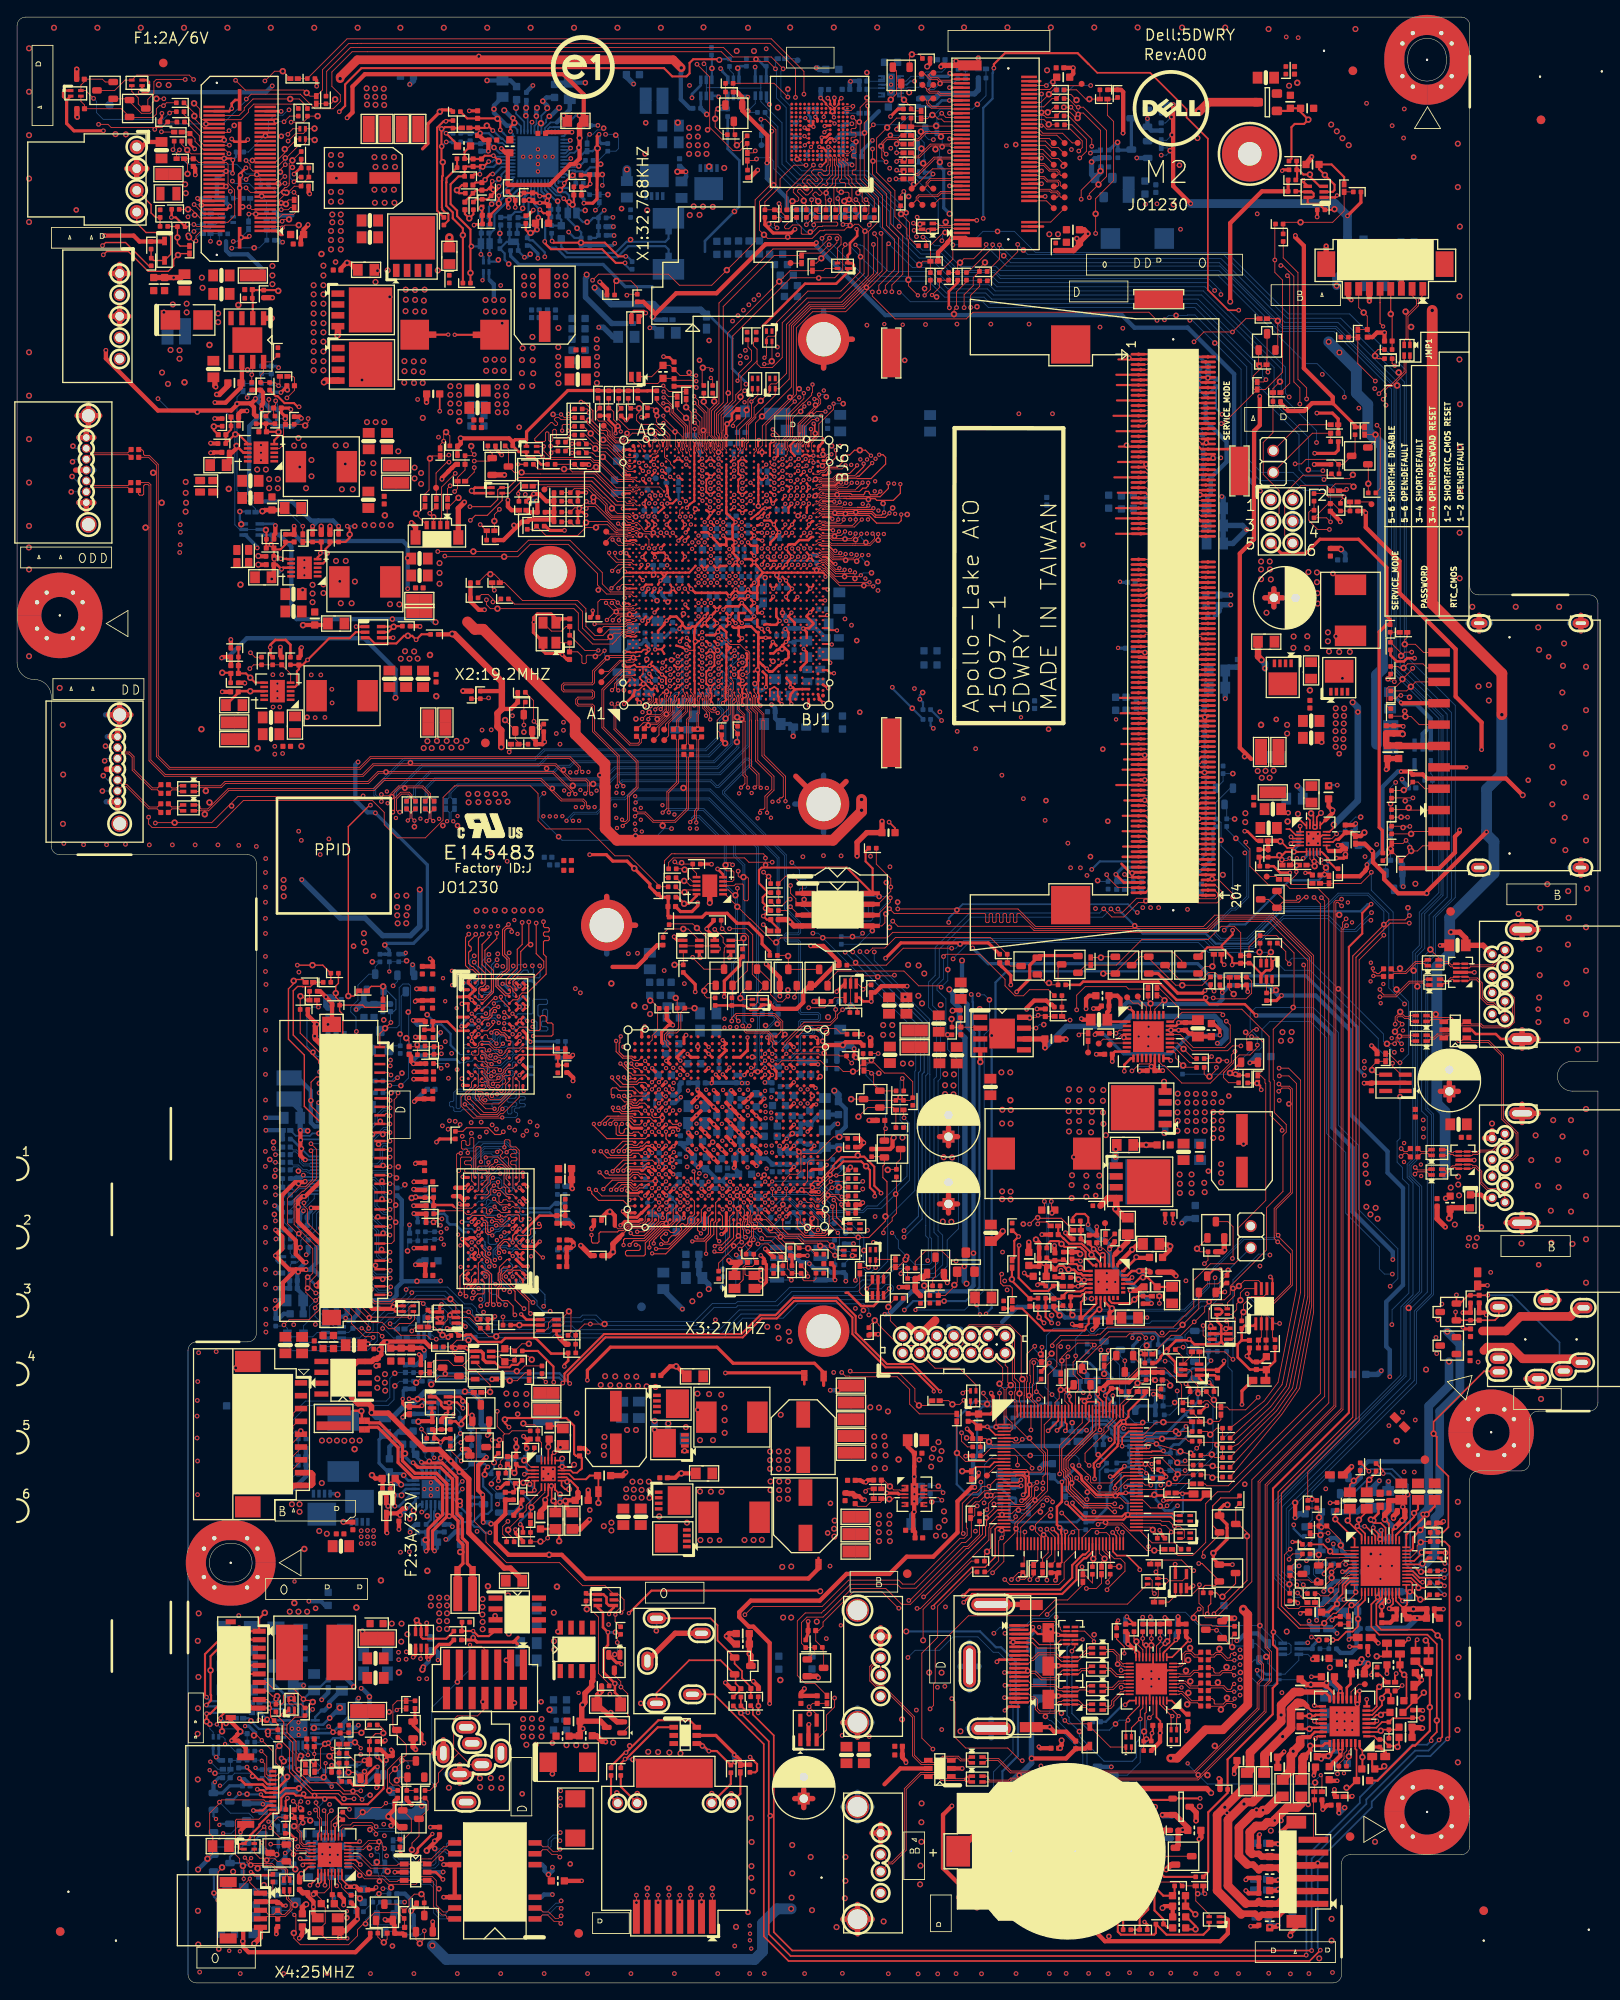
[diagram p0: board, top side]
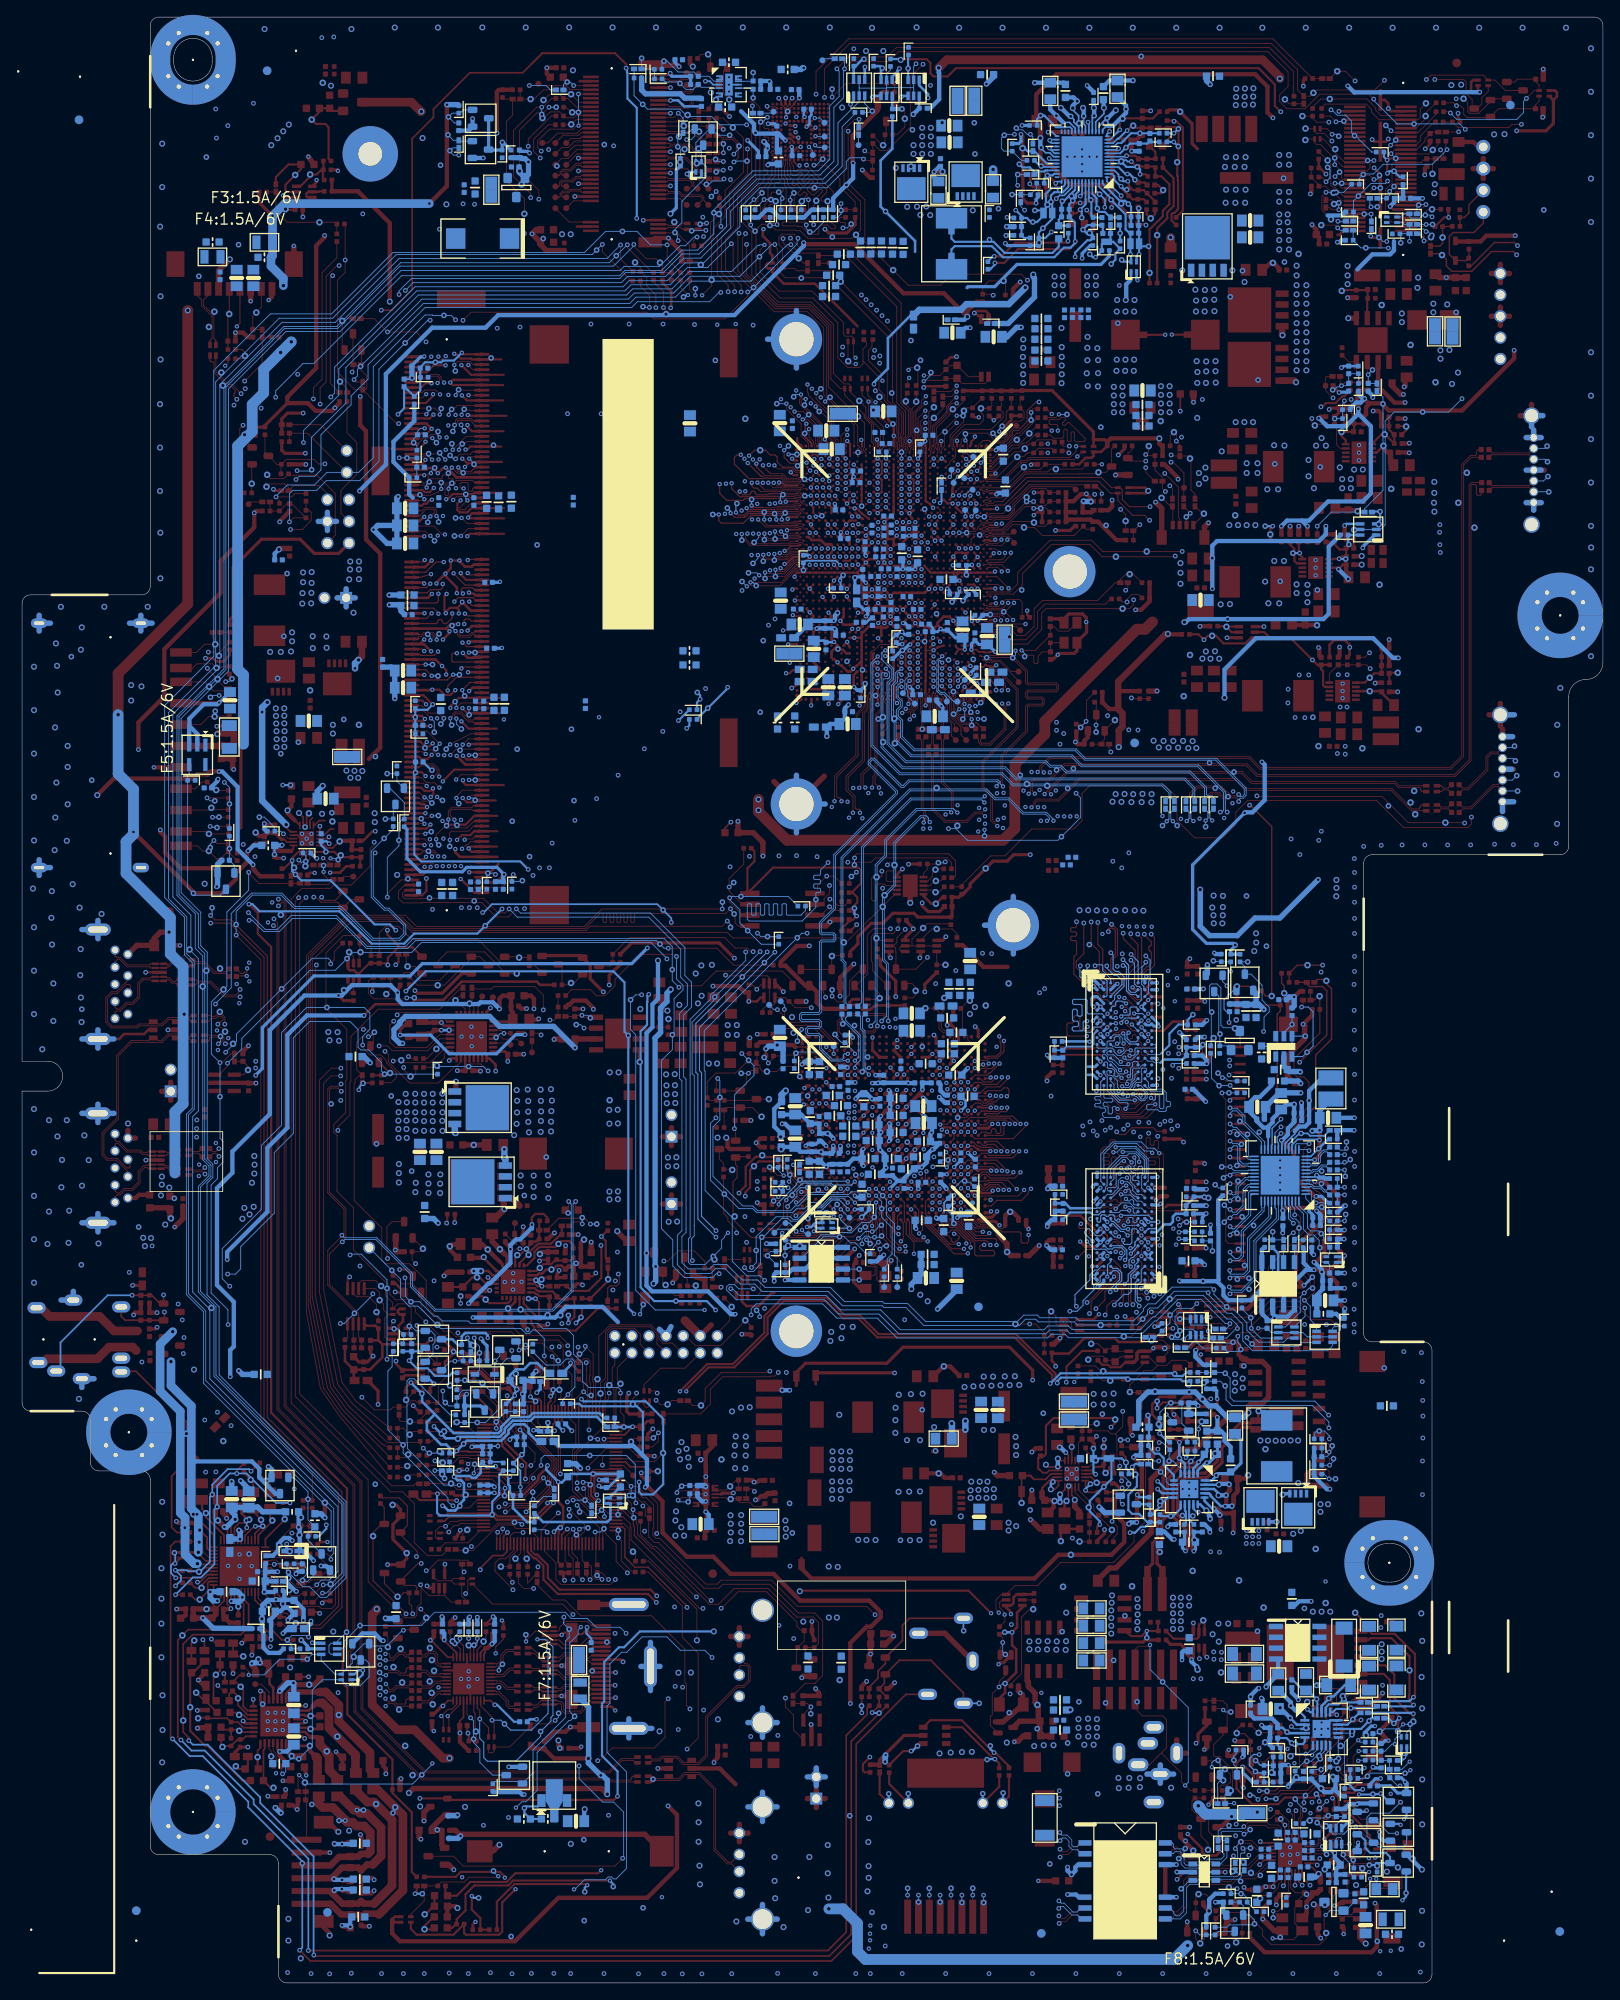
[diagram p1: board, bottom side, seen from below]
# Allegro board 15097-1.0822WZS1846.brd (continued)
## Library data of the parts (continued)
IRMTCN1 = 88459-047N: tolerance: 20.F1897.004
JMP1 = 21S-92-03GB16: tolerance: 021.60308.0203
L1 L10 L11 L25 = L402H24: tolerance: 68.00213.031
L2 = L125100-4P-1H36: tolerance: 68.12105.201; signal model: Graser_L2
L3 = L125100-4P-1H36: tolerance: 68.12105.201; signal model: Graser_L3
L4 = L125100-4P-1H36: tolerance: 68.12105.201; signal model: Graser_L4
L5 = L125100-4P-1H36: tolerance: 68.12105.201; signal model: Graser_L5
L6 = L125100-4P-1H36: tolerance: 68.12105.201; signal model: Graser_L6
L7 = L125100-4P-1H36: tolerance: 68.12105.201; signal model: Graser_L7
L8 = L8080-6020H158: tolerance: 068.33010.1061
L9 = L603H38: tolerance: 68.00335.141
L12-L15 = L20125H42: tolerance: 68.00216.111
L16 = L402H22: tolerance: 68.00084.541
L17 L22 = L603H38: tolerance: 68.00335.051
L19 L23 L24 = L603H38: tolerance: 68.00230.231
L20 = L3030-2709H41: tolerance: 68.2R21F.10E
L21 = L603H38: tolerance: 68.00335.081
L26 PR5-PR8 PR31 PR44 PR46 PR57 PR61 PR69 PR70 PR78 PR79 PR91 PR93 PR139 PR141-PR143 PR146 PR151 PR157 PR165 PR170 PR172 PR184 PR185 PR211 PR217 PR219 PR230 PR235 PR240 PRT1 PRT2 R47 R574 R575 = 0R0805-PAD: tolerance: ZZ.R0805.ZZZ
LED1 = LED1608AKH30: tolerance: 83.01608.Q70
LOUT1 = JAC331-0140A8B-9H: tolerance: 22.10277.2M1
LPC1 = HL5507F: tolerance: 21.60964.207
LVDS1 = 50524-0300N-001: tolerance: 020.K0005.0030
MEMCD1 = 156-5101902601: tolerance: 062.10002.0161
NGFF1 = 2199230-7: tolerance: 62.10043.K51
PC1 PC2 PC27 PC29 PC40 PC41 PC59 PC76 = C402H22: tolerance: 78.10423.5FLDL
PC4 PC9 PC123 PC141 PC146 PC187 PC188 PC198 = C402H22: tolerance: 78.10422.5FLDL
PC11 PC15 = C402H22: tolerance: 78.15034.L1L
PC12 PC183 = C402H22: tolerance: 78.22124.2FLDL
PC18 = C603: tolerance: 78.15324.2BL
PC22 = C402H22: tolerance: 78.10321.2FL
PC38 PC50 = C603H36: tolerance: 78.10224.2BLDL
PC39 PC95 PC112 PC116 = C402H22: tolerance: 78.22034.1FLDL
PC74 = C402H22: tolerance: 78.18034.1FL
PC75 = C402H22: tolerance: 78.10421.L0L
PC85 = C603H36: tolerance: 78.15224.2BLDL
PC88 = C402H22: tolerance: 78.10322.L0L
PC90 = C402H22: tolerance: 78.27224.2FLDL
PC92 = C603H36: tolerance: 78.56224.2BLDL
PC130 PC172 = C402H22: tolerance: 78.47322.2FL
PC135 = C402H22: tolerance: 78.15322.2FLDL
PC136 = C402H22: tolerance: 78.15224.2FLDL
PC144 = C805H54: tolerance: 78.10524.21LDL
PC147 = C402H22: tolerance: 78.22044.1FL
PC175 PC176 = C402H22: tolerance: 78.10034.1FLDL
PD1 = SOD323AKH42: tolerance: 83.04148.D1H
PD2 = SOD523AKH28: tolerance: 83.R2003.0EF
PD3 = D5436AKH97: tolerance: 83.P6SBM.CAG
PG1 PG2 = GAP-CLOSE-PWR: tolerance: ZZ.CLOSE.011
PG3-PG12 PG14-PG18 PGT1 = GAP-CLOSE-PWR-3: tolerance: ZZ.CLOSE.001
PG13 PR40 PR76 PR136 PR202 PR206 PR207 R10 R17 R22 R23 R25 R26 R29 R32 R34 R85 R119 R129 R135 R136 R154 R197 R206 R208 R224 R231 R248 R250 R266 R269 R270 R272 R273 R280 R307 R315 R343 R354 R355 R360-R366 R368 R371 R377 R385 R396 R400 R404 R405 R407 R429 R435 R468 R493 R505 R518 R521 R526 R566 R611 R612 R627 R654 R698 R699 R710 R719 R722 R731 R735 R750 R807 R809 R812 R1702 R1703 R1806 R1807 R2401 R2402 R9201 R9202 = R402H16: tolerance: 63.R0034.1DL
PL1 = L112100-2230H158: tolerance: 68.R2210.10Q
PL2-PL5 = L686647-127318H119: tolerance: 68.1R51A.10F
PL6 = L115100-2H158: tolerance: 68.R3610.10M
PL7 PL8 = L686647-127318H119: tolerance: 68.2R21B.10J
PL9 = L686647-127318H119: tolerance: 68.R4710.10V
PL10 PL11 PL13 = L402H24: tolerance: 69.80007.021
PL12 = L686647-127318H119: tolerance: 68.5R610.10U
PQ1 PQ16 PU8 PU17 = PTDS08-1H44: tolerance: 84.04C10.037
PQ2 PQ3 PU7 PU16 = PTDS08-1H44: tolerance: 84.04C06.037
PQ4 PQ11 PQ18 PU14 PU18 PU19 = PPAK-8P-3232H36: tolerance: 84.07410.A37
PQ5 PQ9 PQ20 PU15 = PPAK-8P-3232H36: tolerance: 84.07506.037
PQ6 PQ8 Q19 Q45-Q47 Q52 = SOT-363H44: tolerance: 84.2N702.A3F
PQ7 Q65 = SOT23CBE2D4H44: tolerance: 84.T3906.E11
PQ10 PQ17 Q25 Q34 Q38 Q64 Q1801 U27 = SOT23DGS2D4H44: tolerance: 84.2N702.J31
PQ12 PQ19 Q8 Q10 Q22 Q26 Q35 Q41 Q50 Q55 Q56 Q70-Q72 Q74 Q2801 Q4501 = SOT23DGS2D4H48: tolerance: 84.2N702.E31
PQ13 = SOT-363H44: tolerance: 84.00512.03F
PQ14 = SOT323CBE2D2H40: tolerance: 84.05212.B11
PQ15 = SOT323CBE2D2H44: tolerance: 84.00124.K1K
PR1 PR16 PR18 PR42 PR197 R585 R586 R634 R655 R785 = R402H16: tolerance: 64.10015.6DL
PR2 PR30 PR43 PR48 PR55 PR58 PR62 PR65 PR74 PR80 PR96 PR103 PR108 PR120 PR126 PR137 PR152 PR167 PR168 PR182 PR194 PR210 PR223 PRT3 = R805H24: tolerance: 63.2R231.16L
PR3 = R402H16: tolerance: 64.19625.6DL
PR4 PR81 PR111 PR198 PR242 R4 R14 R31 R39 R40 R80 R90 R94 R96 R130 R164 R175 R198 R205 R221 R233 R244 R275 R295 R306 R312 R358 R378 R380 R394 R401 R403 R408 R571 R573 R709 R738 R793 = 0R0402-PAD: tolerance: ZZ.R0402.001
PR9 = R603H22: tolerance: 64.84525.55L
PR10 R736 = R603H22: tolerance: 64.2R205.55L
PR11 = R402H16: tolerance: 64.48735.6DL
PR12 = R402H16: tolerance: 64.75025.6DL
PR13 = R402H16: tolerance: 64.22125.6DL
PR14 PR21 PR83 PR85 PR109 PR113 R126 R156 R387 R703 = R402H16: tolerance: 64.20025.6DL
PR15 PR154 = R402H16: tolerance: 64.10235.6DL
PR17 PR27 PR28 PR34 PR89 PR122 PR132 PR159 PR160 PR177 PR232 R101 R103-R105 R112 R118 R131 R148 R161 R252 R279 R281 R282 R285 R290 R298-R300 R308 R313 R314 R373 R391 R453 R461 R660 R661 R667 R692 R696 R697 R708 R716 R720 R778 R784 R792 R1801 R1802 = R402H16: tolerance: 64.10025.6DL
PR19 = R402H16: tolerance: 64.64915.6DL
PR20 = R402H16: tolerance: 64.28025.6DL
PR22 = R402H16: tolerance: 64.84525.6DL
PR23 = R402H16: tolerance: 64.49R95.6DL
PR24 = R402H16: tolerance: 64.15015.6DL
PR25 PR205 = NTC-402H24-U: tolerance: 69.60013.201
PR26 = R402H16: tolerance: 64.29425.6DL
PR29 PR193 = R805H24: tolerance: 63.1R031.16L
PR32 PR37 PR39 PR51 PR63 PR94 PR95 PR97 PR98 PR101 PR150 PR196 PR214 PR216 R3 R11 R20 R41 R51 R56 R59 R75 R92 R106 R109 R133 R159 R166 R179 R185 R194 R204 R209-R211 R215 R217 R219 R223 R227 R232 R239-R241 R255 R262 R274 R276 R319 R324 R326 R327 R331 R332 R334 R336 R337 R339 R348 R367 R392 R397 R452 R460 R474 R481 R485 R490 R491 R507 R508 R510 R515 R516 R525 R536 R547-R554 R557 R568 R628-R630 R633 R635 R644 R649 R653 R656 R668 R682 R745 R760 R789 R791 R798 R799 R802-R805 R815 R1803 R2002 R2403 R5502 = R402H16: tolerance: 63.10334.1DL
PR33 = NTC-402H24-U: tolerance: 69.60028.031
PR35 = R402H16: tolerance: 64.12725.6DL
PR36 PR50 PR64 PR107 PR175 PR203 PR208 PR209 R9 R12 R28 R35 R38 R43 R46 R48 R140 R146 R172 R173 R214 R216 R222 R238 R260 R351 R370 R372 R390 R426 R448 R450 R458 R473 R482 R483 R520 R532 R541 R577 R620 R680 R705 R712 R729 R748 R780 R794 R814 = R402H16: tolerance: 63.10234.1DL
PR38 PR88 PR105 R50 = R402H16: tolerance: 63.47334.1DL
PR41 PR52 PR60 PR110 = R402H16: tolerance: 64.18025.6DL
PR45 PR47 PR53 PR54 R347 R713 R715 R726 R757 = 0R0603-PAD: tolerance: ZZ.R0603.ZZZ
PR49 PR102 PR118 PR119 R16 R24 R30 R33 R36 R37 R42 R45 R49 R52 R55 R76-R78 R120 R124 R141 R143 R150-R153 R168 R203 R212 R218 R225 R230 R234 R235 R256 R263 R265 R330 R345 R356 R379 R381 R388 R402 R417 R441 R444 R463 R469-R471 R475 R479 R494 R511 R517 R522 R528-R531 R539 R544 R545 R556 R559-R561 R563 R564 R580 R587 R657 R662 R688 R689 R702 R704 R707 R734 R768-R770 R772 = 0R0402-PAD-1: tolerance: ZZ.00PAD.M11
PR56 PR189 = R402H16: tolerance: 64.16905.6DL
PR67 R128 R167 = R402H16: tolerance: 64.51025.6DL
PR75 = R402H16: tolerance: 64.64925.6DL
PR82 PR84 PR87 PR90 PR106 PR121 PR127 PR135 PR138 PR140 PR144 PR166 PR190 PR227 PR243 R91 R99 R142 R155 R183 R236 R271 R340-R342 R350 R353 R357 R376 R386 R399 R415 R416 R438 R621 R622 R718 R723 R724 R743 R749 R783 R810 = 0R0402-PAD: tolerance: ZZ.R0402.ZZZ
PR86 PR129 PR156 PR174 PR220 PR226 PR228 PR231 R27 R44 R53 R57 R89 R149 R184 R196 R200 R229 R245 R278 R288 R321 R413 R428 R439 R454 R472 R478 R664 R672 R675-R677 R685 R790 R1805 R4501 = R402H16: tolerance: 63.10434.1DL
PR92 = R402H16: tolerance: 64.31615.6DL
PR99 = NTC-402H22-U: tolerance: 69.60011.221
PR100 PR164 PR229 = R402H16: tolerance: 64.33025.6DL
PR104 PR117 PR204 R79 R651 R781 = R402H14: tolerance: 64.10005.6DL
PR112 R335 R797 = R402H16: tolerance: 64.20015.6DL
PR114 = R402H16: tolerance: 64.35725.6DL
PR115 = R603H22: tolerance: 64.59015.55L
PR116 PR224 R382 R383 = R402H16: tolerance: 64.47025.6DL
PR123 PR128 PR133 PR169 PR171 PR225 R177 R344 R349 R393 R558 R721 R737 R742 R746 R786 R1701 R5501 = R402H16: tolerance: 64.10035.6DL
PR124 = R402H16: tolerance: 64.82025.6DL
PR125 = R402H16: tolerance: 64.51R05.6DL
PR130 R132 = R402H16: tolerance: 63.10534.1DL
PR131 = R402H16: tolerance: 63.47434.1DL
PR134 = R402H16: tolerance: 64.68035.6DL
PR145 PR173 = R3720H40: tolerance: 64.R0105.7FL
PR147 = R402H16: tolerance: 64.30935.6DL
PR148 = R402H16: tolerance: 64.16935.6DL
PR149 = R402H16: tolerance: 64.78725.6DL
PR153 = R402H16: tolerance: 63.33534.1DL
PR155 = R402H16: tolerance: 64.88725.6DL
PR158 = R402H16: tolerance: 64.15425.6DL
PR161 = R402H16: tolerance: 64.1R505.6DL
PR162 = R402H16: tolerance: 64.66515.6DL
PR163 = R402H16: tolerance: 64.10735.6DL
PR176 R665 = R402H16: tolerance: 64.49925.6DL
PR178 = R1206H28: tolerance: 63.33232.11L
PR179 = R603H22: tolerance: 63.47333.15L
PR180 = R603H22: tolerance: 63.24434.15L
PR181 = R805H24: tolerance: 64.2R205.16L
PR183 PR200 = R402H16: tolerance: 64.14025.6DL
PR186 = R402H16: tolerance: 64.11025.6DL
PR187 R253 R254 R267 R268 R283 R284 R287 R292 R310 R645-R647 R652 R669 R670 R673 R674 R693 = R402H16: tolerance: 64.49915.6DL
PR188 PR233 R410 R412 R771 = R402H14: tolerance: 64.10R05.6DL
PR191 = R402H16: tolerance: 64.20R05.6DL
PR192 = R402H16: tolerance: 64.95R35.6DL
PR195 = R402H16: tolerance: 64.84R55.6DL
PR199 R86 = R402H16: tolerance: 64.49905.6DL
PR201 = R603H22: tolerance: 64.75015.55L
PR212 = R603H22: tolerance: 64.5R105.55L
PR213 = R402H16: tolerance: 64.75035.6DL
PR218 = R402H16: tolerance: 64.12035.6DL
PR221 = R805H24: tolerance: 64.20R05.16L
PR222 = R603H22: tolerance: 64.30935.55L
PR234 = R402H16: tolerance: 64.7R505.6DL
PR236 = 0R0402-PAD: tolerance: ZZ.R0402.ZZZ; signal model: Graser_PR236
PR237 = 0R0402-PAD: tolerance: ZZ.R0402.ZZZ; signal model: Graser_PR237
PR238 = 0R0402-PAD: tolerance: ZZ.R0402.ZZZ; signal model: Graser_PR238
PR239 = 0R0402-PAD: tolerance: ZZ.R0402.ZZZ; signal model: Graser_PR239
PRB1 = R402H16: tolerance: 64.26135.6DL
PT1 PT4 PT6 = SE361414H241: tolerance: 79.47612.3GL
PT2 = SE361414H241: tolerance: 79.3371V.6BL
PT3 PT5 PTC1 = ECAP-100D6D3H375: tolerance: 09.8271V.08L
PT7 PT8 = SE3116H241: tolerance: 79.22710.30L
PU1 PU6 = SOIC8-G3530H63: tolerance: 74.05930.B3D
PU2-PU4 = DFN10G3-G265175H32: tolerance: 74.08068.A43
PU5 = QFN20-G1D75H32: tolerance: 074.08231.0073
PU9 PU11 PU12 = SOIC8H69: tolerance: 84.04407.G37
PU10 = QFN20-G1D75H32: tolerance: 074.06575.0A43
PU13 = LFQFN52J6-G4D8-1H40: tolerance: 074.81226.0073
PWRCN1 = 51530-01041-W01: tolerance: 20.K0642.010
Q1 Q5 Q23 Q73 Q9201 Q9202 = SOT23DGS2D4H48: tolerance: 84.05067.031
Q2 = SOT23DGS2D4H48: tolerance: 84.05067.031; signal model: Graser_Q2
Q3 = SOT23DGS2D8H50: tolerance: 84.03418.A31
Q4 = SOT23DGS2D4H48: tolerance: 84.05067.031; signal model: Graser_Q4
Q6 Q12 Q13 = SOT-363H44: tolerance: 75.27002.D7C
Q7 = SOT23CBE2D4H44: tolerance: 84.T3906.A11
Q9 Q28 Q32 Q36 Q60-Q62 = SOT-363H44: tolerance: 75.27002.F7C
Q11 Q18 Q20 Q21 Q40 Q42 Q48 Q49 Q67 Q81 = SOT23CBE2D4H44: tolerance: 84.T3904.H11
Q14-Q17 Q24 = SOT23DGS2D4H44: tolerance: 84.27002.Z31
Q27 Q51 Q59 Q79 = SOT23DGS2D8H50: tolerance: 84.03413.B31
Q29 Q33 Q37 = SOT23-2D4-312H46: tolerance: 75.05125.07D
Q30 Q31 Q69 Q76 = SOT-363H44: tolerance: 84.M3904.B1F
Q39 Q43 Q44 Q53 Q75 Q77 Q78 Q80 = SOT23CBE2D4H44: tolerance: 84.T3904.C11
Q63 = SOT23DGS2D4H48: tolerance: 84.02130.031
Q66 = SOT23DGS2D4H44: tolerance: 84.27002.W31
Q68 = SOIC8H69: tolerance: 084.04286.0037
Q1802 = SOT23CBE2D4H44: tolerance: 084.02222.0011
R1 R73 R384 R406 R728 R788 R1808 = R402H16: tolerance: 63.22234.1DL
R2 R58 R325 R329 R333 R465 R467 R642 R687 R690 R700 R701 R759 R782 R1804 = R402H16: tolerance: 63.47234.1DL
R7 = R402H14: tolerance: 63.10034.1DL
R13 = R402H16: tolerance: 63.R0034.1DL; signal model: Graser_R13
R18 = R402H16: tolerance: 63.R0034.1DL; signal model: Graser_R18
R19 = R402H16: tolerance: 63.R0034.1DL; signal model: Graser_R19
R21 = R402H16: tolerance: 63.R0034.1DL; signal model: Graser_R21
R54 R74 R81 R82 R84 R87 R111 R117 R122 R123 R207 R309 R311 R369 R374 R411 R476 R691 R714 R717 R725 R774 R776 R779 R787 = R402H16: tolerance: 63.33034.1DL
R60 = R402H14: tolerance: 63.10034.1DL; signal model: Graser_R60
R61 = R402H14: tolerance: 63.10034.1DL; signal model: Graser_R61
R62 = R402H14: tolerance: 63.10034.1DL; signal model: Graser_R62
R63 = R402H14: tolerance: 63.10034.1DL; signal model: Graser_R63
R64 = R402H14: tolerance: 63.10034.1DL; signal model: Graser_R64
R65 = R402H14: tolerance: 63.10034.1DL; signal model: Graser_R65
R66 = R402H14: tolerance: 63.10034.1DL; signal model: Graser_R66
R67 = R402H14: tolerance: 63.10034.1DL; signal model: Graser_R67
R68 = R402H14: tolerance: 63.10034.1DL; signal model: Graser_R68
R69 = R402H14: tolerance: 63.10034.1DL; signal model: Graser_R69
R70 = R402H14: tolerance: 63.10034.1DL; signal model: Graser_R70
R71 = R402H16: tolerance: 64.82015.6DL
R72 R213 R228 = R402H16: tolerance: 63.20334.1DL
R83 = R402H16: tolerance: 64.24905.6DL
R88 = R402H15: tolerance: 63.10334.L0L
R93 R169 = R402H16: tolerance: 64.68R05.6DL
R95 R484 = R603H22: tolerance: 64.10055.55L
R97 R98 = R402H16: tolerance: 63.22034.1DL
R100 R193 R289 = NTC-603H38: tolerance: 69.60035.041
R102 R113-R116 R125 R137-R139 R144 R145 R147 R157 R158 R160 R162 R163 R418 R420-R423 R459 R464 R540 R754-R756 R2001 = R402H16: tolerance: 64.47015.6DL
R108 = 0R0402-PAD: tolerance: ZZ.R0402.001; signal model: Graser_R108
R110 = 0R0402-PAD: tolerance: ZZ.R0402.001; signal model: Graser_R110
R121 = R402H16: tolerance: 64.38325.6DL
R127 = R402H16: tolerance: 63.R0034.1DL; signal model: Graser_R127
R134 = R402H16: tolerance: 63.R0034.1DL; signal model: Graser_R134
R165 = R402H16: tolerance: 64.54925.6DL
R170 = R402H16: tolerance: 64.22005.6DL
R171 R546 R565 R567 = R402H16: tolerance: 63.51034.1DL
R174 = R402H16: tolerance: 64.20035.6DL
R176 = R402H14: tolerance: 64.10R05.6DL; signal model: Graser_R176
R178 = R402H14: tolerance: 64.10R05.6DL; signal model: Graser_R178
R180 = R402H14: tolerance: 64.10R05.6DL; signal model: Graser_R180
R181 R182 R604 = R402H16: tolerance: 64.40205.6DL
R186 = R402H14: tolerance: 64.10R05.6DL; signal model: Graser_R186
R187 = R402H16: tolerance: 63.R0034.1DL; signal model: Graser_R187
R188 = R402H16: tolerance: 63.R0034.1DL; signal model: Graser_R188
R189 = R402H16: tolerance: 63.R0034.1DL; signal model: Graser_R189
R190 = R402H16: tolerance: 63.R0034.1DL; signal model: Graser_R190
R191 = R402H14: tolerance: 64.10R05.6DL; signal model: Graser_R191
R192 = R402H14: tolerance: 64.10R05.6DL; signal model: Graser_R192
R195 = 0R0402-PAD: tolerance: ZZ.R0402.001; signal model: Graser_R195
R199 = R402H16: tolerance: 63.R0034.1DL; signal model: Graser_R199
R201 = R402H16: tolerance: 63.33034.1DL; signal model: Graser_R201
R202 = R402H16: tolerance: 63.R0034.1DL; signal model: Graser_R202
R220 R226 R320 R499 R533 R800 R806 = R402H16: tolerance: 63.82234.1DL
R237 R251 R437 R512 R519 R523 R535 R569 R570 R599 R602 R613 R614 R808 = R603H22: tolerance: 63.00000.00L
R246 R583 R584 R590 R816 = R402H16: tolerance: 64.20005.6DL
R247 R498 = R402H16: tolerance: 64.24915.6DL
R257 R261 R683 R686 = R402H16: tolerance: 64.80R65.6DL
R258 R291 R643 R679 = R402H16: tolerance: 64.24305.6DL
R259 R684 = R402H16: tolerance: 64.16205.6DL
R264 = R402H16: tolerance: 64.40R25.6DL
R277 = R402H16: tolerance: 64.40225.6DL
R286 = R603H22: tolerance: 63.15234.15L
R293 = R402: tolerance: 63.51034.1D1
R301 = R402H16: tolerance: 64.42R25.6DL
R304 R730 R732 R733 R739 = R402H16: tolerance: 64.24925.6DL
R316 R359 R375 R424 R427 R430-R432 R440 R466 R594 R747 = 0R0603-PAD-1-U: tolerance: ZZ.00PAD.M21
R317 R502 R534 = R402H16: tolerance: 64.39225.6DL
R318 R409 R751 R753 R758 R762 R767 = R805H24: tolerance: 63.R0031.16L
R328 = R402H16: tolerance: 64.18725.6DL
R338 = 0R0402-PAD: tolerance: ZZ.R0402.ZZZ; signal model: Graser_R338
R352 R477 R480 = R402H16: tolerance: 64.15025.6DL
R389 = R402H16: tolerance: 64.51015.6DL
R414 = R402H16: tolerance: 63.33334.1DL
R419 = R402H16: tolerance: 64.43015.6DL
R425 R449 = 0R1206-PAD-1: tolerance: ZZ.R1206.ZZ1
R433 = R603H22: tolerance: 63.10033.15L
R434 R436 = R603H22: tolerance: 64.10525.55L
R445 = R402H16: tolerance: 63.15234.1DL
R446 R447 = R402H16: tolerance: 63.47034.1DL
R451 = R402H16: tolerance: 64.56015.6DL
R455 R775 = R402H16: tolerance: 64.30035.6DL
R462 = R402H16: tolerance: 64.39015.6DL
R486 R801 = R805H24: tolerance: 64.10025.16L
R487 R489 R496 R504 = R603H22: tolerance: 64.3R305.55L
R492 R495 R501 R503 R506 = R603H22: tolerance: 64.75R05.55L
R500 R744 = R603H22: tolerance: 64.10045.55L
R513 R514 R524 R527 R588 = R402H16: tolerance: 64.47005.6DL
R542 R582 R598 R601 R811 = 0R0805-PAD-U: tolerance: ZZ.R0805.001
R543 = R402H14: tolerance: 63.10134.1DL
R572 R596 R603 R605-R608 R615 R616 R641 = 0R0603-PAD-U: tolerance: ZZ.R0603.001
R578 R581 R610 R617 = R402H16: tolerance: 64.36515.6DL
R589 R591 = R402H16: tolerance: 64.10505.6DL
R592 R593 R609 = R402H16: tolerance: 64.15005.6DL
R595 R659 R666 = R402H16: tolerance: 64.60R45.6DL
R597 = R402H16: tolerance: 64.13705.6DL
R600 = R402H16: tolerance: 64.11305.6DL
R623 = 0R0402-PAD: tolerance: ZZ.R0402.ZZZ; signal model: Graser_R623
R624 = 0R0402-PAD: tolerance: ZZ.R0402.ZZZ; signal model: Graser_R624
R625 = 0R0402-PAD: tolerance: ZZ.R0402.ZZZ; signal model: Graser_R625
R626 = 0R0402-PAD: tolerance: ZZ.R0402.ZZZ; signal model: Graser_R626
R631 = R402H16: tolerance: 63.33034.1DL; signal model: Graser_R631
R632 = R402H16: tolerance: 63.33034.1DL; signal model: Graser_R632
R639 = R603H22: tolerance: 63.33133.15L
R658 = R402H16: tolerance: 64.12025.6DL
R671 = R402H16: tolerance: 64.40R25.6D1
R706 = R402H16: tolerance: 63.33434.1DL
R711 = R402H16: tolerance: 63.20434.1DL
R727 = R402H16: tolerance: 64.16035.6DL
R761 R764 = R1206H26: tolerance: 64.R3305.41L
R766 = R805H24: tolerance: 63.20131.16L
R795 = R603H22: tolerance: 64.18005.55L
R796 = R603H22: tolerance: 64.36R05.55L
RJ1 = 23-01120-2A03-A: tolerance: 062.10032.0041
RN1 RN11 RN14 = SMD-ARES4H20: tolerance: 66.R0036.04L
RN2 RN4-RN8 RN21 RN22 RN37 RN39 RN40 = ARES2H18: tolerance: 66.10336.04L
RN9 RN20 RN25 RN32 RN36 = ARES2H16: tolerance: 66.22236.04L
RN12 RN13 RN24 RN34 RN35 RN41 = SMD-ARES4H18: tolerance: 66.47236.04L
RN15 RN18 = SMD-ARES4H20: tolerance: 66.10156.04L
RN16 RN17 = SMD-ARES4H18: tolerance: 66.10236.04L
RN19 RN30 RN38 = SMD-ARES4: tolerance: 66.10436.04L
RN23 = SMD-ARES4H20: tolerance: 66.20336.04L
RV1 = TVS5436-1121H105: tolerance: 069.A0007.0001
SATAP1 = CI2505P1H00-LF-U: tolerance: 021.60197.0105
SPK1 = A1501WV0-6PS-5E: tolerance: 21.D0278.106
SRCON1 = SKT-SOIC8-092117H235: tolerance: 62.10089.001
SSUSB1 SSUSB2 = SKT-USB11-138165-1: tolerance: 022.10005.0391
TC1 = CT3528H79: tolerance: 77.21071.07L
TC2 = ECAP-100D6D3H237: tolerance: 09.1071D.A5L
TC3 = ECAP-100D6D3H237: tolerance: 09.1071D.F5L
TC4 = CT7343H75: tolerance: 77.23371.13L
TOUCH1 = 3703K-Q05N-11L: tolerance: 020.F0146.0005
TP1-TP66 TP68-TP76 TP78-TP85 = TPAD28: tolerance: ZZ.PAD28.XXX
TP77 = TPAD24: tolerance: ZZ.PAD24.001
TR1-TR4 TR9-TR11 = L125100-4P-4H28: tolerance: 68.01012.20B
TR5 = L125100-4P-1H28: tolerance: 68.10129.201; signal model: Graser_TR5
TR6 = L125100-4P-1H28: tolerance: 68.10129.201; signal model: Graser_TR6
TR7 = L125100-4P-1H28: tolerance: 68.10129.201; signal model: Graser_TR7
TR8 = L125100-4P-1H28: tolerance: 68.10129.201; signal model: Graser_TR8
U1 = BGA153G115130-1H40: tolerance: 072.KMBG4.0C0U
U2 = DFN10G3-G265175H32: tolerance: 73.03956.003; signal model: Graser_U2
U3 = SOIC8-1H86: tolerance: 072.25647.0001
U4 = DFN10G2510H26: tolerance: 75.01045.073; signal model: Graser_U4
U5 = SC70-5H44: tolerance: 73.7SZ08.DAH
U6 U25 = SOT-6H58: tolerance: 075.02304.007C
U7 = QFN32G5-G3D6H32: tolerance: 071.00650.0A03
U8 U23 U39 = SOT-23-5H58: tolerance: 074.22802.009F
U9 = DFN10G2510H26: tolerance: 75.01045.073; signal model: Graser_U9
U11 = LFQFN24G4-G2D9H40: tolerance: 74.81172.073
U12 = MSOP8-1H44: tolerance: 74.07718.0B9
U13 = SC70-6H44: tolerance: 73.02129.02J
U14 = LQFP128H63: tolerance: 071.00985.000G
U15 U29 = SON14J3020-G2610H34: tolerance: 74.22966.093
U16 = QFN48J6-G465H40: tolerance: 71.03661.003
U17 = SC70-5H44: tolerance: 73.7SZ08.EAH
U18 U19 U21 = DFN10G2510H26: tolerance: 75.01045.073
U20 = QFN40J5-G3D65H32: tolerance: 071.08407.0003; signal model: Graser_U20
U22 = QFN32-G3D55H40: tolerance: 74.03131.013
U24 U28 U37 = SOT-6H58: tolerance: 75.01215.07C
U26 = QFN32J4-G2D85H36: tolerance: 71.08111.U03
U31 = QFN48J6-G4D55H40: tolerance: 71.02136.003
U32 = SOIC8H69: tolerance: 72.25106.001
U33 = SOIC8H69: tolerance: 72.24C64.R01
U34 = QFN20G3D5-G2D15H40: tolerance: 74.24727.A73
U35 = QFN20-G2D1H32: tolerance: 074.00554.0073
U36 = SOT-89-4541-3PH63: tolerance: 074.01117.0038
U38 = SOT-6-1H58: tolerance: 74.03521.07P
UHS1 = 2SJ3082-038111F: tolerance: 022.10002.0881
UR1-UR4 = R402H16: tolerance: 64.33005.6DL
USB3 USB4 = SKT-USB6-135063: tolerance: 022.10005.01E1
VRAM1-VRAM4 = BGA96D075130H48: tolerance: 72.51G63.H0U
WEBCM1 = A1251WR0-8PS-5E: tolerance: 20.F1245.008
X1 = SMD49-6914-0403H56: tolerance: 82.30001.G11
X2 = OSC-3225-4P-4H32: tolerance: 82.30071.051
X3 = OSC-3225-4P-4H30: tolerance: 82.30034.641
X4 = OSC-3225-4P-4H36: tolerance: 82.30020.G71
XDP1 = QSH-030-01-FDAK: tolerance: 20.F0971.060
XF1 XF2 = XFORM12A127097H91: tolerance: 68.68167.30D

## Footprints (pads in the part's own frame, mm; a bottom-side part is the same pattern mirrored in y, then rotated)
0R0402-PAD
  custom 0.14x0.14 smd: 1(0,0.445) 2(0,-0.445)
0R0402-PAD-1
  custom 0.14x0.14 smd: 1(0,0.445) 2(0,-0.445)
0R0603-PAD
  custom 0.216x0.216 smd: 1(0,0.851) 2(0,-0.673)
0R0603-PAD-1-U
  custom 0.216x0.216 smd: 1(0,0.762) 2(0,-0.762)
0R0603-PAD-U
  custom 0.216x0.216 smd: 1(0,0.762) 2(0,-0.762)
0R0805-PAD
  rect 1.397x1.562 smd: 1(0,0.965)
  rect 1.397x1.569 smd: 2(0,-0.965)
0R0805-PAD-U
  rect 1.397x1.562 smd: 1(0,0.965)
  rect 1.397x1.569 smd: 2(0,-0.965)
0R1206-PAD-1
  rect 1.651x2.057 smd: 1(0,1.397) 2(0,-1.397)
2DC3115-000111F
  oval 1.422x2.413 hole 0.711x1.702: 1(-1.1,1.46)
  oval 1.473x2.413 hole 0.762x1.702: 2(2.5,0) 5(4.375,0.7) 7(-4.375,0.7)
  oval 1.524x2.413 hole 0.813x1.702: 3(0,-1.13)
  oval 2.413x1.473 hole 1.702x0.762: 4(1.35,3.375) 6(1.35,-3.375)
2SJ3082-038111F
  round 0.254 hole 1.27 unplated: (0,0) (0,-6)
  oval 1.321x2.134 hole 0.61x1.422: 1(3.8,3.1) 2(-3.7,-4.5) 3(3.7,-6.8) 4(-2.7,-6.6) 5(-2.2,3.1) 6(-3.8,3.1) MS1(-4.6,-1.5) MS2(4.6,-2.5)
15-02070-5A61-A
  round 1.041 hole 0.762: 1(3.81,-0.25) 2(2.54,-0.25) 3(1.27,-0.25) 4(0,-0.25) 5(-1.27,-0.25) 6(-2.54,-0.25) 7(-3.81,-0.25)
  round 1.93 hole 1.524: 8(6.37,0) 9(-6.37,0)
21S-92-03GB16
  round 1.422 hole 1.016: 1(-2.54,-1.27) 2(-2.54,1.27) 3(0,-1.27) 4(0,1.27) 5(2.54,-1.27) 6(2.54,1.27)
23-01120-2A03-A
  rect 0.813x3.988 smd: 1(-4.445,13.3) 2(-3.175,13.3) 3(-1.905,13.3) 4(-0.635,13.3) 5(0.635,13.3) 6(1.905,13.3) 7(3.175,13.3) 8(4.445,13.3)
  round 1.321 hole 0.914: 9(-6.645,0) 10(-4.355,0) 11(4.355,0) 12(6.645,0)
  rect 8.992x3.404 smd: 13(0,-3.5)
156-5101902601
  round 0.254 hole 1.702 unplated: (-12.65,0) (12.65,0)
  rect 0.991x2.54 smd: 1(-7.57,8.245) 2(-5.07,8.245) 3(-2.57,8.245) 4(-0.07,8.245) 5(2.43,8.245) 6(4.93,8.245) 7(7.43,8.245) 8(9.055,8.245) 9(-10.07,8.245) 10(10.875,8.245) 11(-11.755,8.245)
  oval 1.118x1.93 hole 0.406x1.219: 12(-14.3,3.55) 13(14.3,3.55) 14(-14.3,-8.35) 15(14.3,-8.35)
3703K-Q05N-11L
  rect 0.61x1.549 smd: 1(-2,3.775) 2(-1,3.775) 3(0,3.775) 4(1,3.775) 5(2,3.775)
  rect 1.194x2.007 smd: 6(-3.3,0) 7(3.3,0)
50524-0300N-001
  rect 0.305x1.295 smd: 1(-14.5,5.65) 2(-13.5,5.65) 3(-12.5,5.65) 4(-11.5,5.65) 5(-10.5,5.65) 6(-9.5,5.65) 7(-8.5,5.65) 8(-7.5,5.65) 9(-6.5,5.65) 10(-5.5,5.65) 11(-4.5,5.65) 12(-3.5,5.65) 13(-2.5,5.65) 14(-1.5,5.65) 15(-0.5,5.65) 16(0.5,5.65) 17(1.5,5.65) 18(2.5,5.65) 19(3.5,5.65) 20(4.5,5.65) 21(5.5,5.65) 22(6.5,5.65) 23(7.5,5.65) 24(8.5,5.65) 25(9.5,5.65) 26(10.5,5.65) 27(11.5,5.65) 28(12.5,5.65) 29(13.5,5.65) 30(14.5,5.65)
  rect 1.803x2.21 smd: 31(-17.15,0) 32(17.15,0)
51202-00901-W01-U
  rect 0.66x1.448 smd: 1(-6,6.225) 2(-4.5,6.225) 3(-3,6.225) 4(-1.5,6.225) 5(0,6.225) 6(1.5,6.225) 7(3,6.225) 8(4.5,6.225) 9(6,6.225)
  rect 2.489x2.997 smd: 10(-8.5,0) 11(8.5,0)
51530-01041-W01
  rect 0.305x0.838 smd: 1(-2.25,3.175) 2(-1.75,3.175) 3(-1.25,3.175) 4(-0.75,3.175) 5(-0.25,3.175) 6(0.25,3.175) 7(0.75,3.175) 8(1.25,3.175) 9(1.75,3.175) 10(2.25,3.175)
  rect 0.813x2.007 smd: 11(-3.95,0) 12(3.95,0)
88314-077N
  rect 0.838x3.556 smd: 1(-4.5,-3.225) 2(-3,-3.225) 3(-1.5,-3.225) 4(0,-3.225) 5(1.5,-3.225) 6(3,-3.225) 7(4.5,-3.225)
  rect 0.838x2.642 smd: 8(-4.5,0.675) 9(-3,0.675) 10(-1.5,0.675) 11(0,0.675) 12(1.5,0.675) 13(3,0.675) 14(4.5,0.675)
88459-047N
  rect 0.508x0.991 smd: 1(1.2,1.455) 2(0.4,1.455) 3(-0.4,1.455) 4(-1.2,1.455)
  rect 1.194x1.702 smd: 5(2.5,0) 6(-2.5,0)
2199230-7
  round 0.254 hole 1.6 unplated: (-10,0)
  round 0.254 hole 1.118 unplated: (10,0)
  rect 0.305x1.854 smd: 1(9.25,-5.423) 2(9,2.423) 3(8.75,-5.423) 4(8.5,2.423) 5(8.25,-5.423) 6(8,2.423) 7(7.75,-5.423) 16(5.5,2.423) 17(5.25,-5.423) 18(5,2.423) 19(4.75,-5.423) 20(4.5,2.423) 21(4.25,-5.423) 22(4,2.423) 23(3.75,-5.423) 24(3.5,2.423) 25(3.25,-5.423) 26(3,2.423) 27(2.75,-5.423) 28(2.5,2.423) 29(2.25,-5.423) 30(2,2.423) 31(1.75,-5.423) 32(1.5,2.423) 33(1.25,-5.423) 34(1,2.423) 35(0.75,-5.423) 36(0.5,2.423) 37(0.25,-5.423) 38(0,2.423) 39(-0.25,-5.423) 40(-0.5,2.423) 41(-0.75,-5.423) 42(-1,2.423) 43(-1.25,-5.423) 44(-1.5,2.423) 45(-1.75,-5.423) 46(-2,2.423) 47(-2.25,-5.423) 48(-2.5,2.423) 49(-2.75,-5.423) 50(-3,2.423) 51(-3.25,-5.423) 52(-3.5,2.423) 53(-3.75,-5.423) 54(-4,2.423) 55(-4.25,-5.423) 56(-4.5,2.423) 57(-4.75,-5.423) 58(-5,2.423) 59(-5.25,-5.423) 60(-5.5,2.423) 61(-5.75,-5.423) 62(-6,2.423) 63(-6.25,-5.423) 64(-6.5,2.423) 65(-6.75,-5.423) 66(-7,2.423) 67(-7.25,-5.423) 68(-7.5,2.423) 69(-7.75,-5.423) 70(-8,2.423) 71(-8.25,-5.423) 72(-8.5,2.423) 73(-8.75,-5.423) 74(-9,2.423) 75(-9.25,-5.423)
  rect 1.194x2.743 smd: 76(10.35,-4.5) 77(-10.35,-4.5)
A1251WR0-8PS-5E
  rect 0.813x1.6 smd: 1(-4.375,2.9) 2(-3.125,2.9) 3(-1.875,2.9) 4(-0.625,2.9) 5(0.625,2.9) 6(1.875,2.9) 7(3.125,2.9) 8(4.375,2.9)
  rect 2.108x2.997 smd: 9(-6.925,0) 10(6.925,0)
A1501WV0-6PS-5E
  rect 0.711x3.505 smd: 1(3.75,2) 2(2.25,2) 3(0.75,2) 4(-0.75,2) 5(-2.25,2) 6(-3.75,2)
  rect 1.499x2.311 smd: 7(5.8,0) 8(-5.8,0)
A2541WV0-1EX2PA-6T
  round 1.397 hole 0.991: 1(-1.27,0) 2(1.27,0)
AAA-BAT-034-K01
  round 0.254 hole 1.067 unplated: (-7.5,0)
  round 0.254 hole 1.372 unplated: (0,0)
  rect 2.794x3.607 smd: 1(6.2,0)
  rect 2.997x2.591 smd: 2(-15.1,0)
AFTE14P-75
  round 0.356 smd: 1(0,0)
ARES2H16
  rect 0.356x0.66 smd: 1(-0.325,-0.599) 2(0.325,-0.599) 3(0.325,0.599) 4(-0.325,0.599)
ARES2H18
  rect 0.356x0.66 smd: 1(-0.325,-0.599) 2(0.325,-0.599) 3(0.325,0.599) 4(-0.325,0.599)
AS0A621-J4R6-7H-U
  round 0.254 hole 1.118 unplated: (-33.4,0)
  round 0.254 hole 1.6 unplated: (33.4,0)
  custom 0.114x0.114 smd: 1(31.65,4.1) 2(31.35,-4.1) 3(31.05,4.1) 4(30.751,-4.1) 5(30.45,4.1) 6(30.15,-4.1) 7(29.85,4.1) 8(29.55,-4.1) 9(29.251,4.1) 10(28.95,-4.1) 11(28.65,4.1) 12(28.35,-4.1) 13(28.051,4.1) 14(27.751,-4.1) 15(27.45,4.1) 16(27.15,-4.1) 17(26.851,4.1) 18(26.551,-4.1) 19(26.25,4.1) 20(25.95,-4.1) 21(25.65,4.1) 22(25.35,-4.1) 23(25.051,4.1) 24(24.75,-4.1) 25(24.45,4.1) 26(24.15,-4.1) 27(23.851,4.1) 28(23.55,-4.1) 29(23.25,4.1) 30(22.95,-4.1) 31(22.651,4.1) 32(22.351,-4.1) 33(22.05,4.1) 34(21.75,-4.1) 35(21.451,4.1) 36(21.151,-4.1) 37(20.85,4.1) 38(20.55,-4.1) 39(20.25,4.1) 40(19.95,-4.1) 41(19.65,4.1) 42(19.35,-4.1) 43(19.049,4.1) 44(18.749,-4.1) 45(18.45,4.1) 46(18.15,-4.1) 47(17.85,4.1) 48(17.549,-4.1) 49(17.25,4.1) 50(16.95,-4.1) 51(16.65,4.1) 52(16.349,-4.1) 53(16.049,4.1) 54(15.75,-4.1) 55(15.45,4.1) 56(15.15,-4.1) 57(14.849,4.1) 58(14.549,-4.1) 59(14.25,4.1) 60(13.95,-4.1) 61(13.649,4.1) 62(13.349,-4.1) 63(13.05,4.1) 64(12.75,-4.1) 65(12.45,4.1) 66(12.149,-4.1) 67(11.85,4.1) 68(11.55,-4.1) 69(11.25,4.1) 70(10.95,-4.1) 71(10.649,4.1) 72(10.349,-4.1) 73(7.65,4.1) 74(7.35,-4.1) 75(7.049,4.1) 76(6.749,-4.1) 77(6.45,4.1) 78(6.15,-4.1) 79(5.85,4.1) 80(5.549,-4.1) 81(5.25,4.1) 82(4.95,-4.1) 83(4.65,4.1) 84(4.349,-4.1) 85(4.05,4.1) 86(3.75,-4.1) 87(3.45,4.1) 88(3.15,-4.1) 89(2.849,4.1) 90(2.549,-4.1) 91(2.25,4.1) 92(1.95,-4.1) 93(1.649,4.1) 94(1.349,-4.1) 95(1.05,4.1) 96(0.75,-4.1) 97(0.45,4.1) 98(0.149,-4.1) 99(-0.15,4.1) 100(-0.45,-4.1) 101(-0.75,4.1) 102(-1.051,-4.1) 103(-1.351,4.1) 104(-1.65,-4.1) 105(-1.95,4.1) 106(-2.25,-4.1) 107(-2.551,4.1) 108(-2.851,-4.1) 109(-3.15,4.1) 110(-3.45,-4.1) 111(-3.751,4.1) 112(-4.051,-4.1) 113(-4.35,4.1) 114(-4.65,-4.1) 115(-4.95,4.1) 116(-5.251,-4.1) 117(-5.55,4.1) 118(-5.85,-4.1) 119(-6.15,4.1) 120(-6.451,-4.1) 121(-6.751,4.1) 122(-7.051,-4.1) 123(-7.35,4.1) 124(-7.65,-4.1) 125(-7.951,4.1) 126(-8.251,-4.1) 127(-8.55,4.1) 128(-8.85,-4.1) 129(-9.15,4.1) 130(-9.451,-4.1) 131(-9.75,4.1) 132(-10.05,-4.1) 133(-10.35,4.1) 134(-10.651,-4.1) 135(-10.95,4.1) 136(-11.25,-4.1) 137(-11.55,4.1) 138(-11.85,-4.1) 139(-12.151,4.1) 140(-12.451,-4.1) 141(-12.75,4.1) 142(-13.05,-4.1) 143(-13.351,4.1) 144(-13.651,-4.1) 145(-13.95,4.1) 146(-14.25,-4.1) 147(-14.55,4.1) 148(-14.851,-4.1) 149(-15.15,4.1) 150(-15.45,-4.1) 151(-15.75,4.1) 152(-16.051,-4.1) 153(-16.35,4.1) 154(-16.65,-4.1) 155(-16.95,4.1) 156(-17.25,-4.1) 157(-17.551,4.1) 158(-17.851,-4.1) 159(-18.15,4.1) 160(-18.45,-4.1) 161(-18.751,4.1) 162(-19.051,-4.1) 163(-19.35,4.1) 164(-19.65,-4.1) 165(-19.95,4.1) 166(-20.251,-4.1) 167(-20.55,4.1) 168(-20.85,-4.1) 169(-21.15,4.1) 170(-21.451,-4.1) 171(-21.751,4.1) 172(-22.051,-4.1) 173(-22.35,4.1) 174(-22.65,-4.1) 175(-22.951,4.1) 176(-23.251,-4.1) 177(-23.55,4.1) 178(-23.85,-4.1) 179(-24.151,4.1) 180(-24.451,-4.1) 181(-24.75,4.1) 182(-25.05,-4.1) 183(-25.35,4.1) 184(-25.651,-4.1) 185(-25.95,4.1) 186(-26.25,-4.1) 187(-26.55,4.1) 188(-26.851,-4.1) 189(-27.151,4.1) 190(-27.451,-4.1) 191(-27.75,4.1) 192(-28.05,-4.1) 193(-28.351,4.1) 194(-28.651,-4.1) 195(-28.95,4.1) 196(-29.25,-4.1) 197(-29.55,4.1) 198(-29.851,-4.1) 199(-30.15,4.1) 200(-30.45,-4.1) 201(-30.75,4.1) 202(-31.05,-4.1) 203(-31.349,4.1) 204(-31.649,-4.1)
  rect 4.496x4.597 smd: 205(32.8,12) 206(-32.8,12)
BGA96D075130H48
  round 0.356 smd: A1(-3.2,6) A2(-2.4,6) A3(-1.6,6) A7(1.6,6) A8(2.4,6) A9(3.2,6) B1(-3.2,5.2) B2(-2.4,5.2) B3(-1.6,5.2) B7(1.6,5.2) B8(2.4,5.2) B9(3.2,5.2) C1(-3.2,4.4) C2(-2.4,4.4) C3(-1.6,4.4) C7(1.6,4.4) C8(2.4,4.4) C9(3.2,4.4) D1(-3.2,3.6) D2(-2.4,3.6) D3(-1.6,3.6) D7(1.6,3.6) D8(2.4,3.6) D9(3.2,3.6) E1(-3.2,2.8) E2(-2.4,2.8) E3(-1.6,2.8) E7(1.6,2.8) E8(2.4,2.8) E9(3.2,2.8) F1(-3.2,2) F2(-2.4,2) F3(-1.6,2) F7(1.6,2) F8(2.4,2) F9(3.2,2) G1(-3.2,1.2) G2(-2.4,1.2) G3(-1.6,1.2) G7(1.6,1.2) G8(2.4,1.2) G9(3.2,1.2) H1(-3.2,0.4) H2(-2.4,0.4) H3(-1.6,0.4) H7(1.6,0.4) H8(2.4,0.4) H9(3.2,0.4) J1(-3.2,-0.4) J2(-2.4,-0.4) J3(-1.6,-0.4) J7(1.6,-0.4) J8(2.4,-0.4) J9(3.2,-0.4) K1(-3.2,-1.2) K2(-2.4,-1.2) K3(-1.6,-1.2) K7(1.6,-1.2) K8(2.4,-1.2) K9(3.2,-1.2) L1(-3.2,-2) L2(-2.4,-2) L3(-1.6,-2) L7(1.6,-2) L8(2.4,-2) L9(3.2,-2) M1(-3.2,-2.8) M2(-2.4,-2.8) M3(-1.6,-2.8) M7(1.6,-2.8) M8(2.4,-2.8) M9(3.2,-2.8) N1(-3.2,-3.6) N2(-2.4,-3.6) N3(-1.6,-3.6) N7(1.6,-3.6) N8(2.4,-3.6) N9(3.2,-3.6) P1(-3.2,-4.4) P2(-2.4,-4.4) P3(-1.6,-4.4) P7(1.6,-4.4) P8(2.4,-4.4) P9(3.2,-4.4) R1(-3.2,-5.2) R2(-2.4,-5.2) R3(-1.6,-5.2) R7(1.6,-5.2) R8(2.4,-5.2) R9(3.2,-5.2) T1(-3.2,-6) T2(-2.4,-6) T3(-1.6,-6) T7(1.6,-6) T8(2.4,-6) T9(3.2,-6)
BGA153G115130-1H40
  oval 0.229x0.356 smd: A1(-3.25,3.25) A2(-2.75,3.25) A3(-2.25,3.25) A4(-1.75,3.25) A5(-1.25,3.25) A6(-0.75,3.25)
  round 0.356 smd: A7(-0.25,3.25) A8(0.25,3.25) A9(0.75,3.25) A10(1.25,3.25) A11(1.75,3.25) A12(2.25,3.25) A13(2.75,3.25) A14(3.25,3.25) B2(-2.75,2.75) B3(-2.25,2.75) B4(-1.75,2.75) B5(-1.25,2.75) B6(-0.75,2.75) B7(-0.25,2.75) B8(0.25,2.75) B9(0.75,2.75) B10(1.25,2.75) B11(1.75,2.75) B12(2.25,2.75) B13(2.75,2.75) B14(3.25,2.75) C2(-2.75,2.25) C3(-2.25,2.25) C4(-1.75,2.25) C5(-1.25,2.25) C6(-0.75,2.25) C7(-0.25,2.25) C8(0.25,2.25) C9(0.75,2.25) C10(1.25,2.25) C11(1.75,2.25) C12(2.25,2.25) C13(2.75,2.25) C14(3.25,2.25) D1(-3.25,1.75) D2(-2.75,1.75) D3(-2.25,1.75) D4(-1.75,1.75) D12(2.25,1.75) D13(2.75,1.75) D14(3.25,1.75) E1(-3.25,1.25) E2(-2.75,1.25) E3(-2.25,1.25) E5(-1.25,1.25) E6(-0.75,1.25) E7(-0.25,1.25) E8(0.25,1.25) E9(0.75,1.25) E10(1.25,1.25) E12(2.25,1.25) E13(2.75,1.25) E14(3.25,1.25) F1(-3.25,0.75) F2(-2.75,0.75) F3(-2.25,0.75) F5(-1.25,0.75) F10(1.25,0.75) F12(2.25,0.75) F13(2.75,0.75) F14(3.25,0.75) G1(-3.25,0.25) G2(-2.75,0.25) G3(-2.25,0.25) G5(-1.25,0.25) G10(1.25,0.25) G12(2.25,0.25) G13(2.75,0.25) G14(3.25,0.25) H1(-3.25,-0.25) H2(-2.75,-0.25) H3(-2.25,-0.25) H5(-1.25,-0.25) H10(1.25,-0.25) H12(2.25,-0.25) H13(2.75,-0.25) H14(3.25,-0.25) J1(-3.25,-0.75) J2(-2.75,-0.75) J3(-2.25,-0.75) J5(-1.25,-0.75) J10(1.25,-0.75) J12(2.25,-0.75) J13(2.75,-0.75) J14(3.25,-0.75) K1(-3.25,-1.25) K2(-2.75,-1.25) K3(-2.25,-1.25) K5(-1.25,-1.25) K6(-0.75,-1.25) K7(-0.25,-1.25) K8(0.25,-1.25) K9(0.75,-1.25) K10(1.25,-1.25) K12(2.25,-1.25) K13(2.75,-1.25) K14(3.25,-1.25) L1(-3.25,-1.75) L2(-2.75,-1.75) L3(-2.25,-1.75) L12(2.25,-1.75) L13(2.75,-1.75) L14(3.25,-1.75) M2(-2.75,-2.25) M3(-2.25,-2.25) M4(-1.75,-2.25) M5(-1.25,-2.25) M6(-0.75,-2.25) M7(-0.25,-2.25) M8(0.25,-2.25) M9(0.75,-2.25) M10(1.25,-2.25) M11(1.75,-2.25) M12(2.25,-2.25) M13(2.75,-2.25) M14(3.25,-2.25) N2(-2.75,-2.75) N3(-2.25,-2.75) N4(-1.75,-2.75) N5(-1.25,-2.75) N6(-0.75,-2.75) N7(-0.25,-2.75) N8(0.25,-2.75) N9(0.75,-2.75) N10(1.25,-2.75) N11(1.75,-2.75) N12(2.25,-2.75) N13(2.75,-2.75) N14(3.25,-2.75) P2(-2.75,-3.25) P3(-2.25,-3.25) P4(-1.75,-3.25) P5(-1.25,-3.25) P6(-0.75,-3.25) P7(-0.25,-3.25) P8(0.25,-3.25) P9(0.75,-3.25) P10(1.25,-3.25) P11(1.75,-3.25) P12(2.25,-3.25) P13(2.75,-3.25) P14(3.25,-3.25)
  oval 0.356x0.229 smd: B1(-3.25,2.75) C1(-3.25,2.25) M1(-3.25,-2.25) N1(-3.25,-2.75) P1(-3.25,-3.25)
BGA595M23H83
  round 0.432 smd: A2(-9.9,10.7) A3(-9.1,10.7) A25(9.1,10.7) A26(9.9,10.7) AE1(-10.7,-9.1) AE2(-9.9,-9.1) AE3(-9.1,-9.1) AE25(9.1,-9.1) AE26(9.9,-9.1) AE27(10.7,-9.1) AF1(-10.7,-9.9) AF2(-9.9,-9.9) AF3(-9.1,-9.9) AF25(9.1,-9.9) AF26(9.9,-9.9) AF27(10.7,-9.9) AG2(-9.9,-10.7) AG3(-9.1,-10.7) AG25(9.1,-10.7) AG26(9.9,-10.7) B1(-10.7,9.9) B2(-9.9,9.9) B3(-9.1,9.9) B25(9.1,9.9) B26(9.9,9.9) B27(10.7,9.9) C1(-10.7,9.1) C2(-9.9,9.1) C3(-9.1,9.1) C25(9.1,9.1) C26(9.9,9.1) C27(10.7,9.1)
  round 0.381 smd: A4(-8.3,10.7) A6(-6.6,10.7) A7(-5.8,10.7) A9(-4.12,10.7) A10(-3.32,10.7) A12(-1.64,10.7) A13(-0.84,10.7) A15(0.84,10.7) A16(1.64,10.7) A18(3.32,10.7) A19(4.12,10.7) A21(5.8,10.7) A22(6.6,10.7) A24(8.3,10.7) AA1(-10.7,-5.8) AA2(-9.9,-5.8) AA3(-9.1,-5.8) AA4(-8.3,-5.8) AA5(-7.5,-5.8) AA6(-6.66,-5.8) AA7(-5.8,-5.8) AA8(-4.96,-5.8) AA9(-4.12,-5.86) AA10(-3.32,-5.86) AA12(-1.64,-5.86) AA13(-0.84,-5.86) AA14(0,-5.86) AA15(0.84,-5.86) AA16(1.64,-5.86) AA18(3.32,-5.86) AA19(4.12,-5.86) AA20(4.96,-5.8) AA21(5.8,-5.8) AA22(6.66,-5.8) AA23(7.5,-5.8) AA24(8.3,-5.8) AA25(9.1,-5.8) AA26(9.9,-5.8) AA27(10.7,-5.8) AB1(-10.7,-6.6) AB2(-9.9,-6.6) AB3(-9.1,-6.6) AB4(-8.3,-6.6) AB5(-7.5,-6.6) AB6(-6.6,-6.6) AB7(-5.8,-6.66) AB8(-4.96,-6.66) AB9(-4.12,-6.66) AB10(-3.32,-6.66) AB11(-2.48,-6.66) AB12(-1.64,-6.66) AB13(-0.84,-6.66) AB14(0,-6.66) AB15(0.84,-6.66) AB16(1.64,-6.66) AB17(2.48,-6.66) AB18(3.32,-6.66) AB19(4.12,-6.66) AB20(4.96,-6.66) AB21(5.8,-6.66) AB22(6.6,-6.6) AB23(7.5,-6.6) AB24(8.3,-6.6) AB25(9.1,-6.6) AB26(9.9,-6.6) AB27(10.7,-6.6) AC2(-9.9,-7.45) AC3(-9.1,-7.45) AC4(-8.3,-7.45) AC5(-7.45,-7.45) AC6(-6.6,-7.5) AC7(-5.8,-7.5) AC8(-4.96,-7.5) AC9(-4.12,-7.5) AC10(-3.32,-7.5) AC11(-2.48,-7.5) AC12(-1.64,-7.5) AC13(-0.84,-7.5) AC14(0,-7.5) AC15(0.84,-7.5) AC16(1.64,-7.5) AC17(2.48,-7.5) AC18(3.32,-7.5) AC19(4.12,-7.5) AC20(4.96,-7.5) AC21(5.8,-7.5) AC22(6.6,-7.5) AC23(7.45,-7.45) AC24(8.3,-7.45) AC25(9.1,-7.45) AC26(9.9,-7.45) AD1(-10.7,-8.3) AD2(-9.9,-8.3) AD3(-9.1,-8.3) AD4(-8.3,-8.3) AD5(-7.45,-8.3) AD6(-6.6,-8.3) AD7(-5.8,-8.3) AD8(-4.96,-8.3) AD9(-4.12,-8.3) AD10(-3.32,-8.3) AD11(-2.48,-8.3) AD12(-1.64,-8.3) AD13(-0.84,-8.3) AD14(0,-8.3) AD15(0.84,-8.3) AD16(1.64,-8.3) AD17(2.48,-8.3) AD18(3.32,-8.3) AD19(4.12,-8.3) AD20(4.96,-8.3) AD21(5.8,-8.3) AD22(6.6,-8.3) AD23(7.45,-8.3) AD24(8.3,-8.3) AD25(9.1,-8.3) AD26(9.9,-8.3) AD27(10.7,-8.3) AE4(-8.3,-9.1) AE5(-7.45,-9.1) AE6(-6.6,-9.1) AE7(-5.8,-9.1) AE8(-4.96,-9.1) AE9(-4.12,-9.1) AE10(-3.32,-9.1) AE11(-2.48,-9.1) AE12(-1.64,-9.1) AE13(-0.84,-9.1) AE14(0,-9.1) AE15(0.84,-9.1) AE16(1.64,-9.1) AE17(2.48,-9.1) AE18(3.32,-9.1) AE19(4.12,-9.1) AE20(4.96,-9.1) AE21(5.8,-9.1) AE22(6.6,-9.1) AE23(7.45,-9.1) AE24(8.3,-9.1) AF4(-8.3,-9.9) AF5(-7.45,-9.9) AF6(-6.6,-9.9) AF7(-5.8,-9.9) AF8(-4.96,-9.9) AF9(-4.12,-9.9) AF10(-3.32,-9.9) AF11(-2.48,-9.9) AF12(-1.64,-9.9) AF13(-0.84,-9.9) AF14(0,-9.9) AF15(0.84,-9.9) AF16(1.64,-9.9) AF17(2.48,-9.9) AF18(3.32,-9.9) AF19(4.12,-9.9) AF20(4.96,-9.9) AF21(5.8,-9.9) AF22(6.6,-9.9) AF23(7.45,-9.9) AF24(8.3,-9.9) AG4(-8.3,-10.7) AG6(-6.6,-10.7) AG7(-5.8,-10.7) AG9(-4.12,-10.7) AG10(-3.32,-10.7) AG12(-1.64,-10.7) AG13(-0.84,-10.7) AG15(0.84,-10.7) AG16(1.64,-10.7) AG18(3.32,-10.7) AG19(4.12,-10.7) AG21(5.8,-10.7) AG22(6.6,-10.7) AG24(8.3,-10.7) B4(-8.3,9.9) B5(-7.45,9.9) B6(-6.6,9.9) B7(-5.8,9.9) B8(-4.96,9.9) B9(-4.12,9.9) B10(-3.32,9.9) B11(-2.48,9.9) B12(-1.64,9.9) B13(-0.84,9.9) B14(0,9.9) B15(0.84,9.9) B16(1.64,9.9) B17(2.48,9.9) B18(3.32,9.9) B19(4.12,9.9) B20(4.96,9.9) B21(5.8,9.9) B22(6.6,9.9) B23(7.45,9.9) B24(8.3,9.9) C4(-8.3,9.1) C5(-7.45,9.1) C6(-6.6,9.1) C7(-5.8,9.1) C8(-4.96,9.1) C9(-4.12,9.1) C10(-3.32,9.1) C11(-2.48,9.1) C12(-1.64,9.1) C13(-0.84,9.1) C14(0,9.1) C15(0.84,9.1) C16(1.64,9.1) C17(2.48,9.1) C18(3.32,9.1) C19(4.12,9.1) C20(4.96,9.1) C21(5.8,9.1) C22(6.6,9.1) C23(7.45,9.1) C24(8.3,9.1) D1(-10.7,8.3) D2(-9.9,8.3) D3(-9.1,8.3) D4(-8.3,8.3) D5(-7.45,8.3) D6(-6.6,8.3) D7(-5.8,8.3) D8(-4.96,8.3) D9(-4.12,8.3) D10(-3.32,8.3) D11(-2.48,8.3) D12(-1.64,8.3) D13(-0.84,8.3) D14(0,8.3) D15(0.84,8.3) D16(1.64,8.3) D17(2.48,8.3) D18(3.32,8.3) D19(4.12,8.3) D20(4.96,8.3) D21(5.8,8.3) D22(6.6,8.3) D23(7.45,8.3) D24(8.3,8.3) D25(9.1,8.3) D26(9.9,8.3) D27(10.7,8.3) E2(-9.9,7.45) E3(-9.1,7.45) E4(-8.3,7.45) E5(-7.45,7.45) E6(-6.6,7.5) E7(-5.8,7.5) E8(-4.96,7.5) E9(-4.12,7.5) E10(-3.32,7.5) E11(-2.48,7.5) E12(-1.64,7.5) E13(-0.84,7.5) E14(0,7.5) E15(0.84,7.5) E16(1.64,7.5) E17(2.48,7.5) E18(3.32,7.5) E19(4.12,7.5) E20(4.96,7.5) E21(5.8,7.5) E22(6.6,7.5) E23(7.45,7.45) E24(8.3,7.45) E25(9.1,7.45) E26(9.9,7.45) F1(-10.7,6.6) F2(-9.9,6.6) F3(-9.1,6.6) F4(-8.3,6.6) F5(-7.5,6.6) F6(-6.6,6.6) F7(-5.8,6.66) F8(-4.96,6.66) F9(-4.12,6.66) F10(-3.32,6.66) F11(-2.48,6.66) F12(-1.64,6.66) F13(-0.84,6.66) F14(0,6.66) F15(0.84,6.66) F16(1.64,6.66) F17(2.48,6.66) F18(3.32,6.66) F19(4.12,6.66) F20(4.96,6.66) F21(5.8,6.66) F22(6.6,6.6) F23(7.5,6.6) F24(8.3,6.6) F25(9.1,6.6) F26(9.9,6.6) F27(10.7,6.6) G1(-10.7,5.8) G2(-9.9,5.8) G3(-9.1,5.8) G4(-8.3,5.8) G5(-7.5,5.8) G6(-6.66,5.8) G7(-5.8,5.8) G8(-4.96,5.8) G9(-4.12,5.86) G10(-3.32,5.86) G12(-1.64,5.86) G13(-0.84,5.86) G14(0,5.86) G15(0.84,5.86) G16(1.64,5.86) G18(3.32,5.86) G19(4.12,5.86) G20(4.96,5.8) G21(5.8,5.8) G22(6.66,5.8) G23(7.5,5.8) G24(8.3,5.8) G25(9.1,5.8) G26(9.9,5.8) G27(10.7,5.8) H2(-9.9,4.96) H3(-9.1,4.96) H4(-8.3,4.96) H5(-7.5,4.96) H6(-6.66,4.96) H22(6.66,4.96) H23(7.5,4.96) H24(8.3,4.96) H25(9.1,4.96) H26(9.9,4.96) J1(-10.7,4.12) J2(-9.9,4.12) J3(-9.1,4.12) J4(-8.3,4.12) J5(-7.5,4.12) J6(-6.66,4.12) J7(-5.86,4.12) J21(5.86,4.12) J22(6.66,4.12) J23(7.5,4.12) J24(8.3,4.12) J25(9.1,4.12) J26(9.9,4.12) J27(10.7,4.12) K1(-10.7,3.32) K2(-9.9,3.32) K3(-9.1,3.32) K4(-8.3,3.32) K5(-7.5,3.32) K6(-6.66,3.32) K7(-5.86,3.32) K21(5.86,3.32) K22(6.66,3.32) K23(7.5,3.32) K24(8.3,3.32) K25(9.1,3.32) K26(9.9,3.32) K27(10.7,3.32) L2(-9.9,2.48) L3(-9.1,2.48) L4(-8.3,2.48) L5(-7.5,2.48) L6(-6.66,2.48) L22(6.66,2.48) L23(7.5,2.48) L24(8.3,2.48) L25(9.1,2.48) L26(9.9,2.48) M1(-10.7,1.64) M2(-9.9,1.64) M3(-9.1,1.64) M4(-8.3,1.64) M5(-7.5,1.64) M6(-6.66,1.64) M7(-5.86,1.64) M21(5.86,1.64) M22(6.66,1.64) M23(7.5,1.64) M24(8.3,1.64) M25(9.1,1.64) M26(9.9,1.64) M27(10.7,1.64) N1(-10.7,0.84) N2(-9.9,0.84) N3(-9.1,0.84) N4(-8.3,0.84) N5(-7.5,0.84) N6(-6.66,0.84) N7(-5.86,0.84) N21(5.86,0.84) N22(6.66,0.84) N23(7.5,0.84) N24(8.3,0.84) N25(9.1,0.84) N26(9.9,0.84) N27(10.7,0.84) P2(-9.9,0) P3(-9.1,0) P4(-8.3,0) P5(-7.5,0) P6(-6.66,0) P22(6.66,0) P23(7.5,0) P24(8.3,0) P25(9.1,0) P26(9.9,0) R1(-10.7,-0.84) R2(-9.9,-0.84) R3(-9.1,-0.84) R4(-8.3,-0.84) R5(-7.5,-0.84) R6(-6.66,-0.84) R7(-5.86,-0.84) R21(5.86,-0.84) R22(6.66,-0.84) R23(7.5,-0.84) R24(8.3,-0.84) R25(9.1,-0.84) R26(9.9,-0.84) R27(10.7,-0.84) T1(-10.7,-1.64) T2(-9.9,-1.64) T3(-9.1,-1.64) T4(-8.3,-1.64) T5(-7.5,-1.64) T6(-6.66,-1.64) T7(-5.86,-1.64) T21(5.86,-1.64) T22(6.66,-1.64) T23(7.5,-1.64) T24(8.3,-1.64) T25(9.1,-1.64) T26(9.9,-1.64) T27(10.7,-1.64) U2(-9.9,-2.48) U3(-9.1,-2.48) U4(-8.3,-2.48) U5(-7.5,-2.48) U6(-6.66,-2.48) U22(6.66,-2.48) U23(7.5,-2.48) U24(8.3,-2.48) U25(9.1,-2.48) U26(9.9,-2.48) V1(-10.7,-3.32) V2(-9.9,-3.32) V3(-9.1,-3.32) V4(-8.3,-3.32) V5(-7.5,-3.32) V6(-6.66,-3.32) V7(-5.86,-3.32) V21(5.86,-3.32) V22(6.66,-3.32) V23(7.5,-3.32) V24(8.3,-3.32) V25(9.1,-3.32) V26(9.9,-3.32) V27(10.7,-3.32) W1(-10.7,-4.12) W2(-9.9,-4.12) W3(-9.1,-4.12) W4(-8.3,-4.12) W5(-7.5,-4.12) W6(-6.66,-4.12) W7(-5.86,-4.12) W21(5.86,-4.12) W22(6.66,-4.12) W23(7.5,-4.12) W24(8.3,-4.12) W25(9.1,-4.12) W26(9.9,-4.12) W27(10.7,-4.12) Y2(-9.9,-4.96) Y3(-9.1,-4.96) Y4(-8.3,-4.96) Y5(-7.5,-4.96) Y6(-6.66,-4.96) Y22(6.66,-4.96) Y23(7.5,-4.96) Y24(8.3,-4.96) Y25(9.1,-4.96) Y26(9.9,-4.96)
  round 0.457 smd: K10(-4,4) K11(-3,4) K12(-2,4) K13(-1,4) K14(0,4) K15(1,4) K16(2,4) K17(3,4) K18(4,4) L10(-4,3) L11(-3,3) L12(-2,3) L13(-1,3) L14(0,3) L15(1,3) L16(2,3) L17(3,3) L18(4,3) M10(-4,2) M11(-3,2) M12(-2,2) M13(-1,2) M14(0,2) M15(1,2) M16(2,2) M17(3,2) M18(4,2) N10(-4,1) N11(-3,1) N12(-2,1) N13(-1,1) N14(0,1) N15(1,1) N16(2,1) N17(3,1) N18(4,1) P10(-4,0) P11(-3,0) P12(-2,0) P13(-1,0) P14(0,0) P15(1,0) P16(2,0) P17(3,0) P18(4,0) R10(-4,-1) R11(-3,-1) R12(-2,-1) R13(-1,-1) R14(0,-1) R15(1,-1) R16(2,-1) R17(3,-1) R18(4,-1) T10(-4,-2) T11(-3,-2) T12(-2,-2) T13(-1,-2) T14(0,-2) T15(1,-2) T16(2,-2) T17(3,-2) T18(4,-2) U10(-4,-3) U11(-3,-3) U12(-2,-3) U13(-1,-3) U14(0,-3) U15(1,-3) U16(2,-3) U17(3,-3) U18(4,-3) V10(-4,-4) V11(-3,-4) V12(-2,-4) V13(-1,-4) V14(0,-4) V15(1,-4) V16(2,-4) V17(3,-4) V18(4,-4)
BGA1296M3124H56
  round 0.47 smd: A3(13.954,-11.314) A62(-14.382,-11.314) B2(14.383,-10.883) B63(-14.814,-10.883) BH1(14.814,10.883) BH63(-14.814,10.883) BJ2(14.382,11.314) BJ62(-14.382,11.314) C1(14.814,-10.454)
  round 0.356 smd: A4(13.221,-11.314) A5(12.548,-11.314) A7(11.697,-11.314) A9(11.024,-11.314) A56(-11.411,-11.314) A58(-12.439,-11.314) A60(-13.112,-11.314) A61(-13.786,-11.314) B3(13.759,-10.72) B4(13.162,-10.72) B5(12.565,-10.72) B8(11.371,-10.72) B57(-11.841,-10.72) B58(-12.438,-10.72) B60(-13.035,-10.72) B61(-13.632,-10.72) B62(-14.238,-10.738) BB1(14.814,8.089) BB63(-14.814,8.089) BC2(14.22,8.354) BC62(-14.22,8.354) BD1(14.814,8.94) BD2(14.22,8.95) BD62(-14.22,8.95) BD63(-14.814,8.94) BE1(14.814,9.613) BE2(14.22,9.547) BE62(-14.22,9.547) BE63(-14.814,9.613) BG1(14.814,10.286) BG2(14.22,10.144) BG62(-14.22,10.144) BG63(-14.814,10.286) BH2(14.238,10.738) BH3(13.632,10.72) BH4(13.035,10.72) BH6(12.438,10.72) BH7(11.841,10.72) BH57(-11.841,10.72) BH58(-12.438,10.72) BH60(-13.035,10.72) BH61(-13.632,10.72) BH62(-14.238,10.738) BJ3(13.786,11.314) BJ4(13.112,11.314) BJ6(12.439,11.314) BJ8(11.411,11.314) BJ56(-11.411,11.314) BJ58(-12.439,11.314) BJ60(-13.112,11.314) BJ61(-13.786,11.314) C2(14.22,-10.259) C62(-14.22,-10.144) C63(-14.814,-10.286) D1(14.814,-9.724) D2(14.22,-9.665) E62(-14.22,-9.547) E63(-14.814,-9.613) F1(14.814,-9.051) F2(14.22,-9.072) F62(-14.22,-8.95) F63(-14.814,-8.94) G1(14.814,-8.2) G2(14.258,-8.474) G62(-14.22,-8.354) H63(-14.814,-8.089) J1(14.814,-7.527)
  oval 0.254x0.343 smd: A10(10.198,-11.314) A12(9.271,-11.314) A14(8.344,-11.314) A16(7.417,-11.314) A18(6.49,-11.314) A20(5.563,-11.314) A22(4.636,-11.314) A24(3.708,-11.314) A26(2.781,-11.314) A28(1.854,-11.314) A30(0.927,-11.314) A32(0,-11.314) A34(-0.927,-11.314) A36(-1.854,-11.314) A38(-2.781,-11.314) A40(-3.708,-11.314) A42(-4.636,-11.314) A44(-5.563,-11.314) A46(-6.49,-11.314) A48(-7.417,-11.314) A50(-8.344,-11.314) A52(-9.271,-11.314) A54(-10.198,-11.314) BJ10(10.198,11.314) BJ12(9.271,11.314) BJ14(8.344,11.314) BJ16(7.417,11.314) BJ18(6.49,11.314) BJ20(5.563,11.314) BJ22(4.636,11.314) BJ24(3.708,11.314) BJ26(2.781,11.314) BJ28(1.854,11.314) BJ30(0.927,11.314) BJ32(0,11.314) BJ34(-0.927,11.314) BJ36(-1.854,11.314) BJ38(-2.781,11.314) BJ40(-3.708,11.314) BJ42(-4.636,11.314) BJ44(-5.563,11.314) BJ46(-6.49,11.314) BJ48(-7.417,11.314) BJ50(-8.344,11.314) BJ52(-9.271,11.314) BJ54(-10.198,11.314)
  oval 0.343x0.254 smd: AA1(14.814,-1.854) AA63(-14.814,-1.854) AC1(14.814,-0.927) AC63(-14.814,-0.927) AE1(14.814,0) AE63(-14.814,0) AG1(14.814,0.927) AG63(-14.814,0.927) AJ1(14.814,1.854) AJ63(-14.814,1.854) AL1(14.814,2.781) AL63(-14.814,2.781) AN1(14.814,3.708) AN63(-14.814,3.708) AR1(14.814,4.636) AR63(-14.814,4.636) AU1(14.814,5.563) AU63(-14.814,5.563) AW1(14.814,6.49) AW63(-14.814,6.49) BA1(14.814,7.417) BA63(-14.814,7.417) J63(-14.814,-7.417) L1(14.814,-6.49) L63(-14.814,-6.49) N1(14.814,-5.563) N63(-14.814,-5.563) R1(14.814,-4.636) R63(-14.814,-4.636) U1(14.814,-3.708) U63(-14.814,-3.708) W1(14.814,-2.781) W63(-14.814,-2.781)
  round 0.279 smd: AA2(14.037,-1.854) AA62(-14.037,-1.854) AB2(14.414,-1.391) AB3(13.66,-1.391) AB61(-13.66,-1.391) AB62(-14.414,-1.391) AC2(14.037,-0.927) AC62(-14.037,-0.927) AD2(14.414,-0.464) AD3(13.66,-0.464) AD61(-13.66,-0.464) AD62(-14.414,-0.464) AE2(14.037,0) AE4(13.285,0) AE60(-13.285,0) AE62(-14.037,0) AF2(14.414,0.464) AF3(13.66,0.464) AF61(-13.66,0.464) AF62(-14.414,0.464) AG2(14.037,0.927) AG62(-14.037,0.927) AH2(14.414,1.391) AH3(13.66,1.391) AH61(-13.66,1.391) AH62(-14.414,1.391) AJ2(14.037,1.854) AJ62(-14.037,1.854) AK2(14.414,2.318) AK3(13.66,2.318) AK61(-13.66,2.318) AK62(-14.414,2.318) AL2(14.037,2.781) AL62(-14.037,2.781) AM2(14.414,3.245) AM3(13.66,3.245) AM61(-13.66,3.245) AM62(-14.414,3.245) AN2(14.037,3.708) AN62(-14.037,3.708) AP2(14.414,4.172) AP3(13.66,4.172) AP61(-13.66,4.172) AP62(-14.414,4.172) AR2(14.037,4.636) AR62(-14.037,4.636) AT2(14.414,5.099) AT3(13.66,5.099) AT61(-13.66,5.099) AT62(-14.414,5.099) AU2(14.037,5.563) AU62(-14.037,5.563) AV2(14.414,6.026) AV3(13.66,6.026) AV61(-13.66,6.026) AV62(-14.414,6.026) AW2(14.037,6.49) AW62(-14.037,6.49) AY2(14.414,6.953) AY3(13.66,6.953) AY61(-13.66,6.953) AY62(-14.414,6.953) B9(10.774,-10.745) B11(9.735,-10.914) B13(8.807,-10.914) B15(7.88,-10.914) B17(6.953,-10.914) B19(6.026,-10.914) B21(5.099,-10.914) B23(4.172,-10.914) B25(3.245,-10.914) B27(2.318,-10.914) B29(1.391,-10.914) B31(0.464,-10.914) B33(-0.464,-10.914) B35(-1.391,-10.914) B37(-2.318,-10.914) B39(-3.245,-10.914) B41(-4.172,-10.914) B43(-5.099,-10.914) B45(-6.026,-10.914) B47(-6.953,-10.914) B49(-7.88,-10.914) B51(-8.807,-10.914) B53(-9.735,-10.914) B55(-10.662,-10.914) BA2(14.22,7.544) BA62(-14.22,7.544) BF32(0,9.78) BG7(11.589,10.159) BG8(11.125,10.537) BG9(10.662,10.159) BG10(10.198,10.537) BG11(9.735,10.159) BG12(9.271,10.537) BG13(8.807,10.159) BG14(8.344,10.537) BG15(7.88,10.159) BG16(7.417,10.537) BG17(6.953,10.159) BG18(6.49,10.537) BG19(6.026,10.159) BG20(5.563,10.537) BG21(5.099,10.159) BG22(4.636,10.537) BG23(4.172,10.159) BG24(3.708,10.537) BG25(3.245,10.159) BG26(2.781,10.537) BG27(2.318,10.159) BG28(1.854,10.537) BG29(1.391,10.159) BG30(0.927,10.537) BG31(0.464,10.159) BG32(0,10.537) BG33(-0.464,10.159) BG34(-0.927,10.537) BG35(-1.391,10.159) BG36(-1.854,10.537) BG37(-2.318,10.159) BG38(-2.781,10.537) BG39(-3.245,10.159) BG40(-3.708,10.537) BG41(-4.172,10.159) BG42(-4.636,10.537) BG43(-5.099,10.159) BG44(-5.563,10.537) BG45(-6.026,10.159) BG46(-6.49,10.537) BG47(-6.953,10.159) BG48(-7.417,10.537) BG49(-7.88,10.159) BG50(-8.344,10.537) BG51(-8.807,10.159) BG52(-9.271,10.537) BG53(-9.735,10.159) BG54(-10.198,10.537) BG55(-10.662,10.159) BG56(-11.125,10.537) BG57(-11.589,10.159) BH9(10.662,10.914) BH11(9.735,10.914) BH13(8.807,10.914) BH15(7.88,10.914) BH17(6.953,10.914) BH19(6.026,10.914) BH21(5.099,10.914) BH23(4.172,10.914) BH25(3.245,10.914) BH27(2.318,10.914) BH29(1.391,10.914) BH31(0.464,10.914) BH33(-0.464,10.914) BH35(-1.391,10.914) BH37(-2.318,10.914) BH39(-3.245,10.914) BH41(-4.172,10.914) BH43(-5.099,10.914) BH45(-6.026,10.914) BH47(-6.953,10.914) BH49(-7.88,10.914) BH51(-8.807,10.914) BH53(-9.735,10.914) BH55(-10.662,10.914) C9(10.662,-10.159) C10(10.198,-10.537) C11(9.735,-10.159) C12(9.271,-10.537) C13(8.807,-10.159) C14(8.344,-10.537) C15(7.88,-10.159) C16(7.417,-10.537) C17(6.953,-10.159) C18(6.49,-10.537) C19(6.026,-10.159) C20(5.563,-10.537) C21(5.099,-10.159) C22(4.636,-10.537) C23(4.172,-10.159) C24(3.708,-10.537) C25(3.245,-10.159) C26(2.781,-10.537) C27(2.318,-10.159) C28(1.854,-10.537) C29(1.391,-10.159) C30(0.927,-10.537) C31(0.464,-10.159) C32(0,-10.537) C33(-0.464,-10.159) C34(-0.927,-10.537) C35(-1.391,-10.159) C36(-1.854,-10.537) C37(-2.318,-10.159) C38(-2.781,-10.537) C39(-3.245,-10.159) C40(-3.708,-10.537) C41(-4.172,-10.159) C42(-4.636,-10.537) C43(-5.099,-10.159) C44(-5.563,-10.537) C45(-6.026,-10.159) C46(-6.49,-10.537) C47(-6.953,-10.159) C48(-7.417,-10.537) C49(-7.88,-10.159) C50(-8.344,-10.537) C51(-8.807,-10.159) C52(-9.271,-10.537) C53(-9.735,-10.159) C54(-10.198,-10.537) C55(-10.662,-10.159) C56(-11.125,-10.537) C57(-11.589,-10.159) D32(0,-9.78) H61(-13.66,-8.001) J2(14.037,-7.417) J62(-14.22,-7.544) K2(14.414,-6.953) K3(13.66,-6.953) K61(-13.66,-6.953) K62(-14.414,-6.953) L2(14.037,-6.49) L62(-14.037,-6.49) M2(14.414,-6.026) M3(13.66,-6.026) M61(-13.66,-6.026) M62(-14.414,-6.026) N2(14.037,-5.563) N62(-14.037,-5.563) P2(14.414,-5.099) P3(13.66,-5.099) P61(-13.66,-5.099) P62(-14.414,-5.099) R2(14.037,-4.636) R62(-14.037,-4.636) T2(14.414,-4.172) T3(13.66,-4.172) T61(-13.66,-4.172) T62(-14.414,-4.172) U2(14.037,-3.708) U62(-14.037,-3.708) V2(14.414,-3.245) V3(13.66,-3.245) V61(-13.66,-3.245) V62(-14.414,-3.245) W2(14.037,-2.781) W62(-14.037,-2.781) Y2(14.414,-2.318) Y3(13.66,-2.318) Y61(-13.66,-2.318) Y62(-14.414,-2.318)
  round 0.33 smd: AA18(6.299,-1.448) AA20(5.512,-1.448) AA22(4.724,-1.448) AA23(3.937,-1.448) AA25(3.15,-1.448) AA27(2.362,-1.448) AA28(1.575,-1.448) AA30(0.787,-1.448) AA32(0,-1.448) AA34(-0.787,-1.448) AA36(-1.575,-1.448) AA37(-2.362,-1.448) AA39(-3.15,-1.448) AA41(-3.937,-1.448) AA42(-4.724,-1.448) AA44(-5.512,-1.448) AA46(-6.299,-1.448) AC18(6.299,-0.724) AC20(5.512,-0.724) AC22(4.724,-0.724) AC23(3.937,-0.724) AC25(3.15,-0.724) AC27(2.362,-0.724) AC28(1.575,-0.724) AC30(0.787,-0.724) AC32(0,-0.724) AC34(-0.787,-0.724) AC36(-1.575,-0.724) AC37(-2.362,-0.724) AC39(-3.15,-0.724) AC41(-3.937,-0.724) AC42(-4.724,-0.724) AC44(-5.512,-0.724) AC46(-6.299,-0.724) AE18(6.299,0) AE20(5.512,0) AE22(4.724,0) AE23(3.937,0) AE25(3.15,0) AE27(2.362,0) AE28(1.575,0) AE30(0.787,0) AE32(0,0) AE34(-0.787,0) AE36(-1.575,0) AE37(-2.362,0) AE39(-3.15,0) AE41(-3.937,0) AE42(-4.724,0) AE44(-5.512,0) AE46(-6.299,0) AG18(6.299,0.724) AG20(5.512,0.724) AG22(4.724,0.724) AG23(3.937,0.724) AG25(3.15,0.724) AG27(2.362,0.724) AG28(1.575,0.724) AG30(0.787,0.724) AG32(0,0.724) AG34(-0.787,0.724) AG36(-1.575,0.724) AG37(-2.362,0.724) AG39(-3.15,0.724) AG41(-3.937,0.724) AG42(-4.724,0.724) AG44(-5.512,0.724) AG46(-6.299,0.724) AJ18(6.299,1.448) AJ20(5.512,1.448) AJ22(4.724,1.448) AJ23(3.937,1.448) AJ25(3.15,1.448) AJ27(2.362,1.448) AJ28(1.575,1.448) AJ30(0.787,1.448) AJ32(0,1.448) AJ34(-0.787,1.448) AJ36(-1.575,1.448) AJ37(-2.362,1.448) AJ39(-3.15,1.448) AJ41(-3.937,1.448) AJ42(-4.724,1.448) AJ44(-5.512,1.448) AJ46(-6.299,1.448) AK18(6.299,2.172) AK20(5.512,2.172) AK22(4.724,2.172) AK23(3.937,2.172) AK25(3.15,2.172) AK27(2.362,2.172) AK28(1.575,2.172) AK30(0.787,2.172) AK32(0,2.172) AK34(-0.787,2.172) AK36(-1.575,2.172) AK37(-2.362,2.172) AK39(-3.15,2.172) AK41(-3.937,2.172) AK42(-4.724,2.172) AK44(-5.512,2.172) AK46(-6.299,2.172) AM18(6.299,2.896) AM20(5.512,2.896) AM22(4.724,2.896) AM23(3.937,2.896) AM25(3.15,2.896) AM27(2.362,2.896) AM28(1.575,2.896) AM30(0.787,2.896) AM32(0,2.896) AM34(-0.787,2.896) AM36(-1.575,2.896) AM37(-2.362,2.896) AM39(-3.15,2.896) AM41(-3.937,2.896) AM42(-4.724,2.896) AM44(-5.512,2.896) AM46(-6.299,2.896) AN18(6.299,3.619) AN20(5.512,3.619) AN22(4.724,3.619) AN23(3.937,3.619) AN25(3.15,3.619) AN27(2.362,3.619) AN28(1.575,3.619) AN30(0.787,3.619) AN32(0,3.619) AN34(-0.787,3.619) AN36(-1.575,3.619) AN37(-2.362,3.619) AN39(-3.15,3.619) AN41(-3.937,3.619) AN42(-4.724,3.619) AN44(-5.512,3.619) AN46(-6.299,3.619) U18(6.299,-3.619) U20(5.512,-3.619) U22(4.724,-3.619) U23(3.937,-3.619) U25(3.15,-3.619) U27(2.362,-3.619) U28(1.575,-3.619) U30(0.787,-3.619) U32(0,-3.619) U34(-0.787,-3.619) U36(-1.575,-3.619) U37(-2.362,-3.619) U39(-3.15,-3.619) U41(-3.937,-3.619) U42(-4.724,-3.619) U44(-5.512,-3.619) U46(-6.299,-3.619) V18(6.299,-2.896) V20(5.512,-2.896) V22(4.724,-2.896) V23(3.937,-2.896) V25(3.15,-2.896) V27(2.362,-2.896) V28(1.575,-2.896) V30(0.787,-2.896) V32(0,-2.896) V34(-0.787,-2.896) V36(-1.575,-2.896) V37(-2.362,-2.896) V39(-3.15,-2.896) V41(-3.937,-2.896) V42(-4.724,-2.896) V44(-5.512,-2.896) V46(-6.299,-2.896) Y18(6.299,-2.172) Y20(5.512,-2.172) Y22(4.724,-2.172) Y23(3.937,-2.172) Y25(3.15,-2.172) Y27(2.362,-2.172) Y28(1.575,-2.172) Y30(0.787,-2.172) Y32(0,-2.172) Y34(-0.787,-2.172) Y36(-1.575,-2.172) Y37(-2.362,-2.172) Y39(-3.15,-2.172) Y41(-3.937,-2.172) Y42(-4.724,-2.172) Y44(-5.512,-2.172) Y46(-6.299,-2.172)
  round 0.305 smd: AB5(12.999,-1.397) AB6(12.288,-1.397) AB7(11.577,-1.397) AB9(10.866,-1.397) AB10(10.154,-1.397) AB12(9.443,-1.397) AB13(8.732,-1.397) AB15(8.021,-1.397) AB16(7.309,-1.397) AB48(-7.309,-1.397) AB49(-8.021,-1.397) AB51(-8.732,-1.397) AB52(-9.443,-1.397) AB54(-10.154,-1.397) AB55(-10.866,-1.397) AB57(-11.577,-1.397) AB58(-12.288,-1.397) AB59(-12.999,-1.397) AC5(12.999,-0.521) AC6(12.288,-0.521) AC7(11.577,-0.521) AC9(10.866,-0.521) AC10(10.154,-0.521) AC12(9.443,-0.521) AC13(8.732,-0.521) AC15(8.021,-0.521) AC16(7.309,-0.521) AC48(-7.309,-0.521) AC49(-8.021,-0.521) AC51(-8.732,-0.521) AC52(-9.443,-0.521) AC54(-10.154,-0.521) AC55(-10.866,-0.521) AC57(-11.577,-0.521) AC58(-12.288,-0.521) AC59(-12.999,-0.521) AE5(12.644,0) AE7(11.932,0) AE8(11.221,0) AE10(10.51,0) AE11(9.799,0) AE13(9.088,0) AE14(8.376,0) AE16(7.665,0) AE17(6.954,0) AE47(-6.954,0) AE48(-7.665,0) AE50(-8.376,0) AE51(-9.088,0) AE53(-9.799,0) AE54(-10.51,0) AE56(-11.221,0) AE57(-11.932,0) AE59(-12.644,0) AG5(12.999,0.521) AG6(12.288,0.521) AG7(11.577,0.521) AG9(10.866,0.521) AG10(10.154,0.521) AG12(9.443,0.521) AG13(8.732,0.521) AG15(8.021,0.521) AG16(7.309,0.521) AG48(-7.309,0.521) AG49(-8.021,0.521) AG51(-8.732,0.521) AG52(-9.443,0.521) AG54(-10.154,0.521) AG55(-10.866,0.521) AG57(-11.577,0.521) AG58(-12.288,0.521) AG59(-12.999,0.521) AH5(12.999,1.397) AH6(12.288,1.397) AH7(11.577,1.397) AH9(10.866,1.397) AH10(10.154,1.397) AH12(9.443,1.397) AH13(8.732,1.397) AH15(8.021,1.397) AH16(7.309,1.397) AH48(-7.309,1.397) AH49(-8.021,1.397) AH51(-8.732,1.397) AH52(-9.443,1.397) AH54(-10.154,1.397) AH55(-10.866,1.397) AH57(-11.577,1.397) AH58(-12.288,1.397) AH59(-12.999,1.397) AK5(12.999,2.349) AK6(12.288,2.349) AK7(11.577,2.349) AK9(10.866,2.349) AK10(10.154,2.349) AK12(9.443,2.349) AK13(8.732,2.349) AK15(8.021,2.349) AK16(7.309,2.349) AK48(-7.309,2.349) AK49(-8.021,2.349) AK51(-8.732,2.349) AK52(-9.443,2.349) AK54(-10.154,2.349) AK55(-10.866,2.349) AK57(-11.577,2.349) AK58(-12.288,2.349) AK59(-12.999,2.349) AM5(12.999,3.226) AM6(12.288,3.226) AM7(11.577,3.226) AM9(10.866,3.226) AM10(10.154,3.226) AM12(9.443,3.226) AM13(8.732,3.226) AM15(8.021,3.226) AM16(7.309,3.226) AM48(-7.309,3.226) AM49(-8.021,3.226) AM51(-8.732,3.226) AM52(-9.443,3.226) AM54(-10.154,3.226) AM55(-10.866,3.226) AM57(-11.577,3.226) AM58(-12.288,3.226) AM59(-12.999,3.226) AN5(12.644,3.747) AN7(11.932,3.747) AN8(11.221,3.747) AN10(10.51,3.747) AN11(9.799,3.747) AN13(9.088,3.747) AN14(8.376,3.747) AN16(7.665,3.747) AN17(6.954,3.747) AN47(-6.954,3.747) AN48(-7.665,3.747) AN50(-8.376,3.747) AN51(-9.088,3.747) AN53(-9.799,3.747) AN54(-10.51,3.747) AN56(-11.221,3.747) AN57(-11.932,3.747) AN59(-12.644,3.747) AP5(12.999,4.267) AP6(12.288,4.267) AP7(11.577,4.267) AP9(10.866,4.267) AP10(10.154,4.267) AP12(9.443,4.267) AP13(8.732,4.267) AP15(8.021,4.267) AP49(-8.021,4.267) AP51(-8.732,4.267) AP52(-9.443,4.267) AP54(-10.154,4.267) AP55(-10.866,4.267) AP57(-11.577,4.267) AP58(-12.288,4.267) AP59(-12.999,4.267) AR17(7.004,4.432) AR19(6.096,4.432) AR21(5.144,4.432) AR23(4.223,4.432) AR25(3.27,4.432) AR27(2.349,4.432) AR29(1.397,4.432) AR30(0.476,4.432) AR32(0,4.787) AR34(-0.476,4.432) AR35(-1.397,4.432) AR37(-2.349,4.432) AR39(-3.27,4.432) AR41(-4.223,4.432) AR43(-5.144,4.432) AR45(-6.096,4.432) AR47(-7.004,4.432) AT5(12.999,5.144) AT6(12.288,5.144) AT7(11.577,5.144) AT9(10.866,5.144) AT10(10.154,5.144) AT12(9.443,5.144) AT13(8.732,5.144) AT16(7.626,5.143) AT17(7.004,5.143) AT19(6.096,5.143) AT21(5.144,5.143) AT23(4.223,5.143) AT25(3.27,5.143) AT27(2.349,5.143) AT29(1.397,5.143) AT30(0.476,5.143) AT34(-0.476,5.143) AT35(-1.397,5.143) AT37(-2.349,5.143) AT39(-3.27,5.143) AT41(-4.223,5.143) AT43(-5.144,5.143) AT45(-6.096,5.143) AT47(-7.004,5.143) AT48(-7.626,5.143) AT51(-8.732,5.144) AT52(-9.443,5.144) AT54(-10.154,5.144) AT55(-10.866,5.144) AT57(-11.577,5.144) AT58(-12.288,5.144) AT59(-12.999,5.144) AU32(0,5.499) AV5(12.999,6.096) AV6(12.288,6.096) AV7(11.577,6.096) AV9(10.866,6.096) AV10(10.154,6.096) AV12(9.443,6.096) AV14(8.534,5.854) AV16(7.626,5.854) AV17(7.004,5.854) AV19(6.096,5.854) AV21(5.144,5.854) AV23(4.223,5.854) AV25(3.27,5.854) AV27(2.349,5.854) AV29(1.397,5.854) AV30(0.476,5.854) AV32(0,6.21) AV34(-0.476,5.854) AV35(-1.397,5.854) AV37(-2.349,5.854) AV39(-3.27,5.854) AV41(-4.223,5.854) AV43(-5.144,5.854) AV45(-6.096,5.854) AV47(-7.004,5.854) AV48(-7.626,5.854) AV50(-8.534,5.854) AV52(-9.443,6.096) AV54(-10.154,6.096) AV55(-10.866,6.096) AV57(-11.577,6.096) AV58(-12.288,6.096) AV59(-12.999,6.096) AW14(8.534,6.565) AW16(7.626,6.565) AW17(7.004,6.565) AW19(6.096,6.565) AW21(5.144,6.565) AW23(4.223,6.565) AW25(3.27,6.565) AW27(2.349,6.565) AW29(1.397,6.565) AW30(0.476,6.565) AW34(-0.476,6.565) AW35(-1.397,6.565) AW37(-2.349,6.565) AW39(-3.27,6.565) AW41(-4.223,6.565) AW43(-5.144,6.565) AW45(-6.096,6.565) AW47(-7.004,6.565) AW48(-7.626,6.565) AW50(-8.534,6.565) AY5(12.999,7.048) AY6(12.288,7.048) AY7(11.577,7.048) AY9(10.866,7.048) AY10(10.154,7.048) AY32(0,6.921) AY54(-10.154,7.048) AY55(-10.866,7.048) AY57(-11.577,7.048) AY58(-12.288,7.048) AY59(-12.999,7.048) B7(11.968,-10.72) BA12(9.487,7.277) BA14(8.534,7.277) BA16(7.626,7.277) BA17(7.004,7.277) BA19(6.096,7.277) BA21(5.144,7.277) BA23(4.223,7.277) BA25(3.27,7.277) BA27(2.349,7.277) BA29(1.397,7.277) BA30(0.476,7.277) BA32(0,7.632) BA34(-0.476,7.277) BA35(-1.397,7.277) BA37(-2.349,7.277) BA39(-3.27,7.277) BA41(-4.223,7.277) BA43(-5.144,7.277) BA45(-6.096,7.277) BA47(-7.004,7.277) BA48(-7.626,7.277) BA50(-8.534,7.277) BA52(-9.487,7.277) BB3(13.66,8.001) BB5(12.999,8.001) BB6(12.288,8.001) BB7(11.577,8.001) BB10(10.439,7.988) BB12(9.487,7.988) BB14(8.534,7.988) BB16(7.626,7.988) BB17(7.004,7.988) BB19(6.096,7.988) BB21(5.144,7.988) BB23(4.223,7.988) BB25(3.27,7.988) BB27(2.349,7.988) BB29(1.397,7.988) BB30(0.476,7.988) BB34(-0.476,7.988) BB35(-1.397,7.988) BB37(-2.349,7.988) BB39(-3.27,7.988) BB41(-4.223,7.988) BB43(-5.144,7.988) BB45(-6.096,7.988) BB47(-7.004,7.988) BB48(-7.626,7.988) BB50(-8.534,7.988) BB52(-9.487,7.988) BB54(-10.439,7.988) BB57(-11.577,8.001) BB58(-12.288,8.001) BB59(-12.999,8.001) BB61(-13.66,8.001) BC32(0,8.343) BD3(13.629,8.89) BD5(12.961,8.89) BD6(12.288,8.89) BD8(11.392,8.699) BD10(10.439,8.699) BD12(9.487,8.699) BD14(8.534,8.699) BD16(7.626,8.699) BD17(7.004,8.699) BD19(6.096,8.699) BD21(5.144,8.699) BD23(4.223,8.699) BD25(3.27,8.699) BD27(2.349,8.699) BD29(1.397,8.699) BD30(0.476,8.699) BD32(0,9.055) BD34(-0.476,8.699) BD35(-1.397,8.699) BD37(-2.349,8.699) BD39(-3.27,8.699) BD41(-4.223,8.699) BD43(-5.144,8.699) BD45(-6.096,8.699) BD47(-7.004,8.699) BD48(-7.626,8.699) BD50(-8.534,8.699) BD52(-9.487,8.699) BD54(-10.439,8.699) BD56(-11.392,8.699) BD58(-12.288,8.89) BD59(-12.961,8.89) BD61(-13.629,8.89) BE8(11.392,9.41) BE10(10.439,9.41) BE12(9.487,9.41) BE14(8.534,9.41) BE16(7.626,9.41) BE17(7.004,9.41) BE19(6.096,9.41) BE21(5.144,9.41) BE23(4.223,9.41) BE25(3.27,9.41) BE27(2.349,9.41) BE29(1.397,9.41) BE30(0.476,9.41) BE34(-0.476,9.41) BE35(-1.397,9.41) BE37(-2.349,9.41) BE39(-3.27,9.41) BE41(-4.223,9.41) BE43(-5.144,9.41) BE45(-6.096,9.41) BE47(-7.004,9.41) BE48(-7.626,9.41) BE50(-8.534,9.41) BE52(-9.487,9.41) BE54(-10.439,9.41) BE56(-11.392,9.41) BF3(13.629,9.682) BF5(12.961,9.682) BF6(12.344,10.121) BF58(-12.344,10.121) BF59(-12.961,9.682) BF61(-13.629,9.682) D4(13.139,-10.121) D6(12.255,-10.121) D8(11.392,-10.121) D58(-12.344,-10.121) D59(-12.961,-9.682) D61(-13.629,-9.682) E3(13.622,-9.624) E4(13.025,-9.474) E6(12.255,-9.41) E8(11.392,-9.41) E10(10.439,-9.41) E12(9.487,-9.41) E14(8.534,-9.41) E16(7.626,-9.41) E17(7.004,-9.41) E19(6.096,-9.41) E21(5.144,-9.41) E23(4.223,-9.41) E25(3.27,-9.41) E27(2.349,-9.41) E29(1.397,-9.41) E30(0.476,-9.41) E34(-0.476,-9.41) E35(-1.397,-9.41) E37(-2.349,-9.41) E39(-3.27,-9.41) E41(-4.223,-9.41) E43(-5.144,-9.41) E45(-6.096,-9.41) E47(-7.004,-9.41) E48(-7.626,-9.41) E50(-8.534,-9.41) E52(-9.487,-9.41) E54(-10.439,-9.41) E56(-11.392,-9.41) F3(13.698,-8.7) F5(12.999,-8.7) F6(12.288,-8.7) F8(11.392,-8.699) F10(10.439,-8.699) F12(9.487,-8.699) F14(8.534,-8.699) F16(7.626,-8.699) F17(7.004,-8.699) F19(6.096,-8.699) F21(5.144,-8.699) F23(4.223,-8.699) F25(3.27,-8.699) F27(2.349,-8.699) F29(1.397,-8.699) F30(0.476,-8.699) F32(0,-9.055) F34(-0.476,-8.699) F35(-1.397,-8.699) F37(-2.349,-8.699) F39(-3.27,-8.699) F41(-4.223,-8.699) F43(-5.144,-8.699) F45(-6.096,-8.699) F47(-7.004,-8.699) F48(-7.626,-8.699) F50(-8.534,-8.699) F52(-9.487,-8.699) F54(-10.439,-8.699) F56(-11.392,-8.699) F58(-12.288,-8.89) F59(-12.961,-8.89) F61(-13.629,-8.89) G32(0,-8.343) H3(13.859,-8.02) H5(12.999,-7.912) H6(12.288,-7.912) H7(11.577,-7.912) H10(10.439,-7.988) H12(9.487,-7.988) H14(8.534,-7.988) H16(7.626,-7.988) H17(7.004,-7.988) H19(6.096,-7.988) H21(5.144,-7.988) H23(4.223,-7.988) H25(3.27,-7.988) H27(2.349,-7.988) H29(1.397,-7.988) H30(0.476,-7.988) H34(-0.476,-7.988) H35(-1.397,-7.988) H37(-2.349,-7.988) H39(-3.27,-7.988) H41(-4.223,-7.988) H43(-5.144,-7.988) H45(-6.096,-7.988) H47(-7.004,-7.988) H48(-7.626,-7.988) H50(-8.534,-7.988) H52(-9.487,-7.988) H54(-10.439,-7.988) H57(-11.577,-8.001) H58(-12.288,-8.001) H59(-12.999,-8.001) J12(9.487,-7.277) J14(8.534,-7.277) J16(7.626,-7.277) J17(7.004,-7.277) J19(6.096,-7.277) J21(5.144,-7.277) J23(4.223,-7.277) J25(3.27,-7.277) J27(2.349,-7.277) J29(1.397,-7.277) J30(0.476,-7.277) J32(0,-7.632) J34(-0.476,-7.277) J35(-1.397,-7.277) J37(-2.349,-7.277) J39(-3.27,-7.277) J41(-4.223,-7.277) J43(-5.144,-7.277) J45(-6.096,-7.277) J47(-7.004,-7.277) J48(-7.626,-7.277) J50(-8.534,-7.277) J52(-9.487,-7.277) K5(12.999,-7.048) K6(12.288,-7.048) K7(11.577,-7.048) K9(10.866,-7.048) K10(10.154,-7.048) K32(0,-6.921) K54(-10.154,-7.048) K55(-10.866,-7.048) K57(-11.577,-7.048) K58(-12.288,-7.048) K59(-12.999,-7.048) L14(8.534,-6.565) L16(7.626,-6.565) L17(7.004,-6.565) L19(6.096,-6.565) L21(5.144,-6.565) L23(4.223,-6.565) L25(3.27,-6.565) L27(2.349,-6.565) L29(1.397,-6.565) L30(0.476,-6.565) L34(-0.476,-6.565) L35(-1.397,-6.565) L37(-2.349,-6.565) L39(-3.27,-6.565) L41(-4.223,-6.565) L43(-5.144,-6.565) L45(-6.096,-6.565) L47(-7.004,-6.565) L48(-7.626,-6.565) L50(-8.534,-6.565) M5(12.999,-6.096) M6(12.288,-6.096) M7(11.577,-6.096) M9(10.866,-6.096) M10(10.154,-6.096) M12(9.443,-6.096) M14(8.534,-5.854) M16(7.626,-5.854) M17(7.004,-5.854) M19(6.096,-5.854) M21(5.144,-5.854) M23(4.223,-5.854) M25(3.27,-5.854) M27(2.349,-5.854) M29(1.397,-5.854) M30(0.476,-5.854) M32(0,-6.21) M34(-0.476,-5.854) M35(-1.397,-5.854) M37(-2.349,-5.854) M39(-3.27,-5.854) M41(-4.223,-5.854) M43(-5.144,-5.854) M45(-6.096,-5.854) M47(-7.004,-5.854) M48(-7.626,-5.854) M50(-8.534,-5.854) M52(-9.443,-6.096) M54(-10.154,-6.096) M55(-10.866,-6.096) M57(-11.577,-6.096) M58(-12.288,-6.096) M59(-12.999,-6.096) N32(0,-5.499) P5(12.999,-5.144) P6(12.288,-5.144) P7(11.577,-5.144) P9(10.866,-5.144) P10(10.154,-5.144) P12(9.443,-5.144) P13(8.732,-5.144) P16(7.626,-5.143) P17(7.004,-5.143) P19(6.096,-5.143) P21(5.144,-5.143) P23(4.223,-5.143) P25(3.27,-5.143) P27(2.349,-5.143) P29(1.397,-5.143) P30(0.476,-5.143) P34(-0.476,-5.143) P35(-1.397,-5.143) P37(-2.349,-5.143) P39(-3.27,-5.143) P41(-4.223,-5.143) P43(-5.144,-5.143) P45(-6.096,-5.143) P47(-7.004,-5.143) P48(-7.626,-5.143) P51(-8.732,-5.144) P52(-9.443,-5.144) P54(-10.154,-5.144) P55(-10.866,-5.144) P57(-11.577,-5.144) P58(-12.288,-5.144) P59(-12.999,-5.144) R17(7.004,-4.432) R19(6.096,-4.432) R21(5.144,-4.432) R23(4.223,-4.432) R25(3.27,-4.432) R27(2.349,-4.432) R29(1.397,-4.432) R30(0.476,-4.432) R32(0,-4.787) R34(-0.476,-4.432) R35(-1.397,-4.432) R37(-2.349,-4.432) R39(-3.27,-4.432) R41(-4.223,-4.432) R43(-5.144,-4.432) R45(-6.096,-4.432) R47(-7.004,-4.432) T5(12.999,-4.267) T6(12.288,-4.267) T7(11.577,-4.267) T9(10.866,-4.267) T10(10.154,-4.267) T12(9.443,-4.267) T13(8.732,-4.267) T15(8.021,-4.267) T49(-8.021,-4.267) T51(-8.732,-4.267) T52(-9.443,-4.267) T54(-10.154,-4.267) T55(-10.866,-4.267) T57(-11.577,-4.267) T58(-12.288,-4.267) T59(-12.999,-4.267) U5(12.644,-3.747) U7(11.932,-3.747) U8(11.221,-3.747) U10(10.51,-3.747) U11(9.799,-3.747) U13(9.088,-3.747) U14(8.376,-3.747) U16(7.665,-3.747) U17(6.954,-3.747) U47(-6.954,-3.747) U48(-7.665,-3.747) U50(-8.376,-3.747) U51(-9.088,-3.747) U53(-9.799,-3.747) U54(-10.51,-3.747) U56(-11.221,-3.747) U57(-11.932,-3.747) U59(-12.644,-3.747) V5(12.999,-3.226) V6(12.288,-3.226) V7(11.577,-3.226) V9(10.866,-3.226) V10(10.154,-3.226) V12(9.443,-3.226) V13(8.732,-3.226) V15(8.021,-3.226) V16(7.309,-3.226) V48(-7.309,-3.226) V49(-8.021,-3.226) V51(-8.732,-3.226) V52(-9.443,-3.226) V54(-10.154,-3.226) V55(-10.866,-3.226) V57(-11.577,-3.226) V58(-12.288,-3.226) V59(-12.999,-3.226) Y5(12.999,-2.349) Y6(12.288,-2.349) Y7(11.577,-2.349) Y9(10.866,-2.349) Y10(10.154,-2.349) Y12(9.443,-2.349) Y13(8.732,-2.349) Y15(8.021,-2.349) Y16(7.309,-2.349) Y48(-7.309,-2.349) Y49(-8.021,-2.349) Y51(-8.732,-2.349) Y52(-9.443,-2.349) Y54(-10.154,-2.349) Y55(-10.866,-2.349) Y57(-11.577,-2.349) Y58(-12.288,-2.349) Y59(-12.999,-2.349)
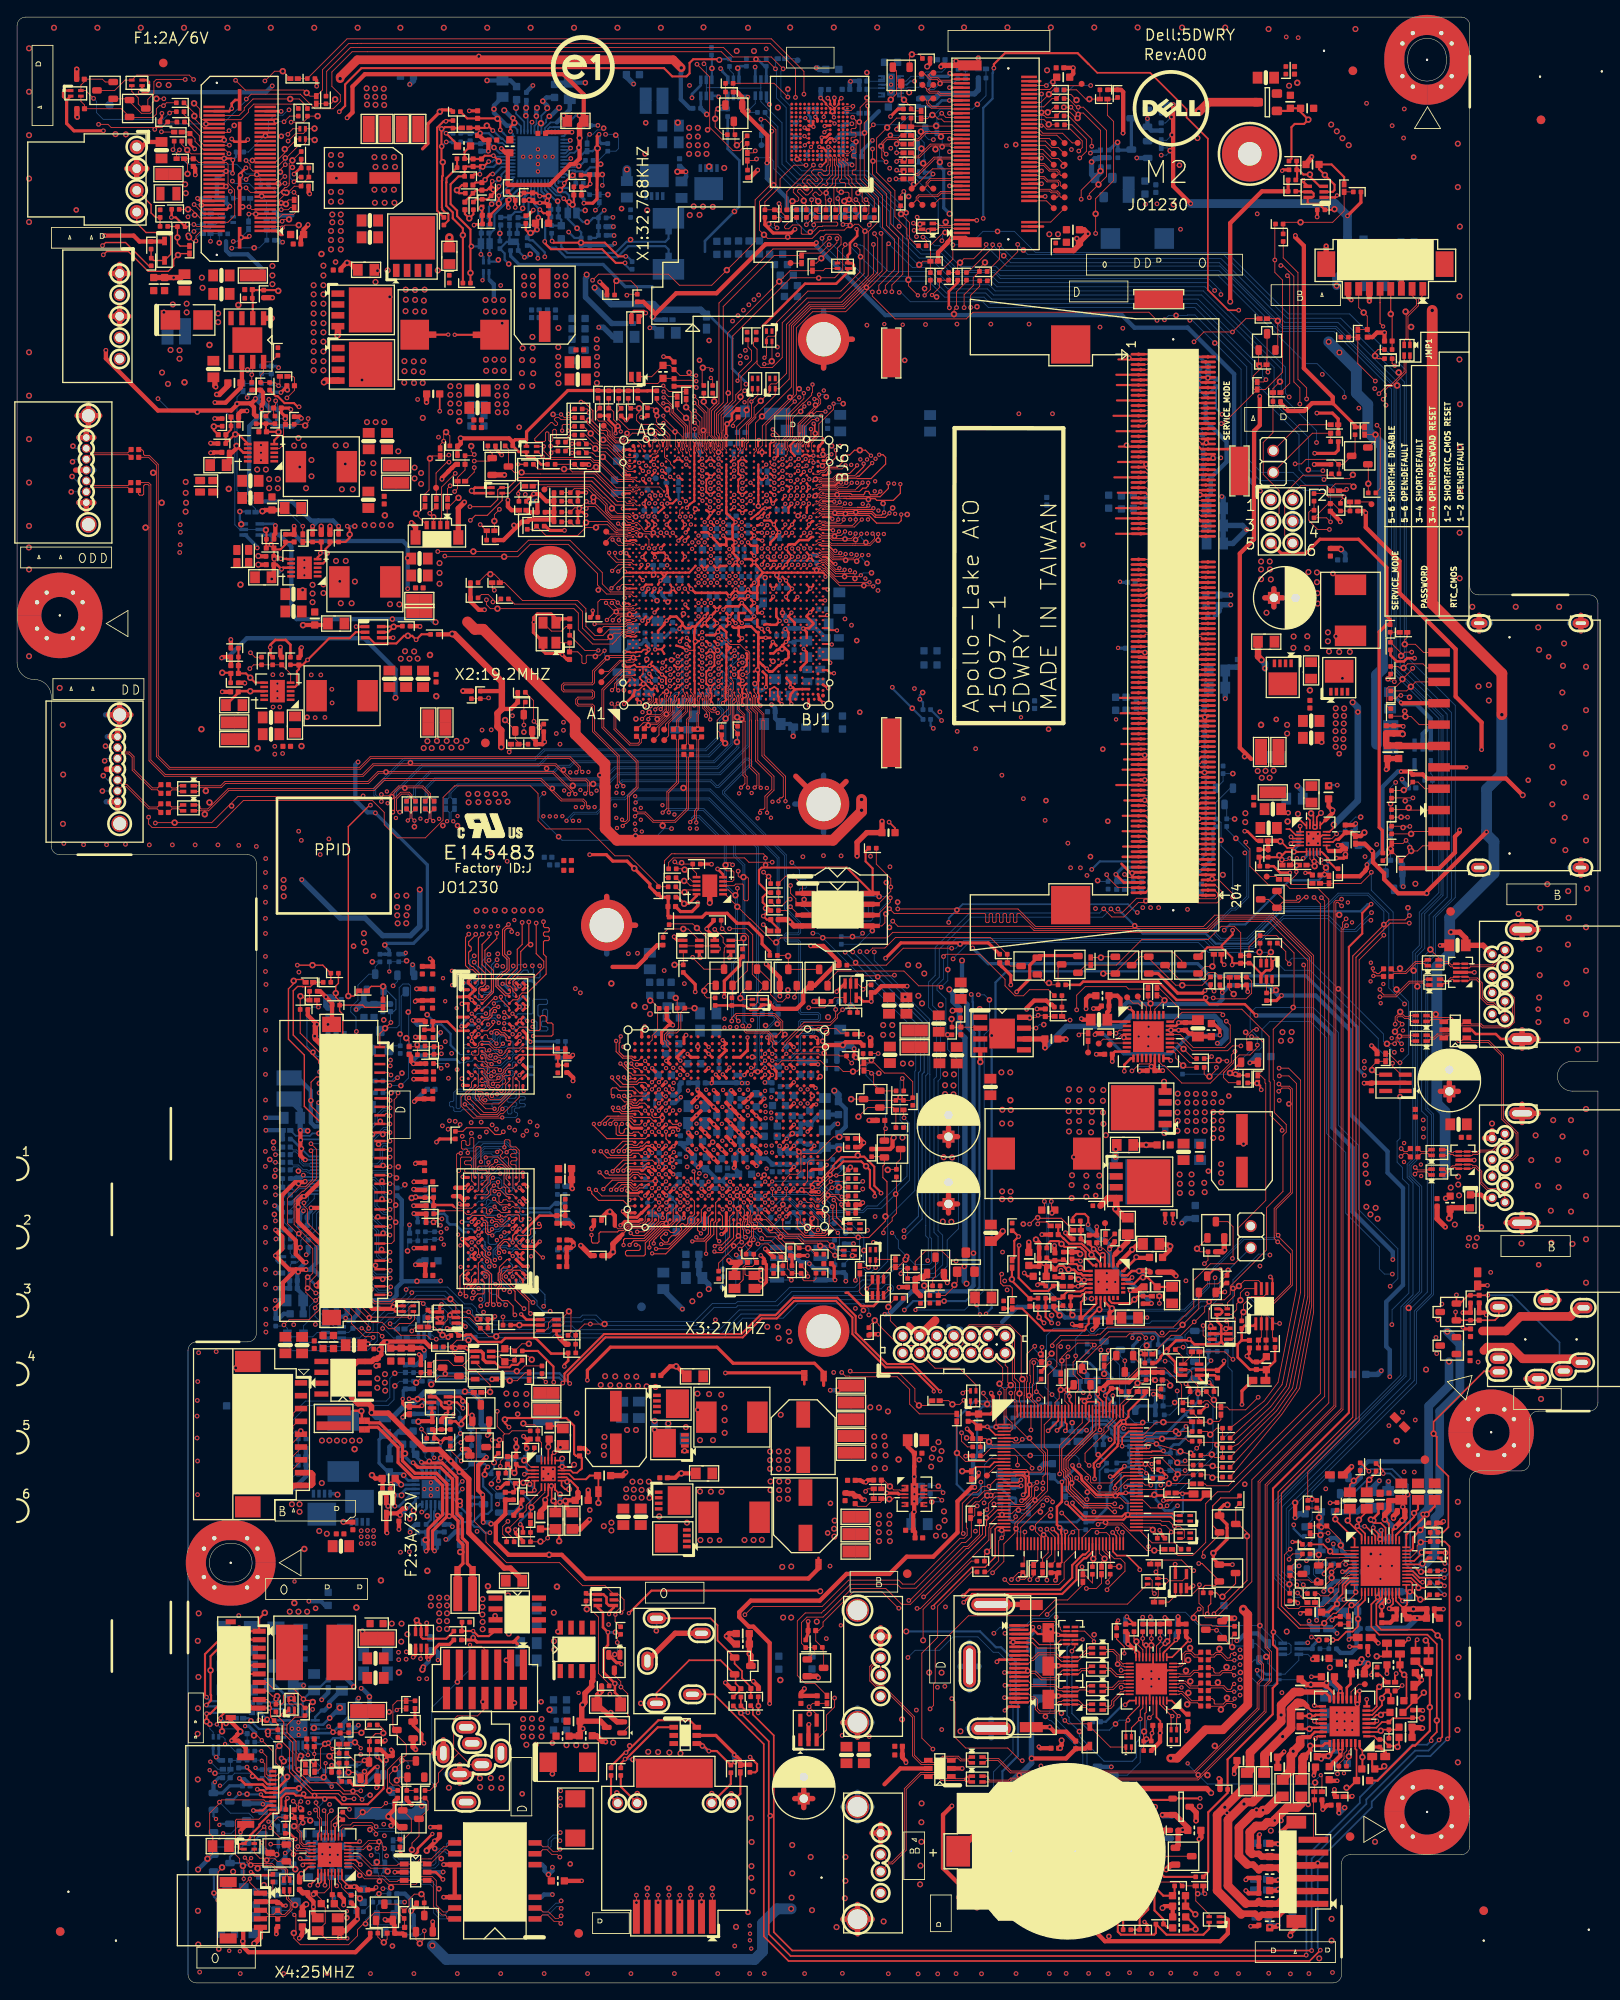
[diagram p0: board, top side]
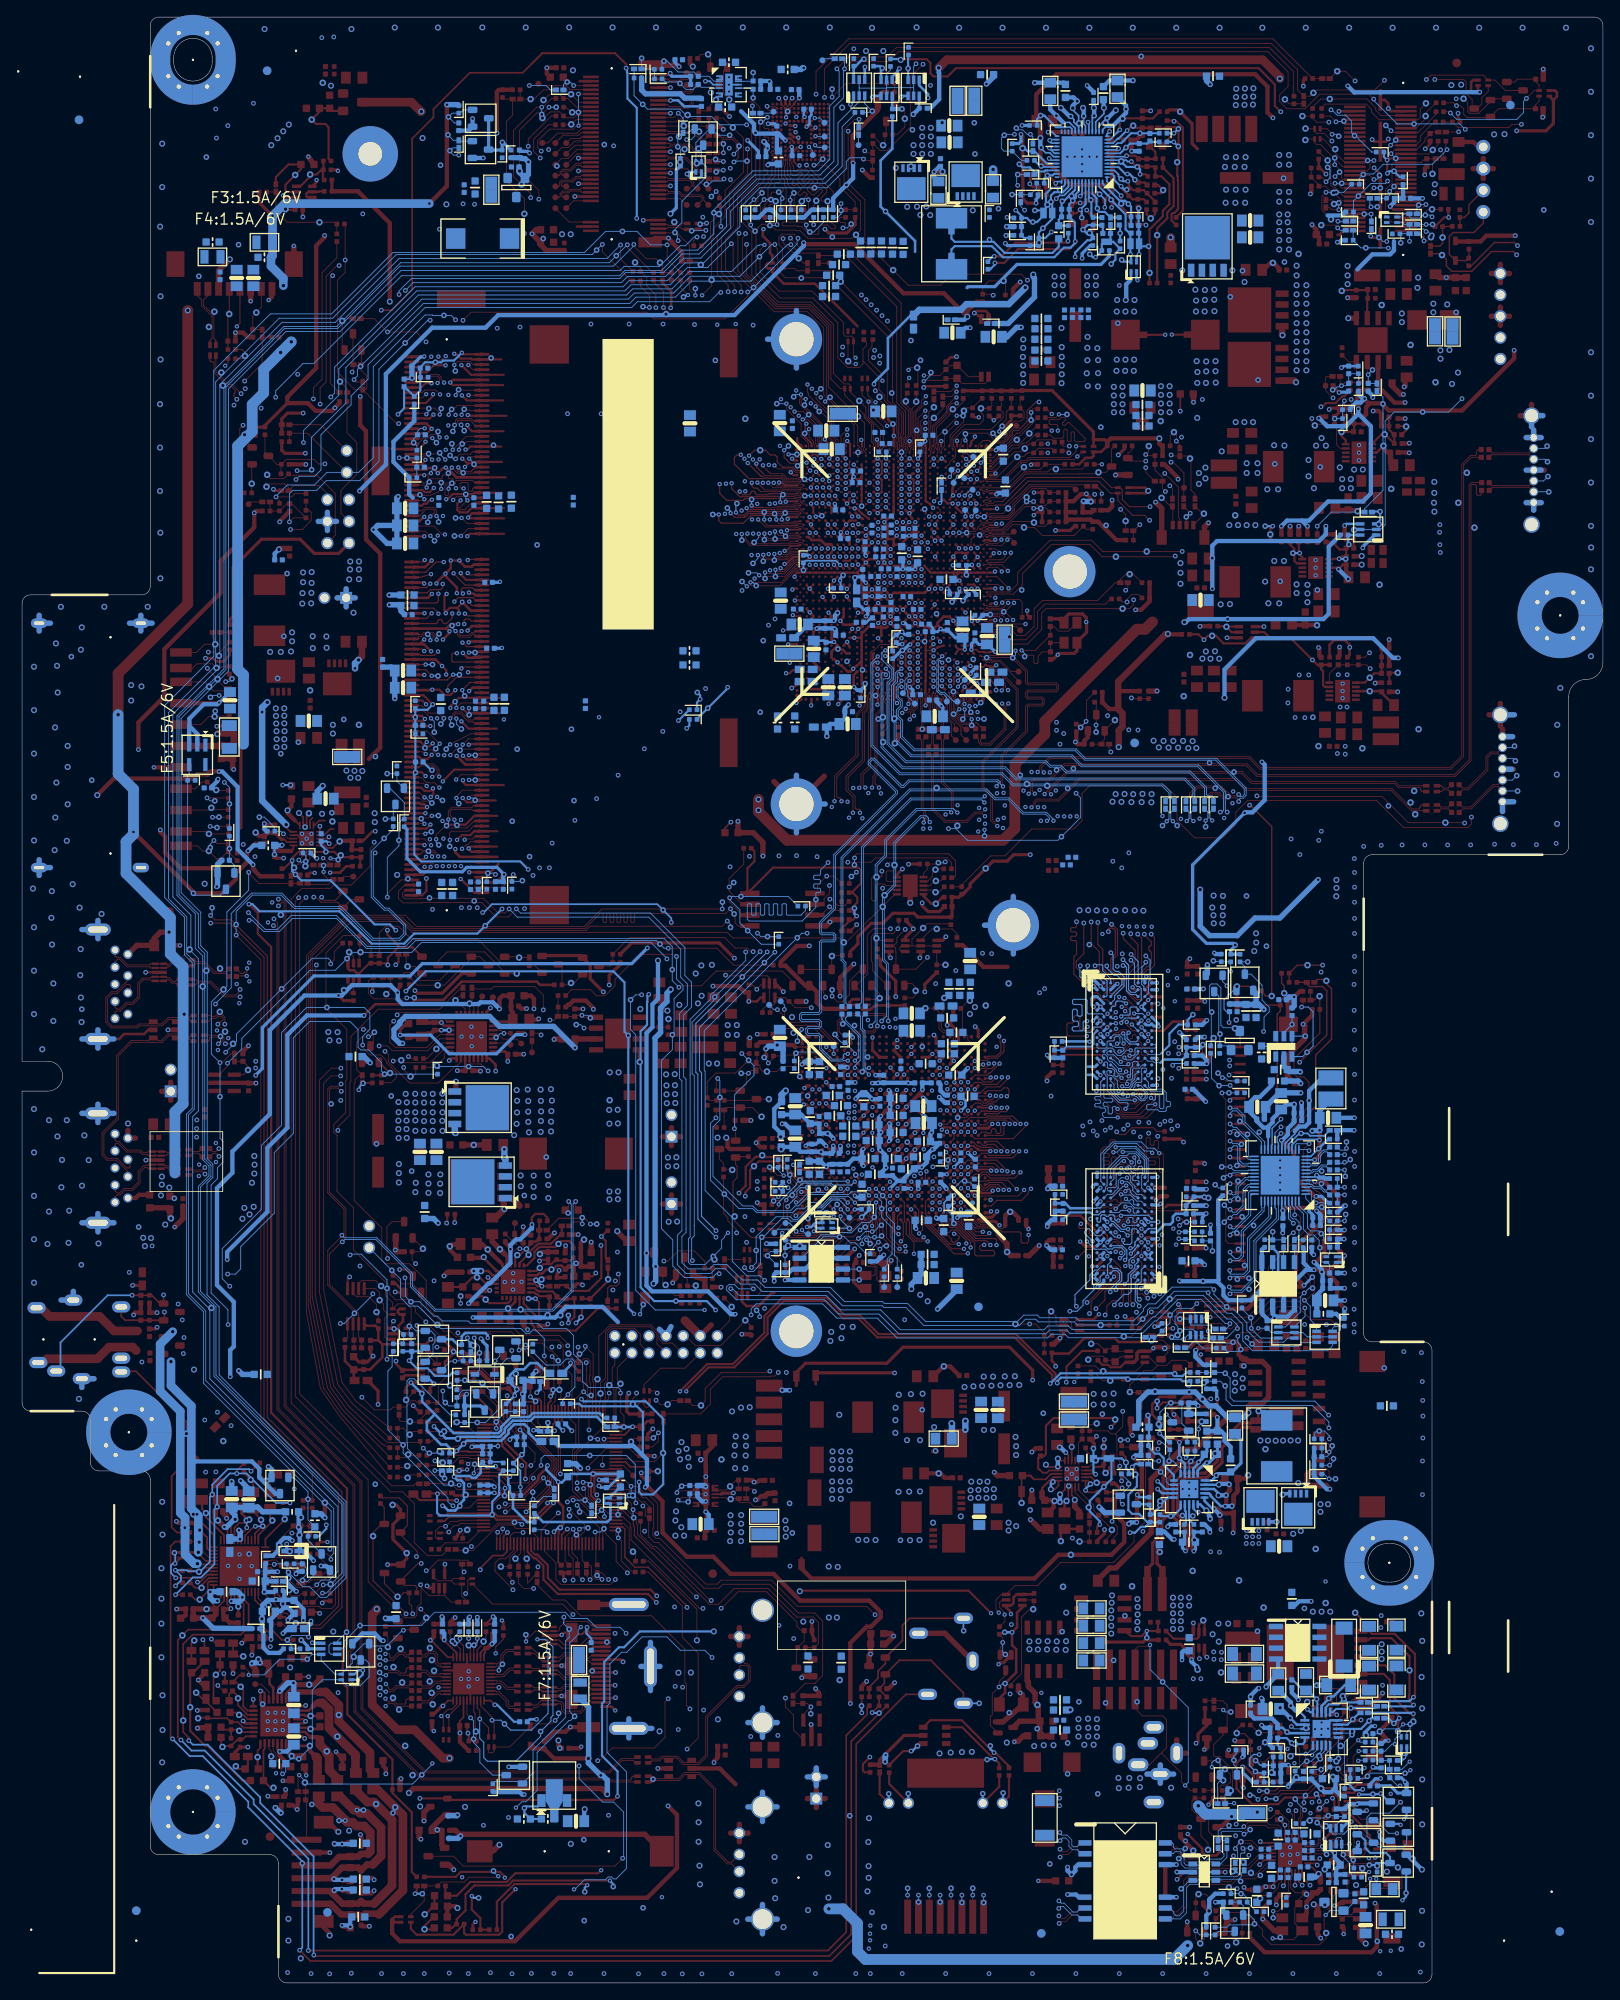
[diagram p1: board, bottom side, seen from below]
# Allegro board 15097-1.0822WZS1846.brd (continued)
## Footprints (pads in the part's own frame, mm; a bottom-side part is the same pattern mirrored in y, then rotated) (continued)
C402H22
  custom 0.152x0.152 smd: 1(0,0.445) 2(0,-0.445)
C603
  custom 0.216x0.216 smd: 1(0,0.762) 2(0,-0.762)
C603H35
  custom 0.216x0.216 smd: 1(0,0.762) 2(0,-0.762)
C603H36
  custom 0.216x0.216 smd: 1(0,0.762) 2(0,-0.762)
C603H38
  custom 0.216x0.216 smd: 1(0,0.762) 2(0,-0.762)
C603H40
  custom 0.216x0.216 smd: 1(0,0.762) 2(0,-0.762)
C805H50
  rect 1.397x1.143 smd: 1(0,0.965) 2(0,-0.965)
C805H54
  rect 1.397x1.143 smd: 1(0,0.965) 2(0,-0.965)
C805H58
  rect 1.397x1.143 smd: 1(0,0.965) 2(0,-0.965)
C1206H71
  rect 1.651x1.27 smd: 1(0,1.397) 2(0,-1.397)
C1206H75
  rect 1.651x1.27 smd: 1(0,1.397) 2(0,-1.397)
C1808H87
  rect 2.286x1.27 smd: 1(0,2.032) 2(0,-2.032)
CI1410M1HRL-NH
  rect 0.61x1.549 smd: 1(-4.5,3.325) 2(-3.5,3.325) 3(-2.5,3.325) 4(-1.5,3.325) 5(-0.5,3.325) 6(0.5,3.325) 7(1.5,3.325) 8(2.5,3.325) 9(3.5,3.325) 10(4.5,3.325)
  rect 0.61x1.194 smd: 11(-5.6,0) 12(5.6,0)
CI2505P1H00-LF-U
  round 1.422 hole 1.016: 1(-5,0) 2(-2.5,0) 3(0,0) 4(2.5,0) 5(5,0)
CT3528H79
  rect 2.286x2.286 smd: 1(0,1.905) 2(0,-1.905)
CT7343H75
  rect 2.413x2.286 smd: 1(0,3.15) 2(0,-3.15)
D4724AKH44
  rect 2.007x1.549 smd: A(0,2.221) K(0,-2.221)
D5436AKH97
  rect 2.286x2.032 smd: A(0,2.438) K(0,-2.438)
DFN10G3-G265175H32
  rect 0.305x0.914 smd: 1(1,1.549) 2(0.5,1.549) 3(0,1.549) 4(-0.5,1.549) 5(-1,1.549) 6(-1,-1.549) 7(-0.5,-1.549) 8(0,-1.549) 9(0.5,-1.549) 10(1,-1.549)
  rect 2.642x1.753 smd: 11(0,0)
DFN10G2510H26
  rect 0.305x0.787 smd: 1(1,0.494) 5(-1,0.494) 6(-1,-0.494) 10(1,-0.494)
  rect 0.254x0.787 smd: 2(0.521,0.494) 4(-0.521,0.494) 7(-0.521,-0.494) 9(0.521,-0.494)
  rect 0.025x0.025 smd: 3(0,0.494)
  rect 0.406x1.753 smd: 8(0,-0.494)
ECAP-100D6D3H237
  rect 1.397x1.397 hole 0.991: 1(0,-1.27)
  round 1.397 hole 0.991: 2(0,1.27)
ECAP-100D6D3H375
  rect 1.397x1.397 hole 0.991: 1(0,-1.27)
  round 1.397 hole 0.991: 2(0,1.27)
FUSE-1608H22
  custom 0.216x0.216 smd: 1(0,0.762) 2(0,-0.762)
FUSE-3216H28
  rect 1.778x1.27 smd: 1(0,-1.336) 2(0,1.336)
GAP-CLOSE-PWR
  rect 0.66x0.762 smd: 1(-0.305,0) 2(0.305,0)
GAP-CLOSE-PWR-3
  rect 0.66x0.762 smd: 1(-0.305,0) 2(0.305,0)
GEN8D5X8R5X4D5-8-F-A
  round 0.254 hole 5.004x4.521 unplated: (0,0)
  round 0.864 hole 0.508: 1(3.136,1.664) 2(1.918,2.882) 3(-1.918,2.882) 4(-3.136,1.664) 5(-3.136,-1.664) 6(-1.918,-2.882) 7(1.918,-2.882) 8(3.136,-1.664)
GEN315R138-8-F-A-1
  round 0.254 hole 3.505 unplated: (0,0)
  round 0.864 hole 0.508: 1(2.667,1.54) 2(1.54,2.667) 3(-1.54,2.667) 4(-2.667,1.54) 5(-2.667,-1.54) 6(-1.54,-2.667) 7(1.54,-2.667) 8(2.667,-1.54)
GEN315R138-8-F-A-2-S
  round 0.254 hole 3.505 unplated: (0,0)
  round 0.864 hole 0.508: 1(2.667,1.54) 2(1.54,2.667) 3(-1.54,2.667) 4(-2.667,1.54) 5(-2.667,-1.54) 6(-1.54,-2.667) 7(1.54,-2.667) 8(2.667,-1.54)
GEN315R178-8-F-A-1
  round 0.254 hole 4.521 unplated: (0,0)
  round 0.864 hole 0.508: 1(2.882,1.664) 2(1.664,2.882) 3(-1.664,2.882) 4(-2.882,1.664) 5(-2.882,-1.664) 6(-1.664,-2.882) 7(1.664,-2.882) 8(2.882,-1.664)
HF1804H
  round 1.651 hole 1.016: 1(-3.81,0) 2(-1.27,0) 3(1.27,0) 4(3.81,0)
HL5507F
  round 0.254 hole 1.016 unplated: (5,0)
  round 1.321 hole 0.914: 1(-6,-1) 2(-6,1) 3(-4,-1) 4(-4,1) 5(-2,-1) 6(-2,1) 7(0,-1) 8(0,1) 9(2,-1) 10(2,1) 11(4,-1) 12(4,1) 13(6,-1) 14(6,1)
HOLE237R158
  round 6.02 hole 4.013: 1(0,0)
JAC331-0140A8B-9H
  oval 1.321x2.235 hole 0.61x1.524: 1(-4.95,2.1) 4(5,2.1) P(3.25,-3.15) Q(-3.9,-2.1)
  oval 2.235x1.422 hole 1.524x0.711: 5(0,3.17)
L402H22
  custom 0.14x0.14 smd: 1(0,0.445) 2(0,-0.445)
L402H24
  custom 0.14x0.14 smd: 1(0,0.445) 2(0,-0.445)
L603H38
  custom 0.216x0.216 smd: 1(0,0.762) 2(0,-0.762)
L3030-2709H41
  rect 2.946x1.778 smd: 1(0,1.235) 2(0,-1.235)
L8080-6020H158
  rect 6.502x3.15 smd: 1(0,2.944) 2(0,-2.944)
L20125H42
  rect 1.397x1.143 smd: 1(0,0.965) 2(0,-0.965)
L112100-2230H158
  rect 3.505x3.353 smd: 1(0,4.67) 2(0,-4.67)
L115100-2H158
  rect 3.759x3.251 smd: 1(0,5.022) 2(0,-5.022)
L125100-4P-1H28
  rect 0.762x0.432 smd: 1(0.625,0.341) 2(-0.625,0.341) 3(-0.625,-0.341) 4(0.625,-0.341)
L125100-4P-1H36
  rect 0.762x0.432 smd: 1(0.625,0.341) 2(-0.625,0.341) 3(-0.625,-0.341) 4(0.625,-0.341)
L125100-4P-4H28
  rect 0.762x0.432 smd: 1(-0.625,0.341) 2(0.625,0.341) 3(0.625,-0.341) 4(-0.625,-0.341)
L686647-127318H119
  rect 3.683x2.413 smd: 1(0,2.986) 2(0,-2.986)
LED1608AKH30
  custom 0.216x0.216 smd: A(0,0.762) K(0,-0.762)
LFQFN24G4-G2D9H40
  rect 0.305x0.508 smd: 1(1.25,1.905) 2(0.75,1.905) 3(0.25,1.905) 4(-0.25,1.905) 5(-0.75,1.905) 6(-1.25,1.905) 13(-1.25,-1.905) 14(-0.75,-1.905) 15(-0.25,-1.905) 16(0.25,-1.905) 17(0.75,-1.905) 18(1.25,-1.905)
  rect 0.508x0.305 smd: 7(-1.905,1.25) 8(-1.905,0.75) 9(-1.905,0.25) 10(-1.905,-0.25) 11(-1.905,-0.75) 12(-1.905,-1.25) 19(1.905,-1.25) 20(1.905,-0.75) 21(1.905,-0.25) 22(1.905,0.25) 23(1.905,0.75) 24(1.905,1.25)
  rect 2.896x2.896 smd: 25(0,0)
LFQFN52J6-G4D8-1H40
  rect 0.203x0.533 smd: 1(2.4,2.911) 13(-2.4,2.911) 27(-2.4,-2.911) 39(2.4,-2.911)
  rect 0.203x0.584 smd: 2(2,2.911) 3(1.6,2.911) 4(1.2,2.911) 5(0.8,2.911) 6(0.4,2.911) 7(0,2.911) 8(-0.4,2.911) 9(-0.8,2.911) 10(-1.2,2.911) 11(-1.6,2.911) 12(-2,2.911) 28(-2,-2.911) 29(-1.6,-2.911) 30(-1.2,-2.911) 31(-0.8,-2.911) 32(-0.4,-2.911) 33(0,-2.911) 34(0.4,-2.911) 35(0.8,-2.911) 36(1.2,-2.911) 37(1.6,-2.911) 38(2,-2.911)
  rect 0.533x0.203 smd: 14(-2.911,2.4) 26(-2.911,-2.4) 40(2.911,-2.4) 52(2.911,2.4)
  rect 0.584x0.203 smd: 15(-2.911,2) 16(-2.911,1.6) 17(-2.911,1.2) 18(-2.911,0.8) 19(-2.911,0.4) 20(-2.911,0) 21(-2.911,-0.4) 22(-2.911,-0.8) 23(-2.911,-1.2) 24(-2.911,-1.6) 25(-2.911,-2) 41(2.911,-2) 42(2.911,-1.6) 43(2.911,-1.2) 44(2.911,-0.8) 45(2.911,-0.4) 46(2.911,0) 47(2.911,0.4) 48(2.911,0.8) 49(2.911,1.2) 50(2.911,1.6) 51(2.911,2)
  rect 4.801x4.801 smd: 53(0,0)
LQFP128H63
  rect 0.203x1.524 smd: 1(6.2,7.747) 2(5.8,7.747) 3(5.4,7.747) 4(5,7.747) 5(4.6,7.747) 6(4.2,7.747) 7(3.8,7.747) 8(3.4,7.747) 9(3,7.747) 10(2.6,7.747) 11(2.2,7.747) 12(1.8,7.747) 13(1.4,7.747) 14(0.999,7.747) 15(0.599,7.747) 16(0.199,7.747) 17(-0.199,7.747) 18(-0.599,7.747) 19(-0.999,7.747) 20(-1.4,7.747) 21(-1.8,7.747) 22(-2.2,7.747) 23(-2.6,7.747) 24(-3,7.747) 25(-3.4,7.747) 26(-3.8,7.747) 27(-4.2,7.747) 28(-4.6,7.747) 29(-5,7.747) 30(-5.4,7.747) 31(-5.8,7.747) 32(-6.2,7.747) 65(-6.2,-7.747) 66(-5.8,-7.747) 67(-5.4,-7.747) 68(-5,-7.747) 69(-4.6,-7.747) 70(-4.2,-7.747) 71(-3.8,-7.747) 72(-3.4,-7.747) 73(-3,-7.747) 74(-2.6,-7.747) 75(-2.2,-7.747) 76(-1.8,-7.747) 77(-1.4,-7.747) 78(-0.999,-7.747) 79(-0.599,-7.747) 80(-0.199,-7.747) 81(0.199,-7.747) 82(0.599,-7.747) 83(0.999,-7.747) 84(1.4,-7.747) 85(1.8,-7.747) 86(2.2,-7.747) 87(2.6,-7.747) 88(3,-7.747) 89(3.4,-7.747) 90(3.8,-7.747) 91(4.2,-7.747) 92(4.6,-7.747) 93(5,-7.747) 94(5.4,-7.747) 95(5.8,-7.747) 96(6.2,-7.747)
  rect 1.524x0.203 smd: 33(-7.747,6.2) 34(-7.747,5.8) 35(-7.747,5.4) 36(-7.747,5) 37(-7.747,4.6) 38(-7.747,4.2) 39(-7.747,3.8) 40(-7.747,3.4) 41(-7.747,3) 42(-7.747,2.6) 43(-7.747,2.2) 44(-7.747,1.8) 45(-7.747,1.4) 46(-7.747,0.999) 47(-7.747,0.599) 48(-7.747,0.199) 49(-7.747,-0.199) 50(-7.747,-0.599) 51(-7.747,-0.999) 52(-7.747,-1.4) 53(-7.747,-1.8) 54(-7.747,-2.2) 55(-7.747,-2.6) 56(-7.747,-3) 57(-7.747,-3.4) 58(-7.747,-3.8) 59(-7.747,-4.2) 60(-7.747,-4.6) 61(-7.747,-5) 62(-7.747,-5.4) 63(-7.747,-5.8) 64(-7.747,-6.2) 97(7.747,-6.2) 98(7.747,-5.8) 99(7.747,-5.4) 100(7.747,-5) 101(7.747,-4.6) 102(7.747,-4.2) 103(7.747,-3.8) 104(7.747,-3.4) 105(7.747,-3) 106(7.747,-2.6) 107(7.747,-2.2) 108(7.747,-1.8) 109(7.747,-1.4) 110(7.747,-0.999) 111(7.747,-0.599) 112(7.747,-0.199) 113(7.747,0.199) 114(7.747,0.599) 115(7.747,0.999) 116(7.747,1.4) 117(7.747,1.8) 118(7.747,2.2) 119(7.747,2.6) 120(7.747,3) 121(7.747,3.4) 122(7.747,3.8) 123(7.747,4.2) 124(7.747,4.6) 125(7.747,5) 126(7.747,5.4) 127(7.747,5.8) 128(7.747,6.2)
LVDFH-02004-TP00
  rect 0.305x1.295 smd: 1(-4.75,-1.95) 2(-4.25,-1.95) 3(-3.75,-1.95) 4(-3.25,-1.95) 5(-2.75,-1.95) 6(-2.25,-1.95) 7(-1.75,-1.95) 8(-1.25,-1.95) 9(-0.75,-1.95) 10(-0.25,-1.95) 11(0.25,-1.95) 12(0.75,-1.95) 13(1.25,-1.95) 14(1.75,-1.95) 15(2.25,-1.95) 16(2.75,-1.95) 17(3.25,-1.95) 18(3.75,-1.95) 19(4.25,-1.95) 20(4.75,-1.95)
  rect 1.194x2.692 smd: 21(-7.15,0) 22(7.15,0)
  rect 2.261x1.346 smd: 23(3.9,1.975) 24(0,1.975) 25(-3.9,1.975)
MSOP8-1H44
  rect 0.356x1.524 smd: 1(-0.975,-2.055) 2(-0.325,-2.055) 3(0.325,-2.055) 4(0.975,-2.055) 5(0.975,2.055) 6(0.325,2.055) 7(-0.325,2.055) 8(-0.975,2.055)
NTC-402H22-U
  custom 0.14x0.14 smd: 1(0,0.445) 2(0,-0.445)
NTC-402H24-U
  custom 0.14x0.14 smd: 1(0,0.445) 2(0,-0.445)
NTC-603H38
  custom 0.216x0.216 smd: 1(0,0.762) 2(0,-0.762)
OSC-3225-4P-4H30
  rect 1.397x1.067 smd: 1(-1.171,-0.756) 2(1.171,-0.756) 3(1.171,0.756) 4(-1.171,0.756)
OSC-3225-4P-4H32
  rect 1.397x1.067 smd: 1(-1.171,-0.756) 2(1.171,-0.756) 3(1.171,0.756) 4(-1.171,0.756)
OSC-3225-4P-4H36
  rect 1.397x1.067 smd: 1(-1.171,-0.756) 2(1.171,-0.756) 3(1.171,0.756) 4(-1.171,0.756)
POLYSW-2114H30
  rect 1.6x0.965 smd: 1(0,0.94) 2(0,-0.94)
PPAK-8P-3232H36
  rect 0.406x0.914 smd: 1(-0.975,-2.396) 2(-0.325,-2.396) 3(0.325,-2.396) 4(0.975,-2.396)
  rect 3.353x2.692 smd: 5(0,0)
  rect 0.025x0.025 smd: 6(0.65,0.838) 7(0,0.838) 8(-0.65,0.838)
PTDS08-1H44
  rect 0.762x1.524 smd: 1(-1.905,-3.81) 2(-0.635,-3.81) 3(0.635,-3.81) 4(1.905,-3.81)
  rect 5.283x5.08 smd: 5(0,0)
  rect 0.025x0.025 smd: 6(0.635,2.032) 7(-0.635,2.032) 8(-1.905,2.032)
QFN20-G1D75H32
  rect 0.203x0.914 smd: 1(0.8,1.551) 2(0.4,1.551) 3(0,1.551) 4(-0.4,1.551) 5(-0.8,1.551) 11(-0.8,-1.551) 12(-0.4,-1.551) 13(0,-1.551) 14(0.4,-1.551) 15(0.8,-1.551)
  rect 0.914x0.203 smd: 6(-1.551,0.8) 7(-1.551,0.4) 8(-1.551,0) 9(-1.551,-0.4) 10(-1.551,-0.8) 16(1.551,-0.8) 17(1.551,-0.4) 18(1.551,0) 19(1.551,0.4) 20(1.551,0.8)
  rect 1.753x1.753 smd: 21(0,0)
QFN20-G2D1H32
  rect 0.305x1.092 smd: 1(0.999,1.956) 5(-0.999,1.956) 11(-0.999,-1.956) 15(0.999,-1.956)
  rect 0.305x1.143 smd: 2(0.5,1.93) 3(0,1.93) 4(-0.5,1.93) 12(-0.5,-1.93) 13(0,-1.93) 14(0.5,-1.93)
  rect 1.092x0.305 smd: 6(-1.956,0.999) 10(-1.956,-0.999) 16(1.956,-0.999) 20(1.956,0.999)
  rect 1.143x0.305 smd: 7(-1.93,0.5) 8(-1.93,0) 9(-1.93,-0.5) 17(1.93,-0.5) 18(1.93,0) 19(1.93,0.5)
  rect 2.108x2.108 smd: 21(0,0)
QFN20G3D5-G2D15H40
  rect 0.305x0.914 smd: 1(1,1.801) 5(-1,1.801) 11(-1,-1.801) 15(1,-1.801)
  rect 0.305x0.965 smd: 2(0.5,1.775) 3(0,1.775) 4(-0.5,1.775) 12(-0.5,-1.775) 13(0,-1.775) 14(0.5,-1.775)
  rect 0.914x0.305 smd: 6(-1.801,1) 10(-1.801,-1) 16(1.801,-1) 20(1.801,1)
  rect 0.965x0.305 smd: 7(-1.775,0.5) 8(-1.775,0) 9(-1.775,-0.5) 17(1.775,-0.5) 18(1.775,0) 19(1.775,0.5)
  rect 2.159x2.159 smd: 21(0,0)
QFN32-G3D55H40
  rect 0.305x0.838 smd: 1(1.75,2.591) 8(-1.75,2.591) 17(-1.75,-2.591) 24(1.75,-2.591)
  rect 0.305x0.94 smd: 2(1.25,2.54) 3(0.751,2.54) 4(0.25,2.54) 5(-0.25,2.54) 6(-0.751,2.54) 7(-1.25,2.54) 18(-1.25,-2.54) 19(-0.751,-2.54) 20(-0.25,-2.54) 21(0.25,-2.54) 22(0.751,-2.54) 23(1.25,-2.54)
  rect 0.838x0.305 smd: 9(-2.591,1.75) 16(-2.591,-1.75) 25(2.591,-1.75) 32(2.591,1.75)
  rect 0.94x0.305 smd: 10(-2.54,1.25) 11(-2.54,0.751) 12(-2.54,0.25) 13(-2.54,-0.25) 14(-2.54,-0.751) 15(-2.54,-1.25) 26(2.54,-1.25) 27(2.54,-0.751) 28(2.54,-0.25) 29(2.54,0.25) 30(2.54,0.751) 31(2.54,1.25)
  rect 3.531x3.531 smd: 33(0,0)
QFN32G5-G3D6H32
  rect 0.305x0.914 smd: 1(1.75,2.551) 8(-1.75,2.551) 17(-1.75,-2.551) 24(1.75,-2.551)
  rect 0.305x0.991 smd: 2(1.25,2.513) 3(0.75,2.513) 4(0.25,2.513) 5(-0.25,2.513) 6(-0.75,2.513) 7(-1.25,2.513) 18(-1.25,-2.513) 19(-0.75,-2.513) 20(-0.25,-2.513) 21(0.25,-2.513) 22(0.75,-2.513) 23(1.25,-2.513)
  rect 0.914x0.305 smd: 9(-2.551,1.75) 16(-2.551,-1.75) 25(2.551,-1.75) 32(2.551,1.75)
  rect 0.991x0.305 smd: 10(-2.513,1.25) 11(-2.513,0.75) 12(-2.513,0.25) 13(-2.513,-0.25) 14(-2.513,-0.75) 15(-2.513,-1.25) 26(2.513,-1.25) 27(2.513,-0.75) 28(2.513,-0.25) 29(2.513,0.25) 30(2.513,0.75) 31(2.513,1.25)
  rect 3.607x3.607 smd: 33(0,0)
QFN32J4-G2D85H36
  rect 0.203x0.864 smd: 1(1.4,2.085) 2(1,2.085) 3(0.6,2.085) 4(0.2,2.085) 5(-0.2,2.085) 6(-0.6,2.085) 7(-1,2.085) 8(-1.4,2.085) 17(-1.4,-2.085) 18(-1,-2.085) 19(-0.6,-2.085) 20(-0.2,-2.085) 21(0.2,-2.085) 22(0.6,-2.085) 23(1,-2.085) 24(1.4,-2.085)
  rect 0.864x0.203 smd: 9(-2.085,1.4) 10(-2.085,1) 11(-2.085,0.6) 12(-2.085,0.2) 13(-2.085,-0.2) 14(-2.085,-0.6) 15(-2.085,-1) 16(-2.085,-1.4) 25(2.085,-1.4) 26(2.085,-1) 27(2.085,-0.6) 28(2.085,-0.2) 29(2.085,0.2) 30(2.085,0.6) 31(2.085,1) 32(2.085,1.4)
  rect 2.845x2.845 smd: 33(0,0)
QFN40J5-G3D65H32
  rect 0.203x0.94 smd: 1(1.8,2.538) 10(-1.8,2.538) 21(-1.8,-2.538) 30(1.8,-2.538)
  rect 0.203x0.965 smd: 2(1.4,2.526) 3(1,2.526) 4(0.6,2.526) 5(0.2,2.526) 6(-0.2,2.526) 7(-0.6,2.526) 8(-1,2.526) 9(-1.4,2.526) 22(-1.4,-2.526) 23(-1,-2.526) 24(-0.6,-2.526) 25(-0.2,-2.526) 26(0.2,-2.526) 27(0.6,-2.526) 28(1,-2.526) 29(1.4,-2.526)
  rect 0.94x0.203 smd: 11(-2.538,1.8) 20(-2.538,-1.8) 31(2.538,-1.8) 40(2.538,1.8)
  rect 0.965x0.203 smd: 12(-2.526,1.4) 13(-2.526,1) 14(-2.526,0.6) 15(-2.526,0.2) 16(-2.526,-0.2) 17(-2.526,-0.6) 18(-2.526,-1) 19(-2.526,-1.4) 32(2.526,-1.4) 33(2.526,-1) 34(2.526,-0.6) 35(2.526,-0.2) 36(2.526,0.2) 37(2.526,0.6) 38(2.526,1) 39(2.526,1.4)
  rect 3.658x3.658 smd: 41(0,0)
QFN48J6-G4D55H40
  rect 0.203x1.016 smd: 1(2.2,3) 2(1.8,3) 3(1.4,3) 4(1,3) 5(0.6,3) 6(0.2,3) 7(-0.2,3) 8(-0.6,3) 9(-1,3) 10(-1.4,3) 11(-1.8,3) 12(-2.2,3) 25(-2.2,-3) 26(-1.8,-3) 27(-1.4,-3) 28(-1,-3) 29(-0.6,-3) 30(-0.2,-3) 31(0.2,-3) 32(0.6,-3) 33(1,-3) 34(1.4,-3) 35(1.8,-3) 36(2.2,-3)
  rect 1.016x0.203 smd: 13(-3,2.2) 14(-3,1.8) 15(-3,1.4) 16(-3,1) 17(-3,0.6) 18(-3,0.2) 19(-3,-0.2) 20(-3,-0.6) 21(-3,-1) 22(-3,-1.4) 23(-3,-1.8) 24(-3,-2.2) 37(3,-2.2) 38(3,-1.8) 39(3,-1.4) 40(3,-1) 41(3,-0.6) 42(3,-0.2) 43(3,0.2) 44(3,0.6) 45(3,1) 46(3,1.4) 47(3,1.8) 48(3,2.2)
  rect 4.547x4.547 smd: 49(0,0)
QFN48J6-G465H40
  rect 0.203x0.965 smd: 1(2.2,3.025) 2(1.8,3.025) 3(1.4,3.025) 4(1,3.025) 5(0.6,3.025) 6(0.2,3.025) 7(-0.2,3.025) 8(-0.6,3.025) 9(-1,3.025) 10(-1.4,3.025) 11(-1.8,3.025) 12(-2.2,3.025) 25(-2.2,-3.025) 26(-1.8,-3.025) 27(-1.4,-3.025) 28(-1,-3.025) 29(-0.6,-3.025) 30(-0.2,-3.025) 31(0.2,-3.025) 32(0.6,-3.025) 33(1,-3.025) 34(1.4,-3.025) 35(1.8,-3.025) 36(2.2,-3.025)
  rect 0.965x0.203 smd: 13(-3.025,2.2) 14(-3.025,1.8) 15(-3.025,1.4) 16(-3.025,1) 17(-3.025,0.6) 18(-3.025,0.2) 19(-3.025,-0.2) 20(-3.025,-0.6) 21(-3.025,-1) 22(-3.025,-1.4) 23(-3.025,-1.8) 24(-3.025,-2.2) 37(3.025,-2.2) 38(3.025,-1.8) 39(3.025,-1.4) 40(3.025,-1) 41(3.025,-0.6) 42(3.025,-0.2) 43(3.025,0.2) 44(3.025,0.6) 45(3.025,1) 46(3.025,1.4) 47(3.025,1.8) 48(3.025,2.2)
  rect 4.648x4.648 smd: 49(0,0)
QSH-030-01-FDAK
  round 0.254 hole 1.016 unplated: (-10.066,2.67) (10.066,2.67)
  rect 0.305x2.515 smd: 1(-7.25,-2.99) 2(-7.25,2.99) 3(-6.75,-2.99) 4(-6.75,2.99) 5(-6.25,-2.99) 6(-6.25,2.99) 7(-5.751,-2.99) 8(-5.751,2.99) 9(-5.25,-2.99) 10(-5.25,2.99) 11(-4.75,-2.99) 12(-4.75,2.99) 13(-4.249,-2.99) 14(-4.249,2.99) 15(-3.75,-2.99) 16(-3.75,2.99) 17(-3.25,-2.99) 18(-3.25,2.99) 19(-2.75,-2.99) 20(-2.75,2.99) 21(-2.25,-2.99) 22(-2.25,2.99) 23(-1.75,-2.99) 24(-1.75,2.99) 25(-1.25,-2.99) 26(-1.25,2.99) 27(-0.751,-2.99) 28(-0.751,2.99) 29(-0.25,-2.99) 30(-0.25,2.99) 31(0.25,-2.99) 32(0.25,2.99) 33(0.751,-2.99) 34(0.751,2.99) 35(1.25,-2.99) 36(1.25,2.99) 37(1.75,-2.99) 38(1.75,2.99) 39(2.25,-2.99) 40(2.25,2.99) 41(2.75,-2.99) 42(2.75,2.99) 43(3.25,-2.99) 44(3.25,2.99) 45(3.75,-2.99) 46(3.75,2.99) 47(4.249,-2.99) 48(4.249,2.99) 49(4.75,-2.99) 50(4.75,2.99) 51(5.25,-2.99) 52(5.25,2.99) 53(5.751,-2.99) 54(5.751,2.99) 55(6.25,-2.99) 56(6.25,2.99) 57(6.75,-2.99) 58(6.75,2.99) 59(7.25,-2.99) 60(7.25,2.99)
  rect 2.54x0.432 smd: 61(-8.065,0) 64(8.065,0)
  rect 4.699x0.432 smd: 62(-3.175,0) 63(3.175,0)
R402
  custom 0.14x0.14 smd: 1(0,0.445) 2(0,-0.445)
R402H14
  custom 0.14x0.14 smd: 1(0,0.445) 2(0,-0.445)
R402H15
  custom 0.14x0.14 smd: 1(0,0.445) 2(0,-0.445)
R402H16
  custom 0.14x0.14 smd: 1(0,0.445) 2(0,-0.445)
R603H22
  custom 0.216x0.216 smd: 1(0,0.762) 2(0,-0.762)
R805H24
  rect 1.397x1.143 smd: 1(0,0.965) 2(0,-0.965)
R1206H26
  rect 1.651x1.27 smd: 1(0,1.397) 2(0,-1.397)
R1206H28
  rect 1.651x1.27 smd: 1(0,1.397) 2(0,-1.397)
R3720H40
  rect 4.013x1.041 smd: 1(0,0.867) 2(0,-0.867)
SC70-5H44
  rect 0.406x1.219 smd: 1(0.65,0.826) 2(0,0.826) 3(-0.65,0.826) 4(-0.65,-0.826) 5(0.65,-0.826)
SC70-6H44
  rect 0.406x1.016 smd: 1(-0.65,-0.94) 2(0,-0.94) 3(0.65,-0.94) 4(0.65,0.94) 5(0,0.94) 6(-0.65,0.94)
SE3116H241
  rect 1.626x3.099 smd: 1(0,2.654) 2(0,-2.654)
SE361414H241
  rect 1.372x3.607 smd: 1(0,2.499) 2(0,-2.499)
SKT-HDMI22-150077
  rect 0.305x2.007 smd: 1(4.21,3.37) 2(3.71,3.37) 3(3.21,3.37) 4(2.71,3.37) 5(2.21,3.37) 6(1.71,3.37) 7(1.21,3.37) 8(0.71,3.37) 9(0.21,3.37) 10(-0.29,3.37) 11(-0.79,3.37) 12(-1.29,3.37) 13(-1.79,3.37) 14(-2.29,3.37) 15(-2.79,3.37) 16(-3.29,3.37) 17(-3.79,3.37) 18(-4.29,3.37) 19(-4.79,3.37)
  oval 4.928x1.524 hole 4.216x0.813: 20(0,-2.53)
  oval 1.524x4.674 hole 0.813x3.962: 21(-7.25,0) 22(7.25,0)
SKT-SOIC8-092117H235
  rect 0.508x1.702 smd: 1(1.905,4.1) 2(0.635,4.1) 3(-0.635,4.1) 4(-1.905,4.1) 5(-1.905,-4.1) 6(-0.635,-4.1) 7(0.635,-4.1) 8(1.905,-4.1)
SKT-USB6-135063
  round 1.346 hole 0.94: 1(3.5,-2.71) 2(1,-2.71) 3(-1,-2.71) 4(-3.5,-2.71)
  round 2.718 hole 2.311: 5(6.57,0) 6(-6.57,0)
SKT-USB11-138165-1
  round 1.067 hole 0.711: 1(3.5,3.5) 2(1,3.5) 3(-1,3.5) 4(-3.5,3.5) 5(-4,2) 6(-2,2) 7(0,2) 8(2,2) 9(4,2)
  oval 1.422x3.023 hole 0.711x2.311: 10(-6.4,0) 11(6.4,0)
SMD49-6914-0403H56
  rect 1.168x0.559 smd: 1(-3.38,-0.427) 2(3.38,-0.427) 3(3.38,0.427) 4(-3.38,0.427)
SMD-ARES4
  rect 0.356x0.66 smd: 1(-0.325,-0.599) 2(0.325,-0.599) 3(0.325,0.599) 4(-0.325,0.599)
SMD-ARES4H18
  rect 0.356x0.66 smd: 1(-0.325,-0.599) 2(0.325,-0.599) 3(0.325,0.599) 4(-0.325,0.599)
SMD-ARES4H20
  rect 0.356x0.66 smd: 1(-0.325,-0.599) 2(0.325,-0.599) 3(0.325,0.599) 4(-0.325,0.599)
SOD323AKH38
  rect 0.559x1.016 smd: A(0,1.143) K(0,-1.143)
SOD323AKH42
  rect 0.559x1.016 smd: A(0,1.143) K(0,-1.143)
SOD523AKH28
  rect 0.559x1.016 smd: A(0,0.762) K(0,-0.762)
SOIC8-1H86
  rect 0.635x1.651 smd: 1(-1.905,-3.493) 2(-0.635,-3.493) 3(0.635,-3.493) 4(1.905,-3.493) 5(1.905,3.493) 6(0.635,3.493) 7(-0.635,3.493) 8(-1.905,3.493)
SOIC8-G3530H63
  rect 0.635x1.651 smd: 1(-1.905,-2.555) 2(-0.635,-2.555) 3(0.635,-2.555) 4(1.905,-2.555) 5(1.905,2.555) 6(0.635,2.555) 7(-0.635,2.555) 8(-1.905,2.555)
  rect 3.505x2.997 smd: 9(0,0)
SOIC8H69
  rect 0.635x1.651 smd: 1(-1.905,-2.54) 2(-0.635,-2.54) 3(0.635,-2.54) 4(1.905,-2.54) 5(1.905,2.54) 6(0.635,2.54) 7(-0.635,2.54) 8(-1.905,2.54)
SON14J3020-G2610H34
  rect 0.025x0.025 smd: 1(1.2,1.105) 6(-0.8,1.105) 9(-0.8,-1.105) 14(1.2,-1.105)
  custom 0.151x0.151 smd: 2(0.8,1.105) 7(-1.2,1.105) 8(-1.2,-1.105) 13(0.8,-1.105)
  rect 0.203x0.813 smd: 3(0.4,1.105) 4(0,1.105) 5(-0.4,1.105) 10(-0.4,-1.105) 11(0,-1.105) 12(0.4,-1.105)
  rect 2.591x0.889 smd: 15(0,0)
SOT23-2D4-312H46
  custom 0.191x0.191 smd: 1(-0.984,-0.953) 2(0.984,-0.953) 3(0,0.953)
SOT23-2D4-312H48
  custom 0.191x0.191 smd: 1(-0.984,-0.953) 2(0.984,-0.953) 3(0,0.953)
SOT23CBE2D4H44
  custom 0.191x0.191 smd: B(-0.984,-0.953) C(0,0.953) E(0.984,-0.953)
SOT23DGS2D4H44
  custom 0.191x0.191 smd: D(0,0.953) G(-0.984,-0.953) S(0.984,-0.953)
SOT23DGS2D4H48
  custom 0.191x0.191 smd: D(0,0.953) G(-0.984,-0.953) S(0.984,-0.953)
SOT23DGS2D8H50
  custom 0.254x0.254 smd: D(0,1.118) G(-1.016,-1.118) S(1.016,-1.118)
SOT323CBE2D2H40
  custom 0.152x0.152 smd: B(-0.65,-0.902) C(0,0.902) E(0.65,-0.902)
SOT323CBE2D2H44
  custom 0.152x0.152 smd: B(-0.65,-0.902) C(0,0.902) E(0.65,-0.902)
SOT-6-1H58
  rect 0.584x1.219 smd: 1(-0.95,-1.194) 2(0,-1.194) 3(0.95,-1.194) 4(0.95,1.194) 5(0,1.194) 6(-0.95,1.194)
SOT-6H58
  rect 0.584x1.016 smd: 1(-0.953,-1.346) 2(0,-1.346) 3(0.953,-1.346) 4(0.953,1.346) 5(0,1.346) 6(-0.953,1.346)
SOT-23-5H58
  rect 0.508x1.524 smd: 1(-0.95,-1.143) 2(0,-1.143) 3(0.95,-1.143) 4(0.95,1.143) 5(-0.95,1.143)
SOT-23-9H44
  custom 0.178x0.178 smd: 1(-0.95,-0.999) 2(0.95,-0.999) 3(0,0.999)
SOT-89-4541-3PH63
  rect 0.991x1.499 smd: 1(-1.5,0) 3(1.5,0)
  custom 0.502x0.502 smd: 2(0,0)
SOT-363H44
  rect 0.406x1.016 smd: 1(-0.65,-0.94) 2(0,-0.94) 3(0.65,-0.94) 4(0.65,0.94) 5(0,0.94) 6(-0.65,0.94)
SPR6024H64
  rect 5.69x2.083 smd: 1(0,0)
STF256R109H99
  round 6.502 hole 2.769: 1(0,0)
TPAD24
  round 0.61 smd: 1(0,0)
TPAD28
  round 0.711 smd: 1(0,0)
TVS5436-1121H105
  rect 2.337x2.007 smd: 1(0,2.299) 2(0,-2.299)
unnamed#2
  round 1.016 smd: (0,0)
XFORM12A127097H91
  rect 0.635x1.524 smd: 1(-4.445,-4.699) 2(-3.175,-4.699) 3(-1.905,-4.699) 4(1.905,-4.699) 5(3.175,-4.699) 6(4.445,-4.699) 7(4.445,4.699) 8(3.175,4.699) 9(1.905,4.699) 10(-1.905,4.699) 11(-3.175,4.699) 12(-4.445,4.699)

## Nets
1V_CPU_VCGI: C19.1 C20.1 C22.1 C24.1 C25.1 C27.1 C28.1 C265.1 C266.1 C267.1 C268.1 C269.1 C270.1 C271.1 C272.1 C273.1 C276.1 C277.1 C278.1 C279.1 C284.1 C288.1 C302.1 C303.1 C304.1 C305.1 C306.1 C307.1 C309.1 C310.1 CPU1.AA28 CPU1.AA30 CPU1.AA32 CPU1.AA36 CPU1.AA37 CPU1.AA39 CPU1.AC28 CPU1.AC30 CPU1.AC32 CPU1.AC36 CPU1.AC37 CPU1.AE28 CPU1.AE30 CPU1.AE32 CPU1.AE36 CPU1.AE37 CPU1.AG28 CPU1.AG30 CPU1.AG32 CPU1.AG36 CPU1.AJ28 CPU1.AJ30 CPU1.AJ32 CPU1.AK28 CPU1.AK30 CPU1.AK32 CPU1.AK34 CPU1.AM30 CPU1.E29 CPU1.E35 CPU1.E37 CPU1.E43 CPU1.E45 CPU1.E48 CPU1.E50 CPU1.F29 CPU1.R45 CPU1.R47 CPU1.U28 CPU1.U30 CPU1.U32 CPU1.U36 CPU1.U37 CPU1.U39 CPU1.U41 CPU1.U42 CPU1.U44 CPU1.U46 CPU1.U47 CPU1.U48 CPU1.V28 CPU1.V30 CPU1.V32 CPU1.V36 CPU1.V37 CPU1.V39 CPU1.V41 CPU1.Y28 CPU1.Y30 CPU1.Y32 CPU1.Y36 CPU1.Y37 CPU1.Y39 CPU1.Y41 PG2.2 PL1.2 PT2.1 RN15.1(A)
1V_CPU_VNN: C252.1 C253.1 C254.1 C255.1 C256.1 C257.1 C258.1 C259.1 C263.1 C264.1 C296.1 C297.1 C301.1 CPU1.AJ37 CPU1.AJ39 CPU1.AJ41 CPU1.AJ42 CPU1.AJ46 CPU1.AK37 CPU1.AK39 CPU1.AK41 CPU1.AK42 CPU1.AK44 CPU1.AK46 CPU1.AM44 PG17.2 PL9.2 PR204.2 R527.1 R582.2
1V_VCCIOA: C286.1 C287.1 CPU1.AM23 CPU1.AM25 CPU1.AM41 CPU1.AM42 PC152.1 PC153.1 R582.1
3V3_VDD33: C425.2 C426.1 C427.1 C428.1 C429.1 C433.1 C440.2 GPU1.G8 GPU1.G9 GPU1.G10 GPU1.G12 R662.2
3V3AUX: GPU1.F11
3V_5V_POK: PC198.1 PR166.1 PR169.2 PR171.2 PR243.1
3V_VA: C162.1 C163.1 C165.1 C166.2 L25.2 U16.23 U16.25
19V_AMP_AVCC: C178.1 R433.2 U22.12
19V_AMP_PVCC: C180.1 C216.1 C500.1 C506.2 L9.2 R433.1 U22.13 U22.14 U22.27 U22.28
+5V_PWR: PC115.1 PG3.2 PGT1.2 PL7.2 PR139.2 PR142.2 PR146.2 PR151.2 PR157.2 PT7.1
AGND: C121.2 C123.2 C124.2 C131.2 C145.2 C146.1 C147.1 C148.1 C149.2 C153.1 C162.2 C163.2 C165.2 C166.1 C167.2 C184.1 C185.1 C218.1 C479.2 C480.1 EC2901.2 LOUT1.5 LOUT1.P Q66.S R316.2 R319.2 R326.2 R359.2 R375.2 R387.2 R424.2 R437.2 R747.2 U16.22 U16.28 U16.42 UHS1.5
AVCC33_2136: C459.1 C460.2 C461.2 L23.2 U31.5
DVCC33_2136: C391.1 C396.2 C397.1 C402.1 C404.1 L19.2 R672.1 RN35.1(A) RN35.2(A) U31.18 U31.22
GND: AFTP1.1 BAT2.8 BAT2.9 BAT2.10 BAT2.11 BT1.2 C1.2 C2.1 C3.1 C4.2 C6.2 C7.2 C8.2 C9.2 C10.2 C11.2 C12.2 C13.1 C14.2 C15.2 C16.2 C17.2 C18.1 C19.2 C20.2 C21.2 C22.2 C23.2 C24.2 C25.2 C26.2 C27.2 C28.2 C29.2 C32.2 C35.2 C36.1 C37.1 C38.1 C39.1 C48.1 C49.1 C52.2 C55.2 C56.2 C57.1 C58.2 C59.1 C61.2 C62.2 C64.2 C65.2 C66.2 C67.2 C68.2 C69.2 C70.2 C71.2 C72.2 C73.2 C74.2 C75.2 C76.2 C77.2 C78.2 C79.2 C80.2 C81.2 C82.2 C83.2 C84.2 C85.2 C86.2 C87.2 C88.2 C89.1 C90.1 C91.2 C93.2 C95.2 C96.2 C99.2 C100.2 C101.2 C103.2 C104.2 C108.2 C110.2 C111.2 C112.2 C113.2 C114.2 C115.2 C116.1 C117.2 C118.2 C119.2 C120.1 C126.2 C128.2 C129.2 C130.2 C132.2 C133.2 C134.2 C138.2 C139.2 C140.2 C141.2 C142.2 C143.2 C144.2 C150.2 C156.2 C157.2 C158.1 C159.2 C160.2 C164.1 C168.1 C169.1 C170.2 C171.2 C172.2 C173.1 C175.2 C180.2 C181.2 C189.2 C190.2 C195.2 C196.2 C203.1 C204.2 C205.2 C206.2 C207.1 C208.1 C209.2 C211.2 C212.2 C213.2 C214.2 C216.2 C218.2 C221.2 C222.2 C223.2 C224.1 C225.1 C226.2 C227.2 C228.2 C229.2 C230.2 C231.2 C232.2 C233.2 C234.2 C235.2 C236.2 C237.2 C238.2 C239.2 C240.2 C241.2 C242.2 C243.2 C244.2 C245.2 C246.2 C247.2 C248.1 C249.2 C250.2 C251.2 C252.2 C253.2 C254.2 C255.2 C256.2 C257.2 C258.2 C259.2 C260.1 C261.2 C262.2 C263.2 C264.2 C265.2 C266.2 C267.2 C268.2 C269.2 C270.2 C271.2 C272.2 C273.2 C274.2 C275.2 C276.2 C277.2 C278.2 C279.2 C280.2 C281.2 C282.2 C283.2 C284.2 C285.2 C286.2 C287.2 C288.2 C289.1 C290.1 C291.1 C292.1 C293.1 C294.2 C295.2 C296.2 C297.2 C298.2 C299.2 C300.2 C301.2 C302.2 C303.2 C304.2 C305.2 C306.2 C307.2 C308.2 C309.2 C310.2 C311.1 C312.2 C313.2 C314.1 C315.2 C316.1 C317.2 C318.2 C319.2 C320.2 C321.1 C322.2 C323.2 C324.2 C325.2 C326.2 C327.2 C328.2 C329.1 C330.2 C331.2 C332.1 C333.2 C334.2 C335.1 C336.1 C337.1 C338.1 C339.1 C340.2 C341.2 C342.2 C343.2 C344.1 C345.2 C346.2 C347.2 C348.1 C349.1 C350.2 C351.2 C352.1 C353.2 C354.2 C355.2 C360.2 C361.2 C362.2 C363.2 C364.2 C365.2 C366.2 C367.2 C368.2 C369.2 C370.2 C371.2 C372.2 C373.2 C374.2 C375.1 C376.1 C377.2 C378.1 C379.2 C380.2 C381.2 C382.2 C383.2 C384.2 C385.2 C386.1 C387.2 C388.1 C389.2 C390.1 C391.2 C392.2 C393.1 C394.2 C395.2 C396.1 C397.2 C398.1 C399.1 C400.2 C401.1 C402.2 C403.2 C404.2 C405.2 C406.1 C407.1 C408.1 C409.1 C410.2 C411.2 C412.2 C413.1 C414.1 C416.2 C417.2 C419.2 C420.1 C421.1 C422.1 C424.2 C425.1 C426.2 C427.2 C428.2 C429.2 C430.1 C432.2 C433.2 C434.2 C435.2 C436.2 C437.2 C439.2 C440.1 C443.2 C444.2 C445.2 C446.1 C447.2 C448.2 C449.2 C450.2 C451.2 C452.2 C453.2 C454.2 C455.2 C456.1 C457.2 C458.2 C459.2 C460.1 C461.1 C462.2 C465.2 C466.2 C468.2 C469.2 C470.2 C471.2 C472.2 C473.2 C474.2 C475.2 C476.2 C477.2 C478.2 C481.2 C482.2 C483.1 C484.1 C486.2 C487.1 C488.2 C489.2 C490.2 C491.2 C492.2 C493.2 C494.2 C495.1 C496.2 C497.2 C499.2 C500.2 C502.2 C503.2 C505.1 C506.1 C508.1 C509.2 C510.1 C511.2 C512.2 C514.2 C516.1 C517.2 C519.1 C520.2 C521.1 C522.2 C523.2 C524.2 C525.2 C526.1 C527.1 C528.1 C529.1 C530.2 C531.2 C532.2 C533.1 C534.1 C535.2 C536.2 C537.1 C538.2 C539.2 C540.2 C541.2 C542.2 C543.1 C544.2 C545.2 C546.2 C547.2 C548.2 C549.2 C550.2 C551.2 C552.2 C553.2 C554.2 C555.2 C556.2 C557.2 C558.2 C559.2 C560.2 C561.2 C562.2 C563.2 C564.2 C565.2 C568.2 C569.2 CONVT1.10 CONVT1.11 CONVT1.12 CPU1.A5 CPU1.A9 CPU1.A12 CPU1.A16 CPU1.A20 CPU1.A24 CPU1.A28 CPU1.A32 CPU1.A36 CPU1.A40 CPU1.A44 CPU1.A48 CPU1.A52 CPU1.A56 CPU1.A62 CPU1.AA1 CPU1.AA2 CPU1.AA27 CPU1.AA34 CPU1.AA41 CPU1.AA63 CPU1.AB5 CPU1.AB9 CPU1.AB10 CPU1.AB12 CPU1.AB16 CPU1.AB48 CPU1.AB52 CPU1.AB57 CPU1.AB59 CPU1.AC18 CPU1.AC27 CPU1.AC34 CPU1.AC39 CPU1.AE1 CPU1.AE2 CPU1.AE4 CPU1.AE5 CPU1.AE7 CPU1.AE8 CPU1.AE10 CPU1.AE11 CPU1.AE13 CPU1.AE14 CPU1.AE16 CPU1.AE17 CPU1.AE23 CPU1.AE27 CPU1.AE34 CPU1.AE39 CPU1.AE41 CPU1.AE47 CPU1.AE48 CPU1.AE50 CPU1.AE51 CPU1.AE53 CPU1.AE54 CPU1.AE56 CPU1.AE57 CPU1.AE59 CPU1.AE63 CPU1.AG13 CPU1.AG18 CPU1.AG23 CPU1.AG27 CPU1.AG34 CPU1.AG37 CPU1.AG39 CPU1.AG41 CPU1.AG42 CPU1.AG44 CPU1.AG46 CPU1.AH5 CPU1.AH6 CPU1.AH7 CPU1.AH15 CPU1.AH16 CPU1.AH48 CPU1.AH52 CPU1.AH54 CPU1.AH55 CPU1.AH57 CPU1.AH58 CPU1.AH59 CPU1.AJ1 CPU1.AJ2 CPU1.AJ18 CPU1.AJ23 CPU1.AJ27 CPU1.AJ34 CPU1.AJ36 CPU1.AJ63 CPU1.AK5 CPU1.AK9 CPU1.AK10 CPU1.AK12 CPU1.AK18 CPU1.AK23 CPU1.AK27 CPU1.AK36 CPU1.AK48 CPU1.AK52 CPU1.AK59 CPU1.AM18 CPU1.AM22 CPU1.AM27 CPU1.AM34 CPU1.AM36 CPU1.AM39 CPU1.AM46 CPU1.AN1 CPU1.AN2 CPU1.AN5 CPU1.AN7 CPU1.AN8 CPU1.AN10 CPU1.AN11 CPU1.AN13 CPU1.AN14 CPU1.AN16 CPU1.AN17 CPU1.AN25 CPU1.AN27 CPU1.AN28 CPU1.AN30 CPU1.AN34 CPU1.AN36 CPU1.AN37 CPU1.AN39 CPU1.AN47 CPU1.AN48 CPU1.AN50 CPU1.AN51 CPU1.AN53 CPU1.AN54 CPU1.AN56 CPU1.AN57 CPU1.AN59 CPU1.AN63 CPU1.AP9 CPU1.AP55 CPU1.AR19 CPU1.AR32 CPU1.AR45 CPU1.AT2 CPU1.AT3 CPU1.AT7 CPU1.AT12 CPU1.AT16 CPU1.AT19 CPU1.AT25 CPU1.AT29 CPU1.AT35 CPU1.AT39 CPU1.AT45 CPU1.AT48 CPU1.AT52 CPU1.AT57 CPU1.AT61 CPU1.AT62 CPU1.AU32 CPU1.AV2 CPU1.AV3 CPU1.AV9 CPU1.AV19 CPU1.AV21 CPU1.AV23 CPU1.AV29 CPU1.AV32 CPU1.AV35 CPU1.AV41 CPU1.AV43 CPU1.AV45 CPU1.AV55 CPU1.AV61 CPU1.AV62 CPU1.AW14 CPU1.AW30 CPU1.AW34 CPU1.AW50 CPU1.AY6 CPU1.AY10 CPU1.AY32 CPU1.AY54 CPU1.AY58 CPU1.B2 CPU1.B3 CPU1.B9 CPU1.B62 CPU1.B63 CPU1.BA1 CPU1.BA2 CPU1.BA12 CPU1.BA16 CPU1.BA17 CPU1.BA21 CPU1.BA25 CPU1.BA27 CPU1.BA29 CPU1.BA32 CPU1.BA35 CPU1.BA37 CPU1.BA39 CPU1.BA43 CPU1.BA47 CPU1.BA48 CPU1.BA52 CPU1.BA62 CPU1.BA63 CPU1.BB3 CPU1.BB19 CPU1.BB25 CPU1.BB39 CPU1.BB45 CPU1.BB61 CPU1.BC32 CPU1.BD3 CPU1.BD8 CPU1.BD32 CPU1.BD56 CPU1.BD61 CPU1.BE1 CPU1.BE10 CPU1.BE12 CPU1.BE16 CPU1.BE17 CPU1.BE21 CPU1.BE27 CPU1.BE29 CPU1.BE35 CPU1.BE37 CPU1.BE43 CPU1.BE47 CPU1.BE48 CPU1.BE52 CPU1.BE54 CPU1.BE63 CPU1.BF3 CPU1.BF32 CPU1.BF61 CPU1.BG19 CPU1.BG23 CPU1.BG29 CPU1.BG32 CPU1.BG35 CPU1.BG41 CPU1.BG45 CPU1.BH1 CPU1.BH2 CPU1.BH21 CPU1.BH25 CPU1.BH39 CPU1.BH43 CPU1.BH62 CPU1.BH63 CPU1.BJ4 CPU1.BJ8 CPU1.BJ10 CPU1.BJ14 CPU1.BJ18 CPU1.BJ28 CPU1.BJ32 CPU1.BJ36 CPU1.BJ46 CPU1.BJ50 CPU1.BJ54 CPU1.BJ56 CPU1.BJ60 CPU1.C12 CPU1.C16 CPU1.C28 CPU1.C32 CPU1.C40 CPU1.C48 CPU1.D6 CPU1.D32 CPU1.D58 CPU1.E4 CPU1.E12 CPU1.E14 CPU1.E19 CPU1.E27 CPU1.E54 CPU1.F3 CPU1.F10 CPU1.F21 CPU1.F32 CPU1.F37 CPU1.F43 CPU1.F45 CPU1.F50 CPU1.F56 CPU1.F59 CPU1.F63 CPU1.G1 CPU1.G32 CPU1.H3 CPU1.H7 CPU1.H17 CPU1.H23 CPU1.H29 CPU1.H37 CPU1.H47 CPU1.H61 CPU1.J12 CPU1.J14 CPU1.J19 CPU1.J27 CPU1.J30 CPU1.J32 CPU1.J35 CPU1.J37 CPU1.J48 CPU1.J63 CPU1.K5 CPU1.K6 CPU1.K32 CPU1.K54 CPU1.K57 CPU1.L21 CPU1.L27 CPU1.L29 CPU1.L35 CPU1.L43 CPU1.L45 CPU1.L50 CPU1.M3 CPU1.M9 CPU1.M14 CPU1.M21 CPU1.M27 CPU1.M32 CPU1.M50 CPU1.M59 CPU1.N1 CPU1.N32 CPU1.N63 CPU1.P5 CPU1.P9 CPU1.P13 CPU1.P19 CPU1.P35 CPU1.P37 CPU1.P41 CPU1.P43 CPU1.P45 CPU1.P55 CPU1.P59 CPU1.R23 CPU1.R29 CPU1.R32 CPU1.T49 CPU1.U1 CPU1.U2 CPU1.U5 CPU1.U7 CPU1.U8 CPU1.U10 CPU1.U11 CPU1.U13 CPU1.U14 CPU1.U16 CPU1.U17 CPU1.U18 CPU1.U27 CPU1.U34 CPU1.U50 CPU1.U51 CPU1.U53 CPU1.U54 CPU1.U56 CPU1.U57 CPU1.U59 CPU1.U62 CPU1.U63 CPU1.V20 CPU1.V27 CPU1.V34 CPU1.V42 CPU1.Y5 CPU1.Y6 CPU1.Y7 CPU1.Y12 CPU1.Y16 CPU1.Y22 CPU1.Y27 CPU1.Y34 CPU1.Y42 CPU1.Y46 CPU1.Y48 CPU1.Y52 CPU1.Y54 CPU1.Y55 CPU1.Y57 CPU1.Y59 D5.1 D9.A DCIN1.2 DCIN1.4 DCIN1.5 DCIN1.6 DCIN1.7 DCIN2.5 DCIN2.6 DCIN2.7 DCIN2.12 DCIN2.13 DCIN2.14 DIMM1.2 DIMM1.3 DIMM1.8 DIMM1.9 DIMM1.11 DIMM1.13 DIMM1.14 DIMM1.19 DIMM1.20 DIMM1.25 DIMM1.26 DIMM1.28 DIMM1.31 DIMM1.32 DIMM1.37 DIMM1.38 DIMM1.43 DIMM1.44 DIMM1.46 DIMM1.48 DIMM1.49 DIMM1.54 DIMM1.55 DIMM1.60 DIMM1.61 DIMM1.63 DIMM1.65 DIMM1.66 DIMM1.71 DIMM1.72 DIMM1.127 DIMM1.128 DIMM1.133 DIMM1.134 DIMM1.136 DIMM1.138 DIMM1.139 DIMM1.144 DIMM1.145 DIMM1.150 DIMM1.151 DIMM1.153 DIMM1.155 DIMM1.156 DIMM1.161 DIMM1.162 DIMM1.167 DIMM1.168 DIMM1.170 DIMM1.172 DIMM1.173 DIMM1.178 DIMM1.179 DIMM1.184 DIMM1.185 DIMM1.187 DIMM1.189 DIMM1.190 DIMM1.195 DIMM1.196 DIMM1.205 DIMM1.206 EC1.2 EC2.2 EC518.2 EC2901.1 EC8601.2 EC8602.2 EC8603.2 EC8604.2 EC_DEBUG1.1 EMC1.1 EMC2.1 EMC3.1 EMC4.1 FANC3.1 GPU1.A2 GPU1.A26 GPU1.AA7 GPU1.AB7 GPU1.AB11 GPU1.AB14 GPU1.AB17 GPU1.AB20 GPU1.AB24 GPU1.AC2 GPU1.AC5 GPU1.AC8 GPU1.AC22 GPU1.AC26 GPU1.AD12 GPU1.AD13 GPU1.AD15 GPU1.AD16 GPU1.AD18 GPU1.AD19 GPU1.AD21 GPU1.AD22 GPU1.AE11 GPU1.AE14 GPU1.AE17 GPU1.AE20 GPU1.AF1 GPU1.AF5 GPU1.AF8 GPU1.AF11 GPU1.AF14 GPU1.AF17 GPU1.AF20 GPU1.AF23 GPU1.AG2 GPU1.AG26 GPU1.B1 GPU1.B5 GPU1.B8 GPU1.B11 GPU1.B14 GPU1.B17 GPU1.B20 GPU1.B23 GPU1.B27 GPU1.E2 GPU1.E5 GPU1.E8 GPU1.E11 GPU1.E14 GPU1.E17 GPU1.E20 GPU1.E22 GPU1.E25 GPU1.H2 GPU1.H5 GPU1.H23 GPU1.H25 GPU1.K11 GPU1.K13 GPU1.K15 GPU1.K17 GPU1.L2 GPU1.L5 GPU1.L10 GPU1.L12 GPU1.L14 GPU1.L16 GPU1.L18 GPU1.L23 GPU1.L25 GPU1.M11 GPU1.M13 GPU1.M15 GPU1.M17 GPU1.N10 GPU1.N12 GPU1.N14 GPU1.N16 GPU1.N18 GPU1.P2 GPU1.P5 GPU1.P11 GPU1.P13 GPU1.P15 GPU1.P17 GPU1.P23 GPU1.P26 GPU1.R10 GPU1.R12 GPU1.R14 GPU1.R16 GPU1.R18 GPU1.T11 GPU1.T13 GPU1.T15 GPU1.T17 GPU1.U2 GPU1.U5 GPU1.U10 GPU1.U12 GPU1.U14 GPU1.U16 GPU1.U18 GPU1.U23 GPU1.U26 GPU1.V11 GPU1.V13 GPU1.V15 GPU1.V17 GPU1.Y2 GPU1.Y5 GPU1.Y23 GPU1.Y26 H1.1 H2.1 H3.1 H4.1 H5.1 H6.1 H6.2 H6.3 H6.4 H6.5 H6.6 H6.7 H6.8 H7.1 H7.2 H7.3 H7.4 H7.5 H7.6 H7.7 H7.8 H9.1 H9.2 H9.3 H9.4 H9.5 H9.6 H9.7 H9.8 H10.1 H10.2 H10.3 H10.4 H10.5 H10.6 H10.7 H10.8 H11.1 H11.2 H11.3 H11.4 H11.5 H11.6 H11.7 H11.8 HDD1.1 HDD1.4 HDD1.7 HDD1.8 HDD1.9 HDMI1.2 HDMI1.5 HDMI1.8 HDMI1.11 HDMI1.17 HDMI1.20 HDMI1.21 HDMI1.22 HDMI2.3 HDMI2.9 HDMI2.12 HDMI2.15 HDMI2.18 HDMI2.20 HDMI2.21 HDMI2.22 HDMI2.23 HDMI2.24 HDMI2.25 HS6.1 IRMTCN1.5 IRMTCN1.6 JMP1.4 LED1.K LPC1.12 LPC1.14 LVDS1.7 LVDS1.14 LVDS1.31 LVDS1.32 MEMCD1.3 MEMCD1.6 MEMCD1.12 MEMCD1.13 MEMCD1.14 MEMCD1.15 NGFF1.7 NGFF1.18 NGFF1.23 NGFF1.24 NGFF1.29 NGFF1.30 NGFF1.33 NGFF1.36 NGFF1.39 NGFF1.45 NGFF1.57 NGFF1.63 NGFF1.69 NGFF1.75 NGFF1.76 NGFF1.77 ODD1.1 ODD1.4 ODD1.7 ODD1.8 ODD1.9 PC1.2 PC2.2 PC3.2 PC4.2 PC5.2 PC6.2 PC9.2 PC12.2 PC13.2 PC15.2 PC16.1 PC17.2 PC19.2 PC20.2 PC21.2 PC23.2 PC24.1 PC25.2 PC26.2 PC27.2 PC29.2 PC31.2 PC32.2 PC33.2 PC34.2 PC35.2 PC36.2 PC37.2 PC38.2 PC40.2 PC41.2 PC43.2 PC44.2 PC45.2 PC46.2 PC47.1 PC48.2 PC49.2 PC50.2 PC54.2 PC55.2 PC56.2 PC57.1 PC58.2 PC59.2 PC60.2 PC61.2 PC62.2 PC64.2 PC65.2 PC66.2 PC67.2 PC69.2 PC70.2 PC71.2 PC72.2 PC73.2 PC75.2 PC76.2 PC77.2 PC78.2 PC79.2 PC81.2 PC82.2 PC83.2 PC84.2 PC85.2 PC86.2 PC87.2 PC88.2 PC89.2 PC90.2 PC92.2 PC93.2 PC94.2 PC98.2 PC99.2 PC100.2 PC101.2 PC102.2 PC103.2 PC104.2 PC105.2 PC108.2 PC110.2 PC111.1 PC113.2 PC115.2 PC117.2 PC118.2 PC119.2 PC120.1 PC122.2 PC123.2 PC124.2 PC126.1 PC129.2 PC131.2 PC132.2 PC133.2 PC139.2 PC141.2 PC144.2 PC145.2 PC146.2 PC147.2 PC148.2 PC149.2 PC150.2 PC151.2 PC152.2 PC153.2 PC154.2 PC155.2 PC156.2 PC157.2 PC158.2 PC159.2 PC160.2 PC161.2 PC162.2 PC163.2 PC164.2 PC165.2 PC166.2 PC167.2 PC168.2 PC169.2 PC170.2 PC171.2 PC172.2 PC173.2 PC174.2 PC175.2 PC176.2 PC177.2 PC178.2 PC184.2 PC185.2 PC190.2 PC191.2 PC192.2 PC193.1 PC195.2 PC196.2 PC197.2 PC198.2 PCB1.2 PCT1.2 PCT2.2 PD3.A PG13.1 PL10.2 PL11.2 PL13.2 PQ2.1 PQ2.2 PQ2.3 PQ3.1 PQ3.2 PQ3.3 PQ5.1 PQ5.2 PQ5.3 PQ6.1 PQ6.4 PQ9.1 PQ9.2 PQ9.3 PQ10.S PQ12.S PQ13.1 PQ13.4 PQ14.E PQ17.S PQ19.S PQ20.1 PQ20.2 PQ20.3 PR3.2 PR13.2 PR15.2 PR20.2 PR21.2 PR22.2 PR24.2 PR25.1 PR26.1 PR34.2 PR41.2 PR52.2 PR60.2 PR67.2 PR85.2 PR89.2 PR94.2 PR95.2 PR97.2 PR99.2 PR101.2 PR107.2 PR111.2 PR114.2 PR116.2 PR117.2 PR130.2 PR131.2 PR133.1 PR134.2 PR144.1 PR155.2 PR159.2 PR160.2 PR163.2 PR179.2 PR183.2 PR186.2 PR214.2 PR216.2 PR218.2 PR242.1 PRB1.2 PT1.2 PT2.2 PT3.2 PT4.2 PT5.2 PT6.2 PT7.2 PT8.2 PTC1.2 PU1.1 PU2.11 PU3.11 PU4.11 PU5.1 PU5.3 PU5.14 PU5.21 PU6.1 PU7.1 PU7.2 PU7.3 PU10.21 PU13.27 PU13.28 PU13.29 PU13.30 PU13.31 PU13.32 PU13.34 PU13.53 PU15.1 PU15.2 PU15.3 PU16.1 PU16.2 PU16.3 PU18.1 PU18.2 PU18.3 PWRCN1.4 PWRCN1.11 PWRCN1.12 Q6.1 Q6.4 Q8.S Q9.1 Q9.4 Q10.S Q12.1 Q12.4 Q13.1 Q13.4 Q14.S Q15.S Q17.S Q18.E Q19.1 Q19.4 Q24.S Q26.S Q29.3 Q30.1 Q30.4 Q31.1 Q31.4 Q33.3 Q36.1 Q36.4 Q37.3 Q38.S Q39.E Q40.E Q43.E Q44.E Q45.1 Q45.4 Q46.1 Q46.4 Q47.1 Q47.4 Q48.E Q50.S Q52.1 Q52.4 Q55.S Q56.S Q64.S Q65.C Q67.E Q69.1 Q70.S Q71.S Q72.S Q74.S Q75.E Q76.1 Q76.4 Q77.E Q78.E Q80.E Q81.E Q1801.S Q2801.S Q4501.S R2.2 R27.1 R30.1 R38.1 R43.2 R44.2 R56.2 R57.2 R59.2 R72.1 R75.2 R78.1 R86.2 R88.1 R100.2 R112.2 R113.2 R114.2 R115.2 R116.2 R120.2 R128.2 R132.2 R138.2 R139.2 R143.2 R145.2 R148.2 R158.2 R161.2 R163.2 R167.2 R171.1 R184.2 R193.2 R197.1 R210.2 R213.2 R229.2 R239.1 R245.2 R247.2 R253.2 R255.1 R258.2 R262.1 R267.2 R277.1 R279.2 R281.2 R282.2 R283.2 R285.2 R291.2 R292.2 R293.2 R298.2 R299.2 R301.2 R304.2 R310.2 R316.1 R324.2 R332.1 R336.2 R351.2 R352.2 R359.1 R375.1 R376.1 R383.2 R390.1 R413.2 R419.2 R424.1 R428.2 R437.1 R438.2 R449.1 R459.2 R472.2 R477.2 R479.2 R480.2 R484.2 R498.1 R558.1 R567.1 R577.2 R578.2 R583.1 R584.1 R589.1 R590.1 R591.1 R592.1 R593.1 R595.1 R597.1 R600.1 R609.1 R617.2 R629.2 R630.2 R633.2 R643.2 R644.2 R647.2 R652.2 R657.1 R658.2 R664.2 R673.2 R674.2 R675.2 R676.2 R677.2 R679.2 R685.2 R692.2 R693.2 R711.2 R718.1 R731.1 R735.1 R747.1 R754.2 R755.2 R756.2 R761.2 R764.2 R790.2 R794.2 R796.2 R803.2 R805.1 R812.2 R1702.2 R1703.2 R1803.2 R1808.2 R2002.2 R4501.2 R5501.2 RJ1.13 RN15.2(A) RN30.3(B) RN30.4(B) RN38.3(B) RN38.4(B) RV1.1 SATAP1.2 SATAP1.4 SPK1.5 SPK1.7 SPK1.8 SRCON1.4 SSUSB1.4 SSUSB1.7 SSUSB1.10 SSUSB1.11 SSUSB2.4 SSUSB2.7 SSUSB2.10 SSUSB2.11 TC1.2 TC2.2 TC3.2 TC4.2 TOUCH1.2 U1.A6 U1.C4 U1.E7 U1.G5 U1.H10 U1.J5 U1.K8 U1.N2 U1.N5 U1.P4 U1.P6 U2.5 U2.11 U3.4 U4.3 U4.8 U5.3 U6.2 U7.9 U7.16 U7.23 U7.32 U7.33 U8.2 U9.3 U9.8 U11.22 U11.25 U12.5 U13.2 U14.5 U14.18 U14.45 U14.78 U14.89 U14.116 U15.11 U15.15 U16.49 U17.3 U18.3 U18.8 U19.3 U19.8 U20.8 U20.15 U20.35 U20.41 U21.3 U21.8 U22.8 U22.9 U22.10 U22.17 U22.20 U22.21 U22.24 U22.33 U23.2 U24.2 U25.2 U26.33 U27.S U28.2 U29.11 U29.15 U31.6 U31.49 U32.4 U33.1 U33.2 U33.4 U34.14 U34.21 U35.20 U37.2 U38.2 U39.2 U39.3 UHS1.MS1 UHS1.MS2 USB3.4 USB3.5 USB3.6 USB4.4 USB4.5 USB4.6 VRAM1.A9 VRAM1.B1 VRAM1.B3 VRAM1.B9 VRAM1.D1 VRAM1.D8 VRAM1.E1 VRAM1.E2 VRAM1.E8 VRAM1.F9 VRAM1.G1 VRAM1.G8 VRAM1.G9 VRAM1.J2 VRAM1.J8 VRAM1.M1 VRAM1.M9 VRAM1.P1 VRAM1.P9 VRAM1.T1 VRAM1.T9 VRAM2.A9 VRAM2.B1 VRAM2.B3 VRAM2.B9 VRAM2.D1 VRAM2.D8 VRAM2.E1 VRAM2.E2 VRAM2.E8 VRAM2.F9 VRAM2.G1 VRAM2.G8 VRAM2.G9 VRAM2.J2 VRAM2.J8 VRAM2.M1 VRAM2.M9 VRAM2.P1 VRAM2.P9 VRAM2.T1 VRAM2.T9 VRAM3.A9 VRAM3.B1 VRAM3.B3 VRAM3.B9 VRAM3.D1 VRAM3.D8 VRAM3.E1 VRAM3.E2 VRAM3.E8 VRAM3.F9 VRAM3.G1 VRAM3.G8 VRAM3.G9 VRAM3.J2 VRAM3.J8 VRAM3.M1 VRAM3.M9 VRAM3.P1 VRAM3.P9 VRAM3.T1 VRAM3.T9 VRAM4.A9 VRAM4.B1 VRAM4.B3 VRAM4.B9 VRAM4.D1 VRAM4.D8 VRAM4.E1 VRAM4.E2 VRAM4.E8 VRAM4.F9 VRAM4.G1 VRAM4.G8 VRAM4.G9 VRAM4.J2 VRAM4.J8 VRAM4.M1 VRAM4.M9 VRAM4.P1 VRAM4.P9 VRAM4.T1 VRAM4.T9 WEBCM1.6 WEBCM1.8 WEBCM1.9 WEBCM1.10 X1.2 X1.3 X2.2 X2.4 X3.2 X3.4 X4.2 X4.4 XDP1.16 XDP1.57 XDP1.58 XDP1.61 XDP1.62 XDP1.63 XDP1.64
GND_AUD: C145.1 C148.2 U16.40
V1P8A_S5_PG: PR49.2 R404.2 R580.1 R587.1
V1P8A_S5_PG_EC: R404.1 U14.58
VBAT1: BT1.1 R483.1 TP85.1
VBAT1_R: D7.2 R483.2 R484.1 TP84.1 U27.G
VCC: C142.1 C143.1 C203.2 C369.1 D6.A F1.1 F7.1 LPC1.8 PC81.1 PR120.1 PR126.1 PU6.6 R47.2 R220.1 R414.1 R574.1 R575.1 R707.1 U15.13 U15.14 U38.6
VCC3: C122.2 C157.1 C171.1 C196.1 C343.1 C344.2 C481.1 C486.1 C487.2 C488.1 C489.1 C519.2 C564.1 D1.K DIMM1.199 F3.1 F5.1 L19.1 L23.1 L25.1 LPC1.4 PR17.1 PR206.1 PR208.1 Q27.S R46.1 R73.1 R92.1 R119.2 R251.2 R252.2 R318.2 R320.2 R321.1 R325.1 R327.1 R331.1 R347.1 R367.1 R392.1 R418.1 R420.1 R421.1 R422.1 R423.1 R460.1 R464.1 R473.1 R482.1 R491.1 R508.1 R510.2 R525.2 R535.1 R566.1 R570.1 R628.2 R642.1 R668.1 R682.2 R687.1 R690.1 R700.1 R701.1 R750.1 R759.2 R789.1 R815.1 RN17.1(A) RN17.2(A) RN41.1(A) RN41.2(A) U15.8 U15.9 U16.11 U20.11 U20.37 U33.3 U33.8 U36.3 U39.5
VCC3_CAM: C260.2 C261.1 C262.1 F3.2 F4.2 R569.2 R570.2 WEBCM1.3
VCC3_CT2: C478.1 U15.10
VCC3_EN: C150.1 R381.1 U15.5
VCC5_PANEL: C355.1 C360.1 C361.1 C548.1 LVDS1.2 LVDS1.3 Q59.S R639.2 R649.2 R655.1 R656.1 U38.1
VCC_1P24_A1_R: C308.1 CPU1.AM28 R594.2
VCC_CT1: C475.1 U15.12
VCC_EN: C144.1 R379.1 U15.3
VCC_FAN_PWR: C8.1 F1.2 FANC3.2 R47.1 R58.1
VCCGI_SENSE: CPU1.R41 PG15.1 RN15.4(B)
VSSGI_SENSE: CPU1.R43 PG16.1 RN15.3(B)
1D05V_FHV0: CPU1.T13 R608.2
1D05V_FHV1: CPU1.T15 R605.2
1D05V_FUSE: CPU1.P16 R607.2
1D05V_IO_3PHASEIO: C324.1 C328.1 C333.1 C334.1 CPU1.AA22 CPU1.AA23 CPU1.AC23 CPU1.V18 CPU1.Y18 CPU1.Y20 PC169.1 R616.2
1D05V_PCH: C315.1 C318.1 C326.1 C330.1 CPU1.AA25 CPU1.AC25 CPU1.AE25 CPU1.U20 CPU1.U22 CPU1.U23 CPU1.U25 CPU1.V22 CPU1.V23 CPU1.V25 CPU1.Y23 CPU1.Y25 PC162.1 PC163.1 R598.2
1D05V_S0: PC9.1 PR44.2 PR46.2 PR56.1 PR189.1 PR195.1 R169.1 R598.1 R605.1 R607.1 R608.1 R616.1
1D8V_EMMC: C240.1 C241.1 C247.1 Q5.G R11.1 R512.2 R519.2 R547.2 R548.2 R549.2 R550.2 R551.2 R552.2 R553.2 R554.2 R557.2 U1.C6 U1.M4 U1.N4 U1.P3 U1.P5 U29.13 U29.14
1D8V_EMMC_CT1: C237.1 U29.12
1D8V_EMMC_EN: C236.1 R518.2 U29.3
1D8V_PCH: C280.1 C283.1 C294.1 C295.1 C313.1 CPU1.AA46 CPU1.AC42 CPU1.AC44 CPU1.AC46 CPU1.AE42 CPU1.AE44 CPU1.AE46 CPU1.AG25 PC149.1 R572.1
1D8V_S0: C2.2 C4.1 C5.2 Q3.S R2.1 R196.2 R474.2 R519.1 R809.1
1D8V_S0_EN: C10.1 Q6.2 R52.1
1D8V_S0_EN1: Q6.5 Q6.6 R53.2 R57.1
1D8V_S0_EN2: Q6.3 R41.1 R44.1 R50.2
1D8V_S0_EN_G: C5.1 C6.1 Q3.G R41.2
1D8V_S0_EN_R: PR17.2 PR27.2 PR28.2 R52.2
1D8V_S5: C12.1 C14.1 C235.1 C251.1 JMP1.5 PR31.1 PR42.1 Q3.D Q23.G Q9201.G Q9202.G R1.1 R3.2 R51.1 R101.1 R102.1 R103.1 R104.1 R105.1 R106.1 R109.2 R124.1 R125.1 R131.2 R133.2 R137.1 R144.1 R147.1 R149.1 R157.1 R159.2 R160.1 R162.1 R166.2 R173.1 R177.1 R179.2 R200.2 R212.1 R222.1 R240.2 R241.2 R512.1 R524.1 R540.1 R543.1 R546.1 R565.1 R572.2 R726.1 R749.1 R780.1 R788.1 R1701.1 R2001.1 R5502.1 RN5.3(B) RN5.4(B) RN6.3(B) RN6.4(B) RN7.1(A) RN7.2(A) RN8.1(A) RN8.2(A) RN18.1(A) RN18.2(A) RN21.1(A) RN21.2(A) RN22.1(A) RN22.2(A) RN24.1(A) RN24.2(A) RN39.1(A) RN39.2(A) U29.1 U29.2 XDP1.1 XDP1.12
1D8V_S5_D: Q47.6 R524.2
1D8V_SPI: C57.2 R194.1 R204.1 R209.1 R212.2 SRCON1.8 U3.8
1D24_35V_S5: R596.1 R599.2 R601.1 R602.2 R603.1 R606.1 R613.2 R614.2
1D24V_AUD_ISH_PLL: C322.1 C331.1 CPU1.AJ20 CPU1.AJ22 CPU1.AK22 PC164.1 R601.2
1D24V_DSI_CSI: C327.1 C340.1 CPU1.AA18 CPU1.AA20 PC171.1 R615.2
1D24V_GLML: C300.1 C319.1 C325.1 CPU1.AK20 CPU1.AM20 CPU1.AM37 PC161.1 R594.1 R596.2
1D24V_MPHY: C317.1 C323.1 CPU1.AE18 CPU1.AE20 CPU1.AE22 CPU1.AG22 PC166.1 PC167.1 R606.2
1D24V_S5: PR57.2 PR240.2 R588.1 R613.1 R614.1 R615.1
1D24V_S5_D: Q52.6 R588.2
1D24V_USB2: C320.1 CPU1.AG20 R603.2
1D35V_S3_PWRGD: PR86.2 PU5.10 R221.1 U14.101
1P05V_PG: PC29.1 PR39.2 PU2.4 R403.2
1P05V_PG_EC: R403.1 U14.57
1P05V_S5_D: Q46.3 R514.2
3D3V_AUX_KBC: Q63.D R373.2 R393.2 R708.1 R713.2 R730.1 R736.2 R737.2 R739.1 R742.2 R745.1 R2403.2 RN12.1(A) RN12.2(A) RN13.1(A) RN13.2(A) RN40.3(B) RN40.4(B)
3D3V_AUX_S5_MUX: R208.1 U2.10
3D3V_EMMC: C243.1 C245.1 R523.2 R535.2 U1.E6 U1.F5 U1.J10 U1.K9 U29.8 U29.9
3D3V_EMMC_CT2: C239.1 U29.10
3D3V_EMMC_EN: C238.1 R521.2 U29.5
3D3V_USB: C282.1 C298.1 C299.1 C312.1 CPU1.AA42 CPU1.AC41 CPU1.AJ25 CPU1.AK25 CPU1.V44 CPU1.V46 CPU1.Y44 PC145.1 R573.2
3D3V_VCCRTC: CPU1.AA44 PC144.1 R571.1
3D3VDD_TPM: C74.1 C75.1 C78.1 C82.1 R237.1 R251.1 U7.8 U7.14 U7.22
1117_ADJ: R795.2 R796.1 U36.1
+3D3V_PWR: PC117.1 PG7.2 PL8.1 PR165.2 PR170.2 PR172.2 PR230.2 PR235.2 PT8.1
+V_1P05_VGA: C68.1 C69.1 C79.1 C351.1 C352.2 C363.1 C366.1 C367.1 C368.1 C370.1 C378.2 C379.1 C380.1 C381.1 C389.1 GPU1.AA10 GPU1.AA12 GPU1.AA13 GPU1.AA16 GPU1.AA18 GPU1.AA19 GPU1.AA20 GPU1.AA21 GPU1.AA22 GPU1.AB22 GPU1.AB23 GPU1.AC23 GPU1.AC24 GPU1.AD24 GPU1.AD25 GPU1.AE25 GPU1.AE26 GPU1.AE27 GPU1.AF26 GPU1.AF27 L17.2 L21.1 L22.1 PR91.1 PR93.1 R217.2 R641.2
+V_1P05_VGA_DISCHIG: Q13.6 R217.1
+V_1P35_VGA: C55.1 C61.1 C62.1 C65.1 C66.1 C67.1 C71.1 C83.1 C84.1 C86.1 C87.1 C95.1 C96.1 C100.1 C101.1 C110.1 C111.1 C112.1 C113.1 C117.1 C118.1 C119.1 C353.1 C384.1 C385.1 C419.1 C424.1 C435.1 C437.1 C439.1 C446.2 C447.1 C454.1 C455.1 C456.2 C458.1 EC8601.1 EC8602.1 EC8603.1 EC8604.1 GPU1.B26 GPU1.C25 GPU1.E23 GPU1.E26 GPU1.F14 GPU1.F21 GPU1.G13 GPU1.G14 GPU1.G15 GPU1.G16 GPU1.G18 GPU1.G19 GPU1.G20 GPU1.G21 GPU1.H24 GPU1.H26 GPU1.J21 GPU1.K21 GPU1.L22 GPU1.L24 GPU1.L26 GPU1.M21 GPU1.N21 GPU1.R21 GPU1.T21 GPU1.V21 GPU1.W21 PR69.2 PR70.2 R215.2 R254.1 R268.1 R284.1 R287.1 R645.1 R646.1 R659.2 R666.2 R669.1 R670.1 R671.2 VRAM1.A1 VRAM1.A8 VRAM1.B2 VRAM1.C1 VRAM1.C9 VRAM1.D2 VRAM1.D9 VRAM1.E9 VRAM1.F1 VRAM1.G7 VRAM1.H2 VRAM1.H9 VRAM1.K2 VRAM1.K8 VRAM1.N1 VRAM1.N9 VRAM1.R1 VRAM1.R9 VRAM2.A1 VRAM2.A8 VRAM2.B2 VRAM2.C1 VRAM2.C9 VRAM2.D2 VRAM2.D9 VRAM2.E9 VRAM2.F1 VRAM2.G7 VRAM2.H2 VRAM2.H9 VRAM2.K2 VRAM2.K8 VRAM2.N1 VRAM2.N9 VRAM2.R1 VRAM2.R9 VRAM3.A1 VRAM3.A8 VRAM3.B2 VRAM3.C1 VRAM3.C9 VRAM3.D2 VRAM3.D9 VRAM3.E9 VRAM3.F1 VRAM3.G7 VRAM3.H2 VRAM3.H9 VRAM3.K2 VRAM3.K8 VRAM3.N1 VRAM3.N9 VRAM3.R1 VRAM3.R9 VRAM4.A1 VRAM4.A8 VRAM4.B2 VRAM4.C1 VRAM4.C9 VRAM4.D2 VRAM4.D9 VRAM4.E9 VRAM4.F1 VRAM4.G7 VRAM4.H2 VRAM4.H9 VRAM4.K2 VRAM4.K8 VRAM4.N1 VRAM4.N9 VRAM4.R1 VRAM4.R9
+V_1P35_VGA_DISCHG: Q12.6 R215.1
+V_3P3_VGA: C116.2 C375.2 C376.2 C377.1 C547.1 GPU1.AA8 GPU1.AA9 GPU1.AB8 PR63.1 PR64.1 PR88.1 PR100.1 PR105.1 PR123.2 PR128.2 Q22.G Q27.D Q28.2 Q28.5 R232.2 R274.1 R276.1 R278.2 R288.2 R290.2 R300.1 R308.1 R313.1 R314.1 R318.1 R653.1 R660.1 R661.1 R662.1 R665.1 R667.1 R696.1 R697.1 RN19.1(A) RN19.2(A) RN20.1(A) RN20.2(A) U5.5 U32.3 U32.7 U32.8
+V_VGA_CORE: C108.1 C382.1 C383.1 C386.2 C388.2 C390.2 C392.1 C393.2 C394.1 C398.2 C399.2 C405.1 C406.2 C407.2 C408.2 C409.2 C413.2 C414.2 C420.2 C421.2 C422.2 C430.2 C432.1 GPU1.K10 GPU1.K12 GPU1.K14 GPU1.K16 GPU1.K18 GPU1.L11 GPU1.L13 GPU1.L15 GPU1.L17 GPU1.M10 GPU1.M12 GPU1.M14 GPU1.M16 GPU1.M18 GPU1.N11 GPU1.N13 GPU1.N15 GPU1.N17 GPU1.P10 GPU1.P12 GPU1.P14 GPU1.P16 GPU1.P18 GPU1.R11 GPU1.R13 GPU1.R15 GPU1.R17 GPU1.T10 GPU1.T12 GPU1.T14 GPU1.T16 GPU1.T18 GPU1.U11 GPU1.U13 GPU1.U15 GPU1.U17 GPU1.V10 GPU1.V12 GPU1.V14 GPU1.V16 GPU1.V18 PC84.1 PL6.2 PR104.1 PT3.1 PT5.1 R223.2
AC_IN: PQ12.D PQ13.2 PR156.2
AC_IN_KBC#: PQ10.G Q36.6 R393.1 U14.65
AC_IN_KBC#_R: PQ10.D PR140.2
AC_OK#: PQ12.G PR225.2 R738.1 R742.1 U34.5
AC_PRESENT_CPU: CPU1.AK49 R394.2 RN4.3(B)
AC_PRESENT_KBC: R394.1 U14.52
AC_PROTECT: PR153.1 PR218.1 PR226.2 R727.1 U34.3
AC_PROTECT_R: C465.1 PQ17.G PR220.2 R727.2
AD+_2: PC125.2 PQ15.C PR179.1 PR180.2 PU12.4
AD+_G_1: PQ13.5 PQ13.6 PR176.2
AD+_G_2: PR174.2 PR176.1 PU11.4
AD+_TO_SYS: PG8.1 PR173.1 PR174.1 PU11.1 PU11.2 PU11.3 R409.2 R751.2 R753.2 R758.2 R762.2
AD_IA: PR227.2 R350.1
AD_IA_HW1: PQ8.5 U14.54
AD_IA_HW2: PQ8.2 U14.55
AD_IA_R: C136.1 R350.2 R352.1 U14.97
AD_JK: C502.1 DCIN1.1 DCIN2.1 DCIN2.2 DCIN2.3 DCIN2.8 DCIN2.9 DCIN2.10 PC125.1 PC191.1 PC192.1 PC193.2 PD3.K PQ15.E PR178.1 PR180.1 PU12.1 PU12.2 PU12.3 R439.1
AD_JK1: Q36.2 R413.1 R439.2
AD_OFF_L: PQ14.C PQ15.B
ADAPTOR_PSID_R: Q41.S R476.1
ADAPTOR_PSID_R_R: D5.3 R444.1 R445.2 R476.2
ADAPTOR_PSID_SIO: R444.2 U14.99
ALERT#: R328.2 U12.6
ALL_PWRGD_2: Q26.D R317.1 R320.1
AMD_RST#_L: D3.2 R239.2 R248.2 R265.2 R272.1 U5.4
AMP_GND: C173.2 C178.2 C197.1 C200.1 R434.2 R436.2 R440.1 R451.2 R462.1 R466.1 R479.1 U22.4
AMP_SPKR_L: C191.1 R431.2 R434.1
AMP_SPKR_R: C217.1 R432.2 R436.1
APU_PROCHOT#: C32.1 C172.1 PQ17.D PR42.2 PR136.1 PR190.1 Q38.D R141.1 R429.2
APU_PROCHOT#_R: CPU1.E47 R141.2
APU_PWNBTN_N: CPU1.AK55 R16.2 R31.2 R528.1 R1802.2
APU_PWNBTN_N_R: R16.1 R17.1
APU_SATA_LED_B: Q78.B R490.2
APU_SATA_LED_N: CPU1.C31 R474.1 R490.1
APU_SPKR: CPU1.AK57 R382.1
AUD_BEEP_C: C155.2 U16.2
AUD_BEEP_R: C155.1 R382.2 R383.1 R388.2
AUD_DMIC_CLK: C18.2 L1.2 WEBCM1.4
AUD_DMIC_CLK_R: R93.1 U16.12
AUD_DMIC_CLK_R_1: L1.1 R93.2
AUD_DMIC_DATA: C168.2 R417.1 WEBCM1.5
AUD_DMIC_DATA_R: R417.2 U16.13
AUD_DVDD: C483.2 C484.2 R749.2 R750.2 R809.2 U16.7
AUD_GP3: R392.2 U16.3
AUD_LINK_BCLK: C158.2 R81.1 U16.5
AUD_LINK_RST_N: R74.1 R748.1 U16.6
AUD_LINK_RST_N_2: Q69.4 Q69.6
AUD_LINK_RST_N_R: C482.1 Q67.B R748.2
AUD_LINK_SDIN: R82.1 R411.1
AUD_LINK_SDIN_1: R411.2 R416.1 U16.8
AUD_LINK_SDIN_ST: R83.2 R86.1 R416.2
AUD_LINK_SDO: C161.1 Q35.D R87.1 R396.2
AUD_LINK_SDO_1: C161.2 Q35.G R414.2
AUD_LINK_SDO_N: Q35.S R396.1 U16.4
AUD_LINK_SYNC: R84.1 U16.9
AUD_REGREF: C164.2 U16.10
AZ_BCLK_M: CPU1.AM48 R81.2
AZ_RST_N_M: R54.1 R74.2
AZ_RST_R_M: CPU1.K58 R54.2
AZ_SDIN_M: CPU1.AK51 R82.2
AZ_SDOUT_M: CPU1.AM54 R87.2
AZ_SYNC_M: CPU1.AK58 R83.1 R84.2
BAT_ALERT: BAT2.7 R735.2
BAT_IN#: R725.1 R737.1 U14.80
BAT_IN#_1: BAT2.5 PC184.1 PL13.1 R725.2
BATA_SCL_1: BAT2.3 PC175.1 PL10.1 R714.2
BATA_SDA_1: BAT2.4 PC176.1 PL11.1 R717.2
BATT_AMBER_LED#: R407.2 U14.32
BATT_AMBER_LED#_C: PWRCN1.10 R407.1 R801.2
BATT_WHITE_LED#: R385.2 U14.22
BATT_WHITE_LED#_C: PWRCN1.8 Q75.C Q77.C R385.1 R486.2
BIST_DISABLE: R333.1 R336.1 R339.2 U14.118
BIST_DISABLE_1: Q31.5 R333.2
BIST_EN: Q30.2 Q31.3 Q31.6 R331.2
BIST_EN_INV: Q30.3 Q30.6 R327.2 R402.1 R676.1 U31.2
BIST_EN_SIO: R402.2 U14.42
BIST_ENABLE: R330.1 U14.43
BIST_ENABLE_1: Q30.5 R324.1 R330.2 R334.2
BIST_PIN25: Q56.G U14.82
BKLT_ADJ: C511.1 C512.1 R778.2 R782.2
BKLT_EN: C206.1 Q40.C R453.2 R460.2 R465.2
BKLT_EN1: Q40.B R467.2
BOOT_HALT_N: R532.1 R540.2 XDP1.36
BQ24737_CSON_1: PC187.1 PC189.2 PG4.1 PR234.2
BQ24737_CSOP_1: PC188.1 PC189.1 PG5.1 PR233.2
BQ24737_REGN: PC120.2 PD2.A PR226.1 U34.16
BT+: BAT2.1 BAT2.2 PC100.1 PC101.1 PC102.1 PC103.1 PC104.1 PC105.1 PG4.2 PR145.2 PU9.5 PU9.6 PU9.7 PU9.8
BT+_R: PG5.2 PL12.2 PR145.1
BUFRST_N: GPU1.D11 R675.1
BUZZER_SPKR_R: C187.1 R388.1
BVCCRTC_EXTPAD: C26.1 CPU1.AG51
C_GPP_TXN2: C41.1 CPU1.L1
C_GPP_TXP2: C40.1 CPU1.L2
CAGND: C198.2 C201.2 C202.2 C498.2 C501.1 C504.2 C507.2 C513.2 C515.2 R449.2 R455.2 R775.2 R785.2 R786.2 R792.2 U35.15 U35.21
CBN: C485.2 U16.21
CBP: C485.1 U16.24
CFG: R423.2 U20.23
CHG_AGND: PC179.2 PC180.2 PC181.2 PC183.2 PC186.2 PC187.2 PC188.2 PQ8.1 PQ8.4 PR144.2 PR148.2 PR224.2 PR229.2
CHG_ON#: PQ19.G PR228.2 U14.28
CHG_SMB2_CLK: R714.1 RN12.3(B) U14.70 U34.9
CHG_SMB2_DATA: R717.1 RN12.4(B) U14.69 U34.8
CK_25M_SIO: R98.2 U14.2
CK_GLAN_DN: CPU1.B8 U26.16
CK_GLAN_DP: CPU1.A7 U26.15
CK_M_DDR0_A_DN: CPU1.BE45 DIMM1.103
CK_M_DDR0_A_DP: CPU1.BD45 DIMM1.101
CK_M_DDR1_A_DN: CPU1.BD48 DIMM1.104
CK_M_DDR1_A_DP: CPU1.BB48 DIMM1.102
CK_PCIEX1_WLAN_DN: CPU1.B5 R33.2
CK_PCIEX1_WLAN_DP: CPU1.B7 R36.2
CK_PE_100M_16PORT_DN: CPU1.B11 GPU1.AD8
CK_PE_100M_16PORT_DP: CPU1.C11 GPU1.AE8
CLINK_CLK_LAN: NGFF1.42 TP11.1
CLINK_DATA_LAN: NGFF1.40 TP14.1
CLINK_RST_LAN_N: NGFF1.38 TP13.1
CLKA0: GPU1.D24 R684.1 R686.1 VRAM2.J7 VRAM4.J7
CLKA0#: GPU1.D25 R683.1 R684.2 VRAM2.K7 VRAM4.K7
CLKA0_AND: C450.1 R683.2 R686.2
CLKA1: GPU1.N22 R259.1 R261.1 VRAM1.J7 VRAM3.J7
CLKA1#: GPU1.M22 R257.1 R259.2 VRAM1.K7 VRAM3.K7
CLKA1_AND: C77.1 R257.2 R261.2
CORE_PLLVDD: C411.1 C416.1 C417.1 GPU1.L6 L22.2
CPU_FAN_CTRL_SIO: R79.1 U14.81
CPU_FAN_TACH_SIO: R76.1 U14.31
CPU_HPD: CPU1.P48 Q10.D R179.1
CPU_LVDS_BL_ADJ: R136.2 R142.1 R149.2 R233.1
CPVEE: C167.1 U16.20
CX_PMODE_PLRST_N: R541.2 XDP1.7
DACA_VDD: GPU1.W5
DACA_VREF: C76.1 GPU1.AE2
DBG0: CPU1.A38 R55.1
DBG1: CPU1.B33 XDP1.19
DBG2: CPU1.C39 XDP1.21
DBG3: CPU1.B39 XDP1.23
DBG4: CPU1.B35 XDP1.25
DBG5: CPU1.A34 XDP1.27
DBG6: CPU1.B31 XDP1.29
DBG7: CPU1.H39 RN1.3(B)
DBG7_R: RN1.2(A) XDP1.31
DBG16: CPU1.B29 RN1.4(B)
DBG16_R: RN1.1(A) XDP1.33
DBG_H_PRDY_N: R544.2 XDP1.11
DBG_H_PREQ_N: R556.1 XDP1.10
DBG_H_TCK: R563.2 XDP1.3
DBG_H_TDI: R559.2 XDP1.5
DBG_H_TDO: R561.1 XDP1.4
DBG_H_TMS: R564.1 XDP1.2
DBG_H_TRST_N: R560.2 XDP1.9
DBG_I2C_SCL_LB: R21.1 XDP1.48
DBG_I2C_SDA_LB: R18.1 XDP1.50
DBG_PMU_PLTRST_N: R35.1 XDP1.38
DBG_PMU_PWRBTN_N: C7.1 R31.1 XDP1.40
DBG_PMU_RSTBTN_N: C9.1 R40.1 XDP1.6 XDP1.34
DBG_PTI_CLK0: R55.2 XDP1.13
DBG_RSMRST_N: R28.1 XDP1.42
DBG_TARGET_PRESENT_N: R43.1 R48.2 R51.2 XDP1.15
DBG_UART_RXD: R23.1 XDP1.56
DBG_UART_TXD: R22.1 XDP1.54
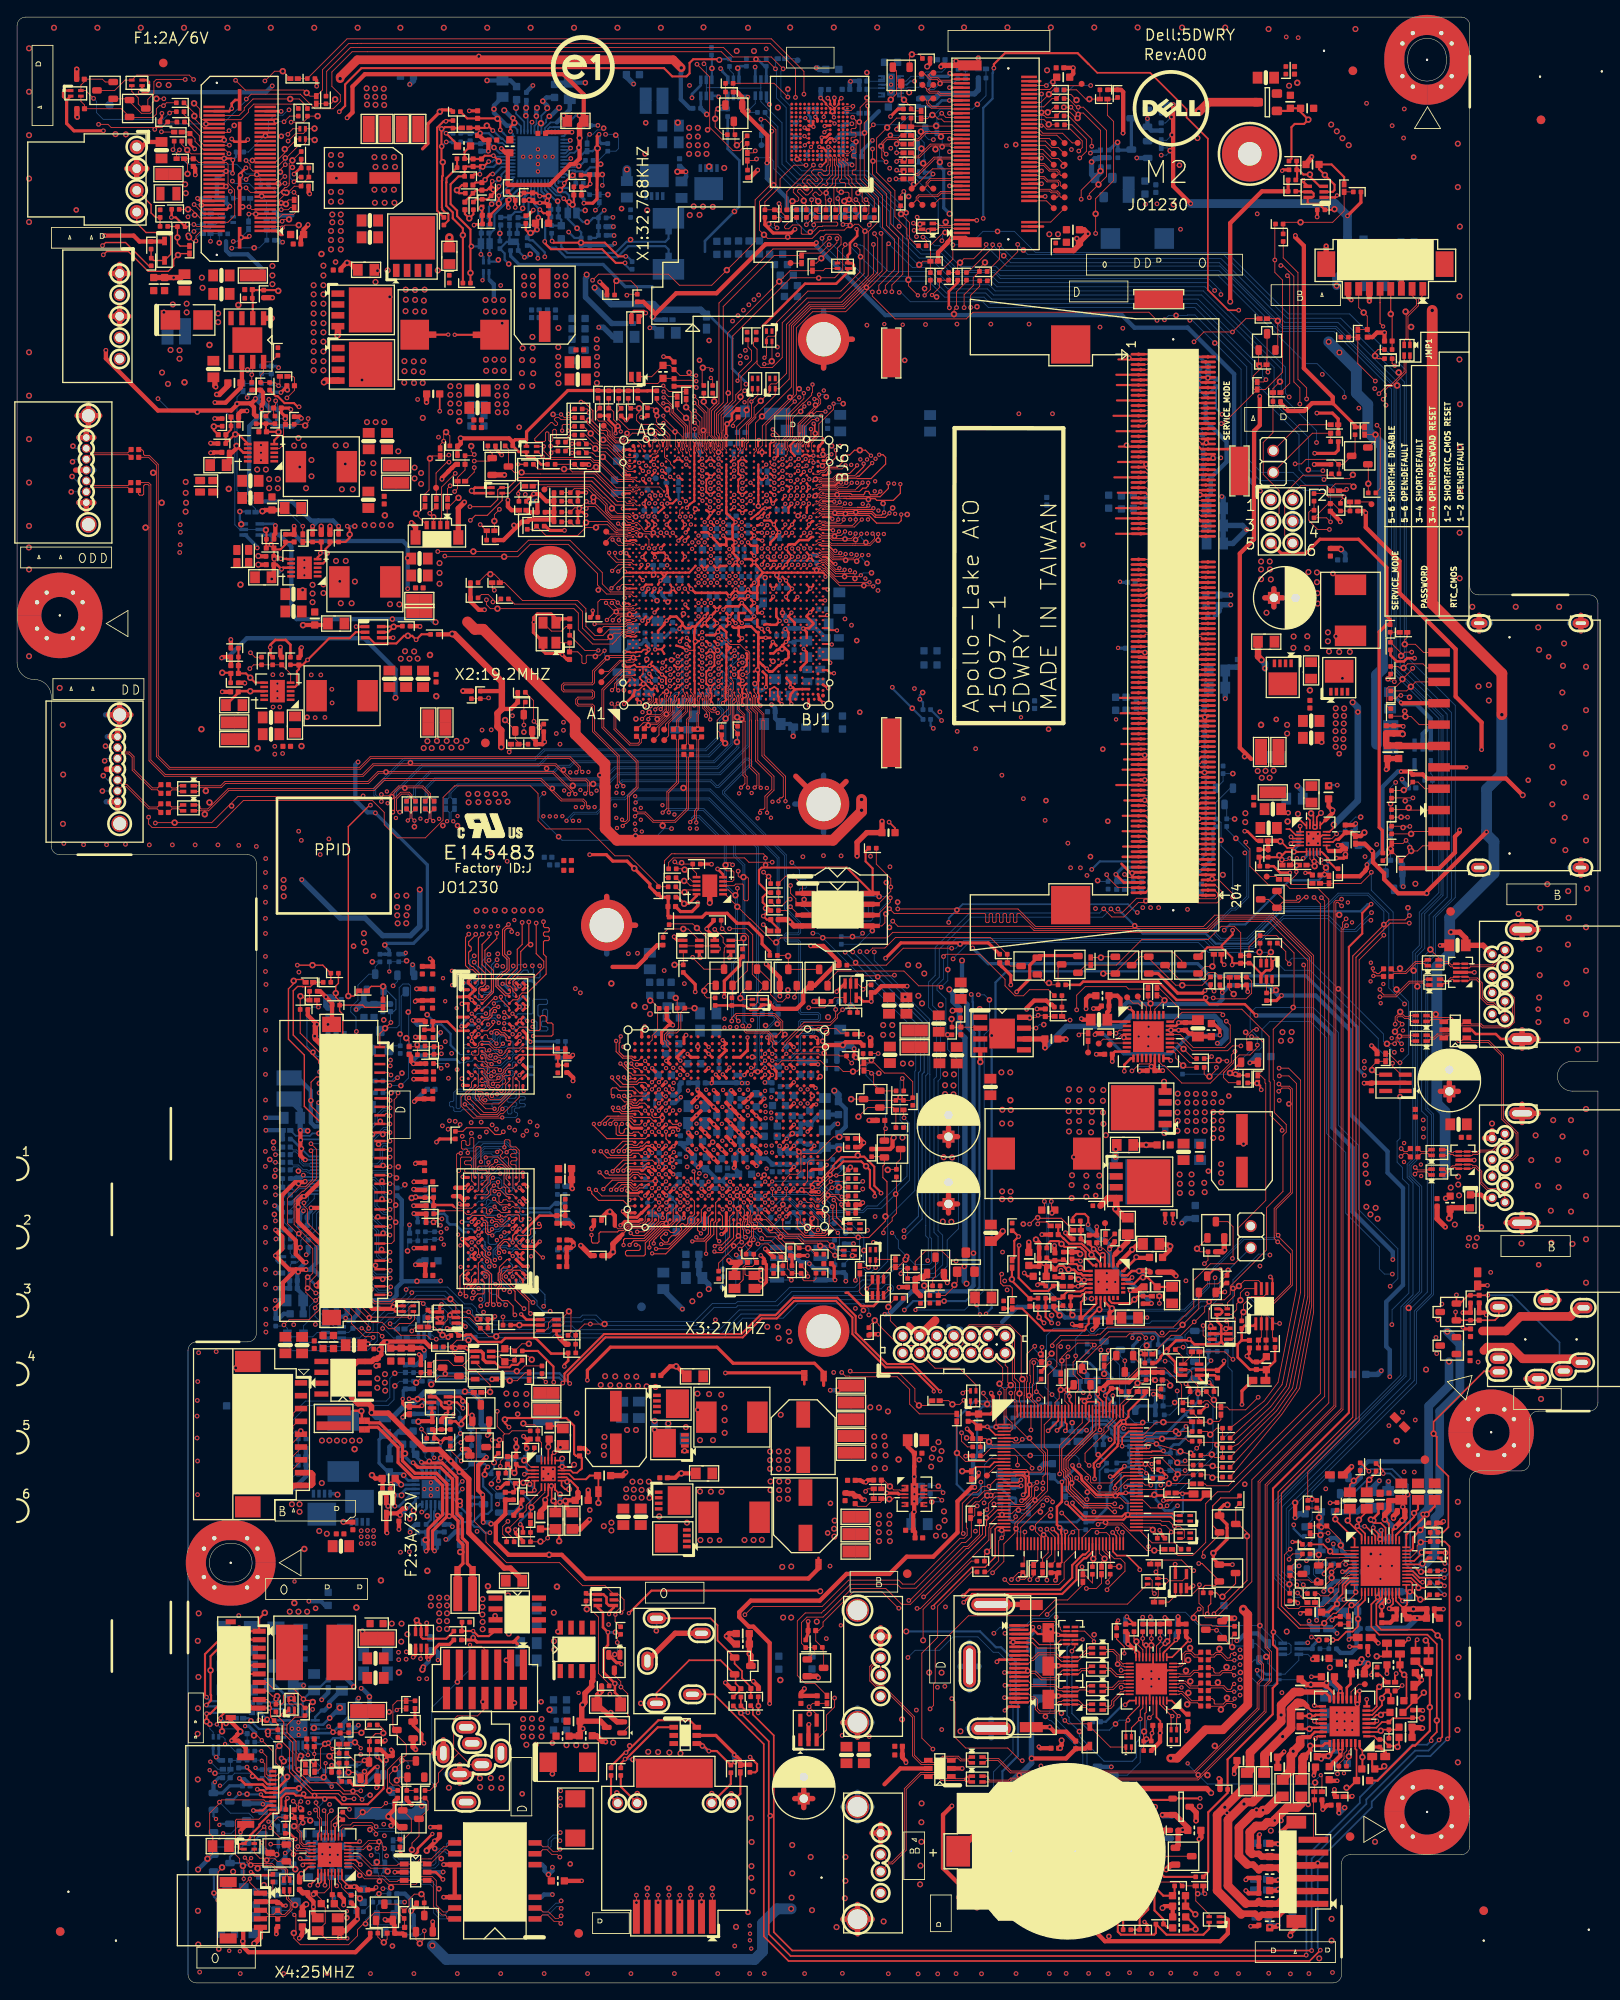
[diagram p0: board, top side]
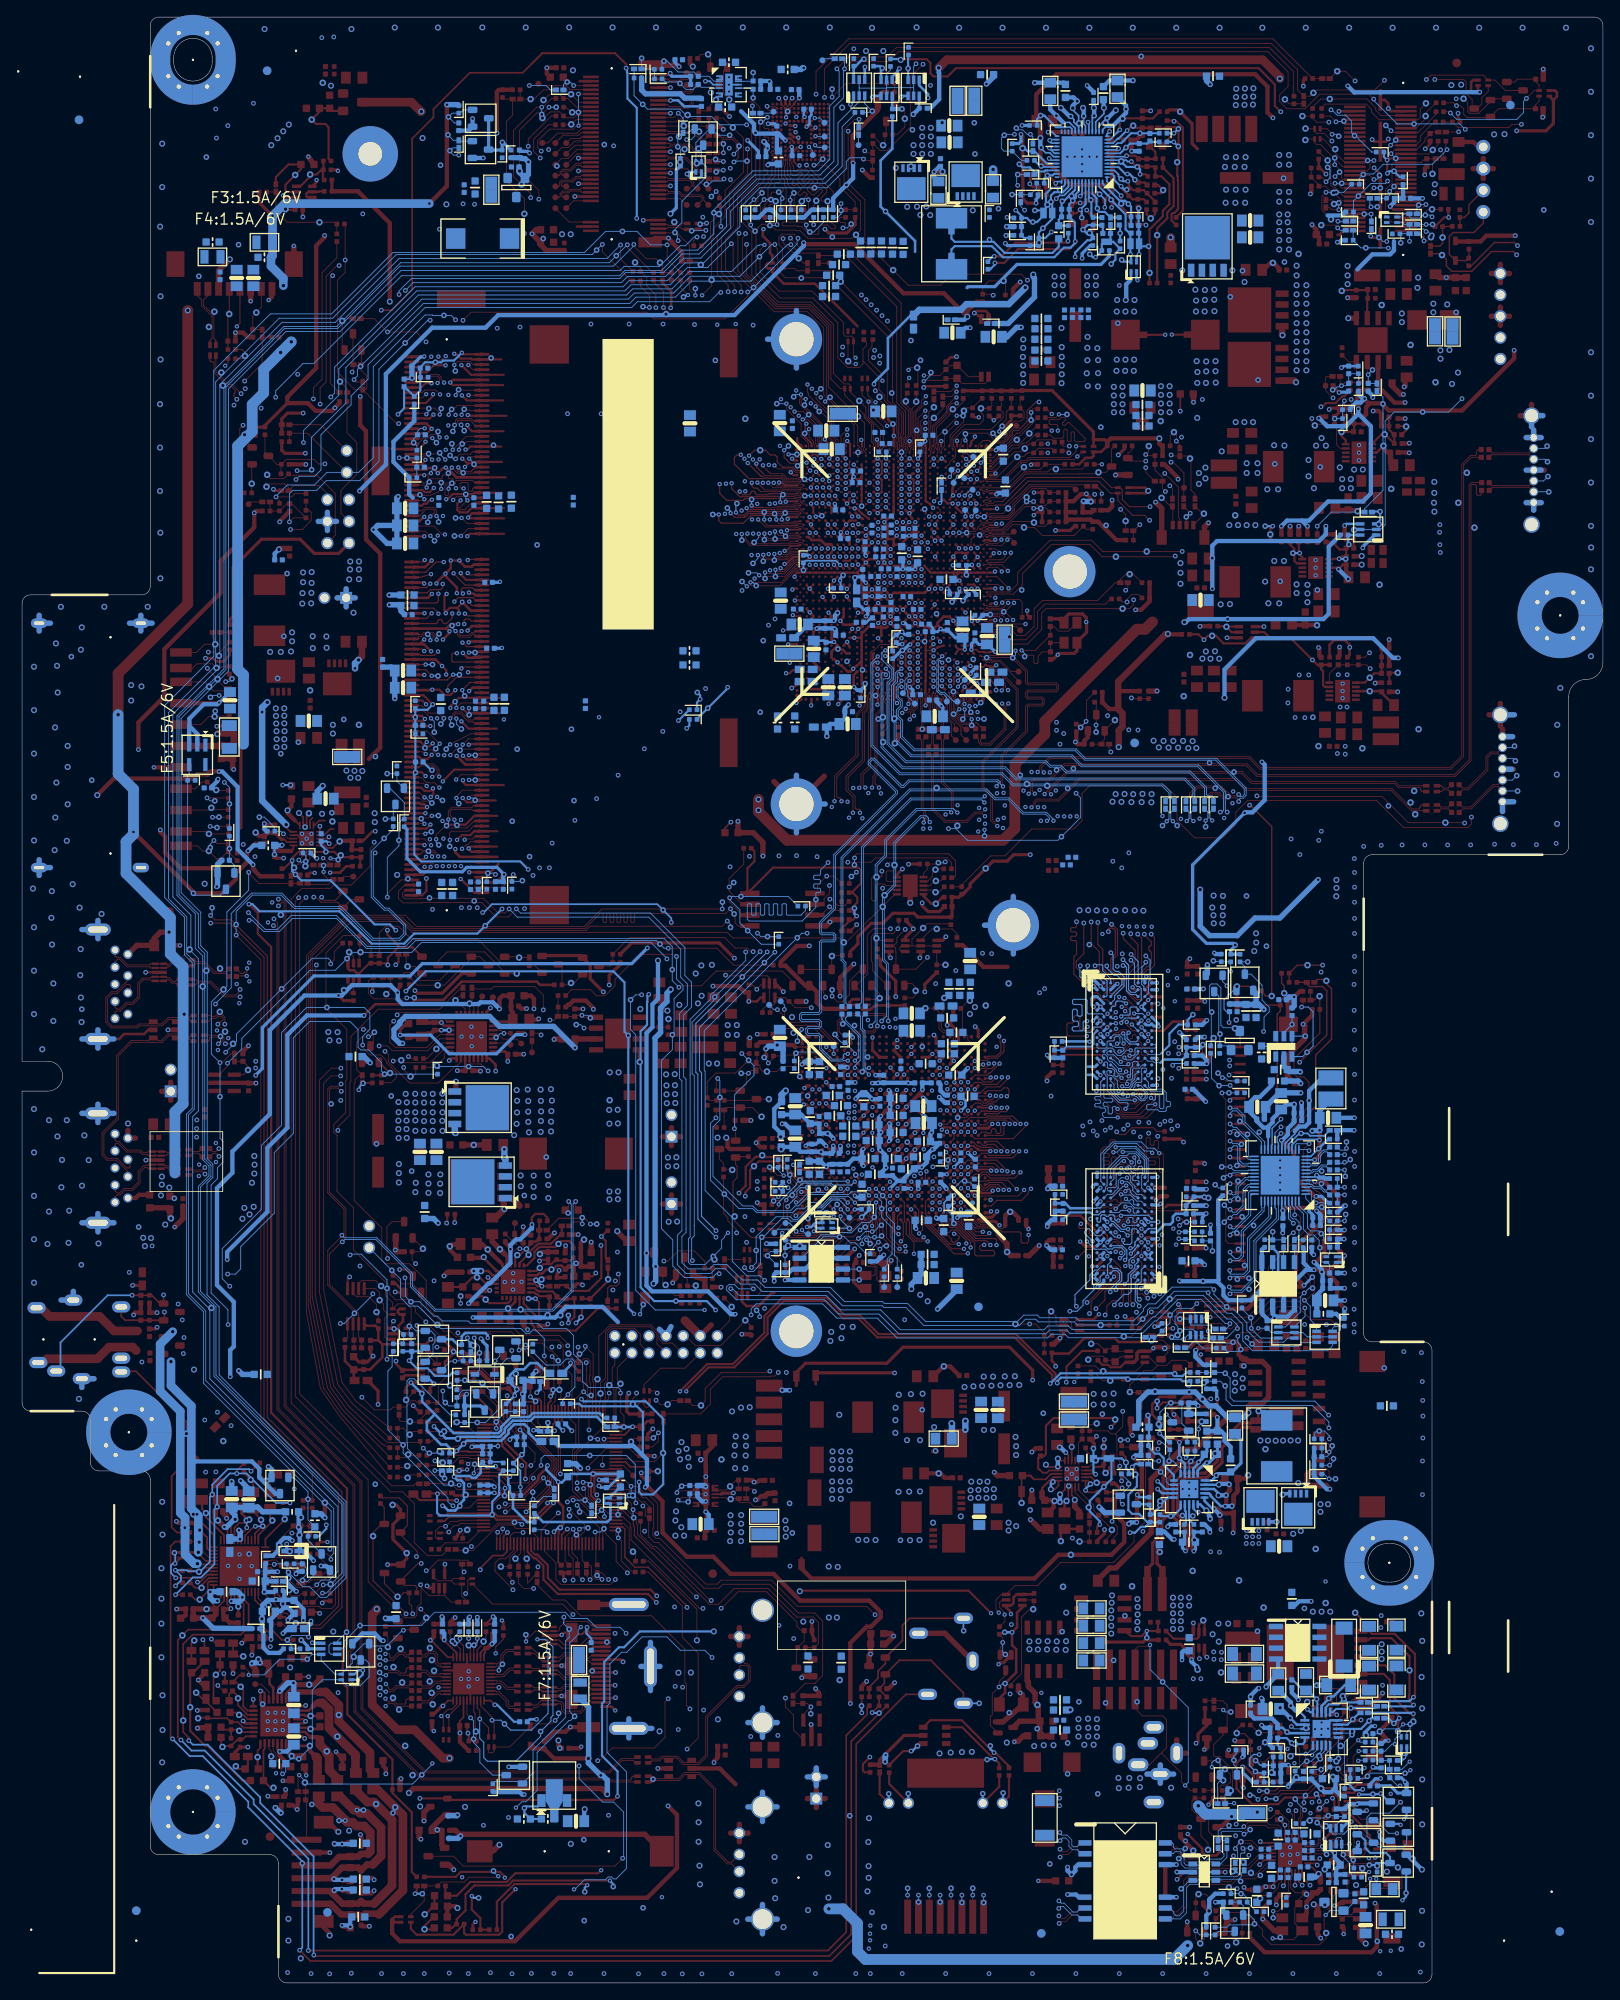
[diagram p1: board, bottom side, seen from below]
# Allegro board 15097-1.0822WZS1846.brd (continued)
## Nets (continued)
DC_19V: PC107.2 PR129.1 PR131.1 PR177.1 PR221.1 PR222.1 PU9.4 PU11.5 PU11.6 PU11.7 PU11.8 PU12.5 PU12.6 PU12.7 PU12.8 R409.1 R751.1 R753.1 R758.1 R762.1
DC_IN_D: PQ13.3 PR177.2
DCBATOUT: C93.1 C128.1 C129.1 C130.1 C494.1 C553.1 C554.1 C555.1 C556.1 C557.1 C558.1 C559.1 C560.1 C561.1 C562.1 C563.1 F2.1 L9.1 PC86.1 PC107.1 PC123.1 PC124.1 PC173.1 PC174.1 PC190.1 PG9.1 PR5.1 PR6.1 PR7.1 PR8.1 PR138.1 PR141.1 PR143.1 PR173.2 PR184.1 PR185.1 PR217.1 PR219.1 PRT1.1 PRT2.1 PT4.1 PU8.5 PU8.6 PU8.7 PU8.8 PU9.1 PU9.2 PU9.3 PU17.5 PU17.6 PU17.7 PU17.8 PU19.5 PU19.6 PU19.7 PU19.8 R50.1 R53.1 R425.1
DCBATOUT_RT6575: PC177.1 PC178.1 PC196.1 PCB1.1 PCT1.1 PQ11.5 PQ11.6 PQ11.7 PQ11.8 PQ18.5 PQ18.6 PQ18.7 PQ18.8 PR141.2 PR143.2 PR168.1 PR217.2 PR219.2 PT6.1
DCBATOUT_RT6575_1: PC118.1 PR168.2 PU10.12
DCIN_EN: R422.2 U20.13
DDCBUF: R418.2 R754.1 U20.14
DDI0_RCOMP_N: CPU1.AG2 R182.1
DDI0_RCOMP_P: CPU1.AG1 R182.2
DDPC_CTRL_CLK_CONN: HDMI1.15 HDMI2.5 RN36.4(B) U18.1 U18.10 U20.32
DDPC_CTRL_DATA_CONN: HDMI1.16 HDMI2.4 RN36.3(B) U18.2 U18.9 U20.33
DDR3_DRAMRST_N: C285.1 CPU1.AR34 R585.1 R586.2
DDR3_DRAMRST_N_A_1: C281.1 DIMM1.30 R585.2
DDR_VDDQ: C289.2 C290.2 C291.2 C292.2 C293.2 C311.2 C314.2 C316.2 C321.2 C329.2 C332.2 C335.2 C336.2 C337.2 C338.2 C339.2 C549.1 C550.1 C551.1 C552.1 CPU1.AN18 CPU1.AN20 CPU1.AN22 CPU1.AN23 CPU1.AN41 CPU1.AN42 CPU1.AN44 CPU1.AN46 CPU1.AR17 CPU1.AR47 CPU1.AT13 CPU1.AT17 CPU1.AT47 CPU1.AT51 CPU1.AV14 CPU1.AV50 DIMM1.75 DIMM1.76 DIMM1.81 DIMM1.82 DIMM1.87 DIMM1.88 DIMM1.93 DIMM1.94 DIMM1.99 DIMM1.100 DIMM1.105 DIMM1.106 DIMM1.111 DIMM1.112 DIMM1.117 DIMM1.118 DIMM1.123 DIMM1.124 EC1.1 EC2.1 PC43.1 PC77.1 PC150.1 PC151.1 PC154.1 PC155.1 PC156.1 PC157.1 PC158.1 PC159.1 PC160.1 PC165.1 PC168.1 PL4.2 PR82.2 PR211.1 PTC1.1 PU6.5 PU6.9 R581.1 R586.1 R599.1 R602.1 R610.1 R620.1
DDSP_C_HPD_CONN: HDMI1.19 HDMI2.1 U18.4 U18.7 U20.28
DFX_MSR_STRAP: R38.2 XDP1.17
DGPU_PWR_EN#: Q12.2 Q12.5 Q13.2 Q13.3 R211.1
DIGITAL_PU: D9.K L24.2 R757.1
DIMM1_SA0: DIMM1.197 R630.1
DIMM1_SA1: DIMM1.201 R629.1
DISCHANGE_EN: R269.1 U14.27
DP1_AUXN: C442.1 R622.2 R672.2
DP1_AUXP: C438.1 R621.2 R664.1
DP1_HPD: Q10.G R183.2 R184.1
DP1_TXN0: C423.1 R189.2 R624.2
DP1_TXN1: C415.1 R187.2 R626.2
DP1_TXP0: C431.1 R190.2 R623.2
DP1_TXP1: C418.1 R188.2 R625.2
DP_AUXN: NGFF1.20 TP22.1
DP_AUXP: NGFF1.22 TP23.1
DP_CPU_AUXN: CPU1.AH9 R622.1
DP_CPU_AUXP: CPU1.AH10 R621.1
DP_CPU_TXN0: CPU1.AG9 R624.1
DP_CPU_TXN1: CPU1.AG10 R626.1
DP_CPU_TXN2: CPU1.AC5 R189.1
DP_CPU_TXN3: CPU1.AC9 R187.1
DP_CPU_TXP0: CPU1.AG7 R623.1
DP_CPU_TXP1: CPU1.AG12 R625.1
DP_CPU_TXP2: CPU1.AC6 R190.1
DP_CPU_TXP3: CPU1.AC7 R188.1
DP_HPD: NGFF1.31 TP19.1
DP_ML0N: NGFF1.32 TP15.1
DP_ML0P: NGFF1.34 TP16.1
DP_ML1N: NGFF1.26 TP17.1
DP_ML1P: NGFF1.28 TP18.1
DP_ML2N: NGFF1.25 TP21.1
DP_ML2P: NGFF1.27 TP20.1
DP_ML3N: NGFF1.19 TP25.1
DP_ML3P: NGFF1.21 TP24.1
DPLVDS_AUXN: C442.2 U31.3
DPLVDS_AUXP: C438.2 U31.4
DPLVDS_BL_EN: R463.2 U14.26 U31.44
DPLVDS_EDIDCLK: C451.1 R687.2 R688.2 U31.46
DPLVDS_EDIDCLK_C: R688.1 U33.6
DPLVDS_EDIDSDA: C452.1 R689.2 R690.2 U31.45
DPLVDS_EDIDSDA_C: R689.1 U33.5
DPLVDS_FWCLK: C453.1 RN41.3(B) U31.48
DPLVDS_FWSDA: C457.1 RN41.4(B) U31.47
DPLVDS_HPD: R680.1 U31.1
DPLVDS_HPD_1: R183.1 R680.2 R682.1 R685.1
DPLVDS_ISPCLK: Q60.4 Q62.1 RN35.3(B) U31.13
DPLVDS_ISPDAT: Q60.1 Q61.1 RN35.4(B) U31.14
DPLVDS_PANEL_VCC: R236.1 R642.2 R5501.1 U31.20
DPLVDS_PIN12: R658.1 U31.12
DPLVDS_PIN16: R657.2 U31.16
DPLVDS_PWMIN: R224.2 R244.1 R245.1 U31.21
DPLVDS_PWMOUT: R230.2 U31.19
DQMA0: GPU1.D19 VRAM4.E7
DQMA1: GPU1.D14 VRAM4.D3
DQMA2: GPU1.C17 VRAM2.D3
DQMA3: GPU1.C22 VRAM2.E7
DQMA4: GPU1.P24 VRAM3.E7
DQMA5: GPU1.W24 VRAM3.D3
DQMA6: GPU1.AA25 VRAM1.D3
DQMA7: GPU1.U25 VRAM1.E7
DRX0N: C423.2 U31.8
DRX0P: C431.2 U31.7
DRX1N: C415.2 U31.10
DRX1P: C418.2 U31.9
EAPD_DEPOP: R426.1 U16.14
EAPD_DEPOP_1: R426.2 R759.1 R760.1
EAPD_DEPOP_2: Q69.2 R760.2
EC_AGND: C135.1 C136.2 C137.2 C464.2 C467.1 R344.2 R718.2 R721.2 U14.103
EC_AVCC: C137.1 C464.1 R349.1 R713.1 R720.1 U14.102
EC_BEEP_GPIO: Q2801.G R2401.1
EC_BEEP_GPIO_EC: R2401.2 U14.79
EC_DEBUG: EC_DEBUG1.2 U14.111
EC_HDMI_PD_N: Q71.G R791.2 U14.109
EC_IMS: R400.2 U14.35
EC_PECI: TP52.1 U14.13
EC_SCI#: R3.1 R4.2 R743.2
EC_SMB_DATA: R2403.1 U14.120
EC_SMI#: R130.2 R131.1 R357.2
EC_SPI_CLK: R361.1 U14.92
EC_SPI_CS0_N: R366.1 U14.90
EC_SPI_SI: R369.1 U14.87
EC_SPI_SO: R374.2 U14.86
EC_SWI#: R164.2 R166.1 R341.2
EC_V_3P3_A: C463.1 Q63.S R380.2 R706.2 R715.2 R716.1 R732.1 R733.1
EC_VBKUP: R724.1 U14.114
EC_VCC1V8_S5: C134.1 R348.1 R722.1 R726.2 R728.1 U13.1 U14.88
EC_VCC3: C126.1 C132.1 C133.1 Q32.2 Q32.5 R328.1 R335.1 R337.1 R343.2 R347.2 R723.1 R729.1 RN9.1(A) RN9.2(A) U12.1 U13.6 U17.5
EC_VDD3D3: C139.1 C140.1 R722.2 R723.2 U14.4
EC_VSBY: R380.1 U14.75
EC_VTT: R376.2 U14.12
ECRST#: C466.1 Q65.E R373.1 R719.2 U14.85
ECSCI#_KBC: R743.1 U14.29
ECSMI#_KBC: R357.1 U14.11
ECSWI#_KBC: R341.1 U14.123
EDID_WC#: R810.2 R812.1 U33.7
EDID_WC_EC#: R810.1 U14.113
EDP_RCOMP_N: CPU1.AG5 R181.2
EDP_RCOMP_P: CPU1.AG6 R181.1
EMMC_CLK: CPU1.Y58 R70.1
EMMC_CLK_R: R70.2 U1.M6
EMMC_CMD: CPU1.Y51 R61.1 R554.1
EMMC_CMD_R: R61.2 U1.M5
EMMC_DATA_0: CPU1.V58 R67.2 R548.1
EMMC_DATA_0_R: R67.1 U1.A3
EMMC_DATA_1: CPU1.T58 R65.2 R550.1
EMMC_DATA_1_R: R65.1 U1.A4
EMMC_DATA_2: CPU1.T59 R63.2 R551.1
EMMC_DATA_2_R: R63.1 U1.A5
EMMC_DATA_3: CPU1.V51 R69.2 R557.1
EMMC_DATA_3_R: R69.1 U1.B2
EMMC_DATA_4: CPU1.V52 R68.2 R547.1
EMMC_DATA_4_R: R68.1 U1.B3
EMMC_DATA_5: CPU1.Y49 R66.2 R549.1
EMMC_DATA_5_R: R66.1 U1.B4
EMMC_DATA_6: CPU1.V55 R64.2 R552.1
EMMC_DATA_6_R: R64.1 U1.B5
EMMC_DATA_7: CPU1.V57 R62.2 R553.1
EMMC_DATA_7_R: R62.1 U1.B6
EMMC_E9: TP60.1 U1.E9
EMMC_E10: TP59.1 U1.E10
EMMC_F10: TP57.1 U1.F10
EMMC_K10: TP56.1 U1.K10
EMMC_RCLK: CPU1.V54 R60.1
EMMC_RCLK_R: R59.1 R60.2 U1.H5
EMMC_RCOMP: CPU1.V59 R583.2
EMMC_RESET#: Q5.S R7.1 R11.2 R32.1
EMMC_RESET#_R: R7.2 U1.K5
EMMC_VDDI: C248.2 U1.C2
EQ: R420.2 R756.1 U20.17
F_USB0N: CPU1.V10 TR3.2
F_USB0N_H: CPU1.AC10 TR2.3
F_USB0P: CPU1.V12 TR3.3
F_USB0P_H: CPU1.AC12 TR2.2
F_USB1N: CPU1.V15 TR4.2
F_USB1N_H: CPU1.Y10 TR1.3
F_USB1P: CPU1.V16 TR4.3
F_USB1P_H: CPU1.Y9 TR1.2
F_USB2N: CPU1.V7 TR9.3
F_USB2N_H: CPU1.V6 TR11.3
F_USB2P: CPU1.V9 TR9.2
F_USB2P_H: CPU1.V5 TR11.2
F_USB3N: CPU1.V13 TR10.2
F_USB3P: CPU1.Y13 TR10.3
FB_CAL_PD_VDDQ: GPU1.D22 R671.1
FB_CAL_PU_GND: GPU1.C24 R301.1
FB_CAL_TERM_GND: GPU1.B25 R293.1
FB_PLLAVDD: C350.1 C387.1 C412.1 C434.1 C436.1 GPU1.F16 GPU1.H22 GPU1.P22 L17.1
FB_VREF: GPU1.D23 TP77.1
FBA_CMD0: GPU1.C27 VRAM2.L2 VRAM4.L2
FBA_CMD2: GPU1.E24 PR101.1 VRAM2.K1 VRAM4.K1
FBA_CMD3: GPU1.F24 PR216.1 VRAM2.K9 VRAM4.K9
FBA_CMD4: GPU1.D27 VRAM1.T7 VRAM2.T7 VRAM3.T7 VRAM4.T7
FBA_CMD5: GPU1.D26 PR95.1 VRAM1.T2 VRAM2.T2 VRAM3.T2 VRAM4.T2
FBA_CMD6: GPU1.F25 VRAM1.R3 VRAM2.R3 VRAM3.R3 VRAM4.R3
FBA_CMD7: GPU1.F26 VRAM1.R2 VRAM2.R2 VRAM3.R2 VRAM4.R2
FBA_CMD8: GPU1.F23 VRAM1.P3 VRAM2.P3 VRAM3.P3 VRAM4.P3
FBA_CMD9: GPU1.G22 VRAM1.N3 VRAM2.N3 VRAM3.N3 VRAM4.N3
FBA_CMD10: GPU1.G23 VRAM1.P8 VRAM2.P8 VRAM3.P8 VRAM4.P8
FBA_CMD11: GPU1.G24 VRAM1.P7 VRAM2.P7 VRAM3.P7 VRAM4.P7
FBA_CMD12: GPU1.F27 VRAM1.M2 VRAM2.M2 VRAM3.M2 VRAM4.M2
FBA_CMD13: GPU1.G25 VRAM1.L3 VRAM2.L3 VRAM3.L3 VRAM4.L3
FBA_CMD15: GPU1.G26 VRAM1.K3 VRAM2.K3 VRAM3.K3 VRAM4.K3
FBA_CMD16: GPU1.M24 VRAM1.L2 VRAM3.L2
FBA_CMD18: GPU1.K24 PR94.1 VRAM1.K1 VRAM3.K1
FBA_CMD19: GPU1.K23 PR214.1 VRAM1.K9 VRAM3.K9
FBA_CMD20: GPU1.M27 VRAM1.T3 VRAM2.T3 VRAM3.T3 VRAM4.T3
FBA_CMD21: GPU1.M26 VRAM1.T8 VRAM2.T8 VRAM3.T8 VRAM4.T8
FBA_CMD22: GPU1.M25 VRAM1.R8 VRAM2.R8 VRAM3.R8 VRAM4.R8
FBA_CMD23: GPU1.K26 VRAM1.R7 VRAM2.R7 VRAM3.R7 VRAM4.R7
FBA_CMD24: GPU1.K22 VRAM1.P2 VRAM2.P2 VRAM3.P2 VRAM4.P2
FBA_CMD25: GPU1.J23 VRAM1.N2 VRAM2.N2 VRAM3.N2 VRAM4.N2
FBA_CMD26: GPU1.J25 VRAM1.M3 VRAM2.M3 VRAM3.M3 VRAM4.M3
FBA_CMD27: GPU1.J24 VRAM1.N8 VRAM2.N8 VRAM3.N8 VRAM4.N8
FBA_CMD28: GPU1.K27 VRAM1.N7 VRAM2.N7 VRAM3.N7 VRAM4.N7
FBA_CMD29: GPU1.K25 VRAM1.L7 VRAM2.L7 VRAM3.L7 VRAM4.L7
FBA_CMD30: GPU1.J27 VRAM1.J3 VRAM2.J3 VRAM3.J3 VRAM4.J3
FBA_DEBUG0: GPU1.F22 R666.1
FBA_DEBUG1: GPU1.J22 R659.1
FWH_ID0: LPC1.6 R332.2
GC6_FB_EN: GPU1.C6 TP78.1
GLAN_WAKE_CPU: CPU1.P61 Q42.C RN39.4(B)
GLAN_WAKE_N: Q42.E R798.1 U26.21
GLAN_WAKE_N_LS: Q42.B RN39.3(B)
GP_SPI0_FS1: CPU1.H52 R532.2
GPIO1_FBVDDQCTL: GPU1.B2 TP81.1
GPIO2_BL_PWM: GPU1.D6 RN30.2(A)
GPIO3_PPEN_R: GPU1.C7 R677.1
GPIO4_BLEN: GPU1.F9 RN30.1(A)
GPIO5_PWM_VID_BOOT_EN: GPU1.A3 TP79.1
GPIO6_FB_CLAMP_TGL_REQ: GPU1.A4 TP80.1
GPIO7_3D_STEREO: GPU1.B6 RN38.1(A)
GPIO8_OVERT#: GPU1.A6 Q25.S R278.1
GPIO9_ALERT#: GPU1.F8 PR127.1 R290.1
GPIO10_MEM_VREF_CTL: GPU1.C5 RN38.2(A)
GPIO11_PWM_VID: GPU1.E7 PR102.2
GPIO12_AC_DETECT: GPU1.D7 R288.1
GPIO13_NVVDD_PSI: GPU1.B4 R295.1
GPIO34_CPU: CPU1.B41 TP35.1
GPIO35_CPU: CPU1.C41 TP34.1
GPIO36_VCCIO_LEVEL: CPU1.F41 R160.2 R161.1
GPIO39_TXE_BPS: CPU1.B45 R144.2 R145.1
GPIO40_CPU: CPU1.A46 TP32.1
GPIO43_EMMC_BOOT: CPU1.B43 R22.2 R157.2 R158.1
GPIO44_SPI_BOOT: CPU1.A42 R162.2 R163.1
GPIO47_DNXFW: CPU1.H41 R147.2 R148.1 R153.1
GPIO48_CPU: CPU1.L41 R152.1 TP31.1
GPIO78_SMB_LEVEL: CPU1.K62 R103.2 R115.1
GPIO82_CPU: CPU1.M55 TP63.1
GPIO88_PMU_LEVEL: CPU1.M58 R105.2 R116.1
GPIO92_SMB_NRB: CPU1.L63 R104.2 R114.1
GPIO104_CPU: CPU1.F54 TP64.1
GPIO105_CPU: CPU1.F52 TP66.1
GPIO110_LPC_LEVEL: CPU1.J52 R137.2 R138.1
GPIO111_BBS: CPU1.F58 R101.2 R113.1
GPIO112_CPU: CPU1.K55 TP65.1
GPIO113_CPU: CPU1.F61 TP30.1
GPIO117_CPU: CPU1.H58 TP62.1
GPIO118_FLASH_OVR: CPU1.F62 Q7.C R125.2 R139.1 R140.2
GPIO120_BIOS_SWAP: CPU1.E56 R102.2 R112.1
GPIO121_CPU: CPU1.D59 TP61.1
GPIO123_CPU: CPU1.E62 R48.1
GPIO_11_SCI: CPU1.C34 R4.1
GPIO_12_SWI: CPU1.E39 R164.1
GPIO_FB_CLAMP_GPU: GPU1.F3 PR97.1
GPIO_RCOMP: CPU1.E34 R590.2
GPU_1D05V: PC79.1 PC80.1 PC82.1 PC83.1 PR91.2 PR92.1 PR93.2 PU6.3 PU6.4
GPU_1D05V_EN: PC78.1 PR90.1 PU6.8
GPU_1D05V_FB: PC80.2 PR89.1 PR92.2 PU6.2
GPU_1D05V_PG: PC59.1 PR64.2 PR76.2 PU4.5 PU6.7
GPU_1D05V_VGA_EN: PR88.2 PR90.2 PR121.1 R250.2
GPU_ALLPWR: CPU1.C33 Q9.3 R173.2
GPU_DMINUS: R698.1 TP82.1
GPU_DMINUS_G: GPU1.E12 R698.2
GPU_DPLUS: R699.1 TP83.1
GPU_DPLUS_G: GPU1.F12 R699.2
GPU_PEX_RST_HOLD: D3.1 R275.1 R276.2
GPU_PEX_RST_HOLD_GPU#: GPU1.C4 R275.2
GPU_TESTMODE: GPU1.AD9 R644.1
GPU_THERM_SHUTDOWN_N: PR106.1 TP51.1
GPU_VCC3_CTL: C120.2 Q26.G R315.2 R321.2
GPU_VCC3_CTL_2: C122.1 Q27.G R317.2
GPU_WAKEB_CPU: CPU1.R62 R222.2
H_PROCHOT_N_EC: Q38.G R428.1 R429.1 RN40.1(A) U14.24
HDM2_CPU_HPD: CPU1.C50 Q8.D R133.1
HDMI1_DATA_IC_N0: C188.2 U20.2
HDMI1_DATA_IC_N1: C182.2 U20.5
HDMI1_DATA_IC_N2: C177.2 U20.7
HDMI1_DATA_IC_N3: C174.2 U20.10
HDMI1_DATA_IC_P0: C192.2 U20.1
HDMI1_DATA_IC_P1: C186.2 U20.4
HDMI1_DATA_IC_P2: C179.2 U20.6
HDMI1_DATA_IC_P3: C176.2 U20.9
HDMI2_HPD: Q8.G R132.1 U20.3
HDMI_CTRL_CLK: Q9201.D R9201.1 RN25.4(B) U20.38
HDMI_CTRL_CLK_CPU: CPU1.B49 Q9201.S R9201.2 RN8.3(B)
HDMI_CTRL_DATA: Q9202.D R9202.1 RN25.3(B) U20.39
HDMI_CTRL_DATA_CPU: CPU1.C49 Q9202.S R9202.2 RN8.4(B)
HDMI_DATA_CPU_N0: C188.1 CPU1.AK2
HDMI_DATA_CPU_N1: C182.1 CPU1.AM2
HDMI_DATA_CPU_N2: C177.1 CPU1.AH2
HDMI_DATA_CPU_N3: C174.1 CPU1.AL1
HDMI_DATA_CPU_P0: C192.1 CPU1.AK3
HDMI_DATA_CPU_P1: C186.1 CPU1.AM3
HDMI_DATA_CPU_P2: C179.1 CPU1.AH3
HDMI_DATA_CPU_P3: C176.1 CPU1.AL2
HDMI_DP2_HPD: D6.K RN36.1(A) RN36.2(A)
HDMI_LANE0_DN: HDMI1.3 HDMI2.17 TR8.2 U21.2 U21.9
HDMI_LANE0_DP: HDMI1.1 HDMI2.19 TR8.3 U21.1 U21.10
HDMI_LANE0_IC_DN: TR8.1 U20.29
HDMI_LANE0_IC_DP: TR8.4 U20.30
HDMI_LANE1_DN: HDMI1.6 HDMI2.14 TR7.2 U21.5 U21.6
HDMI_LANE1_DP: HDMI1.4 HDMI2.16 TR7.3 U21.4 U21.7
HDMI_LANE1_IC_DN: TR7.1 U20.26
HDMI_LANE1_IC_DP: TR7.4 U20.27
HDMI_LANE2_DN: HDMI1.9 HDMI2.11 TR6.2 U19.4 U19.7
HDMI_LANE2_DP: HDMI1.7 HDMI2.13 TR6.3 U19.5 U19.6
HDMI_LANE2_IC_DN: TR6.1 U20.24
HDMI_LANE2_IC_DP: TR6.4 U20.25
HDMI_LANE3_DN: HDMI1.12 HDMI2.8 TR5.2 U19.1 U19.10
HDMI_LANE3_DP: HDMI1.10 HDMI2.10 TR5.3 U19.2 U19.9
HDMI_LANE3_IC_DN: TR5.1 U20.21
HDMI_LANE3_IC_DP: TR5.4 U20.22
HPOL_CON: C123.1 Q29.1 R326.1 R372.2 R384.2 R412.2 UHS1.1
HPOR_CON: C121.1 Q29.2 R319.1 R370.2 R406.2 R410.2 UHS1.2
HPOUT-JD: R389.1 UHS1.6
HPOUT-L: R412.1 U16.26
HPOUT-R: R410.1 U16.27
HSI_C_DN2: CPU1.M7 R37.2
HSI_C_DP2: CPU1.K7 R42.2
HSI_LAN_DN1_R: C219.1 U26.18
HSI_LAN_DN3: C219.2 CPU1.M6
HSI_LAN_DP1_R: C220.1 U26.17
HSI_LAN_DP3: C220.2 CPU1.M5
HSO_C_DN2: C41.2 R45.2
HSO_C_DP2: C40.2 R49.2
HSO_C_LAN_DN3: C47.2 U26.14
HSO_C_LAN_DP3: C46.2 U26.13
HSO_LAN_DN3: C47.1 CPU1.T3
HSO_LAN_DP3: C46.1 CPU1.T2
I2CC_SCL_PU: GPU1.A9 RN20.4(B)
I2CC_SDA_PU: GPU1.B9 RN20.3(B)
I2CS_SCL_G: GPU1.D9 R312.1 RN19.3(B)
I2CS_SDA_G: GPU1.D8 R306.1 RN19.4(B)
IFPA_IOVDD: GPU1.W6
IFPAB_PLLVDD_1: GPU1.V7
IFPAB_PLLVDD_2: GPU1.W7
IFPB_IOVDD: GPU1.Y6
IFPC_IOVDD: GPU1.P6
IFPC_PLLVDD_1: GPU1.M7
IFPC_PLLVDD_2: GPU1.N7
IFPD_IOVDD: GPU1.R6
IFPD_PLLVDD_1: GPU1.R7
IFPD_PLLVDD_2: GPU1.T7
IFPE_IOVDD: GPU1.H6
IFPEF_PLLVDD_1: GPU1.J7
IFPEF_PLLVDD_2: GPU1.K7
IFPF_IOVDD: GPU1.J6
IMS: LVDS1.4 R400.1 R633.1 R634.2
INIT_3V: LPC1.2 R325.2
INT_SERIRQ_CPU: CPU1.AB62 R235.1 R338.1 U13.3
INT_SERIRQ_OE: R348.2 R351.1 U13.5
INTRUDER: CPU1.AC54 R88.2 R89.1
ISEN1: R768.2 U35.17
ISEN2: R769.2 U35.16
ISEN3: R770.2 U35.14
ISEN4: R772.2 U35.13
ISET: R459.1 R464.2 U20.34
ISP_CLK1: Q62.3 Q62.6 R701.2
ISP_DAT1: Q61.3 Q61.6 R700.2
ISW: C498.1 R766.2 U35.19
ISW_1: Q68.1 Q68.2 Q68.3 R761.1 R764.1 R766.1
JACK_PSID: DCIN1.3 DCIN2.4 DCIN2.11 L16.1
JDREF: R387.1 U16.35
JTAG_TCLK: GPU1.AE5 R262.2
JTAG_TDI: GPU1.AE6 TP47.1
JTAG_TDO: GPU1.AF6 TP46.1
JTAG_TMS: GPU1.AD6 TP76.1
JTAG_TRST: GPU1.AG4 R255.2
KBC_ON#_GATE: C463.2 Q63.G Q64.G R703.2
KBC_ON#_GATE_L: R703.1 R705.2 R706.1
KBC_SPI_CLK: R360.1 R361.2 R362.1
KBC_SPI_CS0_N: R365.1 R366.2 R368.1
KBC_SPI_DATAIN: R374.1 R377.1
KBC_SPI_DATAOUT: R369.2 R371.1
KBC_VCC: C160.1 C468.1 C473.1 C474.1 C476.1 C477.1 R736.1 U14.19 U14.46 U14.76 U14.115
KBC_VCORF: C159.1 U14.44
LAD0_FWH0: CPU1.Y61 LPC1.5 U7.24 U14.126
LAD1_FWH1: CPU1.Y62 LPC1.7 U7.21 U14.127
LAD2_FWH2: CPU1.W62 LPC1.9 U7.18 U14.128
LAD3_FWH3: CPU1.W63 LPC1.11 U7.15 U14.1
LAN_DISABLE_N: R802.1 R804.1 R805.2 U14.63
LAN_DISABLE_N_1: C544.1 Q80.B R804.2 R807.1
LAN_DISABLE_N_2: Q44.B Q80.C R806.2 R807.2
LAN_DISABLE_N_3: Q43.C Q44.C R499.2 R502.1
LAN_DISABLE_N_4: C233.1 PC194.2 Q79.G R502.2
LAN_DISABLE_V3: C234.1 Q43.B R510.1
LAN_LEDACT_R#: RJ1.10 UR1.2
LAN_MDI0_C_DN: RJ1.2 XF1.2
LAN_MDI0_C_DP: RJ1.1 XF1.1
LAN_MDI0_DN: U26.2 U28.3 XF1.11
LAN_MDI0_DP: U26.1 U28.4 XF1.12
LAN_MDI1_C_DN: RJ1.6 XF1.6
LAN_MDI1_C_DP: RJ1.3 XF1.5
LAN_MDI1_DN: U26.5 U28.1 XF1.7
LAN_MDI1_DP: U26.4 U28.6 XF1.8
LAN_MDI2_C_DN: RJ1.5 XF2.5
LAN_MDI2_C_DP: RJ1.4 XF2.6
LAN_MDI2_DN: PR238.2 U37.3 XF2.8
LAN_MDI2_DN_R: PR238.1 U26.7
LAN_MDI2_DP: PR239.2 U37.4 XF2.7
LAN_MDI2_DP_R: PR239.1 U26.6
LAN_MDI3_C_DN: RJ1.8 XF2.1
LAN_MDI3_C_DP: RJ1.7 XF2.2
LAN_MDI3_DN: PR236.2 U37.1 XF2.12
LAN_MDI3_DN_R: PR236.1 U26.10
LAN_MDI3_DP: PR237.2 U37.6 XF2.11
LAN_MDI3_DP_R: PR237.1 U26.9
LAN_RSET: R498.2 U26.31
LAN_XTALI: C226.1 R500.2 U26.28 X4.1
LAN_XTALO: C227.1 R500.1 U26.29 X4.3
LANCLK_REQ_U_N: Q73.D R481.1 R793.2 U26.12
LDR: R767.2 U35.1
LDR_1: Q68.4 R767.1
LED_5VSB: LED1.A R286.2
LEDC_ISET: R792.1 U35.12
LFRAMEJ_FW4: CPU1.V61 LPC1.13 U7.20 U14.3
LINE2-VREFO: RN32.1(A) RN32.2(A) U16.29
LINEOUT-JD: LOUT1.Q R391.1
LINEOUT-L: R446.1 U16.19
LINEOUT-R: R447.1 U16.18
LINEOUT_C-L: L10.1 R446.2
LINEOUT_C-R: L11.1 R447.2
LINEOUT_CON-L: C184.2 L10.2 LOUT1.4 Q37.1
LINEOUT_CON-R: C185.2 L11.2 LOUT1.1 Q37.2
LINK_ACTIVITY_N: U24.4 U26.27 UR1.1
LINK_PWR: R471.2 RJ1.9
LPC_CLK0_R: CPU1.AB61 R98.1
LPC_CLK1: LPC1.1 R97.2 R264.1
LPC_CLK1_R: CPU1.AA62 R97.1
LPC_CLKRUN#: CPU1.V62 R367.2 R654.2 U14.8
LPC_PME_N: CPU1.AR63 R363.1 R728.2
LPC_PME_N_R: R363.2 U14.91
LPF: C513.1 U35.9
LPSS_UART1_RXD: CPU1.C43 R23.2
LPSS_UART2_CTS#: IRMTCN1.4 R151.2
LPSS_UART2_RTS#: IRMTCN1.3 R152.2
LPSS_UART2_RXD: CPU1.J41 IRMTCN1.2
LPSS_UART2_TXD: IRMTCN1.1 R153.2
LVDS_BL_ADJ: R230.1 R231.1 R782.1 R789.2 R790.1
LVDS_DET_A*: LVDS1.17 R668.2 U14.59
LVDS_DET_B*: Q55.D R635.2 U14.121
LVDS_DET_B_C*: C354.1 LVDS1.1 Q55.G
LVDS_PU_5: LVDS1.5 R655.2
LVDS_PU_5_1: Q59.D R651.1
LVDS_PU_6: LVDS1.6 R651.2
LVDS_PU_6_2: Q56.D Q59.G R649.1
LVDS_PU_24: LVDS1.24 R656.2
LX: D10.A L8.2 Q68.5 Q68.6 Q68.7 Q68.8
M1_SMB_CLK: NGFF1.60 R13.2
M1_SMB_DATA: NGFF1.58 R19.2
M_A_VREFCA_CPU: CPU1.AR35 R612.1
M_A_VREFDQ_CPU: CPU1.AT34 R611.1
M_CAS_A_N: CPU1.BH47 DIMM1.115
M_DATA_A0: CPU1.AW63 DIMM1.4
M_DATA_A1: CPU1.AY62 DIMM1.5
M_DATA_A2: CPU1.BD62 DIMM1.15
M_DATA_A3: CPU1.BG62 DIMM1.17
M_DATA_A4: CPU1.AY61 DIMM1.7
M_DATA_A5: CPU1.AW62 DIMM1.6
M_DATA_A6: CPU1.BD63 DIMM1.16
M_DATA_A7: CPU1.BE62 DIMM1.18
M_DATA_A8: CPU1.AU63 DIMM1.22
M_DATA_A9: CPU1.AT55 DIMM1.23
M_DATA_A10: CPU1.AV58 DIMM1.33
M_DATA_A11: CPU1.AY59 DIMM1.34
M_DATA_A12: CPU1.AU62 DIMM1.24
M_DATA_A13: CPU1.AT54 DIMM1.21
M_DATA_A14: CPU1.AV57 DIMM1.35
M_DATA_A15: CPU1.AV59 DIMM1.36
M_DATA_A16: CPU1.AV52 DIMM1.42
M_DATA_A17: CPU1.AY55 DIMM1.41
M_DATA_A18: CPU1.BD58 DIMM1.51
M_DATA_A19: CPU1.AV54 DIMM1.40
M_DATA_A20: CPU1.BB57 DIMM1.50
M_DATA_A21: CPU1.BD59 DIMM1.52
M_DATA_A22: CPU1.AY57 DIMM1.39
M_DATA_A23: CPU1.BF59 DIMM1.53
M_DATA_A24: CPU1.BA50 DIMM1.67
M_DATA_A25: CPU1.BB54 DIMM1.58
M_DATA_A26: CPU1.BD50 DIMM1.69
M_DATA_A27: CPU1.BF58 DIMM1.56
M_DATA_A28: CPU1.BE56 DIMM1.57
M_DATA_A29: CPU1.BB50 DIMM1.70
M_DATA_A30: CPU1.BD54 DIMM1.59
M_DATA_A31: CPU1.BE50 DIMM1.68
M_DATA_A32: CPU1.AR41 DIMM1.129
M_DATA_A33: CPU1.AT41 DIMM1.132
M_DATA_A34: CPU1.AR37 DIMM1.141
M_DATA_A35: CPU1.AW35 DIMM1.140
M_DATA_A36: CPU1.AT37 DIMM1.130
M_DATA_A37: CPU1.AR39 DIMM1.131
M_DATA_A38: CPU1.AV37 DIMM1.143
M_DATA_A39: CPU1.AW37 DIMM1.142
M_DATA_A40: CPU1.BJ44 DIMM1.147
M_DATA_A41: CPU1.BG43 DIMM1.149
M_DATA_A42: CPU1.BG39 DIMM1.157
M_DATA_A43: CPU1.BG40 DIMM1.158
M_DATA_A44: CPU1.BH45 DIMM1.146
M_DATA_A45: CPU1.BG44 DIMM1.148
M_DATA_A46: CPU1.BJ40 DIMM1.159
M_DATA_A47: CPU1.BH41 DIMM1.160
M_DATA_A48: CPU1.BD39 DIMM1.163
M_DATA_A49: CPU1.BD37 DIMM1.166
M_DATA_A50: CPU1.BD34 DIMM1.176
M_DATA_A51: CPU1.BB34 DIMM1.177
M_DATA_A52: CPU1.BE39 DIMM1.165
M_DATA_A53: CPU1.BB37 DIMM1.164
M_DATA_A54: CPU1.BE34 DIMM1.174
M_DATA_A55: CPU1.BA34 DIMM1.175
M_DATA_A56: CPU1.BH37 DIMM1.181
M_DATA_A57: CPU1.BG34 DIMM1.194
M_DATA_A58: CPU1.BJ38 DIMM1.180
M_DATA_A59: CPU1.BG38 DIMM1.183
M_DATA_A60: CPU1.BH33 DIMM1.193
M_DATA_A61: CPU1.BJ34 DIMM1.192
M_DATA_A62: CPU1.BG33 DIMM1.191
M_DATA_A63: CPU1.BG37 DIMM1.182
M_DQS_A_DN0: CPU1.BC62 DIMM1.10
M_DQS_A_DN1: CPU1.AT58 DIMM1.27
M_DQS_A_DN2: CPU1.BB58 DIMM1.45
M_DQS_A_DN3: CPU1.BB52 DIMM1.62
M_DQS_A_DN4: CPU1.AW39 DIMM1.135
M_DQS_A_DN5: CPU1.BG42 DIMM1.152
M_DQS_A_DN6: CPU1.BD35 DIMM1.169
M_DQS_A_DN7: CPU1.BH35 DIMM1.186
M_DQS_A_DP0: CPU1.BB63 DIMM1.12
M_DQS_A_DP1: CPU1.AT59 DIMM1.29
M_DQS_A_DP2: CPU1.BB59 DIMM1.47
M_DQS_A_DP3: CPU1.BD52 DIMM1.64
M_DQS_A_DP4: CPU1.AV39 DIMM1.137
M_DQS_A_DP5: CPU1.BJ42 DIMM1.154
M_DQS_A_DP6: CPU1.BB35 DIMM1.171
M_DQS_A_DP7: CPU1.BG36 DIMM1.188
M_MAA_A0: CPU1.BG50 DIMM1.98
M_MAA_A1: CPU1.BG51 DIMM1.97
M_MAA_A2: CPU1.BH51 DIMM1.96
M_MAA_A3: CPU1.BD41 DIMM1.95
M_MAA_A4: CPU1.BE41 DIMM1.92
M_MAA_A5: CPU1.BJ52 DIMM1.91
M_MAA_A6: CPU1.BG53 DIMM1.90
M_MAA_A7: CPU1.BG55 DIMM1.86
M_MAA_A8: CPU1.BH53 DIMM1.89
M_MAA_A9: CPU1.BG52 DIMM1.85
M_MAA_A10: CPU1.BH49 DIMM1.107
M_MAA_A11: CPU1.BH55 DIMM1.84
M_MAA_A12: CPU1.BG54 DIMM1.83
M_MAA_A13: CPU1.BG46 DIMM1.119
M_MAA_A14: CPU1.BG56 DIMM1.80
M_MAA_A15: CPU1.BG57 DIMM1.78
M_ODT_A0: CPU1.AW43 DIMM1.116
M_ODT_A1: CPU1.AW41 DIMM1.120
M_RAS_A_N: CPU1.BG47 DIMM1.110
M_SBS_A0: CPU1.BJ48 DIMM1.109
M_SBS_A1: CPU1.BG49 DIMM1.108
M_SBS_A2: CPU1.BH57 DIMM1.79
M_SCKE_A0: CPU1.BH61 DIMM1.73
M_SCKE_A1: CPU1.BH60 DIMM1.74
M_SCS_A_N0: CPU1.AR43 DIMM1.114
M_SCS_A_N1: CPU1.BA41 DIMM1.121
M_WE_A_N: CPU1.BG48 DIMM1.113
MCSI_RCOMP_1: CPU1.H27 R592.2
MCSI_RCOMP_2: CPU1.F27 R593.2
MCT_R: R492.2 RV1.2 XF1.3 XF1.4 XF2.3 XF2.4
MCT_R_1: EC518.1 R492.1
MDA0: GPU1.E18 VRAM4.F7
MDA1: GPU1.F18 VRAM4.F8
MDA2: GPU1.E16 VRAM4.E3
MDA3: GPU1.F17 VRAM4.F2
MDA4: GPU1.D20 VRAM4.H8
MDA5: GPU1.D21 VRAM4.G2
MDA6: GPU1.F20 VRAM4.H7
MDA7: GPU1.E21 VRAM4.H3
MDA8: GPU1.E15 VRAM4.A2
MDA9: GPU1.D15 VRAM4.C2
MDA10: GPU1.F15 VRAM4.A7
MDA11: GPU1.F13 VRAM4.D7
MDA12: GPU1.C13 VRAM4.C3
MDA13: GPU1.B13 VRAM4.A3
MDA14: GPU1.E13 VRAM4.B8
MDA15: GPU1.D13 VRAM4.C8
MDA16: GPU1.B15 VRAM2.A2
MDA17: GPU1.C16 VRAM2.C2
MDA18: GPU1.A13 VRAM2.C3
MDA19: GPU1.A15 VRAM2.A3
MDA20: GPU1.B18 VRAM2.B8
MDA21: GPU1.A18 VRAM2.C8
MDA22: GPU1.A19 VRAM2.D7
MDA23: GPU1.C19 VRAM2.A7
MDA24: GPU1.B24 VRAM2.H8
MDA25: GPU1.C23 VRAM2.G2
MDA26: GPU1.A25 VRAM2.H3
MDA27: GPU1.A24 VRAM2.H7
MDA28: GPU1.A21 VRAM2.F8
MDA29: GPU1.B21 VRAM2.F7
MDA30: GPU1.C20 VRAM2.F2
MDA31: GPU1.C21 VRAM2.E3
MDA32: GPU1.R22 VRAM3.F7
MDA33: GPU1.R24 VRAM3.H7
MDA34: GPU1.T22 VRAM3.H3
MDA35: GPU1.R23 VRAM3.H8
MDA36: GPU1.N25 VRAM3.E3
MDA37: GPU1.N26 VRAM3.F8
MDA38: GPU1.N23 VRAM3.G2
MDA39: GPU1.N24 VRAM3.F2
MDA40: GPU1.V23 VRAM3.C2
MDA41: GPU1.V22 VRAM3.A2
MDA42: GPU1.T23 VRAM3.A3
MDA43: GPU1.U22 VRAM3.C3
MDA44: GPU1.Y24 VRAM3.D7
MDA45: GPU1.AA24 VRAM3.A7
MDA46: GPU1.Y22 VRAM3.C8
MDA47: GPU1.AA23 VRAM3.B8
MDA48: GPU1.AD27 VRAM1.A7
MDA49: GPU1.AB25 VRAM1.B8
MDA50: GPU1.AD26 VRAM1.C8
MDA51: GPU1.AC25 VRAM1.D7
MDA52: GPU1.AA27 VRAM1.C2
MDA53: GPU1.AA26 VRAM1.C3
MDA54: GPU1.W26 VRAM1.A2
MDA55: GPU1.Y25 VRAM1.A3
MDA56: GPU1.R26 VRAM1.H7
MDA57: GPU1.T25 VRAM1.F7
MDA58: GPU1.N27 VRAM1.F8
MDA59: GPU1.R27 VRAM1.H8
MDA60: GPU1.V26 VRAM1.H3
MDA61: GPU1.V27 VRAM1.G2
MDA62: GPU1.W27 VRAM1.E3
MDA63: GPU1.W25 VRAM1.F2
MDSI_RCOMP: CPU1.AP7 R609.2
ME_UNLOCK: R146.2 U14.23
ME_UNLOCK_1: Q7.B R146.1
ME_UNLOCK_2: Q7.E R124.2
ME_UNLOCK_3: JMP1.6 R140.1
MEM_MA_EVENT_L: DIMM1.198 Q53.E R628.1
MEM_VTT: C52.1 C345.1 C346.1 C347.1 C348.2 C349.2 DIMM1.203 DIMM1.204 PR79.1
MIC2-L: C152.1 U16.47
MIC2-L-1: C152.2 R372.1
MIC2-R: C151.1 U16.48
MIC2-R-1: C151.2 R370.1
MIC2-VREFO-L: R384.1 U16.1
MIC2-VREFO-R: R406.1 U16.30
MIC-CAP: C147.2 U16.36
MINI_POWER_CTRL: R531.1 U14.33
MIPI_PMODE: CPU1.B19 TP36.1
MODEL_ID_DET: C467.2 R720.2 R721.1 U14.95
MPCIE_DISABLE_N: R25.1 U14.40
NCP81172_FB1: PC96.1 PR125.1
NCT3956_OE#_MUX: R197.2 U2.6
NCT_CLK: Q32.1 RN9.3(B) U12.8
NCT_DATA: Q32.4 RN9.4(B) U12.7
NGFF_ALERT_N: NGFF1.62 R10.2
NGFF_BT_DISABLE: R29.1 U14.100
NGFF_CLKREQ0_N: NGFF1.53 R24.1
NGFF_CLKREQ1_N: NGFF1.68 TP3.1
NGFF_DETECT_PCIE: CPU1.AP51 R26.2
NGFF_DETECT_PCIE_C: NGFF1.51 R26.1 R30.2
NGFF_DETECT_USB: CPU1.AP49 R85.2
NGFF_DETECT_USB_C: NGFF1.1 R78.2 R85.1
NGFF_PCIE0_RXN: NGFF1.43 R37.1
NGFF_PCIE0_RXP: NGFF1.41 R42.1
NGFF_PCIE0_TXN: NGFF1.37 R45.1
NGFF_PCIE0_TXP: NGFF1.35 R49.1
NGFF_PCIE1_RXN: NGFF1.67 TP5.1
NGFF_PCIE1_RXP: NGFF1.65 TP4.1
NGFF_PCIE1_TXN: NGFF1.61 TP7.1
NGFF_PCIE1_TXP: NGFF1.59 TP6.1
NGFF_PEWAKE0_N: NGFF1.55 NGFF1.70 R522.2 R529.1
NGFF_POWER_CTRL_1: Q50.G R531.2
NGFF_POWER_CTRL_V2: C244.1 Q48.B R525.1
NGFF_REFCLKN0: NGFF1.49 R33.1
NGFF_REFCLKN1: NGFF1.73 TP1.1
NGFF_REFCLKP0: NGFF1.47 R36.1
NGFF_REFCLKP1: NGFF1.71 TP2.1
NGFF_W_DISABLE1_N: NGFF1.56 R25.2
NGFF_W_DISABLE2_N: NGFF1.54 R29.2
NGFF_WAKE_CPU: CPU1.N62 Q49.C RN21.3(B)
NGFF_WAKE_N: Q49.E R522.1 R529.2 R536.1
NGFF_WAKE_N_LS: Q49.B RN21.4(B)
OSD_BIST_N: R329.1 R401.1 U14.39
OSD_BIST_N_1: Q31.2 R329.2
OSD_BIST_N_LS: R401.2 R783.2
OSD_DN: C508.2 CPU1.AM61 R776.1 RN24.4(B)
OSD_DN_R: PWRCN1.2 R776.2
OSD_MENU: CPU1.AP58 R405.2 R408.1
OSD_MENU_EC: R405.1 U14.56
OSD_MENU_LS: C505.2 R408.2 R774.1 RN24.3(B)
OSD_MENU_R: PWRCN1.1 R774.2
OSD_UP: C510.2 CPU1.AN62 R779.1 R780.2 R783.1
OSD_UP_R: PWRCN1.3 R779.2
OZ554_ENA: C198.1 R453.1 R455.1 U35.3
OZ554_PWM: C507.1 R775.1 R778.1 U35.5
OZ554_VIN: C504.1 R771.2 U35.4
P2800_DXN: C125.2 C127.2 Q11.E R289.2 U12.3
P2800_DXP: C125.1 C127.1 Q11.B Q11.C R289.1 U12.2
P_GFX_TXN0: C43.1 CPU1.V2
P_GFX_TXN1: C45.1 CPU1.R2
P_GFX_TXP0: C44.1 CPU1.V3
P_GFX_TXP1: C42.1 CPU1.R1
PANEL_ON_1: R236.2 U38.3
PANEL_ON_2: C364.1 U38.5
PANEL_ON_3: R639.1 U38.4
PANEL_SEL1_CABLE: CONVT1.7 R450.2 RN37.4(B)
PANEL_SEL1_CABLE_EC: R450.1 U14.107
PANEL_SEL2_CABLE: CONVT1.8 R448.2 RN37.3(B)
PANEL_SEL2_CABLE_EC: R448.1 U14.106
PANEL_SEL3_CABLE: CONVT1.9 R452.2 R458.2
PANEL_SEL3_CABLE_EC: R458.1 U14.105
PB_IN_SW1: PWRCN1.6 R784.2 R787.1
PCB_VER_ID: C135.2 R344.1 R349.2 U14.98
PCH_AUD_RST_N: R397.1 U14.30
PCH_AUD_RST_N_1: Q69.5 R397.2
PCH_PCIECLKRQ0_N: CPU1.AK62 Q23.S RN6.2(A)
PCH_PCIECLKRQ1_N: CPU1.AH62 RN5.1(A)
PCH_PCIECLKRQ2_N: CPU1.AJ62 Q1.S RN6.1(A)
PCH_PCIECLKRQ2_N_1: Q1.D R20.1 R24.2
PCH_PCIECLKRQ2_N_B: Q1.G R1.2
PCH_PCIECLKRQ3_N: CPU1.AH61 Q73.S R793.1 RN5.2(A)
PCH_PCIECLKRQ3_N_B: Q73.G R788.2
PCH_RTCRST: JMP1.1 R1806.2 R1807.2
PCH_RTCRST_DOWN: JMP1.2 R143.1
PCH_RTCRST_PULLUP: C35.1 CPU1.AC55 Q1801.D R150.1 R154.1 R156.2 R1806.1
PCH_RTCX1: C21.1 CPU1.AC59 R95.1 X1.1
PCH_RTCX2: C23.1 CPU1.AC58 R95.2 X1.4
PCH_SATA_LED_1: Q77.B Q78.C R799.2
PCH_SRTCRST_DOWN: CMCLR2.1 R120.1
PCH_SRTCRSTB_PULLUP: C29.1 CMCLR2.2 CPU1.AH49 R126.2 R154.2 R1807.1
PCIE_CLKOUT1N: CPU1.A10 TP37.1
PCIE_CLKOUT1P: CPU1.C10 TP38.1
PCIE_OBSN_CPU: CPU1.F5 R604.1
PCIE_OBSP_CPU: CPU1.F6 R604.2
PCIE_P3_USB3_P4_RXN: CPU1.P10 TP74.1
PCIE_P3_USB3_P4_RXP: CPU1.P12 TP73.1
PCIE_P3_USB3_P4_TXN: CPU1.P2 TP40.1
PCIE_P3_USB3_P4_TXP: CPU1.P3 TP42.1
PCIE_P4_USB3_P3_RXN: CPU1.H6 TP70.1
PCIE_P4_USB3_P3_RXP: CPU1.H5 TP71.1
PCIE_P4_USB3_P3_TXN: CPU1.M2 TP39.1
PCIE_P4_USB3_P3_TXP: CPU1.N2 TP41.1
PCIE_REF_CLK_RCOMP: CPU1.E21 R595.2
PCIE_RST#: NGFF1.52 NGFF1.66 R399.2
PCIE_WAKE1#: CPU1.P62 R106.2
PD4405_A: PD1.A PQ7.B
PD4405_K: PD1.K PR138.2
PD_N: Q71.D U20.36
PEG_C_RXN0: C359.2 GPU1.AB9
PEG_C_RXN1: C357.2 GPU1.AC10
PEG_C_RXP0: C358.2 GPU1.AC9
PEG_C_RXP1: C356.2 GPU1.AB10
PEG_RXN0: C359.1 CPU1.P6
PEG_RXN1: C357.1 CPU1.T12
PEG_RXP0: C358.1 CPU1.P7
PEG_RXP1: C356.1 CPU1.T10
PEG_TXN0: C43.2 GPU1.AG7
PEG_TXN1: C45.2 GPU1.AE7
PEG_TXP0: C44.2 GPU1.AG6
PEG_TXP1: C42.2 GPU1.AF7
PEX_CLKREQ_M: Q22.D Q23.D R219.2
PEX_CLKREQ_N: GPU1.AC6 Q22.S R653.2
PEX_PLLVDD_GPU: C362.1 C365.1 C373.1 C374.1 GPU1.AA14 GPU1.AA15 R641.1
PEX_RST_GPU: GPU1.AC7 R260.1 R265.1 R273.2 R274.2
PEX_RST_GPU_D#: D3.3 R273.1
PEX_TERMP: GPU1.AF25 R247.1
PEX_TSTCLK_OUT: GPU1.AF22 R246.2
PEX_TSTCLK_OUT#: GPU1.AE22 R246.1
PLT_RST#_CPU: CPU1.AG57 R34.2 R35.2 R39.1 R541.1
PLTRST#_CPU_D: Q5.D R32.2 R34.1
PLTRST#_EC_R: C141.1 R364.1 U14.7
PLTRST#_LPC: LPC1.3 R266.1 RN11.3(B)
PLTRST*_SIO: R364.2 RN14.4(B)
PLTRST_LAN_N: RN14.3(B) U26.19
PLTRST_N: R39.2 R46.2 R415.1 R1804.1 U17.1 U17.2
PLTRST_N_1: R399.1 R415.2 RN11.1(A) RN11.2(A) RN14.1(A) RN14.2(A) U17.4
PLTRST_N_1A: C89.2 Q25.G R260.2
PLTRST_N_R: Q1802.B R1804.2 R1808.1
PLTRST_SL_N: R248.1 RN11.4(B) U5.2
PM_SLP_S0#_CPU: CPU1.AD61 R90.1 R256.1
PM_SLP_S3#_CPU: CPU1.AC62 R77.1 R96.1
PM_SLP_S4#_CPU: CPU1.AK54 R203.1 R205.1
PMC_BATLOW#: CPU1.AH51 RN4.4(B)
PMC_SUS_STAT: CPU1.AG58 R234.1 RN2.3(B)
PMIC_I2C_SCL: CPU1.H45 TP68.1
PMIC_I2C_SDA: CPU1.F47 TP69.1
PMIC_THERMTRIP#: CPU1.J47 Q1802.E R2402.1
PMIC_THERMTRIP#_EC: R2402.2 R5502.2 U14.83
PMU_RCOMP: CPU1.AG59 R584.2
PMU_WAKE#_EMMC: R517.1 R518.1 R521.1
PNL0_BKLCTL: CPU1.C46 R142.2
PNL1_BKLCTL: CPU1.C53 R136.1
PORTC_SPK_L: R427.1 U16.43
PORTC_SPK_L_1: R427.2 R431.1
PORTC_SPK_R: R430.1 U16.44
PORTC_SPK_R_1: R430.2 R432.1
PQ4206_D: PR178.2 Q36.3
PQ4406_2: PQ6.2 PR135.2 PR140.1
PQ4406_3: PQ6.3 PR136.2
PQ4406_5: PC106.1 PQ6.5 PR133.2
PQ4406_6: PC106.2 PQ6.6 PR132.1
PQ4409_C: PQ7.C PR134.1 PR135.1
PQ4409_E: PQ7.E PR129.2 PR130.1
PRE: R421.2 R755.1 U20.16
PSID_D: L16.2 Q41.D R478.1
PSID_D_1: Q39.B R477.1 R478.2
PSID_G: Q39.C Q41.G R485.2
PSL_IN1#: R738.2 U14.73
PSL_IN2#: R358.2 U14.93
PSL_OUT#: R705.1 U14.74
PSTBTN_N: CPU1.AD62 R40.2 R530.1 R1801.2
PSTBTN_N_APS: R530.2 TP58.1
PSYS: PR16.2 PR21.1 PU13.50
PURE_HW_SHUTDOWN#: D8.K Q34.D Q65.B Q1802.C R280.1 R716.2 R719.1
PURE_HW_SHUTDOWN#_R: Q25.D R280.2
PW_CLEAR: CPU1.E41 R99.2
PW_CLEAR_H: JMP1.3 R99.1 R109.1
PWR_1D05V_A: PC28.1 PC31.1 PC32.1 PC36.1 PC37.1 PL2.2 PR44.1 PR46.1 R121.1
PWR_1D05V_EN: C569.1 PR40.1 PU2.5 R118.2 R119.1
PWR_1D05V_FB: PC28.2 PC30.1 PU2.6 R121.2 R128.1
PWR_1D05V_FB_N: PC30.2 PR41.1
PWR_1D05V_LX: PL2.1 PR48.1 PU2.1 PU2.2 PU2.3
PWR_1D05V_PVIN: PC34.1 PC35.1 PR43.1 PR45.1 PR47.1 PU2.9 PU2.10
PWR_1D05V_SN: PC38.1 PR48.2
PWR_1D05V_SVIN: PC33.1 PR43.2 PU2.8
PWR_1D24V_A: PC39.1 PC44.1 PC46.1 PC47.2 PC195.1 PL3.2 PR57.1 PR240.1 R165.1
PWR_1D24V_EN: PC40.1 PR49.1 PR50.2 PU3.5
PWR_1D24V_FB: PC39.2 PC42.1 PU3.6 R165.2 R167.1
PWR_1D24V_FB_N: PC42.2 PR52.1
PWR_1D24V_LX: PL3.1 PR58.1 PU3.1 PU3.2 PU3.3
PWR_1D24V_PG: PC41.1 PR51.2 PU3.4 U14.61
PWR_1D24V_PVIN: PC48.1 PC49.1 PR53.1 PR54.1 PR55.1 PU3.9 PU3.10
PWR_1D24V_SN: PC50.1 PR58.2
PWR_1D24V_SVIN: PC45.1 PR55.2 PU3.8
PWR_1D35V_A: PC54.1 PC55.1 PC56.1 PC57.2 PC63.1 PL5.2 PR69.1 PR70.1 PR75.1
PWR_1D35V_FB: PC51.1 PC63.2 PR67.1 PR75.2 PU4.6
PWR_1D35V_FB_N: PC51.2 PR60.1
PWR_1D35V_LX: PL5.1 PR74.1 PU4.1 PU4.2 PU4.3
PWR_1D35V_PVIN: PC64.1 PC67.1 PR61.1 PR65.1 PR78.1 PU4.9 PU4.10
PWR_1D35V_SN: PC65.1 PR74.2
PWR_1D35V_SVIN: PC62.1 PR65.2 PU4.8
PWR_1P15V_PG_L: Q52.3 R587.2
PWR_3D3V_5V_PG: PR166.2 PU10.7
PWR_3D3V_BOOT2: PR167.2 PU10.9
PWR_3D3V_BOOT2_A: PC121.2 PR167.1
PWR_3D3V_CS2: PR163.1 PU10.5
PWR_3D3V_EN2: PC119.1 PR164.1 PU10.6
PWR_3D3V_FB2: PC116.2 PR160.1 PR162.2 PU10.4
PWR_3D3V_FB2_A: PC116.1 PG7.1 PR162.1
PWR_3D3V_HG2: PQ18.4 PU10.10
PWR_3D3V_LDO3: PC185.1 PG18.2 PU10.3
PWR_3D3V_LG2: PQ20.4 PU10.11
PWR_3D3V_PH2: PC121.1 PL8.2 PQ18.1 PQ18.2 PQ18.3 PQ20.5 PQ20.6 PQ20.7 PQ20.8 PRT3.1 PU10.8
PWR_3D3V_SN: PCT2.1 PRT3.2
PWR_5V3V_EMN_R: D4.3 D8.A R709.1 R711.1 R712.1
PWR_5V_BOOT1: PR152.1 PU10.17
PWR_5V_BOOT1_A: PC109.1 PR152.2
PWR_5V_BYP1: PC111.2 PG3.1 PU10.14
PWR_5V_CS1: PR155.1 PU10.1
PWR_5V_EN1: PC110.1 PR150.1 PU10.20
PWR_5V_FB1: PC112.2 PR158.2 PR159.1 PU10.2
PWR_5V_FB1_A: PC112.1 PGT1.1 PR158.1
PWR_5V_HG1: PR223.2 PU10.16
PWR_5V_HG1_R: PQ11.4 PR223.1
PWR_5V_LDO5: PC113.1 PG6.1 PU10.13
PWR_5V_LG1: PQ9.4 PU10.15
PWR_5V_PH1: PC109.2 PL7.1 PQ9.5 PQ9.6 PQ9.7 PQ9.8 PQ11.1 PQ11.2 PQ11.3 PR137.1 PU10.18
PWR_5V_SN: PC108.1 PR137.2
PWR_ALERT#: PU13.37 R539.1
PWR_CHG_ACDET: PC179.1 PR222.2 PR224.1 U34.6
PWR_CHG_ACN: PC181.1 PC182.1 PG9.2 U34.1
PWR_CHG_ACP: PC180.1 PC182.2 PG8.2 U34.2
PWR_CHG_AD_OFF: PR175.1 Q36.5 U14.6
PWR_CHG_AD_OFF_R: PQ14.B PR175.2
PWR_CHG_BTST: PR161.1 U34.17
PWR_CHG_BTST_1: PC114.1 PD2.K PR161.2
PWR_CHG_CMPIN: PR147.1 PR148.1 PR149.2 PR153.2 PR154.2 U34.4
PWR_CHG_CMPIN_R: PQ8.3 PR147.2
PWR_CHG_CMPIN_RR: PQ8.6 PR149.1
PWR_CHG_HIDRV: PU19.4 U34.18
PWR_CHG_ILIM: PQ19.D PR229.1 PR231.2 U34.10
PWR_CHG_IOUT: PC183.1 PR154.1 PR227.1 U34.7
PWR_CHG_LODRV: PC122.1 PU18.4 U34.15
PWR_CHG_NC: PR232.1 U34.11
PWR_CHG_PHASE: PC114.2 PL12.1 PU18.5 PU18.6 PU18.7 PU18.8 PU19.1 PU19.2 PU19.3 U34.19
PWR_CHG_SRN: PR234.1 U34.12
PWR_CHG_SRP: PR233.1 U34.13
PWR_CHG_VCC: PC186.1 PR221.2 U34.20
PWR_CORE_BOOT: PR181.2 PU13.14
PWR_CORE_BOOT_A: PC128.1 PR181.1
PWR_CORE_HG1: PR29.1 PU13.15
PWR_CORE_HG1_R: PQ1.4 PQ16.4 PR29.2 PR32.1
PWR_CORE_LG1: PQ2.4 PQ3.4 PR183.1 PU13.17
PWR_CORE_LX1: PC128.2 PG1.2 PL1.1 PQ1.1 PQ1.2 PQ1.3 PQ2.5 PQ2.6 PQ2.7 PQ2.8 PQ3.5 PQ3.6 PQ3.7 PQ3.8 PQ16.1 PQ16.2 PQ16.3 PR30.1 PR32.2 PU13.16
PWR_CORE_SN: PC20.1 PR30.2
PWR_DCBATOUT_VCCGI: PC17.1 PC19.1 PC139.1 PC197.1 PQ1.5 PQ1.6 PQ1.7 PQ1.8 PQ16.5 PQ16.6 PQ16.7 PQ16.8 PR1.1 PR5.2 PR6.2 PR7.2 PR8.2 PT1.1
PWR_DCBATOUT_VDDQ: PC61.1 PC66.1 PC170.1 PQ4.5 PQ4.6 PQ4.7 PQ4.8 PR213.1 PRT1.2 PRT2.2
PWR_DCBATOUT_VNN: PC129.1 PC131.1 PR184.2 PR185.2 PU14.5 PU14.6 PU14.7 PU14.8
PWR_DDR_SN: PC60.1 PR62.2
PWR_LED_YELLOW_C: PWRCN1.9 Q74.D R505.1 R506.2
PWR_LED_YELLOW_C2: R503.2 R506.1
PWR_SCLK_A: PR192.1 PU13.38
PWR_SDIO: PR191.1 PU13.36
PWR_V1P8A: PC21.1 PC22.1 PC23.1 PR31.2 PR35.1 PU1.3 PU1.4
PWR_V1P8A_EN: PC146.1 PC147.1 PR36.2 PR38.1 PR206.2 PR207.2 PR243.2 PU1.8 R577.1
PWR_V1P8A_FB: PC22.2 PR34.1 PR35.2 PU1.2
PWR_V1P8A_PG: PC148.1 PR37.2 PU1.7 R580.2
PWR_V1P24A_PG_L: Q47.3 R516.2
PWR_VCCGI_COMP: PC10.2 PC11.2 PU13.4
PWR_VCCGI_COMPA: PC10.1 PR19.2
PWR_VCCGI_CSCOMP: PC7.1 PC8.1 PR12.2 PR14.2 PR33.2 PU13.6
PWR_VCCGI_CSN: PG2.1 PR188.2
PWR_VCCGI_CSP: PG1.1 PR9.1 PR187.1
PWR_VCCGI_CSP1: PC130.2 PR187.2 PU13.10
PWR_VCCGI_CSREF: PC130.1 PC132.1 PR188.1 PU13.8
PWR_VCCGI_CSSUM: PC7.2 PC8.2 PR9.2 PR11.1 PU13.7
PWR_VCCGI_DIFFOUT: PR18.1 PR22.1 PR23.1 PU13.2
PWR_VCCGI_EN: PG10.1 PU13.41
PWR_VCCGI_EN_PH: PC141.1 PG10.2 Q4501.D R558.2 R566.2 R568.2
PWR_VCCGI_FB: PC11.1 PC14.2 PR18.2 PR19.1 PU13.3
PWR_VCCGI_FBA: PC14.1 PR23.2
PWR_VCCGI_ICCMAX: PR186.1 PU13.23
PWR_VCCGI_ILIM: PR14.1 PU13.5
PWR_VCCGI_IOUT: PC16.2 PR26.2 PU13.1
PWR_VCCGI_NTC: PR3.1 PR4.1 PR25.2
PWR_VCCGI_PVCC: PC5.1 PR2.1 PU13.18
PWR_VCCGI_TSENSE: PC4.1 PR4.2 PU13.11
PWR_VCCGI_VCC: PC6.1 PR10.2 PU13.13
PWR_VCCGI_VR_RDY: PG11.1 PU13.42
PWR_VCCGI_VR_RDY1: PG11.2 PR203.2 PR207.1
PWR_VCCGI_VRMP: PC3.1 PR1.2 PU13.12
PWR_VCCGI_VSN: PC140.2 PR197.2 PU13.52
PWR_VCCGI_VSNA: PC140.1 PC142.2 PG16.2 PR197.1
PWR_VCCGI_VSP: PC142.1 PG15.2 PU13.51
PWR_VCCGT_ILIM_NTC: PR11.2 PR12.1 PR33.1
PWR_VCORE_VNN_D: Q46.6 R527.2
PWR_VDDQ_BOOT: PR80.1 PU5.18
PWR_VDDQ_BOOT_A: PC68.1 PR80.2
PWR_VDDQ_CS: PRB1.1 PU5.13
PWR_VDDQ_EN: PC75.1 PR87.2 PU5.8
PWR_VDDQ_FB: PC74.2 PR83.2 PR85.1 PU5.6
PWR_VDDQ_HG: PR210.2 PU5.17
PWR_VDDQ_HG_R: PQ4.4 PR210.1
PWR_VDDQ_LG: PQ5.4 PU5.15
PWR_VDDQ_PH: PC68.2 PL4.1 PQ4.1 PQ4.2 PQ4.3 PQ5.5 PQ5.6 PQ5.7 PQ5.8 PR62.1 PU5.16
PWR_VDDQ_TON: PR213.2 PU5.9
PWR_VDDQ_VDD: PC72.1 PR81.1 PU5.12
PWR_VDDQ_VDDQ: PC74.1 PR82.1 PR83.1 PU5.5
PWR_VDDQ_VID: PC73.1 PR212.1 PU5.11
PWR_VDDQ_VLDOIN: PC69.1 PR211.2 PU5.19
PWR_VDDQ_VTT: PC70.1 PC71.1 PR79.2 PU5.2 PU5.20
PWR_VDDQ_VTTREF: PC172.1 PU5.4
PWR_VGA_CORE_BOOT1: PR108.1 U11.1
PWR_VGA_CORE_BOOT1_1: PC91.1 PR108.2
PWR_VGA_CORE_COMP: PC95.1 PR124.2 U11.12
PWR_VGA_CORE_COMP_1: PC97.2 PR124.1
PWR_VGA_CORE_EN: PC89.1 PR105.2 PR106.2 R307.2 U11.3
PWR_VGA_CORE_FB: PC95.2 PC97.1 PR122.1 PR125.2 U11.11
PWR_VGA_CORE_FBRTN: PR118.2 U11.10
PWR_VGA_CORE_FS: PR116.1 U11.9
PWR_VGA_CORE_LGATE1: PR114.1 PU7.4 PU16.4 U11.23
PWR_VGA_CORE_PGOOD: PR121.2 PR123.1 U11.16
PWR_VGA_CORE_PHASE1: PC91.2 PL6.1 PR96.2 PR98.2 PU7.5 PU7.6 PU7.7 PU7.8 PU8.1 PU8.2 PU8.3 PU16.5 PU16.6 PU16.7 PU16.8 PU17.1 PU17.2 PU17.3 U11.24
PWR_VGA_CORE_PSI: PC88.1 PR100.2 PR107.1 R295.2 U11.4
PWR_VGA_CORE_PVCC: PC94.1 PR120.2 U11.21
PWR_VGA_CORE_REFIN: PC90.1 PR110.1 PR112.2 U11.7
PWR_VGA_CORE_SENCE+: GPU1.F2 PR104.2 PR119.1
PWR_VGA_CORE_SENCE-: GPU1.F1 PR117.1 PR118.1
PWR_VGA_CORE_SENSE+_1: PC96.2 PR119.2 PR122.2
PWR_VGA_CORE_SNB: PC85.1 PR96.1
PWR_VGA_CORE_TALERT#: PR127.2 PR128.1 U11.14
PWR_VGA_CORE_TSNS: PC98.1 PR99.1 PR115.2 U11.13
PWR_VGA_CORE_UGATE1: PR103.1 U11.2
PWR_VGA_CORE_UGATE1_R: PR98.1 PR103.2 PU8.4 PU17.4
PWR_VGA_CORE_VCC: PC99.1 PR126.2 U11.15
PWR_VGA_CORE_VID: PC87.1 PR102.1 U11.5
PWR_VGA_CORE_VIDBUF: PR109.1 U11.6
PWR_VGA_CORE_VREF: PC93.1 PR113.1 PR115.1 U11.8
PWR_VGA_CORE_VREF_1: PC92.1 PR109.2 PR112.1 PR113.2
PWR_VGA_CORE_VREF_2: PR110.2 PR111.1
PWR_VGA_VRAM_POK: PC58.1 PR63.2 PU4.4 Q9.2 U14.96
PWR_VGA_VRAM_POK_B_1: Q9.5 Q9.6 R172.2
PWR_VNN_BOOT: PR182.2 PU13.22
PWR_VNN_BOOTA: PC127.2 PR182.1
PWR_VNN_COMP: PC15.1 PC18.1 PU13.47
PWR_VNN_COMPA: PC18.2 PR24.1
PWR_VNN_CSN: PC135.1 PC136.1 PG17.1 PR205.2 PU13.45
PWR_VNN_CSN_NTC: PR200.2 PR205.1
PWR_VNN_CSP: PG12.1 PR201.2
PWR_VNN_CSP1B: PC135.2 PC136.2 PR200.1 PR201.1 PU13.44
PWR_VNN_HG: PR193.1 PU13.21
PWR_VNN_HG_R: PR193.2 PR196.1 PU14.4
PWR_VNN_ILIM: PC13.1 PR20.1 PU13.46
PWR_VNN_IOUT: PC12.1 PR15.1 PU13.43
PWR_VNN_LG: PU13.19 PU15.4
PWR_VNN_PH: PC127.1 PG12.2 PL9.1 PR194.1 PR196.2 PU13.20 PU14.1 PU14.2 PU14.3 PU15.5 PU15.6 PU15.7 PU15.8
PWR_VNN_PWM: PR13.1 PU13.40
PWR_VNN_SN: PC133.1 PR194.2
PWR_VNN_VSN: PC138.2 PR199.2 PU13.48
PWR_VNN_VSP: PC137.2 PR198.2 PU13.49
PWR_VNN_VSPA: PC143.1 PG14.2 PR198.1 PR202.1
PWR_VNN_VSPA_R: PC137.1 PR202.2
PWR_VR_HOT#: PR190.2 PU13.35
PWR_VTT_EN: PR84.2 PU5.7
PWRBTN_APS: R528.2 TP55.1
PWRBTN_N: C514.1 R354.2 R356.1 R787.2
PWRBTN_N_R: C138.1 R355.2 R356.2 R358.1
PWRCN_DET_N: C516.2 PWRCN1.5 R155.1
PWRCN_DET_N_C: CPU1.J39 R155.2 R159.1
PWRGD_3V: C58.1 Q17.G R213.1 R214.1 R218.1 R340.1 R734.2
PWRGD_3V_B: Q17.D Q18.B R226.2
PWRGD_3V_B_1: Q19.5 Q19.6 R238.2
PWRGD_3V_C: PC76.1 Q2.G Q4.G Q18.C R220.2
PWRGD_3V_D: Q14.D Q16.S
PWRGD_3V_G1: Q16.G R218.2
PWRGD_3V_G2: Q14.G R221.2
PWRGD_3V_LL: Q19.3 R214.2
PWRGD_3V_N: Q34.G R340.2 R343.1
PWROK3_1_R: R729.2 R734.1 U14.84
PWROK3_2_R: R216.1 U14.10
QSA0: GPU1.E19 VRAM4.F3
QSA1: GPU1.C15 VRAM4.C7
QSA2: GPU1.B16 VRAM2.C7
QSA3: GPU1.B22 VRAM2.F3
QSA4: GPU1.R25 VRAM3.F3
QSA5: GPU1.W23 VRAM3.C7
QSA6: GPU1.AB26 VRAM1.C7
QSA7: GPU1.T26 VRAM1.F3
QSA#0: GPU1.F19 VRAM4.G3
QSA#1: GPU1.C14 VRAM4.B7
QSA#2: GPU1.A16 VRAM2.B7
QSA#3: GPU1.A22 VRAM2.G3
QSA#4: GPU1.P25 VRAM3.G3
QSA#5: GPU1.W22 VRAM3.B7
QSA#6: GPU1.AB27 VRAM1.B7
QSA#7: GPU1.T27 VRAM1.G3
REXT: R419.1 U20.18
RING2: C124.1 Q33.2 RN32.4(B) U16.31 UHS1.3
ROM_CS*: GPU1.D12 R691.1
ROM_CS_R*: R691.2 R696.2 U32.1
ROM_SCLK: GPU1.C12 R310.1 R311.1 R313.2
ROM_SCLK_R: R311.2 U32.6
ROM_SI: GPU1.B12 R304.1 R308.2 R309.1
ROM_SI_R: R309.2 U32.5
ROM_SO: GPU1.A12 R314.2 R693.1 U32.2
RSMRST#_KBC_MUX: R206.1 U2.9
RSMRST*_R: Q19.2 R216.2
RSMRST_APS: R511.2 TP54.1
RSMRST_N: CPU1.AC57 R27.2 R28.2 R206.2 R511.1 R1805.2 U14.20
RT: R786.1 U35.10
RTC_DET#: RN40.2(A) U14.17 U27.D
RTCRST_ON: Q1801.G R1803.1 U14.122
RTD_LVDS_BL_ADJ: R233.2 R244.2
RTL_ISOLATE_N: Q76.6 R480.1 R482.2 U26.20
RTL_ISOLATE_N_1: C517.1 Q76.5 R794.1 R797.2
RTL_ISOLATE_N_2: Q76.2 Q76.3 R800.2
RTN1: CONVT1.1 R768.1
RTN2: CONVT1.2 R769.1
RTN3: CONVT1.5 R770.1
RTN4: CONVT1.6 R772.1
S5_ENABLE: Q64.D R708.2 R712.2 U14.14
S_LVDS_BL_EN: R463.1 R465.1 R467.1 R472.1 R473.2
S_TXE0+: LVDS1.18 U31.31
S_TXE0-: LVDS1.19 U31.32
S_TXE1+: LVDS1.15 U31.29
S_TXE1-: LVDS1.16 U31.30
S_TXE2+: LVDS1.12 U31.27
S_TXE2-: LVDS1.13 U31.28
S_TXE3+: LVDS1.8 U31.23
S_TXE3-: LVDS1.9 U31.24
S_TXEC+: LVDS1.10 U31.25
S_TXEC-: LVDS1.11 U31.26
S_TXO0+: LVDS1.29 U31.41
S_TXO0-: LVDS1.30 U31.42
S_TXO1+: LVDS1.27 U31.39
S_TXO1-: LVDS1.28 U31.40
S_TXO2+: LVDS1.25 U31.37
S_TXO2-: LVDS1.26 U31.38
S_TXO3+: LVDS1.20 U31.33
S_TXO3-: LVDS1.21 U31.34
S_TXOC+: LVDS1.22 U31.35
S_TXOC-: LVDS1.23 U31.36
SATA__RXN0_C: C51.2 HDD1.5
SATA__RXN1_C: C31.2 ODD1.5
SATA__RXP0_C: C50.2 HDD1.6
SATA__RXP1_C: C30.2 ODD1.6
SATA__TXN0_C: C53.2 HDD1.3
SATA__TXN1_C: C33.2 ODD1.3
SATA__TXP0_C: C54.2 HDD1.2
SATA__TXP1_C: C34.2 ODD1.2
SATAHDR_RX_DN0: CPU1.T7 L2.4
SATAHDR_RX_DN0_EMI: C51.1 L2.3
SATAHDR_RX_DN1: C31.1 CPU1.T6
SATAHDR_RX_DP0: CPU1.T9 L2.1
SATAHDR_RX_DP0_EMI: C50.1 L2.2
SATAHDR_RX_DP1: C30.1 CPU1.T5
SATAHDR_TX_DN0: CPU1.Y2 L3.1
SATAHDR_TX_DN0_EMI: C53.1 L3.2
SATAHDR_TX_DN1: C33.1 CPU1.W2
SATAHDR_TX_DP0: CPU1.Y3 L3.4
SATAHDR_TX_DP0_EMI: C54.1 L3.3
SATAHDR_TX_DP1: C34.1 CPU1.W1
SB3V: C56.1 C70.1 C72.1 C156.1 C242.1 C249.1 C250.1 C537.2 C542.1 D5.2 F4.1 PC25.1 PC134.1 PC194.1 PR36.1 PR37.1 PR38.2 PR39.1 PR45.2 PR47.2 PR50.1 PR51.1 PR53.2 PR54.2 PR61.2 PR78.2 PR86.1 PR165.1 PR170.1 PR171.1 PR172.1 PR203.1 PR209.1 PR230.1 PR235.1 PU1.5 PU1.9 Q51.S Q79.S R9.1 R12.1 R172.1 R185.1 R208.2 R211.2 R219.1 R228.1 R237.2 R238.1 R334.1 R339.1 R445.1 R452.1 R499.1 R513.1 R514.1 R516.1 R520.1 R523.1 R533.1 R536.2 R542.1 R568.1 R569.1 R573.1 R634.1 R635.1 R791.1 R798.2 R800.1 R802.2 R806.1 R811.1 R1801.1 R1802.1 R1805.1 RN2.1(A) RN2.2(A) RN4.1(A) RN4.2(A) RN16.1(A) RN16.2(A) RN25.1(A) RN25.2(A) RN34.1(A) RN34.2(A) RN37.1(A) RN37.2(A) U7.1 U15.6 U15.7 U29.6 U29.7
SB3V_D: Q45.6 R513.2
SB5V: C85.1 C99.1 C189.1 F8.1 PC26.1 PR2.2 PR10.1 PR16.1 PR81.2 PR139.1 PR142.1 PR146.1 PR151.1 PR157.1 PR212.2 PU1.6 PU13.9 PU13.33 R226.1 R286.1 R485.1 R486.1 R501.1 R503.1 R757.2 R799.1 R801.1 R808.1 U8.5 U15.1 U15.2 U15.4 U23.5 U29.4
SD_CD_BD: MEMCD1.11 R195.2 R196.1 R200.1
SD_CD_BD_CPU: CPU1.AB54 R195.1
SD_CLK_BD: MEMCD1.5 R180.2
SD_CLK_BD_CPU: CPU1.AB58 R180.1
SD_CMD_BD: MEMCD1.2 R185.2 R186.2
SD_CMD_BD_CPU: CPU1.AC52 R186.1
SD_DATA0_BD: MEMCD1.7 R178.2
SD_DATA0_CPU: CPU1.AC49 R178.1
SD_DATA1_BD: MEMCD1.8 R176.2
SD_DATA1_CPU: CPU1.AC48 R176.1
SD_DATA2_BD: MEMCD1.9 R192.2
SD_DATA2_CPU: CPU1.AC51 R192.1
SD_DATA3_BD: MEMCD1.1 R191.2
SD_DATA3_CPU: CPU1.AB51 R191.1
SD_PWR_EN: Q81.C R815.2 U39.4
SD_PWR_EN_CPU#: CPU1.P51 R814.2
SD_PWR_EN_CPU#_R: C568.1 Q81.B R814.1
SD_WP_BD: MEMCD1.10 R175.2
SD_WP_BD_CPU: CPU1.AB55 R175.1 R2001.2 R2002.1
SENSE_B: R389.2 R391.2 U16.33
SER_IRQ: R337.2 R338.2 U13.4 U14.125
SIDE_USB3_RX0+: L5.3 SSUSB1.6 U4.2 U4.9
SIDE_USB3_RX0-: L5.2 SSUSB1.5 U4.1 U4.10
SIDE_USB3_RX1+: L7.3 SSUSB2.6 U9.2 U9.9
SIDE_USB3_RX1-: L7.2 SSUSB2.5 U9.1 U9.10
SIDE_USB3_TX0+: L4.3 SSUSB1.9 U4.5 U4.6
SIDE_USB3_TX0-: L4.2 SSUSB1.8 U4.4 U4.7
SIDE_USB3_TX1+: L6.3 SSUSB2.9 U9.5 U9.6
SIDE_USB3_TX1-: L6.2 SSUSB2.8 U9.4 U9.7
SIO_EUP_EN#: R270.1 R271.2 R709.2
SIO_EUP_EN#_G: Q24.G R269.2 R270.2
SIO_EUP_EN#_L: Q45.3 R526.1
SIO_EUP_EN#_R: PR150.2 PR164.2 R271.1 R526.2
SIO_EUP_EN_D: Q24.D Q45.2 Q45.5 Q46.2 Q46.5 Q47.2 Q47.5 Q52.2 Q52.5 R515.2
SIO_GPU_EN: CPU1.B27 Q20.E R210.1 R241.1
SIO_GPU_EN_C: PR76.1 Q13.5 Q20.C R250.1 R307.1 R315.1
SIO_GPU_EN_LS: Q20.B R240.1
SIO_GPU_RST: CPU1.C26 Q21.E RN22.4(B)
SIO_GPU_RST_C: Q21.C R232.1 U5.1
SIO_GPU_RST_LS: Q21.B RN22.3(B)
SIO_GREEN_PWM: R494.1 U14.16
SIO_GREEN_PWM_1: Q74.G R493.1 R494.2 RN34.3(B)
SIO_HDD_LED: R507.1 R508.2 U14.15
SIO_HDD_LED_1: Q75.B R507.2
SIO_LVDS_BL_ADJ: R224.1 R231.2 U14.62
SIO_MEM_EVENT_L: R627.1 U14.25
SIO_MEM_EVENT_L_B: Q53.B R620.2
SIO_MEM_EVENT_L_C: Q53.C R627.2
SIO_PWNBTN_N: R17.2 R345.2 R354.1 R355.1
SIO_SMCLK0: Q28.6 Q32.6 R469.2 R702.2 RN13.3(B) U14.67
SIO_SMCLK0_D: Q60.3 R702.1
SIO_SMDAT0: Q28.3 Q32.3 R470.2 R704.2 RN13.4(B) U14.68
SIO_SMDAT0_D: Q60.6 R704.1
SIO_YELLOW: Q72.G R505.2 RN34.4(B) U14.47
SLEEVE: C131.1 Q33.1 Q66.D RN32.3(B) U16.32 UHS1.4
SLEEVE_G: Q66.G Q67.C R744.1 R746.2
SLP_S0_APS: R256.2 TP50.1
SLP_S0_N: D2.2 R90.2
SLP_S3_N: D2.1 PR27.1 R94.1 R96.2 R118.1 R353.1 R379.2 R381.2
SLP_S3_N_APS: R77.2 TP29.1
SLP_S3_N_EC: R353.2 U14.64
SLP_S4_N: PR28.1 PR87.1 R205.2 R263.2 R386.2 R441.2
SLP_S4_N_APS: R203.2 TP43.1
SLP_S4_N_EC: R386.1 U14.21
SM_RCOMP_0: CPU1.AV34 R589.2
SM_RCOMP_1: CPU1.AV30 R591.2
SMB0_ALERT#: R9.2 R10.1 R14.1
SMB0_ALERT#_C: CPU1.R63 R12.2 R14.2
SMB0_CLK_C: CPU1.T62 R108.2
SMB0_CLK_MAIN: DIMM1.202 PC1.1 Q2.S Q62.4 R21.2 RN17.4(B)
SMB0_CLK_RESUME: Q2.D R13.1 R108.1 RN16.3(B)
SMB0_CVT_CLK: C202.1 R469.1 U35.6
SMB0_CVT_DATA: C201.1 R470.1 U35.7
SMB0_DATA_C: CPU1.T61 R110.2
SMB0_DATA_MAIN: DIMM1.200 PC2.1 Q4.S Q61.4 R18.2 RN17.3(B)
SMB0_DATA_RESUME: Q4.D R19.1 R110.1 RN16.4(B)
SMB_CLK_GPU: Q28.1 R312.2
SMB_DAT_GPU: Q28.4 R306.2
SMBUS_ISP: C462.1 Q61.2 Q61.5 Q62.2 Q62.5 R710.2 U14.50
SMBUS_ISP_G: Q60.2 Q60.5 R707.2 R710.1
SOC_EXTSMI_N: CPU1.M41 R130.1 R151.1
SOC_PWROK_CPU: CPU1.AG49 R225.1 R229.1
SP_PLLVDD: C395.1 C400.1 C403.1 C410.1 GPU1.M6 L21.2
SPEED_100*_CON: RJ1.12 UR2.2
SPEED_100_N: U24.6 U26.25 UR2.1
SPEED_1000*_CON: RJ1.11 UR3.2 UR4.2
SPEED_1000_N: U24.1 U26.26 UR3.1
SPI_CLK_CPU_MUX: R134.2 U2.4
SPI_CLK_KBC_MUX: R362.2 U2.2
SPI_CLK_N_CPU: CPU1.C56 R134.1 R135.2
SPI_CLK_ROM: R199.1 R631.2 R632.2 SRCON1.6 U3.6
SPI_CLK_ROM_CPU: R135.1 R631.1
SPI_CLK_ROM_KBC: R360.2 R632.1
SPI_CLK_ROM_MUX: R199.2 U2.7
SPI_CS0_N_ROM: R201.2 R202.1 R204.2 R207.2 SRCON1.1 U3.1
SPI_CS0_N_ROM_CPU: R129.1 R201.1
SPI_CS0_N_ROM_KBC: R207.1 R368.2
SPI_CS0_R_CPU: CPU1.B57 R127.1 R129.2
SPI_CS_CPU_MUX: R127.2 U2.3
SPI_CS_KBC_MUX: R365.2 U2.1
SPI_CS_ROM_MUX: R202.2 U2.8
SPI_DATAIN_N_CPU: CPU1.B58 R123.2
SPI_DATAIN_ROM: R123.1 R377.2 SRCON1.2 U3.2
SPI_DATAOUT_N_CPU: CPU1.A58 R122.2
SPI_DATAOUT_ROM: R122.1 R371.2 SRCON1.5 U3.5
SPI_IO2_N_CPU: CPU1.B60 R117.2
SPI_IO2_ROM: R117.1 R209.2 SRCON1.3 U3.3
SPI_IO3_N_CPU: CPU1.B61 R111.2
SPI_IO3_ROM: R111.1 R194.2 SRCON1.7 U3.7
SPKR_DET: R475.1 R745.2 U14.48
SPKR_DET_C: PC126.2 R475.2 SPK1.6
SPKR_IN_L: C187.2 C191.2 U22.6
SPKR_IN_R: C217.2 U22.31
SPKR_L+_C: C231.1 L12.2 R504.1 SPK1.1
SPKR_L+_SNB: C545.1 R504.2
SPKR_L-_C: C228.1 L13.2 R496.1 SPK1.2
SPKR_L-_SNB: C540.1 R496.2
SPKR_OUT_L+: C183.2 C212.1 L12.1 U22.16
SPKR_OUT_L-: C193.2 C211.1 L13.1 U22.18
SPKR_OUT_R+: C210.2 C213.1 L15.1 U22.25
SPKR_OUT_R-: C199.2 C214.1 L14.1 U22.23
SPKR_R+_C: C222.1 L15.2 R487.1 SPK1.4
SPKR_R+_SNB: C525.1 R487.2
SPKR_R-_C: C223.1 L14.2 R489.1 SPK1.3
SPKR_R-_SNB: C538.1 R489.2
SRTCRST_APS: R150.2 TP33.1
SSTCMP: R781.1 U35.11
SSTCMP_1: C515.1 R781.2
STATUS: R785.1 U35.8
STRAP0: GPU1.D1 R282.1 R665.2
STRAP1: GPU1.D2 R285.1 R667.2
STRAP2: GPU1.E4 R279.1 R661.2
STRAP3: GPU1.E3 R281.1 R660.2
STRAP4: GPU1.D3 R692.1 R697.2
STRAP_REF0: GPU1.F6 R277.2
SUS_LED_GREEN_C: PWRCN1.7 Q72.D R493.2 R495.2
SUS_LED_GREEN_C2: R495.1 R501.2
SUS_PWR_ACK_CPU: R80.1 U14.60
SUS_PWR_ACK_CPU_R: CPU1.AC63 R80.2 RN2.4(B)
SUSCLK: R378.1 U14.77
SUSCLK_NGFF: NGFF1.50 TP8.1
SUSCLK_SIO_C: CPU1.AE62 R378.2
SVID0_ALERT#_CPU_R: CPU1.B17 R170.2
SVID0_CLK_CPU_R: CPU1.C17 R545.2
SVID0_DATA_CPU_R: CPU1.C18 PR56.2 R168.2
SW_ON_N_SIO: R345.1 U14.117
SWR_LX: L20.2 U31.17
SWR_V12: C401.2 C445.1 C448.1 C449.1 L20.1 U31.11 U31.15 U31.43
SYNC: TP53.1 U22.11
SYS_FAN_TACH1_1: FANC3.3 R58.2 R71.2
SYS_FAN_TACH1_2: R71.1 R72.2 R76.2
SYS_PEX_RST_MON_GPU#: GPU1.D10 R272.2
SYS_PRES: BAT2.6 R731.2
SYS_PWRGD: C64.1 Q15.D R225.2 R228.2
SYS_PWRGD_G: Q15.G Q16.D R227.2
SYSTEM_FAN_PWM1_1: D1.A FANC3.4 R73.2 R79.2
T_CRIT#: R335.2 R342.1 U12.4
TAP_PRDY#: CPU1.C21 R543.2 R544.1
TAP_PREQ#: CPU1.C20 R556.2 RN18.4(B)
THERM_SYS_SHDN#: Q34.S R342.2
TP_DET: R491.2 TOUCH1.1 U14.124
TP_NGFF_COEX1: NGFF1.48 TP10.1
TP_NGFF_COEX2: NGFF1.46 TP9.1
TP_NGFF_COEX3: NGFF1.44 TP12.1
TP_NGFF_LED1: NGFF1.6 TP28.1
TP_NGFF_LED2: NGFF1.16 TP27.1
TP_NGFF_MLDIR: NGFF1.17 TP26.1
TPA3131_BSNL: C193.1 U22.19
TPA3131_BSNR: C199.1 U22.22
TPA3131_BSPL: C183.1 U22.15
TPA3131_BSPR: C210.1 U22.26
TPA3131_FAULT#: R468.2 U22.30
TPA3131_GAIN: R451.1 R454.2 U22.3
TPA3131_GVDD: C197.2 R454.1 R461.2 U22.2
TPA3131_LINN: C194.2 U22.5
TPA3131_LINN_1: C194.1 R440.2
TPA3131_MUTE: R435.2 R438.1 U22.7
TPA3131_PLIMIT: C200.2 R461.1 R462.2 U22.1
TPA3131_RINN: C215.2 U22.32
TPA3131_RINN_1: C215.1 R466.2
TPA3131_SD: Q69.3 Q70.G Q2801.D R435.1 RN23.3(B)
TPA3131_SD1#: C509.1 Q70.D R468.1 RN23.4(B) U22.29
TPM_CLKRUN_N: R654.1 U7.13
TPM_GPIO0: TP45.1 U7.29
TPM_GPIO1: TP44.1 U7.30
TPM_GPIO2: R252.1 U7.3
TPM_GPIO3: TP49.1 U7.6
TPM_LCLK: R264.2 U7.19
TPM_LPCPD_N: R234.2 U7.28
TPM_PP: TP48.1 U7.4
TPM_RST_N: R266.2 U7.17
TPM_SERIRQ: R235.2 U7.27
TRST_PD: R56.1 XDP1.8
U15_ZQ: R679.1 VRAM4.L8
U19_ZQ: R258.1 VRAM1.L8
U35_ZQ: R291.1 VRAM2.L8
U36_ZQ: R643.1 VRAM3.L8
USB1N_C_EXT: SSUSB2.2 TR4.1 U6.6
USB1P_C_EXT: SSUSB2.3 TR4.4 U6.1
USB2N_EXT: TR9.4 U25.3 USB3.2
USB2P_EXT: TR9.1 U25.4 USB3.3
USB3N_EXT: TR10.1 U25.1 USB4.2
USB3P_EXT: TR10.4 U25.6 USB4.3
USB30_RX_CPU_N0: CPU1.K10 L5.1
USB30_RX_CPU_N1: CPU1.G2 L7.1
USB30_RX_CPU_P0: CPU1.K9 L5.4
USB30_RX_CPU_P1: CPU1.F2 L7.4
USB30_TX_CPU_N0: C63.1 CPU1.J2
USB30_TX_CPU_N0_EMI: C63.2 L4.1
USB30_TX_CPU_N1: C94.2 CPU1.K2
USB30_TX_CPU_N1_EMI: C94.1 L6.1
USB30_TX_CPU_P0: C60.1 CPU1.J1
USB30_TX_CPU_P0_EMI: C60.2 L4.4
USB30_TX_CPU_P1: C92.2 CPU1.K3
USB30_TX_CPU_P1_EMI: C92.1 L6.4
USB_DN5: CPU1.AB7 TP72.1
USB_DP5: CPU1.AB6 TP75.1
USB_EN_1: C81.1 R263.1 U8.4
USB_EN_2: C190.1 R441.1 U23.4
USB_OTGID: CPU1.AC15 R177.2 R1703.1
USB_PCH_DN1_NN: TR2.4 WEBCM1.2
USB_PCH_DN4_NN: C232.1 TOUCH1.4 TR11.4
USB_PCH_DN5_NN: NGFF1.5 TR1.4
USB_PCH_DP1_PP: TR2.1 WEBCM1.1
USB_PCH_DP4_PP: C229.1 TOUCH1.3 TR11.1
USB_PCH_DP5_PP: NGFF1.3 TR1.1
USB_RCOMP: CPU1.Y15 R600.2
USB_SSIC_RCOMP: CPU1.AB15 R597.2
USB_VBUSSNS: CPU1.AC16 R1701.2 R1702.1
USBOC01: CPU1.C55 RN7.4(B) U8.3
USBOC02: CPU1.B55 RN7.3(B) U23.3
USBP0N_EXT: SSUSB1.2 TR3.1 U6.4
USBP0P_EXT: SSUSB1.3 TR3.4 U6.3
USBVCC14: C59.2 C88.1 C90.2 C91.1 SSUSB1.1 SSUSB2.1 TC2.1 U6.5 U8.1
USBVCC56: C204.1 C207.2 C208.2 C209.1 TC3.1 U23.1 U25.5 USB3.1 USB4.1
USBVCCTP: C546.1 F8.2 R808.2 TOUCH1.5
V_1P5_HDMI: C169.2 C170.1 C195.1 C205.1 C490.1 C491.1 C503.1 R795.1 U20.12 U20.19 U20.20 U20.31 U20.40 U36.2
V_1P05_LAN: C224.2 C520.1 C524.1 C526.2 C527.2 C528.2 C529.2 C532.1 C533.2 C534.2 C536.1 U26.3 U26.8 U26.22 U26.24 U26.30
V_3_CARD_BD: C38.2 C39.2 C48.2 C49.2 C565.1 F5.2 MEMCD1.4 U39.1
V_3P0_BAT_VREG: D7.3 R89.2 R126.1 R156.1 R571.2 R724.2 R744.2
V_3P3_A: D7.1 PG18.1 PR132.2 PR156.1 PR169.1 PR220.1 PR225.1 PR228.1 PR231.1 PR232.2 R227.1 R515.1 R715.1 R746.1 R784.1 RN23.1(A) RN23.2(A)
V_3P3_LAN: C225.2 C230.1 C521.2 C522.1 C523.1 C530.1 C531.1 C535.1 C539.1 C541.1 C543.2 Q79.D R471.1 R481.2 R797.1 R803.1 R811.2 U24.5 U26.11 U26.23 U26.32 U28.5 U37.5 UR4.1
V_3P3_PCIVAUX: C1.1 C3.2 C11.1 C13.2 NGFF1.2 NGFF1.4 NGFF1.72 NGFF1.74 Q51.D R20.2 R75.1 R542.2 TC4.1
V_5_CODEC: C153.2 C479.1 C480.2 L24.1 U16.39
V_5HDD: C15.1 C16.1 C17.1 R574.2 R575.2 SATAP1.1 SATAP1.3 TC1.1
V_5P0_A: PG6.2
V_5P0_HDMI_CONN: C495.2 HDMI1.18 HDMI2.2 L26.1
V_5P0_HDMI_CONN_L: F7.2 L26.2
V_19_INV: C175.1 C181.1 F2.2 L8.1 R425.2 R771.1
VD1_EN#: R390.2 U14.66
VD_IN1: C469.1 C470.1 R100.1 R733.2 R739.2 U14.104 U14.108
VD_IN2: C471.1 C472.1 R193.1 R730.2 R732.2 U14.94
VD_OUT1#: D4.2 U14.110
VD_OUT2#: D4.1 U14.112
VGA_CORE_DISCHG: Q12.3 R223.1
VID_PLLVDD: GPU1.N6
VNN_CTRL: Q4501.G R4501.1 U14.119
VNN_VCC_SENSE: CPU1.AG48 PG14.1 PR204.1
VNN_VSS_SENSE: PC138.1 PC143.2 PG13.2 PR199.1 PR242.2
VOUT_INV: C492.1 C493.1 C496.1 C497.1 C499.1 CONVT1.3 CONVT1.4 D10.K U35.18
VR_SVID_ALERT#: R169.2 R170.1 R539.2
VR_SVID_CLK: PR192.2 PR195.2 R545.1
VR_SVID_DATA: PR189.2 PR191.2 R168.1
VREF: C501.2 U35.2
VREF_1: C149.1 U16.41
VREF_CA_DIMM1: C341.1 C342.1 DIMM1.126 R610.2 R612.2 R617.1
VREF_DQ_DIMM1: C274.1 C275.1 DIMM1.1 R578.1 R581.2 R611.2
VREFC_U20: C103.1 R283.1 R284.2 VRAM2.M8
VREFC_U21: C443.1 R669.2 R674.1 VRAM4.M8
VREFC_U22: C372.1 R646.2 R647.1 VRAM3.M8
VREFC_U23: C80.1 R267.1 R268.2 VRAM1.M8
VREFD_U20: C104.1 R287.2 R292.1 VRAM2.H1
VREFD_U21: C444.1 R670.2 R673.1 VRAM4.H1
VREFD_U22: C371.1 R645.2 R652.1 VRAM3.H1
VREFD_U23: C73.1 R253.1 R254.2 VRAM1.H1
VREG_PCIAUX_PCH: Q48.C Q50.D R533.2 R534.1
VREG_PCIAUX_PCH_1: C246.1 PC134.2 Q51.G R534.2
VRP: C146.2 U16.38
VTT_EN: PC27.1 PR40.2 PR84.1 PR208.2 PR209.2 R198.2
VTT_EN_R: D2.3 R94.2 R198.1
WAKE_N_APU: CPU1.AG55 R517.2 R520.2
WEBCAM_DET: R91.2 R92.2 U14.34
WEBCAM_DET_M: PC24.2 R91.1 WEBCM1.7
XDP_H_TCK: CPU1.B23 R563.1 R567.2
XDP_H_TDI: CPU1.C22 R546.2 R559.1
XDP_H_TDO: CPU1.A22 R561.2 RN18.3(B)
XDP_H_TMS: CPU1.C23 R564.2 R565.2
XDP_H_TRST_N: CPU1.C24 R171.2 R560.1
XRF_TDC2: C221.1 XF1.9 XF1.10 XF2.9 XF2.10
XTAL19D2M_IN: C37.2 CPU1.R27 R174.1 X2.1
XTAL19D2M_OUT: C36.2 CPU1.P29 R174.2 X2.3
XTAL_OUTBUFF: GPU1.C10 R299.1 R300.2
XTAL_SSFOUT: GPU1.A10 R298.1
XTALIN: C114.1 GPU1.C11 X3.1
XTALOUT: C115.1 R816.2 X3.3
XTALOUT_GPU: GPU1.B10 R816.1
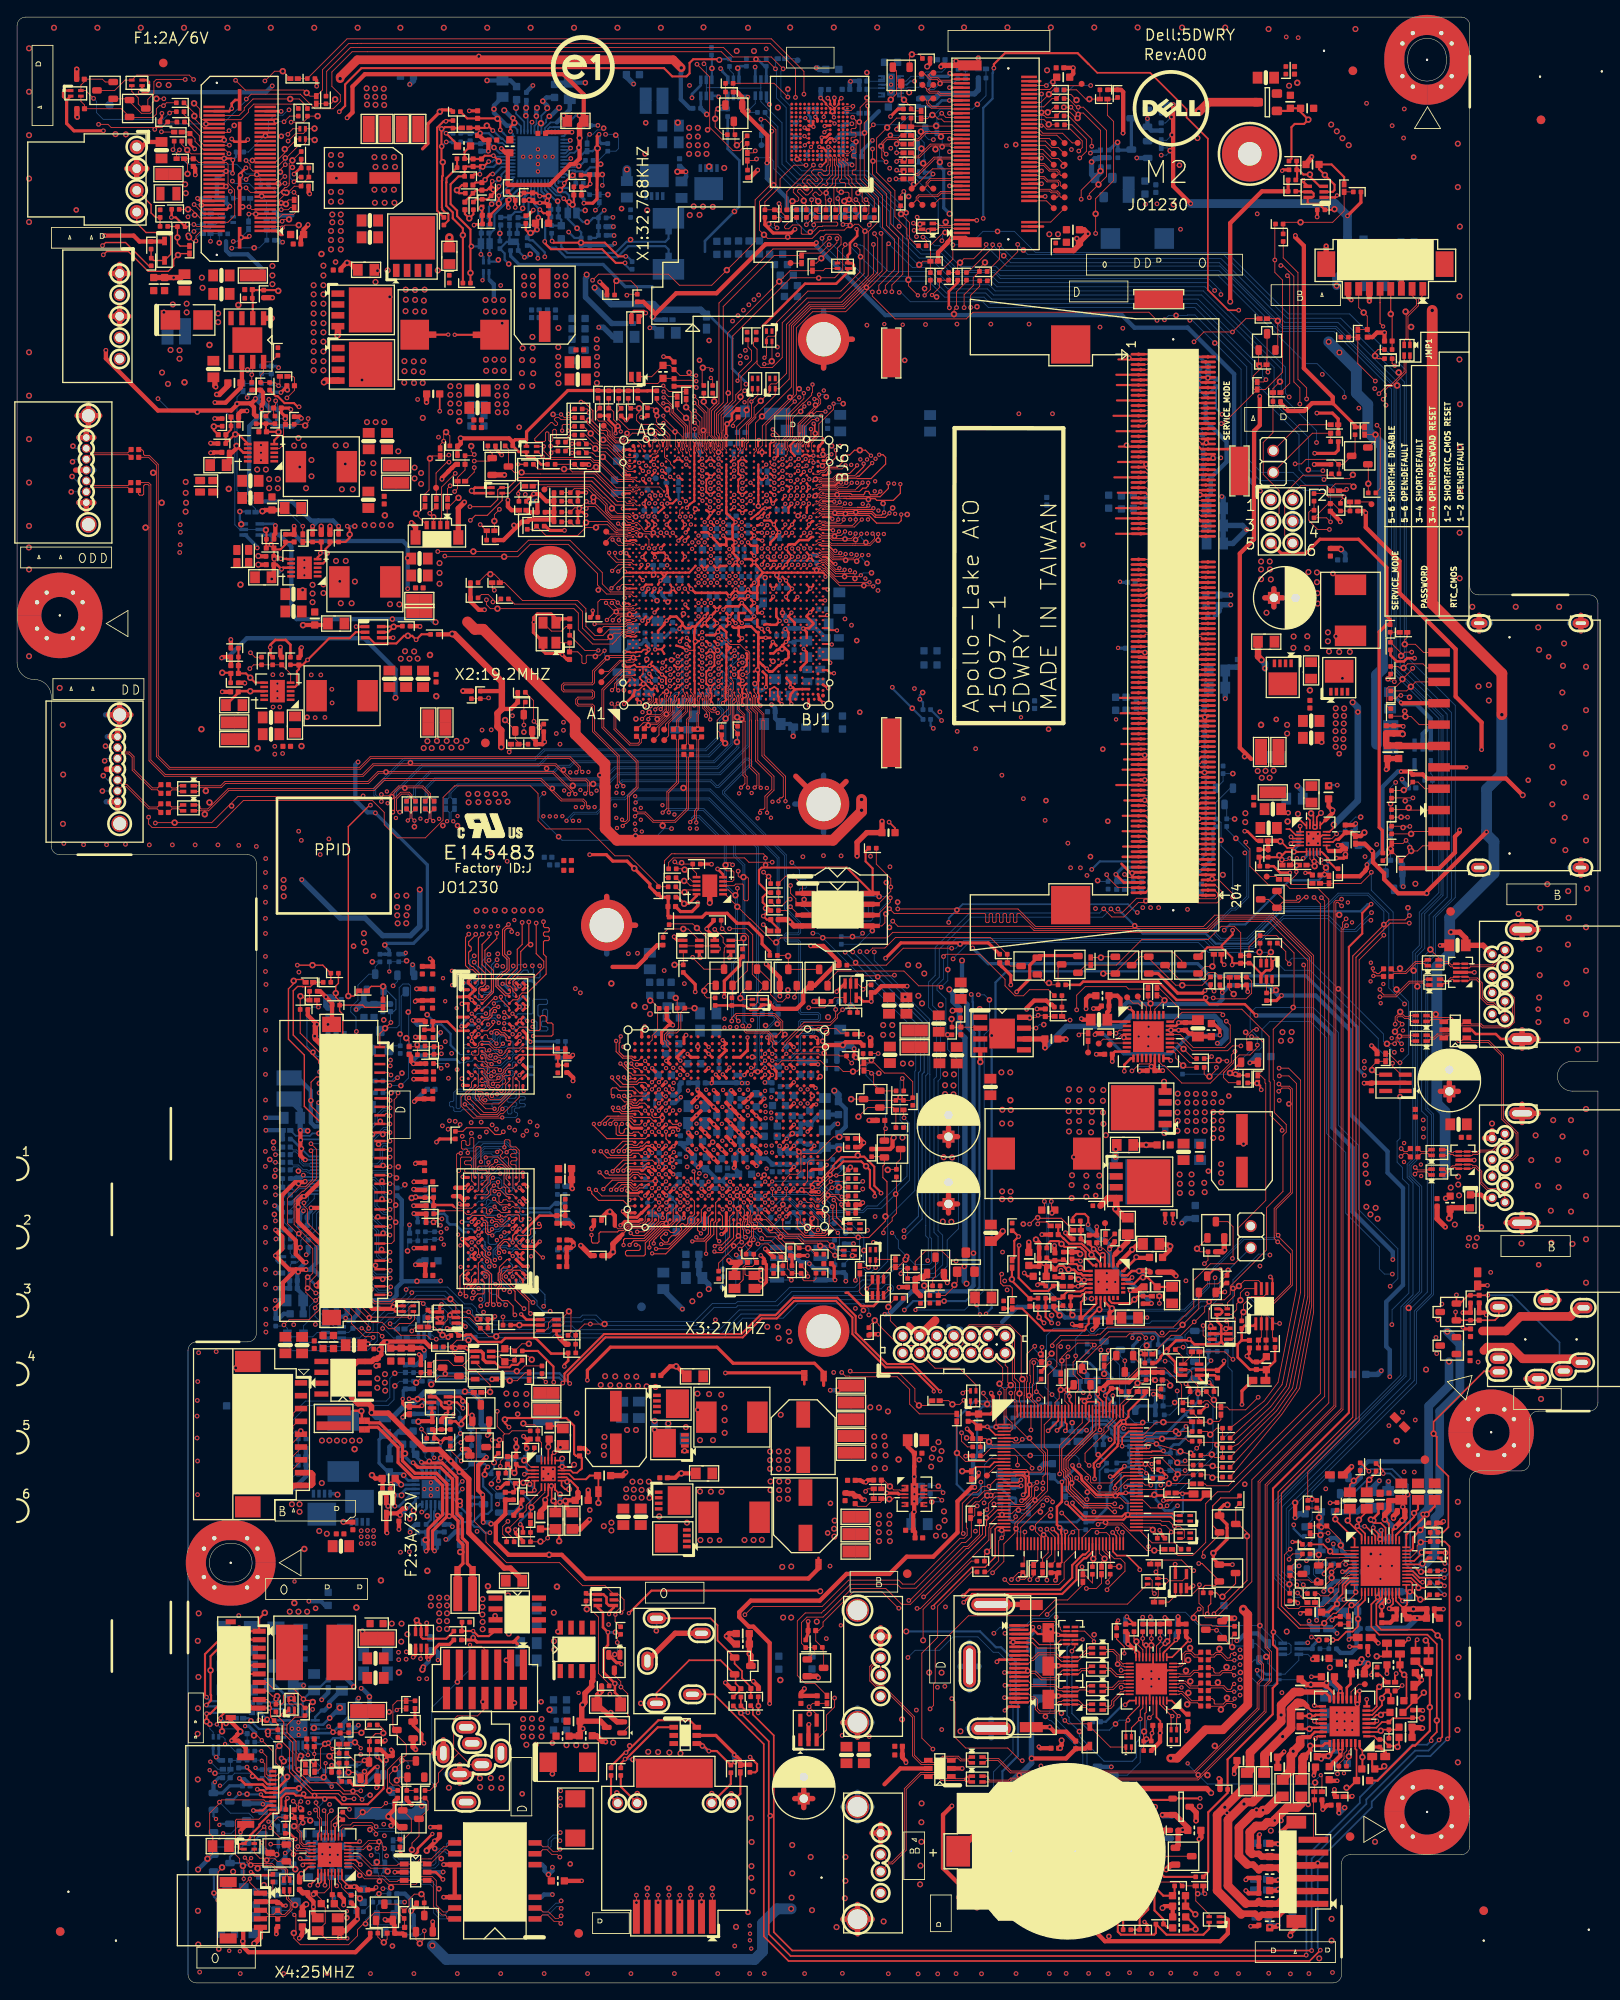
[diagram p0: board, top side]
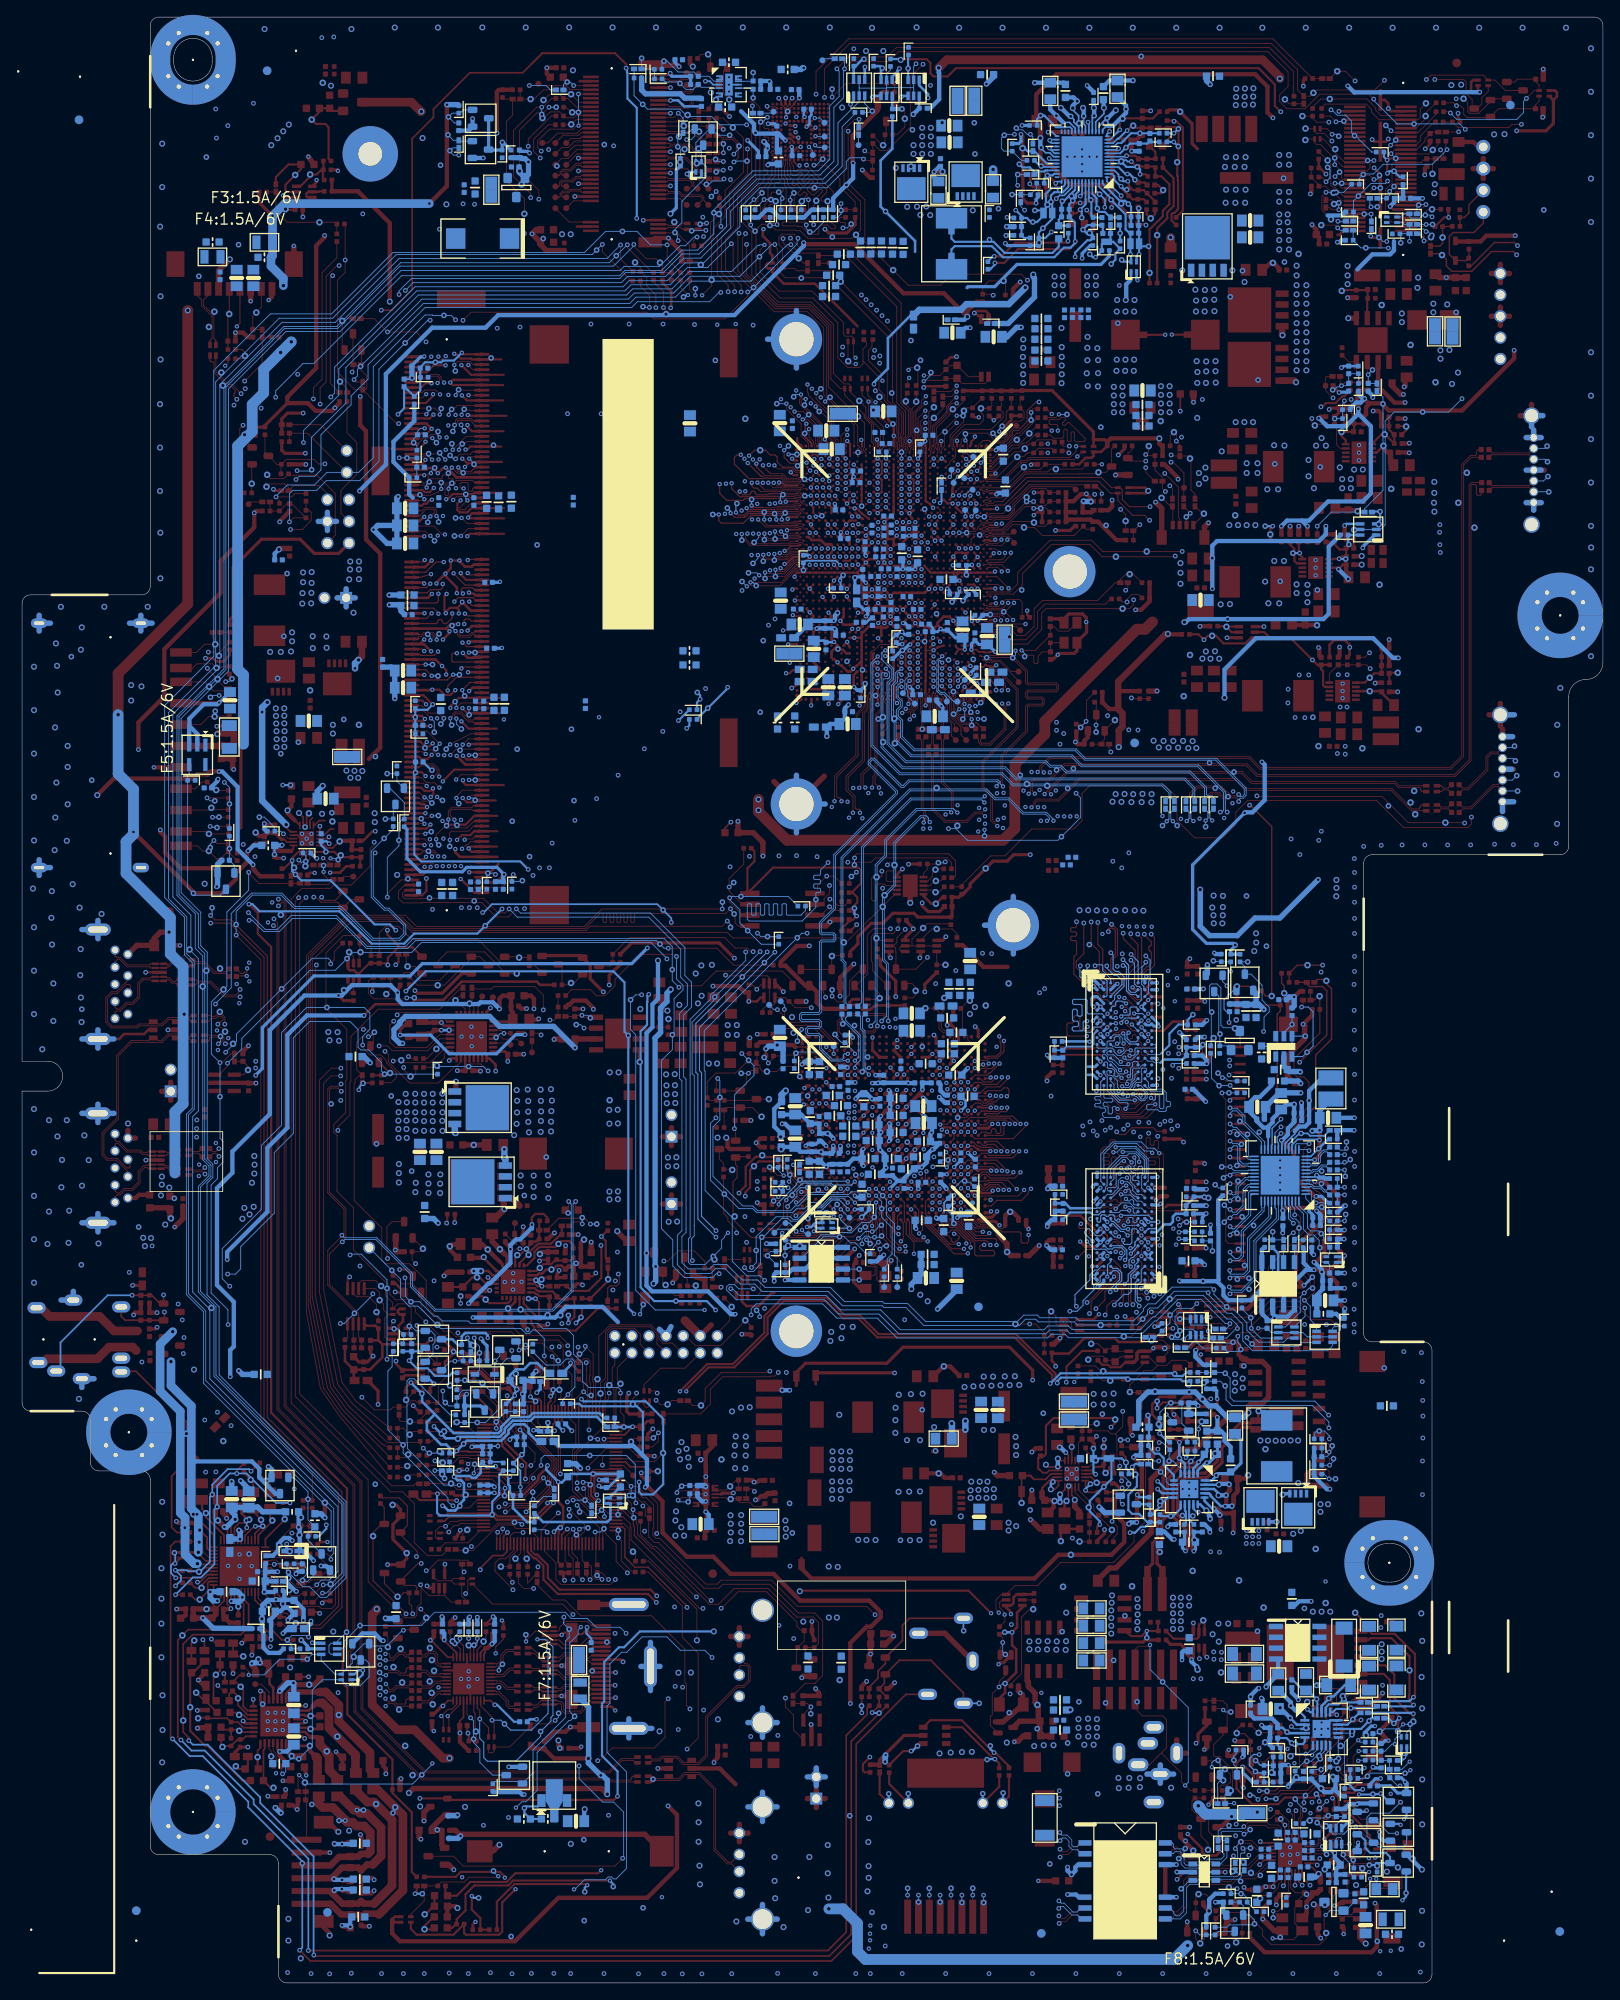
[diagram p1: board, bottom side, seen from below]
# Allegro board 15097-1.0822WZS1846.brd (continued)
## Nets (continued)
Pads without a net: CPU1 A3 A4 A14 A18 A26 A30 A50 A54 A60 A61 AB2 AB3 AB13 AB49 AC1 AC2 AC13 AC20 AC22 AD2 AD3 AE60 AF2 AF3 AF61 AF62 AG15 AG16 AG52 AG54 AG62 AG63 AH12 AH13 AJ44 AK6 AK7 AK13 AK15 AK16 AK61 AL62 AL63 AM5 AM6 AM7 AM9 AM10 AM12 AM13 AM15 AM16 AM32 AM49 AM51 AM52 AM55 AM57 AM58 AM59 AM62 AN32 AP2 AP3 AP5 AP6 AP10 AP12 AP13 AP15 AP52 AP54 AP57 AP59 AP61 AP62 AR1 AR2 AR21 AR23 AR25 AR27 AR29 AR30 AR62 AT5 AT6 AT9 AT10 AT21 AT23 AT27 AT30 AT43 AU1 AU2 AV5 AV6 AV7 AV10 AV12 AV16 AV17 AV25 AV27 AV47 AV48 AW1 AW2 AW16 AW17 AW19 AW21 AW23 AW25 AW27 AW29 AW45 AW47 AW48 AY2 AY3 AY5 AY7 AY9 B4 B13 B15 B21 B25 B37 B47 B51 B53 BA14 BA19 BA23 BA30 BA45 BB1 BB5 BB6 BB7 BB10 BB12 BB14 BB16 BB17 BB21 BB23 BB27 BB29 BB30 BB41 BB43 BB47 BC2 BD1 BD2 BD5 BD6 BD10 BD12 BD14 BD16 BD17 BD19 BD21 BD23 BD25 BD27 BD29 BD30 BD43 BD47 BE2 BE8 BE14 BE19 BE23 BE25 BE30 BF5 BF6 BG1 BG2 BG7 BG8 BG9 BG10 BG11 BG12 BG13 BG14 BG15 BG16 BG17 BG18 BG20 BG21 BG22 BG24 BG25 BG26 BG27 BG28 BG30 BG31 BG63 BH3 BH4 BH6 BH7 BH9 BH11 BH13 BH15 BH17 BH19 BH23 BH27 BH29 BH31 BH58 BJ2 BJ3 BJ6 BJ12 BJ16 BJ20 BJ22 BJ24 BJ26 BJ30 BJ58 BJ61 BJ62 C1 C2 C9 C13 C14 C15 C19 C25 C27 C29 C30 C35 C36 C37 C38 C42 C44 C45 C47 C51 C52 C54 C57 C62 C63 D1 D2 D4 D8 D61 E3 E6 E8 E10 E16 E17 E23 E25 E30 E52 E63 F1 F8 F12 F14 F16 F17 F19 F23 F25 F30 F34 F35 F39 F48 G62 H10 H12 H14 H16 H19 H21 H25 H30 H34 H35 H43 H48 H50 H54 H57 H59 H63 J16 J17 J21 J23 J25 J29 J34 J43 J45 J50 J62 K59 K61 L14 L16 L17 L19 L23 L25 L30 L34 L37 L39 L47 L48 L62 M10 M12 M16 M17 M19 M23 M25 M29 M30 M34 M35 M37 M39 M43 M45 M47 M48 M52 M54 M57 M61 M62 P17 P21 P23 P25 P27 P30 P34 P39 P47 P52 P54 P57 P58 R17 R19 R21 R25 R30 R34 R35 R37 R39 T51 T52 T54 T55 T57 V48 V49; DIMM1 77 122 125; GPU1 A7 AA1 AA2 AA3 AA4 AA5 AA6 AB1 AB2 AB3 AB4 AB5 AB6 AB12 AB13 AB15 AB16 AB18 AB19 AB21 AC3 AC4 AC11 AC12 AC13 AC14 AC15 AC16 AC17 AC18 AC19 AC20 AC21 AD1 AD2 AD3 AD4 AD5 AD7 AD10 AD11 AD14 AD17 AD20 AD23 AE1 AE3 AE4 AE9 AE10 AE12 AE13 AE15 AE16 AE18 AE19 AE21 AE23 AE24 AF2 AF3 AF4 AF9 AF10 AF12 AF13 AF15 AF16 AF18 AF19 AF21 AF24 AG3 AG9 AG10 AG12 AG13 AG15 AG16 AG18 AG19 AG21 AG22 AG24 AG25 B3 B7 B19 C1 C2 C3 C8 C9 C18 C26 D4 D5 D16 D17 D18 E6 E9 E10 F4 F5 F7 F10 G1 G2 G3 G4 G5 G6 G7 G27 H3 H4 J1 J2 J3 J4 J5 J26 K1 K2 K3 K4 K5 K6 L3 L4 M1 M2 M3 M4 M5 M23 N1 N2 N3 N4 N5 P3 P4 R1 R2 R3 R4 R5 T1 T2 T3 T4 T5 T6 T24 U3 U4 U6 U24 V1 V2 V3 V4 V5 V6 V24 V25 W1 W2 W3 W4 Y3 Y4; HDMI1 13 14; HDMI2 6 7; LPC1 10; NGFF1 64; PU2 7; PU3 7; PU4 7; PU10 19; PU13 24 25 26 39; SATAP1 5; TOUCH1 6 7; U1 A1 A2 A7 A8 A9 A10 A11 A12 A13 A14 B1 B7 B8 B9 B10 B11 B12 B13 B14 C1 C3 C5 C7 C8 C9 C10 C11 C12 C13 C14 D1 D2 D3 D4 D12 D13 D14 E1 E2 E3 E5 E8 E12 E13 E14 F1 F2 F3 F12 F13 F14 G1 G2 G3 G10 G12 G13 G14 H1 H2 H3 H12 H13 H14 J1 J2 J3 J12 J13 J14 K1 K2 K3 K6 K7 K12 K13 K14 L1 L2 L3 L12 L13 L14 M1 M2 M3 M7 M8 M9 M10 M11 M12 M13 M14 N1 N3 N6 N7 N8 N9 N10 N11 N12 N13 N14 P1 P2 P7 P8 P9 P10 P11 P12 P13 P14; U7 2 5 7 10 11 12 25 26 31; U11 17 18 19 20; U14 9 36 37 38 41 49 51 53 71 72; U16 15 16 17 34 37 45 46; U18 5 6; U24 3; VRAM1 J1 J9 L1 L9 M7; VRAM2 J1 J9 L1 L9 M7; VRAM3 J1 J9 L1 L9 M7; VRAM4 J1 J9 L1 L9 M7; XDP1 14 18 20 22 24 26 28 30 32 35 37 39 41 43 44 45 46 47 49 51 52 53 55 59 60

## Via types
v1: diameter 0.559, hole 0.305, TOP to BOTTOM, 1796 vias
v2: diameter 0.66, hole 0.33, TOP to BOTTOM, 887 vias
v3: diameter 0.508, hole 0.254, TOP to BOTTOM, 1656 vias
v4: diameter 0.762, hole 0.381, TOP to BOTTOM, 542 vias
v5: diameter 0.711, hole 0.406, TOP to BOTTOM, 958 vias

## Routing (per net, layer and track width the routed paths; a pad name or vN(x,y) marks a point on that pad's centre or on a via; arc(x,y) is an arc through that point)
1V_CPU_VCGI: length 8.4
  TOP w0.254: CPU1.E37 73.18,166.88 v3(73.18,166.82) 73.22,166.82 CPU1.E35 ; CPU1.E43 73.9,170.45 v3(73.9,170.61) 73.9,170.79 CPU1.E45 ; v3(73.17,163.13) CPU1.E29 CPU1.F29 ; CPU1.E48 v3(73.32,173.08) CPU1.E50
  BOTTOM w0.305: RN15.1 55.22,199.29 55.33,199.19
  BOTTOM w0.508: 55.79,196.94 55.79,198.73 55.33,199.19
  vias: v2(56.76,194.19) v2(58.14,170.53) v2(58.75,182.02) v2(68.01,162.97) v2(72.94,169.41) v3(71.11,162.06) v3(73.12,174.24) v3(73.97,173.11) v3(74.67,173.11) v3(78.21,171.55) v3(78.86,171.57) v3(78.85,170.63) v3(79.01,168.54) v3(78.99,167.78) v3(79.74,169.33) v3(79.74,168.54) v3(79.74,165.39) v3(79.74,164.61) v3(79.74,163.82) v3(80.47,168.54) v3(80.47,164.61) v3(80.47,163.82) v3(81.19,167.76) v3(81.19,166.97) v3(81.19,166.18) v3(81.19,163.82) v3(81.91,164.61) v3(81.91,163.82) v3(83.36,167.76) v3(83.36,166.97) v3(83.36,166.18) v3(83.36,164.61) v3(83.36,163.82) v3(84.09,164.61) v3(84.08,163.82) v3(84.81,166.18) v3(84.81,163.82) v5(54.82,196.9) v5(54.86,195.55) v5(54.86,189.92) v5(54.9,188.61) v5(55.83,196.9) v5(55.88,195.55) v5(55.88,189.92) v5(55.91,188.61) v5(56.22,186.74) v5(56.22,185.72) v5(56.22,184.71) v5(56.25,183.76) v5(56.85,196.9) v5(56.89,195.55) v5(56.89,189.92) v5(56.93,188.61) v5(57.23,186.74) v5(57.23,185.72) v5(57.23,184.71) v5(57.22,183.76) v5(59.08,189.87) v5(59.08,188.34) v5(59.1,186.78) v5(59.16,191.26) v5(60.31,192.58) v5(60.33,191.31) v5(60.33,189.85) v5(60.28,186.84) v5(60.4,188.32) v5(63.33,191.39) v5(63.33,190.25) v5(63.33,189.23) v5(63.33,188.21) v5(63.36,193.62) v5(63.36,187.17)
1V_CPU_VNN: length 48.1
  L3 w0.635: 86.14,184 86.14,176.48 86.93,175.69 86.93,173.1
  BOTTOM w0.305: 80.5,202.54 80.5,203.8 v2(83.95,207.26) 84.53,207.83 84.53,213.22 83.15,214.59 R527.1
  BOTTOM w0.381: PR204.2 57.75,202.04 58.74,201.06 68.57,201.06 71.17,198.46 74.29,198.46 74.42,198.34
  vias: v1(83.73,194.44) v1(84.36,195.07) v1(84.62,190.35) v1(84.64,189.51) v1(85,195.71) v1(85.23,191.01) v1(85.36,190.17) v1(85.63,196.34) v1(86.24,196.95) v1(86.77,197.49) v1(88.96,191.4) v1(89.01,190.48) v3(84.81,170.91) v3(84.81,170.12) v3(84.81,169.33) v3(84.81,168.54)
1V_VCCIOA: length 12.1
  TOP w0.305: CPU1.AM25 v3(86.26,161.46) CPU1.AM23 ; CPU1.AM42 v3(86.26,169.33) CPU1.AM41
  L3 w0.381: v3(86.26,170.12) 86.26,170.12 v3(86.26,169.33)
  L3 w0.508: v3(86.26,161.46) 86.26,161.56 87.13,162.43 87.13,164.03 85.61,165.56 85.61,167.44 86.29,168.12 86.29,169.3 v3(86.26,169.33)
  vias: v2(86.74,172.78) v2(87.18,179.07)
3V3_VDD33:
  vias: v2(87.43,94.52) v3(86.72,94.57) v3(87.71,95.27)
3V_5V_POK: length 179.8
  TOP w0.102: v1(31.58,185.45) 32.46,186.32 PC198.1 32.46,187.79 32.29,187.96 PR243.1 ; v1(62.09,52.04) 61.68,51.64 v4(61.25,51.64) 61.22,51.61 PR171.2 PR169.2 PR166.1
  L3 w0.127: v1(62.09,52.04) 58.65,52.04 56.65,54.05 56.65,54.15 55.27,55.52 53.64,55.52 50.99,58.18 50.99,60.79 48.25,63.53 46.01,63.53 37.97,71.57 37.97,78.68 39.14,79.84 39.14,106.01 37.75,107.39 37.75,117.04 36.18,118.62 36.18,129.72 34.36,131.53 34.36,134.55 31.55,137.36 23.41,137.36 18.11,142.66 17.77,142.99 17.77,169.15 18.35,169.72 v1(19.11,169.72)
  L4 w0.127: v1(31.58,185.45) 30.77,184.63 30.77,183.69 29.29,182.22 23.17,182.22 20.73,179.78 20.73,170.81 19.64,169.72 v1(19.11,169.72)
3V_VA: length 19.1
  TOP w0.203: U16.25 162.57,45.85 162.67,45.75 162.67,44.28 162.33,43.94 C163.1 161.36,44.71 161.36,45.07 161.35,45.08 U16.23
  TOP w0.635: 163.53,42.7 C165.1 162.33,43.14 C163.1 v4(163.41,43.74) C162.1 164.97,42.71 C166.2 164.91,42.69 164.06,42.69 163.53,42.7 ; 163.53,42.7 v1(163.84,42.7)
  BOTTOM w0.635: L25.2 162.64,41.5 v1(163.84,42.7)
19V_AMP_AVCC: length 5.8
  TOP w0.305: U22.12 155.6,34.54 156.04,34.98 156.04,36.07 C178.1
  TOP w0.635: C178.1 156.14,37.29 R433.2 156.9,37.41 v4(157.34,37.86)
19V_AMP_PVCC: length 14.3
  TOP w0.305: U22.28 155.1,27.32 v1(154.85,27.07) 154.6,27.32 U22.27 ; U22.14 154.6,33.89 v1(154.85,34.14) 155.1,33.89 U22.13
  TOP w0.508: v1(154.85,27.07) 154.85,26.58 154.06,25.78 C216.1 ; v1(154.85,34.14) 154.85,34.54 154.16,35.23 C180.1
  BOTTOM w0.508: v1(154.85,27.07) 153.99,27.07 C506.2
  BOTTOM w0.635: v1(154.85,34.14) 153.9,35.1 v2(153.24,35.1) 153.2,35.06 C500.1
  vias: v5(153.63,36.91)
+5V_PWR: length 2.4
  TOP w0.305: PG3.2 92.12,70.04
  TOP w0.381: PGT1.2 94.39,69.91
  BOTTOM w0.508: v1(95.16,69.34) v2(96.05,69.34)
AGND: length 43.9
  TOP w0.203: U16.28 163.29,47.77 164.17,46.89 v1(164.47,46.89) ; U16.42 159.74,52.84 v1(159.62,52.96) ; U16.22 160.95,45.01 161.02,44.94 161.02,44.35 160.56,43.89 v1(160.56,43.79)
  TOP w0.381: C124.2 169.39,76.52 v1(169.2,76.71) ; R316.2 v1(172.07,81.61)
  TOP w0.508: R424.2 158.63,40.41 v1(159.29,39.75) ; v1(171.94,78.16) 171.94,78.23 171.75,78.42 C123.2 C121.2 ; R387.2 166.71,53.82 166.89,54 v1(166.94,54) ; v1(82.89,35.13) 83.6,34.42 C185.1 ; v1(166.91,43.74) 165.88,43.74 C162.2 165.86,43.01 C166.1 ; v1(154.69,19.89) 154.66,19.93 C218.1 ; v1(169.2,78.42) R326.2 R319.2 ; C167.2 160.7,42.15 C165.2 161.44,42.89 C163.2 160.71,43.74 160.66,43.79 v1(160.56,43.79) ; v1(86.16,35.28) 86.76,34.68 C184.1
  TOP w0.635: R375.2 155.2,59.44 v1(156.17,60.4) ; v1(161.07,54.36) 161.07,54.58 161.51,55.03 C153.1 ; LOUT1.5 77.01,40.91 LOUT1.P ; EC2901.2 83.32,40.87 v1(83.01,40.56) 83.93,39.65 R437.2
  BOTTOM w0.635: C479.2 160.46,58.65 v1(160.48,58.67) ; v1(156.17,60.4) 155.8,60.04 Q66.S ; v1(159.42,58.75) 158.48,57.81 C480.1 ; v1(154.69,19.89) 154.74,19.89 v2(155.35,20.5) ; v1(159.62,52.96) 159.62,52.94 159.47,52.79 159.47,51.94 v2(159.49,51.92) 159.52,51.94 R747.2
  vias: v1(162.31,59.79) v1(163.51,59.77) v1(163.62,65.86) v1(170.98,72.64) v4(161.45,63.4) v5(152.38,2.87)
AVCC33_2136: length 20.5
  TOP w0.508: v1(33.82,84.33) 33.56,84.33 32.61,85.28 32.61,86.85 30.97,88.49 30.97,92.13 32.54,93.69 33.6,93.69 33.69,93.78 v1(33.71,93.78)
  BOTTOM w0.203: v1(33.71,93.78) 33.84,93.9 U31.5
  BOTTOM w0.508: v1(33.82,84.33) 33.77,84.33 32.9,83.46 v2(32.9,83.19) 32.79,83.07 C459.1 C460.2 32.79,81.16 33.47,80.48 C461.2
  BOTTOM w0.635: L23.2 C461.2
DVCC33_2136: length 58.1
  TOP w0.305: RN35.1 44.32,79.21 43.98,78.87 44.28,78.56 RN35.2
  TOP w0.508: 43.98,78.87 41.59,78.87 38.97,81.48 35.11,81.48 v1(34.98,81.61) 35.92,82.55 35.92,86.03 32.85,89.1 32.85,91.49 33.39,92.02 v1(33.56,92.02) 33.72,92.02 36.15,94.45 36.15,97.12 v1(37.63,98.59)
  BOTTOM w0.203: U31.22 39.18,99.02 ; U31.18 37.58,98.54 v1(37.63,98.59)
  BOTTOM w0.305: v1(34.98,81.61) 34.97,81.61 v2(34,82.58)
  BOTTOM w0.381: v1(33.56,92.02) 32.91,92.02 32.12,91.24 R672.1
  BOTTOM w0.508: 36.14,102.78 C397.1 C404.1 36.14,100.69 36.86,99.96 36.86,99.26 37.52,98.6 37.62,98.6 v1(37.63,98.59) ; 36.14,102.78 37.05,102.78 C391.1 37.65,102.11 38.65,101.1 38.65,100.7 39.18,100.18 39.18,100.06 ; 36.14,102.78 v2(36.13,102.79) ; 39.18,99.02 39.18,100.06 ; 39.18,100.06 39.73,100.06 40.49,100.82 40.51,100.82 C402.1 41.41,101.97 C396.2 41.41,102.92 40.7,103.63 40.17,103.63 38.78,105.02 L19.2
GND: length 2211.6
  TOP w0.089: 97.81,219.28 97.6,219.07 96.91,219.07 U1.N2 96.91,219.56 v1(97.81,219.56) 97.81,219.28
  TOP w0.127: VRAM2.B3 57.7,83.14 57.87,83.14 58.11,83.38 58.86,83.38 VRAM2.B1 ; CPU1.U13 v3(78.33,155.91) ; CPU1.U1 79.33,150.23 79.33,150.83 79.29,150.87 CPU1.U2 ; U1.N5 U1.P6 ; U1.C4 95.16,214.82 v3(94.93,214.82)
  TOP w0.152: CPU1.D6 72.88,152.78 73.25,153.15 73.25,153.91 ; CPU1.E4 73.47,151.98 72.73,151.24 CPU1.B3
  TOP w0.178: v3(85.52,88.57) 85.48,88.61 GPU1.B11
  TOP w0.203: v3(71.11,168.86) 71.26,168.71 CPU1.A40 ; CPU1.A5 71.69,152.43 71.03,151.77 71.03,151.36 71.01,151.34 v1(71.01,151.26) ; CPU1.BH39 94.02,168.24 94.11,168.15 94.98,168.15 95.57,167.55 v3(95.76,167.55) ; U14.5 116.79,63.73 v1(116.9,63.63) ; CPU1.C28 CPU1.A28 ; CPU1.Y52 CPU1.Y54 CPU1.Y55 ; v1(146.67,82.6) 146.91,82.36 U12.5 ; CPU1.BH21 94.67,159.9 v3(94.8,160.03) ; GPU1.E8 87.96,92.5 87.55,92.1 v3(87.54,92.1) ; CPU1.AN5 86.75,151.25 CPU1.AN2 86.76,150.91 86.83,150.63 86.83,150.31 CPU1.AN1 ; v3(151.7,133.88) 152.36,133.88 152.76,134.28 PU5.14 ; U20.8 134.63,36.57 v3(133.63,35.57) ; GPU1.AF8 87.96,110.45 v3(87.79,110.62) ; CPU1.AV2 CPU1.AV3 88.62,151.65 CPU1.AT3 CPU1.AT2 ; v3(71.63,102.41) 71.68,102.41 71.69,102.4 72.74,102.4 72.83,102.48 GPU1.U26 ; v3(132.74,36.46) 132.94,36.66 U20.15 ; CPU1.C16 72.39,157.51 72.29,157.51 72.29,157.51 71.87,157.51 71.87,157.51 71.76,157.51 CPU1.A16 ; U14.89 132.18,62.53 v1(132.37,62.72) ; v3(74.02,154.08) 73.91,153.97 73.31,153.97 73.25,153.91 73.18,153.97 72.51,153.97 CPU1.B9 CPU1.A9 ; CPU1.Y5 CPU1.Y6 CPU1.Y7 ; U15.11 v3(105.01,57.18) ; v1(120.66,64.6) 121.85,65.79 U14.116 ; PU5.1 v1(150.15,135.33) ; CPU1.BE63 92.61,180.14 93.35,180.88 93.35,182.3 v3(93.22,182.43) ; v3(95.49,169.95) 95.41,170.03 94.09,170.03 94.02,170.1 CPU1.BH43 ; v3(70.99,170.7) 71.13,170.56 CPU1.A44 ; CPU1.AJ1 84.92,150.26 84.92,150.41 84.92,150.78 84.92,150.78 84.92,150.89 CPU1.AJ2 ; v3(73.9,155.99) 73.32,155.99 73.05,155.73 CPU1.C12 72.39,155.66 71.76,155.66 CPU1.A12 ; CPU1.AH52 CPU1.AH54 CPU1.AH55 ; U1.P6 94.66,219.92 94.05,220.53 v1(94.03,220.53) ; CPU1.D6 72.88,152.62 CPU1.E4 74.2,151.3 CPU1.F3 ; CPU1.A62 71.83,179.24 CPU1.B62 72.26,179.67 CPU1.B63 ; CPU1.U63 79.22,179.74 79.22,179.11 CPU1.U62 ; GPU1.AF11 v3(85.48,110.62) ; CPU1.BA63 90.54,179.69 CPU1.BA62 ; PU5.3 149.28,133.88 v1(149.08,134.09) ; CPU1.AA1 81.27,150.31 81.27,150.84 CPU1.AA2 ; CPU1.AE2 82.88,150.84 82.88,150.31 CPU1.AE1 ; v1(129.73,58.03) 129.83,58.13 U14.78 ; CPU1.AB12 CPU1.AB10 CPU1.AB9 ; U14.18 117.15,58.53 117.28,58.66 117.29,58.66 v1(117.47,58.85) ; CPU1.BF61 92.5,178.82 92.08,178.82 CPU1.BD61 ; CPU1.AH59 CPU1.AH58 CPU1.AH57 ; U20.35 132.54,34.48 v3(132.74,34.68) ; CPU1.K5 75.93,152.02 75.93,152.69 CPU1.K6 ; v3(75.55,89.53) GPU1.B23 ; CPU1.AN48 CPU1.AN50 ; v1(121.19,53.1) 121.85,52.44 U14.45 ; v3(94.01,212.64) 94.22,212.64 94.66,213.08 U1.A6 ; v3(70.9,172.51) 70.99,172.42 CPU1.A48 CPU1.C48 ; CPU1.A24 71.57,161.41 v3(71.03,161.41)
  TOP w0.229: CPU1.BJ14 95.27,156.66 v3(95.33,156.59) ; CPU1.A20 v3(71.11,159.44) ; CPU1.A36 71.69,166.88 v3(71.29,167.27) ; CPU1.A32 71.27,165 v3(71.14,165.13) ; CPU1.A28 v3(71.11,163.15) ; CPU1.BJ46 95.22,171.49 v3(95.41,171.3) ; CPU1.A16 v3(71.11,157.58) ; CPU1.BJ18 94.95,158.51 95.19,158.27 95.91,158.27 v3(95.95,158.24) ; v3(94.6,164.52) 94.6,164.72 CPU1.BJ32 ; v3(71.11,155.73) CPU1.A12 ; v3(95.63,173.31) 95.6,173.34 CPU1.BJ50
  TOP w0.254: v3(134.89,187.24) 134.6,186.95 DIMM1.13 128.7,186.95 ; v1(161.39,36.2) 161.26,36.07 R438.2 ; 128.41,176.15 DIMM1.49 ; U22.24 152.18,28.86 v1(151.93,28.6) ; v3(133.59,147.6) 132.74,146.75 DIMM1.139 129.47,146.75 ; CPU1.AK5 v3(84.87,151.63) ; v3(84.87,151.63) CPU1.AJ2 ; v3(84.87,151.63) CPU1.AH5 84.55,152 v3(84.89,152.35) 84.53,152.71 CPU1.AH6 84.42,152.74 84.42,153.4 CPU1.AH7 v3(84.87,153.77) 85.34,154.13 CPU1.AK9 85.38,154.17 85.38,154.81 CPU1.AK10 ; DIMM1.14 138.31,186.65 137.8,187.16 v3(137.08,187.16) ; CPU1.AW30 v3(89.98,164.08) CPU1.BA29 v3(90.7,163.13) CPU1.BA27 v3(89.98,162.17) 89.98,162.02 CPU1.BA25 ; v3(91.07,180.59) 91.07,180.54 CPU1.BA63 ; CPU1.AW50 v3(89.84,173.99) ; DIMM1.156 138.23,141.65 v3(137.78,141.2) ; CPU1.E54 73.25,175.78 v3(73.25,175.96) ; v3(87.67,176.22) CPU1.AP55 87.1,175.87 CPU1.AN56 ; v3(95.59,153.23) 95.17,153.23 94.82,153.59 CPU1.BJ8 ; v1(152.94,47.85) 152.94,48.04 C158.1 ; R459.2 132.73,29.13 v1(132.81,29.22) 132.9,29.31 C196.2 ; 128.63,140.15 DIMM1.161 133.05,140.15 133.33,140.43 133.33,140.64 v3(133.41,140.71) ; GPU1.AB7 88.85,106.61 88.85,105.85 GPU1.AA7 ; CPU1.AB5 v3(81.13,151.63) ; v3(81.13,151.63) CPU1.Y5 ; v3(81.13,151.63) 81.14,151.23 81.14,150.97 CPU1.AA2 ; v3(137.93,190.3) 137.98,190.25 DIMM1.2 ; C168.1 154.62,42.86 154.41,42.8 154.24,42.8 v1(153.88,42.44) ; v1(170.53,118.24) U4.3 U4.8 ; CPU1.BA43 v3(90.7,170.62) CPU1.BB45 ; DIMM1.196 138.07,129.65 137.18,130.54 v3(137.18,130.58) ; CPU1.A32 CPU1.C32 CPU1.D32 CPU1.F32 CPU1.G32 CPU1.J32 ; v1(112.3,206.22) 112.27,206.25 NGFF1.7 ; CPU1.AE13 83.17,155.91 CPU1.AG13 83.34,156.27 83,156.61 ; CPU1.AE13 CPU1.AE11 CPU1.AE10 CPU1.AE8 CPU1.AE7 CPU1.AE5 CPU1.AE4 82.9,151.62 82.9,151.06 CPU1.AE2 ; CPU1.AE13 83,156.61 ; CPU1.F63 74.06,179.9 73.93,180.04 73.93,180.32 73.49,180.75 v3(73.49,180.92) ; CPU1.J32 CPU1.K32 ; CPU1.J32 CPU1.J30 ; CPU1.K32 CPU1.J30 ; CPU1.K32 CPU1.M32 CPU1.N32 CPU1.R32 78.67,165 CPU1.U34 ; CPU1.M3 77.13,151.46 77.36,151.69 v3(77.36,151.72) 77.38,151.73 77.5,151.73 CPU1.P5 ; CPU1.G1 74.8,149.74 74.71,149.65 v3(74.71,149.63) ; CPU1.AE48 CPU1.AE50 CPU1.AE51 CPU1.AE53 CPU1.AE54 CPU1.AE56 CPU1.AE57 CPU1.AE59 ; CPU1.AN56 CPU1.AN57 CPU1.AN59 ; CPU1.AN56 CPU1.AN54 CPU1.AN53 CPU1.AN51 CPU1.AN50 ; DIMM1.26 137.92,183.05 137.9,183.02 137.32,183.02 v3(136.86,183.49) ; v3(133.1,179.4) 132.89,179.4 132.54,179.75 DIMM1.37 128.94,179.75 ; 74.37,167.28 CPU1.F37 ; 74.37,167.28 74.64,167.01 v3(74.64,166.8) ; 74.37,167.28 74.43,167.28 74.44,167.29 74.95,167.29 CPU1.H37 CPU1.J37 v3(76.02,166.87) ; v3(133.53,185.73) 132.95,185.15 DIMM1.19 128.72,185.15 ; v3(74.61,176.92) 74.61,176.7 CPU1.F56 ; CPU1.BE35 v3(92.83,166.87) ; v3(92.83,166.87) CPU1.BG35 ; v3(92.83,166.87) CPU1.BE37 ; CPU1.AV55 v3(89.57,176.21) ; v3(81.26,149.65) 81.26,149.89 81.19,149.96 81.19,150.15 CPU1.AA1 ; v3(132.9,169.27) 132.62,169.55 DIMM1.71 128.6,169.55 ; 129.39,136.55 DIMM1.173 132.06,136.55 133.1,135.51 135.31,135.51 135.75,135.95 v3(135.8,135.95) ; CPU1.AT29 88.14,163.44 v3(88.48,163.11) 88.85,163.48 CPU1.AV29 ; v3(84.96,180.57) 84.85,180.47 CPU1.AJ63 ; v3(76.73,163.13) CPU1.L29 ; v3(76.73,163.13) CPU1.L27 CPU1.J27 ; v3(76.73,163.13) CPU1.M27 ; CPU1.BJ32 CPU1.BG32 CPU1.BF32 CPU1.BD32 CPU1.BC32 CPU1.BA32 CPU1.AY32 CPU1.AV32 CPU1.AU32 CPU1.AR32 87.28,165 CPU1.AN34 ; CPU1.A52 71.06,174.27 v3(70.96,174.17) ; v1(31.64,21.62) 31.64,21.5 31.43,21.29 R480.2 ; CPU1.F45 74.68,170.71 v3(74.68,170.61) 74.68,170.53 CPU1.F43 ; CPU1.K6 75.49,153.07 v3(75.48,153.08) CPU1.H7 74.43,154.08 v3(74.02,154.08) CPU1.F10 ; CPU1.E19 73.85,159.32 v3(73.85,159.36) 73.86,159.36 CPU1.F21 ; CPU1.Y52 81.1,174.12 v3(81.16,174.12) 81.16,174.12 CPU1.AB52 ; v3(132.84,183.44) 132.63,183.44 132.53,183.35 DIMM1.25 128.31,183.35 ; CPU1.R23 78.2,161.14 v3(78.2,161.28) ; v3(86.99,149.46) 86.95,149.46 86.74,149.88 86.74,150.16 CPU1.AN1 ; v3(75.44,173.07) 75.44,173.06 CPU1.J48 CPU1.H47 ; DIMM1.162 138.28,139.85 137.9,139.47 137.19,139.47 v3(136.91,139.75) 136.86,139.7 136.86,139.07 v3(137.17,138.76) ; v3(92.67,173.08) 92.67,173.08 92.67,173.02 CPU1.BE48 CPU1.BE47 ; v3(95.05,176.75) 94.71,176.41 CPU1.BJ56 ; DIMM1.172 v3(137.8,136.85) ; v3(82.61,149.73) 82.63,149.76 82.63,149.77 83,150.14 CPU1.AE1 ; v3(88.56,170.62) CPU1.AV43 88.85,170.05 v3(89.19,169.72) 89.12,169.72 88.92,169.52 88.92,169.48 88.85,169.41 CPU1.AV41 ; v3(88.56,170.62) CPU1.AV45 ; v3(88.56,170.62) CPU1.AT45 CPU1.AR45 ; CPU1.BB61 90.79,178.92 90.54,179.16 CPU1.BA62 ; CPU1.AB9 81.6,154.13 v3(81.13,153.77) CPU1.Y7 ; v3(84.9,149.55) 84.9,149.56 84.85,149.61 CPU1.AJ1 ; 129.23,144.95 DIMM1.145 132.64,144.95 v3(132.72,144.87) ; v3(76.02,166.87) CPU1.J35 ; v3(76.02,166.87) CPU1.L35 ; v3(89.9,158.41) 89.99,158.41 CPU1.BA17 CPU1.BA16 ; DIMM1.184 137.97,133.25 137.9,133.19 v3(137.9,133.12) ; CPU1.F59 74.49,178.3 v3(74.52,178.3) 74.52,178.33 CPU1.H61 ; 129.57,138.35 DIMM1.167 132.12,138.35 132.34,138.13 132.93,138.13 133.43,138.63 v3(133.43,138.63) ; CPU1.C40 72.37,168.8 71.78,168.8 CPU1.A40 ; v3(137.73,131.75) 138.03,131.45 DIMM1.190 ; CPU1.BE52 v3(92.69,174.96) CPU1.BE54 ; 129.37,134.75 DIMM1.179 132.09,134.75 132.54,134.29 133.54,134.29 v3(134.09,133.73) ; DIMM1.8 137.64,188.45 136.84,189.26 v3(135.44,189.26) ; v3(132.67,129.95) DIMM1.195 ; v3(79.26,149.46) 79.26,149.47 79.29,149.5 CPU1.U1 ; v1(142.25,123.16) 142.25,122.66 140.97,121.38 140.97,121.16 ; v3(78.38,172.59) CPU1.T49 CPU1.U50 CPU1.U51 CPU1.U53 CPU1.U54 CPU1.U56 CPU1.U57 CPU1.U59 79.25,179 CPU1.U62 ; v3(137.93,176.4) 137.98,176.45 DIMM1.48 ; 75.42,156.02 75.42,156.05 75.72,156.35 CPU1.J14 ; 75.42,156.02 74.69,156.02 v3(74.67,156.01) ; 75.42,156.02 CPU1.J12 ; CPU1.AM46 CPU1.AN47 87.25,172.47 v3(87.57,172.52) CPU1.AT48 ; CPU1.AY54 v3(90.56,174.96) CPU1.BA52 ; CPU1.BH25 94.56,161.76 v3(94.56,161.75) ; v3(78.33,155.91) CPU1.P13 CPU1.M14 ; CPU1.M9 76.91,154.13 77.33,153.82 v3(77.33,153.79) 77.39,153.79 77.85,154.13 CPU1.P9 ; 132.89,177.81 133.41,178.33 v3(133.48,178.33) ; 132.89,177.81 132.46,177.81 132.32,177.95 DIMM1.43 128.84,177.95 ; 132.89,177.81 132.89,177.66 v3(133.18,177.37) ; 83,156.61 CPU1.AE14 ; v3(136.81,174.91) 137.3,174.42 137.87,174.42 138.1,174.65 DIMM1.54 ; v3(133.46,149.15) 132.87,148.56 132.87,148.55 DIMM1.133 129.12,148.55 ; CPU1.BA48 CPU1.BA47 ; v3(134.42,190.6) 134.2,190.6 133.64,190.05 132.46,190.05 132.36,189.95 DIMM1.3 128.88,189.95 ; CPU1.AT52 v3(88.62,174.09) ; v3(96.4,175.54) 96.07,175.54 95.73,175.2 CPU1.BJ54 ; CPU1.AH59 v3(84.87,178.37) CPU1.AK59 ; CPU1.Y55 80.67,175.87 81.14,176.23 v3(81.18,176.23) 81.6,176.53 CPU1.AB57 ; 128.64,188.15 DIMM1.9 132.46,188.15 132.46,188.17 133.15,188.86 133.17,188.86 v3(133.59,189.28) ; CPU1.L50 76.13,174.05 v3(76.04,174.05) ; v3(86.8,180.52) 86.71,180.43 CPU1.AN63 ; PR25.1 49.16,207.35 49.16,217.06 49.9,217.81 v1(50.19,217.81) 50.28,217.9 PR3.2 ; DIMM1.144 138.4,145.25 138.4,145.23 137.85,144.68 137.29,144.68 v3(136.95,145.03) ; 128.81,174.35 DIMM1.55 132.1,174.35 132.25,174.19 134.61,174.19 134.66,174.14 135.22,173.58 v3(135.36,173.58) ; v1(151.81,32.46) 151.91,32.36 U22.17 ; DIMM1.32 138.29,181.25 138.21,181.33 137.57,181.33 v3(137.07,181.84) ; CPU1.AH57 v3(84.87,176.23) CPU1.AH55 ; 129.06,150.35 DIMM1.127 133.88,150.35 134.89,149.35 v3(134.89,149.17) ; v1(150.17,43.23) 150.32,43.38 C164.1 ; v1(124.44,84.45) 124.28,84.62 PR111.2 ; v3(92.83,163.13) CPU1.BE29 ; v3(92.83,163.13) CPU1.BE27 ; v3(92.83,163.13) 93.16,163.46 CPU1.BG29 ; CPU1.J30 75.3,164.1 v3(75.3,164.07) 75.28,164.07 CPU1.H29 ; Q14.S 139.29,121.16 140.97,121.16 ; 129.36,141.95 DIMM1.155 134.41,141.95 135.76,140.6 v3(135.76,140.58) ; 129.43,132.95 DIMM1.185 132.54,132.95 v3(132.75,132.74) ; v3(137.06,143.69) 137.07,143.69 137.57,143.18 138.26,143.18 138.53,143.45 DIMM1.150 ; v3(133.41,143.58) 132.96,143.13 132.49,143.13 132.47,143.15 DIMM1.151 129.53,143.15 ; CPU1.Y12 v3(81.13,155.9) CPU1.AB12 ; CPU1.E27 73.86,163.09 73.88,163.11 v3(73.88,163.11) ; v3(137.79,180.33) 137.79,180.22 138.57,179.45 DIMM1.38 ; CPU1.P35 v3(78.15,166.87) CPU1.P37 ; U22.9 v1(157.1,34.15) 156.87,34.15 156.6,33.89 U22.10 ; CPU1.M59 v3(77.38,178.35) CPU1.P59 ; PQ6.4 55.9,72.6 56.47,72.03 57.62,72.03 57.9,72.31 58.57,72.31 PR133.1 ; 118.87,41.38 119.44,40.82 120.52,40.82 HDMI2.25 121.6,40.97 v3(121.84,40.72) ; CPU1.AK48 85.22,172.31 v3(84.87,171.97) 84.53,172.31 CPU1.AH48 ; v3(82.99,181) 82.99,180.98 83,180.96 CPU1.AE63 ; CPU1.AV35 CPU1.AT35 v3(87.85,166.87) ; CPU1.BF61 v3(93.19,178.69) ; CPU1.AT57 v3(88.62,176.22) ; CPU1.P55 v3(77.38,176.22) ; CPU1.BJ10 94.91,154.8 95.16,154.55 v3(95.16,154.46) ; CPU1.E14 73.9,156.15 v3(73.9,155.99) 73.9,155.83 CPU1.E12 ; R72.1 18.58,206.57 v1(18.05,206.57) ; DIMM1.178 137.68,135.05 v3(137.21,135.52) ; v3(137.73,149.61) 138.17,150.05 DIMM1.128 ; v3(94.85,163.02) 94.72,163.15 CPU1.BJ28 ; 140.97,121.16 142.2,119.93 v1(142.2,119.1) 142.39,119.3 C58.2 143.21,119.31 R213.2 144.35,119.31 145.56,118.1 145.56,117.89 ; v1(129.87,42.84) 130.71,42.01 R419.2 C169.1 ; CPU1.BA35 v3(90.7,166.87) CPU1.BA37 v3(89.98,167.83) CPU1.BA39 ; CPU1.F50 v3(74.02,174.01) ; CPU1.AT61 CPU1.AT62 88.1,180.06 v3(88.43,180.39) ; v3(73.24,176.91) 73.16,176.99 CPU1.D58 ; U22.20 152.07,30.86 v1(151.82,30.61) 152.07,30.36 U22.21 ; v3(92.67,170.64) 92.67,170.44 CPU1.BE43 ; CPU1.H23 v3(74.59,160.33) ; PWRCN1.4 29.3,23.25 28.75,23.8 28.23,23.8 26.9,25.13 v1(26.9,25.25) ; CPU1.AY58 v3(90.52,177.64) ; CPU1.P43 v3(78.15,170.62) CPU1.P45 ; CPU1.P41 77.44,168.81 77.44,168.8 v3(77.39,168.74) ; v3(132.88,182.27) 132.88,182.08 132.35,181.55 DIMM1.31 128.66,181.55 ; CPU1.K57 v3(75.48,176.93) ; v3(89.48,149.62) 89.12,149.99 89.12,150.5 CPU1.AV2 ; C180.2 v1(151.47,35.81) ; v3(95.77,166.01) 95.74,166.04 95.54,166.04 94.89,166.69 94.87,166.69 94.73,166.83 94.63,166.83 94.61,166.85 CPU1.BJ36 ; CPU1.AH52 v3(84.87,174.1) CPU1.AK52 ; CPU1.AE17 CPU1.AE16 ; 128.59,171.35 DIMM1.65 132.7,171.35 v3(132.8,171.45) ; v3(77.42,149.39) 77.42,149.68 77.44,149.69 CPU1.N1 ; CPU1.U14 CPU1.U13 CPU1.U11 CPU1.U10 CPU1.U8 CPU1.U7 CPU1.U5 79.29,152.32 CPU1.U2 ; R424.1 156.09,40.41 v1(155.86,40.18) ; CPU1.M50 76.72,173.11 76.11,173.11 v3(76.1,173.09) ; CPU1.AA63 v3(81.15,180.39) ; CPU1.AB59 v3(81.13,178.37) CPU1.Y59 ; DIMM1.44 138.24,177.65 137.8,178.09 v3(137.8,178.2) ; v3(133.69,173.46) 134.06,173.08 134.06,172.33 133.79,172.06 132.89,172.06 132.4,172.55 DIMM1.61 128.6,172.55 ; v3(94.88,178.33) 94.66,178.11 CPU1.BJ60 ; C173.1 v1(155.94,39.34) ; DIMM1.60 138.21,172.85 138,173.06 137.68,173.06 137.21,173.53 v3(137.04,173.53) ; v3(79.29,180.39) CPU1.U63 ; v3(92.08,176.79) 92.08,176.77 CPU1.BD56 ; v3(88.62,178.35) CPU1.AV61 CPU1.AV62 ; v3(136.9,185.88) 136.9,185.69 137.74,184.85 DIMM1.20 ; U22.8 v1(157.94,33.17) ; DIMM1.72 v3(137.93,169.25) ; CPU1.L45 v3(76.02,170.62) CPU1.L43 ; CPU1.N63 v3(77.44,180.39) ; CPU1.J63 v3(75.58,180.42)
  TOP w0.305: v3(58.99,78.23) 59.61,77.61 Q31.1 ; HDMI1.17 118.43,40.82 118.87,41.27 v1(118.87,41.61) ; VRAM1.G9 58.82,112.58 v3(58.82,112.59) ; DIMM1.168 138.46,138.05 138.34,137.92 137.96,137.92 v3(137.6,137.57) 137.72,137.45 DIMM1.170 ; GPU1.AC8 87.99,107.5 v3(88.41,107.08) ; SSUSB1.10 173.63,110.44 173.06,111.02 170.71,111.02 170.22,111.51 U6.2 ; CPU1.AT12 88.52,155.56 88.93,155.96 89.06,155.96 CPU1.AW14 ; v1(129.57,106.68) 129.57,107.42 130.32,108.17 U7.9 ; v3(92.06,156.06) 92.41,155.7 CPU1.BE12 CPU1.BE10 91.7,153.85 CPU1.BD8 ; CPU1.AN16 CPU1.AN17 86.55,158.05 CPU1.AM18 CPU1.AK18 85.06,158.59 84.56,158.59 CPU1.AJ18 ; CPU1.AN16 86.83,157.33 86.88,157.39 87.44,157.39 87.44,157.38 v3(87.61,157.38) 87.62,157.37 CPU1.AT16 ; CPU1.AN16 CPU1.AN14 CPU1.AN13 CPU1.AN11 CPU1.AN10 ; v3(88.48,162.2) 88.48,162.06 CPU1.AT25 ; XDP1.61 26.99,204.18 v1(27.18,204.36) ; GPU1.L2 92.9,97.54 v3(93.29,97.94) ; 89.23,159.35 89.19,159.35 CPU1.AV19 CPU1.AT19 87.71,158.99 CPU1.AR19 ; 89.23,159.35 CPU1.AV21 CPU1.AV23 ; 89.23,159.35 v3(89.24,159.35) ; v3(81.16,171.96) 81.16,171.98 CPU1.Y48 ; v3(81.16,171.96) 81.16,171.83 CPU1.Y46 ; v3(81.16,171.96) 81.25,171.96 CPU1.AB48 ; v1(26.78,212.36) 26.04,211.63 XDP1.62 ; v3(53.99,111) 53.6,110.6 VRAM1.J2 ; v1(30.9,218.97) 30.87,218.99 XDP1.57 ; U1.P4 95.66,220.29 95.64,220.31 v1(95.64,220.55) ; R38.1 33.25,213.38 R43.2 33.13,212.35 v1(32.41,211.63) ; VRAM2.T1 59.2,94.75 59.18,94.78 v3(59.18,94.79) ; PC75.2 151.33,129.87 v3(150.76,129.87) ; v1(20.78,214.59) 20.24,215.14 20.24,215.17 C7.2 ; Q19.1 146.86,118.69 146.64,118.47 146.14,118.47 145.56,117.89 Q19.4 ; R2002.2 160.71,155.35 161.45,154.61 162.29,154.61 162.67,154.99 v1(163.53,154.99) ; CPU1.AN34 v3(86.26,166.18) ; v3(86.26,166.18) CPU1.AM36 CPU1.AK36 ; v3(86.26,166.18) CPU1.AN36 ; v3(86.26,166.18) CPU1.AM34 ; PC12.2 66.04,209.19 PR15.2 66.72,210.14 v1(67.06,210.49) 67,210.55 PC9.2 66.95,211.51 PR13.2 ; v3(90.91,97.94) 90.5,97.53 GPU1.L5 ; R56.2 18.09,206.6 v1(18.05,206.57) ; CPU1.BA16 90.28,157.2 v3(89.98,156.9) 89.98,156.89 89.57,156.48 CPU1.AW14 ; CPU1.BB25 v3(91.32,162.16) ; v3(134.89,187.24) 134.58,187.55 DIMM1.11 ; 129.38,131.75 DIMM1.189 133.76,131.75 134.3,132.28 v3(134.3,132.66) ; PR85.2 147.05,130.65 147.8,129.9 v3(148.95,129.9) ; v3(84.09,166.18) CPU1.AJ36 CPU1.AG37 83.88,167.52 83.88,167.9 CPU1.AG39 v3(84.09,168.54) CPU1.AG41 ; v3(84.09,166.18) CPU1.AJ34 ; v3(84.09,166.18) CPU1.AG34 ; CPU1.Y57 80.82,176.58 v3(81.18,176.23) ; v1(16.95,218.74) 16.95,218.24 16.73,218.01 R27.1 ; VRAM1.D8 v3(58.8,114.2) VRAM1.E8 ; v3(92.67,170.64) 93.06,171.03 CPU1.BG45 ; v3(150.53,210.93) 150.53,210.7 Q6.4 ; HDMI2.20 116.02,32.32 v3(115.58,31.88) ; v1(130.18,114.07) 130.64,113.61 U7.32 ; v3(82.64,160.67) CPU1.AE23 CPU1.AG23 CPU1.AJ23 v3(84.81,161.46) CPU1.AK23 CPU1.AM22 ; v1(79.48,186.66) 79.34,186.8 C23.2 ; CPU1.BG41 92.95,169.17 92.59,168.81 91.53,168.81 CPU1.BB39 90.97,168.27 90.91,168.33 90.48,168.33 90.43,168.27 CPU1.BA39 ; v3(70.04,181.31) 70.04,182.07 69.23,182.87 R112.2 68.2,183.36 R113.2 ; GPU1.AB14 83.32,106.98 83.32,107.05 v3(83.36,107.09) ; U1.E7 v3(94.16,215.9) 94.2,215.94 94.69,215.94 95.07,216.32 U1.G5 ; 94.29,180.72 94.29,180.24 93.88,179.83 CPU1.BH63 93.74,179.67 CPU1.BH62 ; CPU1.BG23 93.16,160.7 92.82,160.36 v3(92.82,160.35) 92.81,160.35 92.41,159.95 CPU1.BE21 93.16,159.11 CPU1.BG19 92.68,158.5 92.03,158.5 v3(92,158.46) 92.41,158.04 CPU1.BE17 CPU1.BE16 ; v3(67.37,160.55) 67.37,160.06 R171.1 ; GPU1.AB11 85.11,106.29 v3(85.11,106.22) ; CPU1.F3 v3(74.71,151.65) CPU1.H3 ; CPU1.V42 CPU1.Y42 v3(81.19,169.33) CPU1.AA41 CPU1.AC39 82.4,168.28 82.87,168.28 CPU1.AE39 CPU1.AE41 ; CPU1.AK10 85.45,154.94 85.45,155.46 CPU1.AK12 ; v3(90.62,160.32) 90.62,160.27 90.28,159.93 CPU1.BA21 90.99,159.15 CPU1.BB19 ; C21.2 76.34,190.2 75.73,190.2 v1(75.65,190.27) ; VRAM1.F9 59.2,112.97 v3(58.82,112.59) ; DIMM1.134 138.22,148.25 v3(137.85,147.88) 138.08,147.65 DIMM1.136 ; XDP1.58 24.81,218.99 v1(25.11,219.29) 25.11,219.9 25.52,220.31 XDP1.64 ; U1.J5 94.63,217.32 94.56,217.25 v3(94.51,217.25) ; NGFF1.45 v1(109.12,215.75) ; CPU1.AH15 84.49,156.98 v3(84.84,157.33) 84.76,157.33 CPU1.AH16 84.45,157.74 CPU1.AJ18 ; CPU1.Y22 v3(80.47,159.88) CPU1.V20 CPU1.U18 ; CPU1.AN5 CPU1.AN7 CPU1.AN8 CPU1.AN10 ; PR22.2 54.43,206.83 PC16.1 54.43,206.8 54.43,205.76 ; v1(139.22,67.53) 138.49,66.8 C138.2 ; CPU1.BB3 CPU1.BA2 CPU1.BA1 v3(90.61,149.65) ; CPU1.BB3 90.78,151.56 90.54,151.56 v3(90.51,151.6) 90.51,152.16 90.05,152.62 CPU1.AY6 ; CPU1.BB3 CPU1.BD3 CPU1.BF3 ; HDMI1.8 HDMI2.12 v1(115.55,36.32) ; v3(154.47,209.14) 154.23,208.9 Q6.1 ; CPU1.BJ4 v1(94.93,151.5) ; v3(93.41,218.32) 93.59,218.13 93.59,218.12 93.66,218.05 U1.K8 ; v3(58.82,112.59) 58.43,112.2 VRAM1.G8 ; CPU1.P19 78.26,158.5 78.79,158.5 78.99,158.7 CPU1.U18 ; CPU1.P19 77.51,158.55 v3(77.51,158.43) ; CPU1.P19 77.86,159.15 CPU1.M21 CPU1.L21 76.43,159.8 v3(76.02,159.38) 75.72,159.09 CPU1.J19 75.01,158.19 CPU1.H17 ; XDP1.16 21.41,208.49 v1(21.11,208.79) ; 54.43,205.76 53.56,205.76 v1(53.47,205.67) ; 54.43,205.76 PR26.1 ; CPU1.R29 v1(78.87,163.11) CPU1.U27 CPU1.V27 CPU1.Y27 CPU1.AA27 CPU1.AC27 CPU1.AE27 v3(83.36,162.24) CPU1.AG27 v3(84.09,163.03) CPU1.AJ27 CPU1.AK27 v3(85.53,163.03) CPU1.AM27 CPU1.AN27 ; CPU1.BH2 CPU1.BH1 v3(94.38,149.75) ; v3(71.03,149.63) 71.13,149.63 72.11,150.62 CPU1.B2 CPU1.B3 ; R148.2 R145.2 66.58,174.37 v3(66.58,174.37) ; DIMM1.46 137.66,177.05 137.48,177.24 136.92,177.24 136.34,176.65 v3(136.34,176.64) 135.74,177.24 135.47,177.24 v3(135.42,177.29) ; v1(43.64,96.62) 43.52,96.5 LVDS1.14 ; CPU1.AJ18 84.3,158.55 83.87,158.55 CPU1.AG18 ; VRAM1.T9 59.2,104.43 v3(59.28,104.35) ; v1(52.06,114.56) 52.1,114.6 VRAM1.D1 VRAM1.E1 ; CPU1.AE41 v3(82.64,169.33) ; CPU1.AE41 CPU1.AG41 ; v1(155.58,174.75) 155.42,174.59 R143.2 ; v1(25.11,215.74) 25.44,215.42 XDP1.63 26.75,215.42 v1(27,215.67) ; CPU1.AW14 90.28,155.75 CPU1.BA12 90.28,155.07 CPU1.AY10 89.93,154.85 89.59,154.51 v3(89.57,154.51) 89.57,154.49 89.21,154.13 CPU1.AV9 88.38,153.42 CPU1.AT7 88.01,153.42 87.74,153.7 v3(87.74,153.76) 87.67,153.76 87.3,154.13 CPU1.AP9 86.91,154.49 CPU1.AN10 ; v1(120.31,209.01) 120.29,209 NGFF1.18 ; v1(109.14,223.43) 109.33,223.25 NGFF1.75 ; v3(71.01,179.33) 71.06,179.38 CPU1.A62 ; CPU1.U14 CPU1.U16 CPU1.U17 CPU1.U18 ; CPU1.AN27 CPU1.AN28 86.77,163.57 86.77,164.07 CPU1.AN30 87.28,165 ; CPU1.AN27 CPU1.AN25 ; CPU1.AE34 CPU1.AC34 v3(81.91,165.39) CPU1.AA34 ; Q9.1 v1(39.67,158.69) ; v1(115.6,34.82) HDMI1.5 ; v3(132.8,171.45) 132.8,171.48 132.32,171.95 DIMM1.63 ; v1(115.55,33.38) 115.61,33.32 HDMI2.18 HDMI1.2 ; C26.2 84.15,184.1 83.65,183.59 83.65,182.91 82.99,182.24 v3(82.99,181) ; DIMM1.153 133.13,142.55 v3(134.15,143.56) ; R115.2 71.82,183.32 71.32,182.83 v3(71.29,182.83) 71.2,182.83 R116.2 ; NGFF1.57 v1(109.12,218.75) ; v3(76.04,174.05) 76.13,174.14 76.13,174.63 76.06,175.05 CPU1.K54 ; v1(135.92,112.36) 135.92,112.27 135.62,111.97 U7.23 ; v1(52.46,76.78) 52.05,77.2 Q30.1 ; DIMM1.38 141.69,179.45 141.74,179.5 ; CPU1.A56 71.27,176.41 v3(71.08,176.61) ; CPU1.AE48 CPU1.AE47 CPU1.AG46 v3(84.09,170.91) CPU1.AG44 CPU1.AG42 CPU1.AG41 ; v1(97.96,109.3) R262.1 ; v1(130.48,82.54) 130.45,82.54 130.2,82.29 U11.22 ; CPU1.AT39 88.14,168.51 CPU1.AV41 ; v1(135.01,107.92) 134.77,108.17 U7.16 ; v1(81.97,130.33) 82.61,129.69 U2.5 ; R114.2 73.57,183.18 v3(73.03,183.18) ; CPU1.BE1 v3(92.66,149.47) ; CPU1.BA48 90.61,172.96 v3(90.61,173.08) ; CPU1.AN37 CPU1.AN39 CPU1.AM39 v3(85.53,168.54) ; v1(141.24,72.77) 141.24,72.43 C134.2 140.43,71.72 U13.2 ; R4501.2 141.36,81.89 Q4501.S ; DIMM1.28 137.68,182.45 v3(137.07,181.84) ; v1(114.66,37.57) 114.92,37.82 HDMI1.11 ; 129.24,130.93 130.22,129.95 DIMM1.195 ; GPU1.AE11 GPU1.AF11 ; v1(63.53,75.44) 63.13,75.84 Q31.4 ; CPU1.BA35 v3(89.98,165.92) CPU1.AW34 ; NGFF1.63 v1(109.12,220.25) ; v3(132.75,132.74) 132.75,132.69 132.41,132.35 DIMM1.187 ; NGFF1.24 v1(119.88,210.5) ; U1.H10 92.44,216.82 92.18,217.07 v3(92.15,217.07) ; R86.2 110.06,198.93 109.03,197.9 109.03,196.05 v1(109.1,195.99) ; v3(69.27,43.15) 69.28,43.15 69.28,43.39 69.83,43.94 Q36.4 69.25,44.16 68.98,44.43 68.98,45.1 68.62,45.46 Q36.1 66.71,45.46 R413.2 ; CPU1.V34 v3(80.47,165.39) CPU1.Y34 ; LVDS1.7 43.4,103.5 v1(43.64,103.25) ; R351.2 137.27,69.61 v1(136.79,70.09) ; VRAM1.P1 52.81,106.6 v3(53.21,106.2) ; CPU1.Y16 CPU1.AB16 81.64,157.69 v1(82.01,158.07) 82.01,158.31 82.28,158.57 CPU1.AC18 CPU1.AE17 ; v3(52.22,108.1) 52.32,108.2 VRAM1.M1 ; v3(66.6,171.72) 66.55,171.72 66.18,172.09 R158.2 R161.2 ; v3(70.99,154.17) 71.28,153.98 CPU1.A9 ; GPU1.AE17 80.53,109.1 v3(80.93,108.7) 81.33,108.3 GPU1.AD16 ; GPU1.AF17 80.53,109.9 v3(80.93,109.5) ; DIMM1.138 v3(137.22,147.05) ; NGFF1.69 v1(109.12,221.75) ; X1.2 72.75,194.68 73.44,195.38 v1(73.57,195.38) 73.34,195.61 72.19,195.61 71.89,195.3 X1.3 ; NGFF1.39 v1(109.12,214.25) ; NGFF1.30 v1(119.88,212) ; NGFF1.29 v1(109.12,211.75) ; NGFF1.33 v1(109.12,212.75) ; VRAM1.P9 v3(58.8,106.2) ; VRAM1.E2 v3(54,114.2) ; NGFF1.23 v1(109.12,210.25) ; NGFF1.36 v1(119.88,213.5)
  TOP w0.33: DIMM1.66 138.48,171.05 138.01,171.53 v3(137.93,171.53) ; DIMM1.49 134.17,176.15 134.76,176.75 134.93,176.75 135.25,177.07 135.25,177.13 v3(135.42,177.29)
  TOP w0.356: VRAM1.B1 v3(52.2,116.2) ; GPU1.AF20 78.04,110.65 v1(78.28,110.89) ; VRAM2.D1 59.2,84.64 v3(58.8,85.04) ; 82.98,109.9 82.97,109.9 v3(82.57,110.3) ; 82.98,109.9 GPU1.AF14 ; 82.98,109.9 v3(82.57,109.5) 82.97,109.1 ; v3(88.41,107.08) 88.8,106.69 GPU1.AB7 ; GPU1.AC26 73,107.45 73,107.45 v3(72.53,107.45) ; v3(78.46,108.69) 78.85,108.3 GPU1.AD19 GPU1.AD18 ; GPU1.AD22 76.2,108.1 76.2,108.09 75.98,107.87 75.97,107.87 ; GPU1.B14 83,88.05 82.57,87.61 v3(82.43,87.61) ; v3(75.9,105.37) 75.66,105.13 75.66,105.12 GPU1.Y23 ; v3(52,111.91) 52.51,111.91 VRAM1.G1 ; v3(78.46,92.1) 78.44,92.1 GPU1.E20 ; v3(75.92,97.95) 75.84,97.87 75.84,97.86 GPU1.L23 ; GPU1.AB20 77.88,106.82 77.87,106.82 v3(77.63,107.06) ; GPU1.E5 90.47,92.55 v3(90.87,92.95) ; GPU1.T11 86,101.99 v3(86.51,101.48) 86.99,101 GPU1.R10 ; v1(76.73,112.06) 76.71,112.03 76.2,112.03 75.42,111.25 75.42,110.03 GPU1.AF23 ; v3(71.45,100.5) 71.95,100 GPU1.P26 ; GPU1.A2 92.9,88.68 v3(93.14,88.44) ; U19.8 U19.3 v3(121.87,37.11) ; PQ6.1 52.96,73.9 v3(52.61,74.26) ; v3(94.75,95.71) 94.22,95.18 93.04,95.18 GPU1.H2 ; GPU1.P2 92.51,99.61 v3(92.51,99.6) ; v3(58.8,86.64) 59.2,87.04 VRAM2.G1 ; VRAM2.A9 52.8,82.24 v3(52.4,82.64) 52.8,83.04 VRAM2.B9 ; v3(59.6,82.64) 59.2,83.04 VRAM2.B1 ; v1(47.37,67.53) 47.25,67.53 47.14,67.42 PR144.1 45.48,67.42 45.13,67.78 v3(45.13,68.33) ; v3(55.04,116.48) 54.76,116.2 VRAM1.B3 ; v3(90.88,109.49) 90.47,109.9 GPU1.AF5 ; VRAM2.F9 52.1,86.94 52.1,87.04 ; v3(52.14,94.31) 52.21,94.24 VRAM2.T9 ; GPU1.E2 93.43,92.55 v3(93.81,92.55) ; v3(58.8,85.04) 59.2,85.44 VRAM2.E1 ; v3(58.8,85.04) 58.8,85.09 58.45,85.44 VRAM2.E2 ; GPU1.H23 75.87,95.41 75.87,95.41 v3(75.92,95.46) ; VRAM2.E8 53.43,85.27 53.43,85.27 v3(53.2,85.04) 53.6,84.64 VRAM2.D8 ; GPU1.AG26 73.1,111.53 v1(73.46,111.88) ; v3(80.11,92.92) 80.11,92.91 GPU1.E17 ; GPU1.L25 74.3,97.12 v3(74.3,97.11) ; v3(87.54,90.5) 87.55,90.5 87.95,90.1 GPU1.B8 ; U18.8 122.78,40.67 121.9,40.67 v3(121.84,40.72) ; GPU1.B5 v3(90.01,89.66) ; VRAM1.T1 52.22,105 v3(52.19,105.03) ; GPU1.AF1 93.7,110.41 v3(93.55,110.56) 93.41,110.7 GPU1.AG2 ; GPU1.Y26 73.5,104.56 v3(73.5,104.55) ; GPU1.E14 83.41,92.91 v3(83.45,92.91) ; v3(77.62,107.9) 77.61,107.91 77.59,107.91 GPU1.AD21 78,109.1 GPU1.AE20 ; v3(93.73,107.46) 92.99,107.46 92.98,107.45 GPU1.AC2 ; VRAM2.P9 52.8,92.64 v3(53.2,93.04) ; VRAM2.M1 59.2,91.04 v3(58.8,91.44) ; GPU1.E25 73.73,92.38 73.73,92.34 v3(73.5,92.11) ; GPU1.AC5 90.46,107.45 v3(90.88,107.03) ; VRAM2.J2 58.4,88.64 v3(58,88.24) ; GPU1.AD15 82.17,108.3 82.97,109.1 ; GPU1.N10 86.77,99.23 86.77,99.24 v3(86.53,99.47) 86.01,100 GPU1.P11 ; GPU1.AE11 85.46,109.1 84.66,108.3 GPU1.AD12 GPU1.AD13 ; v3(58.8,93.04) 59.2,92.64 VRAM2.P1 ; v3(58.79,111) 58.4,110.61 VRAM1.J8 ; v3(121.87,33.57) 121.88,33.58 U21.8 ; 82.97,109.1 GPU1.AE14 ; 75.97,107.87 v3(75.96,107.87) ; 75.97,107.87 76.2,107.64 76.26,107.64 GPU1.AC22 ; v3(58.79,107.8) 59.19,108.2 VRAM1.M9 ; v3(75.11,102.06) 75.11,102.09 GPU1.U23 ; GPU1.AB24 74.32,106.98 74.32,107.02 v3(74.32,107.02) ; GPU1.B20 78.04,89.53 v3(78.03,89.52) ; VRAM1.B9 59.6,116.6 v3(59.6,116.6) VRAM1.A9 ; v3(76.84,92.91) 76.83,92.9 76.8,92.9 GPU1.E22 ; GPU1.A26 72.91,89.3 72.71,89.1 71.12,89.1 70.66,88.64 v3(70.61,88.64) ; GPU1.P23 75.86,100.36 75.87,100.36 v3(75.92,100.41) ; GPU1.B17 80.45,90.03 80.45,88.31 v3(80.37,88.23) ; v1(49.66,79.38) 49.46,79.17 Q30.4 48.29,78.5 R324.2 ; v3(74.29,94.62) 73.9,95.01 GPU1.H25 ; v3(93.51,102.78) 93.2,102.78 GPU1.U2 ; v3(87.45,103.46) 87,103.01 GPU1.U10 ; v3(90.91,100.41) 90.71,100.21 90.71,100.21 GPU1.P5 ; VRAM2.J8 53.6,88.64 v3(54,89.04) ; GPU1.H5 90.5,95.07 v3(90.9,95.47) ; v3(51.78,91.16) 51.93,91.01 52.77,91.01 VRAM2.M9 ; v3(71.6,90.27) 71.78,90.1 GPU1.B27 ; VRAM2.G8 53.44,87.2 52.96,87.2 VRAM2.G9 52.1,87.04 ; GPU1.AB17 80.87,107.01 80.91,107.01 v3(80.93,107.04) ; 52.1,87.04 v3(52.07,87.04) ; GPU1.E11 v3(85.87,92.89)
  TOP w0.381: R163.2 61.85,170.44 62.34,169.94 v1(64.06,169.94) ; C139.2 111.34,66.56 C140.2 113.94,66.56 114.22,66.84 114.22,68.62 114,68.83 v1(114,69.01) ; v1(43.99,157.39) Q9.4 ; R352.2 133.34,68.88 v1(132.98,68.88) ; v1(81.26,130.89) 81.24,130.91 R197.1 ; v3(70.72,37.29) 70.54,37.47 70.15,37.47 PQ14.E ; R59.2 87.51,205.71 88.48,204.74 90.6,204.74 v1(91.04,205.18) ; PC73.2 155.25,131.6 v1(154.39,131.6) ; PR21.2 57.41,207.81 v1(57.5,207.72) ; R428.2 92.57,40.94 C172.2 v1(92.57,42.29) ; v1(137.61,46.45) 137.5,46.35 137.44,46.35 137.28,46.19 U17.3 ; v1(87.03,85.12) 87.42,84.72 C115.2 87.69,84.04 87.69,83.4 87.68,83.39 87.68,82 86.93,81.25 X3.2 ; v1(49.08,98.37) 49.45,98.74 PR95.2 ; PR155.2 59.52,62.74 59.52,63.09 PC110.2 59.6,63.63 v1(59.27,63.96) ; PC15.2 61.86,208.26 v1(61.17,208.26) 60.6,208.26 PC13.2 PR20.2 ; v1(121.51,47.1) 121.64,47.23 121.64,47.72 C160.2 C159.2 ; PC119.2 58.12,54.84 v1(58.96,55.68) 58.96,56.31 PR163.2 ; v1(76.89,122.4) 76.89,122.35 77.27,121.98 Q12.1 ; PR24.2 59.76,206.77 v1(60.41,207.42) ; C36.1 63.7,159.6 X2.2 63.06,159.61 62.51,160.16 60.88,160.16 60.47,159.75 v3(60.47,159.22) 60.47,159.18 60.42,159.14 60.42,158.02 61.54,156.9 X2.4 61.54,155.86 61.86,155.55 63.64,155.55 v3(63.8,155.4) 64.35,154.84 C37.1 ; PC98.2 123.67,76.9 v1(123.48,77.09) ; GPU1.Y2 92.9,104.96 93.18,104.96 v3(93.45,104.69) ; PR159.2 56.31,58.85 56.33,58.83 v1(56.33,58.73) ; R44.2 148.16,212.13 v3(148.04,212.01) ; v1(95.92,115.98) 96.87,116.93 U5.3 ; v3(31.43,9.04) 31.1,9.04 30.83,9.31 30.57,9.31 C229.2 ; v1(116.97,115.95) 118.51,117.48 118.51,119.07 Q18.E 119.63,120.2 124.1,120.2 Q17.S ; v1(30.88,186.07) 31.57,186.76 PC198.2 ; PR99.2 134.35,88.98 v1(134.37,88.95) ; v1(79.66,126.36) 79.66,126.03 78.98,125.35 77.64,125.35 C56.2 ; PC76.2 114.99,119.15 115.24,118.9 115.27,118.9 116.29,117.88 v1(116.29,116.76) ; v1(152.1,183.67) 153.93,183.67 154.6,182.99 R120.2 154.6,181.32 C29.2 ; v1(95.71,82.25) 95.62,82.34 95.62,83.83 C116.1 ; v1(52.92,219.03) 52.93,219.03 PC3.2 ; v1(42.01,11.18) 42.01,11.17 41.75,10.92 41.56,10.92 C225.1 ; C132.2 145.58,72.66 C133.2 144.59,72.66 v1(143.92,73.32) 143.92,73.39 144.21,73.68 C126.2 ; C64.2 143.77,116.69 R229.2 143.97,116.67 143.97,116.01 v1(144.01,115.98) ; v1(79.94,119.94) 79.84,120.04 Q12.4 ; v1(56.71,178.77) 55.98,179.5 R132.2 ; v1(56.26,57.92) 56.59,57.92 57.11,58.45 PR160.2 ; PC93.2 121.53,82.52 PR116.2 122.4,82.96 122.22,83.13 122.22,83.3 v1(122.16,83.36) ; C141.2 111.78,64.22 v1(111.18,64.82) ; R210.2 81.5,124.21 80.7,123.41 v1(80.7,123.32) 80.7,123.26 81.64,122.33 Q13.1 ; Q13.4 83.52,120.09 v1(83.37,119.94) ; v1(139.02,116.1) 138.72,115.8 135.82,115.8 133.52,118.1 Q15.S ; v1(152.14,206.62) 152.14,206.67 152.16,206.69 R57.2 ; PR117.2 120.11,81.79 119.54,81.79 v1(119.41,81.66) ; v1(133.71,52.96) 133.81,52.86 133.81,52.66 134.05,52.43 134.05,52.3 R390.1 ; v3(90.91,102.9) 90.5,102.49 GPU1.U5 ; v1(141.33,80.85) 141.27,80.78 Q4501.S ; v1(112.53,59.68) 112.53,59.35 112.15,58.97 R376.1 ; PC88.2 PC89.2 v1(126.35,88.47) ; C38.1 161.11,147.09 C39.1 162.14,147.08 v1(162.21,147.02) ; PC78.2 v1(119.35,113.96) ; U28.2 v1(44.2,12.95) ; GPU1.Y5 90.5,104.98 v3(90.89,105.37) ; v1(144.26,107.65) 144.32,107.7 Q24.S ; R310.2 90.69,84.9 R298.2 R299.2 92.48,85.1 v1(92.49,85.09) ; v1(94.44,89.76) 94.1,90.1 GPU1.B1 ; PC29.2 30.91,183.73 PC27.2 30.95,184.25 31.88,184.25 v1(32.04,184.1)
  TOP w0.406: v1(46.35,38.11) 46.63,38.39 PQ13.1 ; v1(170.52,96.27) U9.3 U9.8 ; PQ6.4 54.9,72.6 54.54,72.96 54.54,73.66 54.3,73.9 PQ6.1 ; PQ13.4 v1(47.93,42.11)
  TOP w0.457: GPU1.M17 80,98 v1(80.51,97.49) 81,97 GPU1.L16 81,96.98 v1(81.53,96.45) 81.98,96 GPU1.K15 ; GPU1.K17 80,95.72 v3(79.71,95.43) ; GPU1.V17 79.56,103.56 v3(79.53,103.56) 79.24,103.27 79.24,103.24 GPU1.U18 ; GPU1.V17 79.63,104.37 v3(79.63,104.52) ; GPU1.V17 GPU1.U16 81,103 v1(81.51,102.49) 82,102 GPU1.T15 ; GPU1.L18 79,97.01 v3(78.49,97.52) ; v3(86.53,95.58) 86.12,96 GPU1.K11 ; GPU1.R14 83.05,101 v3(83.5,100.55) 84,100.05 GPU1.P13 84,99.99 v3(84.48,99.51) 84.99,99 GPU1.N12 ; GPU1.N18 78.96,99 78.56,99.4 v3(78.56,99.49) ; v3(83.57,104.45) 83.57,104.43 83.77,104.23 GPU1.V13 ; GPU1.T17 v3(79.5,101.5) GPU1.R18 ; GPU1.K13 84,95.5 v3(83.88,95.38) ; GPU1.L10 87,97.13 v3(86.56,97.56) 86.34,97.79 86.21,97.79 GPU1.M11 ; GPU1.L14 82.99,97 v1(82.47,97.51) 82,97.99 GPU1.M15 ; v3(84.57,97.45) 85,97.02 GPU1.L12 ; v3(81.54,104.45) 81.99,104 GPU1.V15 ; GPU1.P15 81.99,100 v1(81.53,100.46) 81,100.99 GPU1.R16 ; GPU1.M13 84,98.04 v3(83.54,98.5) 83.04,99 GPU1.N14 ; GPU1.V11 86,103.89 v3(85.56,103.45) 85.11,103 GPU1.U12 ; GPU1.N16 80.99,99 v1(80.51,99.47) 80,99.99 GPU1.P17 ; GPU1.R12 84.93,101 v3(84.51,101.42) 84,101.93 GPU1.T13 83.97,102 v3(83.48,102.48) 83,102.97 GPU1.U14
  TOP w0.508: v3(105.01,58.06) 104.99,58.09 v1(104.99,59.23) 104.99,60.41 105,60.43 C143.2 104.22,62.75 C142.2 ; v1(30.82,156.29) 30.82,155.26 PC59.2 ; v3(66.94,177.62) 66.89,177.62 66.84,177.67 R138.2 ; MEMCD1.6 162.02,149.72 v3(161.94,149.8) ; C72.2 124.7,112.69 124.59,112.8 v1(124.54,112.8) ; v1(22.65,180.15) 22.68,180.12 R128.2 ; v1(87.56,85.88) 88.5,84.94 R304.2 ; v1(20.85,211.54) 20.84,211.55 20.84,212.31 C9.2 ; C82.2 131.45,106.73 131.4,106.68 v1(131.35,106.68) ; v1(46.59,114.83) 46.69,114.94 C67.2 47.44,114.94 C66.2 ; v3(30.34,5.71) 30.35,5.72 30.35,6.43 C232.2 ; C3.1 123.59,223.38 v1(123.59,224.07) C1.2 ; v1(26.65,152.07) 26.6,152.12 PR60.2 ; R253.2 46.66,110.63 v1(46.62,110.67) ; v1(46.43,93.72) 46.44,93.73 C101.2 ; SSUSB2.4 171.69,91.84 171.33,92.21 LED1.K ; PWRCN1.12 26.75,18.41 26.14,17.81 v3(26.14,17.64) ; v1(154.16,22.63) 154.16,21.98 R479.2 ; v3(169.58,142.22) MEMCD1.3 ; R498.1 39.81,8.67 v1(39.81,7.47) ; C110.2 64.8,86.92 65.1,86.62 v1(65.1,86.28) 64.83,86 C111.2 64.32,85.98 C113.2 64.32,83.82 C118.2 ; v1(49.72,175.93) 49.72,176.08 50.49,176.85 50.49,176.87 50.88,177.26 50.9,177.26 51.31,177.67 C32.2 ; PR130.2 52.38,74.37 52.49,74.37 v3(52.61,74.26) ; PC99.2 126.32,76.91 v1(125.84,76.43) ; PC111.1 66.39,62.55 v1(66.84,62.1) ; R267.2 64.48,106.51 65.07,105.91 65.07,105.56 v1(65.05,105.53) ; v1(108.86,81.9) 108.86,82.03 108.46,82.43 Q26.S ; CONVT1.10 27.45,32.15 25.79,33.81 v1(25.79,33.91) ; C77.2 46.11,108.4 46.11,107.81 v1(46.38,107.54) 47.17,107.54 47.19,107.56 PR94.2 ; C233.2 45.18,5.77 44.25,5.77 C234.2 44.16,5.86 44.16,6.73 Q43.E 43.17,7.31 43.06,7.42 v1(43.05,7.42) ; C216.2 153.68,23.65 v3(154.49,23.65) ; v3(67.23,88.2) 67.23,88.3 67.5,88.58 R293.2 ; C75.2 137.89,112.36 C74.2 v1(135.92,112.36) ; v3(36.8,25.48) R472.2 ; C231.2 145.18,6.63 v1(144.36,6.63) ; C18.1 v1(160.02,193.08) 160.02,193.09 159.14,193.09 158.61,192.55 PC24.1 ; v1(55.15,214.31) 55.15,215.53 PC6.2 54.62,215.62 54.09,216.15 PC4.2 ; v1(92.66,30.24) 92.62,30.19 U23.2 ; v1(52.08,62.45) 52.08,62.45 52.08,62.46 52.74,62.46 52.98,62.22 PQ12.S ; PR107.2 123.43,87.05 122.75,87.73 122.72,87.73 v1(122.69,87.76) ; PC90.2 121.45,85.85 121.39,85.9 v1(121.39,86.26) ; v1(142.43,24.46) 142.43,25.07 142.76,25.4 C212.2 ; v5(28.23,166.95) 28.26,166.91 R167.2 ; Q44.E v1(48.64,7.16) ; C204.2 C209.2 103.6,26.35 104.02,25.93 v1(104.02,25.78) ; v3(46.16,20.85) 45.6,21.41 R477.2 ; v1(65.02,108.56) 64.82,108.35 C80.2 64.15,108.38 R258.2 ; SPK1.5 148.99,15.25 v1(148.98,15.24) ; C81.2 159.15,109 v1(158.5,109.65) ; v1(34.04,205.72) 34.04,205.65 33.54,205.15 C12.2 33.21,204.23 C14.2 ; NGFF1.76 110.98,204.17 109.38,204.17 v1(109.35,204.14) 109.35,204.13 108.88,203.66 108.88,203.57 107.77,202.46 R78.1 ; R283.2 46.61,92.77 46.52,92.86 v1(46.41,92.86) ; v1(22.66,179.02) 22.67,179.01 22.96,179.01 23.02,179.07 PC33.2 ; v1(46.61,95.86) 46.7,95.94 47.68,95.94 C95.2 ; v1(143.8,12.06) 144.01,12.28 C223.2 C228.2 144.11,10.48 v1(143.8,10.79) ; v1(100.77,75.9) 99.79,75.9 R332.1 ; v5(109.47,113.75) 109.53,113.8 PR89.2 ; HDMI2.22 120.81,29.92 v1(120.84,29.95) 121.39,29.39 122.77,29.39 C203.1 ; v3(43.78,27.27) 43.79,27.26 43.79,27.21 43.95,27.06 43.95,26.57 AFTP1.1 43.31,26.54 42.58,27.28 C206.2 ; U25.2 v1(110.6,25.1) ; v3(119.57,27.64) 119.74,27.46 C205.2 ; C222.2 145.32,17.27 v1(145.4,17.35) ; v1(46.43,90.01) 46.46,89.99 R291.2 PR101.2 ; R5501.2 35.47,116.02 v1(36.13,115.36) 36.86,114.63 R245.2 36.86,112.21 LVDS1.31 ; v1(68.18,199.01) 69.03,198.16 R88.1 ; v1(38.21,9.12) 38.23,9.14 38.23,9.8 37.78,10.25 C227.2 ; CONVT1.12 25,30.58 26.12,29.46 v4(26.12,29.41) 25.76,29.06 25.76,29.01 v3(25.1,28.35) 25.89,28.35 26.75,27.49 PWRCN1.11 ; PC62.2 v1(24.01,151.05) ; v1(157.63,105.27) 158.48,105.27 C85.2 158.53,105.31 U8.2 ; WEBCM1.8 155.77,198.18 155.77,197.26 v3(156.14,196.89) ; C150.2 98.52,56.96 98.97,56.52 v1(99.17,56.52) ; C144.2 99.57,58.83 v1(99.33,58.6) 99.07,58.6 98.66,58.8 PC115.2 ; X4.4 34.68,8.12 v1(34.68,8.9) 34.68,9.51 34.01,10.19 C226.2 ; PC5.2 61.98,216.53 v1(64.93,216.53) ; C78.2 v1(126.3,108.66) ; FANC3.1 14.59,214.81 15.17,215.39 C8.2 ; C120.1 103.21,81.41 v1(103.2,81.4) ; v1(156.65,135.64) 156.48,135.47 PC72.2 ; C229.2 30.38,9.5 TOUCH1.2 ; v1(33.28,156.24) 33.18,156.13 33.18,155.28 PC58.2 ; C65.2 v1(46.74,116.3) ; R277.1 98.59,98.8 v1(99.09,98.3) 98.58,97.79 PR97.2 ; C214.2 147.51,25.25 C211.2 147.66,26.42 148.27,27.03 v3(148.27,27.05) ; PR134.2 47.25,73.33 v3(47.05,73.53) ; v1(42.07,22.83) 42.17,22.93 Q40.E ; C86.2 47.64,103.44 C87.2 46.79,103.43 v1(46.48,103.12) ; R30.1 103.26,217.17 102.95,216.87 v1(102.93,216.87) ; R247.2 76.02,114 76.02,112.77 v1(76.73,112.06) ; 64.97,92.94 64.88,93.03 C100.2 ; PC126.1 v1(152.8,20.29) 153.31,20.8 C218.2 ; v1(55.05,64.06) 55.25,64.26 PQ10.S ; PC120.1 v1(44.69,53.06) ; v1(154.85,170.94) 154.85,171.02 C35.2 ; v1(46.35,112.62) 47.61,112.62 C73.2 ; C112.2 v1(46.43,85.97) ; R139.2 151.85,177.67 151.85,177.67 v1(151.79,177.67) ; C230.2 33.38,5.74 33.31,5.66 33.31,5.62 33.26,5.57 33.26,5.46 v1(33.03,5.23) ; v1(46.61,84.02) C117.2 C119.2 ; C59.1 166.82,121.4 166.81,121.39 v3(166.52,121.39) ; v1(119.92,87.55) PC87.2 ; C157.2 105.08,52.75 C156.2 104.87,55 v1(104.99,55.12) v3(104.99,56.34) ; v1(65.02,88.49) 64.62,88.9 R292.2 64.13,88.88 C104.2 ; C103.2 v1(46.41,90.93) ; v1(30.22,170.51) 30.22,169.57 30.07,169.42 PR52.2 ; v3(136.81,29.46) 137.03,29.68 C195.2 ; C70.2 126.59,114 v1(125.97,114) ; v1(92.13,34.43) 92.13,34.34 91.73,33.93 C189.2 C190.2 ; SPK1.7 149.7,6.5 149,5.81 v5(149,5.55) ; SPK1.8 149.11,18.8 v5(147.99,17.68) ; R1703.2 61.63,145.3 v1(61.73,145.19) 61.47,144.93 R184.2 60.68,145.35 60.28,145.75 Q10.S ; v1(48.37,18.22) C221.2 ; v1(48.34,119.83) 48.64,119.53 C62.2 C61.2 ; PR41.2 v1(23.13,183.02) ; C128.2 C129.2 C130.2 46.16,74.29 47.37,74.29 v1(47.63,74.03) ; R255.1 v1(98.97,111) ; C171.2 C170.2 135.91,42.79 v1(135.86,42.85) ; PC45.2 v5(28.23,165.93) ; C84.2 v1(46.41,105.74) ; v3(151.75,24.28) C213.2 ; C83.2 v1(46.43,106.6) ; PR67.2 v1(25.01,157.18)
  TOP w0.635: HDMI2.24 120.7,37.11 v3(121.87,37.11) ; HDMI1.21 118.63,44.28 HDMI2.21 ; R484.2 138.53,17.02 v1(138.33,16.82) ; 176.12,87.87 SSUSB2.10 ; SSUSB2.10 177.99,88.94 ; SSUSB2.10 174.25,88.94 ; SSUSB2.10 176.12,90.01 ; v1(142.48,42.67) 141.38,42.67 Q2801.S ; Q38.S 93.58,35.88 v1(93.75,35.71) ; 176.58,70.69 UHS1.MS1 178,69.67 ; v1(57.03,176.43) 57.03,176.43 Q8.S ; U27.S 135.07,13.84 v1(134.47,13.24) ; 94.38,188.94 H1.1 97.75,192.31 ; 176.12,109.37 SSUSB1.10 ; SSUSB1.10 176.12,111.51 ; SSUSB1.10 177.99,110.44 ; WEBCM1.6 v3(158.25,196.77) ; C48.1 160.37,143.25 C49.1 160.36,142.1 v1(160.24,141.98) ; v1(83.29,84.53) 83.52,84.3 C114.2 83.95,83.67 X3.4 ; v1(52.35,173.24) 51.63,172.53 IRMTCN1.5 ; PC25.2 23.15,187.68 23.15,186.84 v1(23.25,186.74) ; C224.1 33.45,10.54 C226.2 ; v1(99.83,110.57) 99.89,110.5 C76.2 ; 183,129.58 MEMCD1.14 183,131.4 ; 176.12,100.67 SSUSB2.11 ; SSUSB2.11 177.99,101.74 ; SSUSB2.11 176.12,102.81 ; v5(129.14,16.16) 129.75,15.55 129.82,15.55 129.97,15.4 BT1.2 ; PC92.2 v1(118.4,86.66) ; v1(39.81,7.47) 38.44,6.1 X4.2 ; PR34.2 v1(29.88,197.17) ; 11.75,137.31 HDD1.1 10.87,138.19 ; ODD1.7 8.1,181.69 ; ODD1.7 7.22,180.81 ; ODD1.7 8.98,180.81 ; C150.2 97.78,57.25 97.41,57.25 97.09,57.31 97.07,57.32 PC117.2 ; PU1.1 v5(29.8,194.77) ; v1(130.28,81.03) 131.17,81.03 131.58,81.43 PC94.2 ; v1(52.18,151.16) 52.19,151.14 R1702.2 ; 8.1,172.31 ODD1.1 ; ODD1.1 7.22,173.19 ; ODD1.1 8.98,173.19 ; 12,147.05 HDD1.9 ; HDD1.9 10.68,148.37 ; HDD1.9 13.32,148.37 ; HDD1.9 12,149.69 ; v5(115.35,87.96) 115.35,87.91 114.23,86.79 C108.2 ; Q37.3 85.87,38.32 v1(85.71,38.48) 85.7,38.49 R437.1 85.68,39.66 EC2901.1 ; IRMTCN1.6 46.63,170.36 v1(46.15,170.84) ; 96.64,30.46 USB3.6 98.35,28.74 ; v1(47.91,184.94) 47.91,185.89 R100.2 ; C11.2 124.85,205.12 v1(125.32,204.65) 124.33,203.65 C13.1 124.32,203.36 123.64,202.68 R75.2 ; v5(81.06,126.36) 81.06,126.59 81.06,126.6 U2.11 ; HDD1.4 10.46,142 ; v1(65.96,86.28) 67.15,85.09 R301.2 ; ODD1.9 9.67,183.37 ; ODD1.9 8.35,182.05 ; ODD1.9 8.35,184.69 ; ODD1.9 7.03,183.37 ; SRCON1.4 90.92,123.67 v1(90.46,124.13) 90.18,124.41 C57.1 ; C15.2 19.19,199.52 v1(18.32,199.52) C17.2 C16.2 ; PC113.2 70.84,59.35 v1(71.23,59.74) ; PC1.2 6.97,223.89 v1(6.98,223.9) ; PR179.2 67.82,28.91 68.47,28.26 68.82,28.26 v3(68.87,28.21) ; PC40.2 v1(35.59,170.43) ; PR114.2 135.04,83.16 135.22,83.12 v1(135.62,82.73) ; NGFF1.77 108.26,224.35 v1(108.11,224.2) ; 176.12,122.17 SSUSB1.11 ; SSUSB1.11 177.99,123.24 ; SSUSB1.11 176.12,124.31 ; 49.88,28.44 DCIN1.4 48.79,26.88 ; v1(122.74,110.39) 122.69,110.44 PC81.2 ; C96.2 64.89,93.99 C100.2 ; v1(101.22,135.9) 101.22,134.58 R193.2 99.43,134.58 98.3,133.45 v1(98.3,131.85) ; v5(154.93,167.72) 154.83,167.83 PC43.2 ; 179,80.91 UHS1.MS2 180.42,79.89 ; BAT2.8 34.39,59.7 34.6,59.49 34.6,58.39 34.41,58.2 BAT2.9 32.38,58.2 v1(31.95,57.77) ; 64.97,92.94 v1(64.97,92.93) ; v3(167.14,88.44) 166.17,89.41 C99.2 ; Q1801.S 141.27,85.79 v1(141.31,85.75) 141.1,85.55 R1803.2 ; 98.35,5.74 USB4.6 ; USB4.6 98.35,9.17 ; USB4.6 96.64,7.46 ; USB4.6 100.07,7.46 ; R336.2 64.24,74.73 v1(63.53,75.44) ; ODD1.4 6.85,177 ; R239.1 v1(93.25,114.83) ; PC118.2 v1(66.84,57.66) ; HDMI2.23 121.07,33.57 v3(121.87,33.57) ; PC2.2 7,218.34 v1(7.05,218.29) ; 72.37,123.75 H4.1 69,127.12 ; 171.1,160 MEMCD1.13 171.1,158.17 ; v3(46.64,27.3) 46.35,27.6 D5.1 ; 97.01,140.56 H3.1 91.13,141.18 ; WEBCM1.10 153.2,201.38 153.19,201.39 v3(153.19,203.21) ; 183,160 MEMCD1.15 183,158.17 ; 11.75,146.69 HDD1.7 10.87,145.81 ; PC26.2 24.67,186.87 23.66,185.85 v1(23.35,185.85) ; C89.1 v1(99.7,100.91) ; PC41.2 v1(36.61,170.43) ; C10.2 v3(151.5,213.66)
  L3 w0.635: 175.17,62.1 H11.4 175.17,63.68 ; H7.5 8.46,161.54 ; H7.5 7.67,160.75 ; H7.5 7.67,162.33 ; 168.67,18.34 H10.4 167.88,17.55 ; H7.7 3.46,163.46 ; H7.7 2.67,162.67 ; H7.7 4.25,162.67 ; 168.67,21.66 H10.5 167.88,22.45 ; 23.08,45.48 H9.6 22.29,46.27 ; H7.2 4.25,157.33 ; H7.2 3.46,156.54 ; H7.2 2.67,157.33 ; HDD1.9 9.97,148.37 ; 171.75,61.76 H11.2 170.17,61.76 ; H7.4 7.67,159.25 ; H7.4 8.46,158.46 ; H7.4 7.67,157.67 ; H7.1 2.33,159.25 ; H7.1 1.54,158.46 ; H7.1 2.33,157.67 ; 175.17,66.76 H11.5 175.17,65.18 ; 6.54,156.54 H7.3 ; H7.3 7.33,157.33 ; H7.3 5.75,157.33 ; HDD1.8 10.19,135.63 ; 162.55,17.12 H10.2 163.34,16.33 ; 22.29,52.03 H9.3 23.08,52.82 ; 166.66,23.67 H10.6 167.45,22.88 ; ODD1.9 6.24,183.37 ; 174.83,61.76 H11.3 173.25,61.76 ; 168.67,223.08 H6.2 167.88,222.29 ; H7.6 6.54,163.46 ; H7.6 5.75,162.67 ; H7.6 7.33,162.67 ; 167.88,227.71 H6.3 168.67,226.92 ; ODD1.7 6.34,180.81 ; 2.33,160.75 H7.8 ; H7.8 2.33,162.33 ; H7.8 1.54,161.54 ; 166.66,16.33 H10.3 167.45,17.12 ; HDD1.4 10.21,142 ; HDD1.7 10.08,145.81 ; ODD1.4 6.34,177 ; ODD1.8 6.2,170.63 ; ODD1.1 6.34,173.19 ; HDD1.1 10.08,138.19
  L4 w0.635: 22.29,52.03 H9.3 23.08,52.82 ; H7.2 4.25,157.33 ; H7.2 3.46,156.54 ; H7.2 2.67,157.33 ; 5.75,157.33 H7.3 ; H7.3 7.33,157.33 ; H7.3 6.54,156.54 ; H7.1 2.33,159.25 ; H7.1 2.33,157.67 ; H7.1 1.54,158.46 ; 174.83,61.76 H11.3 173.25,61.76 ; 167.88,17.55 H10.4 168.67,18.34 ; 166.66,23.67 H10.6 167.45,22.88 ; 167.88,222.29 H6.2 168.67,223.08 ; 175.17,63.68 H11.4 175.17,62.1 ; 1.54,161.54 H7.8 ; H7.8 2.33,160.75 ; H7.8 2.33,162.33 ; 166.66,16.33 H10.3 167.45,17.12 ; H7.4 8.46,158.46 ; H7.4 7.67,157.67 ; H7.4 7.67,159.25 ; HDD1.4 9.7,142 ; 22.29,46.27 H9.6 23.08,45.48 ; ODD1.7 6.22,180.81 ; 168.67,226.92 H6.3 167.88,227.71 ; ODD1.9 6.11,183.37 ; H7.7 3.46,163.46 ; H7.7 4.25,162.67 ; H7.7 2.67,162.67 ; H7.6 7.33,162.67 ; H7.6 5.75,162.67 ; H7.6 6.54,163.46 ; H7.5 8.46,161.54 ; H7.5 7.67,160.75 ; H7.5 7.67,162.33 ; 175.17,66.76 H11.5 175.17,65.18 ; HDD1.7 9.83,145.81 ; HDD1.1 9.57,138.19 ; 168.67,21.66 H10.5 167.88,22.45 ; 171.75,61.76 H11.2 170.17,61.76 ; ODD1.4 6.22,177 ; ODD1.1 6.09,173.19 ; HDD1.9 9.72,148.37 ; HDD1.8 9.81,135.63 ; ODD1.8 6.32,170.63
  BOTTOM w0.203: U29.11 v3(102.27,222.1) ; PU13.32 64.18,214.06 64.77,214.66 v1(64.77,214.68) ; PU13.34 64.6,213.26 v1(64.8,213.46) ; U31.6 33.7,94.3 v1(33.5,94.51) ; PU13.27 63.95,216.06 64.42,216.53 v1(64.93,216.53) ; v1(64.77,214.68) 64.56,214.46 PU13.31 ; v1(64.77,214.68) 64.58,214.86 PU13.30 ; PU13.29 64.55,215.26 64.73,215.45 v1(64.73,215.58) 64.65,215.66 PU13.28
  BOTTOM w0.254: v1(29.11,99.75) 29.13,99.77 ; R600.1 83.22,155.92 83.22,157.19 R597.1 ; v1(47.35,55.09) 47.53,55.09 47.92,55.48 U34.14 ; R583.1 79.66,180.02 v3(79.29,180.39) 79.3,180.4 C282.2 ; v1(69.73,206.57) 69.68,206.57 69.68,206.57 68.99,206.57 R558.1 ; v2(139.35,187.78) 139.49,187.64 C275.2 ; v2(137.03,141.88) 137.1,141.88 C342.2 ; v1(34.58,32) 34.25,31.67 U35.20 ; C495.1 118.4,40.32 118.95,40.88 118.95,41.53 v1(118.87,41.61) ; 29.09,101.22 v1(29.08,101.21)
  BOTTOM w0.305: v1(37.75,82.93) 38.01,83.19 38.01,85.37 38.64,86 C451.2 ; v3(52.22,108.1) 52.32,108.2 VRAM1.M1 ; Q64.S 137.39,70.7 v1(136.79,70.09) ; C298.2 v3(81.19,169.33) C299.2 ; R591.1 v3(90.7,163.13) ; v3(58.8,114.2) VRAM3.E1 ; v3(58.8,114.2) VRAM3.D1 ; v3(58.8,114.2) VRAM1.E8 ; v3(93.41,218.32) 93.52,218.42 C243.2 ; v3(92.06,156.06) 92.06,156.44 92.35,156.73 PC164.2 91.15,157.05 C331.2 90.03,156.86 v3(89.98,156.9) ; v1(88.05,219.79) 87.69,220.15 Q45.1 ; C327.2 81.72,157.77 v1(82.01,158.07) 82.22,158.07 82.58,157.71 R597.1 ; Q46.1 83.17,222.99 82.53,223.64 82.53,223.78 v1(82.33,223.98) ; C322.2 85.64,159.72 86.17,159.19 PC160.2 ; PR242.1 77.4,176.2 v3(77.38,176.22) ; 92.36,88.72 91.94,88.3 RN38.4 ; 92.36,88.72 92.16,88.93 91.43,88.93 RN38.3 91.4,88.96 91.4,89.51 90.86,90.04 R677.2 ; 92.36,88.72 92.65,88.44 v3(93.14,88.44) ; v1(82.11,220.67) 82,220.78 Q47.4 ; VRAM1.J2 53.6,110.6 v3(53.99,111) ; C286.2 87.77,176.33 v3(87.67,176.22) 87.84,176.05 C287.2 ; RN15.2 54.57,199.34 54.46,199.24 v3(54.46,199.21) ; Q47.1 80.01,222.03 78.98,221 v1(78.98,220.56) ; VRAM1.M9 59.19,108.2 v3(58.79,107.8) ; VRAM1.E2 v3(54,114.2) VRAM3.D8 ; R577.2 PC146.2 30.31,189.17 30.5,188.99 v1(30.6,188.99) ; v1(109.12,220.25) 108.22,220.25 107.77,219.8 107.74,219.8 107.5,219.55 C242.2 ; C468.2 121.39,65.33 v1(120.66,64.6) ; v1(86.37,224.16) 86.37,223.87 86.39,223.86 Q45.4 ; v1(52.46,76.78) 52,76.78 51.62,77.17 R812.2 ; VRAM1.P9 v3(58.8,106.2) ; v1(85.51,220.63) 85.36,220.78 Q46.4 ; v3(53.21,106.2) 52.81,106.6 VRAM1.P1 ; v3(59.28,104.35) 59.2,104.43 VRAM1.T9 ; VRAM3.F9 52,112.2 v3(52,111.91) 52.03,111.95 52.55,111.95 VRAM1.G1 52.84,112.2 52.98,112.06 53.42,112.06 53.56,112.2 VRAM3.G8 ; C503.2 125.6,30.84 v1(124.8,30.84) ; v3(87.54,90.5) 87.51,90.53 R675.2 ; Q52.4 30.03,170.7 v1(30.22,170.51) ; C387.2 74.59,103.21 74.59,102.58 v3(75.11,102.06) ; v3(75.92,95.46) 75.15,96.23 C419.2 ; C326.2 77.36,158.28 v3(77.51,158.43) 77.84,158.1 C328.2 78.41,158.53 C324.2 ; C470.2 127.12,63.87 C469.2 127.6,63.88 v1(127.91,63.57) ; v3(58.82,112.59) 58.82,112.58 VRAM1.G9
  BOTTOM w0.356: VRAM4.D1 52.8,84.64 v3(53.2,85.04) ; VRAM2.T9 52.21,94.24 v3(52.14,94.31) ; v3(58.8,86.64) 59.2,87.04 VRAM2.G1 ; v3(58.8,86.64) 59.2,86.24 VRAM4.F9 ; v3(58.8,86.64) 58.4,87.04 VRAM4.G8 ; v3(52.2,116.2) VRAM1.B1 ; VRAM1.T1 52.76,105 52.73,105.03 v3(52.19,105.03) ; v3(58.79,111) 58.4,110.61 VRAM1.J8 ; VRAM2.B1 59.2,83.04 v3(59.6,82.64) 59.2,82.24 VRAM4.A9 ; VRAM2.B9 52.8,83.04 v3(52.4,82.64) ; VRAM4.D8 58.4,84.64 v3(58.8,85.04) 58.6,85.24 58.6,85.24 VRAM2.E2 ; VRAM2.M9 52.77,91.01 51.93,91.01 v3(51.78,91.16) ; VRAM1.B9 59.6,116.6 v3(59.6,116.6) ; VRAM3.A9 v3(52.19,117) ; Q76.4 30.52,18.12 29.77,18.87 v3(29.42,18.87) ; VRAM2.P9 52.97,92.81 52.98,92.81 v3(53.2,93.04) ; VRAM2.P1 59.2,92.64 v3(58.8,93.04) ; VRAM3.B3 56.91,116.89 56.84,116.89 56.83,116.89 v3(56.81,116.89) ; VRAM2.M1 59.2,91.04 v3(58.8,91.44) ; v3(58,88.24) 58.4,88.64 VRAM2.J2 ; v3(53.2,85.04) 52.8,85.44 VRAM4.E1 ; v3(53.2,85.04) 53.6,85.44 VRAM2.E8 ; v3(54.81,82.64) 54.8,82.65 54.79,82.65 VRAM4.B3 ; VRAM2.J8 53.6,88.64 v3(54,89.04) ; v3(59.18,94.79) 59.18,94.78 59.2,94.75 VRAM2.T1 ; VRAM2.G9 v3(52.07,87.04)
  BOTTOM w0.381: v1(125.61,214.09) 125.8,214.29 126.27,214.29 126.29,214.3 126.64,214.3 C246.2 ; 46.46,89.99 46.88,89.57 PR216.2 ; 46.46,89.99 C444.2 ; 46.46,89.99 v1(46.43,90.01) ; C440.1 87.37,91.92 v3(87.54,92.1) ; v1(108.11,224.2) 108.59,224.68 C235.2 ; v1(30.88,186.07) 30.83,186.12 29.88,186.12 PC147.2 ; v3(73.85,159.36) 73.85,159.65 R595.1 ; v3(81.13,151.63) 80.76,151.26 C333.2 ; v3(74.67,156.01) 74.67,157.11 PC162.2 75.78,157.38 76.68,158.28 C326.2 ; v3(81.91,165.39) 81.91,166.37 C302.2 ; v3(81.91,165.39) 81.88,165.43 C307.2 81.19,165.39 v3(80.47,165.39) 80.47,165.88 C303.2 ; v3(81.91,165.39) 82.58,165.39 C306.2 ; v3(75.3,164.07) 75.92,164.07 C310.2 ; C247.2 94.88,214.77 v3(94.93,214.82) ; v1(151.04,39.8) 150.98,39.74 Q69.1 ; C332.1 128.88,156.15 v3(128.84,156.19) ; R711.2 130.58,74.54 131.1,75.06 131.1,75.19 v1(131.29,75.38) ; R590.1 v3(76.08,165.86) ; v1(129.73,58.03) 129.93,58.23 C477.2 C476.2 ; v3(161.94,149.8) 161.91,149.8 C565.2 ; v1(45.92,88.69) 45.93,88.68 C450.2 ; D9.A 154.03,50.66 v1(154.03,51.36) ; v1(109.14,223.43) 109.14,223.28 108.94,223.08 C236.2 C238.2 ; v1(60.94,201.78) 60.94,202.34 60,203.28 PG13.1 ; C311.1 129.14,163.87 v3(129.07,163.94) ; v3(92.83,166.87) 93,167.04 R589.1 ; v1(132.98,68.88) 133.22,68.64 C466.2 131.35,67.5 Q65.C ; R718.1 124.36,69.47 v1(124.77,69.06) ; C508.1 25.83,28 25.48,28.35 v3(25.1,28.35) ; v3(73.9,155.99) 73.9,156.65 C330.2 73.03,156.6 PC163.2 71.98,156.6 v3(71.11,155.73) ; v3(76.73,163.13) 76.44,162.84 R592.1 ; PR186.2 v1(67.97,217.32) ; v3(137.93,190.3) 137.98,190.25 138.36,190.25 139.42,189.19 ; C472.2 131.11,62.47 131.1,62.48 C471.2 132.32,62.77 v1(132.37,62.72) ; C424.2 73.56,96.37 v3(74.3,97.11) ; Q72.S 24.03,22.22 24.87,23.06 C516.1 ; v1(26.9,25.25) 26.81,25.16 25.94,25.16 C510.1 ; C505.1 27.81,29.35 27.11,30.05 v3(26.68,30.05) ; v3(73.88,163.11) 73.88,163.07 73.36,162.56 R593.1 ; v1(97.69,217.52) 96.94,217.52 C245.2 ; v1(100.09,215.57) 98.83,214.31 C248.1 ; v3(77.42,149.39) 77.23,149.19 PC169.2 ; PC157.2 89.23,169.67 v3(89.19,169.72) ; v3(23.15,23.5) 23.15,23.56 23.59,24 C514.2 ; v3(89.9,173.05) 89.83,172.99 PC155.2 ; v1(117.47,58.85) 117.09,58.85 117.08,58.84 C474.2 ; v3(93.29,97.94) 93.1,98.13 C416.2 92.1,98.13 C410.2 ; v3(45.13,68.33) 45.19,68.39 45.19,69.31 45.38,69.5 PC176.2 ; v3(83.45,92.91) 82.52,93.84
  BOTTOM w0.406: v3(28.66,16.41) 28.63,16.38 28.63,16.04 28.75,15.92 Q77.E ; v1(31.38,15.19) 31.45,15.19 31.87,15.61 Q76.1 ; v1(28.1,167.89) 28.1,168.02 26.72,169.4 Q52.1 ; Q75.E 25.74,16.64 26.14,17.04 v3(26.14,17.64)
  BOTTOM w0.508: v1(49.86,12.98) 49.83,12.95 U37.2 ; v1(47.63,74.03) 47.69,73.97 47.69,73.26 46.73,72.3 PL10.2 46.39,72.31 PC175.2 ; v3(161.94,149.8) 162.13,149.61 163.74,149.61 165.42,147.93 165.42,147.06 ; v3(104.99,56.34) 105.42,56.34 105.96,56.88 C478.2 ; v3(83.57,104.45) 83.41,104.29 C388.1 83.41,102.55 v3(83.48,102.48) 83.41,102.41 C398.1 ; v5(119.16,20.32) 119.21,20.27 C519.1 ; R567.1 30.58,203.9 30.81,203.67 v1(31.07,203.67) ; C551.2 155.43,167.23 v5(154.93,167.72) ; v1(26.92,185.49) 26.92,185.66 27.47,186.21 PC148.2 ; C482.2 152.71,48.15 152.94,47.91 v1(152.94,47.85) ; v1(142.73,40.03) 142.78,40.08 142.93,40.08 143.74,40.89 145.15,40.89 Q70.S ; Q71.S 126.46,25.27 v1(128.05,25.27) ; v3(86.56,97.56) 86.69,97.44 C421.1 ; R1808.2 133.21,67.49 C466.2 ; C494.2 49.06,38.86 49.25,38.66 v3(49.25,37.78) ; C558.2 51.32,52.81 50.4,51.89 v1(50.17,51.89) ; v3(77.42,149.39) 77.94,149.91 C334.2 ; v3(76.84,92.91) 76.84,93 77,93.16 77,93.17 77.5,93.66 C434.2 ; v1(31.38,15.19) 31.38,14.66 30.74,14.03 C530.2 31.22,13.32 C535.2 ; C425.1 C426.2 91.57,96.14 v3(90.9,95.47) 90.58,95.78 C428.2 C429.2 88.39,95.78 C427.2 87.73,96.44 C421.1 ; v1(38.44,77.77) 38.26,77.95 36.91,77.95 36.1,78.77 U33.4 ; v1(38.44,77.77) 38.44,78.08 38.64,78.28 U33.2 ; v1(38.44,77.77) 38.73,77.48 C462.2 39.3,77.7 39.91,78.31 U33.1 ; v3(83.5,100.55) 83.41,100.46 C408.1 83.41,98.63 v3(83.54,98.5) ; C421.1 86.69,95.74 v3(86.53,95.58) ; v1(89.24,97.92) 89.21,97.89 89.21,97.22 C417.2 ; C392.2 84.68,103.39 85.49,103.39 v3(85.56,103.45) 86.14,104.03 C390.1 86.87,104.03 v3(87.45,103.46) ; C284.2 70.78,179.57 v3(71.01,179.33) ; v1(33.84,85.19) 34.07,85.42 C452.2 ; C239.2 98.56,222.52 C237.2 97.58,222.52 v1(97.54,222.48) 97.44,222.38 C240.2 ; v5(21.18,13.26) 22.93,15.01 Q78.E ; v1(47.37,67.53) 47.7,67.86 C465.2 48.48,67.85 PQ17.S 48.47,66.57 PR218.2 ; v3(92,158.46) 91.98,158.48 C325.2 89.97,158.48 v3(89.9,158.41) 89.78,158.3 C329.1 ; v3(36.8,25.48) 36.82,25.5 37.59,25.5 C511.2 C512.2 R790.2 ; C491.2 129.69,42.67 v1(129.87,42.84) ; v1(34.15,44.65) 35.57,44.65 36.05,44.17 C559.2 ; v3(75.55,89.53) 75.24,89.84 74.43,89.84 C446.1 ; C539.2 31.22,11.74 C535.2 ; v1(74.05,193.65) 74.57,193.65 PC144.2 ; C384.2 47.91,104.55 v1(46.48,103.12) ; C401.1 29.09,101.22 ; v1(46.41,90.93) 46.51,90.93 46.53,90.95 R673.2 ; v3(84.51,101.42) 84.71,101.22 C406.1 84.71,99.74 v3(84.48,99.51) 84.68,99.31 C413.1 84.68,97.56 v3(84.57,97.45) 84,96.87 C422.1 84,95.5 v3(83.88,95.38) 84.44,94.82 C433.2 84.27,94.45 C432.2 83.13,94.45 82.52,93.84 C436.2 81.79,94.11 80.66,95.25 C430.1 80.38,95.43 v3(79.71,95.43) 79.15,95.99 C420.1 79.15,96.87 v3(78.49,97.52) 78.33,97.52 C412.2 78.45,98.23 C414.1 78.69,99.36 v3(78.56,99.49) 78.51,99.54 C405.2 78.6,100.6 v3(79.5,101.5) ; v3(88.41,107.08) 88.5,107.17 C377.2 ; v1(156.65,135.64) 156.65,135 156.39,134.75 PRB1.2 ; C459.2 C460.1 v1(30.23,81.28) ; C490.2 135.79,42.78 v1(135.86,42.85) ; C381.2 C380.2 79.64,104.53 v3(79.63,104.52) ; C448.2 37.45,87.76 v1(37.47,87.73) ; v1(94.03,220.53) 94.04,220.54 94.04,221.29 94.08,221.32 C241.2 ; R658.2 R657.1 31.06,99.77 29.13,99.77 ; 165.42,147.06 164.49,146.13 U39.2 ; 165.42,147.06 165.44,147.03 U39.3 ; PR183.2 59.6,221.23 v1(60.36,222) ; C251.2 v1(21.11,208.79) ; C455.2 47.07,84.48 v1(46.61,84.02) ; v3(23.15,23.5) 22.98,23.33 Q72.S ; C535.2 31.17,12.69 C537.1 ; C435.2 80.13,92.94 v3(80.11,92.92) ; v1(46.35,112.62) 46.88,112.09 R643.2 ; PL11.2 46.39,69.5 PC176.2 ; C371.2 64.18,108.23 R652.2 64.71,108.24 v1(65.02,108.56) ; PR94.2 47.76,107.49 47.71,107.54 v1(46.38,107.54) 46.38,107.99 46.89,108.5 C372.2 ; R756.2 v1(131.72,42.78) ; v1(97.88,86.49) 97.87,86.47 R692.2 ; U32.4 v1(95.71,82.25) ; v3(77.68,103.63) 77.66,103.63 77,102.98 C389.2 ; v1(31.95,57.77) 32.3,57.77 33.8,59.27 R735.1 33.8,60.57 R731.1 33.8,61.55 PC184.2 PL13.2 ; v1(162.06,140.84) 162.16,140.74 162.16,140.59 162.8,139.95 C564.2 ; C443.2 63.18,90.32 R674.2 R679.2 64.52,89.28 65.02,88.77 v1(65.02,88.49) ; R754.2 133.78,41.98 R755.2 132.74,42.71 v1(132.62,42.82) ; C439.2 47.74,92.86 v1(46.41,92.86) ; C517.2 R794.2 29.69,20.9 v3(28.76,20.9) 28.67,21 Q74.S ; v1(46.62,110.67) 47.4,110.67 R647.2 ; R633.2 45.33,120.37 v3(45.48,120.52) ; C461.1 v1(30.21,79.85) ; C244.2 132.73,216.73 Q48.E v1(132.28,218.12) ; v3(93.73,107.46) 93.39,107.8 C375.1 C376.1 ; v3(85.11,106.22) 85.1,106.21 C379.2 ; v1(96.05,100.51) 95.69,100.51 94.92,99.74 C411.2 ; Q50.S v1(131.03,213.52) ; R676.2 31.04,90.17 30.28,90.93 v1(30.13,90.93) ; C447.2 80.48,88.34 v3(80.37,88.23) ; v1(30.29,87.04) R685.2 31.08,87.04 C453.2 ; v3(70.96,174.17) 70.82,174.31 C288.2 ; v3(87.79,110.62) 88.08,110.9 R644.2 ; v1(46.74,116.3) 46.76,116.28 C353.2 ; v1(104.99,55.12) 104.63,54.76 C481.2 ; C449.2 C445.2 33.06,89.88 v1(33.51,90.33) ; v1(45.35,9.45) C544.2 44.42,8.29 Q80.E ; v1(65.1,86.28) 64.6,85.78 C454.2 ; C410.2 91.47,98.5 v3(90.91,97.94) ; C457.2 v1(30.23,83.06) ; v1(33.5,94.51) 33.21,94.22 32.64,94.22 32.53,94.11 R664.2 ; v3(74.32,107.02) 75.03,106.31 C378.1 ; R693.2 84.97,84.42 84.65,84.73 84.65,84.87 84.45,84.87 v1(84.16,85.17) ; v1(35.29,102.98) 35.25,102.95 C397.2 C404.2 ; C383.2 88.3,105.35 v1(87.51,105.35) ; PC132.2 v1(55.15,214.31) ; v3(78.03,89.52) 77.94,89.43 C71.2 ; v1(150.02,48.79) 149.99,48.77 149.43,48.77 Q67.E ; v1(153.88,42.44) 153.88,42.49 153.17,43.21 C487.1 153.87,43.93 C486.2 154.76,43.48 C488.2 155.35,43.07 C489.2 155.86,42.28 v1(155.86,40.18) ; v3(79.53,103.56) C394.2
  BOTTOM w0.635: PC156.2 PC158.2 142.27,168.42 v1(143.88,170.03) 143.39,170.53 PC156.2 ; PC156.2 PC154.2 141.13,173.75 v1(140.98,173.9) ; v1(58.96,55.68) 58.31,55.02 PQ19.S ; 176.12,100.67 SSUSB2.11 ; SSUSB2.11 176.12,102.81 ; SSUSB2.11 177.99,101.74 ; SSUSB2.11 174.25,101.74 ; 181.68,159.09 MEMCD1.15 ; MEMCD1.15 183,158.17 ; MEMCD1.15 183,160 ; PC69.2 150.45,139.42 v5(149.82,140.06) ; C361.2 C360.2 41.82,114.53 C355.2 43.7,114.53 C354.2 ; C361.2 40.59,115.79 Q55.S ; C361.2 40.26,114.48 39.68,113.91 v3(39.68,113.89) ; v1(141.38,150.27) PC168.2 PC165.2 141.79,153.95 C550.2 ; C475.2 105.14,58.19 v3(105.01,58.06) ; 176.58,70.69 UHS1.MS1 178,69.67 ; v1(162.21,128.27) 162.12,128.36 Q81.E 162.12,130.85 C568.2 ; TC3.2 93.11,24.1 ; TC3.2 92.06,23.05 ; TC3.2 91,24.1 ; TC3.2 92.06,25.16 ; 179,80.91 UHS1.MS2 180.42,79.89 ; JMP1.4 150.34,171 ; JMP1.4 149.27,169.93 ; JMP1.4 149.27,172.07 ; JMP1.4 148.2,171 ; v1(68.08,193.7) 68.61,193.7 69.72,192.59 PC145.2 ; v1(144.26,107.65) 144.99,108.38 C554.2 ; C562.2 71.31,223.01 v1(72.14,222.17) ; 113.99,28.66 HDMI1.22 ; HDMI1.22 113.99,30.9 ; HDMI1.22 111.3,29.78 ; v1(159.65,71.63) 159.21,71.2 C563.2 ; USB3.6 100.07,30.46 ; USB3.6 96.64,30.46 ; USB3.6 98.35,32.17 ; USB3.6 98.35,28.74 ; v1(136.3,88.9) 136.84,89.43 C553.2 ; v1(97.96,109.3) 97.65,109.6 C367.2 95.94,109.23 C547.2 ; SSUSB1.11 177.99,123.24 ; SSUSB1.11 176.12,124.31 ; SSUSB1.11 176.12,122.17 ; 7.22,180.81 ODD1.7 ; ODD1.7 8.1,181.69 ; ODD1.7 8.98,180.81 ; H1.1 94.38,195.68 ; H1.1 97.75,192.31 ; H1.1 94.38,188.94 ; H4.1 69,127.12 ; H4.1 72.37,123.75 ; H4.1 69,120.38 ; C314.1 v1(142.04,162.38) ; 7.03,183.37 ODD1.9 8.35,182.05 ; C364.2 36.13,114.32 v1(36.13,115.36) 36.72,115.36 C369.2 ; v2(139.35,187.78) 139.38,187.81 139.38,189.15 139.42,189.19 ; C437.2 64.69,93.21 v1(64.97,92.93) ; C402.2 39.62,102.35 C396.1 37.85,104.11 C391.2 37.63,104.14 v1(35.36,104.14) ; 174.25,110.44 SSUSB1.10 ; SSUSB1.10 176.12,109.37 ; SSUSB1.10 176.12,111.51 ; SSUSB1.10 177.99,110.44 ; 171.1,158.17 MEMCD1.13 ; MEMCD1.13 172.42,159.09 ; MEMCD1.13 169.78,159.09 ; MEMCD1.13 171.1,160 ; SSUSB2.10 176.12,90.01 ; SSUSB2.10 176.12,87.87 ; SSUSB2.10 174.25,88.94 ; SSUSB2.10 177.99,88.94 ; 181.68,130.49 MEMCD1.14 ; MEMCD1.14 183,129.58 ; MEMCD1.14 183,131.4 ; 110.34,37.03 HDMI1.20 ; HDMI1.20 112.58,37.03 ; HDMI1.20 111.46,39.85 ; HDMI1.20 111.46,34.21 ; C555.2 142.43,42.62 v1(142.48,42.67) ; v1(46.29,119.12) 46.29,118.08 Q56.S ; 94.38,134.56 H3.1 ; H3.1 94.38,141.3 ; H3.1 91.01,137.93 ; v1(45.96,222.12) 46.39,222.55 C561.2 ; 96.64,7.46 USB4.6 ; USB4.6 98.35,5.74 ; USB4.6 98.35,9.17 ; USB4.6 100.07,7.46 ; 7.22,177 ODD1.4 8.98,177 ; HDD1.9 10.35,148.37 ; 96.64,20.6 USB4.5 ; USB4.5 98.35,18.88 ; USB4.5 100.07,20.6 ; USB4.5 98.35,22.31 ; 10.43,138.19 HDD1.1 11.75,137.07 11.74,137.06 ; HDD1.7 10.56,145.81 ; v1(119.66,60.21) 120.21,60.75 C473.2 ; U38.2 37.34,107.25 C548.2 36.71,106.63 35.47,106.63 v1(35.42,106.58) ; C499.2 33.47,34.85 v1(33.52,34.8) ; 8.1,172.31 ODD1.1 ; ODD1.1 8.98,173.19 ; ODD1.1 7.22,173.19 ; C55.2 75.62,81.08 v1(77.86,78.84) ; C321.1 140.66,160.53 C316.1 140.75,161.24 v1(142.02,161.24) ; HDD1.4 10.66,142 ; C385.2 C456.1 79.79,82.88 C458.2 80.93,81.74 v5(80.93,81.18) ; PC141.2 v1(69.78,205.49)
  vias: v1(5.47,133.32) v1(7.78,133.17) v1(10.47,133.17) v1(12.68,133.22) v1(15.48,133.15) v1(18.17,133.15) v1(20.84,133.15) v1(21.14,70.36) v1(21.09,68.15) v1(21.06,66.32) v1(21.06,63.75) v1(21.12,61.06) v1(21.12,57.12) v1(21.24,73.74) v1(21.36,1.26) v1(23.3,73.86) v1(23.5,133.15) v1(25.79,34.82) v1(25.94,133.1) v1(25.94,42.98) v1(25.99,41.57) v1(26.12,1.09) v1(28,132.97) v1(29.05,109.19) v1(29.09,131.55) v1(29.07,129.92) v1(29.07,128.2) v1(29.07,126.44) v1(29.07,124.54) v1(29.07,122.78) v1(29.07,120.1) v1(29.07,118.34) v1(29.13,116.82) v1(29.11,113.79) v1(29.09,111.47) v1(29.07,106.3) v1(29.07,103.29) v1(29.06,97.29) v1(29.06,95.53) v1(29.07,93.1) v1(29.07,91.34) v1(29.07,88.4) v1(29.07,86.64) v1(29.07,83.47) v1(29.07,81.71) v1(29.12,78.82) v1(29.12,77.06) v1(29.12,76.15) v1(29.93,153.06) v1(29.95,149.28) v1(30.16,144.68) v1(30.16,143.76) v1(30.74,149.28) v1(30.97,153.06) v1(31.07,143.84) v1(31.2,1.09) v1(32.37,77.01) v1(32.98,118.26) v1(34.04,21.13) v1(34.91,77.04) v1(36.28,1.09) v1(36.57,20.89) v1(40.27,52.91) v1(40.27,52.2) v1(40.27,51.41) v1(41,52.93) v1(41,52.2) v1(41,51.41) v1(41.44,14.94) v1(41.36,1.09) v1(41.71,52.93) v1(41.71,52.2) v1(41.74,51.41) v1(42.91,18.57) v1(42.98,17.22) v1(43.24,14.86) v1(44.64,38.68) v1(44.66,37.82) v1(45.55,38.73) v1(45.52,37.87) v1(46.44,1.09) v1(47.05,35.59) v1(47.94,35.59) v1(50.11,110.13) v1(50.85,108.76) v1(51.52,1.09) v1(54.58,78.48) v1(56.25,120.4) v1(56.59,198.6) v1(56.6,1.09) v1(56.84,118.94) v1(61.68,1.09) v1(63.61,22.48) v1(63.58,21.62) v1(63.59,20.74) v1(66.76,1.09) v1(71.53,120.42) v1(71.84,1.09) v1(72.6,120.47) v1(75.73,118.44) v1(76.92,1.09) v1(78.09,116.92) v1(82,1.09) v1(83.98,4.32) v1(85.73,1.09) v1(87.43,1.09) v1(91.96,131.76) v1(92.16,1.09) v1(94.37,131.89) v1(96.43,131.86) v1(96.55,28.96) v1(96.58,1.12) v1(96.88,159.59) v1(97.65,158.85) v1(98.97,93.78) v1(98.97,92.89) v1(99.45,193.95) v1(99.52,88.06) v1(99.73,28.83) v1(99.87,131.82) v1(100.74,162.92) v1(101.95,1.07) v1(102.12,212.32) v1(102.1,210.98) v1(102.15,130.59) v1(102.24,214.66) v1(105.01,151.43) v1(105.25,204.32) v1(105.33,206.59) v1(105.44,1.06) v1(106.31,194.03) v1(107.74,1.06) v1(107.98,148.72) v1(109.88,1.08) v1(109.99,194.08) v1(110.02,146.43) v1(112.17,144.4) v1(112.86,1.06) v1(113.95,194.08) v1(115.25,141.3) v1(116.9,1.09) v1(117.23,183.59) v1(117.76,138.56) v1(118.42,194.08) v1(120.3,136.02) v1(120.8,1.09) v1(121.17,183.59) v1(122.76,1.11) v1(122.97,133.35) v1(123.29,130.47) v1(123.38,214.5) v1(124.44,130.47) v1(125.39,1.11) v1(126.2,125.7) v1(126.73,193.73) v1(127.66,1.07) v1(128.07,19.35) v1(129.4,193.6) v1(130.18,1.19) v1(131.73,125.81) v1(132.05,208.1) v1(132.65,125.81) v1(132.78,1.09) v1(133.39,208.15) v1(133.59,125.81) v1(135.01,1.15) v1(136.15,205.18) v1(136.96,125.6) v1(137.93,1.09) v1(140.38,1.09) v1(142.93,1.09) v1(143.11,38.96) v1(143.11,37.24) v1(143.11,35.48) v1(143.11,33.68) v1(146.47,1.13) v1(148.52,227.67) v1(149.01,1.06) v1(149.92,227.59) v1(151.18,1.09) v1(153.15,57.8) v1(153.93,1.22) v1(157.92,219.91) v1(158.88,186.53) v1(160.2,184.6) v1(160.54,65.2) v1(160.92,217.3) v1(162.14,66.78) v1(162.34,219.25) v1(162.25,215.85) v1(164.55,100.97) v1(164.57,99.95) v1(164.57,98.96) v1(166.05,75.51) v1(166.12,73.63) v1(166.25,77.57) v1(166.73,79.43) v1(172.45,83.13) v2(23.6,3.96) v2(25.59,71.96) v2(33.41,162.97) v2(37.27,201.35) v2(37.37,211.15) v2(43.92,4.32) v2(62.52,58.14) v2(66.2,29.74) v2(69.48,31.62) v2(80.81,216.81) v2(85.54,8.26) v2(88.15,19.56) v2(90.18,204.27) v2(93.07,103.78) v2(93.81,199.47) v2(103.87,189.84) v2(111.16,23.83) v2(112.33,8.79) v2(119.21,7.29) v2(120.4,138.33) v2(120.71,146.69) v2(122.41,212.57) v2(125.61,131.78) v2(127.06,144.35) v2(127.64,135.92) v2(127.77,5.44) v2(129.83,179.91) v2(130.11,190.12) v2(132.09,126.59) v2(136.41,17.91) v2(137.32,126.95) v2(141.59,19.89) v2(141.8,103.77) v2(143.52,98.17) v2(151.09,20.88) v2(151.87,135.23) v2(152.66,145.16) v2(154.72,143.81) v2(156.85,32.61) v2(158.43,50.19) v2(163.43,213.61) v2(178.01,113.92) v2(178.06,84.02) v2(179.23,155.17) v3(24.82,3.76) v3(26.07,3.71) v3(28.54,179.92) v3(28.54,179.03) v3(28.54,178.15) v3(30.46,152.02) v3(30.46,151.13) v3(30.46,150.32) v3(33.62,166.47) v3(33.62,165.58) v3(33.62,164.69) v3(34.22,19.86) v3(35.72,15.06) v3(36.61,15.88) v3(36.61,14.99) v3(36.61,14.07) v3(37.52,14.99) v3(37.78,96.23) v3(37.78,95.36) v3(37.78,94.5) v3(37.78,93.64) v3(37.78,92.77) v3(43.27,139.4) v3(43.36,138.02) v3(44.33,136.3) v3(47.2,136.22) v3(47.66,57.78) v3(48.42,58.55) v3(48.42,57.78) v3(48.42,57.02) v3(49.18,57.78) v3(49.39,136.19) v3(49.94,86.38) v3(50.27,88.26) v3(51.54,136.53) v3(52.81,123.57) v3(53.7,123.59) v3(54.56,123.59) v3(55.45,123.59) v3(56.29,123.64) v3(58.19,124.35) v3(58.57,122.73) v3(59.22,213.66) v3(60.09,213.66) v3(60.95,214.53) v3(60.95,213.66) v3(60.95,212.8) v3(60.95,211.94) v3(61.58,136.5) v3(61.59,60.12) v3(61.58,59) v3(61.81,213.66) v3(62.16,59.56) v3(62.68,213.66) v3(62.71,60.1) v3(62.73,59) v3(63.81,136.51) v3(64.02,139.51) v3(64.73,141.63) v3(65.38,137.56) v3(65.77,135.97) v3(65.92,139.57) v3(66.86,141.68) v3(67.58,137.57) v3(67.81,139.49) v3(69.99,137.76) v3(70.14,139.24) v3(70.12,136.31) v3(70.2,135.12) v3(70.9,139.19) v3(70.95,109.52) v3(72.99,137.48) v3(73,136.09) v3(73.11,134.71) v3(73.19,148.68) v3(75.52,137.79) v3(76.92,136.71) v3(78.75,135.08) v3(79.54,135.05) v3(82.79,112.8) v3(82.79,111.76) v3(83.45,111.84) v3(84.21,111.84) v3(84.49,139.18) v3(85.12,184.94) v3(85.96,139.22) v3(86.01,112.65) v3(86.66,136.26) v3(87.74,139.8) v3(88.22,136.32) v3(88.4,138.2) v3(90.24,137.59) v3(91.53,185.51) v3(91.69,104.54) v3(91.7,102.9) v3(92.51,104.54) v3(92.51,102.9) v3(92.57,186.52) v3(92.69,184.81) v3(94.11,183.36) v3(94.41,186.31) v3(95.05,184.35) v3(96.19,185.29) v3(96.3,179.83) v3(97.52,173.05) v3(97.49,171.22) v3(97.49,169.62) v3(97.47,165.28) v3(97.61,177.61) v3(97.63,167.17) v3(98.31,175.51) v3(98.68,178.25) v3(98.96,173.05) v3(99.27,164.31) v3(99.45,169.57) v3(99.47,178.24) v3(99.58,171.22) v3(99.63,167.06) v3(100.41,175.69) v3(100.36,174.52) v3(100.46,178.33) v3(100.79,172.26) v3(101.43,169.52) v3(101.48,194.08) v3(102.27,222.97) v3(102.27,221.29) v3(102.62,175.41) v3(102.75,171.88) v3(103.64,194.01) v3(117.48,148.08) v3(126.55,82.03) v3(127.53,83.04) v3(127.54,82.04) v3(127.54,81.12) v3(128.51,82.01) v3(128.61,147.83) v3(131.25,110.73) v3(131.72,35.56) v3(132.42,111.88) v3(132.39,110.72) v3(132.37,109.59) v3(132.74,35.57) v3(133.64,136.07) v3(133.57,110.73) v3(134.14,144.82) v3(134.22,174.88) v3(134.27,183.45) v3(134.34,130.66) v3(135.1,185.79) v3(135.12,182.22) v3(135.32,180.82) v3(135.42,179.37) v3(135.59,143.64) v3(135.59,131.77) v3(135.75,171.63) v3(135.69,133.88) v3(135.76,130.66) v3(136.28,190.27) v3(136.26,178.25) v3(136.35,169.34) v3(136.43,147.96) v3(137.27,133.81) v3(151.14,134.44) v3(151.14,133.32) v3(152.23,134.44) v3(152.23,133.32) v3(154.44,31.62) v3(154.47,30.61) v3(154.49,29.59) v3(155.28,24.54) v3(155.35,31.62) v3(155.35,30.61) v3(155.35,29.59) v3(155.74,126.42) v3(156.22,124.08) v3(156.24,31.6) v3(156.24,30.61) v3(156.24,29.59) v3(158.12,48.77) v3(158.42,119.37) v3(158.39,117.18) v3(159.55,50.14) v3(159.55,48.77) v3(159.55,47.27) v3(159.58,114.63) v3(159.88,116.87) v3(160.87,110.54) v3(160.89,48.79) v3(162.08,109.15) v3(162.19,111.43) v3(162.32,98.26) v3(162.3,96.05) v3(164.28,95.75) v3(164.31,94.41) v4(35.62,202.29) v4(43.04,171.7) v4(44.69,36.32) v4(47.43,36.65) v4(48.32,155.37) v4(51.75,182.74) v4(77.33,217.65) v4(80.98,212.52) v4(100.36,183.01) v4(162.85,78.97) v5(1.4,226.34) v5(1.4,221.26) v5(1.4,216.18) v5(1.4,211.1) v5(1.4,206.02) v5(1.4,190.78) v5(1.4,185.7) v5(1.4,180.62) v5(1.4,175.54) v5(1.4,170.46) v5(1.38,167.94) v5(1.4,165.38) v5(1.4,155.22) v5(4.32,228.76) v5(4.99,151.51) v5(5.34,147.19) v5(5.39,141.38) v5(5.37,135.61) v5(9.4,228.76) v5(14.48,228.76) v5(19.53,228.76) v5(21.15,40.02) v5(21.13,29.15) v5(21.15,23.8) v5(21.15,18.55) v5(21.22,35.79) v5(21.16,32.13) v5(21.16,8.43) v5(21.2,4.5) v5(21.25,43.23) v5(21.62,199.52) v5(21.7,198.33) v5(23.53,195.33) v5(23.53,194.31) v5(24.61,228.76) v5(28.1,177.06) v5(29.12,177.06) v5(29.5,175.95) v5(29.5,174.88) v5(29.69,228.76) v5(30.51,175.95) v5(30.51,174.88) v5(34.58,163.58) v5(34.58,162.56) v5(34.58,161.54) v5(34.7,198.63) v5(34.7,197.56) v5(34.7,196.47) v5(34.7,195.33) v5(34.7,194.18) v5(34.7,193.12) v5(34.7,192.02) v5(34.7,190.88) v5(34.7,189.74) v5(34.7,188.67) v5(34.77,228.76) v5(35.85,200.91) v5(35.85,199.77) v5(35.85,198.63) v5(35.85,197.56) v5(35.85,196.47) v5(35.85,195.33) v5(35.85,194.18) v5(35.85,193.12) v5(35.85,192.02) v5(35.85,190.88) v5(35.85,189.74) v5(35.85,188.67) v5(36.74,213.87) v5(36.74,212.72) v5(36.74,209.55) v5(36.74,208.41) v5(36.74,204.98) v5(36.74,203.91) v5(36.74,202.82) v5(36.89,206.91) v5(36.89,205.99) v5(37.88,213.87) v5(37.88,212.72) v5(37.88,209.55) v5(37.88,208.41) v5(37.88,206.91) v5(37.88,205.99) v5(37.88,204.98) v5(37.88,203.91) v5(37.88,202.82) v5(39.85,228.76) v5(40.67,170.56) v5(40.94,182.61) v5(41.69,170.56) v5(41.96,182.61) v5(42.71,170.56) v5(42.97,182.61) v5(43.72,170.56) v5(44.86,228.76) v5(44.9,154.93) v5(45.4,155.8) v5(45.92,154.93) v5(46.46,155.78) v5(46.87,154.94) v5(49.44,166.12) v5(49.44,164.97) v5(49.44,163.7) v5(49.94,228.76) v5(50.71,186.82) v5(50.71,185.8) v5(50.71,184.78) v5(50.71,183.77) v5(51.72,186.82) v5(51.72,185.8) v5(51.72,184.78) v5(51.72,183.77) v5(55.02,228.76) v5(59.34,199.64) v5(59.34,198.63) v5(59.34,197.51) v5(60.1,228.76) v5(60.36,199.64) v5(60.36,198.63) v5(60.36,197.51) v5(63.2,199.64) v5(63.2,198.63) v5(63.2,197.51) v5(64.17,199.64) v5(64.17,198.63) v5(64.17,197.51) v5(64.3,27.81) v5(65.18,228.76) v5(65.44,27.81) v5(66.56,27.71) v5(67.84,192.28) v5(67.84,191.3) v5(67.88,190.25) v5(67.85,189.23) v5(67.85,188.21) v5(67.85,187.2) v5(68.3,69.96) v5(68.81,70.99) v5(69.43,69.94) v5(70,70.96) v5(70.26,228.76) v5(70.5,69.92) v5(71.28,57.76) v5(71.28,56.79) v5(71.37,70.93) v5(71.56,69.87) v5(72.02,58.65) v5(72.14,56.74) v5(72.17,57.71) v5(72.46,70.93) v5(72.65,69.84) v5(72.93,58.65) v5(73.08,57.68) v5(73.08,56.77) v5(73.67,69.8) v5(73.92,58.65) v5(73.86,27.03) v5(74,57.63) v5(74,56.74) v5(74.71,69.72) v5(75.01,27.01) v5(75.34,228.76) v5(76.33,26.95) v5(77.63,26.85) v5(78.65,217.04) v5(78.65,216.03) v5(78.65,215.01) v5(78.65,214) v5(79.66,217.04) v5(79.66,216.03) v5(79.66,215.01) v5(79.66,214) v5(80.32,228.8) v5(80.68,215.01) v5(80.68,214) v5(84.13,6.55) v5(85.53,228.75) v5(85.89,19.28) v5(85.94,13.67) v5(85.92,12.29) v5(85.96,16.48) v5(86.06,10.72) v5(88.12,62.18) v5(88.12,61.17) v5(88.12,60.15) v5(88.17,58.67) v5(88.17,57.66) v5(89.14,62.18) v5(89.14,61.17) v5(89.14,60.15) v5(89.19,58.67) v5(89.19,57.66) v5(89.19,56.64) v5(90.15,62.18) v5(90.15,61.17) v5(90.15,60.15) v5(90.2,58.67) v5(90.2,57.66) v5(90.2,56.64) v5(90.47,228.79) v5(90.63,9.98) v5(90.71,16.13) v5(90.71,12.83) v5(92.87,14.73) v5(93.02,8.51) v5(95.58,228.79) v5(95.89,6.53) v5(96.93,14.73) v5(96.93,11.94) v5(96.87,9.91) v5(100.66,228.79) v5(101.4,7.19) v5(103.67,107.57) v5(104.63,107.57) v5(105.47,115.49) v5(105.72,13.72) v5(105.67,11.53) v5(105.82,228.77) v5(105.85,21.01) v5(105.82,18.8) v5(105.82,16.51) v5(105.9,114.6) v5(106.73,36.31) v5(108.08,114.43) v5(108.19,36.3) v5(108.62,106.32) v5(109.63,106.3) v5(110.4,29.44) v5(110.82,228.79) v5(112.64,113.94) v5(115.19,106.54) v5(115.9,228.79) v5(116.23,106.53) v5(120.98,228.79) v5(126.06,228.79) v5(131.14,228.79) v5(135.82,104.04) v5(135.82,103.02) v5(135.8,101.85) v5(135.82,100.86) v5(135.8,99.69) v5(136.33,228.78) v5(136.94,104.01) v5(136.94,103) v5(136.94,101.85) v5(136.94,100.84) v5(136.94,99.69) v5(137.96,104.01) v5(137.96,103) v5(137.96,101.85) v5(137.96,100.84) v5(137.96,99.69) v5(138.99,104.02) v5(138.99,103.01) v5(138.99,101.86) v5(138.97,100.91) v5(138.97,99.69) v5(139.98,103.02) v5(139.98,101.88) v5(140.01,100.89) v5(140.01,99.9) v5(139.98,98.86) v5(140.1,104.01) v5(140.95,103.06) v5(140.93,101.87) v5(140.94,98.85) v5(140.96,100.88) v5(140.96,99.89) v5(141.38,228.78) v5(143.74,136.86) v5(143.72,135.81) v5(146.46,228.6) v5(146.72,17.81) v5(153.83,7.49) v5(153.83,4.95) v5(154.32,149.13) v5(154.31,148.26) v5(154.31,147.37) v5(154.29,146.46) v5(154.31,145.52) v5(154.31,144.63) v5(155.23,146.46) v5(155.2,145.52) v5(155.23,144.58) v5(155.3,149.12) v5(155.28,148.23) v5(155.25,147.35) v5(156.62,228.6) v5(158.91,16.51) v5(168.6,215.19) v5(168.6,210.11) v5(168.6,56.28) v5(168.56,52.45) v5(168.56,33.66) v5(168.56,29.59) v5(168.6,25.8) v5(168.69,48.51) v5(168.69,44.96) v5(168.69,42.04) v5(168.69,38.1) v5(168.84,205.49) v5(168.79,197.33) v5(168.79,189.94) v5(168.82,169.67) v5(168.82,164.34) v5(168.86,184.71) v5(168.86,179.63) v5(168.86,174.55) v5(170.3,161) v5(175.38,161) v5(175.7,125.07) v5(176.06,86.51) v5(177.2,96.27) v5(177.71,99.16) v5(178.01,158.6) v5(178.04,112.42) v5(177.99,93.27) v5(178.11,155.98) v5(178.14,120.95) v5(178.11,115.29) v5(178.19,117.91) v5(178.26,125.81) v5(178.34,68.33) v5(179.08,128.55) v5(179.48,90.35) v5(179.56,86.59) v5(179.66,144.73) v5(179.66,142.27) v5(179.66,137.9) v5(179.76,133.63) v5(179.76,100.94) v5(180.32,96.29) v5(180.4,93.09) v5(180.46,161) v5(180.83,150.98) v5(180.91,154.1) v5(180.86,99.03) v5(181.03,156.72) v5(180.98,140.44) v5(181.14,146.89) v5(181.11,136.35) v5(181.19,132.54) v5(181.34,116.94) v5(181.34,112.55) v5(181.52,127.74) v5(181.49,121.49) v5(181.57,124.61) v5(181.85,100.94) v5(181.85,90.25) v5(182.02,86.46) v5(182.64,109.24) v5(183.6,153.99) v5(183.6,148.91) v5(183.6,143.83) v5(183.6,138.75) v5(183.6,133.67) v5(183.6,123.51) v5(183.6,118.43) v5(183.6,113.35) v5(183.6,102.24) v5(183.6,97.16) v5(183.6,92.08) v5(183.6,87) v5(183.6,81.92) v5(183.73,128.04)
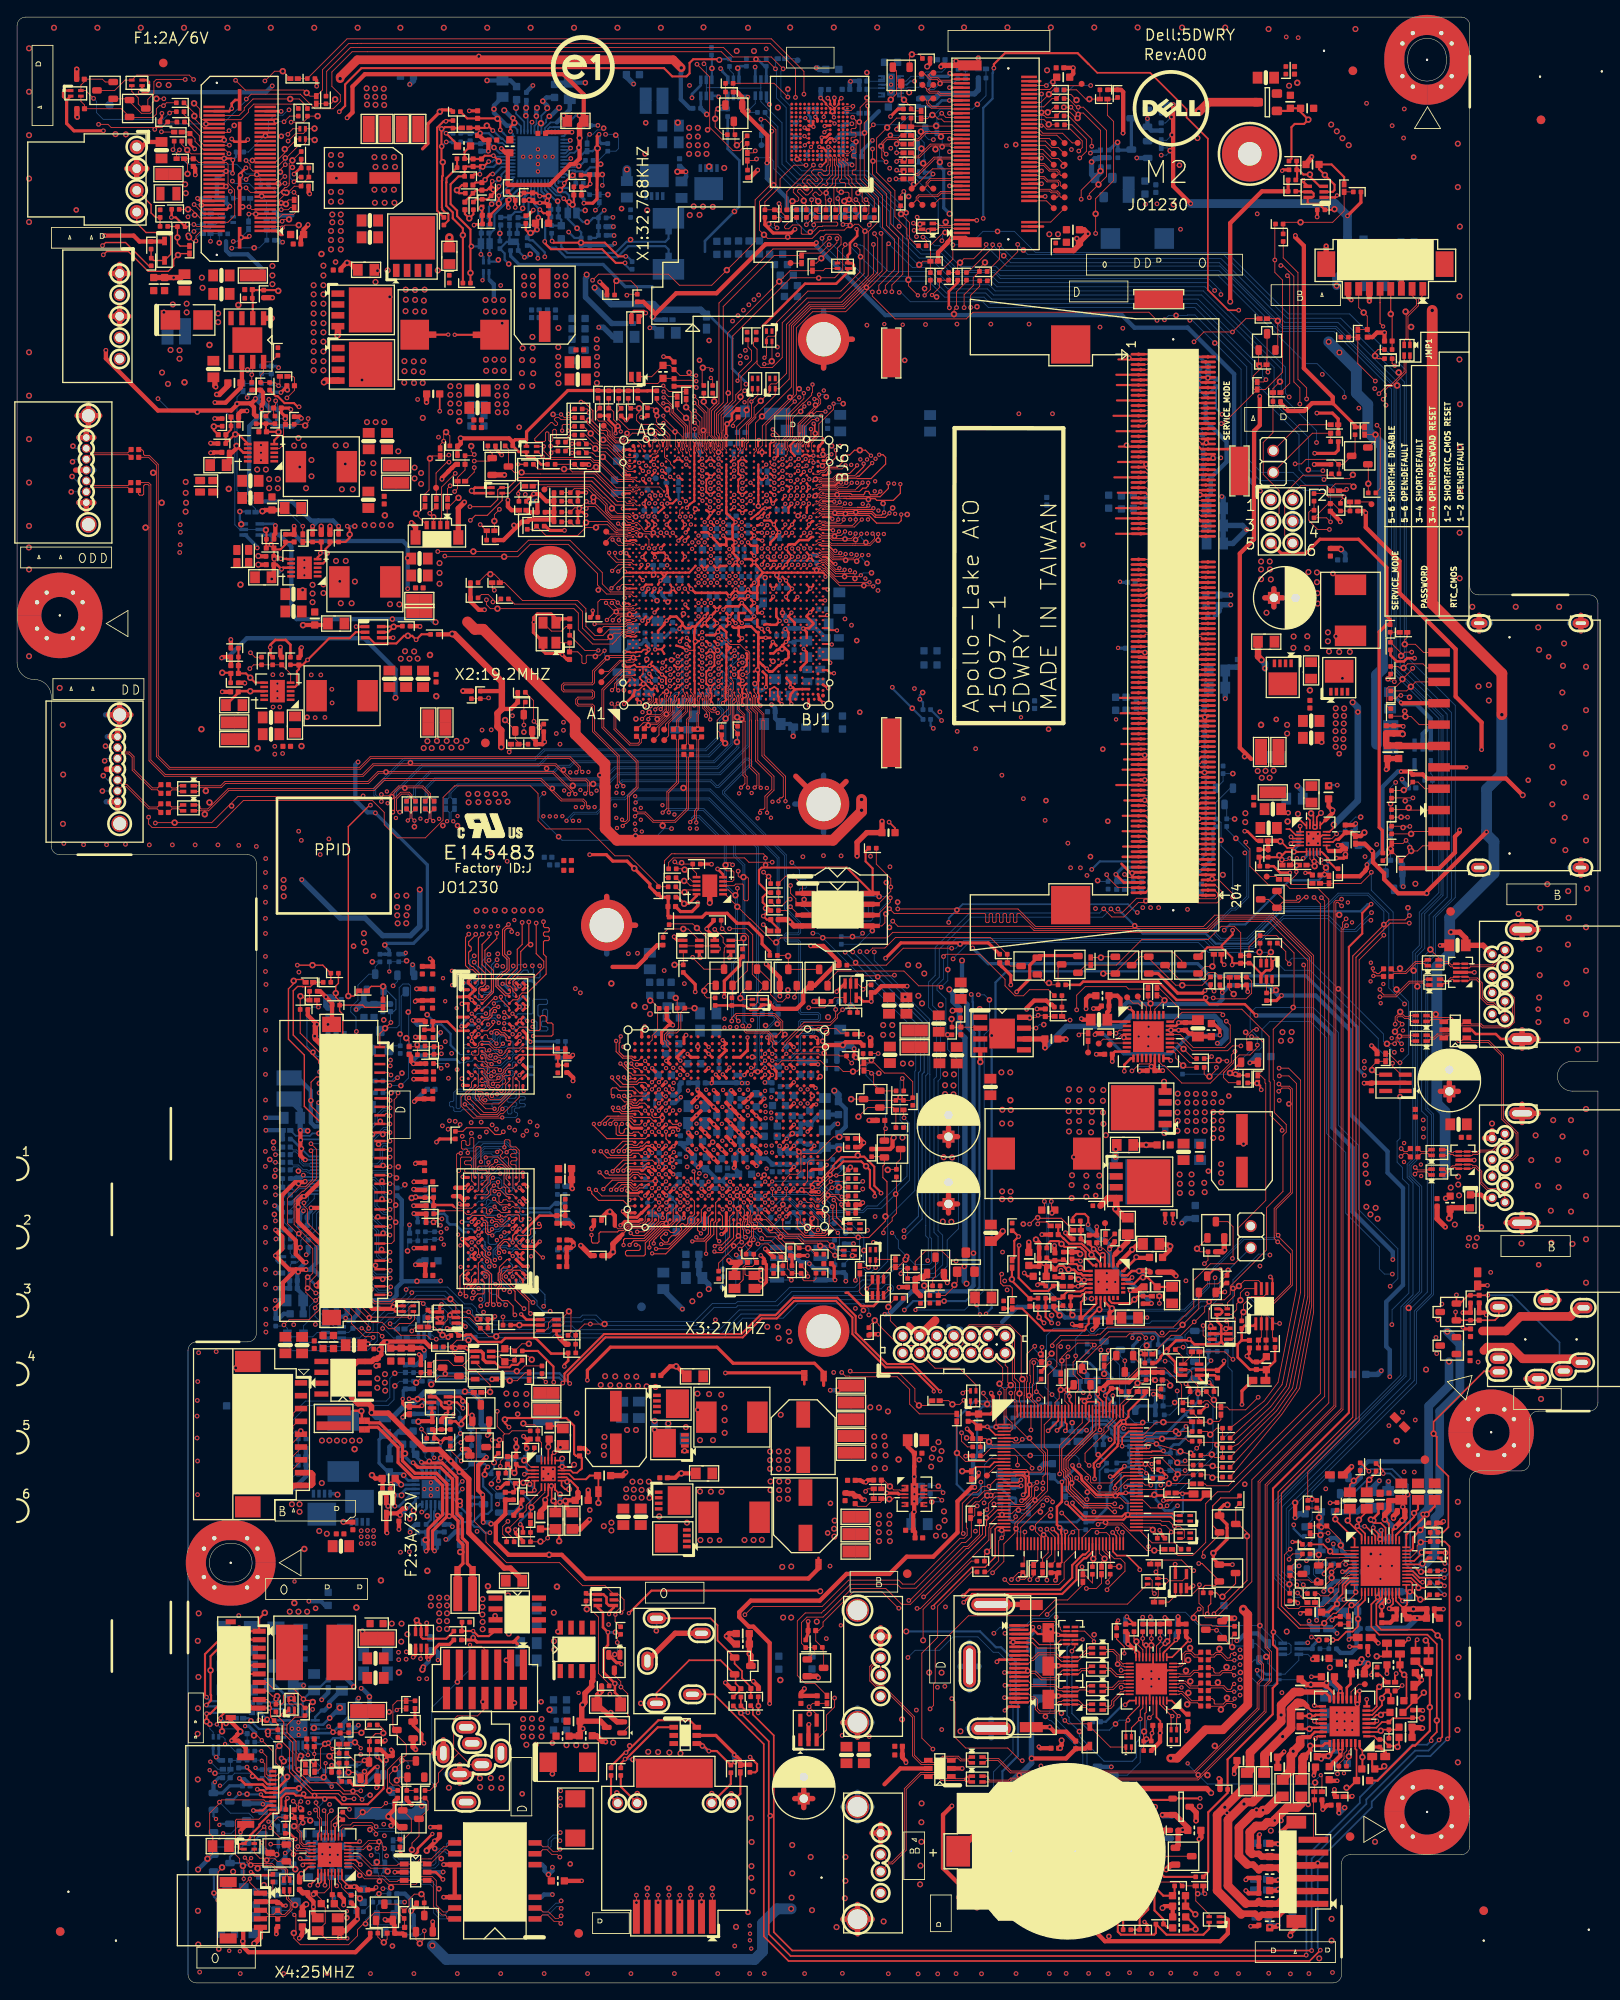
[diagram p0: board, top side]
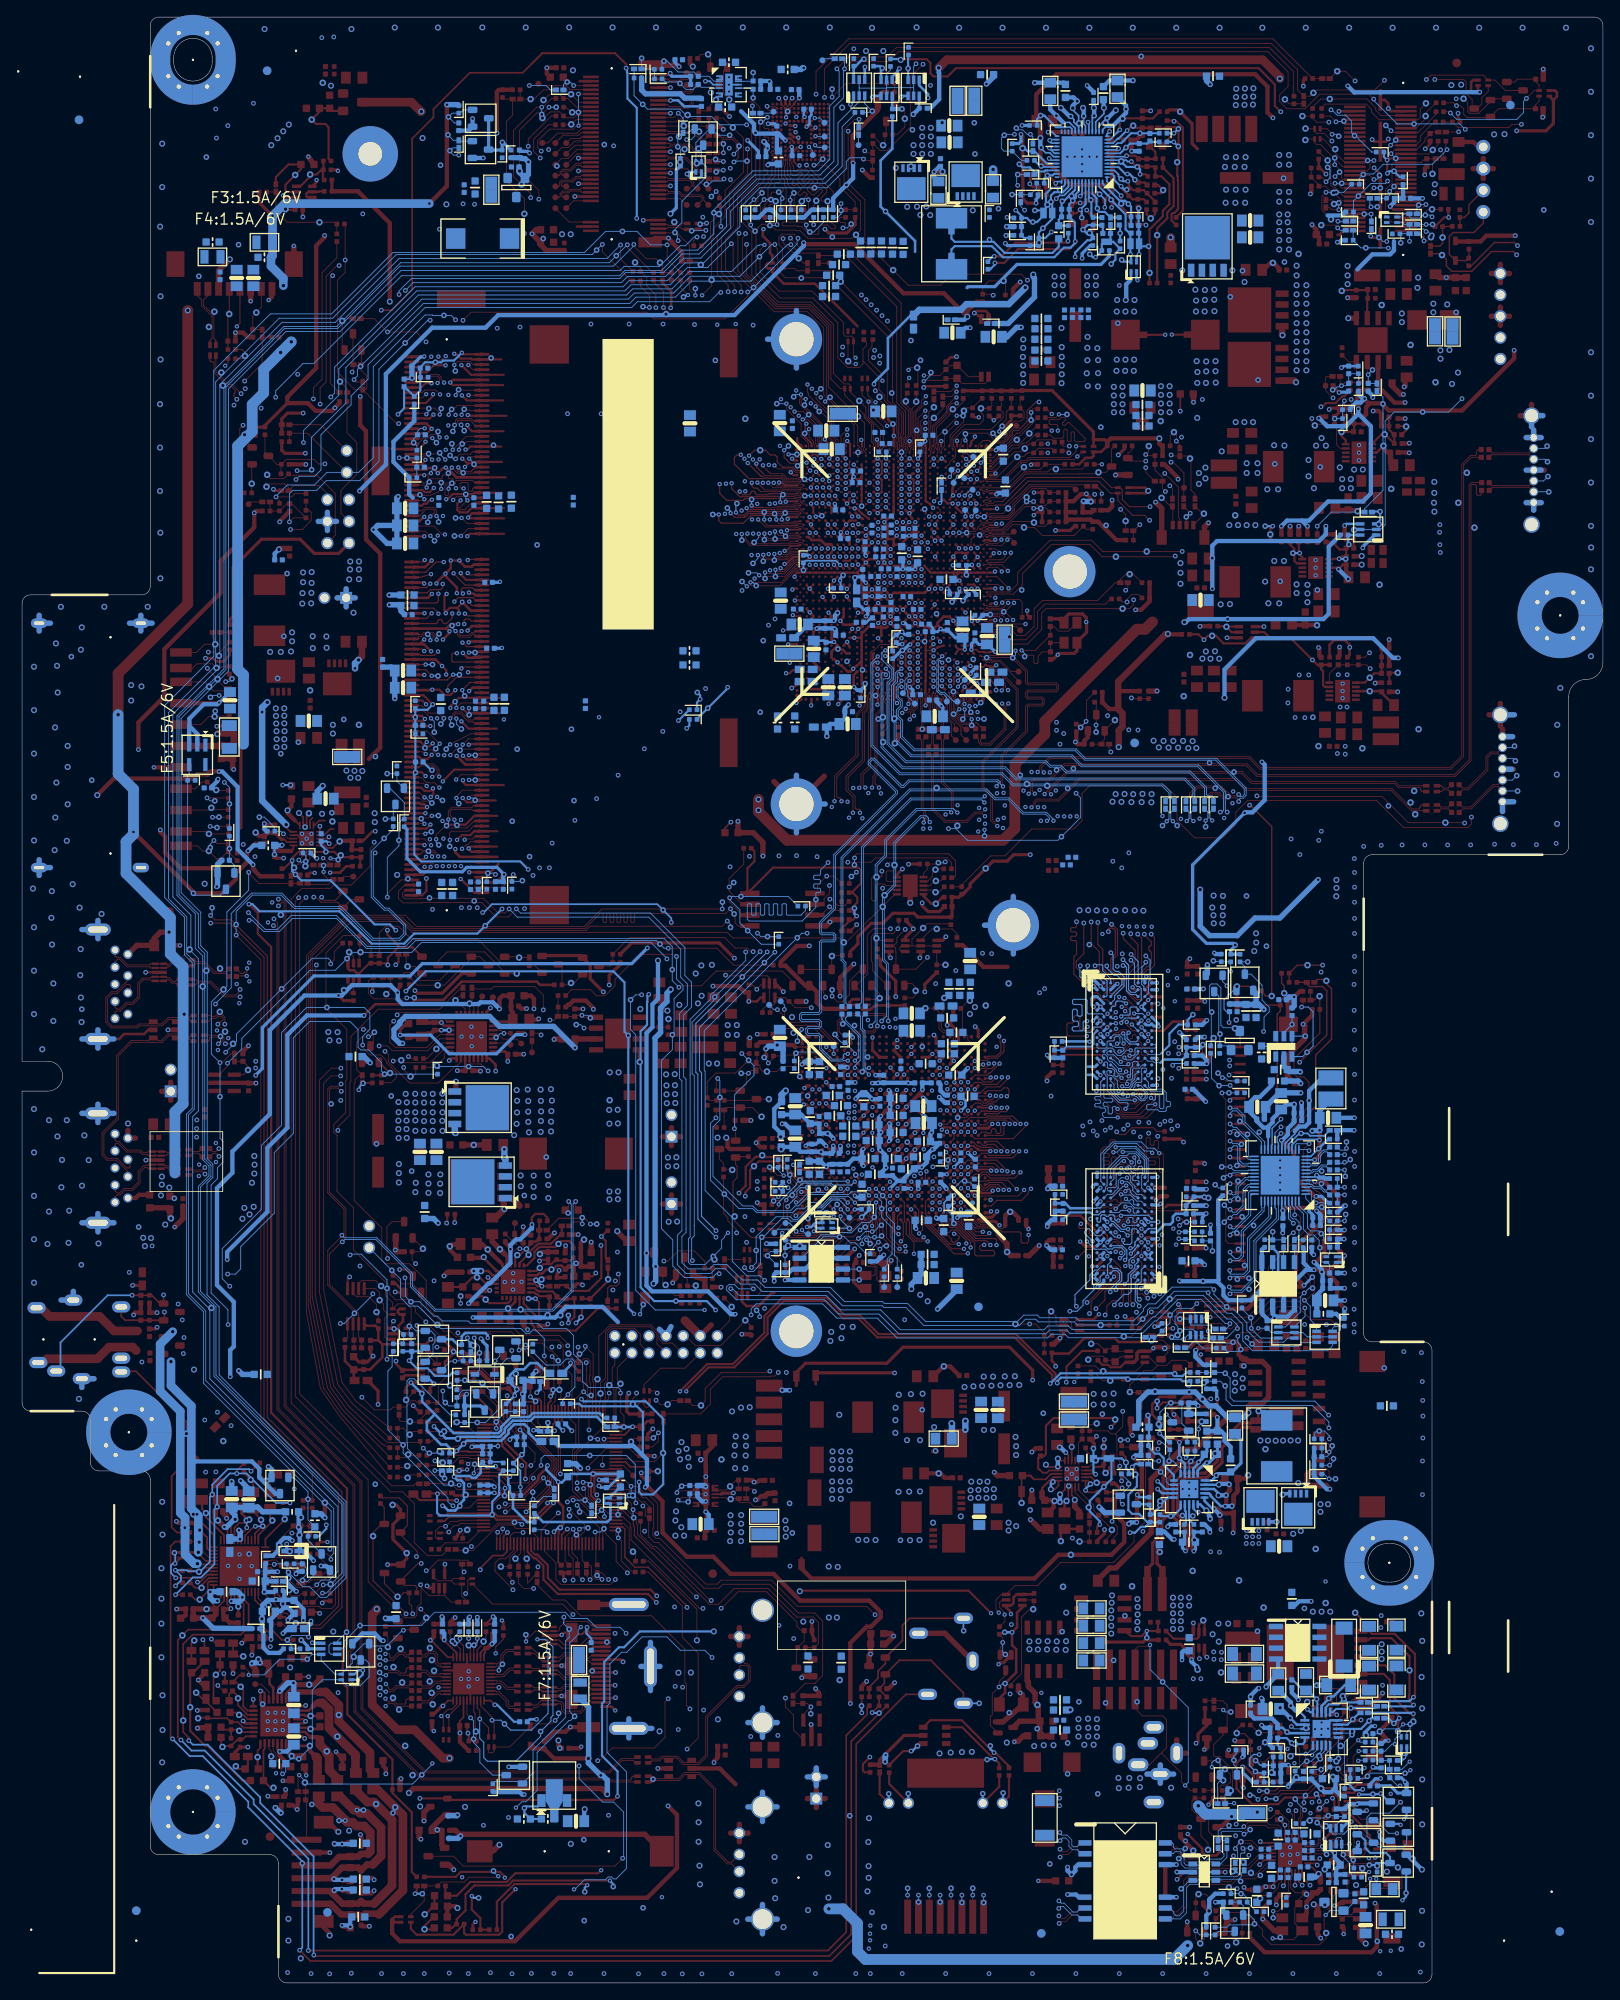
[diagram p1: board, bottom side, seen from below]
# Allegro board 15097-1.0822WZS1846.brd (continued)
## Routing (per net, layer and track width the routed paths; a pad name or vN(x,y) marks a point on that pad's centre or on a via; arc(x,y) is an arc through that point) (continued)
GND_AUD: length 6.5
  TOP w0.203: U16.40 160.55,53.74 v4(160.05,54.23)
  TOP w0.635: v4(160.05,54.23) 160.05,54.84 160.54,55.32 C148.2 161.89,56.43 C145.1
V1P8A_S5_PG: length 251.3
  TOP w0.102: R404.2 127.92,47.42 127.62,47.12 v1(127.62,46.86) ; PR49.2 v1(33.43,170.43)
  L3 w0.127: v1(19.03,167.36) 19.16,167.23 19.16,143.05 23.6,138.61 31.76,138.61 35.39,134.98 35.39,134.59 35.42,134.57 35.42,133.27 37.63,131.06 37.63,119.23 40.37,116.48 40.37,107.16 40.83,106.71 40.83,79.52 40.86,79.48 40.86,79.24 45.1,75.01 47.63,75.01 48.06,75.01 49.26,73.81 63.31,73.81 63.37,73.88 65.49,73.88 65.55,73.81 84.81,73.81 93.76,64.86 93.76,51.53 98.75,46.53 111.28,46.53 112.38,45.44 126.06,45.44 127.49,46.86 v1(127.62,46.86)
  L4 w0.127: v1(33.43,170.43) 33.43,170.44 32.42,171.46 23.13,171.46 v1(19.03,167.36)
  BOTTOM w0.102: v1(33.43,170.43) 32.37,171.5 31.78,172.09 R587.1 27.91,172.45 25.74,174.62 v2(25.74,184.74) 25.74,185.53 R580.1
V1P8A_S5_PG_EC: length 4.1
  TOP w0.102: U14.58 127.05,50.61 127.46,50.19 127.49,50.19 127.92,49.76 R404.1 v4(128.96,48.7)
VBAT1: length 27.5
  TOP w0.635: BT1.1 112.13,17.39 133.48,17.39 v1(133.68,17.19) 133.68,17.25 134.28,17.86 R483.1
  BOTTOM w0.635: TP85.1 133.96,16.91 v1(133.68,17.19)
VBAT1_R: length 8.4
  TOP w0.635: U27.G 135.86,16.12 R483.2 137,17.86 R484.1 137.01,18.18 135.52,19.67 D7.2 134.05,19.67 v1(134.03,19.65)
  BOTTOM w0.635: v1(134.03,19.65) 134.12,19.56 TP84.1
VCC: length 251.8
  TOP w0.305: v1(149.87,44.45) 149.63,44.69 R414.1
  TOP w0.381: R220.1 113.65,121.68 103.43,121.68 v1(101.63,119.89)
  TOP w0.508: v5(118.73,26.26) 122.75,26.26 C203.2 123.9,27.41 124.98,27.41 125.28,27.71 D6.A
  TOP w0.635: PU6.6 PC81.1 120.28,109.43 v1(120.29,109.41) ; v5(116.52,22.07) 117.19,22.74 139.22,22.74 v5(139.73,22.23)
  L3 w0.508: v1(149.87,44.45) 148.85,44.45 146.39,41.99 146.39,36.05 146.38,36.04 146.38,28.94 144.24,26.81 143.75,26.31 143.75,24.21 142.3,22.76 140.27,22.76 v5(139.73,22.23)
  L3 w0.635: v5(103.56,30.84) 105.6,30.84 108.11,28.32 116.67,28.32 v5(118.73,26.26)
  L3 w1.016: v5(89.36,66.47) 91.78,64.06 91.78,49.81 92.41,49.17 92.41,44.09 93.58,42.93 v5(93.58,42.27)
  L4 w0.508: v1(136.78,82.15) 138.21,83.58 138.21,87.7 142.84,92.34 142.84,105.6 140.75,107.7 140.75,109.65 v1(140.47,109.93) ; v1(120.29,109.41) 120.03,109.41 111.13,118.31 110.17,118.31 110.09,118.39 107.44,118.39 105.94,119.89 v1(101.63,119.89)
  L4 w0.762: v5(103.56,30.84) 101.19,30.84 93.36,38.67 93.36,42.04 v5(93.58,42.27)
  BOTTOM w0.508: v3(132.24,77.85) 124.93,77.85 122.61,77.85 121.37,79.1 117.05,79.1 115.27,77.32
  BOTTOM w0.635: v1(140.47,109.93) 140.81,109.93 141.47,110.6 141.47,111.54 140.79,112.22 140.79,112.43 140.14,113.08 130.29,113.08 129.12,111.91 122.79,111.91 v1(120.29,109.41) ; 110.41,76.48 LPC1.8 109.06,76.78 ; v5(116.52,22.07) 116.52,23.72 117.08,24.28 v2(117.28,24.28) 118.73,25.73 v5(118.73,26.26) 118.7,26.29 118.7,32.28 F7.1
  vias: v2(39.38,121.3) v2(51.29,74.24) v2(105.57,61.21) v5(17.96,191.05) v5(19.01,191.02) v5(19.01,190.03) v5(19.67,210.44) v5(19.74,209.4) v5(31.19,129.05) v5(31.18,128.12) v5(31.2,127.14) v5(40.59,122.8) v5(40.57,121.72) v5(40.8,120.73) v5(87.79,76.76) v5(89.01,76.76) v5(89.12,75.43) v5(90.3,76.17) v5(90.41,75.11) v5(107.04,61.47) v5(106.97,60.4) v5(107.25,62.48) v5(107.83,63.27) v5(108,61.26) v5(108.18,62.22)
VCC3: length 1045.5
  TOP w0.203: U16.11 155.99,46.97 155.45,46.42 155.45,45.13 155.28,44.96 v1(155.28,44.86) ; U20.11 135.17,38.11 136.84,39.78 136.84,39.8 137.12,40.08 v1(137.22,40.08) ; C196.1 133.79,30.63 133.34,31.08 U20.37
  TOP w0.305: DIMM1.199 129.53,128.75 v1(128.58,129.69) ; v1(42.17,25.27) 41.88,25.27 40.88,24.27 40.88,23.39 40.57,23.09 39.36,23.09 R473.1 ; R331.1 55.09,76.62 R327.1 55.66,77.65 55.91,77.9 v1(55.91,77.98) ; R491.1 29.81,12.6 27.82,12.6 27.44,12.98 v3(27.37,12.98) ; R392.1 150.13,51.59 v3(149.26,51.59) ; R423.1 128.67,42.23 v3(128.85,42.41) ; R482.1 31.91,17.5 v3(32.59,16.82) ; RN17.2 5.8,220.28 5.39,220.69 5.39,221.21 5.59,221.4 RN17.1 ; v3(131.94,7.14) 132.25,6.82 R508.1
  TOP w0.381: R367.1 111.3,61.67 111.25,61.63 v1(111.01,61.63) ; R347.1 143.34,69.27 v1(143.34,67.68) ; 5.8,220.28 5.8,217.55 6.66,216.69 v1(10.1,216.69) ; R251.2 140.04,112.24 140.75,111.53 v1(140.75,110.9) ; PR17.1 157.26,208.32 v1(155.69,206.74)
  TOP w0.508: v1(137.22,40.08) 136.8,40.5 C171.1 ; v1(126.14,110.95) 126.3,111.1 R252.2 ; R119.2 27.72,183.51 27.72,184.36 27.35,184.73 ; R46.1 85.77,211.21 v1(86.67,212.11) ; v1(10.26,204.43) 13.63,204.43 14.32,203.75 R73.1 17.19,203.75 D1.K ; R420.1 R421.1 133.78,41.98 R418.1 134.89,41.99 R422.1 134.9,42.17 v1(134.32,42.75) ; 32.65,83.46 31.1,81.92 31.1,79.79 30.2,78.89 v1(30.18,78.89) ; 32.65,83.46 31.86,83.46 v1(30.23,85.09) 31.02,85.88 31.02,87.32 v1(30.25,88.09) ; 32.65,83.46 33.79,83.46 v1(33.82,83.44) ; v1(137.34,208.18) 135.29,210.23 v1(135.29,219.75) ; R642.1 34.02,113.22 v1(35.08,112.16) ; v1(43.09,28.37) 42.96,28.24 R460.1 ; 27.35,184.73 27.89,185.27 v1(27.89,185.36) ; 27.35,184.73 27.34,184.73 27.26,184.81 25.89,184.81 25.06,183.97 16.48,183.97 10.39,190.06 v1(10.39,191.01) ; v1(26.67,9.32) 26.46,9.12 26.46,4.22 27.09,3.59 39.59,3.59 41.33,5.32 R510.2 ; C196.1 133.79,29.27 v1(133.75,29.24) 133.75,28.21 R464.1
  TOP w0.635: 104.35,76.99 105.63,75.7 LPC1.4 ; v1(35.08,112.16) 34.9,111.98 34.9,110.47 36.91,108.46 36.91,106.05 36.1,105.23 v1(35.36,105.23)
  TOP w1.016: 107.43,77.5 LPC1.4
  L3 w0.381: v1(152.08,42.42) 152.05,42.44 152.05,43.26 151.14,44.17 151.14,48.8 151.49,49.16 151.49,49.65 149.55,51.59 v3(149.26,51.59)
  L3 w0.508: v1(10.1,216.69) 10.12,216.67 10.12,204.56 v1(10.26,204.43) 11.09,203.6 11.09,201.92 10.39,201.23 v1(10.39,191.01) 10.39,186.39 13.65,183.13 13.65,176.2 16.14,173.7 16.14,141.31 20.97,136.48 28.95,136.48 32.27,133.17 32.27,130.76 33.32,129.71 v1(33.32,129.08) 33.32,120.32 34.2,119.44 34.2,112.93 34.97,112.16 v1(35.08,112.16) ; v1(69.86,204.44) 71.15,204.44 72.98,202.62 72.98,199.06 74.15,197.89 78.49,197.89 86.67,206.07 v1(86.67,212.11) 86.8,211.98 97,211.98 v1(97.72,212.7) ; v5(109.09,116.24) 109.5,116.65 114.62,116.65 115.75,117.78 123.52,117.78 129.93,124.19 129.93,128.35 v1(128.58,129.69)
  L3 w0.635: v5(138.41,20.65) 139.51,20.65 140.66,21.81 142.69,21.81 145.19,24.31 145.19,26.42 149.03,30.25 149.03,35.33 153.37,39.68 153.37,40.89 155.18,42.7 155.18,44.75 v1(155.28,44.86) ; v5(69.76,28.12) 69.76,28.32 65.32,32.75 46.33,32.75 43.09,29.51 v1(43.09,28.37) 43.09,27.56 43.09,25.97 42.38,25.27 v1(42.17,25.27) 41.88,25.27 38.62,22.01 36.03,22.01 35.43,22.61 31.48,22.61 30.89,22.02 30.89,19.84 32.59,18.14 32.59,16.83 v3(32.59,16.82) 32.35,16.58 32.33,16.58 32.08,16.33 32.08,15.51 32.1,15.49 32.1,14.89 30.71,13.5 30.71,10.97 29.6,9.86 27.21,9.86 v1(26.67,9.32) ; v1(33.82,83.44) 33.95,83.44 34.8,84.29 34.8,89.64 35.45,90.3 35.45,98.47 34.56,99.36 34.56,104.43 v1(35.36,105.23) ; v1(97.72,212.7) 98.8,212.7 101.45,210.05 103.2,210.05 103.47,210.32 107.81,210.32 108.9,209.24 119.51,209.24 120.01,209.74 135.78,209.74 v1(137.34,208.18)
  L3 w1.016: v5(107.53,52.32) 106.94,51.74 105.08,51.74 103.83,50.5 99.77,50.5 98.13,52.14 98.13,68.18 100.57,70.62 100.57,74.47 101.08,74.98 101.15,74.98 101.68,75.52 101.68,75.58 103.1,77 104.17,77 105.47,75.7 LPC1.4
  L3 w1.27: 149.46,70.68 155.2,76.42 155.2,79.68 159.72,84.2 159.72,84.92 160.87,86.06 160.87,92.63 159.83,93.66 159.83,113.1 160.68,113.95 160.68,115.51 161.01,115.84 161.01,116.01 161.88,116.89 161.88,125.78 163.63,127.53 v5(163.63,128.6)
  L4 w0.305: v1(55.91,77.98) 55.91,77.82 55.71,77.61 54.65,77.61 52.99,79.27 51.52,79.27 49.56,81.23 v1(49.56,82.14)
  L4 w0.508: v3(131.94,7.14) 131.48,7.59 131.48,17.96 v1(131,18.44) ; v3(27.37,12.98) 27.61,12.98 28.26,13.63 28.88,13.63 31.98,16.73 32.5,16.73 v3(32.59,16.82) ; v5(109.09,116.24) 117.15,108.18 123.6,108.18 126.04,110.62 126.04,110.85 v1(126.14,110.95)
  L4 w0.635: v5(133.16,20.59) 137.87,20.59 137.93,20.65 v5(138.41,20.65) ; v1(116.37,19.61) 112.61,19.61 108.4,23.81 94.28,23.81 92.62,25.46 70.85,25.46 70.43,25.89 70.43,25.91 69.76,26.59 v5(69.76,28.12) ; v5(109.09,116.24) 108.91,116.24 107.89,115.23 107.75,115.23 106.33,113.8 103.64,113.8 100.11,117.34 87.67,117.34 87.09,116.75 78.96,116.75 78.4,116.19 76.95,116.19 74.99,118.15 74.99,119.11 71.79,122.31 71.79,124.72 69.53,126.97 65.18,126.97 63.76,128.4 47.61,128.4 v5(47.12,127.91)
  BOTTOM w0.305: RN41.1 30.58,84.31 30.39,84.51 30.39,84.84 30.37,84.85 30.37,84.96 ; v1(30.23,85.09) 30.37,84.96 ; 30.37,84.96 RN41.2
  BOTTOM w0.381: v1(128.58,129.69) 129.41,130.52 132.43,130.52 132.43,130.52 132.95,130.52 133.47,130.01 138.39,130.01 139.95,131.56 139.95,134.96 R628.2 ; v1(42.17,25.27) 42.14,25.24 42.14,24.61 41.03,23.5 R789.1 ; v1(140.75,110.9) 137.19,110.9 135.01,108.71 129.47,108.71 127.24,110.95 v1(126.14,110.95)
  BOTTOM w0.457: R682.2 v1(30.25,88.09)
  BOTTOM w0.508: R690.1 35.02,85.98 35.02,84.24 34.22,83.44 ; R750.1 154.31,45.76 C486.1 ; R566.1 69.83,204.47 v1(69.86,204.44) ; 45.14,82.07 44.41,81.33 44.41,80.44 43.84,79.87 R700.1 41.22,79.87 40.06,81.03 39.83,81.03 ; 45.14,82.07 44.98,82.23 44.98,88.67 45.02,88.71 45.02,91.58 R668.1 ; 45.14,82.07 45.17,82.09 v2(46.79,82.09) 49.51,82.09 v1(49.56,82.14) ; 34.22,83.44 v1(33.82,83.44) ; 34.22,83.44 34.72,83.44 36.88,81.28 37.63,81.28 37.88,81.03 ; R759.2 154.88,38.61 156.14,38.61 156.75,39.22 156.75,41.01 L25.1 156.89,41.76 C489.1 156.88,42.43 C488.1 156.88,44.22 156.29,44.81 155.33,44.81 v1(155.28,44.86) 155.18,44.86 155.14,44.82 C486.1 ; C486.1 153.23,44.82 C487.2 153.1,44.75 152.05,43.71 152.05,42.79 152.08,42.77 v1(152.08,42.42) ; PR208.1 29.58,184.21 28.88,184.9 28.34,184.9 v1(27.89,185.36) 28.12,185.36 28.61,185.85 PR206.1 ; U33.3 37.37,80.44 37.88,80.95 37.88,81.03 ; L23.1 31.21,78.28 30.67,77.74 R701.1 30.26,78.82 v1(30.18,78.89) ; 39.83,81.03 37.88,81.03 ; 39.83,81.03 39.91,81.1 U33.8 39.91,85.79 R687.1 ; C343.1 C344.2 128.68,129.59 v1(128.58,129.69) ; R535.1 97.6,212.82 v1(97.72,212.7)
  BOTTOM w0.635: v5(109.09,116.24) 109.52,115.8 109.52,114.83 110.27,114.08 110.27,111.2 110.92,110.56 110.92,83.88 v2(110.85,83.82) 110.85,82.07 v5(111.11,81.81) ; R525.2 134,219.75 v1(135.29,219.75) ; L19.1 35.66,105.52 v1(35.36,105.23) ; v5(47.12,127.91) 47.12,123.62 46.04,122.53 42.78,122.53 40.72,124.59 37.81,124.59 v1(33.32,129.08)
  BOTTOM w1.016: v1(137.34,208.18) 154.25,208.18 v1(155.69,206.74) F3.1 155.69,202.07 R570.1 155.87,200.87 154.42,199.42 v5(154.42,198.58)
  BOTTOM w1.27: v5(153.49,192.01) v5(154.74,190.76) 156.73,188.77 156.73,186.01 158.06,184.68 158.06,181.52 159.77,179.81 159.77,153.72 159.09,153.03 159.09,144.93
  vias: v2(119.26,16.76) v5(107.86,53.31) v5(108.47,55.17) v5(108.54,54.1) v5(108.54,52.32) v5(120.78,16.27)
VCC3_CAM: length 4
  TOP w0.635: v5(160.68,201.66) 162,200.34 WEBCM1.3
  vias: v2(159.66,203.37)
VCC3_CT2: length 4.5
  TOP w0.102: v1(108.22,56.48) 108.14,56.48 107.85,56.78 U15.10
  BOTTOM w0.102: C478.1 106.85,56.48 v2(107.04,56.29) 108.03,56.29 v1(108.22,56.48)
VCC3_EN: length 6.7
  TOP w0.102: U15.5 102.62,56.78 102.44,56.6 v4(102.07,56.6) 101.98,56.69 101.16,56.69 R381.1 101.13,56.65 101.13,56.31 101.02,56.21 99.83,56.21 99.38,55.75 98.39,55.75 C150.1
VCC5_PANEL:
  vias: v1(43.7,107.98) v1(43.67,107.29) v2(42.91,112.67)
VCC_1P24_A1_R: length 3.8
  TOP w0.305: CPU1.AM28 85.9,163.46 v3(86.26,163.82)
  BOTTOM w0.381: v3(86.26,163.82) 86.62,164.18 C308.1 87.46,164.49 v2(87.54,164.41) 87.54,163.25 R594.2
VCC_CT1: length 4.3
  TOP w0.102: v1(108.36,57.36) 108.14,57.58 U15.12
  BOTTOM w0.102: C475.1 107.73,58.19 v2(107.81,58.12) 108.36,57.56 v1(108.36,57.36)
VCC_EN: length 4.3
  TOP w0.102: U15.3 103.39,57.58 103.29,57.68 102.58,57.68 102.17,58.09 v4(102.14,58.09) 102.14,58.12 101.43,58.83 C144.1 R379.1
VCC_FAN_PWR: length 4.7
  TOP w0.635: 14,211.09 FANC3.2 ; FANC3.2 14,213.45 ; FANC3.2 15.18,212.27 ; FANC3.2 12.82,212.27
VCCGI_SENSE: length 54.9
  TOP w0.254: CPU1.R41 78.57,169.17 v1(78.15,168.74)
  L3 w0.254: v1(78.15,168.74) 78.15,168.91 77.74,169.32 77.74,169.34 76.59,170.49 76.59,174.36 76.17,174.79 72.82,174.79 71.83,175.78 71.83,176.81 69.04,179.6 69.04,198.98 67.42,200.61 57.55,200.61 55.7,202.46 55.5,202.46 v1(55.29,202.25)
  BOTTOM w0.254: PG15.1 v1(55.29,202.25) 55.22,202.18 RN15.4 56.11,201.39 v2(56.32,201.6)
VSSGI_SENSE: length 55.9
  TOP w0.254: v3(78.24,169.7) 78.57,170.02 CPU1.R43
  L3 w0.254: v3(78.24,169.7) 78.1,169.7 77.1,170.7 77.1,174.57 76.38,175.3 73.03,175.3 72.34,175.99 72.34,177.03 69.55,179.81 69.55,199.19 67.63,201.12 57.76,201.12 55.91,202.97 55.01,202.97 v1(54.28,202.24)
  BOTTOM w0.254: RN15.3 54.57,201.94 v1(54.28,202.24) PG16.1 53.29,203.18 53.28,203.17 v2(53.16,203.17)
1D05V_FHV0: length 0.5
  TOP w0.254: CPU1.T13 78.37,156.63 v3(78.34,156.63)
  vias: v2(76,151.08) v2(76.58,154.8)
1D05V_FHV1: length 0.5
  TOP w0.254: CPU1.T15 78.38,157.36 v3(78.38,157.37)
  vias: v2(72.12,155.06)
1D05V_FUSE: length 0.5
  TOP w0.254: v3(77.57,156.94) 77.58,156.94 CPU1.P16
  vias: v2(73.69,154.86)
1D05V_IO_3PHASEIO: length 4.3
  TOP w0.305: CPU1.V18 v3(80.47,159.09) ; v3(80.47,159.09) CPU1.Y20 v3(81.19,159.88) CPU1.AA22 v3(81.92,160.67) ; v3(80.47,159.09) CPU1.Y18 ; CPU1.AA23 v3(81.92,160.67) ; v3(81.92,160.67) CPU1.AC23
  vias: v2(79.38,156.95) v2(79.65,146.68)
1D05V_PCH:
  vias: v2(70.12,160.43) v2(77.98,160.19) v3(79.74,161.46) v3(79.74,159.88) v3(80.47,161.46) v3(81.19,161.46)
1D05V_S0: length 62.3
  TOP w0.381: v1(68.11,216.28) 67.89,216.07 v4(67.89,214.66) PC9.1 67.87,209.77 67.87,208.73 67.37,208.23 v1(66.33,208.23)
  TOP w0.508: v1(54.69,160.66) 54.04,160.66 53.06,161.64 R169.1 PR56.1
  L4 w0.381: v1(66.33,208.23) 65.39,207.29 65.39,204.72 61.09,200.43 61.09,186.69 56.85,182.45 56.07,182.45 53.54,179.92 51.61,179.92 51.24,180.29 51.24,180.72 50.46,181.51 50.1,181.51 49.73,181.87 48.89,181.87 48.53,181.51 48.52,181.51 47.28,180.26 v5(47.28,176.66)
  BOTTOM w0.381: v1(66.33,208.23) 66.33,208.69 66.11,208.9 PR195.1 ; PR189.1 68.36,215.2 68.11,215.46 v1(68.11,216.28)
  vias: v5(46.52,177.29) v5(46.52,176.02) v5(47.28,175.39)
1D8V_EMMC: length 39.5
  TOP w0.127: U1.P5 U1.N4 U1.P3
  TOP w0.203: v1(96.45,220.51) 96.16,220.21 U1.P3 ; U1.P5 95.16,220.23 v1(94.87,220.52)
  TOP w0.254: U1.C6 94.66,214.37 94.33,214.71 94.32,214.71 94.04,214.71 93.94,214.8 93.89,214.8 v3(93.88,214.82) ; U1.N4 U1.M4
  TOP w0.508: v1(87.75,212.94) 87.81,213 87.81,216.12 84.86,219.08 Q5.G 84.86,220.36 84.85,220.36 84.85,220.64 84.26,221.23 R11.1
  L3 w0.508: v3(93.88,214.82) 93.82,214.82 93.17,214.17 88.98,214.17 v1(87.75,212.94)
  BOTTOM w0.508: v1(87.75,212.94) 87.75,211.15 v2(88.53,210.37) 90.08,208.82 R554.2 R553.2 R552.2 92.6,207.45 93.49,206.57 R551.2 R550.2 R549.2 96.39,206.57 97.28,207.45 R548.2 97.89,207.45 98.78,206.57 R547.2 100.29,206.57 R557.2
1D8V_EMMC_CT1: length 2.7
  BOTTOM w0.102: U29.12 99.47,222.5 C237.1 v2(99.44,223.51)
1D8V_EMMC_EN: length 8.5
  BOTTOM w0.102: R518.2 110.12,224.61 v2(109.88,224.85) 109.87,224.86 109.5,224.86 108.21,223.57 106.36,223.57 C236.1 104.61,223.08 104.03,222.5 U29.3
1D8V_PCH: length 10
  TOP w0.305: CPU1.AG25 v3(84.09,162.24)
  L4 w0.305: v3(82.64,170.12) 83.13,169.62 83.13,169.01 82.87,168.75 82.87,163.49 84.09,162.27 v3(84.09,162.24)
  BOTTOM w0.381: C313.1 v3(84.09,162.24)
  vias: v2(80.98,192.16) v2(83.23,186.02) v3(81.91,170.91) v3(82.64,170.91)
1D8V_S0: length 300.2
  TOP w0.508: v1(168.82,134.9) 168.82,134.67 168.26,134.12 168.26,132.26 166.43,130.42 R196.2
  TOP w0.635: v1(140.66,23.89) 140.77,23.78 R474.2
  L3 w0.635: v5(168.25,88.72) 169.64,90.12 169.64,101.48 170.49,102.34 170.49,111.67 168.8,113.36 168.8,134.66 168.82,134.67 v1(168.82,134.9) ; v5(164.88,71.75) 164.63,71.75 152.38,59.51 152.38,52.48 153.09,51.77 v1(153.37,51.77) 152.38,50.77 152.38,48.79 152.05,48.46 152.05,44.51 152.94,43.62 152.94,42.79 152.97,42.76 152.97,42.02 152.26,41.31 152.26,40 148.01,35.76 v1(148.01,33.96)
  L4 w0.635: v1(140.66,23.89) 141,24.23 141,26.02 148.01,33.03 v1(148.01,33.96) ; v5(168.25,88.72) 168.25,86.56 164.19,82.5 164.19,72.45 v5(164.88,71.75) ; v1(93.52,224.06) 96.34,226.87 133.89,226.87 138.86,221.9 148.78,221.9 v5(148.85,221.97) 153.59,221.97 167.19,208.37 167.19,158.18 168.82,156.55 v1(168.82,134.9)
  BOTTOM w0.508: R809.1 155.65,49.97 155.04,50.58 155.04,51.34 154.32,52.06 153.79,52.06 153.7,51.97 153.65,51.97 153.45,51.77 v1(153.37,51.77)
  BOTTOM w0.635: R519.1 93.85,223.88 93.67,224.06 v1(93.52,224.06)
  vias: v4(149.81,222.31)
1D8V_S0_EN: length 9.5
  TOP w0.254: Q6.2 153.97,209.55 154.17,209.75 154.17,210.39 v4(153.04,211.53) 152.36,212.2 C10.1 153.82,212.76 155.3,211.28 R52.1
1D8V_S0_EN1: length 7.4
  TOP w0.254: v4(154.16,207.53) 154.08,207.45 R57.1 152.34,208.15 151.16,208.15 151.03,208.29 Q6.6 151.61,208.9 151.72,209.01 151.72,209.37 151.54,209.55 Q6.5 150.27,209.55 150.21,209.62 R53.2
1D8V_S0_EN2: length 6.4
  TOP w0.254: Q6.3 152.43,210.2 151.29,211.34 v4(151.29,211.58) 150.53,211.58 149.98,212.13 R44.1 ; R41.1 149.73,212.14 R44.1 ; R44.1 149.79,212.08 149.79,211.11 R50.2
1D8V_S0_EN_G: length 11
  TOP w0.254: R41.2 149.13,213.41 149.13,217.12 149.51,217.5 150.61,217.5 v4(151.11,218) 150.2,218.91 C6.1 C5.1 148.7,219.02 Q3.G
1D8V_S0_EN_R: length 12.2
  TOP w0.102: PR17.2 156.37,209.55 R52.2 155.3,207.34 153.96,205.99 v4(150.2,205.99) 148.36,205.99 PR27.2 148.15,204.65 PR28.2
1D8V_S5: length 965.4
  TOP w0.203: RN39.1 26.52,16.26 26.1,16.26 26.06,16.22 26.05,16.22 25.99,16.16 25.99,16.16 25.99,16.15 25.99,15.75 26.09,15.65 RN39.2
  TOP w0.254: v3(42.17,26.42) 42.88,25.7 42.88,22.73 41.05,20.9 38.01,20.9 37.22,21.69 33.72,21.69 33.49,21.92 32.63,21.92 32.4,22.15 31.42,22.15 30.92,21.65 30.92,20.73 30.9,20.63 30.89,20.63 30.89,20.38 30.87,20.26 30.42,19.81 29.64,19.81 28.35,18.53 28.35,18.34 27.26,17.25 27.26,16.96 RN39.1 ; R212.1 88.06,123.08 v1(87.33,123.81)
  TOP w0.305: RN8.1 53.58,174.95 v5(53.21,174.57) 53.48,174.3 RN8.2 ; RN22.2 87.82,115.08 88.17,114.73 88.17,114.43 88.17,114.43 RN22.1 87.11,114.3 87.07,114.3 86.61,113.85 85.81,113.85 85.68,113.97 85.6,113.97 85.28,114.3 85,114.3 84.93,114.36 R241.2 R240.2 ; v1(24.91,207.85) 24.88,207.85 24.53,207.49 XDP1.12 ; 59.62,180.55 59.61,180.54 RN7.1 ; R133.2 58.71,179.13 RN7.2 59.61,178.68 59.85,178.44 60.54,178.44 61.3,177.67 R137.1 ; 31.07,204.52 30.84,204.52 30.36,204.99 XDP1.1
  TOP w0.381: R200.2 159.77,132.25 159.77,134.82 159.4,135.2 159.4,158.07 160.24,158.92 R2001.1 160.69,159.51 160.31,159.89 160.31,165.58 156.98,168.91 152.46,168.91 150.81,167.26 147.93,167.26 JMP1.5 ; R3.2 35.05,222.6 v1(35.05,221.92) ; v1(142.22,48.94) Q9201.G 139.99,49.64 v4(139.99,50.29) 141.59,51.89 141.59,52.19 141.6,52.2 141.6,53.22 141.59,53.24 141.59,53.64 140.71,54.52 Q9202.G 140.71,55.41 141.23,55.93 v4(141.64,55.93) ; R106.1 73.78,186.28 73.77,186.27 72.65,186.27 R104.1 R103.1 70.43,186.28 R105.1 69.26,186.26 R102.1 68.01,186.28 R101.1 64.45,186.31 59.62,181.48 59.62,180.55 58.29,180.55 58.01,180.28 ; v1(60.45,174.22) 59.61,173.38 R149.1 ; 153.96,184.83 156.57,182.22 R125.1 157.69,182.03 R124.1
  TOP w0.508: v1(149.59,204.44) 149.59,204.24 150.58,203.25 150.58,188.93 153.96,185.54 153.96,184.83 151.54,184.83 150.63,183.92 148.75,183.92 v1(148.39,184.28) 147.86,184.82 R109.2 ; R177.1 R179.2 57.79,149.05 56.73,149.05 ; R51.1 34.12,209.46 34.23,209.35 v1(34.23,209.31) ; R159.2 61.8,172.09 R157.1 ; R166.2 56.91,168.81 59.07,170.96 R162.1 59.95,171.21 62.57,171.21 R160.1 R157.1 ; v5(106.5,224.21) 106.84,224.55 R1.1 ; R133.2 58.01,180.28 57.58,180.71 v5(51.91,180.71) 51.91,180.09 51.66,179.83 R131.2 PR42.1 ; 56.73,151.16 56.71,151.14 R1701.1 ; v5(50.91,157.84) 50.85,157.78 R173.1 ; R147.1 61.95,173.35 61.11,174.19 60.47,174.19 v1(60.45,174.22) ; R147.1 R157.1 ; R147.1 R144.1 ; v1(112.07,58) 112.05,57.97 111.68,57.97 110.05,56.34 110.05,52.71 107.21,49.87 104.1,49.87 102.09,47.85 97.06,47.85 93.94,44.73 85.86,44.73 84.51,43.39 84.51,42.8 85.64,41.68 86.16,41.68 88.07,39.77 v1(88.07,32.69) ; v1(92.87,121.34) 92.88,121.32 94.34,121.32 96.21,119.46 R222.1 96.16,119.02 95.68,119.02 93.33,116.67 Q23.G 92.72,116.67 92.01,115.96 92.01,114.73 91.24,113.97 88.63,113.97 88.17,114.43
  TOP w0.762: v5(56.66,144.59) 56.66,146.55 56.22,146.99 56.22,148.54 56.73,149.05 56.73,152.24 51.15,157.81 50.93,157.81 v5(50.91,157.84)
  TOP w1.016: v5(37.8,222.8) 37.8,222.99 39.82,225.01 76.78,225.01 v5(77.72,224.06) ; Q3.D 139.43,220.04 138.34,218.95 v5(138.28,218.95)
  L3 w0.381: 139.94,17.58 139.94,17.98 137.73,20.19 137.73,22.83 141.71,26.82 141.71,48.43 v1(142.22,48.94)
  L3 w0.508: 42.13,30.53 46.18,34.57 68.61,34.57 v1(69.38,33.81) ; 42.13,30.53 42.13,26.45 v3(42.17,26.42) ; 42.13,30.53 42.13,30.57 41.46,31.24 39.15,31.24 38.18,30.28 38.18,25.32 37.02,24.16 26.93,24.16 24.67,26.42 v1(23.3,26.42) ; v1(152.9,45.81) 155.67,45.81 156.23,45.25 156.23,41.49 155.2,40.46 155.2,40.13 153.68,38.61 153.65,38.61 152.55,37.5 152.55,35.95 150.07,33.48 150.07,29.75 146.26,25.94 146.26,23.9 139.94,17.58 139.94,9.91 139.07,9.04 137.88,9.04 136.53,10.39 133.81,10.39 132.01,8.59 105.29,8.59 103.82,10.06 103.82,18.03 89.16,32.69 v1(88.07,32.69) ; v1(149.59,204.44) 145.47,208.56 143.63,208.56 143.35,208.84 143.23,208.84 139.51,212.56 139.51,217.71 v5(138.28,218.95) ; JMP1.5 147.84,169.57 147.84,174.88 148.88,175.92 148.88,183.8 v1(148.39,184.28) ; v5(53.21,174.57) 58.08,174.57 58.38,174.87 59.8,174.87 v1(60.45,174.22)
  L3 w0.762: v5(110.58,119.62) 109.98,119.02 107.36,119.02 104.54,121.83 95.3,121.83 94.8,121.34 v1(92.87,121.34) 89.8,121.34 v1(87.33,123.81) 86.66,123.81 85,122.15 80.7,122.15 79.81,123.04 79.81,124.87 72.93,131.75 68.82,131.75 67.6,132.97 60.36,132.97 58.26,135.07 58.26,135.17 58.25,135.18 58.25,141.55 56.75,143.05 56.75,144.5 v5(56.66,144.59) ; v5(77.72,224.06) 78.63,223.16 94.38,223.16 95.04,223.82 106.11,223.82 v5(106.5,224.21) 106.67,224.21 108.35,222.54 112.7,222.54 117.12,218.12 128.41,218.12 129.19,218.91 138.23,218.91 v5(138.28,218.95) ; v5(51.91,180.71) 52,180.62 58.78,180.62 66.3,188.14 66.3,197.05 v5(67.6,198.35)
  L4 w0.508: v3(101.53,78.24) 101.53,71.94 110.15,63.33 110.15,59.92 v1(112.07,58) ; v1(69.38,33.81) 76.21,33.81 77.32,32.69 v1(88.07,32.69)
  L4 w0.635: v5(106.5,224.21) 106.5,212.46 107.19,211.77 v1(107.19,211.64)
  L4 w0.762: v5(50.91,157.84) 50.91,169.71 49.16,171.45 49.16,173.17 48.27,174.07 46.55,174.07 45.65,174.96 45.65,181.04 47.45,182.84 47.45,183.08 v5(47.48,183.11)
  BOTTOM w0.254: R5502.1 119.79,67.77 119.49,67.46 113.04,67.46 112.35,66.78 112.35,61.72
  BOTTOM w0.305: v1(85.3,187.05) 85.3,187.25 83.68,188.87 83.68,192.43 81.03,195.07 R572.2 ; RN21.2 105.5,211.4 105.52,211.37 105.52,211.35 105.61,211.26 105.64,211.26 105.7,211.2 106.75,211.2 v1(107.19,211.64) 106.95,211.87 RN21.1 ; RN24.1 23.6,26.72 v1(23.3,26.42) 22.95,26.77 RN24.2
  BOTTOM w0.508: 24.45,203.77 24.45,202.7 24.84,202.31 24.91,202.24 26.97,202.24 28.74,200.47 ; R780.1 23.68,26.04 v1(23.3,26.42) ; v1(24.91,207.85) 24.42,208.33 R543.1 24.41,208.79 C251.1 23.39,210.42 R540.1 ; R546.1 30.15,207.21 30.56,206.8 32.21,206.8 ; R726.1 122.15,62.81 113.44,62.81 111.87,61.24 111.87,58.2 v1(112.07,58) ; v5(110.58,119.62) 110.58,115.12 111.23,114.48 111.23,111.83 111.92,111.13 v2(111.92,85.38) 111.92,81.58 111.25,80.91 104.72,80.91 102.05,78.24 101.7,78.24 v3(101.53,78.24) ; R749.1 154.13,46.99 152.96,45.81 v1(152.9,45.81) ; R788.1 42.04,26.54 v3(42.17,26.42) ; v5(77.72,224.06) 77.72,223.47 77.67,223.42 77.67,220.38 78.71,219.33 R524.1
  BOTTOM w0.762: v5(67.6,198.35) 69.53,196.42 74.48,196.42 75.14,195.76 79.99,195.76 R572.2
  vias: v5(29.88,200.89) v5(29.88,199.77) v5(29.88,198.75)
1D8V_S5_D: length 2.5
  BOTTOM w0.305: R524.2 80.01,219.36 Q47.6
  BOTTOM w0.508: v2(80.7,218.62) R524.2
1D8V_SPI: length 31.5
  TOP w0.254: 87.91,127.57 87.8,127.57 87.26,127.03 87.26,126.42 R209.1 87.99,125.47 v1(87.33,124.82) 87.74,124.41 C57.2 88.2,124.23 89.03,123.4 R212.2 ; 87.91,127.57 R204.1 ; 87.91,127.57 86.82,128.66 86.82,130.18 87.13,130.49 97.1,130.49 SRCON1.8 100.12,130.39 99.3,131.22 99.3,132.4 R194.1
  BOTTOM w0.254: v1(87.33,124.82) 87.59,125.07 v2(87.59,125.73)
1D24_35V_S5:
  vias: v2(98.26,157.05) v2(98.61,148.67)
1D24V_AUD_ISH_PLL: length 2
  TOP w0.305: CPU1.AK22 CPU1.AJ22 CPU1.AJ20 v3(84.81,159.09)
  vias: v2(89.52,156.06)
1D24V_DSI_CSI: length 21.6
  TOP w0.305: CPU1.AA18 81.86,159.01 81.86,159.04 v3(81.91,159.09) 81.86,159.15 81.86,159.18 CPU1.AA20
  L4 w0.381: v1(88.29,149.56) 87.67,149.56 86.8,150.42 83.98,150.42 83.11,151.29 83.11,155.02 82.75,155.37 82.75,158.32 81.98,159.09 v3(81.91,159.09)
  BOTTOM w0.381: C327.1 81.66,159.09 v3(81.91,159.09)
  BOTTOM w0.508: v2(90.82,145.86) R615.2 90.46,147.29 PC171.1 88.71,147.95 C340.1 88.71,149.14 v1(88.29,149.56)
1D24V_GLML: length 24.2
  TOP w0.305: v3(86.26,159.88) CPU1.AM20 CPU1.AK20 ; CPU1.AM37 v3(86.26,166.97)
  L3 w0.508: v3(86.26,159.88) 86.42,159.72 88.47,159.72 88.71,159.95 89.49,159.95 90,159.44 v3(90,159.35)
  L4 w0.508: v3(86.26,159.88) 86.26,160.42 87,161.16 87,164.11 85.66,165.46 85.66,166.45 86.01,166.8 86.09,166.8 v3(86.26,166.97)
  BOTTOM w0.381: R594.1 86.5,160.69 C319.1 86.06,160.08 v3(86.26,159.88) ; C300.1 86.34,167.05 v3(86.26,166.97)
  BOTTOM w0.508: v2(89.57,160.3) 89.86,160.01 89.86,159.49 v3(90,159.35) 90.01,159.37 C325.1 92.6,159.37 PC161.1 94.64,157.33 R596.2
1D24V_MPHY: length 2.7
  TOP w0.305: CPU1.AG22 v3(83.36,159.88) ; v3(83.36,159.88) CPU1.AE22 ; v3(83.36,159.88) CPU1.AE20 v3(83.36,159.09) CPU1.AE18
  vias: v2(86.65,153.62)
1D24V_S5: length 91.9
  TOP w1.27: v5(98.82,138.46) v5(98.82,137.2) 98.82,137.04 95.48,133.69 70.2,133.69 68.83,135.06 68.83,139.91 68.79,139.95 68.79,142.61 65.31,146.09 65.31,147.6 54.54,158.37 53.58,158.37 52.71,159.23
  BOTTOM w0.508: R588.1 32.09,168.03 32.09,160.18 32.71,159.57 v2(43.92,159.57) 48.44,159.57 48.8,159.21 v5(48.98,159.21)
1D24V_S5_D: length 2.6
  BOTTOM w0.305: Q52.6 29.8,169.4 R588.2 29.81,168.43 29.73,168.34 v2(29.73,168.29)
1D24V_USB2: length 0.5
  TOP w0.305: CPU1.AG20 v3(84.09,159.09)
  vias: v2(88.46,154.62)
1D35V_S3_PWRGD: length 97.4
  TOP w0.203: PU5.10 152.66,132.33 152.86,132.13
  TOP w0.254: U14.101 127.85,67.82 128.23,68.2 v1(128.23,68.71) ; 152.86,132.13 153.39,131.61 v1(153.39,131.32) 154.35,130.37 PR86.2 ; v1(141.26,119.13) 140.94,119.45 R221.1
  L3 w0.254: v1(121.83,77.14) 122.41,76.56 124.39,76.56 125.18,77.34 130.74,77.34 132.16,78.77 133.69,78.77 136.25,81.32 136.25,83.48 137.43,84.67 137.43,85.1 137.43,85.46 144.14,92.17 144.14,105.02 143.94,105.22 143.94,106.24 142.12,108.05 142.12,108.08 141.99,108.2 141.99,109.73 142.49,110.22 142.49,117.23 141.26,118.46 v1(141.26,119.13) v1(141.26,123.16)
  L4 w0.254: v1(128.23,68.71) 128.61,69.09 128.61,69.7 122.03,76.28 122.03,76.94 v1(121.83,77.14)
  BOTTOM w0.254: v1(153.39,131.32) 153.39,130.06 v2(153,129.68) 152.33,129.01 148.9,129.01 143.74,123.85 141.95,123.85 v1(141.26,123.16)
1P05V_PG: length 245
  TOP w0.102: v1(34.06,183.03) 34.06,182.57 v4(33.71,182.22) 33.64,182.22 33.5,182.36 PR39.2 32.42,182.35 PC29.1 31.17,182.12 31.17,179.98 30.72,179.53 PU2.4 ; v1(125.13,46.15) 125.13,46.15 126.3,46.15 126.91,46.76 R403.2
  L3 w0.127: v1(125.13,46.15) 124.92,45.94 112.59,45.94 111.47,47.07 98.94,47.07 94.27,51.74 94.27,65.07 84.88,74.46 53.75,74.46 53.42,74.79 50.26,74.79 49.27,75.78 48.84,75.78 48.83,75.77 46.03,75.77 43.77,78.03 42.98,78.03 41.37,79.64 41.37,79.69 41.33,79.73 41.33,107.43 40.88,107.89 40.88,116.71 38.13,119.46 38.13,131.29 35.92,133.5 35.92,135.18 31.99,139.12 23.81,139.12 19.67,143.26 19.67,167.92 19.31,168.28 v1(19.08,168.28)
  L4 w0.127: v1(19.08,168.28) 21.48,170.68 21.48,179.79 23.4,181.71 32.74,181.71 v1(34.06,183.03)
1P05V_PG_EC: length 3.1
  TOP w0.102: U14.57 126.65,50.25 v4(127.26,49.63) 126.91,49.28 R403.1
1P05V_S5_D: length 2.5
  BOTTOM w0.305: Q46.3 84.48,223.89 v2(84.34,224.03) 84.56,224.26 R514.2
3D3V_AUX_KBC: length 86.8
  TOP w0.305: R737.2 134.26,59.03 134.44,59.22 134.45,59.22 v1(134.45,59.22) 134.45,59.39 133.78,60.06 R373.2 ; v1(127.92,59.23) 128.28,59.23 129.11,60.06 129.2,60.06 v1(129.59,60.45) ; R2403.2 119.84,71.58 v1(120.81,72.54)
  L4 w0.305: 125.69,67.77 132.65,67.77 134.91,70.02 134.91,72.98 133.54,74.35 131.54,74.35 130.51,75.37 v3(130.51,75.46) ; 125.69,67.77 125.69,66.95 128.51,64.14 128.51,62.51 129.59,61.43 v1(129.59,60.45) ; 125.69,67.77 123.22,67.77 121.47,69.52 121.47,71.81 120.81,72.47 v1(120.81,72.54)
  BOTTOM w0.305: v1(129.59,60.45) 129.68,60.36 130.65,60.36 131.09,60.81 R730.1 131.33,60.71 131.33,59.68 131.92,59.09 132.36,59.09 132.58,59.31 134.36,59.31 v1(134.45,59.22) 134.03,58.8 133.61,58.8 133.28,58.47 133.28,56.51 133.77,56.02 v2(133.77,55.8) 134.3,55.28 134.34,55.28 134.35,55.27 134.81,55.27 134.81,55.28 135.14,55.28 135.69,55.83 v1(135.8,55.83) ; R713.2 120.81,72.29 v1(120.81,72.54) ; Q63.D 134.64,75.3 133.97,74.63 133.59,74.63 R708.1 133.54,75.63 133.14,76.03 130.78,76.03 130.51,75.77 v3(130.51,75.46) ; R736.2 115.01,58.01 RN40.3 116.78,56.74 116.89,56.63 116.89,56.21 116.78,56.09 RN40.4 116.15,55.96 116.15,54.29 116.51,53.92 124.02,53.92 R742.2 125.05,54.93 R745.1 125.9,53.91 127.55,55.55 R739.1 127.92,57.4 127.92,58.12 128.1,58.3 128.1,59.03 127.92,59.21 v1(127.92,59.23)
3D3V_AUX_S5_MUX: length 3.3
  TOP w0.305: U2.10 79.51,127.18 78.6,126.26 v4(78.06,126.26) 77.3,127.03 R208.1
3D3V_EMMC: length 18.5
  TOP w0.254: v3(95.67,215.57) 95.64,215.57 95.39,215.82 U1.F5 95.1,215.82 94.66,215.37 U1.E6
  TOP w0.305: U1.J10 92.71,217.26 93.05,217.26 93.15,217.16 v3(93.2,217.16) 93.16,217.2 U1.K9
  L3 w0.305: v3(95.67,215.57) 95.67,216.75 95.04,217.38 95.04,217.47 94.73,217.78 93.81,217.78 v3(93.2,217.16)
  BOTTOM w0.305: v3(93.2,217.16) 92.85,217.51 92.85,218.32 92.63,218.54 C243.1
  BOTTOM w0.508: R535.2 96.66,214.53 C245.1 ; 100.85,218.98 99.35,217.48 99.35,216.64 v2(99.17,216.46) 99.07,216.36 C245.1 ; C245.1 96.46,216.36 v3(95.67,215.57)
3D3V_EMMC_CT2: length 2.8
  BOTTOM w0.102: v2(99.44,220.55) 99.45,220.55 C239.1 99.59,221.7 U29.10
3D3V_EMMC_EN: length 7.7
  BOTTOM w0.102: R521.2 109.73,222.41 108.18,222.41 v2(108.01,222.23) 107.3,221.52 106.48,221.52 105.88,222.12 C238.1 105.53,221.78 104.23,221.78 104.15,221.7 U29.5
3D3V_USB: length 13.9
  TOP w0.254: v3(85.53,162.25) CPU1.AK25 85.04,161.99 84.58,161.99 CPU1.AJ25
  L4 w0.254: v3(81.19,170.12) 82.17,169.14 82.17,169.14 82.46,168.85 82.46,162.45 83.2,161.7 84.34,161.7 84.79,162.16 85.45,162.16 v3(85.53,162.25)
  BOTTOM w0.254: C312.1 v3(85.53,162.25)
  vias: v2(77,181.48) v2(79.38,172.42) v3(80.47,170.91)
3D3V_VCCRTC: length 0.5
  TOP w0.254: CPU1.AA44 v3(81.19,170.91)
  vias: v2(79.86,189.85) v2(80.31,181.65)
3D3VDD_TPM: length 33.6
  TOP w0.305: U7.22 v1(135.92,111.47) ; U7.8 128.47,108.97 C78.1 ; U7.14 133.14,106.73 C82.1
  TOP w0.508: C82.1 v1(134.07,106.73) ; R251.1 C75.1 137.86,110.72 137.51,111.07 137.13,111.07 C74.1 v1(135.92,111.47) ; C78.1 v1(128.16,107.82) ; R237.1 125.44,115.5 125.09,115.16 v1(125.09,113.97)
  L3 w0.508: v1(125.09,113.97) 125.34,113.73 125.34,110.64 v1(128.16,107.82) 132.75,107.82 133.84,106.73 v1(134.07,106.73) 135.21,106.73 135.92,107.44 v1(135.92,111.47)
  BOTTOM w0.305: v1(135.92,111.47) v2(135.02,111.47)
1117_ADJ: length 5.4
  BOTTOM w0.254: U36.1 124.21,21.07 124.63,20.65 126.02,20.65 v2(126.21,20.46) 126.21,19.88 R796.1 124.24,19.18 R795.2
+3D3V_PWR: length 0.5
  TOP w0.305: PG7.2 93.78,49.73
  vias: v2(94.86,52.64) v5(85.12,51.82) v5(86.19,51.82) v5(87.16,51.84) v5(95.61,53.14) v5(95.64,52.22) v5(95.67,54.09)
+V_1P05_VGA: length 19.2
  TOP w0.356: GPU1.AA16 81.36,105.36 v3(81.28,105.28)
  TOP w0.381: v1(82.76,115.39) 82.76,117.22 84.56,119.02 84.56,119.75 R217.2
  BOTTOM w0.508: L21.1 96.97,102.27 96.97,100.19 96.16,99.38 L22.1 ; C381.1 77.52,105.11 77.52,104.39 77,103.87 C389.1 ; C380.1 80.56,105.28 v3(81.28,105.28) 81.32,105.32 C379.1 84.8,105.32 v3(84.84,105.28) v3(85.5,105.28)
  BOTTOM w0.762: L21.1 96.12,103.9 v5(95.63,104.39)
  vias: v3(75.95,107.03) v3(76.78,107.06) v3(76.84,105.3) v3(77.6,106.24) v3(78.44,106.24) v4(72.22,114.35) v5(73.49,114.17) v5(74.07,113.36) v5(94.73,111.15) v5(94.9,113) v5(101.35,112.06) v5(101.35,110.92) v5(102.42,112.06) v5(102.42,110.92)
+V_1P05_VGA_DISCHIG: length 2.9
  TOP w0.102: Q13.6 84.65,121.98 84.89,122.22 v4(85.02,122.22) 85.02,121.09 R217.1
+V_1P35_VGA: length 90.5
  TOP w0.178: v3(53.21,110.2) 53.2,110.2 v3(53.2,111) ; VRAM2.H2 58,87.44 v3(58,86.64)
  TOP w0.203: VRAM2.B2 58.81,82.63 VRAM2.A1 ; GPU1.H26 73.28,95.04 73.7,95.46 73.73,95.46 74.3,95.46 v3(74.3,95.45) ; v3(74.31,97.94) 74.1,97.94 74.1,97.94 74.07,97.94 73.64,97.94 73.32,97.61 73.22,97.61 73.13,97.52 GPU1.L26 72.99,97.41 71.82,97.41 71.73,97.32 v3(71.68,97.32)
  TOP w0.229: v3(71.59,95.04) 71.72,95.17 72.97,95.17 73.1,95.04 GPU1.H26
  TOP w0.254: VRAM2.A1 59.2,81.48 v3(59.14,81.42) ; VRAM1.C9 59.2,115.39 59.72,114.88
  TOP w0.279: v3(71.4,92.69) 71.68,92.41 72.71,92.41 72.85,92.55 GPU1.E26
  TOP w0.305: GPU1.L22 76.71,97.89 v3(76.81,97.89) 77.14,98.22 GPU1.M21 ; VRAM1.G7 v3(58,111.8) ; VRAM1.D9 v3(59.6,114.2) VRAM1.E9 ; VRAM1.H2 v3(53.2,111)
  TOP w0.356: GPU1.C25 GPU1.B26 73.06,90.1 72.54,89.58 71.51,89.58 70.89,90.19 v3(70.89,90.27) ; v3(53.44,117.75) 53.32,117.75 52.8,117.23 VRAM1.A1 VRAM1.B2 VRAM1.C1 ; v3(74.31,97.94) 74.32,97.92 74.7,97.54 GPU1.L24 ; GPU1.H24 74.66,95.04 74.32,95.38 74.32,95.43 v3(74.3,95.45) ; VRAM1.F1 51.59,113 51.56,112.97 ; v3(54,86.64) 54.4,87.04 VRAM2.G7 ; v3(61.16,86.74) 61.15,86.74 60.58,86.17 59.27,86.17 VRAM2.F1 ; v3(59.6,91.44) 59.2,91.84 VRAM2.N1 ; GPU1.E23 75.72,92.38 75.72,92.38 75.95,92.15 v3(75.95,92.13) ; VRAM2.K2 58,89.04 v3(58,89.04) ; VRAM1.R9 59.6,106.2 ; v3(60.06,110.11) 59.68,110.49 59.68,110.92 VRAM1.H9 ; v3(52.4,93.03) 52.8,93.43 VRAM2.R9 ; VRAM1.K8 58.41,109.8 v3(58.81,110.2) ; VRAM1.C1 52.25,115.4 52.21,115.36 51.54,115.36 ; VRAM1.C1 52.8,115.4 v3(53.21,115) 53.6,114.6 VRAM1.D2 ; v3(58.8,88.24) 58.4,87.84 VRAM2.H2 ; VRAM1.N9 59.21,107.4 59.68,106.93 ; v3(59.76,83.84) 59.75,83.84 VRAM2.C1 VRAM2.D2 ; v3(59.69,93.17) 59.42,93.44 VRAM2.R1 ; VRAM2.N9 52.56,91.84 v3(52.29,91.57) ; v3(53.2,89.04) 53.6,89.44 VRAM2.K8 ; v3(53.21,110.2) 53.21,110.19 53.59,109.8 VRAM1.K2 ; VRAM2.A8 53.6,82.03 52.97,81.4 v1(52.83,81.4) ; v3(58.79,116.6) 58.69,116.7 58.69,116.71 VRAM1.A8
  TOP w0.508: 69.68,118.87 72.5,118.87 73.59,119.96 73.59,120.09 74.92,121.42 R215.2 ; v3(52.29,91.57) 51.82,92.05 51,92.05 ; 51.28,93.04 51.28,93.03 v3(52.4,93.03)
  L3 w0.305: v3(54,86.64) 53.96,86.64 53.42,87.17 53.41,87.17 53.35,87.23 52.94,87.23 52.55,87.62 51.69,87.62 v3(51.61,87.55)
  L3 w0.508: v3(58,89.04) 58.02,89.05 58.8,89.05 ; 58.8,89.05 58.83,89.05 58.83,89.05 59.67,89.05 59.96,89.34 v1(59.96,89.38) ; 58.8,89.05 v3(58.8,88.24)
  L4 w0.254: v3(53.2,111) 53.19,111.01 53.19,111.81 53.98,112.6 v3(54.01,112.6)
  L4 w0.508: v3(60.06,110.11) 59.98,110.2 ; 59.98,110.2 v3(58.81,110.2) ; 59.98,110.2 59.68,110.49 59.68,111.01 59.03,111.66 58.14,111.66 v3(58,111.8)
  BOTTOM w0.178: v1(52.06,89.03) 52.07,89.04 v3(53.2,89.04) ; VRAM4.H2 53.19,88.25 52.41,88.25 52.32,88.34
  BOTTOM w0.203: 77.1,90.18 77.1,91.29 R671.2
  BOTTOM w0.305: R645.1 60.11,110.16 v3(60.06,110.11) ; 59.82,115.18 59.82,114.42 v3(59.6,114.2) ; VRAM1.R9 59.64,106.24 60.27,106.24 ; v3(58,89.04) 58,89.04 VRAM2.K2 ; VRAM3.G7 54.01,112.59 v3(54.01,112.6) ; VRAM1.C9 VRAM3.D2 ; VRAM3.F1 59.25,113 v3(59.69,112.55) ; VRAM1.N9 59.21,107.4 59.4,107.2 60.28,107.2 ; VRAM3.H2 v3(58,111.8)
  BOTTOM w0.356: VRAM4.A8 58.4,82.03 59.01,81.42 v3(59.14,81.42) ; VRAM1.K8 58.41,109.8 v3(58.81,110.2) ; 60.71,116.84 60.29,117.25 59.45,117.25 59.2,117 VRAM3.A1 59.19,117 v3(58.79,116.6) 58.4,116.21 VRAM3.B2 ; VRAM4.H9 58.8,88.24 v3(58.8,88.24) ; VRAM2.K8 53.6,89.44 v3(53.2,89.04) ; v3(53.44,117.75) 53.44,117.52 53.6,117.37 VRAM3.A8 ; 59.82,115.18 59.6,115.4 VRAM1.C9 ; VRAM2.R1 59.42,93.44 v3(59.69,93.17) ; VRAM2.N1 59.2,91.84 v3(59.6,91.44) ; v3(58,86.64) 57.6,87.04 VRAM4.G7
  BOTTOM w0.508: v3(75.95,92.13) 76.26,92.13 R671.2 ; v1(49.56,111.2) 48.74,110.38 R646.1
  vias: v1(50.48,105.84) v1(51.49,106.86) v1(52.06,105.8) v1(64.57,103.76) v1(65.33,116.33) v1(65.92,115.84) v1(78.29,96.65) v1(78.42,95.48) v1(79.84,94.72) v1(80.58,94.41) v2(60.1,121.48) v3(49.84,117.55) v3(50.1,114.86) v3(50.88,118.41) v3(50.91,116.74) v3(51.45,114.05) v3(51.88,86.29) v3(51.92,83.77) v3(60.16,85.01) v3(67.51,97.3) v3(77.53,102.11) v4(69.55,116.94) v5(47.58,144.48) v5(48.01,145.29) v5(48.52,144.48) v5(49.13,145.31) v5(49.72,144.53) v5(50.27,145.31) v5(50.83,144.53) v5(51.42,145.31) v5(51.98,144.55) v5(52.59,145.34) v5(52.81,139.09) v5(52.84,138.13) v5(53.78,125.45) v5(53.88,139.12) v5(53.98,138.15) v5(54.8,125.48) v5(54.97,139.09) v5(55.18,138.15) v5(55.91,125.5) v5(55.98,139.11) v5(56.34,138.18) v5(57.02,139.1) v5(57.06,125.48) v5(57.39,138.2) v5(58.2,125.48) v5(59.22,125.48) v5(60.23,125.5) v5(61.25,125.5) v5(79.02,79.75) v5(79.88,80.51)
+V_1P35_VGA_DISCHG: length 5.5
  TOP w0.102: Q12.6 79.84,122 78.52,123.31 v4(77.96,123.31) 76.15,123.31 75.6,122.76 R215.1
+V_3P3_VGA: length 215
  TOP w0.254: v3(87.53,106.26) 87.14,105.86 GPU1.AA9 ; PR100.1 123.54,89.55 123.96,89.97 124.95,89.97 125.36,89.56 125.36,88.75 v1(125.33,88.72) ; GPU1.AA8 87.96,105.84 v3(88.35,106.23) 87.96,106.61 GPU1.AB8
  TOP w0.305: 96.96,80.75 97.24,80.75 98.79,79.2 100.24,79.2 100.74,79.71 Q28.2 Q28.5 ; PR63.1 31.99,156.57 31.43,157.12 30.21,157.12 29.62,156.54 v1(29.62,156.26) 29.65,156.24 29.65,155.36 PR64.1 ; U5.5 98.57,115.28 99.02,114.83 v1(99.96,114.83)
  TOP w0.508: v1(104.16,116.62) 101.16,116.62 100.42,115.88 R232.2 99.96,115.87 v1(99.96,114.83) ; v1(127.85,85.84) 127.85,86.03 128.45,86.63 PR105.1 ; PR123.2 132.71,79.46 v1(132.75,79.5) ; v1(89.27,115.44) Q22.G 89.27,117.62 87.68,119.21 v1(87.66,119.21) ; R290.2 R288.2 98.69,91.06 98.92,91.29 v1(98.97,91.29) ; v1(118.14,113.92) 118.14,114.05 119.03,114.94 120.46,114.94 120.94,114.45 121.1,114.45 PR88.1 ; v5(102.59,98.89) 102.45,98.75 102.45,97.86 102.16,97.56 R278.2
  L3 w0.305: v1(56.31,130.46) 43.16,130.46 41.16,132.46 41.15,132.46 37.93,135.68 37.93,136.04 33.33,140.64 33.32,140.64 32.76,141.2 24.59,141.2 21.84,143.95 21.84,154.34 24.06,156.57 29.32,156.57 v1(29.62,156.26)
  L3 w0.508: v1(89.27,115.44) 89.27,114.9 89.72,114.45 89.72,110.29 89.21,109.78 89.21,106.98 88.45,106.23 v3(88.35,106.23) ; v1(118.14,113.92) 116.42,113.92 115.63,114.71 108.85,114.71 108.39,115.16 107.38,115.16 105.92,116.62 v1(104.16,116.62) ; v1(115.32,85.51) 119.17,85.51 122.38,88.72 v1(125.33,88.72)
  L4 w0.508: v1(56.31,130.46) 57.03,129.73 64.31,129.73 65.74,128.31 70.08,128.31 73.12,125.27 73.12,123.09 77.94,118.26 86.71,118.26 v1(87.66,119.21) ; v1(100.41,89.66) 98.97,91.1 v1(98.97,91.29) ; v1(89.27,115.44) 90.06,114.66 92.14,114.66 92.98,115.49 94.72,115.49 95.38,114.83 v1(99.96,114.83)
  BOTTOM w0.508: 90.94,85.09 89.97,86.06 U32.8 ; 90.94,85.09 91.7,84.33 92.54,84.33 v1(92.72,84.15) 93.35,83.52 U32.3 94.85,83.52 95.24,83.12 R696.1 95.72,83.12 R697.1 96.99,82.86 96.99,82.12 v1(96.98,82.11) ; 90.94,85.09 90.63,84.79 U32.7 ; v1(132.75,79.5) 130.39,81.86 130.21,81.86 127.85,84.23 v1(127.85,85.84) 127.85,86.33 127.19,87 126.7,87 125.45,88.24 125.33,88.24 v1(125.33,88.72)
  vias: v1(100.21,86.64) v2(93.99,106.05) v5(103.61,98.9)
+V_VGA_CORE: length 39.1
  TOP w0.381: v1(79.36,115.95) 79.36,116.83 R223.2
  TOP w0.635: PT3.1 109,100.06 ; PT3.1 110.05,99.01 ; PT3.1 107.94,99.01 ; PT3.1 109,97.95 ; PT5.1 109,92.19 ; PT5.1 110.05,91.14 ; PT5.1 107.94,91.14 ; PT5.1 109,90.08
  L3 w0.381: 80.09,105.28 80.09,115.21 v1(79.36,115.95)
  L3 w0.635: 109,90.08 PT5.1 ; PT5.1 110.05,91.14 ; PT5.1 107.94,91.14 ; PT5.1 109,92.19 ; PT3.1 109,100.06 ; PT3.1 109,97.95 ; PT3.1 110.05,99.01 ; PT3.1 107.94,99.01
  L4 w0.635: 109,90.08 PT5.1 ; PT5.1 109,92.19 ; PT5.1 107.94,91.14 ; PT5.1 110.05,91.14 ; 107.94,99.01 PT3.1 ; PT3.1 109,97.95 ; PT3.1 110.05,99.01 ; PT3.1 109,100.06
  vias: v2(81.41,98.37) v3(78.52,104.4) v3(79.55,102.51) v3(79.51,100.53) v3(79.53,99.44) v3(79.48,97.54) v3(80.63,104.5) v3(81.51,97.46) v3(82.53,102.49) v3(82.48,100.51) v3(82.53,98.53) v3(82.61,104.47) v3(83.52,97.46) v3(84.56,104.49) v3(85.53,104.5) v3(85.48,102.47) v3(85.53,101.5) v3(85.5,99.47) v3(85.5,97.46) v3(85.48,95.43) v3(87.53,104.36) v3(87.56,102.62) v3(87.59,101.9) v3(87.59,101.17) v3(87.63,97.96) v3(87.64,97.16) v3(88.25,101.83) v3(88.26,103.63) v3(88.27,101.15) v3(88.31,97.97) v3(88.35,97.16) v4(116.24,103.28) v5(108.34,89.08) v5(108.43,96.6) v5(108.43,95.56) v5(108.59,105.03) v5(108.59,103.99) v5(108.56,102.95) v5(109.33,89.05) v5(109.42,96.57) v5(109.42,95.53) v5(109.55,102.92) v5(109.58,105) v5(109.58,103.96) v5(115.3,102.16) v5(115.27,100.56) v5(115.27,92.61) v5(115.27,91.69) v5(116.29,102.13) v5(116.26,100.53) v5(116.26,92.58) v5(116.26,91.67)
AC_IN: length 37.7
  TOP w0.102: v1(47.21,37.93) 47.28,38 PQ13.2 ; v1(55.61,63.53) 56.09,63.53 56.32,63.3 PR156.2 56.15,62.69 PQ12.D
  L4 w0.127: v1(55.61,63.53) 55.54,63.59 54.85,63.59 54.75,63.69 51.73,63.69 51.35,63.31 51.35,62.15 51.77,61.73 51.97,61.73 52.73,60.98 52.73,53.33 47.21,47.82 v1(47.21,37.93)
  BOTTOM w0.102: v1(55.61,63.53) v2(56.45,63.53)
AC_IN_KBC#: length 119.1
  TOP w0.102: v1(126.5,53.64) 126.6,53.64 126.76,53.81 129.33,53.81 130.2,52.93 U14.65 131.38,52.93 132.82,51.49 135.47,51.49 R393.1 ; v3(70.7,43.32) 70.71,43.32 71.03,43.64 71.03,44.83 70.4,45.46 Q36.6 68.81,46.48 66.17,46.48 63.48,49.17 57.28,49.17 54.87,51.58 54.87,52.63 53.53,53.97 53.53,60.89 53.73,61.09 53.73,64.77 53.28,65.22 PQ10.G
  L4 w0.127: v1(126.5,53.64) 125.9,53.05 125.9,52.15 126.18,51.87 126.18,45.54 124.65,44 124.65,42.43 121.63,39.41 114.56,39.41 113.78,40.19 108.74,40.19 107.65,39.1 102.71,39.1 102.48,39.33 96.73,39.33 94.8,41.26 94.8,42.83 93.73,43.89 86.62,43.89 85.4,43.89 85.16,44.13 71.48,44.13 70.9,43.55 70.9,43.52 v3(70.7,43.32)
  BOTTOM w0.102: v1(126.5,53.64) 126.74,53.88 v2(127.37,53.88)
AC_IN_KBC#_R: length 2.9
  TOP w0.102: PQ10.D 54.26,68.05 53.44,68.87 PR140.2 52.51,69.09 v4(52.41,69.19)
AC_OK#: length 113.3
  TOP w0.102: PQ12.G 52.38,63.67 v1(51.93,63.22)
  L4 w0.127: v1(51.93,63.22) 51.61,62.9 51.61,62.26 51.88,61.98 52.08,61.98 55.04,59.02 55.04,54.18 64.5,44.72 85.41,44.72 85.65,44.48 86.38,44.48 93.98,44.48 95.38,43.07 95.38,41.5 96.01,40.88 99.37,40.88 99.88,41.39 101.52,41.39 103.23,39.69 104.74,39.69 106.71,41.66 115.71,41.66 117.37,39.99 120.33,39.99 121.74,41.4 122.12,41.4 124.06,43.34 124.06,44.37 125.6,45.91 125.6,51.63 125.32,51.91 125.32,54.41 v1(126.02,55.11)
  BOTTOM w0.102: v1(51.93,63.22) 51.53,63.22 PR225.2 50.68,61.88 50.77,61.79 v2(50.77,61.06) 50.3,61.06 49.42,60.18 U34.5 ; v1(126.02,55.11) 125.3,55.83 R742.1 123.97,56.9 R738.1
AC_PRESENT_CPU: length 256.1
  TOP w0.102: v3(98.12,203.35) 98.12,203.29 98.64,202.77 98.64,200.18 96.4,197.94 92.54,197.94 88.88,194.28 88.88,192.91 88.63,192.66 87.89,192.66 87.69,192.46 RN4.3 87.69,190.38 v3(87.46,190.14) ; R394.2 135.87,50.01 137.57,50.01 139.1,51.54 139.1,56.08 140.47,57.45 141.85,57.45 153.02,68.62 153.02,126.59 v1(152.64,126.97) ; CPU1.AK49 85.37,173.04 85.37,173.05 85.71,173.38 v3(85.83,173.38)
  L3 w0.127: v1(152.64,126.97) 152.64,127.4 155.56,130.32 155.56,132.59 159.25,136.28 159.25,141.65 160.31,142.71 160.31,150.69 159.53,151.47 159.53,172.66 155.89,176.3 153.45,176.3 v1(152.81,176.94) ; v3(87.46,190.14) 87.87,189.74 87.87,189.15 86.33,187.61 86.33,186.13 85.69,185.49 84.94,185.49 84.68,185.22 84.68,184.02 85.64,183.06 85.64,176.31 86.26,175.68 86.26,173.7 85.95,173.38 v3(85.83,173.38)
  BOTTOM w0.102: v1(152.81,176.94) 152.76,176.89 151.26,176.89 v2(151.11,177.04) 151.14,177.06 151.14,180.8 147.1,184.83 147.1,189 138.62,197.49 114.26,197.49 113.55,198.2 108.95,198.2 106.92,200.23 101.96,200.23 98.92,203.28 98.75,203.28 98.67,203.35 v3(98.12,203.35)
AC_PRESENT_KBC: length 12.2
  TOP w0.102: U14.52 124.65,52.1 125.71,53.16 127.17,53.16 127.59,53.58 129.23,53.58 132.21,50.6 v4(133.08,50.6) 134.14,50.6 R394.1
AC_PROTECT: length 8.5
  TOP w0.102: PR153.1 47.94,64.17 47.32,64.79 v1(47.32,64.8)
  BOTTOM w0.102: PR218.1 46.75,65.68 47.32,65.11 v1(47.32,64.8) 47.32,63.7 R727.1 47.74,63.27 PR226.2 47.74,61.52 v2(48.23,61.03) 48.42,60.84 U34.3
AC_PROTECT_R: length 8.6
  BOTTOM w0.102: R727.2 48.64,64.45 PQ17.G 48.48,64.65 49.28,65.45 49.28,67.78 C465.1 v2(50.57,67.86) 50.72,67.86 51.85,66.73 PR220.2
AD+_2: length 12.9
  TOP w0.635: PC125.2 65.87,29 PR179.1 65.75,28.87 PR180.2 ; PC125.2 66.08,30.83 66.08,32.43 v4(66.18,32.53) 66.4,32.75 66.4,32.81 66.45,32.86 66.45,33.9 67.24,34.68 67.24,35.23 67.37,35.36 PU12.4 ; PC125.2 68.27,30.62 PQ15.C
AD+_G_1: length 7.9
  TOP w0.254: PQ13.6 46.63,42.28 v4(46.77,42.42) 47.28,41.91 PQ13.5 47.28,40.47 47.47,40.27 50.22,40.27 PR176.2
AD+_G_2: length 6.3
  TOP w0.254: 52.01,41.17 52.06,41.22 PR174.2 ; 52.01,41.17 v3(53.37,41.17) 53.97,40.58 55.2,40.58 PU11.4 ; 52.01,41.17 PR176.1
  BOTTOM w0.254: v3(53.37,41.17) v2(53.37,40.39)
AD+_TO_SYS: length 2.3
  TOP w0.254: PR173.1 53.3,45.51 PG8.1
  vias: v2(55.94,42.95) v2(57.26,37.74) v4(55.1,46.41) v5(54.48,44.91) v5(54.45,43.99) v5(54.45,43.1) v5(54.48,42.24) v5(54.48,41.38) v5(57.45,45.34) v5(57.49,44.48) v5(57.54,43.59) v5(57.54,42.7) v5(57.54,41.78) v5(57.54,40.87)
AD_IA: length 116
  TOP w0.254: v4(54.72,59.48) 54.73,59.49 54.73,60.06 54.92,60.25 54.96,60.25 55.07,60.36 v1(55.08,60.36) ; R350.1 132.03,68.88 130.06,66.91 130.06,66.26 129.59,65.8 129.12,65.8 128.44,65.12 128.44,63.22 125.99,60.77 125.99,60.32 126.09,60.22 v1(126.09,58.97)
  L4 w0.254: v1(55.08,60.36) 55.08,60.27 55.49,59.86 55.49,54.36 64.68,45.16 85.59,45.16 85.83,44.92 86.2,44.92 94.16,44.92 94.42,44.66 95.83,43.25 95.83,42.4 95.83,41.69 96.19,41.33 99.19,41.33 99.7,41.84 101.71,41.84 103.41,40.13 104.56,40.13 106.53,42.1 115.9,42.1 117.56,40.44 120.15,40.44 121.56,41.85 121.94,41.85 123.48,43.39 123.48,44.61 123.94,45.07 123.94,50.92 124.67,51.66 124.67,57 125.74,58.06 125.74,58.55 126.09,58.9 v1(126.09,58.97)
  BOTTOM w0.254: PR227.2 54.74,60.71 v1(55.08,60.36)
AD_IA_HW1: length 94.2
  TOP w0.203: 125,50.12 125.45,50.58 U14.54
  TOP w0.254: 125,50.12 124.72,50.12 123.48,48.89 123.48,47.4 122.09,46.01 111.45,46.01 v1(110.72,45.29) ; PQ8.5 51.5,67.92 v1(52.18,67.24)
  L4 w0.254: v1(52.18,67.24) 52.9,66.52 54.93,66.52 57.42,64.03 57.42,63.31 59.9,60.84 59.9,56.74 60.42,56.22 60.42,52.39 64.6,48.21 86.85,48.21 87.08,47.98 107.3,47.98 109.99,45.29 v1(110.72,45.29)
  BOTTOM w0.254: v2(52.16,68.06) 52.16,68.02 52.18,68 v1(52.18,67.24)
AD_IA_HW2: length 104.2
  TOP w0.203: U14.55 125.85,50.44 125.79,50.38
  TOP w0.254: 125.79,50.38 125.1,49.68 124.87,49.68 123.99,48.8 123.99,47.19 122.3,45.5 111.75,45.5 v1(110.78,44.53) ; v1(45.88,68.33) 45.91,68.3 v4(46.87,68.3) 47.56,68.3 47.94,67.92 PQ8.2
  L4 w0.254: v1(110.78,44.53) 110.6,44.7 109.84,44.7 107.07,47.47 87.29,47.47 86.87,47.47 86.64,47.7 64.39,47.7 64.22,47.87 64.18,47.87 59.91,52.13 59.91,52.18 59.91,52.18 59.91,52.6 59.91,55.79 58.73,56.97 58.73,60.22 56.85,62.1 56.85,63.88 54.81,65.93 52.6,65.93 51.16,67.37 49.11,67.37 47.68,65.94 46.68,65.94 45.88,66.73 v1(45.88,68.33)
AD_IA_R: length 8.7
  TOP w0.102: U14.97 129.45,67.49 R350.2 131.14,69.39 131.39,69.64 132.31,69.64 132.57,69.38 133.77,69.38 R352.1 133.88,69.49 133.88,70.42 C136.1 134.59,70.55 134.93,70.21 v4(134.93,69.9)
AD_JK: length 28
  TOP w0.635: 51.79,23.36 DCIN1.1 ; DCIN1.1 53.36,24.43 ; DCIN1.1 51.79,25.5 ; PQ15.E 70.22,30.54 PR178.1 67.93,33.69 v3(68.18,33.93) 68.4,34.15 R439.1
  L3 w0.635: 50.23,24.43 DCIN1.1 ; DCIN1.1 51.79,23.36 ; DCIN1.1 53.36,24.43 ; DCIN1.1 51.79,25.5
  L4 w0.635: DCIN1.1 53.36,24.43 ; DCIN1.1 51.79,25.5 ; DCIN1.1 51.79,23.36 ; DCIN1.1 50.23,24.43 ; v3(68.18,33.93) 67.84,33.93 67.84,33.93 v3(65.72,33.93)
  BOTTOM w0.635: DCIN1.1 53.36,24.43 ; DCIN1.1 51.79,25.5 ; DCIN1.1 51.79,23.36 ; DCIN1.1 50.23,24.43
  vias: v2(54.52,32.89) v2(58.2,32.77) v2(59.11,22.12) v2(61.32,32.89) v2(62.64,28.07) v2(62.64,24.46) v4(62.32,31.96) v5(50.53,22.83) v5(54.16,23.95) v5(54.19,22.91) v5(55.43,23.98) v5(55.51,22.83) v5(56.65,22.78) v5(56.7,23.98) v5(59.22,30.86) v5(59.22,29.84) v5(59.22,28.83) v5(59.6,27.86) v5(60.23,29.84) v5(60.23,28.83) v5(60.26,30.91) v5(60.69,27.86) v5(61.37,30.86) v5(61.37,29.84) v5(61.37,28.83)
AD_JK1: length 12.7
  TOP w0.102: Q36.2 66.7,44.81 R413.1 66.58,43.81 v4(66.67,43.73) 67.1,43.73 68.03,42.8 68.03,36.22 69.29,34.96 R439.2
AD_OFF_L: length 9.3
  TOP w0.102: PQ15.B 71.69,30.12 71.69,31.14 71.46,31.37 71.46,33.83 v1(70.67,34.62) 70.65,34.65 70.65,35.26 69.89,36.01 PQ14.C
  BOTTOM w0.102: v1(70.67,34.62) 70.26,35.03 v2(69.96,35.03)
ADAPTOR_PSID_R: length 4.8
  TOP w0.508: 43.47,19.46 v4(43.45,19.46) ; 43.47,19.46 43.47,19.62 44.18,20.33 44.18,21.27 R476.1 ; 43.47,19.46 44.71,18.22 Q41.S
ADAPTOR_PSID_R_R: length 15.7
  TOP w0.102: R445.2 R444.1 44.47,33.01 43.98,32.51 43.98,30.06 D5.3 44.44,28.99 45.55,27.89 45.55,26.67 45.35,26.47 44.87,26.47 43.34,24.94 43.34,22.7 v4(43.54,22.5) 43.56,22.52 R476.2
ADAPTOR_PSID_SIO: length 125.4
  TOP w0.102: R444.2 44.62,32.12 v3(44.43,31.93) ; U14.99 128.65,66.01 127.69,65.05 127.69,64.69 124.98,61.97 124.98,61.01 125.45,60.54 v1(125.46,60.54)
  L4 w0.127: v1(125.46,60.54) 126.19,59.8 126.28,59.8 127.4,58.68 127.4,51.85 126.98,51.44 126.98,45.39 125.41,43.82 125.41,42.47 121.84,38.9 113.63,38.9 112.85,39.68 109.34,39.68 105.98,36.32 105.98,31.99 103.99,30.01 100.22,30.01 99.12,28.91 97.26,28.91 95.05,31.13 85.29,31.13 85.1,31.32 72.65,31.32 70.93,33.04 65.29,33.04 62.28,36.06 46.85,36.06 44.43,33.63 v3(44.43,31.93)
  BOTTOM w0.102: v3(44.43,31.93) 44.2,31.7 v2(43.54,31.7)
ALERT#: length 5.8
  TOP w0.102: R328.2 143.31,78.28 v4(143.52,78.49) 143.52,79.38 144.43,80.29 145.86,80.29 146.26,80.69 U12.6
ALL_PWRGD_2: length 5.9
  TOP w0.102: Q26.D 107.48,82.68 107.16,82.36 107.16,81.58 R317.1 107.11,81.53 106.21,81.53 v4(106.15,81.58) 106.15,81.33 106.81,80.67 R320.1
AMD_RST#_L: length 24.8
  TOP w0.102: R272.1 100.98,104.37 D3.2 100.24,105.11 100.24,106.17 v1(99.98,106.43) 99.66,106.74 R265.2 ; v1(92.64,114.1) 94.51,114.1 R239.2 95.69,115.28 U5.4 96.89,114.62 97.45,114.06 R248.2
  L3 w0.127: v1(92.64,114.1) 92.81,113.93 94.81,113.93 96.54,112.21 96.54,109.87 v1(99.98,106.43)
  BOTTOM w0.102: v1(99.98,106.43) v2(100.85,106.43)
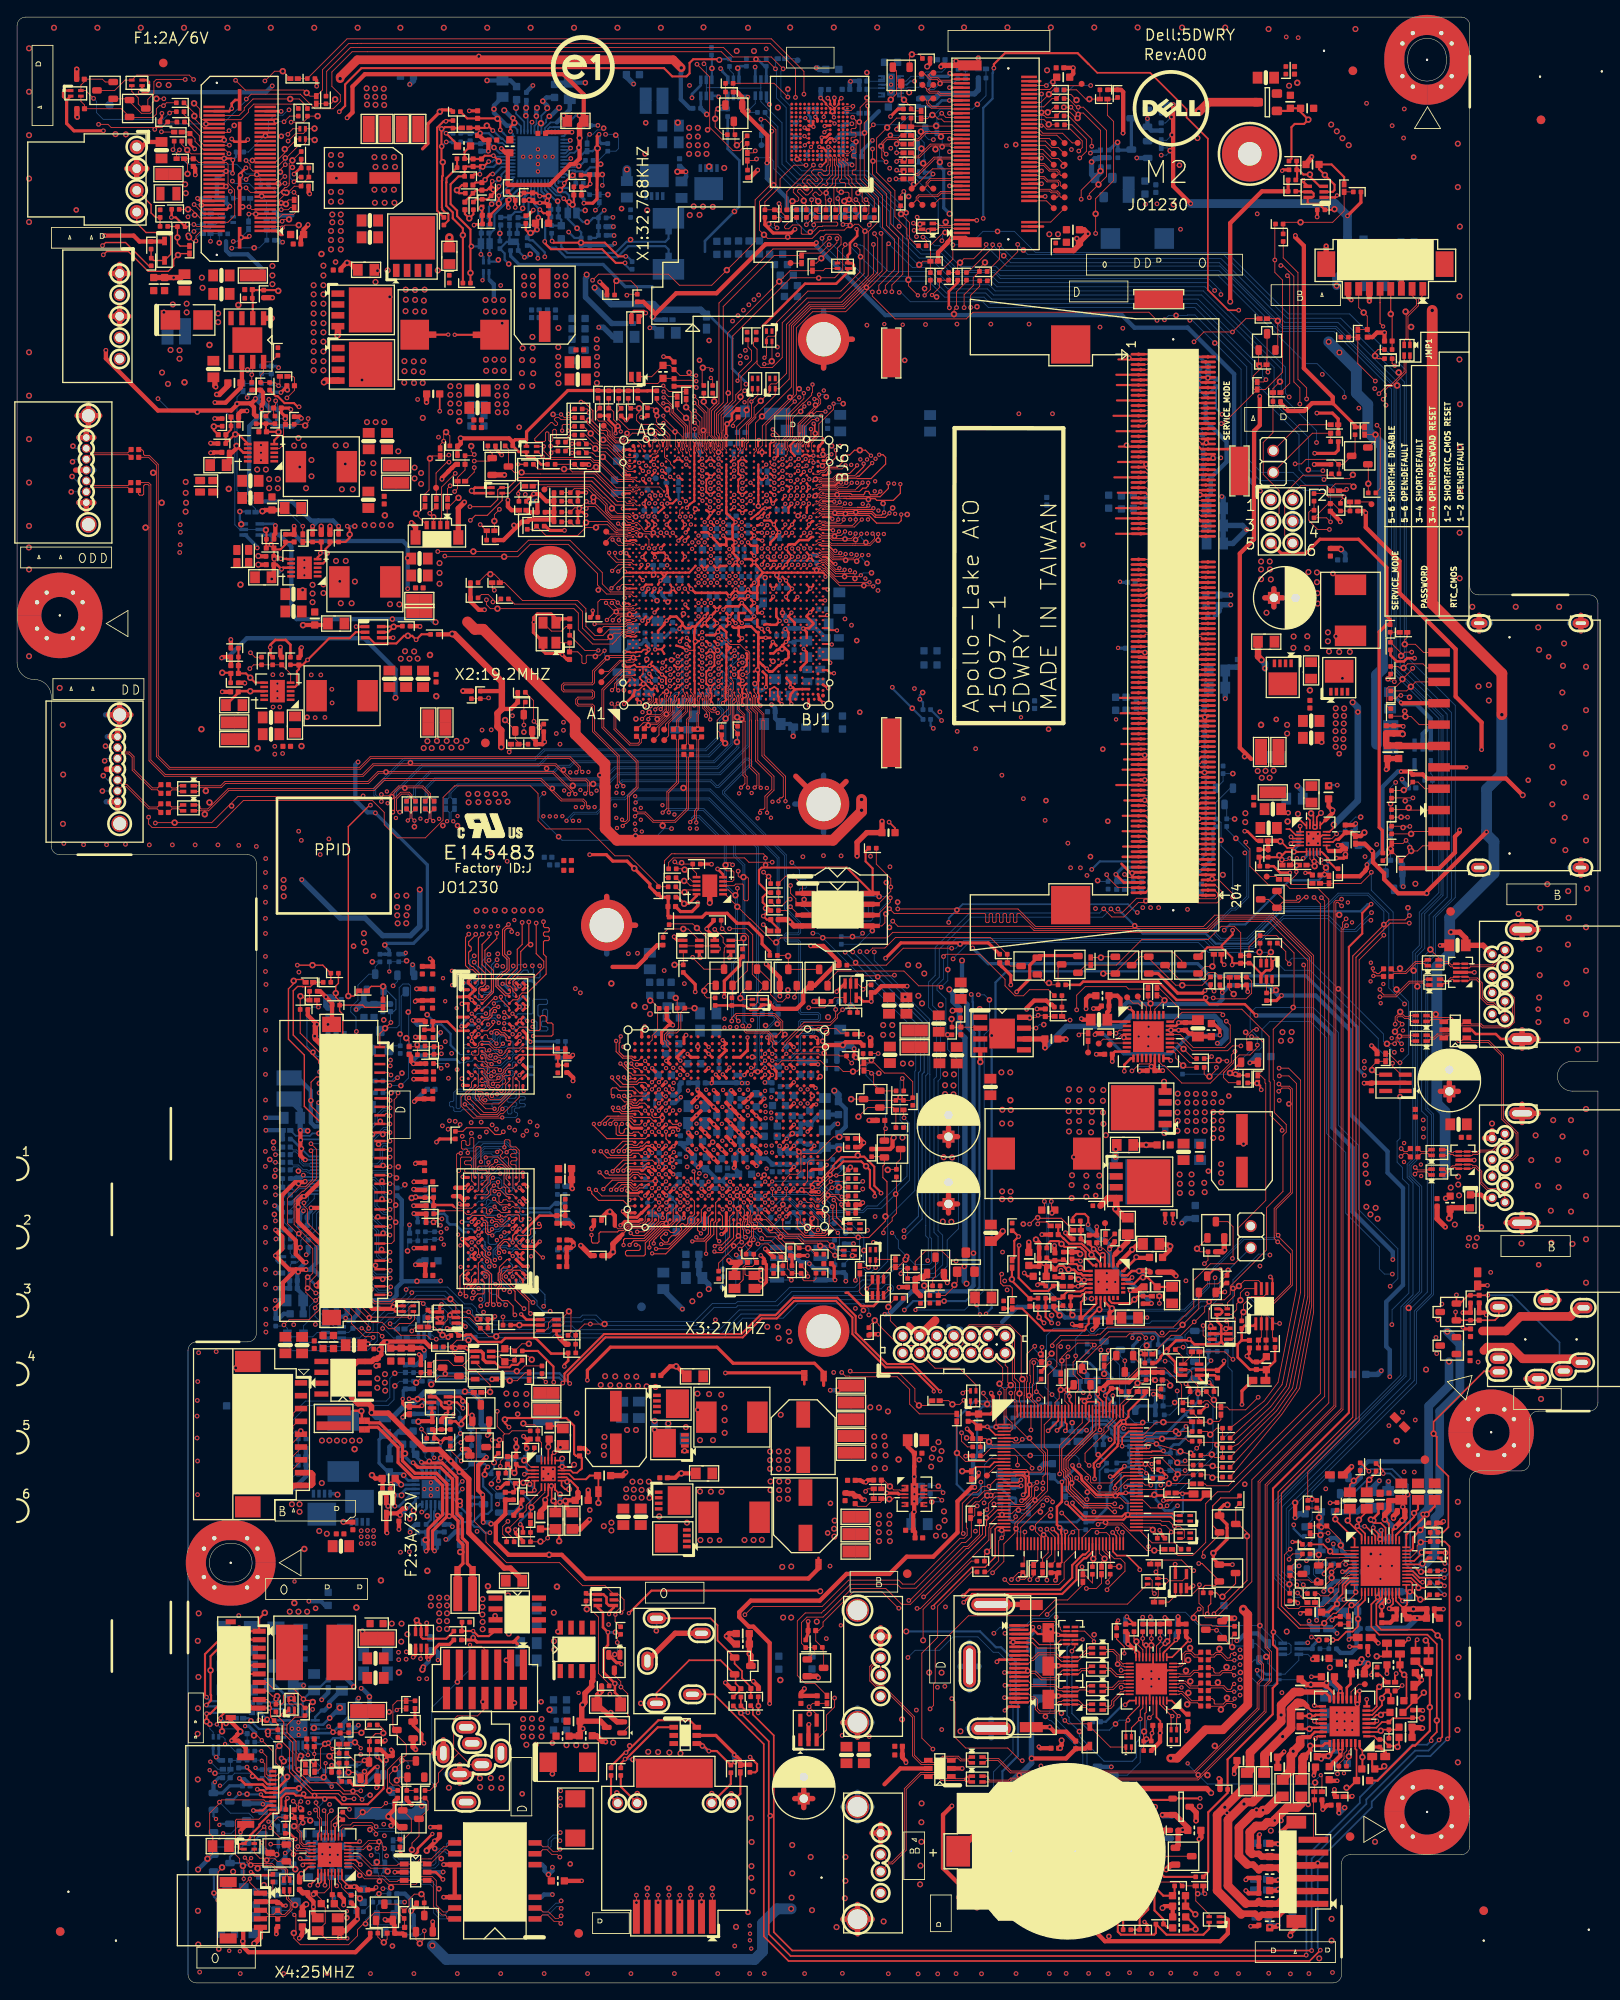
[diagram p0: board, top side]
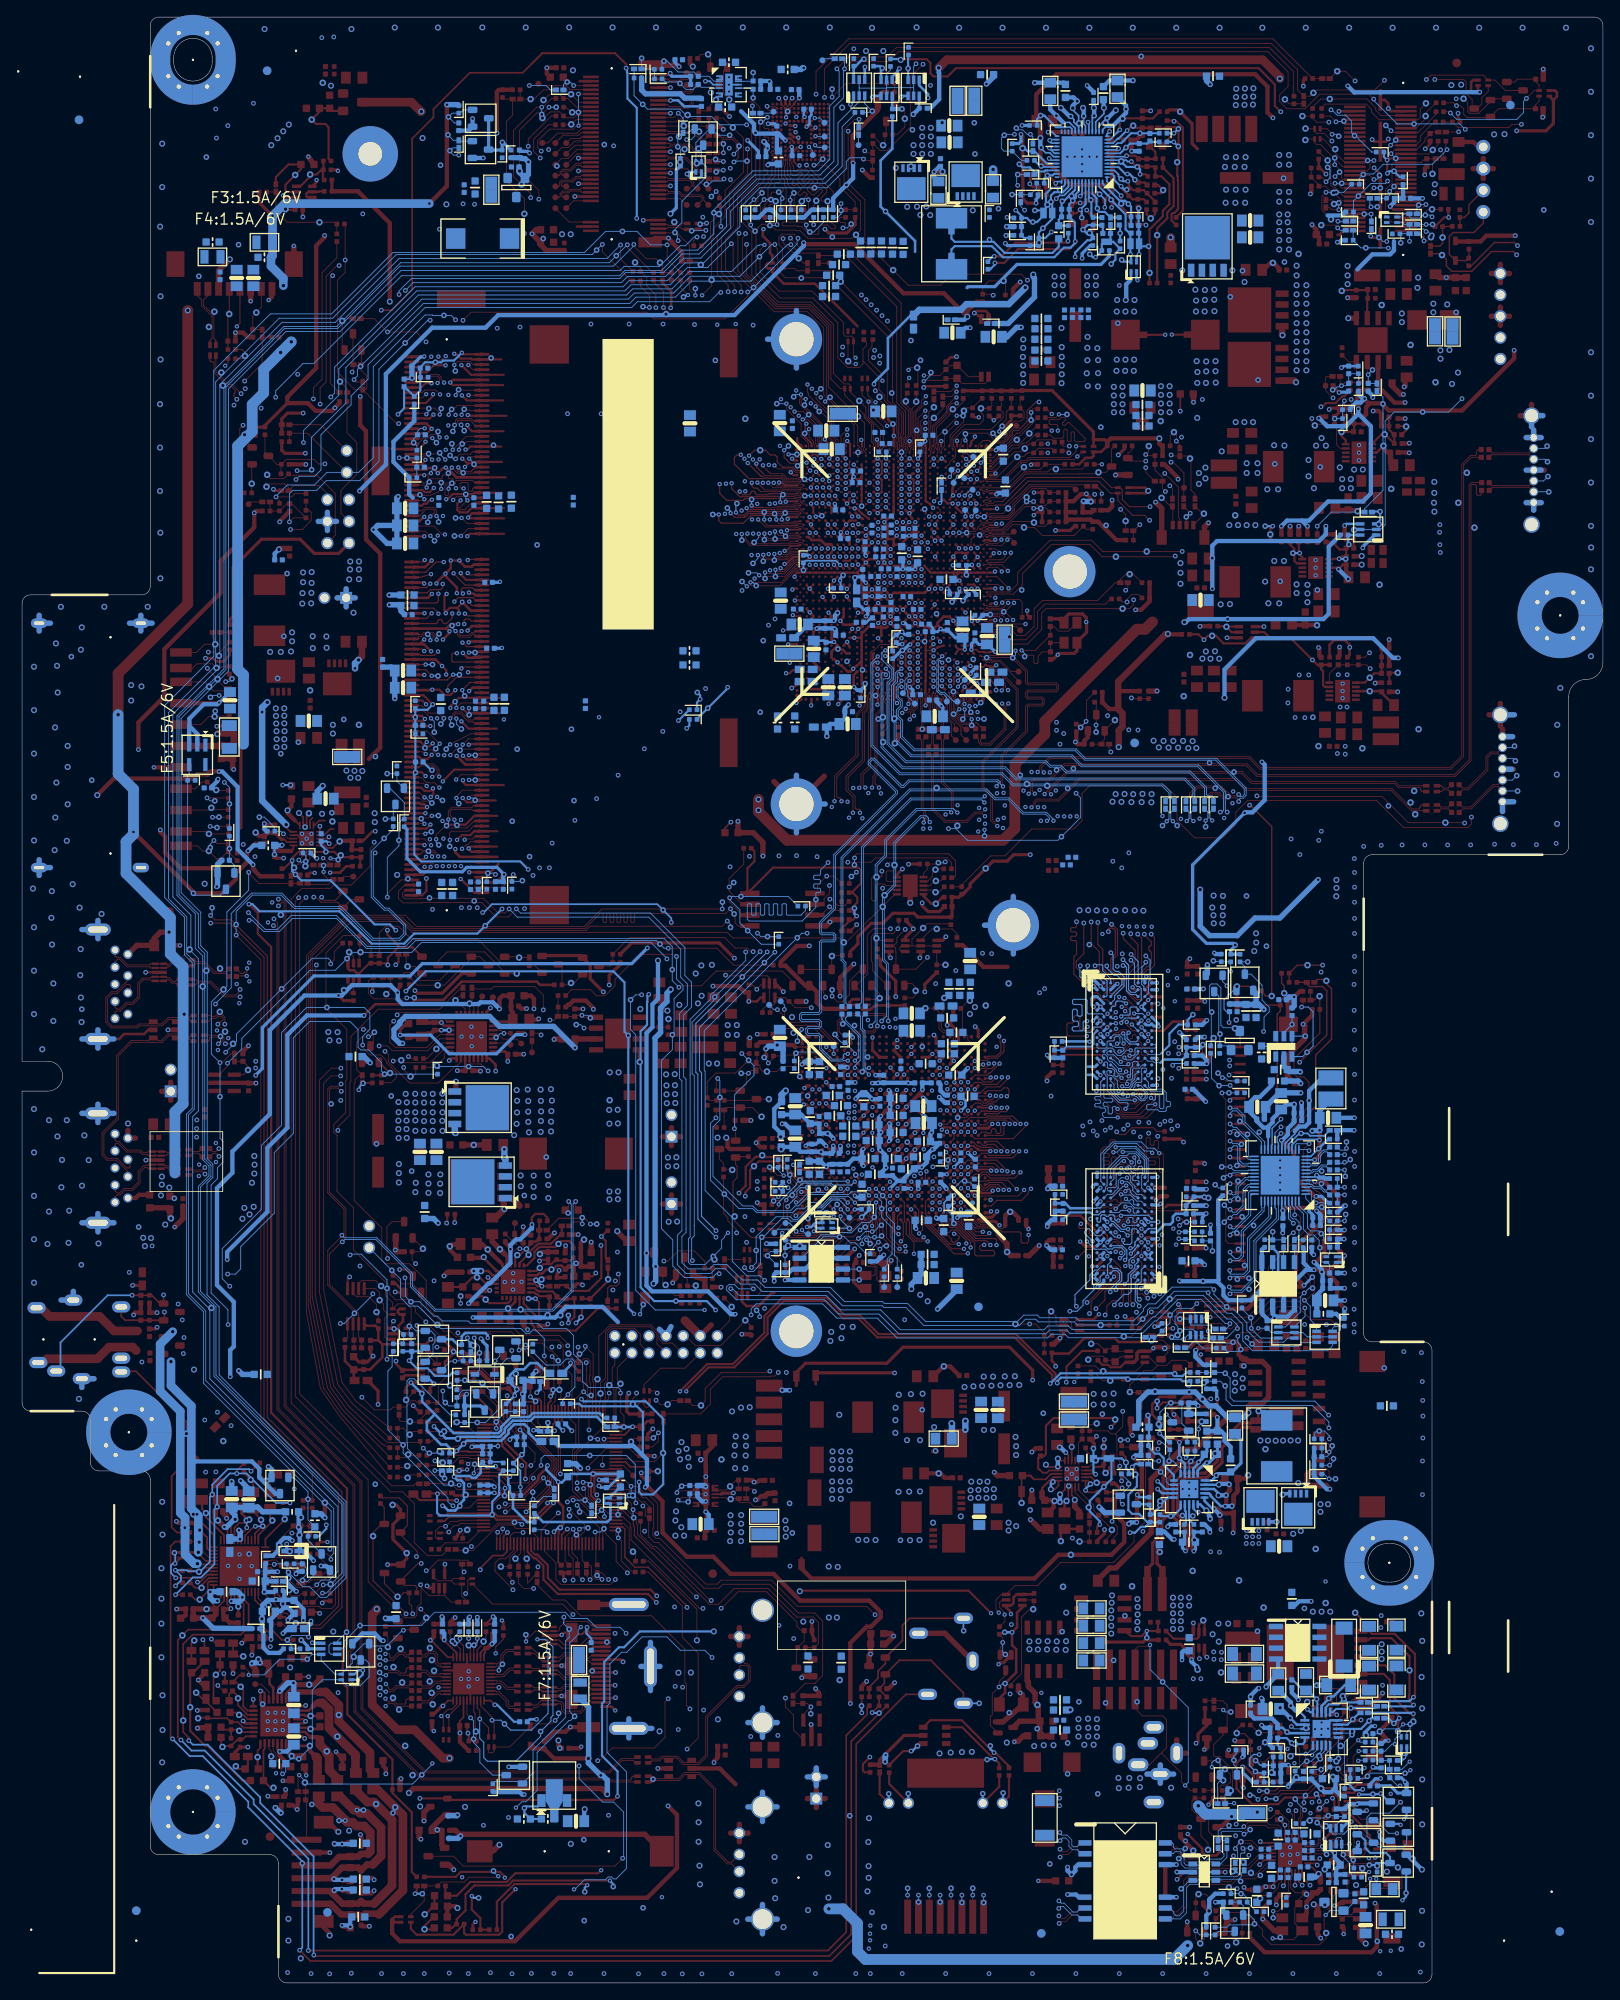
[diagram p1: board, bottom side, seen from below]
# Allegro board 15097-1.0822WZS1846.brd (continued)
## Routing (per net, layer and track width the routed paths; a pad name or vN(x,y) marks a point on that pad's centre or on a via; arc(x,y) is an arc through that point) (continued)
AMP_GND: length 15.1
  TOP w0.305: v1(159.13,30.65) 158.84,30.36 U22.4
  TOP w0.381: R466.1 160.1,26.96 R462.1 158.59,27.6 v1(158.58,27.58)
  TOP w0.508: R479.1 156.19,21.79 v1(156.24,21.84) ; R440.1 163.7,34.76 v1(164.37,35.43) 164.37,35.48 163.63,36.22 R436.2 ; C173.2 158.06,38.4 v1(158.11,38.35) ; R434.2 v1(160.31,36.2) ; v1(164.5,31.88) 164.46,31.92 R451.2
  TOP w0.635: C178.2 157.67,36.73 158.12,37.19 v1(158.12,37.37) ; C200.1 C197.1 163.38,29.86 164.28,29.86 164.33,29.81 v1(164.47,29.81)
  BOTTOM w0.635: v2(157.16,37.47) 158.02,37.47 v1(158.12,37.37)
AMP_SPKR_L: length 5.9
  TOP w0.203: 162.59,35.78 162.59,33.32 C191.1
  TOP w0.254: R431.2 R434.1 161.83,36.54 v4(162.32,36.06) 162.59,35.78
AMP_SPKR_R: length 18.4
  TOP w0.254: R432.2 164.98,36.3 R436.1 165.32,36.13 v4(165.32,32.25) 165.32,29.49 163.59,27.76 163.3,27.76 159.21,23.67 C217.1
APU_PROCHOT#: length 302.1
  TOP w0.102: PR136.1 61.42,70.75 v3(61.87,70.31) ; v4(53.14,179.81) 53.14,179.17 v1(53.5,178.82) 53.38,178.69 PR42.2 C32.1 52.42,177.02 51.54,176.14 R141.1 51.54,174.83 v1(51.2,174.49) ; Q38.D 94.38,38.62 R429.2 93.46,40.02 C172.1 93.81,41.22 94.32,41.73 94.32,42.22 97.87,45.77 101.2,45.77 103.13,43.84 v1(103.18,43.84)
  L3 w0.127: v3(51.07,66.51) 51.18,66.4 59.32,66.4 59.86,66.94 59.9,66.94 60.29,67.34 60.29,67.37 61.87,68.95 v3(61.87,70.31) 59.79,72.39 43.36,72.39 39.5,76.25 39.5,77.14 40.23,77.87 40.23,79.22 40.19,79.26 40.19,106.4 38.79,107.8 38.79,117.45 37.24,119 37.24,130.12 35.47,131.9 v1(35.47,132.02)
  L4 w0.127: v1(51.2,174.49) 51.12,174.4 51.12,170.48 51.61,169.99 51.61,154.58 53.98,152.21 53.98,148.83 55.99,146.82 55.99,145.89 56.75,145.14 56.89,145.14 57.21,144.82 57.21,144.68 57.25,144.64 57.25,144.36 57.11,144.22 57.11,143.81 57.39,143.54 57.5,143.54 58.18,142.85 58.18,137.86 57.75,137.43 45.5,137.43 45.48,137.45 43.54,137.45 42.45,136.36 41.12,136.36 36.77,132.02 v1(35.47,132.02) ; v1(66.99,216.28) 66.87,216.16 66.87,210.96 66.59,210.68 66.59,210.29 66.87,210.02 66.9,210.02 67.22,209.7 67.22,207.65 67.19,207.62 67.19,207.21 67.22,207.19 67.22,204.55 62.49,199.82 62.49,186.01 57.91,181.43 56.5,181.43 53.88,178.82 v1(53.5,178.82) ; v1(103.18,43.84) 102.91,43.84 99.72,47.03 87.48,47.03 86.69,47.03 86.46,47.26 64.16,47.26 59.47,51.95 59.47,51.99 59.47,51.99 59.47,52.78 59.47,54 58.29,55.18 58.29,59.74 56.41,61.62 56.41,63.39 54.52,65.28 52.3,65.28 v3(51.07,66.51)
  BOTTOM w0.102: PQ17.D 50.38,65.82 v3(51.07,66.51) ; v2(68.64,217) 68.44,216.8 67.89,216.8 67.37,216.28 v1(66.99,216.28) 66.71,215.99 PR190.1
APU_PROCHOT#_R: length 27.2
  TOP w0.102: v1(53.5,177.29) 53.5,176.76 R141.2 ; CPU1.E47 73.18,171.58 v3(73.18,171.57)
  L3 w0.127: v3(73.18,171.57) 72.59,172.16 72.59,173.49 72,174.08 72,174.32 70.34,175.97 64.08,175.97 62.05,178 60.67,178 60.36,178.31 56.91,178.31 56.91,178.3 56.39,178.3 55.38,177.29 v1(53.5,177.29)
  BOTTOM w0.102: v3(73.18,171.57) 72.44,171.57 72.41,171.54 v2(72.4,171.54)
APU_PWNBTN_N: length 162.3
  TOP w0.102: v1(16.89,216.59) 16.89,216.57 16.91,216.55 R31.2 ; v3(84.31,187.45) 84.44,187.58 84.44,188.32 85.94,189.82 85.94,191 85.53,191.41 85.53,192.15 R1802.2 ; v1(99.53,219.62) 99.52,219.6 99.52,217.99 99.14,217.61 99.14,211.23 101.28,209.1 101.28,205.41 102.68,204.01 102.68,200.46 100.85,198.63 v1(100.85,197.84) ; v3(84.87,175.52) CPU1.AK55 ; v1(25.57,222.6) 26.71,221.46 33.55,221.46 v4(33.88,221.13) 33.88,221.13 34.27,220.75 R16.2 35.75,221.48 35.75,223.85 38.81,226.91 39.21,226.91 39.21,226.91 39.8,226.91 39.81,226.92 39.86,226.92 40.26,226.92 40.26,226.92 88.12,226.92 91.09,223.95 v1(91.09,220.6)
  L3 w0.127: v3(84.31,187.45) 84.31,188.33 85.96,189.98 85.96,191.73 91.15,196.93 99.93,196.93 v1(100.85,197.84)
  L4 w0.089: 84.49,180.77 84.49,175.91 v3(84.87,175.52)
  L4 w0.127: v1(16.89,216.59) 19.52,216.59 24.45,221.52 24.48,221.52 v1(25.57,222.6) ; v1(99.53,219.62) 99.12,220.03 91.66,220.03 v1(91.09,220.6) ; v3(84.31,187.45) 84.25,187.39 84.25,182.47 84.49,182.23 84.49,180.77
  BOTTOM w0.102: v1(99.53,219.62) 99.48,219.56 R528.1
APU_PWNBTN_N_R: length 2.4
  TOP w0.102: R16.1 36.14,219.86 R17.1 36.71,219.86 v4(37.22,220.37)
APU_SATA_LED_B: length 131.6
  TOP w0.254: v3(128.5,12.31) 128.5,12.43 129.06,12.99 133.66,12.99 134.24,12.41 R490.2
  L3 w0.254: v3(85.77,5.75) 85.69,5.75 84.92,4.98 84.92,3.34 84.18,2.6 24.25,2.6 23.25,3.59 23.25,9.46 v3(23.46,9.67)
  L4 w0.254: v3(85.77,5.75) 87.03,4.5 110.95,4.5 119.06,12.6 127.67,12.6 127.95,12.31 v3(128.5,12.31)
  BOTTOM w0.254: Q78.B 23.04,11.81 v2(23.04,10.52) 23.04,10.1 v3(23.46,9.67)
APU_SATA_LED_N: length 231.6
  TOP w0.254: CPU1.C31 72.84,164.51 v3(73.23,164.12) ; R490.1 139.39,12.99 139.39,19.96 141.66,22.23 R474.1 141.66,26.15 146.94,31.43 146.94,34.49 147.47,35.02 147.47,39.08 146.97,39.57 146.97,57.84 155.85,66.71 155.85,121.21 157.42,122.77 157.42,125.18 v1(158.45,126.21)
  L3 w0.254: v1(125.2,129.58) 128.83,125.95 v1(128.83,125.65)
  L4 w0.254: v1(125.2,129.58) 125.2,129.57 122.77,129.57 101.91,150.43 89.58,150.43 87.76,152.25 86.94,152.25 86.01,153.17 86.01,158.95 84.96,160 83.97,160 81.9,162.08 80.65,162.08 79.09,163.64 76.42,163.64 75.48,164.58 73.69,164.58 v3(73.23,164.12)
  BOTTOM w0.254: v1(128.83,125.65) v2(130.79,123.69) 131.71,122.77 139.11,122.77 140.28,121.59 144.08,121.59 147.86,125.38 157.21,125.38 158.04,126.21 v1(158.45,126.21)
APU_SPKR: length 244.2
  TOP w0.102: CPU1.AK57 v3(84.87,176.95) ; v1(159.94,122.58) 157.06,119.7 157.06,65.78 151.04,59.76 R382.1
  L4 w0.089: 85.57,181.36 85.57,177.64 v3(84.87,176.95)
  L4 w0.102: 85.53,181.39 85.57,181.36
  L4 w0.127: 85.53,181.39 85.53,185.18 85.77,185.42 86.49,185.42 90.43,189.36 90.43,192.19 93.72,195.48 97.98,195.48 98.53,196.04 103.46,196.04 104.39,196.97 107.3,196.97 108.26,197.94 112.41,197.94 114.22,196.13 137.52,196.13 142.23,191.41 142.23,173.52 140.81,172.09 140.81,134.18 142.78,132.21 v1(143.68,132.21)
  BOTTOM w0.102: v1(143.68,132.21) 143.68,132.19 143.9,131.97 143.9,127.13 142.53,125.75 142.05,125.75 140.1,123.79 140.1,122.68 140.78,122 144.02,122 147.73,125.71 153.13,125.71 154.69,127.27 158.04,127.27 159.94,125.37 v2(159.94,123.83) v1(159.94,122.58)
AUD_BEEP_C: length 4.9
  TOP w0.102: U16.2 155.33,50.57 154.9,51 v4(154.9,51.2) 154.9,51.83 C155.2
AUD_BEEP_R: length 4.3
  TOP w0.102: R388.2 151.33,53.47 C155.1 152.36,53.48 v4(152.36,54.46) 152.36,55.31 R383.1 R382.2
AUD_DMIC_CLK: length 7.2
  TOP w0.127: L1.2 160.91,192.09 C18.2 160.91,195.11 v4(160.76,195.26) 160.76,195.64 160.75,195.65 WEBCM1.4
AUD_DMIC_CLK_R: length 169.8
  TOP w0.127: v3(161.23,189.21) 161.19,189.21 160.91,189.49 R93.1 ; U16.12 156.52,45.41 154.35,43.24 154.35,43.24 154.02,43.24 153.69,42.91 153.69,42.91 152.97,42.19 v4(152.97,42.09) 152.75,41.87 150.17,41.87 147.95,44.09 147.95,57.29 156.69,66.03 156.69,119.99 160.69,124 v1(162.92,124)
  L4 w0.127: v3(161.23,189.21) 161.23,188.86 166.55,183.54 166.55,157.69 166.93,157.31 166.93,131.9 164.72,129.7 164.72,125.8 v1(162.92,124)
AUD_DMIC_CLK_R_1: length 2.9
  TOP w0.127: L1.1 159.26,191.1 158.91,190.75 v4(158.91,190.36) 159.23,190.04 R93.2
AUD_DMIC_DATA: length 176.9
  TOP w0.127: WEBCM1.5 159.5,196.59 159.5,196.58 159.5,194.17 v3(159.86,193.81) ; v1(162.94,124.89) 162.43,124.38 160.53,124.38 156.31,120.15 156.31,66.18 147.57,57.45 147.57,43.94 150.01,41.49 153.98,41.49 154.45,41.97 154.48,41.97 C168.2 155.79,41.97 R417.1
  L4 w0.127: v3(159.86,193.81) 159.43,193.38 159.43,189.65 166.17,182.91 166.17,157.5 166.55,157.13 166.55,132.06 164.34,129.86 164.34,126.29 v1(162.94,124.89)
  BOTTOM w0.127: v2(162.76,125.79) 162.76,125.07 v1(162.94,124.89)
AUD_DMIC_DATA_R: length 3.7
  TOP w0.127: U16.13 157.35,44.97 156.57,44.2 v4(156.17,44.2) 155.81,43.84 R417.2
AUD_DVDD: length 9.1
  TOP w0.203: v1(155.1,48.11) 155.15,48.16 155.49,48.16 155.9,48.57 U16.7
  BOTTOM w0.508: C484.2 156.55,48.09 C483.2 ; C484.2 156.52,46.99 R749.2 ; C484.2 156.64,46.92 v2(156.64,45.73) 155.51,45.73 R750.2 ; C483.2 156.54,49.02 R809.2 ; C483.2 v1(155.1,48.11)
AUD_GP3: length 5.7
  TOP w0.203: U16.3 153.99,50.17 v4(153.66,50.5) 152.85,51.31 R392.2
AUD_LINK_BCLK: length 218.1
  TOP w0.102: v1(150.51,46.58) 150.8,46.29 152.86,46.29 153.83,47.26 v4(153.83,47.4) 153.83,48.04 C158.2 155.27,49.48 155.79,49.48 155.9,49.37 U16.5 ; R81.1 114.96,201.69 v1(114.96,203.34)
  BOTTOM w0.102: v1(150.51,46.58) 149.96,47.14 149.04,47.14 148.04,48.13 148.04,55.71 163.02,70.69 163.02,78.82 165.03,80.82 165.03,101.35 164.37,102.01 164.37,119.86 165.24,120.73 165.24,124.93 167.35,127.04 167.35,148.44 167.22,148.57 167.22,148.57 164.25,151.54 164.25,151.54 161.86,153.94 161.86,187 154.57,194.28 148.35,194.28 140.89,201.75 116.55,201.75 v1(114.96,203.34)
AUD_LINK_RST_N: length 225.8
  TOP w0.102: v1(106.01,204.27) 106.01,204.26 106.39,203.88 R74.1 ; v1(155.48,48.97) 155.58,48.97 155.59,48.97 U16.6
  BOTTOM w0.102: v1(155.48,48.97) 155.42,49.03 R748.1 154.01,49 154.01,48.23 v2(153.83,48.04) 152.15,46.36 151.35,46.36 150.1,45.11 149.36,45.11 147.1,47.37 147.1,56.31 161.93,71.15 161.93,79.1 163.36,80.52 163.36,93.56 162.67,94.24 162.67,95.78 163.33,96.44 163.33,120.6 164.09,121.36 164.09,125.27 166.38,127.56 166.38,147.96 160.84,153.49 160.84,186.49 154.11,193.22 147.78,193.22 140.65,200.36 115.02,200.36 114.54,200.84 110.4,200.84 107.98,203.25 107.36,203.25 106.35,204.27 v1(106.01,204.27)
AUD_LINK_RST_N_2: length 4.7
  BOTTOM w0.102: v2(147.02,41.05) 148.12,39.95 Q69.6 148.84,39.74 149.08,39.5 149.08,38.68 148.84,38.44 Q69.4
AUD_LINK_RST_N_R: length 5.5
  BOTTOM w0.102: R748.2 C482.1 152.2,48.99 151.72,48.51 151.72,47.77 152.17,47.32 v2(152.17,47.11) 152.06,46.99 151.57,46.99 150.93,47.63 Q67.B
AUD_LINK_SDIN: length 213.3
  TOP w0.102: R411.1 150.77,45.55 v1(149.75,46.57) ; R82.1 111.23,200.12 114.17,203.05 v1(114.17,203.37)
  BOTTOM w0.102: v1(114.17,203.37) v2(115.46,202.08) 116.27,201.27 140.69,201.27 148.15,193.8 154.37,193.8 161.37,186.8 161.37,153.74 166.87,148.24 166.87,127.24 164.73,125.1 164.73,121.03 163.85,120.16 163.85,96.31 163.13,95.58 163.13,94.44 164.37,93.19 164.37,80.85 162.54,79.02 162.54,70.99 147.56,56.01 147.56,47.93 148.92,46.57 v1(149.75,46.57)
AUD_LINK_SDIN_1: length 7.2
  TOP w0.102: R416.1 151.89,44.51 R411.2 152.3,45.55 152.56,45.29 153.45,45.29 153.75,45.59 v4(153.75,45.95) 154.44,46.63 154.44,46.67 155.94,48.17 U16.8
AUD_LINK_SDIN_ST: length 216.5
  TOP w0.102: R416.2 150.95,44.51 v1(149.84,45.62) ; v1(113.4,203.4) 113.4,203.19 111.95,201.73 110.8,201.73 v4(110.35,201.27) 110.06,200.99 R86.1 109.01,200.11 R83.2
  BOTTOM w0.102: v1(149.84,45.62) 149.39,45.62 147.33,47.68 147.33,56.12 162.3,71.09 162.3,79.11 164.12,80.92 164.12,93.12 163.31,93.93 163.3,93.93 162.9,94.34 162.9,95.68 163.62,96.41 163.62,120.44 164.37,121.18 164.37,125.07 166.64,127.34 166.64,148.15 161.15,153.64 161.15,186.7 154.28,193.57 148.06,193.57 140.77,200.86 115.78,200.86 113.4,203.24 v1(113.4,203.4)
AUD_LINK_SDO: length 212.4
  TOP w0.102: v1(117.09,203.41) 117.09,202.55 113.69,199.14 R87.1 ; Q35.D 149.65,47.85 C161.1 150.41,50.01 R396.2 149.28,50.19 148.85,49.76 v1(148.85,49.56)
  BOTTOM w0.102: v1(148.85,49.56) 148.85,49.94 148.52,50.27 148.52,55.5 163.51,70.48 163.51,78.61 165.51,80.62 165.51,101.55 164.85,102.21 164.85,119.53 165.72,120.4 165.72,124.73 167.85,126.86 167.85,148.63 164.4,152.08 164.39,152.08 162.34,154.14 162.34,187.32 154.9,194.77 148.65,194.77 141.18,202.23 118.27,202.23 v2(117.76,202.74) v1(117.09,203.41)
AUD_LINK_SDO_1: length 5.8
  TOP w0.102: R414.2 148.93,46.55 148.89,46.58 v4(148.89,46.65) 148.95,46.71 C161.2 149.17,47.66 149.69,47.14 151.16,47.14 151.44,46.87 Q35.G
AUD_LINK_SDO_N: length 6.9
  TOP w0.102: U16.4 154.77,49.77 154.73,49.73 153.21,49.73 Q35.S 152.32,50.08 v4(152.33,50.09) 152.23,50.19 R396.1
AUD_LINK_SYNC: length 230.5
  TOP w0.102: v1(148.98,50.75) 148.32,50.09 148.32,44.25 148.75,43.81 149.99,43.81 150.22,44.04 152.89,44.04 154.67,45.82 154.67,46.57 155.74,47.65 155.91,47.65 156.03,47.77 U16.9 ; R84.1 109.51,201.68 v1(109.51,203.35)
  BOTTOM w0.102: v1(109.51,203.35) 111.46,203.35 113.04,204.93 v2(114.74,204.93) 116.71,204.93 119.17,202.46 141.59,202.46 148.78,195.28 155.94,195.28 162.57,188.65 162.57,155.2 168.31,149.46 168.31,126.99 166,124.68 166,120.27 165.08,119.35 165.08,102.33 165.74,101.66 165.74,80.52 163.76,78.53 163.76,70.15 148.83,55.22 148.83,50.91 148.98,50.76 v1(148.98,50.75)
AUD_REGREF: length 6.4
  TOP w0.203: U16.10 155.93,47.37 155.12,46.56 155.12,45.51 154.67,45.07 154.67,45.06 154.47,44.86 v4(154.47,44.35)
  TOP w0.305: C164.2 153.5,43.38 v4(154.47,44.35)
AZ_BCLK_M: length 47.8
  TOP w0.102: v1(110.83,196) 110.83,197.51 111.89,198.58 111.89,199.51 R81.2 112.62,200.65 v4(113.27,201.29) ; CPU1.AM48 86.17,172.31 v3(85.83,171.97)
  L4 w0.127: v1(110.83,196) 109.46,194.64 106.12,194.64 104.71,193.23 100.08,193.23 96.11,189.26 92.85,189.26 87.82,184.23 87.82,179.69 87.11,178.99 87.11,173.26 v3(85.83,171.97)
AZ_RST_N_M: length 5.7
  TOP w0.102: R74.2 105.3,203.25 105.3,203.26 104.43,204.12 104.43,205.97 v4(103.44,206.96) 103.39,207 R54.1
AZ_RST_R_M: length 62.8
  TOP w0.102: R54.2 103.39,209.22 v1(103.77,209.6) ; CPU1.K58 v3(75.48,177.64)
  L4 w0.127: v3(75.48,177.64) 75.48,177.92 74.5,178.89 73.3,178.89 71.38,180.81 71.38,181.97 70.42,182.93 70.42,195.81 72.52,197.92 77.7,197.92 89.79,210.01 100.09,210.01 100.61,209.49 103.66,209.49 v1(103.77,209.6)
  BOTTOM w0.102: v1(103.77,209.6) 103.77,209.57 v2(104.33,209.01)
AZ_SDIN_M: length 43.6
  TOP w0.102: CPU1.AK51 v3(85.83,174.1) ; v4(109.64,195.25) 109.64,195.71 v1(109.94,196.01) 109.94,197.87 111.1,199.03 R82.2
  L4 w0.127: v3(85.83,174.1) 86.75,175.02 86.75,179.02 87.21,179.48 87.21,184.1 92.58,189.48 95.97,189.48 97.08,190.58 97.08,190.59 99.97,193.48 104.38,193.48 105.96,195.07 109.33,195.07 109.94,195.68 v1(109.94,196.01)
AZ_SDOUT_M: length 44.6
  TOP w0.102: v1(111.59,196.03) 111.59,197.45 112.65,198.51 R87.2 ; CPU1.AM54 v3(85.83,175.52)
  L4 w0.089: 86.39,180.79 86.39,176.09 v3(85.83,175.52)
  L4 w0.102: 86.73,181.14 86.39,180.79
  L4 w0.127: v1(111.59,196.03) 111.14,196.48 108.78,196.48 107.97,195.68 105.9,195.68 104.76,194.54 99.37,194.54 97.65,192.82 97.65,191.62 95.72,189.69 92.49,189.69 86.73,183.93 86.73,181.14
  BOTTOM w0.102: v1(111.59,196.03) 112.25,196.03 v2(112.33,196.12)
AZ_SYNC_M: length 41.9
  TOP w0.102: v3(107.07,197.48) 107.93,198.34 R84.2 107.93,199.22 R83.1 ; CPU1.AK58 v3(84.87,177.66)
  L4 w0.089: 85.36,180.98 85.36,178.15 v3(84.87,177.66)
  L4 w0.127: 85.36,180.98 84.99,181.35 84.99,182.41 84.72,182.69 84.72,185.11 85.25,185.64 86.4,185.64 90.18,189.41 90.18,192.3 93.79,195.91 97.77,195.91 98.2,196.34 103.1,196.34 104.68,197.92 106.62,197.92 v3(107.07,197.48)
  BOTTOM w0.102: v3(107.07,197.48) 107.38,197.48 v2(107.6,197.26)
BAT_ALERT: length 4.6
  TOP w0.102: v1(32.03,58.97) 32.03,59.86 33.22,61.06 BAT2.7
  BOTTOM w0.102: R735.2 32.61,59.51 32.07,58.97 v1(32.03,58.97) v2(31.29,58.97)
BAT_IN#: length 144
  TOP w0.102: R737.1 132.8,58.93 U14.80 129.98,58.93 128.94,57.88 128.94,57.69 128.67,57.43 128.29,57.43 128.29,57.43 126.49,57.43 125.17,58.75 v1(125.17,59.05)
  L3 w0.127: v1(32.01,63.65) 30.51,62.15 30.51,55.68 35.62,50.57 44.3,50.57 44.95,51.22 49.37,51.22 50.31,50.28 59.07,50.28 61.5,47.85 83.95,47.85 87.61,44.2 87.61,41.61 89.75,39.47 95.31,39.47 96.4,40.56 v3(96.4,41.83)
  L4 w0.127: v3(96.4,41.83) 99.07,41.83 99.51,42.28 101.89,42.28 103.6,40.58 104.37,40.58 106.34,42.55 116.09,42.55 117.75,40.88 119.92,40.88 121.33,42.29 121.75,42.29 122.84,43.38 122.84,44.6 123.49,45.25 123.49,51.09 124.32,51.91 124.32,57.15 125.17,58 v1(125.17,59.05)
  BOTTOM w0.102: R725.1 33.78,63.97 33.78,64.28 33.49,64.57 v2(33.2,64.57) 32.57,64.57 32.01,64.01 v1(32.01,63.65)
BAT_IN#_1: length 6.8
  TOP w0.102: BAT2.5 33.22,64.15 32.04,62.97 v1(32.04,62.1)
  BOTTOM w0.102: v2(31.68,62.84) 31.68,62.46 v1(32.04,62.1) 32.04,61.83 32.3,61.56 PC184.1 PL13.1 32.89,63.41 R725.2
BATA_SCL_1: length 20.2
  TOP w0.102: BAT2.3 32.86,67.2 v1(32.1,66.43)
  BOTTOM w0.102: R714.2 46.41,71.43 PL10.1 46.39,71.42 PC175.1 44.3,71.42 v2(44.2,71.32) 43.62,70.74 43.62,68.5 43.19,68.07 33.74,68.07 v1(32.1,66.43)
BATA_SDA_1: length 20.4
  TOP w0.102: BAT2.4 32.84,65.7 v1(32.07,64.93)
  BOTTOM w0.102: R717.2 47.42,70.4 PL11.1 45.46,70.4 PC176.1 44.75,70.39 v2(44.21,69.85) 44.1,69.74 44.1,68.24 43.43,67.56 34.01,67.56 32.07,65.63 v1(32.07,64.93)
BATT_AMBER_LED#: length 6.9
  TOP w0.102: U14.32 115.5,52.35 v1(115.22,52.07) 114.87,51.71 114.87,49.38 113.57,48.08 R407.2
  BOTTOM w0.102: v1(115.22,52.07) v2(115.22,52.96)
BATT_AMBER_LED#_C: length 133.2
  TOP w0.102: PWRCN1.10 29.4,20.25 28.3,19.15 25.69,19.15 25.57,19.03 25.57,15 26.04,14.53 26.04,14.07 v4(26.42,13.69) 26.53,13.59 v3(26.53,12.18) ; R407.1 111.72,48.08 107.73,44.09 107.73,40.44 105.87,38.58 105.87,28.65 v1(107.17,27.36)
  L4 w0.127: v1(107.17,27.36) 106.76,26.94 103.45,26.94 102.7,26.2 94.75,26.2 92.98,27.97 84.84,27.97 84.04,28.78 71.6,28.78 70.15,30.23 64.48,30.23 61.47,33.25 50.02,33.25 44.98,28.2 44.98,23.98 37.39,16.38 34.52,16.38 33.59,15.45 32.3,15.45 29.79,12.93 28.61,12.93 27.42,11.75 26.96,11.75 v3(26.53,12.18)
  BOTTOM w0.102: R801.2 v3(26.53,12.18)
BATT_WHITE_LED#: length 5
  TOP w0.102: R385.2 113.02,54.9 v1(113.49,55.37) 113.7,55.58 113.7,56.11 114.52,56.93 U14.22
  BOTTOM w0.102: v2(113.42,54.43) 113.49,54.51 v1(113.49,55.37)
BATT_WHITE_LED#_C: length 210.5
  TOP w0.102: R385.1 112.63,52.47 111.21,51.05 110.78,51.05 104.48,44.75 v1(104.35,44.75) ; PWRCN1.8 29.05,21.25 28.89,21.41 23.94,21.41 v1(23.68,21.15) 23.68,21.01 22.54,19.86 22.54,17.48 22.87,17.14 R486.2 22.87,15.11 v4(22.28,14.53)
  L3 w0.127: v1(104.35,44.75) 104.59,44.51 104.59,38.85 104.25,38.51 v1(104.25,38.07)
  L4 w0.127: v3(120.4,10.95) 120.02,10.95 112.42,3.34 27.94,3.34 26.53,4.75 26.12,4.75 23.91,6.96 23.91,9.86 23.31,10.45 23.31,13.94 23.31,14.72 24.27,15.68 24.27,16.68 24.53,16.94 24.53,16.94 24.59,17.01 24.59,19.79 24,20.38 23.68,20.7 v1(23.68,21.15)
  BOTTOM w0.102: Q75.C 22.98,16.27 23.35,15.9 26.33,15.9 Q77.C 27.62,17.18 27.62,19.37 27.12,19.86 24.97,19.86 24.38,20.45 v1(23.68,21.15) ; v3(120.4,10.95) 120.3,10.95 119.18,12.06 116.75,12.06 116.42,12.4 116.01,12.4 115.78,12.17 115.48,12.17 114.26,13.39 114.26,24.69 116.31,26.75 116.31,26.77 116.54,27 116.54,32.38 116.21,32.72 116.21,37.31 114.84,38.68 114.23,38.68 112.43,40.49 109.53,40.49 107.96,38.91 105.09,38.91 v1(104.25,38.07)
BIST_DISABLE: length 95.7
  TOP w0.102: U14.118 121.05,66.15 120.2,65.3 120.2,62.71 120.58,62.33 120.58,57.58 116.77,53.77 116.77,52.65 115.48,51.36 115.48,49.3 v1(114.16,47.98) ; v4(68.75,77.09) v1(67.09,77.09) 66.4,77.09 65.36,76.05 R333.1 R336.1 65.37,74.71 R339.2
  L3 w0.127: v1(67.09,77.09) 85.71,77.09 96.91,65.89 96.91,51.65 99.72,48.84 112.33,48.84 113.19,47.98 v1(114.16,47.98)
BIST_DISABLE_1: length 5.7
  TOP w0.102: Q31.5 63.85,76.96 64,77.11 64,77.99 v4(64.58,78.57) 64.81,78.33 64.81,76.11 R333.2
BIST_EN: length 13.8
  TOP w0.102: Q31.6 62.58,77.61 62.19,77.22 62.19,76.71 61.79,76.31 Q31.3 60.85,76.31 60.59,76.05 56.47,76.05 v4(56.07,75.64) 55.18,75.64 R331.2 52.97,77.85 Q30.2
BIST_EN_INV: length 126.2
  TOP w0.102: R402.1 120,47.76 v1(119.42,47.18) ; Q30.6 49.98,77.2 50.4,77.62 50.4,78.18 50.72,78.5 Q30.3 ; R327.2 53.69,77.65 v1(52.84,78.5) Q30.3 ; Q30.3 51.34,79.38 v4(50.71,80.01) 43.98,80.01 43.67,79.71 41.89,79.71 39.17,82.42 39.17,83.72 33.97,88.93 33.97,90.52 33.56,90.92 v1(33.56,91.26)
  L3 w0.127: v1(119.42,47.18) 119.42,47.65 117.86,49.2 99.72,49.2 97.16,51.76 97.16,66.08 85.16,78.09 65.7,78.09 65.31,77.7 62.42,77.7 62.14,77.42 54.75,77.42 53.66,78.5 v1(52.84,78.5)
  BOTTOM w0.102: U31.2 34.22,92.7 34.09,92.57 34.09,91.59 33.76,91.26 v1(33.56,91.26) 33.14,91.26 33.09,91.31 32.72,91.31 32.42,91.01 32.42,90.88 31.97,90.44 R676.1
BIST_EN_SIO: length 5.9
  TOP w0.102: v1(119.77,53.09) 119.77,52.98 120.65,52.1 U14.42 120.65,50.33 120,49.68 R402.2
  BOTTOM w0.102: v1(119.77,53.09) 119.62,53.24 v2(118.78,53.24)
BIST_ENABLE: length 100.4
  TOP w0.102: v1(120.51,47.13) 120.51,49.61 121.05,50.15 U14.43 ; v1(46.18,76.28) 46.64,76.73 R330.1
  L3 w0.127: v1(120.51,47.13) 119.83,46.45 112.8,46.45 111.68,47.57 99.15,47.57 94.78,51.95 94.78,65.28 85.09,74.97 53.96,74.97 53.63,75.3 50.51,75.3 49.52,76.29 48.03,76.29 48.01,76.28 v1(46.18,76.28)
BIST_ENABLE_1: length 5.6
  TOP w0.102: Q30.5 48.06,77.85 R324.1 R330.2 48.85,76.73 v4(49.79,75.79) 49.84,75.74 R334.2
BIST_PIN25: length 143.2
  TOP w0.102: U14.82 129.24,59.73 128.01,58.5 125.74,58.5 125.63,58.61 125.63,59.24 125.36,59.51 125.3,59.51 v1(124.26,60.54)
  L3 w0.127: v1(44,116.66) 44,113.13 45.25,111.89 45.25,84.25 48.57,80.92 49.66,80.92 52.74,77.85 53.21,77.85 53.95,77.85 54.64,77.17 62.36,77.17 62.64,77.44 65.42,77.44 65.56,77.59 v1(81.72,77.59)
  L4 w0.127: v1(81.72,77.59) 81.73,77.59 86.67,72.64 99.12,72.64 105.1,66.67 105.1,60.6 106.96,58.74 109.21,58.74 111.56,56.39 112.94,56.39 v1(113.16,56.16)
  BOTTOM w0.102: v1(124.26,60.54) 124.26,61.34 123.89,61.71 v2(118.56,61.71) 114.28,61.71 113.24,60.68 113.24,56.24 v1(113.16,56.16) ; v1(44,116.66) 44.51,117.17 Q56.G
BKLT_ADJ: length 4.2
  BOTTOM w0.165: R778.2 C511.1 ; C511.1 38.64,25.46 R782.2 40.08,25.46 v2(40.64,26.02) ; C511.1 C512.1
BKLT_EN: length 9
  TOP w0.127: R453.2 42.33,30.19 42.85,29.66 v4(42.85,29.22) 42.79,29.16 41.93,29.16 41.24,28.47 R460.2 C206.1 41.24,25.91 Q40.C 39.61,25.84 R465.2
BKLT_EN1: length 2.9
  TOP w0.127: Q40.B 39.51,24.63 v4(38.79,24.63) 38.58,24.83 R467.2
BOOT_HALT_N: length 7.1
  TOP w0.254: v1(25.21,211.72) 25.25,211.75 v1(25.25,213.28) 25.06,213.46 24.52,213.46 24.49,213.49 XDP1.36
  BOTTOM w0.254: R532.1 25.63,213.65 v1(25.25,213.28) ; R540.2 23.79,211.31 v2(24.44,211.96) 24.97,211.96 v1(25.21,211.72)
BQ24737_CSON_1: length 25.9
  TOP w0.381: v4(45.4,61.93) 45.09,61.93 ; 45.09,61.93 45.09,61.09 46.56,59.63 49.07,59.63 49.54,59.16 50.29,58.41 50.29,54.56 48.61,52.88 48.61,50.77 v1(48.85,50.54) ; 45.09,61.93 45.09,62.85 42.42,65.52 41.2,65.52 PG4.1
  BOTTOM w0.381: PC187.1 48.98,52.76 PR234.2 48.97,51.81 PC189.2 49.2,50.89 v1(48.85,50.54)
BQ24737_CSOP_1: length 25
  TOP w0.381: 48.1,51.83 48.1,53.09 49.79,54.77 49.79,58.2 49.19,58.8 48.86,59.12 46.35,59.12 44.58,60.88 44.58,62.64 42.21,65.01 41.2,65.01 PG5.1 ; 48.1,51.83 v4(47.8,51.83) ; 48.1,51.83 48.1,50.75 v1(47.87,50.52)
  BOTTOM w0.381: v1(47.87,50.52) 47.68,50.71 PC189.1 47.87,51.77 PR233.2 PC188.1
BQ24737_REGN: length 25.3
  TOP w0.508: v1(45.5,55.5) 45.13,55.5 44.69,55.05 PC120.2 44.68,54.93 43.28,54.93 PD2.A 43.21,52.72 v1(43.28,52.65)
  L4 w0.508: v1(43.28,52.65) 43.92,52.01 46.43,52.01 48.13,53.71 48.81,53.71 48.88,53.65 49.43,53.65 49.81,54.03 49.81,55.4 50.66,56.24 50.66,60.26 49.51,61.41 48.86,61.41 48.86,61.41 48.84,61.41 v3(48.81,61.44)
  BOTTOM w0.305: v3(48.81,61.44) 48.63,61.62 PR226.1 ; U34.16 46.62,56.39 45.73,55.5 v1(45.5,55.5)
  BOTTOM w0.508: v2(44.83,54.73) 44.83,54.78 45.5,55.45 v1(45.5,55.5)
BT+: length 2
  TOP w0.305: PG4.2 40.34,66.86 v4(40.29,66.9) 40.25,66.94 39.46,66.94
BT+_R:
  vias: v4(39.49,62.45) v5(35.68,63.46) v5(36.54,63.47) v5(37.43,63.45) v5(38.3,63.44) v5(39.2,63.45) v5(40.08,63.46)
BUFRST_N: length 2.7
  TOP w0.305: GPU1.D11 85.5,91.7 v3(85.9,91.3)
  BOTTOM w0.305: v2(86.75,89.59) 86.72,89.59 85.87,90.44 R675.1 85.9,90.55 v3(85.9,91.3)
BUZZER_SPKR_R: length 26.6
  TOP w0.102: v1(153.42,52.63) 152.76,52.63 v4(152.53,52.4) 152.34,52.59 R388.1 ; v1(162.09,34.8) 161.45,34.16 C187.1
  L4 w0.127: v1(153.42,52.63) 153.8,52.63 155.23,51.21 155.23,50.8 156.8,49.23 156.8,37.47 157.69,36.58 159.16,36.58 161.07,34.67 161.96,34.67 v1(162.09,34.8)
BVCCRTC_EXTPAD: length 11.1
  TOP w0.102: CPU1.AG51 v3(83.92,174.1) ; C26.1 84.37,183.07 83.78,182.47 v3(83.78,182.17)
  L4 w0.089: 84.02,180.65 84.31,180.35 84.31,174.49 v3(83.92,174.1)
  L4 w0.127: v3(83.78,182.17) 84.02,181.93 84.02,180.65
  BOTTOM w0.102: v2(83.09,182.4) 83.32,182.17 v3(83.78,182.17)
C_GPP_TXN2: length 5.5
  TOP w0.089: CPU1.L1 76.51,149.97 76.45,149.91 76.45,148.79 74.88,147.22 73.79,147.22
  TOP w0.102: C41.1 73.4,147.03 73.59,147.22 73.79,147.22
C_GPP_TXP2: length 6.9
  TOP w0.089: 73.79,147.43 73.81,147.43 73.82,147.42 73.88,147.42 73.88,147.41 74.8,147.41 76.26,148.87 76.26,149.9 76.22,149.94 76.22,150.33 76.37,150.52 76.43,150.58 CPU1.L2
  TOP w0.102: 73.79,147.43 73.27,147.43 72.58,146.74 C40.1
CAGND: length 27.9
  L3 w0.508: v3(36.81,22.96) 38.08,22.96 39.33,24.21 39.33,29.51 39.94,30.12 v1(39.94,30.15)
  BOTTOM w0.305: U35.15 31.93,30.72 v3(32.93,29.72)
  BOTTOM w0.508: C501.1 39.83,33.2 v1(39.96,33.32) ; R775.2 38.99,27.84 38.99,28.62 C507.2 C504.2 39.63,29.84 v1(39.94,30.15) ; C498.2 36.41,33.96 35.64,33.2 v1(35.64,33.12) ; 31.3,22.83 31.81,22.33 32.62,22.33 34.07,23.78 R786.2 C513.2 36,23.86 R785.2 36.81,23.1 v3(36.81,22.96) ; 31.3,22.83 C515.2 ; 31.3,22.83 31.3,22.52 30.63,21.85 R792.2
  vias: v3(32.16,29.74) v3(32.93,30.48) v3(32.95,29.01) v3(33.69,29.69) v4(34.74,29.83) v4(37.77,32.19)
CBN: length 4.1
  TOP w0.203: v1(160.51,44.65) 160.55,44.69 U16.21
  BOTTOM w0.635: C485.2 159.76,45.77 159.21,45.23 v2(159.21,45.11) 159.21,44.96 159.52,44.65 v1(160.51,44.65)
CBP: length 4.1
  TOP w0.203: v1(162.14,44.7) 161.74,45.09 U16.24
  BOTTOM w0.635: C485.1 162.97,45.77 v2(162.98,45.75) 162.98,45.04 162.64,44.7 v1(162.14,44.7)
CFG: length 6.5
  TOP w0.127: v3(129.57,38.56) 129.57,39.32 128.67,40.22 R423.2 ; U20.23 v1(129.2,36.57)
  L3 w0.127: v3(129.57,38.56) 129.2,38.18 v1(129.2,36.57)
  BOTTOM w0.127: v2(128.79,37.29) 129.2,36.88 v1(129.2,36.57)
CHG_AGND: length 53.1
  TOP w0.305: v1(50.19,66.51) 50.43,66.74 PQ8.4 49.96,67.27 49.64,67.59 49.64,67.94 49.01,68.57 PQ8.1
  TOP w0.508: v1(45.13,66.17) 45.49,66.54 PR144.2 ; v1(54.55,53.89) 54.52,53.92 54.52,57 54.49,57.02 v1(54.49,57.11) 53.96,57.64 53.96,60.53 v1(54.92,61.49) ; PR148.2 49.66,65.95 50.19,66.48 v1(50.19,66.51)
  L3 w0.508: v1(54.55,53.89) 54.55,52.27 54.25,51.96 52.35,51.96 v1(50.93,53.38) 50.28,52.73 v1(45.99,52.73) ; v1(54.92,61.49) 54.92,61.98 55.1,62.15 55.1,62.73 52.46,65.36 51.22,65.36 50.19,66.39 v1(50.19,66.51) 50.15,66.46 45.42,66.46 v1(45.13,66.17)
  BOTTOM w0.305: v1(54.49,57.11) 54.49,57.09 54.24,56.83 PR229.2
  BOTTOM w0.508: v1(50.93,53.38) 50.67,53.64 PC187.2 ; v1(45.13,66.17) 45.11,66.15 PC181.2 ; PC179.2 PR224.2 PC183.2 54.69,61.72 v1(54.92,61.49) ; v2(55.47,53.71) 55.29,53.89 v1(54.55,53.89) ; v1(45.99,52.73) 45.99,53.03 46.6,53.64 PC188.2 ; PC181.2 44.68,64.56 44.26,64.14 44.26,63.4 43.57,62.71 PC186.2 ; PC181.2 PC180.2
CHG_ON#: length 75.7
  TOP w0.102: U14.28 114.66,54.53 113.83,53.7 113.83,53.38 113.72,53.28 113.72,51.82 105.72,43.81 v1(105.32,43.81)
  L4 w0.127: v1(105.32,43.81) 104.86,43.36 102.85,43.36 99.67,46.53 63.94,46.53 56.19,54.28 56.19,55.98 v1(56.22,56.01)
  BOTTOM w0.102: v1(56.22,56.01) 56.26,56.01 56.48,56.23 PQ19.G 55.48,57.99 55.48,58.37 v2(55.5,58.39) 55.5,58.71 PR228.2
CHG_SMB2_CLK: length 132
  TOP w0.203: RN12.3 135.44,54.68 135.19,54.93 U14.70 129.67,54.93
  TOP w0.254: v1(64.67,70.13) 64.47,70.33 64.47,70.36 64.44,70.39 64.44,71.12 68.85,75.53 84.91,75.53 87.12,77.74 88.9,77.74 90.94,79.78 95.84,79.78 97.75,77.86 97.75,75.91 101.65,72.02 104.66,72.02 107.27,69.41 v3(107.27,69.22) ; 129.67,54.93 129.31,54.57 124.87,54.57 123.5,55.94 v1(123.5,56.16)
  L3 w0.254: v1(52.1,57.78) 52.15,57.83 54.64,57.83 55.57,56.9 57.01,56.9 58.2,58.09 58.2,61.56 60.61,63.98 60.61,64.97 64.45,68.8 64.45,69.91 v1(64.67,70.13)
  L4 w0.254: v1(123.5,56.16) 123.35,56.31 123.35,56.38 121.17,58.56 121.17,60.4 119.31,62.26 116.77,62.26 115.07,63.96 115.07,65 113.84,66.23 111.27,66.23 108.75,68.75 108.75,69.19 108.22,69.72 107.78,69.72 v3(107.27,69.22)
  BOTTOM w0.254: v1(52.1,57.78) 51.6,57.28 U34.9 ; R714.1 48.76,71.43 49.18,71.01 50.11,71.01 ; v1(64.67,70.13) 64.66,70.13 63.47,71.32 50.43,71.32 50.11,71.01 ; 50.11,71.01 v2(50.11,71.27)
CHG_SMB2_DATA: length 130.8
  TOP w0.203: 129.81,54.53 U14.69 135.05,54.53 135.55,54.03 RN12.4
  TOP w0.254: v1(122.82,56.16) 122.82,56.09 124.71,54.19 129.47,54.19 129.81,54.53 ; v1(63.86,70.18) 64.06,70.38 64.06,71.28 68.69,75.91 84.76,75.91 86.96,78.12 88.74,78.12 90.78,80.16 95.99,80.16 98.14,78.02 98.14,76.07 101.8,72.4 104.82,72.4 v3(108.01,69.22)
  L3 w0.254: v1(63.86,70.18) 64.07,69.97 64.07,68.96 60.23,65.13 60.23,64.14 57.82,61.72 57.82,58.25 56.85,57.28 55.73,57.28 54.8,58.21 52.57,58.21 v1(52.1,58.67)
  L4 w0.254: v1(122.82,56.16) 122.82,56.37 120.78,58.41 120.78,60.24 119.15,61.87 116.61,61.87 114.69,63.8 114.69,64.84 113.68,65.85 111.11,65.85 108.37,68.6 108.37,68.85 v3(108.01,69.22)
  BOTTOM w0.254: R717.1 48.76,70.39 49.18,70.39 49.41,70.62 v2(55.58,70.62) 55.77,70.82 63.44,70.82 63.86,70.4 v1(63.86,70.18) ; U34.8 51.18,57.78 52.07,58.67 v1(52.1,58.67)
CK_25M_SIO: length 242.7
  TOP w0.102: v1(114.97,69.01) 114.97,66.76 114.56,66.36 114.56,65.06 114.69,64.93 U14.2 ; R98.2 81.4,187.57 v3(81.19,187.78)
  L3 w0.127: v1(147.7,103.25) 154.55,110.1 154.55,121.59 154.53,121.6 154.53,127.23 156.7,129.41 156.7,132.23 160.27,135.8 160.27,140.42 161.37,141.53 161.37,151.16 160.55,151.98 160.55,173.84 160.54,173.85 160.54,174.89 152.83,182.59 152.83,188.1 v1(152.74,188.2)
  L4 w0.127: v1(140.19,82.5) 140.13,82.56 140.13,87.91 144.02,91.8 144.02,99.58 v1(147.7,103.25) ; v3(81.19,187.78) 82.33,188.93 82.33,190.21 92.96,200.84 141.44,200.84 149,193.28 149,192.44 149,191.94 v1(152.74,188.2)
  BOTTOM w0.102: v1(114.97,69.01) 114.97,69.42 115.21,69.66 118.67,69.66 119.4,70.38 119.4,72.35 119.44,72.39 119.44,72.54 120.45,73.56 120.45,75.74 121.29,76.58 124.06,76.58 124.65,77.17 132.52,77.17 132.8,77.44 135.81,77.44 136.37,78.01 136.79,78.01 138.47,79.69 v2(139.49,79.69) 140.13,80.33 140.13,82.44 v1(140.19,82.5)
CK_GLAN_DN: length 191
  TOP w0.102: v1(34.92,20.23) 35.17,19.98 35.17,19.37 35.39,19.15 35.39,17.68 35.21,17.5 U26.16 ; v3(70.8,136.09) 71,135.89 71.22,135.89 71.42,136.1 71.42,138.89 72.45,139.92 72.45,142.83 68.44,146.85 68.44,151.35 70.72,153.63 71.82,153.63 71.83,153.63 CPU1.B8
  L4 w0.127: v3(70.8,136.09) 70.54,135.84 66.99,135.84 65.74,137.09 64.79,137.09 64.39,137.49 61.38,137.49 59.08,135.19 54.67,135.19 51.32,131.84 43.18,131.84 35.31,123.97 35.31,117.95 34.17,116.8 34.17,102.45 35.78,100.83 35.78,91.29 32.47,87.98 32.47,78.1 32.96,77.61 32.96,76.49 26.33,69.87 26.33,55.54 38.12,43.75 38.12,34.45 34.39,30.72 34.39,29.7 30.6,25.92 30.6,20.98 31.21,20.37 34.79,20.37 v1(34.92,20.23)
  BOTTOM w0.102: v2(36,21.51) 35.77,21.29 35.77,21.08 v1(34.92,20.23)
CK_GLAN_DP: length 189.9
  TOP w0.102: CPU1.A7 71.69,153.31 71.58,153.42 70.81,153.42 68.65,151.26 68.65,146.94 72.67,142.92 72.67,139.83 71.64,138.8 71.64,136.01 71.31,135.67 71.19,135.67 v3(70.87,135.36) ; U26.15 35.61,19.24 35.39,19.46 35.39,20.45 34.98,20.85 v1(34.98,21.1)
  L4 w0.127: v3(70.87,135.36) 70.66,135.57 66.88,135.57 65.62,136.82 64.67,136.82 64.28,137.22 61.49,137.22 59.19,134.92 54.78,134.92 51.44,131.57 43.29,131.57 35.58,123.86 35.58,117.84 34.43,116.69 34.43,102.56 36.05,100.94 36.05,91.18 32.74,87.87 32.74,78.21 33.22,77.73 33.22,76.38 26.6,69.76 26.6,55.65 38.39,43.86 38.39,34.34 34.65,30.61 34.65,29.59 30.87,25.81 30.87,21.09 31.32,20.64 34.53,20.64 v1(34.98,21.1)
  BOTTOM w0.102: v2(34.81,21.92) 34.98,21.75 v1(34.98,21.1)
CK_M_DDR0_A_DN: length 63.4
  TOP w0.089: CPU1.BE45 92.77,171.5 v3(92.84,171.5)
  TOP w0.102: v3(134.27,158.17) 134.06,157.95 134.06,157.7 133.8,157.45 132.62,157.45 132.26,157.81 132.08,157.81 131.96,157.68 131.96,157.68 131.83,157.55 DIMM1.103
  L4 w0.127: v3(134.27,158.17) 134.27,158.06 133.56,157.35 131.57,157.35 131.29,157.64 131.29,158.42 131.16,158.55 130.78,158.55 130.66,158.42 130.66,156.59 130.37,156.31 129.77,156.31 129.49,156.59 129.49,158.42 129.36,158.55 128.98,158.55 128.85,158.42 128.85,157.64 128.57,157.35 127.71,157.35 126.44,158.62 126.18,158.88 108.97,176.1 96.33,176.1 94.08,173.84 94.08,172.53 93.4,171.86 93.2,171.86 92.84,171.5 v3(92.84,171.5)
  BOTTOM w0.102: v3(134.27,158.17) 134.68,158.57 v2(134.68,158.8)
CK_M_DDR0_A_DP: length 63.2
  TOP w0.089: CPU1.BD45 v3(92.12,171.57)
  TOP w0.102: DIMM1.101 131.99,158.15 132.11,158.02 132.11,158.02 132.35,158.02 132.71,157.67 133.71,157.67 133.84,157.79 133.84,157.97 133.64,158.17 v3(133.56,158.17)
  L4 w0.127: v3(92.12,171.57) 92.67,172.12 93.29,172.12 93.81,172.64 93.81,173.95 96.22,176.37 109.08,176.37 126.37,159.07 126.63,158.81 127.82,157.62 128.46,157.62 128.59,157.75 128.59,158.53 128.87,158.81 129.47,158.81 129.75,158.53 129.75,156.7 129.88,156.57 130.26,156.57 130.39,156.7 130.39,158.53 130.67,158.81 131.27,158.81 131.56,158.53 131.56,157.75 131.69,157.62 133.45,157.62 133.63,157.8 133.63,158.1 v3(133.56,158.17)
  BOTTOM w0.102: v3(92.12,171.57) 91.8,171.6 91.42,171.65 v2(91.4,171.65)
CK_M_DDR1_A_DN: length 62.4
  TOP w0.102: CPU1.BD48 91.7,172.78 92.03,173.11 v3(92.03,173.13) ; v3(137.22,157.1) 136.89,157.42 136.89,157.67 137.02,157.79 137.93,157.79 138.21,157.51 138.53,157.51 138.79,157.25 DIMM1.104
  L4 w0.127: v3(137.22,157.1) 136.89,157.43 136.89,158.09 135.26,159.72 127,159.72 126.94,159.78 126.88,159.84 126.18,160.54 109.36,177.36 101.11,177.36 100.9,177.14 96.1,177.14 93.15,174.19 93.15,172.87 92.9,172.62 91.98,172.62 91.8,172.8 91.8,172.9 v3(92.03,173.13)
  BOTTOM w0.102: v2(137.52,157.78) 137.22,157.48 v3(137.22,157.1)
CK_M_DDR1_A_DP: length 62.4
  TOP w0.102: DIMM1.102 138.79,157.85 138.67,157.73 138.3,157.73 138.02,158.01 136.93,158.01 136.68,157.76 136.68,157.36 v3(136.47,157.15) ; v3(91.32,173.13) 91.32,173.11 90.99,172.78 CPU1.BB48
  L4 w0.127: v3(91.32,173.13) 91.53,172.92 91.53,172.7 91.87,172.35 93.01,172.35 93.41,172.76 93.41,174.08 96.21,176.87 101.01,176.87 101.23,177.09 109.25,177.09 126,160.35 126.69,159.65 126.89,159.45 135.15,159.45 135.63,158.97 136.62,157.98 136.62,157.3 v3(136.47,157.15)
  BOTTOM w0.102: v2(136.2,157.84) 136.47,157.56 v3(136.47,157.15)
CK_PCIEX1_WLAN_DN: length 102.2
  TOP w0.089: 71,152.78 71.93,152.78 CPU1.B5
  TOP w0.102: v3(70.35,151.22) 70.15,151.42 70.15,151.93 71,152.78 ; v1(101.69,213.05) 101.2,213.54 101.2,215.36 101.72,215.88 103.12,215.88 103.39,216.15 R33.2
  L4 w0.127: v1(101.69,213.05) 101.59,213.15 98.89,213.15 98.59,213.46 89.4,213.46 76.3,200.36 70.87,200.36 67.58,197.07 67.58,194.99 66.84,194.24 66.84,185.12 67.66,184.29 67.66,170.52 66.99,169.85 66.99,163.27 65.69,161.97 65.69,154.5 66.81,153.38 69.42,153.38 70.35,152.45 v3(70.35,151.22)
  BOTTOM w0.102: v2(100.16,213.16) 101.38,213.16 101.5,213.05 v1(101.69,213.05)
CK_PCIEX1_WLAN_DP: length 101.9
  TOP w0.089: 70.89,152.97 70.91,153 71.09,153 71.12,152.97 72.01,152.97 72.01,152.97 72.22,152.97 CPU1.B7
  TOP w0.102: v1(101.71,213.96) 101.41,214.26 101.41,215.27 101.81,215.67 102.96,215.67 103.49,215.14 R36.2 ; 70.89,152.97 69.94,152.02 69.94,151.58 v3(69.62,151.26)
  L4 w0.127: v3(69.62,151.26) 69.62,151.6 69.79,151.78 69.99,151.78 70.09,151.88 70.09,152.34 69.31,153.11 66.7,153.11 65.42,154.39 65.42,162.08 66.72,163.38 66.72,169.96 67.39,170.63 67.39,184.18 66.57,185.01 66.57,194.35 67.32,195.1 67.32,197.18 70.76,200.62 76.19,200.62 89.29,213.72 98.7,213.72 99.01,213.42 101.33,213.42 101.71,213.79 v1(101.71,213.96)
  BOTTOM w0.102: v1(101.71,213.96) 101.09,214.58 v2(101.09,214.91)
CK_PE_100M_16PORT_DN: length 101.9
  TOP w0.102: CPU1.B11 71.97,155.27 71.94,155.3 69.12,155.3 67.35,153.52 67.35,152.19 67.25,152.09 63.95,152.09 63.7,151.84 63.7,151.3 63.95,151.05 67.25,151.05 67.35,150.95 67.35,150.54 67.25,150.44 65.63,150.44 65.37,150.19 65.37,149.65 65.63,149.4 67.25,149.4 67.35,149.3 67.35,146.4 70.24,143.51 70.24,140.01 v3(70.21,139.98) ; GPU1.AD8 87.97,108.3 v3(88.37,107.9)
  BOTTOM w0.102: v3(70.21,139.98) 70.56,140.33 70.56,140.53 70.78,140.75 81.24,140.75 81.9,140.1 82.04,140.1 85.25,143.3 85.61,143.3 85.99,142.93 85.99,142.57 82.78,139.36 82.78,139.21 90.01,131.98 90.01,125.76 91.69,124.08 91.69,122.86 91.46,122.63 90.09,122.63 89.99,122.53 89.99,122.13 90.09,122.02 91.46,122.02 91.69,121.8 91.69,113.64 91.79,113.54 93.77,113.54 94.03,113.28 94.03,112.75 93.77,112.5 91.79,112.5 91.69,112.39 91.69,111.99 91.79,111.89 93.04,111.89 93.29,111.63 93.29,111.1 93.04,110.85 91.79,110.85 91.69,110.74 91.69,109.26 90.29,107.86 88.91,107.86 88.84,107.92 88.4,107.92 v3(88.37,107.9)
CK_PE_100M_16PORT_DP: length 101.9
  TOP w0.102: v3(88.37,108.7) 88.36,108.7 GPU1.AE8 ; v3(70.95,140.02) 70.45,140.51 70.45,143.6 67.56,146.49 67.56,149.39 67.34,149.61 65.72,149.61 65.59,149.74 65.59,150.1 65.72,150.22 67.34,150.22 67.56,150.45 67.56,151.04 67.34,151.26 64.04,151.26 63.91,151.39 63.91,151.75 64.04,151.87 67.34,151.87 67.56,152.1 67.56,153.43 69.21,155.08 71.85,155.08 71.95,154.97 72.2,154.97 72.46,155.19 72.76,155.19 CPU1.C11
  BOTTOM w0.102: v3(70.95,140.02) 70.77,140.2 70.77,140.44 70.87,140.54 81.15,140.54 81.81,139.88 82.13,139.88 85.34,143.09 85.52,143.09 85.77,142.84 85.77,142.66 82.56,139.45 82.56,139.12 89.8,131.89 89.8,125.67 91.47,123.99 91.47,122.95 91.37,122.85 90,122.85 89.77,122.62 89.77,122.04 90,121.81 91.37,121.81 91.47,121.71 91.47,113.55 91.7,113.32 93.68,113.32 93.81,113.2 93.81,112.84 93.68,112.71 91.7,112.71 91.47,112.48 91.47,111.9 91.7,111.67 92.95,111.67 93.07,111.54 93.07,111.19 92.95,111.06 91.7,111.06 91.47,110.83 91.47,109.35 90.2,108.08 88.99,108.08 88.9,108.17 88.9,108.57 88.77,108.7 v3(88.37,108.7)
CLINK_CLK_LAN: length 3.3
  TOP w0.102: TP11.1 120.31,215 NGFF1.42
CLINK_DATA_LAN: length 4.9
  TOP w0.102: NGFF1.40 120.06,214.5 121.1,213.46 121.85,213.46 TP14.1
CLINK_RST_LAN_N: length 3.4
  TOP w0.102: TP13.1 120.04,214 NGFF1.38
CLKA0: length 48.1
  TOP w0.127: v3(55.61,87.45) 55.5,87.56 55.07,87.56 54.82,87.81 54.82,88.86 54.71,88.98 54.57,88.98 54.4,88.81 VRAM2.J7 ; v3(75.13,91.31) 75.09,91.31 GPU1.D24
  L4 w0.127: v1(49.63,87.07) 49.89,87.33 50.42,87.33 51.08,87.99 51.08,88.74 51.88,89.54 54.17,89.54 54.47,89.24 54.47,88.05 54.79,87.73 55.33,87.73 v3(55.61,87.45)
  L4 w0.152: v3(55.61,87.45) 55.81,87.65 56.24,87.65 57.55,88.96 57.55,89.43 57.68,89.56 58.29,89.56 58.57,89.84 58.57,90.5 58.72,90.65 59.01,90.65 59.16,90.5 59.16,88.5 59.51,88.16 60.27,88.16 60.65,88.53 60.65,88.99 60.73,89.08 60.73,89.09 61.01,89.37 61.01,89.83 60.39,90.45 60.39,90.61 60.76,90.99 60.92,90.99 61.39,90.51 61.52,90.39 61.77,90.14 61.77,88.96 62.03,88.7 62.48,88.7 63.28,89.5 71.9,89.5 72.54,90.15 72.54,90.67 72.77,90.9 73.17,90.9 73.34,90.73 73.34,90.34 73.59,90.09 74.02,90.09 74.47,90.55 74.47,91.24 74.69,91.46 74.98,91.46 v3(75.13,91.31)
  BOTTOM w0.127: v1(49.63,87.07) 49.56,87 47.96,87 R686.1 ; v3(55.61,87.45) 56.08,87.92 56.44,87.92 57.34,88.82 57.51,88.82 57.6,88.72 VRAM4.J7
CLKA0#: length 48
  TOP w0.127: v3(55.57,88.18) 55.57,88.05 55.34,87.82 55.18,87.82 55.08,87.92 55.08,88.97 54.81,89.23 54.54,89.23 54.4,89.37 VRAM2.K7 ; v3(74.3,92.13) 73.9,91.73 GPU1.D25
  L4 w0.127: v3(55.57,88.18) 55.35,87.96 54.88,87.96 54.7,88.15 54.7,89.33 54.26,89.77 51.78,89.77 50.85,88.83 50.85,88.08 50.32,87.56 49.88,87.56 v1(49.61,87.83)
  L4 w0.152: v3(74.3,92.13) 74.43,92.13 74.59,91.96 74.59,91.79 74.17,91.37 74.17,90.67 73.89,90.39 73.72,90.39 73.64,90.47 73.64,90.86 73.3,91.2 72.64,91.2 72.24,90.8 72.24,90.27 71.77,89.81 63.15,89.81 62.35,89.01 62.15,89.01 62.07,89.09 62.07,90.27 61.05,91.29 60.63,91.29 60.08,90.74 60.08,90.33 60.71,89.7 60.71,89.5 60.43,89.22 60.43,89.2 60.34,89.12 60.34,88.66 60.15,88.46 59.63,88.46 59.47,88.63 59.47,90.62 59.14,90.95 58.59,90.95 58.26,90.62 58.26,89.96 58.16,89.86 57.55,89.86 57.24,89.55 57.24,89.08 56.11,87.95 55.8,87.95 v3(55.57,88.18)
  BOTTOM w0.127: R683.1 R684.2 49.55,87.88 v1(49.61,87.83) ; v3(55.57,88.18) 55.9,88.18 55.92,88.17 56.33,88.17 57.23,89.07 57.44,89.07 57.6,89.24 VRAM4.K7
CLKA0_AND: length 3.3
  BOTTOM w0.102: R683.2 R686.2 C450.1 45.73,86.61 45.73,85.63 v2(45.69,85.63)
CLKA1: length 50.7
  TOP w0.127: VRAM1.J7 57.03,111.17 56.71,111.17 56.33,111.54 55.87,111.54 v3(55.51,111.18) ; R261.1 47.79,108.66 R259.1 49.61,108.66 v1(49.66,108.71) ; v3(76.76,99.59) 76.34,99.17 GPU1.N22
  L4 w0.127: v1(49.66,108.71) 49.91,108.96 50.26,108.96 50.54,109.24 53.21,109.24 55.15,111.18 v3(55.51,111.18)
  L4 w0.152: v3(76.76,99.59) 76.76,98.85 76.46,98.55 75.35,98.55 75.12,98.77 73.79,98.77 73.61,98.59 73.61,98.44 73.28,98.1 72.75,98.1 72.42,98.44 72.42,99.11 72.22,99.31 70.05,99.31 69.68,99.68 66.82,99.68 61.68,104.82 57.31,104.82 56.98,105.15 56.98,105.72 57.31,106.05 57.89,106.05 58.04,106.2 58.04,106.51 57.89,106.67 57.35,106.67 57.02,106.99 57.02,107.46 57.35,107.78 57.84,107.78 58,107.94 58,108.25 57.84,108.4 57.37,108.4 57.04,108.73 57.04,109.32 57.37,109.65 57.81,109.65 57.96,109.8 57.96,110.11 57.81,110.26 57.33,110.26 57.25,110.34 55.98,110.34 55.59,110.73 55.59,111.09 v3(55.51,111.18)
  BOTTOM w0.127: v3(55.51,111.18) 55.69,111 55.69,110.51 55.29,110.11 54.62,110.11 54.4,110.33 VRAM3.J7
CLKA1#: length 51.7
  TOP w0.127: VRAM1.K7 57.79,109.99 57.79,110.13 57.68,110.23 57.35,110.23 57.23,110.36 57.23,110.62 56.93,110.91 56.6,110.91 56.42,111.09 v3(56.14,111.09) ; v3(75.94,99.59) 75.94,98.76 GPU1.M22 ; v1(49.61,109.47) 49.53,109.55 R259.2 47.81,109.55 R257.1
  L4 w0.127: v3(56.14,111.09) 56.14,111.17 55.69,111.62 55.27,111.62 53.12,109.47 50.44,109.47 50.16,109.19 49.89,109.19 v1(49.61,109.47)
  L4 w0.152: v3(56.14,111.09) 56.11,111.09 55.99,110.97 55.99,110.76 56.11,110.64 57.38,110.64 57.45,110.56 57.94,110.56 58.27,110.23 58.27,109.67 57.94,109.34 57.5,109.34 57.35,109.19 57.35,108.86 57.5,108.71 57.97,108.71 58.3,108.38 58.3,107.81 57.97,107.48 57.47,107.48 57.32,107.33 57.32,107.12 57.47,106.97 58.02,106.97 58.35,106.64 58.35,106.08 58.02,105.75 57.43,105.75 57.28,105.59 57.28,105.28 57.43,105.13 61.81,105.13 66.95,99.99 69.81,99.99 70.18,99.61 72.35,99.61 72.72,99.24 72.72,98.56 72.87,98.41 73.15,98.41 73.3,98.56 73.3,98.71 73.66,99.07 75.25,99.07 75.47,98.85 76.33,98.85 76.45,98.97 76.45,99.28 76.15,99.59 v3(75.94,99.59)
  BOTTOM w0.127: v3(56.14,111.09) 55.94,110.9 55.94,110.4 55.4,109.86 54.62,109.86 54.56,109.8 VRAM3.K7
CLKA1_AND: length 3.2
  TOP w0.102: v4(45.55,110.54) 45.87,110.22 C77.1 46.76,109.53 R257.2 R261.2
CORE_PLLVDD: length 7.8
  TOP w0.356: v3(90.07,97.94) 89.66,97.53 GPU1.L6
  BOTTOM w0.508: L22.2 C411.1 93.95,97.24 C416.1 v2(91.5,97.24) 91.31,97.05 C417.1 90.07,97.25 v3(90.07,97.94)
CPU_FAN_CTRL_SIO: length 307
  TOP w0.165: v1(128.48,57.88) 128.48,58.27 129.54,59.33 U14.81 ; R79.1 15.41,200.9 12.69,203.62 10.36,203.62 v1(10,203.26)
  L3 w0.165: v1(108.57,34.7) 108.57,34.69 107.08,33.2 103.31,33.2 102.18,32.07 99.99,32.07 99.17,32.89 98.31,32.89 93.66,37.54 88.96,37.54 85.71,40.79 85.71,43.31 83.12,45.9 60.74,45.9 58.66,47.98 34.53,47.98 27.87,54.64 27.87,69.29 32.86,74.28 32.86,77.36 31.86,78.36 31.86,129.56 31.13,130.29 31.13,132.66 28.46,135.33 20.51,135.33 15.01,140.84 15.01,173.23 12.51,175.73 12.51,182.34 9.25,185.6 9.25,202.52 v1(10,203.26)
  L4 w0.165: v1(108.57,34.7) 108.91,34.36 112.65,34.36 116.77,38.48 121.98,38.48 125.97,42.46 125.97,43.66 128.11,45.8 128.11,48.58 127.7,48.99 127.7,56.63 128.51,57.43 128.51,57.86 v1(128.48,57.88)
  BOTTOM w0.165: v1(128.48,57.88) 128.53,57.83 v2(128.53,57)
CPU_FAN_TACH_SIO: length 281.3
  TOP w0.165: v1(10.09,202.19) 10.47,202.56 13.04,202.56 15.35,200.25 17.69,200.25 18.32,200.89 18.32,201.65 v4(18.83,202.16) 18.87,202.16 19.03,202.32 R76.1 ; U14.31 114.69,53.33 114.45,53.1 114.45,49.82 113.27,48.64 111.73,48.64 107.25,44.16 107.25,44 v1(107.19,43.94)
  L3 w0.165: v1(10.09,202.19) 9.67,201.77 9.67,185.81 12.93,182.56 12.93,175.9 15.43,173.4 15.43,141.01 20.67,135.76 28.63,135.76 31.55,132.85 31.55,130.46 32.29,129.72 32.29,120.32 33.47,119.15 33.47,117.23 33.24,117 33.24,108.6 33.67,108.16 33.67,97.4 33.01,96.74 33.01,79.22 33.97,78.26 33.97,73.28 28.99,68.3 28.99,55.09 34.98,49.1 59.11,49.1 61.2,47.02 83.65,47.02 86.82,43.84 86.82,41.25 89.42,38.66 97.11,38.66 103.7,45.24 105.26,45.24 106.26,44.25 106.89,44.25 v1(107.19,43.94)
CPU_HPD: length 40.5
  TOP w0.102: v3(77.57,171.55) 77.57,171.86 77.55,171.88 77.55,172.32 CPU1.P48 ; R179.1 59.29,149.66 Q10.D 59.29,147.4 59.32,147.37 v1(59.32,147.17)
  L3 w0.127: v1(59.32,147.17) 61.15,149 62.45,149 69.87,156.42 72.12,156.42 76,160.3 76,163.2 79.27,166.46 79.27,167.04 79.02,167.28 78.91,167.28 78.59,167.61 78.59,169.46 78.65,169.53 78.65,169.87 78.3,170.21 77.98,170.21 77.57,170.62 v3(77.57,171.55)
  BOTTOM w0.102: v1(59.32,147.17) 59.32,146.63 59.31,146.62 v2(59.31,146.34)
CPU_LVDS_BL_ADJ: length 93.5
  TOP w0.165: v1(41.35,137.8) 41.26,137.8 38.76,135.3 v4(38.76,115.46) 39.42,115.46 R233.1 ; R149.2 58.72,174.15 v3(58.64,174.23) 58.64,174.51 59.24,175.11 R142.1 ; R136.2 v3(58.63,177.67)
  L3 w0.165: v1(63.94,146.56) 63.76,146.56 63.65,146.67 61,146.67 60.5,146.17 58.65,146.17 57.68,147.14 46.97,147.14 41.35,141.51 v1(41.35,137.8)
  L4 w0.165: v1(63.94,146.56) 63.38,147.12 63.38,148.52 55.36,156.54 55.36,159.35 57.14,161.12 57.14,169.45 58.64,170.95 v3(58.64,174.23) 58.63,174.25 v3(58.63,177.67)
CPVEE: length 2.9
  TOP w0.203: U16.20 160.14,45.03 159.98,44.86 159.98,44.63 159.9,44.55
  TOP w0.305: 159.9,44.55 159.7,44.35 v4(159.7,44.04) C167.1
CX_PMODE_PLRST_N: length 9.9
  TOP w0.102: v1(32.4,209.5) 32.89,209.02 32.89,207.44 32.36,206.91 31.06,206.91 30.65,206.49 XDP1.7
  BOTTOM w0.102: v1(32.4,209.5) v2(31.21,209.5) 30.34,209.5 R541.2
DACA_VREF: length 6.6
  TOP w0.152: 94.52,109.5 93.3,109.5 GPU1.AE2
  TOP w0.508: 94.52,109.5 94.75,109.73 v4(96.63,109.73) 96.96,110.06 98.65,110.06 C76.1
DBG0: length 75.8
  TOP w0.102: R55.1 31.99,207.72 31.73,207.47 v1(30.91,207.47) ; CPU1.A38 71.07,167.78 70.63,167.34 v3(70.63,167.3)
  L3 w0.127: v3(70.63,167.3) 69.99,167.95 68.93,167.95 68.89,167.91 66.38,167.91 65.43,168.86 52.97,168.86 48.09,173.74 48.09,178.79 43.45,183.43 34.81,183.43 30.82,187.41 30.82,187.73 29.84,188.71 29.84,193.67 30.54,194.37 30.54,207.14 30.87,207.47 v1(30.91,207.47)
  BOTTOM w0.102: v1(30.91,207.47) 30.91,207.47 v2(30.91,208.27)
DBG1: length 90.9
  TOP w0.102: XDP1.19 27.31,209.49 26.79,210.01 v1(26.79,210.02) ; v3(70.35,165.14) 70.83,165.62 71.93,165.62 CPU1.B33
  L3 w0.127: v3(70.35,165.14) 70.01,164.8 67.24,164.8 64.45,167.59 52.44,167.59 50.35,169.67 30.03,169.67 24.93,174.78 24.93,198.38 26.18,199.63 26.18,208.41 26.79,209.02 v1(26.79,210.02)
  BOTTOM w0.102: v2(26.04,210.01) 26.17,210.01 26.18,210.02 v1(26.79,210.02)
DBG2: length 79.1
  TOP w0.089: v3(70.39,168.86) 70.82,168.44 71.84,168.44 71.97,168.53 72.21,168.53 72.56,168.24 CPU1.C39
  TOP w0.102: XDP1.21 30.53,209.99 31.09,210.55 v1(31.35,210.55)
  L3 w0.127: v3(70.39,168.86) 69.99,169.27 69.22,169.27 68.95,168.99 66.89,168.99 65.22,170.67 62.46,170.67 61.94,170.15 54,170.15 53.52,170.64 53.52,171.32 53.24,171.59 53.08,171.59 49.1,175.57 49.1,179.21 46.11,182.21 46.11,182.26 43.88,184.49 35.19,184.49 31.84,187.84 31.84,188.24 31.84,188.24 31.84,202.51 32.33,203 32.33,208.01 31.35,208.99 v1(31.35,210.55)
  BOTTOM w0.102: v2(30.57,210.55) 30.57,210.55 v1(31.35,210.55)
DBG3: length 79.7
  TOP w0.089: 70.07,168.47 70.38,168.17 71.37,168.17 71.44,168.24 CPU1.B39
  TOP w0.102: 70.07,168.47 v3(69.68,168.86) ; v1(31.34,211.35) 31.25,211.35 30.39,210.49 XDP1.23
  L3 w0.127: v3(69.68,168.86) 69.12,168.86 69,168.73 66.79,168.73 65.11,170.41 62.56,170.41 62.05,169.9 53.61,169.9 48.85,174.66 48.85,179.11 45.86,182.1 45.86,182.15 43.78,184.23 35.08,184.23 31.58,187.73 31.58,188.13 31.58,188.14 31.58,202.62 32.07,203.11 32.07,207.9 30.88,209.1 30.88,210.89 v1(31.34,211.35)
  BOTTOM w0.102: v1(31.34,211.35) 31.34,211.35 v2(30.82,211.87)
DBG4: length 87
  TOP w0.102: XDP1.25 30.42,210.99 30.6,211.18 30.6,211.95 v1(31.39,212.73) ; v3(69.97,167.31) 69.97,166.89 70.35,166.51 71.97,166.51 CPU1.B35
  L3 w0.127: v1(31.39,212.73) 30.89,212.73 30.06,211.89 30.06,208.74 30.07,208.73 30.07,202.15 29.23,201.31 29.23,186.98 30.15,186.06 30.15,186.06 30.94,185.26 30.94,184.1 31.62,183.42 32.82,183.42 33.25,183.85 33.93,183.85 34.61,183.17 43.34,183.17 47.83,178.68 47.83,173.64 52.86,168.6 65.33,168.6 66.27,167.66 68.95,167.66 69.02,167.73 69.55,167.73 v3(69.97,167.31)
  BOTTOM w0.102: v1(31.39,212.73) v2(31.39,213.52)
DBG5: length 91.4
  TOP w0.102: v3(69.64,165.2) 70.36,165.93 CPU1.A34 ; XDP1.27 27.28,211.49 v1(26.79,211)
  L3 w0.127: v3(69.64,165.2) 67.27,165.2 64.64,167.84 52.54,167.84 50.45,169.93 30.14,169.93 25.18,174.88 25.18,198.27 26.43,199.52 26.43,208.3 27.26,209.13 27.26,210.53 v1(26.79,211)
  BOTTOM w0.102: v1(26.79,211) 26.45,211 26.14,211.31 v2(26.14,211.48)
DBG6: length 96.3
  TOP w0.102: XDP1.29 27.61,211.99 27.26,212.34 27.26,212.75 v1(26.79,213.22) ; CPU1.B31 70.92,164.54 v3(69.55,163.17)
  L3 w0.127: v3(69.55,163.17) 68.01,163.17 67.56,162.72 59.7,162.72 55.26,167.17 52.22,167.17 50.22,169.16 30.18,169.16 24.67,174.67 24.67,198.6 25.93,199.85 25.93,212.36 v1(26.79,213.22)
  BOTTOM w0.102: v1(26.79,213.22) 27.39,213.22 27.39,213.23 v2(27.54,213.23)
DBG7: length 88.4
  TOP w0.102: v1(31.72,215.5) 32.61,216.4 33.52,216.4 33.74,216.62 RN1.3 34.78,216.94 v4(34.81,216.97) ; CPU1.H39 75.01,168.24 v3(74.59,167.83)
  L3 w0.127: v3(74.59,167.83) 74.2,167.44 72.73,167.44 71.72,168.45 66.71,168.45 66.68,168.48 65.7,169.46 53.69,169.46 48.6,174.55 48.6,179 43.62,183.98 34.98,183.98 31.33,187.63 31.33,188.03 31.33,188.03 31.33,202.73 31.82,203.22 31.82,207.8 30.63,208.99 30.63,211.3 31.15,211.82 31.5,211.82 32.11,212.43 32.11,213.74 31.72,214.13 v1(31.72,215.5)
DBG7_R: length 7.4
  TOP w0.102: XDP1.31 30.46,212.49 33.05,215.09 33.53,215.09 33.74,215.3 RN1.2 34.7,215.74 v4(34.82,215.62)
DBG16: length 91.6
  TOP w0.102: v3(70.37,163.17) 70.81,163.61 CPU1.B29 ; v1(31.69,216.28) 31.69,216.35 32.28,216.94 RN1.4
  L3 w0.127: v3(70.37,163.17) 70.37,163.32 71.7,164.66 71.7,167.44 70.97,168.16 66.49,168.16 65.54,169.11 53.68,169.11 48.34,174.45 48.34,178.89 43.51,183.72 34.87,183.72 31.08,187.52 31.08,187.92 31.07,187.92 31.07,202.83 31.56,203.32 31.56,207.59 30.37,208.79 30.37,211.4 31.04,212.07 31.39,212.07 31.86,212.54 31.86,213.38 31.25,213.99 31.25,215.84 v1(31.69,216.28)
  BOTTOM w0.102: v2(30.92,216.06) 31.14,216.28 v1(31.69,216.28)
DBG16_R: length 5.4
  TOP w0.102: XDP1.33 30.19,212.99 31.33,214.12 v4(31.33,214.55) 31.56,214.55 32.75,215.74 RN1.1
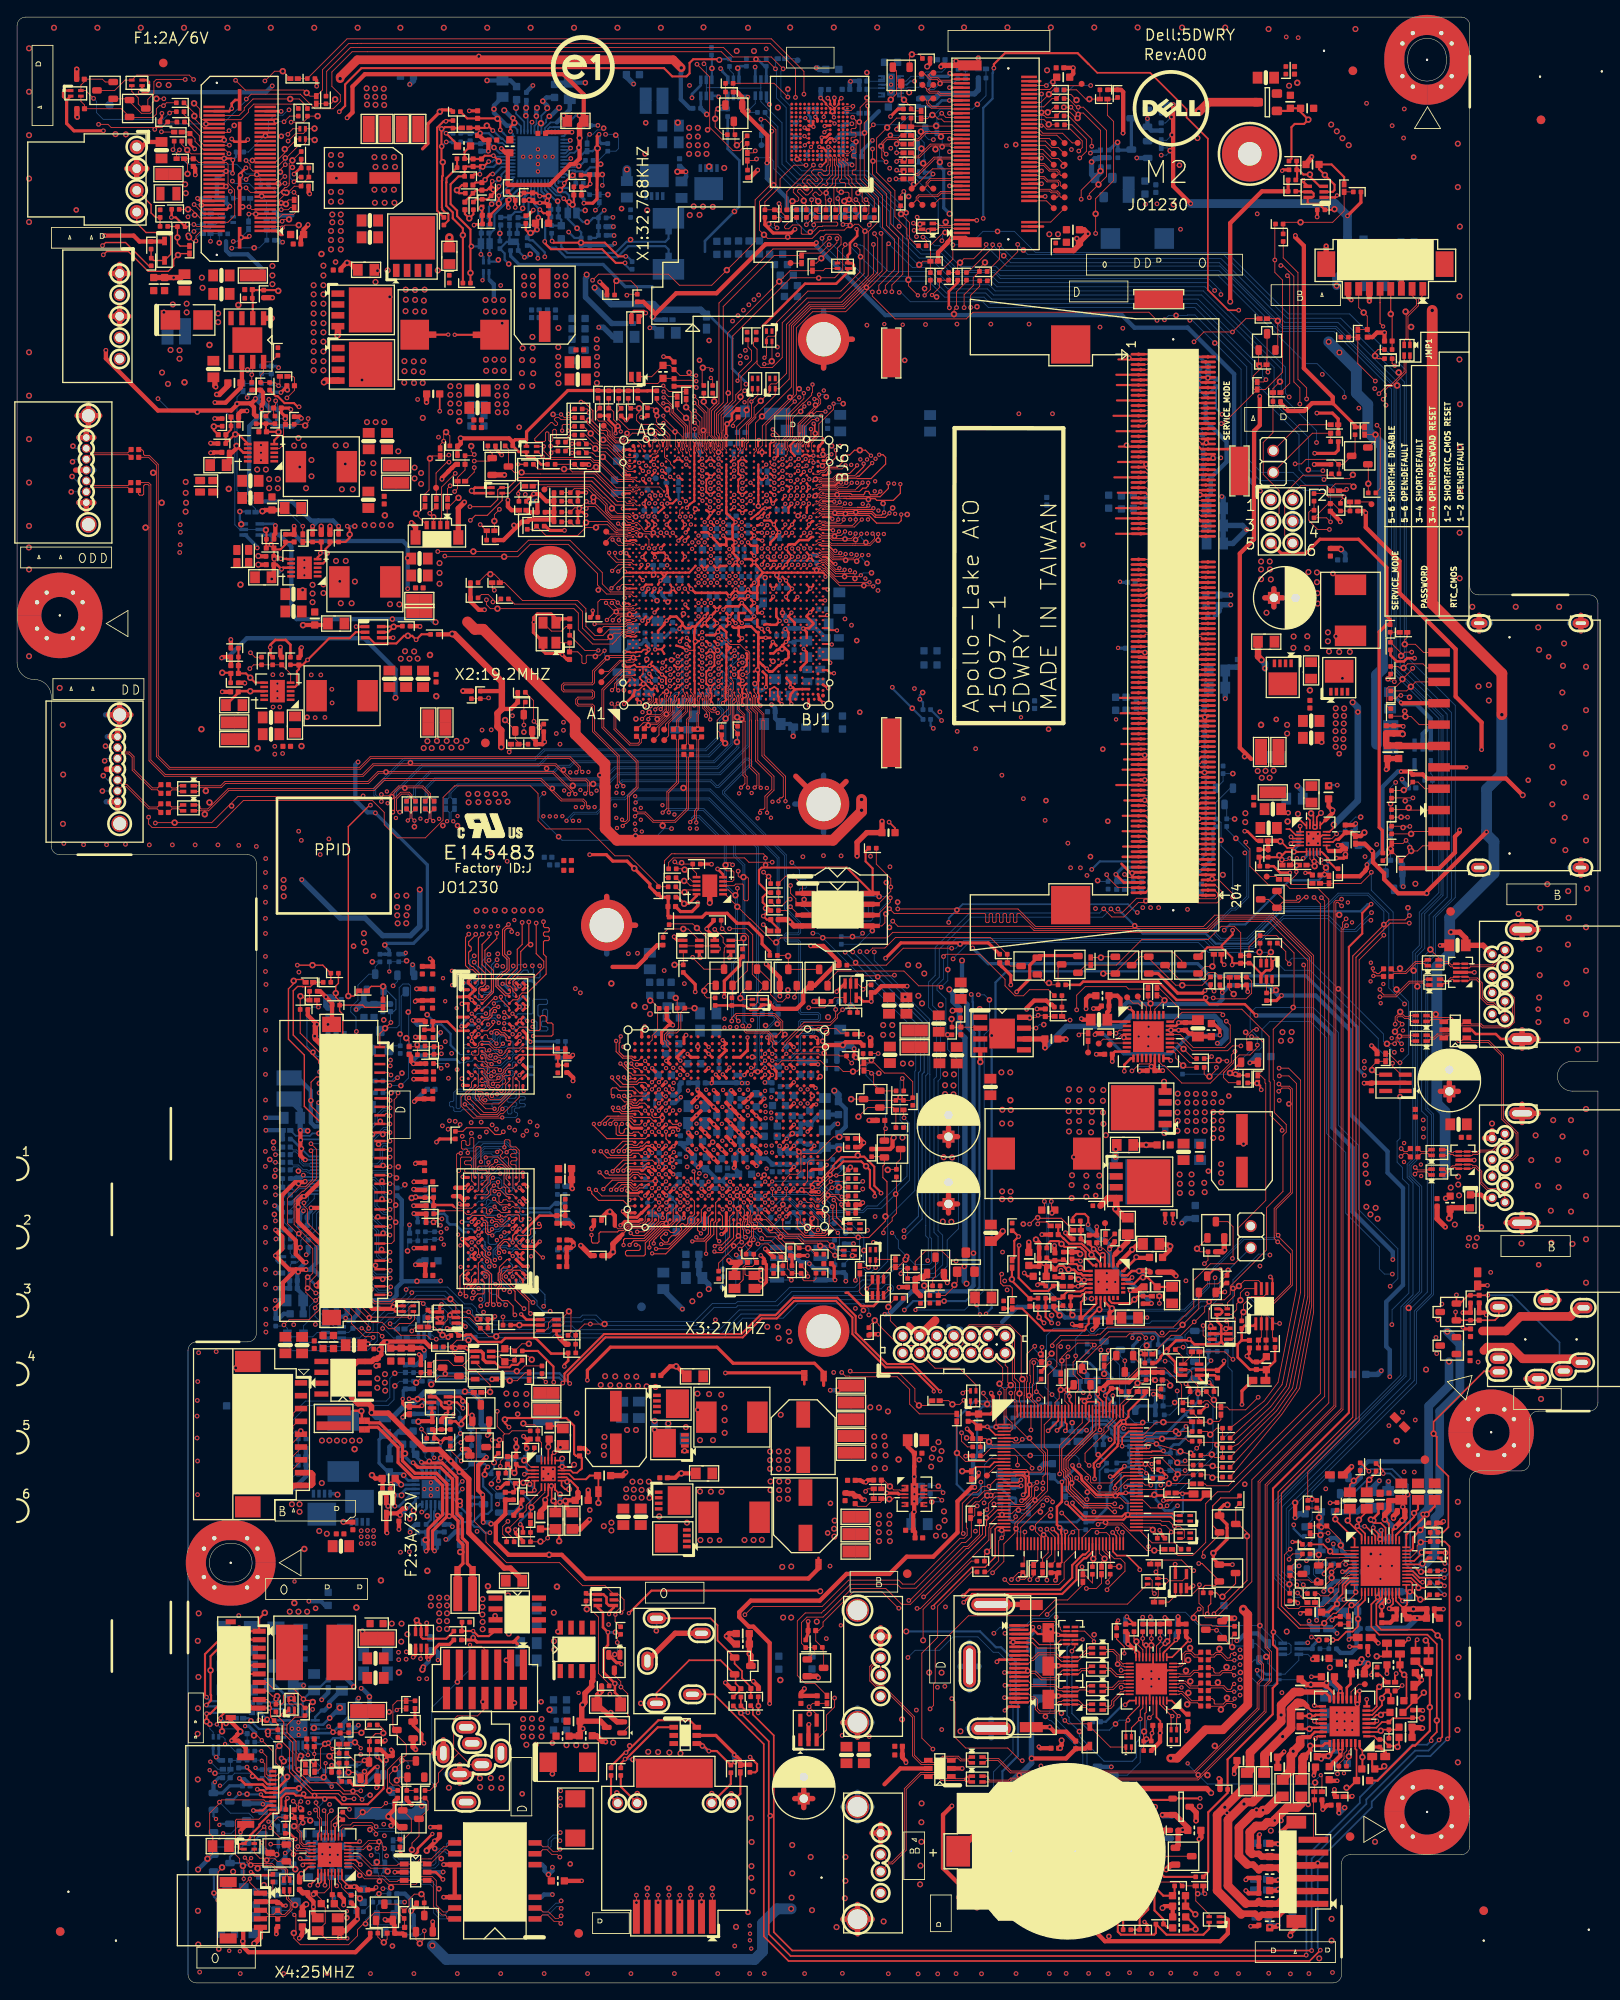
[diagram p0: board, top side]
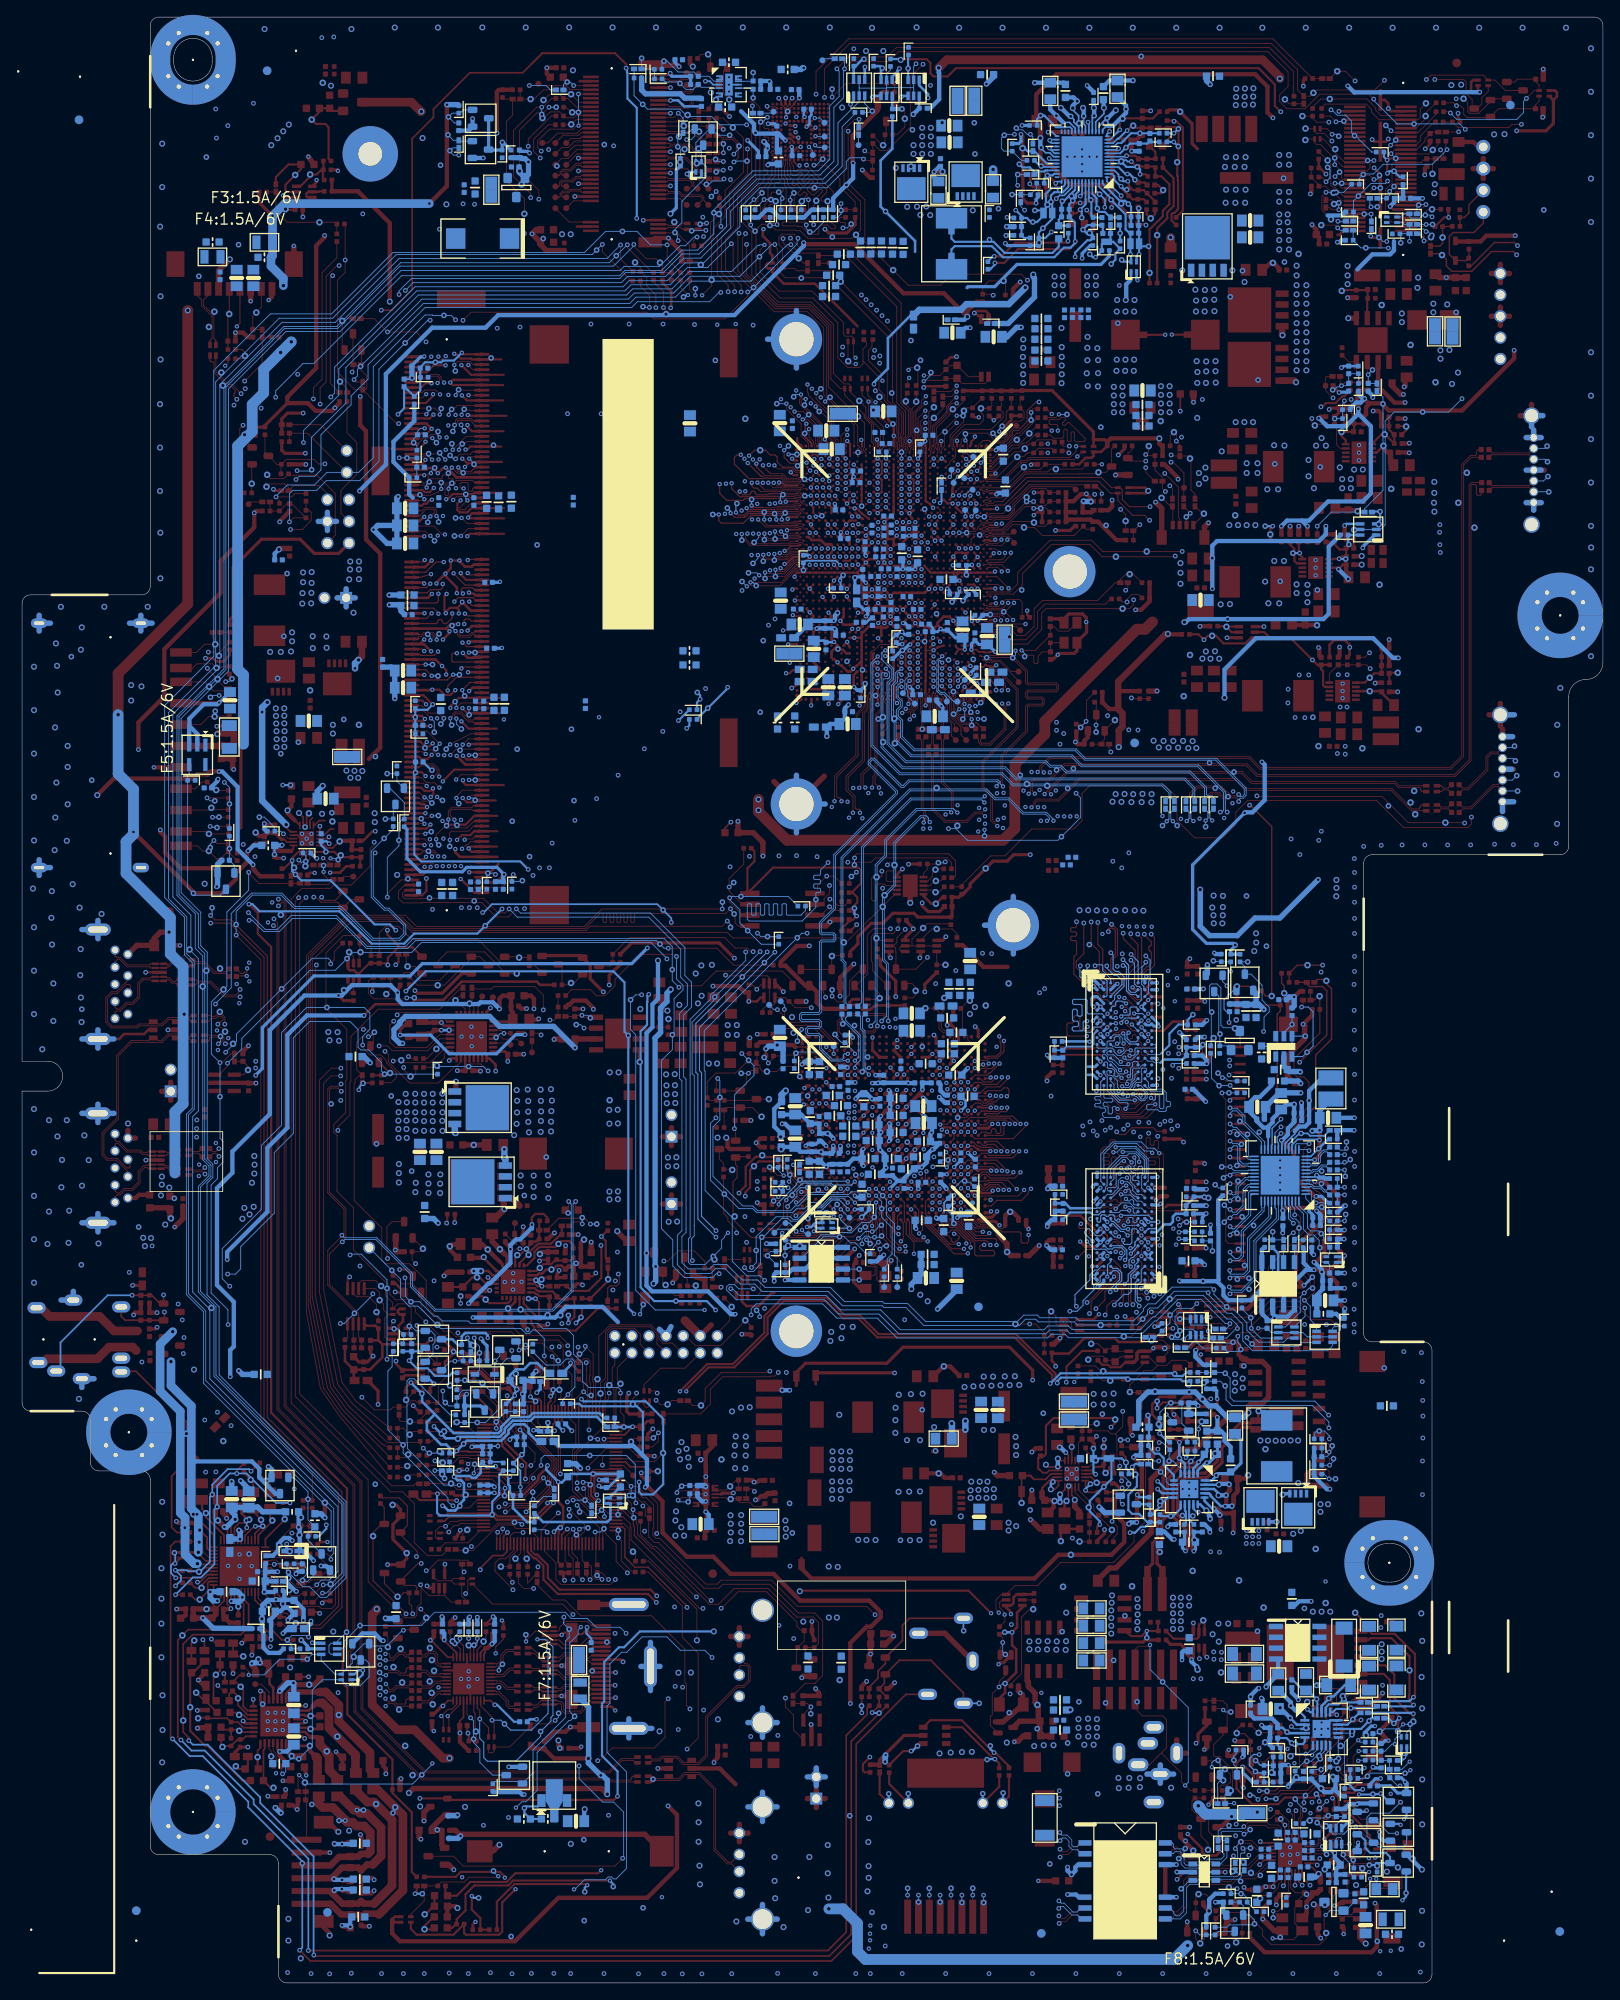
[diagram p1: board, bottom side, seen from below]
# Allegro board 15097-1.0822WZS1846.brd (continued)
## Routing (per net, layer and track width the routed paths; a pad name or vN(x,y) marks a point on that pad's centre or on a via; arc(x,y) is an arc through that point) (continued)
DBG_H_PRDY_N: length 3.8
  TOP w0.102: XDP1.11 27.44,207.49 v1(27.14,207.8)
  BOTTOM w0.102: v2(26.4,207.8) v1(27.14,207.8) 27.27,207.94 R544.2
DBG_H_PREQ_N: length 4.8
  TOP w0.102: XDP1.10 21.8,206.99 v1(20.71,208.07)
  BOTTOM w0.102: R556.1 21.76,207.81 v2(21.56,208.01) 21.5,208.07 v1(20.71,208.07)
DBG_H_TCK: length 5.2
  TOP w0.102: v4(32.96,205.66) 31.36,205.66 v1(31.04,205.35) 30.9,205.49 XDP1.3
  BOTTOM w0.102: v1(31.04,205.35) 30.76,205.06 R563.2
DBG_H_TDI: length 3.9
  TOP w0.102: XDP1.5 30.9,205.99 v1(31.01,206.11) 31.24,206.34 v4(31.83,206.34)
  BOTTOM w0.102: v1(31.01,206.11) 30.86,206.11 30.85,206.11 30.28,206.11 30.26,206.13 R559.2
DBG_H_TDO: length 4.3
  TOP w0.102: v1(20.69,205.74) 20.8,205.74 21.05,205.49 XDP1.4
  BOTTOM w0.102: v2(19.94,205.74) v1(20.69,205.74) 20.7,205.75 R561.1
DBG_H_TMS: length 5.3
  TOP w0.102: XDP1.2 21.54,204.99 20.93,204.39 v1(20.93,203.81) 20.55,203.81 v4(20.12,204.24)
  BOTTOM w0.102: R564.1 21.5,204.67 20.93,204.11 v1(20.93,203.81)
DBG_H_TRST_N: length 3.6
  TOP w0.102: v1(27.12,206.95) 27.16,206.99 XDP1.9
  BOTTOM w0.102: R560.2 27.09,206.92 v1(27.12,206.95) v2(27.93,206.95)
DBG_I2C_SCL_LB: length 7.4
  TOP w0.102: v1(24.8,216.71) 24.58,216.49 XDP1.48 21.65,216.49 19.54,218.61 R21.1
  BOTTOM w0.102: v2(25.41,217.32) v1(24.8,216.71)
DBG_I2C_SDA_LB: length 5.1
  TOP w0.102: XDP1.50 21.89,216.99 20.75,218.14 v4(20.75,218.42) 20.75,218.76 R18.1
DBG_PMU_PLTRST_N: length 4.6
  TOP w0.102: XDP1.38 20.37,213.99 v4(19.91,214.46) 19.27,215.09 R35.1
DBG_PMU_PWRBTN_N: length 7.5
  TOP w0.102: R31.1 20.04,216.55 C7.1 20.82,215.77 20.82,215.46 21.79,214.49 XDP1.40 24.33,214.49 v1(24.8,214.02)
  BOTTOM w0.102: v1(24.8,214.02) v2(24.24,213.46)
DBG_PMU_RSTBTN_N: length 16.4
  TOP w0.102: v4(19.95,211.66) 19.95,212.88 19.55,213.27 R40.1 19.57,213.42 C9.1 20.82,213.42 21.25,212.99 XDP1.34 24.49,212.99 24.68,212.8 24.68,210.56 25.45,209.8 25.45,208.14 25.47,208.12 25.47,206.78 24.68,205.99 XDP1.6
DBG_PTI_CLK0: length 3.8
  TOP w0.102: XDP1.13 30.75,207.99 30.77,208.01 31.34,208.01 v4(31.46,208.13) 31.46,208.31 31.76,208.61 R55.2
DBG_RSMRST_N: length 7.6
  TOP w0.102: R28.1 19.72,217.73 21.33,216.13 21.33,215.55 21.89,214.99 XDP1.42 24.67,214.99 24.69,215.01 v1(24.85,215.01)
  BOTTOM w0.102: v1(24.85,215.01) v2(24.24,215.62)
DBG_TARGET_PRESENT_N: length 7.4
  TOP w0.102: XDP1.15 30.57,208.49 v4(31.53,209.45) 31.68,209.45 32.45,210.21 33.22,210.21 R51.2 33.23,210.37 R48.2 34.14,212.35 R43.1
DBG_UART_RXD: length 12.4
  TOP w0.102: R23.1 33.98,219.47 33.03,220.42 v4(31.96,220.42) 27.61,220.42 26.59,219.39 26.59,219.12 25.97,218.49 XDP1.56
DBG_UART_TXD: length 14.8
  TOP w0.102: v4(20.71,219.91) 21.37,219.25 21.37,218.29 21.66,217.99 XDP1.54 26.19,217.99 27.07,218.87 27.07,219.19 27.7,219.82 32.48,219.82 32.91,219.39 R22.1
DC_19V: length 74.1
  TOP w0.381: 58.07,39.88 58.34,39.88 58.57,39.65 ; 58.07,39.88 58.63,40.44 ; 58.07,39.88 53.82,39.88 53.57,40.13 PR177.1
  TOP w0.508: PC107.2 42.63,73.5 PR131.1 42.63,74.7 42.97,75.04 47.7,75.04 48.32,74.42 PR129.1
  TOP w0.635: R409.1 59.11,47.16 57.73,48.54 57.01,48.54 52.87,52.68 52.87,58.94 49.38,62.42 47.68,62.42 43.44,66.66 41.53,66.66 v5(41.48,66.72) 41.48,67.44 41.17,67.74 39.91,67.74 39.13,68.53 39.13,71.99 39.85,72.71 PU9.4 41.5,72.71 41.77,72.97 42.11,72.97 PC107.2
  BOTTOM w0.635: v5(41.48,66.72) 42.03,66.17 PR221.1 43.95,66.17 45.29,67.51 46.09,67.51 47.72,69.14 v2(48.41,69.14) 53.25,69.14 54.31,68.07 54.31,65.35 PR222.1
  vias: v2(63.28,41.1) v4(63.18,46.35) v5(62.81,43.32) v5(62.82,39.98) v5(62.87,38.96) v5(63.91,39.95) v5(63.96,38.99) v5(64.98,39.98) v5(65.06,39.01) v5(66.05,39.98) v5(66.12,39.01) v5(67.11,39.95) v5(67.11,39.04)
DC_IN_D: length 6.8
  TOP w0.381: PQ13.3 47.93,38.06 v3(48.14,37.85) 48.14,37.91 48.83,38.6 48.83,39.04 49.4,39.61 50.6,39.61 PR177.2
  BOTTOM w0.508: v3(48.14,37.85) 48.14,37.59 47.53,36.98 v2(47.53,36.96)
DCBATOUT: length 77.6
  TOP w0.254: PG9.1 51.54,45.53 PR173.2
  TOP w0.381: R50.1 R53.1
  TOP w0.508: 144.41,143.21 143.09,144.53 143.09,167.23 144.74,168.89 144.74,176.06 144.76,176.07 144.76,181.58 145.42,182.25 v1(145.42,185.62) ; R53.1 145.68,209.62 141.97,205.9 v5(141.97,196.71)
  L4 w0.508: v1(145.42,185.62) 145.01,186.04 145.01,192.31 141.97,195.35 v5(141.97,196.71)
  vias: v2(6.92,207.44) v2(25.1,137.71) v2(41.71,127.17) v2(42.02,72.18) v2(54.03,225.4) v2(58.58,66.55) v2(139.41,94.98) v2(143.67,58.35) v2(148.83,102.84) v4(33.61,50.77) v4(42.58,47.09) v4(48.01,48.21) v5(32.16,56.01) v5(33.05,56.01) v5(33.05,55.12) v5(35.35,52.88) v5(36.25,52.55) v5(40.9,221.67) v5(40.93,220.7) v5(40.95,219.76) v5(41.89,221.64) v5(41.92,220.68) v5(41.94,219.74) v5(42.16,70.71) v5(42.15,69.63) v5(42.91,221.62) v5(42.93,220.65) v5(42.96,219.71) v5(43.05,71.22) v5(43.04,70.23) v5(43.08,69.3) v5(43.85,42.04) v5(44.47,127.18) v5(44.47,125.87) v5(44.48,124.91) v5(44.53,123.97) v5(44.99,42.04) v5(44.95,39.93) v5(45.54,123.98) v5(45.56,127.22) v5(45.58,124.92) v5(45.71,125.82) v5(45.68,40.79) v5(48.42,45.09) v5(48.42,44.15) v5(49.39,45.07) v5(49.39,44.16) v5(49.39,43.24) v5(49.39,42.33) v5(49.39,41.41) v5(50.31,45.07) v5(50.31,44.16) v5(50.31,43.24) v5(50.31,42.33) v5(50.31,41.41) v5(57.26,68.96) v5(57.39,67.67) v5(58.38,68.88) v5(58.43,67.69) v5(59.6,68.91) v5(59.6,67.67) v5(136.05,94.59) v5(136.08,93.51) v5(136.08,92.42) v5(137.44,94.59) v5(137.44,93.53) v5(137.44,92.43) v5(138.93,93.61) v5(138.98,92.52) v5(140.9,95.81) v5(140.9,94.74) v5(140.9,93.65) v5(145.18,141.79) v5(145.66,140.99) v5(146.1,141.81) v5(146.58,141) v5(147.04,141.84) v5(147.91,110.22) v5(148.08,111.24) v5(148.58,41.1) v5(149.02,110.28) v5(149.16,111.25)
DCBATOUT_RT6575: length 2.5
  TOP w0.635: v1(66.99,54.2) 65.9,53.11 PR168.1
  vias: v2(65.49,66.64) v2(67.02,55.33) v5(68.74,63.88) v5(68.67,62.78) v5(68.67,61.77) v5(68.66,53.44) v5(69.55,53.85) v5(69.55,52.93) v5(71.38,64.69) v5(72.42,64.69)
DCBATOUT_RT6575_1: length 6.9
  TOP w0.203: 64.73,58.75 64.31,59.16 PU10.12
  TOP w0.254: 64.73,58.75 64.78,58.75 65.62,57.91 65.62,57.4
  TOP w0.508: PR168.2 64.88,55.04 64.3,55.63 64.3,56.26 v4(64.17,56.39) 64.24,56.46 PC118.1
  TOP w0.635: PC118.1 65.64,56.79 65.64,57.38 65.62,57.4
DCIN_EN: length 3.5
  TOP w0.127: U20.13 133.74,39.1 v4(134.61,39.97) 134.9,40.26 R422.2
DDCBUF: length 5.9
  TOP w0.127: R418.2 133.78,40.32 v1(133.75,40.29) 133.79,40.26 133.79,39.89 133.34,39.44 U20.14
  BOTTOM w0.127: v1(133.75,40.29) 133.75,40.04 134.08,39.71 v2(134.36,39.71) 134.4,39.75 134.4,40.48 R418.2
DDI0_RCOMP_N: length 4.8
  TOP w0.089: 83.88,148.08 83.88,149.68 84.2,150.01 84.2,150.34 84.01,150.59 CPU1.AG2 ; 83.88,148.08 v4(84.26,148.08) ; 83.88,148.08 83.88,147.32 84.17,147.03 R182.1
DDI0_RCOMP_P: length 5.4
  TOP w0.089: R182.2 84.31,146.25 83.69,146.87 83.69,149.95 CPU1.AG1
  TOP w0.102: R182.2 84.31,145.26 v4(84.23,145.19)
DDPC_CTRL_CLK_CONN: length 27.9
  TOP w0.127: v1(123.44,38.81) 123.44,38.93 123.79,39.28 U18.1 U18.10 122.27,39.64 121.8,39.17 119.46,39.17 118.81,39.82 HDMI1.15 ; RN36.4 129.76,30.49 v1(130,30.73) 130,31.1 131.34,32.43 U20.32
  BOTTOM w0.127: v1(123.44,38.81) 123.44,31.53 125.39,29.58 127.82,29.58 v2(128.54,30.3) 128.98,30.73 v1(130,30.73)
DDPC_CTRL_DATA_CONN: length 38.7
  TOP w0.127: v3(124.69,40.19) 124.58,40.19 124.51,40.12 U18.2 U18.9 122.12,40.12 121.57,39.57 119.62,39.57 118.87,40.32 HDMI1.16 ; U20.33 131.74,32.17 131.44,31.88 v1(131.44,30.89) 130.41,29.85 RN36.3
  BOTTOM w0.127: v1(131.44,30.89) 131.44,28.62 130.97,28.14 130.97,26.37 130.54,25.93 127.22,25.93 124.32,28.84 v2(124.32,29.41) 123.11,30.62 123.11,31.05 122.87,31.29 122.87,39.29 123.77,40.19 v3(124.69,40.19)
DDR3_DRAMRST_N: length 119.1
  TOP w0.102: CPU1.AR34 87.83,165.9 v3(87.83,165.9)
  L4 w0.127: v3(87.83,165.9) 88.93,164.8 89.84,164.8 93.38,161.26 93.38,157.94 95.13,156.18 98.56,156.18 122.91,131.84 135.02,131.84 135.43,132.25 138.55,132.25 139.49,133.18 139.49,176.39 140.86,177.75 v1(140.86,178.44)
  BOTTOM w0.102: R586.2 138.81,176.12 C285.1 138.79,177.36 R585.1 v2(139.95,178.42) 140.85,178.42 v1(140.86,178.44)
DDR3_DRAMRST_N_A_1: length 5.1
  TOP w0.102: v3(137.88,181.89) 137.88,181.89 137.92,181.85 139.19,181.85 139.19,181.85 DIMM1.30
  BOTTOM w0.102: R585.2 138.79,179.83 v2(139.17,180.21) 139.17,180.66 C281.1 138.7,181.55 138.36,181.89 v3(137.88,181.89)
DDR_VDDQ: length 126.5
  TOP w0.254: v3(134.83,166.42) v3(133.81,166.42) ; CPU1.AT47 v3(87.85,171.57) ; v3(87.16,169.67) 87.1,169.72 CPU1.AN42 ; DIMM1.81 131.2,164.15 133.01,164.15 133.66,164.8 v3(133.66,164.95) ; v3(132.71,162.67) 132.6,162.56 132.2,162.56 132.11,162.48 132.04,162.48 131.92,162.35 DIMM1.87 ; 134.04,160.88 133.5,161.43 v1(133.5,161.57) ; 134.04,160.88 134.93,160.88 135.39,160.43 135.39,160.27 v3(135.42,160.25) 135.42,160.43 135.57,160.58 135.57,162.26 v3(135.31,162.51) ; 134.04,160.88 134.04,160.83 133.89,160.68 v3(133.89,160.23) ; CPU1.AT51 88.25,173.48 88.25,173.28 v3(88.45,173.08) 88.45,173.09 CPU1.AV50 ; v3(134.3,151.26) 134.86,150.7 135.57,150.7 136.18,151.31 v3(136.99,151.31) ; v3(135.85,154.08) 135.36,153.59 v3(135.36,153.09) ; CPU1.AR17 v3(87.14,158.43) ; 138.46,156.65 v3(137.94,157.18) ; CPU1.AT17 v3(87.85,158.43)
  TOP w0.305: v3(135.46,164.88) 134.83,165.51 v3(134.83,166.42) ; v3(135.46,164.88) 135.46,164.61 134.12,163.27 v3(134.12,162.6) ; v3(135.46,164.88) 136.51,163.83 v3(136.51,163.73) ; 135.29,158.45 v3(134.98,158.14) 134.98,157.94 v3(135.75,157.18) ; 135.29,158.45 135.29,158.52 134.83,158.98 v3(133.97,158.98) ; 135.29,158.45 DIMM1.100 ; v3(137.04,162.51) 137.06,162.51 137.52,162.05 DIMM1.88 ; v3(137.13,155.8) 137.14,155.8 137.98,156.64 138.16,156.64 138.17,156.65 DIMM1.106 ; DIMM1.99 132.37,158.75 132.85,158.27 v3(132.85,158.22) ; CPU1.AN20 CPU1.AN18 v3(87.14,158.43) ; CPU1.AN46 v3(87.14,171.57) CPU1.AR47 ; DIMM1.76 137.83,165.65 137.36,166.12 137.36,166.14 137.1,166.4 137.09,166.4 v3(137.07,166.42) ; v3(137.9,160.25) 137.9,160.25 DIMM1.94 ; CPU1.AN23 CPU1.AN22 87.14,160.28 v3(87.18,160.31) ; v3(133.81,166.42) 133.76,166.37 133.76,166.29 133.18,165.71 132.37,165.71 132.13,165.95 DIMM1.75 ; DIMM1.82 138.04,163.85 137.98,163.79 137.98,163.77 v3(137.94,163.73) ; DIMM1.118 138.48,153.05 138.46,153.03 v3(137.93,153.03) ; CPU1.AV14 v3(88.44,156.9) CPU1.AT13 ; DIMM1.117 v3(132.8,153.35) ; v1(143.66,134.75) 143.97,134.75 145.09,133.63 PR82.2 ; v3(133.41,155.6) 132.84,155.03 132.25,155.03 132.22,155.06 131.29,155.06 DIMM1.111 ; CPU1.AN44 v3(87.13,170.67) ; v3(132.75,156.84) 132.64,156.95 DIMM1.105 ; DIMM1.123 132.28,151.55 v3(132.68,151.15) ; CPU1.AN41 v3(87.2,168.74) ; v3(135.85,154.08) 136.62,154.85 DIMM1.112
  TOP w0.33: DIMM1.124 137.05,151.25 v3(136.99,151.31) ; DIMM1.93 132.47,160.55 v1(133.5,161.57)
  TOP w0.635: PTC1.1 147.07,163.11 ; PTC1.1 147.07,161 ; PTC1.1 146.02,162.05 ; PTC1.1 148.13,162.05
  L4 w0.508: v5(146.21,160.31) 146.2,160.3 144.33,160.3 143.42,159.38 143.42,152.02 143.92,151.51 143.92,139.06 144.81,138.18 144.81,135.13 144.43,134.75 v1(143.66,134.75)
  BOTTOM w0.508: R581.1 139.1,182.75 141.54,180.31 141.54,177.96 R586.1 139.69,174.17 139.28,173.76
  BOTTOM w0.635: 147.07,161 PTC1.1 ; PTC1.1 147.07,163.11 ; PTC1.1 148.13,162.05 ; PTC1.1 146.02,162.05
  vias: v2(124.72,168.25) v2(143.64,143.48) v2(153.98,164.9) v5(104.27,119.11) v5(105.51,119.04) v5(106.16,118.1) v5(145.58,166.31) v5(145.58,165.38) v5(145.58,164.24) v5(146.59,166.31) v5(146.62,165.38) v5(146.72,164.21) v5(151.11,165.07) v5(151.11,163.8) v5(151.14,162.63) v5(151.17,161.41) v5(152.12,165.03) v5(152.12,163.89) v5(152.18,162.6) v5(152.2,161.38)
DDSP_C_HPD_CONN: length 18.5
  TOP w0.102: v3(126.02,39.95) 126.02,40.07 124.92,41.16 U18.4 U18.7 122.27,41.16 122.08,41.35 122.08,41.61 121.41,42.28 118.83,42.28 118.37,41.82 HDMI1.19 ; U20.28 v1(129.2,34.57)
  L3 w0.127: v3(126.02,39.95) 126.02,37.77 129.2,34.59 v1(129.2,34.57)
  BOTTOM w0.102: v2(126.04,40.74) 126.04,39.98 v3(126.02,39.95)
DFX_MSR_STRAP: length 7.9
  TOP w0.102: R38.2 v4(32.22,213.24) 31.84,212.86 31.84,210.55 31.83,210.54 31.83,210.35 31.55,210.07 31.36,210.07 31.3,210.01 31.3,210.01 30.97,209.68 30.97,209.68 30.29,208.99 XDP1.17
DGPU_PWR_EN#: length 11.5
  TOP w0.102: Q12.2 Q12.5 80.86,121.33 ; Q13.3 82.1,120.68 82.28,120.85 82.28,121.13 82.08,121.33 Q13.2 80.86,121.33 ; R211.1 76.41,123.91 79.07,123.91 v4(79.56,123.42) 80.86,122.12 80.86,121.33
DIGITAL_PU: length 15.4
  L4 w0.635: v1(150.89,49.4) 150.89,47.65 151.24,47.3 151.24,42.49 151.19,42.44 v1(151.19,42.34)
  BOTTOM w0.508: L24.2 v2(152.64,53.31) 152.51,53.19 152.51,50.66 D9.K 152,50.54 150.89,49.43 v1(150.89,49.4) ; v1(151.19,42.34) 151.19,42.05 151.79,41.45 R757.1
DIMM1_SA0: length 3.8
  TOP w0.102: DIMM1.197 129.95,129.35 129.66,129.64 129.65,129.64 v1(129.6,129.69)
  BOTTOM w0.102: R630.1 130.61,129.72 v2(130.49,129.84) 129.75,129.84 v1(129.6,129.69)
DIMM1_SA1: length 6.6
  TOP w0.102: v1(127.52,129.67) 127.52,129.46 128.83,128.15 DIMM1.201
  BOTTOM w0.102: v1(127.52,129.67) 127.67,129.51 R629.1 126.55,128.87 v2(126.45,128.97)
DISCHANGE_EN: length 116.6
  TOP w0.102: v1(120.04,57.83) 120.04,57.53 117.84,55.34 116.83,55.34 116.42,54.93 U14.27 ; R269.1 141.78,105.32 141.18,105.92 141.18,106.48 141.26,106.55 141.26,106.56 141.33,106.63 141.33,106.65 142.32,107.64 142.32,107.87 143.02,108.57 144.27,108.57 145.14,109.44 v1(145.14,109.73)
  L3 w0.127: v1(160.69,81.51) 158.14,78.96 158.14,75.78 138.86,56.5 135.49,56.5 134.99,57 134.19,57 134.19,57 133.8,57 133.79,57 130.05,57 129.93,56.87 129.5,56.87 129.12,57.25 126.5,57.25 125.83,57.92 123.11,57.92 123.01,57.83 v1(120.04,57.83)
  BOTTOM w0.102: v1(160.69,81.51) 161.58,82.4 161.58,85.9 156.99,90.49 156.99,97.98 154.63,100.35 154.63,111.2 151.69,114.13 v2(149.33,114.13) 144.96,114.13 144.3,113.48 144.3,111.56 145.14,110.72 v1(145.14,109.73)
DP1_AUXN: length 62.1
  L4 w0.127: v3(50.32,135.92) 50.35,135.92 50.76,135.51 50.76,135.33 50.56,135.13 50.38,135.13 50.1,135.42 49.94,135.42 48.48,133.95 42.2,133.95 31.67,123.42 31.67,100.27 32.59,99.35 32.59,95.97 31.38,94.75 31.38,93.02 30.87,92.51 30.54,92.51 v1(30.23,92.2)
  BOTTOM w0.102: R622.2 50.57,136.96 50.57,136.17 v3(50.32,135.92) 50.32,135.9 49.82,135.41 v2(49.82,135.41) ; R672.2 C442.1 v1(30.23,92.2)
DP1_AUXP: length 62.1
  L4 w0.127: v3(51.04,135.91) 50.59,136.36 50.11,136.36 49.84,136.1 49.84,135.69 48.37,134.22 42.09,134.22 31.41,123.53 31.41,100.16 32.32,99.24 32.32,96.08 31.11,94.86 31.11,93.13 30.76,92.78 30.54,92.78 v1(30.23,93.09)
  BOTTOM w0.102: R664.1 C438.1 v1(30.23,93.09) ; v2(51.54,135.4) 51.54,135.4 51.04,135.9 v3(51.04,135.91) 50.78,136.17 50.78,136.97 R621.2
DP1_HPD: length 4.6
  TOP w0.102: R184.1 R183.2 58.68,145.14 58.31,145.51 Q10.G 58.31,146.55 v4(57.11,147.75)
DP1_TXN0: length 58.3
  TOP w0.102: R189.2 48.22,136.92 48.22,136.24 v3(47.92,135.94)
  L4 w0.127: v3(47.92,135.94) 48.07,135.79 48.22,135.79 48.42,135.59 48.42,135.38 48.09,135.05 41.75,135.05 30.63,123.93 30.63,99.74 31.55,98.82 31.55,96.4 30.85,95.7 30.49,95.7 30.23,95.96 v1(30.23,96.01)
  BOTTOM w0.102: v3(47.92,135.94) 47.94,135.94 48.22,136.22 48.22,136.92 R189.2 ; v2(29.57,96.34) 29.89,96.01 v1(30.23,96.01) 30.34,95.91 30.98,95.91 C423.1
DP1_TXN1: length 54.5
  TOP w0.102: R187.2 45.99,136.96 45.99,136.26 v3(45.73,136)
  L4 w0.127: v1(30.01,97.64) 30.08,97.64 30.36,97.36 30.65,97.36 30.77,97.49 30.77,98.5 29.82,99.45 29.82,124.23 41.41,135.82 44.9,135.82 45.03,135.95 45.03,136.04 45.15,136.17 45.6,136.17 45.73,136.04 v3(45.73,136)
  BOTTOM w0.102: R187.2 46,136.95 46,136.28 v3(45.73,136) ; C415.1 30.73,97.43 30.21,97.43 v1(30.01,97.64) 30.01,98.39 v2(30.01,98.39)
DP1_TXP0: length 58.2
  TOP w0.102: R190.2 48.43,137.01 48.43,136.21 v3(48.7,135.94)
  L4 w0.127: v1(30.23,95.12) 30.54,95.43 30.96,95.43 31.82,96.29 31.82,98.93 30.9,99.85 30.9,123.82 41.86,134.78 48.2,134.78 48.7,135.28 v3(48.7,135.94)
  BOTTOM w0.102: v3(48.7,135.94) 48.43,136.21 48.43,137.01 R190.2 ; C431.1 v1(30.23,95.12) 30.15,95.04 v2(30.15,94.37)
DP1_TXP1: length 54.4
  TOP w0.102: v3(46.5,135.99) 46.2,136.28 46.2,136.96 R188.2
  L4 w0.127: v1(30.23,96.9) 30.42,97.09 30.76,97.09 31.04,97.37 31.04,98.61 30.09,99.56 30.09,124.12 41.53,135.56 46.07,135.56 v3(46.5,135.99)
  BOTTOM w0.102: C418.1 v1(30.23,96.9) ; R188.2 46.22,136.98 46.22,136.28 46.5,136 v3(46.5,135.99) 46.5,135.37 46.5,135.37 46.5,135.28 v2(46.5,135.28)
DP_AUXN: length 4.4
  TOP w0.102: TP22.1 121.7,208.91 121.83,209.04 121.83,209.3 121.67,209.45 121.01,209.45 120.81,209.65 119.65,209.65 119.5,209.5 NGFF1.20
DP_AUXP: length 4.8
  TOP w0.102: TP23.1 122.16,208.91 122.03,209.04 122.03,209.38 121.76,209.65 121.1,209.65 120.9,209.85 119.65,209.85 119.5,210 NGFF1.22
DP_CPU_AUXN: length 50
  TOP w0.102: CPU1.AH9 84.28,154.25 84.28,154.41 84.41,154.54 84.81,154.54 v3(84.87,154.48)
  BOTTOM w0.102: v3(84.87,154.48) 85.03,154.63 85.13,154.63 85.44,154.32 85.44,150.61 ; v2(85.11,150.61) 85.44,150.61 ; 85.44,150.61 85.44,144.8 82.21,141.58 70.26,141.58 68.96,140.27 51.52,140.27 50.55,139.3 50.55,138.67 R622.1
DP_CPU_AUXP: length 50
  TOP w0.102: CPU1.AH10 v3(84.87,155.19)
  BOTTOM w0.102: v2(62.64,139.75) 62.64,140.06 ; 62.64,140.06 51.61,140.06 50.77,139.21 50.77,138.68 R621.1 ; 62.64,140.06 69.04,140.06 70.35,141.36 82.3,141.36 85.65,144.71 85.65,154.41 v3(84.87,155.19)
DP_CPU_TXN0: length 50.8
  TOP w0.102: CPU1.AG9 v3(83.92,153.77)
  BOTTOM w0.102: v2(68.18,141.3) 68.18,140.97 ; 68.18,140.97 48.88,140.97 47.76,139.85 R624.1 ; 68.18,140.97 68.61,140.97 69.92,142.28 81.91,142.28 84.25,144.62 84.25,152.46 84.12,152.59 83.66,152.59 83.5,152.76 83.5,153.31 83.92,153.74 v3(83.92,153.77)
DP_CPU_TXN1: length 53.6
  TOP w0.102: CPU1.AG10 83.58,154.85 v3(83.98,155.24)
  BOTTOM w0.102: R626.1 45.58,138.71 45.73,138.86 46.21,138.86 46.4,139.05 46.4,139.89 48.3,141.79 61.96,141.79 ; v3(83.98,155.24) 83.68,155.24 83.55,155.12 83.55,154.94 83.75,154.74 83.75,154.51 83.01,153.76 83.01,152.56 83.55,152.02 83.55,145.01 81.52,142.98 65.16,142.98 64.64,142.46 63.41,142.46 62.74,141.79 61.96,141.79 ; v2(61.96,142.08) 61.96,141.79
DP_CPU_TXN2: length 60.2
  TOP w0.102: CPU1.AC5 82.32,152 82.08,151.78 v3(82.08,151.63) ; v1(42.63,138.23) 42.63,138.4 42.81,138.58 42.82,138.58 42.91,138.67 43.58,138.67 44.74,139.83 47.4,139.83 48.17,139.06 48.17,138.68 R189.1
  BOTTOM w0.102: v2(43.17,141.67) 43.39,141.45 ; 43.39,141.45 41.75,139.82 41.75,138.92 42.06,138.62 42.41,138.62 42.63,138.4 v1(42.63,138.23) ; 43.39,141.45 45.21,143.28 60.55,143.28 61.64,144.37 80.53,144.37 81.99,145.83 81.99,147.75 82.47,148.23 82.47,148.84 82,149.31 82,149.99 82.48,150.46 82.48,151.53 82.31,151.7 82.14,151.7 v3(82.08,151.63)
DP_CPU_TXN3: length 58.1
  TOP w0.102: v1(44.78,136.98) 44.61,136.98 44.38,137.21 44.38,138.48 44.99,139.09 45.8,139.09 45.99,138.91 45.99,138.68 R187.1 ; CPU1.AC9 82.23,153.91 v3(82.09,153.77)
  BOTTOM w0.102: 45.14,140.03 44.41,139.29 44.41,137.19 44.61,136.98 v1(44.78,136.98) ; 45.14,140.03 v2(45.38,139.78) ; 45.14,140.03 47.41,142.3 61.05,142.3 62.21,143.46 80.98,143.46 82.94,145.42 82.94,147.41 83.24,147.71 83.24,151.84 82.75,152.33 82.75,153.3 82.53,153.53 82.34,153.53 v3(82.09,153.77)
DP_CPU_TXP0: length 50.8
  TOP w0.102: CPU1.AG7 v3(83.92,153.05)
  BOTTOM w0.102: v2(84.8,147.88) 84.47,147.88 ; 84.47,147.88 84.47,144.53 82,142.06 70.01,142.06 68.7,140.75 48.97,140.75 47.98,139.76 47.98,139 48.17,138.81 48.62,138.81 48.8,138.63 R623.1 ; 84.47,147.88 84.47,153.16 84.34,153.29 84.05,153.29 83.92,153.16 v3(83.92,153.05)
DP_CPU_TXP1: length 53.7
  TOP w0.102: CPU1.AG12 83.61,155.56 v3(83.95,155.91)
  BOTTOM w0.102: R625.1 46.62,139.8 48.39,141.57 62.83,141.57 63.5,142.24 63.94,142.24 ; 63.94,142.24 v2(63.94,141.91) ; 63.94,142.24 64.73,142.24 65.25,142.76 81.61,142.76 83.76,144.92 83.76,152.11 83.22,152.65 83.22,153.67 84.38,154.83 84.38,155.61 84.08,155.91 v3(83.95,155.91)
DP_CPU_TXP2: length 60.3
  TOP w0.102: CPU1.AC6 v3(82.08,152.34) ; v1(42.63,139.04) 42.78,138.89 43.49,138.89 44.65,140.04 47.49,140.04 48.39,139.15 48.39,138.68 R190.1
  BOTTOM w0.102: 46.03,143.06 60.64,143.06 61.73,144.16 80.62,144.16 82.2,145.74 82.2,147.66 82.68,148.14 82.68,148.93 82.21,149.4 82.21,149.9 82.69,150.37 82.69,151.62 82.08,152.23 v3(82.08,152.34) ; 46.03,143.06 v2(46.03,142.76) ; 46.03,143.06 45.3,143.06 41.97,139.73 41.97,139.01 42.15,138.84 42.43,138.84 v1(42.63,139.04)
DP_CPU_TXP3: length 58.1
  TOP w0.102: v1(43.97,136.98) 44.17,137.18 44.17,138.57 44.9,139.31 45.89,139.31 46.2,139 46.2,138.68 R188.1 ; CPU1.AC7 v3(82.08,153.07)
  BOTTOM w0.102: v1(43.97,136.98) 44.19,137.2 44.19,138.79 ; v3(82.08,153.07) 82.09,153.07 82.34,153.31 82.44,153.31 82.54,153.21 82.54,152.24 83.03,151.75 83.03,147.8 82.72,147.5 82.72,145.5 80.89,143.68 62.12,143.68 60.96,142.51 47.32,142.51 44.19,139.38 44.19,138.79 ; v2(43.87,138.79) 44.19,138.79
DP_HPD: length 6.9
  TOP w0.102: TP19.1 104.81,209.93 107.13,212.25 NGFF1.31
DP_ML0N: length 4.6
  TOP w0.102: TP15.1 121.7,211.46 121.83,211.58 121.83,211.84 121.67,211.99 120.78,211.99 120.12,212.65 119.65,212.65 119.5,212.5 NGFF1.32
DP_ML0P: length 5
  TOP w0.102: TP16.1 122.16,211.46 122.03,211.58 122.03,211.92 121.76,212.19 120.87,212.19 120.21,212.85 119.65,212.85 119.5,213 NGFF1.34
DP_ML1N: length 4.6
  TOP w0.102: NGFF1.26 119.5,211 119.65,211.15 120.1,211.15 120.53,210.72 121.77,210.72 121.88,210.61 121.88,210.31 121.75,210.19 TP17.1
DP_ML1P: length 4.9
  TOP w0.102: NGFF1.28 119.5,211.5 119.65,211.35 120.18,211.35 120.61,210.92 121.85,210.92 122.08,210.69 122.08,210.31 122.21,210.19 TP18.1
DP_ML2N: length 5.3
  TOP w0.102: TP21.1 106.94,209.93 106.59,210.29 106.59,210.57 106.92,210.9 109.35,210.9 109.5,210.75 NGFF1.25
DP_ML2P: length 5.4
  TOP w0.102: TP20.1 106.13,209.93 106.38,210.19 106.38,210.65 106.83,211.1 109.35,211.1 109.5,211.25 NGFF1.27
DP_ML3N: length 6.5
  TOP w0.102: TP25.1 105.42,208.56 105.42,208.84 105.57,208.99 107.76,208.99 108.17,209.4 109.35,209.4 109.5,209.25 NGFF1.19
DP_ML3P: length 6.8
  TOP w0.102: TP24.1 105.21,208.56 105.21,208.93 105.48,209.19 107.68,209.19 108.09,209.6 109.35,209.6 109.5,209.75 NGFF1.21
DPLVDS_AUXN: length 3.3
  BOTTOM w0.102: C442.2 32.31,92.54 32.63,92.54 33.03,92.93 33.88,92.93 34.15,93.19 34.23,93.19 34.32,93.1 U31.3
DPLVDS_AUXP: length 3.6
  BOTTOM w0.102: 32.94,93.15 33.79,93.15 34.06,93.41 34.23,93.41 34.33,93.5 U31.4 ; 32.94,93.15 v2(32.94,93.51) ; 32.94,93.15 32.55,92.75 32.31,92.75 C438.2
DPLVDS_BL_EN: length 170.2
  TOP w0.127: v1(106.08,45.16) 106.17,45.16 113.13,52.12 113.13,52.12 113.34,52.34 113.34,53.42 113.46,53.53 113.46,54.06 114.72,55.33 U14.26 ; v3(40.22,27.46) 40.22,27.54 39.6,28.15 v4(39.54,28.15) 38.79,28.15 R463.2
  L3 w0.127: v1(36.23,88.87) 35.72,88.37 35.72,74.17 29.4,67.84 29.4,55.27 35.16,49.5 44.97,49.5 v1(45.91,50.44) 46.62,49.73 59.06,49.73 61.37,47.42 83.83,47.42 87.23,44.02 87.23,41.43 89.58,39.08 96.95,39.08 103.69,45.82 105.42,45.82 v1(106.08,45.16)
  L4 w0.127: v3(40.22,27.46) 40.22,28.2 43.3,31.29 43.3,43.32 45.78,45.8 45.78,50.32 v1(45.91,50.44)
  BOTTOM w0.127: v1(36.23,88.87) 36.79,89.43 36.79,90.5 37.18,90.89 U31.44
DPLVDS_EDIDCLK: length 9.4
  TOP w0.102: v1(36.07,89.86) 35.67,89.86 35.39,89.57 35.39,88.67 36.23,87.83 v1(36.23,87.76)
  BOTTOM w0.102: U31.46 36.38,90.93 36.07,90.62 v1(36.07,89.86) ; v2(38.64,87.89) C451.1 ; C451.1 R687.2 ; C451.1 R688.2 37.21,86.93 36.38,87.76 v1(36.23,87.76)
DPLVDS_EDIDCLK_C: length 1.7
  BOTTOM w0.102: U33.6 R688.1
DPLVDS_EDIDSDA: length 7.5
  BOTTOM w0.102: U31.45 36.78,91 36.54,90.77 36.54,89.64 36.28,89.37 35.92,89.37 35.57,89.01 v2(35.57,88.31) 35.57,87.47 R689.2 R690.2 C452.1
DPLVDS_EDIDSDA_C: length 1.7
  BOTTOM w0.102: U33.5 R689.1
DPLVDS_FWCLK: length 8.7
  BOTTOM w0.102: U31.48 35.58,90.96 35.01,90.39 35.01,90.38 34.57,89.95 34.57,88.36 34.2,87.99 33.29,87.99 v2(32.97,87.67) 32.68,87.38 32.68,86.86 31.97,86.15 C453.1 31.96,85.35 RN41.3
DPLVDS_FWSDA: length 10.7
  BOTTOM w0.102: U31.47 35.98,90.93 35.06,90.02 35.06,88.16 34.4,87.5 33.83,87.5 33.2,86.88 33.2,86.11 v2(33.12,86.02) 33.09,85.99 33.09,84.62 32.78,84.31 RN41.4 32.27,84.31 31.97,84.01 C457.1
DPLVDS_HPD: length 4.8
  BOTTOM w0.102: U31.1 34.78,91.76 33.8,90.79 33.32,90.79 33.31,90.78 v2(32.91,90.78) 32.42,90.28 32.42,89.6 R680.1
DPLVDS_HPD_1: length 83.4
  TOP w0.102: v1(57.59,144.02) 57.79,144.22 R183.1
  L4 w0.127: v1(57.59,144.02) 58.58,143.03 60,143.03 60.4,142.63 60.4,138.95 58.25,136.8 53.16,136.8 49.73,133.38 42.52,133.38 32.2,123.06 32.2,102.05 33.91,100.35 33.91,96.81 34.2,96.51 34.2,96.1 32.31,94.2 32.31,92.75 30.97,91.41 30.97,90.03 30.23,89.3 v1(30.23,89.15)
  BOTTOM w0.102: R685.1 31.98,87.05 R682.1 31.98,88.26 R680.2 v1(30.23,89.15) 30.11,89.28 v2(30.11,89.92)
DPLVDS_ISPCLK: length 49.5
  TOP w0.102: 44.12,76.54 44.9,75.77 47.94,75.77 48.4,75.31 v1(49.06,75.31) ; 44.12,76.54 44.72,77.14 46.03,77.14 46.5,77.61 46.5,78.43 RN35.3 ; 44.12,76.54 43.47,76.54 42.72,77.29 41.49,77.29 38.54,80.24 35.31,80.24 v1(34.93,79.86) 34.73,79.86 33.79,80.8 33.79,82.24 34.6,83.05 34.6,85.88 31.63,88.85 31.63,91.8 32.98,93.14 33.73,93.14 34.58,93.99 34.58,97.18 34.39,97.37 v1(34.39,97.37)
  BOTTOM w0.102: U31.13 34.53,97.5 v1(34.39,97.37) ; v2(50.45,75.54) 50.22,75.31 v1(49.06,75.31) 48.57,75.79 Q60.4 ; Q62.1 33.51,76.86 34.25,77.6 34.25,79.17 v1(34.93,79.86)
DPLVDS_ISPDAT: length 44.9
  TOP w0.102: RN35.4 46,79.21 45.85,79.07 45.85,78.05 45.94,77.97 v3(45.94,77.89) 45.94,77.89 41.57,77.89 38.74,80.72 v1(34.96,80.72) 34.88,80.8 34.81,80.8 34.27,81.33 34.27,82.04 35.09,82.85 35.09,86.08 32.42,88.74 32.42,91.66 33.39,92.63 33.54,92.63 35.06,94.15 35.06,97.51 v1(34.39,98.19)
  BOTTOM w0.102: v3(45.94,77.89) 45.99,77.93 46.54,77.93 46.8,77.67 Q60.1 ; v1(34.39,98.19) 35.83,98.19 35.98,98.04 U31.14 ; v2(33.98,81.29) 34.39,81.29 v1(34.96,80.72) 35.42,80.26 35.42,78.48 37.15,76.75 Q61.1
DPLVDS_PANEL_VCC: length 24.8
  TOP w0.127: R5501.1 34.23,115.01 R236.1 33.82,114.99 33.36,115.44 v4(33.15,115.44) 33.13,115.42 R642.2 33.13,111.12 36.15,108.1 36.15,106.38 35.77,105.99 35.01,105.99 34.4,105.38 34.4,102.62 36.86,100.15 v1(37.68,100.15)
  BOTTOM w0.102: U31.20 38.38,99.45 v1(37.68,100.15)
DPLVDS_PIN12: length 3.6
  BOTTOM w0.203: v2(33.27,97.6) 34.18,96.7 U31.12
  BOTTOM w0.305: v2(33.27,97.6) 32.15,98.73 R658.1
DPLVDS_PIN16: length 6.3
  BOTTOM w0.203: R657.2 32.61,99.11 34.27,99.11 34.55,99.39 v2(35.33,99.39) 35.51,99.39 36.78,98.13 U31.16
DPLVDS_PWMIN: length 26.9
  TOP w0.165: R245.1 37.75,113.71 38.11,113.34 38.11,101.51 v1(37.68,101.07) ; R245.1 37.75,114.88 37.29,115.33 v4(37.29,115.8) 37.29,116.64 37.6,116.95 R224.2 ; R245.1 40.44,114.4 40.7,114.15 R244.1
  BOTTOM w0.165: v1(37.68,101.07) 37.68,101.02 38.71,99.98 38.71,98.07 38.78,98.01 U31.21
DPLVDS_PWMOUT: length 24.8
  TOP w0.165: R230.2 33.43,117.4 32.52,117.4 v4(32.37,117.25) 32.37,116.92 31.76,116.31 31.76,110.41 33.61,108.56 33.61,102.57 36.79,99.39 v1(37.68,99.39)
  BOTTOM w0.165: U31.19 37.98,98.25 38.12,98.39 38.12,98.95 v1(37.68,99.39)
DQMA0: length 37.5
  TOP w0.127: v3(75.93,87.65) 75.67,87.65 75.31,87.3 75.31,87.12 75.55,86.88 75.56,86.88 75.78,86.66 76.09,86.66 76.25,86.83 76.25,87.04 76.63,87.43 77.07,87.43 77.77,88.12 77.77,88.3 77.59,88.48 77.59,88.66 77.77,88.84 77.95,88.84 78.13,88.66 78.3,88.66 78.48,88.84 78.48,89.45 78.74,89.71 79.04,89.71 79.27,89.94 79.27,91.45 79.01,91.7 GPU1.D19
  L3 w0.165: v3(75.93,87.65) 74.84,87.65 74.68,87.81 74.68,88.5 74.23,88.95 73.94,88.95 73.77,88.78 73.77,87.55 73.61,87.38 73.28,87.38 73.11,87.55 73.11,88.78 72.95,88.95 72.54,88.95 72.38,88.78 72.38,88.35 72.22,88.19 71.82,88.19 71.49,88.51 71.23,88.51 71.07,88.35 71.07,87.97 70.9,87.8 69.6,87.8 69.45,87.66 69.45,86.96 69.29,86.79 67.93,86.79 67.77,86.96 67.77,88.61 67.6,88.77 66.94,88.77 66.76,88.59 66.76,87.83 66.41,87.47 63.64,87.47 63.17,87.01 62.32,87.01 62.12,87.21 61.62,87.21 61.6,87.2 60.82,87.2 60.38,86.76 v3(60.38,86.75)
  BOTTOM w0.127: VRAM4.E7 57.64,85.48 57.87,85.48 58.22,85.83 59.45,85.83 60.37,86.75 v3(60.38,86.75)
DQMA1: length 37.1
  TOP w0.127: GPU1.D14 83.02,91.7 83.42,91.29 v3(83.42,91.29)
  L3 w0.102: v3(83.42,91.29) 82.76,91.29 82.15,90.68 82.15,90.25 82.2,90.2
  L3 w0.165: 82.2,90.2 82.2,89.56 81.36,88.72 81.36,87.51 75.89,82.03 60.39,82.03 60.25,81.89 58.68,81.89 58.43,81.64 56.08,81.64 v3(55.98,81.74)
  BOTTOM w0.127: VRAM4.D3 54.4,84.36 54.55,84.21 54.55,84.21 54.77,83.99 54.77,83.99 54.77,83.98 54.77,83.66 55.56,82.87 55.56,82.16 v3(55.98,81.74)
DQMA2: length 42
  TOP w0.127: v1(56.43,79.36) 56.13,79.66 56.13,81.24 56.44,81.55 56.44,82.09 56.3,82.22 56.3,83.02 56.44,83.15 56.44,83.75 57.33,84.64 VRAM2.D3 ; GPU1.C17 80.07,90.45 80.07,89.14 79.62,88.69 79.62,88.09 v3(80.02,87.69)
  L4 w0.165: v3(80.02,87.69) 79.93,87.78 79.93,90.15 79.77,90.32 79.15,90.32 78.99,90.15 78.99,88.12 77.56,86.7 77.56,86.37 73.02,81.82 64.99,81.82 64.31,81.15 59.54,81.15 58.24,79.84 56.9,79.84 v1(56.43,79.36)
DQMA3: length 31.2
  TOP w0.127: v3(54.99,84.42) 54.99,84.57 54.45,85.11 54.45,85.23 54.4,85.28 VRAM2.E7 ; GPU1.C22 76.37,90.9 v3(75.98,90.51)
  L4 w0.165: v3(75.98,90.51) 76.29,90.51 76.45,90.67 76.45,91.37 76.62,91.54 76.97,91.54 77.14,91.37 77.14,89.66 76.99,89.51 76.23,89.51 75.78,89.06 74.41,89.06 74.24,88.9 74.24,87.82 74.08,87.65 73.23,87.65 72.57,87 70.35,87 70.11,86.76 68.68,86.76 68.23,86.31 66.67,86.31 66.17,86.81 62.63,86.81 62.14,86.32 61.99,86.32 61.97,86.3 59.23,86.3 59.01,86.08 56.79,86.08 56.62,85.91 56.2,85.91 55.78,85.49 55.78,85.2 v3(54.99,84.42)
DQMA4: length 35.6
  TOP w0.127: v3(74.29,100.42) 74.29,100.41 GPU1.P24
  L3 w0.165: v3(56.37,113.07) 56.37,113.59 56.81,114.04 58.08,114.04 58.24,114.2 58.24,114.5 58.41,114.67 61.32,114.67 61.7,114.29 63.13,114.29 64.2,113.21 64.2,108.31 64.47,108.05 65.18,108.05 65.54,107.68 65.54,101.82 67.32,100.04 71.8,100.04 72.64,100.88 73.83,100.88 v3(74.29,100.42)
  BOTTOM w0.127: VRAM3.E7 54.4,113.96 54.62,114.18 55.21,114.18 55.33,114.05 55.33,113.36 55.46,113.23 56.2,113.23 v3(56.37,113.07)
DQMA5: length 40.7
  TOP w0.127: v3(75.11,104.54) 75.11,104.53 GPU1.W24
  L3 w0.165: v1(57.59,120.53) 57.67,120.44 64.33,120.44 71.11,113.67 71.11,110.29 72.09,109.31 72.09,108.22 71.93,108.07 70.48,108.07 70.08,107.67 70.08,107.25 70.24,107.08 72.19,107.08 73.28,105.99 73.28,105 73.06,104.78 73.06,104.34 73.32,104.08 74.45,104.08 74.91,104.54 v3(75.11,104.54)
  BOTTOM w0.127: VRAM3.D3 57.14,115.06 57.14,115.52 56.04,116.62 56.04,117.72 56.67,118.35 57.04,118.35 57.32,118.63 57.32,120.26 v1(57.59,120.53)
DQMA6: length 39
  TOP w0.127: v1(56.14,122.81) 56.14,122.2 54.75,120.8 54.75,119.44 55.74,118.45 55.74,115.89 54.45,114.6 VRAM1.D3 ; v3(70.6,107.56) 71.71,106.46 71.83,106.46 72.08,106.21 73.49,106.21 GPU1.AA25
  L4 w0.165: v1(56.14,122.81) 56.86,122.81 57.53,122.15 58.35,122.15 58.52,121.97 58.76,121.97 58.91,122.13 59.15,122.13 59.38,121.89 59.38,121.66 59.23,121.5 59.23,121.27 59.46,121.04 63.48,121.04 68.76,115.76 68.76,109.4 v3(70.6,107.56)
DQMA7: length 33.5
  TOP w0.127: GPU1.U25 73.45,102.93 72.86,102.93 72.59,102.66 72.05,102.66 71.86,102.85 71.37,102.85 70.99,102.48 v3(70.99,102.41) ; VRAM1.E7 57.6,114.08 56.61,115.06 v3(56.61,115.36)
  L4 w0.165: v3(56.61,115.36) 62.76,115.36 63.82,114.31 63.82,109.02 69.56,103.27 72.83,103.27 73,103.11 73,102.11 72.83,101.94 71.16,101.94 70.99,102.11 v3(70.99,102.41)
DRX0N: length 3.3
  BOTTOM w0.102: U31.8 34.33,95.1 34.22,95 34.1,95 33.91,95.18 33.45,95.18 32.94,95.69 32.29,95.69 C423.2
DRX0P: length 3.6
  BOTTOM w0.102: v2(32.91,94.98) 33.13,95.2 ; 33.13,95.2 33.36,94.96 33.82,94.96 34.01,94.78 34.17,94.78 34.25,94.7 U31.7 ; 33.13,95.2 32.85,95.48 32.33,95.48 C431.2
DRX1N: length 4.1
  BOTTOM w0.102: U31.10 34.31,95.9 34.22,95.81 33.58,95.81 33.28,96.11 33.28,96.88 32.7,97.45 32.31,97.45 C415.2
DRX1P: length 4.1
  BOTTOM w0.102: C418.2 32.31,97.24 32.61,97.24 33.06,96.79 33.06,96.02 33.49,95.59 34.23,95.59 34.33,95.5 U31.9
EAPD_DEPOP: length 8.7
  TOP w0.203: U16.14 157.74,44.8 156.93,43.98 v4(156.93,42.59) 156.93,41.73 156.29,41.1 155.56,41.1 154.59,40.13 R426.1
EAPD_DEPOP_1: length 6.1
  TOP w0.102: R426.2 151.99,40.13 151.73,40.39 151.54,40.39 v1(151.47,40.46)
  BOTTOM w0.102: v1(151.47,40.46) 151.52,40.46 151.69,40.64 153.44,40.64 v2(153.96,40.13) 153.51,39.68 R759.1 R760.1
EAPD_DEPOP_2: length 2.9
  BOTTOM w0.381: Q69.2 R760.2 151.58,39.41 152.28,40.11 v2(152.33,40.11)
EC_AGND: length 17.7
  TOP w0.203: v1(126.45,68.9) 126.45,68.6 127.05,68.01 U14.103
  TOP w0.508: v1(126.45,68.9) 126.45,69.34 126.66,69.56 C137.2 127.16,69.74 127.69,70.27 130.14,70.27 131.29,71.42 132.1,71.42 R344.2 C135.1 134,71.45 C136.2
  BOTTOM w0.508: v2(124.86,71.56) 124.87,71.56 125.24,71.18 R718.2 125.3,70.43 C464.2 126.19,70.27 126.19,69.15 v1(126.45,68.9) 126.31,68.76 C467.1 126.32,67.74 R721.2
EC_AVCC: length 14.2
  TOP w0.203: v1(127.35,68.72) 127.35,68.6 127.45,68.49 U14.102
  TOP w0.305: v1(127.35,68.72) 127.35,68.73 127.87,69.26 127.87,69.38 C137.1 128.85,69.56 R349.1
  BOTTOM w0.305: R713.1 123.5,71.32 124.7,72.52 125.53,72.52 126.27,71.78 127.21,71.78 127.9,71.09 C464.1 127.9,70.23 v2(127.11,69.44) 127.11,69.25 127.35,69.01 v1(127.35,68.72) 128.25,67.82 128.29,67.82 R720.1
EC_BEEP_GPIO: length 3.3
  TOP w0.102: Q2801.G 141.15,40.34 v4(142.2,39.29) 142.2,40.55 R2401.1
EC_BEEP_GPIO_EC: length 25.2
  TOP w0.102: v1(132.67,58.23) 132.58,58.23 132.57,58.24 132.01,58.24 131.72,58.53 U14.79 ; R2401.2 142.46,41.71 140.44,41.71 140.39,41.76 139.86,41.76 139.73,41.88 138.54,41.88 v4(137.7,42.72) 137.7,43.1 v1(138.34,43.74)
  L4 w0.127: v1(138.34,43.74) 138.34,43.79 134.17,47.96 134.17,50.6 132.91,51.85 132.91,53.45 133,53.54 133,57.2 132.91,57.29 132.91,57.31 132.67,57.55 v1(132.67,58.23)
EC_DEBUG: length 35.6
  TOP w0.102: U14.111 123.85,69.04 124.2,69.39 124.2,70.62 123.58,71.25 123.58,72.62 123.88,72.93 v1(123.88,73.36)
  BOTTOM w0.102: v1(123.88,73.36) 123.88,75.39 124.9,76.4 125.22,76.4 125.65,75.97 126.03,75.97 126.46,76.4 126.47,76.4 126.63,76.57 136.04,76.57 138.65,79.18 139.7,79.18 140.71,80.18 140.71,82.35 v2(141.72,83.37) EC_DEBUG1.2
EC_HDMI_PD_N: length 52.7
  TOP w0.102: v1(122,59.55) 122,62.89 124.65,65.53 U14.109
  L4 w0.127: v1(121.6,42.8) 121.6,44.08 122.98,45.46 122.98,51.5 124.02,52.54 124.02,57.21 122.74,58.5 122.74,58.81 122.03,59.51 122.03,59.52 v1(122,59.55)
  BOTTOM w0.102: R791.2 129.64,23.57 126.68,23.57 Q71.G 125.2,24.56 125.2,27.25 121.39,31.06 121.39,40.01 120.97,40.43 v2(120.97,41.38) 121.65,42.06 121.65,42.16 121.6,42.21 v1(121.6,42.8)
EC_IMS: length 5.2
  TOP w0.102: v1(117.94,52.76) 117.85,52.66 U14.35 117.85,49.07 R400.2
  BOTTOM w0.102: v1(117.94,52.76) 117.28,52.76 v2(116.9,53.14)
EC_PECI: length 2.5
  TOP w0.102: U14.13 114.6,60.53 113.49,59.42 TP52.1
EC_SCI#: length 316.4
  TOP w0.102: R4.2 33.96,222.8 R3.1 38.61,227.46 88.27,227.46 92.08,223.64 v1(92.08,220.98)
  L3 w0.127: v1(92.08,220.98) 92.37,220.69 93.52,220.69 93.86,221.02 97.02,221.02 99.03,219 100.13,219 101.8,217.34 103.13,217.34 106.68,213.78 119.5,213.78 119.69,213.97 120.54,213.97 122.21,212.3 136.77,212.3 143.78,205.28 144.2,205.28 150.68,198.8 150.68,198.37 157.28,191.77 157.28,185.17 163.44,179.01 163.44,178.12 163.44,177.17 163.46,177.16 163.46,175.06 163.47,175.05 163.47,158.02 165.88,155.61 165.88,155.29 165.88,155.29 165.88,123.68 164.74,122.54 164.74,102.17 165.04,101.86 165.04,90.96 163.52,89.43 163.52,83.66 158.52,78.66 158.52,75.62 138.24,55.33 130.21,55.33 129.39,56.16 129.04,56.16 128.61,56.59 126.25,56.59 125.55,57.29 123.85,57.29 123.64,57.07 121.5,57.07 121.17,56.74 120.78,56.74 v1(120.52,56.48)
  BOTTOM w0.102: R743.2 119.01,56.48 v2(119.12,56.48) v1(120.52,56.48)
EC_SMB_DATA: length 5.5
  TOP w0.102: R2403.1 119.29,70.09 v1(119.29,69.16) 119.38,69.16 120.04,68.5 120.05,68.5 120.25,68.3 U14.120
  BOTTOM w0.102: v2(118.42,68.73) 118.85,68.73 v1(119.29,69.16)
EC_SMI#: length 221.6
  TOP w0.102: v1(96.5,71.42) 96.93,70.99 97.39,70.99 97.47,70.92 101.25,70.92 102.99,70.92 104.45,69.45 104.45,67.72 105.59,66.58 R357.2 ; R130.2 49.53,180 v1(49.92,180.39) 49.92,181.16 v4(50.2,181.44) 50.64,181 R131.1
  L3 w0.127: v1(96.5,71.42) 96.5,72.29 98.07,73.86 98.07,78.01 99.14,79.07 102.32,79.07 102.91,79.66 109.93,79.66 113.8,83.53 113.8,111.01 111.65,113.16 106.5,113.16 103.28,116.38 103.28,119.15 101.29,121.14 95.61,121.14 95.12,120.64 88.71,120.64 88.05,121.3 80.41,121.3 79,122.71 79,124.69 72.73,130.96 65.67,130.96 65.26,131.37 59.84,131.37 56.85,134.37 43.79,134.37 41.08,137.07 41.08,137.39 40.02,138.45 40.02,141.89 46.55,148.42 57.81,148.42 v1(57.97,148.26)
  L4 w0.127: v1(57.97,148.26) 57.97,149.67 52.43,155.22 52.43,170.4 51.88,170.94 51.88,173.44 52.05,173.61 52.05,175.16 49.77,177.44 49.77,179.3 49.92,179.45 v1(49.92,180.39)
EC_SPI_CLK: length 6.8
  TOP w0.102: R361.1 137.44,64.53 v4(135.61,64.53) 133.3,64.53 132.82,64.04 132.1,64.04 131.79,63.73 U14.92
EC_SPI_CS0_N: length 6.9
  TOP w0.102: U14.90 131.81,62.93 132.13,63.13 132.19,63.17 132.35,63.21 132.48,63.21 132.79,63.15 134.54,62.68 v4(136.13,62.19) R366.1
EC_SPI_SI: length 7.1
  TOP w0.102: R369.1 136.05,60.58 v4(135.77,60.86) 134.9,61.73 U14.87
EC_SPI_SO: length 7.5
  TOP w0.102: R374.2 135.9,59.44 v4(135.83,59.51) 133.87,61.47 132.7,61.47 132.57,61.33 U14.86
EC_SWI#: length 155.7
  TOP w0.102: R341.2 119.87,74.27 119.92,74.32 119.92,74.36 v1(119.93,74.38) ; R166.1 54.95,169.89 R164.2 54.91,169.91 v1(54.2,170.62)
  L3 w0.127: v1(63.53,144.93) 63.53,144.67 61.12,142.26 61.12,136.7 61.14,136.68 61.14,136.25 61.87,135.52 68.85,135.52 70.14,134.24 76.36,134.24 84.29,126.31 87.59,126.31 90.38,123.52 92.54,123.52 93.12,122.94 v1(93.12,122.82)
  L4 w0.127: v1(54.2,170.62) 54.2,155.97 61.93,148.24 61.93,146.53 v1(63.53,144.93) ; v1(98.1,82.19) 98.1,80.66 98.88,79.88 105.65,79.88 105.82,79.71 113.27,79.71 115.06,77.91 116.33,77.91 116.39,77.85 116.4,77.85 119.87,74.38 v1(119.93,74.38)
  BOTTOM w0.102: v1(93.12,122.82) 93.75,122.82 v2(94.28,122.28) 105.16,111.4 105.16,106.77 105.06,106.66 105.06,92.71 101.89,89.53 101.89,84.43 100.19,82.73 98.64,82.73 v1(98.1,82.19)
EC_V_3P3_A: length 45.8
  TOP w0.254: R380.2 136.28,57.33 v1(136.38,57.23) 136.43,57.28 137.6,57.28 R715.2
  L4 w0.254: v1(139.71,72.81) 139.71,70.81 140.14,70.39 140.14,67.42 138.79,66.08 138.79,59.64 v1(136.38,57.23)
  BOTTOM w0.254: R733.1 128.67,59.93 R732.1 129.17,59.46 129.17,57.12 129.98,56.3 v2(129.98,54.79) 130.08,54.69 136.13,54.69 136.43,54.99 136.43,57.17 v1(136.38,57.23) ; Q63.S 138.24,73.89 C463.1 ; C463.1 R706.2 ; C463.1 139.4,73.12 v1(139.71,72.81) 138.81,71.91 137.54,71.91 136.65,71.02 135,71.02 134.63,71.39 R716.1
EC_VBKUP: length 4.3
  TOP w0.203: U14.114 122.65,65.58 122.84,65.38 122.84,64.77 v1(122.67,64.6)
  BOTTOM w0.305: v2(123.47,65.54) R724.1 122.74,64.53 v1(122.67,64.6)
EC_VCC1V8_S5: length 55.7
  TOP w0.203: U14.88 132.75,62.13 132.82,62.2 134.1,62.2 v1(134.15,62.25)
  TOP w0.305: R348.1 140.06,69.67 v1(139.5,70.24) 138.84,70.24 138.33,70.75 U13.1 140.17,71.09 C134.1
  BOTTOM w0.305: R726.2 124.72,63.36 125.68,64.32 125.68,64.41 125.71,64.43 125.71,64.87 126.18,65.35 127.4,65.35 128.07,64.67 128.07,64.29 128.91,63.45 132.94,63.45 v2(133.33,63.06) v1(134.15,62.25) 134.41,61.99 R728.1 134.97,62.6 135.36,62.99 135.98,62.99 137.62,64.64 137.62,65.61 136.7,66.54 ; 136.7,66.54 138.18,68.02 138.18,68.92 v2(138.21,68.95) v1(139.5,70.24) ; 136.7,66.54 134.49,64.33 129.27,64.33 128.94,64.66 128.94,65.02 127.75,66.21 125.67,66.21 125.22,66.66 117.44,66.66 116.88,66.1 R722.1
EC_VCC3: length 91.6
  TOP w0.305: 140.92,75.95 Q32.2 ; 140.92,75.95 140.92,76.9 140.43,77.4 RN9.2 140.79,78.21 141.02,78.43 141.02,78.64 140.79,78.86 RN9.1 ; 140.92,75.95 Q32.5 ; 140.92,75.95 140.92,75.05 ; 142.84,74.71 142.84,73.2 144.27,71.77 C133.1 145.05,71.74 C132.1 ; 142.84,74.71 143.3,75.17 ; 142.84,74.71 141.22,74.71 140.92,75.02 140.92,75.05 ; 143.3,75.17 143.31,75.19 R328.1 143.63,76.89 144.73,76.89 U12.1 ; 143.3,75.17 C126.1 ; R337.1 133.83,73.28 133.83,73.09 133.26,72.52 R343.2 ; R337.1 134.65,73.51 135.52,72.64 135.52,71.51 135.93,71.09 U13.6 ; R337.1 134.65,74.19 135.64,75.18 137.04,75.18 v1(137.17,75.31) 137.76,74.71 140.58,74.71 140.92,75.05 ; C132.1 147.21,72.76 R335.1 ; C132.1 146.19,70.59 R347.2 ; v1(135.52,48.98) 135.52,48.82 135.55,48.79 U17.5
  L4 w0.305: v1(137.17,75.31) 138.64,73.84 138.64,66.95 v1(136.79,65.11) 136.79,61.2 v1(136.69,61.09) 137.24,60.53 137.24,59.03 135.21,57 135.21,55.65 134.34,54.78 134.34,52.06 135.29,51.11 135.29,49.38 135.52,49.15 v1(135.52,48.98)
  BOTTOM w0.305: R723.1 117.73,66.23 125.04,66.23 125.49,65.78 127.58,65.78 128.51,64.84 128.51,64.48 129.09,63.9 133.74,63.9 133.92,63.72 135.41,63.72 v2(135.93,64.24) v1(136.79,65.11) ; R729.1 136.56,60.96 v1(136.69,61.09)
EC_VDD3D3: length 8.1
  TOP w0.203: v1(113.54,65.07) 114.48,64.13 U14.4
  TOP w0.305: C139.1 111.8,65.71 111.83,65.71 C140.1 112.55,65.07 v1(113.54,65.07)
  BOTTOM w0.305: v1(113.54,65.07) 113.56,65.04 v2(114.57,65.04) R723.2 R722.2
EC_VSBY: length 3.9
  TOP w0.203: U14.75 132.9,56.93 v4(133.08,57.11)
  TOP w0.305: v4(133.08,57.11) 133.17,57.02 134.38,57.02 R380.1
EC_VTT: length 5.4
  TOP w0.203: U14.12 114.35,60.93 113.8,60.38 112.19,60.38 R376.2
  TOP w0.305: v4(110.6,59.87) 110.61,59.86 R376.2
ECRST#: length 19.4
  TOP w0.102: U14.85 132.56,60.93 v3(132.78,60.71) 133.02,60.95 R373.1
  L4 w0.127: v1(135.76,69.26) 135.76,68.11 133.45,65.8 133.45,61.57 132.78,60.9 v3(132.78,60.71)
  BOTTOM w0.102: Q65.E 132.26,69.34 133.4,69.34 133.81,68.93 133.81,68.81 R719.2 134.12,67.51 C466.1 135.05,67.5 135.45,67.91 v2(135.46,67.91) 135.46,67.92 135.76,68.21 v1(135.76,69.26)
ECSCI#_KBC: length 3.9
  TOP w0.102: U14.29 116.6,54.13 116.85,54.38 v1(116.85,54.56)
  BOTTOM w0.102: v1(116.85,54.56) 116.85,54.99 v2(117.18,55.32) 117.56,54.94 R743.1
ECSMI#_KBC: length 9.8
  TOP w0.102: U14.11 113.79,61.33 113.47,61.01 110.98,61.01 v4(109.99,62) 109.96,62.03 109.96,65.05 R357.1
ECSWI#_KBC: length 9.4
  TOP w0.102: v4(121.06,73.63) 120.06,72.63 R341.1 119.66,72.63 119.26,73.03 118.79,73.03 118.52,72.77 118.52,71.07 118.57,71.02 118.57,70.26 118.47,70.16 118.47,68.46 118.48,68.45 118.48,68.35 119.05,67.78 U14.123
EDID_WC#: length 20.9
  TOP w0.102: v1(47.53,79.48) 47.28,79.73 44.15,79.73 43.87,79.45 41.82,79.45 39.1,82.17 v1(37.75,82.17)
  BOTTOM w0.102: v1(47.53,79.48) 48.09,78.92 49.87,78.92 v2(50.66,78.13) 50.66,77.22 R812.1 52.33,75.54 R810.2 ; U33.7 38.64,83.06 v1(37.75,82.17)
EDID_WC_EC#: length 83.6
  TOP w0.102: U14.113 123.05,67.64 122.61,68.07 122.61,68.94 122.77,69.09 122.77,73.08 v1(122.97,73.28)
  L4 w0.127: v1(122.97,73.28) 121.65,73.28 121.6,73.33 119.59,73.33 118.32,74.6 118.32,75.38 116.17,77.53 114.9,77.53 113.11,79.32 105.65,79.32 105.49,79.48 101,79.48 v1(99.68,78.16)
  BOTTOM w0.102: R810.1 53.58,75.49 62.54,75.49 62.95,75.9 64.55,75.9 64.98,75.46 82.61,75.46 84.92,77.77 89.64,77.77 91.32,79.45 99.07,79.45 99.68,78.84 v1(99.68,78.16) ; v2(122.26,72.8) 122.49,72.8 v1(122.97,73.28)
EDP_RCOMP_N: length 8.1
  TOP w0.089: R181.2 81.92,146.57 81.92,147.75 83.27,149.1 83.27,150.37 83.26,150.38 83.18,150.47 83.18,150.7 83.2,150.76 83.29,150.84 83.29,151.08 83.26,151.14 83.18,151.22 83.18,151.47 83.18,151.47 83.31,151.66 CPU1.AG5
  TOP w0.381: R181.2 82.46,145.44 v4(82.86,145.03)
EDP_RCOMP_P: length 6.5
  TOP w0.089: R181.1 82.46,147.46 82.47,147.47 82.48,147.47 82.91,147.9 v4(82.91,147.93) 82.94,147.93 83.45,148.44 83.45,150.17 83.75,150.47 83.75,150.7 83.64,150.81 83.64,151.1 83.78,151.27 83.82,151.35 83.82,152.18 83.82,152.2 83.72,152.41 CPU1.AG6
EMMC_CLK: length 45.4
  TOP w0.102: v1(99.73,205.69) 100.31,206.27 R70.1 ; CPU1.Y58 80.53,177.29 80.22,177.61 80.2,177.61 v3(80.18,177.62)
  L4 w0.089: v3(80.18,177.62) 80.18,177.64 79.77,178.06 79.77,179.37 78.9,180.23 78.9,180.63 78.18,181.36
  L4 w0.114: 78.18,181.36 78.03,181.51 78.03,188.86 78.37,189.2 78.37,189.3 78.37,189.3 78.37,189.85 82.1,193.58 82.1,194.29 86.81,199 87.44,199 91.82,203.37 91.9,203.37 92.49,203.37 93.87,204.75 98.78,204.75 99.08,205.05 99.88,205.05 100.22,205.4 100.22,205.58 100,205.8 99.82,205.8 99.73,205.7 v1(99.73,205.69)
  BOTTOM w0.102: v1(99.73,205.69) 99.73,205.46 v2(99.22,204.95)
EMMC_CLK_R: length 20.5
  TOP w0.102: R70.2 100.31,208.68 98.18,210.82 98.18,211.5 98.07,211.6 97.84,211.6 97.73,211.7 97.73,212.01 97.84,212.11 98.07,212.11 98.18,212.21 98.18,213.44 98.07,213.54 97.77,213.54 97.67,213.64 97.67,213.95 97.77,214.05 98.07,214.05 98.18,214.15 98.18,215.34 98.07,215.44 97.7,215.44 97.59,215.54 97.59,215.85 97.7,215.95 98.07,215.95 98.18,216.05 98.18,216.35 98.07,216.46 97.7,216.46 97.59,216.56 97.59,216.86 97.7,216.96 98.07,216.96 98.18,217.07 98.18,217.88 v1(97.77,218.28) ; U1.M6 94.63,218.82 94.4,218.59 v3(94.4,218.32)
  L4 w0.114: v1(97.77,218.28) 97.35,218.71 94.79,218.71 v3(94.4,218.32)
  BOTTOM w0.102: v2(98.56,217.73) 98.33,217.73 v1(97.77,218.28)
EMMC_CMD: length 55.4
  TOP w0.102: R61.1 90.06,206.57 89.44,207.19 89.44,207.9 v1(89.16,208.18) ; CPU1.Y51 80.73,173.73 v3(81.11,173.35)
  L4 w0.114: v1(89.16,208.18) 89.01,208.18 78.63,197.8 78,197.17 73.15,197.17 71.18,195.2 71.18,183.95 71.99,183.13 71.99,182.36 72.58,181.27 73.4,180.45 74.62,179.93 78.23,176.32 78.46,174.59 80.04,173.01 80.45,173.01 v3(81.11,173.35)
  BOTTOM w0.102: v1(89.16,208.18) v2(89.16,207.38) 89.16,206.96 89.56,206.57 R61.1
EMMC_CMD_R: length 15.6
  TOP w0.102: R61.2 90.08,209.57 v1(93.2,212.69) ; v3(95.59,218.27) 95.59,218.38 U1.M5
  L3 w0.114: v1(93.2,212.69) 93.43,212.69 93.85,213.11 94.55,213.11 96.13,214.69 96.13,217.74 v3(95.59,218.27)
  BOTTOM w0.102: v3(95.59,218.27) 95.59,218.78 v2(95.41,218.97)
EMMC_DATA_0: length 56.3
  TOP w0.102: R67.2 97.42,206.57 97.55,206.44 97.55,205.98 97.42,205.85 96.76,205.85 v1(96.64,205.73) ; CPU1.V58 79.87,177.29 80.18,176.98 v3(80.18,176.95)
  L4 w0.089: v3(80.18,176.95) 79.59,177.54 79.59,179.23 78.66,180.16 78.66,180.53 77.92,181.27
  L4 w0.114: 77.92,181.27 77.83,181.36 77.83,189.31 77.88,189.36 77.88,190.05 81.61,193.78 81.61,194.5 86.66,199.54 87.29,199.54 87.55,199.81 87.55,199.97 87.4,200.12 87.4,200.28 87.64,200.53 87.8,200.53 87.95,200.37 88.12,200.37 88.36,200.61 88.36,200.78 88.2,200.93 88.2,201.09 88.45,201.33 88.61,201.33 88.76,201.18 88.93,201.18 89.16,201.42 89.16,201.59 89.01,201.74 89.01,201.9 89.25,202.14 89.42,202.14 89.57,201.99 89.73,201.99 89.97,202.23 89.97,202.39 89.82,202.55 89.82,202.71 90.06,202.95 90.22,202.95 90.38,202.8 90.54,202.8 91.61,203.87 92.19,203.87 93.69,205.37 93.69,205.92 93.99,206.23 94.22,206.23 94.35,206.1 94.35,205.37 94.48,205.25 94.75,205.25 94.87,205.37 94.87,206.1 95,206.23 95.44,206.23 95.57,206.1 95.57,205.48 95.8,205.25 96.99,205.25 97.61,205.87 98.8,205.87 98.93,206 98.93,206.29 98.82,206.4 97.26,206.4 97.24,206.42 96.41,206.42 96.28,206.29 96.28,205.86 96.41,205.73 v1(96.64,205.73)
  BOTTOM w0.102: R548.1 97.49,206.55 v2(97.49,205.62) 96.76,205.62 v1(96.64,205.73)
EMMC_DATA_0_R: length 10.8
  TOP w0.102: R67.1 96.93,207.3 97.06,207.17 97.45,207.17 97.57,207.3 97.57,207.94 97.45,208.07 96.93,208.07 96.81,208.2 v4(96.81,208.46) 96.81,208.73 96.93,208.86 97.25,208.86 97.35,208.96 97.35,209.38 97.22,209.51 96.07,209.51 95.94,209.64 95.94,209.94 96.07,210.06 96.83,210.06 96.96,210.19 96.96,210.52 96.83,210.64 96.39,210.64 96.27,210.77 96.27,210.91 96.47,211.11 96.47,212.71 96.16,213.02 U1.A3
EMMC_DATA_1: length 63.2
  TOP w0.102: R65.2 94.88,206.57 95.2,206.88 95.2,208.47 95.11,208.56 v1(95.11,208.59) ; CPU1.T58 78.69,177.29 78.35,177.63 v3(78.3,177.63)
  L4 w0.089: 75.19,180.59 75.19,180.26 76.43,179.02 77.26,179.02 77.79,178.5 77.79,178.19 78.3,177.68 v3(78.3,177.63)
  L4 w0.114: v1(95.11,208.59) 95.08,208.59 94.81,208.85 93.94,208.85 93.69,209.1 90.92,209.1 89.17,207.35 88.71,207.35 78.1,196.74 73.47,196.74 73.33,196.6 73.33,196.12 73.46,195.99 74.89,195.99 75.02,195.86 75.02,193.66 74.53,193.17 73.69,193.17 73.54,193.03 73.54,186.98 73.18,186.62 73.18,186.33 73.35,186.16 73.35,186 73.11,185.75 72.95,185.75 72.38,186.32 72.22,186.32 71.64,185.74 71.64,185.22 71.76,185.1 73.2,185.1 73.32,184.97 73.32,184.68 73.2,184.55 71.76,184.55 71.64,184.42 71.64,184.06 72.37,183.33 72.37,182.29 73.13,181.53 73.54,181.53 74.09,180.98 74.8,180.98 75.19,180.59
  BOTTOM w0.102: v2(94.67,209.42) 95.11,208.99 v1(95.11,208.59) 95.03,208.51 R550.1
EMMC_DATA_1_R: length 6.4
  TOP w0.102: U1.A4 95.66,212.65 95.76,212.56 95.76,211.41 95.44,211.09 95.44,210.47 94.58,209.62 94.58,208.66 94.65,208.6 R65.1
EMMC_DATA_2: length 56.8
  TOP w0.102: v3(78.31,178.35) 78.34,178.35 78.69,178 CPU1.T59 ; R63.2 92.36,206.6 92.96,207.2 92.96,208.61 v1(92.97,208.63)
  L4 w0.089: v3(78.31,178.35) 77.39,179.27 76.66,179.27 75.98,179.95 75.98,180.61 75.57,181.03
  L4 w0.114: v1(92.97,208.63) 91.19,208.63 89.54,206.98 88.86,206.98 77.98,196.09 77.81,196.09 77.54,196.37 77.25,196.37 77.08,196.2 77.08,196.02 77.41,195.69 77.41,195.53 77.17,195.29 77.01,195.29 75.92,196.37 75.69,196.37 75.49,196.17 75.49,195.99 76.6,194.88 76.6,194.72 76.36,194.48 76.2,194.48 75.75,194.93 75.57,194.93 75.39,194.75 75.39,194.48 75.79,194.07 75.79,193.91 74.69,192.8 74.01,192.8 73.91,192.71 73.91,185.97 73.93,185.95 73.93,184.35 73.84,184.25 73.46,184.25 73.34,184.14 73.34,183.79 73.46,183.68 73.8,183.68 73.93,183.55 73.93,182.86 73.73,182.65 72.87,182.65 72.72,182.47 72.72,182.23 72.82,182.13 73.67,182.13 73.74,182.06 73.74,181.76 73.93,181.57 74.17,181.57 74.49,181.9 74.7,181.9 75.57,181.03
  BOTTOM w0.102: v1(92.97,208.63) 93.14,208.8 93.41,208.8 93.71,208.5 v2(93.71,208.5) 93.71,208.5 93.81,208.4 R551.1
EMMC_DATA_2_R: length 13.2
  TOP w0.102: U1.A5 95.16,212.57 95.06,212.47 95.06,211.72 94.81,211.46 94.41,211.46 94.04,211.84 93.84,211.84 93.73,211.73 93.73,211.56 94.26,211.03 94.26,210.88 93.58,210.2 93.49,210.2 92.73,210.96 92.56,210.96 92.44,210.85 92.44,210.68 93.08,210.03 93.08,209.74 92.54,209.2 92.31,209.2 91.65,209.85 91.47,209.85 91.35,209.73 91.35,209.55 92.06,208.84 v4(92.06,208.51) 92.06,208.28 92.36,207.98 R63.1
EMMC_DATA_3: length 62.8
  TOP w0.102: v3(80.21,173.41) 80.21,173.42 79.89,173.73 CPU1.V51 ; R69.2 99.68,207.02 99.68,208.32 v1(99.35,208.65)
  L4 w0.089: 77.07,179.59 77.62,179.59 78.7,178.51 78.7,174.91 v3(80.21,173.41)
  L4 w0.114: v1(99.35,208.65) 99.35,208.44 99.56,208.23 100.24,208.23 100.38,208.37 100.38,208.97 99.77,209.58 97.73,209.58 96.45,208.3 95.63,208.3 95.46,208.12 91.37,208.12 89.71,206.46 88.87,206.46 74.3,191.9 74.3,182.7 76.21,180.8 76.21,180.45 77.07,179.59
  BOTTOM w0.102: R557.1 100.31,207.69 v1(99.35,208.65) 99.18,208.65 v2(98.41,209.42)
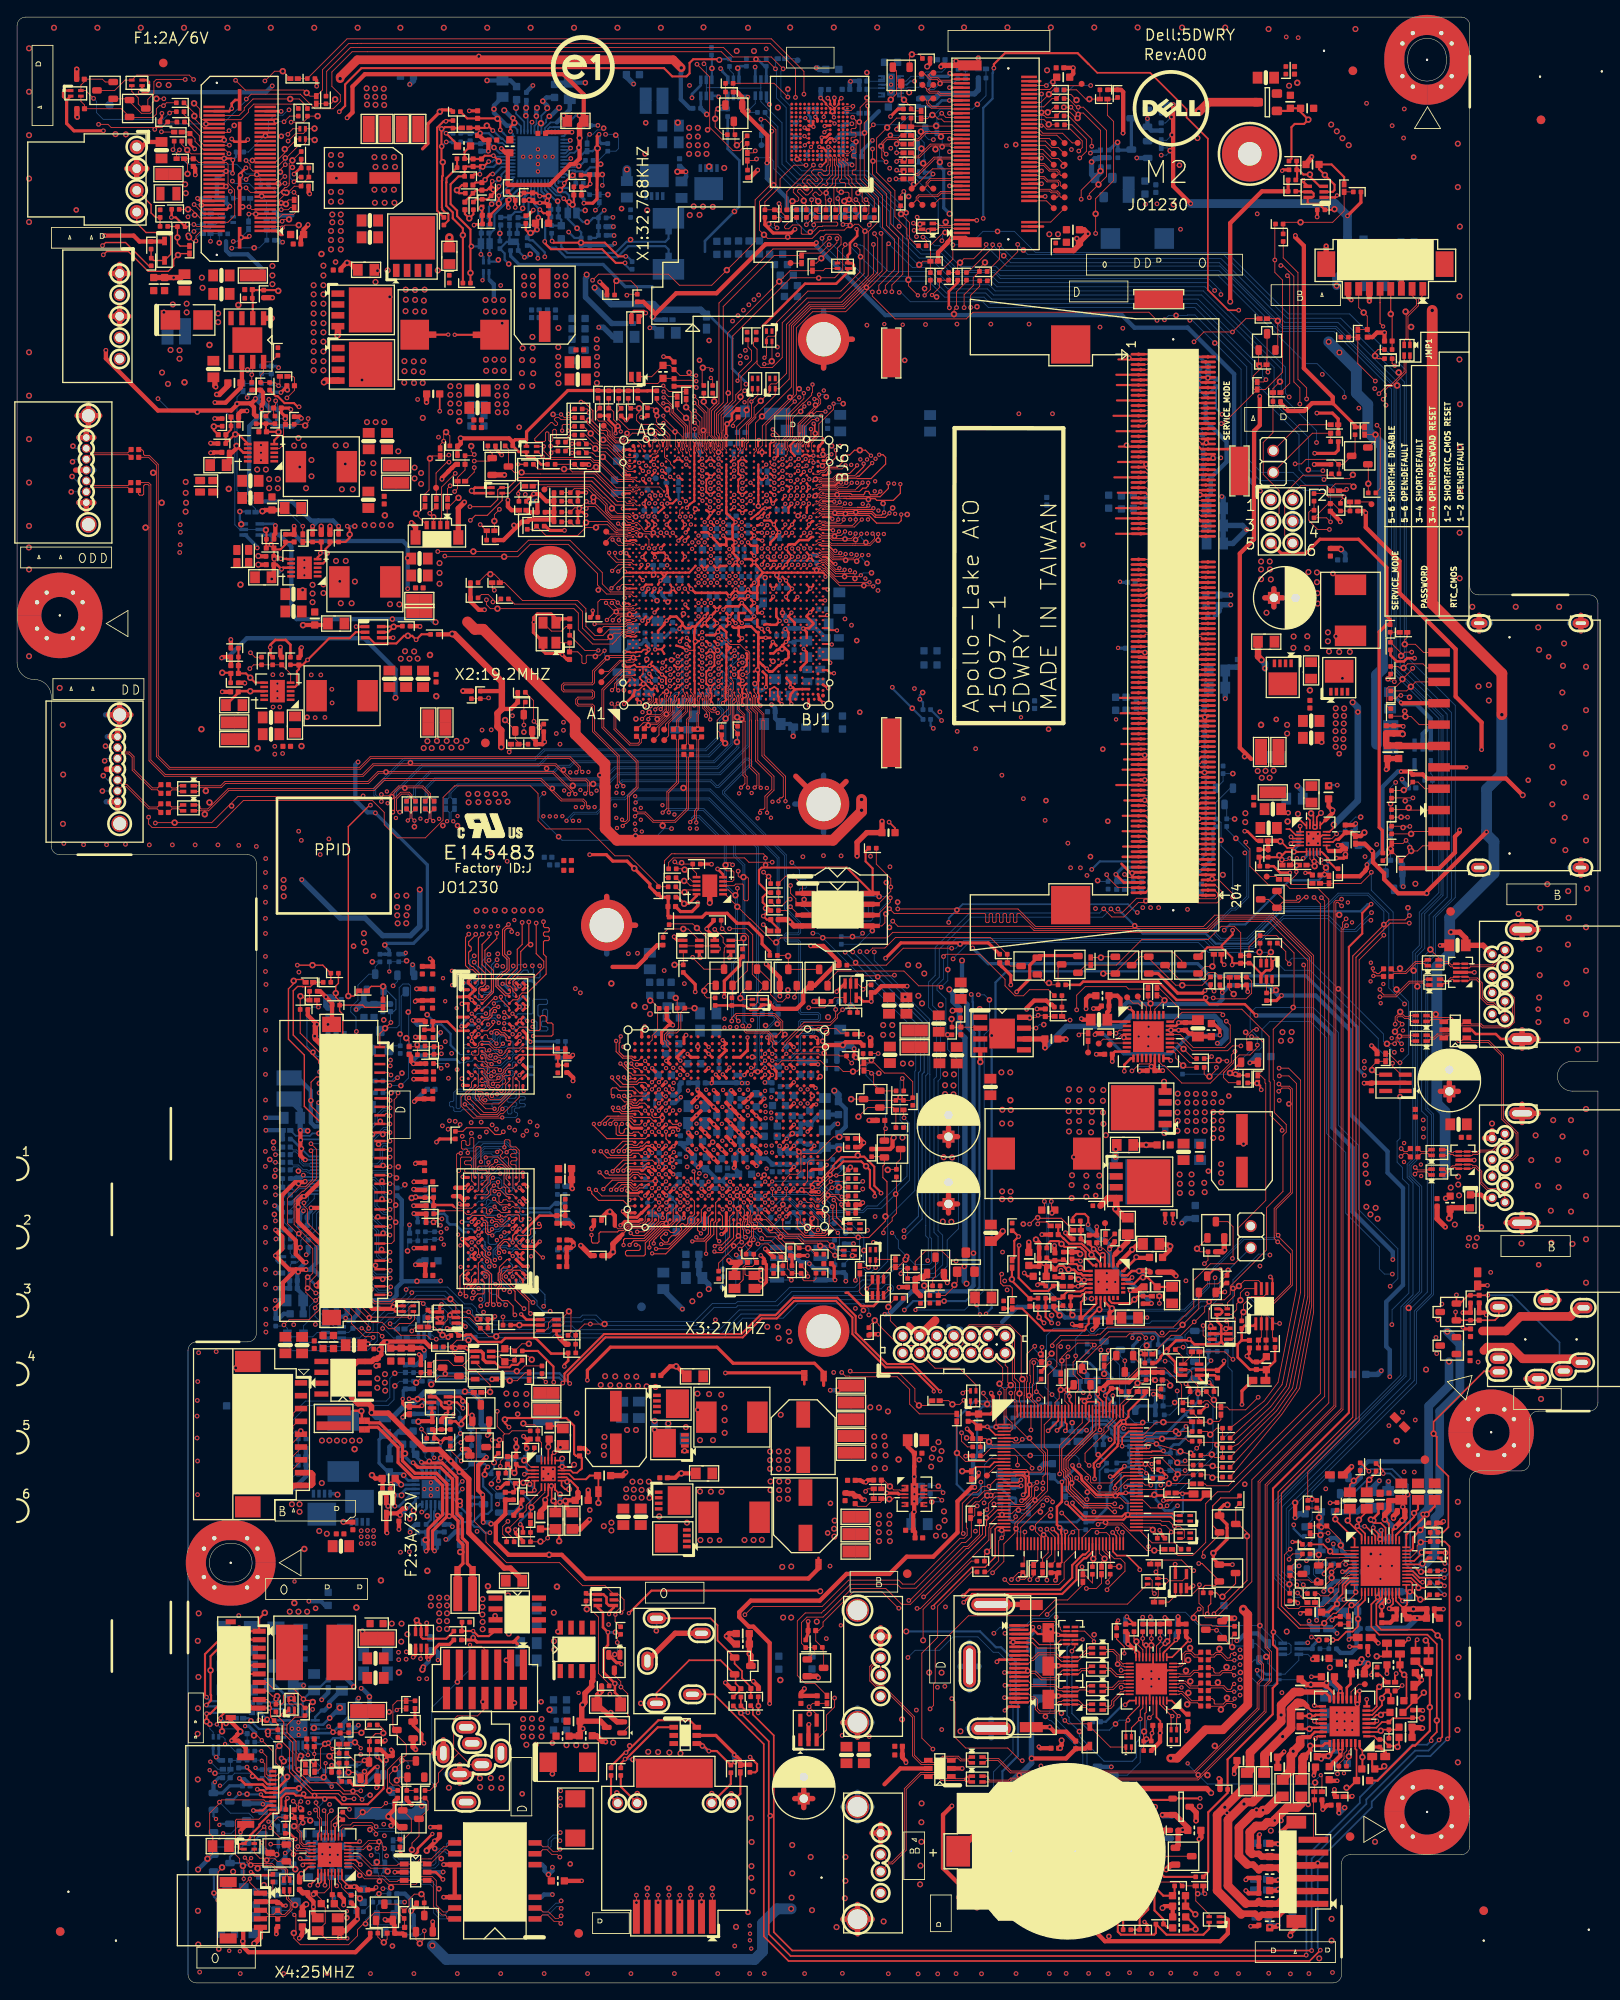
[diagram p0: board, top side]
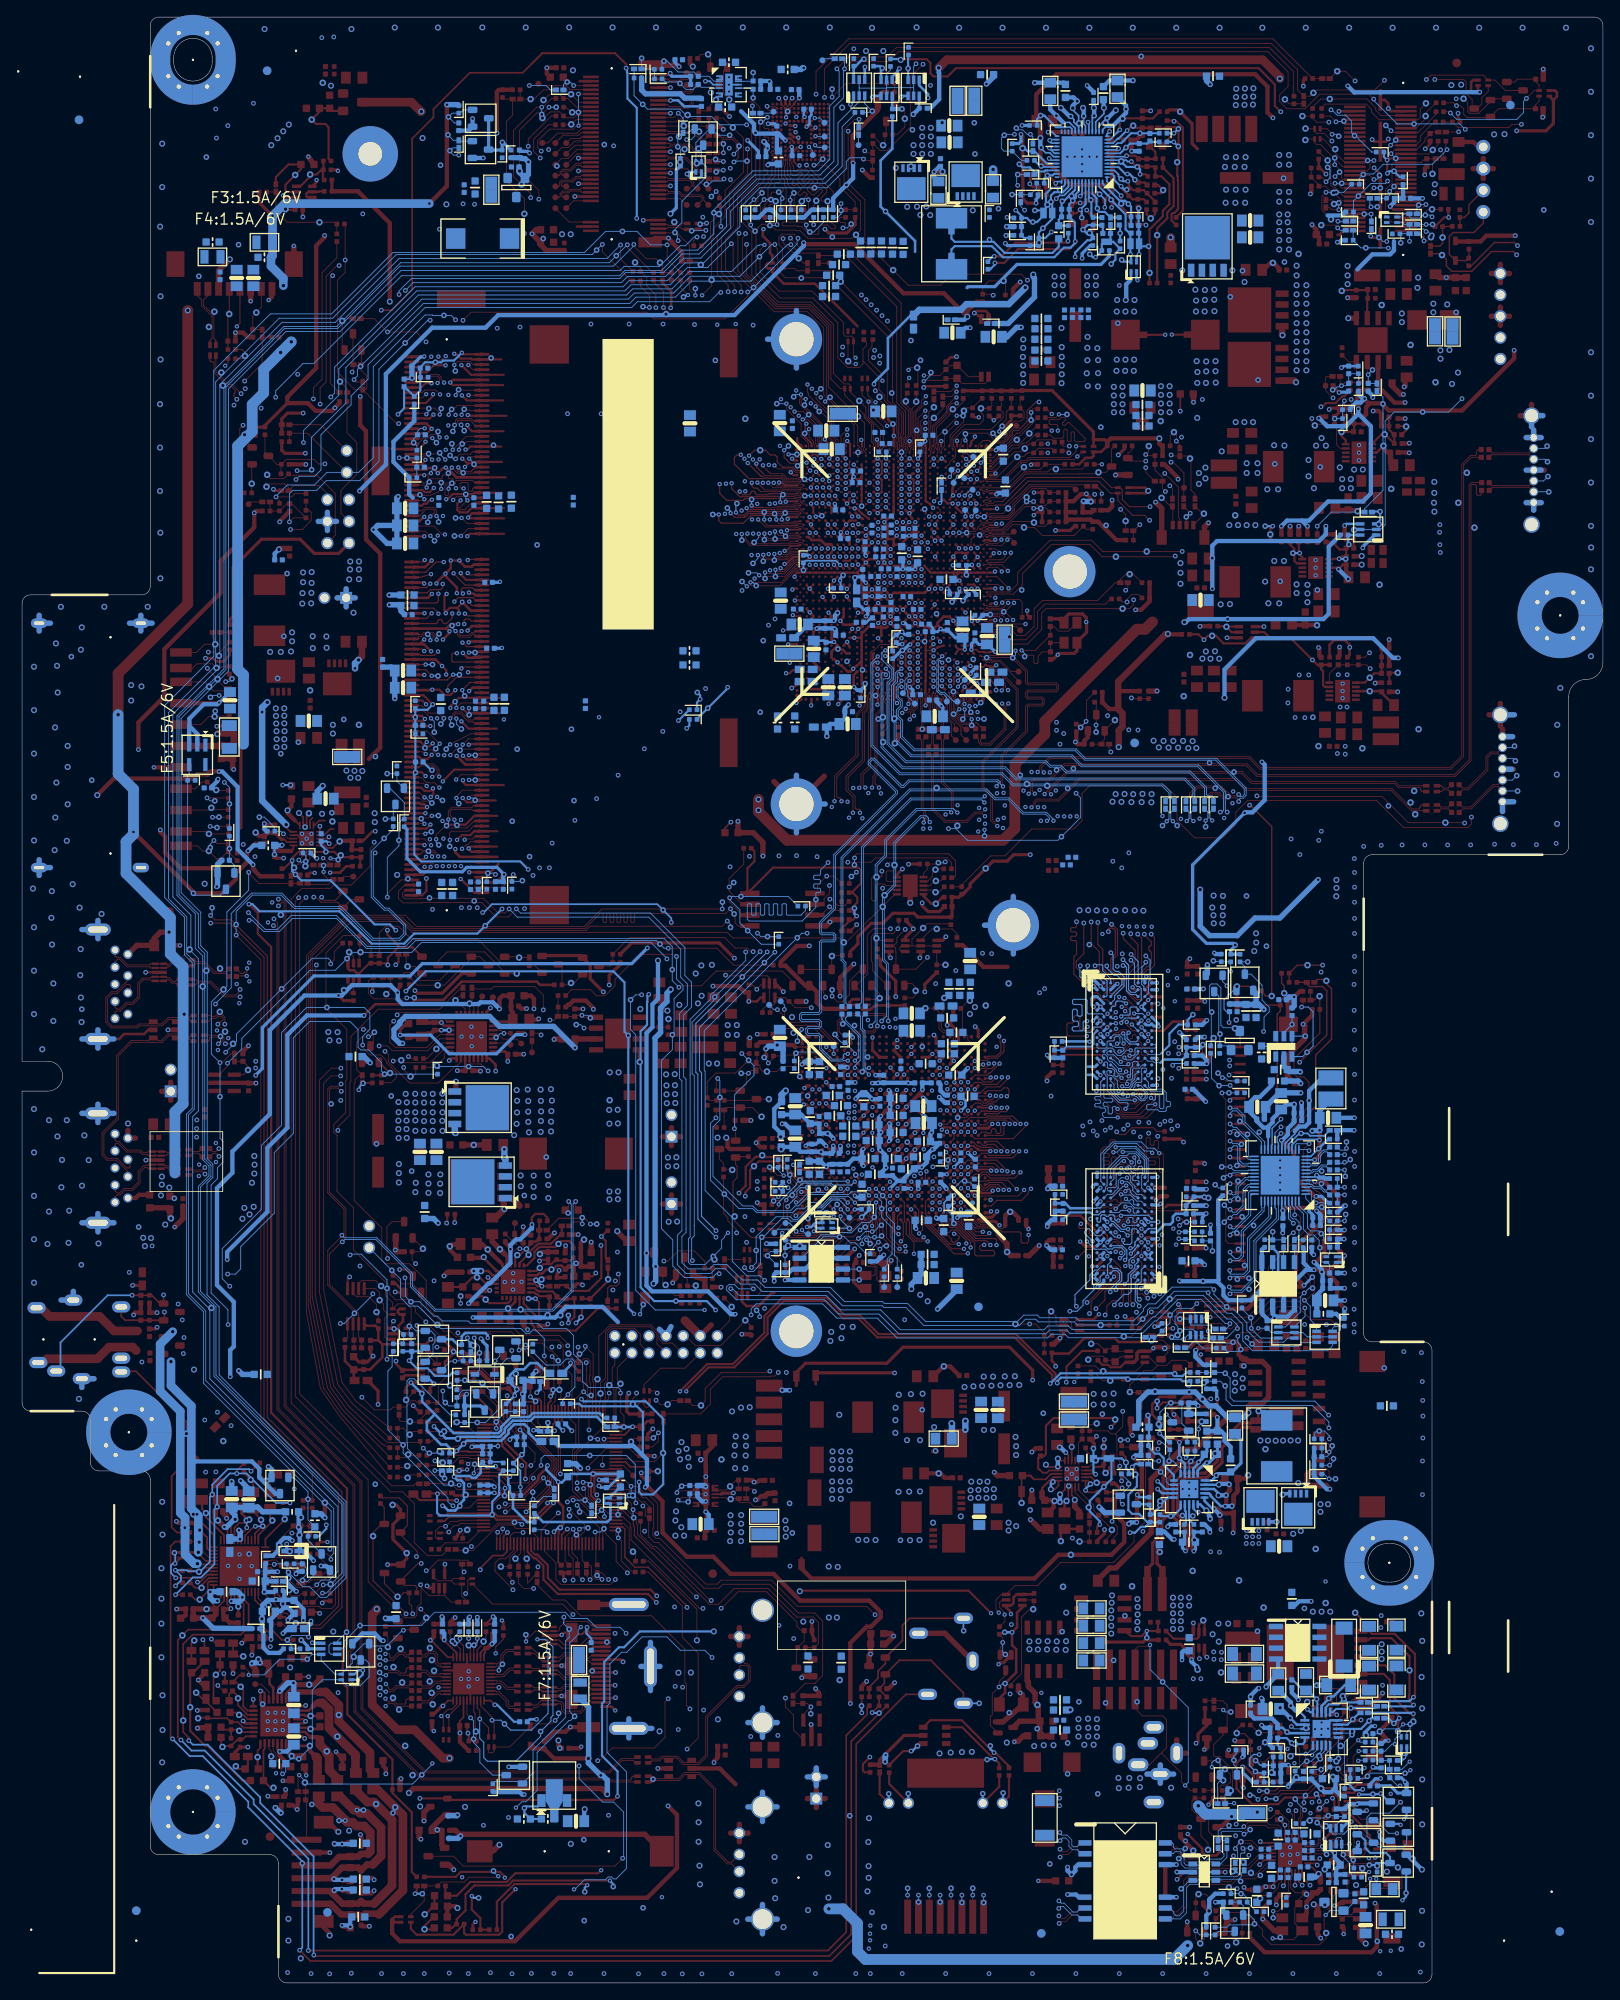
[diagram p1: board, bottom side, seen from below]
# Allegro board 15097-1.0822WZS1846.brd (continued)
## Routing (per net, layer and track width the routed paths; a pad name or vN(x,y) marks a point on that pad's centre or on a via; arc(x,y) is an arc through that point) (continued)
EMMC_DATA_3_R: length 7.4
  TOP w0.089: U1.B2 96.66,213.78 96.91,213.54 96.91,213.14
  TOP w0.102: 96.91,213.14 97.25,212.8 97.25,211.5 97.69,211.06 97.69,210.62 98.89,209.42 98.89,208.46 99.22,208.13 R69.1
EMMC_DATA_4: length 62.6
  TOP w0.102: v3(80.2,174.11) 79.87,174.44 CPU1.V52 ; v1(98.16,208.65) 98.59,208.22 98.59,207.07 R68.2
  L4 w0.089: 76.62,180.74 76.62,180.42 77.25,179.78 77.68,179.78 78.88,178.59 78.88,175.43 79.08,175.23 79.08,175.1 79,175.02 79,174.9 79.19,174.71 79.32,174.71 79.4,174.79 79.52,174.79 79.71,174.6 79.71,174.42 80.02,174.11 v3(80.2,174.11)
  L4 w0.114: 76.62,180.74 75.45,181.91 75.39,181.91 74.51,182.79 74.51,184.07 74.62,184.18 74.85,184.18 74.96,184.3 74.96,184.64 74.85,184.75 74.62,184.75 74.51,184.87 74.51,185.27 74.62,185.38 74.78,185.38 74.9,185.5 74.9,185.84 74.78,185.95 74.62,185.95 74.51,186.07 74.51,186.41 74.62,186.53 74.78,186.53 74.9,186.64 74.9,186.98 74.78,187.1 74.62,187.1 74.51,187.21 74.51,187.55 74.62,187.67 74.78,187.67 74.9,187.78 74.9,188.13 74.78,188.24 74.62,188.24 74.51,188.35 74.51,188.95 74.67,189.12 74.67,191.75 89.02,206.1 89.86,206.1 91.52,207.76 95.61,207.76 95.78,207.93 96.64,207.93 97.87,209.16 98.55,209.16 98.75,208.97 98.75,208.04 98.62,207.91 97.89,207.91 97.76,208.04 97.76,208.25 v1(98.16,208.65)
  BOTTOM w0.102: v2(97.37,208.65) 97.38,208.65 v1(98.16,208.65) 99.22,207.59 R547.1
EMMC_DATA_4_R: length 7.2
  TOP w0.089: 96.6,212.95 96.41,213.14 96.41,213.57 U1.B3
  TOP w0.102: R68.1 98.08,208.09 97.7,208.46 97.7,210.11 97.34,210.47 97.34,210.91 96.87,211.38 96.87,212.68 96.6,212.95
EMMC_DATA_5: length 64
  TOP w0.102: v3(81.08,172.63) 80.7,173.02 CPU1.Y49 ; R66.2 96.25,207.03 96.25,208.18 v1(96.04,208.78)
  L4 w0.114: v3(81.08,172.63) 80,172.76 78.1,174.66 77.82,176.44 74.56,179.71 73.36,180.2 72.32,181.25 71.76,182.3 71.76,182.94 70.81,183.88 70.81,195.36 73,197.54 77.85,197.54 78.05,197.74 78.27,197.96 78.27,197.96 88.95,208.64 90.77,209.47 90.77,209.47 93.84,209.47 93.85,209.47 94.36,209.47 v1(96.04,208.78)
  BOTTOM w0.102: v2(96.45,209.52) 96.04,209.12 v1(96.04,208.78) 96.04,208.68 96.2,208.53 R549.1
EMMC_DATA_5_R: length 6.8
  TOP w0.089: 96.09,212.54 95.91,212.73 95.91,213.57 U1.B4
  TOP w0.102: 96.09,212.54 96.11,212.53 96.11,211.26 95.79,210.94 95.79,210.33 95.59,210.12 95.59,208.28 R66.1
EMMC_DATA_6: length 54
  TOP w0.102: v3(80.2,175.54) 79.87,175.87 CPU1.V55 ; R64.2 93.21,206.57 v1(92.36,205.71)
  L4 w0.089: 77.43,181.04 78.12,180.35 78.12,180.2 79.23,179.08 79.23,176.87 79.49,176.61 79.49,176.43 79.23,176.17 79.23,175.63 79.61,175.26 80.07,175.26 80.2,175.39 v3(80.2,175.54)
  L4 w0.114: 77.43,181.04 77.39,181.08 77.17,181.08 76.97,181.28 76.97,181.6 77.14,181.77 77.14,182.05 77.03,182.16 76.98,182.16 76.87,182.27 76.87,182.62 76.98,182.73 77.08,182.73 77.21,182.86 77.21,183.27 77.08,183.4 76.92,183.4 76.81,183.51 76.81,183.86 76.92,183.97 77.07,183.97 77.2,184.1 77.2,184.45 77.07,184.57 76.18,184.57 76.05,184.7 76.05,185.02 76.18,185.15 77.05,185.15 77.18,185.27 77.18,185.59 77.05,185.72 76.24,185.72 76.11,185.84 76.11,186.16 76.24,186.29 77.03,186.29 77.14,186.4 77.14,190.44 77.32,190.62 77.32,190.85 77.14,191.03 77.14,191.24 77.38,191.48 77.54,191.48 77.82,191.2 77.98,191.2 78.22,191.44 78.22,191.6 77.95,191.88 77.95,192.04 78.19,192.28 78.35,192.28 78.63,192.01 78.79,192.01 79.03,192.25 79.03,192.41 78.76,192.69 78.76,192.85 79,193.09 79.16,193.09 79.44,192.82 79.6,192.82 79.84,193.06 79.84,193.22 79.56,193.5 79.56,193.66 79.84,193.94 80.01,193.94 80.23,193.72 80.41,193.72 80.63,193.94 80.63,194.12 80.41,194.34 80.41,194.51 80.96,195.05 81.12,195.05 81.44,195.37 81.44,195.54 81.76,195.86 81.93,195.86 82.25,196.18 82.25,196.35 82.57,196.67 82.74,196.67 83.06,196.99 83.06,197.15 83.38,197.48 83.55,197.48 83.87,197.8 83.87,197.96 84.19,198.28 84.35,198.28 84.68,198.61 84.68,198.77 85,199.09 85.16,199.09 85.48,199.41 85.48,199.58 85.81,199.9 85.97,199.9 86.29,200.22 86.29,200.39 86.61,200.71 86.78,200.71 87.1,201.03 87.1,201.2 87.42,201.52 87.59,201.52 87.91,201.84 87.91,202 88.23,202.33 88.4,202.33 88.72,202.65 88.72,202.81 89.04,203.13 89.2,203.13 89.56,203.48 89.56,203.65 90.48,204.57 90.73,204.57 90.89,204.41 91.06,204.41 91.28,204.64 91.65,204.64 91.89,204.88 91.89,205.25 91.68,205.47 91.68,205.77 92.13,206.23 92.51,206.23 92.6,206.14 92.6,205.96 v1(92.36,205.71)
  BOTTOM w0.102: R552.1 v1(92.36,205.71)
EMMC_DATA_6_R: length 11
  TOP w0.089: 95.09,211.23 95.41,211.55 95.41,213.63 95.22,213.82 U1.B5
  TOP w0.102: R64.1 93.51,207.25 93.72,207.04 94.06,207.04 94.19,207.16 94.19,208 v4(93.76,208.43) 93.76,208.56 93.45,208.86 93.43,208.86 93.13,209.16 93.13,209.29 93.37,209.52 93.5,209.52 93.87,209.15 94.02,209.15 94.2,209.33 94.2,209.47 93.84,209.84 93.84,209.95 94.31,210.42 94.45,210.42 94.59,210.28 94.74,210.28 94.88,210.42 94.88,210.57 94.74,210.71 94.74,210.85 95.09,211.2 95.09,211.23
EMMC_DATA_7: length 55
  TOP w0.102: R62.2 90.87,206.57 90.36,206.05 90.33,206.05 89.81,205.53 89.81,205.36 89.94,205.23 90.3,205.23 90.75,205.68 91.51,205.68 91.76,205.43 91.76,204.7 91.87,204.6 92.85,204.6 93.75,205.49 94.2,205.49 94.27,205.56 95.91,205.56 96.04,205.69 96.04,205.9 95.91,206.02 93.35,206.02 93.23,205.9 v1(93.23,205.69) ; CPU1.V57 79.87,176.58 80.18,176.26 v3(80.18,176.24)
  L4 w0.089: v3(80.18,176.24) 79.41,177.01 79.41,179.15 78.35,180.21 78.35,180.43 77.7,181.08
  L4 w0.114: v1(93.23,205.69) 91.8,204.27 91.44,204.27 90.76,203.59 90.18,203.59 81.11,194.52 81.11,193.81 77.51,190.21 77.51,181.27 77.7,181.08
  BOTTOM w0.102: v1(93.23,205.69) 93.23,205.26 v2(92.82,204.85) 92.36,204.85 91.22,205.99 R62.2
EMMC_DATA_7_R: length 15.3
  TOP w0.089: U1.B6 94.72,213.82 94.91,213.63 94.91,212.75
  TOP w0.102: R62.1 90.85,207.45 90.53,207.77 90.53,208.25 v4(90.74,208.46) 91.35,208.46 91.47,208.58 91.47,208.86 90.84,209.5 90.84,209.8 91.39,210.36 91.66,210.36 92.36,209.67 92.5,209.67 92.65,209.81 92.65,209.96 91.91,210.7 91.91,210.88 92.52,211.49 92.7,211.49 93.43,210.76 93.6,210.76 93.72,210.88 93.72,211.05 92.97,211.8 92.97,211.94 93.23,212.19 94.18,212.19 94.41,211.97 94.6,211.97 94.7,212.07 94.7,212.54 94.91,212.75
EMMC_E9: length 1.7
  TOP w0.102: U1.E9 93.16,215.06 92.91,214.82 v3(92.91,214.8)
  BOTTOM w0.102: v3(92.91,214.8) 92.46,214.35 TP60.1
EMMC_E10: length 1.8
  TOP w0.102: U1.E10 92.47,215.32 92.18,215.03 v3(92.18,215.01)
  BOTTOM w0.102: TP59.1 91.93,214.75 v3(92.18,215.01)
EMMC_F10: length 1.7
  TOP w0.102: v3(92.15,216.07) 92.15,216.06 92.39,215.82 U1.F10
  BOTTOM w0.102: v3(92.15,216.07) 92.1,216.02 TP57.1
EMMC_K10: length 1.9
  TOP w0.102: v3(92.24,218.18) 92.6,217.82 U1.K10
  BOTTOM w0.102: v3(92.24,218.18) 91.64,218.18 TP56.1
EMMC_RCLK: length 49.2
  TOP w0.102: R60.1 89.26,206.57 89.39,206.44 89.39,206.15 89.22,205.98 88.73,205.98 88.62,205.86 88.62,205.65 v1(88.93,205.33) ; CPU1.V54 80.13,174.8 v3(80.17,174.8)
  L4 w0.089: v3(80.17,174.8) 80,174.97 79.46,174.97 79.34,175.08 79.34,175.27 79.06,175.56 79.06,178.99 78.65,179.39 78.53,179.39 78.49,179.35 78.36,179.35 78.17,179.54 78.17,179.67 78.21,179.71 78.21,179.83 78.06,179.99 77.3,179.99 76.92,180.37 76.92,180.39
  L4 w0.114: v1(88.93,205.33) 88.93,205.17 88.48,204.72 88.34,204.72 83.51,199.88 83.51,199.74 83.28,199.51 83.13,199.51 82.67,199.04 82.67,198.9 82.28,198.51 82.14,198.51 76.7,193.07 76.7,192.93 76.39,192.62 76.25,192.62 75.35,191.73 75.35,191.53 75.48,191.4 75.54,191.4 75.63,191.31 75.63,190.98 75.54,190.89 75.29,190.89 75.17,190.77 75.17,189.69 75.28,189.58 75.56,189.58 75.67,189.46 75.67,189.12 75.56,189.01 75.28,189.01 75.17,188.89 75.17,188.55 75.28,188.43 75.71,188.43 75.82,188.32 75.82,187.98 75.71,187.86 75.28,187.86 75.17,187.75 75.17,184 75.34,183.83 75.58,183.83 75.69,183.94 75.69,184.26 75.8,184.38 76.1,184.38 76.21,184.26 76.21,183.65 76.33,183.54 76.49,183.54 76.61,183.43 76.61,183.08 76.49,182.97 76.23,182.97 76.12,182.85 76.12,182.55 76.25,182.42 76.54,182.42 76.66,182.29 76.66,182.07 76.54,181.95 76.15,181.95 76.03,181.84 76.03,181.61 76.76,180.89 76.8,180.89 76.92,180.78 76.92,180.39
  BOTTOM w0.102: v2(87.97,205.79) 88.43,205.33 v1(88.93,205.33)
EMMC_RCLK_R: length 17.4
  TOP w0.102: R60.2 R59.1 87.51,208.38 89.29,210.16 89.29,211.07 90.89,212.67 v1(92.32,212.67) ; U1.H5 94.79,216.82 94.51,216.54 v3(94.47,216.54)
  L3 w0.114: v1(92.32,212.67) 92.37,212.67 93.17,213.47 93.46,213.47 93.59,213.61 94.34,213.61 95.37,214.64 95.37,215 95.07,215.3 95.07,215.94 v3(94.47,216.54)
  BOTTOM w0.102: v1(92.32,212.67) 92.06,212.67 91.35,213.39 v2(91.3,213.39)
EMMC_RCOMP: length 1.4
  TOP w0.254: v3(80.16,178.34) 80.16,178.34 80.13,178.31 80.11,178.31 79.81,178 CPU1.V59
  BOTTOM w0.254: R583.2 79.92,178.62 80.15,178.39 80.15,178.35 v3(80.16,178.34)
EMMC_RESET#: length 7.7
  TOP w0.102: R32.1 82.59,216.25 81.69,217.14 v4(81.69,218.11) 81.69,219.02 82.37,219.7 Q5.S 82.89,221.22 R11.2 R7.1
EMMC_RESET#_R: length 16.3
  TOP w0.102: v3(95.65,217.55) 95.64,217.55 95.37,217.82 U1.K5 ; R7.2 88.59,222.25 v1(90.2,220.64)
  L4 w0.127: v3(95.65,217.55) 95.5,217.71 91.53,217.71 90.2,219.03 v1(90.2,220.64)
  BOTTOM w0.102: v1(90.2,220.64) v2(90.2,221.58)
EMMC_VDDI: length 3.5
  TOP w0.089: U1.C2 96.91,214.07 97.32,214.07 97.69,214.43 97.69,214.59 v3(97.74,214.65)
  BOTTOM w0.508: C248.2 97.94,214.45 v3(97.74,214.65) 97.74,214.98 v2(98.18,215.42)
EQ: length 4.9
  TOP w0.127: R420.2 v1(131.72,40.29) 131.72,39.56 132.14,39.14 U20.17
  BOTTOM w0.127: R420.2 v1(131.72,40.29) 131.72,39.91 v2(132.11,39.52)
F_USB0N: length 127.7
  TOP w0.102: CPU1.V10 v3(80.17,154.48) ; v4(161.25,111.3) 161.25,111.33 162.09,112.17 v1(162.09,112.17) 162.09,112.24 161.89,112.43 161.72,112.43 161.49,112.66 161.49,112.93 161.6,113.04 162.15,113.04 162.35,112.84 162.83,112.84 163.18,112.5 TR3.2
  L4 w0.089: 79.97,150.71 79.97,150.82 79.94,150.86 79.94,151.13 79.77,151.3 79.77,154.69 79.89,154.81 80.05,154.81 80.17,154.69 v3(80.17,154.48)
  L4 w0.127: v1(162.09,112.17) 161.81,112.45 161.81,115.85 161.94,115.97 163.4,115.97 163.69,116.26 163.69,116.86 163.4,117.14 161.94,117.14 161.81,117.27 161.81,117.65 161.94,117.78 163.4,117.78 163.69,118.06 163.69,118.66 163.4,118.95 161.94,118.95 161.81,119.07 161.81,119.71 161.07,120.45 161.07,120.63 162.64,122.21 162.64,122.66 162.26,123.04 161.82,123.04 160.24,121.46 160.06,121.46 156.1,125.42 139.93,125.42 139.01,124.5 125.29,124.5 125.1,124.69 125.1,125.32 124.8,125.63 124.07,125.63 123.78,125.35 123.78,124.84 123.44,124.5 122.73,124.5 101.05,146.18 81.95,146.18 79.97,148.15 79.97,150.71
F_USB0N_H: length 160.5
  TOP w0.102: 161.95,188.15 162.32,188.51 TR2.3 ; 161.95,188.15 v4(161.68,188.42) ; 161.95,188.15 160.8,186.99 160.42,186.99 v1(159.37,185.95) ; CPU1.AC10 v3(82.08,154.48)
  L4 w0.089: v3(82.08,154.48) 82.08,154.51 82.28,154.72 82.41,154.72 82.49,154.64 82.49,151.02 82.45,150.98 82.45,150.96
  L4 w0.127: v1(159.37,185.95) 159.71,186.28 160.58,186.28 160.99,185.87 164.64,182.23 164.64,156.52 165,156.16 165,134.4 159.04,128.45 122.52,128.45 102.32,148.64 84.66,148.64 82.45,150.85 82.45,150.96
F_USB0P: length 126.9
  TOP w0.102: TR3.3 162.97,113.18 162.85,113.06 162.44,113.06 162.24,113.26 161.86,113.26 ; v1(161.27,112.17) 161.27,113.02 161.51,113.26 161.86,113.26 ; 161.86,113.26 v4(161.86,113.61) ; CPU1.V12 v3(80.17,155.19)
  L4 w0.089: v3(80.17,155.19) 79.99,155 79.81,155 79.58,154.77 79.58,151.22 79.75,151.05 79.75,150.86 79.71,150.82 79.71,150.71
  L4 w0.127: v1(161.27,112.17) 161.54,112.44 161.54,115.96 161.82,116.24 163.29,116.24 163.42,116.37 163.42,116.75 163.29,116.88 161.82,116.88 161.54,117.16 161.54,117.76 161.82,118.04 163.29,118.04 163.42,118.17 163.42,118.55 163.29,118.68 161.82,118.68 161.54,118.96 161.54,119.6 160.8,120.34 160.8,120.74 162.37,122.32 162.37,122.55 162.15,122.77 161.93,122.77 160.35,121.19 159.95,121.19 155.99,125.15 140.04,125.15 139.12,124.23 125.18,124.23 124.84,124.58 124.84,125.21 124.69,125.36 124.18,125.36 124.05,125.23 124.05,124.73 123.55,124.23 122.62,124.23 100.94,145.91 81.84,145.91 79.71,148.04 79.71,150.71
F_USB0P_H: length 160.5
  TOP w0.102: 161.25,187.14 160.89,186.78 160.51,186.78 160.05,186.32 160.05,186.08 160.21,185.93 160.21,185.62 v1(159.87,185.28) ; 161.25,187.14 162.53,188.42 162.53,189.53 162.67,189.66 162.87,189.66 163,189.79 TR2.2 ; 161.25,187.14 v4(161.5,186.89) ; CPU1.AC12 82.09,155.2 82.09,155.19 v3(82.06,155.16)
  L4 w0.089: v3(82.06,155.16) 82.06,155.16 82.31,154.91 82.49,154.91 82.68,154.72 82.68,151.02 82.71,150.98 82.71,150.96
  L4 w0.127: 82.71,150.96 84.77,148.91 102.44,148.91 122.63,128.71 158.93,128.71 164.73,134.51 164.73,156.05 164.37,156.41 164.37,182.12 160.8,185.69 160.47,186.02 160.02,186.02 159.87,185.86 v1(159.87,185.28)
F_USB1N: length 120.6
  TOP w0.102: v1(162.02,109.88) 161.86,109.88 161.59,110.15 161.59,110.48 161.77,110.66 162.96,110.66 163.05,110.57 163.05,110.31 163.17,110.19 TR4.2 ; CPU1.V15 v3(80.17,157.32)
  L4 w0.089: 78.14,148.97 78.14,149 78.1,149.03 78.1,149.78 78.96,150.63 78.96,156.93 79.58,157.55 79.95,157.55 v3(80.17,157.32)
  L4 w0.127: v1(162.02,109.88) 161.65,110.25 161.65,110.82 160.61,111.86 160.61,119.63 157.55,122.69 121.92,122.69 100.24,144.37 81.2,144.37 78.14,147.44 78.14,148.97
  BOTTOM w0.102: v1(162.02,109.88) 161.78,110.12 v2(161.78,110.74)
F_USB1N_H: length 228.4
  TOP w0.102: v3(81.13,155.19) 81.07,155.24 80.74,155.24 80.65,155.16 CPU1.Y10 ; TR1.3 105.71,205.85 105.47,205.61 105.18,205.61 v1(104.9,205.89)
  L4 w0.089: 81.74,150.99 81.74,151.02 81.69,151.06 81.69,154.97 81.67,154.99 81.67,155.41 81.58,155.5 81.22,155.5 81.13,155.41 v3(81.13,155.19)
  L4 w0.127: v1(104.9,205.89) 104.9,205.7 104.51,205.31 104.2,205.31 104.05,205.46 104.05,205.81 103.8,206.05 103.8,206.68 104.19,207.06 107.19,207.06 108.89,205.36 116.43,205.36 118.04,203.75 143.55,203.75 159.03,188.28 159.49,188.28 165.27,182.49 165.27,157.01 165.64,156.64 165.64,133.14 160.31,127.81 122.19,127.81 102.02,147.98 83.73,147.98 82.13,149.58 82.13,150.08 81.74,150.47 81.74,150.99
  BOTTOM w0.102: v2(105.65,205.77) 105.52,205.89 v1(104.9,205.89)
F_USB1P: length 120.7
  TOP w0.102: v4(160.31,109.88) v1(161.21,109.88) 161.37,110.05 161.37,110.57 161.68,110.88 TR4.3 ; CPU1.V16 v3(80.17,158.03)
  L4 w0.089: 77.87,148.97 77.87,149 77.91,149.03 77.91,149.85 78.77,150.71 78.77,157.01 79.5,157.74 79.88,157.74 v3(80.17,158.03)
  L4 w0.127: 77.87,148.97 77.87,147.33 81.09,144.11 100.13,144.11 121.81,122.43 157.44,122.43 160.35,119.52 160.35,111.75 161.38,110.71 161.38,110.06 v1(161.21,109.88)
F_USB1P_H: length 229.2
  TOP w0.102: v1(104.97,205.05) 105.09,205.17 TR1.2 ; CPU1.Y9 v3(81.13,154.48)
  L4 w0.089: v3(81.13,154.48) 81.35,154.48 81.48,154.35 81.51,154.31 81.51,151.06 81.47,151.02 81.47,150.99
  L4 w0.127: v1(104.97,205.05) 104.09,205.05 103.78,205.35 103.78,205.7 103.54,205.94 103.54,206.79 104.08,207.33 107.3,207.33 109,205.63 116.54,205.63 118.15,204.02 143.66,204.02 159.14,188.54 159.6,188.54 165.54,182.6 165.54,157.12 165.91,156.75 165.91,133.03 160.42,127.54 122.08,127.54 101.91,147.71 83.62,147.71 81.86,149.47 81.86,149.97 81.47,150.36 81.47,150.99
  BOTTOM w0.102: v2(106.64,205) 106.59,205 106.55,205.05 v1(104.97,205.05)
F_USB2N: length 224.7
  TOP w0.102: v4(154.72,124.97) 154.33,124.97 ; 154.33,124.97 154.33,67.45 145.45,58.57 145.45,37.72 145.87,37.3 145.87,35.57 145.33,35.04 145.33,32.04 137.87,24.57 116.23,24.57 114.79,26.02 113.46,26.02 113.18,25.74 TR9.3 ; 154.33,124.97 154.33,126.34 154.43,126.44 154.57,126.44 v1(155,126.01) ; CPU1.V7 v3(80.17,153.05)
  L4 w0.089: 80.52,151.2 80.52,151.22 80.56,151.27 80.56,152.89 80.4,153.05 v3(80.17,153.05)
  L4 w0.127: v1(155,126.01) 154.82,126.19 141.78,126.19 141.52,126.44 121.74,126.44 101.37,146.81 82.71,146.81 80.52,149.01 80.52,151.2
F_USB2N_H: length 202.1
  TOP w0.102: CPU1.V6 v3(80.17,152.34) ; v3(27.38,14.61) 27.13,14.35 27.13,14.17 27.33,13.97 29.85,13.97 30.26,13.56 31.3,13.56 31.66,13.2 31.66,12.52 31.9,12.28 TR11.3
  L3 w0.127: v3(80.17,152.34) 80.72,151.8 80.72,151.47 81.04,151.14 82.15,151.14 83.51,149.79 83.51,146.28 77,139.78 75.85,139.78 74.07,138 74.07,135.54 73.7,135.17 72.62,135.17 v3(72.37,134.91)
  L4 w0.127: v3(72.37,134.91) 72.12,134.91 71.67,134.47 71.3,134.47 69.58,132.74 55.2,132.74 52.17,129.71 44,129.71 38.68,124.39 38.68,85.36 35.9,82.58 35.9,76.48 28.4,68.98 28.4,56.4 41.1,43.7 41.1,33.3 35.49,27.69 35.49,23.01 37.61,20.89 37.61,19.71 36.01,18.11 30.91,18.11 30.18,17.38 28.58,17.38 27.38,16.18 v3(27.38,14.61)
  BOTTOM w0.102: v3(72.37,134.91) v2(72.37,134.19)
F_USB2P: length 224.8
  TOP w0.102: CPU1.V9 v3(80.17,153.77) ; v4(140.16,27.74) 140.44,27.46 ; 140.44,27.46 137.78,24.79 116.32,24.79 114.88,26.24 113.37,26.24 113.18,26.43 TR9.2 ; 140.44,27.46 145.12,32.13 145.12,35.13 145.65,35.66 145.65,37.21 145.23,37.63 145.23,58.66 154.11,67.54 154.11,126.43 154.34,126.66 154.86,126.66 v1(155,126.8)
  L4 w0.089: 80.78,151.2 80.78,151.22 80.74,151.27 80.74,153.2 v3(80.17,153.77)
  L4 w0.127: 80.78,151.2 80.78,149.12 82.82,147.08 101.48,147.08 121.85,126.71 141.64,126.71 141.89,126.46 154.66,126.46 v1(155,126.8)
F_USB2P_H: length 201.7
  TOP w0.102: CPU1.V5 v3(80.17,151.63) ; 28.15,13.75 27.24,13.75 26.91,14.08 26.91,14.4 v3(26.65,14.66) ; 28.15,13.75 v4(28.15,13.4) ; 28.15,13.75 29.76,13.75 30.17,13.35 31.21,13.35 31.45,13.11 31.45,12.49 31.21,12.26 TR11.2
  L3 w0.127: v3(72.31,135.62) 72.5,135.43 73.59,135.43 73.81,135.65 73.81,138.11 75.74,140.04 76.89,140.04 83.24,146.39 83.24,149.68 82.04,150.88 80.93,150.88 v3(80.17,151.63)
  L4 w0.127: v3(72.31,135.62) 72.17,135.76 71.94,135.76 71.81,135.64 71.81,134.99 71.56,134.73 71.19,134.73 69.47,133.01 55.09,133.01 52.06,129.98 43.89,129.98 38.41,124.5 38.41,85.47 35.63,82.69 35.63,76.59 28.13,69.09 28.13,56.29 40.84,43.59 40.84,33.41 35.22,27.8 35.22,22.9 37.35,20.78 37.35,19.82 35.9,18.38 30.8,18.38 30.07,17.65 28.47,17.65 27.12,16.29 27.12,15.12 v3(26.65,14.66)
F_USB3N: length 231
  TOP w0.102: v1(155.52,124.49) 155.12,124.1 155.12,123.55 154.95,123.38 154.95,67.18 146.06,58.29 146.06,39.19 146.57,38.68 146.57,38.15 ; TR10.2 113.51,24.19 113.7,24 113.7,23.85 113.82,23.73 116.01,23.73 116.25,23.96 138.12,23.96 145.94,31.79 145.94,34.79 146.57,35.41 146.57,38.15 ; 146.57,38.15 v4(146.18,38.15) ; CPU1.V13 v3(80.17,155.9)
  L4 w0.089: 79,148.92 78.82,149.1 78.82,149.86 79.33,150.37 79.33,155.99 79.51,156.17 79.9,156.17 v3(80.17,155.9)
  L4 w0.127: 79,148.92 79.41,148.51 79.41,147.44 81.57,145.28 100.63,145.28 122.31,123.6 139.76,123.6 140.28,124.11 155.14,124.11 v1(155.52,124.49)
F_USB3P: length 230.9
  TOP w0.102: 139.03,24.57 146.16,31.7 146.16,34.7 146.78,35.32 146.78,38.77 146.27,39.28 146.27,58.2 155.16,67.09 155.16,123.29 v1(155.58,123.71) ; 139.03,24.57 138.21,23.75 116.34,23.75 116.1,23.51 TR10.3 ; 139.03,24.57 v4(139.3,24.31) ; CPU1.Y13 v3(80.17,156.61)
  L4 w0.089: v3(80.17,156.61) 79.93,156.36 79.43,156.36 79.14,156.07 79.14,150.45 78.63,149.94 78.63,149.02 78.79,148.86 78.79,148.83 78.8,148.83 78.8,148.75 78.81,148.73
  L4 w0.127: v1(155.58,123.71) 155.44,123.85 140.39,123.85 139.87,123.33 122.2,123.33 100.52,145.01 81.46,145.01 79.14,147.33 79.14,148.4 78.81,148.73
FB_CAL_PD_VDDQ: length 3.7
  TOP w0.254: GPU1.D22 76.38,91.7 v3(75.97,91.3)
  BOTTOM w0.305: v2(75.95,88.85) 76.08,88.98 76.08,89.87 76.61,90.39 R671.1 76.38,90.89 v3(75.97,91.3)
FB_CAL_PU_GND: length 10
  TOP w0.127: GPU1.C24 74.32,90.52 74.32,89.18 73.46,88.32 71.59,88.32 70.84,87.58
  TOP w0.508: 70.48,87.22 70.84,87.58
  TOP w0.635: 70.48,87.22 69.73,86.47 v4(69.73,85.52) 69.3,85.09 R301.1
FB_CAL_TERM_GND: length 8.7
  TOP w0.102: GPU1.B25 73.51,89.71 73.51,89.15 73.26,88.91 72.98,88.91 72.84,88.77 71.4,88.77 70.87,88.24 70.3,88.24 69.95,88.59
  TOP w0.508: R293.1 68.39,89.52 69.09,90.22 v4(69.37,90.22) 69.47,90.11 69.6,90.11 69.95,89.77 69.95,88.59
FB_PLLAVDD: length 7.8
  TOP w0.254: v3(77.37,99.82) 77.37,99.84 77.11,100.1 76.44,100.1 GPU1.P22
  TOP w0.381: v3(80.96,92.91) 81.36,93.31 GPU1.F16 ; GPU1.H22 76.78,94.6 v3(76.79,94.6)
  L4 w0.381: 77.77,94.48 78.79,94.48 79.71,93.57 80.29,93.57 80.95,92.91 v3(80.96,92.91)
  BOTTOM w0.381: C436.1 81,92.95 v3(80.96,92.91) ; C434.1 77.46,94.6 v3(76.79,94.6)
  vias: v2(75.51,101.24)
FB_VREF: length 2.3
  TOP w0.102: GPU1.D23 75.54,91.7 v3(75.14,92.1)
  BOTTOM w0.102: v3(75.14,92.1) 74.3,91.26 TP77.1
FBA_CMD0: length 35.9
  TOP w0.102: VRAM2.L2 58.53,90.11 58.72,90.11 58.84,90.24 58.84,90.58 58.74,90.68 58.25,90.68 58.11,90.83 57.94,90.83 57.71,90.6 57.54,90.6 57.31,90.83 57.15,90.83 57.02,90.7 v3(57.02,90.57)
  TOP w0.127: GPU1.C27 71.58,90.9 70.92,91.56 68.04,91.56 67.25,92.35 67.25,92.59 v3(66.93,92.91)
  L3 w0.165: v3(57.02,90.57) 58.35,91.9 59.04,91.9 60.52,93.37 61.11,93.37 61.27,93.54 61.27,94.57 61.44,94.74 61.77,94.74 61.94,94.57 61.94,93.54 62.1,93.37 62.43,93.37 62.6,93.54 62.6,95.19 62.72,95.32 63.13,95.32 63.26,95.19 63.26,93.54 63.42,93.37 63.75,93.37 63.92,93.54 63.92,94.84 64.04,94.97 64.45,94.97 64.58,94.84 64.58,93.67 64.7,93.54 65.96,93.54 66.09,93.67 66.09,94.51 66.22,94.64 66.8,94.64 66.93,94.51 v3(66.93,92.91)
  BOTTOM w0.102: VRAM4.L2 54.02,90.66 54.75,90.66 55.35,91.26 56.34,91.26 v3(57.02,90.57)
FBA_CMD2: length 46.7
  TOP w0.127: v3(56.4,89.76) 56.4,89.75 56.78,89.75 56.9,89.63 57.23,89.63 57.45,89.86 58.65,89.86 58.78,89.73 58.78,89.22 58.9,89.1 59.08,89.1 59.2,89.22 VRAM2.K1 ; GPU1.E24 74.7,92.55 v3(75.11,92.97) ; v1(49.71,89.39) 49.3,89.39 48.86,88.95 PR101.1
  L3 w0.165: v3(75.11,92.97) 75.11,93.92 74.99,94.05 70.84,94.05 70.71,93.92 70.71,93.54 70.84,93.42 72.09,93.42 72.21,93.29 72.21,92.53 71.91,92.22 66.37,92.22 66.25,92.35 66.25,92.81 66.12,92.93 65.71,92.93 65.59,92.81 65.59,92.43 65.46,92.3 64.26,92.3 64.13,92.43 64.13,92.73 64.01,92.86 62.71,92.86 62.59,92.73 62.59,91.64 62.46,91.51 62.1,91.51 61.98,91.64 61.98,92.73 61.85,92.86 60.78,92.86 60.43,92.5 60.43,91.61 59.77,90.95 58.25,90.95 57.07,89.76 56.41,89.76 56.4,89.76 v3(56.4,89.76)
  L4 w0.127: v1(49.71,89.39) 50.94,90.62 54.53,90.62 55.24,89.91 56.24,89.91 v3(56.4,89.76)
  BOTTOM w0.127: VRAM4.K1 53.17,89.81 56.34,89.81 v3(56.4,89.76)
FBA_CMD3: length 50.3
  TOP w0.127: v3(56.71,89.2) 56.61,89.3 56.03,89.3 55.77,89.57 54.88,89.57 54.64,89.81 53.31,89.81 52.94,89.44 VRAM2.K9 ; GPU1.F24 74.7,93.39 v3(74.3,92.99)
  L3 w0.165: v3(56.71,89.2) 56.95,89.2 57.94,90.19 60.09,90.19 60.83,90.93 60.83,92.1 60.96,92.22 61.39,92.22 61.52,92.1 61.52,91.23 61.65,91.1 62.92,91.1 63.04,91.23 63.04,92.17 63.17,92.3 63.58,92.3 63.7,92.17 63.7,91.23 63.83,91.1 64.2,91.1 64.36,91.27 64.36,91.69 64.53,91.86 64.86,91.86 65.02,91.69 65.02,91.27 65.19,91.1 65.52,91.1 65.68,91.27 65.68,91.69 65.85,91.86 66.18,91.86 66.34,91.69 66.34,91.27 66.51,91.1 66.88,91.1 67.04,91.27 67.04,91.69 67.21,91.86 67.54,91.86 67.7,91.69 67.7,91.27 67.87,91.1 68.2,91.1 68.36,91.27 68.36,91.69 68.53,91.86 68.86,91.86 69.02,91.69 69.02,91.27 69.19,91.1 69.52,91.1 69.68,91.27 69.68,91.69 69.85,91.86 70.18,91.86 70.35,91.69 70.35,91.27 70.51,91.1 72.57,91.1 72.69,91.23 72.69,93.44 72.82,93.57 74.17,93.57 74.3,93.44 v3(74.3,92.99)
  L4 w0.127: v1(49.54,88.63) 49.64,88.63 51.23,90.22 54.41,90.22 55.07,89.55 55.78,89.55 56.01,89.32 56.58,89.32 v3(56.71,89.2)
  BOTTOM w0.127: v1(49.54,88.63) 49.15,89.02 v2(48.72,89.02) PR216.1 ; v3(56.71,89.2) 57,89.2 57.12,89.33 57.12,89.73 57.25,89.86 57.71,89.86 57.89,89.68 58.12,89.68 58.29,89.86 58.65,89.86 58.78,89.73 58.78,89.12 58.9,89 59.08,89 59.2,89.12 VRAM4.K9
FBA_CMD4: length 50.6
  TOP w0.102: VRAM2.T7 54.4,94.51 54.53,94.64 54.86,94.64 54.99,94.76 54.99,94.97 54.86,95.09 54.05,95.09 53.92,95.22 53.92,95.45 54.05,95.58 55.03,95.58 55.16,95.7 v3(55.16,96) ; v3(54.97,103.98) 55.14,103.81 55.14,103.59 55.39,103.33 56.57,103.33 57.6,104.36 VRAM1.T7
  TOP w0.127: v3(71.65,91.61) 71.74,91.7 GPU1.D27
  L3 w0.127: v3(55.16,96) 55.16,96.27 55.32,96.43 55.32,96.77 54.91,97.18 54.91,97.56 55.28,97.93 55.28,98.55 55.16,98.67 54.92,98.67 54.79,98.55 54.79,98.19 54.46,97.86 54.28,97.86 54.03,98.11 54.03,98.29 54.31,98.57 54.31,98.83 v3(54.14,98.99) 54.14,99.77 53.62,100.29 53.61,100.3 53.61,100.47 53.61,100.47 53.61,100.86 53.61,101 54.9,102.29 54.9,102.75 55.23,103.09 55.23,103.46 54.97,103.72 v3(54.97,103.98)
  L4 w0.165: v3(71.65,91.61) 70.59,91.61 69.93,90.96 63.67,90.96 57.9,96.72 57.09,96.72 56.65,97.17 56.65,97.42 55.9,98.17 54.97,98.17 v3(54.14,98.99)
  BOTTOM w0.102: v3(54.97,103.98) 54.68,103.69 54.57,103.69 54.32,103.43 54.1,103.22 53.67,103.22 53.34,103.55 53.34,104.24 54.1,105 VRAM3.T7 ; VRAM4.T7 57.6,95.28 56.29,96.59 55.76,96.59 55.16,96 v3(55.16,96)
FBA_CMD5: length 60.4
  TOP w0.102: GPU1.D26 72.73,92.07 68.44,92.07 v3(67.73,92.77) ; VRAM2.T2 58.4,95.6 58.27,95.73 57.89,95.73 57.76,95.86 57.76,96.06 57.89,96.19 58.38,96.19 58.5,96.3 58.5,96.47 58.38,96.59 57.89,96.59 57.76,96.72 57.76,96.9 57.89,97.02 58.34,97.02 58.47,97.15 58.47,97.38 58.34,97.51 57.6,97.51 v3(57.29,97.19) ; v3(56.8,102.26) 56.8,102.24 56.15,101.6 54.23,101.6 52.45,103.37 52.45,103.75 53.6,104.9 VRAM1.T2
  TOP w0.127: PR95.1 52.17,99.63 52.59,100.05 55.13,100.05 55.91,99.26 56.58,99.26 v1(56.9,99.58)
  L3 w0.127: v3(56.8,102.26) 57.22,101.84 57.22,100.37 56.9,100.05 v1(56.9,99.58) 56.9,98.47 57.03,98.34 57.37,98.34 57.49,98.22 57.49,97.39 v3(57.29,97.19)
  L4 w0.165: v3(67.73,92.77) 67.4,92.45 64.66,92.45 58.19,98.91 58.03,98.91 57.36,99.58 v1(56.9,99.58)
  BOTTOM w0.102: VRAM3.T2 58.4,103.63 58.27,103.51 57.48,103.51 57.35,103.38 57.35,103.17 57.48,103.04 58.35,103.04 58.48,102.92 58.48,102.69 58.35,102.56 58.03,102.56 57.9,102.43 57.9,101.8 57.78,101.67 57.52,101.67 57.39,101.8 57.39,102.43 57.31,102.52 57.06,102.52 v3(56.8,102.26) ; VRAM4.T2 53.6,94.5 53.43,94.67 53.43,96.35 54.73,97.66 56.39,97.66 56.86,97.19 v3(57.29,97.19)
FBA_CMD6: length 50.1
  TOP w0.102: VRAM1.R3 54.28,105.8 54.18,105.7 54.18,105.48 54.3,105.36 54.61,105.36 54.75,105.5 54.88,105.5 55,105.38 55,104.93 55.38,104.55 55.6,104.55 55.73,104.42 55.73,104.29 55.5,104.06 55.5,103.83 v3(55.57,103.76) ; VRAM2.R3 57.6,93.71 57.23,94.08 57.23,94.39 57.35,94.51 57.35,95.24 56.83,95.75 56.21,95.75 55.75,95.29 v3(55.68,95.29)
  TOP w0.127: v3(70.77,92.79) 70.81,92.83 70.81,92.86 71.1,93.14 71.63,93.14 72.03,92.75 72.57,92.75 72.84,93.01 73.26,93.01 73.65,93.4 GPU1.F25
  L3 w0.127: v3(55.57,103.76) 55.57,103.73 55.56,103.72 55.56,103 55.12,102.57 55.12,102.19 54.98,102.04 54.98,102.04 53.84,100.9 53.84,100.49 54.47,99.86 54.62,99.86 v1(54.92,99.56) 54.65,99.29 54.65,99.11 54.86,98.9 55.04,98.9 55.22,99.08 55.4,99.08 55.51,98.97 55.51,97.82 55.24,97.56 55.24,97.17 55.61,96.81 55.61,95.98 55.85,95.73 55.85,95.47 v3(55.68,95.29)
  L4 w0.165: v3(70.77,92.79) 70.77,92.77 69.69,91.69 63.99,91.69 58.28,97.4 58.28,97.54 56.99,98.83 55.65,98.83 v1(54.92,99.56)
  BOTTOM w0.102: v3(55.57,103.76) 55.81,103.52 56.48,103.52 57.23,104.27 57.23,105.15 57.6,105.53 VRAM3.R3 ; v3(55.68,95.29) 55.68,95.47 55.55,95.6 55.35,95.6 55.22,95.47 55.22,94.97 55.09,94.84 54.81,94.84 54.69,94.71 54.69,94.53 54.81,94.41 54.93,94.41 55.06,94.28 55.06,93.97 54.97,93.87 54.41,93.87 54.28,93.75 54.28,93.56 VRAM4.R3
FBA_CMD7: length 60
  TOP w0.102: VRAM1.R2 53.17,105.37 53.17,104.84 51.96,103.63 51.96,102.62 53.39,101.19 56.71,101.19 v3(56.78,101.26) ; VRAM2.R2 58.76,93.8 58.76,97.42 58.37,97.81 57.81,97.81 57.68,97.94 57.68,98.52 57.56,98.65 57.15,98.65 57.02,98.52 v3(57.02,97.77)
  TOP w0.127: GPU1.F26 72.85,93.4 72.46,93.01 72.12,93.01 71.74,93.4 70.74,93.4 v3(70.13,92.79)
  L3 w0.127: v3(56.78,101.26) 56.41,101.26 56.29,101.13 56.29,100.91 56.41,100.78 56.64,100.78 56.77,100.66 56.77,100.38 56.64,100.25 56.45,100.25 v1(56.09,99.89) 56.43,99.55 56.43,99.11 56.59,98.94 56.59,98.19 v3(57.02,97.77)
  L4 w0.165: v3(70.13,92.79) 70.13,92.77 69.43,92.06 64.29,92.06 57.25,99.09 56.7,99.09 56.09,99.7 v1(56.09,99.89)
  BOTTOM w0.102: v3(56.78,101.26) 58.35,101.26 58.57,101.48 58.57,101.72 58.45,101.85 58.32,101.85 58.19,101.98 58.19,102.23 58.32,102.36 58.75,102.36 58.88,102.49 59.34,102.49 59.46,102.61 59.46,102.78 59.34,102.9 58.88,102.9 58.77,103 58.77,103.2 58.88,103.3 59.34,103.3 59.46,103.42 59.46,103.59 59.34,103.71 58.88,103.71 58.77,103.81 58.77,105.43 VRAM3.R2 ; VRAM4.R2 53.23,93.81 53.23,96.44 54.65,97.86 56.93,97.86 v3(57.02,97.77)
FBA_CMD8: length 63
  TOP w0.102: VRAM1.P3 54.4,106.33 54.77,105.95 54.77,105.89 55.21,105.46 55.21,105.01 55.46,104.75 55.77,104.75 56.07,104.45 56.58,104.45 v3(56.67,104.36) ; VRAM2.P3 57.6,92.91 56.98,93.52 56.98,94.49 57.07,94.57 57.07,95.18 56.85,95.4 56.46,95.4 v3(56.39,95.32)
  TOP w0.127: v3(75.94,93.77) 75.56,93.4 GPU1.F23
  L3 w0.127: v3(56.67,104.36) 56.61,104.42 53.91,104.42 53.62,104.14 53.62,102.51 52.32,101.21 52.32,100.24 52.1,100.02 v1(52.1,99.06) 52.45,98.71 52.45,98.36 53.39,97.42 53.39,97.42 53.49,97.32 53.49,97.32 53.52,97.29 53.52,95.93 54.13,95.32 54.33,95.32 54.62,95.61 54.8,95.61 55.05,95.36 55.05,95.18 54.75,94.88 54.75,94.7 55.03,94.42 55.21,94.42 55.45,94.66 55.96,94.66 56.08,94.79 56.08,95.02 v3(56.39,95.32)
  L4 w0.165: v1(52.1,99.06) 52.34,99.06 53.82,97.58 53.82,95.87 55.01,94.67 55.89,94.67 56.4,94.16 58.33,94.16 58.78,93.71 59.79,93.71 63.28,90.22 68.36,90.22 68.36,90.22 69.94,90.22 70.55,90.82 71.9,90.82 73.04,91.97 73.04,92.39 74.11,93.46 75.62,93.46 v3(75.94,93.77)
  BOTTOM w0.102: VRAM3.P3 57.75,106.75 57.94,106.75 58.04,106.64 58.04,106.35 57.88,106.18 57.47,106.18 56.82,105.53 56.82,104.82 56.67,104.68 v3(56.67,104.36) ; VRAM4.P3 54.77,93.01 54.77,93.2 55.26,93.69 55.26,94.4 55.56,94.7 55.77,94.7 v3(56.39,95.32)
FBA_CMD9: length 60.2
  TOP w0.102: v3(55.88,92.63) 55.95,92.7 56.57,92.7 57.28,91.99 57.45,91.99 VRAM2.N3 ; VRAM1.N3 54.6,107.2 54.92,107.2 55.09,107.03 55.09,106.8 54.96,106.67 54.96,106.5 55.06,106.4 55.21,106.4 55.44,106.63 v3(55.8,106.63)
  TOP w0.127: GPU1.G22 75.93,94.61 v3(75.91,94.61)
  L3 w0.127: v3(55.88,92.63) 55.87,92.63 55.87,92.64 55.67,92.64 50.44,97.86 v1(50.44,99.89) 50.44,100.32 50.11,100.65 50.11,101.69 55.06,106.63 v3(55.8,106.63)
  L4 w0.165: v3(75.91,94.61) 75.19,93.89 74.16,93.89 72.16,91.89 72.16,91.47 71.85,91.15 70.5,91.15 69.94,90.59 63.45,90.59 59.91,94.12 59.01,94.12 56.39,96.74 55.33,96.74 55.03,97.04 54.82,97.04 52.32,99.54 50.82,99.54 50.48,99.89 v1(50.44,99.89)
  BOTTOM w0.102: VRAM4.N3 54.6,92.04 54.85,92.04 55.3,92.49 55.3,92.73 55.42,92.86 55.65,92.86 v3(55.88,92.63) ; v3(55.8,106.63) 56.08,106.35 56.67,106.35 56.95,106.63 56.95,106.82 57.53,107.4 VRAM3.N3
FBA_CMD10: length 69
  TOP w0.102: v3(54.1,103.83) 54.1,103.35 54.61,102.84 56.37,102.84 58.03,104.5 58.03,105.95 58.22,106.14 58.22,106.42 VRAM1.P8 ; v3(54.28,96.06) 54.28,97.71 54.15,97.84 53.81,97.84 53.69,97.71 53.69,94.84 53.81,94.72 53.9,94.72 54.03,94.59 54.03,92.76 53.9,92.64 53.6,92.64 VRAM2.P8
  TOP w0.127: v3(75.1,94.62) 75.5,94.22 GPU1.G23
  L3 w0.127: v3(54.1,103.83) 53.89,103.61 53.89,102.42 52.67,101.2 52.67,99.91 v1(53.16,99.42) 53.28,99.3 53.28,99.03 53.15,98.9 52.91,98.9 52.78,98.78 52.78,98.5 52.91,98.37 53.21,98.37 53.34,98.24 53.34,97.96 54.2,97.1 54.2,96.85 54.08,96.72 53.87,96.72 53.77,96.62 53.77,96.29 54,96.06 v3(54.28,96.06)
  L4 w0.165: v1(53.16,99.42) 53.36,99.61 54.17,99.61 55.23,98.56 56.88,98.56 58.02,97.43 58.02,97.15 63.84,91.32 69.92,91.32 70.48,91.88 71.25,91.88 73.53,94.15 74.64,94.15 v3(75.1,94.62)
  BOTTOM w0.102: VRAM3.P8 53.52,106.6 53.39,106.73 53.39,106.9 53.52,107.03 53.9,107.03 54.03,106.91 54.03,106.4 53.96,106.33 53.96,105.48 54.08,105.36 54.56,105.36 54.76,105.15 54.76,104.87 54.93,104.71 54.93,104.53 54.78,104.38 54.6,104.38 54.33,104.64 54.03,104.64 53.54,104.15 53.54,103.64 53.75,103.42 54,103.42 54.1,103.53 v3(54.1,103.83) ; VRAM4.P8 58.21,92.83 58.21,93.12 58.03,93.3 58.03,95.26 56.49,96.79 55.7,96.79 55.49,97.01 54.66,97.01 54.28,96.63 v3(54.28,96.06)
FBA_CMD11: length 46.1
  TOP w0.102: VRAM2.P7 54.4,92.91 55.11,93.62 55.11,94.26 55.54,94.68 v3(56.54,94.68) ; v3(56.25,104.9) 56.52,104.9 56.79,105.18 56.96,105.18 57.15,105.36 57.15,105.66 56.97,105.84 56.97,106.04 57.1,106.17 57.58,106.17 57.71,106.29 57.71,106.49 VRAM1.P7
  TOP w0.127: v3(68.6,92.88) 69.65,93.92 71.93,93.92 72.04,93.81 74.31,93.81 GPU1.G24
  L3 w0.127: v3(56.54,94.68) 56.87,95.01 56.87,96.12 57.75,97 57.75,98.58 57.61,98.73 v1(57.61,100.08) 57.57,100.11 57.57,102.29 56.9,102.97 56.9,103.75 57.14,104 57.14,104.6 56.84,104.9 v3(56.25,104.9)
  L4 w0.165: v3(68.6,92.88) 68.24,93.24 67.44,93.24 67.26,93.42 64.28,93.42 58.52,99.18 58.14,99.18 57.61,99.71 v1(57.61,100.08)
  BOTTOM w0.102: VRAM3.P7 54.77,106.23 54.77,105.75 55.23,105.3 55.23,105.03 55.51,104.75 56.1,104.75 v3(56.25,104.9) ; v3(56.54,94.68) 56.86,94.68 56.96,94.59 56.96,93.15 57.05,93.06 57.84,93.06 57.96,92.94 57.96,92.76 57.84,92.64 VRAM4.P7
FBA_CMD12: length 47.4
  TOP w0.102: VRAM1.M2 53.98,107.83 54.51,107.83 54.93,107.4 55.01,107.4 55.35,107.06 56.24,107.06 v3(56.5,106.8) ; v3(56.39,92.25) 56.39,91.44 56.52,91.31 56.72,91.31 56.85,91.44 56.85,91.54 56.95,91.64 57.28,91.64 57.45,91.46 57.98,91.46 VRAM2.M2
  TOP w0.127: v3(69.5,92.79) 69.55,92.84 69.55,92.85 70.36,93.65 71.84,93.65 72.1,93.4 GPU1.F27
  L3 w0.127: v3(56.39,92.25) 56.39,93.14 58.15,94.9 58.15,95.79 58.58,96.22 58.58,96.83 59.2,97.46 59.2,97.75 59.07,97.87 58.8,97.87 58.67,98 58.67,98.25 58.8,98.38 59.07,98.38 59.2,98.51 v1(59.2,99.16) 59.12,99.24 59.12,103.04 58,104.16 58,105.3 v3(56.5,106.8)
  L4 w0.165: v1(59.2,99.16) 59.2,99.1 64.49,93.81 67.44,93.81 67.63,93.62 68.67,93.62 v3(69.5,92.79)
  BOTTOM w0.102: VRAM4.M2 54.02,91.46 54.56,91.46 55.27,92.18 56.07,92.18 56.14,92.25 v3(56.39,92.25) ; VRAM3.M2 58.57,108.37 58.57,108.54 58.46,108.64 58.27,108.64 57.96,108.34 57.96,108.02 57.72,107.77 57.47,107.77 56.5,106.8 v3(56.5,106.8)
FBA_CMD13: length 50.1
  TOP w0.102: v3(56.41,107.78) 55.85,107.78 55.57,108.06 55.22,108.06 54.97,108.31 54.97,108.57 54.73,108.81 54.59,108.81 VRAM1.L3 ; VRAM2.L3 57.48,90.12 56.66,90.12 56.4,90.38 56.32,90.38 v3(55.88,90.83)
  TOP w0.127: GPU1.G25 73.47,94.63 72.92,94.63 72.7,94.84 72.03,94.84 72.03,94.84 72.02,94.84 71.7,94.52 69.32,94.52 v3(68.98,94.85)
  L3 w0.127: v3(56.41,107.78) 56.74,108.11 56.92,108.11 57.23,107.8 57.23,107.67 57.01,107.45 57.01,107.27 57.53,106.75 57.89,106.75 58.04,106.9 58.22,106.9 58.38,106.74 58.38,106.56 58.22,106.4 58.22,106.12 58.55,105.79 58.55,104.97 58.68,104.85 58.98,104.85 59.11,104.97 59.11,105.3 59.23,105.43 59.6,105.43 59.73,105.3 59.73,101.43 60.03,101.13 v1(60.03,100.74) 60.03,99.96 60.11,99.88 60.11,96.94 58.75,95.57 58.75,94.76 57.13,93.15 57.13,92.01 56.47,91.35 56.41,91.35 v3(55.88,90.83)
  L4 w0.165: v1(60.03,100.74) 60.03,100.41 60.71,99.72 61.03,99.72 65.41,95.34 68.49,95.34 v3(68.98,94.85)
  BOTTOM w0.102: v3(56.41,107.78) 57.22,108.58 57.92,108.58 58.04,108.7 58.04,108.88 57.92,109 VRAM3.L3 ; v3(55.88,90.83) 55.22,90.83 54.97,90.57 54.97,90.19 54.84,90.06 54.58,90.06 VRAM4.L3
FBA_CMD15: length 49.3
  TOP w0.102: v3(55.57,89.09) 55.94,89.09 56.2,89.09 56.52,88.77 56.93,88.77 VRAM2.K3 ; VRAM1.K3 55.21,109.8 55.83,109.19 56.35,109.19 v3(56.57,108.97)
  TOP w0.127: v3(68.17,94.84) 68.83,94.17 71.72,94.17 72.13,94.58 72.6,94.58 72.98,94.2 GPU1.G26
  L3 w0.127: v3(55.57,89.09) 55.57,89.88 56.35,90.66 56.35,90.9 57.36,91.92 57.36,91.95 57.49,92.08 57.49,92.49 60.47,95.48 60.47,98.91 v1(60.8,99.23) 60.8,99.66 60.4,100.06 60.4,100.45 60.5,100.54 60.5,101.04 60.04,101.49 60.04,105.59 58.32,107.31 57.96,107.31 57.77,107.12 57.59,107.12 57.39,107.33 57.39,107.5 57.51,107.63 57.51,108.03 v3(56.57,108.97)
  L4 w0.165: v3(68.17,94.84) 68.09,94.92 65.12,94.92 v1(60.8,99.23)
  BOTTOM w0.102: VRAM3.K3 57.4,109.6 57.18,109.6 57.03,109.44 56.18,109.44 56.06,109.32 56.06,109.1 56.19,108.97 v3(56.57,108.97) ; VRAM4.K3 54.53,89.31 54.53,89.07 54.66,88.95 54.86,88.95 54.99,89.07 54.99,89.43 55.12,89.56 55.44,89.56 55.57,89.43 v3(55.57,89.09)
FBA_CMD16: length 40.3
  TOP w0.102: v3(55.26,109.12) 55.08,108.94 54.89,108.94 54.79,109.04 54.79,109.32 54.66,109.44 54.15,109.44 54.03,109.32 54.03,108.68 53.9,108.56 53.29,108.56 53.16,108.68 53.16,108.87 53.29,109 VRAM1.L2
  TOP w0.127: GPU1.M24 75.1,97.96 v3(75.1,97.93)
  L3 w0.165: v3(75.1,97.93) 75.1,97.17 74.57,96.63 72.1,96.63 71.93,96.46 66.35,96.46 62.67,100.15 62.67,101.3 61.6,102.37 61.6,106.42 57.39,110.63 55.29,110.63 54.79,110.13 54.79,109.59 v3(55.26,109.12)
  BOTTOM w0.102: v3(55.26,109.12) 55.75,109.12 56.35,108.52 56.76,108.52 57.23,108.98 57.23,109.16 57.44,109.37 57.85,109.37 58.08,109.15 58.25,109.15 VRAM3.L2
FBA_CMD18: length 53.2
  TOP w0.102: v3(56.86,109.89) 56.85,109.89 56.42,109.46 55.9,109.46 55.19,110.16 54.56,110.16 54.55,110.17 54.25,110.17 54.03,109.95 54.03,109.7 53.75,109.42 53.18,109.42 VRAM1.K1
  TOP w0.127: GPU1.K24 75.11,96.27 v3(75.11,95.46) ; v1(49.63,107.01) 49.07,107.56 PR94.1
  L3 w0.165: v3(75.11,95.46) 74.65,95.92 72.76,95.92 72.57,95.73 64.85,95.73 64.24,96.34 64.24,96.57 64.6,96.94 64.6,97.17 64.37,97.4 64.13,97.4 63.55,96.82 63.37,96.82 63.08,97.11 63.08,97.29 63.67,97.87 63.67,98.1 63.43,98.34 63.2,98.34 62.84,97.97 62.6,97.97 61.73,98.84 61.73,101.01 60.79,101.96 60.79,106.46 57.36,109.89 v3(56.86,109.89)
  L4 w0.165: v1(49.63,107.01) 49.63,107.01 49.63,107.54 49.63,107.54 49.63,107.72 50.18,108.27 51.28,108.27 51.92,108.91 53.53,108.91 54.2,109.58 55.52,109.58 55.66,109.44 56.41,109.44 v3(56.86,109.89)
  BOTTOM w0.102: v3(56.86,109.89) 56.64,109.89 56.51,110.01 56.51,110.55 56.68,110.71 57.02,110.71 57.15,110.59 57.15,110.33 57.28,110.21 57.91,110.21 58.03,110.09 58.03,109.49 58.16,109.37 59.08,109.37 59.2,109.49 VRAM3.K1
FBA_CMD19: length 50
  TOP w0.102: VRAM1.K9 58.77,109.37 57.44,109.37 57.1,109.03 57.1,108.86 56.76,108.52 56.39,108.52 56.18,108.72 55.63,108.72 v3(55.4,108.49)
  TOP w0.127: GPU1.K23 75.87,97.05 v3(75.92,97.05)
  L3 w0.165: v3(75.92,97.05) 75.87,97.05 75.1,96.28 72.47,96.28 72.28,96.09 66.2,96.09 63.3,98.99 63.07,98.99 62.73,98.66 62.55,98.66 62.26,98.94 62.26,99.12 62.6,99.46 62.6,99.69 62.23,100.06 62.23,101.13 61.2,102.16 61.2,106.42 57.26,110.36 55.9,110.36 55.56,110.02 55.56,109.59 55.78,109.37 55.78,108.87 v3(55.4,108.49)
  L4 w0.165: v3(55.4,108.49) 55.31,108.58 52.02,108.58 51.3,107.86 50.84,107.86 v1(50.34,107.36)
  BOTTOM w0.102: v3(55.4,108.49) 54.93,108.49 54.76,108.66 54.76,109.27 54.65,109.37 52.4,109.37 52.27,109.5 52.27,109.68 52.4,109.8 VRAM3.K9
  BOTTOM w0.127: v1(50.34,107.36) 50.14,107.56 PR214.1
FBA_CMD20: length 49.2
  TOP w0.102: v3(54.79,103.27) 54.74,103.22 54.52,103.22 54.44,103.29 54.39,103.35 54.39,103.51 54.53,103.65 54.53,104.14 54.41,104.26 54.01,104.26 53.9,104.37 53.9,104.51 54.03,104.64 54.67,104.64 54.8,104.77 54.8,104.97 54.7,105.08 54.48,105.08 VRAM1.T3 ; v3(54.84,96.58) 54.9,96.64 56.25,96.64 57.6,95.3 VRAM2.T3
  TOP w0.127: v3(69.7,97.29) 69.71,97.29 70.89,98.47 72.03,98.47 72.15,98.36 GPU1.M27
  L3 w0.127: v3(54.84,96.58) 54.5,96.92 54.5,97.21 53.67,98.04 53.67,99.84 53.14,100.38 v1(53.14,100.66) 53.14,101.29 53.36,101.52 53.81,101.52 54.05,101.77 54.05,102.05 54.18,102.18 54.46,102.18 54.61,102.33 54.61,102.66 54.48,102.79 54.25,102.79 54.13,102.92 54.13,103.23 54.35,103.45 54.61,103.45 v3(54.79,103.27)
  L4 w0.165: v3(69.7,97.29) 69.69,97.29 68.48,98.5 65.95,98.5 61.47,102.99 56.5,102.99 56.25,102.74 55.67,102.74 55.2,102.27 54.75,102.27 v1(53.14,100.66)
  BOTTOM w0.102: VRAM3.T3 57.6,104.31 56.57,103.27 v3(54.79,103.27) ; v3(54.84,96.58) 54.71,96.45 54.71,95.71 54.86,95.56 54.86,95.25 54.74,95.12 54.51,95.12 54.38,95.25 54.38,95.42 54.25,95.55 53.99,95.55 53.86,95.42 53.86,94.92 53.99,94.79 54.27,94.79 54.4,94.66 VRAM4.T3
FBA_CMD21: length 69.1
  TOP w0.102: v3(52.74,97.11) 52.74,97.43 52.62,97.56 52.12,97.56 51.99,97.68 51.99,98.45 52.12,98.57 52.4,98.57 52.53,98.45 52.53,98.12 52.65,97.99 52.86,97.99 52.98,98.12 52.98,98.8 53.11,98.93 53.32,98.93 53.44,98.8 53.44,94.4 VRAM2.T8 ; VRAM1.T8 58.4,104.47 56.32,102.39 56.32,102.12 56.05,101.84 54.59,101.84 v3(52.88,103.55)
  TOP w0.127: v3(70.41,97.31) 70.41,97.31 71.21,98.11 72.01,98.11 72.14,97.98 72.52,97.98 72.9,98.36 GPU1.M26
  L3 w0.127: v3(52.74,97.11) 52.74,97.12 51.27,98.59 v1(51.27,100.81) 51.61,101.14 51.61,101.35 51.36,101.59 51.36,101.77 51.57,101.99 51.75,101.99 51.92,101.82 52.14,101.82 53.01,102.69 53.01,103.43 v3(52.88,103.55)
  L4 w0.165: v1(51.27,100.81) 52.34,101.87 53.4,101.87 54.07,102.54 55.09,102.54 55.55,103.01 56.14,103.01 56.39,103.26 61.72,103.26 66.1,98.87 68.85,98.87 70.41,97.31 v3(70.41,97.31)
  BOTTOM w0.102: VRAM4.T8 58.4,97 57.2,98.2 54.54,98.2 53.85,97.5 53.84,97.5 53.67,97.33 52.96,97.33 v3(52.74,97.11) ; VRAM3.T8 53.38,104.78 53.38,104.78 52.93,104.32 51.54,104.32 51.38,104.17 51.38,102.41 51.51,102.28 51.74,102.28 51.87,102.41 51.87,103.81 51.99,103.93 52.22,103.93 52.35,103.81 52.35,103.4 52.48,103.27 52.6,103.27 v3(52.88,103.55)
FBA_CMD22: length 80.1
  TOP w0.102: v3(52.39,102.8) 53.8,101.39 56.27,101.39 56.59,101.71 56.86,101.71 58.76,103.6 58.76,105.44 VRAM1.R8 ; VRAM2.R8 53.17,93.87 53.17,94.71 53.05,94.84 52.5,94.84 52.37,94.97 52.37,95.14 52.5,95.27 53.05,95.27 53.17,95.4 53.17,95.6 53.05,95.73 52.48,95.73 52.35,95.86 52.35,96.06 52.48,96.19 53.05,96.19 53.17,96.31 53.17,96.49 53.05,96.62 52.02,96.62 51.89,96.49 51.89,94.94 51.77,94.81 51.56,94.81 51.44,94.94 51.44,96.95 51.56,97.07 v3(51.92,97.07)
  TOP w0.127: v3(71.05,97.31) 71.05,97.31 71.5,97.76 71.92,97.76 71.94,97.74 72.78,97.74 72.94,97.91 73.2,97.91 73.65,98.36 GPU1.M25
  L3 w0.127: v3(51.92,97.07) 50.96,98.03 50.96,100.37 50.59,100.74 v1(50.59,100.87) 51.08,101.36 51.08,101.57 50.8,101.85 50.8,102.03 51.09,102.32 51.27,102.32 51.36,102.23 51.54,102.23 51.77,102.46 51.77,103.01 51.97,103.22 52.27,103.22 52.39,103.09 v3(52.39,102.8)
  L4 w0.165: v1(50.59,100.87) 51.96,102.24 53.39,102.24 53.96,102.81 54.98,102.81 55.47,103.3 56.05,103.3 56.28,103.52 61.97,103.52 66.26,99.24 69.14,99.24 70.88,97.5 70.88,97.48 71.05,97.31 v3(71.05,97.31)
  BOTTOM w0.102: VRAM3.R8 53.17,105.37 53.17,104.86 52.88,104.56 51.49,104.56 51.11,104.18 51.11,103.25 50.98,103.12 50.72,103.12 50.6,102.99 50.6,102.64 50.72,102.51 50.98,102.51 51.11,102.38 51.11,102.08 51.23,101.95 51.89,101.95 52.1,102.15 53.26,102.15 53.39,102.28 53.39,102.67 53.26,102.8 v3(52.39,102.8) ; v3(51.92,97.07) 52.51,97.66 53.29,97.66 54.02,98.4 57.35,98.4 58.76,96.99 58.76,93.79 58.4,93.44 VRAM4.R8
FBA_CMD23: length 46
  TOP w0.102: VRAM2.R7 54.91,93.95 54.91,94.34 55.24,94.68 55.24,95.47 55.5,95.72 55.62,95.72 v3(56.06,96.16) ; VRAM1.R7 57.6,105.53 57.14,105.07 57.14,104.22 56.85,103.93 56.22,103.93 v3(56.17,103.98)
  TOP w0.127: v3(68.99,97.31) 69.48,96.82 71.81,96.82 72.06,97.07 72.71,97.07 GPU1.K26
  L3 w0.127: v3(56.17,103.98) 56.17,103.45 56.29,103.32 56.51,103.32 56.64,103.2 56.64,102.89 56.5,102.75 55.66,102.75 55.43,102.52 55.43,101.7 55.13,101.41 54.67,101.41 54.28,101.02 54.28,100.73 v1(54.31,100.71) 54.93,100.08 55.06,100.08 55.39,99.75 55.39,99.5 55.74,99.14 55.74,97 56.06,96.68 56.06,96.16 v3(56.06,96.16)
  L4 w0.165: v3(68.99,97.31) 68.17,98.13 65.8,98.13 61.21,102.72 56.61,102.72 56.34,102.45 56.34,102.08 55.94,101.69 55.28,101.69 v1(54.31,100.71)
  BOTTOM w0.102: VRAM4.R7 57.6,93.71 57.23,94.08 57.23,95.25 56.31,96.16 v3(56.06,96.16) ; VRAM3.R7 55.02,105.18 55.02,104.95 55.43,104.54 55.96,104.54 56.17,104.33 v3(56.17,103.98)
FBA_CMD24: length 57.9
  TOP w0.102: v3(56.18,97.23) 56.43,97.47 56.61,97.47 56.81,97.27 56.81,97.09 56.57,96.85 56.57,96.67 56.76,96.48 56.94,96.48 57.1,96.64 57.35,96.64 57.52,96.48 57.52,95.67 58.03,95.16 58.03,93.01 VRAM2.P2 ; VRAM1.P2 53.97,106.23 53.97,104.87 53.64,104.54 53.64,103.48 54.84,102.28 v3(55.87,102.28)
  TOP w0.127: GPU1.K22 v3(76.86,97.2)
  L3 w0.127: v3(55.87,102.28) 56.13,102.01 56.13,101.69 55.5,101.06 55.04,101.06 54.91,100.93 54.91,100.51 55.04,100.38 v1(55.59,100.38) 55.59,99.87 55.62,99.84 55.62,99.67 56.18,99.11 v3(56.18,97.23)
  L4 w0.165: v3(76.86,97.2) 76.56,97.5 75.67,97.5 74.62,96.45 65.9,96.45 60.86,101.49 58.33,101.49 57.22,100.38 v1(55.59,100.38)
  BOTTOM w0.102: VRAM4.P2 53.97,93.01 53.97,94.43 53.63,94.78 53.63,96.27 54.59,97.23 v3(56.18,97.23) ; v3(55.87,102.28) 55.58,102.57 55.58,102.87 55.7,102.99 56.62,102.99 58.01,104.38 58.01,106.02 58.4,106.41 VRAM3.P2
FBA_CMD25: length 52.3
  TOP w0.102: v3(56.34,105.9) 56.07,105.63 55.32,105.63 54.98,105.98 54.98,106.15 54.76,106.38 54.76,106.77 54.56,106.97 54.03,106.97 VRAM1.N2 ; v3(56.28,93.7) 56.28,93.04 56.39,92.93 56.62,92.93 56.79,93.11 57.05,93.11 57.18,92.98 57.18,92.43 57.34,92.26 57.98,92.26 VRAM2.N2
  TOP w0.127: v3(75.92,96.29) 75.92,96.26 75.54,95.88 GPU1.J23
  L3 w0.127: v3(56.34,105.9) 56.64,105.6 57.16,105.6 57.73,105.02 57.73,103.35 57.86,103.22 58.45,103.22 58.57,103.09 58.57,102.76 58.45,102.64 58.16,102.64 58.03,102.51 58.03,102.23 58.16,102.1 58.55,102.1 58.67,101.98 58.67,101.67 58.55,101.54 58.19,101.54 58.06,101.42 58.06,101.02 58.19,100.89 v1(58.63,100.89) 58.63,100.56 58.72,100.47 58.72,99.49 58.27,99.03 58.27,96.24 57.87,95.84 57.87,95.03 56.78,93.94 56.52,93.94 v3(56.28,93.7)
  L4 w0.165: v3(75.92,96.29) 75.71,96.08 65.74,96.08 60.59,101.23 58.97,101.23 v1(58.63,100.89)
  BOTTOM w0.102: VRAM4.N2 54.02,92.26 54.56,92.26 55.04,92.75 55.04,93.17 55.61,93.74 56.06,93.74 56.1,93.7 v3(56.28,93.7) ; VRAM3.N2 58.4,107.62 58.27,107.74 58.09,107.74 57.96,107.62 57.96,107.11 57.84,106.98 57.4,106.98 57.16,106.74 57.16,106.44 57.22,106.37 57.22,106.22 57.03,106.03 56.86,106.03 56.74,106.14 56.58,106.14 v3(56.34,105.9)
FBA_CMD26: length 46.9
  TOP w0.102: VRAM1.M3 54.23,108.37 54.23,108.5 54.33,108.61 54.64,108.61 54.76,108.48 54.76,108.21 54.86,108.11 54.86,107.81 55.02,107.65 55.37,107.65 v3(55.52,107.5) ; v3(55.81,91.73) 56.5,91.04 VRAM2.M3
  TOP w0.127: v3(70.96,95.02) 71.02,95.09 71.02,95.11 71.41,95.49 73.27,95.49 73.66,95.88 GPU1.J25
  L3 w0.127: v3(55.52,107.5) 55.82,107.5 55.98,107.34 56.59,107.34 58.27,105.66 58.27,104.39 59.38,103.27 59.38,99.94 v1(59.64,99.68) 59.67,99.65 59.67,97.46 58.81,96.59 58.81,96.06 58.44,95.7 58.44,94.82 56.86,93.24 56.86,92.06 56.41,91.61 55.93,91.61 v3(55.81,91.73)
  L4 w0.165: v1(59.64,99.68) 59.75,99.57 59.75,99.07 64.64,94.18 67.65,94.18 67.83,94 69.96,94 70.96,95 v3(70.96,95.02)
  BOTTOM w0.102: v3(55.52,107.5) 55.68,107.34 56.59,107.34 57.25,108 57.4,108 VRAM3.M3 ; VRAM4.M3 54.8,91.04 54.91,91.16 54.91,91.49 55.07,91.64 55.24,91.64 55.4,91.49 55.57,91.49 v3(55.81,91.73)
FBA_CMD27: length 51.6
  TOP w0.102: v3(55.68,105.19) 55.73,105.19 55.91,105.36 56.44,105.36 56.77,105.69 56.77,106.14 57.16,106.53 57.16,106.69 57.48,107.01 58.01,107.01 VRAM1.N8 ; VRAM2.N8 53.6,92.1 53.72,92.22 55.02,92.22 55.15,92.35 55.15,92.63 54.97,92.81 54.97,93.09 55.38,93.5 55.38,93.89 v3(55.7,94.21)
  TOP w0.127: GPU1.J24 74.32,96.26 70.93,96.26 69.88,95.21 69.88,95.15 v3(69.69,94.97)
  L3 w0.127: v3(55.7,94.21) 56.69,94.21 57.51,95.02 57.51,95.58 57.33,95.75 57.33,96.13 57.46,96.26 57.81,96.26 57.98,96.43 57.98,99.52 v1(58.24,99.77) 58.24,100.27 57.8,100.71 57.8,102.38 57.47,102.72 57.47,104.6 56.7,105.37 55.87,105.37 v3(55.68,105.19)
  L4 w0.165: v3(69.69,94.97) 69.69,94.9 69.17,94.38 67.97,94.38 67.8,94.55 64.8,94.55 60.13,99.21 60.13,99.89 59.84,100.17 58.63,100.17 v1(58.24,99.77)
  BOTTOM w0.102: VRAM3.N8 53.89,107.4 54.26,107.03 54.87,107.03 55.04,106.85 55.04,105.79 55.19,105.64 55.63,105.64 55.75,105.51 55.75,105.25 v3(55.68,105.19) ; v3(55.7,94.21) 56.39,94.21 56.72,93.88 56.72,92.99 57.44,92.26 57.98,92.26 VRAM4.N8
FBA_CMD28: length 52
  TOP w0.102: v3(55.49,106.07) 55.87,106.07 56.15,106.35 56.69,106.35 56.95,106.61 56.95,106.82 57.53,107.4 VRAM1.N7 ; v3(55.8,93.29) 55.44,92.93 55.44,92.26 55.01,91.84 VRAM2.N7
  TOP w0.127: v3(68.31,97.31) 69.07,96.54 72.16,96.54 GPU1.K27
  L3 w0.127: v3(55.49,106.07) 55.49,105.78 55.32,105.61 55.14,105.61 54.94,105.81 54.71,105.81 54.53,105.64 54.53,105.46 54.81,105.18 54.81,105 54.59,104.77 54.33,104.77 54.03,105.08 53.83,105.08 53.39,104.64 53.39,102.75 51.96,101.32 51.96,100.55 v1(51.85,100.43) 51.63,100.21 51.63,98.86 53.29,97.19 53.29,95.79 v3(55.8,93.29)
  L4 w0.165: v3(68.31,97.31) 67.85,97.77 65.65,97.77 61.39,102.03 57.68,102.03 57.38,101.72 56.55,101.72 56.1,101.27 55.41,101.27 54.84,100.7 54.84,100.55 54.46,100.17 52.11,100.17 v1(51.85,100.43)
  BOTTOM w0.102: VRAM4.N7 57.52,91.84 56.2,93.16 55.92,93.16 v3(55.8,93.29) ; VRAM3.N7 54.4,107.67 54.53,107.79 54.92,107.79 55.05,107.67 55.05,107.23 55.28,107 55.28,106.28 v3(55.49,106.07)
FBA_CMD29: length 62.3
  TOP w0.102: VRAM2.L7 54.4,90.57 54.53,90.7 54.79,90.7 54.91,90.57 54.91,90.09 55.04,89.96 55.3,89.96 55.43,90.09 v3(55.43,90.38) ; VRAM1.L7 57.34,108.74 57.34,108.44 57.02,108.12 56.69,108.12 56.5,108.31 56.05,108.31 v3(55.99,108.26)
  TOP w0.127: v3(73.51,97.1) 73.52,97.1 73.9,96.72 GPU1.K25
  L3 w0.127: v3(55.43,90.38) 55.43,90.38 55.33,90.28 54.88,90.28 54.05,91.12 54.05,93.05 49.77,97.33 v1(49.77,100.28) 49.77,101.88 54.11,106.22 54.11,106.4 53.7,106.81 53.7,106.99 53.88,107.17 54.06,107.17 54.47,106.76 54.65,106.76 54.82,106.94 54.82,107.11 54.51,107.42 54.51,107.72 54.79,108 55.7,108 55.96,108.26 v3(55.99,108.26)
  L4 w0.165: v1(49.77,100.28) 49.87,100.38 51.01,100.38 51.48,99.91 54.57,99.91 55.1,100.44 55.1,100.59 55.39,100.87 55.96,100.87 56.04,100.79 56.97,100.79 57.94,101.76 61.12,101.76 66.06,96.83 73.24,96.83 v3(73.51,97.1)
  BOTTOM w0.102: v3(55.99,108.26) 55.72,107.99 55.14,107.99 54.4,108.73 VRAM3.L7 ; VRAM4.L7 57.48,90.12 56.66,90.12 56.4,90.38 v3(55.43,90.38)
FBA_CMD30: length 50.8
  TOP w0.102: v3(56.09,109.9) 55.53,110.46 55.19,110.46 55.07,110.59 55.07,110.82 54.94,110.94 54.74,110.94 VRAM1.J3 ; v3(56.06,88.62) 56.13,88.55 57.51,88.55 VRAM2.J3
  TOP w0.127: GPU1.J27 71.18,95.88 v3(70.32,95.02)
  L3 w0.127: v3(56.09,109.9) 56.09,109.53 56.21,109.42 56.63,109.42 56.63,109.41 56.76,109.41 57.08,109.09 57.25,109.09 57.4,109.24 57.55,109.24 57.75,109.03 57.75,108.85 57.53,108.63 57.53,108.33 57.67,108.2 58.09,108.2 58.35,107.94 58.35,107.62 58.85,107.12 59.03,107.12 59.23,107.32 59.41,107.32 59.59,107.14 59.59,106.96 59.39,106.76 59.39,106.58 59.57,106.4 59.75,106.4 59.94,106.6 60.12,106.6 60.3,106.42 60.3,106.24 60.11,106.04 60.11,105.86 60.38,105.59 60.38,101.59 60.87,101.09 v1(60.87,100.26) 61.27,99.86 61.27,95.47 59.26,93.46 59.26,92.87 58.56,92.17 57.93,92.17 57.59,91.83 57.59,91.82 56.58,90.81 56.58,90.57 55.95,89.94 55.95,89.38 56.06,89.27 v3(56.06,88.62)
  L4 w0.165: v1(60.87,100.26) 61.03,100.26 65.57,95.71 69.64,95.71 v3(70.32,95.02)
  BOTTOM w0.102: v3(56.09,109.9) 56.18,109.99 56.18,110.51 56.59,110.92 57.28,110.92 VRAM3.J3 ; VRAM4.J3 54.4,88.64 55.04,88.64 55.04,88.64 56.04,88.64 v3(56.06,88.62)
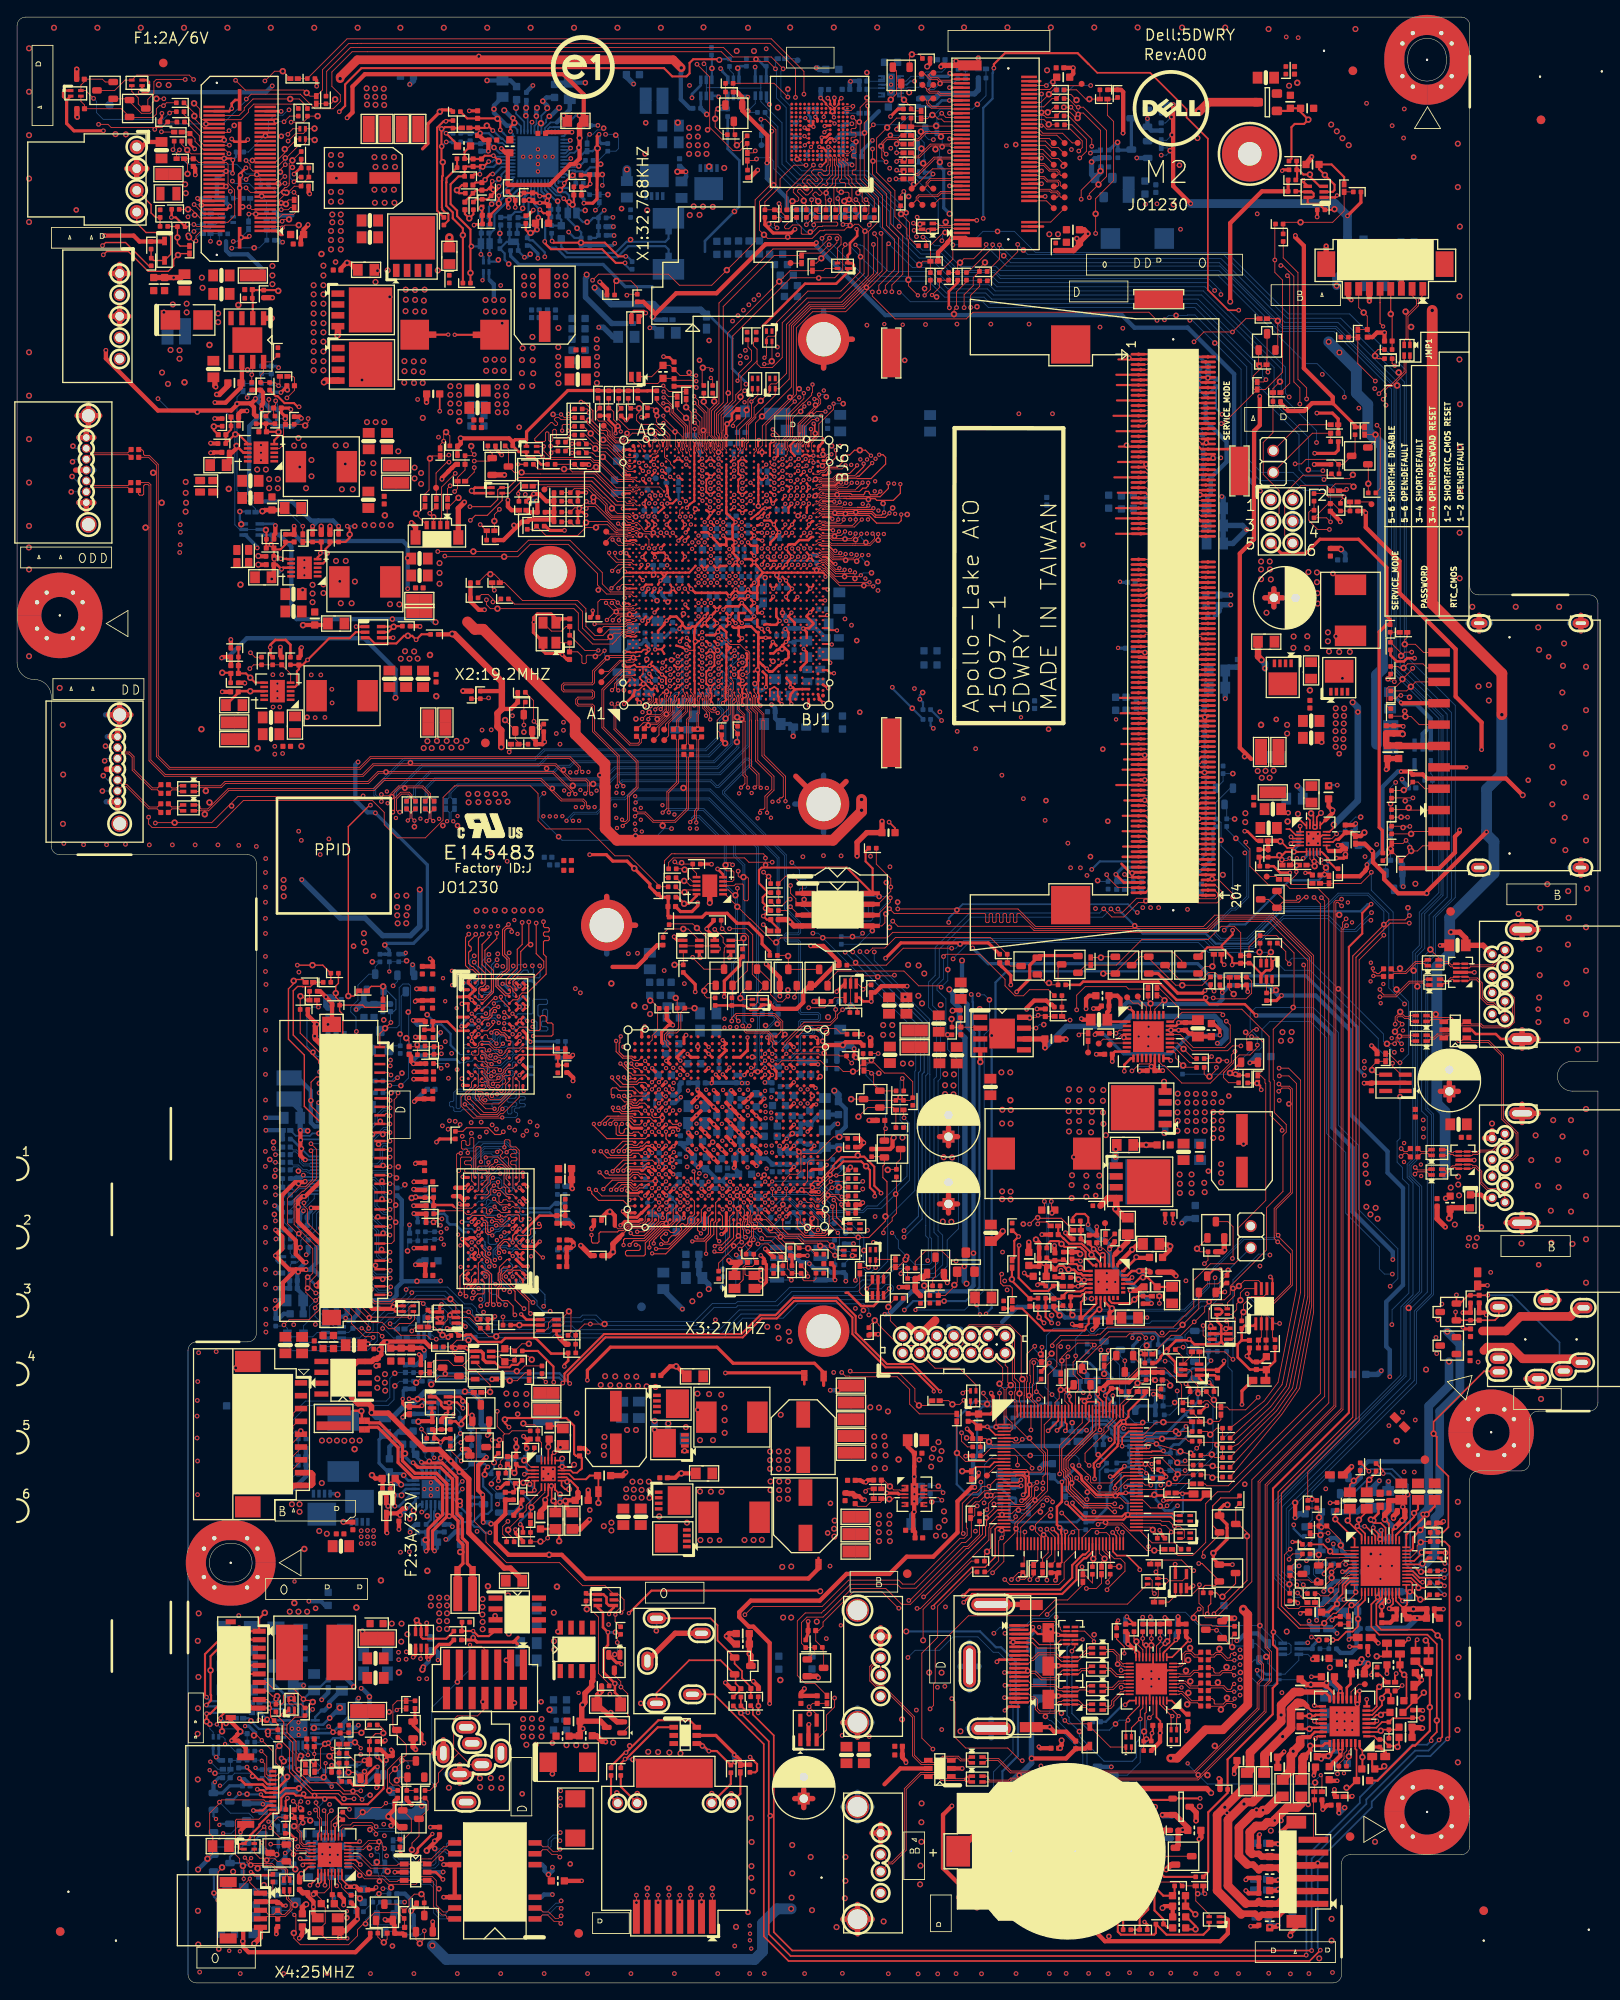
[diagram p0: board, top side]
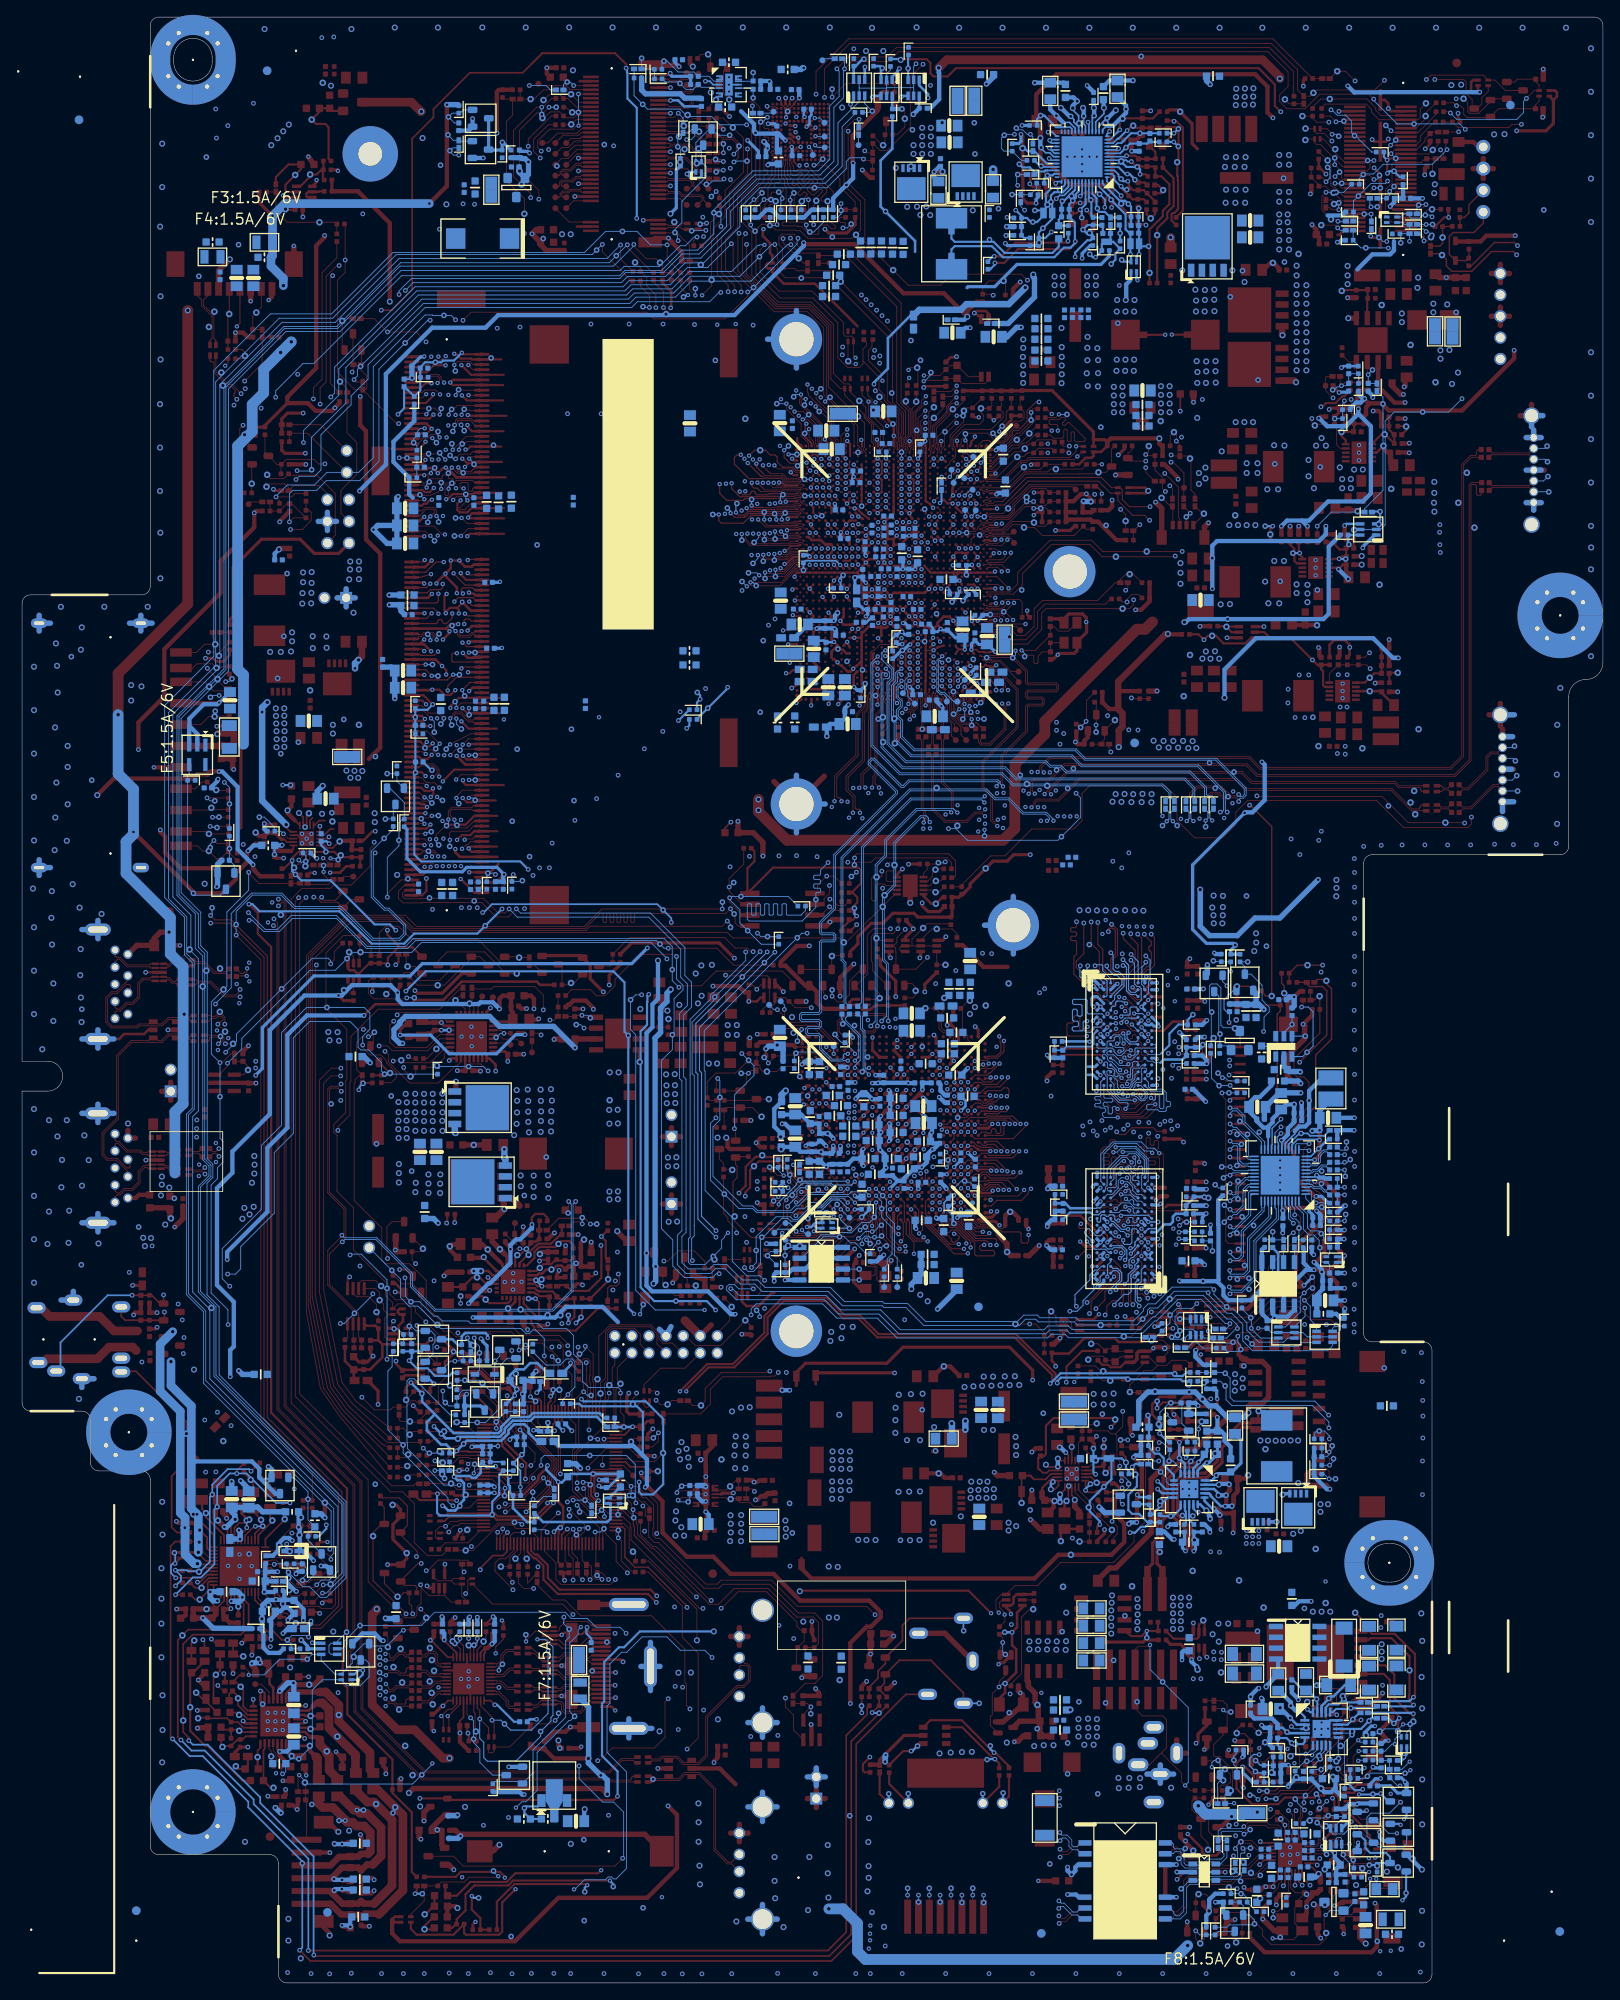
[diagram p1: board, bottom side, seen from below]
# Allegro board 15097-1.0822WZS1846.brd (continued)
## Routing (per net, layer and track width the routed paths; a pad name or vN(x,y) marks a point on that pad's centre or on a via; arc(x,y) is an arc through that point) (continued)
FBA_DEBUG0: length 3.7
  TOP w0.102: v3(75.98,92.97) 75.98,92.98 GPU1.F22
  BOTTOM w0.102: v3(75.98,92.97) 75.94,92.97 75.09,93.82 v2(74.7,93.82) 74.5,93.62 74,93.62 R666.1
FBA_DEBUG1: length 2.6
  TOP w0.102: GPU1.J22 76.34,95.87 v3(76.78,95.42)
  BOTTOM w0.102: v3(76.78,95.42) 76.64,95.57 v2(76.64,96.29) 77.36,96.29 R659.1
FWH_ID0: length 10.1
  TOP w0.102: R332.2 99.68,76.83 v4(100.36,77.52) 100.83,77.05 100.83,76.97 103.23,74.57 106.21,74.57 107.33,75.7 LPC1.6
GC6_FB_EN: length 2
  TOP w0.102: v3(89.19,90.51) 89.21,90.51 GPU1.C6
  BOTTOM w0.102: v3(89.19,90.51) 88.21,89.53 TP78.1
GLAN_WAKE_CPU: length 410.2
  TOP w0.089: 77.38,181.38 77.82,180.93 77.82,180.23 77.72,180.13 77.72,179.65 77.62,179.55 77.62,179.29 77.9,179.01 CPU1.P61
  TOP w0.102: v3(75.62,183.36) 75.62,183.13 77.38,181.38 ; RN39.4 27.75,17.11 v3(28.92,18.28) 29.12,18.09 29.12,15.7 Q42.C
  L3 w0.127: v3(75.62,183.36) 77.5,185.24 77.5,191.68 87.71,201.89 98.72,201.89 98.73,201.9 139.75,201.9 153.34,188.31 153.34,182.8 161.04,175.1 161.04,174.06 161.06,174.05 161.06,153.37 162.69,151.74 162.69,140.05 160.78,138.14 160.78,135.59 157.21,132.02 157.21,129.2 156.18,128.17 156.18,126.23 155.05,125.11 155.05,109.1 146.36,100.41 146.36,90.07 145.26,88.97 145.26,88.19 144.74,87.67 144.47,87.67 141.38,84.59 141.38,83.03 134.94,76.58 134.53,76.58 v1(133.99,76.05)
  L4 w0.127: v3(28.92,18.28) 28.21,18.28 26.08,16.16 26.08,12 26.58,11.49 27.57,11.49 28.49,12.41 30.02,12.41 32.77,15.16 33.75,15.16 34.1,15.51 35.91,15.51 35.98,15.43 36.8,15.43 45.32,23.95 45.32,28.18 50.13,32.99 61.36,32.99 64.38,29.97 70.04,29.97 71.49,28.52 83.92,28.52 84.75,27.69 92.8,27.69 94.54,25.95 103.23,25.95 103.8,26.52 115.65,26.52 121.01,31.88 123.6,31.88 129.07,37.34 129.91,37.34 131.25,38.68 131.25,40.49 133.75,42.98 133.75,50.64 132.66,51.73 132.66,57.2 132.16,57.7 132.16,58.53 135.31,61.68 135.31,66.82 136.23,67.74 136.23,73.81 v1(133.99,76.05)
  BOTTOM w0.102: v3(75.62,183.36) v2(74.88,183.36)
GLAN_WAKE_N: length 8.6
  TOP w0.102: v1(29.67,16.23) 29.71,16.19 Q42.E 31.51,16.07 32.47,15.11 33.64,15.11 33.96,14.79 U26.21
  BOTTOM w0.102: R798.1 29.15,14.31 v2(29.22,14.37) 29.24,14.4 29.24,14.4 29.7,14.86 29.7,16.03 29.67,16.05 v1(29.67,16.23)
GLAN_WAKE_N_LS: length 6
  TOP w0.102: RN39.3 27.75,15.25 28.41,14.58 30.1,14.58 30.47,14.22 Q42.B 31.63,14.22 v4(32.56,13.3)
GP_SPI0_FS1: length 89.6
  TOP w0.102: CPU1.H52 75.34,174.16 v3(75.34,174.03)
  L3 w0.127: v3(75.34,174.03) 74.91,173.6 73.02,173.6 70.14,176.48 64.29,176.48 61.49,179.29 51.57,179.29 50.66,180.21 50.66,180.37 48.46,182.56 47.71,182.56 47.7,182.56 47.25,182.56 44.31,185.5 35.61,185.5 32.85,188.26 32.85,188.66 32.85,188.67 32.85,202.09 33.38,202.62 33.38,208.27 33.68,208.57 33.68,217.29 v1(31.82,219.15)
  BOTTOM w0.102: R532.2 27.06,214.21 27.07,214.22 27.07,214.23 28.97,216.13 v2(29.07,216.13) 29.41,216.47 29.41,217.82 30.1,218.51 31.09,218.51 31.72,219.15 v1(31.82,219.15)
GPIO1_FBVDDQCTL: length 3.3
  TOP w0.102: GPU1.B2 93.73,89.27 v3(93.73,88.08)
  BOTTOM w0.127: TP81.1 93.25,87.6 v3(93.73,88.08)
GPIO2_BL_PWM: length 12.4
  TOP w0.102: GPU1.D6 89.62,91.7 90.02,92.09 90.02,92.91 v3(89.99,92.93)
  TOP w0.127: v1(95.41,90.83) 95.46,90.78 95.46,89.36 96.63,88.19 RN30.2
  BOTTOM w0.102: v3(89.99,92.93) 90.42,93.36 92.78,93.36 93.07,93.07 v2(93.07,93.06) 93.88,93.06 94.32,92.61 94.32,92 94.59,91.73 94.59,91.73 94.84,91.49 94.84,91.48
  BOTTOM w0.127: 94.84,91.48 95.41,90.91 v1(95.41,90.83)
GPIO3_PPEN_R: length 6.7
  TOP w0.127: v3(88.38,90.51) 88.77,90.9 GPU1.C7
  BOTTOM w0.127: v2(93.05,89.43) 92.41,90.07 91.83,90.07 R677.1 91.73,90.17 91.64,90.17 90.2,91.61 89.35,91.61 88.38,90.63 v3(88.38,90.51)
GPIO4_BLEN: length 13.8
  TOP w0.102: GPU1.F9 87.13,93.35 87.13,93.35 87.53,93.75 v3(87.55,93.75)
  TOP w0.127: v3(95.56,91.59) 95.56,91.54 95.89,91.21 95.89,89.61 96.66,88.84 RN30.1
  BOTTOM w0.127: v3(95.56,91.59) 95.56,91.67 95.07,92.16 v2(94.88,92.16) 94.88,92.36 93.8,93.43 93.75,93.43 93.6,93.58 90.33,93.58 90.11,93.35 87.95,93.35 v3(87.55,93.75)
GPIO5_PWM_VID_BOOT_EN: length 5.1
  TOP w0.127: v1(94.41,87.93) 94.15,87.66 93.55,87.66 93.55,87.67 93.32,87.67 92.1,88.89 GPU1.A3
  BOTTOM w0.127: v1(94.41,87.93) 94.41,88.13 95.18,88.9 TP79.1
GPIO6_FB_CLAMP_TGL_REQ: length 7.5
  TOP w0.127: v1(95.12,87.98) 94.58,87.43 92.23,87.43 91.3,88.36 GPU1.A4
  BOTTOM w0.127: v1(95.12,87.98) 95.32,88.18 96.54,88.18 TP80.1
GPIO7_3D_STEREO: length 4.4
  TOP w0.102: GPU1.B6 89.57,90.1 89.21,89.74 v3(89.21,89.69)
  BOTTOM w0.127: 88.21,88.3 v2(88.17,88.27) ; 88.21,88.3 89.21,89.31 v3(89.21,89.69) ; 88.21,88.3 RN38.1
GPIO8_OVERT#: length 23.6
  TOP w0.127: GPU1.A6 89.6,88.23 90.22,87.6 91.73,87.6 92.13,87.21 99.67,87.21 101.61,89.15 v4(101.61,89.68) 101.8,89.87 101.8,93.74 101.32,94.23 101.32,95.57 101.49,95.75 Q25.S 101.4,96.67 R278.1
GPIO9_ALERT#: length 40
  TOP w0.102: v3(88.36,93.77) 88.34,93.75 88.34,93.72 GPU1.F8
  TOP w0.127: R290.1 96.45,90.84 v3(96.45,91.08) ; PR127.1 116.47,81.28 116.19,81.56 115.41,81.56 115.1,81.86 115.1,82.81 v1(115.22,82.93)
  L4 w0.165: v1(115.22,82.93) 112.85,85.3 105.05,85.3 103.28,87.07 103.28,88.01 102.73,88.56 101.83,88.56 101.51,88.25 100.72,88.25 99.96,87.48 98.99,87.48 96.45,90.02 v3(96.45,91.08)
  BOTTOM w0.102: 88.39,93.8 v3(88.36,93.77)
  BOTTOM w0.127: v3(96.45,91.08) 96.45,91.33 95.19,92.59 95.18,92.59 94.39,93.37 94.39,93.52 v2(93.96,93.95) 93.94,93.95 93.79,93.81 90.23,93.81 90.23,93.8 88.39,93.8
GPIO10_MEM_VREF_CTL: length 3.3
  TOP w0.127: GPU1.C5 90.05,90.5 v3(90.03,90.5)
  BOTTOM w0.127: RN38.2 90.57,89.32 90.57,89.7 90.03,90.24 v3(90.03,90.5) 90.03,90.68 v2(89.62,91.08)
GPIO11_PWM_VID: length 40.2
  TOP w0.102: v3(89.2,92.93) 88.8,92.52 GPU1.E7
  TOP w0.127: PR102.2 120.49,89.03 119.67,89.03 v1(119.44,88.8)
  L4 w0.165: v1(119.44,88.8) 118.91,88.27 118.91,86.48 118.22,85.79 116.47,85.79 115.25,87.02 106.54,87.02 104.13,89.43 101.3,89.43 100.89,89.02 99.49,89.02 97.84,90.67 97.84,91.79 96.84,92.79 95.8,92.79 95.56,92.56 94.8,92.56 94.35,92.11 90.02,92.11 v3(89.2,92.93)
  BOTTOM w0.127: v1(119.44,88.8) v2(119.44,89.53)
GPIO12_AC_DETECT: length 11.9
  TOP w0.102: v3(88.38,92.91) 88.39,92.9 88.39,92.11 GPU1.D7
  TOP w0.127: R288.1 96.76,91.55 96.21,91.55 95.75,92.01 95.12,92.01 v3(94.42,91.31)
  BOTTOM w0.102: 91.81,92.48 88.98,92.48 88.54,92.91 v3(88.38,92.91) ; 91.81,92.48 v2(91.81,92.77) ; 91.81,92.48 92.98,92.48 94.14,91.31 v3(94.42,91.31)
GPIO13_NVVDD_PSI: length 48.3
  TOP w0.102: v3(92.34,87.93) 92.34,87.96 92.24,88.06 92.24,88.39 91.64,88.98 91.64,89.76 GPU1.B4
  TOP w0.127: R295.1 122.19,89.46 119.16,89.46 v1(118.49,88.79)
  L4 w0.165: v1(118.49,88.79) 118.99,89.29 119.64,89.29 119.93,89 119.93,88.45 119.29,87.81 119.29,86.32 118.38,85.41 116.3,85.41 115.07,86.64 106.7,86.64 106.38,86.64 103.97,89.05 101.46,89.05 101.04,88.64 100.73,88.64 99.33,88.64 97.46,90.52 97.46,91.64 96.68,92.41 95.8,92.41 95.66,92.28 95.44,92.28 94.98,91.82 94.31,91.82 92.24,89.75 92.24,88.06 92.34,87.96 v3(92.34,87.93)
  BOTTOM w0.127: v1(118.49,88.79) v2(117.75,88.79)
GPIO34_CPU: length 3.6
  TOP w0.089: 70.13,169.27 71.32,169.27 71.41,169.17 CPU1.B41
  TOP w0.102: TP35.1 68.92,168.65 69.53,169.27 70.13,169.27
GPIO35_CPU: length 4.2
  TOP w0.089: CPU1.C41 72.49,169.17 72.21,169.46 71.95,169.46 71.86,169.36 71.47,169.36 71.39,169.44 70.19,169.44 70.11,169.52
  TOP w0.102: TP34.1 69.22,169.52 70.11,169.52
GPIO36_VCCIO_LEVEL: length 11.9
  TOP w0.089: 71.53,169.91 71.85,169.91
  TOP w0.102: 71.85,169.91 71.95,169.81 72.21,169.81 72.33,169.93 72.58,169.93 72.97,169.54 73.98,169.54 CPU1.F41 ; R160.2 R161.1 65.25,170.43 66.15,170.43 v4(66.58,170.87) 66.71,170.99 69.07,170.99 70.17,169.89 71.5,169.89 71.53,169.91
GPIO39_TXE_BPS: length 10.7
  TOP w0.102: R144.2 R145.1 65.2,174.83 66.77,174.83 67.44,174.16 v4(67.44,173.81) 67.52,173.74 67.95,173.74 68.85,172.83 68.85,172.21 69.02,172.04 69.02,172 69.58,171.44 71.3,171.44 71.53,171.21 71.9,171.21 CPU1.B45
GPIO40_CPU: length 12
  TOP w0.102: CPU1.A46 71.55,171.63 69.66,171.63 69.21,172.08 69.21,172.12 69.04,172.29 69.04,173 66.99,175.06 62.03,175.06 TP32.1
GPIO43_EMMC_BOOT: length 88.6
  TOP w0.089: 71.45,170.11 71.93,170.11
  TOP w0.102: 71.93,170.11 71.93,170.1 CPU1.B43 ; R22.2 31.91,218.42 v1(31.24,217.75) ; R157.2 R158.1 65.25,172.59 66.53,172.59 v1(66.61,172.51) 66.84,172.75 67.62,172.75 70.29,170.08 71.42,170.08 71.45,170.11
  L3 w0.127: v1(66.61,172.51) 65.11,174.02 62.32,174.02 60.9,175.44 58.14,175.44 57.9,175.2 52.73,175.2 51.55,174.02 51.01,174.02 50.19,174.84 50.19,176.22 49.36,177.06 49.36,179.32 46.37,182.31 46.37,182.36 43.99,184.74 35.29,184.74 32.09,187.94 32.09,188.35 32.09,188.35 32.09,202.41 32.62,202.94 32.62,208.59 32.88,208.85 32.88,215.76 31.24,217.4 v1(31.24,217.75)
  BOTTOM w0.102: v2(30.32,217.82) 30.36,217.78 31.21,217.78 v1(31.24,217.75) ; v1(66.61,172.51) v2(65.79,172.51)
GPIO44_SPI_BOOT: length 13.6
  TOP w0.089: 69.63,170.08 69.96,169.75 70.05,169.75 70.1,169.71 70.19,169.71 70.2,169.7 70.26,169.7 70.33,169.64 CPU1.A42
  TOP w0.102: R162.2 60.42,170.07 R163.1 61.88,169.34 65.59,169.34 66.54,170.29 v4(67.74,170.29) 67.74,170.36 68,170.61 69.1,170.61 69.63,170.08
GPIO47_DNXFW: length 33.2
  TOP w0.102: v1(50.68,175.17) 50.38,174.86 R153.1 ; R147.2 R148.1 65.27,172.82 66.12,172.82 v1(66.63,173.33) 66.91,173.05 67.7,173.05 69.5,171.24 71.1,171.24 71.51,170.84 71.85,170.84 71.95,170.73 72.21,170.73 72.33,170.85 72.58,170.85 73.13,170.31 73.13,170.17 73.48,169.82 74.33,169.82 74.93,169.22 CPU1.H41
  L3 w0.127: v1(66.63,173.33) 66.35,173.33 65.41,174.27 62.43,174.27 61,175.69 57.75,175.69 57.51,175.45 51.03,175.45 50.75,175.17 v1(50.68,175.17)
  BOTTOM w0.102: v2(67.44,173.33) 67.44,173.33 v1(66.63,173.33)
GPIO48_CPU: length 35.3
  TOP w0.102: v1(50.54,177.93) 50.3,177.93 49.03,176.66 TP31.1 49.05,174.9 R152.1 ; CPU1.L41 v3(76.02,169.67)
  L3 w0.127: v1(50.54,177.93) 50.85,177.93 52.57,176.21 56.15,176.21 56.84,176.9 57.23,176.9 57.67,176.46 61.32,176.46 62.7,175.08 67.4,175.08 69.04,173.44 69.04,173.38 70.59,171.84 71.24,171.84 73.2,169.89 74.93,169.89 75.15,170.1 75.51,170.1 75.76,169.85 75.8,169.85 75.98,169.67 v3(76.02,169.67)
GPIO78_SMB_LEVEL: length 9.8
  TOP w0.102: R103.2 71.52,184.53 R115.1 v4(72.78,184.23) 72.78,183.74 72.5,183.46 72.5,182.8 72.96,182.35 74.7,182.35 76.17,180.88 76.17,179.53 CPU1.K62
GPIO82_CPU: length 1.5
  TOP w0.102: CPU1.M55 v3(76.43,176.21)
  BOTTOM w0.102: v3(76.43,176.21) 76.23,176.4 TP63.1
GPIO88_PMU_LEVEL: length 13.3
  TOP w0.102: CPU1.M58 76.46,177.73 76.46,177.92 76.02,178.36 75.93,178.36 75.75,178.54 75.75,179.54 75.98,179.76 75.98,180.58 74.8,181.76 71.56,181.76 70.19,183.14 70.19,183.72 R116.1 70.4,184.52 R105.2
GPIO92_SMB_NRB: length 7.6
  TOP w0.102: R104.2 72.65,185.39 73.77,184.28 74.44,184.28 v4(74.77,183.94) 74.81,183.91 74.81,182.65 76.4,181.07 76.4,179.93 CPU1.L63
GPIO104_CPU: length 1.4
  TOP w0.102: CPU1.F54 v3(73.98,175.92)
  BOTTOM w0.102: TP64.1 74.12,176.05 v3(73.98,175.92)
GPIO105_CPU: length 1.8
  TOP w0.102: CPU1.F52 74.68,174.1 v3(74.68,174.02)
  BOTTOM w0.102: TP66.1 74,174.7 v3(74.68,174.02)
GPIO110_LPC_LEVEL: length 14.5
  TOP w0.089: CPU1.J52 75.19,175.02 72.72,175.02 72.61,174.91 72.35,174.91 72.24,175.02 71.95,175.02 71.86,174.92 71.41,174.92
  TOP w0.102: 71.41,174.92 70.12,174.92 67.75,177.29 v4(67.75,177.35) 67.45,177.35 67.16,177.06 65.86,177.06 R138.1 R137.2
GPIO111_BBS: length 12.8
  TOP w0.102: CPU1.F58 v3(73.61,177.52) ; R101.2 68.19,185.21 R113.1 67.74,183.79 67.74,183.08 68.09,182.73 68.86,182.73 69.64,181.95 69.64,181.14 69.87,180.91 70,180.78 v3(70.86,180.78)
  L3 w0.127: v3(73.61,177.52) 73.61,177.75 70.86,180.51 v3(70.86,180.78)
  BOTTOM w0.102: v3(70.86,180.78) v2(71.38,181.3)
GPIO112_CPU: length 1.5
  TOP w0.102: CPU1.K55 v3(75.48,176.22)
  BOTTOM w0.102: TP65.1 75.98,175.72 v3(75.48,176.22)
GPIO113_CPU: length 10.8
  TOP w0.102: CPU1.F61 74.37,178.89 74.78,178.89 74.98,179.08 74.98,179.24 75.24,179.5 75.24,179.95 75.09,180.1 75.09,180.54 74.31,181.32 72,181.32 71.07,180.39 70.13,180.39 69.39,181.12 69.39,181.49 68.69,182.19 TP30.1
GPIO117_CPU: length 1.9
  TOP w0.102: CPU1.H58 v3(74.52,177.62)
  BOTTOM w0.102: TP62.1 73.69,178.45 v3(74.52,177.62)
GPIO118_FLASH_OVR: length 118.9
  TOP w0.102: v3(74.61,180.47) 74.39,180.25 74.39,179.56 CPU1.F62 ; R139.1 154.06,178.26 150.83,178.26 150.3,177.73 v1(149.56,177.73) ; R139.1 154.7,177.62 R140.2 ; R139.1 155.18,177.67 Q7.C 156.57,179.06 R125.2
  L3 w0.127: v3(74.61,180.47) 74.61,180.54 77.77,183.71 77.77,191.59 87.82,201.64 98.83,201.64 98.84,201.65 137.8,201.65 149.45,190 149.45,177.84 v1(149.56,177.73)
  BOTTOM w0.102: v3(74.61,180.47) v2(74.61,181.24)
GPIO120_BIOS_SWAP: length 12
  TOP w0.102: v3(73.91,176.81) 73.91,176.72 CPU1.E56 ; R102.2 R112.1 69.36,184.25 69.82,183.8 69.82,182.89 70.59,182.12 70.59,181.56 v3(70.65,181.51)
  L3 w0.127: v3(70.65,181.51) 70.97,181.19 71.02,181.19 71.26,180.95 71.26,180.48 74.02,177.73 74.02,176.91 v3(73.91,176.81)
  BOTTOM w0.102: v2(70.3,182.14) 70.3,182.14 70.65,181.8 v3(70.65,181.51)
GPIO121_CPU: length 1.5
  TOP w0.102: v3(72.8,177.86) 72.8,177.86 72.85,177.91 CPU1.D59
  BOTTOM w0.102: TP61.1 72.42,178.24 v3(72.8,177.86)
GPIO123_CPU: length 77.5
  TOP w0.102: CPU1.E62 73.06,179.62 73.06,179.94 72.53,180.47 72.44,180.47
  TOP w0.127: 72.44,180.47 71.84,180.47 71.56,180.19 70.04,180.19 69.12,181.11 69.12,181.46 68.93,181.65 68.41,181.65 67.38,182.68 67.38,183.94 66.36,184.96 v1(65.99,184.96) ; v1(32.4,210.74) 32.94,211.28 R48.1
  L3 w0.165: v1(65.99,184.96) 64.14,184.96 58.99,179.81 51.79,179.81 51.19,180.41 51.19,180.71 46.87,185.04 v1(46.87,185.27)
  L4 w0.165: v1(32.4,210.74) 31.85,210.18 31.85,187.47 34.05,185.27 v1(46.87,185.27)
  BOTTOM w0.127: v2(32.21,212.42) 31.94,212.15 31.94,211.2 v1(32.4,210.74)
GPIO_11_SCI: length 103.5
  TOP w0.102: v3(69.28,167.33) 69.28,167.05 70.11,166.22 70.77,166.22 70.79,166.2 71.52,166.2 71.53,166.21 71.85,166.21 71.85,166.2 71.86,166.2 72.13,165.93 CPU1.C34 ; v1(29,222.53) 30.14,223.67 v4(31.09,223.67) 31.1,223.67 R4.1
  L3 w0.127: v1(29,222.53) 29,221.66 27.64,220.3 27.64,216.88 27.64,207.74 27.65,207.74 27.65,203.24 26.81,202.4 26.81,199.36 25.56,198.11 25.56,175.14 29.23,171.47 49.45,171.47 52.7,168.22 65.17,168.22 66.11,167.27 68.95,167.27 69,167.33 v3(69.28,167.33)
GPIO_12_SWI: length 22
  TOP w0.102: v3(73.19,167.9) 73.24,167.95 73.29,167.95 CPU1.E39 ; R164.1 v4(55.85,171.04) 55.85,171.8 56.44,172.38 v1(56.44,172.41)
  L3 w0.127: v3(73.19,167.9) 73.14,167.9 71.56,169.48 69.06,169.48 68.95,169.37 67.05,169.37 64.02,172.41 v1(56.44,172.41)
GPIO_FB_CLAMP_GPU: length 8.2
  TOP w0.102: PR97.1 96.42,97.79 v4(96.17,97.54) 94.9,96.27 92.8,96.27 92.49,95.95 92.49,93.79 GPU1.F3
GPIO_RCOMP: length 2.3
  TOP w0.254: CPU1.E34 73.59,165.51 73.8,165.72 73.8,165.88 v3(73.84,165.92)
  BOTTOM w0.381: v2(74.49,164.74) R590.2 73.89,165.86 v3(73.84,165.92)
GPU_1D05V: length 1.4
  TOP w0.508: v4(112.72,107.75) PU6.4
GPU_1D05V_EN: length 4.9
  TOP w0.102: PU6.8 119.26,112.98 v1(119.49,113.21) 120.19,113.21 PC78.1 121.39,113.07 PR90.1
  BOTTOM w0.102: v2(118.5,112.9) 118.8,113.21 v1(119.49,113.21)
GPU_1D05V_FB: length 5.4
  TOP w0.102: PC80.2 PR92.2 109.41,112.62 109.35,112.67 v4(109.35,112.78) ; PC80.2 112.6,111.82 PU6.2 ; PC80.2 110.4,111.87 PR89.1
GPU_1D05V_PG: length 133.2
  TOP w0.102: v1(27.24,153.77) 27.68,154.22 PR76.2 PR64.2 PC59.1 32.01,153.17 PU4.5 ; PU6.7 v1(119.24,111.71)
  L3 w0.127: v1(27.24,153.77) 24.67,153.77 23.45,152.55 23.45,144.61 25.26,142.81 33.43,142.81 33.76,142.48 33.77,142.48 34,142.26 35.74,140.51 35.75,140.51 39.56,136.7 39.56,136.34 41.82,134.07 41.82,134.07 43.68,132.22 v1(55.48,132.22)
  L4 w0.127: v1(119.24,111.71) 118.75,111.71 111.45,119.01 110.46,119.01 110.37,119.1 107.81,119.1 106.32,120.59 101.26,120.59 99.88,119.2 89.88,119.2 88.66,120.42 79.29,120.42 79.25,120.46 78.17,120.46 74.84,123.8 74.84,125.98 70.34,130.48 65.99,130.48 64.66,131.81 55.89,131.81 v1(55.48,132.22)
  BOTTOM w0.102: v2(120.15,112.12) 119.65,112.12 v1(119.24,111.71)
GPU_1D05V_VGA_EN: length 58.2
  TOP w0.102: v1(123.22,112.65) 122.73,112.65 PR90.2 122.27,113.11 PR88.2 R250.2 ; v1(133.68,79.5) PR121.1
  L4 w0.127: v1(123.22,112.65) 123.86,113.28 136.13,113.28 139.1,110.31 139.1,107.05 142.15,104 142.15,92.82 137.36,88.03 137.36,83.74 133.68,80.05 v1(133.68,79.5)
  BOTTOM w0.102: v2(133.68,80.37) 133.68,80.19 133.68,80.18 v1(133.68,79.5)
GPU_ALLPWR: length 42.8
  TOP w0.254: Q9.3 41.18,157.39 41.85,156.72 44.38,156.72 45.28,157.61 v4(45.73,157.61) 46.23,157.61 v1(46.69,157.15) 47.33,157.78 48.04,157.78 R173.2 ; v3(73.07,165.9) 73.03,165.87 73.03,165.66 CPU1.C33
  L3 w0.254: v1(46.69,157.15) 47.33,157.78 49.39,157.78 50.09,158.49 67.35,158.49 67.36,158.48 71.54,158.48 72.25,159.18 72.25,164.82 73.07,165.64 v3(73.07,165.9)
GPU_DMINUS: length 1.2
  BOTTOM w0.102: TP82.1 R698.1
GPU_DMINUS_G: length 10.4
  TOP w0.102: v3(85.07,92.09) 84.66,92.5 GPU1.E12
  BOTTOM w0.102: R698.2 84.11,83.67 83.75,84.02 83.75,84.72 83.18,85.29 83.18,88.35 84.4,89.58 v2(84.4,90.58) 84.4,91.43 v3(85.07,92.09)
GPU_DPLUS: length 1.2
  BOTTOM w0.102: R699.1 TP83.1
GPU_DPLUS_G: length 11.1
  TOP w0.102: GPU1.F12 84.66,93.34 v3(85.09,92.91)
  BOTTOM w0.102: R699.2 82.58,84.84 82.9,85.16 82.9,88.84 83.85,89.79 83.85,91.68 84.28,92.11 v2(84.28,92.11) 84.28,92.11 v3(85.09,92.91)
GPU_PEX_RST_HOLD: length 7
  TOP w0.102: v4(98.46,101.35) 99.53,102.42 D3.1 102.56,102.42 R275.1 102.84,102.14 R276.2
GPU_PEX_RST_HOLD_GPU#: length 23.9
  TOP w0.102: v3(91.68,91.3) 91.3,90.92 GPU1.C4 ; R275.2 103.73,101.29 v1(103.79,101.22)
  BOTTOM w0.102: v3(91.68,91.3) 92.72,91.3 93.39,90.63 94.32,90.63 94.84,90.12 99.02,90.12 99.49,90.59 101.11,90.59 v2(102.81,92.29) 104.43,93.91 104.43,100.58 v1(103.79,101.22)
GPU_TESTMODE: length 4.1
  TOP w0.102: GPU1.AD9 87.14,108.3 v3(87.53,108.7)
  BOTTOM w0.102: v3(87.53,108.7) 87.53,108.85 R644.1 89.09,110.02 89.87,110.79 v2(89.87,110.97)
GPU_THERM_SHUTDOWN_N: length 1.3
  TOP w0.102: TP51.1 127.36,88.85 PR106.1
GPU_VCC3_CTL: length 3.9
  TOP w0.635: R321.2 105.1,81.03 C120.2 R315.2 105.52,82.42 105.66,82.56 106.06,82.56 Q26.G
GPU_VCC3_CTL_2: length 5.4
  TOP w0.102: Q27.G 110.02,81.99 v4(109.68,81.66) 109.68,81.51 108.61,80.43 C122.1 107.81,81 108.02,81.22 R317.2
GPU_WAKEB_CPU: length 237.3
  TOP w0.089: CPU1.R62 78.25,179.15 78.25,179.45 78.09,179.66 78.09,180 78.19,180.09 78.19,181.29 78.25,181.36
  TOP w0.102: 78.25,181.36 78.25,182.09 76.64,183.7 76.64,184.36 76.19,184.81 v3(75.62,184.81) ; v1(109.37,121.06) 103.7,121.06 101.72,119.08 R222.2
  L3 w0.127: v3(75.62,184.81) 77.25,186.44 77.25,191.79 87.61,202.15 98.62,202.15 98.63,202.16 139.86,202.16 154.13,187.89 154.13,182.6 161.3,175.43 161.3,174.17 161.31,174.16 161.31,153.48 162.94,151.85 162.94,139.67 161.58,138.3 161.58,133.02 159.65,131.09 159.65,128.85 157.73,126.94 157.73,125.03 v1(158.43,124.33)
  BOTTOM w0.102: v1(158.43,124.33) 158.05,124.33 156.73,123.01 154.88,123.01 153.36,124.54 148.19,124.54 144.69,121.03 139.86,121.03 138.94,121.95 110.77,121.95 v2(110.35,121.54) 109.87,121.06 v1(109.37,121.06)
H_PROCHOT_N_EC: length 40.4
  TOP w0.102: Q38.G 93.34,38.71 R429.1 93.33,39.24 R428.1 91.79,39.74 91.79,42.16 92.44,42.8 94.32,42.8 94.6,43.08 94.62,43.08 97.7,46.15 101.66,46.15 103.51,44.3 104.54,44.3 111.07,50.83 111.31,50.83 112.97,52.49 112.97,53.57 113.09,53.68 113.09,54.25 114.32,55.48 v1(114.32,56.03) 114.41,56.13 U14.24
  BOTTOM w0.102: v2(115.25,54.79) 115.25,55.92 RN40.1 114.37,56.09 v1(114.32,56.03)
HDM2_CPU_HPD: length 19.2
  TOP w0.102: CPU1.C50 72.31,173.5 71.97,173.5 71.7,173.77 70.4,173.77 67.61,176.56 61.22,176.56 61.21,176.56 59.21,176.56 v4(59.04,176.73) 58.19,176.73 Q8.D 57.5,179.45 R133.1
HDMI1_DATA_IC_N0: length 4.2
  TOP w0.102: 136.81,33.68 136.38,34.11 135.98,34.11 135.98,34.11 135.92,34.17 U20.2 ; 136.81,33.68 v4(137.07,33.93) ; 136.81,33.68 137.47,33.02 138.25,33.02 C188.2
HDMI1_DATA_IC_N1: length 4
  TOP w0.102: 137.03,35.01 137.29,34.75 138.18,34.75 C182.2 ; 137.03,35.01 136.74,35.31 136,35.31 135.93,35.37 U20.5 ; 137.03,35.01 v4(137.29,35.28)
HDMI1_DATA_IC_N2: length 4
  TOP w0.102: 136.79,36.13 136.1,36.13 136.06,36.17 U20.7 ; 136.79,36.13 137.23,36.13 137.68,36.58 138.2,36.58 C177.2 ; 136.79,36.13 v4(136.79,36.53)
HDMI1_DATA_IC_N3: length 5.1
  TOP w0.102: 137.27,38.81 136.73,38.81 136.4,38.48 136.4,37.54 136.17,37.31 135.98,37.31 135.92,37.37 U20.10 ; 137.27,38.81 v4(137.27,39.19) ; 137.27,38.81 137.42,38.81 137.85,38.38 138.2,38.38 C174.2
HDMI1_DATA_IC_P0: length 4.3
  TOP w0.102: C192.2 138.15,32.77 137.37,32.77 137.24,32.89 ; U20.1 136.01,33.77 136.1,33.86 136.27,33.86 137.24,32.89 ; v4(136.94,32.59) 137.24,32.89
HDMI1_DATA_IC_P1: length 3.6
  TOP w0.102: C186.2 138.22,34.49 137.19,34.49 136.63,35.05 136,35.05 135.91,34.97 U20.4
HDMI1_DATA_IC_P2: length 3.6
  TOP w0.102: U20.6 135.91,35.77 136.02,35.87 137.33,35.87 137.78,36.32 138.2,36.32 C179.2
HDMI1_DATA_IC_P3: length 5.2
  TOP w0.102: U20.9 135.92,36.97 136.01,37.06 136.28,37.06 136.66,37.44 136.66,37.77 ; 136.66,37.77 136.66,38.38 136.84,38.56 137.31,38.56 137.75,38.12 138.2,38.12 C176.2 ; 136.66,37.77 v4(137.04,37.77)
HDMI2_HPD: length 222.9
  TOP w0.102: R132.1 55.09,179.43 55.6,178.93 Q8.G 55.25,178.05 v1(53.5,178.05) ; v3(136.27,34.57) U20.3
  L4 w0.127: v1(53.5,178.05) 53.97,177.58 53.97,171.38 53.73,171.14 53.73,155.81 61.46,148.08 61.46,146.34 64.52,143.28 67.54,143.28 68.86,141.96 71.67,141.96 74.74,138.9 74.74,136.62 74.91,136.44 74.91,129.85 77.12,127.64 77.12,125.09 79.96,122.26 89.42,122.26 89.82,121.86 90.21,121.86 90.21,121.85 92.7,121.85 92.72,121.84 93.53,121.84 93.55,121.85 97.44,121.85 v1(98.63,120.67) ; v3(136.27,34.57) 136.27,34.74 135.12,35.89 135.12,40.33 136.48,41.68 136.94,41.68 138.95,43.68 138.95,47.75 136.51,50.18 136.51,54.32 142.34,60.14 142.34,69.78 143.36,70.8 143.36,76.34 141.77,77.93 136.38,77.93 135.86,77.41 124.89,77.41 123.18,79.12 119.36,79.12 116.82,81.66 114.94,81.66 113.28,83.31 107.88,83.31 106.69,84.51 v1(106.56,84.51)
  BOTTOM w0.102: v1(106.56,84.51) 106.64,84.58 106.64,87.11 106.33,87.41 106.33,88.61 106.33,106.14 106.59,106.39 106.59,112.41 104.1,114.89 104.1,115.19 v2(103.94,115.36) v1(98.63,120.67)
HDMI_CTRL_CLK: length 26.3
  TOP w0.127: Q9201.D 142.59,46.72 v4(141.05,45.19) 140.83,45.19 140.37,45.64 R9201.1 139.69,44.37 139.4,44.08 139.4,43.31 v1(139.28,43.18) ; RN25.4 135.04,31.07 v3(135.19,31.22) 135.11,31.22 133.74,32.59 U20.38
  L4 w0.127: v3(135.19,31.22) 135.19,32.52 136.71,34.04 136.71,35.26 136.06,35.91 136.06,40.26 136.06,40.62 136.69,41.25 137.35,41.25 v1(139.28,43.18)
HDMI_CTRL_CLK_CPU: length 224.2
  TOP w0.089: CPU1.B49 71.09,172.88 71.08,172.89
  TOP w0.127: v1(53.05,171.12) 53.63,171.7 55.02,171.7 56.77,173.45 RN8.3 57.62,174.3 59.02,175.7 67.26,175.7 70.05,172.91 71.06,172.91 71.08,172.89 ; R9201.2 138.81,46.29 139.02,46.51 140.22,46.51 Q9201.S 140.69,47.05 138.67,49.07 v1(138.29,49.07)
  L4 w0.127: v1(53.05,171.12) 53.3,170.88 53.3,155.62 60.97,147.95 60.97,145.29 63.41,142.85 67.36,142.85 68.76,141.44 71.58,141.44 74.3,138.72 74.3,138.02 74.3,138.02 74.3,136.64 74.31,136.63 74.31,136.44 74.48,136.27 74.48,129.41 76.69,127.2 76.69,125.22 76.69,124.92 79.78,121.83 89.24,121.83 89.64,121.42 89.89,121.42 89.89,121.42 91.4,121.42 91.96,120.87 93.68,120.87 93.88,121.07 97.36,121.07 v1(97.8,120.63) ; v1(103.79,87.25) 103.82,87.25 105.32,85.75 113.37,85.75 119.39,79.73 119.41,79.73 119.59,79.55 123.36,79.55 123.78,79.13 129.18,79.13 129.95,78.36 141.95,78.36 144.39,75.92 144.39,70.46 142.77,68.84 142.77,59.96 138.29,55.48 v1(138.29,49.07)
  BOTTOM w0.127: v1(103.79,87.25) 105.91,89.37 105.91,106.31 106.15,106.55 106.15,112.24 103.67,114.73 103.67,114.76 v2(100.72,117.71) v1(97.8,120.63)
HDMI_CTRL_DATA: length 34.7
  TOP w0.127: RN25.3 135.69,30.98 v3(135.94,31.22) 135.93,31.22 135.15,32 134.72,32 134.14,32.59 U20.39 ; v1(140.06,43.18) 140.06,43.22 143.92,47.08 v4(143.92,52.27) 143.95,52.3 143.95,52.65 142.91,53.7 Q9202.D 142.62,55.65 R9202.1
  L4 w0.127: v1(140.06,43.18) 139.99,43.1 139.99,42.98 137.83,40.82 136.87,40.82 136.49,40.44 136.49,36.18 137.15,35.53 137.15,33.15 135.94,31.94 v3(135.94,31.22)
HDMI_CTRL_DATA_CPU: length 230.3
  TOP w0.089: CPU1.C49 72.5,172.88 72.21,173.17 71.95,173.17 71.85,173.07 71.4,173.07 71.16,173.31 70.38,173.31
  TOP w0.127: R9202.2 142.82,56.74 140.85,56.74 139.91,55.8 139.91,53.51 Q9202.S 140.71,52.45 138.74,50.48 138.74,49.99 v1(138.84,49.89) ; v1(52.99,172.72) 55.41,172.72 56.24,173.56 56.24,174.68 56.52,174.95 RN8.4 57.51,174.95 58.69,176.14 67.44,176.14 70.26,173.31 70.38,173.31
  L4 w0.127: v1(103.79,88.01) 105.62,86.18 113.57,86.18 119.77,79.98 123.54,79.98 123.96,79.57 129.76,79.57 130.3,79.03 141.89,79.03 144.93,75.99 144.93,70.36 144.2,69.63 144.2,67.62 143.38,66.8 143.38,59.96 138.84,55.43 v1(138.84,49.89) ; v1(52.99,172.72) 52.58,172.31 52.58,170.85 52.86,170.57 52.86,155.41 59.9,148.37 59.9,145.75 64.69,140.96 71.45,140.96 73.87,138.55 73.87,137.84 73.87,137.84 73.87,137.11 73.87,137.11 73.87,136.46 73.87,136.45 73.87,136.26 74.05,136.09 74.05,129.23 76.26,127.02 76.26,125.04 76.26,124.74 79.6,121.39 89.06,121.39 89.46,120.99 89.71,120.99 89.71,120.99 91.22,120.99 91.78,120.43 93.86,120.43 94.02,120.6 v1(96.91,120.6)
  BOTTOM w0.127: v1(96.91,120.6) v2(98.13,119.38) 105.72,111.79 105.72,106.73 105.48,106.49 105.48,89.7 v1(103.79,88.01)
HDMI_DATA_CPU_N0: length 181.4
  TOP w0.089: 85.68,147.62 85.68,147.64 85.71,147.67 85.71,148.59 85.31,149 85.31,150.57 CPU1.AK2
  TOP w0.102: v3(142.48,33.26) 142.48,33.15 142.27,32.94 141.59,32.94 ; C188.1 139.88,33.28 140.09,33.07 140.09,32.72 140.18,32.63 141.14,32.63 141.46,32.94 141.59,32.94 ; 141.59,32.94 v4(141.59,33.35) ; v3(86.32,139.86) 86.57,140.11 86.57,141.35 85.68,142.24 85.68,147.62
  L4 w0.127: v3(86.32,139.86) 86.32,139.75 86.65,139.42 86.77,139.42 87.33,138.86 90.22,138.86 90.69,138.4 90.69,137.29 92.92,135.05 93,134.98 102.38,134.98 119.48,117.88 139.18,117.88 139.64,117.42 150.65,117.42 153.4,114.68 153.4,65.71 148.37,60.68 148.37,57.03 146.64,55.3 146.64,35.92 143.37,32.64 143.1,32.64 142.93,32.81 142.93,33.07 142.74,33.26 v3(142.48,33.26)
HDMI_DATA_CPU_N1: length 177.3
  TOP w0.089: CPU1.AM2 86.24,149.34 87.2,148.39 87.2,147.72 87.17,147.69 87.17,147.66
  TOP w0.102: v3(89.11,138.25) 89.11,138.48 89.28,138.65 89.5,138.65 89.67,138.81 89.67,141.07 87.17,143.57 87.17,147.66 ; v3(142.43,34.98) 142.16,34.71 142.16,34.51 141.99,34.34 141.67,34.34 141.24,34.77 140.52,34.77 ; 140.52,34.77 139.72,34.77 C182.1 ; 140.52,34.77 v4(140.52,35.15)
  L4 w0.127: v3(142.43,34.98) 142.7,34.98 142.83,34.85 142.83,34.57 142.98,34.42 143.77,34.42 145.19,35.84 145.32,35.84 145.88,36.4 145.88,55.62 147.61,57.34 147.61,61 152.64,66.03 152.64,114.02 150.02,116.64 139.06,116.64 138.58,117.12 119.13,117.12 102.14,134.11 92.69,134.11 89.69,137.11 89.53,137.27 89.53,138.02 89.29,138.25 v3(89.11,138.25)
HDMI_DATA_CPU_N2: length 175.8
  TOP w0.089: CPU1.AH2 84.39,149.9 84.31,149.82 84.31,148.98 84.97,148.32 84.97,147.64 84.94,147.61 84.94,147.58
  TOP w0.102: v3(84.72,139.85) 85.17,140.31 85.17,141.04 84.94,141.28 84.94,147.58 ; 141.54,36.55 v4(141.54,36.96) ; 141.54,36.55 141,36.55 140.7,36.26 140.2,36.26 140.05,36.4 140.05,36.72 139.88,36.89 C177.1 ; 141.54,36.55 142.1,36.55 v3(142.43,36.88)
  L4 w0.127: v3(84.72,139.85) 84.72,139.65 84.89,139.47 85.1,139.47 85.25,139.32 85.25,138.48 85.68,138.05 87.48,138.05 92.26,133.27 101.73,133.27 118.67,116.33 137.32,116.33 137.32,116.33 137.45,116.33 139.25,114.52 149.92,114.52 151.85,112.59 151.85,66.36 146.82,61.33 146.82,57.67 145.09,55.94 145.09,37.87 143.47,36.25 143.06,36.25 142.91,36.4 142.91,36.7 142.73,36.88 v3(142.43,36.88)
HDMI_DATA_CPU_N3: length 172.4
  TOP w0.089: CPU1.AL1 85.87,150.1 85.87,149.1 86.45,148.52 86.45,147.75 86.42,147.72 86.42,147.7
  TOP w0.102: 140.7,38.68 140.95,38.68 141.64,38 141.84,38 141.97,38.13 141.97,38.43 142.1,38.56 142.42,38.56 v3(142.48,38.49) ; 140.7,38.68 140.29,38.68 139.98,38.38 139.72,38.38 C174.1 ; 140.7,38.68 v4(140.7,39.09) ; 86.42,147.7 86.42,142.97 88.32,141.07 88.32,139.65 87.51,138.84 87.51,137.47 87.36,137.31 86.98,137.31 86.88,137.21 86.88,136.98 v3(86.95,136.91)
  L4 w0.127: v3(142.48,38.49) 142.75,38.22 143.16,38.22 143.64,38.71 143.64,42.47 144.28,43.1 144.28,56.28 146.01,58.01 146.01,61.66 151.04,66.69 151.04,112.18 149.47,113.74 138.95,113.74 137.13,115.56 118.29,115.56 101.39,132.46 90.99,132.46 87.51,135.94 87.51,136.34 87.37,136.49 87.14,136.49 86.95,136.68 v3(86.95,136.91)
HDMI_DATA_CPU_P0: length 181.4
  TOP w0.089: 85.94,147.62 85.94,147.73 85.91,147.76 85.91,148.67 85.5,149.08 85.5,150.33 85.6,150.46 85.6,150.47 85.6,150.7 85.6,150.71 85.6,150.73 85.5,150.84 85.32,151.27 CPU1.AK3
  TOP w0.102: C192.1 139.43,32.37 140.88,32.37 ; v3(87.03,139.83) 86.82,140.03 86.82,141.46 85.94,142.34 85.94,147.62 ; 140.88,32.37 v4(140.88,31.98) ; 140.88,32.37 141.25,32.37 141.57,32.69 142.15,32.69 v3(142.45,32.38)
  L4 w0.127: v3(87.03,139.83) 87.03,139.52 87.43,139.12 90.33,139.12 90.94,138.51 90.94,137.39 93.1,135.23 102.49,135.23 119.58,118.14 139.28,118.14 139.74,117.68 150.76,117.68 153.65,114.78 153.65,65.61 148.62,60.58 148.62,56.92 146.9,55.19 146.9,35.81 143.47,32.38 v3(142.45,32.38)
HDMI_DATA_CPU_P1: length 177.8
  TOP w0.089: CPU1.AM3 86.24,151.04 86.32,150.96 86.54,150.69 86.54,150.49 86.45,150.36 86.45,150.36 86.44,150.34 86.44,149.42 87.39,148.47 87.39,147.72 87.42,147.69 87.42,147.66
  TOP w0.102: C186.1 139.72,34.52 141.13,34.52 141.56,34.09 142.41,34.09 v3(142.43,34.07) ; 87.42,147.66 87.42,143.68 89.92,141.18 v3(89.92,138.26)
  L4 w0.127: v3(142.43,34.07) 142.52,34.16 143.87,34.16 145.3,35.59 145.42,35.59 146.13,36.3 146.13,55.51 147.86,57.24 147.86,60.89 152.89,65.92 152.89,114.13 150.12,116.9 139.17,116.9 138.69,117.37 119.24,117.37 102.25,134.37 92.8,134.37 89.87,137.29 89.78,137.38 89.78,138.12 v3(89.92,138.26)
  BOTTOM w0.102: v3(142.43,34.07) 142.65,34.07 v2(143.13,34.54)
HDMI_DATA_CPU_P2: length 176.2
  TOP w0.089: CPU1.AH3 84.39,151.04 84.47,150.96 84.68,150.71 84.68,150.47 84.58,150.34 84.58,149.82 84.5,149.74 84.5,149.06 85.16,148.39 85.16,147.64 85.19,147.61 85.19,147.58
  TOP w0.102: 85.19,147.58 85.19,141.38 85.43,141.15 85.43,139.96 v3(85.53,139.85) ; v3(142.43,35.99) 142.12,36.3 141.1,36.3 140.81,36 C179.1
  L4 w0.127: v3(142.43,35.99) 143.57,35.99 145.35,37.77 145.35,55.84 147.07,57.56 147.07,61.22 152.1,66.25 152.1,112.69 150.02,114.77 139.36,114.77 137.55,116.58 118.78,116.58 101.83,133.53 92.36,133.53 87.59,138.3 85.78,138.3 85.5,138.58 85.5,139.82 v3(85.53,139.85)
  BOTTOM w0.102: v3(142.43,35.99) 142.83,35.99 v2(143.16,36.32)
HDMI_DATA_CPU_P3: length 172.8
  TOP w0.089: 86.68,147.7 86.68,147.72 86.65,147.75 86.65,148.6 86.06,149.18 86.06,150.34 85.92,150.52 85.92,150.82 CPU1.AL2
  TOP w0.102: C176.1 139.72,38.12 140.09,38.12 140.39,38.43 140.85,38.43 141.53,37.74 v3(142.45,37.74) ; v3(87.76,136.91) 87.76,138.73 88.58,139.55 88.58,141.17 86.68,143.07 86.68,147.7
  L4 w0.127: v3(87.76,136.91) 87.76,136.05 91.1,132.72 101.5,132.72 118.39,115.82 137.24,115.82 139.06,114 149.58,114 151.29,112.28 151.29,66.59 146.26,61.56 146.26,57.9 144.53,56.17 144.53,43 143.9,42.36 143.9,38.6 143.26,37.97 142.67,37.97 v3(142.45,37.74)
  BOTTOM w0.102: v2(143.16,38.1) 142.81,37.74 v3(142.45,37.74)
HDMI_DP2_HPD: length 11.3
  TOP w0.102: v1(122.61,30.71) 123.01,30.31 125.22,30.31 D6.K 127.94,27.59 RN36.1 129.76,27.12 129.95,26.92 130.08,26.92 130.08,26.92 130.33,26.92 130.41,27 RN36.2
  BOTTOM w0.102: v2(122.21,31.55) 122.21,31.11 v1(122.61,30.71)
HDMI_LANE0_DN: length 11.1
  TOP w0.102: HDMI1.3 118.37,33.82 118.71,33.47 119.12,33.47 119.41,33.18 119.41,32.11 119.72,31.8 121.39,31.8 121.62,32.03 121.62,32.64 121.9,32.92 122.23,32.92 122.37,33.06 U21.9 U21.2 124.23,33.06 124.82,32.48 125.14,32.48 125.27,32.61 TR8.2
HDMI_LANE0_DP: length 11
  TOP w0.102: TR8.3 125.38,31.93 125.08,32.22 124.71,32.22 124.35,32.58 U21.1 U21.10 122.37,32.58 122.28,32.66 122.01,32.66 121.88,32.53 121.88,31.93 121.5,31.55 119.61,31.55 119.16,32 119.16,33.07 119.01,33.22 118.71,33.22 118.32,32.82 HDMI1.1
HDMI_LANE0_IC_DN: length 4.3
  TOP w0.102: U20.29 129.56,34.17 129.45,34.06 129.14,34.06 128.09,33.01 128.09,32.57 127.89,32.38 127.41,32.38 127.18,32.61 TR8.1
HDMI_LANE0_IC_DP: length 4.2
  TOP w0.102: TR8.4 127.26,31.93 127.45,32.12 128,32.12 128.34,32.47 128.34,32.91 129.24,33.81 129.41,33.81 129.45,33.77 U20.30
HDMI_LANE1_DN: length 9
  TOP w0.102: TR7.2 125.34,34.77 125.1,34.53 124.2,34.53 124.15,34.58 U21.5 U21.6 122.45,34.58 122.31,34.44 121.95,34.44 121.48,34.92 118.71,34.92 118.32,35.32 HDMI1.6
HDMI_LANE1_DP: length 9
  TOP w0.102: HDMI1.4 118.33,34.32 118.67,34.67 121.37,34.67 121.85,34.19 122.29,34.19 122.38,34.1 U21.7 U21.4 124.13,34.1 124.3,34.28 125.06,34.28 125.25,34.09 TR7.3
HDMI_LANE1_IC_DN: length 3.6
  TOP w0.102: U20.26 129.51,35.37 129.46,35.32 128.91,35.32 128.18,34.59 127.48,34.59 127.3,34.77 TR7.1
HDMI_LANE1_IC_DP: length 3.6
  TOP w0.102: TR7.4 127.17,34.09 127.42,34.33 128.28,34.33 129.01,35.06 129.48,35.06 129.57,34.97 U20.27
HDMI_LANE2_DN: length 9.4
  TOP w0.102: HDMI1.9 118.28,36.82 118.63,36.47 119.19,36.47 119.95,35.71 121.47,35.71 122.35,36.59 U19.4 U19.7 124.3,36.59 124.5,36.79 125.31,36.79 125.58,37.05 TR6.2
HDMI_LANE2_DP: length 9.4
  TOP w0.102: HDMI1.7 118.32,35.82 118.71,36.22 119.09,36.22 119.84,35.46 121.58,35.46 122.23,36.11 U19.5 U19.6 124.18,36.11 124.6,36.53 125.26,36.53 125.42,36.37 TR6.3
HDMI_LANE2_IC_DN: length 3.6
  TOP w0.102: TR6.1 127.28,37.05 127.51,36.82 128,36.82 128.2,36.62 128.73,36.09 128.74,36.08 129.48,36.08 129.57,36.17 U20.24
HDMI_LANE2_IC_DP: length 3.6
  TOP w0.102: U20.25 129.54,35.77 129.49,35.82 128.64,35.82 128.55,35.91 127.9,36.57 127.45,36.57 127.26,36.37 TR6.4
HDMI_LANE3_DN: length 9.5
  TOP w0.102: TR5.2 125.37,39.21 124.94,38.79 124.92,38.79 124.24,38.11 U19.10 U19.1 122.07,38.11 121.55,38.63 119.47,38.63 118.81,37.97 118.71,37.97 118.37,38.32 HDMI1.12
HDMI_LANE3_DP: length 9.6
  TOP w0.102: TR5.3 125.02,38.53 124.12,37.63 U19.9 U19.2 122.19,37.63 121.45,38.38 119.57,38.38 118.91,37.72 118.71,37.72 118.32,37.32 HDMI1.10
HDMI_LANE3_IC_DN: length 4.3
  TOP w0.102: TR5.1 127.26,39.21 127.45,39.02 128.33,39.02 128.97,38.38 128.97,37.74 129.39,37.32 129.49,37.32 129.54,37.37 U20.21
HDMI_LANE3_IC_DP: length 4.4
  TOP w0.102: TR5.4 127.28,38.53 127.51,38.76 128.22,38.76 128.71,38.27 128.71,37.64 129.29,37.06 129.48,37.06 129.57,36.97 U20.22
HPOL_CON: length 59
  TOP w0.203: v1(153.65,56.16) 153.75,56.16 153.79,56.2 R384.2 ; v1(168.34,78.49) 168.34,77.62 Q29.1 168.46,77.53 R326.1 C123.1 172.94,77.53 173.4,77.99 UHS1.1 ; R412.2 v1(167.04,45.42) ; v1(159.88,59.6) 159.88,59.93 R372.2
  L4 w0.203: v1(168.34,78.49) 168.34,77.62 168.61,77.34 168.61,68.88 159.88,60.15 v1(159.88,59.6)
  BOTTOM w0.203: v1(167.04,45.42) 165.01,47.45 164.03,47.45 162.49,48.98 162.49,55.38 v2(162.17,55.7) 162.17,58.13 160.7,59.6 v1(159.88,59.6) 158.72,59.6 155.28,56.16 v1(153.65,56.16)
HPOR_CON: length 69.6
  TOP w0.203: v1(167.04,46.46) 166.68,46.81 R410.2 ; v1(158.2,59.87) 157.22,60.85 R370.2 ; v1(172.12,80.45) C121.1 R319.1 169.82,80.45 168.85,79.48 Q29.2 v1(168.44,80.49) ; R406.2 166.99,48.21 v1(167.06,48.29)
  L4 w0.203: v1(168.44,80.49) 167.8,79.85 167.8,77.22 168.16,76.86 168.16,69.07 158.95,59.87 v1(158.2,59.87)
  BOTTOM w0.203: v1(172.12,80.45) 174.98,80.45 180.5,74.93 180.5,72.09 UHS1.2 ; v1(158.2,59.87) 158.44,60.11 160.93,60.11 162.74,58.3 v2(162.74,57.14) 163.02,56.85 163.02,49.27 164.11,48.18 165.62,48.18 165.72,48.29 v1(167.06,48.29) 166.4,47.62 166.4,47.09 v1(167.04,46.46)
HPOUT-JD: length 24.7
  TOP w0.203: UHS1.6 173.33,71.56 171.67,71.56 165.77,65.66 v4(165.77,64.26) 166.15,63.88 166.15,60.63 167.5,59.28 167.5,53.31 166.89,52.7 R389.1
HPOUT-L: length 4.4
  TOP w0.203: U16.26 163.08,46.97 163.28,46.76 163.28,45.77 164.19,44.86 v4(164.21,44.86) 164.74,44.86 R412.1
HPOUT-R: length 3.6
  TOP w0.203: U16.27 163.15,47.37 164,46.52 v4(164,46.22) 164.73,46.22 R410.1
HSI_C_DN2: length 102
  TOP w0.102: v1(102.93,214.12) R37.2 ; CPU1.M7 76.45,153.09 v3(76.45,153.05)
  L4 w0.127: v1(102.93,214.12) 104.26,214.12 104.79,213.59 104.79,211.54 103.38,210.13 100.93,210.13 100.05,211.01 89.59,211.01 77.13,198.55 71.74,198.55 69.78,196.6 69.78,184.05 69.55,183.82 69.55,169.52 68.82,168.78 68.82,162.36 68.33,161.87 68.33,158.04 67.49,157.19 67.49,155.46 67.69,155.26 76.19,155.26 76.86,154.59 76.86,153.46 v3(76.45,153.05)
  BOTTOM w0.102: v1(102.93,214.12) v2(102.93,215.16)
HSI_C_DP2: length 102
  TOP w0.102: R42.2 103.47,213.37 103.19,213.37 v1(102.93,213.11) ; v3(76.45,153.76) 76.45,153.61 76.2,153.42 CPU1.K7
  L4 w0.127: v1(102.93,213.11) 103.37,213.11 103.51,213.25 103.51,213.7 103.66,213.86 104.15,213.86 104.53,213.48 104.53,211.65 103.27,210.39 101.04,210.39 100.16,211.28 89.48,211.28 77.02,198.82 71.63,198.82 69.51,196.71 69.51,184.16 69.29,183.93 69.29,169.63 68.55,168.89 68.55,162.47 68.07,161.98 68.07,158.15 67.22,157.3 67.22,155.35 67.58,154.99 76.08,154.99 76.35,154.72 76.35,154.53 76.23,154.4 76.15,154.4 76.02,154.27 76.02,153.89 76.15,153.76 v3(76.45,153.76)
  BOTTOM w0.102: v2(103.84,213.36) 103.59,213.11 v1(102.93,213.11)
HSI_LAN_DN1_R: length 5.2
  TOP w0.102: C219.1 32.76,19.02 32.76,18.34 ; v4(32.42,18.34) 32.76,18.34 ; 32.76,18.34 32.76,17.81 33.09,17.48 33.09,16.36 33.46,15.99 U26.18
HSI_LAN_DN3: length 174.7
  TOP w0.102: CPU1.M6 76.45,152.38 76.4,152.38 v3(76.39,152.37) ; v1(32.32,21.26) 32.68,20.89 32.68,20.52 C219.2
  L3 w0.127: v3(62.34,136.48) 62.56,136.71 62.56,137.39 62.34,137.61 62.34,141.77 67.66,147.09 74.15,147.09 75.74,148.68 75.74,151.27 75.91,151.44 75.91,151.89 v3(76.39,152.37)
  L4 w0.127: v1(32.32,21.26) 32.32,26.21 35.59,29.49 35.59,30.33 39.11,33.85 39.11,44.03 35.14,48.01 28.25,54.9 28.25,54.9 27.23,55.92 27.23,69.47 33.88,76.11 33.88,82.66 36.7,85.48 36.7,124.08 43.53,130.91 51.69,130.91 54.69,133.92 54.84,134.07 59.73,134.07 60.64,134.98 61.84,134.98 62.43,135.57 62.43,136.39 v3(62.34,136.48)
  BOTTOM w0.102: v1(32.32,21.26) 33.11,20.47 33.12,20.47 v2(33.17,20.42)
HSI_LAN_DP1_R: length 6.1
  TOP w0.102: U26.17 34,16.39 33.81,16.2 33.55,16.2 33.31,16.45 33.31,17.57 32.98,17.9 32.98,18.49 33.13,18.64 33.46,18.64 33.53,18.72 33.53,18.95 33.31,19.17 C220.1 33.93,19.37 v4(34.3,19)
HSI_LAN_DP3: length 174.4
  TOP w0.102: C220.2 32.9,20.66 32.9,21.03 33.1,21.23 v1(33.21,21.23) ; CPU1.M5 76.9,151.97 76.57,151.71 v3(76.39,151.71)
  L3 w0.127: v3(76.39,151.71) 76.39,151.54 76,151.16 76,148.57 74.26,146.82 67.77,146.82 62.6,141.66 62.6,137.72 62.82,137.5 62.82,136.71 v3(63.05,136.48)
  L4 w0.127: v1(33.21,21.23) 33.21,21.62 33.03,21.79 32.72,21.79 32.58,21.93 32.58,26.1 35.86,29.38 35.86,30.22 39.22,33.58 39.38,33.74 39.38,44.14 35.25,48.28 28.52,55.01 28.52,55.01 27.5,56.03 27.5,69.35 34.14,76 34.14,82.55 36.96,85.37 36.96,123.97 43.64,130.65 51.8,130.65 54.96,133.8 59.84,133.8 60.75,134.71 61.95,134.71 62.69,135.46 62.69,136.13 v3(63.05,136.48)
  BOTTOM w0.102: v1(33.21,21.23) 33.21,21.77 v2(33.54,22.1)
HSO_C_DN2: length 104.3
  TOP w0.102: C41.2 73.05,145.5 73.05,145.12 72.76,144.83 71.68,144.83 69.85,146.65 69.85,149.41 v3(69.58,149.68) ; v1(102.93,212.09) 103.12,211.9 103.54,211.9 R45.2
  L4 w0.127: v3(69.58,149.68) 69.86,149.96 69.86,150.26 70.29,150.68 71.17,150.68 71.44,150.96 71.44,152.44 69.81,154.08 67.01,154.08 66.32,154.76 66.32,161.66 67.62,162.96 67.62,169.31 68.32,170.01 68.32,184.24 68.56,184.48 68.56,197.13 71.16,199.72 76.61,199.72 89.07,212.18 100.78,212.18 101.24,211.72 102.51,211.72 102.53,211.74 v1(102.93,212.09)
  BOTTOM w0.102: v1(102.93,212.09) 103.56,212.09 v2(103.77,211.89)
HSO_C_DP2: length 104.4
  TOP w0.102: R49.2 v1(102.85,211.07) ; v3(70.3,149.68) 70.07,149.45 70.07,146.74 71.77,145.04 72.67,145.04 72.84,145.21 72.84,145.5 C40.2
  L4 w0.127: v3(70.3,149.68) 70.13,149.86 70.13,150.15 70.4,150.42 71.28,150.42 71.71,150.85 71.71,152.55 69.92,154.34 67.12,154.34 66.59,154.87 66.59,161.55 67.89,162.85 67.89,169.2 68.59,169.9 68.59,184.13 68.83,184.37 68.83,197.02 71.27,199.45 76.72,199.45 89.18,211.91 100.67,211.91 101.13,211.46 102.52,211.46 v1(102.85,211.07)
  BOTTOM w0.102: v2(104.92,210.43) 104.61,210.43 104.21,210.83 103.1,210.83 v1(102.85,211.07)
HSO_C_LAN_DN3: length 186.9
  TOP w0.102: U26.14 36.01,17.48 36.11,17.58 36.11,19.97 v1(35.92,20.16) ; 75.55,135.8 77.03,135.8 78.58,137.34 78.58,143.38 C47.2 ; 75.55,135.8 v4(75.55,135.39) ; 75.55,135.8 74.42,135.8 73.44,136.78 72.6,136.78 v3(72.31,136.5)
  L4 w0.127: v1(35.92,20.16) 35.1,19.34 30.4,19.34 30.32,19.42 29.79,19.94 29.79,28.41 30.28,28.9 31.02,29.64 35.07,33.69 37.27,35.89 37.27,43.59 33.21,47.64 29.78,51.08 29.78,51.11 25.8,55.08 25.68,55.2 25.68,70.27 30.56,75.16 30.56,77.76 31.17,78.36 31.17,88.57 31.96,89.36 31.96,91.11 33.49,92.64 33.88,92.64 35.13,93.89 35.13,100.44 33.4,102.17 33.4,117.12 33.76,117.48 33.76,123.34 42.9,132.48 50.28,132.48 53.69,135.88 58.65,135.88 60.89,138.13 68.36,138.13 69.66,136.82 70.46,136.82 70.96,137.33 71.66,137.33 71.76,137.22 71.76,136.5 71.86,136.4 72.21,136.4 v3(72.31,136.5)
HSO_C_LAN_DP3: length 187.7
  TOP w0.102: v4(77.98,139.81) 78.36,139.81 ; 78.36,139.81 78.36,137.43 76.94,136.02 74.51,136.02 73.53,136.99 72.6,136.99 v3(72.29,137.31) ; 78.36,139.81 78.36,143.39 C46.2 ; v1(36.79,20.16) 36.33,19.7 36.33,17.55 36.41,17.47 U26.13
  L4 w0.127: v1(36.79,20.16) 36.28,19.66 35.79,19.66 35.21,19.07 30.29,19.07 30.13,19.23 29.52,19.83 29.52,28.52 34.96,33.96 37,36 37,43.48 33.1,47.37 29.51,50.97 29.51,50.99 25.69,54.82 25.69,54.82 25.42,55.09 25.42,70.38 30.3,75.27 30.3,77.87 30.9,78.47 30.9,88.68 31.69,89.47 31.69,91.22 33.38,92.91 33.77,92.91 34.86,94 34.86,100.32 33.13,102.06 33.13,117.23 33.49,117.59 33.49,123.45 42.79,132.74 50.17,132.74 53.58,136.15 58.54,136.15 60.78,138.39 68.47,138.39 69.77,137.09 70.35,137.09 70.85,137.59 72.01,137.59 v3(72.29,137.31)
HSO_LAN_DN3: length 7.2
  TOP w0.089: 78.54,147.34 78.54,147.78 78.86,148.1 78.86,149.69 79.02,149.85 79.02,150.34 79.13,150.49 79.13,150.69 78.91,150.96 78.83,151.04 CPU1.T3
  TOP w0.102: C47.1 78.54,144.98 78.54,147.34
HSO_LAN_DP3: length 6.3
  TOP w0.089: 78.33,147.34 78.33,147.35 78.35,147.37 78.35,147.42 78.35,147.42 78.35,147.86 78.67,148.18 78.67,149.77 78.83,149.92 CPU1.T2
  TOP w0.102: C46.1 78.33,144.91 78.33,147.34
I2CC_SCL_PU: length 11.4
  TOP w0.102: RN20.4 95.66,85.09 94.51,86.23 v4(93.99,86.23) 93.66,86.56 91.96,86.56 91.4,87.12 89.82,87.12 87.64,89.3 GPU1.A9
I2CC_SDA_PU: length 11.4
  TOP w0.102: RN20.3 95.87,85.74 v4(95.35,86.26) 94.82,86.79 92.07,86.79 91.5,87.37 89.87,87.37 87.2,90.04 87.18,90.04 GPU1.B9
I2CS_SCL_G: length 20.6
  TOP w0.102: GPU1.D9 87.13,91.7 87.54,91.29 v3(87.54,91.29) ; RN19.3 99.83,83.9 v1(99.64,83.71) 98.81,83.71 R312.1
  BOTTOM w0.102: v3(87.54,91.29) 88.27,92.02 90.38,92.02 91.51,90.89 92.69,90.89 94.26,89.33 94.77,89.33 95.08,89.64 96.76,89.64 99.09,87.31 v2(99.09,85.7) 99.08,85.7 99.07,85.69 99.07,84.27 v1(99.64,83.71)
I2CS_SDA_G: length 21.9
  TOP w0.102: v3(88.38,91.3) 87.98,91.7 GPU1.D8 ; v1(100.46,83.69) 100.48,83.71 RN19.4 100.54,84.65 R306.1
  BOTTOM w0.102: v1(100.46,83.69) 100.46,83.69 100.01,83.24 99.42,83.24 98.58,84.08 98.58,87.07 98.43,87.22 v2(98.43,87.25) 98.28,87.25 96.1,89.43 95.36,89.43 95.05,89.12 94.17,89.12 92.62,90.68 91.44,90.68 91.43,90.69 91.43,90.69 90.29,91.82 88.9,91.82 v3(88.38,91.3)
IMS: length 137.4
  TOP w0.102: v1(43.75,106.22) 43.47,106.5 LVDS1.4 ; v1(116.37,47.19) 117.19,48.02 R400.1
  L3 w0.127: v1(116.37,47.19) 115.86,47.7 114.78,47.7 114.52,47.45 112.89,47.45 112,48.34 99.51,48.34 96.4,51.44 96.4,65.47 85.29,76.58 65.55,76.58 65.21,76.92 62.86,76.92 62.59,76.66 54.43,76.66 53.85,77.24 52.67,77.24 52.66,77.25 52.45,77.25 49.86,79.84 49.86,79.84 49.28,80.42 48.36,80.42 44.74,84.04 44.74,103.17 44.03,103.89 44.03,104.55 44.18,104.7 44.18,105.44 43.75,105.87 v1(43.75,106.22) 43.71,106.26 43.71,106.66 44.14,107.09 44.14,107.76 44.17,107.78 44.17,108.17 43.62,108.72 43.62,109.86 43.19,110.29 43.19,117.97 v3(43.56,118.34)
  BOTTOM w0.102: v2(45.58,119.59) 45.48,119.48 R633.1 R634.2 43.56,119.46 v3(43.56,118.34)
INIT_3V: length 5.5
  TOP w0.102: LPC1.2 103.63,76.03 102.19,77.47 102.19,78.21 101.96,78.44 v4(101.96,79.1) 101.96,79.26 R325.2
INT_SERIRQ_CPU: length 265.5
  TOP w0.089: CPU1.AB62 81.61,180.05 81.71,180.15 81.71,180.63 81.27,181.07 81.27,181.36
  TOP w0.102: v1(142.29,72.96) 142.24,72.96 141.36,73.84 R338.1 138.37,72.46 U13.3 ; v1(95.08,204.14) 93.81,202.87 88.46,202.87 82.14,196.55 82.14,184.81 81.27,183.95 81.27,181.36 ; v1(148.04,99.75) 148.04,100.13 146.64,101.52 146.64,105.38 146.51,105.51 146.51,110.74 143.33,113.92 136.14,113.92 133.62,116.43 R235.1
  L3 w0.127: v1(146.61,85.17) 147.05,85.6 147.05,87.62 147.63,88.2 147.63,88.71 147.89,88.97 147.89,99.59 v1(148.04,99.75) 148.13,99.66 148.68,99.66 156.58,107.56 156.58,121.06 159.01,123.49 159.01,126.95 160.15,128.09 160.15,130.77 162.23,132.84 162.38,132.84 163.82,134.29 163.82,152.17 161.82,154.17 161.82,174.37 161.81,174.38 161.81,176.06 154.74,183.12 154.74,188.78 139.94,203.58 129.02,203.58 127.03,205.57 113.78,205.57 113.16,204.95 108.12,204.95 106.44,203.28 102.96,203.28 102.27,203.96 100.1,203.96 99.06,202.92 98.31,202.92 98.3,202.91 96.31,202.91 v1(95.08,204.14)
  BOTTOM w0.102: v1(146.61,85.17) 146.51,85.27 145.3,85.27 142.29,82.26 v2(142.29,81.25) v1(142.29,72.96)
INT_SERIRQ_OE: length 6.1
  TOP w0.102: U13.5 137.21,71.74 137.47,71.48 137.47,70.6 138.16,69.9 R351.1 138.18,69.19 R348.2 139.17,69.09 140.05,68.21 v4(140.05,68.21)
INTRUDER: length 38.1
  TOP w0.102: CPU1.AC54 v3(82.08,175.52) ; v1(71.36,197.46) 71.47,197.57 R89.1 72.58,198.4 71.84,199.14 v4(70.14,199.14) 69.92,198.92 R88.2
  L3 w0.127: v1(71.36,197.46) 71.56,197.46 73.17,195.85 73.76,195.85 73.77,195.83 74.26,195.83 74.92,195.17 74.92,193.28 73.79,192.15 73.79,181.51 73.97,181.33 73.97,180.21 74.76,179.43 79.66,179.43 80.7,178.38 80.7,177.5 81.64,176.56 81.64,175.96 v3(82.08,175.52)
ISEN1: length 5.2
  BOTTOM w0.254: U35.17 32.43,32.23 32.07,32.59 30.94,32.59 v2(30.31,33.22) 29.9,32.82 R768.2
ISEN2: length 5.7
  BOTTOM w0.254: U35.16 31.6,31.67 31.22,32.05 29.6,32.05 v2(29.5,32.16) 26.66,32.16 R769.2
ISEN3: length 3.2
  BOTTOM w0.254: R770.2 28.51,31.6 v2(29.27,30.84) 29.89,30.22 U35.14
ISEN4: length 5.1
  BOTTOM w0.254: U35.13 28.3,29.72 v2(27.36,30.66) 27.36,30.71 27.11,30.96 R772.2
ISET: length 6
  TOP w0.127: R464.2 R459.1 131.84,29.37 v4(131.88,29.41) 131.99,29.51 131.99,31.52 132.14,31.68 U20.34
ISP_CLK1: length 24.2
  TOP w0.102: v1(41.66,75.51) 41.56,75.62 40.66,75.62 39.12,77.15 39.12,78.05 38.06,79.12 35.67,79.12 35.36,78.82 35.36,78.77 35.09,78.49 35.05,78.49 34.16,77.6 31.83,77.6 v1(31.22,76.99)
  BOTTOM w0.102: Q62.6 31.63,76.58 v1(31.22,76.99) 31.08,76.85 R701.2 ; Q62.3 35.2,74.94 35.69,74.45 40.75,74.45 v2(41.06,74.76) 41.66,75.36 v1(41.66,75.51)
ISP_DAT1: length 17.4
  TOP w0.102: v1(41.15,76.59) 41.15,76.84 38.23,79.76 35.54,79.76 34.88,79.1 v1(34.88,78.97)
  BOTTOM w0.102: v1(34.88,78.97) 34.86,78.94 34.86,77.99 Q61.6 ; Q61.3 40.07,75.45 41.15,76.52 v1(41.15,76.59) 41.15,77.76 v2(41.21,77.83) 42.25,78.87 R700.2
ISW: length 5.4
  BOTTOM w0.254: C498.1 36.29,35.45 35.06,34.21 R766.2 34.53,34.21 v2(33.51,33.2) 33.43,33.11 U35.19
ISW_1:
  vias: v2(40.42,41.15)
JACK_PSID: length 41.4
  TOP w0.102: DCIN2.4 54.75,39.01 54.38,39.38 53.17,39.38 v3(53,39.55) ; 51.67,26.9 53.04,25.53 DCIN1.3 ; 51.67,26.9 49.31,24.54 49.31,23.52 v3(48.89,23.1) 48.31,22.52 L16.1 ; 51.67,26.9 51.09,27.48 51.09,30.81 51.52,31.24 53.88,31.24 54.75,32.11 DCIN2.11
  BOTTOM w0.102: v3(48.89,23.1) 48.52,23.47 48.52,32.21 v2(51.53,35.21) 53,36.69 v3(53,39.55)
JDREF: length 4.8
  TOP w0.203: U16.35 163.09,50.57 163.33,50.81
  TOP w0.254: R387.1 165.06,53.82 v4(164.21,52.98) 163.36,52.12 163.36,50.84 163.33,50.81
JTAG_TCLK: length 8.8
  TOP w0.102: v1(97.67,107.62) 97.07,108.22 R262.2 96.27,108.45 96.16,108.56 93.97,108.56 93.83,108.7 90.86,108.7 90.46,109.1 GPU1.AE5
  BOTTOM w0.102: v2(98.15,108.28) 97.67,107.79 v1(97.67,107.62)
JTAG_TDI: length 10.6
  TOP w0.102: v1(96.6,113.87) 95.99,113.26 95.99,112.89 95.13,112.03 92.1,112.03 90.08,110.02 90.08,109.86 89.6,109.38 GPU1.AE6
  BOTTOM w0.102: TP47.1 97.01,113.87 v1(96.6,113.87)
JTAG_TDO: length 9.5
  TOP w0.102: GPU1.AF6 92.1,112.39 95.21,112.39 95.79,112.98 v1(95.79,113.89)
  BOTTOM w0.102: v1(95.79,113.89) 95.79,114.43 TP46.1
JTAG_TMS: length 1.5
  TOP w0.102: GPU1.AD6 89.6,108.32 89.99,108.71 v3(90.02,108.71)
  BOTTOM w0.102: TP76.1 v3(90.02,108.71)
JTAG_TRST: length 8.1
  TOP w0.102: GPU1.AG4 92.26,111.66 93.69,111.66 v1(93.78,111.56) 93.88,111.66 95.84,111.66 96.38,111.12 97,111.12 R255.2
  BOTTOM w0.102: v2(94.27,110.19) 94.27,110.82 93.78,111.3 v1(93.78,111.56)
KBC_ON#_GATE: length 9.2
  BOTTOM w0.102: C463.2 139.47,74.85 R703.2 139.68,76.08 v2(139.68,76.83) 139.45,76.83 138.9,76.28 Q63.G 137.15,76.28 136.68,75.81 136.68,74.94 136.91,74.71 136.91,73.64 136.88,73.61 Q64.G
KBC_ON#_GATE_L: length 3.6
  BOTTOM w0.102: v2(141.46,76.53) 141.03,76.53 R703.1 140.36,74.87 R706.1 141.54,74.78 R705.2
KBC_SPI_CLK: length 4.3
  TOP w0.102: R361.2 139.28,64.52 v4(139.63,64.16) 140.37,64.9 R360.1 R362.1
KBC_SPI_CS0_N: length 3.9
  TOP w0.102: R366.2 139.71,61.72 v4(139.81,61.82) 140.16,61.47 R368.1 R365.1
KBC_SPI_DATAIN: length 2.7
  TOP w0.102: R377.1 139.96,59.18 v4(139.89,59.11) 139.56,59.44 R374.1
KBC_SPI_DATAOUT: length 2.6
  TOP w0.102: R371.1 140.06,60.33 v4(139.91,60.48) 139.81,60.58 R369.2
KBC_VCC: length 45.5
  TOP w0.203: 122.18,52.79 122.18,52.55 122.25,52.48 U14.46 122.25,49.22 C160.1 ; v1(117.5,58.16) 117.47,58.13 U14.19 ; U14.76 129.68,57.33 ; v1(121.7,64.64) 121.71,64.64 122.25,65.18 U14.115
  TOP w0.305: 122.18,52.79 122.18,53.11 121.68,53.61 121.68,55.72 122.27,56.3 v1(122.27,58.61) ; 129.68,57.33 129.69,57.34 v1(129.73,57.34) 129.64,57.25 128.96,57.25 128.8,57.1 128.15,57.1 128.15,57.1 126.33,57.1 124.61,58.82 124.61,58.96 124.54,59.03 124.54,59.31 123.5,60.35 v1(123.5,60.54)
  L4 w0.305: v1(121.7,64.64) 121.79,64.55 121.79,63.19 123.5,61.48 v1(123.5,60.54)
  BOTTOM w0.305: v1(129.73,57.34) C477.1 C476.1 ; v1(123.5,60.54) 123.5,60.53 123.63,60.4 123.63,60.02 122.27,58.66 v1(122.27,58.61) 122.22,58.61 122.16,58.55 121.83,58.55 C473.1 120.83,59.55 v2(118.17,59.55) R736.1 114.98,59.35 116.39,57.95 C474.1 117.29,57.95 v1(117.5,58.16) ; C468.1 122.28,65.19 121.73,64.64 v1(121.7,64.64)
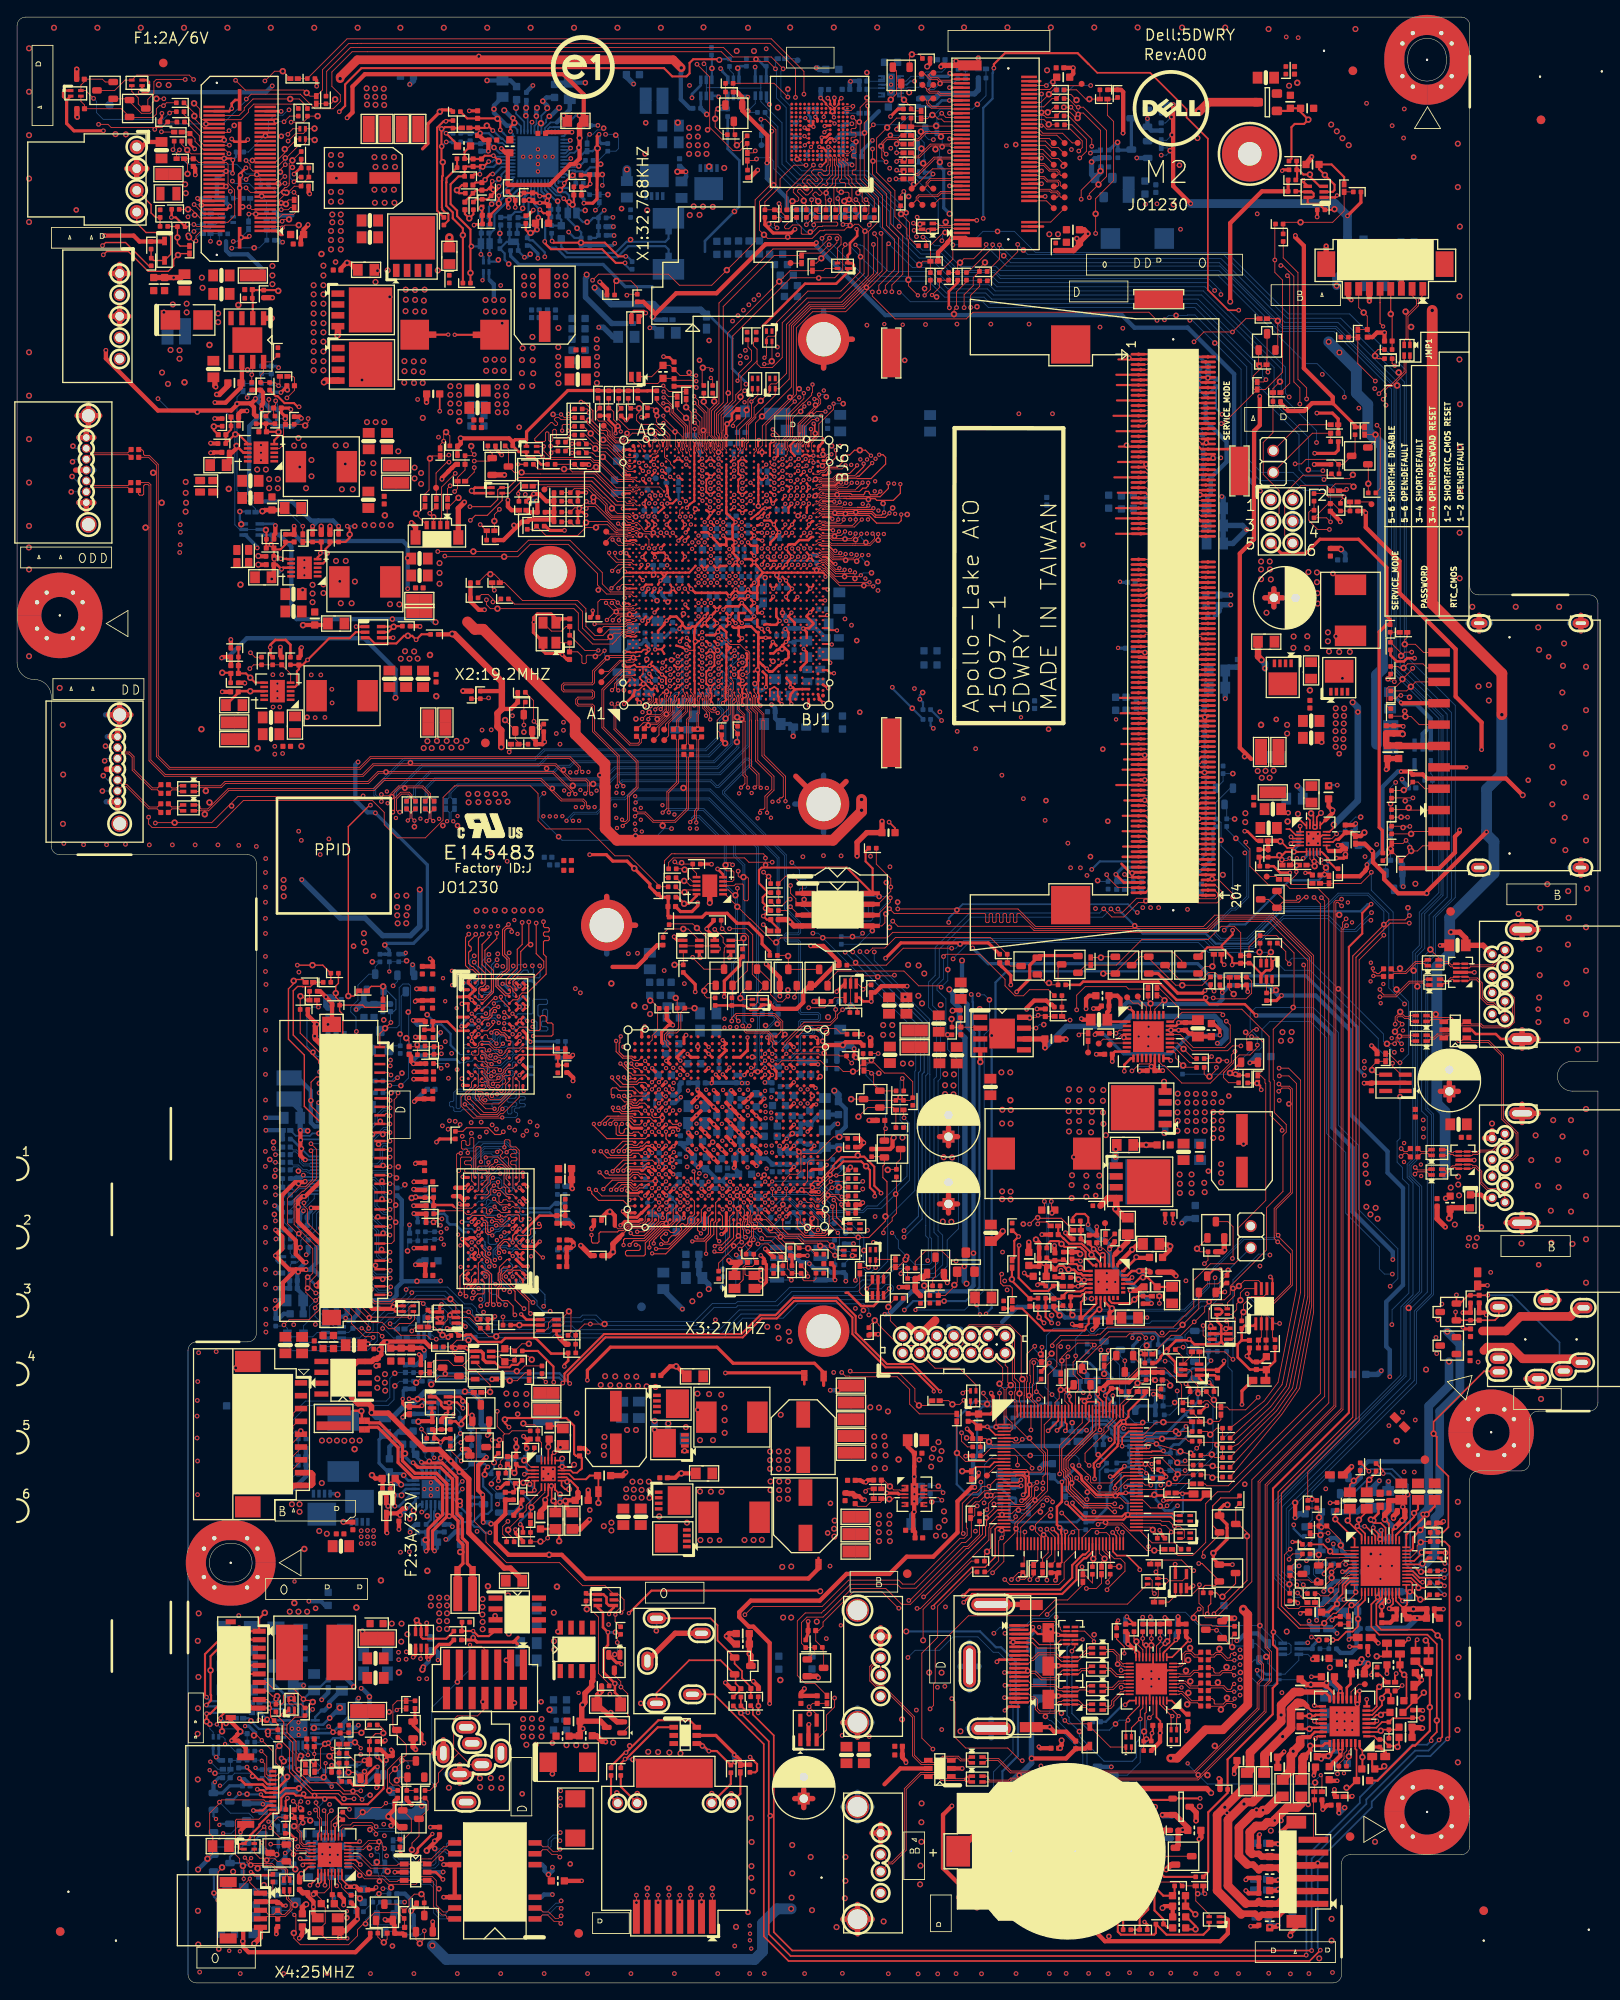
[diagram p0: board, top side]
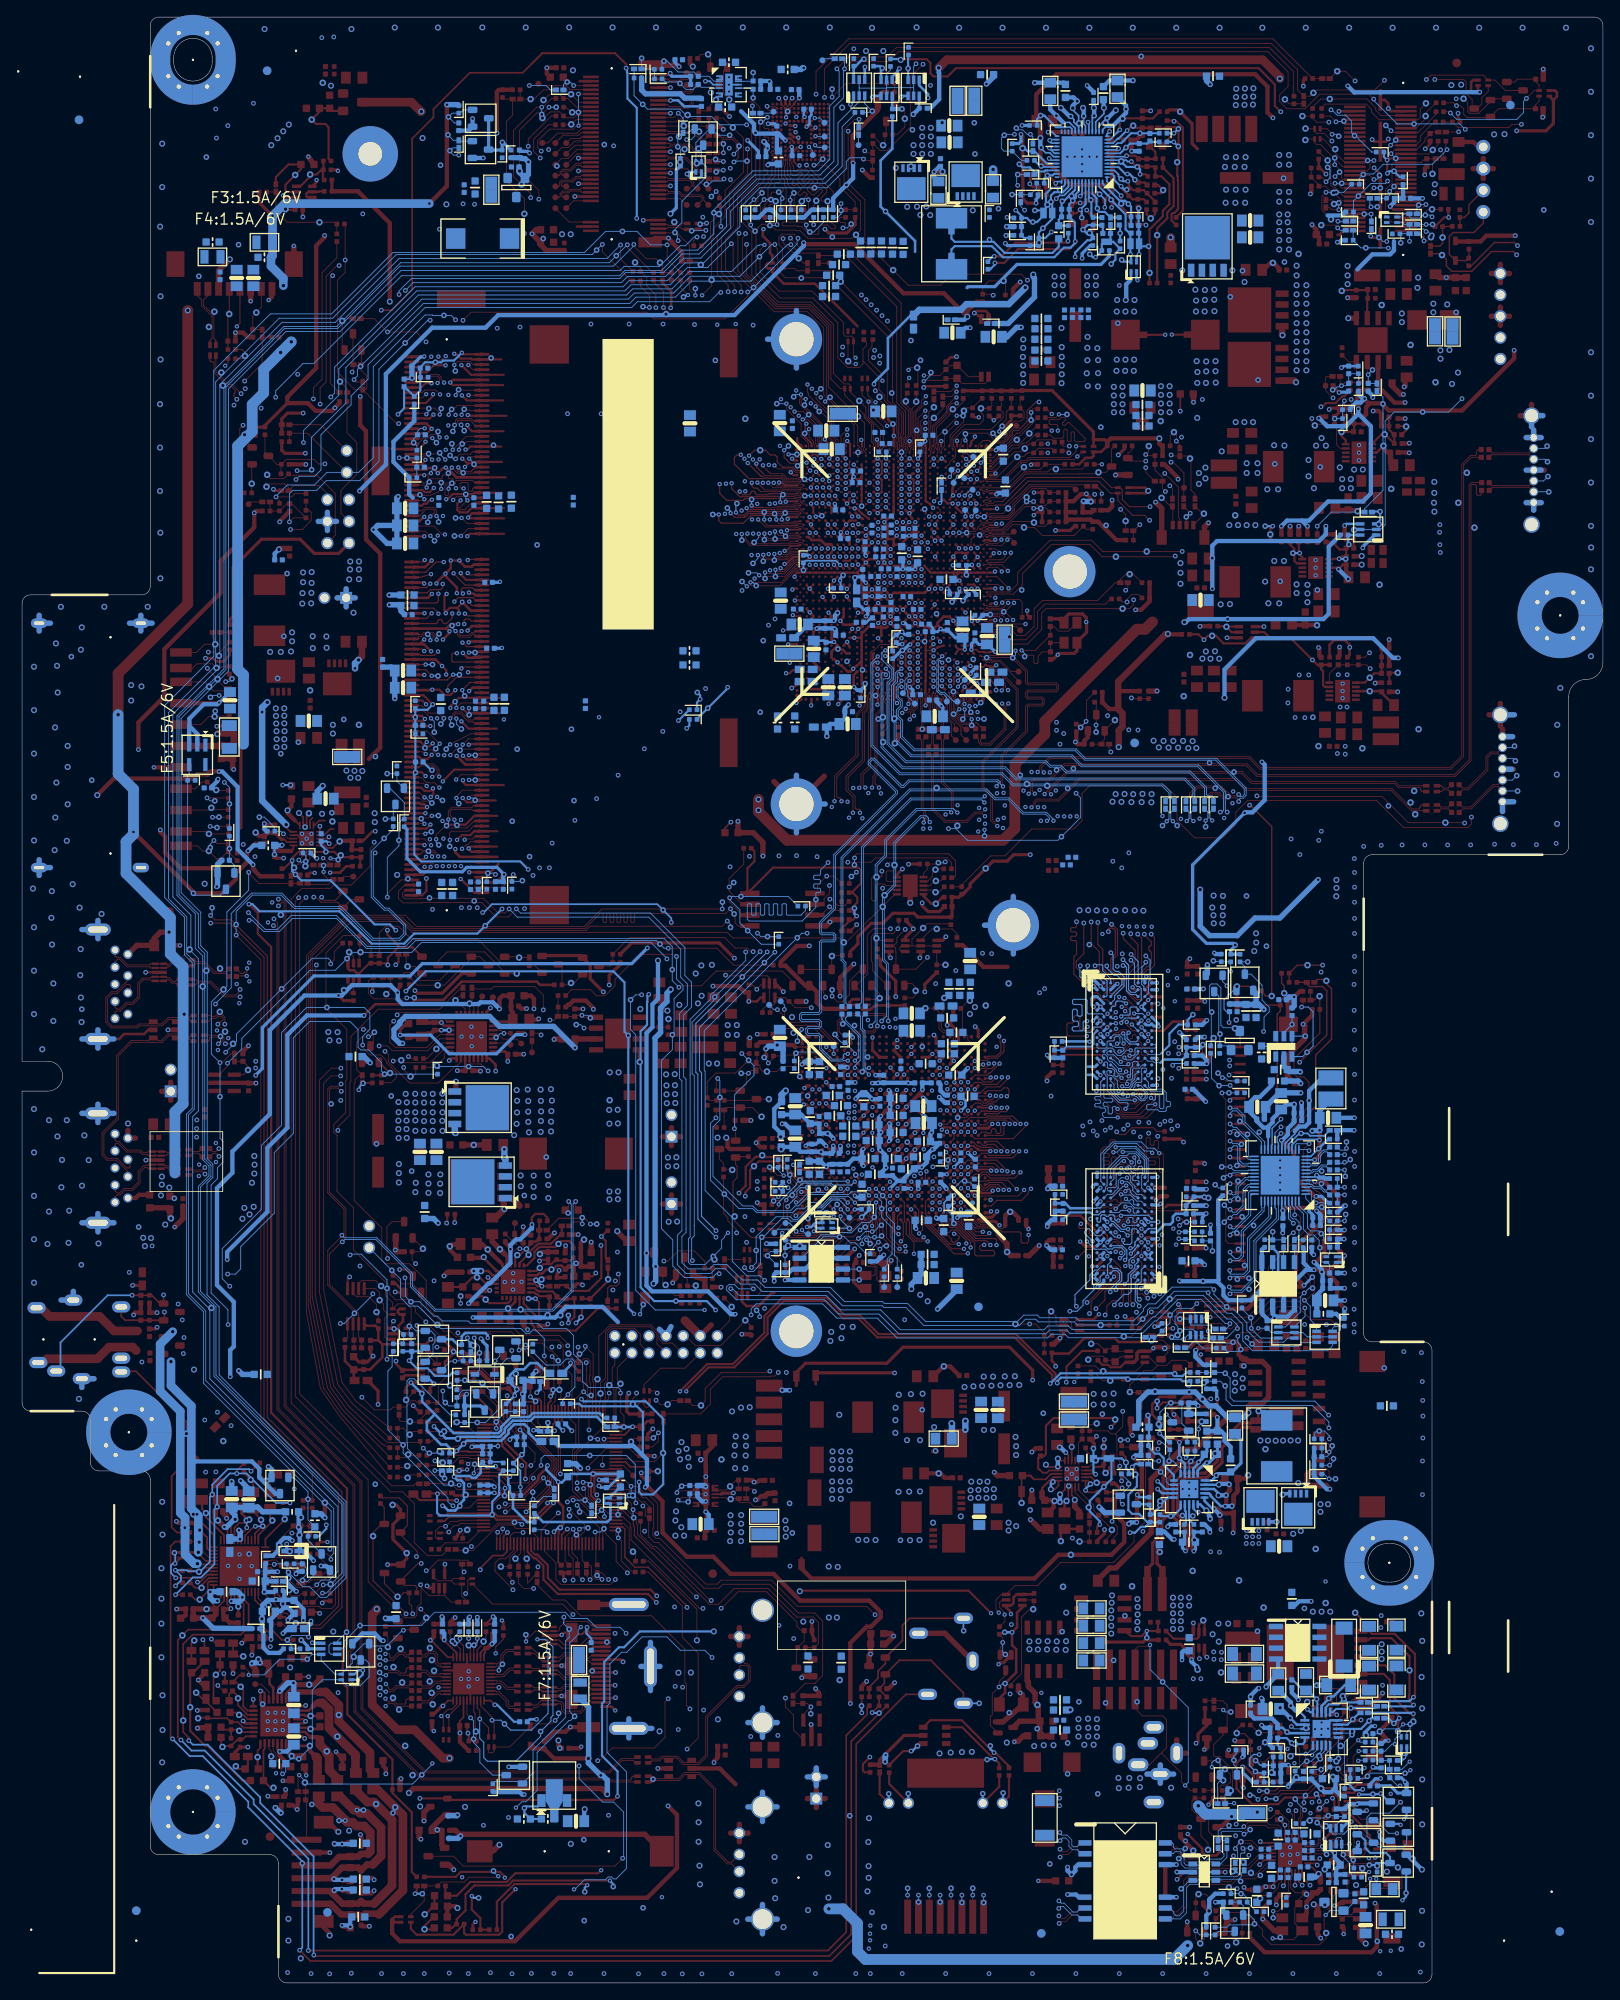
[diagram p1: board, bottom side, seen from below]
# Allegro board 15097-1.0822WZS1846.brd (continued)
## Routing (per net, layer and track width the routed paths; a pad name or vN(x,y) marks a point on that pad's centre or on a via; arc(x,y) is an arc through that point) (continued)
KBC_VCORF: length 5.5
  TOP w0.102: C159.1 121.45,49.34 U14.44 121.45,52.14 v1(120.51,53.09)
  BOTTOM w0.102: v2(120.12,52.43) 120.45,53.01 v1(120.51,53.09)
LAD0_FWH0: length 259.9
  TOP w0.089: CPU1.Y61 80.68,178.94 80.4,179.29 80.4,179.53 80.49,179.66 80.49,180 80.4,180.09 80.4,181.36
  TOP w0.102: LPC1.5 107.75,73.7 108.91,74.86 109.98,74.86 110.47,75.35 110.47,76.05 111.42,77 115.79,77 115.79,77 116.17,77 117.51,75.66 117.51,70.79 v4(117.66,70.64) 117.86,70.43 117.86,68.73 117.85,68.71 U14.126 ; U7.24 135.23,112.47 136.33,113.56 140.9,113.56 141.1,113.36 v1(141.1,113.26) ; v3(79.25,184.85) 80.4,183.7 80.4,181.36
  L3 w0.127: v3(79.25,184.85) 79.64,185.24 79.64,185.86 79.05,186.45 79.05,191.03 88.39,200.37 104.14,200.37 104.15,200.38 109.79,200.38 110.17,200 133.62,200 142.74,190.87 142.74,172.78 141.85,171.89 141.85,166.37 141.28,165.8 141.28,159.98 141.85,159.4 141.85,149.64 141.42,149.21 141.42,130.82 142.16,130.08 142.16,129.05 140.27,127.16 140.27,118.01 141.54,116.74 141.54,113.69 v1(141.1,113.26) 141.03,113.18 141.03,112.29 141.26,112.06 141.26,110.39 141.03,110.16 141.03,109.75 140.85,109.57 140.85,107.37 142.98,105.23 142.98,104.82 143.19,104.62 143.19,92.56 136.48,85.86 136.48,85.5 136.48,85.49 136.48,85.12 131.7,80.34 131.34,80.34 129.83,78.83 129.2,78.83 124.05,78.83 123.95,78.93 112.71,78.93 111.54,77.76 111.54,77.17 110.52,76.15 110.52,75.39 109.99,74.85 108.78,74.85 LPC1.5
LAD1_FWH1: length 259.3
  TOP w0.089: 80.64,181.36 80.58,181.3 80.58,180.16 80.68,180.06 CPU1.Y62
  TOP w0.102: 80.64,181.36 80.64,183.76 79.74,184.66 79.74,185.13 v3(79.23,185.64) ; U7.21 136.1,110.97 137.65,109.42 141.31,109.42 141.97,110.08 141.97,112.06 v1(141.51,112.52) ; LPC1.7 110.7,74.77 110.7,75.95 111.52,76.77 116.08,76.77 116.72,76.12 116.72,70.79 117.3,70.2 v4(117.3,68.96) 117.3,67.98 117.45,67.84 U14.127
  L3 w0.127: v3(79.23,185.64) 78.8,186.07 78.8,191.14 88.28,200.62 104.04,200.62 104.05,200.63 109.89,200.63 110.27,200.25 133.72,200.25 143,190.98 143,172.67 142.11,171.78 142.11,166.27 141.53,165.69 141.53,160.08 142.11,159.51 142.11,149.53 141.68,149.1 141.68,130.92 142.41,130.18 142.41,128.95 140.54,127.07 140.54,118.11 141.79,116.86 141.79,112.8 v1(141.51,112.52) 141.51,110.26 141.28,110.03 141.28,109.5 141.1,109.32 141.1,107.65 143.24,105.51 143.24,104.93 143.44,104.73 143.44,92.46 136.74,85.75 136.74,85.39 136.74,84.96 129.89,78.11 114.47,78.11 113.69,77.33 112.06,77.33 110.78,76.05 110.78,74.84 LPC1.7
LAD2_FWH2: length 253.4
  TOP w0.089: CPU1.W62 80.1,179.16 80.1,179.46 79.93,179.67 79.93,179.98 80.04,180.08 80.04,181.03 79.9,181.17 79.9,181.36
  TOP w0.102: U14.128 117,66.93 117,68.07 116.75,68.33 116.75,69.19 116.84,69.28 116.84,70.16 116.47,70.53 116.47,76.05 115.98,76.54 113.29,76.54 112.66,75.91 112.66,74.72 LPC1.9 ; v3(79.29,183.24) 79.9,182.63 79.9,181.36 ; v1(141.57,107.85) 141.47,107.95 v4(140.62,107.95) 140.34,107.66 137.22,107.66 135.42,109.47 U7.18
  L3 w0.127: v3(79.29,183.24) 79.7,183.65 79.7,184.12 79.39,184.43 79.1,184.43 78.54,184.98 78.54,191.24 88.18,200.88 99.14,200.88 99.16,200.89 110,200.89 110.38,200.51 133.83,200.51 143.25,191.08 143.25,172.57 142.57,171.89 142.57,149.64 141.93,148.99 141.93,131.03 142.67,130.29 142.67,128.84 140.79,126.97 140.79,118.23 142.04,116.98 142.04,110.41 141.55,109.92 141.55,107.88 v1(141.57,107.85) 143.49,105.93 143.49,105.03 143.7,104.83 143.7,92.35 136.99,85.65 136.99,85.28 136.99,84.85 129.99,77.86 114.59,77.86 113.54,76.81 113.18,76.81 112.53,76.16 112.53,75.79 112.53,75.79 112.53,74.59 LPC1.9
LAD3_FWH3: length 252.1
  TOP w0.089: CPU1.W63 80.22,181.19 80.14,181.27 80.14,181.36
  TOP w0.102: 80.14,181.36 80.14,183.1 v3(79.29,183.95) ; v1(142.53,108.99) 142.1,108.56 142.1,107.73 139.65,105.28 136.3,105.28 134.23,107.35 134.06,107.35 133.64,107.77 U7.15 ; LPC1.11 115.34,72 115.34,70.47 v4(114.97,70.1) 114.97,69.98 115.5,69.44 U14.1
  L3 w0.127: v3(79.29,183.95) 79.27,183.95 78.29,184.93 78.29,191.35 88.07,201.13 99.04,201.13 99.05,201.14 110.1,201.14 110.48,200.76 133.94,200.76 143.51,191.2 143.51,172.46 142.83,171.78 142.83,149.53 142.18,148.89 142.18,131.14 142.93,130.39 142.93,110.01 142.74,109.82 142.74,109.21 v1(142.53,108.99) 142.83,108.69 142.83,107.98 144.38,106.43 144.38,105.4 144.58,105.2 144.58,91.99 137.88,85.28 137.88,81.99 134.15,78.26 133.54,78.26 132.27,76.99 131.01,76.99 130.93,76.9 125.36,76.9 124.55,76.09 116.45,76.09 115.99,76.55 113.28,76.55 112.78,76.05 112.78,75.35 113.28,74.85 113.39,74.85 113.63,74.61 LPC1.11
LAN_DISABLE_N: length 150.9
  TOP w0.102: v1(109.38,33.25) 109.76,32.87 109.76,28.73 111.01,27.48 115.93,27.48 117.42,26 v1(117.63,26) ; v1(128.75,53.12) 128.75,52.66 129.05,52.37 U14.63
  L4 w0.127: v1(109.38,33.25) 113.17,33.25 115.22,35.3 115.97,35.3 117.27,36.6 123.36,36.6 127.13,40.37 127.13,43.28 129.34,45.49 129.34,48.96 128.75,49.55 v1(128.75,53.12) ; v1(117.63,26) 116.26,24.63 110.4,24.63 110.23,24.8 94.36,24.8 92.24,26.93 85.06,26.93 84.43,26.93 83.6,27.76 73.03,27.76 71.18,27.76 69.73,29.21 64.06,29.21 61.04,32.23 53.99,32.23 53.99,32.23 51.12,32.23 51.12,32.23 50.44,32.23 46.65,28.44 46.65,28.43 46.2,27.98 46.2,25.54 46.27,25.46 46.27,23.79 44.16,21.68 44.16,14.37 42.81,13.03 v1(42.81,11.03)
  BOTTOM w0.102: v1(42.81,11.03) 42.86,11.08 43.22,11.08 43.53,10.77 R802.1 43.53,10.43 v2(42.35,10.43) 42.12,10.43 41.63,9.94 R804.1 41.63,9.42 R805.2
LAN_DISABLE_N_1: length 9.5
  BOTTOM w0.102: R807.1 43.99,6.52 43.71,6.79 40.89,6.79 v2(40.77,6.91) 40.77,7.37 41.34,7.94 Q80.B 42.1,9.04 R804.2 C544.1
LAN_DISABLE_N_2: length 8.2
  TOP w0.102: Q44.B 46.67,5.07 v4(47.12,4.62) 47.66,5.16 v1(47.66,6.1)
  BOTTOM w0.102: v1(47.66,6.1) 47.19,5.63 R806.2 R807.2 44.99,6.03 Q80.C
LAN_DISABLE_N_3: length 8.6
  TOP w0.102: Q43.C 44.51,9.22 R502.1 45.86,9 45.86,9.77 46.48,10.39 v4(47.32,10.39) 47.65,10.06 R499.2 47.65,7.9 Q44.C
LAN_DISABLE_N_4: length 23.5
  TOP w0.102: v3(32.44,7.95) 32.62,7.77 32.62,6.08 v4(32.38,5.84) 32.38,5.23 33.14,4.47 38.79,4.47 39.83,5.51 39.83,6.23 41.82,8.22 44.61,8.22 R502.2 45.35,7.17 C233.1
  BOTTOM w0.102: v3(32.44,7.95) 31.94,8.46 Q79.G 30.11,8.46 PC194.2
LAN_DISABLE_V3: length 4.2
  TOP w0.102: Q43.B 42.21,7.1 R510.1 42.21,5.38 42.85,4.74 v4(42.92,4.74) 43.31,5.13 C234.1
LAN_LEDACT_R#: length 5.6
  TOP w0.254: UR1.2 83.52,23.29 RJ1.10
  BOTTOM w0.254: v2(81.29,22.15) 81.29,21.05 RJ1.10
LAN_MDI0_C_DN: length 28.5
  TOP w0.089: RJ1.2 v1(80.1,10.27) ; XF1.2 61.08,8.76 61.55,8.3 62.21,8.3 62.97,7.54 63.36,7.54 v1(63.66,7.84)
  L4 w0.102: v1(63.66,7.84) 63.97,7.53 65.44,7.53 66.49,6.48 79.75,6.48 80.78,7.52 80.78,10.14 80.65,10.27 v1(80.1,10.27)
  BOTTOM w0.089: v1(80.1,10.27) v2(80.1,9.45)
LAN_MDI0_C_DP: length 28.5
  TOP w0.089: v1(63.63,6.96) 63.39,7.19 62.83,7.19 62.07,7.96 61.47,7.96 61.01,7.49 XF1.1 ; RJ1.1 v1(81.37,10.27)
  L4 w0.102: v1(63.63,6.96) 63.87,7.2 65.3,7.2 66.35,6.15 79.61,6.15 79.88,6.15 81.11,7.38 81.11,10.01 v1(81.37,10.27)
  BOTTOM w0.089: v1(81.37,10.27) v2(81.37,11.08)
LAN_MDI0_DN: length 17.7
  TOP w0.089: 41.19,12.52 42.92,12.52 43.56,11.88 44.5,11.88 44.62,12 U28.3 45.97,12 46.09,11.88 46.53,11.88 47.12,12.47 48.57,12.47 49.06,11.98 49.06,9.12 49.87,8.3 50.32,8.3 50.78,8.76 XF1.11 ; 41.19,12.52 v4(41.19,12.88) ; 41.19,12.52 40.8,12.52 39.34,13.99 U26.2
LAN_MDI0_DP: length 17.7
  TOP w0.089: 43.77,11.54 43.42,11.54 42.78,12.18 40.66,12.18 39.25,13.59 U26.1 ; 43.77,11.54 v4(43.77,11.16) ; 43.77,11.54 46.67,11.54 47.26,12.12 47.87,12.12 U28.4 48.55,12 48.71,11.84 48.71,8.98 49.73,7.96 50.09,7.96 50.3,7.75 50.3,7.57 50.38,7.49 XF1.12
LAN_MDI1_C_DN: length 29.6
  TOP w0.089: XF1.6 61.08,16.38 61.54,15.92 62.17,15.92 62.74,15.35 63.24,15.35 v1(63.53,15.64) ; RJ1.6 v1(75.02,10.27)
  L4 w0.102: v1(75.02,10.27) 75.02,9.85 75.22,9.65 76.76,9.65 76.89,9.53 76.89,8.23 76.53,7.87 68.11,7.87 64.9,11.08 64.9,14.92 64.48,15.34 63.84,15.34 v1(63.53,15.64)
  BOTTOM w0.089: v1(75.02,10.27) v2(75.02,9.4)
LAN_MDI1_C_DP: length 29.5
  TOP w0.089: v1(63.52,14.72) 63.23,15.01 62.59,15.01 62.03,15.58 61.49,15.58 61.03,15.11 XF1.5 ; RJ1.3 v1(78.83,10.27)
  L4 w0.102: v1(63.52,14.72) 63.8,15.01 64.35,15.01 64.57,14.79 64.57,10.94 67.97,7.54 76.67,7.54 77.22,8.09 77.22,9.53 77.35,9.65 78.21,9.65 v1(78.83,10.27)
  BOTTOM w0.089: v1(78.83,10.27) 78.83,10.61 78.83,10.62 v2(78.83,11.08)
LAN_MDI1_DN: length 14.7
  TOP w0.089: 42.1,13.76 44.45,13.76 44.6,13.91 U28.1 45.92,13.91 46.06,13.76 46.43,13.76 47.18,14.5 48.47,14.5 49.89,15.92 50.29,15.92 50.76,16.38 XF1.7 ; 42.1,13.76 41.52,13.76 40.13,15.15 39.2,15.15 39.17,15.19 U26.5 ; 42.1,13.76 v4(42.1,14.14)
LAN_MDI1_DP: length 14.8
  TOP w0.089: 43.37,13.42 46.57,13.42 47.32,14.16 47.74,14.16 U28.6 48.36,13.91 50.03,15.58 50.32,15.58 50.78,15.11 XF1.8 ; 43.37,13.42 v4(43.37,13.05) ; 43.37,13.42 41.38,13.42 39.99,14.81 39.15,14.81 39.12,14.79 U26.4
LAN_MDI2_C_DN: length 25.2
  TOP w0.089: RJ1.5 v1(76.29,10.27)
  L3 w0.102: v1(76.29,10.27) 76.81,10.27 76.93,10.14 76.93,7.84 76.26,7.16 66.87,7.16 66.02,8.01 66.02,8.85 65.55,9.33 63.93,9.33 v1(63.66,9.6)
  BOTTOM w0.089: XF2.5 61.07,8.76 61.54,8.29 62.01,8.29 63.06,9.34 63.41,9.34 v1(63.66,9.6) ; v1(76.29,10.27) v2(76.29,11.08)
LAN_MDI2_C_DP: length 25.2
  TOP w0.089: RJ1.4 v1(77.56,10.27)
  L3 w0.102: v1(77.56,10.27) 77.26,9.98 77.26,7.7 76.39,6.83 66.73,6.83 65.69,7.87 65.69,8.71 65.41,9 63.96,9 v1(63.67,8.71)
  BOTTOM w0.089: XF2.6 61.01,7.49 61.47,7.95 62.15,7.95 63.14,8.93 63.45,8.93 v1(63.67,8.71) ; v1(77.56,10.27) v2(77.56,9.45)
LAN_MDI2_DN: length 13.9
  BOTTOM w0.089: 49.06,11.01 49.06,11.3 48.48,11.88 48.11,11.88 U37.3 47.87,11.88 47.51,11.88 46.92,12.47 42.78,12.47 42.65,12.6 42.65,12.79 PR238.2 ; 49.06,11.01 v2(49.36,11.01) ; 49.06,11.01 49.06,8.36 49.58,7.84 49.94,7.84 50.22,8.11 50.22,8.33 50.65,8.76 XF2.8
LAN_MDI2_DN_R: length 8.2
  TOP w0.089: v1(43.02,15.71) 42.73,16 42.73,16.38 42.44,16.68 41.12,16.68 40.37,15.93 39.17,15.93 39.11,15.99 U26.7
  BOTTOM w0.089: v2(42.36,16.52) 43.02,15.86 v1(43.02,15.71) 42.76,15.45 42.76,14.34 PR238.1
LAN_MDI2_DP: length 14
  BOTTOM w0.089: XF2.7 49.44,7.49 48.71,8.22 48.71,11.16 48.33,11.54 47.37,11.54 46.78,12.13 45.42,12.13 U37.4 45.17,12.13 42.64,12.13 ; v2(42.4,11.89) 42.64,12.13 ; 42.64,12.13 42.31,12.46 42.31,12.83 PR239.2
LAN_MDI2_DP_R: length 8
  TOP w0.089: v1(42.13,15.74) 42.39,15.99 42.39,16.24 42.3,16.33 41.26,16.33 40.51,15.58 38.7,15.58 U26.6
  BOTTOM w0.089: v2(41.24,15.78) 42.09,15.78 v1(42.13,15.74) 41.98,15.74 41.89,15.65 41.89,15.28 41.98,15.19 42.3,15.19 42.41,15.07 42.41,14.5 PR239.1
LAN_MDI3_C_DN: length 25.9
  TOP w0.089: RJ1.8 v1(72.48,10.27)
  L3 w0.102: v1(72.48,10.27) 72.81,10.27 73.05,10.03 73.05,9.01 72.55,8.52 68.39,8.52 65.61,11.3 65.61,16.51 64.9,17.22 63.76,17.22 63.56,17.42 v1(63.56,17.59)
  BOTTOM w0.089: v1(63.56,17.59) 63.56,17.53 63.33,17.3 62.72,17.3 62.15,16.72 62.15,16.12 61.96,15.93 61.53,15.93 61.07,16.38 XF2.1 ; v1(72.48,10.27) v2(72.48,9.4)
LAN_MDI3_C_DP: length 26
  TOP w0.089: RJ1.7 v1(73.75,10.27)
  L3 w0.102: v1(63.52,16.64) 63.78,16.89 64.77,16.89 65.28,16.38 65.28,11.16 68.26,8.19 72.69,8.19 73.38,8.88 73.38,9.91 73.74,10.27 v1(73.75,10.27)
  BOTTOM w0.089: v1(73.75,10.27) v2(73.75,11.08) ; v1(63.52,16.64) 63.23,16.96 62.87,16.96 62.49,16.58 62.49,15.98 62.1,15.59 61.51,15.59 61.03,15.11 XF2.2
LAN_MDI3_DN: length 11.1
  BOTTOM w0.089: 49.12,15.48 v2(48.87,15.72) ; 49.12,15.48 49.32,15.68 50.08,15.68 50.27,15.88 50.27,16.26 50.4,16.38 XF2.12 ; 49.12,15.48 49.02,15.38 49.02,14.04 48.76,13.78 48.12,13.78 U37.1 47.59,13.91 47.47,13.78 46.96,13.78 46.25,14.49 44.68,14.49 44.34,14.82 44.34,15.09 PR236.2
LAN_MDI3_DN_R: length 10.5
  TOP w0.089: U26.10 37.61,17.5 37.64,17.53 37.64,18.1 38.02,18.48 39.01,18.48 39.3,18.77 41.54,18.77 41.97,18.34 v1(42.02,18.29)
  BOTTOM w0.089: 43.76,18.08 42.22,18.08 v1(42.02,18.29) ; 43.76,18.08 v2(43.76,18.4) ; 43.76,18.08 44.69,18.08 45.02,17.75 45.02,16.7 PR236.1
LAN_MDI3_DP: length 11
  BOTTOM w0.089: PR237.2 44,14.68 44.78,13.91 U37.6 45.54,14.15 46.11,14.15 46.82,13.44 48.9,13.44 49.36,13.89 49.36,14.55 ; v2(49.65,14.55) 49.36,14.55 ; 49.36,14.55 49.36,15.24 49.46,15.34 50.08,15.34 50.31,15.11 XF2.11
LAN_MDI3_DP_R: length 11.1
  TOP w0.089: U26.9 38.01,17.5 37.98,17.53 37.98,17.96 38.16,18.14 39.15,18.14 39.44,18.43 41.39,18.43 41.57,18.25 41.57,18.08 41.99,17.65 v1(41.99,17.4)
  BOTTOM w0.089: v2(41.29,17.94) 41.82,17.4 v1(41.99,17.4) 42.34,17.74 44.55,17.74 44.67,17.61 44.67,17.1 44.58,17.01 44.58,16.76 44.5,16.68 PR237.1
LAN_RSET: length 4.6
  TOP w0.102: v4(40.12,9.88) 39.75,10.25 R498.2 38.91,10.25 37.96,11.2 37.96,11.51 37.61,11.85 U26.31
LAN_XTALI: length 13.9
  TOP w0.102: U26.28 36.41,12.15 36.56,12 36.56,11.15 35.95,10.54 C226.1 34.89,10.45 35.59,9.75 R500.2 36.06,8.8 36.06,6.98 X4.1 36.21,5.08 38.51,5.08 v3(38.64,5.21)
  BOTTOM w0.102: v3(38.64,5.21) 38.01,5.21 37.88,5.33 v2(37.75,5.33)
LAN_XTALO: length 7.8
  TOP w0.102: U26.29 36.81,10.4 C227.1 36.89,9.5 R500.1 37.99,8.39 v3(38.59,8.39) 37.81,7.61 X4.3
  BOTTOM w0.102: v3(38.59,8.39) v2(38.59,7.62)
LANCLK_REQ_U_N: length 12.4
  TOP w0.102: v3(43.16,21.03) 42.65,20.52 41.54,20.52 40.99,19.98 v4(40.44,19.98) 39.72,19.25 38.83,19.25 R481.1 37.84,19.98 36.75,18.89 36.75,17.87 36.81,17.81 U26.12
  BOTTOM w0.102: v3(43.16,21.03) 43.21,20.98 R793.2 44.22,22.05 Q73.D
LDR: length 5
  BOTTOM w0.254: 35.64,31.88 34.88,31.11 U35.1
  BOTTOM w0.508: 35.64,31.88 35.97,31.88 v2(36.53,32.44) 36.53,32.84 37.88,34.19 R767.2
LDR_1: length 3.9
  BOTTOM w0.508: v2(39.4,34.65) 39.4,34.72 R767.1 38.01,37.64 Q68.4
LED_5VSB: length 3.6
  TOP w0.635: v4(167.58,89.45) 167.7,89.57 R286.2 167.86,90.68 LED1.A
LEDC_ISET: length 8.3
  BOTTOM w0.102: R792.1 30.23,28.17 v2(29.37,29.03) 29.56,29.22 U35.12
LFRAMEJ_FW4: length 248
  TOP w0.089: CPU1.V61 79.76,178.95 79.47,179.3 79.47,179.53 79.58,179.67 79.58,180.13 79.68,180.23 79.68,180.6 79.29,180.99 79.29,181.36
  TOP w0.102: U14.3 116.22,64.53 116.44,64.76 116.44,65.51 115.73,66.22 115.73,69.44 116.22,69.93 v4(116.28,69.93) 115.93,70.28 115.93,71.98 115.63,72.28 LPC1.13 ; 79.29,181.36 v3(79.29,181.82) ; v1(143.21,109.63) 142.22,109.63 141.66,109.07 137.52,109.07 136.12,110.47 U7.20
  L3 w0.127: LPC1.13 117.73,75.79 126.22,75.79 126.38,75.63 126.77,75.63 127.01,75.87 128.02,75.87 128.8,76.64 132.3,76.64 133.66,78 134.27,78 138.13,81.86 138.13,85.17 144.84,91.88 144.84,105.3 144.64,105.51 144.64,106.55 143.21,107.98 v1(143.21,109.63) 143.21,130.47 142.44,131.24 142.44,148.78 143.08,149.42 143.08,171.36 143.76,172.04 143.76,192.29 135.04,201.02 110.59,201.02 110.21,201.4 98.94,201.4 98.93,201.38 87.92,201.38 78.02,191.49 78.02,183.08 v3(79.29,181.82)
LINE2-VREFO: length 11.1
  TOP w0.203: RN32.2 166.99,50.36 167.17,50.19 167.17,49.15 v1(167.09,49.07) 166.49,49.67 RN32.1 ; v1(167.01,47.4) 164.13,47.4 163.36,48.17 U16.29
  BOTTOM w0.203: v1(167.01,47.4) 167.57,47.96 167.57,48.84 167.34,49.07 v1(167.09,49.07) 167.06,49.1 167.06,50.23 v2(167.17,50.33)
LINEOUT-JD: length 156.3
  TOP w0.203: R391.1 167.06,51.64 167.62,51.08 167.62,28.78 v1(167.39,28.55) ; LOUT1.Q 81.56,33.76 87.38,27.94 87.38,5.46 90.28,2.57 151.25,2.57 v1(152.51,3.83)
  BOTTOM w0.203: v1(152.51,3.83) 152.2,4.13 v2(152.2,14) 152.2,14.22 158.53,20.55 158.53,21.21 163.86,26.54 165.39,26.54 v1(167.39,28.55)
LINEOUT-L: length 147.6
  TOP w0.203: v1(166.4,28.42) 166.77,28.79 166.77,40.11 v4(166.24,40.65) 165.56,41.33 159.64,41.33 159.06,41.9 159.06,44.35 159.65,44.93 159.65,45 159.74,45.1 U16.19 ; R446.1 86.1,32.18 86.1,31.4 88.55,28.95 88.55,5.95 90.71,3.78 v1(151.49,3.78)
  BOTTOM w0.203: v1(151.49,3.78) 151.49,14.53 157.89,20.93 157.89,21.46 163.61,27.18 165.16,27.18 v1(166.4,28.42)
LINEOUT-R: length 149.1
  TOP w0.203: U16.18 159.35,45.16 158.48,44.29 158.48,41.66 159.39,40.74 165.04,40.74 166.14,39.64 v4(166.14,30.71) 166.14,29.35 165.49,28.7 v1(165.49,28.35) ; R447.1 87.97,28.26 87.97,5.7 90.52,3.15 150.76,3.15 v1(150.86,3.25)
  BOTTOM w0.203: v1(165.49,28.35) 165.02,27.88 163.29,27.88 157.13,21.72 157.13,21.06 150.88,14.81 150.88,3.28 v1(150.86,3.25)
LINEOUT_C-L: length 2.7
  TOP w0.203: v1(86.73,31.6) 86.74,31.6 R446.2 L10.1
  BOTTOM w0.203: v1(86.73,31.6) 86.76,31.62 86.76,32.41 v2(86.76,32.41)
LINEOUT_C-R: length 3
  TOP w0.203: v1(85.52,31.62) 84.73,32.41 R447.2 L11.1
  BOTTOM w0.203: v1(85.52,31.62) 85.47,31.57 85.11,31.57 85.11,31.58 v2(84.71,31.58)
LINEOUT_CON-L: length 18.9
  TOP w0.203: L10.2 85.87,33.5 C184.2 85.87,34.61 84.83,35.65 84.83,36.49 83.97,37.35 Q37.1 81.97,40.06 81.97,41.84 81.15,42.66 LOUT1.4
  BOTTOM w0.203: v2(74.81,41.2) 74.84,41.22 74.84,42.55 LOUT1.4
LINEOUT_CON-R: length 17.8
  TOP w0.203: L11.2 84.7,34.34 C185.2 84.08,35.04 84.08,35.99 Q37.2 82.32,37.75 78.65,37.75 74.83,33.93 LOUT1.1
  BOTTOM w0.203: v2(72.99,32.71) LOUT1.1
LINK_ACTIVITY_N: length 61
  TOP w0.203: 36.01,11.99 U26.27
  TOP w0.254: v1(36.03,11.42) 36.03,11.48 36.01,11.5 36.01,11.99 ; U24.4 80.08,28 v1(80.96,27.13) 81.88,27.13 UR1.1
  L3 w0.254: v1(36.03,11.42) 36.03,11.43 36.74,12.15 37.88,12.15 39.5,13.76 39.5,17.22 41.54,19.26 57.24,19.26 62.53,24.55 78.38,24.55 v1(80.96,27.13)
  BOTTOM w0.254: v2(80.2,27.72) 80.79,27.13 v1(80.96,27.13)
LINK_PWR: length 5.1
  TOP w0.254: R471.2 84.64,22.12 RJ1.9
  BOTTOM w0.254: RJ1.9 83.57,21.05 v2(83.57,22.12)
LPC_CLK0_R: length 8
  TOP w0.089: 81.06,181.36 81.06,181.03 81.53,180.55 81.53,180.23 81.43,180.13 81.43,179.67 81.32,179.53 81.32,179.29 81.61,178.94 CPU1.AB61
  TOP w0.102: R98.1 81.58,185.83 v4(81.58,185.05) 81.58,184.64 81.06,184.12 81.06,181.36
LPC_CLK1: length 223.8
  TOP w0.102: R264.1 139.55,108.15 v1(139.78,108.38) ; v3(81.26,188.72) 81.01,188.98 v4(80.25,188.98) 80.17,188.9 80.17,187.08 R97.2
  L3 w0.127: LPC1.1 104.59,74.66 105.8,74.66 106.65,75.51 106.65,75.92 108.99,78.26 110.96,78.26 112.39,79.69 124.3,79.69 124.4,79.59 129.51,79.59 131.02,81.1 131.38,81.1 135.72,85.44 135.72,85.81 135.72,85.81 135.72,86.18 142.43,92.88 142.43,104.21 139.78,106.86 v1(139.78,108.38) 139.78,112.78 140.57,113.56 140.57,116.97 139.76,117.78 139.76,127.38 141.65,129.27 141.65,129.87 140.91,130.6 140.91,151.59 141.28,151.96 141.28,159.26 140.77,159.76 140.77,166.01 141.28,166.52 141.28,172.03 142.23,172.99 142.23,190.66 133.68,199.21 109.53,199.21 108.87,199.87 104.37,199.87 104.16,199.67 90.5,199.67 81.26,190.43 v3(81.26,188.72)
LPC_CLK1_R: length 7.4
  TOP w0.089: 80.85,181.36 80.85,180.96 80.76,180.87 80.76,180.23 80.86,180.13 80.86,179.67 81.06,179.41 81.06,179.12 CPU1.AA62
  TOP w0.102: 80.85,181.36 80.85,184.2 80.36,184.7 v4(80.36,185.01) R97.1
LPC_CLKRUN#: length 326.6
  TOP w0.089: 79.7,181.36 79.7,180.95 79.86,180.79 79.86,180.17 79.76,180.06 CPU1.V62
  TOP w0.102: 79.7,181.36 79.7,182.12 v3(79.29,182.53) ; R367.2 113.06,61.67 113.92,62.53 U14.8 116.65,62.53 118.78,60.4 v1(118.78,60.22)
  L3 w0.127: v1(118.78,60.22) 119.26,59.74 120.44,59.74 121.01,60.31 122.2,60.31 122.71,59.8 128.19,59.8 128.32,59.67 129.84,59.67 131.76,57.76 133.48,57.76 133.48,57.76 134.38,57.76 135.03,58.42 139.7,58.42 157.18,75.9 157.18,79.41 160.71,82.93 v1(160.94,82.93) 161.53,82.93 162.5,83.91 162.5,94.7 161.48,95.72 161.48,98.17 162.81,99.5 162.81,112.94 161.75,114 161.75,115.06 162.97,116.28 162.97,123.18 165.23,125.44 165.23,155.35 162.83,157.75 162.83,174.79 162.82,174.8 162.82,176.89 162.81,176.91 162.81,177.58 157.02,183.37 v1(157.02,184.25)
  L4 w0.127: v3(79.29,182.53) 79.7,182.93 79.7,185.76 79.05,186.41 79.05,188.23 79.42,188.59 79.99,188.59 92.7,201.31 92.71,201.31 92.75,201.35 141.65,201.35 149.51,193.49 149.51,192.36 157.02,184.85 v1(157.02,184.25)
  BOTTOM w0.102: v1(160.94,82.93) 160.02,82.93 159.42,83.54 159.42,86.12 155.48,90.06 155.48,97.16 153.25,99.38 153.25,110.58 151.36,112.48 146.6,112.48 145.68,111.55 145.68,109.47 145.35,109.14 144.41,109.14 142.93,107.67 142.93,106.68 v2(142.58,106.32) R654.2
LPC_PME_N: length 230
  TOP w0.102: v1(138.04,62.56) 138.4,62.91 R363.1 138.53,63.25 142.26,63.25 146.7,67.4 148.5,69.82 148.56,70.03 150.68,80.47 150.68,118.97 v1(150.55,119.1) ; v1(101.99,203.49) 101.79,203.28 101.79,200.35 96.97,195.53 93.09,195.53 91.19,193.63 91.19,185.84 87.64,182.28 CPU1.AR63
  L3 w0.127: v1(150.55,119.1) 150.55,120.96 153.96,124.36 153.96,127.38 156.19,129.62 156.19,132.46 159.76,136.03 159.76,140.8 160.82,141.86 160.82,150.9 160.04,151.68 160.04,173.63 153.45,180.22 v1(152.07,180.22)
  BOTTOM w0.102: R728.2 v2(137.33,61.99) 137.47,61.99 v1(138.04,62.56) ; v1(152.07,180.22) 152.07,181.62 147.94,185.75 147.94,188.85 138.82,197.97 114.46,197.97 113.75,198.68 109.15,198.68 107.12,200.71 104.76,200.71 v1(101.99,203.49)
LPC_PME_N_R: length 6.8
  TOP w0.102: R363.2 137.06,63.37 136.77,63.67 v4(134,63.67) 132.15,63.67 131.81,63.33 U14.91
LPF: length 4.4
  BOTTOM w0.102: C513.1 34.54,25.25 34.04,25.25 33.08,26.21 v2(33.08,26.21) 33.08,26.59 32.43,27.25 U35.9
LPSS_UART1_RXD: length 83.6
  TOP w0.089: 71.86,170.29 71.85,170.29 71.52,170.29 71.51,170.29
  TOP w0.102: v3(70.34,170.74) 70.78,170.3 71.51,170.3 71.51,170.29 ; v1(32.07,217.71) 33.5,217.71 33.98,218.19 R23.2 v4(35.17,218.41) ; CPU1.C43 72.67,170.1 72.52,170.25 72.35,170.25 72.21,170.39 71.95,170.39 71.86,170.29
  L3 w0.127: v1(32.07,217.71) 32.07,217.11 33.17,216.01 33.17,208.78 32.98,208.59 32.88,208.49 32.88,202.83 32.34,202.3 32.34,188.46 32.35,188.45 32.35,188.05 35.4,184.99 44.1,184.99 46.62,182.47 46.62,182.42 49.96,179.08 49.96,177.27 51.52,175.7 57.4,175.7 57.65,175.95 61.11,175.95 62.53,174.53 65.51,174.53 66.24,173.8 66.82,173.8 66.84,173.79 67.8,173.79 70.34,171.25 v3(70.34,170.74)
LPSS_UART2_CTS#: length 3.2
  TOP w0.102: R151.2 46.88,171.91 v4(46.69,171.91) 46.95,171.65 46.95,171.55 IRMTCN1.4
LPSS_UART2_RTS#: length 3.3
  TOP w0.102: IRMTCN1.3 48.73,171.37 48.29,171.81 v1(48.29,171.94) 48.29,172 R152.2
  BOTTOM w0.102: v1(48.29,171.94) 48.33,171.94 v2(48.75,171.53)
LPSS_UART2_RXD: length 35.4
  TOP w0.102: v1(51.28,176.61) 49.68,175.01 49.68,171.48 49.53,171.34 IRMTCN1.2 ; v1(75.33,169.67) 75.33,169.66 75.33,169.59 75.7,169.22 CPU1.J41
  L3 w0.127: v1(51.28,176.61) 51.93,175.96 57.29,175.96 57.54,176.2 61.22,176.2 62.59,174.83 67.29,174.83 70.5,171.62 71.15,171.62 73.11,169.67 v1(75.33,169.67)
  BOTTOM w0.102: v2(74.46,169.67) v1(75.33,169.67)
LPSS_UART2_TXD: length 3.9
  TOP w0.102: v4(51.65,173.75) 51.59,173.75 50.59,172.76 R153.2 50.33,172.72 IRMTCN1.1
LVDS_BL_ADJ: length 119
  TOP w0.165: R231.1 R230.1 34.65,116.89 34.32,116.56 33.41,116.56 33.38,116.59 32.82,116.59 32.32,116.08 32.32,110.9 v1(35.49,107.72)
  L3 w0.165: v1(44.86,50.39) 44.51,50.04 35.39,50.04 29.93,55.5 29.93,67.21 36.28,73.56 36.28,87.02 36.72,87.46 36.72,92.32 36.69,92.35 36.69,92.37 36.55,92.5 36.55,98.13 36.53,98.15 36.53,101.47 36.55,101.49 36.55,106.22 35.49,107.28 v1(35.49,107.72)
  L4 w0.165: v1(44.86,50.39) 44.89,50.37 44.89,45.66 42.77,43.54 42.77,31.5 39.69,28.42 39.69,27.24 40,26.93 40.01,26.93 v1(40.22,26.72)
  BOTTOM w0.165: v1(40.22,26.72) 40.88,26.72 41.33,26.26 41.33,25.41 v2(40.66,24.73) 40.5,24.57 R782.1 39.66,23.51 R789.2 R790.1
LVDS_DET_A*: length 130.5
  TOP w0.102: U14.59 127.45,50.59 128.4,49.63 129.14,49.63 129.65,49.12 129.65,48.17 127.55,46.07 v1(127.55,46) ; LVDS1.17 v1(43.63,93.5)
  L3 w0.127: v1(127.55,46) 127.55,46.07 128.09,46.61 128.09,47.06 127.54,47.6 120.32,47.6 120.01,47.3 120.01,47.11 119.61,46.71 112.91,46.71 111.79,47.83 99.25,47.83 95.03,52.05 95.03,66.12 85.08,76.07 65.28,76.07 64.94,76.42 63.09,76.42 62.82,76.15 54.22,76.15 54.05,76.31 52.27,76.31 51.85,76.73 51.82,76.73 49.65,78.91 49.15,78.91 44.23,83.83 44.23,92.9 v1(43.63,93.5)
  BOTTOM w0.102: v2(45.37,93.39) 44.99,93 R668.2 43.99,93.5 v1(43.63,93.5)
LVDS_DET_B*: length 177.8
  TOP w0.102: v1(120.04,58.51) 120.04,59.24 120.35,59.55 120.35,62 119.85,62.5 U14.121
  L3 w0.127: v1(108.64,43.99) 106.43,46.2 96.95,46.2 92.74,50.41 92.74,64.44 84.44,72.75 60.72,72.75 60.69,72.77 43.52,72.77 39.88,76.41 39.88,76.78 40.55,77.45 40.55,77.65 40.61,77.71 40.61,79.38 40.57,79.41 40.57,106.58 39.71,107.44 v1(39.71,111.32)
  L4 w0.127: v1(120.04,58.51) 120.04,58.49 120.51,58.02 120.51,57.8 122.71,55.6 122.71,53.55 122.27,53.1 122.27,45.47 121.09,44.29 121.09,42.48 119.75,41.14 118.38,41.14 116.46,43.06 109.58,43.06 v1(108.64,43.99)
  BOTTOM w0.102: v2(41.57,119.46) R635.2 41.9,118.9 Q55.D 41.18,118.02 39.88,116.72 39.88,114.99 39.05,114.15 39.05,113.61 39.66,113 39.66,111.37 v1(39.71,111.32)
LVDS_DET_B_C*: length 8.4
  TOP w0.127: v1(43.75,112.37) v4(43.07,111.69) 42.45,111.07 42.45,109.5 LVDS1.1
  BOTTOM w0.127: v1(43.75,112.37) 43.7,112.42 C354.1 44.05,113.64 44.33,113.92 44.33,115.02 43.24,116.12 Q55.G
LVDS_PU_5: length 4.9
  TOP w0.102: v1(44.52,105.91) 44.11,105.5 LVDS1.5
  BOTTOM w0.102: R655.2 43.52,105.52 43.58,105.59 43.87,105.59 44.19,105.91 v1(44.52,105.91) 44.99,106.38 44.99,106.4 v2(45.04,106.45)
LVDS_PU_5_1: length 15.6
  BOTTOM w0.102: 42.5,111.38 42.88,111.76 44.42,111.76 44.71,112.05 44.71,116.43 45.16,116.88 45.83,116.88 46.05,116.65 46.05,113.86 v2(45.78,113.59) 45.83,113.54 45.83,109.74 R651.1
LVDS_PU_6: length 6.9
  TOP w0.102: v1(43.62,105) 43.12,104.5 LVDS1.6
  BOTTOM w0.102: R651.2 45.91,108.56 45.8,108.46 45.8,105.87 v2(44.91,104.98) 44.89,105 v1(43.62,105)
LVDS_PU_6_2: length 8.2
  BOTTOM w0.102: Q56.D 44.95,115.45 44.95,111.21 44.81,111.07 v2(44.81,111.02) 44.84,111 R649.1 44.01,109.64 Q59.G
LVDS_PU_24: length 21.1
  TOP w0.102: v1(44.59,104.13) 44.44,103.98 44.44,103.66 44.13,103.34 44.13,86.82 43.81,86.5 LVDS1.24
  BOTTOM w0.102: R656.2 v2(43.76,104.14) 44.57,104.14 v1(44.59,104.13)
LX:
  vias: v2(34.93,43.83) v4(32.44,44.45) v5(31.91,43.43) v5(32.93,43.43) v5(33.94,43.43)
M1_SMB_CLK: length 6.4
  TOP w0.102: NGFF1.60 120.14,219.5 121.11,220.47 R13.2 122.12,220.95 123.31,220.95 123.5,220.77 v4(123.98,220.29)
M1_SMB_DATA: length 3.5
  TOP w0.102: NGFF1.58 120.47,219 v4(120.62,218.85) 120.75,218.85 121.35,219.46 R19.2
M_A_VREFCA_CPU: length 28.6
  TOP w0.254: v3(87.15,165.94) 87.15,165.94 CPU1.AR35
  L4 w0.254: v1(102.42,151.59) 102.12,151.59 98.1,155.6 94.93,155.6 92.84,157.68 92.84,158.7 91.14,160.4 91.14,161.67 90.84,161.98 90.84,161.99 89.22,163.6 89.09,163.6 87.15,165.54 v3(87.15,165.94)
  BOTTOM w0.254: v1(102.42,151.59) 102.42,151.47 v2(104.76,149.14) 106.01,147.88 R612.1
M_A_VREFDQ_CPU: length 27.8
  TOP w0.254: CPU1.AT34 v3(88.56,165.92)
  L4 w0.254: v3(88.56,165.92) 89.23,165.25 90.03,165.25 94.01,161.26 94.01,159 96.05,156.97 98.69,156.97 105.47,150.19 v1(105.65,150.19)
  BOTTOM w0.254: v2(105.98,150.98) 105.65,150.65 v1(105.65,150.19) 106.01,149.82 R611.1
M_CAS_A_N: length 59.3
  TOP w0.089: 95.88,171.95 CPU1.BH47
  TOP w0.14: 95.88,171.95 95.9,171.93 96.73,171.93 96.76,171.91 97.14,171.91 97.16,171.93 98.67,171.93 98.68,171.93 99.97,171.93 100.4,171.5 100.44,171.5 100.46,171.48 101.61,171.48 v3(102.09,171.96) ; DIMM1.115 132.75,153.95 132.75,153.95 133.43,153.95 v3(133.59,153.8)
  L3 w0.191: v3(102.09,171.96) 102.45,172.32 105.23,172.32 125.86,151.69 133.24,151.69 133.29,151.74 134.49,151.74 134.54,151.69 136.19,151.69 136.39,151.89 136.39,152.29 136.19,152.49 134.03,152.49 133.58,152.94 133.58,153.79 v3(133.59,153.8)
  BOTTOM w0.14: v3(102.09,171.96) 102.09,172.19 v2(102.46,172.57)
M_DATA_A0: length 61.4
  TOP w0.089: CPU1.AW63 89.49,180.49 90.02,181.02 90.02,181.36
  TOP w0.102: v3(137.12,190.27) 137.73,189.65 DIMM1.4 ; 90.02,181.36 90.02,184.03 v3(91.01,185.02)
  L4 w0.127: v3(137.12,190.27) 137.12,190.35 136.58,190.89 135,190.89 132.76,193.13 111.36,193.13 111.24,193.26 111.24,193.5 111.11,193.62 110.83,193.62 110.7,193.5 110.7,193.26 110.57,193.13 105.36,193.13 104.93,192.7 100.3,192.7 97.48,189.88 96.2,188.59 93.15,188.59 91.01,186.45 v3(91.01,185.02)
  BOTTOM w0.102: v2(90.43,185.52) 90.51,185.52 v3(91.01,185.02)
M_DATA_A1: length 60.9
  TOP w0.089: 90.5,181.36 90.5,180.87 89.95,180.32 CPU1.AY62
  TOP w0.102: 90.5,181.36 90.5,183.38 91.97,184.84 92.05,184.84 92.98,185.77 92.98,186.01 93.08,186.11 v3(93.08,187.02) ; v3(134.41,189.3) 133.99,189.72 132.6,189.72 132.23,189.35 DIMM1.5
  L4 w0.127: v3(134.41,189.3) 134.41,189.61 134.27,189.76 132.96,189.76 130.65,192.06 113.31,192.06 113.19,191.94 113.19,191.89 113.06,191.76 112.78,191.76 112.65,191.89 112.65,191.94 112.53,192.06 109.26,192.06 109.13,191.94 109.13,191.6 109,191.48 108.72,191.48 108.6,191.6 108.6,191.94 108.47,192.06 108.19,192.06 108.06,191.94 108.06,191.6 107.93,191.48 107.66,191.48 107.53,191.6 107.53,191.94 107.4,192.06 107.12,192.06 106.99,191.94 106.99,191.6 106.87,191.48 106.59,191.48 106.46,191.6 106.46,191.94 106.33,192.06 105.8,192.06 105.37,191.63 100.74,191.63 97.15,188.04 94.1,188.04 v3(93.08,187.02)
  BOTTOM w0.102: v2(134.3,188.59) 134.41,189.05 v3(134.41,189.3)
M_DATA_A2: length 59.2
  TOP w0.089: CPU1.BD62 91.66,179.51 91.62,179.55 91.62,179.97 91.89,180.24 91.89,181.36
  TOP w0.102: v3(94.59,183.85) 93.55,183.85 91.89,182.19 91.89,181.36 ; v3(134.24,185.77) 133.66,186.35 DIMM1.15
  L4 w0.127: v3(134.24,185.77) 133.46,186.56 131.71,186.56 130.51,187.75 109.43,187.75 109.3,187.63 109.3,187.3 109.17,187.18 108.89,187.18 108.77,187.3 108.77,187.63 108.64,187.75 108.36,187.75 108.23,187.63 108.23,187.3 108.11,187.18 107.83,187.18 107.7,187.3 107.7,187.63 107.57,187.75 107.29,187.75 107.17,187.63 107.17,187.3 107.04,187.18 106.76,187.18 106.63,187.3 106.63,187.63 106.51,187.75 106.23,187.75 106.1,187.63 106.1,187.3 105.97,187.18 105.69,187.18 105.57,187.3 105.57,187.63 105.44,187.75 105.16,187.75 105.03,187.63 105.03,187.3 104.91,187.18 104.63,187.18 104.5,187.3 104.5,187.63 104.37,187.75 104.09,187.75 103.97,187.63 103.97,187.3 103.84,187.18 103.56,187.18 103.43,187.3 103.43,187.63 103.31,187.75 103.03,187.75 102.9,187.63 102.9,187.3 102.77,187.18 102.49,187.18 102.37,187.3 102.37,187.63 102.24,187.75 101.99,187.75 100.34,186.11 95.97,186.11 94.59,184.73 v3(94.59,183.85)
  BOTTOM w0.102: v3(134.24,185.77) 134.24,185.91 v2(133.92,186.41)
M_DATA_A3: length 59.5
  TOP w0.089: CPU1.BG62 92.95,179.41 92.95,180.14
  TOP w0.102: v3(132.76,185.76) 132.75,185.75 DIMM1.17 ; v3(95.55,184.77) 95.55,184.13 93.82,182.4 93.82,181.01 92.95,180.14
  L4 w0.127: v3(95.55,184.77) 95.55,185.23 96.05,185.72 100.77,185.72 101.59,186.55 101.88,186.55 101.89,186.56 109.82,186.56 109.95,186.69 109.95,187.13 110.04,187.22 110.39,187.22 110.48,187.13 110.48,186.69 110.61,186.56 110.89,186.56 111.02,186.69 111.02,187.07 111.14,187.2 111.42,187.2 111.55,187.07 111.55,186.69 111.68,186.56 111.96,186.56 112.08,186.69 112.08,187.07 112.21,187.2 112.49,187.2 112.62,187.07 112.62,186.69 112.75,186.56 113.02,186.56 113.15,186.69 113.15,187.07 113.28,187.2 113.56,187.2 113.68,187.07 113.68,186.69 113.81,186.56 114.09,186.56 114.22,186.69 114.22,187.07 114.35,187.2 114.62,187.2 114.75,187.07 114.75,186.69 114.88,186.56 115.16,186.56 115.29,186.69 115.29,187.07 115.41,187.2 115.69,187.2 115.82,187.07 115.82,186.69 115.95,186.56 116.22,186.56 116.35,186.69 116.35,187.07 116.48,187.2 116.76,187.2 116.89,187.07 116.89,186.69 117.01,186.56 117.29,186.56 117.42,186.69 117.42,187.07 117.55,187.2 117.83,187.2 117.95,187.07 117.95,186.69 118.08,186.56 118.36,186.56 118.49,186.69 118.49,187.07 118.61,187.2 118.89,187.2 119.02,187.07 119.02,186.69 119.15,186.56 119.43,186.56 119.55,186.69 119.55,187.07 119.68,187.2 119.96,187.2 120.09,187.07 120.09,186.69 120.21,186.56 120.49,186.56 120.62,186.69 120.62,187.07 120.75,187.2 121.03,187.2 121.15,187.07 121.15,186.69 121.28,186.56 121.56,186.56 121.69,186.69 121.69,187.11 121.8,187.22 130.23,187.22 131.69,185.76 v3(132.76,185.76)
  BOTTOM w0.102: v3(95.55,184.77) v2(96.68,184.77)
M_DATA_A4: length 60.4
  TOP w0.089: 90.76,181.36 90.76,180.87 90.13,180.24 90.13,179.67 90.25,179.51 90.25,179.31 90.12,179.15 90.12,178.83 CPU1.AY61
  TOP w0.102: 90.76,181.36 90.76,183.08 v3(92.13,184.45) ; DIMM1.7 132.24,188.75 v3(132.78,189.29)
  L4 w0.127: v3(132.78,189.29) 132.67,189.29 130.43,191.53 130.18,191.53 130.05,191.4 130.05,191.21 129.92,191.08 129.64,191.08 129.52,191.21 129.52,191.4 129.39,191.53 129.11,191.53 128.98,191.4 128.98,191.21 128.86,191.08 128.58,191.08 128.45,191.21 128.45,191.4 128.32,191.53 128.04,191.53 127.92,191.4 127.92,191.21 127.79,191.08 127.51,191.08 127.38,191.21 127.38,191.4 127.26,191.53 126.98,191.53 126.85,191.4 126.85,191.21 126.72,191.08 126.44,191.08 126.32,191.21 126.32,191.4 126.19,191.53 125.91,191.53 125.78,191.4 125.78,191.21 125.66,191.08 125.38,191.08 125.25,191.21 125.25,191.4 125.12,191.53 124.84,191.53 124.72,191.4 124.72,191.21 124.59,191.08 124.31,191.08 124.18,191.21 124.18,191.4 124.06,191.53 123.78,191.53 123.65,191.4 123.65,191.21 123.52,191.08 123.24,191.08 123.12,191.21 123.12,191.4 122.99,191.53 117.47,191.53 117.34,191.4 117.34,191.07 117.21,190.94 116.93,190.94 116.81,191.07 116.81,191.4 116.68,191.53 116.4,191.53 116.27,191.4 116.27,191.07 116.15,190.94 115.87,190.94 115.74,191.07 115.74,191.4 115.61,191.53 115.08,191.53 114.49,190.94 100.81,190.94 97.65,187.78 94.43,187.78 92.13,185.48 v3(92.13,184.45)
  BOTTOM w0.102: v3(92.13,184.45) 92.13,184.28 v2(91.7,183.86)
M_DATA_A5: length 61.4
  TOP w0.089: 90.26,181.36 90.26,180.98 89.78,180.5 89.78,179.67 89.65,179.51 89.49,179.35 CPU1.AW62
  TOP w0.102: v3(92.07,186) 92.07,185.37 90.26,183.56 90.26,181.36 ; v3(135.42,190.33) 135.42,190.26 135.88,189.98 135.97,189.89 136.18,189.79 137.01,189.55 138.29,189.05 DIMM1.6
  L4 w0.127: v3(135.42,190.33) 135.24,190.16 133.42,190.16 131.92,191.65 131.92,191.83 132.13,192.04 132.13,192.22 131.93,192.42 131.75,192.42 131.55,192.21 131.37,192.21 130.98,192.6 105.58,192.6 105.15,192.16 100.52,192.16 97.76,189.41 96.67,188.32 93.79,188.32 92.07,186.59 v3(92.07,186)
  BOTTOM w0.102: v3(92.07,186) 91.69,186.39 v2(91.52,186.51)
M_DATA_A6: length 58.8
  TOP w0.089: CPU1.BD63 91.94,179.87 92.14,180.07 92.14,181.36
  TOP w0.102: v3(93.63,182.93) 93.05,182.93 92.14,182.02 92.14,181.36 ; DIMM1.16 138.2,186.05 137.89,186.36 136.59,186.36 v3(136.09,185.86)
  L4 w0.127: v3(93.63,182.93) 93.63,184.3 95.79,186.46 99.88,186.46 101.71,188.29 111.76,188.29 111.89,188.41 111.89,188.49 112.01,188.62 112.29,188.62 112.42,188.49 112.42,188.41 112.55,188.29 112.83,188.29 112.95,188.41 112.95,188.49 113.08,188.62 113.36,188.62 113.49,188.49 113.49,188.41 113.61,188.29 113.89,188.29 114.02,188.41 114.02,188.49 114.15,188.62 114.43,188.62 114.55,188.49 114.55,188.41 114.68,188.29 114.96,188.29 115.09,188.41 115.09,188.49 115.21,188.62 115.49,188.62 115.62,188.49 115.62,188.41 115.75,188.29 116.03,188.29 116.15,188.41 116.15,188.49 116.28,188.62 116.56,188.62 116.69,188.49 116.69,188.41 116.81,188.29 117.09,188.29 117.22,188.41 117.22,188.49 117.35,188.62 117.63,188.62 117.75,188.49 117.75,188.41 117.88,188.29 118.16,188.29 118.29,188.41 118.29,188.49 118.41,188.62 118.69,188.62 118.82,188.49 118.82,188.41 118.95,188.29 119.23,188.29 119.35,188.41 119.35,188.49 119.48,188.62 119.76,188.62 119.89,188.49 119.89,188.41 120.01,188.29 120.29,188.29 120.42,188.41 120.42,188.49 120.55,188.62 120.83,188.62 120.95,188.49 120.95,188.41 121.08,188.29 121.36,188.29 121.49,188.41 121.49,188.49 121.61,188.62 121.89,188.62 122.02,188.49 122.02,188.41 122.15,188.29 130.77,188.29 131.97,187.09 133.68,187.09 134.27,186.5 135.36,186.5 136,185.86 v3(136.09,185.86)
  BOTTOM w0.102: v2(92.94,183.48) 92.98,183.48 93.54,182.93 v3(93.63,182.93)
M_DATA_A7: length 58.3
  TOP w0.089: 92.37,180.32 92.37,180.05 92.29,179.97 92.29,179.48 CPU1.BE62
  TOP w0.102: v3(137.71,185.88) 137.76,185.88 138.19,185.45 DIMM1.18 ; 92.37,180.32 92.9,180.86 v3(92.9,181.8)
  L4 w0.127: v3(137.71,185.88) 137.06,186.53 135.81,186.53 135.58,186.75 134.65,186.75 133.62,187.78 132.37,187.78 131,189.15 108.49,189.15 108.36,189.02 108.36,188.95 108.23,188.82 107.96,188.82 107.83,188.95 107.83,189.02 107.7,189.15 107.17,189.15 107.04,189.02 107.04,188.95 106.91,188.82 106.63,188.82 106.51,188.95 106.51,189.02 106.38,189.15 106.1,189.15 105.97,189.02 105.97,188.95 105.85,188.82 105.57,188.82 105.44,188.95 105.44,189.02 105.31,189.15 105.03,189.15 104.91,189.02 104.91,188.95 104.78,188.82 104.5,188.82 104.37,188.95 104.37,189.02 104.25,189.15 103.97,189.15 103.84,189.02 103.84,188.95 103.71,188.82 103.43,188.82 103.31,188.95 103.31,189.02 103.18,189.15 102.9,189.15 102.77,189.02 102.77,188.95 102.65,188.82 102.37,188.82 102.24,188.95 102.24,189.02 102.11,189.15 101.58,189.15 99.27,186.84 95.59,186.84 92.81,184.06 92.81,181.89 v3(92.9,181.8)
  BOTTOM w0.102: v2(93.41,181.29) 92.9,181.8 v3(92.9,181.8)
M_DATA_A8: length 59.3
  TOP w0.089: CPU1.AU63 88.56,179.96 88.82,180.21 88.82,180.72 v3(88.43,181.11)
  TOP w0.102: DIMM1.22 136.71,184.25 136.15,183.7 136.15,183.53 v3(136.12,183.5)
  L4 w0.127: v3(136.12,183.5) 136.44,183.82 136.44,184.42 136.12,184.74 135.84,184.74 135.71,184.61 135.71,184.33 135.58,184.2 135.21,184.2 135.08,184.33 135.08,184.61 134.96,184.74 131.13,184.74 130.63,185.25 129.65,185.25 129.4,185.5 129.12,185.5 128.87,185.25 128.33,185.25 128.08,185.5 102.45,185.5 101.76,184.81 96.95,184.81 93.25,181.11 90.64,181.11 90.51,180.98 90.51,180.77 90.38,180.64 90.1,180.64 89.98,180.77 89.98,180.98 89.85,181.11 89.42,181.11 89.09,180.77 88.63,180.77 88.43,180.97 v3(88.43,181.11)
  BOTTOM w0.102: v3(136.12,183.5) 136.08,183.67 v2(135.95,184.2)
M_DATA_A9: length 61.9
  TOP w0.102: CPU1.AT55 88.26,175.87 v3(88.62,175.51) ; v3(133.56,183.46) 133.56,183.65 133.18,184.02 132.59,184.02 132.52,183.95 DIMM1.23
  L4 w0.089: 89.11,179.64 88.23,178.76 88.23,178.52 88.22,178.51 88.22,178.19 88.23,178.18 88.23,175.9 v3(88.62,175.51)
  L4 w0.127: 89.11,179.64 91.4,179.64 91.94,180.18 93.2,180.18 96.94,183.92 97.2,183.92 97.32,183.79 97.32,183.54 97.45,183.41 97.73,183.41 97.86,183.54 97.86,183.79 97.98,183.92 98.26,183.92 98.39,183.79 98.39,183.54 98.52,183.41 98.8,183.41 98.92,183.54 98.92,183.79 99.05,183.92 99.33,183.92 99.46,183.79 99.46,183.54 99.58,183.41 99.86,183.41 99.99,183.54 99.99,183.79 100.12,183.92 100.4,183.92 100.52,183.79 100.52,183.54 100.65,183.41 100.93,183.41 101.06,183.54 101.06,183.79 101.18,183.92 102.4,183.92 102.62,184.15 102.88,184.15 103,184.28 103,184.3 103.13,184.43 103.41,184.43 103.54,184.3 103.54,184.28 103.67,184.15 103.94,184.15 104.07,184.28 104.07,184.3 104.2,184.43 104.48,184.43 104.6,184.3 104.6,184.28 104.73,184.15 105.01,184.15 105.14,184.28 105.14,184.3 105.27,184.43 105.54,184.43 105.67,184.3 105.67,184.28 105.8,184.15 106.08,184.15 106.21,184.28 106.21,184.3 106.33,184.43 106.61,184.43 106.74,184.3 106.74,184.28 106.87,184.15 107.14,184.15 107.27,184.28 107.27,184.3 107.4,184.43 107.68,184.43 107.81,184.3 107.81,184.28 107.93,184.15 108.21,184.15 108.34,184.28 108.34,184.3 108.47,184.43 108.75,184.43 108.87,184.3 108.87,184.28 109,184.15 109.28,184.15 109.41,184.28 109.41,184.3 109.53,184.43 109.81,184.43 109.94,184.3 109.94,184.28 110.07,184.15 110.35,184.15 110.47,184.28 110.47,184.3 110.6,184.43 110.88,184.43 111.01,184.3 111.01,184.28 111.13,184.15 111.41,184.15 111.54,184.28 111.54,184.3 111.67,184.43 111.95,184.43 112.07,184.3 112.07,184.28 112.2,184.15 112.48,184.15 112.61,184.28 112.61,184.3 112.73,184.43 113.01,184.43 113.14,184.3 113.14,184.28 113.27,184.15 113.55,184.15 113.67,184.28 113.67,184.3 113.8,184.43 114.08,184.43 114.21,184.3 114.21,184.28 114.33,184.15 129.54,184.15 129.8,183.89 131.25,183.89 131.38,183.76 131.38,183.56 131.51,183.43 131.79,183.43 131.91,183.56 131.91,183.76 132.04,183.89 133.38,183.89 133.56,183.71 v3(133.56,183.46)
  BOTTOM w0.102: v3(133.56,183.46) 133.54,183.67 v2(133.26,184.12)
M_DATA_A10: length 59.6
  TOP w0.102: v3(134.6,179.37) 133.03,180.95 DIMM1.33 ; v3(89.57,177.63) 89.44,177.63 CPU1.AV58
  L4 w0.089: 93.36,176.9 92.95,176.49 92.33,176.49 92.24,176.4 91.65,176.4 91.58,176.48 91.28,176.48 90.52,177.24 89.96,177.24 v3(89.57,177.63)
  L4 w0.127: 93.36,176.9 94.06,177.6 94.06,178.48 96.53,180.95 110.77,180.95 112.03,179.69 118.74,179.69 118.87,179.82 118.87,180.27 119,180.4 119.28,180.4 119.4,180.27 119.4,179.82 119.53,179.69 119.81,179.69 119.94,179.82 119.94,180.27 120.06,180.4 120.34,180.4 120.47,180.27 120.47,179.82 120.6,179.69 120.88,179.69 121,179.82 121,180.27 121.13,180.4 121.41,180.4 121.54,180.27 121.54,179.82 121.66,179.69 121.94,179.69 122.07,179.82 122.07,180.27 122.2,180.4 122.48,180.4 122.6,180.27 122.6,179.82 122.73,179.69 123.01,179.69 123.14,179.82 123.14,180.27 123.26,180.4 132.39,180.4 132.47,180.32 134.05,180.32 134.6,179.77 v3(134.6,179.37)
  BOTTOM w0.102: v3(134.6,179.37) 134.6,179.38 134.6,179.98 v2(134.7,180.09)
M_DATA_A11: length 60
  TOP w0.102: CPU1.AY59 90.17,178 v3(90.52,178.35) ; DIMM1.34 138.4,180.65 138.07,180.99 137.36,180.99 137.17,181.18 136.49,181.18 v3(136.14,180.82)
  L4 w0.089: 93.76,178.62 93.45,178.3 92.9,178.3 92.51,178.7 90.87,178.7 v3(90.52,178.35)
  L4 w0.127: 93.76,178.62 96.63,181.48 110.99,181.48 111.53,180.95 112.21,180.95 112.34,180.82 112.34,180.39 112.47,180.26 112.75,180.26 112.88,180.39 112.88,180.82 113,180.95 113.28,180.95 113.41,180.82 113.41,180.39 113.54,180.26 113.81,180.26 113.94,180.39 113.94,180.82 114.07,180.95 114.35,180.95 114.48,180.82 114.48,180.39 114.6,180.26 114.88,180.26 115.01,180.39 115.01,180.82 115.14,180.95 115.42,180.95 115.54,180.82 115.54,180.39 115.67,180.26 115.95,180.26 116.08,180.39 116.08,180.82 116.2,180.95 116.48,180.95 116.61,180.82 116.61,180.39 116.74,180.26 117.02,180.26 117.14,180.39 117.14,180.82 117.27,180.95 117.55,180.95 117.68,180.82 117.68,180.55 117.8,180.42 118.08,180.42 118.21,180.55 118.21,180.82 118.34,180.95 130.8,180.95 131,180.75 134.2,180.75 135.12,179.82 135.92,179.82 136.14,180.03 v3(136.14,180.82)
  BOTTOM w0.102: v2(136.33,181.51) 136.33,181.02 v3(136.14,180.82)
M_DATA_A12: length 60.9
  TOP w0.102: v3(88.43,181.76) 89.16,181.03 89.16,180.11 88.86,179.81 88.86,179.68 88.84,179.66 88.84,179.65 88.56,179.37 CPU1.AU62 ; v3(137.69,183.53) 137.8,183.65 DIMM1.24
  L4 w0.127: v3(137.69,183.53) 136.06,185.16 131.32,185.16 130.45,186.03 102.12,186.03 101.37,185.29 97.04,185.29 93.14,181.39 91.03,181.39 90.9,181.52 90.9,182.09 90.77,182.22 90.49,182.22 90.37,182.09 90.37,181.52 90.24,181.39 89.96,181.39 89.83,181.52 89.83,182.09 89.7,182.22 89.43,182.22 89.3,182.09 89.3,181.52 89.17,181.39 88.8,181.39 v3(88.43,181.76)
  BOTTOM w0.102: v2(137.4,184.2) 137.5,183.74 v3(137.69,183.53)
M_DATA_A13: length 62.8
  TOP w0.102: DIMM1.21 134.08,184.55 135.07,183.56 v3(135.07,183.47) ; v3(88.62,174.8) 88.26,175.15 CPU1.AT54
  L4 w0.089: v3(88.62,174.8) 88.05,175.36 88.05,178.1 88.04,178.11 88.04,178.58 88.05,178.59 88.05,179.11 88.85,179.91
  L4 w0.127: v3(135.07,183.47) 135.07,183.82 134.47,184.42 130.26,184.42 130,184.68 120.37,184.68 120.24,184.81 120.24,184.84 120.12,184.96 119.84,184.96 119.71,184.84 119.71,184.81 119.58,184.68 119.3,184.68 119.18,184.81 119.18,184.84 119.05,184.96 118.77,184.96 118.64,184.84 118.64,184.81 118.52,184.68 118.24,184.68 118.11,184.81 118.11,184.84 117.98,184.96 117.7,184.96 117.58,184.84 117.58,184.81 117.45,184.68 117.17,184.68 117.04,184.81 117.04,184.84 116.92,184.96 116.64,184.96 116.51,184.84 116.51,184.81 116.38,184.68 116.1,184.68 115.98,184.81 115.98,184.84 115.85,184.96 115.57,184.96 115.44,184.84 115.44,184.81 115.32,184.68 115.04,184.68 114.91,184.81 114.91,184.84 114.78,184.96 102.68,184.96 102.03,184.31 96.86,184.31 93.08,180.53 91.82,180.53 91.2,179.91 89.92,179.91 89.8,180.03 89.8,180.39 89.67,180.52 89.39,180.52 89.26,180.39 89.26,180.03 89.14,179.91 88.85,179.91
  BOTTOM w0.102: v2(134.73,184.1) 135.07,183.71 v3(135.07,183.47)
M_DATA_A14: length 58.6
  TOP w0.102: v3(89.57,176.92) 89.44,176.92 CPU1.AV57 ; v3(133.87,179.37) 133.87,179.43 132.94,180.35 DIMM1.35
  L4 w0.089: 93.51,176.72 93.1,176.32 92.4,176.32 92.31,176.23 91.54,176.23 91.47,176.3 91.21,176.3 90.59,176.92 v3(89.57,176.92)
  L4 w0.127: v3(133.87,179.37) 133.87,179.45 133.44,179.88 131.97,179.88 131.85,179.75 131.85,178.9 131.72,178.78 131.2,178.78 131.07,178.9 131.07,179.74 130.95,179.87 130.67,179.87 130.54,179.74 130.54,178.89 130.41,178.76 130.13,178.76 130.01,178.89 130.01,179.74 129.88,179.87 129.6,179.87 129.47,179.74 129.47,179.02 129.35,178.9 129.07,178.9 128.94,179.02 128.94,179.74 128.81,179.87 128.53,179.87 128.41,179.74 128.41,179.09 128.28,178.96 128,178.96 127.85,179.11 111.65,179.11 111.01,179.75 111.01,179.88 110.47,180.42 96.3,180.42 94.45,178.56 94.45,177.67 93.51,176.72
  BOTTOM w0.102: v2(133.48,180.06) 133.87,179.68 v3(133.87,179.37)
M_DATA_A15: length 60.1
  TOP w0.102: DIMM1.36 138.68,180.05 137.97,180.76 137.23,180.76 137.22,180.75 v3(136.99,180.75) ; CPU1.AV59 89.26,178 v3(89.57,178.31)
  L4 w0.089: v3(89.57,178.31) 90.18,178.92 92.87,178.92 93.03,179.07 93.51,179.07
  L4 w0.127: v3(136.99,180.75) 136.99,181.08 136.76,181.31 136.17,181.31 136.05,181.43 136.05,181.69 135.92,181.81 135.64,181.81 135.51,181.69 135.51,181.43 135.39,181.31 134.9,181.31 134.72,181.13 131.36,181.13 130.9,181.59 122.56,181.59 122.43,181.72 122.43,181.89 122.31,182.02 122.03,182.02 121.9,181.89 121.9,181.72 121.77,181.59 121.49,181.59 121.37,181.72 121.37,181.89 121.24,182.02 120.96,182.02 120.83,181.89 120.83,181.72 120.71,181.59 120.43,181.59 120.3,181.72 120.3,181.89 120.17,182.02 119.89,182.02 119.77,181.89 119.77,181.72 119.64,181.59 119.36,181.59 119.23,181.72 119.23,181.89 119.11,182.02 118.83,182.02 118.7,181.89 118.7,181.72 118.57,181.59 118.29,181.59 118.17,181.72 118.17,181.89 118.04,182.02 117.76,182.02 117.63,181.89 117.63,181.72 117.51,181.59 117.23,181.59 117.1,181.72 117.1,181.89 116.97,182.02 116.69,182.02 116.57,181.89 116.57,181.72 116.44,181.59 116.16,181.59 116.03,181.72 116.03,181.89 115.91,182.02 115.63,182.02 115.5,181.89 115.5,181.72 115.37,181.59 115.09,181.59 114.97,181.72 114.97,181.89 114.84,182.02 114.56,182.02 114.43,181.89 114.43,181.72 114.31,181.59 114.03,181.59 113.9,181.72 113.9,181.89 113.77,182.02 113.49,182.02 113.37,181.89 113.37,181.72 113.24,181.59 112.96,181.59 112.83,181.72 112.83,181.89 112.7,182.02 112.43,182.02 112.3,181.89 112.3,181.72 112.17,181.59 111.64,181.59 111.21,182.02 96.45,182.02 93.51,179.07
  BOTTOM w0.102: v2(136.51,180.21) 136.51,180.26 v3(136.99,180.75)
M_DATA_A16: length 76.2
  TOP w0.102: v3(137.02,178.22) 137.62,178.66 137.99,178.66 138.4,178.25 DIMM1.42 ; v3(89.57,174.79) 89.23,174.44 CPU1.AV52
  L3 w0.089: v3(89.57,174.79) 89.23,175.12 89.01,175.35 89.01,178.77
  L3 w0.127: v3(137.02,178.22) 135.79,179.86 132.78,181.71 132.28,182.21 132.28,183.9 124.68,191.5 124.5,191.5 123.93,190.93 123.75,190.93 123.56,191.13 123.56,191.31 124.13,191.88 124.13,192.06 123.93,192.26 123.75,192.26 123.18,191.69 123,191.69 122.8,191.89 122.8,192.07 123.37,192.63 123.37,192.81 122.99,193.19 98.74,193.19 93.91,188.37 93.38,188.37 89.01,183.99 89.01,178.77
  BOTTOM w0.102: v3(137.02,178.22) 137.42,178.63 v2(137.42,178.92)
M_DATA_A17: length 75.4
  TOP w0.102: DIMM1.41 132.46,178.55 v3(132.67,178.33) ; CPU1.AY55 90.34,175.87 90.42,175.79 90.47,175.79 90.54,175.72 v3(90.55,175.72)
  L3 w0.089: v3(90.55,175.72) 89.96,176.31 89.96,178.98
  L3 w0.127: 89.96,178.98 89.96,182.85 97.28,190.17 97.29,190.17 99.25,192.13 120.86,192.13 121.24,191.75 121.24,191.57 120.91,191.23 120.91,191.05 121.1,190.86 121.28,190.86 121.62,191.19 121.8,191.19 121.99,190.99 121.99,190.81 121.66,190.48 121.66,190.3 121.86,190.1 122.04,190.1 122.37,190.44 122.55,190.44 122.75,190.24 122.75,190.06 122.41,189.73 122.41,189.55 122.61,189.35 122.79,189.35 123.12,189.68 123.3,189.68 123.5,189.48 123.5,189.3 123.17,188.97 123.17,188.79 123.37,188.59 123.55,188.59 123.88,188.93 124.06,188.93 124.26,188.73 124.26,188.55 123.92,188.22 123.92,188.04 124.12,187.84 124.3,187.84 124.63,188.17 124.81,188.17 125.01,187.98 125.01,187.8 124.68,187.46 124.68,187.28 124.87,187.09 125.05,187.09 125.39,187.42 125.57,187.42 125.76,187.22 125.76,187.04 125.43,186.71 125.43,186.53 125.63,186.33 125.81,186.33 126.14,186.66 126.32,186.66 126.52,186.47 126.52,186.29 126.44,186.2 126.44,186.02 126.63,185.83 126.81,185.83 126.9,185.91 127.08,185.91 127.45,185.53 127.45,185.35 127.16,185.06 127.16,184.88 127.36,184.69 127.54,184.69 127.83,184.98 128.01,184.98 128.21,184.78 128.21,184.6 127.92,184.31 127.92,184.13 128.12,183.93 128.3,183.93 128.59,184.22 128.77,184.22 128.96,184.02 128.96,183.84 128.67,183.55 128.67,183.37 128.87,183.18 129.05,183.18 129.34,183.47 129.52,183.47 132.31,180.68 132.31,178.7 v3(132.67,178.33)
  BOTTOM w0.102: v3(132.67,178.33) 132.54,178.28 v2(132.11,177.67)
M_DATA_A18: length 72.6
  TOP w0.102: DIMM1.51 132.06,175.55 132.29,175.78 134.17,175.78 134.29,175.65 134.29,175.42 134.45,175.26 135.42,175.26 135.52,175.16 135.52,174.14 135.39,174.02 135.22,174.02 135.08,174.15 v3(135.08,174.83) ; CPU1.BD58 92.16,177.29 v3(92.39,177.52)
  L3 w0.089: v3(92.39,177.52) 92.67,177.8 92.67,178.41 92.62,178.5 92.62,178.97 93.7,180.06 93.7,180.14 93.3,180.55 93.3,180.73 93.58,181.01 93.76,181.01 94.02,180.75
  L3 w0.127: 94.02,180.75 94.15,180.75 94.66,181.27 94.66,181.45 94.55,181.56 94.55,181.74 94.75,181.94 94.93,181.94 95.04,181.82 95.22,181.82 95.42,182.02 95.42,182.2 95.3,182.32 95.3,182.5 95.5,182.7 95.68,182.7 95.8,182.58 95.98,182.58 96.17,182.78 96.17,182.96 96.06,183.07 96.06,183.25 96.25,183.45 96.43,183.45 96.55,183.33 96.73,183.33 96.93,183.53 96.93,183.71 96.81,183.83 96.81,184.01 97.01,184.2 97.19,184.2 97.3,184.09 97.48,184.09 97.68,184.29 97.68,184.47 97.57,184.58 97.57,184.76 97.76,184.96 97.94,184.96 98.06,184.84 98.24,184.84 98.44,185.04 98.44,185.22 98.32,185.34 98.32,185.52 98.52,185.71 98.7,185.71 98.81,185.6 98.99,185.6 99.19,185.79 99.19,185.97 99.07,186.09 99.07,186.27 99.27,186.47 99.45,186.47 99.57,186.35 99.75,186.35 99.94,186.55 99.94,186.73 99.83,186.84 99.83,187.02 100.03,187.22 100.21,187.22 100.32,187.11 100.5,187.11 100.7,187.3 100.7,187.48 100.58,187.6 100.58,187.78 100.78,187.98 100.96,187.98 101.08,187.86 101.26,187.86 101.48,188.09 101.48,188.33 101.88,188.73 111.89,188.73 111.89,188.73 116.24,188.73 117.47,188.73 127.45,178.76 129.37,176.84 129.47,176.84 129.82,177.19 130,177.19 130.2,176.99 130.2,176.81 129.34,175.95 129.34,175.77 129.49,175.63 129.77,175.63 130.09,175.94 130.27,175.94 130.42,175.79 130.42,175.56 130.54,175.43 130.99,175.43 131.12,175.31 131.12,175.23 131.24,175.11 131.52,175.11 131.65,175.23 131.65,175.39 131.78,175.51 132.06,175.51 132.18,175.39 132.18,175.23 132.31,175.11 132.59,175.11 132.72,175.23 132.72,175.49 132.84,175.62 134.96,175.62 135.08,175.49 v3(135.08,174.83)
  BOTTOM w0.102: v3(135.08,174.83) 135.08,175.08 v2(134.7,175.46)
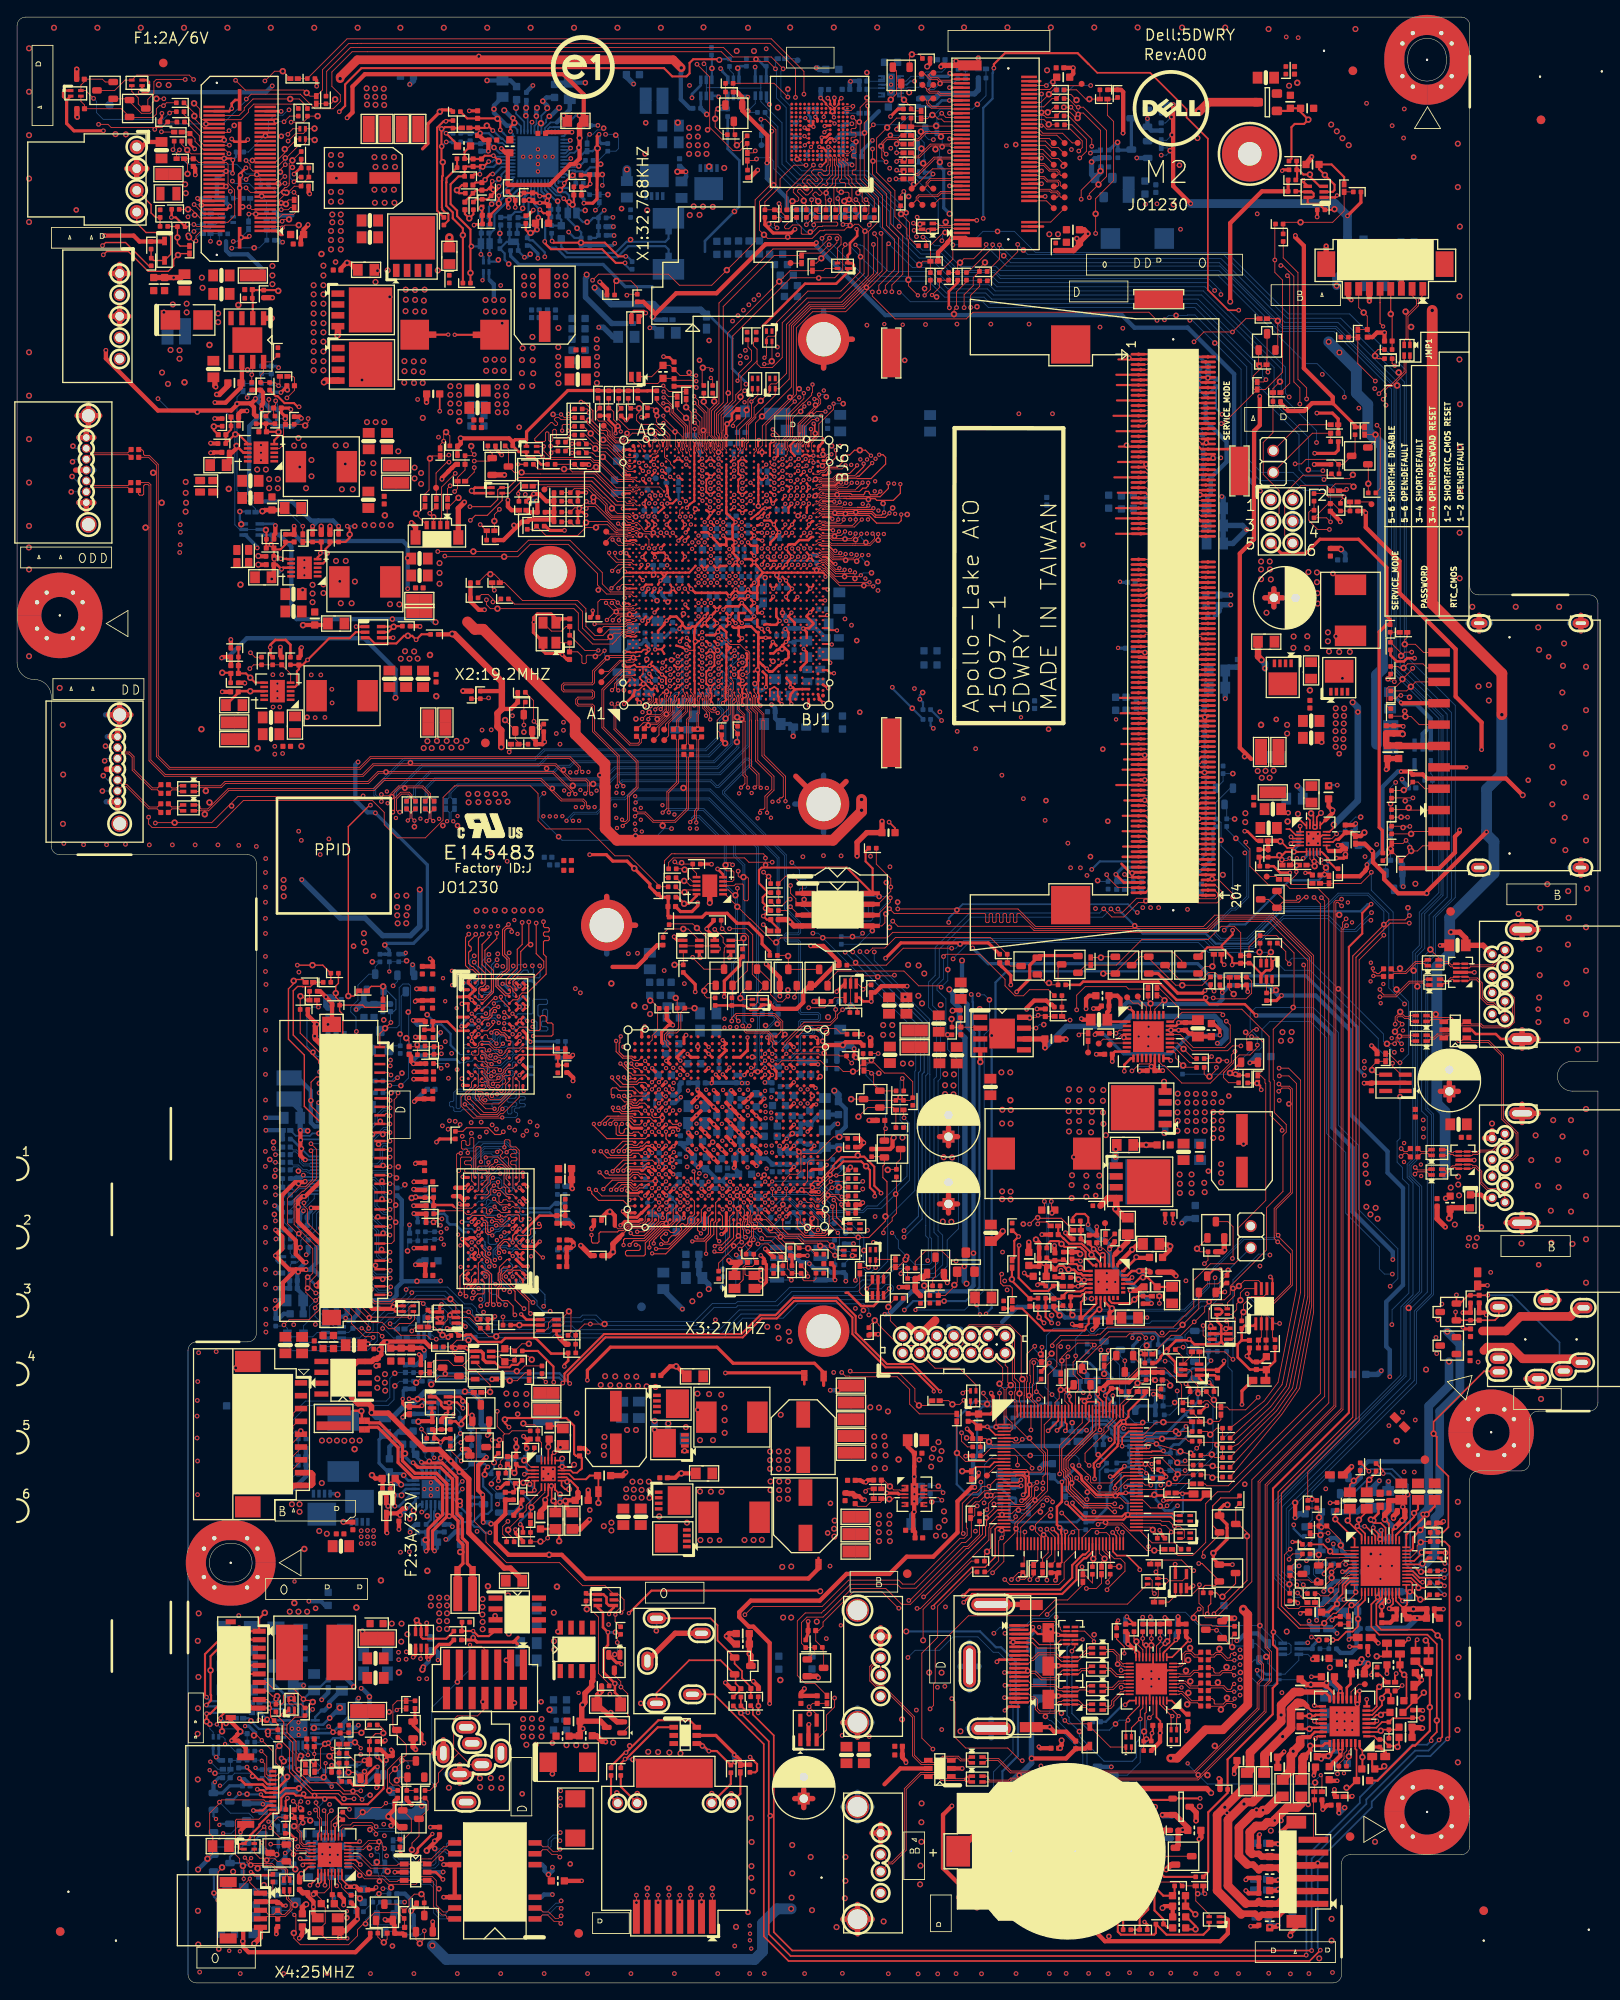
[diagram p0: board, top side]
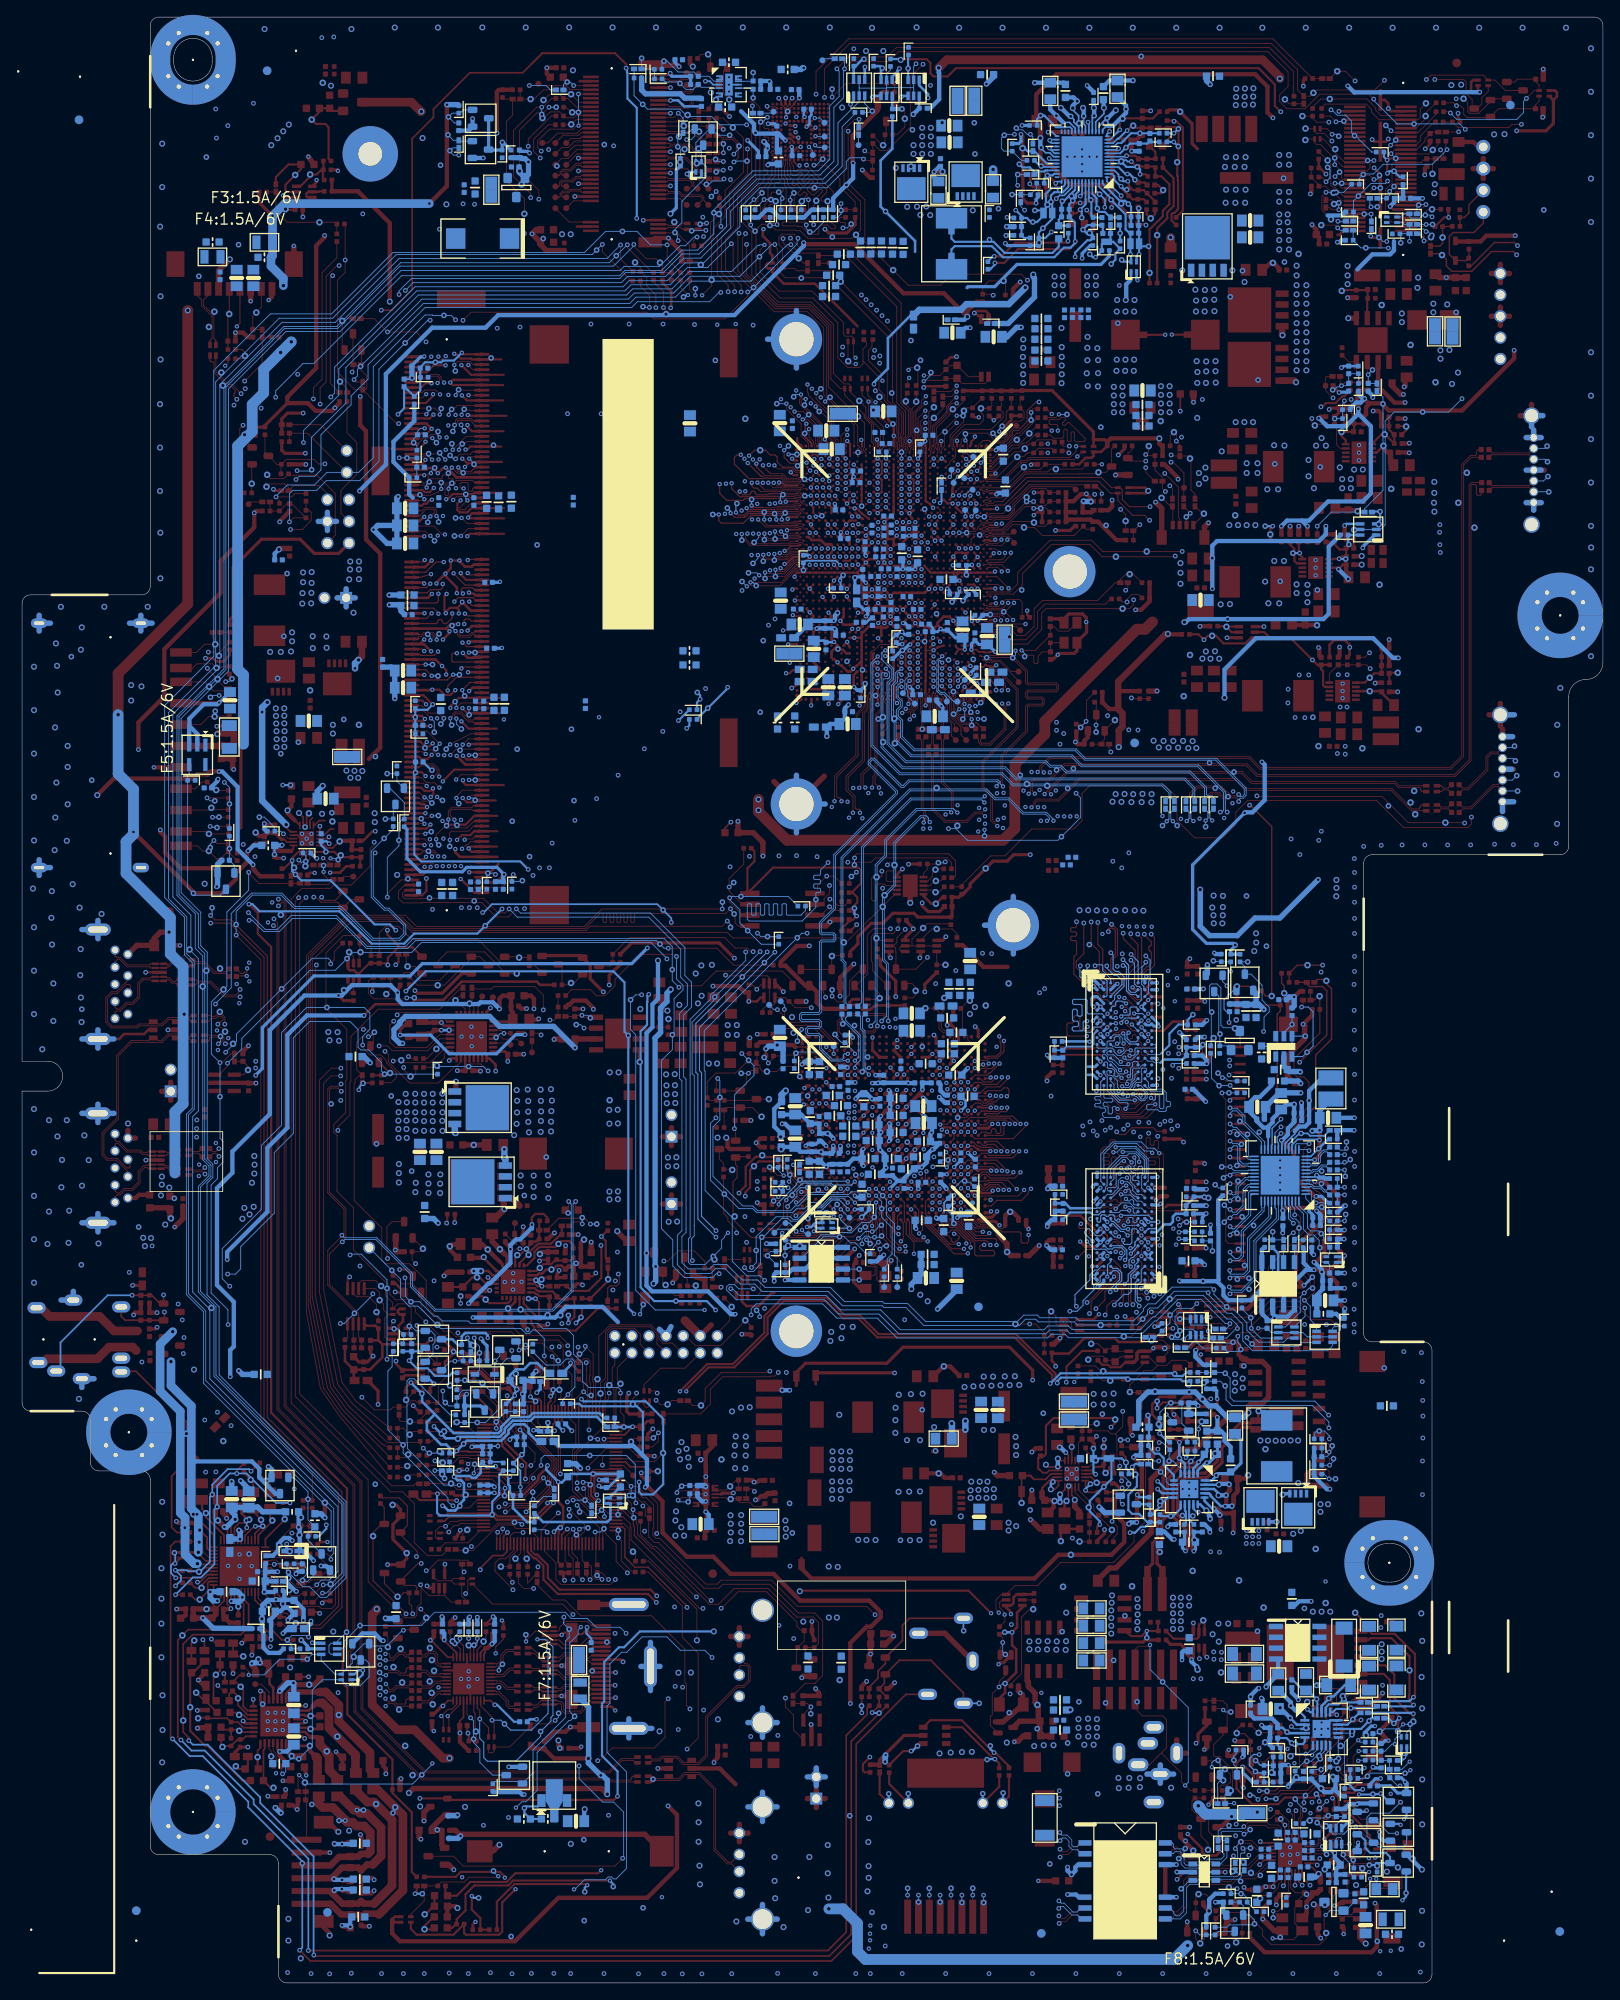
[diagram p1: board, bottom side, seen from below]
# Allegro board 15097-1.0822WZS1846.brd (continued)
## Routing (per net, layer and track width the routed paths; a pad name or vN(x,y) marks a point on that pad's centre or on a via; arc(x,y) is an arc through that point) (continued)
M_DATA_A19: length 76.2
  TOP w0.102: CPU1.AV54 89.23,175.15 v3(89.57,175.5) ; DIMM1.40 138.28,178.85 138.24,178.89 136.12,178.89 v3(135.47,178.24)
  L3 w0.089: 89.44,179.1 89.44,178.9 89.18,178.65 89.18,175.88 v3(89.57,175.5)
  L3 w0.127: 89.44,179.1 89.44,184.03 93.24,187.83 94.2,187.83 99.02,192.66 121.08,192.66 123.79,189.95 123.97,189.95 124.63,190.62 124.81,190.62 125.01,190.42 125.01,190.24 124.34,189.58 124.34,189.4 124.54,189.2 124.72,189.2 125.39,189.86 125.57,189.86 125.77,189.67 125.77,189.49 125.1,188.82 125.1,188.64 125.3,188.44 125.48,188.44 125.64,188.61 125.82,188.61 126.02,188.41 126.02,188.23 125.85,188.07 125.85,187.89 132.56,181.18 132.56,179.32 132.97,178.9 134.81,178.9 v3(135.47,178.24)
  BOTTOM w0.102: v2(136.13,179.02) 136.13,178.9 v3(135.47,178.24)
M_DATA_A20: length 73.6
  TOP w0.102: DIMM1.50 138.38,175.85 138.02,175.49 134.67,175.49 134.52,175.64 134.52,175.86 134.65,175.98 135,175.98 135.11,176.09 135.11,176.32 135.22,176.43 135.73,176.43 135.84,176.32 135.84,176.09 135.94,175.98 137.36,175.98 137.49,176.11 137.49,176.51 137.36,176.64 v3(137.15,176.64) ; CPU1.BB57 91.33,176.9 91.41,176.9 v3(91.41,176.9)
  L3 w0.089: 92.2,180.46 92.04,180.3 92.04,179.63 91.9,179.49 91.9,177.41 91.41,176.92 v3(91.41,176.9)
  L3 w0.127: 92.2,180.46 93.31,181.57 93.31,181.67 101.44,189.8 111.45,189.8 118.81,189.8 121.3,187.31 121.3,187.13 121.13,186.96 121.13,186.78 121.33,186.58 121.51,186.58 121.68,186.75 121.86,186.75 122.05,186.56 122.05,186.38 121.88,186.2 121.88,186.02 122.08,185.83 122.26,185.83 122.43,186 122.61,186 124.36,184.25 124.68,183.93 124.68,183.04 129.59,178.13 130.08,178.13 130.94,177.27 130.94,176.77 131.52,176.19 134.95,176.19 136,177.24 137.5,177.24 137.6,177.14 137.6,176.73 137.5,176.64 v3(137.15,176.64)
  BOTTOM w0.102: v3(137.15,176.64) 137.15,176.82 v2(136.71,177.27)
M_DATA_A21: length 72.3
  TOP w0.102: v3(92.28,178.29) 91.95,177.96 CPU1.BD59 ; v3(137.65,174.96) 137.95,175.25 139.4,175.25 DIMM1.52
  L3 w0.089: v3(92.28,178.29) 92.28,180.03 92.44,180.19 92.56,180.19 92.81,179.94 92.93,179.94 93.16,180.17 93.16,180.29 92.91,180.54 92.91,180.66 93.64,181.39 93.78,181.39
  L3 w0.127: v3(137.65,174.96) 137.64,174.96 137.14,174.46 136.63,174.46 136.62,174.47 136.26,174.47 136.13,174.34 136.13,174.07 136.26,173.95 136.82,173.95 136.92,174.04 138.35,174.04 138.48,174.17 138.48,175.4 138.35,175.52 136.93,175.52 136.8,175.65 136.8,176.04 136.68,176.17 136.28,176.17 136.15,176.04 136.15,175.4 136.03,175.27 135.75,175.27 135.62,175.4 135.62,175.77 135.49,175.9 131.07,175.9 130.5,176.47 130.5,177.31 130.2,177.61 129.86,177.61 129.85,177.6 129.36,177.6 120.21,186.76 120.21,186.94 120.47,187.2 120.47,187.38 120.28,187.58 120.1,187.58 119.83,187.31 119.65,187.31 119.45,187.51 119.45,187.69 119.72,187.96 119.72,188.14 119.52,188.33 119.34,188.33 119.08,188.07 118.9,188.07 118.7,188.27 118.7,188.44 118.96,188.71 118.96,188.89 118.77,189.09 118.59,189.09 118.32,188.82 118.14,188.82 117.7,189.27 116.46,189.27 101.66,189.27 93.78,181.39
  BOTTOM w0.102: v3(137.65,174.96) 137.65,175.31 v2(137.35,175.62)
M_DATA_A22: length 70.6
  TOP w0.102: v1(134.27,178.32) 133.72,178.87 132.52,178.87 132.24,179.15 DIMM1.39 ; v3(90.53,176.36) 90.31,176.58 CPU1.AY57
  L3 w0.089: v3(90.53,176.36) 90.14,176.75 90.14,178.73 90.3,178.89
  L3 w0.127: v1(134.27,178.32) 134.8,178.32 134.92,178.19 134.92,177.94 134.8,177.81 133.36,177.81 133.36,177.81 132.99,177.81 132.99,177.81 132.37,177.81 132.05,178.13 132.05,179.09 131.75,179.39 131.75,179.7 132.05,180 132.05,180.23 131.78,180.5 131.6,180.5 131.2,180.1 131.04,180.1 130.77,180.37 130.77,180.55 131.18,180.96 131.18,181.14 130.98,181.33 130.8,181.33 130.39,180.93 130.21,180.93 130.02,181.13 130.02,181.34 129.68,181.68 129.46,181.68 120.37,190.77 120.37,191.44 120.22,191.59 99.55,191.59 95.07,187.11 95.07,186.3 92.66,183.89 91.52,183.89 90.27,182.63 90.27,181.57 90.3,181.53 90.3,178.89
  BOTTOM w0.102: v1(134.27,178.32) 134.51,178.32 v2(134.91,178.71)
M_DATA_A23: length 72.7
  TOP w0.102: DIMM1.53 132.14,174.95 132.26,174.82 132.26,174.61 132.35,174.52 132.69,174.52 132.79,174.61 132.79,175.41 132.91,175.53 133.62,175.53 133.75,175.41 133.75,174.98 133.62,174.85 v3(133.33,174.85) ; CPU1.BF59 92.68,178.19 92.79,178.29 93.09,178.29 93.2,178.19 v3(93.2,177.87)
  L3 w0.089: v3(93.2,177.87) 92.97,177.87 92.85,178 92.85,178.46 92.8,178.54 92.8,178.85 93.84,179.88
  L3 w0.127: v3(133.33,174.85) 129.92,174.85 129.68,175.09 129.1,175.09 128.31,175.88 128.31,176.06 128.51,176.27 128.51,176.45 128.05,176.91 127.87,176.91 127.66,176.71 127.48,176.71 127.29,176.91 127.29,177.09 127.73,177.54 127.73,177.72 127.54,177.91 127.36,177.91 126.91,177.46 126.73,177.46 126.53,177.66 126.53,177.84 126.98,178.29 126.98,178.47 126.78,178.67 126.6,178.67 126.15,178.22 125.97,178.22 125.78,178.42 125.78,178.6 126.23,179.05 126.23,179.22 126.03,179.42 125.85,179.42 125.4,178.97 125.22,178.97 125.02,179.17 125.02,179.35 125.47,179.8 125.47,179.98 125.27,180.18 125.09,180.18 124.65,179.73 124.47,179.73 124.27,179.93 124.27,180.11 124.72,180.55 124.72,180.73 124.52,180.93 124.34,180.93 123.87,180.46 123.73,180.46 123.5,180.7 123.5,180.84 123.96,181.31 123.96,181.49 123.16,182.29 122.98,182.29 122.75,182.07 122.57,182.07 122.37,182.26 122.37,182.44 122.6,182.67 122.6,182.85 122.4,183.05 122.22,183.05 121.99,182.82 121.82,182.82 121.62,183.02 121.62,183.2 121.85,183.43 121.85,183.61 121.42,184.03 121.42,184.03 120.89,184.56 120.71,184.56 120.48,184.33 120.3,184.33 120.1,184.53 120.1,184.71 120.33,184.94 120.33,185.12 120.14,185.32 119.96,185.32 119.73,185.09 119.55,185.09 119.35,185.29 119.35,185.47 119.58,185.7 119.58,185.88 119.38,186.07 119.2,186.07 118.97,185.84 118.79,185.84 118.6,186.04 118.6,186.22 118.83,186.45 118.83,186.63 118.63,186.83 118.45,186.83 118.22,186.6 118.04,186.6 117.84,186.79 117.84,186.97 118.07,187.2 118.07,187.38 117.25,188.2 116.02,188.2 102.1,188.2 94.42,180.52 94.42,180.47 93.84,179.88
  BOTTOM w0.102: v2(94.25,177.5) 93.87,177.87 v3(93.2,177.87)
M_DATA_A24: length 61.3
  TOP w0.102: CPU1.BA50 90.28,173.73 v3(90.56,174.01) ; DIMM1.67 132.91,170.75 v3(133.56,171.4)
  L3 w0.089: 93.84,174.72 93.69,174.58 90.79,174.58 90.56,174.34 v3(90.56,174.01)
  L3 w0.127: v3(133.56,171.4) 133.17,171.01 132.61,171.01 132.54,171.08 127.48,171.08 114.43,184.13 108.23,184.13 108.08,184.28 107.72,184.28 107.58,184.13 107.21,184.13 107.07,184.28 106.71,184.28 106.56,184.13 106.2,184.13 106.05,184.28 105.69,184.28 105.54,184.13 105.18,184.13 105.04,184.28 104.67,184.28 104.53,184.13 104.17,184.13 104.02,184.28 103.66,184.28 103.51,184.13 103.15,184.13 103,184.28 102.64,184.28 102.5,184.13 101.66,184.13 97.87,180.34 97.87,179.96 95.7,177.79 95.7,176.58 95.1,175.98 94.92,175.98 94.51,176.39 94.33,176.39 94.15,176.21 94.15,176.03 94.56,175.62 94.56,175.44 94.38,175.26 94.2,175.26 93.79,175.67 93.61,175.67 93.43,175.49 93.43,175.31 93.84,174.9 93.84,174.72
  BOTTOM w0.102: v3(133.56,171.4) v2(134.27,171.4)
M_DATA_A25: length 61.5
  TOP w0.102: v3(91.31,175.88) 91.31,175.87 91.31,175.76 CPU1.BB54 ; v3(137.91,173.59) 138.05,173.45 DIMM1.58
  L3 w0.089: v3(91.31,175.88) 91.31,175.92 91.69,176.3 92.15,176.3 92.34,176.49 92.9,176.49 93.99,177.59 93.99,179.15
  L3 w0.127: v3(137.91,173.59) 137.91,173.52 137.07,172.96 136.7,172.96 135.85,173.9 135.72,174.03 128.58,174.03 121.96,180.64 121.96,181.13 115.96,187.13 115.58,187.13 115.57,187.13 112.55,187.13 101.98,187.13 93.99,179.15
  BOTTOM w0.102: v3(137.91,173.59) 137.91,173.59 v2(138.44,174.12)
M_DATA_A26: length 59.9
  TOP w0.102: CPU1.BD50 91.7,173.73 v3(91.98,174.01) ; DIMM1.69 132.78,170.15 v3(133.64,169.29)
  L3 w0.127: v3(91.98,174.01) 91.98,173.69 92.11,173.56 92.98,173.56 93.11,173.43 93.11,172.9 93.24,172.77 93.73,172.77 96,175.04 96,175.79 96.68,176.48 97.16,176.48 97.29,176.6 97.29,177 97.16,177.13 96.66,177.13 96.45,177.33 96.45,177.62 98.64,179.81 99.05,179.81 101.77,182.53 111.09,182.53 111.12,182.5 112.92,182.5 112.96,182.53 113.77,182.53 126.93,169.37 129.86,169.37 130.14,169.09 132.09,169.09 132.22,169.21 132.22,169.63 132.35,169.76 133.51,169.76 133.64,169.63 v3(133.64,169.29)
  BOTTOM w0.102: v3(133.64,169.29) v2(134.4,169.29)
M_DATA_A27: length 60.6
  TOP w0.102: v3(92.79,176.94) 92.8,176.94 92.81,176.95 92.81,176.95 93.12,177.27 CPU1.BF58 ; v3(135.95,174.8) 136.35,174.41 137.23,174.05 DIMM1.56
  L3 w0.089: 93.71,179.08 93.71,177.61 93.58,177.49 92.9,177.49 92.67,177.25 92.67,177.06 v3(92.79,176.94)
  L3 w0.127: v3(135.95,174.8) 135.95,174.69 135.54,174.28 133.14,174.28 132.86,174.56 128.88,174.56 122.49,180.94 122.49,181.35 122.25,181.59 122.25,181.63 117.18,186.7 117.18,187.48 116.99,187.67 115.8,187.67 101.88,187.67 94.94,180.73 94.94,180.4 93.77,179.24 93.77,179.15 93.71,179.08
  BOTTOM w0.102: v2(135.95,175.54) v3(135.95,174.8)
M_DATA_A28: length 62.4
  TOP w0.102: DIMM1.57 132.56,173.75 132.7,173.89 134.18,173.89 v3(134.55,173.52) ; CPU1.BE56 92.7,176.1 v3(92.7,175.93)
  L3 w0.089: 94.44,178.61 94.44,177.54 92.83,175.93 92.77,175.93 92.77,175.93 v3(92.7,175.93)
  L3 w0.127: 94.44,178.61 96.27,180.44 96.43,180.44 102.05,186.07 113.05,186.07 114.92,186.07 114.92,186.07 115.03,186.07 117.02,184.08 117.4,184.08 117.7,183.79 117.7,183.4 128.16,172.94 129.73,172.94 130.14,172.53 134.39,172.53 134.52,172.4 134.52,172.4 135.1,171.82 135.28,171.82 135.57,172.11 136.33,172.11 136.46,172.24 136.46,172.57 135.98,173.04 135.03,173.04 v3(134.55,173.52)
  BOTTOM w0.102: v2(93.43,175.92) 93.27,175.93 v3(92.7,175.93)
M_DATA_A29: length 60.9
  TOP w0.102: v3(137.22,169.31) 137.31,169.31 137.85,169.85 DIMM1.70 ; v3(91.27,174.01) 90.99,173.73 CPU1.BB50
  L3 w0.089: v3(91.27,174.01) 91.65,174.4 93.82,174.4 95.1,175.68
  L3 w0.127: v3(137.22,169.31) 137.22,169.93 136.6,170.55 127.26,170.55 114.21,183.6 112.51,183.6 112.48,183.57 111.56,183.57 111.53,183.6 101.54,183.6 98.2,180.26 98.2,179.99 95.92,177.7 95.92,176.49 95.1,175.68
  BOTTOM w0.102: v2(136.74,168.73) 136.74,168.83 v3(137.22,169.31)
M_DATA_A30: length 61.9
  TOP w0.102: v3(92.03,175.84) 92.02,175.82 92.02,175.76 CPU1.BD54 ; v3(132.88,173.46) 132.93,173.46 133.76,172.63 133.76,172.45 133.66,172.36 133.18,172.36 132.41,173.14 132.16,173.14 132.15,173.15 DIMM1.59
  L3 w0.089: 94.22,178.79 94.22,177.56 92.97,176.32 92.51,176.32 v3(92.03,175.84)
  L3 w0.127: 94.22,178.79 102.02,186.6 112.77,186.6 115.74,186.6 116.11,186.22 116.11,186.04 116.05,185.98 116.05,185.8 116.25,185.6 116.43,185.6 116.49,185.67 116.67,185.67 116.87,185.47 116.87,185.29 116.8,185.23 116.8,185.05 117,184.85 117.18,184.85 117.24,184.91 117.42,184.91 118.41,183.93 118.41,183.57 118.61,183.37 118.96,183.37 119.16,183.17 119.16,182.82 119.36,182.62 119.72,182.62 119.92,182.42 119.92,182.07 120.12,181.87 120.47,181.87 120.67,181.66 120.67,181.31 120.87,181.11 121.23,181.11 121.43,180.91 121.43,180.42 128.38,173.47 130.42,173.47 130.54,173.34 130.54,172.97 130.67,172.85 130.95,172.85 131.08,172.97 131.08,173.56 131.2,173.69 131.48,173.69 131.61,173.56 131.61,172.97 131.74,172.85 132.02,172.85 132.14,172.97 132.14,173.66 132.26,173.77 132.76,173.77 132.88,173.66 v3(132.88,173.46)
  BOTTOM w0.102: v3(132.88,173.46) 133.08,173.66 v2(133.08,174.17)
M_DATA_A31: length 60.7
  TOP w0.102: v3(135.52,169.47) 135.85,169.47 136.83,170.45 DIMM1.68 ; v3(92.69,174.01) 92.41,173.73 CPU1.BE50
  L3 w0.127: v3(92.69,174.01) 93.28,174.01 93.41,173.88 93.41,173.57 93.54,173.44 93.92,173.44 95.78,175.3 95.78,175.88 96.13,176.24 96.13,177.61 101.59,183.06 111.31,183.06 111.34,183.03 112.7,183.03 112.74,183.06 113.99,183.06 127.04,170.01 133.77,170.01 134.2,169.59 134.2,169.01 134.33,168.88 135.39,168.88 135.52,169.01 v3(135.52,169.47)
  BOTTOM w0.102: v2(93.4,173.99) 93.19,174.01 v3(92.69,174.01)
M_DATA_A32: length 64.2
  TOP w0.102: v3(134.18,149.17) 134.17,149.18 134.17,149.2 133.62,149.75 DIMM1.129 ; v3(87.79,169.66) 87.43,169.3 CPU1.AR41
  L3 w0.089: v3(87.79,169.66) 88.34,169.1 93.06,169.1 93.87,169.91
  L3 w0.127: 93.87,169.91 94.75,170.79 104.36,170.79 125.45,149.71 126.03,149.71 126.28,149.45 126.56,149.45 126.82,149.71 127.1,149.71 127.22,149.58 127.22,149.43 127.35,149.3 127.63,149.3 127.76,149.43 127.76,149.58 127.88,149.71 128.16,149.71 128.29,149.58 128.29,149.25 128.42,149.12 128.7,149.12 128.82,149.25 128.82,149.58 128.95,149.71 129.23,149.71 129.36,149.58 129.36,149.25 129.48,149.12 129.76,149.12 129.89,149.25 129.89,149.58 130.02,149.71 130.3,149.71 130.42,149.58 130.42,149.25 130.55,149.12 130.83,149.12 130.96,149.25 130.96,149.58 131.08,149.71 133.64,149.71 134.17,149.17 v3(134.18,149.17)
  BOTTOM w0.102: v3(134.18,149.17) 134.18,149.76 v2(134.32,149.91)
M_DATA_A33: length 66.9
  TOP w0.102: v3(88.45,169.67) 88.45,169.53 CPU1.AT41 ; DIMM1.132 138.04,148.85 v3(137.14,147.96)
  L3 w0.089: 93.68,170.25 93.68,169.97 92.99,169.28 88.84,169.28 v3(88.45,169.67)
  L3 w0.127: 93.68,170.25 95.14,171.7 95.7,171.7 95.83,171.83 95.83,172.01 95.96,172.14 96.24,172.14 96.37,172.01 96.37,171.83 96.49,171.7 96.77,171.7 96.9,171.83 96.9,172.16 97.03,172.29 97.3,172.29 97.43,172.16 97.43,171.83 97.56,171.7 97.84,171.7 97.97,171.83 97.97,172.19 98.09,172.31 98.37,172.31 98.5,172.19 98.5,171.83 98.63,171.7 99.94,171.7 102.75,171.22 104.69,171.22 125.67,150.24 129.85,150.24 129.98,150.1 133.9,150.1 135.31,149.67 v3(137.14,147.96)
  BOTTOM w0.102: v2(136.76,146.33) 136.76,147.59 136.91,147.73 v3(137.14,147.96)
M_DATA_A34: length 66.6
  TOP w0.089: CPU1.AR37 v3(87.14,166.87)
  TOP w0.102: v3(134.91,144.91) 134.41,145.16 134.4,145.17 132.48,146.15 DIMM1.141
  L3 w0.089: v3(87.14,166.87) 87.96,166.31 88.72,166.31 93.24,166.31
  L3 w0.127: v3(134.91,144.91) 134.91,144.8 134.38,144.37 134.25,144.37 132.71,144.26 131.44,143.59 129.85,143.59 129.85,143.59 127.57,143.59 127.44,143.46 127.44,143.18 127.31,143.05 127.03,143.05 126.91,143.18 126.91,143.46 126.78,143.59 126.5,143.59 126.37,143.46 126.37,143.18 126.25,143.05 125.97,143.05 125.84,143.18 125.84,143.46 125.71,143.59 124.12,143.59 119,148.71 118.99,148.71 104.98,162.72 104.98,163.86 100.88,167.96 95.3,167.96 93.24,166.31
  BOTTOM w0.102: v2(135.36,144.35) 135.36,144.45 v3(134.91,144.91)
M_DATA_A35: length 67.4
  TOP w0.089: CPU1.AW35 v3(89.98,166.87)
  TOP w0.102: DIMM1.140 137.59,146.45 v3(136.13,144.98)
  L3 w0.089: v3(89.98,166.87) 90.37,167.26 93.55,167.26
  L3 w0.127: v3(136.13,144.98) 134.99,146.12 132.88,146.12 131.43,144.68 125.58,144.68 121.94,148.31 121.7,148.31 121.38,148.62 121.38,148.87 121.19,149.07 121.01,149.07 120.72,148.78 120.54,148.78 120.34,148.98 120.34,149.16 120.63,149.45 120.63,149.63 120.25,150 120.07,150 119.73,149.66 119.55,149.66 119.35,149.86 119.35,150.04 119.7,150.38 119.7,150.56 119.5,150.76 119.32,150.76 118.98,150.42 118.8,150.42 118.6,150.61 118.6,150.79 118.94,151.13 118.94,151.31 118.74,151.51 118.56,151.51 118.22,151.17 118.04,151.17 106.05,163.16 106.05,164.3 101.96,168.39 94.7,168.39 94.1,167.79 94.09,167.79 93.55,167.26
  BOTTOM w0.102: v2(136.58,144.4) 136.58,144.53 v3(136.13,144.98)
M_DATA_A36: length 64.9
  TOP w0.089: CPU1.AT37 v3(87.85,167.83)
  TOP w0.102: DIMM1.130 138.26,149.45 137.37,148.56 136.25,148.56 v1(135.64,147.96)
  L3 w0.089: 93.91,169.11 93.53,168.73 88.92,168.73 v3(87.85,167.83)
  L3 w0.127: v1(135.64,147.96) 135.28,148.32 134.78,148.59 134.59,148.6 133.64,148.33 132.5,147.19 126.45,147.19 103.29,170.36 95.16,170.36 93.91,169.11
  BOTTOM w0.102: v2(136,147.29) 135.64,147.65 v1(135.64,147.96)
M_DATA_A37: length 65.5
  TOP w0.089: CPU1.AR39 v3(87.14,167.83)
  TOP w0.102: DIMM1.131 132.65,149.15 132.65,149.15 v3(132.7,149.15)
  L3 w0.089: v3(87.14,167.83) 88.22,168.91 93.35,168.91 93.91,169.47
  L3 w0.127: 93.91,169.47 95.02,170.57 103.83,170.57 125.81,148.58 126.68,148.58 126.8,148.46 126.8,147.85 126.93,147.72 127.21,147.72 127.34,147.85 127.34,148.46 127.46,148.58 129.06,148.58 129.19,148.46 129.19,147.9 129.32,147.77 129.59,147.77 129.72,147.9 129.72,148.46 129.85,148.58 130.13,148.58 130.26,148.46 130.26,147.58 130.38,147.45 130.66,147.45 130.79,147.58 130.79,148.46 130.92,148.58 131.19,148.58 131.32,148.46 131.32,147.58 131.45,147.45 131.73,147.45 131.86,147.58 131.86,148.46 131.98,148.58 132.13,148.58 v3(132.7,149.15)
  BOTTOM w0.102: v2(132.67,148.36) 132.7,148.56 v3(132.7,149.15)
M_DATA_A38: length 63.4
  TOP w0.089: CPU1.AV37 v3(88.56,166.87)
  TOP w0.102: v3(133.43,144.88) 132.76,145.55 DIMM1.143
  L3 w0.089: 93.78,167.13 93.14,166.49 89.07,166.49 88.68,166.87 v3(88.56,166.87)
  L3 w0.127: 93.78,167.13 94.83,168.18 101.42,168.18 105.51,164.08 105.51,162.94 121.87,146.59 122.05,146.59 122.39,146.93 122.57,146.93 122.77,146.73 122.77,146.55 122.43,146.21 122.43,146.03 122.63,145.83 122.81,145.83 123.15,146.17 123.33,146.17 123.53,145.98 123.53,145.8 123.18,145.45 123.18,145.27 123.38,145.08 123.71,145.08 123.94,144.85 123.94,144.52 124.32,144.14 131.36,144.14 132.59,145.37 132.94,145.37 v3(133.43,144.88)
  BOTTOM w0.102: v3(133.43,144.88) 133.43,144.73 v2(133.74,144.22)
M_DATA_A39: length 65.4
  TOP w0.089: CPU1.AW37 v3(89.27,166.87)
  TOP w0.102: v3(137.64,145.19) 137.64,145.56 137.93,145.85 DIMM1.142
  L3 w0.089: v3(89.27,166.87) 89.84,167.44 93.14,167.44 93.2,167.5
  L3 w0.127: 93.2,167.5 93.71,168.01 94.01,168.01 94.61,168.61 102.5,168.61 106.58,164.52 106.58,163.38 113.65,156.32 114.79,156.32 115.17,155.94 115.17,155.76 115.01,155.59 115.01,155.41 115.2,155.22 115.38,155.22 115.55,155.38 115.73,155.38 115.93,155.19 115.93,155.01 115.76,154.84 115.76,154.66 115.96,154.46 116.14,154.46 116.3,154.63 116.48,154.63 116.68,154.43 116.68,154.19 117,153.87 117.24,153.87 125.75,145.36 126.08,145.36 126.08,145.36 126.26,145.36 126.26,145.36 131.54,145.36 132.59,146.41 136.42,146.41 v3(137.64,145.19)
  BOTTOM w0.102: v2(137.85,144.5) 137.85,144.98 v3(137.64,145.19)
M_DATA_A40: length 61.4
  TOP w0.102: DIMM1.147 134.19,144.35 v3(134.88,143.66) ; CPU1.BJ44 94.48,170.56 94.51,170.54 97.77,170.54 98.14,170.91 v3(98.14,171.21)
  L4 w0.127: v3(98.14,171.21) 98.78,171.84 99.97,171.84 100.65,171.16 104.07,171.16 104.69,170.53 104.69,169.3 106.05,167.95 106.05,167.95 113.97,160.02 114.15,160.02 114.24,160.11 114.42,160.11 114.61,159.91 114.61,159.73 114.53,159.65 114.53,159.47 114.72,159.27 114.9,159.27 114.99,159.36 115.17,159.36 115.37,159.16 115.37,158.98 115.28,158.89 115.28,158.71 116.32,157.68 116.5,157.68 116.98,158.16 117.16,158.16 117.36,157.97 117.36,157.79 116.87,157.3 116.87,157.12 117.07,156.92 117.25,156.92 117.69,157.36 117.87,157.36 130.95,144.27 134.27,144.27 v3(134.88,143.66)
  BOTTOM w0.102: v3(98.14,171.21) v2(98.14,172.08)
M_DATA_A41: length 60.1
  TOP w0.089: CPU1.BG43 93.44,170.1 93.79,170.38 94.03,170.38 94.16,170.29 94.49,170.29 94.55,170.35
  TOP w0.102: DIMM1.149 132.58,143.75 v3(132.7,143.64) ; v3(98.86,171.21) 97.99,170.35 94.55,170.35
  L4 w0.127: v3(98.86,171.21) 99.27,171.63 99.88,171.63 100.56,170.94 103.38,170.94 104.16,170.16 104.16,169.08 117.23,156.01 117.67,156.01 117.91,156.24 118.15,156.24 118.34,156.04 118.34,155.86 117.96,155.48 117.96,155.3 118.16,155.1 118.34,155.1 118.72,155.49 118.9,155.49 119.1,155.29 119.1,155.11 118.71,154.72 118.71,154.54 118.91,154.35 119.09,154.35 119.48,154.73 119.66,154.73 119.85,154.54 119.85,154.36 119.47,153.97 119.47,153.79 119.67,153.59 119.85,153.59 120.23,153.98 120.41,153.98 120.61,153.78 120.61,153.6 120.22,153.22 120.22,153.04 120.42,152.84 120.6,152.84 120.99,153.22 121.16,153.22 130.68,143.71 132.62,143.71 v3(132.7,143.64)
  BOTTOM w0.102: v3(132.7,143.64) v2(131.96,143.64)
M_DATA_A42: length 60.4
  TOP w0.089: CPU1.BG39 93.44,168.24 93.79,168.53 94.03,168.53 94.16,168.44 95.02,168.44 95.26,168.2 95.28,168.2 95.29,168.19 97.74,168.19 98.05,168.19 98.06,168.19 99.83,168.19 100.56,168.91 100.56,168.92
  TOP w0.102: v3(100.77,169.52) 100.8,169.49 100.8,169.16 100.56,168.92 ; v3(134.2,140.79) 133.64,141.35 DIMM1.157
  L4 w0.127: v3(100.77,169.52) 100.77,169.18 123.17,146.78 123.18,146.78 123.37,146.58 123.55,146.58 123.92,146.95 124.1,146.95 124.3,146.75 124.3,146.57 123.93,146.2 123.93,146.02 124.13,145.83 124.31,145.83 124.68,146.19 124.86,146.19 129.73,141.33 134.33,141.33 134.46,141.2 134.46,140.92 134.33,140.79 v3(134.2,140.79)
  BOTTOM w0.102: v3(100.77,169.52) v2(100.77,168.8)
M_DATA_A43: length 60.7
  TOP w0.089: CPU1.BG40 93.68,168.85 93.98,168.85 94.16,168.98 95.21,168.98 95.24,168.95 95.28,168.91
  TOP w0.102: v3(136.15,139.85) 136.71,140.41 137.42,140.41 137.47,140.46 137.7,140.46 138.29,141.05 DIMM1.158 ; 95.28,168.91 95.4,168.8 98.12,168.8 98.79,169.46 v3(98.79,169.54)
  L4 w0.127: v3(136.15,139.85) 135.54,139.85 135.14,140.26 128.18,140.26 100.99,167.46 100.88,167.46 99.94,168.39 99.94,168.8 99.72,169.01 99.32,169.01 v3(98.79,169.54)
  BOTTOM w0.102: v3(98.79,169.54) 98.79,169.09 v2(99.33,168.54)
M_DATA_A44: length 60.2
  TOP w0.102: DIMM1.146 138.36,144.65 138.01,144.3 138,144.3 137.99,144.3 137.99,144.3 137.94,144.25 137.01,144.25 136.5,143.74 136.35,143.74 v3(136.3,143.69) ; CPU1.BH45 93.92,171.02 94.55,171.02 94.66,170.9 95.83,170.9 96.1,171.17 v3(96.1,171.22)
  L4 w0.127: v3(96.1,171.22) 96.72,171.84 98.13,171.84 98.35,172.06 100.06,172.06 100.74,171.37 105.9,171.37 107.39,169.88 107.39,169.55 107.6,169.34 107.93,169.34 108.14,169.12 108.14,168.79 108.36,168.58 108.69,168.58 108.9,168.37 108.9,168.04 109.11,167.83 109.44,167.83 109.65,167.62 109.65,167.29 109.87,167.07 110.2,167.07 131.8,145.47 135.08,145.47 135.35,145.2 135.35,144.64 v3(136.3,143.69)
  BOTTOM w0.102: v3(96.1,171.22) 96.1,171.58 v2(95.69,171.99)
M_DATA_A45: length 62.2
  TOP w0.089: v3(96.73,171.22) 96.68,171.17 96.68,171.02 96.38,170.72 94.59,170.72 94.47,170.84 94.16,170.84 94.13,170.81 94.12,170.81 93.98,170.7 93.68,170.7 CPU1.BG44
  TOP w0.102: v3(137.77,143.79) 137.78,143.79 137.93,143.94 138.06,143.94 138.11,143.99 138.12,143.99 138.12,144 138.14,144 138.19,144.05 DIMM1.148
  L4 w0.127: v3(137.77,143.79) 137.99,143.79 138.12,143.66 138.12,143.24 137.99,143.12 130.51,143.12 122.01,151.62 121.83,151.62 121.44,151.23 121.26,151.23 121.06,151.43 121.06,151.61 121.45,152 121.45,152.18 121.25,152.38 121.07,152.38 120.68,151.98 120.5,151.98 120.3,152.18 103.41,169.08 103.41,169.95 102.63,170.73 97.23,170.73 v3(96.73,171.22)
  BOTTOM w0.102: v3(96.73,171.22) 96.73,171.7 96.94,171.9 v2(96.94,171.9)
M_DATA_A46: length 60.3
  TOP w0.089: 96.02,168.38 95.33,168.38 95.03,168.68 94.34,168.68 CPU1.BJ40
  TOP w0.102: v3(100.11,169.57) 100.33,169.35 100.33,168.95 99.75,168.38 98.14,168.38 96.02,168.38 ; DIMM1.159 132.69,140.75 v3(132.7,140.74)
  L4 w0.127: v3(132.7,140.74) 132.65,140.79 128.41,140.79 128.03,141.17 128.03,141.35 128.39,141.71 128.39,141.89 128.19,142.09 128.01,142.09 127.65,141.73 127.47,141.73 127.27,141.92 127.27,142.1 127.63,142.46 127.63,142.64 127.43,142.84 127.25,142.84 126.9,142.48 126.72,142.48 126.52,142.68 126.52,142.86 126.88,143.22 126.88,143.4 126.68,143.59 126.5,143.59 126.14,143.24 125.96,143.24 125.76,143.43 125.76,143.61 126.12,143.97 126.12,144.15 125.93,144.35 125.75,144.35 125.39,143.99 125.21,143.99 125.01,144.19 125.01,144.37 125.37,144.73 125.37,144.91 125.17,145.1 124.99,145.1 124.63,144.74 124.45,144.74 100.41,168.78 100.41,169.27 v3(100.11,169.57)
  BOTTOM w0.102: v3(132.7,140.74) v2(131.96,140.74)
M_DATA_A47: length 61.8
  TOP w0.089: 95.49,168.99 95.3,169.17 CPU1.BH41
  TOP w0.102: v3(98.13,169.57) 98.13,169.49 97.63,168.99 95.49,168.99 ; v3(137.65,140.03) 137.73,140.11 137.78,140.11 138.03,140.36 139.14,140.36 139.23,140.45 DIMM1.160
  L4 w0.127: v3(98.13,169.57) 98.28,169.42 98.28,169.41 98.45,169.23 98.45,169.05 98.15,168.75 98.15,168.57 98.35,168.37 98.53,168.37 98.83,168.68 99.01,168.68 99.21,168.48 99.21,168.3 98.9,167.99 98.9,167.81 99.1,167.62 99.28,167.62 99.59,167.92 99.77,167.92 127.96,139.73 134.78,139.73 135.2,139.31 137.1,139.31 137.65,139.86 v3(137.65,140.03)
  BOTTOM w0.102: v3(98.13,169.57) v2(98.13,168.85)
M_DATA_A48: length 67.3
  TOP w0.089: CPU1.BD39 v3(92.12,167.83)
  TOP w0.102: v3(134.17,138.63) 134.17,138.81 133.43,139.55 DIMM1.163
  L4 w0.127: v3(92.12,167.83) 92.52,168.23 94.44,168.23 96.15,166.52 100.41,166.52 124.24,142.69 124.24,142.51 123.71,141.99 123.71,141.81 123.91,141.61 124.09,141.61 124.62,142.14 124.8,142.14 124.99,141.94 124.99,141.76 124.47,141.23 124.47,141.05 124.67,140.86 124.85,140.86 125.37,141.38 125.55,141.38 125.75,141.19 125.75,141.01 125.23,140.49 125.23,140.31 125.43,140.11 125.61,140.11 126.13,140.63 126.31,140.63 126.5,140.43 126.5,140.25 125.98,139.72 125.98,139.54 126.17,139.35 126.35,139.35 126.88,139.87 127.06,139.87 127.77,139.17 134.48,139.17 134.6,139.04 134.6,138.65 134.48,138.52 134.28,138.52 v3(134.17,138.63)
  BOTTOM w0.102: v3(134.17,138.63) 134.17,138.33 v2(133.89,137.97)
M_DATA_A49: length 66.6
  TOP w0.089: CPU1.BD37 v3(91.41,167.83)
  TOP w0.102: v3(136.43,138.76) 136.94,138.25 138.11,138.25 138.5,138.65 DIMM1.166
  L4 w0.089: 93.3,167.44 91.79,167.44 v3(91.41,167.83)
  L4 w0.127: 93.3,167.44 96.43,164.31 98.54,164.31 100.37,162.48 101.18,162.48 101.3,162.61 101.3,163.25 101.43,163.37 101.71,163.37 101.84,163.25 101.84,162.61 101.96,162.48 102.94,162.48 115.54,149.89 115.54,149.54 115.05,149.05 115.05,148.91 115.28,148.68 115.43,148.68 115.92,149.17 116.1,149.17 116.29,148.97 116.29,148.79 115.82,148.31 115.82,148.13 125.85,138.1 135.77,138.1 v3(136.43,138.76)
  BOTTOM w0.102: v2(135.8,138.35) 136.02,138.35 v3(136.43,138.76)
M_DATA_A50: length 67.3
  TOP w0.102: CPU1.BD34 v3(92.12,165.92) ; v3(137.91,135.61) 137.95,135.65 DIMM1.176
  L4 w0.127: v3(137.91,135.61) 137.65,135.35 137.65,135.34 137.28,134.97 124.91,134.97 105.33,154.55 105.33,154.73 105.9,155.29 105.9,155.47 105.7,155.67 105.52,155.67 104.95,155.1 104.77,155.1 104.58,155.3 104.58,155.48 105.14,156.05 105.14,156.23 104.94,156.42 104.76,156.42 104.2,155.86 104.02,155.86 103.82,156.06 103.82,156.23 104.39,156.8 104.39,156.98 104.19,157.18 104.01,157.18 103.87,157.03 103.69,157.03 103.49,157.23 103.49,157.41 103.63,157.55 103.63,157.73 101.74,159.63 99.31,159.63 96.21,162.73 96.19,162.73 95.38,163.54 94.5,163.54 v3(92.12,165.92)
  BOTTOM w0.102: v2(138.29,136.22) 138.01,135.74 v3(137.91,135.61)
M_DATA_A51: length 68
  TOP w0.102: CPU1.BB34 v3(91.41,165.92) ; v3(134.93,133.73) 134.98,133.78 134.98,134.52 134.75,134.75 132.77,134.75 132.17,135.35 DIMM1.177
  L4 w0.127: v3(91.41,165.92) 91.41,165.89 94.68,162.61 95.57,162.61 99.08,159.09 99.97,159.09 100.44,158.62 100.62,158.62 101.09,159.09 101.27,159.09 101.46,158.89 101.46,158.71 101,158.25 101,158.07 101.2,157.87 101.38,157.87 101.96,158.45 102.14,158.45 102.33,158.25 102.33,158.07 101.75,157.49 101.75,157.31 101.95,157.12 102.13,157.12 102.57,157.56 102.75,157.56 102.95,157.36 102.95,157.18 102.51,156.74 102.51,156.56 124.86,134.2 134.46,134.2 v3(134.93,133.73)
  BOTTOM w0.102: v2(134.96,132.97) 134.96,132.97 134.93,133.04 v3(134.93,133.73)
M_DATA_A52: length 66.9
  TOP w0.089: CPU1.BE39 v3(92.83,167.83)
  TOP w0.102: v3(132.72,138.63) 132.41,138.95 DIMM1.165
  L4 w0.127: v3(132.72,138.63) 126.11,138.63 122.86,141.89 122.86,142.06 123.38,142.59 123.38,142.77 123.19,142.97 123.01,142.97 122.48,142.44 122.3,142.44 122.1,142.64 122.1,142.82 122.63,143.35 122.63,143.53 122.43,143.72 122.25,143.72 121.72,143.2 121.55,143.2 121.35,143.39 121.35,143.57 121.88,144.1 121.88,144.28 121.68,144.48 121.5,144.48 120.97,143.95 120.79,143.95 120.59,144.15 120.59,144.33 121.12,144.86 121.12,145.04 120.92,145.23 120.74,145.23 120.22,144.71 120.04,144.71 119.84,144.9 119.84,145.08 120.37,145.61 120.37,145.79 120.17,145.99 119.99,145.99 119.46,145.46 119.28,145.46 119.08,145.66 119.08,145.84 119.61,146.36 119.61,146.54 119.41,146.74 119.24,146.74 118.71,146.21 118.53,146.21 118.33,146.41 118.33,146.59 118.51,146.77 118.51,146.95 118.31,147.15 118.13,147.15 117.95,146.97 117.77,146.97 117.01,147.73 117.01,149.17 100.26,165.92 96.43,165.92 94.53,167.83 v3(92.83,167.83)
  BOTTOM w0.102: v2(131.96,138.38) 132.21,138.63 v3(132.72,138.63)
M_DATA_A53: length 67.2
  TOP w0.089: CPU1.BB37 v3(90.7,167.83)
  TOP w0.102: v3(137.9,138.71) 138.44,139.25 DIMM1.164
  L4 w0.089: 96.67,164.1 96.31,164.1 93.15,167.26 91.26,167.26 v3(90.7,167.83)
  L4 w0.127: v3(137.9,138.71) 138.03,138.58 138.03,138.26 137.9,138.14 137.33,138.14 136.76,137.57 125.63,137.57 114.18,149.02 114.18,149.2 114.73,149.76 114.73,149.94 114.53,150.14 114.36,150.14 113.79,149.57 113.63,149.57 113.41,149.79 113.41,149.95 113.98,150.51 113.98,150.69 113.78,150.89 102.72,161.95 100.27,161.95 98.12,164.1 96.67,164.1
  BOTTOM w0.102: v2(137.04,138.05) 137.12,138.05 137.78,138.71 v3(137.9,138.71)
M_DATA_A54: length 65.2
  TOP w0.102: v3(137.04,136.55) 137.19,136.55 137.44,136.31 139.34,136.31 DIMM1.174 ; CPU1.BE34 v3(92.83,165.92)
  L4 w0.127: v3(137.04,136.55) 137.04,136.01 136.53,135.5 131.66,135.5 131.44,135.72 131.12,135.72 130.9,135.5 130.59,135.5 130.37,135.72 130.06,135.72 129.84,135.5 129.52,135.5 129.3,135.72 128.99,135.72 128.77,135.5 128.46,135.5 128.24,135.72 127.92,135.72 127.7,135.5 125.17,135.5 124.92,135.75 124.92,135.75 111.23,149.44 109.77,150.9 108.31,152.35 108.31,152.35 107.04,153.62 107.04,153.8 107.56,154.32 107.56,154.5 107.36,154.7 107.18,154.7 106.67,154.18 106.49,154.18 106.29,154.38 106.29,154.56 106.84,155.11 106.84,155.29 101.96,160.16 99.53,160.16 96.75,162.94 96.28,162.94 95.47,163.75 94.79,163.75 92.83,165.71 v3(92.83,165.92)
  BOTTOM w0.102: v2(136.28,136.58) 136.3,136.55 v3(137.04,136.55)
M_DATA_A55: length 66.9
  TOP w0.102: v3(90.7,165.92) 90.28,165.5 CPU1.BA34 ; v3(136.53,133.81) 136.53,134.32 135.72,135.13 132.95,135.13 132.92,135.15 132.91,135.15 132.11,135.95 DIMM1.175
  L4 w0.127: v3(90.7,165.92) 91.81,164.8 94.65,162.18 96.19,161.18 119.7,137.67 120.79,136.8 121.86,135.94 124.6,133.73 125.76,133.29 135.54,133.29 v3(136.53,133.81)
  BOTTOM w0.102: v3(136.53,133.81) 136.53,133.45 v2(136.23,133.15)
M_DATA_A56: length 67
  TOP w0.089: 96.4,166.7 95.54,166.7 94.92,167.32 CPU1.BH37
  TOP w0.102: v3(98.26,167.08) 97.87,166.7 96.4,166.7 ; v3(133.21,133.76) 133.13,133.83 132.3,133.83 131.98,134.15 DIMM1.181
  L3 w0.127: v3(98.26,167.08) 98.63,167.46 99.87,167.46 103.89,163.44 103.89,162.36 103.91,162.34 103.91,162.28 104.35,161.85 104.35,161.67 103.99,161.32 103.99,161.14 104.19,160.94 104.37,160.94 104.72,161.29 104.9,161.29 105.1,161.09 105.1,160.91 104.75,160.56 104.75,160.38 104.95,160.18 105.13,160.18 105.48,160.54 105.66,160.54 105.85,160.34 105.85,160.16 105.5,159.81 105.5,159.63 105.7,159.43 105.88,159.43 106.23,159.78 106.41,159.78 119.43,146.77 119.43,146.59 119.35,146.51 119.35,146.33 119.55,146.13 119.73,146.13 119.8,146.21 119.98,146.21 120.18,146.01 120.18,145.83 120.1,145.75 120.1,145.57 120.3,145.38 120.48,145.38 120.56,145.45 120.74,145.45 120.94,145.26 120.94,145.08 120.86,145 120.86,144.82 121.06,144.62 121.24,144.62 121.31,144.7 121.49,144.7 121.69,144.5 121.69,144.32 121.61,144.25 121.61,144.07 121.81,143.87 121.99,143.87 122.07,143.95 122.25,143.95 122.45,143.75 122.45,143.57 122.37,143.49 122.37,143.31 122.56,143.11 122.74,143.11 122.82,143.19 123,143.19 123.2,142.99 123.2,142.81 123.12,142.74 123.12,142.56 123.32,142.36 123.5,142.36 123.58,142.44 123.76,142.44 123.95,142.24 123.95,142.06 123.88,141.98 123.88,141.8 124.07,141.6 124.25,141.6 124.33,141.68 124.51,141.68 124.71,141.49 124.71,141.31 124.63,141.23 124.63,141.05 124.83,140.85 125.01,140.85 125.09,140.93 125.27,140.93 125.46,140.73 125.46,140.55 125.39,140.47 125.39,140.29 125.58,140.1 125.76,140.1 125.84,140.17 126.02,140.17 126.22,139.98 126.22,139.8 126.14,139.72 126.14,139.54 126.34,139.34 126.52,139.34 126.59,139.42 126.77,139.42 126.97,139.22 126.97,139.04 126.89,138.96 126.89,138.78 127.09,138.59 127.27,138.59 127.35,138.66 127.53,138.66 127.73,138.47 127.73,138.29 127.65,138.21 127.65,138.03 127.85,137.83 128.03,137.83 128.1,137.91 128.28,137.91 128.48,137.71 128.48,137.53 128.4,137.46 128.4,137.28 128.6,137.08 128.78,137.08 128.86,137.16 129.04,137.16 129.23,136.96 129.23,136.78 129.16,136.7 129.16,136.52 129.35,136.32 129.53,136.32 129.61,136.4 129.79,136.4 132.44,133.76 v3(133.21,133.76)
  BOTTOM w0.102: v3(98.26,167.08) v2(98.26,166.33)
M_DATA_A57: length 65.9
  TOP w0.089: 94.68,165.99 94.68,165.99 94.47,166.2 94.16,166.2 94.15,166.19 93.98,166.07 93.68,166.07 CPU1.BG34
  TOP w0.102: DIMM1.194 138.23,130.25 v3(137.89,130.58) ; v3(98.05,165.02) 97.91,164.89 95.78,164.89 95.41,165.25 94.68,165.99
  L3 w0.127: v3(98.05,165.02) 98.05,165 97.59,164.54 97.59,164.08 98.25,160.28 98.25,159.5 127.29,130.46 129.5,130.46 130.45,129.51 133.39,129.51 133.48,129.6 136.91,129.6 v3(137.89,130.58)
  BOTTOM w0.102: v3(98.05,165.02) v2(98.05,164.31)
M_DATA_A58: length 66.5
  TOP w0.089: CPU1.BJ38 94.96,167.78 95.64,167.11 96.15,167.11 v3(96.33,167.29)
  TOP w0.102: v3(137.8,134.45) DIMM1.180
  L3 w0.127: v3(137.8,134.45) 136.83,134.45 136.7,134.58 136.7,135.06 136.58,135.19 136.3,135.19 136.17,135.06 136.17,134.58 136.04,134.45 135.76,134.45 135.64,134.58 135.64,135.06 135.51,135.19 135.23,135.19 135.1,135.06 135.1,134.58 134.98,134.45 134.7,134.45 134.57,134.58 134.57,135.06 134.44,135.19 134.16,135.19 134.04,135.06 134.04,134.58 133.91,134.45 133.63,134.45 133.5,134.58 133.5,135.06 133.38,135.19 133.1,135.19 132.97,135.06 132.97,134.58 132.84,134.45 132.5,134.45 127.42,139.53 127.42,139.53 126.86,140.09 126.66,140.29 126.66,140.46 126.92,140.72 126.92,140.9 126.72,141.1 126.54,141.1 126.29,140.84 126.11,140.84 104.45,162.5 104.45,162.62 104.43,162.64 104.43,163.66 102.99,165.1 100.41,167.68 96.72,167.68 v3(96.33,167.29)
  BOTTOM w0.102: v2(137.12,134.7) 137.73,134.52 v3(137.8,134.45)
M_DATA_A59: length 65.7
  TOP w0.089: v3(96.96,167.18) 96.67,166.9 96.54,166.9 95.59,166.9 95,167.5 94.17,167.5 94.01,167.62 93.85,167.78 CPU1.BG38
  TOP w0.102: DIMM1.183 132.15,133.55 132.17,133.53 132.52,133.53 132.88,133.17 132.93,133.17 132.98,133.12 133.08,133.12 v3(133.51,132.69)
  L3 w0.127: v3(133.51,132.69) 133.12,132.3 132.56,132.3 132.3,132.56 132.3,132.58 129.8,135.08 128.42,135.08 115.87,147.62 115.69,147.62 115.54,147.47 115.36,147.47 115.16,147.67 115.16,147.85 115.32,148 115.32,148.18 115.12,148.38 114.94,148.38 114.79,148.22 114.61,148.22 114.41,148.42 114.41,148.6 114.56,148.75 114.56,148.93 114.37,149.13 114.19,149.13 114.03,148.98 113.85,148.98 113.66,149.18 113.66,149.36 113.81,149.51 113.81,149.69 113.61,149.89 113.43,149.89 113.28,149.73 113.1,149.73 112.9,149.93 112.9,150.11 113.05,150.26 113.05,150.44 112.86,150.64 112.68,150.64 112.52,150.49 112.34,150.49 112.15,150.68 112.15,150.86 112.3,151.02 112.3,151.2 112.1,151.39 111.92,151.39 111.77,151.24 111.59,151.24 111.39,151.44 111.39,151.62 111.55,151.77 111.55,151.95 111.35,152.15 111.17,152.15 111.02,152 110.84,152 110.64,152.19 110.64,152.37 110.79,152.53 110.79,152.71 110.59,152.9 110.41,152.9 110.26,152.75 110.08,152.75 109.88,152.95 109.88,153.13 110.04,153.28 110.04,153.46 109.84,153.66 109.66,153.66 109.51,153.5 109.33,153.5 109.13,153.7 109.13,154.02 108.89,154.26 108.57,154.26 102.32,160.51 102.32,163.48 101.78,164.02 101.26,164.02 98.69,166.59 97.55,166.59 v3(96.96,167.18)
  BOTTOM w0.102: v3(96.96,167.18) v2(96.96,166.45)
M_DATA_A60: length 65.7
  TOP w0.089: 94.15,165.27 94.1,165.27 CPU1.BH33
  TOP w0.102: 94.15,165.27 94.15,165.28 94.47,165.28 96.29,163.46 100.12,163.46 v3(100.19,163.4) ; v3(133.63,130.66) 133.52,130.55 DIMM1.193
  L3 w0.127: v3(100.19,163.4) 100.28,163.3 100.28,159.73 102.49,157.52 102.5,157.52 118.09,141.94 118.27,141.94 118.55,142.22 118.73,142.22 118.92,142.02 118.92,141.84 118.65,141.56 118.65,141.38 118.84,141.18 119.02,141.18 119.3,141.46 119.48,141.46 119.68,141.26 119.68,141.08 119.4,140.81 119.4,140.63 119.6,140.43 119.78,140.43 120.05,140.71 120.23,140.71 120.43,140.51 120.43,140.33 120.15,140.05 120.15,139.87 120.35,139.68 120.53,139.68 120.81,139.95 120.99,139.95 121.19,139.76 121.19,139.58 120.91,139.3 120.91,139.12 121.11,138.92 121.29,138.92 121.56,139.2 121.74,139.2 121.94,139 121.94,138.82 121.66,138.54 121.66,138.36 121.86,138.17 122.04,138.17 122.32,138.44 122.5,138.44 122.7,138.25 122.7,138.07 122.42,137.79 122.42,137.61 122.62,137.41 122.8,137.41 123.07,137.69 123.25,137.69 127.66,133.29 129.07,133.29 131.45,130.9 133.39,130.9 v3(133.63,130.66)
  BOTTOM w0.102: v3(100.19,163.4) v2(100.75,163.96)
M_DATA_A61: length 68.8
  TOP w0.102: CPU1.BJ34 94.58,165.66 94.63,165.66 95.48,164.81 95.73,164.57 98.61,164.57 v3(98.74,164.69) ; v3(136.48,130.66) 136.61,130.66 136.96,131.01 138.26,131.01 138.42,130.85 DIMM1.192
  L3 w0.127: v3(136.48,130.66) 135.78,129.96 133.29,129.96 132.85,130.39 130.22,130.39 128.86,131.75 126.75,131.75 126.37,132.13 126.37,132.31 126.63,132.57 126.63,132.75 126.43,132.95 126.25,132.95 125.99,132.69 125.81,132.69 125.61,132.89 125.61,133.07 125.87,133.33 125.87,133.5 125.67,133.7 125.5,133.7 125.24,133.44 125.06,133.44 124.86,133.64 124.86,133.82 125.12,134.08 125.12,134.26 124.92,134.46 124.74,134.46 124.48,134.2 124.3,134.2 98.78,159.72 98.78,162.16 98.53,162.4 98.53,162.7 98.78,162.94 98.78,163.22 98.65,163.35 98.28,163.35 98.15,163.48 98.15,163.76 98.28,163.88 98.65,163.88 98.78,164.01 98.78,164.65 v3(98.74,164.69)
  BOTTOM w0.102: v2(99.99,164.97) 99.02,164.97 v3(98.74,164.69)
M_DATA_A62: length 66.4
  TOP w0.089: 94.22,165.61 94.03,165.75 93.79,165.75 93.56,165.56 93.26,165.56 CPU1.BG33
  TOP w0.102: DIMM1.191 134.46,131.15 134.96,130.66 v3(135.05,130.66) ; v3(99.75,163.86) 96.16,163.86 94.55,165.47 94.36,165.47 94.22,165.61
  L3 w0.127: v3(135.05,130.66) 134.61,130.21 133.39,130.21 132.96,130.65 130.82,130.65 129.16,132.31 127.83,132.31 124.83,135.31 124.65,135.31 124.38,135.05 124.2,135.05 124.01,135.25 124.01,135.43 124.27,135.69 124.27,135.87 124.07,136.07 123.89,136.07 123.63,135.81 123.45,135.81 123.25,136 123.25,136.18 123.51,136.45 123.51,136.63 123.32,136.82 123.14,136.82 122.88,136.56 122.7,136.56 99.75,159.51 v3(99.75,163.86)
  BOTTOM w0.102: v2(99.09,163.48) 99.47,163.86 v3(99.75,163.86)
M_DATA_A63: length 67
  TOP w0.089: 94.7,167.13 94.16,167.13 94.03,167.03 93.79,167.03 93.53,167.25 93.23,167.25 CPU1.BG37
  TOP w0.102: DIMM1.182 137.95,133.85 137.22,133.12 137.15,133.12 v3(137.14,133.11) ; v3(98.89,167.06) 98.34,166.51 95.47,166.51 94.85,167.13 94.7,167.13
  L3 w0.127: v3(98.89,167.06) 99.35,166.6 99.98,166.6 102.85,163.73 102.85,161.52 103.25,161.13 103.25,160.95 103.03,160.73 103.03,160.55 103.23,160.36 103.41,160.36 103.62,160.57 103.8,160.57 104,160.37 104,160.19 103.79,159.98 103.79,159.8 103.98,159.6 104.16,159.6 104.38,159.82 104.56,159.82 104.76,159.62 104.76,159.44 104.54,159.22 104.54,159.04 104.74,158.85 104.92,158.85 105.13,159.06 105.31,159.06 105.51,158.87 105.51,158.69 105.3,158.47 105.3,158.29 105.49,158.09 105.67,158.09 105.89,158.31 106.07,158.31 128.77,135.61 129.97,135.61 132.39,133.18 132.93,133.18 132.94,133.17 137.08,133.17 v3(137.14,133.11)
  BOTTOM w0.102: v2(99.46,166.08) 98.89,166.65 v3(98.89,167.06)
M_DQS_A_DN0: length 59.9
  TOP w0.089: CPU1.BC62 91.43,179.29 91.43,180.04 91.63,180.25 91.63,180.34 91.64,180.35 91.64,180.83 91.59,180.88 91.59,181.27 91.6,181.28 91.6,181.33 91.62,181.35 91.62,181.36
  TOP w0.102: 91.62,181.36 91.62,182.36 94.03,184.78 94.03,185.25 93.81,185.47 93.81,185.8 v3(93.85,185.83) ; v3(135.6,187.23) 135.95,187.58 135.95,187.89 136.26,188.2 137.16,188.2 137.51,187.85 DIMM1.10
  L4 w0.127: v3(135.6,187.23) 136.1,187.73 136.1,188.21 135.88,188.43 132.47,188.43 130.99,189.91 101.23,189.91 98.54,187.22 94.64,187.22 93.57,186.14 93.57,185.93 93.66,185.83 v3(93.85,185.83)
  BOTTOM w0.102: v2(94.7,185.58) 94.44,185.83 v3(93.85,185.83)
M_DQS_A_DN1: length 60.2
  TOP w0.102: DIMM1.27 132.17,182.75 132.43,183.01 132.66,183.01 132.66,183.01 133.11,183.01 133.11,183.01 134.08,183.01 134.27,182.82 134.27,182.37 v1(134.38,182.27) ; v3(88.62,176.93) CPU1.AT58
  L4 w0.089: v3(88.62,176.93) 89.18,177.5 89.18,178.8 89.57,179.19 91.85,179.19 92.14,179.47 92.25,179.47 92.29,179.44 92.31,179.44
  L4 w0.127: 92.31,179.44 93.35,179.44 96.69,182.78 103.98,182.78 104.33,183.12 104.67,183.12 105.02,182.78 105.58,182.78 105.93,183.12 106.27,183.12 106.62,182.78 107.18,182.78 107.53,183.12 107.87,183.12 108.22,182.78 108.79,182.78 109.13,183.12 109.47,183.12 109.82,182.78 110.39,182.78 110.73,183.12 111.07,183.12 111.42,182.78 111.99,182.78 112.33,183.12 112.68,183.12 113.02,182.78 122.1,182.78 122.42,183.1 123.18,183.1 123.31,182.98 123.31,182.63 123.59,182.35 124.32,182.35 124.61,182.63 124.61,182.98 124.73,183.1 125.24,183.1 125.37,182.98 125.37,182.63 125.65,182.35 126.38,182.35 126.66,182.63 126.66,182.98 126.79,183.1 127.3,183.1 127.43,182.98 127.43,182.63 127.71,182.35 128.44,182.35 128.72,182.63 128.72,182.98 128.85,183.1 130.8,183.1 132.37,181.53 133.49,181.53 133.82,181.53 134.11,181.81 134.11,181.82 134.21,181.92 134.21,182.1 v1(134.38,182.27)
  BOTTOM w0.102: v1(134.38,182.27) 134.38,181.73 v2(134.58,181.53)
M_DQS_A_DN2: length 72.7
  TOP w0.102: v3(133.94,177.32) 134.06,177.2 134.06,176.98 133.94,176.86 132.44,176.86 132.28,177.02 132.26,177.02 131.92,177.35 DIMM1.45 ; CPU1.BB58 91.41,177.57 v3(91.45,177.57)
  L3 w0.089: v3(91.45,177.57) 91.05,177.97 91.05,179.2 91.56,179.7
  L3 w0.127: v3(133.94,177.32) 133.94,177.07 133.77,176.9 131.83,176.9 131.61,177.12 131.61,178.44 131.27,178.78 130.4,178.78 130.07,179.1 130.07,179.28 130.49,179.69 130.49,180.09 129.97,180.61 129.57,180.61 129.16,180.19 128.98,180.19 128.62,180.55 128.62,180.73 128.77,180.89 128.77,181.29 128.26,181.81 127.86,181.81 127.7,181.65 127.52,181.65 127.16,182.01 127.16,182.41 126.47,183.11 126.07,183.11 125.71,183.47 125.71,183.65 125.86,183.8 125.86,184.2 125.35,184.72 125.35,184.72 119.23,190.83 117.23,190.83 99.86,190.83 99.15,190.11 99.15,189.71 99.64,189.22 99.64,189.04 99.46,188.86 99.28,188.86 98.79,189.35 98.39,189.35 98.05,189.02 98.05,188.62 98.55,188.12 98.55,187.94 98.36,187.76 98.19,187.76 97.69,188.26 97.29,188.26 96.95,187.92 96.95,187.52 97.44,187.03 97.44,186.85 97.26,186.67 97.08,186.67 96.59,187.16 96.19,187.16 95.86,186.82 95.86,186.45 92.38,182.97 91.16,182.97 90.88,182.69 90.88,181.67 91.16,181.39 91.43,181.39 91.57,181.24 91.57,180.08 91.56,180.07 91.56,179.7
  BOTTOM w0.102: v2(133.38,176.68) 133.89,177.24 v3(133.94,177.32)
M_DQS_A_DN3: length 61.3
  TOP w0.089: CPU1.BB52 v3(91.27,174.96)
  TOP w0.102: v3(136.51,171.63) 136.51,172.33 136.81,172.64 137.81,172.64 138.2,172.25 DIMM1.62
  L3 w0.089: 94.94,177.81 94.93,177.8 94.93,177.72 94.92,177.71 94.92,177.68 94.82,177.58 94.82,177.43 92.93,175.54 92.93,175.54 92.45,175.54 92.45,175.54 92.29,175.54 92.18,175.43 91.73,175.43 v3(91.27,174.96)
  L3 w0.127: v3(136.51,171.63) 136.51,171.46 136.22,171.17 135.39,171.17 134.39,172.17 127.85,172.17 114.71,185.31 114.61,185.31 101.93,185.31 97.1,180.48 97.1,179.97 95.27,178.14 94.94,177.81
  BOTTOM w0.102: v2(136.25,170.94) 136.25,171.37 v3(136.51,171.63)
M_DQS_A_DN4: length 67.7
  TOP w0.089: CPU1.AW39 v3(89.27,167.83)
  TOP w0.102: DIMM1.135 132.02,147.95 132.22,147.75 132.63,147.75 133.58,148.7 134.36,148.7 134.59,148.47 134.59,148.25 v3(134.88,147.96)
  L3 w0.127: v3(134.88,147.96) 134.75,147.83 134.75,147.24 134.18,146.67 131.57,146.67 131.03,146.12 126.07,146.12 114.91,157.28 114.73,157.28 114.52,157.08 114.12,157.08 113.61,157.6 113.61,158 113.81,158.2 113.81,158.38 113.27,158.92 113.09,158.92 112.81,158.64 112.41,158.64 111.89,159.15 111.89,159.55 112.18,159.83 112.18,160.01 111.82,160.37 111.64,160.37 111.35,160.09 110.95,160.09 110.44,160.61 110.44,161.01 110.72,161.29 110.72,161.47 110.36,161.83 110.18,161.83 109.9,161.55 109.5,161.55 108.98,162.06 108.98,162.46 109.26,162.75 109.26,162.93 108.9,163.29 108.72,163.29 108.44,163 108.04,163 107.35,163.7 107.35,164.84 106.9,165.28 103.36,168.82 94.44,168.82 93.86,168.25 89.7,168.25 v3(89.27,167.83)
  BOTTOM w0.102: v3(134.88,147.96) 134.88,147.32 v2(134.73,147.17)
M_DQS_A_DN5: length 62.4
  TOP w0.089: 96.81,169.74 96.42,169.35 94.15,169.35 94.11,169.4 94.08,169.42 93.81,169.64 CPU1.BG42
  TOP w0.102: DIMM1.152 138.65,142.85 138.42,142.62 136.84,142.62 136.19,141.97 v3(136.19,141.14) ; v3(96.89,169.82) 96.81,169.74
  L4 w0.127: v3(96.89,169.82) 97.2,170.13 101.79,170.13 102.29,169.63 102.29,168.74 120.93,150.1 121.04,149.99 121.34,149.69 121.74,149.69 121.91,149.87 122.09,149.87 122.45,149.51 122.45,149.33 122.27,149.16 122.27,148.76 122.79,148.24 123.19,148.24 123.45,148.5 123.63,148.5 124.09,148.04 124.17,147.96 130.05,142.09 135.87,142.09 136.29,141.67 136.29,141.24 v3(136.19,141.14)
  BOTTOM w0.102: v3(96.89,169.82) v2(96.89,168.94)
M_DQS_A_DN6: length 67.4
  TOP w0.089: CPU1.BD35 v3(92.12,166.87)
  TOP w0.102: v3(135.11,136.12) 135.11,137.14 134.76,137.49 132.42,137.49 132.16,137.75 DIMM1.169
  L4 w0.089: v3(92.12,166.87) 92.02,166.77 92.02,166.61 92.15,166.49 93.3,166.49 93.49,166.29 93.6,166.29
  L4 w0.127: 93.6,166.29 93.84,166.06 94.07,166.06 96.41,163.72 97.43,163.72 99.95,161.19 102.39,161.19 109.78,153.8 109.78,153.4 109.34,152.96 109.34,152.78 109.7,152.42 109.88,152.42 110.32,152.86 110.72,152.86 111.24,152.34 111.24,151.94 110.8,151.5 110.8,151.32 111.16,150.96 111.34,150.96 111.78,151.41 112.18,151.41 112.7,150.89 112.7,150.49 112.25,150.05 112.25,149.87 125.34,136.78 126.11,136.78 126.35,136.53 126.83,136.53 127.08,136.78 134.66,136.78 134.93,136.51 134.93,136.3 v3(135.11,136.12)
  BOTTOM w0.102: v3(135.11,136.12) 135.11,135.62 v2(135.32,135.41)
M_DQS_A_DN7: length 67.4
  TOP w0.089: v3(96.84,165.34) 96.62,165.13 95.8,165.13 95.6,165.33 95.19,165.73 95.05,165.88 95.02,165.91 94.84,166.08 94.69,166.24 94.69,166.24 94.55,166.38 94.11,166.38 94.09,166.39 CPU1.BH35
  TOP w0.102: DIMM1.186 138.38,132.65 138.26,132.53 136.78,132.53 136.54,132.29 136.54,132.04 v3(136.3,131.8)
  L3 w0.127: v3(96.84,165.34) 96.64,165.54 96.64,165.91 96.76,166.03 98.34,166.03 100.97,163.4 100.97,163.38 101.29,163.06 101.29,159.85 115.03,146.11 115.43,146.11 115.58,146.26 115.76,146.26 116.12,145.9 116.12,145.72 115.97,145.57 115.97,145.17 116.49,144.66 116.89,144.66 117.04,144.81 117.21,144.81 117.57,144.45 117.57,144.27 117.43,144.12 117.43,143.72 117.94,143.2 118.34,143.2 118.49,143.35 118.67,143.35 127.97,134.05 129.39,134.05 131.74,131.7 134.67,131.7 135.35,132.37 136.51,132.37 136.63,132.25 136.63,132.01 136.43,131.8 v3(136.3,131.8)
  BOTTOM w0.102: v3(96.84,165.34) v2(96.84,164.54)
M_DQS_A_DP0: length 59.7
  TOP w0.089: CPU1.BB63 91.23,179.96 91.23,180.12 91.44,180.33 91.44,180.42 91.45,180.43 91.45,180.75 91.4,180.8 91.4,181.36
  TOP w0.102: v3(93.3,185.31) 93.31,185.31 93.67,185.31 93.82,185.16 93.82,184.87 91.4,182.45 91.4,181.36 ; DIMM1.12 138.54,187.25 138.16,187.63 137.42,187.63 137.07,187.98 136.35,187.98 136.17,187.8 136.17,187.39 v3(136.37,187.19)
  L4 w0.127: v3(136.37,187.19) 136.37,188.32 135.99,188.7 132.58,188.7 131.1,190.18 101.12,190.18 98.43,187.49 94.53,187.49 93.3,186.25 v3(93.3,185.31)
  BOTTOM w0.102: v3(93.3,185.31) 93.3,184.74 v2(93.43,184.61)
M_DQS_A_DP1: length 60.1
  TOP w0.102: DIMM1.29 131.89,182.15 132.28,182.54 132.28,182.56 132.52,182.8 133.15,182.8 133.16,182.8 133.99,182.8 134.06,182.73 134.06,182.59 133.76,182.29 v1(133.62,182.29) ; CPU1.AT59 88.14,177.72 88.35,177.51 88.49,177.51 88.62,177.64 v3(88.62,177.64)
  L4 w0.089: 92.31,179.7 92.29,179.7 92.25,179.66 92.06,179.66 91.77,179.38 89.65,179.38 89.65,179.38 89.49,179.38 89.01,178.89 89.01,177.64 88.88,177.51 88.75,177.51 v3(88.62,177.64)
  L4 w0.127: v1(133.62,182.29) 133.82,182.29 133.91,182.2 133.91,182 133.84,181.93 133.84,181.92 133.71,181.8 132.48,181.8 130.91,183.37 128.74,183.37 128.45,183.09 128.45,182.75 128.33,182.62 127.82,182.62 127.69,182.75 127.69,183.09 127.41,183.37 126.68,183.37 126.4,183.09 126.4,182.75 126.27,182.62 125.76,182.62 125.63,182.75 125.63,183.09 125.35,183.37 124.62,183.37 124.34,183.09 124.34,182.75 124.21,182.62 123.7,182.62 123.58,182.75 123.58,183.09 123.29,183.37 122.31,183.37 121.99,183.05 113.13,183.05 112.79,183.39 112.22,183.39 111.88,183.05 111.53,183.05 111.19,183.39 110.62,183.39 110.27,183.05 109.93,183.05 109.59,183.39 109.02,183.39 108.67,183.05 108.33,183.05 107.99,183.39 107.42,183.39 107.07,183.05 106.73,183.05 106.38,183.39 105.82,183.39 105.47,183.05 105.13,183.05 104.78,183.39 104.22,183.39 103.87,183.05 96.58,183.05 93.24,179.7 92.31,179.7
  BOTTOM w0.102: v1(133.62,182.29) 133.51,182.04 v2(133.26,181.61)
M_DQS_A_DP2: length 72.6
  TOP w0.102: v3(91.47,178.31) 91.45,178.31 CPU1.BB59 ; v3(134.7,177.29) 134.07,176.66 134.04,176.66 134.03,176.64 132.19,176.64 132.08,176.75 DIMM1.47
  L3 w0.089: 91.83,179.7 91.83,179.69 91.77,179.63 91.77,179.62 91.65,179.49 91.62,179.49 91.24,179.12 91.24,178.41 91.34,178.31 v3(91.47,178.31)
  L3 w0.127: v3(134.7,177.29) 134.04,176.63 131.72,176.63 131.34,177.01 131.34,178.33 131.16,178.51 130.29,178.51 129.81,178.99 129.81,179.39 130.22,179.8 130.22,179.98 129.86,180.34 129.68,180.34 129.27,179.93 128.87,179.93 128.35,180.44 128.35,180.84 128.51,181 128.51,181.18 128.15,181.54 127.97,181.54 127.81,181.38 127.41,181.38 126.9,181.9 126.9,182.3 126.36,182.84 125.96,182.84 125.44,183.35 125.44,183.76 125.6,183.91 125.6,184.09 125.12,184.57 119.12,190.56 117.12,190.56 99.97,190.56 99.41,190 99.41,189.82 99.91,189.33 99.91,188.93 99.57,188.59 99.17,188.59 98.68,189.09 98.5,189.09 98.32,188.91 98.32,188.73 98.81,188.23 98.81,187.83 98.48,187.5 98.07,187.5 97.58,187.99 97.4,187.99 97.22,187.81 97.22,187.63 97.71,187.14 97.71,186.74 97.37,186.41 96.97,186.41 96.48,186.89 96.3,186.89 96.12,186.71 96.12,186.34 92.49,182.7 91.27,182.7 91.15,182.58 91.15,181.78 91.27,181.65 91.54,181.65 91.84,181.35 91.84,179.97 91.83,179.96 91.83,179.7
  BOTTOM w0.102: v2(135.11,176.63) 134.7,177.24 v3(134.7,177.29)
M_DQS_A_DP3: length 61.3
  TOP w0.089: CPU1.BD52 v3(91.98,174.96)
  TOP w0.102: v3(137.22,171.58) 137.19,171.58 136.72,172.05 136.72,172.24 136.9,172.42 137.72,172.42 138.09,172.05 138.09,172.05 138.49,171.65 DIMM1.64
  L3 w0.089: 95.13,177.62 95.01,177.5 95.01,177.35 93.01,175.35 92.85,175.35 92.85,175.35 92.53,175.35 92.53,175.35 92.37,175.35 92.26,175.24 92.25,175.24 v3(91.98,174.96)
  L3 w0.127: 95.13,177.62 95.46,177.95 97.37,179.86 97.37,180.37 102.04,185.04 113.42,185.04 114.6,185.04 127.73,171.91 134.28,171.91 135.28,170.9 136.54,170.9 v3(137.22,171.58)
  BOTTOM w0.102: v3(137.22,171.58) 137.52,171.28 v2(137.52,170.89)
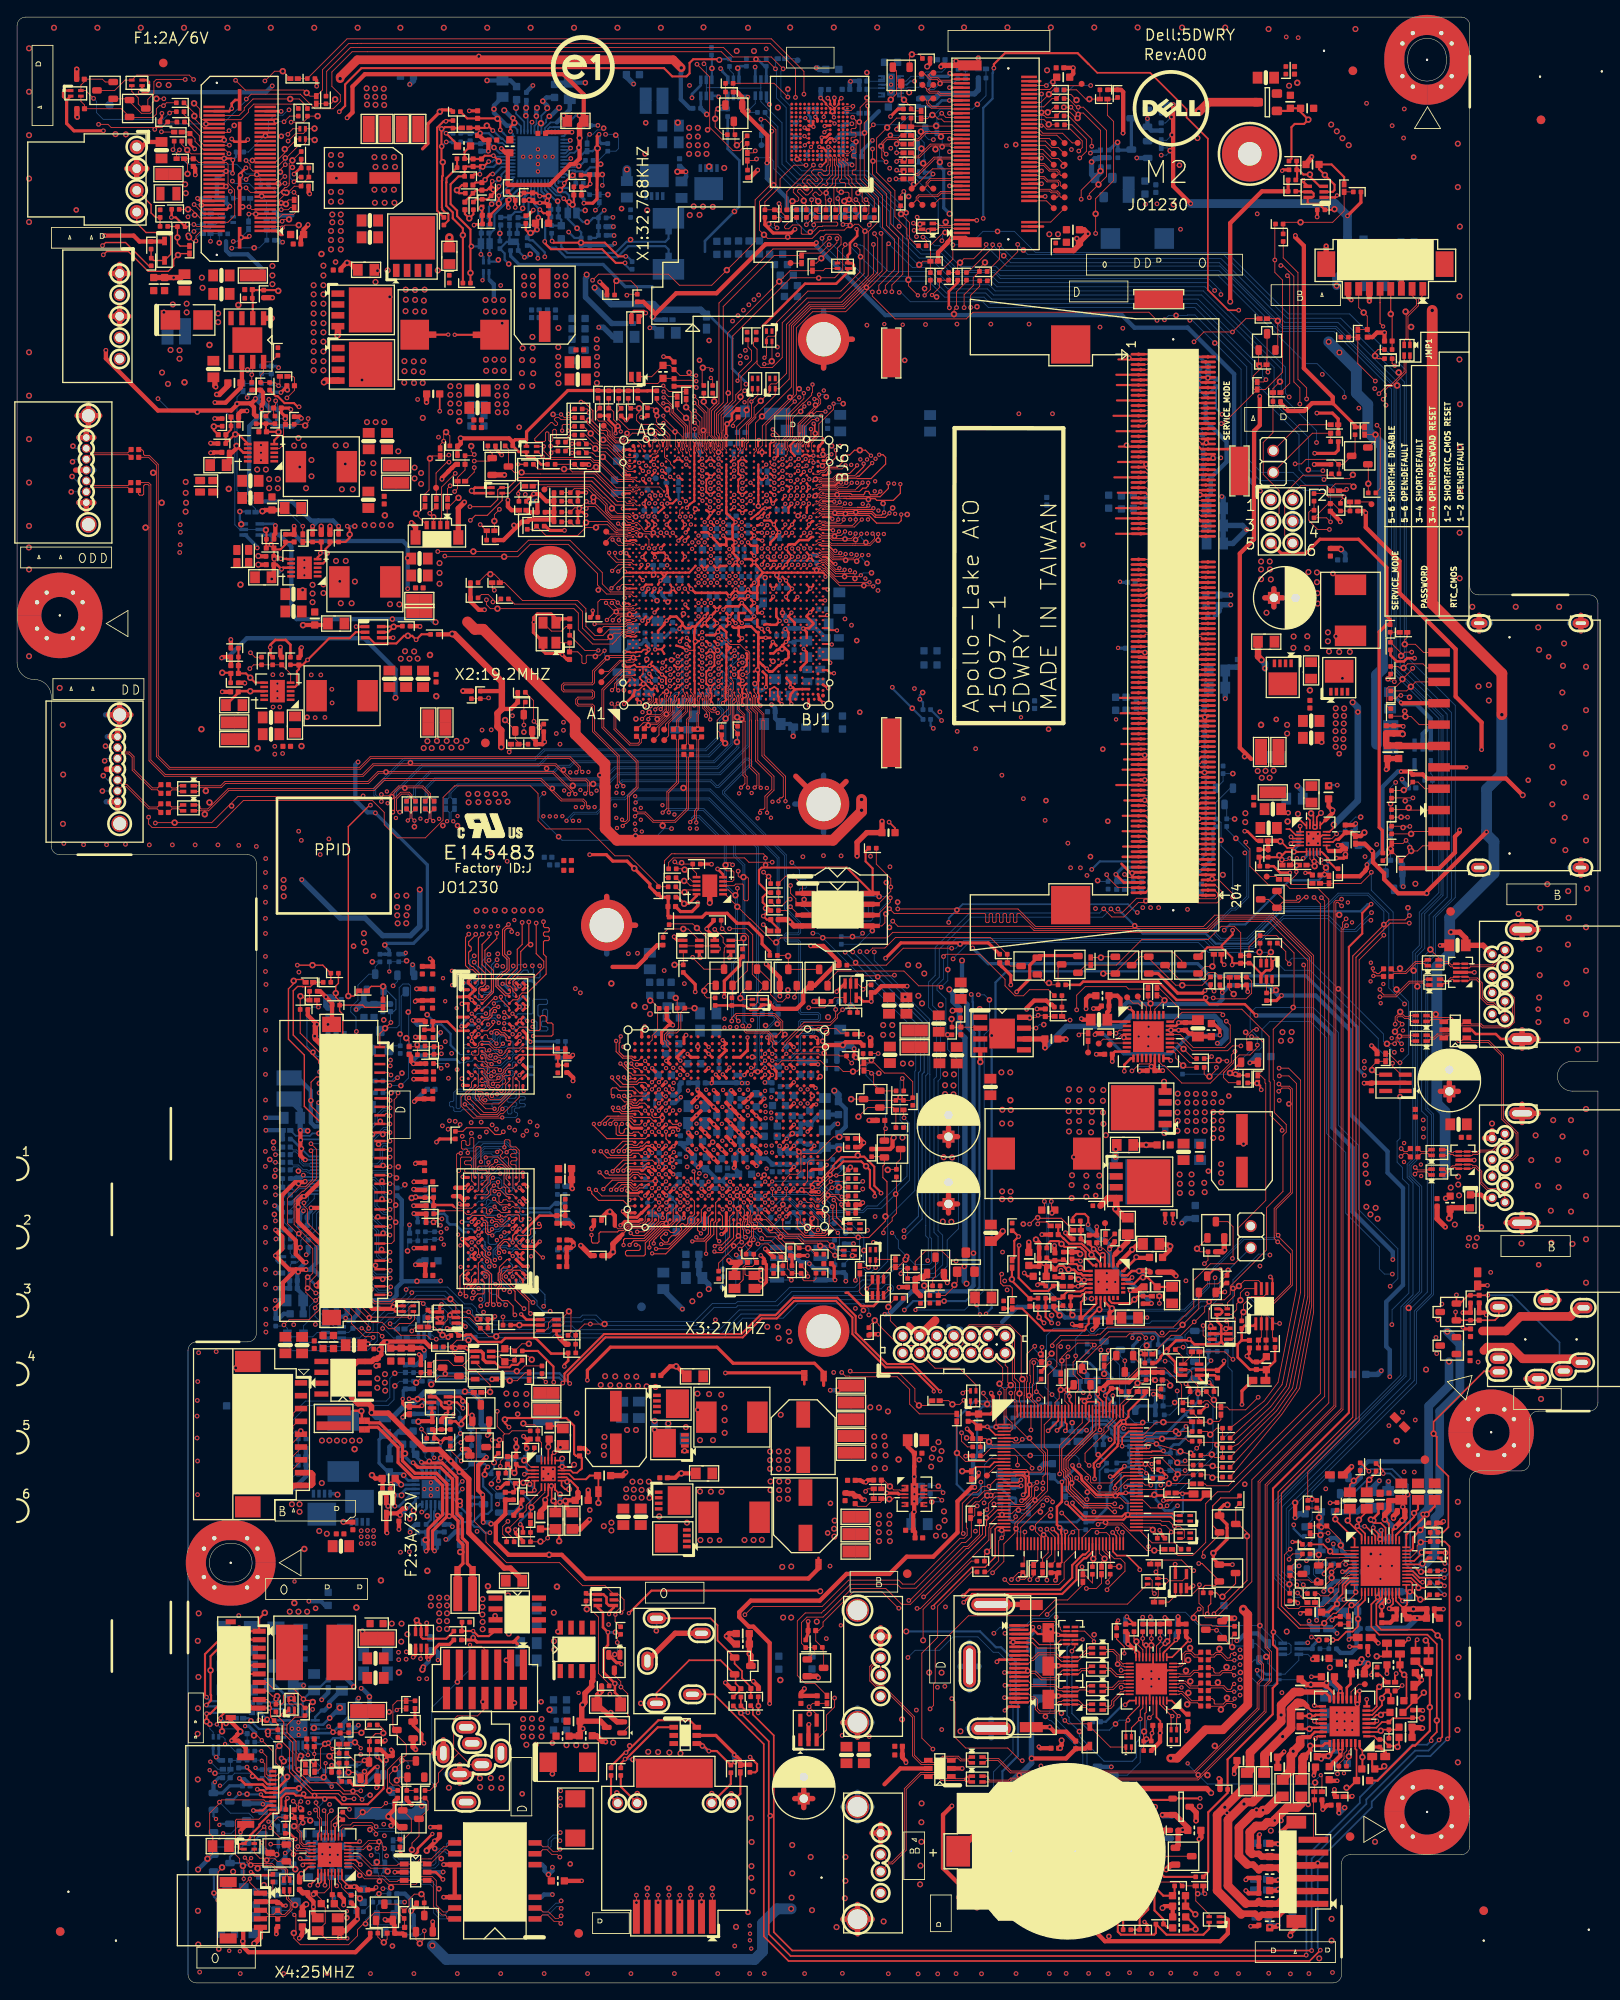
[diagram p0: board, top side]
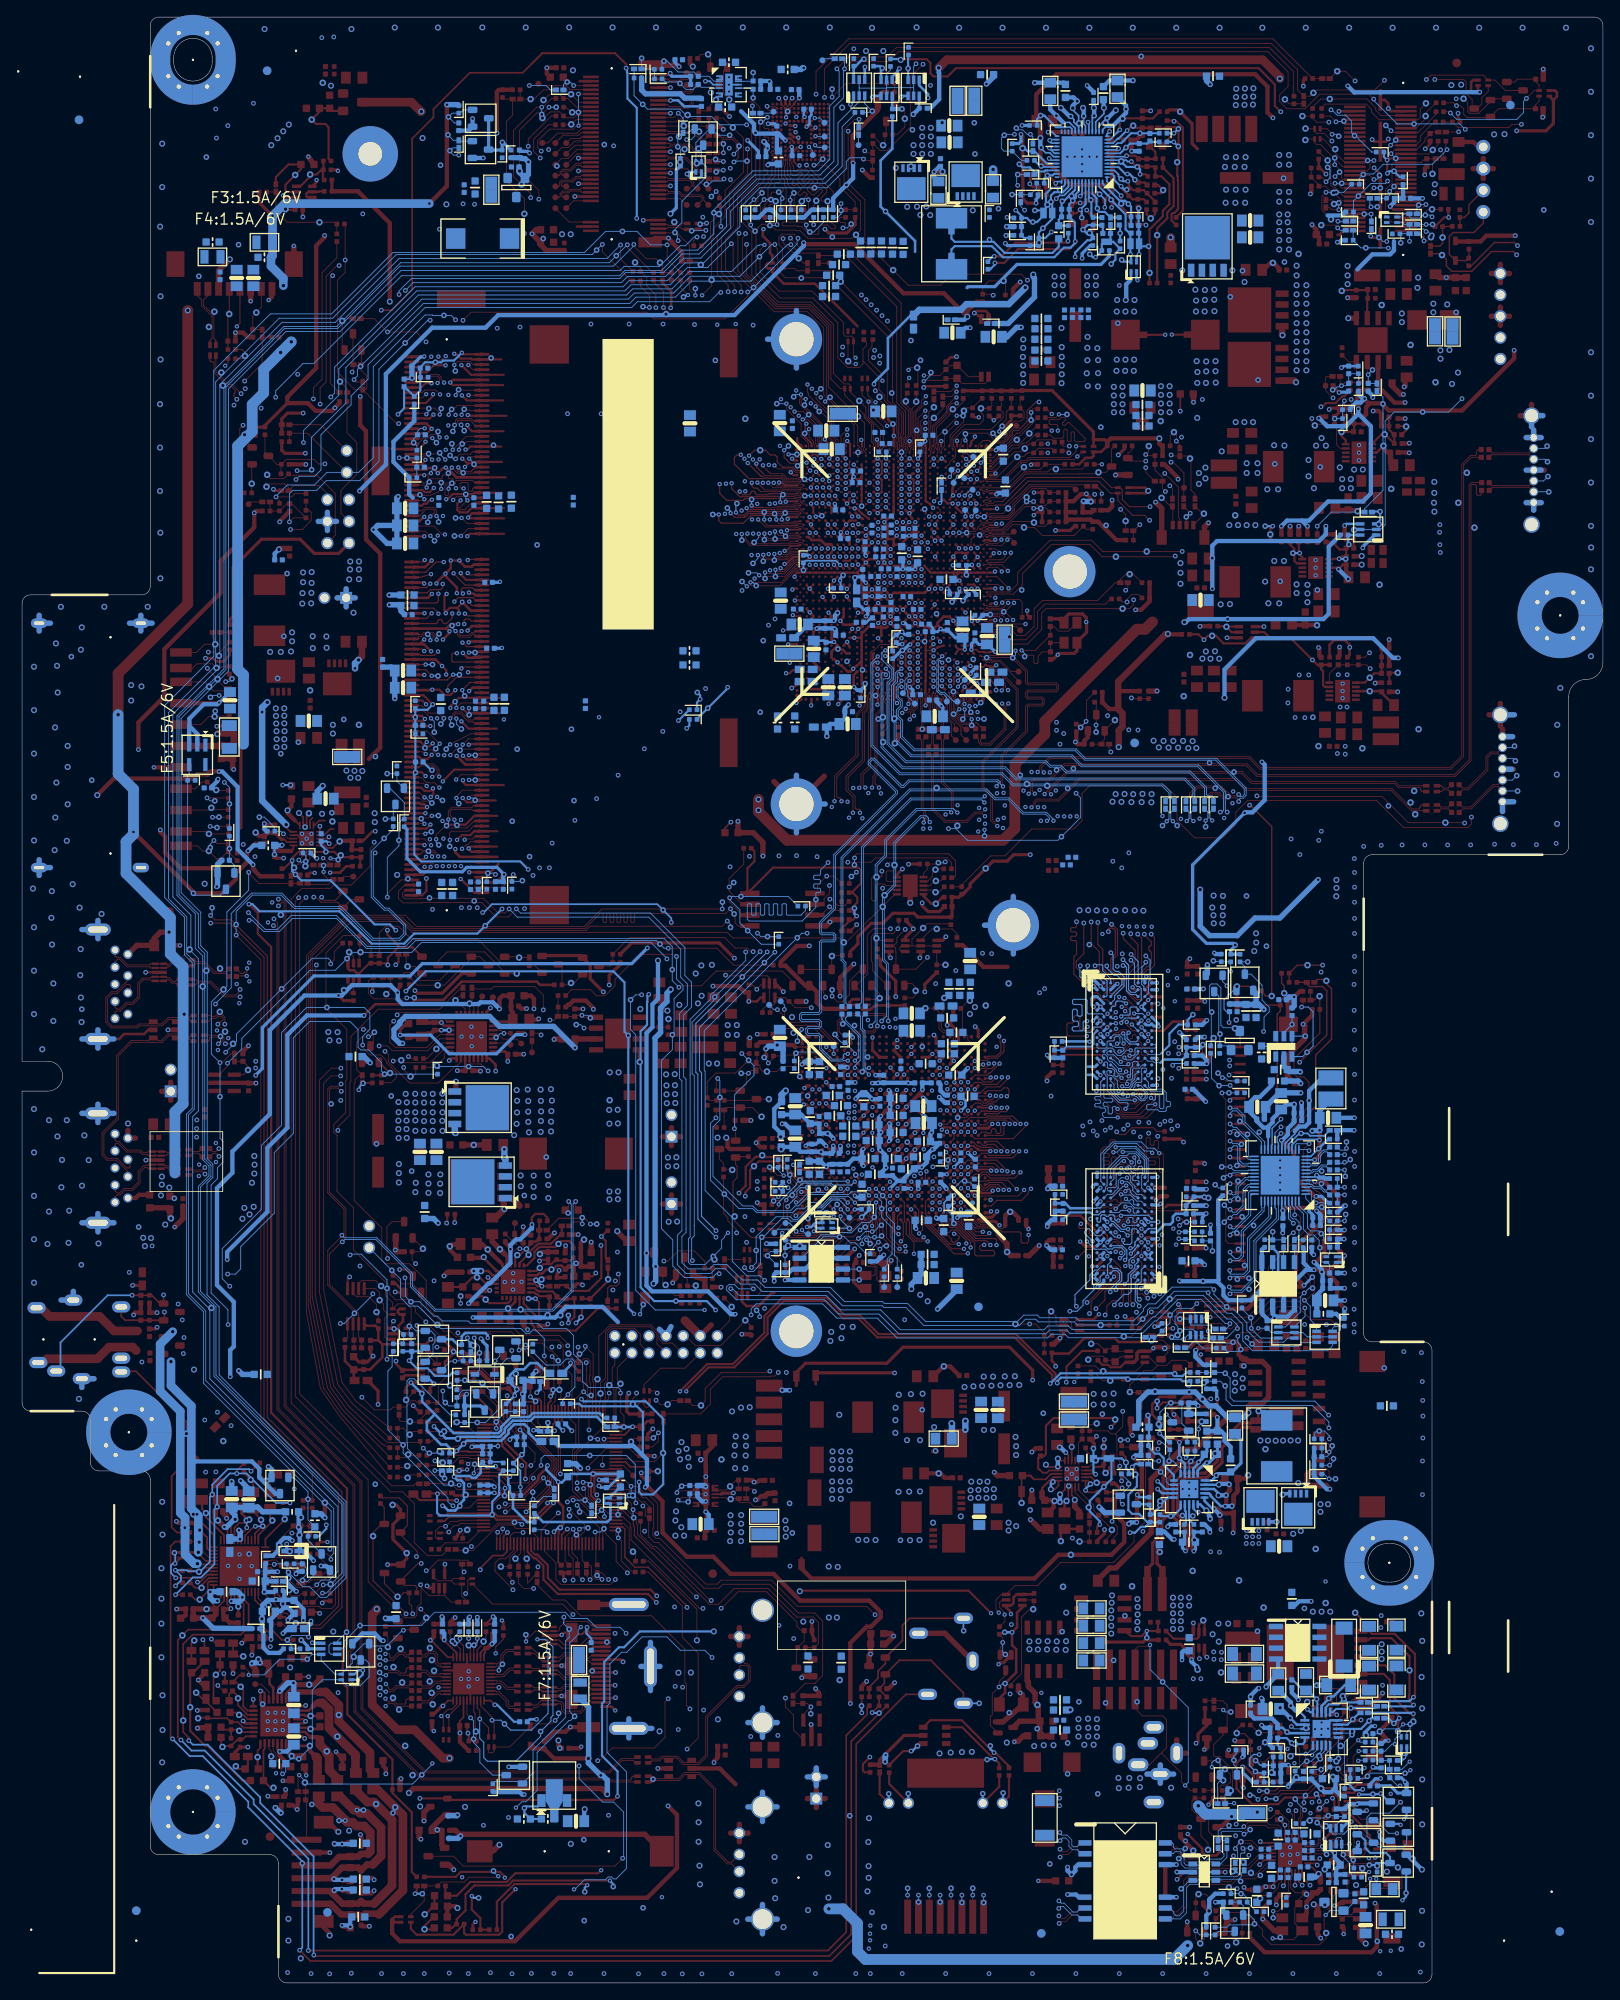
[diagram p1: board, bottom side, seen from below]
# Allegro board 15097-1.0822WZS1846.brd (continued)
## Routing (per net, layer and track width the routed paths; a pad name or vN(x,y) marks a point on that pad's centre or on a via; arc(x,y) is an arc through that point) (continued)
M_DQS_A_DP4: length 68.4
  TOP w0.089: CPU1.AV39 v3(88.56,167.83)
  TOP w0.102: DIMM1.137 132.04,147.35 132.22,147.53 132.72,147.53 133.67,148.48 134.27,148.48 134.37,148.38 134.37,148.08 134.21,147.92 v3(134.17,147.92)
  L3 w0.127: v3(88.56,167.83) 89.25,168.52 93.75,168.52 94.33,169.09 103.47,169.09 107.01,165.55 107.61,164.95 107.61,163.81 108.15,163.27 108.33,163.27 108.61,163.55 109.01,163.55 109.53,163.04 109.53,162.64 109.25,162.35 109.25,162.17 109.61,161.81 109.79,161.81 110.07,162.1 110.47,162.1 110.99,161.58 110.99,161.18 110.7,160.9 110.7,160.72 111.06,160.36 111.24,160.36 111.53,160.64 111.93,160.64 112.44,160.12 112.44,159.72 112.16,159.44 112.16,159.26 112.52,158.9 112.7,158.9 112.98,159.19 113.38,159.19 114.08,158.49 114.08,158.09 113.87,157.89 113.87,157.71 114.23,157.35 114.41,157.35 114.62,157.55 115.02,157.55 126.18,146.39 130.92,146.39 131.46,146.94 134.07,146.94 134.49,147.35 134.49,147.6 v3(134.17,147.92)
  BOTTOM w0.102: v3(134.17,147.92) 134.17,147.29 v2(133.59,146.71)
M_DQS_A_DP5: length 62.2
  TOP w0.089: CPU1.BJ42 94.4,169.54 95.9,169.54 96.13,169.78
  TOP w0.102: DIMM1.154 138.52,142.25 138.36,142.41 136.93,142.41 136.41,141.88 136.41,141.53 136.84,141.1 v3(137.01,141.1) ; 96.13,169.78 v3(96.18,169.82)
  L4 w0.127: v3(137.01,141.1) 136.86,141.1 136.56,141.41 136.56,141.78 135.98,142.35 130.16,142.35 124.28,148.23 123.74,148.77 123.34,148.77 123.08,148.51 122.9,148.51 122.54,148.87 122.54,149.05 122.72,149.22 122.72,149.62 122.2,150.14 121.8,150.14 121.62,149.96 121.45,149.96 102.56,168.85 102.56,169.74 101.9,170.4 96.75,170.4 v3(96.18,169.82)
  BOTTOM w0.102: v2(95.66,169.26) 95.66,169.31 96.17,169.82 v3(96.18,169.82)
M_DQS_A_DP6: length 67.4
  TOP w0.089: CPU1.BB35 v3(91.41,166.87)
  TOP w0.102: DIMM1.171 132.23,137.15 132.35,137.27 134.67,137.27 134.89,137.05 134.89,136.59 v3(134.4,136.09)
  L4 w0.089: 93.41,166.11 93.21,166.31 91.97,166.31 v3(91.41,166.87)
  L4 w0.127: 93.41,166.11 93.73,165.79 93.96,165.79 96.3,163.45 97.32,163.45 99.84,160.92 102.28,160.92 109.51,153.69 109.51,153.51 109.08,153.07 109.08,152.67 109.59,152.15 109.99,152.15 110.43,152.59 110.61,152.59 110.97,152.23 110.97,152.05 110.53,151.61 110.53,151.21 111.05,150.7 111.45,150.7 111.89,151.14 112.07,151.14 112.43,150.78 112.43,150.6 111.99,150.16 111.99,149.76 125.23,136.51 125.99,136.51 126.24,136.26 126.94,136.26 127.19,136.51 134.55,136.51 134.67,136.4 134.67,136.21 134.55,136.09 v3(134.4,136.09)
  BOTTOM w0.102: v3(134.4,136.09) 134.4,135.74 v2(134.1,135.45)
M_DQS_A_DP7: length 67.5
  TOP w0.089: CPU1.BG36 93.55,166.84 93.82,166.84 94.17,166.57 94.62,166.57 94.77,166.43 94.77,166.43 94.98,166.22 95.13,166.07 95.18,166.02 95.33,165.87 95.82,165.38 96.09,165.38 v3(96.23,165.52)
  TOP w0.102: DIMM1.188 138.39,132.05 138.13,132.32 136.87,132.32 136.76,132.2 136.76,132.03 v3(137.02,131.78)
  L3 w0.127: v3(96.23,165.52) 96.37,165.66 96.37,166.02 96.65,166.3 98.45,166.3 101.24,163.51 101.24,163.49 101.56,163.17 101.56,159.96 115.14,146.38 115.32,146.38 115.47,146.53 115.87,146.53 116.39,146.01 116.39,145.61 116.24,145.46 116.24,145.28 116.6,144.92 116.78,144.92 116.92,145.07 117.32,145.07 117.84,144.56 117.84,144.16 117.69,144.01 117.69,143.83 118.05,143.47 118.23,143.47 118.38,143.62 118.78,143.62 128.08,134.32 129.5,134.32 131.85,131.97 134.56,131.97 135.24,132.64 136.62,132.64 136.9,132.36 136.9,131.89 v3(137.02,131.78)
  BOTTOM w0.102: v2(137.45,132.41) 137.45,132.36 137.02,131.93 v3(137.02,131.78)
M_MAA_A0: length 56.2
  TOP w0.089: CPU1.BG50 93.84,173.34 93.85,173.36 93.98,173.48 94.17,173.63 94.66,173.63 94.72,173.69 96.73,173.69
  TOP w0.14: 96.73,173.69 97.05,173.69 97.09,173.65 100.41,173.65 100.6,173.46 102.54,173.46 103.36,174.28 v3(103.36,175.36) ; v3(134.65,160.22) 134.65,159.72 135.32,159.05 135.66,159.05 135.8,159.19 135.8,159.36 135.94,159.5 136.22,159.5 136.36,159.36 136.36,159.19 136.5,159.05 DIMM1.98
  L3 w0.191: v3(134.65,160.22) 134.65,160.51 134.46,160.7 132.18,160.7 131.64,160.17 125.11,160.17 124.12,161.15 124.12,161.42 124.15,161.45 124.15,161.72 123.88,161.98 123.61,161.98 123.58,161.96 123.32,161.96 109.91,175.37 108.17,175.37 108.14,175.4 103.4,175.4 v3(103.36,175.36)
M_MAA_A1: length 57.2
  TOP w0.089: CPU1.BG51 93.44,173.81 93.79,174.09 94.03,174.09 94.16,174 94.51,174 94.61,174.09 96.1,174.09 96.26,174.26
  TOP w0.14: DIMM1.97 132.43,159.35 132.65,159.57 133.11,159.57 133.26,159.41 133.26,158.99 v3(133.26,158.98) ; v3(101.02,174.5) 100.64,174.11 99.87,174.11 99.73,174.25 99.73,174.39 99.61,174.51 99.31,174.51 99.19,174.39 99.19,174.25 99.05,174.11 97.7,174.11 97.55,174.26 96.26,174.26
  L3 w0.191: v3(133.26,158.98) 133.23,158.95 132.72,158.95 132.13,158.36 130.95,158.36 130.76,158.17 130.76,157.49 130.56,157.29 130.2,157.29 130,157.49 130,158.17 129.81,158.36 129.43,158.36 129.24,158.17 129.24,157.51 129.03,157.3 128.68,157.3 128.47,157.51 128.47,158.17 128.28,158.36 127.9,158.36 127.71,158.17 127.71,157.55 127.51,157.34 127.15,157.34 126.95,157.55 126.95,158.17 126.76,158.36 126.38,158.36 126.19,158.17 126.19,157.5 125.99,157.29 125.63,157.29 125.43,157.5 125.43,158.17 125.24,158.36 124.26,158.36 108.45,174.17 101.56,174.17 101.23,174.5 v3(101.02,174.5)
M_MAA_A2: length 56.5
  TOP w0.089: CPU1.BH51 94.57,173.81 94.68,173.91 96.45,173.91 96.48,173.94
  TOP w0.14: DIMM1.96 137.66,159.65 v3(137.06,160.24) ; 96.48,173.94 97.42,173.94 97.47,173.88 100.99,173.88 101.96,174.85 v3(101.96,175.46)
  L3 w0.191: v3(137.06,160.24) 137.58,160.76 137.58,161.79 137.45,161.91 136.85,161.91 136.72,161.79 136.72,161.2 136.59,161.07 131.96,161.07 131.65,160.76 125.95,160.76 123.86,162.85 123.29,162.85 110.17,175.96 108.41,175.96 108.38,176 102.5,176 v3(101.96,175.46)
M_MAA_A3: length 56.8
  TOP w0.14: v3(92.12,169.67) 91.7,169.25 CPU1.BD41 ; DIMM1.95 132.81,159.95 133.06,160.2 v3(133.18,160.2)
  L3 w0.191: v3(133.18,160.2) 132.38,160.2 131.75,159.57 124.84,159.57 109.64,174.77 108.91,174.77 108.88,174.8 101.99,174.8 101.55,175.24 100.07,175.24 99.25,174.43 95.74,174.43 93.7,172.39 91.64,172.39 91.64,172.4 90.86,172.4 90.65,172.19 90.65,171.36 90.86,171.15 91.51,171.15 92.12,170.55 v3(92.12,169.67)
M_MAA_A4: length 57.4
  TOP w0.14: DIMM1.92 136.85,160.85 136.28,160.27 v3(136.28,160.2) ; v3(92.83,169.67) 92.41,169.25 CPU1.BE41
  L3 w0.191: v3(92.83,169.67) 92.83,169.78 95.12,173.41 95.85,174.15 99.37,174.15 100.18,174.96 101.4,174.96 101.87,174.49 109.06,174.49 124.58,158.97 124.6,158.97 125.09,158.97 131.83,158.97 132.52,159.66 135.59,159.66 136.13,160.2 v3(136.28,160.2)
M_MAA_A5: length 54.7
  TOP w0.089: 98.59,174.5 96.15,174.5 95.93,174.28 94.32,174.28 CPU1.BJ52
  TOP w0.14: DIMM1.91 132.33,161.15 132.66,161.48 v3(132.66,161.62) ; v3(99.6,175.51) 99.6,175.16 99.34,174.89 98.98,174.89 98.59,174.5
  L3 w0.191: v3(132.66,161.62) 132.43,161.39 131.65,161.39 131.46,161.58 131.46,162.21 131.33,162.33 130.82,162.33 130.7,162.21 130.7,161.58 130.51,161.39 126.17,161.39 125.6,161.95 125.6,162.03 124.97,162.66 124.96,162.66 124.12,163.5 123.85,163.5 123.8,163.45 123.53,163.45 123.26,163.72 123.26,163.99 123.31,164.04 123.31,164.31 123.04,164.58 122.78,164.58 122.73,164.53 122.46,164.53 122.19,164.8 122.19,165.07 122.24,165.12 122.24,165.39 121.97,165.66 121.7,165.66 121.65,165.61 121.38,165.61 121.11,165.88 121.11,166.14 121.16,166.19 121.16,166.46 120.89,166.73 120.62,166.73 120.57,166.68 120.3,166.68 120.03,166.95 120.03,167.22 120.08,167.27 120.08,167.54 119.81,167.81 119.54,167.81 119.49,167.76 119.22,167.76 118.95,168.03 118.95,168.3 119,168.35 119,168.62 118.73,168.89 118.46,168.89 118.41,168.84 118.14,168.84 117.87,169.11 117.87,169.38 117.92,169.43 117.92,169.7 117.66,169.97 117.39,169.97 117.34,169.92 117.07,169.92 116.8,170.19 116.8,170.46 116.85,170.51 116.85,170.78 116.58,171.05 116.31,171.05 116.26,171 115.99,171 115.72,171.27 115.72,171.53 115.77,171.58 115.77,171.85 115.5,172.12 115.23,172.12 115.18,172.07 114.91,172.07 114.64,172.34 114.64,172.61 114.69,172.66 114.69,172.93 114.42,173.2 114.15,173.2 114.1,173.15 113.83,173.15 113.56,173.42 113.56,173.69 113.61,173.74 113.61,174.01 113.34,174.28 113.07,174.28 113.02,174.23 112.75,174.23 112.48,174.5 112.48,174.77 112.53,174.82 112.53,175.09 112.27,175.36 112,175.36 111.95,175.31 111.68,175.31 111.41,175.58 111.41,175.85 111.46,175.9 111.46,176.17 111.06,176.56 108.66,176.56 108.63,176.59 101.85,176.59 101.63,176.38 101.62,176.38 101.38,176.14 100.23,176.14 v3(99.6,175.51)
M_MAA_A6: length 55.9
  TOP w0.089: CPU1.BG53 93.27,174.85 93.58,174.85 93.79,175.02 94.03,175.02 94.16,174.92 95.82,174.92 96.05,175.15 96.64,175.15 97,175.51 v3(97.04,175.51)
  TOP w0.14: v3(136.28,162.53) 136.28,161.67 136.5,161.45 DIMM1.90
  L3 w0.191: v3(136.28,162.53) 136.24,162.53 135.26,163.51 131.8,163.51 130.88,164.43 128.55,164.43 128.21,164.09 127.79,164.09 127.45,164.43 127.03,164.43 126.69,164.09 126.27,164.09 125.9,164.45 125.7,164.45 111.8,178.35 109.4,178.35 109.37,178.38 102.44,178.38 101.03,176.98 98.91,176.98 98.16,176.23 97.75,176.23 v3(97.04,175.51)
M_MAA_A7: length 55.2
  TOP w0.089: CPU1.BG55 93.44,175.66 93.79,175.95 94.03,175.95 94.05,175.93 94.14,175.85 95.5,175.85 96.02,176.36 98.03,176.36 98.23,176.56
  TOP w0.14: 98.23,176.56 99.07,177.39 v3(99.07,177.75) ; DIMM1.86 137.58,162.65 137.21,163.02 136.02,163.02 135.77,163.27 v3(135.77,163.68)
  L3 w0.191: v3(135.77,163.68) 135.62,163.83 131.94,163.83 130.75,165.02 126.71,165.02 126.68,165.05 125.95,165.05 112.05,178.95 109.65,178.95 109.62,178.98 102.62,178.98 100.99,177.35 99.47,177.35 v3(99.07,177.75)
M_MAA_A8: length 56.2
  TOP w0.089: v3(97.67,175.52) 97.13,174.97 96.12,174.97 95.88,174.73 CPU1.BH53
  TOP w0.14: v3(134.4,161.62) 133.94,162.08 132.21,162.08 131.88,161.75 DIMM1.89
  L3 w0.191: v3(134.4,161.62) 134.4,161.54 134.53,161.41 135.97,161.41 136.1,161.54 136.1,161.9 135.97,162.03 135.24,162.03 135.12,162.03 134.84,162.31 134.84,163.02 134.71,163.14 131.65,163.14 131.33,163.46 125.86,163.46 125.47,163.86 125.46,163.86 111.56,177.76 109.16,177.76 109.13,177.79 102.24,177.79 101.15,176.7 99.02,176.7 98.27,175.95 98.11,175.95 v3(97.67,175.52)
M_MAA_A9: length 54.3
  TOP w0.089: 98.27,174.87 98.08,174.68 96.08,174.68 95.96,174.56 94.17,174.56 93.98,174.41 93.85,174.28 93.84,174.27 CPU1.BG52
  TOP w0.14: DIMM1.85 132,162.95 132.27,163.22 133.39,163.22 133.6,163.01 133.6,162.75 v3(133.41,162.56) ; v3(98.94,175.54) 98.27,174.87
  L3 w0.191: v3(98.94,175.54) 99.01,175.54 99.89,176.42 101.26,176.42 101.5,176.66 101.51,176.66 102.04,177.19 108.88,177.19 108.91,177.16 111.31,177.16 125.21,163.26 125.22,163.26 125.62,162.86 126.01,162.86 126.2,162.67 126.2,162.2 126.39,162.01 126.77,162.01 126.96,162.2 126.96,162.67 127.15,162.86 127.53,162.86 127.72,162.67 127.72,162.2 127.91,162.01 128.29,162.01 128.48,162.2 128.48,162.67 128.67,162.86 129.05,162.86 129.25,162.67 129.25,162.2 129.44,162.01 129.82,162.01 130.01,162.2 130.01,162.67 130.2,162.86 131.49,162.86 132.15,162.19 133.04,162.19 v3(133.41,162.56)
M_MAA_A10: length 55.5
  TOP w0.089: CPU1.BH49 94.54,172.88 94.68,172.74 96.52,172.74 v3(96.88,173.1)
  TOP w0.14: DIMM1.107 132.96,156.35 133.43,156.82 v3(133.46,156.82)
  L3 w0.191: v3(133.46,156.82) 133.46,157.13 133.27,157.32 132.28,157.32 131.39,156.42 131.39,155.93 131.25,155.79 130.74,155.79 130.47,156.06 130.14,156.06 129.95,155.87 129.95,155.17 129.76,154.98 129.38,154.98 129.19,155.17 129.19,155.55 129.06,155.68 128.56,155.68 128.43,155.55 128.43,155.17 128.24,154.98 127.86,154.98 127.67,155.17 127.67,155.87 127.48,156.06 127.1,156.06 126.91,155.87 126.91,155.17 126.72,154.98 126.33,154.98 126.14,155.17 126.14,155.87 125.95,156.06 124.87,156.06 107.44,173.49 97.27,173.49 v3(96.88,173.1)
M_MAA_A11: length 55.3
  TOP w0.089: 98.32,176.29 98.21,176.18 96.09,176.18 95.58,175.67 94.09,175.67 94.08,175.66 CPU1.BH55
  TOP w0.14: 98.32,176.29 98.53,176.29 v3(100.07,177.83) ; v3(137.23,163.7) 137.27,163.66 137.27,163.64 137.7,163.25 DIMM1.84
  L3 w0.191: v3(100.07,177.83) 100.63,177.83 102.38,179.58 109.87,179.58 109.9,179.55 112.3,179.55 126.2,165.65 127.19,165.65 130.81,165.65 132.3,164.15 135.8,164.15 135.93,164.28 135.93,164.9 136.06,165.02 136.54,165.02 136.66,164.9 136.66,164.25 137.21,163.7 v3(137.23,163.7)
M_MAA_A12: length 55.6
  TOP w0.089: 98.32,176 96.16,176 95.65,175.49 94.17,175.49 94.12,175.44 93.98,175.34 93.67,175.34 CPU1.BG54
  TOP w0.14: v3(100.89,178.79) 101.33,178.79 101.64,178.49 101.64,177.71 99.94,176 98.32,176 ; DIMM1.83 133.15,163.55 134.5,164.9 v3(134.5,164.92)
  L3 w0.191: v3(100.89,178.79) 102.27,180.17 110.11,180.17 110.15,180.14 112.55,180.14 126.45,166.24 126.94,166.24 126.94,166.24 130.88,166.24 132.65,164.47 134.05,164.47 v3(134.5,164.92)
M_MAA_A13: length 57.7
  TOP w0.089: CPU1.BG46 93.8,171.49 94.14,171.75 94.14,171.75 94.16,171.76 94.47,171.76 94.48,171.75 95.59,171.75 95.61,171.73
  TOP w0.14: v3(135.19,151.21) 135.19,151.74 134.18,152.75 DIMM1.119 ; v3(103.46,171.81) 103.46,171.08 103.17,170.79 100.59,170.79 99.68,171.7 98.59,171.7 98.58,171.7 97.26,171.7 97.23,171.68 96.66,171.68 96.64,171.7 95.8,171.7 95.78,171.73 95.61,171.73
  L3 w0.191: v3(103.46,171.81) 103.51,171.75 104.95,171.75 125.62,151.08 131.51,151.08 131.99,150.6 134.58,150.6 v3(135.19,151.21)
  BOTTOM w0.14: v3(103.46,171.81) v2(104.17,171.81)
M_MAA_A14: length 56.6
  TOP w0.089: 97.42,176.61 96.01,176.61 95.43,176.02 94.21,176.02 94.11,176.13 CPU1.BG56
  TOP w0.14: DIMM1.80 139.4,164.45 138.39,164.45 v3(137.14,164.82) ; 97.42,176.61 98.23,177.42 98.23,177.48 98.3,177.56 v3(98.3,177.56)
  L3 w0.191: v3(98.3,177.56) 98.3,177.57 98.13,177.74 98.13,178.32 98.66,178.85 99.26,178.85 101.79,181.37 110.61,181.37 110.64,181.34 113.23,181.34 126.38,168.19 131.52,168.19 132.09,167.88 132.26,166.86 132.28,166.39 132.44,166.21 133.01,165.63 136.64,165.63 137.14,165.14 v3(137.14,164.82)
M_MAA_A15: length 56.2
  TOP w0.089: CPU1.BG57 93.23,176.52 93.88,176.52 94.11,176.75 94.5,176.75 94.89,177.13 96.54,177.13 v3(96.95,177.55)
  TOP w0.14: DIMM1.78 137.75,165.05 136.56,166.24 v3(135.64,166.24)
  L3 w0.191: v3(135.64,166.24) 135.64,167.26 135.27,167.63 134.29,167.63 133.14,168.79 132.7,168.79 132.69,168.8 126.7,168.8 113.54,181.97 113.19,181.97 113.16,181.93 110.89,181.93 110.86,181.97 101.76,181.97 99.12,179.32 98.69,179.32 97.17,177.8 97.17,177.77 v3(96.95,177.55)
M_ODT_A0: length 65
  TOP w0.14: DIMM1.116 137.77,153.65 v3(137.06,152.93) ; v3(89.9,170.64) 89.9,170.48 CPU1.AW43
  L4 w0.089: 93.52,170.88 92.87,170.23 90.3,170.23 v3(89.9,170.64)
  L4 w0.191: v3(137.06,152.93) 136.43,153.56 135.52,153.56 134.73,154.36 132.19,154.36 132,154.17 132,153.66 131.81,153.47 131.43,153.47 131.23,153.66 131.23,154.17 131.04,154.36 130.66,154.36 130.47,154.17 130.47,153.66 130.28,153.47 129.9,153.47 129.71,153.66 129.71,154.17 129.52,154.36 128.92,154.36 127.19,156.09 125.55,157.73 125.29,157.99 109.05,174.23 101.67,174.23 101.48,174.05 95.75,174.05 94.72,173.02 94.72,172.09 93.52,170.88
  BOTTOM w0.14: v3(137.06,152.93) 136.36,152.93 v2(136.33,152.91)
M_ODT_A1: length 61.7
  TOP w0.14: v3(134.55,153.06) 134.63,153.06 135.24,152.45 DIMM1.120 ; v3(89.98,169.67) 89.57,169.25 CPU1.AW41
  L4 w0.089: 93.78,170.72 93.11,170.05 90.37,170.05 v3(89.98,169.67)
  L4 w0.191: v3(134.55,153.06) 134.36,152.87 129.24,152.87 109.89,172.23 109.58,172.23 109.08,172.72 109.08,173.03 108.66,173.46 100.74,173.46 100.43,173.77 98.67,173.77 97.95,173.05 97.95,172.87 97.6,172.52 95.57,172.52 93.78,170.72
  BOTTOM w0.14: v3(134.55,153.06) v2(133.81,153.06)
M_RAS_A_N: length 58.6
  TOP w0.089: CPU1.BG47 93.44,171.95 93.79,172.24 94.03,172.24 94.16,172.14 95.75,172.14 95.76,172.16 95.99,172.16
  TOP w0.14: DIMM1.110 138.5,155.45 138.37,155.32 136.77,155.32 v3(136.31,155.77) ; v3(101.46,172.04) 101.15,171.73 100.49,171.73 100.06,172.15 98.78,172.15 98.77,172.16 97.07,172.16 97.04,172.14 96.85,172.14 96.83,172.16 95.99,172.16
  L3 w0.191: v3(136.31,155.77) 135.49,154.95 132.93,154.27 132.32,153.66 132.32,152.49 132.12,152.29 126.11,152.29 105.8,172.6 102.02,172.6 v3(101.46,172.04)
  BOTTOM w0.14: v3(101.46,172.04) 101.46,172.98 v2(101.34,173.1)
M_SBS_A0: length 57
  TOP w0.089: 96.95,172.36 94.37,172.36 CPU1.BJ48
  TOP w0.14: 96.95,172.36 96.97,172.39 100.06,172.39 v3(100.21,172.54) ; DIMM1.109 132.6,155.75 v3(132.7,155.65)
  L3 w0.191: v3(132.7,155.65) 132.99,155.36 132.99,154.87 132.86,154.75 132.2,154.75 132,154.55 132,152.87 131.88,152.75 131.33,152.75 131.2,152.87 131.2,153.73 131,153.93 130.56,153.93 130.36,153.73 130.36,153.07 130.17,152.88 129.79,152.88 129.6,153.07 129.6,153.61 129.43,153.78 129,153.78 128.83,153.61 128.83,153.07 128.64,152.88 128.26,152.88 128.07,153.07 128.07,153.61 127.9,153.78 127.39,153.78 127.22,153.61 127.22,153.09 127.02,152.88 126.6,152.88 126.4,153.09 126.4,153.56 126.19,153.76 125.48,153.76 106.36,172.88 100.55,172.88 v3(100.21,172.54)
  BOTTOM w0.14: v3(132.7,155.65) v2(131.99,155.65)
M_SBS_A1: length 57.7
  TOP w0.089: v3(96.26,173.24) 95.98,172.96 95.95,172.96 95.91,172.92 94.75,172.92 94.61,173.06 94.17,173.06 94.03,173.17 93.79,173.17 93.62,173.03 93.31,173.03 CPU1.BG49
  TOP w0.14: v3(137.94,155.83) 138.16,156.05 DIMM1.108
  L3 w0.191: v3(96.26,173.24) 96.79,173.77 108.01,173.77 125.1,156.67 130.93,156.67 131.92,157.66 138.13,157.66 138.42,157.37 138.42,156.31 v3(137.94,155.83)
  BOTTOM w0.14: v3(96.26,173.24) 96.26,173.82 v2(95.96,174.12)
M_SBS_A2: length 54.1
  TOP w0.14: v3(99.92,178.69) 99.28,179.33 v4(98.62,179.33) 97.99,179.33 97.43,178.77 96.88,178.77 96.63,178.52 96.63,177.96 96,177.34 94.8,177.34 94.42,176.95 94.02,176.95 93.91,176.84 CPU1.BH57 ; DIMM1.79 132.65,164.75 v3(132.85,164.95)
  L3 w0.191: v3(99.92,178.69) 100.01,178.69 102.1,180.77 110.36,180.77 110.39,180.74 112.79,180.74 126.69,166.84 127.07,166.84 127.2,166.97 127.2,167.45 127.33,167.58 127.87,167.58 128,167.45 128,167.03 128.19,166.84 128.57,166.84 128.76,167.03 128.76,167.48 128.88,167.6 129.41,167.6 129.52,167.48 129.52,167.03 129.71,166.84 130.41,166.84 130.54,166.97 130.54,167.57 130.66,167.69 131.47,167.69 131.6,167.57 131.6,166.47 132.85,165.22 v3(132.85,164.95)
M_SCKE_A0: length 58.2
  TOP w0.089: v3(95.3,178.84) 94.83,178.84 94.45,178.46 93.9,178.46 CPU1.BH61
  TOP w0.14: v3(132.85,166.47) 132.77,166.55 132.57,166.55 132.57,166.55 DIMM1.73
  L4 w0.191: v3(95.3,178.84) 97.26,178.84 97.66,179.23 101.22,179.23 101.51,178.94 101.82,178.94 102.01,178.75 102.01,178.26 102.2,178.07 102.59,178.07 102.78,178.26 102.78,178.75 102.97,178.94 103.35,178.94 103.54,178.75 103.54,178.26 103.73,178.07 104.11,178.07 104.3,178.26 104.3,178.75 104.49,178.94 104.87,178.94 105.06,178.75 105.06,178.26 105.25,178.07 105.63,178.07 105.82,178.26 105.82,178.75 106.01,178.94 106.4,178.94 106.59,178.75 106.59,178.26 106.78,178.07 107.16,178.07 107.35,178.26 107.35,178.75 107.54,178.94 108.72,178.94 121.2,166.46 122.24,166.46 122.43,166.27 122.43,165.74 122.62,165.54 123,165.54 123.19,165.74 123.19,166.27 123.38,166.46 123.76,166.46 123.95,166.27 123.95,165.74 124.14,165.54 124.53,165.54 124.72,165.74 124.72,166.27 124.91,166.46 125.29,166.46 125.48,166.27 125.48,165.74 125.67,165.54 126.05,165.54 126.24,165.74 126.24,166.27 126.43,166.46 126.81,166.46 127,166.27 127,165.74 127.19,165.54 127.57,165.54 127.76,165.74 127.76,166.27 127.95,166.46 132.84,166.46 v3(132.85,166.47)
  BOTTOM w0.14: v3(95.3,178.84) v2(94.31,178.84)
M_SCKE_A1: length 57.2
  TOP w0.089: 95.12,177.79 93.97,177.79 CPU1.BH60
  TOP w0.14: v3(137.88,166.47) 138.1,166.25 DIMM1.74 ; v3(95.82,179.32) 95.82,178.49 95.12,177.79
  L4 w0.191: v3(137.88,166.47) 137.29,167.06 130.35,167.06 130.16,167.25 130.16,167.47 129.97,167.67 129.59,167.67 129.4,167.47 129.4,167.25 129.21,167.06 128.83,167.06 128.64,167.25 128.64,167.47 128.45,167.67 128.07,167.67 127.88,167.47 127.88,167.25 127.69,167.06 127.31,167.06 127.12,167.25 127.12,167.47 126.93,167.67 126.54,167.67 126.35,167.47 126.35,167.25 126.16,167.06 125.78,167.06 125.59,167.25 125.59,167.47 125.4,167.67 125.02,167.67 124.83,167.47 124.83,167.25 124.64,167.06 124.26,167.06 124.07,167.25 124.07,167.47 123.88,167.67 123.5,167.67 123.31,167.47 123.31,167.25 123.12,167.06 122.52,167.06 109.87,179.71 97.52,179.71 97.14,179.32 v3(95.82,179.32)
  BOTTOM w0.14: v3(95.82,179.32) v2(95.31,179.83)
M_SCS_A_N0: length 64
  TOP w0.14: CPU1.AR43 87.43,170.2 v3(87.79,170.56) ; DIMM1.114 v3(137.78,154.25)
  L4 w0.089: 93.45,171.35 93.2,171.09 88.32,171.09 v3(87.79,170.56)
  L4 w0.191: v3(137.78,154.25) 137.78,154.44 137.2,155.02 129.1,155.02 127.44,156.69 125.97,158.15 125.71,158.41 109.24,174.88 101.26,174.88 101.18,174.96 96.27,174.96 94.44,173.14 94.44,172.34 93.45,171.35
  BOTTOM w0.14: v3(137.78,154.25) v2(136.97,154.25)
M_SCS_A_N1: length 62.8
  TOP w0.14: v3(90.7,169.67) 90.28,169.25 CPU1.BA41 ; v3(133.48,151.26) 132.59,152.15 DIMM1.121
  L4 w0.089: v3(90.7,169.67) 91.27,169.67 91.66,169.28 92.99,169.28 93.58,169.87 93.58,169.88
  L4 w0.191: 93.58,169.88 94.1,170.39 94.1,170.6 95.58,172.09 97.57,172.09 98.23,172.75 98.23,172.94 98.78,173.49 99.89,173.49 100.55,172.82 107.48,172.82 111.44,168.86 111.71,168.86 111.92,169.08 112.19,169.08 112.46,168.81 112.46,168.54 112.25,168.32 112.25,168.05 112.52,167.78 112.79,167.78 113,168 113.27,168 113.54,167.73 113.54,167.46 113.32,167.24 113.32,166.97 113.59,166.71 113.86,166.71 114.08,166.92 114.35,166.92 114.62,166.65 114.62,166.38 114.4,166.17 114.4,165.9 114.67,165.63 114.94,165.63 115.16,165.84 115.43,165.84 115.7,165.57 115.7,165.3 115.48,165.09 115.48,164.82 115.75,164.55 116.02,164.55 116.23,164.76 116.5,164.76 116.77,164.49 116.77,164.23 116.56,164.01 116.56,163.74 128.1,152.2 132.55,152.2 v3(133.48,151.26)
  BOTTOM w0.14: v2(133.21,150.57) 133.48,151.23 v3(133.48,151.26)
M_WE_A_N: length 59
  TOP w0.089: 98.38,172.64 98.34,172.6 96.63,172.6 96.59,172.56 94.6,172.56 94.48,172.69 94.16,172.69 93.98,172.56 93.85,172.43 93.84,172.42 CPU1.BG48
  TOP w0.14: v3(99.63,172.85) 99.41,172.64 98.38,172.64 98.38,172.64 ; DIMM1.113 134.57,154.55 134.7,154.68 134.7,155.45 134.57,155.57 v3(134.12,155.57)
  L3 w0.191: v3(134.12,155.57) 135.53,155.57 135.74,155.78 135.74,156.13 135.53,156.33 132.55,156.33 130.6,154.38 125.71,154.38 106.93,173.16 99.94,173.16 v3(99.63,172.85)
  BOTTOM w0.14: v2(99.63,173.56) v3(99.63,172.85)
MCSI_RCOMP_1: length 2.5
  TOP w0.254: CPU1.H27 v3(75.3,163.13)
  BOTTOM w0.381: v2(76.16,161.57) 76.16,161.67 75.55,162.28 R592.2 75.3,162.73 v3(75.3,163.13)
MCSI_RCOMP_2: length 2.4
  TOP w0.254: CPU1.F27 v3(74.59,163.13)
  BOTTOM w0.381: v3(74.59,163.13) 74.59,162.78 R593.2 74.43,162.26 v2(74.89,161.72)
MCT_R: length 5.5
  BOTTOM w0.508: v1(62.64,10.34) 61.65,10.34 61.35,10.03 60.61,10.03 ; XF1.4 61.42,13.84 61.73,13.54 61.73,13.13 v2(62.19,12.67) 62.64,13.13 v1(62.64,13.54)
MCT_R_1: length 2
  TOP w0.508: R492.1 v3(66.07,11.94)
  vias: v2(64.73,13.92)
MDA0: length 35.9
  TOP w0.127: v3(80.1,92.1) 80.08,92.1 GPU1.E18
  L3 w0.165: v3(55.92,84.59) 56.17,84.34 57.09,84.34 57.35,84.59 58.08,84.59 58.33,84.34 58.76,84.34 59.26,84.84 59.26,84.85 59.89,85.47 60.38,85.47 60.66,85.19 60.66,84.63 60.88,84.41 61.8,84.41 61.99,84.6 61.99,84.98 62.15,85.15 62.8,85.15 62.97,84.98 62.97,84.65 63.12,84.5 63.48,84.5 63.63,84.65 63.63,84.92 63.79,85.09 73.1,85.09 73.7,84.49 74.87,84.49 79.97,89.59 79.97,91.56 80.1,91.7 v3(80.1,92.1)
  BOTTOM w0.127: v3(55.92,84.59) 55.71,84.8 55.71,85.73 56.24,86.25 57.59,86.25 VRAM4.F7
MDA1: length 37.2
  TOP w0.127: v3(79.16,94.95) 79.28,94.84 79.28,93.72 79.66,93.34 GPU1.F18
  L3 w0.165: v3(79.16,94.95) 79.16,94.63 79.65,94.15 79.65,91.77 79.7,91.72 79.7,89.7 74.86,84.86 74.01,84.86 73.3,85.57 60.88,85.57 60.72,85.74 59.55,85.74 59.35,85.54 57.63,85.54 56.89,84.8 v3(56.52,84.8)
  BOTTOM w0.127: VRAM4.F8 58.3,86.24 57.93,85.87 57.4,85.87 57.25,86.02 56.33,86.02 55.94,85.63 55.94,85.26 56.4,84.8 v3(56.52,84.8)
MDA2: length 39.3
  TOP w0.127: v3(80.94,92.11) 80.97,92.11 GPU1.E16
  L3 w0.165: v3(55.25,83.81) 55.29,83.77 55.32,83.77 55.67,83.42 56.08,83.42 56.67,84.01 58.81,84.01 59.35,84.55 60.36,84.55 60.79,84.12 64.15,84.12 64.31,84.28 64.31,84.54 64.48,84.71 64.81,84.71 64.97,84.54 64.97,84.28 65.14,84.12 65.47,84.12 65.63,84.28 65.63,84.54 65.8,84.71 66.13,84.71 66.29,84.54 66.29,84.28 66.46,84.12 66.79,84.12 66.95,84.28 66.95,84.54 67.12,84.71 67.45,84.71 67.61,84.54 67.61,84.28 67.78,84.12 68.11,84.12 68.27,84.28 68.27,84.54 68.44,84.71 68.77,84.71 68.93,84.54 68.93,84.28 69.1,84.12 69.43,84.12 69.59,84.28 69.59,84.54 69.76,84.71 70.09,84.71 70.26,84.54 70.26,84.28 70.42,84.12 70.75,84.12 70.92,84.28 70.92,84.54 71.08,84.71 71.41,84.71 71.58,84.54 71.58,84.28 71.74,84.12 72.07,84.12 72.24,84.28 72.24,84.54 72.4,84.71 72.73,84.71 72.9,84.54 72.9,84.28 73.06,84.12 74.88,84.12 80.23,89.48 80.23,91.41 v3(80.94,92.11)
  BOTTOM w0.127: VRAM4.E3 54.98,84.86 55.18,84.86 55.46,84.58 55.46,84.01 v3(55.25,83.81)
MDA3: length 38.3
  TOP w0.127: v3(80.92,93.75) 80.52,93.34 GPU1.F17
  L3 w0.165: v3(53.2,85.83) 53.91,85.83 54.48,85.26 54.48,83.92 55.25,83.15 56.19,83.15 56.75,83.71 58.89,83.71 59.45,84.27 60.26,84.27 60.78,83.75 74.89,83.75 80.5,89.37 80.5,89.45 80.51,89.46 80.51,91.02 81.42,91.94 81.42,93.25 v3(80.92,93.75)
  BOTTOM w0.127: VRAM4.F2 53.6,86.23 v3(53.2,85.83)
MDA4: length 33.8
  TOP w0.127: GPU1.D20 78.06,91.7 v3(78.47,91.29)
  L3 w0.165: v3(78.47,91.29) 78.03,90.86 78.03,90.29 77.56,89.81 77.56,89.11 77.26,88.82 76.43,88.82 75.61,87.99 75.13,87.99 74.94,88.18 74.94,88.7 74.43,89.21 69.17,89.21 69.01,89.05 69.01,87.48 68.84,87.31 68.51,87.31 68.35,87.48 68.35,89.05 68.18,89.21 66.58,89.21 66.39,89.02 66.39,88.07 66.23,87.91 65.79,87.91 65.62,88.07 65.62,89.03 65.42,89.23 64.85,89.23 64.51,88.89 64.51,88.16 64.25,87.9 63.55,87.9 63.02,87.38 62.33,87.38 62.23,87.48 60.43,87.48 59.73,86.78 v3(59.73,86.78)
  BOTTOM w0.127: VRAM4.H8 58.83,87.41 59.3,87.41 60.12,88.23 60.3,88.23 60.65,87.88 60.65,87.7 v3(59.73,86.78)
MDA5: length 30.2
  TOP w0.127: GPU1.D21 77.23,91.7 v3(77.62,91.31)
  L3 w0.165: v3(53.2,86.64) 53.2,86.57 53.6,86.17 54.28,86.17 54.95,86.84 55.55,86.84 55.95,86.44 56.34,86.44 56.49,86.6 57.31,86.6 57.88,87.17 59.43,87.17 60,87.75 62.58,87.75 63.13,88.3 63.79,88.3 63.96,88.46 63.96,89.12 64.44,89.61 68.95,89.61 69.08,89.48 74.54,89.48 75.22,88.8 75.92,88.8 76.51,89.38 76.95,89.38 77.11,89.55 77.11,91.13 77.29,91.31 v3(77.62,91.31)
  BOTTOM w0.127: VRAM4.G2 53.59,87.04 53.2,86.65 v3(53.2,86.64)
MDA6: length 35.8
  TOP w0.127: GPU1.F20 77.64,92.94 v3(77.64,92.91)
  L3 w0.165: v3(56.63,87.33) 56.45,87.51 56.45,88.14 58.15,89.84 60.17,89.84 60.46,89.56 60.46,88.78 60.89,88.35 61.76,88.35 61.93,88.53 61.93,88.87 60.99,89.81 60.99,90.48 61.15,90.63 62.33,90.63 63.2,89.76 63.49,89.76 64.36,90.63 64.73,90.63 65.02,90.34 65.39,90.34 65.68,90.63 66.05,90.63 66.34,90.34 66.71,90.34 67,90.63 67.37,90.63 67.66,90.34 68.03,90.34 68.32,90.63 68.69,90.63 68.98,90.34 69.35,90.34 69.64,90.63 70.35,90.63 70.48,90.76 71.77,90.76 72.07,90.47 72.07,90.27 72.26,90.08 72.85,90.08 73.03,90.26 73.03,91.28 73.32,91.57 74.41,91.57 74.63,91.35 74.63,90.31 74.91,90.03 75.32,90.03 75.34,90.05 76.17,90.05 76.45,90.32 76.45,91.71 v3(77.64,92.91)
  BOTTOM w0.127: v3(56.63,87.33) 56.69,87.27 57.13,87.27 57.6,87.74 VRAM4.H7
MDA7: length 35.5
  TOP w0.127: v3(77.62,92.1) 77.6,92.1 GPU1.E21
  L3 w0.165: v3(77.62,92.1) 76.79,91.27 76.79,90.11 75.75,89.06 75.33,89.06 74.37,90.03 74.37,91.16 74.25,91.28 73.47,91.28 73.3,91.11 73.3,90.04 73.07,89.81 69.49,89.81 69.32,89.97 64.29,89.97 63.62,89.31 63.13,89.31 62.18,90.26 61.81,90.26 61.64,90.1 61.64,89.77 62.6,88.81 62.6,88.29 62.4,88.08 59.92,88.08 59.3,87.47 57.76,87.47 57.16,86.86 56.18,86.86 v3(56.14,86.9)
  BOTTOM w0.127: VRAM4.H3 54.4,88.01 54.63,88.23 55.01,88.23 55.13,88.12 55.13,86.6 55.32,86.41 56,86.41 56.14,86.55 v3(56.14,86.9)
MDA8: length 36.7
  TOP w0.127: GPU1.E15 82.18,92.5 82.55,92.13 82.55,92.12 v3(82.57,92.1)
  L3 w0.102: 81.9,90 81.94,90.05 81.94,91.33 82.57,91.96 v3(82.57,92.1)
  L3 w0.165: v1(54.03,81.25) 54.23,81.25 55.18,82.2 56.99,82.2 57.28,81.91 58.32,81.91 58.59,82.17 59.99,82.17 60.27,82.46 75.79,82.46 77.54,84.21 77.58,84.21 78.56,85.19 78.56,85.19 79.1,85.74 79.1,85.74 81.08,87.71 81.08,87.72 81.08,88.82 81.9,89.63 81.9,90
  BOTTOM w0.127: VRAM4.A2 53.6,81.68 v1(54.03,81.25)
MDA9: length 40.1
  TOP w0.127: GPU1.D15 81.75,91.29 81.75,89.16 81.74,89.15 81.74,89.14 81.53,88.94 81.53,87.58 80.63,86.68 v3(80.63,85.31)
  L3 w0.165: v3(80.63,85.31) 80.6,85.28 80.6,85.04 79.9,84.33 79.86,84.33 76.12,80.58 61.25,80.58 61.03,80.36 54.62,80.36 v1(54.24,79.97)
  BOTTOM w0.127: v1(54.24,79.97) 54.5,80.23 54.5,81.61 54.03,82.08 54.03,83.41 VRAM4.C2
MDA10: length 39
  TOP w0.127: v3(82.56,92.93) 82.16,93.33 GPU1.F15
  L3 w0.165: v3(82.56,92.93) 82.93,93.3 82.93,94.6 82.77,94.76 82.26,94.76 82.09,94.6 82.09,93.44 81.97,93.31 81.97,91.71 81.68,91.42 81.68,90.16 81.63,90.11 81.63,89.74 80.81,88.92 80.81,87.82 78.99,86 78.76,86 78.53,86.24 78.29,86.24 78.06,86 78.06,85.77 78.29,85.54 78.29,85.3 77.47,84.48 77.13,84.48 76.98,84.63 76.75,84.63 76.42,84.3 76.42,83.66 75.72,82.96 60.11,82.96 59.97,83.1 59.25,83.1 58.59,82.44 58.48,82.44 58.21,82.18 57.62,82.18 57.2,82.59 v3(57.2,82.64)
  BOTTOM w0.127: VRAM4.A7 57.2,82.64 v3(57.2,82.64)
MDA11: length 41.9
  TOP w0.127: v3(83.43,93.74) 83.45,93.74 83.84,93.35 GPU1.F13
  L3 w0.165: v3(83.43,93.74) 85.03,93.74 85.19,93.9 85.19,94.37 85.03,94.53 83.58,94.53 83.41,94.7 83.41,95.33 83.25,95.5 81.86,95.5 81.7,95.33 81.7,91.82 81.41,91.53 81.41,90.27 81.33,90.18 81.33,89.81 75.88,84.37 75.88,83.79 75.46,83.37 59.15,83.37 58.88,83.1 58.22,83.1 58,82.89 v3(58,82.64)
  BOTTOM w0.127: VRAM4.D7 57.6,84.36 57.97,83.99 57.97,82.67 v3(58,82.64)
MDA12: length 40.9
  TOP w0.127: GPU1.C13 83.84,90.89 84.25,90.48 84.25,87.13 82.56,85.44 81.72,85.44 v3(81.6,85.57)
  L3 w0.165: v1(57.17,79.32) 57.24,79.39 59.52,79.39 59.79,79.12 60.8,79.12 61.38,79.7 76.34,79.7 81.6,84.96 v3(81.6,85.57)
  BOTTOM w0.127: v1(57.17,79.32) 57.17,79.42 56.03,80.56 55.55,80.56 55.19,80.93 55.19,82.39 55.25,82.45 55.25,82.83 54.4,83.68 VRAM4.C3
MDA13: length 39.3
  TOP w0.127: v3(81.64,86.2) 81.77,86.33 82.45,86.33 83.4,87.28 83.4,89.66 GPU1.B13
  L3 w0.165: v3(81.64,86.2) 81.58,86.2 81.14,85.76 81.14,85.08 76.26,80.21 61.26,80.21 61.14,80.1 55.05,80.1 54.33,79.38 54.33,79.26 v1(54.26,79.19)
  BOTTOM w0.127: VRAM4.A3 54.72,81.92 54.72,79.79 54.26,79.33 v1(54.26,79.19)
MDA14: length 39.5
  TOP w0.127: GPU1.E13 84.24,92.9 v3(84.24,92.92)
  L3 w0.165: v3(84.24,92.92) 84.24,89.62 83.9,89.28 83.9,88.82 84.24,88.48 84.24,87.97 83.95,87.68 83.95,87.36 84.24,87.07 84.24,86.46 76.7,78.92 62.72,78.92 v1(62.38,78.59)
  BOTTOM w0.127: VRAM4.B8 58.83,82.61 58.83,82.09 59.05,81.87 59.32,81.87 59.58,81.61 59.58,81.06 60.84,79.8 60.84,79.27 61.53,78.59 v1(62.38,78.59)
MDA15: length 40
  TOP w0.127: v3(83.43,92.1) 83.83,91.7 GPU1.D13
  L3 w0.165: v1(61.62,79.16) 61.78,79.32 76.57,79.32 82.9,85.66 82.9,86.28 83.07,86.45 83.4,86.45 83.57,86.61 83.57,86.94 83.4,87.11 83.07,87.11 82.9,87.27 82.9,87.6 83.07,87.77 83.4,87.77 83.57,87.93 83.57,88.26 83.4,88.43 83.07,88.43 82.9,88.59 82.9,88.87 83.91,89.87 83.91,91.62 v3(83.43,92.1)
  BOTTOM w0.127: v1(61.62,79.16) 61.77,79.32 61.77,79.96 61.77,80.51 60.04,82.24 60.04,82.82 59.46,83.41 59.11,83.41 58.68,83.84 VRAM4.C8
MDA16: length 38.2
  TOP w0.127: v1(60.37,79.61) 60.33,79.61 58.4,81.53 VRAM2.A2 ; GPU1.B15 82.55,89.71 82.55,88.57 82.53,88.55 82.53,88.52 82.44,88.42 82.44,88.37 82.43,88.36 v3(82.43,88.35)
  L4 w0.165: v1(60.37,79.61) 60.37,79.46 60.62,79.21 60.91,79.21 61.33,79.63 62.83,79.63 62.93,79.53 62.93,78.6 63.07,78.47 63.69,78.47 63.85,78.63 63.85,79.29 64.02,79.45 65.15,79.45 65.44,79.74 65.45,79.74 66,80.3 73.84,80.3 74.33,80.79 74.56,80.79 75.03,80.32 75.27,80.32 75.5,80.55 75.5,80.78 75.03,81.25 75.03,81.49 75.26,81.72 75.5,81.72 76.22,81 76.46,81 76.69,81.23 76.69,81.46 75.96,82.19 75.96,82.42 76.22,82.68 76.46,82.68 76.64,82.5 76.87,82.5 77.1,82.74 77.1,82.97 76.92,83.15 76.92,83.38 81.99,88.45 82.28,88.45 82.38,88.35 v3(82.43,88.35)
MDA17: length 38.5
  TOP w0.127: v3(80.95,90.5) 81.34,90.9 GPU1.C16 ; v1(59.33,78.89) 59.29,78.92 59.25,78.92 58.28,79.9 58.28,80.89 56.76,82.41 56.76,82.83 57.34,83.41 57.82,83.41 58.12,83.71 58.27,83.71 VRAM2.C2
  L4 w0.165: v3(80.95,90.5) 80.58,90.5 80.42,90.34 80.42,89.64 80.58,89.48 81.83,89.48 81.99,89.31 81.99,88.88 81.83,88.72 81.24,88.72 81.08,88.55 81.08,88.06 73.69,80.67 65.85,80.67 65.3,80.11 65.29,80.11 65.2,80.02 64.78,80.02 64.78,80.02 63.1,80.02 63.1,80.02 60.62,80.02 60.57,80.07 60,80.07 59.33,79.4 v1(59.33,78.89)
MDA18: length 39.8
  TOP w0.127: VRAM2.C3 57.52,83.76 56.93,83.76 56.67,83.5 56.67,83.06 56.53,82.92 56.53,82.32 56.67,82.18 56.67,81.45 56.36,81.14 56.36,80.21 56.74,79.83 57.41,79.83 58.05,79.18 58.05,78.36 v1(58.25,78.15) ; GPU1.A13 83.84,87.19 82.54,85.89 v3(82.31,85.89)
  L4 w0.165: v1(58.25,78.15) 58.68,77.73 64.6,77.73 66.44,79.56 76.25,79.56 82.31,85.62 v3(82.31,85.89)
MDA19: length 40.5
  TOP w0.127: VRAM2.A3 57.75,82.09 57.75,81.85 59.89,79.71 59.89,78.51 v1(60.08,78.32) ; GPU1.A15 82.16,89.19 81.87,88.91 81.87,87.07 v3(82.16,86.78)
  L4 w0.165: v3(82.16,86.78) 81.23,86.78 80.08,85.62 80.08,85.19 80.61,84.66 80.61,84.49 80.36,84.24 80.13,84.24 79.44,84.93 79.21,84.93 78.97,84.7 78.97,84.46 79.66,83.78 79.66,83.54 79.43,83.31 79.19,83.31 78.51,84 78.27,84 78.04,83.76 78.04,83.53 78.73,82.84 78.73,82.61 78.49,82.37 78.26,82.37 77.94,82.69 77.71,82.69 77.47,82.46 77.47,82.23 77.79,81.91 77.79,81.67 76.05,79.93 66.28,79.93 64.45,78.1 60.31,78.1 v1(60.08,78.32)
MDA20: length 39
  TOP w0.127: GPU1.B18 79.68,89.85 79.29,89.46 79.29,89 76.19,85.9 74.99,85.9 74.97,85.88 v3(74.77,85.88) ; v1(52.54,80.34) 52.33,80.54 52.33,80.82 52.32,80.82 52.32,81.68 52.51,81.87 52.95,81.87 53.17,82.09 53.17,82.61 VRAM2.B8
  L4 w0.165: v1(52.54,80.34) 52.54,81 52.3,81.24 52.3,81.62 52.58,81.89 54.42,81.89 54.58,81.73 54.58,81.26 54.75,81.1 55.31,81.1 55.47,81.26 55.47,82.04 55.64,82.2 56.17,82.2 56.21,82.17 58.24,82.17 59.18,83.11 60.19,83.11 60.35,82.94 60.35,82.63 60.52,82.47 61.02,82.47 61.19,82.63 61.19,82.9 61.35,83.07 72.68,83.07 74.78,85.16 74.78,85.88 v3(74.77,85.88)
MDA21: length 38.4
  TOP w0.127: v1(51.86,80.62) 51.86,80.75 51.83,80.78 51.83,82.7 52.54,83.41 53.17,83.41 VRAM2.C8 ; GPU1.A18 79.68,89.07 75.91,85.3 74.37,85.3 v3(74.32,85.36)
  L4 w0.165: v3(74.32,85.36) 74.29,85.36 72.37,83.43 60.01,83.43 59.95,83.37 57.23,83.37 56.43,82.56 55.39,82.56 54.99,82.16 51.14,82.16 50.98,81.99 50.98,80.79 51.14,80.62 v1(51.86,80.62)
MDA22: length 38
  TOP w0.127: GPU1.A19 78.88,88.92 76.4,86.43 v3(75.38,86.43) ; VRAM2.D7 53.97,84.21 53.97,82.29 53.97,82.28 53.97,81.92 53.32,81.27 53.32,80.87 v1(53.39,80.79)
  L4 w0.165: v3(75.38,86.43) 75.38,87.03 75.51,87.17 76.1,87.17 76.38,86.89 76.38,86.24 72.71,82.57 64.25,82.57 64.08,82.41 64.08,82.14 63.92,81.97 63.18,81.97 63.02,82.14 63.02,82.53 62.85,82.7 62.22,82.7 62.05,82.53 62.05,82.34 61.89,82.17 58.69,82.17 58.24,81.71 56.84,81.71 55.89,80.76 53.82,80.76 53.79,80.79 v1(53.39,80.79)
MDA23: length 35.8
  TOP w0.127: v3(78.48,90.51) 78.48,90.52 78.86,90.9 GPU1.C19 ; VRAM2.A7 54.66,81.98 54.66,80.73 54.55,80.61 53.88,80.61 53.59,80.32 53.46,80.32 v1(53.26,80.12)
  L4 w0.165: v3(78.48,90.51) 78.48,90.49 78.49,90.48 78.49,88.22 77.05,86.78 77.05,86.4 72.86,82.2 64.81,82.2 64.21,81.61 59.87,81.61 59.57,81.91 58.86,81.91 58.48,81.53 58.48,80.84 57.9,80.26 57.06,80.26 56.86,80.47 53.76,80.47 53.41,80.12 v1(53.26,80.12)
MDA24: length 25.9
  TOP w0.127: v3(71.81,87.73) 72.1,87.43 73.37,87.43 75.08,89.14 75.08,89.72 GPU1.B24 ; VRAM2.H8 53.69,87.93 53.7,87.93 v3(54,88.24)
  L4 w0.165: v3(54,88.24) 54,88.17 54.82,87.35 54.82,86.88 54.94,86.76 55.63,86.76 55.95,86.44 56.34,86.44 56.61,86.71 56.81,86.71 57.47,87.37 59.29,87.37 59.41,87.49 62.27,87.49 62.33,87.55 66.47,87.55 66.97,87.05 67.76,87.05 68.21,87.49 69.01,87.49 69.64,88.13 71.41,88.13 v3(71.81,87.73)
MDA25: length 26.7
  TOP w0.127: VRAM2.G2 58.4,87.28 58.59,87.46 59.93,87.46 60.1,87.63 60.1,88.13 60.25,88.28 61.2,88.28 61.35,88.43 61.35,88.66 61.2,88.81 v3(61.08,88.81) ; v3(75.13,90.49) 75.13,90.79 75.24,90.9 GPU1.C23
  L4 w0.165: v3(75.13,90.49) 75.01,90.37 75.01,89.67 74.84,89.51 73.98,89.51 73.81,89.34 73.81,88.17 73.65,88.01 73.27,88.01 73.1,88.17 73.1,89.47 72.95,89.63 72.59,89.63 72.44,89.47 72.44,88.5 72.28,88.34 71.79,88.34 71.63,88.5 71.63,88.94 71.48,89.09 64.58,89.09 64.49,89 64.49,88.45 64.33,88.29 63.97,88.29 63.8,88.45 63.8,88.87 63.65,89.02 63.38,89.02 63.14,88.79 63.14,88.45 62.98,88.29 61.25,88.29 61.08,88.45 v3(61.08,88.81)
MDA26: length 25.2
  TOP w0.127: v3(57.04,87.82) 57.06,87.84 VRAM2.H3 ; GPU1.A25 73.9,89.24 73.22,88.55 71.49,88.55 70.96,88.02 70.42,88.02 70.27,87.87 68.26,87.87 68.1,87.7 68.1,86.72 67.93,86.56 67.38,86.56 67.22,86.72 v3(67.22,87.51)
  L4 w0.165: v3(67.22,87.51) 67.58,87.51 67.94,87.88 68.92,87.88 69.09,88.04 69.09,88.55 68.94,88.7 65.67,88.7 65.51,88.55 65.51,88.29 65.14,87.92 62.33,87.92 62.29,87.87 59.15,87.87 58.95,87.68 57.62,87.68 57.48,87.82 v3(57.04,87.82)
MDA27: length 25.1
  TOP w0.127: GPU1.A24 74.7,89.2 73.38,87.88 v3(72.57,87.88) ; VRAM2.H7 54.4,87.84 v3(54,87.44)
  L4 w0.165: v3(54,87.44) 54.29,87.44 54.46,87.28 54.46,86.56 54.59,86.42 55.59,86.42 55.84,86.17 56.45,86.17 56.6,86.33 56.72,86.44 57.29,86.44 57.45,86.61 57.45,86.93 57.62,87.1 59.4,87.1 59.52,87.23 61.44,87.23 61.82,86.84 62.13,86.84 62.48,87.18 66.32,87.18 66.82,86.68 68.08,86.68 68.52,87.12 69.15,87.12 69.7,87.68 71.19,87.68 71.61,87.26 72.36,87.26 72.57,87.47 v3(72.57,87.88)
MDA28: length 28.9
  TOP w0.127: GPU1.A21 77.2,89.24 76.33,88.37 75.64,88.37 73.99,86.72 v3(73.99,86.04) ; VRAM2.F8 54,85.84 v3(54,85.03)
  L4 w0.165: v3(54,85.03) 54.47,84.56 54.47,83.93 55.06,83.34 56,83.34 56.69,84.03 59.23,84.03 59.47,84.28 59.97,84.28 60.44,83.81 71.7,83.81 73.94,86.04 v3(73.99,86.04)
MDA29: length 29.2
  TOP w0.127: VRAM2.F7 54.4,86.01 54.8,85.61 54.8,85.14 55.06,84.88 55.16,84.88 55.44,84.6 55.44,84.33 v3(55.89,83.88) ; v3(74.5,86.52) 74.5,86.9 74.77,87.17 75.7,88.09 76.21,88.09 76.51,87.8 76.88,87.8 77.14,88.06 77.14,88.7 77.58,89.14 77.58,89.72 GPU1.B21
  L4 w0.165: v3(55.89,83.88) 56.17,83.88 56.58,84.3 59.12,84.3 59.37,84.55 60.11,84.55 60.48,84.19 71.43,84.19 73.75,86.52 v3(74.5,86.52)
MDA30: length 28.4
  TOP w0.127: v3(61.53,84.87) 61.42,84.87 60.49,85.81 58.83,85.81 VRAM2.F2 ; GPU1.C20 78.02,90.9 77.62,90.5 v3(77.58,90.5)
  L4 w0.165: v3(61.53,84.87) 61.57,84.87 61.86,84.58 71.3,84.58 73.2,86.49 73.2,87.03 73.37,87.19 74.54,87.19 74.7,87.36 74.7,88.53 74.87,88.69 75.27,88.69 75.44,88.53 75.44,88.28 75.6,88.11 76.03,88.11 76.2,88.28 76.2,88.98 76.37,89.15 76.72,89.15 76.89,88.98 76.89,87.87 77.05,87.7 77.4,87.7 77.57,87.87 77.57,90.44 77.58,90.46 v3(77.58,90.5)
MDA31: length 29.8
  TOP w0.127: GPU1.C21 76.78,90.48 76.78,89.14 76.24,88.6 75.55,88.6 73.51,86.57 73.51,85.23 73.35,85.06 71.36,85.06 71.2,85.23 71.2,85.53 71.36,85.7 72.76,85.7 72.92,85.86 72.92,86.19 72.76,86.35 v3(72.41,86.35) ; VRAM2.E3 57.6,85.42 57.98,85.04 58,85.04 v3(58,85.04)
  L4 w0.165: v3(58,85.04) 58,84.74 58.17,84.57 58.99,84.57 59.64,85.22 59.64,85.23 59.89,85.47 60.33,85.47 60.51,85.29 61,85.29 61.15,85.43 61.67,85.43 61.82,85.29 61.83,85.29 62.16,84.96 71.1,84.96 72.36,86.21 72.36,86.3 v3(72.41,86.35)
MDA32: length 39.6
  TOP w0.127: GPU1.R22 76.73,100.45 77.52,100.45 v3(77.55,100.43)
  L3 w0.165: v3(56.37,112.33) 56.28,112.33 55.9,111.95 55.9,111.71 56.03,111.58 56.37,111.58 56.37,111.58 56.78,111.17 57.4,111.17 57.54,111.3 57.54,111.99 57.81,112.26 58.19,112.26 58.57,111.88 59.64,111.88 60,111.53 60,111.12 59.59,110.71 59.59,109.51 62.35,106.75 62.35,102.87 63.49,101.73 63.49,101.15 66.48,98.16 73.5,98.16 74.06,98.73 75.03,98.73 75.39,99.08 76.02,99.08 76.38,98.73 76.93,98.73 77.83,99.63 77.83,100.14 v3(77.55,100.43)
  BOTTOM w0.127: v3(56.37,112.33) 56.37,112.41 56.18,112.61 56.18,112.62 55.91,112.88 55.16,112.88 55.13,112.86 54.54,112.86 VRAM3.F7
MDA33: length 36.6
  TOP w0.127: v3(68.15,100.5) 69.06,101.41 70.34,101.41 71.99,101.41 72.15,101.25 74.07,101.25 74.48,100.84 GPU1.R24
  L3 w0.165: v3(68.15,100.5) 68.15,100.5 67.64,101.02 67.52,101.02 66.28,102.25 66.28,111.51 64.96,112.84 64.96,113.53 63.08,115.41 57.28,115.41 56.86,115.83 55.93,115.83 55.33,115.23 55.33,113.95 55.35,113.94 55.35,112.76 55.13,112.55 v3(55.13,112.14)
  BOTTOM w0.127: v3(55.13,112.14) 55.13,112.13 VRAM3.H7
MDA34: length 34.7
  TOP w0.127: v3(76.76,102.08) 76.76,102.06 GPU1.T22
  L3 w0.165: v3(76.76,102.08) 76.76,101.87 78.1,100.53 78.1,99.51 77.04,98.46 74.2,98.46 73.54,97.8 66.32,97.8 63.12,101 63.12,101.48 61.98,102.62 61.98,106.59 59.27,109.3 59.27,111.18 58.99,111.46 58.6,111.46 58.13,111 v3(58,111)
  BOTTOM w0.127: VRAM3.H3 57.6,111.39 v3(58,111)
MDA35: length 37.8
  TOP w0.127: v3(75.09,100.43) 75.09,100.43 GPU1.R23
  L3 w0.165: v3(53.99,111.8) 54.47,112.28 54.47,113.11 54.37,113.21 54.37,113.62 54.61,113.86 54.61,115.26 55.71,116.36 57.4,116.36 57.62,116.14 60.04,116.14 60.05,116.14 63.39,116.14 67.02,112.51 67.02,103.46 69.01,101.47 70.92,101.47 71.25,101.15 74.38,101.15 v3(75.09,100.43)
  BOTTOM w0.127: VRAM3.H8 53.99,111.79 v3(53.99,111.8)
MDA36: length 39.3
  TOP w0.127: GPU1.N25 73.52,98.78 69.01,98.78 67.49,100.3 v3(67.49,100.5)
  L3 w0.165: v3(55.8,114.59) 55.9,114.69 56.14,114.69 56.33,114.87 56.93,114.87 57.1,114.71 57.1,114.54 57.26,114.37 57.67,114.37 57.84,114.54 57.84,114.87 58,115.04 61.59,115.04 61.87,114.75 62.33,114.75 62.62,115.04 62.93,115.04 64.59,113.38 64.59,111.69 64.76,111.53 65.75,111.53 65.91,111.36 65.91,110.9 65.75,110.74 64.76,110.74 64.59,110.57 64.59,109.23 64.76,109.06 65.09,109.06 65.25,109.23 65.25,109.66 65.42,109.83 65.75,109.83 65.91,109.66 65.91,108.91 65.61,108.61 65.61,108.2 65.91,107.89 65.91,102.03 67.44,100.5 v3(67.49,100.5)
  BOTTOM w0.127: VRAM3.E3 57.52,113.88 57.52,114.13 57.39,114.26 57.13,114.26 57.01,114.39 57.01,114.74 56.88,114.87 56.29,114.87 56.18,114.76 55.97,114.76 v3(55.8,114.59)
MDA37: length 38.3
  TOP w0.127: GPU1.N26 72.71,99.55 72.14,99.55 71.98,99.39 71.72,99.39 71.55,99.55 71.55,99.8 71.4,99.94 71.19,99.94 71.04,99.8 71.04,99.55 70.88,99.39 70.62,99.39 70.46,99.55 70.46,100.25 70.71,100.5 v3(70.79,100.5)
  L3 w0.165: v3(54.86,113.41) 54.86,113.73 54.88,113.75 54.88,115.15 55.82,116.09 57.16,116.09 57.47,115.78 63.23,115.78 65.33,113.68 65.33,112.99 65.59,112.73 65.82,112.73 65.94,112.84 66.17,112.84 66.4,112.61 66.4,112.37 66.29,112.26 66.29,112.03 66.65,111.67 66.65,102.46 66.91,102.2 67.14,102.2 67.34,102.39 67.57,102.39 67.8,102.16 67.8,101.92 67.61,101.73 67.61,101.5 68.05,101.06 70.62,101.06 70.79,100.9 v3(70.79,100.5)
  BOTTOM w0.127: VRAM3.F8 53.6,113.13 53.88,113.41 v3(54.86,113.41)
MDA38: length 38.4
  TOP w0.127: GPU1.N23 75.5,99.19 v3(75.1,99.59)
  L3 w0.165: v3(60.32,111.86) 60.69,111.86 60.86,112.03 60.86,112.19 61.01,112.34 61.4,112.34 61.56,112.19 61.56,112.03 61.72,111.86 62.58,111.86 62.73,111.71 62.73,111.22 62.58,111.07 60.99,111.07 60.84,110.92 60.84,110.54 60.99,110.38 62.57,110.38 62.72,110.23 62.72,109.83 62.57,109.68 60.66,109.68 60.51,109.53 60.51,109.17 60.66,109.02 62.32,109.02 62.72,108.62 62.72,103.07 63.86,101.93 63.86,101.3 66.65,98.52 73.48,98.52 73.97,99 74.93,99 75.1,99.17 v3(75.1,99.59)
  BOTTOM w0.127: VRAM3.G2 58.77,111.83 59.47,111.83 59.57,111.72 59.57,111.57 59.92,111.23 60.47,111.23 60.6,111.36 60.6,111.74 60.47,111.86 v3(60.32,111.86)
MDA39: length 42.4
  TOP w0.127: GPU1.N24 74.3,99.56 v3(74.3,99.57)
  L3 w0.165: v3(74.3,99.57) 74.1,99.57 73.42,98.88 66.8,98.88 64.22,101.46 64.22,102.27 63.1,103.39 63.1,111.92 62.64,112.39 62.18,112.39 61.86,112.71 60.54,112.71 v3(60.35,112.52)
  BOTTOM w0.127: v3(60.35,112.52) 60.7,112.52 60.83,112.4 60.83,111.51 60.96,111.38 61.95,111.38 62.1,111.53 62.1,111.74 61.95,111.89 61.49,111.89 61.36,112.01 61.36,112.39 61.49,112.52 61.95,112.52 62.08,112.65 62.08,113.79 61.95,113.92 61.65,113.92 61.51,113.78 61.51,113.23 61.37,113.1 61.09,113.1 60.95,113.23 60.95,114.34 61.09,114.47 61.93,114.47 62.07,114.61 62.07,114.95 61.94,115.08 60.49,115.08 60.36,114.95 60.36,113.51 60.23,113.38 58.63,113.38 58.4,113.15 VRAM3.F2
MDA40: length 39.6
  TOP w0.127: v3(75.1,102.91) 75.11,102.92 75.11,102.93 GPU1.V23
  L3 w0.165: v1(60.3,119) 60.22,118.93 60.22,118.62 60.35,118.49 61.1,118.49 61.49,118.49 61.86,118.86 62.32,118.86 62.53,118.64 62.53,117.62 62.7,117.46 63.03,117.46 63.2,117.62 63.2,118.54 63.32,118.67 63.67,118.67 63.96,118.38 63.96,117.66 64.12,117.5 64.98,117.5 66.68,115.79 66.68,115.66 66.38,115.35 66.38,115.12 66.61,114.88 66.84,114.88 67.13,115.17 67.31,115.17 67.6,114.88 67.6,114.7 67.31,114.41 67.31,114.18 67.54,113.95 67.78,113.95 68.06,114.23 68.24,114.23 68.6,113.88 68.6,113.7 68.35,113.46 68.35,104.21 69.29,103.27 71.95,103.27 72.31,102.91 v3(75.1,102.91)
  BOTTOM w0.127: v1(60.3,119) 60.3,118.74 60.43,118.61 60.43,118.25 60.26,118.07 59.95,118.07 59.82,118.2 59.82,118.37 59.7,118.49 59.27,118.49 58.03,117.25 58.03,115.52 58.15,115.4 VRAM3.C2
MDA41: length 40.8
  TOP w0.127: v3(75.9,102.9) 76.32,103.32 GPU1.V22
  L3 w0.165: v1(61.16,119) 61.34,119.18 63.73,119.18 64.34,118.57 64.34,118.04 64.5,117.88 65.13,117.88 69.14,113.86 69.14,113.56 69.29,113.41 69.52,113.41 69.64,113.28 69.64,112.88 69.52,112.75 69.13,112.75 68.96,112.59 68.96,112.26 69.13,112.09 69.58,112.09 69.7,111.96 69.7,111.56 69.58,111.43 68.87,111.43 68.75,111.3 68.75,104.34 69,104.08 69.39,104.08 69.56,104.25 69.56,105.27 69.72,105.43 70.05,105.43 70.22,105.27 70.22,104.45 70.38,104.29 70.71,104.29 70.88,104.45 70.88,105.27 71.04,105.43 71.96,105.43 72.09,105.3 72.09,104.95 71.96,104.82 71.59,104.82 71.42,104.66 71.42,104.43 71.59,104.26 72.05,104.26 72.21,104.1 72.21,103.6 72.61,103.2 74.77,103.2 74.92,103.35 74.93,103.35 74.96,103.37 75.42,103.37 v3(75.9,102.9)
  BOTTOM w0.127: VRAM3.A2 59,117.6 61.08,117.6 61.21,117.73 61.21,118.82 61.16,118.86 v1(61.16,119)
MDA42: length 41.1
  TOP w0.127: v3(74.3,102.05) 74.3,101.46 74.51,101.25 75.11,101.25 GPU1.T23
  L3 w0.165: v3(74.3,102.05) 74.3,102.35 74.13,102.52 72.97,102.52 72.82,102.36 72.82,102.09 72.66,101.93 72.26,101.93 72.09,102.09 72.09,102.6 71.82,102.87 69.13,102.87 67.88,104.12 67.88,113.09 63.88,117.09 62.33,117.09 62.13,117.29 62.13,117.94 61.96,118.11 61.63,118.11 61.47,117.94 61.47,117.2 61.3,117.04 60.97,117.04 60.81,117.2 60.81,117.94 60.64,118.11 60.31,118.11 60.15,117.94 60.15,117.74 59.98,117.57 57.67,117.57 57.51,117.74 57.51,118.22 57.67,118.38 58.51,118.38 58.67,118.55 58.67,119.11 58.84,119.27 59.27,119.27 59.43,119.11 v1(59.43,119)
  BOTTOM w0.127: v1(59.43,119) 59.31,119.13 58.66,119.13 58.54,119 58.54,118.44 57.6,117.5 VRAM3.A3
MDA43: length 41.3
  TOP w0.127: v3(75.92,102.06) 76.34,102.48 GPU1.U22
  L3 w0.165: v3(75.92,102.06) 75.45,101.59 71.58,101.59 71.27,101.9 69.58,101.9 67.51,103.96 67.51,112.93 63.72,116.72 60.64,116.72 60.25,117.11 57.61,117.11 57.11,117.61 55.82,117.61 55.65,117.77 55.65,118.2 55.82,118.36 57.08,118.36 57.7,118.99 v1(58.06,118.99)
  BOTTOM w0.127: v1(58.06,118.99) 58.06,118.74 57.22,117.9 57.09,117.9 57.09,117.9 56.85,117.9 56.28,117.33 56.28,116.8 57.6,115.49 VRAM3.C3
MDA44: length 40.6
  TOP w0.127: GPU1.Y24 74.69,104.96 74.3,104.57 v3(74.3,104.54)
  L3 w0.165: v1(55.23,119.65) 55.71,120.13 55.71,120.66 56.05,121 56.31,121 56.68,120.62 57.03,120.62 57.55,121.14 57.98,121.14 58.3,120.82 64.48,120.82 71.51,113.78 71.51,110.5 72.42,109.6 73.41,109.6 73.57,109.43 73.57,108.9 73.41,108.73 72.67,108.73 72.5,108.57 72.5,108.11 72.67,107.95 72.87,107.95 73.04,107.78 73.04,106.74 73.24,106.54 74.13,106.54 74.29,106.37 74.29,106.04 74.05,105.79 73.8,105.79 73.63,105.62 73.63,105.24 74.3,104.58 v3(74.3,104.54)
  BOTTOM w0.127: VRAM3.D7 54.03,114.97 54.03,116.36 54.25,116.57 54.5,116.57 54.82,116.89 54.82,118.38 54.82,118.39 54.82,119.25 v1(55.23,119.65)
MDA45: length 39.3
  TOP w0.127: GPU1.AA24 74.7,105.79 v3(74.29,105.38)
  L3 w0.165: v3(74.29,105.38) 74.78,105.87 74.78,108.29 74.62,108.45 74.13,108.45 73.96,108.62 73.96,109.05 74.13,109.22 74.56,109.22 74.73,109.38 74.73,109.88 74.56,110.04 72.53,110.04 71.88,110.69 71.88,112.08 72.05,112.24 72.5,112.24 72.67,112.41 72.67,112.74 72.5,112.9 72.05,112.9 71.88,113.07 71.88,113.94 64.31,121.51 63.72,121.51 63.41,121.2 63.03,121.2 62.72,121.51 62.39,121.51 62.06,121.18 61.73,121.18 61.4,121.51 61.07,121.51 60.74,121.18 60.41,121.18 60.08,121.51 59.75,121.51 59.42,121.18 59.09,121.18 58.76,121.51 56.17,121.51 55.22,120.55 v1(55.22,120.33)
  BOTTOM w0.127: v1(55.22,120.33) 54.39,119.51 54.39,117.01 VRAM3.A7
MDA46: length 40.5
  TOP w0.127: GPU1.Y22 76.72,104.58 v3(76.72,104.56)
  L3 w0.165: v3(76.72,104.56) 76.37,104.91 76.37,105.72 75.48,106.61 75.48,111.1 73.52,113.06 73.52,113.35 64.62,122.25 55.58,122.25 v1(53.49,120.16)
  BOTTOM w0.127: VRAM3.C8 53.17,115.83 53.17,117.16 52.99,117.34 52.99,119.66 v1(53.49,120.16)
MDA47: length 41
  TOP w0.127: GPU1.AA23 75.11,105.41 v3(75.11,105.38)
  L3 w0.165: v1(53.49,119.43) 54.38,119.43 54.55,119.59 54.55,120.48 55.94,121.88 64.46,121.88 73.19,113.15 73.19,112.86 74.17,111.88 74.17,111.44 74,111.27 72.71,111.27 72.54,111.11 72.54,110.63 72.71,110.46 74.94,110.46 75.11,110.29 v3(75.11,105.38)
  BOTTOM w0.127: VRAM3.B8 53.72,116.32 53.72,116.59 53.97,116.84 53.97,117.16 53.96,117.17 53.96,118.84 53.49,119.3 v1(53.49,119.43)
MDA48: length 35
  TOP w0.127: v1(59.89,124.13) 59.89,121.62 58.94,120.67 58.94,118.53 57.6,117.19 VRAM1.A7 ; GPU1.AD27 72.08,108.3 71.95,108.43 70.96,108.43 70.46,108.93 70.46,109.94 70.55,110.03 70.55,110.65 v3(70.64,110.75)
  L4 w0.165: v1(59.89,124.13) 59.89,123.7 60.34,123.25 63.95,123.25 64.11,123.09 64.11,122.71 64.28,122.54 64.99,122.54 65.22,122.31 65.22,122.08 65.03,121.88 65.03,121.7 65.32,121.41 65.49,121.41 65.76,121.68 65.98,121.68 66.23,121.43 66.23,121.22 65.99,120.98 65.99,120.74 66.23,120.51 66.46,120.51 66.7,120.74 66.91,120.74 67.16,120.49 67.16,120.28 66.98,120.1 66.98,119.86 67.22,119.63 67.45,119.63 67.56,119.74 67.79,119.74 68.03,119.51 68.03,118.79 70.29,116.52 70.29,111.09 v3(70.64,110.75)
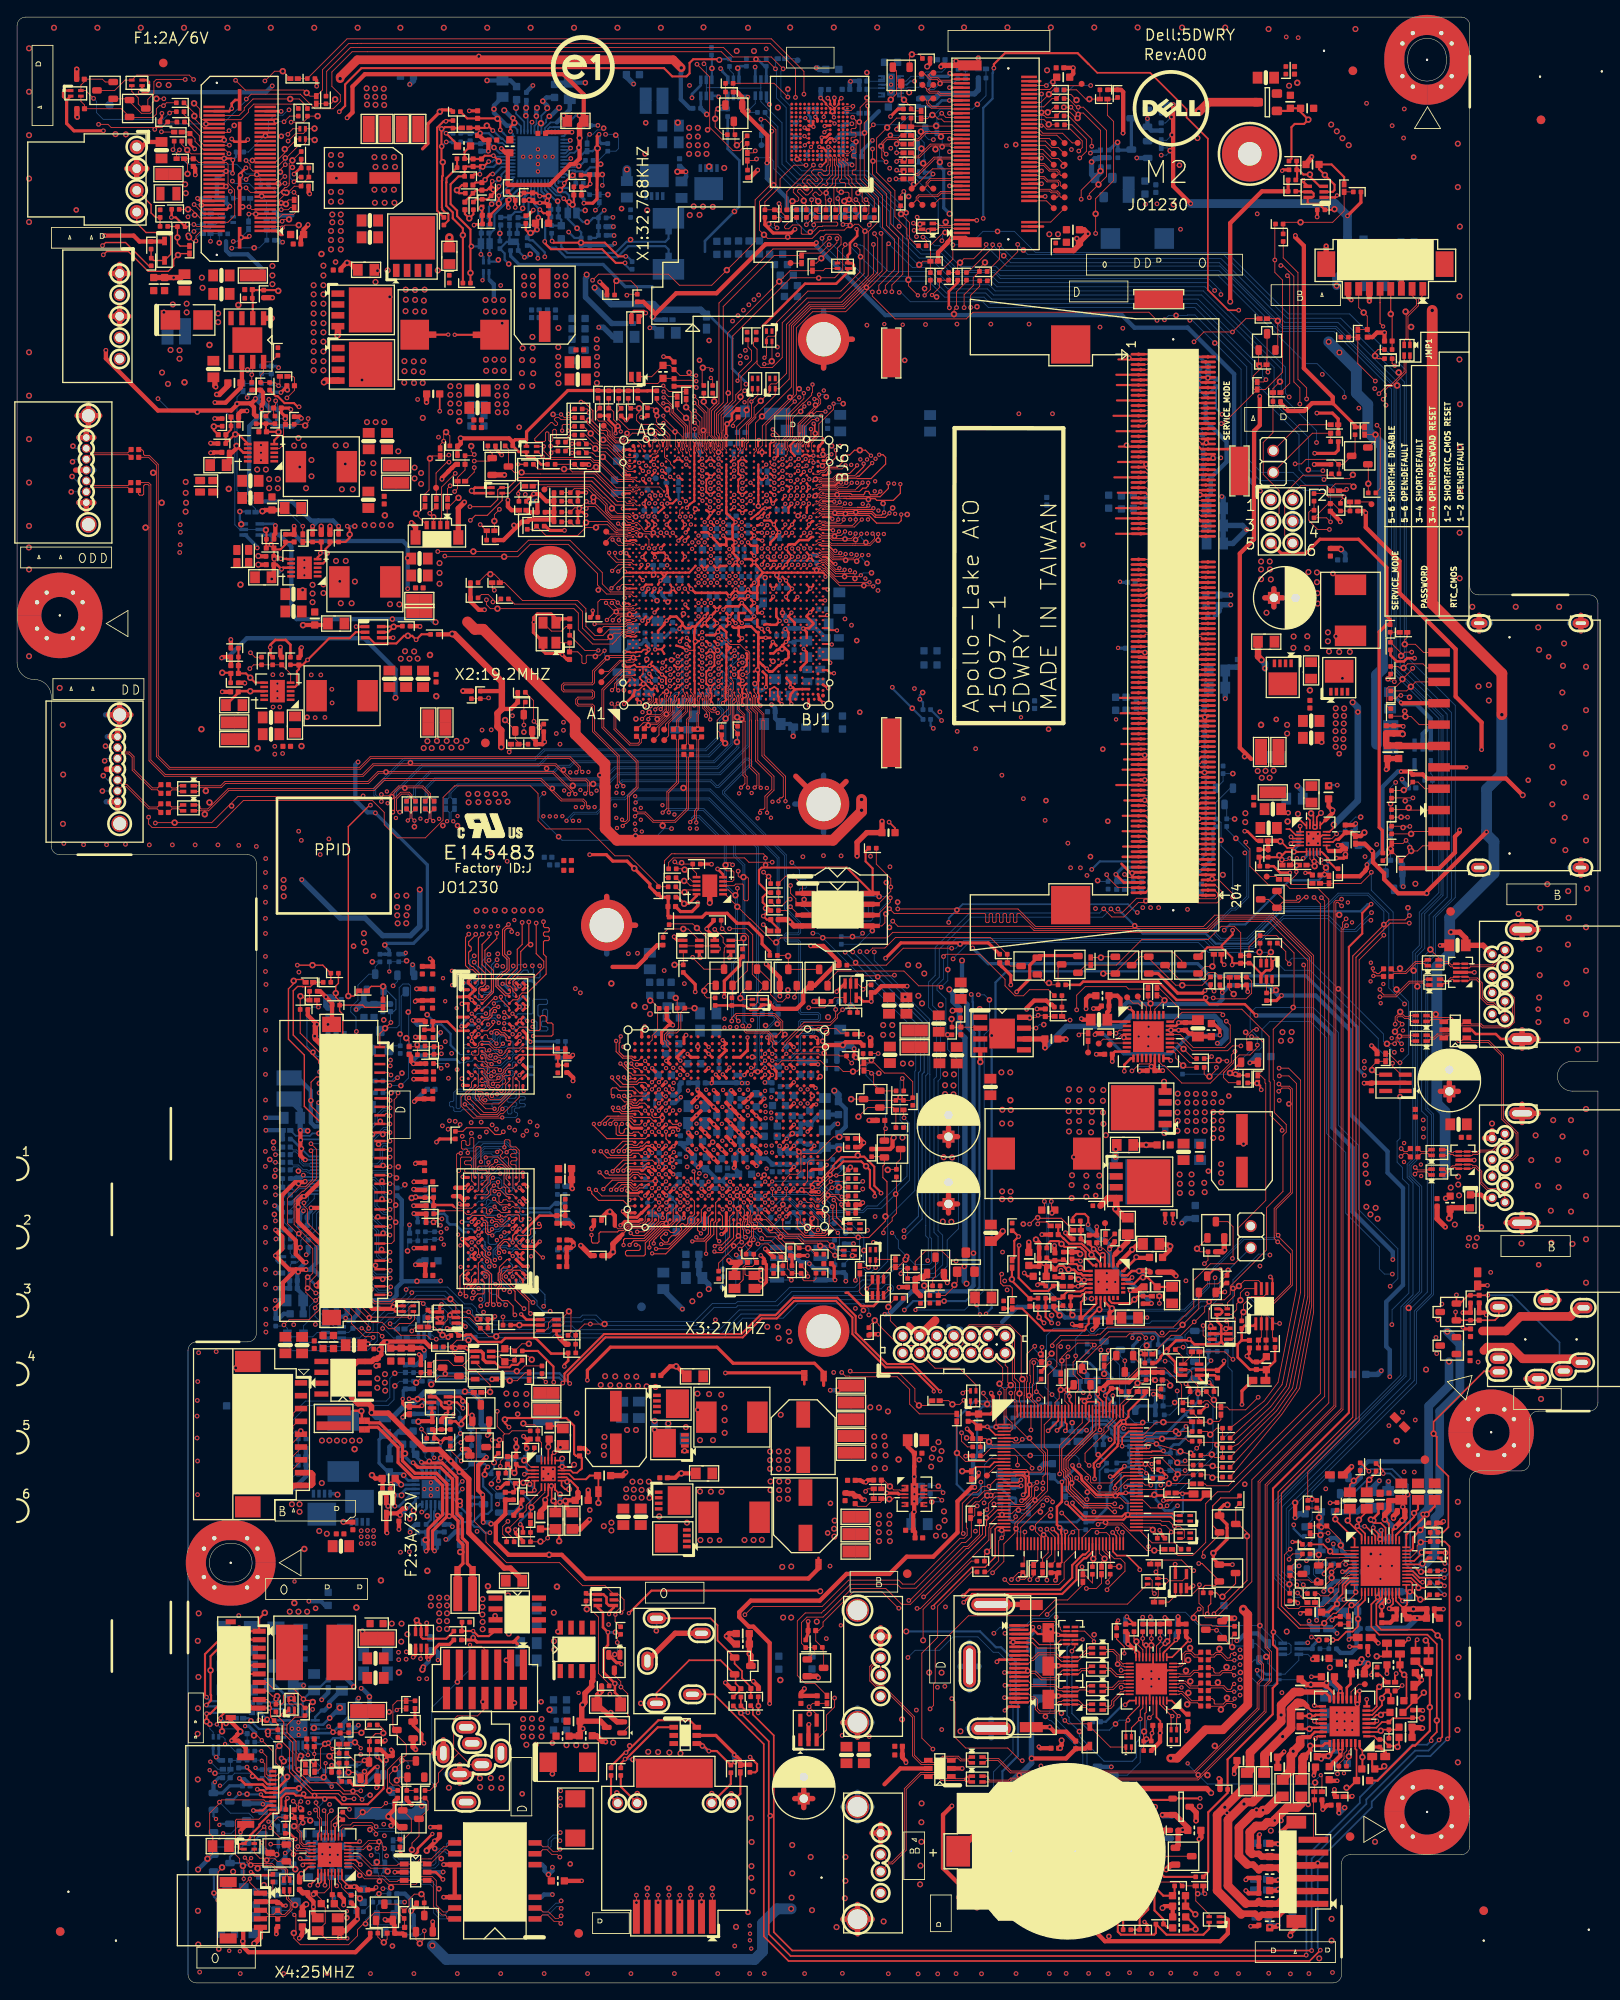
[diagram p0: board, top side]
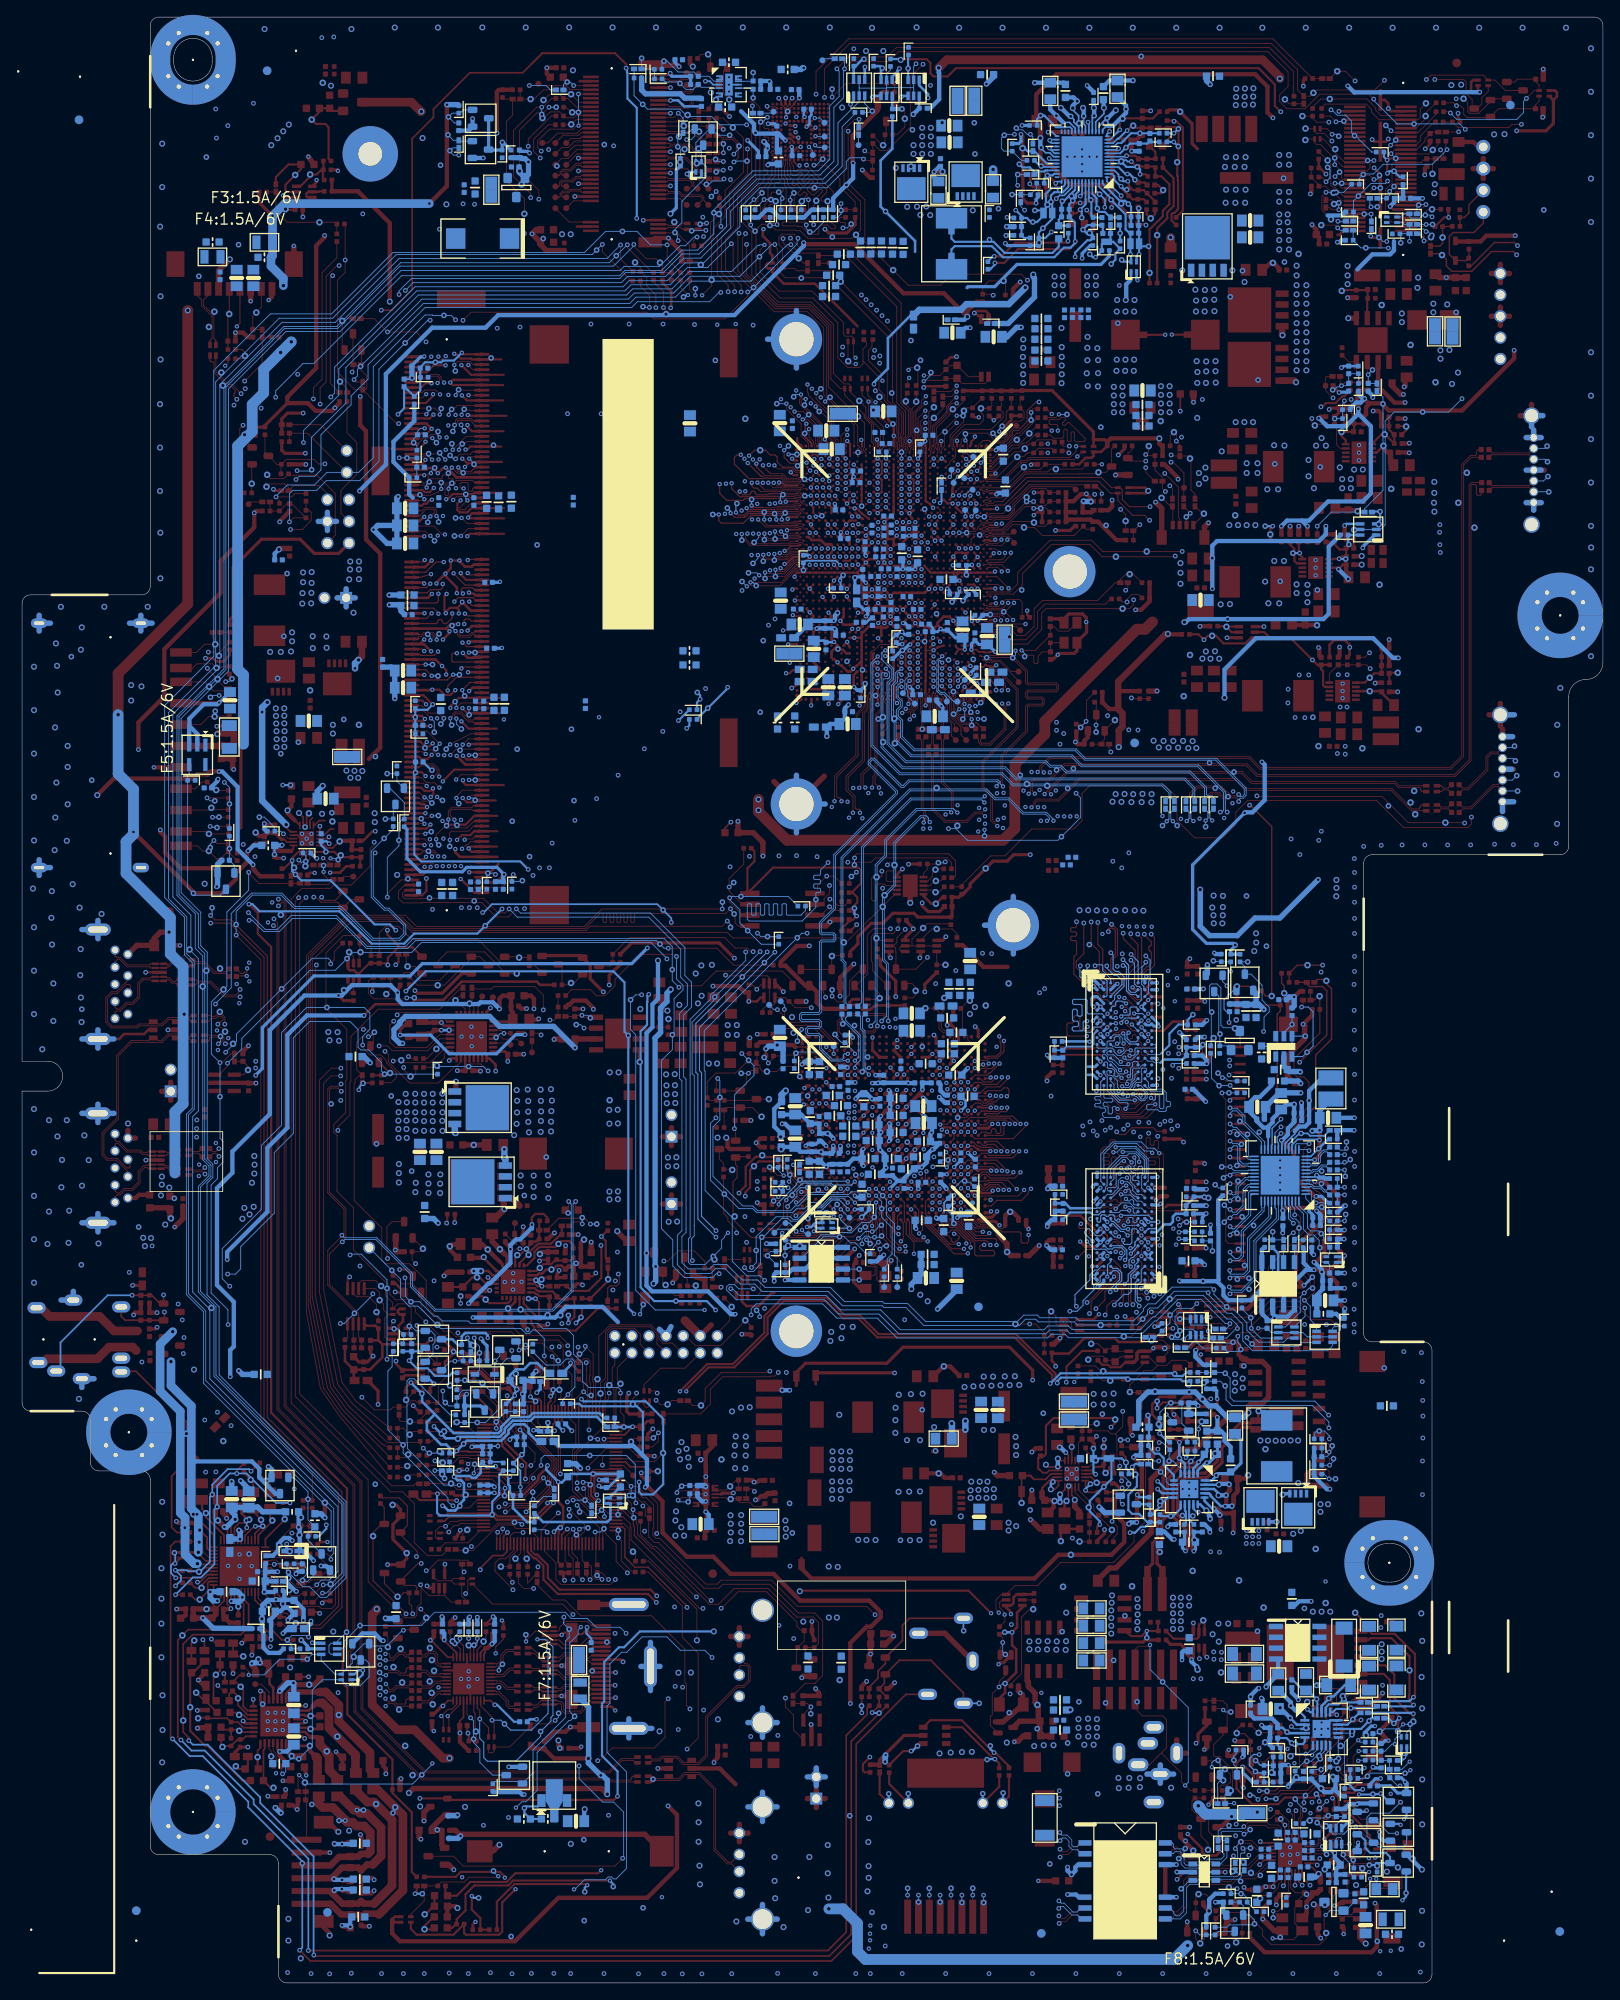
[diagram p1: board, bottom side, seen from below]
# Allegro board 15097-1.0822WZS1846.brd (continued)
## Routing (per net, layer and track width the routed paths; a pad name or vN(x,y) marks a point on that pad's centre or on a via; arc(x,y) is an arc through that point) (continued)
MDA49: length 38.1
  TOP w0.127: VRAM1.B8 58.27,116.33 58.27,116.6 58.03,116.84 58.03,117.15 58.57,117.69 60.51,117.69 61.63,118.81 61.63,119.54 60.75,120.42 v1(60.75,124) ; GPU1.AB25 73.51,106.99 v3(73.51,107.03)
  L4 w0.165: v1(60.75,124) 61.13,123.62 64.8,123.62 68.85,119.58 68.85,119.29 68.56,119.01 68.56,118.79 68.79,118.56 69.01,118.56 69.19,118.75 69.4,118.75 69.66,118.49 69.66,118.28 69.5,118.12 69.5,117.89 69.73,117.65 69.96,117.65 70.07,117.76 70.3,117.76 70.66,117.39 70.66,111.55 71.18,111.03 71.18,109.91 71.81,109.29 71.81,108.19 71.97,108.03 72.83,108.03 72.99,107.86 72.99,107.2 73.16,107.03 v3(73.51,107.03)
MDA50: length 37.6
  TOP w0.127: GPU1.AD26 72.72,107.92 72.14,107.92 72.05,108.01 72.04,108.01 71.86,108.2 70.87,108.2 70.1,108.97 v3(70.1,110.21) ; v1(59.11,124.07) 59.11,121.5 58.53,120.93 58.53,118.73 57.23,117.43 57.23,116.85 57.45,116.63 57.7,116.63 58.03,116.3 58.03,116.04 58.4,115.67 VRAM1.C8
  L4 w0.165: v3(70.1,110.21) 69.89,110.42 69.89,116.32 64.14,122.07 64.14,122.07 63.65,122.55 63.65,122.72 63.49,122.88 63.16,122.88 62.99,122.72 62.99,122.3 62.87,122.17 62.5,122.17 62.33,122.33 62.33,122.72 62.17,122.88 61.84,122.88 61.67,122.72 61.67,122.23 61.51,122.07 61.14,122.07 61.01,122.19 61.01,122.65 60.81,122.86 60.12,122.86 59.11,123.87 v1(59.11,124.07)
MDA51: length 38.3
  TOP w0.127: v1(61.6,124.16) 61.6,123.6 61.73,123.47 62.15,123.47 62.28,123.35 62.28,123.09 62.15,122.97 61.73,122.97 61.6,122.84 61.6,122.58 61.73,122.46 62.15,122.46 62.28,122.33 62.28,122.08 62.15,121.95 61.73,121.95 61.6,121.82 61.6,120.37 61.91,120.06 61.91,118.04 59.7,115.83 59.1,115.83 58.77,115.5 58.77,115.25 58.55,115.03 58.03,115.03 VRAM1.D7 ; v3(73.5,107.87) 73.5,107.85 GPU1.AC25
  L4 w0.165: v1(61.6,124.16) 64.78,124.16 71.03,117.91 71.03,111.84 71.65,111.22 71.65,109.95 72.22,109.38 72.22,108.69 72.39,108.53 73.07,108.53 73.5,108.1 v3(73.5,107.87)
MDA52: length 38
  TOP w0.127: v1(55.26,122.75) 55.26,122.35 54.42,121.51 54.42,119.12 55.5,118.04 55.5,115.98 54.55,115.03 53.97,115.03 VRAM1.C2 ; v3(71.65,105.93) 71.79,105.8 GPU1.AA27
  L4 w0.165: v3(71.65,105.93) 71.65,105.97 71.21,106.42 71.2,106.42 70.65,106.97 70.44,106.97 68.39,109.02 68.39,115.61 63.33,120.67 59.18,120.67 58.1,121.75 57.4,121.75 56.83,122.32 55.69,122.32 v1(55.26,122.75)
MDA53: length 38.4
  TOP w0.127: GPU1.AA26 72.85,105.8 72.46,105.41 71.53,105.41 71.02,105.92 v3(71.02,105.95) ; VRAM1.C3 54.4,115.42 54.03,115.79 54.03,116.35 54.25,116.57 54.5,116.57 54.77,116.85 54.77,118.14 53.99,118.93 53.99,122.26 v1(54.44,122.71)
  L4 w0.165: v3(71.02,105.95) 71.01,105.96 71.01,105.97 70.33,106.65 70.13,106.65 69.19,107.59 69.19,107.62 68.03,108.79 68.03,115.45 63.18,120.3 59.02,120.3 57.94,121.38 57.25,121.38 56.68,121.95 55.19,121.95 v1(54.44,122.71)
MDA54: length 38.9
  TOP w0.127: v3(69.63,105.95) 69.63,105.79 69.75,105.67 69.75,105.66 70.59,104.83 72.14,104.83 72.85,104.12 GPU1.W26 ; VRAM1.A2 53.6,117.02 54.02,117.44 54.02,117.84 53.31,118.55 52.96,118.55 52.48,119.03 52.48,122.32 v1(52.86,122.7)
  L4 w0.165: v1(52.86,122.7) 54.5,121.07 56.35,121.07 57.85,119.57 62.32,119.57 62.33,119.57 62.87,119.57 67.28,115.15 67.28,108.45 69.63,106.11 v3(69.63,105.95)
MDA55: length 38.9
  TOP w0.127: VRAM1.A3 54.33,117.07 54.33,117.92 53.33,118.91 53.21,118.91 52.84,119.28 52.84,120.59 52.97,120.72 53.02,120.72 53.15,120.84 53.15,121.18 53.02,121.3 52.97,121.3 52.84,121.43 52.84,121.81 53.67,122.63 v1(53.67,122.69) ; GPU1.Y25 73.51,105.35 72.77,105.35 72.55,105.13 70.93,105.13 70.34,105.72 v3(70.34,105.96)
  L4 w0.165: v3(70.34,105.96) 67.65,108.64 67.65,115.3 63.02,119.93 58.87,119.93 57.79,121.01 57.04,121.01 56.6,121.45 54.91,121.45 v1(53.67,122.69)
MDA56: length 35.7
  TOP w0.127: v3(69.42,100.5) 69.87,100.95 71.65,100.95 72.2,100.4 72.87,100.4 73.1,100.63 GPU1.R26 ; v3(56.97,111.63) 57.2,111.4 VRAM1.H7
  L4 w0.165: v3(69.42,100.5) 69.25,100.67 69.25,100.7 68.61,101.34 66.72,101.34 65.2,102.85 65.2,103.17 65.53,103.5 65.53,103.73 64.48,104.78 64.25,104.78 63.9,104.43 63.66,104.43 63.26,104.84 63.26,105.07 63.62,105.44 63.62,105.67 63.39,105.91 63.16,105.91 62.79,105.54 62.55,105.54 61.62,106.47 59.88,106.47 59.72,106.64 59.72,106.97 59.88,107.13 60.82,107.13 60.99,107.3 60.99,108.47 60.82,108.63 59.25,108.63 59.08,108.8 59.08,109.13 59.25,109.29 60.82,109.29 60.99,109.46 60.99,112.55 60.47,113.06 58.38,113.06 58.16,112.85 57.7,112.85 57.53,112.68 57.53,111.79 57.37,111.63 v3(56.97,111.63)
MDA57: length 34.3
  TOP w0.127: GPU1.T25 73.5,102.04 v3(73.5,102.05) ; v3(57.01,113.57) 57.14,113.44 57.16,113.44 VRAM1.F7
  L4 w0.165: v3(73.5,102.05) 73.96,101.59 74.49,101.59 74.5,101.6 76.16,101.6 76.33,101.43 76.33,101.1 76.16,100.94 73.53,100.94 72.92,101.54 69.6,101.54 69.04,102.1 68.26,102.1 65.74,104.63 65.74,105.55 65.1,106.19 64.31,106.19 61.72,108.78 61.72,112.92 62.34,113.54 62.34,113.78 62.08,114.04 61.85,114.04 61.54,113.74 58.6,113.74 58.48,113.86 57.29,113.86 v3(57.01,113.57)
MDA58: length 34.2
  TOP w0.127: GPU1.N27 70.27,99.16 70.1,99.33 70.1,100.48 v3(70.08,100.5) ; VRAM1.F8 58.39,113 58,113.39 v3(57.97,113.39)
  L4 w0.165: v3(70.08,100.5) 70.57,100.02 72.71,100.02 72.87,100.19 72.87,101 72.71,101.16 69.34,101.16 68.78,101.72 68.03,101.72 66.9,102.86 66.58,102.86 66.27,102.55 66.04,102.55 65.8,102.78 65.8,103.01 66.16,103.37 66.16,103.6 63.19,106.58 62.95,106.58 62.63,106.26 62.4,106.26 62.16,106.49 62.16,106.72 62.59,107.15 62.59,107.39 62.36,107.62 62.12,107.62 61.83,107.33 61.6,107.33 61.37,107.56 61.37,107.8 61.66,108.09 61.66,108.32 61.35,108.62 61.35,112.91 60.87,113.39 v3(57.97,113.39)
MDA59: length 36.2
  TOP w0.127: VRAM1.H8 58.83,111.83 59.59,111.83 60,111.42 61.05,111.42 61.21,111.58 61.21,113.01 61.38,113.18 61.76,113.18 61.93,113.01 61.93,112.48 62.09,112.31 62.55,112.31 62.71,112.15 62.71,110.95 62.55,110.78 v3(60.39,110.78) ; v3(68.79,100.5) 68.93,100.64 68.93,100.69 69.42,101.18 71.86,101.18 72.2,100.84 GPU1.R27
  L4 w0.165: v3(60.39,110.78) 60.53,110.64 60.53,109.79 60.36,109.62 58.86,109.62 58.7,109.46 58.7,108.44 58.86,108.28 60.39,108.28 60.55,108.11 60.55,107.73 60.39,107.56 59.21,107.56 58.99,107.34 58.89,107.34 58.72,107.17 58.72,106.82 58.88,106.66 59.14,106.66 59.31,106.5 59.31,106.26 59.47,106.09 61.44,106.09 66.57,100.97 68.35,100.97 68.79,100.52 v3(68.79,100.5)
MDA60: length 33.7
  TOP w0.127: VRAM1.H3 55.02,111.4 55.72,112.1 v3(55.72,112.43) ; v3(70.41,103.76) 71.09,103.08 71.99,103.08 72.13,102.94 72.47,102.94 72.85,103.32 GPU1.V26
  L4 w0.165: v3(70.41,103.76) 69.85,104.32 69.56,104.32 65.89,107.99 65.89,109.09 65.33,109.65 64.73,109.65 64.57,109.81 64.57,110.54 64.87,110.84 65.51,110.84 65.89,111.22 65.89,113.51 63.27,116.12 56.23,116.12 55.33,115.23 55.33,113.63 55.35,113.62 55.35,112.81 v3(55.72,112.43)
MDA61: length 32.5
  TOP w0.127: v3(53.2,112.6) 53.59,112.2 VRAM1.G2 ; GPU1.V27 71.51,103.32 v3(71.05,103.78)
  L4 w0.165: v3(71.05,103.78) 70.03,104.8 69.6,104.8 66.26,108.14 66.26,113.77 62.96,117.07 62.59,117.07 62.43,116.9 62.43,116.67 62.26,116.51 61.93,116.51 61.77,116.67 61.77,116.9 61.6,117.07 61.27,117.07 61.11,116.9 61.11,116.67 60.94,116.51 60.61,116.51 60.45,116.67 60.45,116.9 60.28,117.07 58.6,117.07 57.99,116.45 56.11,116.45 54.47,114.81 54.47,113.86 v3(53.2,112.6)
MDA62: length 34.3
  TOP w0.127: VRAM1.E3 55.19,114.59 55.19,114.62 55.63,115.05 55.64,115.05 55.82,115.23 v3(55.99,115.23) ; GPU1.W27 72.03,104.39 70.44,104.39 70.12,104.72 69.67,104.72 69.52,104.57 69.52,103.97 v3(69.75,103.73)
  L4 w0.165: v3(69.75,103.73) 69.62,103.73 65.52,107.83 65.52,108.9 65.35,109.06 64.35,109.06 64.19,109.23 64.19,111.04 64.35,111.21 65.35,111.21 65.52,111.37 65.52,111.7 65.35,111.87 64.35,111.87 64.19,112.04 64.19,112.37 64.35,112.53 65.35,112.53 65.52,112.7 65.52,113.03 65.35,113.19 64.35,113.19 64.19,113.36 64.19,113.62 64.35,113.79 64.55,113.79 64.72,113.95 64.72,114.16 63.13,115.74 56.89,115.74 56.81,115.83 56.42,115.83 55.99,115.4 v3(55.99,115.23)
MDA63: length 32.3
  TOP w0.127: v3(71.73,103.82) 71.79,103.76 73.54,103.76 GPU1.W25 ; VRAM1.F2 v3(53.2,113.4)
  L4 w0.165: v3(71.73,103.82) 70.41,105.14 69.78,105.14 67.65,107.26 67.65,107.26 66.62,108.29 66.62,113.93 63.2,117.36 56.57,117.36 53.86,114.64 53.82,114.64 53.38,114.2 53.38,113.57 v3(53.2,113.4)
MDSI_RCOMP: length 3.9
  TOP w0.305: CPU1.AP7 87.27,153.41 87.69,152.98 87.69,151.66 v3(87.64,151.61)
  BOTTOM w0.381: v3(87.64,151.61) 87.25,151.23 R609.2 86.34,151.76 v2(86.34,152.02)
ME_UNLOCK: length 175.5
  TOP w0.102: R146.2 159.52,174.85 159.52,181.86 v1(159.14,182.25) ; U14.23 116.22,56.53 116.78,55.96 117.79,55.96 118.73,56.9 118.73,57.95 v1(119.35,58.57)
  L3 w0.127: v1(119.35,58.57) 119.76,58.98 120.87,58.98 121.71,58.14 122.82,58.14 123.18,58.5 129.93,58.5 131.17,57.25 133.69,57.25 133.69,57.25 135.09,57.25 135.59,56.76 138.76,56.76 157.88,75.88 157.88,79.37 160.56,82.04 161.36,82.04 163.12,83.8 163.12,95.86 163.92,96.67 163.92,122.27 165.49,123.83 165.49,155.46 163.09,157.86 163.09,174.89 163.08,174.91 163.08,177 163.06,177.01 163.06,178.3 159.14,182.22 v1(159.14,182.25)
  BOTTOM w0.102: v2(118.51,58.29) 118.79,58.57 v1(119.35,58.57)
ME_UNLOCK_1: length 3.4
  TOP w0.102: Q7.B 158.13,177.63 v4(158.13,175.41) 158.13,174.34 R146.1
ME_UNLOCK_2: length 3.1
  TOP w0.102: Q7.E 158.96,180.53 v4(158.96,181.15) R124.2
ME_UNLOCK_3: length 15.6
  TOP w0.102: v4(156.32,176.45) 156.32,176.38 155.94,176 154.37,176 R140.1 153.65,176.4 150.48,176.4 148.34,174.27 148.34,169.39 JMP1.6
MEM_MA_EVENT_L: length 18.7
  TOP w0.102: v1(142.26,127.03) 142.26,127.43 140.64,129.05 DIMM1.198
  BOTTOM w0.102: v1(142.26,127.03) 142.26,131.68 140.9,133.04 v2(140.9,133.69) 140.9,135.75 140.48,136.17 R628.1 140.27,138.1 141.95,139.78 Q53.E
MEM_VTT: length 6.6
  TOP w0.254: DIMM1.204 138.19,127.25 137.69,127.75 v1(137.69,129.21) ; 132.05,127.55 133.38,128.88 133.38,128.9 133.66,129.18 v3(133.66,129.16)
  TOP w0.305: DIMM1.203 132.05,127.55
  vias: v2(139.84,129.19) v5(141.1,129.64)
MIC2-L: length 4.4
  TOP w0.203: U16.47 157.74,52.57 157.03,53.29 v4(157.03,54.18) 157.03,54.23 157.94,55.14 C152.1
MIC2-L-1: length 2.9
  TOP w0.203: C152.2 157.94,58.57 v4(158.24,58.87) 159.04,59.66 R372.1
MIC2-R: length 4.5
  TOP w0.203: C151.1 155.96,54.36 v4(155.71,54.1) 155.71,54.03 157.35,52.39 U16.48
MIC2-R-1: length 3.1
  TOP w0.203: R370.1 157.18,59.47 156.48,58.78 156.45,58.78 v4(156.42,58.75) 155.96,58.29 C151.2
MIC2-VREFO-L: length 5.4
  TOP w0.203: R384.1 154.26,55.11 v4(154.26,54.25) 154.29,54.23 154.29,54.18 156.52,51.95 U16.1
MIC2-VREFO-R: length 3
  TOP w0.203: R406.1 165.25,48.11 v4(164.29,48.11) 164.07,48.11 163.61,48.57 U16.30
MIC-CAP: length 6.9
  TOP w0.203: U16.36 162.57,51.99
  TOP w0.254: 162.57,51.99 162.57,52.44 v4(164.95,54.82) 165.9,55.77 C147.2
MINI_POWER_CTRL: length 214.8
  TOP w0.102: v1(121.18,56.27) 121.18,56.48 120.71,56.94 120.33,56.94 117.05,53.65 U14.33
  L3 w0.127: v1(121.18,56.27) 121.73,56.82 123.74,56.82 123.96,57.04 125.42,57.04 126.13,56.33 127.52,56.33 128.26,55.59 128.63,55.59 129.27,54.95 138.45,54.95 158.9,75.41 158.9,78.5 163.9,83.51 163.9,83.53 163.91,83.54 163.91,89.28 165.44,90.81 165.44,102.03 165.13,102.34 165.13,122.35 166.28,123.49 166.28,155.75 163.85,158.18 163.85,175.21 163.84,175.22 163.84,177.31 163.82,177.33 163.82,177.96 163.82,179.18 157.69,185.32 157.69,191.91 151.08,198.52 151.08,199.37 144.72,205.74 143.87,205.74 135.76,213.84 v1(133.89,213.84)
  BOTTOM w0.102: R531.1 134.61,214.69 v2(134.93,214.38) 134.93,214.27 134.5,213.84 v1(133.89,213.84)
MIPI_PMODE: length 4.2
  TOP w0.102: CPU1.B19 71.93,158.97 71.93,158.97 71.48,158.97 71.22,158.71 68.64,158.71 TP36.1
MODEL_ID_DET: length 6
  TOP w0.102: v1(129.5,64.89) 129.55,64.93 U14.95
  BOTTOM w0.102: v1(129.5,64.89) v2(129.5,65.65) 129.5,65.72 R720.2 128.36,66.85 R721.1 127.29,66.84 C467.2
MPCIE_DISABLE_N: length 224.7
  TOP w0.102: R25.1 123.05,218.44 125.76,215.72 v1(125.76,214.88) ; U14.40 119.85,52.17 119.18,52.83 119.18,53.64 119.79,54.25 119.82,54.25 v1(120.98,55.42)
  L3 w0.127: v1(120.98,55.42) 121.66,55.42 121.94,55.71 122.54,55.71 122.59,55.66 126.84,55.66 128.13,54.38 138.62,54.38 159.59,75.36 159.59,78.46 164.42,83.29 164.42,89.03 165.95,90.55 165.95,122.1 166.78,122.94 166.78,155.54 166.78,155.96 164.36,158.39 164.36,175.42 164.35,175.43 164.35,177.53 164.33,177.54 164.33,179.44 158.41,185.36 158.41,191.97 151.79,198.59 151.79,199.39 144.56,206.62 143.75,206.62 135.71,214.65 125.99,214.65 v1(125.76,214.88)
  BOTTOM w0.102: v2(120.93,54.64) 120.93,55.37 v1(120.98,55.42)
NCP81172_FB1: length 4.1
  TOP w0.254: v1(120.18,77.22) 119.48,77.91 PR125.1 118.59,79.1 PC96.1
  BOTTOM w0.254: v2(119.59,77.88) 119.59,77.8 v1(120.18,77.22)
NCT3956_OE#_MUX: length 4.8
  TOP w0.102: U2.6 79.51,129.82 79.07,130.26 R197.2 77.22,130.91 v1(76.96,131.17)
  BOTTOM w0.102: v2(77.77,131.06) 77.07,131.06 v1(76.96,131.17)
NCT_CLK: length 9.2
  TOP w0.102: 142.12,78.21 142.16,78.21 142.72,78.77 142.72,79.44 v4(143.15,79.88) 143.15,80.74 143.64,81.23 U12.8 ; 142.12,78.21 142.55,77.78 142.55,75.6 142.25,75.3 Q32.1 ; 142.12,78.21 RN9.3
NCT_DATA: length 12
  TOP w0.102: U12.7 145.61,81.85 145.29,82.17 143.62,82.17 v4(142.98,81.53) 142.45,81 142.45,80.39 141.64,79.58 141.64,78.87 RN9.4 141.04,79.45 140.01,79.45 139.46,78.9 139.46,77.38 139.87,76.97 Q32.4
Net_73: length 51.4
  TOP w0.127: 124.25,51.38 124.25,52.98 v1(122.24,54.98)
  L4 w0.127: v1(122.24,54.98) 122.21,54.95 118.34,54.95 116.42,56.87 116.42,60.25 111.26,65.41 110.01,65.41 102.28,73.14 102.28,77.84 103.66,79.22 105.37,79.22 105.52,79.07 111.97,79.07 112.68,78.36 v3(112.68,78.23)
  BOTTOM w0.127: v3(112.68,78.23) 112.56,78.36 112.56,78.87 112.43,78.99 112.43,79.25 v2(112.3,79.38)
NGFF_ALERT_N: length 3.8
  TOP w0.102: NGFF1.62 119.78,220 v4(120.75,220.97) 121.26,221.49 R10.2
NGFF_BT_DISABLE: length 231.2
  TOP w0.102: v1(125.2,56.57) 125,56.57 123.53,58.04 123.53,59.28 123.22,59.59 123.22,60.05 122.99,60.28 122.99,61.06 123.12,61.19 123.12,61.23 126.13,64.24 126.92,64.24 127.19,64.5 127.19,64.94 128.25,66 U14.100 ; v1(124.36,213.51) 125.13,214.29 125.13,215.7 123.44,217.4 R29.1
  L3 w0.127: v1(124.36,213.51) 127.52,213.51 128.31,214.31 135.69,214.31 143.91,206.1 144.72,206.1 151.43,199.39 151.43,198.58 157.94,192.06 157.94,185.45 164.08,179.31 164.08,177.85 164.08,177.43 164.09,177.42 164.09,175.33 164.1,175.31 164.1,158.28 166.53,155.85 166.53,123.37 165.39,122.22 165.39,102.46 165.69,102.16 165.69,90.68 164.17,89.15 164.17,83.41 159.15,78.4 159.15,75.3 138.49,54.64 128.25,54.64 126.84,56.05 125.72,56.05 v1(125.2,56.57)
  BOTTOM w0.102: v1(125.2,56.57) 125.24,56.6 v2(125.24,57.42)
NGFF_CLKREQ0_N: length 5.3
  TOP w0.102: R24.1 106.55,218.13 106.96,218.54 v4(107.11,218.54) 107.33,218.54 107.8,218.07 108.17,218.07 108.49,217.75 NGFF1.53
NGFF_CLKREQ1_N: length 6.4
  TOP w0.102: NGFF1.68 118.45,221.53 120.85,221.53 121.29,221.97 124.36,221.97 TP3.1
NGFF_DETECT_PCIE: length 62.4
  TOP w0.102: v3(105.42,197.45) 104.3,198.56 v4(104.3,199.26) 104.3,203.52 104.3,203.92 104.12,204.1 104.12,205.26 102.73,206.66 102.73,209.7 100.59,211.84 100.59,215.85 v4(101.82,217.08) 102.93,218.19 R26.2 ; CPU1.AP51 87.62,174.08 v1(87.71,174.08)
  L3 w0.127: v1(87.71,174.08) 87.71,175.59 87.04,176.26 87.04,178.4 87.22,178.58 87.22,182.32 87.61,182.71 87.61,184.1 90.59,187.08 90.59,192.84 93.28,195.53 103.61,195.53 105.42,197.33 v3(105.42,197.45)
NGFF_DETECT_PCIE_C: length 7
  TOP w0.102: NGFF1.51 107.59,217.25 107.58,217.26 v4(107.56,217.26) 107.54,217.25 104.94,217.25 104.86,217.17 R30.2 R26.1
NGFF_DETECT_USB: length 42.2
  TOP w0.102: v3(87.72,173.34) 87.59,173.34 CPU1.AP49 ; v3(106.21,197.44) 106.87,198.11 R85.2
  L3 w0.127: v3(106.21,197.44) 106.21,197.33 104.07,195.2 93.34,195.2 90.88,192.74 90.88,187.07 87.83,184.01 87.83,182.62 87.48,182.27 87.48,178.36 87.26,178.14 87.26,177.3 88.14,176.42 88.14,173.77 v3(87.72,173.34)
  BOTTOM w0.102: v3(106.21,197.44) v2(106.21,198.23)
NGFF_DETECT_USB_C: length 9
  TOP w0.102: R78.2 106.88,203.29 108.34,204.75 NGFF1.1 ; R78.2 106.87,201.42 R85.1 ; R78.2 105.99,201.43 v4(105.57,201.02)
NGFF_PCIE0_RXN: length 7.1
  TOP w0.102: 106.08,214.36 106.86,215.14 109.17,215.14 109.28,215.25 NGFF1.43 ; 106.08,214.36 105.46,213.74 105,213.74 R37.1 ; 106.08,214.36 v4(105.83,214.61)
NGFF_PCIE0_RXP: length 7.2
  TOP w0.102: NGFF1.41 109.33,214.75 109.16,214.92 107.47,214.92 ; 107.47,214.92 106.95,214.92 105.55,213.53 105.04,213.53 R42.1 ; 107.47,214.92 v4(107.47,214.54)
NGFF_PCIE0_TXN: length 7.3
  TOP w0.102: 106.3,212.62 v4(106.03,212.89) ; 106.3,212.62 105.39,211.71 105,211.71 R45.1 ; 106.3,212.62 107.3,213.61 109.38,213.61 109.52,213.75 NGFF1.37
NGFF_PCIE0_TXP: length 7.4
  TOP w0.102: 107.99,213.4 107.39,213.4 105.48,211.49 105.04,211.49 R49.1 ; 107.99,213.4 v4(107.99,213.03) ; 107.99,213.4 109.41,213.4 109.55,213.25 NGFF1.35
NGFF_PCIE1_RXN: length 5
  TOP w0.102: TP5.1 106.67,221.58 106.67,221.47 106.82,221.32 107.82,221.32 108.07,221.07 109.31,221.07 109.5,221.25 NGFF1.67
NGFF_PCIE1_RXP: length 5.3
  TOP w0.102: NGFF1.65 109.51,220.75 109.4,220.85 107.98,220.85 107.73,221.11 106.73,221.11 106.46,221.38 106.46,221.62 TP4.1
NGFF_PCIE1_TXN: length 5.1
  TOP w0.102: TP7.1 106.93,220.47 106.67,220.22 106.67,219.95 107.07,219.56 109.29,219.56 109.48,219.75 NGFF1.61
NGFF_PCIE1_TXP: length 5.3
  TOP w0.102: TP6.1 106.21,220.47 106.46,220.22 106.46,219.86 106.98,219.34 109.37,219.34 109.46,219.25 NGFF1.59
NGFF_PEWAKE0_N: length 22
  TOP w0.102: NGFF1.55 108.7,218.25 v1(108.2,218.75) ; v1(120.45,221.99) 120.44,222 NGFF1.70
  L4 w0.127: v1(108.2,218.75) 109.23,219.78 109.31,219.78 109.53,220 116.64,220 118.63,221.99 v1(120.45,221.99)
  BOTTOM w0.102: v1(120.45,221.99) 120.87,222.4 v2(121.21,222.4) 121.34,222.4 121.64,222.1 R522.2 ; v1(108.2,218.75) 107.64,218.19 R529.1
NGFF_POWER_CTRL_1: length 3.2
  BOTTOM w0.102: Q50.G 133.8,215.49 R531.2 134.52,215.58 v2(135.15,216.22)
NGFF_POWER_CTRL_V2: length 4.7
  BOTTOM w0.102: C244.1 134.39,217.61 v2(135.09,218.31) 134.65,218.76 R525.1 133.75,218.9 133.58,218.9 133.33,219.14 Q48.B
NGFF_REFCLKN0: length 6.9
  TOP w0.102: 106.02,216.35 105.76,216.09 105.76,216.09 105.41,215.75 105.02,215.75 R33.1 ; 106.02,216.35 v4(105.77,216.6) ; 106.02,216.35 106.27,216.6 109.35,216.6 109.5,216.75 NGFF1.49
NGFF_REFCLKN1: length 4.9
  TOP w0.102: NGFF1.73 109.43,222.75 109.29,222.61 108.05,222.61 107.77,222.9 106.94,222.9 106.7,223.14 106.7,223.28 106.89,223.47 TP1.1
NGFF_REFCLKP0: length 6.9
  TOP w0.102: NGFF1.47 109.49,216.25 109.35,216.39 108.12,216.39 ; v4(108.12,216.01) 108.12,216.39 ; 108.12,216.39 106.36,216.39 105.85,215.87 105.85,215.87 105.5,215.53 105.01,215.53 R36.1
NGFF_REFCLKP1: length 5.2
  TOP w0.102: TP2.1 106.13,223.41 106.85,222.68 107.68,222.68 107.96,222.4 109.35,222.4 109.5,222.25 NGFF1.71
NGFF_W_DISABLE1_N: length 6.4
  TOP w0.102: v4(124.1,218.19) 123.91,218.19 123.19,218.91 122.1,218.91 R25.2 121.42,218.23 120.45,218.23 120.18,218.5 NGFF1.56
NGFF_W_DISABLE2_N: length 3.5
  TOP w0.102: NGFF1.54 120.18,218 v4(120.73,217.45) 120.78,217.4 R29.2
NGFF_WAKE_CPU: length 64.1
  TOP w0.089: CPU1.N62 77.3,179.52 77.16,179.66 77.05,179.77 77.05,181.1 v3(75.64,182.51)
  L3 w0.127: v1(108.22,203.84) 108.19,203.81 108.01,203.81 106.87,202.67 98.42,202.67 98.4,202.65 87.37,202.65 75.18,190.47 75.18,182.97 v3(75.64,182.51)
  BOTTOM w0.102: v1(108.22,203.84) 108.31,203.93 108.31,204.51 v2(108.6,204.8) 108.6,205.15 107.78,205.96 107.78,208.44 105.07,211.16 105.07,211.18 104.94,211.31 104.94,212.51 RN21.3 105.5,214.8 Q49.C
NGFF_WAKE_N: length 31.2
  L4 w0.127: v1(107.23,215.66) 107.23,215.67 108.5,216.93 117.13,216.93 122.19,222 v1(125.64,222)
  BOTTOM w0.102: v1(107.23,215.66) 106.68,215.66 106.28,216.07 Q49.E 106.58,216.91 107.04,216.46 R529.2 108.26,215.83 v2(108.26,214.82) 107.96,214.52 R536.1 ; R522.1 123.16,221.48 123.68,222 v1(125.64,222)
NGFF_WAKE_N_LS: length 7.2
  BOTTOM w0.102: v2(102.19,216.18) 103.58,216.18 Q49.B 104.56,216.91 106.15,215.32 RN21.4
OSD_BIST_N: length 85.2
  TOP w0.102: v1(117.13,47.22) 117.91,47.22 118.37,47.68 118.37,48.71 118.57,48.91 R401.1 119.45,49.4 U14.39 ; R329.1 v1(56.87,77.93)
  L4 w0.127: v1(56.87,77.93) 58.47,76.33 82.17,76.33 86.23,72.26 99,72.26 104.85,66.42 104.85,60.49 106.94,58.39 107.99,58.39 108.56,57.83 110.62,55.77 110.62,53.73 111.68,52.67 111.68,52.66 111.95,52.39 111.96,52.39 v1(117.13,47.22)
  BOTTOM w0.102: v2(117.71,47.67) 117.26,47.22 v1(117.13,47.22)
OSD_BIST_N_1: length 3.5
  TOP w0.305: Q31.2 v4(58.78,76.96) R329.2
OSD_BIST_N_LS: length 176.9
  TOP w0.102: R401.2 118.96,47.62 v1(118.52,47.18)
  L4 w0.127: v3(127.2,20.5) 127.2,17.32 130.22,14.3 130.22,12.09 128.02,9.88 120.4,9.88 112.84,2.32 26.82,2.32 25.27,3.88 25.27,3.94 22.3,6.92 22.3,23.69 22.99,24.38 22.99,25.51 v3(22.61,25.88) ; v3(119.61,41.63) 119.61,41.95 118.96,42.61 118.96,46.75 v1(118.52,47.18)
  BOTTOM w0.102: v3(22.61,25.88) 23.5,24.99 R783.2 ; v3(119.61,41.63) 119.92,41.32 119.92,40.77 120.91,39.78 120.91,31.75 v2(120.34,31.18) 120.82,30.7 120.99,30.7 124.72,26.97 124.72,22.51 126.04,21.19 126.51,21.19 v3(127.2,20.5)
OSD_DN: length 438.6
  TOP w0.102: v1(100.34,204.67) 100.39,204.62 100.39,204.45 100.71,204.13 100.71,200.14 96.69,196.11 92.83,196.11 90.61,193.9 90.61,186.71 v4(87.18,183.28) 86.41,182.52 86.41,179.67 86.54,179.55 86.54,179.29 86.24,179 CPU1.AM61
  L3 w0.127: v1(100.34,204.67) 100.39,204.62 100.39,204.45 100.63,204.21 102.38,204.21 103.06,203.53 106.34,203.53 108.01,205.21 113.06,205.21 113.67,205.82 127.31,205.82 129.25,203.89 139.99,203.89 155.95,187.93 155.95,183.05 162.31,176.68 162.31,174.59 162.33,174.58 162.33,157.54 164.49,155.38 164.49,133.65 163.18,132.33 162.44,132.33 160.66,130.56 160.66,127.84 159.52,126.7 159.52,123.24 157.4,121.13 157.4,108.24 157.19,108.03 157.19,107.64 157.4,107.42 157.4,107.31 v1(157.67,107.04)
  L4 w0.127: v1(157.67,107.04) 155.1,104.48 155.1,65.57 149.62,60.1 149.62,56.36 147.82,54.55 147.82,35.07 146.62,33.86 146.62,33.45 136.01,22.85 131.96,22.85 130.38,21.26 130.38,16.12 130.73,15.78 130.73,11.87 128.23,9.37 120.62,9.37 113.06,1.82 25.78,1.82 21.79,5.81 21.79,25.69 24.04,27.94 v3(24.34,27.94)
  BOTTOM w0.102: RN24.4 24.09,28.79 24.34,28.54 v3(24.34,27.94) 24.67,27.94 25.5,27.11 C508.2 25.98,27.13 R776.1
OSD_DN_R: length 8.9
  TOP w0.102: v4(30.69,27.73) 30.28,27.33 30.28,25.76 30.67,25.37 30.67,24.56 30.35,24.25 PWRCN1.2 29.38,24.25 29.22,24.41 29.22,26.48 v3(28.58,27.12)
  BOTTOM w0.102: v3(28.58,27.12) 28.57,27.13 R776.2
OSD_MENU: length 261.9
  TOP w0.102: v3(87.67,177.64) 87.67,177.61 87.67,177.61 87.67,177.59 87.36,177.29 CPU1.AP58 ; R405.2 125.84,46.78 125.38,47.25 125.38,47.29 124.86,47.81 R408.1 124.72,48.59 v1(124.62,48.68)
  L3 w0.127: v1(98.68,77.95) 99.42,78.69 102.48,78.69 103.07,79.28 110.23,79.28 110.54,79.28 114.18,82.92 114.18,110.69 116.22,112.73 120.5,112.73 130.62,122.85 130.62,126.58 132.15,128.11 136.88,128.11 137.19,128.42 137.19,129.41 137.47,129.69 138.44,129.69 138.62,129.87 138.62,152.55 138.99,152.93 138.99,158.31 138.49,158.82 138.49,166.96 138.99,167.46 138.99,189.86 136.97,191.88 136.97,192.46 136.56,192.87 136.55,192.87 135.86,193.56 133.19,193.56 132.04,194.71 93.39,194.71 91.51,192.83 91.51,187.19 88.34,184.02 88.34,182.51 87.86,182.03 87.86,178.14 87.67,177.95 v3(87.67,177.64) ; v1(112.15,52.86) 114.84,50.16 122.89,50.16 124.37,48.68 v1(124.62,48.68)
  L4 w0.127: v1(112.15,52.86) 114.05,54.76 114.05,55.63 113.85,55.84 113.85,56.14 113.35,56.64 111.72,56.64 109.37,58.99 107.6,58.99 105.62,60.97 105.62,66.5 98.76,73.37 98.76,77.86 v1(98.68,77.95)
  BOTTOM w0.102: v2(99.04,78.69) 98.68,78.33 v1(98.68,77.95)
OSD_MENU_EC: length 2.9
  TOP w0.102: R405.1 125.84,49.53 v4(125.94,49.63) 126.25,49.94 U14.56
OSD_MENU_LS: length 142.3
  TOP w0.102: v1(106.84,32.05) 107.25,32.46 107.25,34.95 107.44,35.14 107.44,39.07 111.33,42.95 119.62,42.95 121.47,44.8 122.93,44.8 124.72,46.59 R408.2
  L3 w0.127: v3(32.46,46.97) 32.47,46.96 34.06,46.96 34.08,46.94 58.21,46.94 60.3,44.85 62.06,44.85 82.14,44.85 85.2,41.8 85.2,40.72 88.78,37.13 93.3,37.13 98.1,32.33 98.97,32.33 99.65,31.65 102.33,31.65 103.07,32.39 106.5,32.39 v1(106.84,32.05)
  L4 w0.127: v3(23.38,30.25) 22.69,30.94 22.69,33.93 22.05,34.57 22.05,42.52 24.34,44.81 28.23,44.81 29.42,46 31.49,46 v3(32.46,46.97)
  BOTTOM w0.102: RN24.3 22.95,29.34 22.56,29.73 v2(22.56,30.27) 23.36,30.27 v3(23.38,30.25) 23.91,29.72 25.55,29.72 26.14,29.16 C505.2 R774.1
OSD_MENU_R: length 6.2
  TOP w0.102: PWRCN1.1 29.93,27.11 v3(28.63,28.4) 28.07,28.96 v4(27.72,28.96)
  BOTTOM w0.102: v3(28.63,28.4) 28.4,28.17 R774.2
OSD_UP: length 434
  TOP w0.102: v1(101.1,204.7) 101.23,204.57 101.23,200.29 96.82,195.88 92.92,195.88 90.84,193.8 90.84,185.81 87.21,182.18 87.21,179.88 86.74,179.41 86.74,179.21 86.71,179.17 CPU1.AN62
  L3 w0.127: v1(157.66,107.83) 157.66,121.02 159.77,123.14 159.77,126.57 160.92,127.71 160.92,130.45 162.53,132.07 163.27,132.07 164.75,133.54 164.75,155.48 162.58,157.65 162.58,174.68 162.57,174.7 162.57,176.79 162.55,176.8 162.55,177.03 156.38,183.2 156.38,187.86 140.05,204.19 129.5,204.19 127.61,206.08 113.53,206.08 112.94,205.48 107.93,205.48 106.23,203.78 103.24,203.78 102.51,204.52 101.28,204.52 v1(101.1,204.7)
  L4 w0.127: v1(157.66,107.83) 154.54,104.71 154.54,65.73 149.21,60.4 149.21,56.66 147.4,54.85 147.4,35.45 146.11,34.15 146.11,33.31 136.16,23.36 132.11,23.36 130.13,21.37 130.13,16.01 130.47,15.67 130.47,11.98 128.12,9.63 120.51,9.63 112.95,2.07 25.88,2.07 22.04,5.91 22.04,24.06 22.5,24.52 22.5,24.86 v3(22.54,24.89)
  BOTTOM w0.102: R779.1 25.95,26.06 C510.2 25.93,26.04 R780.2 R783.1 24.96,24.8 24.7,24.54 23.16,24.54 v2(23.15,24.53) 22.89,24.53 v3(22.54,24.89)
OSD_UP_R: length 6.9
  TOP w0.102: v3(28.63,25.99) 28.99,25.63 28.99,24.21 29.45,23.75 PWRCN1.3 30.49,23.75 30.97,24.23 30.97,25.7 v4(31.2,25.93)
  BOTTOM w0.102: R779.2 28.56,26.06 v3(28.63,25.99)
OZ554_ENA: length 7.2
  TOP w0.102: R453.1 41.22,30.19 v4(40.29,29.26) 40.28,29.27 R455.1 38.77,29.25 C198.1 37.21,29.25 v1(36.46,30)
  BOTTOM w0.102: U35.3 36.13,29.72 36.41,30 v1(36.46,30)
OZ554_PWM: length 6.5
  BOTTOM w0.254: U35.5 34.88,28.19 35.14,27.94 36.3,27.94 v2(36.43,28.07) 37.02,28.65 C507.1 38.07,27.81 R775.1 37.69,27.43 R778.1
OZ554_VIN: length 7.7
  BOTTOM w0.305: C504.1 37.47,29.84 v2(36.96,29.34) 36.85,29.22 U35.4
  BOTTOM w0.508: R771.2 41.23,31.37 40.8,30.94 38.72,30.94 38.07,30.29 C504.1
P2800_DXN: length 106.9
  TOP w0.102: v1(121.03,91.43) 121.03,90.83 R289.2 ; v1(149.94,127.03) 149.94,126.89 149.72,126.66 148.35,126.66 147.44,127.57 Q11.E ; v1(147.67,105.17) 147.92,104.91 148.9,104.91 149.23,104.59 149.23,92.43 147.33,90.53 147.33,87.71 v1(147.57,87.47) 147.57,87.36 149.23,85.7 149.23,81.63 146.26,78.66 U12.3 146.26,75.31 C125.2 C127.2
  L3 w0.127: v1(147.67,105.17) 148.12,105.17 150.67,107.72 150.67,117.84 149.7,118.81 149.7,125.33 150.48,126.11 150.48,126.53 150.1,127.03 v1(149.94,127.03)
  BOTTOM w0.102: v2(121.09,90.08) 120.73,90.08 ; 120.73,90.08 120.73,81.04 122.96,78.82 136.61,78.82 139.32,81.53 139.32,83.02 143.49,87.19 147.29,87.19 v1(147.57,87.47) ; 120.73,90.08 120.73,91.13 v1(121.03,91.43)
P2800_DXP: length 110.6
  TOP w0.102: C127.1 C125.1 145.61,75.55 U12.2 145.61,78.32 149.01,81.72 149.01,85.28 147.6,86.7 v1(147.52,86.7) 147.11,87.11 147.11,90.62 149.01,92.52 149.01,104.5 148.82,104.7 148.02,104.7 v1(147.64,104.32) ; R289.1 120.22,90.73 v1(120.22,91.43) ; Q11.C 146.46,126.77 Q11.B 148.1,126.45 150.01,126.45 150.6,127.04 v1(150.87,127.04)
  L3 w0.127: v1(150.87,127.04) 150.75,126.94 150.75,126 149.97,125.22 149.97,118.92 150.93,117.95 150.93,107.61 v1(147.64,104.32)
  BOTTOM w0.102: 120.52,84.19 120.52,80.95 122.87,78.6 136.7,78.6 139.54,81.44 139.54,82.93 143.58,86.97 147.24,86.97 v1(147.52,86.7) ; 120.52,84.19 v2(120.16,84.19) ; 120.52,84.19 120.52,91.13 v1(120.22,91.43)
P_GFX_TXN0: length 4.2
  TOP w0.089: C43.1 79.56,147.02 79.56,148.5 79.68,148.62 79.68,149.32 79.68,149.96 79.59,150.05 79.59,150.42 CPU1.V2
P_GFX_TXN1: length 5.1
  TOP w0.089: CPU1.R2 78.5,150.82 78.5,150.52 78.65,150.33 78.65,150.03 78.56,149.94 78.56,149.92 78.44,149.81 78.44,148.72 77.36,147.64 77.36,147.02 C45.1
P_GFX_TXP0: length 5
  TOP w0.089: CPU1.V3 79.76,151.27 79.93,150.84 80.04,150.73 80.04,150.71 80.04,150.7 80.04,150.47 80.04,150.46 79.93,150.33 79.87,150.26 79.87,149.24 79.87,148.54 79.75,148.42 79.75,147.03 C44.1
P_GFX_TXP1: length 4.1
  TOP w0.089: CPU1.R1 78.36,150 78.25,149.89 78.25,148.79 77.17,147.72 77.17,147.02 C42.1
PANEL_ON_1: length 9.4
  TOP w0.127: R236.2 35.1,114.34 v1(35.26,114.17)
  BOTTOM w0.127: v1(35.26,114.17) 34.48,114.17 33.92,113.61 33.92,109.6 v2(34.63,108.89) 35.14,108.38 U38.3
PANEL_ON_2: length 2.8
  BOTTOM w0.127: U38.5 37.34,111.19 v2(36.38,112.14) C364.1
PANEL_ON_3: length 6.1
  BOTTOM w0.127: v2(34.83,110.77) U38.4 36.39,109.93 36.74,109.58 39.89,109.58 R639.1
PANEL_SEL1_CABLE: length 11
  TOP w0.127: CONVT1.7 29.22,35.15 29.95,34.42 32.35,34.42 33.71,33.06 34.41,33.06 v4(34.6,32.87) 33.9,32.17 R450.2 33.24,32.61 31.92,32.61 31.79,32.74 RN37.4
PANEL_SEL1_CABLE_EC: length 155.2
  TOP w0.127: R450.1 33.51,31.1 32.53,31.1 31.58,30.16 31.58,29.32 32.64,28.26 32.64,25.02 34.24,23.42 37.38,23.42 38.32,22.48 v1(40.22,22.48) ; U14.107 125.45,65.67 122.25,62.46 122.25,59.97 122.47,59.74 122.47,59.17 122.77,58.87 122.77,57.68 122.78,57.68 122.78,57.61 124.23,56.16 124.23,56.16 124.8,55.59 124.8,55.59 124.81,55.58 125.23,55.58 127.69,55.58 128.16,55.11 v1(128.45,55.11)
  L4 w0.127: v1(40.22,22.48) 40.46,22.72 40.46,23.51 40.84,23.89 40.84,27.87 44.08,31.11 44.56,31.11 48.85,35.4 62.39,35.4 65.33,32.47 70.96,32.47 72.49,30.94 84.94,30.94 85.13,30.75 85.13,30.75 93.46,30.75 95.85,28.36 101.81,28.36 103.08,29.63 105.3,29.63 108.03,32.36 113.04,32.36 115.03,34.35 115.8,34.35 117.54,36.09 123.83,36.09 127.64,39.91 127.64,43.08 129.85,45.28 129.85,53.71 v1(128.45,55.11)
  BOTTOM w0.127: v1(40.22,22.48) 39.34,22.48 v2(39.31,22.44)
PANEL_SEL2_CABLE: length 7
  TOP w0.127: CONVT1.8 29.28,34.15 29.88,33.55 v4(30.44,33.55) 30.44,33.17 30.28,33.02 R448.2 30.96,32.6 31.17,32.82 31.17,33.63 31.35,33.81 32.32,33.81 32.44,33.68 RN37.3
PANEL_SEL2_CABLE_EC: length 158
  TOP w0.127: U14.106 125.85,64.65 122.5,61.3 122.5,60.08 122.73,59.85 122.73,59.27 123.03,58.97 123.03,58.95 123.03,58.94 123.03,57.72 124.48,56.27 124.48,56.27 124.9,55.84 124.91,55.84 124.91,55.84 127.93,55.84 128.18,55.59 129.11,55.59 v1(129.2,55.68) ; R448.1 30.46,31.24 30.51,31.19 31.2,30.5 31.2,29.17 32.26,28.11 32.26,24.86 34.6,22.52 37.74,22.52 38.16,22.1 39.73,22.1 v1(40.37,21.46)
  L4 w0.127: v1(40.37,21.46) 40.4,21.46 41.22,22.28 41.22,23.19 41.6,23.57 41.6,27.55 44.4,30.35 44.88,30.35 49.17,34.64 62.05,34.64 64.99,31.7 70.65,31.7 72.18,30.18 84.62,30.18 85.42,29.37 85.43,29.37 85.74,29.37 93.56,29.37 95.34,27.6 102.12,27.6 103.39,28.87 105.89,28.87 108.57,31.55 114.39,31.55 118.15,35.31 124.12,35.31 128.4,39.59 128.4,42.76 130.61,44.97 130.61,54.28 v1(129.2,55.68)
  BOTTOM w0.127: v1(40.37,21.46) 40.88,21.97 v2(41.31,21.97)
PANEL_SEL3_CABLE: length 6.3
  TOP w0.127: CONVT1.9 29.27,33.15 29.65,32.77 29.65,31.13 R452.2 30.51,30.26 R458.2 29.54,29.6 v4(29.34,29.41)
PANEL_SEL3_CABLE_EC: length 154
  TOP w0.127: v1(39.43,21.54) 38.18,21.54 37.59,22.14 34.44,22.14 31.88,24.7 31.88,27.35 R458.1 ; v1(128.46,56.06) 128.42,56.09 125.02,56.09 125.01,56.1 125.01,56.1 124.73,56.37 124.73,56.38 123.29,57.82 123.29,59.05 123.28,59.05 123.28,59.08 122.98,59.38 122.98,59.95 122.75,60.18 122.75,61.2 126.25,64.69 U14.105
  L4 w0.127: v1(39.43,21.54) 39.82,21.93 40.33,21.93 40.84,22.44 40.84,23.35 41.22,23.73 41.22,27.71 44.24,30.73 44.72,30.73 49.01,35.02 62.23,35.02 65.17,32.09 70.81,32.09 72.34,30.56 84.78,30.56 85.58,29.75 93.72,29.75 95.5,27.98 101.96,27.98 103.23,29.25 105.73,29.25 108.46,31.98 113.22,31.98 115.21,33.97 115.96,33.97 117.7,35.71 123.99,35.71 128.02,39.75 128.02,42.92 130.23,45.13 130.23,53.99 128.46,55.76 v1(128.46,56.06)
  BOTTOM w0.127: v1(39.43,21.54) v2(38.27,21.54)
PB_IN_SW1: length 8.9
  TOP w0.254: v4(32.98,22.76) 32.95,22.78 31.34,22.78 31.22,22.66 31.21,22.66 30.8,22.25 PWRCN1.6 29.12,22.25 28.81,22.56 28.21,22.56 v1(28.11,22.65)
  BOTTOM w0.254: R784.2 R787.1 29.57,23.08 29.04,22.56 28.21,22.56 v1(28.11,22.65)
PCB_VER_ID: length 6.3
  TOP w0.102: C135.2 R344.1 131.77,70.21 131.15,70.21 v4(131.12,70.18) 130.12,69.18 R349.2 130.11,68.69 129.05,67.62 U14.98
PCH_AUD_RST_N: length 5.9
  TOP w0.102: U14.30 114.55,53.73 113.95,53.14 113.95,50.9 v4(113.51,50.46) 113.2,50.15 R397.1
PCH_AUD_RST_N_1: length 58.2
  TOP w0.102: v5(106.03,40.08) 106.03,43.71 111.67,49.35 R397.2
  L4 w0.127: v5(106.03,40.08) 107.35,41.4 113.65,41.4 114.15,40.9 v1(114.31,40.9)
  BOTTOM w0.102: v1(114.31,40.9) 115.01,41.61 117.82,41.61 118.86,42.65 120.73,42.65 121.45,43.36 136.74,43.36 138.29,41.81 v2(145.45,41.81) 147.25,40.01 147.25,39.42 147.58,39.09 Q69.5
PCH_PCIECLKRQ0_N: length 238.2
  TOP w0.102: Q23.S 94.84,117.19 96.05,118.39 103.77,118.39 105.5,116.66 107.97,116.66 v1(108.13,116.49) ; v1(100.21,203.4) 100.21,199.96 96.59,196.34 92.73,196.34 90.36,193.97 90.36,187.66 89.22,186.52 RN6.2 88.72,185.77 86.44,183.49 86.44,183.13 85.58,182.26 85.58,180.29 85.38,180.09 85.38,179.53 85.32,179.47 CPU1.AK62
  L3 w0.127: v1(100.21,203.4) 100.6,203.02 106.56,203.02 108.23,204.7 113.65,204.7 114.27,205.32 126.92,205.32 128.92,203.32 139.84,203.32 154.38,188.78 154.38,182.71 161.55,175.54 161.55,174.27 161.56,174.26 161.56,153.94 163.48,152.03 163.48,139.69 161.93,138.15 161.93,132.99 159.9,130.96 159.9,128.5 157.98,126.58 157.98,125.74 v1(158.5,125.22)
  BOTTOM w0.102: v1(108.13,116.49) 108.91,117.27 v2(108.91,118.56) 108.91,121.25 109.84,122.18 139.22,122.18 140.14,121.26 144.59,121.26 148.23,124.89 153.48,124.89 155.13,123.25 156.53,123.25 v1(158.5,125.22)
PCH_PCIECLKRQ1_N: length 7.9
  TOP w0.102: RN5.1 86.04,185.78 85.53,185.27 85.53,184.18 v4(85.38,184.02) 85.26,183.91 85.26,183.12 84.21,182.07 84.21,179.65 84.39,179.47 CPU1.AH62
PCH_PCIECLKRQ2_N: length 58.7
  TOP w0.089: 85.34,180.96 85.34,180.39 85.14,180.19 85.14,179.67 84.95,179.42 84.95,179.13 CPU1.AJ62
  TOP w0.102: 85.34,180.96 85.34,182.3 86.25,183.21 86.25,184.33 v4(87.02,185.1) 88.07,186.15 RN6.1 88.07,186.93 88.23,187.08 88.81,187.08 90.05,188.32 90.05,194.06 92.64,196.65 96.5,196.65 99.6,199.75 99.6,204.88 100.79,206.07 100.79,208.88 98.66,211.02 98.66,219.43 99.32,220.09 101.98,220.09 v4(102.24,220.34) 102.91,221.02 102.91,221.58 102.9,221.59 102.9,222.88 102.91,222.89 102.91,223.7 Q1.S
PCH_PCIECLKRQ2_N_1: length 4.7
  TOP w0.102: R24.2 104.85,219.02 R20.1 104.63,219.49 v4(103.79,220.32) 103.46,220.65 Q1.D
PCH_PCIECLKRQ2_N_B: length 3.1
  TOP w0.102: Q1.G 104.45,225.37 v4(104.71,225.64) 105.59,225.64 105.95,225.28 R1.2
PCH_PCIECLKRQ3_N: length 369.6
  TOP w0.089: 84.57,180.31 84.57,179.65 84.68,179.55 84.68,179.29 84.39,179.01 CPU1.AH61
  TOP w0.102: RN5.2 86.69,185.77 v3(85.94,185.01) 85.94,183.16 84.56,181.79 84.56,180.32 84.57,180.31
  L3 w0.127: v1(157.74,131.78) 157.46,131.5 157.46,128.47 156.45,127.45 156.45,124.52 156.66,124.3 156.66,123.28 155.31,121.92 155.31,108.91 146.62,100.22 146.62,89.74 145.73,88.85 145.73,86.18 145.45,85.9 v1(145.45,83.88)
  L4 w0.127: v3(45.76,25.25) 45.69,25.32 45.69,28.19 50.24,32.74 61.25,32.74 64.27,29.72 69.94,29.72 71.39,28.27 83.81,28.27 84.64,27.44 92.45,27.44 94.57,25.31 104.54,25.31 105.19,25.96 115.83,25.96 118.78,28.92 127.02,28.92 128.19,30.09 136.23,30.09 141.03,34.89 141.03,57 143.81,59.78 143.81,66.62 144.63,67.44 144.63,69.45 145.99,70.82 145.99,83.33 v1(145.45,83.88) ; v3(85.94,185.01) 86.39,185.01 90.81,189.43 90.81,192.14 93.75,195.07 98.15,195.07 98.66,195.58 104.33,195.58 105.47,196.72 107.4,196.72 108.18,197.5 112.1,197.5 113.95,195.65 137.57,195.65 141.98,191.24 141.98,177.42 140.51,175.95 140.51,133.64 143.28,130.87 151.96,130.87 151.98,130.85 156.82,130.85 v1(157.74,131.78)
  BOTTOM w0.102: R793.1 45.11,23.32 44.81,23.62 Q73.S 44.81,25.8 v2(45.04,26.04) 45.51,26.04 45.76,25.78 v3(45.76,25.25)
PCH_PCIECLKRQ3_N_B: length 3.2
  BOTTOM w0.102: R788.2 42.93,26.8 43.19,26.54 v2(43.19,26.06) 43.19,25.5 42.84,25.15 Q73.G
PCH_RTCRST: length 13.9
  TOP w0.102: R1807.2 R1806.2 151.4,172.3 151.16,172.06 151.16,171.16 151.21,171.11 151.21,171.04 152.2,170.05 v1(153.58,170.05)
  L4 w0.127: v1(153.58,170.05) 153.58,170.08 151.32,172.34 148.29,172.34 147.09,173.54 JMP1.1
PCH_RTCRST_DOWN: length 9.1
  TOP w0.102: v4(156.4,175.06) 156.07,175.39 154.26,175.39 153.81,174.94 R143.1 153.22,175.18 150.22,175.18 149.27,174.23 JMP1.2
PCH_RTCRST_PULLUP: length 227.9
  TOP w0.102: v1(142.22,84.76) 142.3,84.84 142.3,88.47 141.7,89.07 Q1801.D ; R150.1 R156.2 154.88,172.21 R154.1 154.01,173.08 C35.1 153.44,173.08 R1806.1 153.23,171.41 v1(153.7,170.94) ; CPU1.AC55 v3(82.08,176.23)
  L3 w0.127: v1(159.11,133.2) 159.11,131.47 159.01,131.37 159.01,129.12 157.08,127.19 157.08,124.78 157.3,124.57 157.3,122.68 155.94,121.32 155.94,108.74 155.94,108.74 155.94,108.65 147.25,99.96 147.25,89.23 146.36,88.34 146.36,85.83 146.14,85.61 146.14,83.9 146.08,83.85 146.08,83.61 145.71,83.24 145.18,83.24 145.02,83.41 143.58,83.41 v1(142.22,84.76) ; v3(82.08,176.23) 82.49,176.64 82.49,190.76 90.76,199.03 104.42,199.03 104.63,199.24 108.61,199.24 109.55,198.3 110.73,198.3 110.75,198.32 133.44,198.32 v1(137.24,194.53)
  L4 w0.127: v1(159.11,133.2) 159.49,133.58 159.49,141.07 159.75,141.33 159.75,142.16 160.48,142.9 160.48,151.04 159.14,152.39 159.14,169.8 158.52,170.42 154.22,170.42 v1(153.7,170.94)
  BOTTOM w0.102: v1(153.7,170.94) 153.7,174.24 153.32,174.62 150.53,174.62 149.39,175.77 145.47,175.77 143.24,178 143.24,188.8 v2(140.16,191.87) 137.51,194.53 v1(137.24,194.53)
PCH_RTCX1: length 19.9
  TOP w0.102: CPU1.AC59 82.1,178.35 v3(82.08,178.35) ; X1.1 73.05,187.92 74.26,187.92 R95.1 76.39,189.26 C21.1 77.58,188.06 v3(79.46,188.06)
  L4 w0.089: v3(82.08,178.35) 82.08,178.9 80.5,180.48 80.5,181.05
  L4 w0.127: v3(79.46,188.06) 79.56,188.06 80.52,187.1 80.52,181.07 80.5,181.05
  BOTTOM w0.102: v2(82.08,179.09) v3(82.08,178.35)
PCH_RTCX2: length 21.4
  TOP w0.102: X1.4 71.89,187.56 72.33,187.12 74.98,187.12 R95.2 76.85,187.73 C23.1 77.07,187.5 79.38,187.5 v3(79.48,187.4) ; CPU1.AC58 v3(82.08,177.66)
  L4 w0.089: 80.31,181.16 80.28,181.14 80.28,180.96 80.31,180.93 80.31,180.14 81.69,178.75 81.69,178.66 81.69,178.66 81.69,178.04 81.78,177.95 v3(82.08,177.66)
  L4 w0.127: 80.31,181.16 80.31,186.73 79.64,187.4 v3(79.48,187.4)
  BOTTOM w0.102: v3(79.48,187.4) 79.38,187.4 78.65,188.14 v2(78.65,188.42)
PCH_SATA_LED_1: length 8.7
  BOTTOM w0.254: v2(27.34,13.79) 26.51,13.79 R799.2 26.28,14.02 Q78.C 24.91,14.74 25.38,15.21 27.24,15.21 27.8,15.77 27.8,16.65 28.53,17.39 Q77.B
PCH_SRTCRST_DOWN: length 8
  TOP w0.102: CMCLR2.1 150.04,182.31 R120.1
PCH_SRTCRSTB_PULLUP: length 123.3
  TOP w0.102: R154.2 154.87,173.45 v1(155.28,173.86) 153.45,173.86 153.06,174.26 R1807.1 ; v3(84.89,172.69) 84.72,172.69 CPU1.AH49 ; R126.2 C29.1 151.59,181.32 CMCLR2.2
  L3 w0.127: v1(134.27,194.58) 134.27,195.02 132.27,197.03 109.02,197.03 108.08,197.97 105.15,197.97 103.35,196.16 91.72,196.16 86.59,191.04 86.59,189.72 84.77,187.9 84.77,186.87 84.03,186.12 84.03,183.46 84.63,182.86 84.63,180.82 84.47,180.66 84.47,173.12 v3(84.89,172.69)
  BOTTOM w0.102: v1(155.28,173.86) 155.28,173.93 153.96,175.26 150.78,175.26 149.31,176.73 CMCLR2.2 145.6,176.73 143.9,178.44 143.9,189.09 137.84,195.15 136.96,195.15 136.91,195.1 v2(135.63,195.1) 134.78,195.1 v1(134.27,194.58)
PCIE_CLKOUT1N: length 3.9
  TOP w0.089: TP37.1 69.19,153.42 70.52,154.75 71.63,154.75 CPU1.A10
PCIE_CLKOUT1P: length 5.3
  TOP w0.089: TP38.1 68.37,152.33 68.36,152.34 70.6,154.57 71.29,154.57 71.33,154.53 72.13,154.53 72.4,154.8 CPU1.C10
PCIE_OBSN_CPU: length 2.2
  TOP w0.305: CPU1.F5 v3(73.92,152.35)
  BOTTOM w0.381: R604.1 v3(73.92,152.35) 73.65,152.35 v2(73.29,151.99)
PCIE_OBSP_CPU: length 1.6
  TOP w0.305: CPU1.F6 v3(73.99,153.17)
  BOTTOM w0.381: v3(73.99,153.17) 73.99,153.26 73.91,153.36 73.68,153.59 73.67,153.59 73.39,153.89 R604.2
PCIE_P3_USB3_P4_RXN: length 7.4
  TOP w0.102: v3(77.32,154.48) 77.44,154.48 CPU1.P10
  BOTTOM w0.089: v3(77.32,154.48) 77.55,154.71 77.67,154.71 77.74,154.64 77.74,153.57 77.76,153.55 77.76,152.61 77.75,152.61 77.75,152.12 77.76,152.11 77.76,151.26 77.67,151.17
  BOTTOM w0.102: 77.67,151.17 77.5,151 77.05,151 75.96,149.91 TP74.1
PCIE_P3_USB3_P4_RXP: length 7.1
  TOP w0.102: v3(77.31,155.22) 77.48,155.22 CPU1.P12
  BOTTOM w0.089: v3(77.31,155.22) 77.55,154.99 77.63,154.9 77.74,154.9 77.93,154.71 77.93,153.65 77.95,153.63 77.95,152.52 77.95,152.52 77.95,152.2 77.95,152.19 77.95,151.14 77.8,150.99
  BOTTOM w0.102: 77.8,150.99 77.59,150.78 77.14,150.78 76.78,150.42 TP73.1
PCIE_P3_USB3_P4_TXN: length 4.8
  TOP w0.089: CPU1.P2 77.82,150.51 77.82,149.21 75.87,147.25 75.87,146.79 TP40.1
PCIE_P3_USB3_P4_TXP: length 7
  TOP w0.089: CPU1.P3 78.08,150.9 78.08,150.84 78.19,150.74 78.19,150.71 78.19,150.7 78.19,150.47 78.18,150.46 78.08,150.33 78.02,150.26 78.02,149.13 76.26,147.37 76.26,145.93 TP42.1
PCIE_P4_USB3_P3_RXN: length 2.2
  TOP w0.102: CPU1.H6 75.47,152.38 75.47,152.36 v3(75.47,152.35)
  BOTTOM w0.102: v3(75.47,152.35) 75.47,152.36 75.47,152.46 74.73,153.19 TP70.1
PCIE_P4_USB3_P3_RXP: length 1.7
  TOP w0.102: v3(75.48,151.65) CPU1.H5
  BOTTOM w0.102: TP71.1 74.69,152.45 75.48,151.66 v3(75.48,151.65)
PCIE_P4_USB3_P3_TXN: length 5
  TOP w0.089: CPU1.M2 76.97,150.41 76.94,150.36 76.94,150.05 76.69,149.8 76.69,148.73 74.62,146.65 TP39.1
PCIE_P4_USB3_P3_TXP: length 6.7
  TOP w0.089: TP41.1 75.12,146.02 75.12,146.88 76.88,148.65 76.88,149.72 77.15,149.99 77.15,150.33 77.3,150.52 77.42,150.65 CPU1.N2
PCIE_REF_CLK_RCOMP: length 2.4
  TOP w0.254: CPU1.E21 v3(73.17,159.38)
  BOTTOM w0.381: v3(73.17,159.38) 72.59,159.96 R595.2 72.51,160.1 v2(71.69,160.1)
PCIE_RST#: length 227.4
  TOP w0.102: v1(137.7,48.23) 137.52,48.23 136.27,49.48 133.86,49.48 133.84,49.45 132.84,49.45 132.61,49.21 R399.2 ; NGFF1.66 v1(119.88,221) ; v1(124.24,214.33) 124.65,214.73 124.65,215.5 123.26,216.89 120.5,216.89 120.09,217.3 v3(119.87,217.3) 119.67,217.5 NGFF1.52
  L3 w0.127: v1(137.7,48.23) 138.84,48.23 139.45,48.84 139.45,52.25 162.36,75.16 162.36,79.63 165.62,82.88 165.62,88.62 167.04,90.04 167.04,101.68 169.51,104.15 169.51,111.55 168.01,113.05 168.01,156.3 165.45,158.86 165.45,182.59 159.82,188.21 159.82,192.25 152.89,199.19 152.89,199.95 145.08,207.75 143.33,207.75 135.92,215.16 135.57,215.16 135.38,215.35 126.01,215.35 125.97,215.39 125.55,215.39 125.51,215.35 125.27,215.35 v1(124.24,214.33)
  BOTTOM w0.102: v3(119.87,217.3) 119.88,217.31 v2(119.88,218.86) v1(119.88,221)
PCIE_WAKE1#: length 7.5
  TOP w0.089: CPU1.P62 77.9,180.06 78,180.16 78,181.92
  TOP w0.102: 78,181.92 76.4,183.53 76.4,183.81 v4(76.08,184.12) 75.73,184.12 74.86,184.99 R106.2
PD4405_A: length 5.7
  TOP w0.102: v4(48.47,70.03) 49.44,71 PQ7.B 52.48,71 52.84,70.64 PD1.A
PD4405_K: length 4.5
  TOP w0.102: PD1.K 57.48,70.64 v4(57.65,70.46) 58.53,70.46 59.48,71.41 PR138.2
PD_N: length 11.6
  TOP w0.102: U20.36 132.94,31.44 v1(132.51,31.01)
  BOTTOM w0.102: v1(132.51,31.01) 132.17,30.67 v2(132.17,28.53) 132.17,28.12 131.43,27.38 131.43,25.81 129.93,24.31 Q71.D
PEG_C_RXN0: length 8.4
  TOP w0.102: GPU1.AB9 87.12,106.87 87.3,107.06 v3(87.53,107.06)
  BOTTOM w0.102: v2(87.59,112.01) 87.8,111.8 ; 87.8,111.8 86.91,110.91 86.91,107.94 87.53,107.32 v3(87.53,107.06) ; 87.8,111.8 88.62,112.61 88.62,112.9 C359.2
PEG_C_RXN1: length 8.3
  TOP w0.102: v3(85.89,107.06) 86.21,107.06 86.32,107.17 GPU1.AC10
  BOTTOM w0.102: C357.2 86.65,113.04 86.65,111.69 86.36,111.4 86.36,108.33 ; v3(85.89,107.06) 86.02,106.93 86.24,106.93 86.36,107.05 86.36,108.33 ; 86.36,108.33 v2(86.04,108.33)
PEG_C_RXP0: length 7.3
  TOP w0.102: GPU1.AC9 87.52,107.9 v3(87.53,107.9)
  BOTTOM w0.102: v3(87.53,107.9) 87.13,108.3 87.13,110.82 88.73,112.42 ; C358.2 89.06,112.75 88.73,112.42 ; v2(88.96,112.19) 88.73,112.42
PEG_C_RXP1: length 8.5
  TOP w0.102: GPU1.AB10 86.29,106.66 v3(85.9,106.27)
  BOTTOM w0.102: 86.44,106.83 86.58,106.96 86.58,111.31 86.87,111.6 86.87,113.04 C356.2 ; 86.44,106.83 v2(86.67,106.6) ; 86.44,106.83 86.04,106.42 86.04,106.41 v3(85.9,106.27)
PEG_RXN0: length 74.1
  TOP w0.102: v3(77.33,152.39) 77.41,152.39 CPU1.P6
  L3 w0.089: v3(77.33,152.39) 77.26,152.39 76.97,152.1 76.97,151.56 77.1,151.43 77.1,150.92 77.12,150.9
  L3 w0.127: 77.12,150.9 77.12,150.44 76.82,150.14 76.82,148.42 74.31,145.91 68.13,145.91 63.53,141.31 63.53,138.25 64.79,136.99 64.79,136.23 v3(65.06,135.97)
  BOTTOM w0.102: C359.1 88.59,114.66 88.59,119.39 88.95,119.75 88.95,131.57 81.05,139.47 72.19,139.47 71.15,138.43 69.58,138.43 67.91,136.75 65.22,136.75 64.75,136.29 64.75,136.14 64.93,135.97 v3(65.06,135.97)
PEG_RXN1: length 60.8
  TOP w0.102: CPU1.T12 v3(78.33,155.2)
  L3 w0.089: 80.24,150.89 80.22,150.9 80.17,150.9 79.71,151.36 79.71,154.27 79.05,154.93 78.6,154.93 v3(78.33,155.2)
  L3 w0.127: 80.24,150.89 80.28,150.84 80.59,150.53 81.33,150.53 82.1,149.76 82.1,149.58 82.83,148.85 82.83,146.88 76.77,140.82 75.34,140.82 72.91,138.38 72.65,138.38 v3(72.38,138.11)
  BOTTOM w0.102: v3(72.38,138.11) 72.69,138.41 80.94,138.41 86.55,132.81 86.55,114.49 C357.1
PEG_RXP0: length 75.4
  TOP w0.102: v3(77.37,153.08) 77.38,153.08 CPU1.P7
  L3 w0.089: v3(77.37,153.08) 77.37,153.05 76.78,152.46 76.78,151.48 76.91,151.35 76.91,150.99 76.85,150.93 76.85,150.9
  L3 w0.127: 76.85,150.9 76.85,150.55 76.55,150.25 76.55,148.53 74.2,146.18 68.02,146.18 63.26,141.42 63.26,138.14 64.52,136.88 64.52,136.19 v3(64.3,135.97)
  BOTTOM w0.102: C358.1 88.81,114.49 88.81,119.3 89.16,119.66 89.16,131.66 81.14,139.69 72.1,139.69 71.06,138.65 69.49,138.65 67.82,136.97 65.13,136.97 64.3,136.13 v3(64.3,135.97)
PEG_RXP1: length 60.4
  TOP w0.102: CPU1.T10 v3(78.33,154.49)
  L3 w0.089: v3(78.33,154.49) 78.58,154.74 78.97,154.74 79.52,154.19 79.52,151.28 80.03,150.77 80.03,150.72 80.05,150.7
  L3 w0.127: 80.05,150.7 80.48,150.27 81.22,150.27 81.83,149.65 81.83,149.47 82.56,148.74 82.56,146.99 76.66,141.08 75.23,141.08 72.83,138.68 72.49,138.68 v3(72.33,138.84)
  BOTTOM w0.102: v3(72.33,138.84) 72.54,138.63 81.03,138.63 86.76,132.9 86.76,114.71 C356.1
PEG_TXN0: length 46.5
  TOP w0.102: C43.2 79.55,145.46 79.55,137.44 79.27,137.16 79.27,136.31 v3(78.78,135.82) ; GPU1.AG7 89.38,111.28 89.38,112.4 88.59,113.2 84.22,113.2 84.15,113.12 84.15,112.8 v1(84.41,112.54)
  BOTTOM w0.102: v1(84.41,112.54) 83.85,113.1 83.85,119.19 84.31,119.66 84.31,127.15 82.98,128.49 82.98,133.44 79.86,136.55 79.19,136.55 78.94,136.3 78.94,135.98 v3(78.78,135.82)
PEG_TXN1: length 46.7
  TOP w0.102: v3(76.26,136.96) 76.26,139.26 77.4,140.41 77.4,145.48 C45.2 ; GPU1.AE7 88.43,109.48 88.43,109.98 88.21,110.19 88.21,110.55 88.2,110.57 88.2,110.79 87.84,111.14 85.31,111.14 85.1,111.35 85.1,111.77 v1(84.91,111.96)
  BOTTOM w0.102: v1(84.91,111.96) 84.95,112 84.95,130.73 83.83,131.85 83.83,133.63 80.28,137.17 76.47,137.17 v3(76.26,136.96)
PEG_TXP0: length 45.7
  TOP w0.102: v1(83.63,112.54) 83.63,112.91 84.13,113.41 88.68,113.41 89.6,112.49 GPU1.AG6 ; C44.2 79.76,145.45 79.76,137.35 79.48,137.07 v3(79.48,135.76)
  BOTTOM w0.102: v1(83.63,112.54) 83.63,119.28 84.09,119.75 84.09,127.06 82.76,128.4 82.76,133.35 79.77,136.34 79.48,136.34 79.48,136.32 79.36,136.19 79.36,135.89 v3(79.48,135.76)
PEG_TXP1: length 47.6
  TOP w0.102: GPU1.AF7 88.8,109.99 88.46,110.33 88.46,110.83 87.93,111.35 85.4,111.35 85.31,111.44 85.31,111.79 85.49,111.96 v1(85.68,111.96) ; C42.2 77.19,145.44 77.19,140.5 76.04,139.35 76.04,137.42 v3(75.55,136.93)
  BOTTOM w0.102: v1(85.68,111.96) 85.16,112.48 85.16,130.82 84.04,131.94 84.04,133.72 80.37,137.39 76.01,137.39 v3(75.55,136.93)
PEX_CLKREQ_M: length 6.5
  TOP w0.102: Q23.D 93.86,118.58 Q22.D 90.25,120.12 v4(90.23,120.15) 90.16,120.22 R219.2
PEX_CLKREQ_N: length 17.1
  TOP w0.102: v3(90.04,107.03) 90.04,107.06 GPU1.AC6 ; v1(90.97,115.32) 90.97,115.57 91.24,115.84 Q22.S
  L3 w0.127: v1(90.97,115.32) 90.84,115.19 90.84,110.24 90.46,109.86 90.46,107.45 v3(90.04,107.03)
  BOTTOM w0.102: v3(90.04,107.03) 90.04,107.15 91.81,108.91 94.31,108.91 v2(94.44,108.78) 94.62,108.6 R653.2
PEX_PLLVDD_GPU: length 1.2
  TOP w0.33: GPU1.AA14 83,105.88 v3(82.58,106.3)
  TOP w0.381: GPU1.AA15 82.16,105.88 v3(81.77,106.27)
  vias: v2(79.65,109.55)
PEX_RST_GPU: length 22.4
  TOP w0.102: R273.2 104.5,103.26 R274.2 104.81,105.44 103.79,106.45 101.51,106.45 100.32,107.63 R265.1 ; R265.1 99,107.72 R260.1 ; R265.1 98.85,107.39 98.74,107.39 98.64,107.29 98.64,106.98 98.33,106.68 97.87,106.68 v4(97.82,106.63) 96.68,106.63 96.08,107.23 94.68,107.23 94.02,107.89 89.47,107.89 89.08,107.5 GPU1.AC7
PEX_RST_GPU_D#: length 5.3
  TOP w0.102: R273.1 99.2,103.26 D3.3 97.6,103.4 v4(97.6,103.4)
PEX_TERMP: length 6.1
  TOP w0.102: GPU1.AF25 74.33,110.33 74.33,110.85 74.96,111.48 74.96,113.83 R247.1 74.23,114.93 v4(74.09,114.93)
PEX_TSTCLK_OUT: length 6.8
  TOP w0.102: v4(79.28,114.05) R246.2 77.67,113.58 77.67,111.63 77.19,111.15 76.31,111.15 76.02,110.86 76.02,110.39 76.4,110.01 GPU1.AF22
PEX_TSTCLK_OUT#: length 7.8
  TOP w0.102: GPU1.AE22 76.4,109.32 75.97,109.75 75.97,110.08 75.77,110.28 75.77,110.96 76.2,111.4 77.09,111.4 77.42,111.73 77.42,113.37 77.25,113.54 R246.1 77.25,115.07 v4(77.07,115.24)
PLT_RST#_CPU: length 164.6
  TOP w0.102: v1(100.11,214.57) 100.11,211.64 102.24,209.5 102.24,205.81 103.64,204.41 103.64,199.93 102.37,198.65 v1(102.37,197.87) ; v1(79.57,224.48) 81.05,223 81.05,217.11 83.78,214.38 84.59,214.38 R34.2 85.43,214.14 R39.1 86.15,214.11 v1(86.39,214.35) ; R35.2 18.38,214.64 v1(18.24,214.49) ; CPU1.AG57 v3(83.92,176.95)
  L4 w0.089: v3(83.92,176.95) 83.54,177.33 83.54,177.49 83.53,177.5 83.53,177.82 83.54,177.82 83.54,178.2 83.53,178.21 83.53,180.64 83.57,180.68 83.57,181.37
  L4 w0.127: v1(86.39,214.35) 86.66,214.62 89.09,214.62 89.35,214.36 95.38,214.36 96.12,215.09 98.53,215.09 99.05,214.57 v1(100.11,214.57) ; v1(102.37,197.87) 102.32,197.87 101.82,197.36 101.79,197.36 101.79,197.36 94.22,197.36 93.75,197.36 88.41,192.02 88.41,190.54 88.41,190.54 88.41,189.75 88.41,189.75 88.41,188.94 87.58,188.11 84.4,188.11 83.37,187.09 83.37,182 83.57,181.8 83.57,181.37 ; v1(18.24,214.49) 19.32,215.57 19.97,215.57 29.28,224.88 78.81,224.88 79.21,224.48 v1(79.57,224.48)
  BOTTOM w0.102: R541.1 28.51,211.12 v2(28.05,211.58) 27.99,211.65 26.84,211.65 25.71,212.78 19.96,212.78 v1(18.24,214.49)
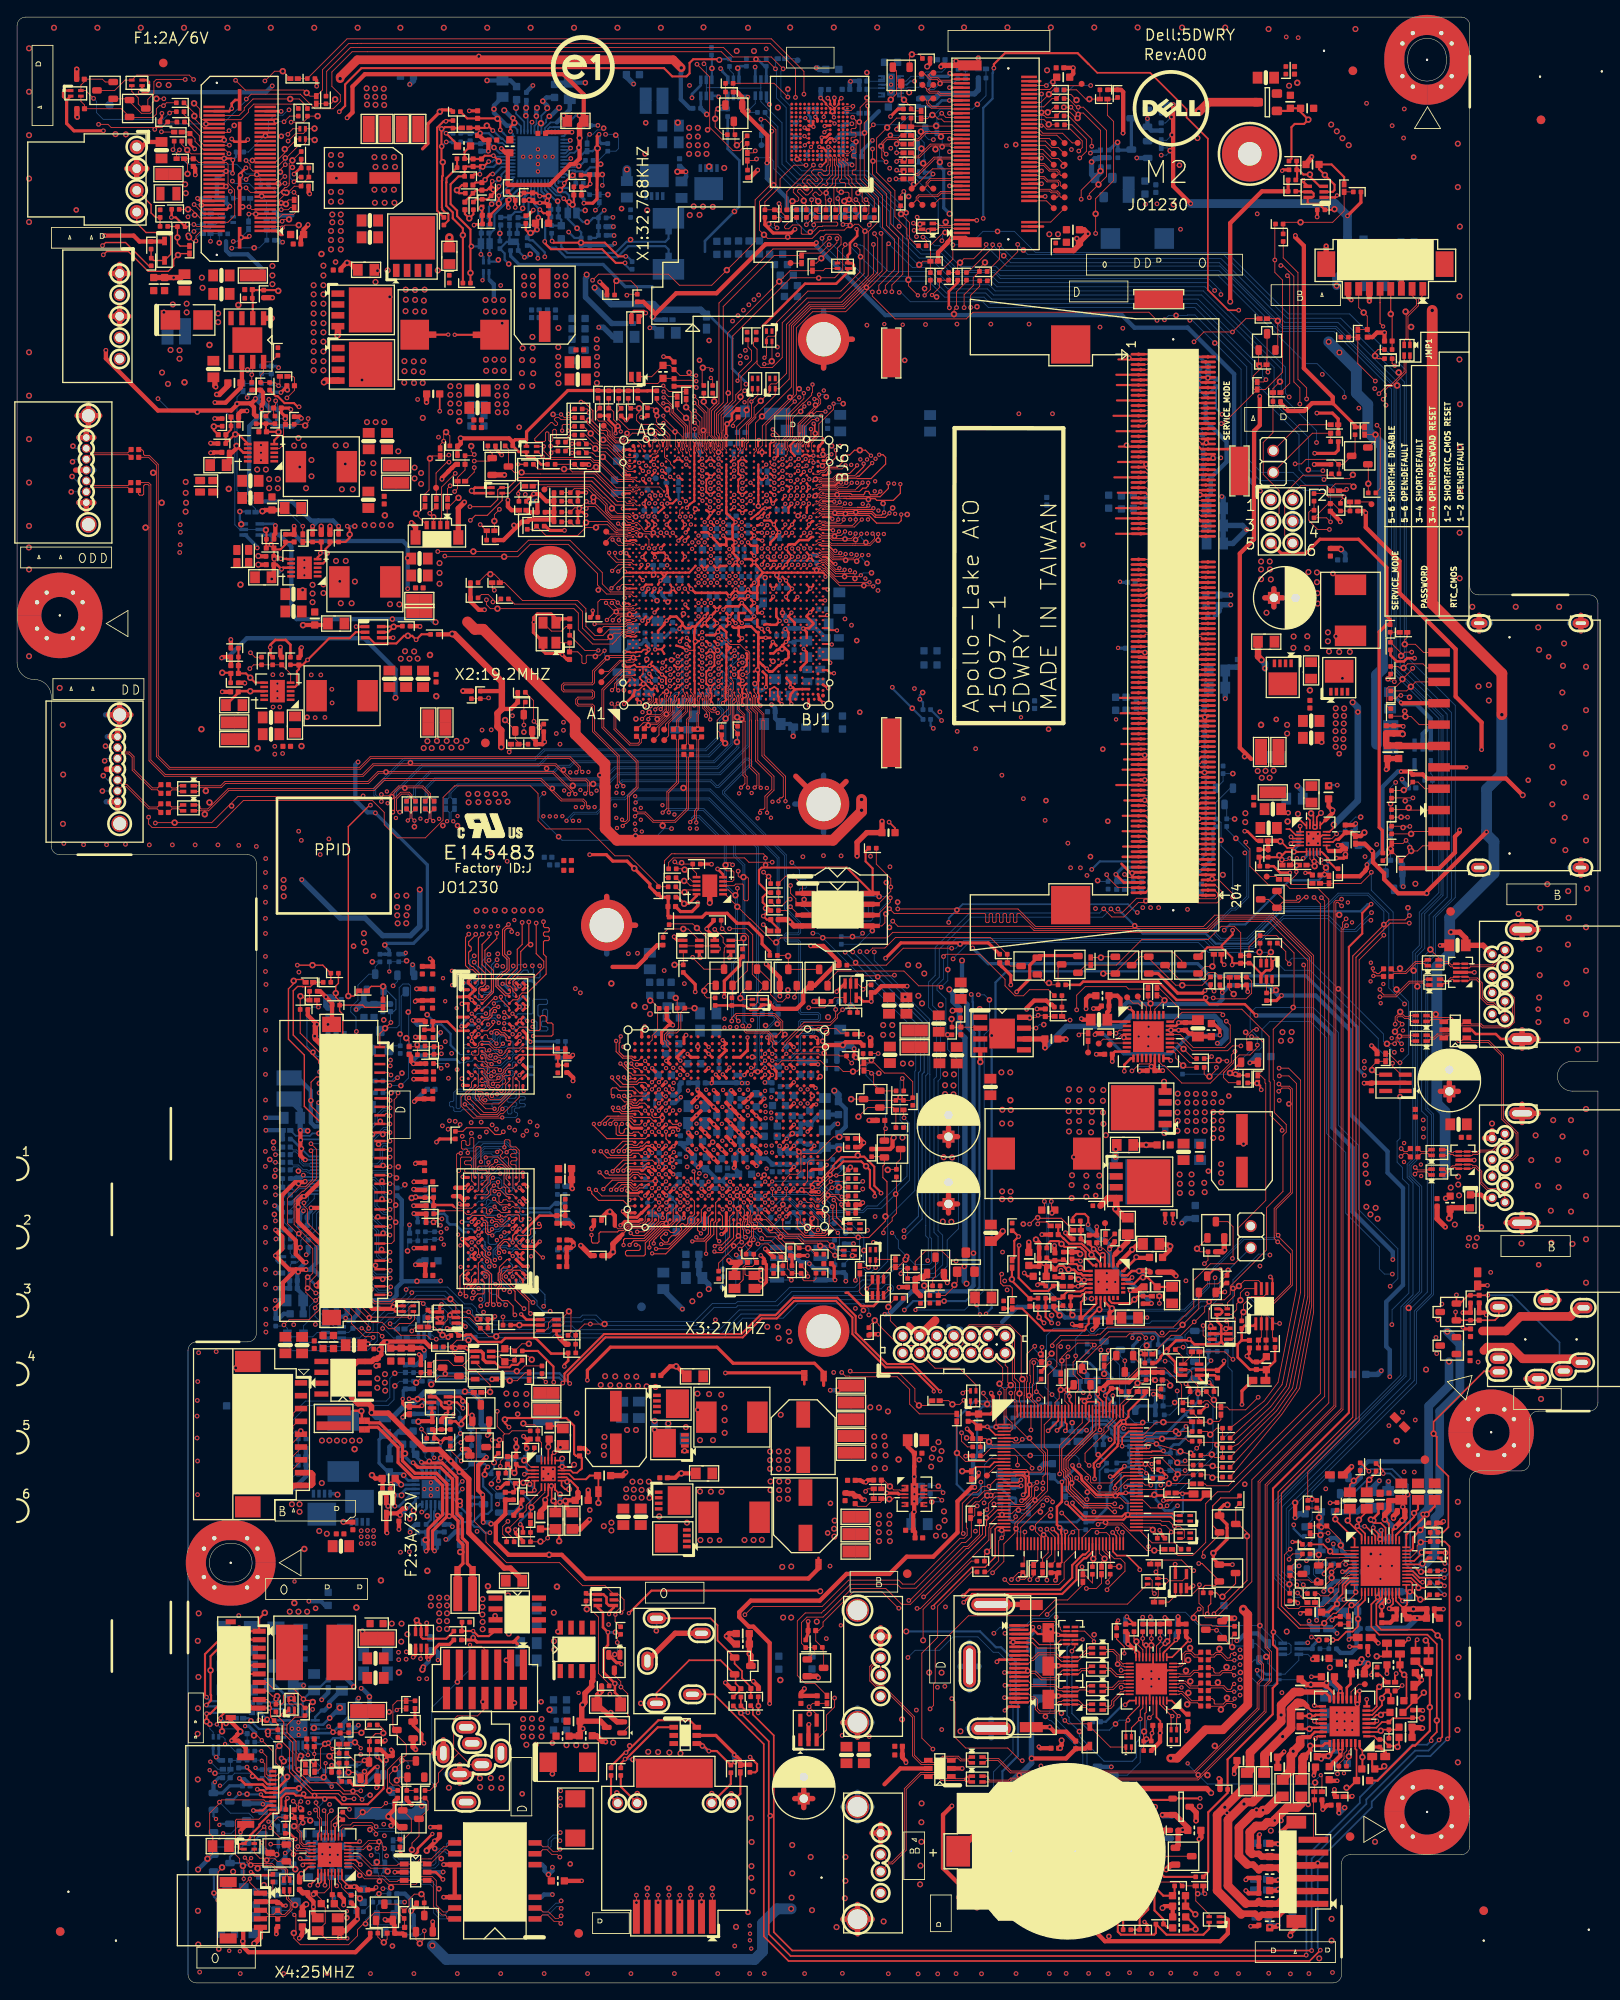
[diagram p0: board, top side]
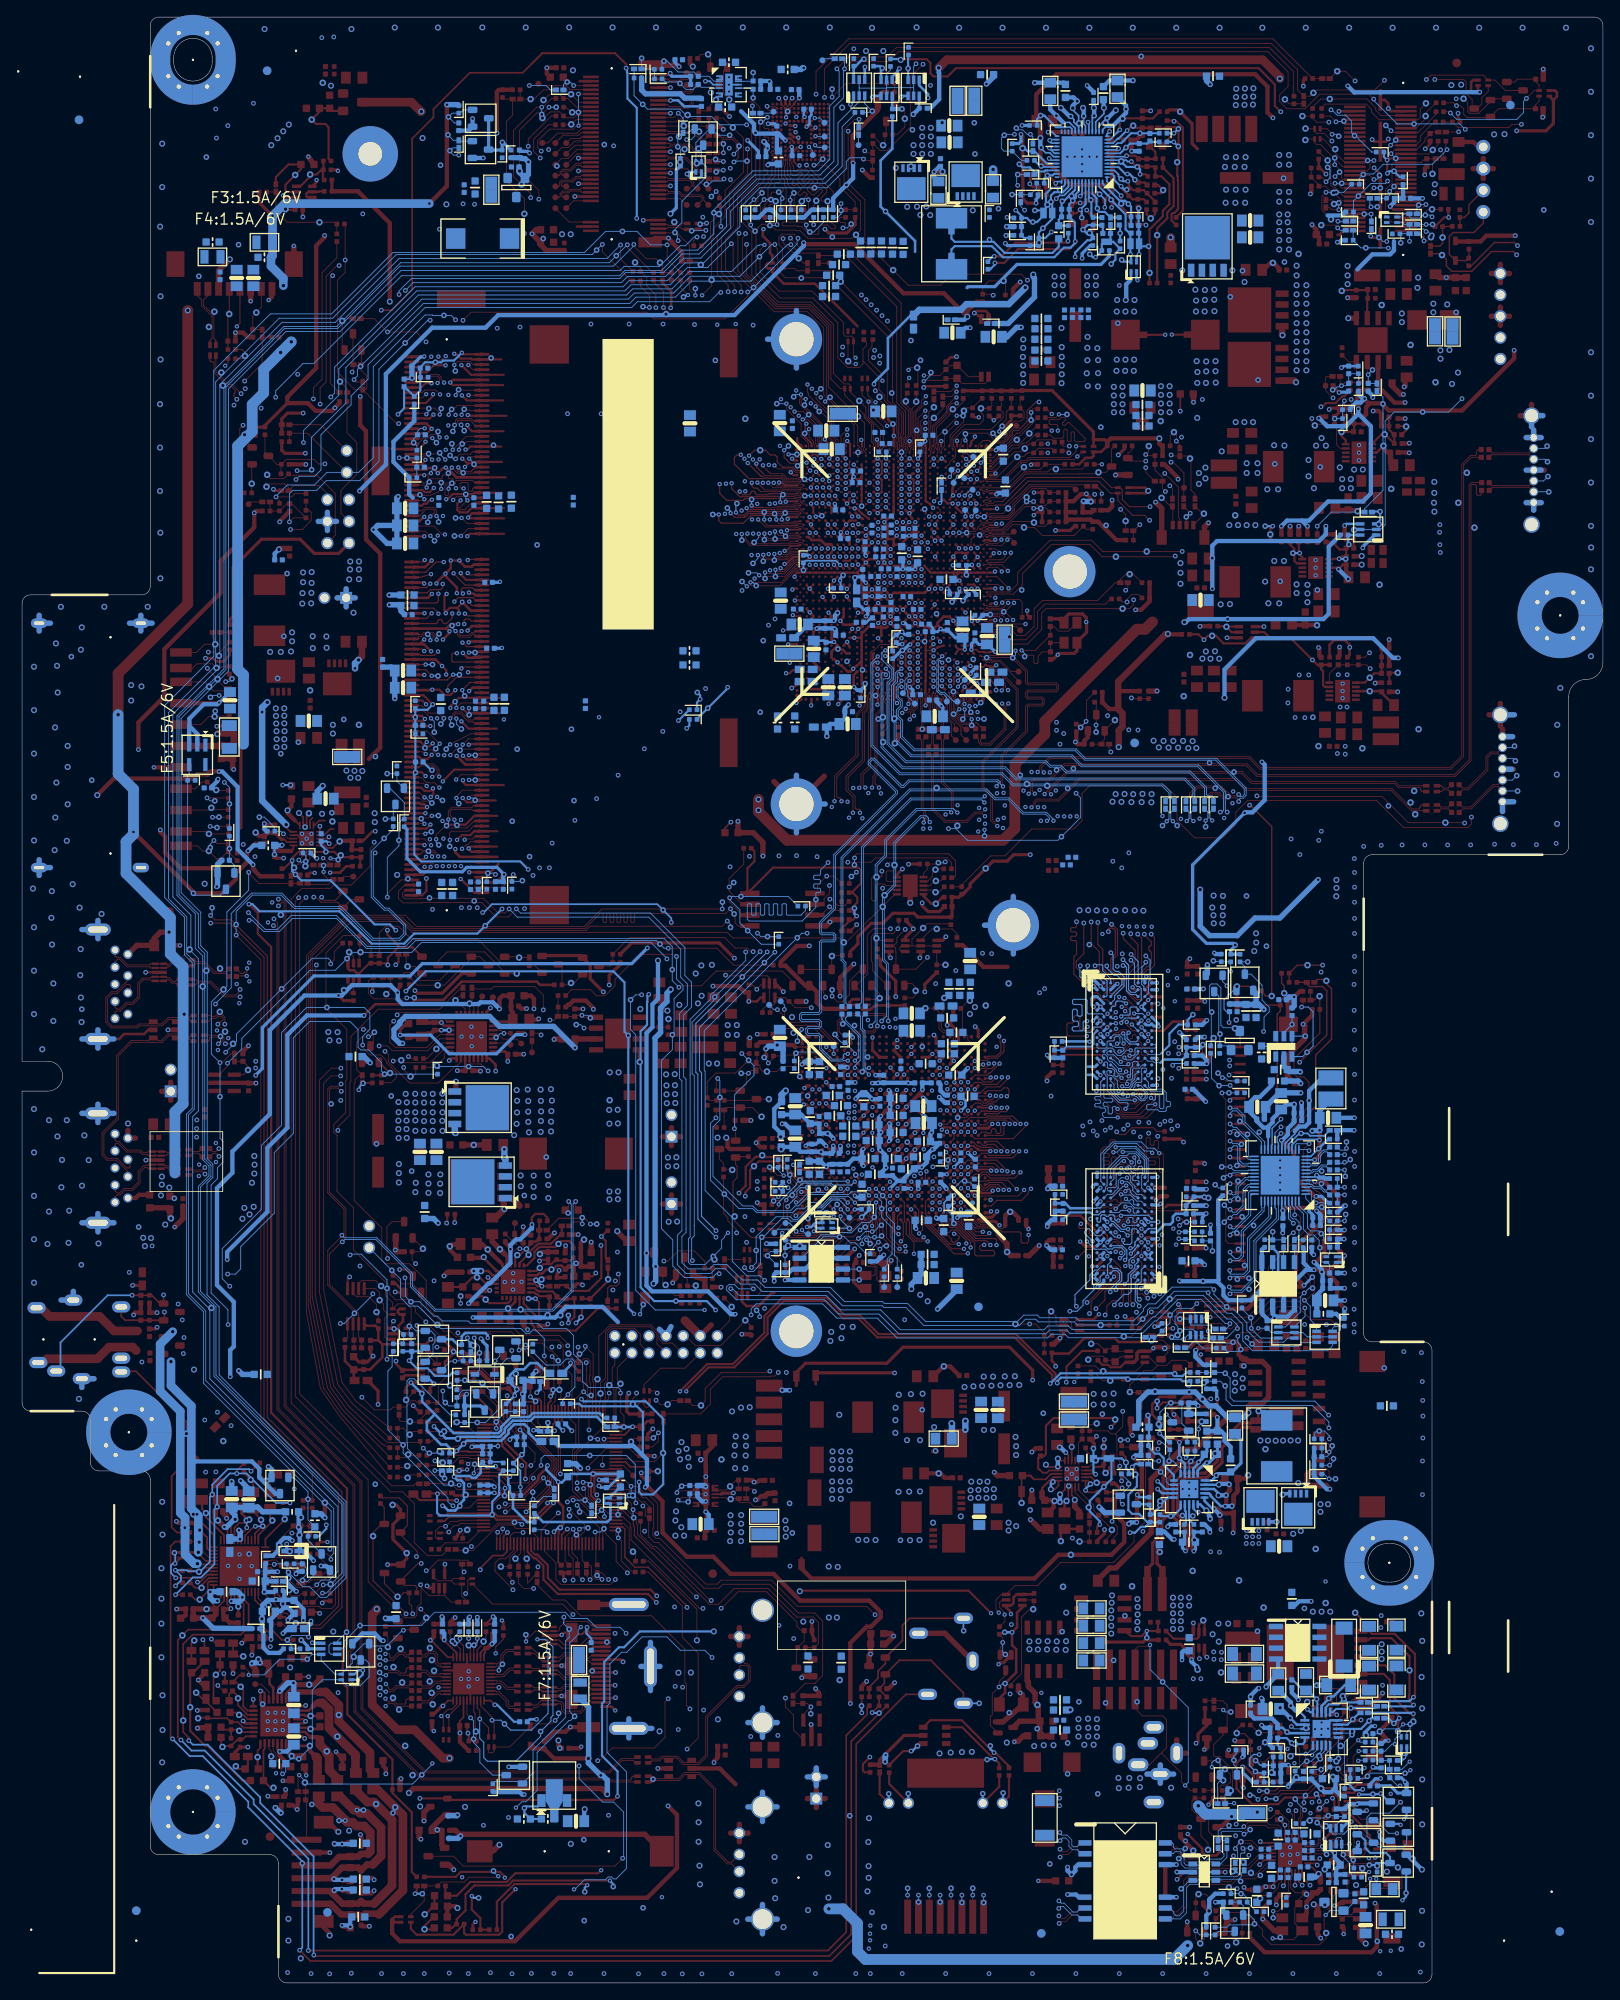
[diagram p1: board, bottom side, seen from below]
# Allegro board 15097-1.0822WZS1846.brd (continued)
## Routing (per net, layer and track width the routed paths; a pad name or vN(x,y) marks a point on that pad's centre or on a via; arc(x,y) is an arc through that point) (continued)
PLTRST#_CPU_D: length 4.6
  TOP w0.102: Q5.D 83.87,216.38 R32.2 84.01,215.24 v4(84.23,215.01) 84.33,215.01 R34.1
PLTRST#_EC_R: length 4.1
  TOP w0.102: R364.1 C141.1 113.38,63.68 v4(113.74,63.32) 114.12,62.93 U14.7
PLTRST#_LPC: length 73.1
  TOP w0.102: R266.1 138.92,106.35 139.23,106.05 v4(139.54,106.05) 140.34,106.85 v1(140.34,107.11) ; LPC1.3 107.42,71.92 110.27,71.92 112.21,69.97 RN11.3
  L3 w0.127: LPC1.3 105.74,73.7 106.71,74.68 107.81,74.68 108.49,75.35 108.49,75.76 110.48,77.75 111.17,77.75 112.6,79.18 124.07,79.18 124.18,79.08 129.3,79.08 129.72,79.08 131.24,80.59 131.59,80.59 136.23,85.23 136.23,85.6 136.23,85.96 142.93,92.67 142.93,104.51 v1(140.34,107.11)
PLTRST*_SIO: length 42.4
  TOP w0.102: RN14.4 132.28,46.66 129.94,44.32 121.75,44.32 v1(120.53,43.1) ; v1(110.52,64.36) 110.52,63.38 111.22,62.71 R364.2
  L4 w0.127: v1(110.52,64.36) 115.2,59.69 115.2,57.36 116.18,56.38 116.18,52.92 120.98,48.12 120.98,44.9 120.58,44.5 120.58,43.15 v1(120.53,43.1)
  BOTTOM w0.102: v2(111.12,63.77) 111.05,63.84 111.05,63.84 v1(110.52,64.36)
PLTRST_LAN_N: length 128.6
  TOP w0.102: v1(32.84,15.96) 32.92,15.96 33.14,15.73 33.93,15.73 34.08,15.59 U26.19 ; v1(133.09,45.55) 132.83,45.81 132.83,47.11 132.63,47.32 RN14.3
  L4 w0.127: v1(133.09,45.55) 133.09,45.38 131.41,43.7 131.25,43.54 131.25,42.13 130.49,41.37 130.49,38.64 129.83,37.97 128.81,37.97 123.22,32.38 120.44,32.38 115.88,27.83 103.61,27.83 102.49,26.71 94.97,26.71 93.19,28.48 86.11,28.48 85.05,28.48 84.25,29.29 71.81,29.29 70.36,30.74 64.69,30.74 61.68,33.75 49.74,33.75 44.47,28.49 44.47,24.18 37.18,16.89 33.77,16.89 v1(32.84,15.96)
  BOTTOM w0.102: v2(32.34,15.04) 32.84,15.53 v1(32.84,15.96)
PLTRST_N: length 291.8
  TOP w0.102: 138.31,46.53 138.23,46.46 138.23,46.18 137.37,45.31 136.14,45.31 ; 138.31,46.53 v1(138.36,46.58) ; 138.31,46.53 138.31,44.41 138.79,43.93 138.79,43.02 139.09,42.72 140.27,42.72 144.5,46.95 144.5,58.86 153.5,67.87 153.5,126.79 152.25,128.04 148.95,128.04 148.54,128.45 146.48,128.45 144.27,130.65 144.27,132.68 143.79,133.16 v1(143.79,133.47) ; 135.55,45.31 134.79,44.55 R415.1 ; 135.55,45.31 U17.1 ; 135.55,45.31 136.14,45.31 ; R46.2 85.46,212.12 R39.2 86.36,213.23 v1(86.53,213.39) ; 136.14,45.31 136.2,45.37 U17.2
  L4 w0.127: v1(143.79,133.47) 143.04,133.47 142.43,134.08 142.43,150.61 141.94,151.1 141.94,160.07 142.68,160.81 142.68,171.91 142.68,172.33 142.68,172.33 142.68,172.52 143.5,173.35 143.5,179.71 145.07,181.28 146.89,181.28 148.87,183.26 v1(148.87,185.55) ; v1(133.84,58.24) 133.36,57.76 133.36,53.52 133.24,53.4 133.24,52.26 134.68,50.83 134.68,48.72 137.42,45.98 137.81,45.98 138.36,46.54 v1(138.36,46.58)
  BOTTOM w0.102: v1(133.84,58.24) 135.63,58.24 139.89,62.5 139.89,63.14 139.95,63.21 139.95,70.43 139.69,70.69 139.13,70.69 134.89,66.46 R1804.1 ; v1(148.87,185.55) 148.42,186 148.42,189.05 139.02,198.45 114.66,198.45 113.95,199.16 109.48,199.16 107.4,201.24 105.23,201.24 101,205.47 101,207.69 98.65,210.03 v2(92.26,210.03) 90.78,210.03 88.55,212.27 88.55,213.11 88.11,213.54 86.69,213.54 86.54,213.39 v1(86.53,213.39)
PLTRST_N_1: length 47.9
  TOP w0.102: v1(113.09,69.01) 113.09,68.78 113.52,68.35 v4(113.52,67.72) 112.83,67.72 112.48,68.07 RN11.2 112.21,67.55 112.02,67.36 111.76,67.36 111.56,67.55 RN11.1 ; R399.1 133.5,48.78 133.5,48.32 v1(133.28,48.09) 133.5,47.87 RN14.2 134.53,47.32 134.79,47.05 ; R415.2 133.05,44.78 133.55,45.28 133.55,46.61 RN14.1 134.4,46.66 134.79,47.05 ; 134.79,47.05 136.39,47.05 136.85,47.51 U17.4
  L4 w0.127: v1(113.09,69.01) 114,68.1 115.1,68.1 117.19,66 122.66,66 127.93,60.72 127.93,60.25 129.43,58.75 130.03,58.75 131.25,57.53 131.25,50.83 133.28,48.8 v1(133.28,48.09)
PLTRST_N_1A: length 13.7
  TOP w0.102: C89.2 101.54,100.04 v1(101.63,99.95) 101.49,99.81 Q25.G ; R260.2 v1(100.77,108.74)
  BOTTOM w0.102: v1(100.77,108.74) v2(99.98,107.94) 99.35,107.31 99.35,106.17 101.63,103.89 v1(101.63,99.95)
PLTRST_N_R: length 13.1
  BOTTOM w0.102: Q1802.B 128.22,73.08 129.03,72.28 129.03,67.3 130.75,65.57 v2(131.73,65.57) R1808.1 R1804.2
PLTRST_SL_N: length 79.7
  TOP w0.102: v1(102.67,117.91) 102.6,117.83 97.8,117.83 97.54,117.58 U5.2 97.54,114.66 98.34,113.86 R248.1 ; v1(110.68,69.01) 110.94,69.27 RN11.4
  L4 w0.127: v3(105.13,78.73) 104.78,78.38 104.78,73.35 107,71.13 108.55,71.13 v1(110.68,69.01) ; v1(102.67,117.91) 103.26,117.32 106.69,117.32 107,117.64 109.85,117.64 109.91,117.58 110.53,117.58 v1(112.49,115.61)
  BOTTOM w0.102: v1(112.49,115.61) 112.5,115.61 113.21,115.61 v2(113.79,115.03) 113.79,111.55 113.18,110.94 113.18,81.03 110.88,78.73 v3(105.13,78.73)
PM_SLP_S0#_CPU: length 184.7
  TOP w0.089: 82.05,181.36 82.22,181.19 82.22,180.87 82.24,180.85 82.24,180.67 82.25,180.66 82.25,180.09 82.35,180 82.35,179.64 82.25,179.55 82.25,179.29 82.54,179.01 CPU1.AD61
  TOP w0.102: R256.1 124.45,111.11 v1(124.26,110.91) ; 82.05,181.36 82.05,183.47 83.75,185.17 83.75,192.7 90.55,199.5 95.68,199.5 96.61,200.44 96.61,202.91 96.91,203.2 v1(96.91,203.39) ; v1(137.73,192) 138.88,193.16 v1(142.23,193.16) 143.79,194.72 R90.1
  L3 w0.127: v1(137.73,192) 139.25,190.48 139.25,167.36 138.74,166.85 138.74,158.92 139.25,158.41 139.25,152.8 138.87,152.43 138.87,129.46 137.44,128.03 137.44,124.61 135.68,122.85 132.21,122.85 123.49,114.13 123.49,113.05 124.26,112.28 v1(124.26,110.91)
  BOTTOM w0.102: v1(142.23,193.16) 142.05,193.16 138.21,197 114.06,197 113.35,197.71 108.75,197.71 106.79,199.67 100.99,199.67 v2(98.7,201.96) 97.26,203.4 96.96,203.4 96.95,203.39 v1(96.91,203.39)
PM_SLP_S3#_CPU: length 92.5
  TOP w0.089: 81.6,181.36 81.6,180.99 81.89,180.7 81.89,180.06 81.8,179.97 81.8,179.66 81.95,179.5 81.95,179.16 CPU1.AC62
  TOP w0.102: R96.1 145.88,187.31 v1(146.15,187.58) ; 81.6,181.36 81.6,183.86 82.63,184.89 82.63,196.14 88.6,202.1 R77.1 92.09,202.39 94.04,202.39 v1(95.03,203.38)
  BOTTOM w0.102: v1(146.15,187.58) 146.15,187.62 145.75,188.01 145.75,188.78 v2(145.4,189.13) 138.03,196.49 113.88,196.49 113.15,197.23 108.55,197.23 106.68,199.1 99.71,199.1 95.44,203.38 v1(95.03,203.38)
PM_SLP_S4#_CPU: length 149.5
  TOP w0.102: R205.1 151.46,128.52 149.15,128.52 R203.1 149.13,129.11 149.71,129.69 v3(149.71,130) ; v3(84.87,174.81) CPU1.AK54
  L4 w0.089: v3(84.87,174.81) 85.35,175.29 85.35,175.64 86.09,176.38 86.09,181.08 86.23,181.22
  L4 w0.127: v3(149.71,130) 149.36,130.35 142.86,130.35 140,133.21 140,176.17 141.47,177.65 141.47,191.03 137.39,195.11 113.71,195.11 111.83,196.99 108.39,196.99 107.61,196.21 105.71,196.21 104.57,195.07 99.18,195.07 97.14,193.03 97.14,191.57 95.48,189.91 92.08,189.91 86.23,184.06 86.23,181.22
  BOTTOM w0.102: v2(149.72,130.73) 149.72,130 v3(149.71,130)
PMC_BATLOW#: length 22.4
  TOP w0.102: v3(87.43,189.41) 87.97,189.41 88.3,189.74 v4(88.32,189.74) 88.34,189.76 RN4.4 ; CPU1.AH51 v3(84.87,173.39)
  L3 w0.127: v3(87.43,189.41) 87.43,189.33 86.01,187.9 86.01,186.23 85.56,185.78 84.79,185.78 84.4,185.39 84.4,183.86 85.39,182.87 85.39,173.67 85.11,173.39 v3(84.87,173.39)
PMC_SUS_STAT: length 188.7
  TOP w0.102: R234.1 132.2,116.28 130.07,116.28 129.78,116.57 125,116.57 124,115.57 v1(124,113.85) ; v1(94.19,204.11) 94.67,204.6 96.08,204.6 96.43,204.25 96.43,203.4 96,202.98 RN2.3 ; v1(133.4,194.52) 132.45,195.47 111.86,195.47 111.08,194.69 102.75,194.69 100.08,197.36 v1(100.08,197.84) ; CPU1.AG58 v3(83.92,177.66)
  L3 w0.127: v1(100.08,197.84) 99.68,197.43 90.94,197.43 83.64,190.13 83.64,183.3 84.18,182.75 84.18,180.78 83.51,180.12 83.51,178.06 v3(83.92,177.66) ; v1(124,113.85) 124,113.92 132.42,122.34 137.04,122.34 137.94,123.25 137.94,127.8 139.39,129.25 139.39,152.23 139.76,152.59 139.76,158.63 139.25,159.13 139.25,166.64 139.76,167.15 139.76,190.73 137.1,193.38 136.76,193.38 136.08,194.07 133.85,194.07 v1(133.4,194.52)
  BOTTOM w0.102: v1(100.08,197.84) 100.06,197.87 99.89,197.87 v2(99.39,198.37) 94.29,203.47 94.29,204.01 v1(94.19,204.11)
PMIC_I2C_SCL: length 1.4
  TOP w0.102: v3(74.59,171.57) CPU1.H45
  BOTTOM w0.102: v3(74.59,171.57) 74.64,171.62 TP68.1
PMIC_I2C_SDA: length 1.5
  TOP w0.102: v3(73.88,171.57) CPU1.F47
  BOTTOM w0.102: TP69.1 73.39,172.06 v3(73.88,171.57)
PMIC_THERMTRIP#: length 210.5
  TOP w0.102: CPU1.J47 v3(76.02,171.57)
  L3 w0.127: v1(49.31,180.85) 49.28,180.82 49.28,180.12 49.87,179.53 50.6,179.53 53.31,176.82 55.98,176.82 56.56,177.41 57.5,177.41 57.84,177.06 61.44,177.06 62.91,175.59 68.39,175.59 72.82,171.16 75.18,171.16 75.59,171.57 v3(76.02,171.57)
  L4 w0.127: v1(126.83,74.04) 125.5,74.04 122.69,76.85 122.69,76.94 121.5,78.14 118.99,78.14 117.17,79.95 115.93,79.95 113.2,82.68 106.8,82.68 102.48,87 102.48,87.67 v3(102.4,87.76) ; v1(100.31,120.62) 99.69,120 89.81,120 88.88,120.93 79.46,120.93 75.83,124.56 75.83,126.8 73.62,129.01 73.62,135.89 73.44,136.07 73.44,136.27 73.43,136.28 73.43,137.29 73.44,137.29 73.44,137.66 73.43,137.66 73.43,138.37 72.52,139.28 72.13,139.28 71.6,138.75 69.46,138.75 67.7,140.51 64.53,140.51 57.31,147.73 57.31,149.73 52.03,155.02 52.03,170.13 51.5,170.66 51.5,173.61 51.67,173.79 51.67,174.9 49.31,177.26 v1(49.31,180.85)
  BOTTOM w0.102: Q1802.E 126.88,74.73 126.88,74.09 v1(126.83,74.04) 126.7,74.17 125.88,74.17 125.61,74.44 125.61,74.5 125.37,74.74 R2402.1 ; v1(100.31,120.62) 100.31,119.62 104.06,115.87 104.14,115.87 104.45,115.56 104.45,115.09 106.81,112.73 106.81,106.25 106.81,87.27 107.02,87.07 107.02,84.32 106.75,84.05 105.06,84.05 v2(104.11,85) 103.13,85.98 103.13,86.89 102.8,87.22 102.8,87.35 v3(102.4,87.76)
PMIC_THERMTRIP#_EC: length 30.5
  TOP w0.102: U14.83 131.71,60.13 132.14,59.7 v3(132.14,59.63)
  L4 w0.127: v3(132.14,59.63) 131.8,59.96 130.23,59.96 130.06,59.79 129.47,59.79 128.99,60.27 128.99,61.42 125.89,64.52 125.89,64.95 124.6,66.23 122.78,66.23 121.11,67.9 v1(121.11,68.83)
  BOTTOM w0.102: v2(132.04,60.68) 132.04,59.89 132.14,59.78 v3(132.14,59.63) ; R2402.2 123.67,72.29 122.03,72.29 121.32,73 120.62,73 120.3,72.68 120.3,69.7 121.11,68.88 v1(121.11,68.83) 121.74,68.21 R5502.2
PMU_RCOMP: length 1.3
  TOP w0.254: CPU1.AG59 v3(83.92,178.37)
  BOTTOM w0.381: R584.2 83.86,178.43 v3(83.92,178.37)
PMU_WAKE#_EMMC: length 3.9
  BOTTOM w0.102: R521.1 110.99,223.88 R518.1 111.05,223.94 R517.1 v2(112.49,225.19)
PNL0_BKLCTL: length 14
  TOP w0.102: CPU1.C46 72.35,171.6 72.02,171.6 71.7,171.92 70.24,171.92 69.65,172.52 v4(69.6,172.52) 69.6,172.87 68.72,173.76 68.61,173.76 67.09,175.29 60.52,175.29 R142.2
PNL1_BKLCTL: length 13.9
  TOP w0.102: CPU1.C53 72.73,174.73 72.56,174.56 72.34,174.56 72.22,174.44 71.97,174.44 71.78,174.62 69.87,174.62 67.7,176.79 67.47,176.79 67.46,176.78 64.98,176.78 64.65,177.11 v4(64.02,177.11) 60.98,177.11 R136.1
PORTC_SPK_L: length 19.7
  TOP w0.203: R427.1 162.36,39.75 v1(162.85,40.23) ; v1(158.71,53.26) 158.71,53.15 159.35,52.52 U16.43
  L4 w0.203: v1(162.85,40.23) 162.72,40.36 162.72,50.93 161.7,51.94 159.67,51.94 158.71,52.91 v1(158.71,53.26)
  BOTTOM w0.203: v2(158.76,54.1) 158.71,54.05 v1(158.71,53.26)
PORTC_SPK_L_1: length 2.6
  TOP w0.203: R427.2 R431.1 160.04,38.21 v4(159.11,38.21)
PORTC_SPK_R: length 22.7
  TOP w0.203: v1(163.84,40.16) 163.66,39.98 R430.1 ; U16.44 158.95,52.31 157.84,53.42 v1(157.69,53.42)
  L4 w0.203: v1(163.84,40.16) 163.3,40.69 163.3,51.23 161.96,52.58 161.07,52.58 159.67,53.98 158.25,53.98 v1(157.69,53.42)
  BOTTOM w0.203: v1(157.69,53.42) 156.86,53.42 v2(156.84,53.44)
PORTC_SPK_R_1: length 2.6
  TOP w0.203: R432.1 165.18,37.67 R430.2 165.18,39.73 v4(164.85,40.07)
PQ4206_D: length 14
  TOP w0.305: PR178.2 70.63,33.29 69.96,33.96 69.96,35.03 68.66,36.33 68.66,39.03 69.15,39.52 v1(69.15,41.02) 68.56,41.61 68.56,43.32 67.95,43.93 Q36.3
  BOTTOM w0.305: v2(70.01,41.02) v1(69.15,41.02)
PQ4406_2: length 12.3
  TOP w0.102: 52.13,72.24 51.06,72.24 50.45,72.85 48.81,72.85 PR135.2 ; 52.13,72.24 52.74,71.63 53.7,71.63 55.35,69.98 v4(55.35,69.14) 55.3,69.09 PR140.1 ; 52.13,72.24 53.14,73.25 PQ6.2
PQ4406_3: length 8.5
  TOP w0.102: PR136.2 59.39,72.19 58.78,71.57 v4(58.48,71.57) 54.63,71.57 PQ6.3
PQ4406_5: length 5.6
  TOP w0.102: v4(60.23,72.92) 59.82,73.33 58.49,73.33 58.21,73.05 PR133.2 57.26,72.85 PC106.1 56.5,73.25 PQ6.5
PQ4406_6: length 5
  TOP w0.102: v4(59.89,74.78) 59.08,74.78 PR132.1 57.98,74.19 PC106.2 56.79,73.9 PQ6.6
PQ4409_C: length 4.2
  TOP w0.102: PQ7.C 49.36,71.98 48.8,71.42 PR135.1 47.25,71.42 PR134.1 47.25,70.78 v4(46.7,70.23)
PQ4409_E: length 5.2
  TOP w0.102: PR129.2 50.93,74.41 PR130.1 ; PR130.1 50.92,74.65 51.47,75.2 v4(52.83,75.2) ; PR130.1 50.92,73.76 PQ7.E
PRE: length 3.9
  TOP w0.127: U20.16 132.54,39.3 v4(132.73,39.5) 132.73,40.29 v1(132.74,40.29) R421.2
  BOTTOM w0.127: R421.2 v1(132.74,40.29)
PSID_D: length 8
  TOP w0.102: v4(46.21,15.57) 46.21,16.36 47.04,17.18 Q41.D 48.09,20.26 48.09,21.27 L16.2 R478.1
PSID_D_1: length 4.1
  TOP w0.102: v4(44.43,23.7) 44.8,24.07 Q39.B 45.6,23.98 R477.1 R478.2
PSID_G: length 13.6
  TOP w0.102: R485.2 45.23,16.8 46.13,17.7 46.13,19.18 Q41.G 45.02,20.3 45.02,22.77 44.65,23.14 43.95,23.14 43.59,23.5 43.59,24.4 44.21,25.02 v4(44.23,25.02) 44.23,25.03 45.17,25.97 Q39.C
PSL_IN1#: length 10.1
  TOP w0.102: U14.73 129.73,56.13 129.09,56.77 128.01,56.77 128.01,56.77 126.19,56.77 124.28,58.68 124.24,58.68 123.99,58.94 v1(123.99,59.08)
  BOTTOM w0.102: v1(123.99,59.08) 123.99,59.06 123.42,58.49 v2(123.42,58.49) 123.42,58.49 R738.2
PSL_IN2#: length 7.1
  TOP w0.102: R358.2 137.46,65.61 v4(134.13,65.61) 133.31,65.61 131.83,64.13 U14.93
PSL_OUT#: length 25.6
  TOP w0.102: v1(134.58,55.83) 134.32,55.58 132.67,55.58 131.71,56.53 U14.74
  BOTTOM w0.102: R705.1 141.69,73.75 141.69,72.09 142.19,71.59 142.19,64.73 v2(140.41,62.95) 140.41,61.99 135.16,56.74 135.16,56.3 134.89,56.03 134.78,56.03 v1(134.58,55.83)
PSTBTN_N: length 145.3
  TOP w0.089: 82.39,181.36 82.42,181.33 82.42,180.74 82.43,180.74 82.43,180.37 82.54,180.26 CPU1.AD62
  TOP w0.102: 86.59,189.76 86.59,189.43 87.01,189.01 88.39,189.01 89.54,190.17 89.54,194.23 92.44,197.13 96.27,197.13 99.12,199.98 99.12,205.1 98.46,205.77 98.02,205.77 97.62,205.37 97.09,205.37 96.8,205.08 94.47,205.08 94.4,205.01 93.95,205.01 93.05,204.11 87.82,204.11 v4(87.41,204.53) 86.89,205.05 86.89,208.45 88.8,210.36 88.8,216.81 87.58,218.04 v1(87.05,218.04) ; 86.59,189.76 86.59,191.14 86.18,191.55 86.18,191.95 86.49,192.25 R1801.2 ; 86.59,189.76 84.72,187.88 84.72,186.42 84.1,185.8 84.1,185.13 82.39,183.42 82.39,181.36 ; v1(19,214.46) 18.66,214.12 R40.2
  L4 w0.127: v1(87.05,218.04) 82.37,222.72 77.07,222.72 75.42,224.37 29.53,224.37 19.62,214.46 19.01,214.46 v1(19,214.46)
  BOTTOM w0.102: R530.1 87.1,217.99 v1(87.05,218.04)
PSTBTN_N_APS: length 1.2
  BOTTOM w0.102: TP58.1 87.11,216.2 R530.2
PSYS: length 5.7
  TOP w0.254: PR16.2 58.3,208.71 PR21.1 58.3,207.88 58.3,207.88 v1(58.3,207.74)
  BOTTOM w0.203: PU13.50 59.35,209.73 v2(58.9,209.28) 58.27,208.65 58.27,207.91 58.3,207.88 v1(58.3,207.74)
PURE_HW_SHUTDOWN#: length 55.4
  TOP w0.102: R280.1 102.9,90.04 102.41,89.55 102.41,89.17 101.43,88.19 101.43,87.81 v1(101.38,87.76) ; Q34.D 129.62,72.78 v1(129.63,72.79)
  L4 w0.127: v1(129.63,72.79) 126.79,75.63 124.27,75.63 123.01,76.89 123.01,76.98 121.45,78.54 119.08,78.54 117.14,80.48 115.76,80.48 113.2,83.03 106.8,83.03 102.92,86.92 102.92,87.86 102.58,88.2 101.98,88.2 101.66,87.88 101.51,87.88 v1(101.38,87.76)
  BOTTOM w0.102: Q1802.C 129.1,73.32 v1(129.63,72.79) 129.71,72.71 D8.K 129.71,69.08 Q65.B 131.46,70.5 133.19,70.5 v2(133.19,70.51) 133.21,70.51 133.21,70.5 R716.2 134.12,70.49 R719.1
PURE_HW_SHUTDOWN#_R: length 3.6
  TOP w0.102: v4(101.89,95.12) 101.95,95.19 R280.2 102.9,95.9 103.4,96.39 Q25.D
PW_CLEAR: length 166.6
  TOP w0.102: v1(67.34,199.22) 68.05,199.92 76.21,199.92 77.51,198.62 81.28,198.62 v4(83.06,200.4) 86.37,203.71 86.37,208.61 88.32,210.56 v1(88.32,216.65) ; CPU1.E41 73.95,168.87 v3(73.95,167.84) ; v1(148.66,199.75) 148.93,199.47 148.93,187.15 R99.2
  L3 w0.127: v1(88.32,216.65) 89.62,216.65 91.73,218.76 95.73,218.76 96.71,217.79 96.71,217.12 97.79,216.04 100.29,216.04 101.11,215.22 102.86,215.22 106.92,211.17 120.2,211.17 120.69,210.68 136.03,210.68 146.96,199.75 v1(148.66,199.75) ; v1(59.47,174.16) 59.47,174.03 60.71,172.79 64.18,172.79 67.21,169.75 68.97,169.75 69.14,169.91 71.52,169.91 73.04,168.39 73.4,168.39 v3(73.95,167.84)
  L4 w0.127: v1(59.47,174.16) 59.47,180.11 65.9,186.53 65.9,194.69 66.58,195.38 66.58,198.35 67.34,199.11 v1(67.34,199.22)
PW_CLEAR_H: length 18.3
  TOP w0.102: v4(147.78,187.35) 146.96,186.52 R99.1 146.96,185.03 R109.1 146.97,181.38 145.83,180.24 145.83,176.48 147.68,174.62 147.68,171.95 JMP1.3
PWR_1D05V_A: length 22.2
  TOP w0.508: R121.1 25.93,183.21 PC28.1 25.92,183.58 26.26,183.92 v1(26.9,183.92)
  L3 w0.508: v5(44.61,179.2) 42.78,179.2 39.65,182.33 28.48,182.33 v1(26.9,183.92)
  vias: v2(38.4,177.72) v5(37.27,179.87) v5(38.01,174.75) v5(38.48,179.91) v5(39.28,174.75) v5(40.42,177.8) v5(40.42,176.66) v5(41.69,177.8) v5(41.69,176.66)
PWR_1D05V_EN: length 6.2
  TOP w0.254: R118.2 28,182.44 R119.1 ; R118.2 29.12,182.43 PR40.1 ; R118.2 29.12,181.55 C569.1 30.56,181.48 v4(30.59,181.46) 30.59,180.98 30.09,180.48 PU2.5
PWR_1D05V_FB: length 6.9
  TOP w0.254: PU2.6 26.99,180.1 25.94,181.15 25.56,181.15 v4(25.53,181.18) 25.48,181.18 R128.1 24.41,181.12 PC30.1 25.04,181.75 R121.2 25.03,182.16 PC28.2
PWR_1D05V_FB_N: length 2.2
  TOP w0.254: PR41.1 23.05,182.13 v4(23.02,182.1) 23.02,181.66 PC30.2
PWR_1D05V_LX:
  vias: v2(33.08,177.37) v5(30.79,177.32) v5(32.42,179.86) v5(32.93,180.75) v5(33.56,179.86) v5(33.82,174.88) v5(34.45,178.18) v5(34.45,176.28)
PWR_1D05V_PVIN:
  vias: v4(24.77,174.8)
PWR_1D05V_SN: length 2.8
  TOP w0.508: PR48.2 31.07,172.33 PC38.1 28.98,172.33 28.84,172.19 v4(28.71,172.19)
PWR_1D05V_SVIN: length 4.6
  TOP w0.305: PU2.8 26.48,179.03 v4(25.69,179.83)
  TOP w0.508: v4(25.69,179.83) 25.69,179.58 25.18,179.07 PC33.1
  TOP w0.635: PR43.2 24.85,177.91 PC33.1
PWR_1D24V_A: length 21.8
  TOP w0.508: v1(32.42,170.43) PC39.1 R165.1
  BOTTOM w0.508: v1(45.71,163.12) v2(45.71,166.7) 45.71,168.15 45.16,168.7 33.22,168.7 32.42,169.5 v1(32.42,170.43)
  vias: v5(43.64,161.32) v5(44.74,161.29)
PWR_1D24V_EN: length 5.1
  TOP w0.254: PU3.5 35.17,166.78 35.49,167.11 v1(35.49,167.28) 35.59,167.39 PC40.1 PR50.2 PR49.1
  BOTTOM w0.254: v1(35.49,167.28) v2(36.28,167.28)
PWR_1D24V_FB: length 6.9
  TOP w0.254: PC39.2 R165.2 31.4,168.3 30.82,167.72 30.21,167.72 PC42.1 30.05,166.94 R167.1 30.54,166.91 30.83,166.62 v1(30.87,166.62) 31.53,166.62 31.58,166.58 PU3.6
  BOTTOM w0.254: v2(30.11,166.6) 30.84,166.6 v1(30.87,166.62)
PWR_1D24V_FB_N: length 2.2
  TOP w0.254: v4(29.12,170) 29.18,169.94 PR52.1 29.16,168.89 PC42.2
PWR_1D24V_LX:
  vias: v2(37.76,163.98) v5(35.85,163.63) v5(35.85,162.61) v5(37.32,166.37) v5(37.88,161.42) v5(38.46,166.37) v5(39.15,161.42) v5(39.53,163.96)
PWR_1D24V_PG: length 259
  TOP w0.203: U14.61 128.25,50.46 128.72,49.99 129.9,49.99 131.35,48.55 131.35,48.37 v1(131.38,48.34)
  TOP w0.254: v1(38.64,170.43) 38.92,170.15 v4(38.92,169.47) 38.92,169.08 38.44,168.59 PR51.2 PC41.1 36.61,168.28 36.1,167.77 36.1,166.37 35.81,166.08 PU3.4
  L3 w0.254: v1(94.7,40.28) 89.56,40.28 88.07,41.78 88.07,44.37 84.13,48.31 61.93,48.31 58.78,51.46 57.49,51.46 56.07,52.88 56.07,53.92 55.05,54.94 52.69,54.94 50.4,57.23 50.4,60.57 48.03,62.94 44.38,62.94 40.85,66.47 40.85,67.23 37.37,70.71 37.37,78.89 37.96,79.48 37.96,80.95 38.56,81.56 38.56,105.77 37.17,107.16 37.17,116.81 35.44,118.54 35.44,129.64 34.63,130.45 34.63,130.45 33.79,131.29 33.79,134.32 33.36,134.75 v1(32.95,134.75) ; v1(108.2,29.64) 105.93,31.92 v1(105.24,31.92)
  L4 w0.254: v1(38.64,170.43) 39.52,169.56 46.11,169.56 47.26,168.41 47.26,161.36 47.91,160.72 47.91,157.81 48.52,157.2 48.52,150.57 48.29,150.34 48.29,150.04 33,134.75 v1(32.95,134.75) ; v1(105.24,31.92) 101.36,31.92 94.24,39.03 94.24,39.83 v1(94.7,40.28) ; v1(131.38,48.34) 131.38,45.11 129.33,43.07 129.33,42.62 129.36,42.6 129.36,42.18 128.86,41.68 128.86,39.42 124.24,34.8 119.6,34.8 115.85,31.05 109.61,31.05 v1(108.2,29.64)
  BOTTOM w0.254: v1(38.64,170.43) v2(39.52,170.43)
PWR_1D24V_PVIN:
  vias: v4(26.14,163.6)
PWR_1D24V_SN: length 3
  TOP w0.508: v4(33.46,158.85) 33.48,158.88 PC50.1 36.21,158.88 PR58.2
PWR_1D24V_SVIN: length 5.5
  TOP w0.305: PU3.8 31.12,165.58 v1(30.94,165.4) 30.42,165.93 PC45.1
  TOP w0.508: PC45.1 30.04,164.73 PR55.2
  BOTTOM w0.508: v2(29.8,164.26) v1(30.94,165.4)
PWR_1D35V_A: length 28.3
  TOP w0.457: v1(23.93,155.02) 24.06,155.14 PR75.1
  TOP w0.508: PC63.1 PR75.1
  BOTTOM w0.508: v5(44.28,150.37) 44.28,153.67 40.62,157.33 26.88,157.33 24.57,155.02 v1(23.93,155.02)
  vias: v4(49.06,150.55)
PWR_1D35V_FB: length 6.4
  TOP w0.254: PR67.1 PR75.2 PC63.2 PC51.1 26.78,153.21 v4(27.29,152.7) 27.86,152.13 PU4.6
PWR_1D35V_FB_N: length 2.1
  TOP w0.254: v4(24.01,153.29) 24.87,153.29 PC51.2 24.99,153.19 PR60.1
PWR_1D35V_LX:
  vias: v1(34.42,153.03) v1(34.88,148.03) v1(35.54,153.03) v1(36.02,148.06) v1(36.84,151.36) v1(36.86,149.76) v2(33.94,148.08)
PWR_1D35V_PVIN:
  vias: v4(28.15,144.45)
PWR_1D35V_SN:
  vias: v4(33.28,144.7)
PWR_1D35V_SVIN: length 5.2
  TOP w0.305: PU4.8 v4(27.29,151.13) 25.95,151.13 PC62.1 25.88,150.94 PR65.2
PWR_1P15V_PG_L: length 2.6
  BOTTOM w0.254: Q52.3 26.07,171.16 v2(26.07,172.15) 26.95,172.15 R587.2
PWR_3D3V_5V_PG: length 4
  TOP w0.102: PR166.2 60.08,55.54 v4(60.18,55.64) 60.18,55.8 61.76,57.38 PU10.7
PWR_3D3V_BOOT2: length 3.2
  TOP w0.203: v4(62.77,56.39) 62.56,56.6 PU10.9
  TOP w0.305: v4(62.77,56.39) 63,56.16 PR167.2
PWR_3D3V_BOOT2_A: length 3.4
  TOP w0.305: v4(63.43,51.69) 63.43,52.68 PR167.1 PC121.2
PWR_3D3V_CS2: length 3.6
  TOP w0.203: PR163.1 60.31,57.4 v1(60.54,57.63) 60.54,58.69 PU10.5
  BOTTOM w0.254: v2(59.98,58.37) 60.54,57.81 v1(60.54,57.63)
PWR_3D3V_EN2: length 8.3
  TOP w0.102: PR164.1 58.17,51.87 57.46,52.58 v4(57.46,53.01) 57.46,53.09 59.01,54.64 PC119.1 59.58,55.28 59.58,55.89 61.36,57.67 PU10.6
PWR_3D3V_FB2: length 4.7
  TOP w0.203: v4(59.24,58.52) 59.88,59.16 PU10.4
  TOP w0.254: PC116.2 58.08,57.4 PR162.2 58.29,57.61 PR160.1 58.41,58.57 59.19,58.57 v4(59.24,58.52)
PWR_3D3V_FB2_A: length 46.6
  TOP w0.508: PG7.1 93.78,48.49 92.61,47.32 66.51,47.32 63.74,50.09 v4(62.26,50.09) 57.51,50.09 56.01,51.59 56.01,53.75 57.13,54.86 PC116.1 58.08,56.52 PR162.1
PWR_3D3V_HG2: length 21
  TOP w0.203: PU10.10 62.96,57.72 v5(63.53,57.15)
  L4 w0.762: v5(78.39,53.85) 78.39,53.52 76.49,51.61 67.82,51.61 63.53,55.9 v5(63.53,57.15)
  BOTTOM w0.508: v5(63.53,57.15) v2(63.53,56.24)
PWR_3D3V_LDO3: length 5.9
  TOP w0.203: v1(59.36,59.51) 59.42,59.56 PU10.3
  BOTTOM w0.254: PC185.1 59.6,61.37 PG18.2 ; PC185.1 59.62,59.76 v1(59.36,59.51) ; PC185.1 v2(59.62,62.52)
PWR_3D3V_LG2: length 14.5
  TOP w0.203: v5(64.6,57.76) 64.14,57.76 63.71,58.19 PU10.11
  L3 w0.762: v5(64.6,57.76) 66.91,55.45 70.29,55.45 71.15,54.58 v5(75.14,54.58)
  BOTTOM w0.305: v2(64.36,58.63) 64.6,58.39 v5(64.6,57.76)
PWR_3D3V_PH2: length 25.7
  TOP w0.203: PU10.8 62.16,57.05 61.81,56.69 v5(61.81,56.52)
  TOP w0.635: v5(61.81,56.52) 61.81,55.72 61.25,55.16 PC121.1
  L4 w0.762: v5(79.97,51.82) 79.95,51.83 78.89,51.83 77.25,50.19 67.27,50.19 61.81,55.66 v5(61.81,56.52)
  vias: v2(82.2,51.79) v5(79.92,57.51) v5(81.08,51.79) v5(81.19,57.48) v5(82.43,57.45)
PWR_3D3V_SN: length 3.5
  TOP w0.508: PCT2.1 77.02,59.1 77.53,59.61 v4(77.73,59.61) PRT3.2
PWR_5V3V_EMN_R: length 16.5
  TOP w0.102: v1(132.09,75.46) 131.61,75.95 130.16,75.95 129.8,75.59 127.82,75.59 126.78,74.55 126.68,74.55 124.63,72.5 D4.3
  BOTTOM w0.102: R711.1 132.47,72.8 R712.1 132.48,73.78 R709.1 ; R711.1 v2(131.47,73.71) 131.47,74.47 131.95,74.95 131.95,75.07 132.09,75.2 v1(132.09,75.46) ; R711.1 131.47,71.72 D8.A
PWR_5V_BOOT1: length 3.4
  TOP w0.203: 63.23,62.28 63,62.05 v1(62.85,62.05) 62.56,61.77 PU10.17
  TOP w0.508: PR152.1 63.74,62.79 63.23,62.28
  BOTTOM w0.508: v2(63.58,62.66) 63.46,62.66 v1(62.85,62.05)
PWR_5V_BOOT1_A: length 1.7
  TOP w0.254: PC109.1 63.58,65.15 PR152.2
PWR_5V_BYP1: length 59.2
  TOP w0.203: 65.92,60.02 65.87,60.02 65.54,59.69 65.06,59.69 64.78,59.96 PU10.14
  TOP w0.254: 65.92,60.02 66.09,60.19 66.09,61.39 PC111.2 65.4,61.66 65.18,61.87 65.18,65.18 64.27,66.09 57.26,66.09 v4(57.08,65.91) 57.08,65.51 v1(57.56,65.02)
  TOP w0.381: PG3.1 82.91,71.38 v1(82.89,71.36)
  L4 w0.381: v1(57.56,65.02) 58.58,66.04 60.15,66.04 61.04,66.93 61.04,71.22 63.06,73.24 81.02,73.24 v1(82.89,71.36)
PWR_5V_CS1: length 3.6
  TOP w0.102: PR155.1 60.54,62.33 v4(59.34,61.14) 60.12,60.36 PU10.1
PWR_5V_EN1: length 5.9
  TOP w0.102: v4(59.24,65.46) 59.39,65.3 60.59,65.3 60.94,64.95 PR150.1 PC110.1 61.36,63.21 PU10.20
PWR_5V_FB1: length 6.1
  TOP w0.203: PU10.2 59.81,59.96 59.39,60.38
  TOP w0.254: 59.39,60.38 58.76,60.38 58.44,60.69 PR158.2 58.4,59.87 v4(58.2,59.67) 57.8,60.06 57.8,60.28 PC112.2 57.2,60.51 PR159.1
PWR_5V_FB1_A: length 46
  TOP w0.381: PGT1.1 94.39,71.42 93.31,72.5 83.79,72.5 81.91,74.38 69.43,74.38 66.74,71.68 v1(66.74,70.52) ; PC112.1 PR158.1 58.4,62.68 v4(58.42,62.7) 58.42,63.51 v1(58.35,63.58)
  L4 w0.381: v1(66.74,70.52) 66.74,70.48 61.41,65.15 59.23,65.15 58.35,64.27 v1(58.35,63.58)
PWR_5V_HG1: length 20.4
  TOP w0.203: v5(63.79,61.34) 63.56,61.11 PU10.16
  L4 w0.762: v5(63.79,61.34) 63.79,62.6 68.24,67.06 75.59,67.06 76.21,66.45 v5(76.21,65.46)
  BOTTOM w0.508: v5(63.79,61.34) v2(63.79,60.4)
  BOTTOM w0.762: PR223.2 76.18,65.43 v5(76.21,65.46)
PWR_5V_HG1_R:
  vias: v2(78.11,62.26) v5(78.27,65.02)
PWR_5V_LDO5: length 6.3
  TOP w0.203: 66.58,58.93 65.21,58.93 64.57,59.56 PU10.13 ; 68.03,57.78 68.03,59.26 PC113.1
  TOP w0.254: 66.58,58.93 67.01,59.35 PC113.1
PWR_5V_LG1: length 15.7
  TOP w0.203: PU10.15 64.99,60.36 65.18,60.55 v5(65.18,60.63)
  L3 w0.762: v5(74.61,65.75) 74.09,66.27 68.94,66.27 65.18,62.51 v5(65.18,60.63)
  BOTTOM w0.762: v5(74.61,65.75) 74.61,65.75 v2(74.61,64.72)
PWR_5V_PH1: length 22.7
  TOP w0.203: PU10.18 v5(62.16,62.71)
  TOP w0.508: 62.26,63.63 62.14,62.74 v5(62.16,62.71)
  L4 w0.762: v5(62.16,62.71) 62.16,62.95 67.67,68.46 79.14,68.46 v5(79.62,68.94)
  vias: v2(79.66,67.06) v5(79.92,63.5) v5(80.98,68.89) v5(81.44,63.5) v5(82.4,68.82) v5(82.78,67.29) v5(82.8,65.83) v5(82.8,64.36)
PWR_5V_SN: length 4
  TOP w0.508: PC108.1 76.4,72.14 v4(77.12,72.14) 77.2,72.14 PR137.2
PWR_ALERT#: length 5.3
  BOTTOM w0.203: PU13.37 65.01,212.06 65.01,212.06
  BOTTOM w0.254: 65.01,212.06 65.25,212.06 65.37,211.94 66.16,211.94 R539.1 66.52,211.87 67.06,212.42 67.92,212.42 v2(68.29,212.79)
PWR_CHG_ACDET: length 9.2
  BOTTOM w0.254: v2(53.23,66.4) 53.23,66.21 53.12,66.1 PR222.2 53.12,63.94 PC179.1 PR224.1 53.18,62.7 52.4,61.92 51.92,61.92 51.39,61.39 51.39,60.61 50.22,59.44 U34.6
PWR_CHG_ACN: length 21.6
  TOP w0.381: v1(46.34,60.87) 46.88,60.33 49.55,60.33 50.96,58.92 50.96,54.69 51.6,54.05 51.6,51.85 52.18,51.27 52.18,50.41 ; v4(51.86,50.41) 52.18,50.41 ; 52.18,50.41 52.18,49.07 PG9.2
  BOTTOM w0.305: v1(46.34,60.87) 46.5,60.87 47.42,59.95 U34.1
  BOTTOM w0.381: PC181.1 45.11,61.86 PC182.1 46.11,60.87 v1(46.34,60.87)
PWR_CHG_ACP: length 20.8
  TOP w0.381: v1(47.32,60.93) 47.41,60.84 49.76,60.84 51.47,59.13 51.47,56.35 ; 51.47,56.35 51.47,54.9 52.1,54.26 52.1,52.06 52.68,51.48 52.68,49.06 PG8.2 ; 51.47,56.35 v4(51.81,56.35)
  BOTTOM w0.305: v1(47.32,60.93) 47.38,60.87 47.38,60.73 47.92,60.19 U34.2
  BOTTOM w0.381: v1(47.32,60.93) 46.65,61.6 PC182.2 46.35,62.14 PC180.1
PWR_CHG_AD_OFF: length 96.7
  TOP w0.102: PR175.1 70.58,41.67 69.98,42.27 69.98,43.05 v3(70.02,43.09) 70.02,43.34 70.59,43.92 70.59,44.53 70.31,44.81 Q36.5 ; v1(117.64,63.6) 117.2,63.17 116.67,63.17 116.51,63.33 U14.6
  L4 w0.127: v3(70.02,43.09) 70.23,42.88 70.89,42.88 71.15,43.14 71.15,43.44 71.41,43.7 85.24,43.7 85.57,43.37 93.65,43.37 94.55,42.47 94.55,41.15 96.62,39.08 102.37,39.08 102.6,38.85 107.76,38.85 108.85,39.94 113.52,39.94 114.31,39.15 121.73,39.15 124.9,42.32 124.9,43.9 126.65,45.65 126.65,51.59 127.15,52.08 127.15,58.58 126.18,59.55 123.06,59.55 119.02,63.59 118.17,63.59 118.16,63.6 v1(117.64,63.6)
  BOTTOM w0.102: v1(117.64,63.6) 117.76,63.73 v2(118.49,63.73)
PWR_CHG_AD_OFF_R: length 4.2
  TOP w0.102: PQ14.B 70.54,39.22 70.24,39.52 v1(70.24,39.83) 70.24,40.4 PR175.2
  BOTTOM w0.102: v2(69.93,38.43) 70.24,38.73 v1(70.24,39.83)
PWR_CHG_BTST: length 6.1
  TOP w0.508: PR161.1 43.66,57.65 44.08,57.23 44.08,55.91 v1(44.2,55.78)
  BOTTOM w0.305: v1(44.2,55.78) 44.71,55.78 45.88,56.95 45.88,57.05 46.11,57.28 U34.17
  BOTTOM w0.508: v2(43.42,55.79) 43.42,55.78 v1(44.2,55.78)
PWR_CHG_BTST_1: length 4.2
  TOP w0.508: PD2.K 43.21,57.02 42.77,57.47 PR161.2 42.77,58.96 PC114.1 41.92,59.01 v4(41.53,59.4)
PWR_CHG_CMPIN: length 9.5
  TOP w0.305: PR149.2 PR148.1 PR147.1 48.83,64.53 PR153.2 49.11,63.7 v1(49.56,63.25)
  TOP w0.381: v1(49.56,63.25) 50.02,63.7 PR154.2
  BOTTOM w0.305: v1(49.56,63.25) v2(49.56,61.4) 49.39,61.23 49.39,61.19 48.92,60.72 U34.4
PWR_CHG_CMPIN_R: length 3.3
  TOP w0.305: PQ8.3 48.55,66.65
  TOP w0.508: 48.55,66.65 48.55,66.4 48.6,66.34 PR147.2 48.52,65.72 47.01,65.72 v4(46.96,65.67)
PWR_CHG_CMPIN_RR: length 6.7
  TOP w0.305: PQ8.6 51.86,68.57 52.74,67.69 52.74,66.51 51.98,65.75 v4(51.98,65.38) 51.65,65.38 51.31,65.72 PR149.1
PWR_CHG_HIDRV: length 11.4
  L3 w1.016: v5(37.49,57.12) 44.91,57.12 v5(44.99,57.05)
  BOTTOM w0.305: v5(44.99,57.05) 45.02,57.07 45.02,57.3 45.5,57.78 U34.18
  BOTTOM w0.406: PU19.4 37.38,57.24 v5(37.49,57.12)
  BOTTOM w0.508: v5(44.99,57.05) v2(44.1,57.05)
PWR_CHG_ILIM: length 6.4
  BOTTOM w0.254: U34.10 50.94,56.79 v2(51.85,55.88) 51.85,55.7 52.75,54.8 PR231.2 52.99,55.73 53,55.83 PR229.1 53.18,56.01 PQ19.D
PWR_CHG_IOUT: length 9.1
  TOP w0.102: v1(51.98,61.06) 50.71,62.33 PR154.1
  BOTTOM w0.102: U34.7 50.76,58.29 51.1,58.63 51.1,59.12 v2(51.76,59.78) 52.07,60.09 52.57,60.09 PR227.1 PC183.1 52.52,61.06 v1(51.98,61.06)
PWR_CHG_LODRV: length 13.4
  TOP w0.508: v5(38.18,53.95) 38.22,53.91 PC122.1
  L3 w1.016: v5(46.41,55.27) 46.41,55.12 45.4,54.1 38.34,54.1 v5(38.18,53.95)
  BOTTOM w0.305: U34.15 47.13,55.98 v5(46.41,55.27)
  BOTTOM w0.406: PU18.4 v5(38.18,53.95)
  BOTTOM w0.508: v2(45.96,54.28) 45.96,54.5 46.11,54.65 46.11,54.97 v5(46.41,55.27)
PWR_CHG_NC: length 3.4
  BOTTOM w0.254: PR232.1 51.66,54.61 v2(50.58,54.61) 50.3,54.61 49.42,55.49 U34.11
PWR_CHG_PHASE: length 13.6
  TOP w0.508: PC114.2 44.94,58.31 v5(44.94,58.3)
  L3 w1.016: v5(44.94,58.3) 44.73,58.3 44.25,58.78 35.95,58.78 v5(35.66,58.48)
  BOTTOM w0.305: v5(44.94,58.3) 44.96,58.29 U34.19
  BOTTOM w0.508: v2(43.74,58.32) 43.82,58.39 44.85,58.39 v5(44.94,58.3)
PWR_CHG_SRN: length 2.9
  BOTTOM w0.254: U34.12 48.92,55.27 48.8,55.15 48.8,54.69 ; 48.8,54.69 v2(49.21,54.69) ; 48.8,54.69 48.8,53.8 PR234.1
PWR_CHG_SRP: length 3
  BOTTOM w0.254: v2(47.99,54.64) 48.42,54.64 ; 48.42,54.64 U34.13 ; 48.42,54.64 48.42,54.2 PR233.1
PWR_CHG_VCC: length 8.9
  BOTTOM w0.305: v2(45.25,59.39) 45.25,59.31 45.77,58.78 U34.20
  BOTTOM w0.381: PR221.2 43.05,64.23 42.36,63.54 42.36,60.82 43.39,59.79 PC186.1 43.77,59.59 45.04,59.59 v2(45.25,59.39)
PWR_CORE_BOOT: length 6.1
  BOTTOM w0.203: 58.07,217.3 58.55,216.82 PU13.14
  BOTTOM w0.508: PR181.2 55.81,219.65 v2(55.81,219.24) 55.81,218.8 57.31,217.3 58.07,217.3
PWR_CORE_BOOT_A: length 3.8
  BOTTOM w0.508: v2(55,222.58) 55,222.58 PR181.1 57.74,222.58 PC128.1
PWR_CORE_HG1: length 29.5
  TOP w1.016: PR29.1 v5(50.59,204.22)
  L3 w1.016: v5(50.59,204.22) 48.31,206.5 48.31,218.19 50.27,220.15 55.98,220.15 57.01,219.13 v5(57.01,219.1)
  BOTTOM w0.203: v2(58.02,218.19) 58.96,217.25 58.96,216.59 PU13.15
  BOTTOM w0.508: v5(57.01,219.1) 57.03,219.1 57.95,218.19 v2(58.02,218.19)
PWR_CORE_HG1_R: length 5.9
  L3 w1.016: v5(43.37,200.36) v5(49.23,200.36)
  vias: v2(42.18,200.32)
PWR_CORE_LG1: length 61.6
  TOP w0.762: v5(37.5,192.79) 37.54,192.83 PQ2.4 ; PQ3.4 37.56,187.47 36.1,187.47 v5(35.91,187.28)
  L4 w1.016: v5(35.91,187.28) 36.9,187.28 37.5,187.88 v5(37.5,192.79) 37.5,198.5 39.91,200.92 39.91,214.25 48.83,223.16 57.16,223.16 59.57,220.75 v5(59.57,219.38)
  BOTTOM w0.203: v2(59.53,218.46) 59.75,218.25 59.75,216.58 PU13.17
  BOTTOM w0.508: PR183.1 59.6,219.41 v5(59.57,219.38) 59.57,219.3 59.53,219.27 v2(59.53,218.46)
PWR_CORE_LX1: length 40.8
  L3 w1.016: v5(41.94,199.01) 41.55,199.41 41.55,202.17 46.64,207.26 46.64,218.95 49.51,221.82 56.72,221.82 58.39,220.15 v5(58.39,219.38)
  BOTTOM w0.203: v5(58.39,219.38) 58.39,218.7 59.35,217.74 PU13.16
  BOTTOM w0.508: v5(58.39,219.38) 58.43,219.41 58.43,220.32 PC128.2
  vias: v2(40.36,187.54) v2(43.6,197.27) v5(45.33,189.75) v5(45.34,188.57) v5(45.31,187.23) v5(45.48,198.11) v5(45.49,196.93) v5(45.46,195.6) v5(46.43,189.71) v5(46.43,188.55) v5(46.45,187.2) v5(46.58,198.07) v5(46.58,196.91) v5(46.61,195.56) v5(47.54,189.75) v5(47.45,188.47) v5(47.47,187.2) v5(47.6,196.83) v5(47.62,195.56) v5(47.69,198.11)
PWR_CORE_SN: length 2.8
  TOP w0.508: PC20.1 37.89,200.6 38.32,201.03 38.34,201.05 38.54,201.24 v4(38.62,201.24) 38.9,201.24 39.71,200.43 PR30.2
PWR_DCBATOUT_VCCGI: length 6.9
  TOP w0.381: 49.49,218.93 49.71,219.14 50.78,219.14 PR1.1 ; 49.49,218.93 v4(49.47,218.93) ; 49.49,218.93 48.08,217.51 48.08,215.21 47.45,214.58
  vias: v5(41.82,213.61) v5(41.82,209.8) v5(41.94,212.47) v5(41.87,208.28) v5(42.96,213.61) v5(42.96,209.8) v5(43.01,208.28) v5(43.09,212.47) v5(44.1,213.61) v5(44.1,209.8) v5(44.23,212.47) v5(44.16,208.28)
PWR_DCBATOUT_VDDQ: length 16.4
  L4 w0.381: v1(150.5,131.57) 150.5,132.23 150.38,132.36 150.38,133.86 148.62,135.61 v5(148.62,146.18)
  BOTTOM w0.381: PR213.1 150.67,131.65 150.58,131.65 v1(150.5,131.57)
  vias: v2(147.35,147.83) v4(145.58,147.19) v5(148.62,147.19)
PWR_DCBATOUT_VNN:
  vias: v2(73.49,213.99) v2(73.57,217.63)
PWR_DDR_SN:
  vias: v4(151.29,151.23)
PWR_LED_YELLOW_C: length 161.1
  TOP w0.254: v1(27.66,20.17) 28.74,20.17 29.32,20.75 PWRCN1.9 ; v3(116.21,11.96) 116.23,11.98 127.54,11.98 128.12,11.4 132.07,11.4 133.1,10.36 133.1,8.48 134.13,7.45 134.13,6.91 R505.1 134.22,6.88 134.67,6.43 R506.2
  L4 w0.254: v3(116.21,11.96) 116.21,11.61 113.51,8.9 100.27,8.9 98.81,10.37 98.81,15.77 95.95,18.64 89.63,18.64 85.53,22.73 68.72,22.73 67.52,23.93 62.09,23.93 57.61,19.46 48.27,19.46 47.23,18.41 47.23,14.22 47.73,13.72 47.73,8.56 47.73,7.99 46.7,6.96 46.7,6.96 43.96,4.22 30.08,4.22 27.93,6.37 25.93,6.37 24.66,7.64 24.66,10.17 24.06,10.76 24.06,14.25 25.02,15.21 25.02,16.37 25.28,16.63 25.28,16.63 25.61,16.96 25.61,19.28 26.44,20.1 27.59,20.1 v1(27.66,20.17)
  BOTTOM w0.254: v1(27.66,20.17) 27.81,20.02 Q74.D ; v3(116.21,11.96) 115.81,11.56 v2(115.81,11.27)
PWR_LED_YELLOW_C2: length 3.2
  TOP w0.254: R506.1 136.92,6.27 v4(137.9,6.27) 137.9,6.65 136.84,7.72 R503.2
PWR_SCLK_A: length 2.3
  BOTTOM w0.203: PU13.38 64.21,211.66
  BOTTOM w0.254: 64.21,211.66 64.4,211.48 64.9,211.48 64.91,211.47 v2(65.01,211.47) 65.01,211.46 65.37,211.09 PR192.1
PWR_SDIO: length 3
  BOTTOM w0.203: v2(65.74,212.57) 65.63,212.46 PU13.36
  BOTTOM w0.254: PR191.1 65.85,212.57 v2(65.74,212.57)
PWR_V1P8A:
  vias: v4(25.89,196.32)
PWR_V1P8A_EN: length 13.6
  TOP w0.102: PR36.2 29.75,189.66 PU1.8 28.85,188.45 28.48,188.09 PR38.1 29.54,187.26 PR207.2 29.6,187.2 30.27,187.2 v1(30.59,186.87) 30.75,187.03 PR243.2
  BOTTOM w0.102: PR206.2 R577.1 PC146.1 PC147.1 30.01,186.87 v1(30.59,186.87) 30.73,186.74 31.1,186.74 31.28,186.56 31.29,186.56 31.3,186.56 31.46,186.56 v2(31.63,186.39)
PWR_V1P8A_FB: length 6.5
  TOP w0.254: PU1.2 27.58,197.05 PR35.2 PC22.2 27.59,198.06 PR34.1 30.47,198.06 v4(30.56,197.97)
PWR_V1P8A_PG: length 5.3
  TOP w0.102: PU1.7 27.58,188.28 v1(27.46,188.16) 27.46,187.99 27.47,187.99 PR37.2
  BOTTOM w0.102: R580.2 PC148.1 27.47,187.99 27.46,187.99 v1(27.46,188.16) 27.46,188.23 v2(26.97,188.72)
PWR_V1P24A_PG_L: length 2.9
  BOTTOM w0.254: R516.2 81.31,225.52 81.31,224.01 v2(81.31,224) 81.31,224 Q47.3
PWR_VCCGI_COMP: length 6.8
  TOP w0.254: v1(55.65,211.64) 55.39,211.64 PC11.2 53.63,210.64 PC10.2
  BOTTOM w0.203: 56.7,212.46 PU13.4
  BOTTOM w0.254: 56.7,212.46 55.88,211.64 v1(55.65,211.64) 55.39,211.64 54.77,211.02 v2(54.77,210.97)
PWR_VCCGI_COMPA: length 2.4
  TOP w0.254: PR19.2 51.72,209.39 51.47,209.64 v4(51.47,209.75) 52.07,210.35 PC10.1
PWR_VCCGI_CSCOMP: length 21.6
  TOP w0.254: PR33.2 v4(53.06,200.07) 53.06,205.15 51.49,206.71 51.49,207.36 50.73,208.12 50.73,210.44 51.66,211.36 PR14.2 52.38,211.37 PR12.2 52.5,212.52 PC7.1 54.34,212.52 PC8.1 54.6,212.51 v1(55.19,213.1)
  BOTTOM w0.203: v1(55.19,213.1) 55.62,213.1 55.79,213.26 PU13.6
PWR_VCCGI_CSN: length 28.4
  TOP w0.254: v3(51.21,192.83) PG2.1
  L4 w0.254: v1(50.22,215.39) 50.2,215.39 49.94,215.14 49.94,208.03 52.48,205.49 52.48,202.41 51.4,201.33 51.4,195.26 51.09,194.94 51.09,192.95 v3(51.21,192.83)
  BOTTOM w0.254: PR188.2 v1(50.22,215.39) 50.21,215.39 v2(49.69,214.87)
PWR_VCCGI_CSP: length 30.9
  TOP w0.254: PG1.1 v3(50.45,192.85) ; PR9.1 51.54,215.07 v1(50.2,216.41)
  L4 w0.254: v1(50.2,216.41) 49.44,215.65 49.44,207.82 51.98,205.28 51.98,202.62 50.9,201.54 50.9,195.47 50.58,195.16 50.58,192.98 v3(50.45,192.85)
  BOTTOM w0.254: PR187.1 v1(50.2,216.41) 50.19,216.41 v2(49.67,216.93)
PWR_VCCGI_CSP1: length 6.8
  BOTTOM w0.203: 56.35,215.26 56.8,215.26 57.2,214.86 PU13.10
  BOTTOM w0.254: PR187.2 53,216.41 PC130.2 53.03,216.41 v2(54.19,216.41) 55.21,216.41 56.35,215.26
PWR_VCCGI_CSREF: length 6.8
  BOTTOM w0.203: 56.48,214.06 PU13.8
  BOTTOM w0.254: PR188.1 52.9,215.39 PC130.1 53.32,215.2 PC132.1 55.34,215.2 v2(55.81,214.74) 56.48,214.06
PWR_VCCGI_CSSUM: length 8.6
  TOP w0.254: v4(56.37,213.13) 56.37,213.15 v1(55.74,213.78) 54.72,213.78 PC8.2 53.37,213.4 PC7.2 52.39,213.41 PR11.1 52.36,214.22 PR9.2
  BOTTOM w0.203: PU13.7 55.86,213.66 v1(55.74,213.78)
PWR_VCCGI_DIFFOUT: length 7.2
  TOP w0.254: v1(56.38,210.2) 56.38,210 PR18.1 55.06,208.68 PR22.1 53.72,208.68 PR23.1
  BOTTOM w0.203: PU13.2 57.46,211.66 57.18,211.39
  BOTTOM w0.254: v2(55.73,209.81) 55.99,209.81 v1(56.38,210.2) 56.44,210.2 57.18,210.94 57.18,211.39
PWR_VCCGI_EN: length 6.1
  BOTTOM w0.203: 63.09,210.25 62.95,210.39 PU13.41
  BOTTOM w0.254: 63.09,210.25 63.32,210.02 64.49,210.02 65.18,209.32 65.18,207.66 PG10.1 v2(66.48,207.38)
PWR_VCCGI_EN_PH: length 257.8
  TOP w0.203: 125.38,224.51 126.41,223.48 132.6,223.48 136.86,219.22 136.86,218.26 139.35,215.77 139.35,198.09 141.73,195.71 v1(142.96,195.71)
  TOP w0.254: Q4501.D 140.05,83.46 v1(140.83,83.46) ; 125.38,224.51 124.11,225.78 115.6,225.78 114.31,224.49 v1(114.31,224.03)
  L3 w0.203: v1(140.83,83.46) 140.55,83.74 140.55,86.26 145.88,91.59 145.88,103.58 146.21,103.91 146.21,104.9 145.5,105.61 145.5,109.17 145.68,109.35 145.68,111.94 145.5,112.12 145.5,116.51 144.79,117.22 144.79,138.35 144.08,139.06 144.08,148.31 144.53,148.77 144.53,167.35 145.79,168.61 145.79,174.08 146.07,174.36 146.07,179.65 147.05,180.63 147.05,191.62 v1(142.96,195.71)
  L3 w0.254: v1(113.06,206.45) 112.76,206.76 111.44,206.76 111.06,206.38 108.29,206.38 107.54,207.12 100.4,207.12 99.04,205.76 99.04,205.01 98.52,204.49 97.7,204.49 97.01,205.18 93.48,205.18 92.09,203.78 86.95,203.78 79.54,196.37 73.52,196.37 71.33,198.56 71.33,200.28 68.65,202.96 68.65,207.34 v1(68.71,207.4)
  BOTTOM w0.254: PG10.2 66.22,206.02 v2(66.71,206.02) 66.94,206.02 67.42,206.5 R558.2 ; v1(68.71,207.4) 68.7,207.4 68.04,206.74 R558.2 ; v1(113.06,206.45) 113.06,219.38 114.16,220.47 114.16,223.44 114.21,223.49 114.21,223.93 v1(114.31,224.03) ; R558.2 PC141.1 R566.2 67.73,204.16 R568.2
PWR_VCCGI_FB: length 7.8
  TOP w0.254: PC14.2 52.4,208.45 PR19.1 53.71,209.75 PC11.1 54.98,209.75 55.21,209.99 PR18.2 55.47,210.67 v1(55.6,210.79)
  BOTTOM w0.203: v2(56.38,211.06) 56.68,211.36 56.68,211.57 57.17,212.06 PU13.3
  BOTTOM w0.254: v2(56.38,211.06) 56.12,210.79 v1(55.6,210.79)
PWR_VCCGI_FBA: length 2.4
  TOP w0.254: PR23.2 53.4,206.93 v4(52.92,206.45) 52.4,206.96 PC14.1
PWR_VCCGI_ICCMAX: length 6
  BOTTOM w0.203: PU13.23 62.15,216.93 62.34,217.12 62.82,217.12
  BOTTOM w0.254: PR186.1 66.21,218.08 v2(65.81,218.48) 65.37,218.48 64.01,217.12 62.82,217.12
PWR_VCCGI_ILIM: length 5.7
  TOP w0.254: PR14.1 53.5,211.6 v1(54.16,211.6)
  BOTTOM w0.203: 56.38,212.86 PU13.5
  BOTTOM w0.254: 56.38,212.86 56.15,212.86 55.76,212.47 v2(54.49,212.47) 54.44,212.47 54.16,212.19 v1(54.16,211.6)
PWR_VCCGI_IOUT: length 6.6
  TOP w0.254: PR26.2 55.34,205.82 PC16.2 56.37,207.85 v4(56.37,208.18) v1(56.37,209.1)
  BOTTOM w0.203: PU13.1 58.04,210.77 v1(56.37,209.1)
PWR_VCCGI_NTC: length 14.4
  TOP w0.254: PR4.1 52.01,217.01 PR3.1 50.89,217.12 50.06,217.12 49.66,216.73 49.66,213.18 v4(49.82,213.03) 49.82,211.44 49.74,211.37 49.74,210.89 49.72,210.86 49.72,207.7 49.74,207.67 49.74,207.49 50.14,207.09 50.33,207.09 50.48,206.94 50.48,206.21 PR25.2
PWR_VCCGI_PVCC: length 1.2
  BOTTOM w0.203: v1(60.26,217.71) 60.15,217.6 PU13.18
  vias: v4(61.3,217.58)
PWR_VCCGI_TSENSE: length 6.1
  TOP w0.254: PR4.2 53.89,217.04 PC4.1 54.72,217.04 v4(54.97,217.3) 55.1,217.3 v1(55.67,216.72)
  BOTTOM w0.203: 56.8,215.77 57.31,215.26 PU13.11
  BOTTOM w0.254: 56.8,215.77 56.67,215.77 55.72,216.72 v1(55.67,216.72)
PWR_VCCGI_VCC: length 1.9
  TOP w0.254: v1(57.73,216.63) 57.73,217.16 v4(58.2,217.63)
  BOTTOM w0.203: v1(57.73,216.63) 58.04,216.32 PU13.13
PWR_VCCGI_VR_RDY: length 4.9
  BOTTOM w0.203: 62.64,210.06 62.55,210.15 PU13.42
  BOTTOM w0.254: PG11.1 64.45,208.23 v2(64.6,208.38) 64.6,209.12 64.21,209.51 63.19,209.51 62.64,210.06
PWR_VCCGI_VR_RDY1: length 57.9
  TOP w0.254: PR207.1 30.26,185.65 30.49,185.65 31.3,184.84 32.4,184.84 32.84,184.4 v1(33,184.4)
  L4 w0.254: v1(33,184.4) 48.29,184.4 48.93,185.04 48.93,186.56 49.94,187.58 57.31,187.58 58.07,188.34 58.07,200.15 59.09,201.17 59.6,201.17 60.33,201.9 60.33,203.17 62.01,204.85 v1(64.55,204.85)
  BOTTOM w0.254: PG11.2 64.45,206.38 v2(65.53,205.3) 66.01,204.81 PR203.2 65.24,204.16 v1(64.55,204.85)
PWR_VCCGI_VRMP: length 8.1
  TOP w0.254: v1(56.55,216.81) 56.55,217.78 v4(56.22,218.11) 56.17,218.15 53.9,218.15 PC3.1 52.67,218.15 PR1.2
  BOTTOM w0.203: PU13.12 57.67,215.66 56.94,216.4
  BOTTOM w0.254: 56.94,216.4 56.55,216.79 v1(56.55,216.81)
PWR_VCCGI_VSN: length 6.9
  BOTTOM w0.203: 58.21,210.19 58.55,210.52 PU13.52
  BOTTOM w0.254: PC140.2 PR197.2 55.21,207.82 55.53,208.13 v2(55.53,208.13) 55.91,208.51 56.54,208.51 58.21,210.19
PWR_VCCGI_VSNA: length 3.9
  BOTTOM w0.254: PG16.2 54.28,204.68 PC142.2 PC140.1 PR197.1 v2(54.33,207.63)
PWR_VCCGI_VSP: length 8.6
  BOTTOM w0.203: PU13.51 58.95,210.16 58.46,209.67
  BOTTOM w0.254: PG15.2 55.29,204.65 PC142.1 55.41,204.72 55.86,205.18 55.86,206.92 v2(57.57,208.63) 57.57,208.78 58.46,209.67
PWR_VCCGT_ILIM_NTC: length 15.9
  TOP w0.254: PR33.1 v4(52.17,204.49) 52.17,205.28 51,206.45 50.99,206.5 50.99,206.5 50.99,207.15 50.22,207.91 50.22,210.65 50.25,210.67 50.25,211.16 PR12.1 51.49,213.42 PR11.2
PWR_VCORE_VNN_D: length 2.7
  BOTTOM w0.305: Q46.6 83.17,219.27 R527.2
  BOTTOM w0.508: R527.2 v2(82.02,219.25)
PWR_VDDQ_BOOT: length 1.5
  TOP w0.203: PU5.18 151.7,136.58 v4(151.43,136.84)
PWR_VDDQ_BOOT_A: length 0.9
  BOTTOM w0.254: v2(153.58,140.14) v1(154.5,140.14)
PWR_VDDQ_CS: length 5.3
  TOP w0.102: v1(154.41,134.44) 153.86,133.88 PU5.13
  BOTTOM w0.102: v2(157.23,136.4) 156.62,136.4 155.48,135.25 155.48,134.81 PRB1.1 154.72,134.75 v1(154.41,134.44)
PWR_VDDQ_EN: length 4.9
  TOP w0.102: 152.51,129.62 153.17,130.27 v4(153.17,130.48) 152.73,130.91 152.42,130.91 151.7,131.64 PU5.8 ; 152.51,129.62 PC75.1 ; 152.51,129.62 153.44,129.62 PR87.2
PWR_VDDQ_FB: length 6.9
  TOP w0.203: PU5.6 149.92,132.33
  TOP w0.254: PR85.1 145.43,131.62 PC74.2 PR83.2 147.49,131.71 v4(147.71,131.93) 148.04,131.93 148.44,132.33 149.92,132.33
PWR_VDDQ_HG: length 27.7
  TOP w0.203: v5(152.59,136.88) 152.1,136.39 PU5.17
  TOP w0.762: PR210.2 145.22,155.19 v5(145.63,154.79)
  L4 w0.762: v5(152.59,136.88) 152.59,137.06 151.39,138.25 151.39,152.06 149.76,153.7 146.72,153.7 v5(145.63,154.79)
  BOTTOM w0.762: v5(145.63,154.79) 146.03,154.38 v2(146.03,153.8)
PWR_VDDQ_LG: length 17.1
  TOP w0.203: PU5.15 153.59,134.68 154.08,135.18 v5(154.08,135.51)
  BOTTOM w0.762: v5(154.08,135.51) 156.9,138.33 v2(156.9,148.69) 156.9,149.22 v5(156.29,149.83)
PWR_VDDQ_PH: length 24.1
  TOP w0.203: PU5.16 153.09,136.02
  TOP w0.508: PC68.2 153.47,137.64 v5(153.93,137.19) 153.93,136.87 153.09,136.02
  L4 w0.762: v5(150.97,156.17) 150.97,154.98 152.94,153.01 152.94,138.86 153.93,137.87 v5(153.93,137.19)
  vias: v2(154.36,157.55) v2(155.09,152.63) v5(149.39,157.53) v5(149.36,156.21) v5(150.99,157.56) v5(153.4,158.01) v5(153.4,156.97) v5(153.53,155.78) v5(154.72,155.73) v5(155.96,155.73)
PWR_VDDQ_TON: length 3.2
  TOP w0.102: v1(152.61,131.37) 152.1,131.88 PU5.9
  BOTTOM w0.102: v1(152.61,131.37) 152.38,131.14 151.88,131.14 v2(151.8,131.21) 151.8,131.89 PR213.2
PWR_VDDQ_VDD: length 5.2
  TOP w0.203: PU5.12 154,133.48 154.31,133.79 154.53,133.79
  TOP w0.381: PC72.1 154.64,133.79 154.53,133.79
  TOP w0.508: PC72.1 156.22,134.58 PR81.1 157.25,134.18 v4(157.67,134.59)
PWR_VDDQ_VDDQ: length 6.5
  TOP w0.203: PU5.5 149.6,133.08 149.31,132.79 148.65,132.79 147.88,133.56 v4(147.84,133.56)
  TOP w0.305: PC74.1 PR83.1
  TOP w0.508: PR83.1 146.4,132.51 PR82.1 147.76,133.63 v4(147.84,133.56)
PWR_VDDQ_VID: length 5.8
  TOP w0.203: PU5.11 153.25,132.69 153.5,132.44
  TOP w0.508: 153.5,132.44 154.85,132.44 155.08,132.67 PC73.1 155.44,132.7 155.03,133.12 v1(154.57,133.12)
  BOTTOM w0.254: PR212.1 155.46,133.07 v2(155.46,132.03)
  BOTTOM w0.508: PR212.1 154.64,133.09 154.62,133.12 v1(154.57,133.12)
PWR_VDDQ_VLDOIN: length 1
  TOP w0.203: 151.01,136.32 151.3,136.04 PU5.19
  vias: v2(148.75,136.91) v5(149.89,136.78)
PWR_VDDQ_VTT: length 3.5
  TOP w0.203: 148.52,135 148.93,135 149.65,134.28 PU5.2 ; PU5.20 150.78,135.43 150.22,135.99 149.54,135.99
  vias: v4(148.68,135.89)
PWR_VDDQ_VTTREF: length 3.7
  TOP w0.203: v1(149.05,133.3) 149.24,133.48 PU5.4
  BOTTOM w0.254: v2(149.44,132.34) 149.44,132.55 149.99,133.11 PC172.1 149.35,133.57 149.08,133.3 v1(149.05,133.3)
PWR_VGA_CORE_BOOT1: length 4.1
  TOP w0.305: U11.1 128.79,84.08 129.01,84.3
  TOP w0.508: PR108.1 131.17,86.46 130.51,85.8 v4(130.5,85.8) 130.5,85.79 129.01,84.3
PWR_VGA_CORE_BOOT1_1: length 3
  TOP w0.508: PR108.2 134.27,86.46 134.35,86.38 134.75,86.38 v4(134.95,86.18) 134.91,86.15 134.91,85.76 PC91.1
PWR_VGA_CORE_COMP: length 4.8
  TOP w0.254: v4(123.5,78.13) 123.29,78.35 PR124.2 PC95.1 123.36,80.34 124.45,80.34 124.7,80.59 124.86,80.59 125.06,80.79 U11.12
PWR_VGA_CORE_COMP_1: length 2.5
  TOP w0.254: v4(122,78.11) 121.32,78.79 PC97.2 122.31,79.16 PR124.1
PWR_VGA_CORE_EN: length 32.9
  TOP w0.102: R307.2 105.1,84.42 106.33,85.65 108.21,85.65 109.41,84.45 v1(109.89,84.45) ; U11.3 127.79,85.25 127.09,85.95 126.8,85.95 v1(126.75,85.9) 126.67,85.9 126.35,86.23 PC89.1 126.47,86.73 PR106.2 127.55,86.73 PR105.2
  L3 w0.127: v1(115.57,82.13) 115.63,82.13 115.67,82.17 115.98,82.17 118.02,84.2 120.81,84.2 122.51,85.9 v1(126.75,85.9)
  L4 w0.127: v1(109.89,84.45) 110.37,83.97 113.34,83.97 115.15,82.17 115.54,82.17 v1(115.57,82.13)
  BOTTOM w0.102: v2(125.97,85.86) 126.71,85.86 v1(126.75,85.9)
PWR_VGA_CORE_FB: length 10
  TOP w0.254: v1(121.06,77.22) 120.37,77.91 PR125.2 PR122.1 120.43,80.05 PC97.1 122.18,80.05 PC95.2 122.4,80.38 122.92,80.9 124.47,80.9 124.55,80.98 124.7,80.98 125.02,81.29 U11.11
  BOTTOM w0.254: v1(121.06,77.22) v2(121.06,78.11)
PWR_VGA_CORE_FBRTN: length 3.5
  TOP w0.254: U11.10 124.98,81.79 124.7,81.51 v1(124.16,81.51) PR118.2
  BOTTOM w0.254: v2(124.87,82.22) v1(124.16,81.51)
PWR_VGA_CORE_FS: length 2.4
  TOP w0.254: PR116.1 123.99,82.52 v4(124.21,82.3) 124.22,82.29 U11.9
PWR_VGA_CORE_LGATE1: length 30
  TOP w0.305: U11.23 129.94,82.79 130.44,83.29 v5(131.3,83.29)
  TOP w0.559: PR114.1 132.48,83.29 132.18,83.29 132.13,83.34 131.48,83.34 131.43,83.29 v5(131.3,83.29)
  TOP w0.635: v5(134.22,105.44) 134.22,104.42 PU7.4
  L4 w1.016: v5(131.3,83.29) 131.39,83.29 133,84.9 133,98.17 v5(134.27,99.44) 134.22,99.49 v5(134.22,105.44)
  BOTTOM w0.762: PU16.4 134.36,99.53 v5(134.27,99.44) ; v2(132.13,83.29) v5(131.3,83.29)
PWR_VGA_CORE_PGOOD: length 5.7
  TOP w0.254: PR121.2 132.77,80.35 PR123.1 131.16,80.35 v4(130.75,79.95) 130.34,79.53 128.41,79.53 128.39,79.55 128.11,79.55 127.79,79.87 U11.16
PWR_VGA_CORE_PHASE1: length 21.3
  TOP w0.305: U11.24 130.97,84.82 130.97,84.84
  TOP w0.508: PC91.2 132.47,84.84 130.97,84.84 v5(130.97,84.91)
  L4 w1.016: v5(130.97,84.91) 131.22,85.17 131.22,98 130.04,99.19 v5(127.41,99.19)
  vias: v2(123.65,96.62) v2(126.22,92.12) v5(122.99,103.23) v5(123.11,104.56) v5(123.06,102) v5(123.1,100.77) v5(123.1,99.62) v5(123.41,93.35) v5(123.41,91.83) v5(123.46,94.49) v5(124.32,104.52) v5(124.28,103.2) v5(124.26,101.97) v5(124.28,100.85) v5(124.3,99.57) v5(125.13,94.45) v5(125.14,93.15) v5(125.13,91.97) v5(125.68,99.52) v5(125.83,104.52) v5(125.76,103.17) v5(125.77,101.93) v5(125.76,100.74) v5(126.63,93.22) v5(126.65,94.47) v5(127.11,104.46) v5(127.07,103.21) v5(127.08,101.84) v5(127.12,100.51)
PWR_VGA_CORE_PSI: length 6.9
  TOP w0.254: U11.4 127.29,84.9 127.04,85.15 v4(127.04,85.16) 126.74,85.16 125.46,86.44 PC88.1 125.33,86.73 124.89,86.73 124.75,86.87 124.66,86.87 PR107.1 R295.2 124.48,89.1 PR100.2
PWR_VGA_CORE_PVCC: length 6.5
  TOP w0.254: PR120.2 PC94.1 132.29,82.55 v4(131.76,82.55) 131.45,82.55 130.69,81.79 U11.21
PWR_VGA_CORE_REFIN: length 5.9
  TOP w0.254: PR112.2 120.81,84.52 PC90.1 122.33,84.52 PR110.1 122.55,84.62 123.07,84.1 123.97,84.1 v4(124.41,83.65) 124.45,83.65 124.82,83.29 U11.7
PWR_VGA_CORE_SENCE+: length 36.2
  TOP w0.152: 95.77,95.91 95.46,95.61 95.46,95.43 93.84,93.8 93.3,93.8 GPU1.F2
  TOP w0.254: PR119.1 116.7,84.82 116.7,86.82 v1(117.2,87.33) 116.52,88.01 PR104.2 ; 95.77,95.91 96.48,96.62 98.18,96.62 v4(98.38,96.82) 98.53,96.67 99.13,96.67 100.31,95.49 100.31,93.27 101.1,92.48 v1(101.1,92.41)
  L4 w0.254: v1(101.1,92.41) 101.1,92.03 101.46,91.67 103.62,91.67 103.84,91.45 103.85,91.45 106.93,88.37 113.69,88.37 114.4,89.08 115.81,89.08 116.7,88.19 116.7,87.83 v1(117.2,87.33)
PWR_VGA_CORE_SENCE-: length 41.1
  TOP w0.152: 96.12,95.53 95.89,95.3 95.71,95.3 93.81,93.4 GPU1.F1
  TOP w0.254: PR118.1 122.18,81.51 122.05,81.64 121.45,81.64 121.34,81.53 PR117.1 120.68,80.96 118.71,80.96 117.2,82.47 117.2,86.23 v1(117.25,86.28) ; v1(100.36,92.05) 100.36,92.5 99.8,93.06 99.8,95.1 v4(99.35,95.55) 98.79,96.11 96.7,96.11 96.12,95.53
  L4 w0.254: v1(100.36,92.05) 101.25,91.16 103.41,91.16 103.63,90.94 103.64,90.94 106.72,87.86 113.9,87.86 114.61,88.57 115.6,88.57 116.19,87.98 116.19,87.35 v1(117.25,86.28)
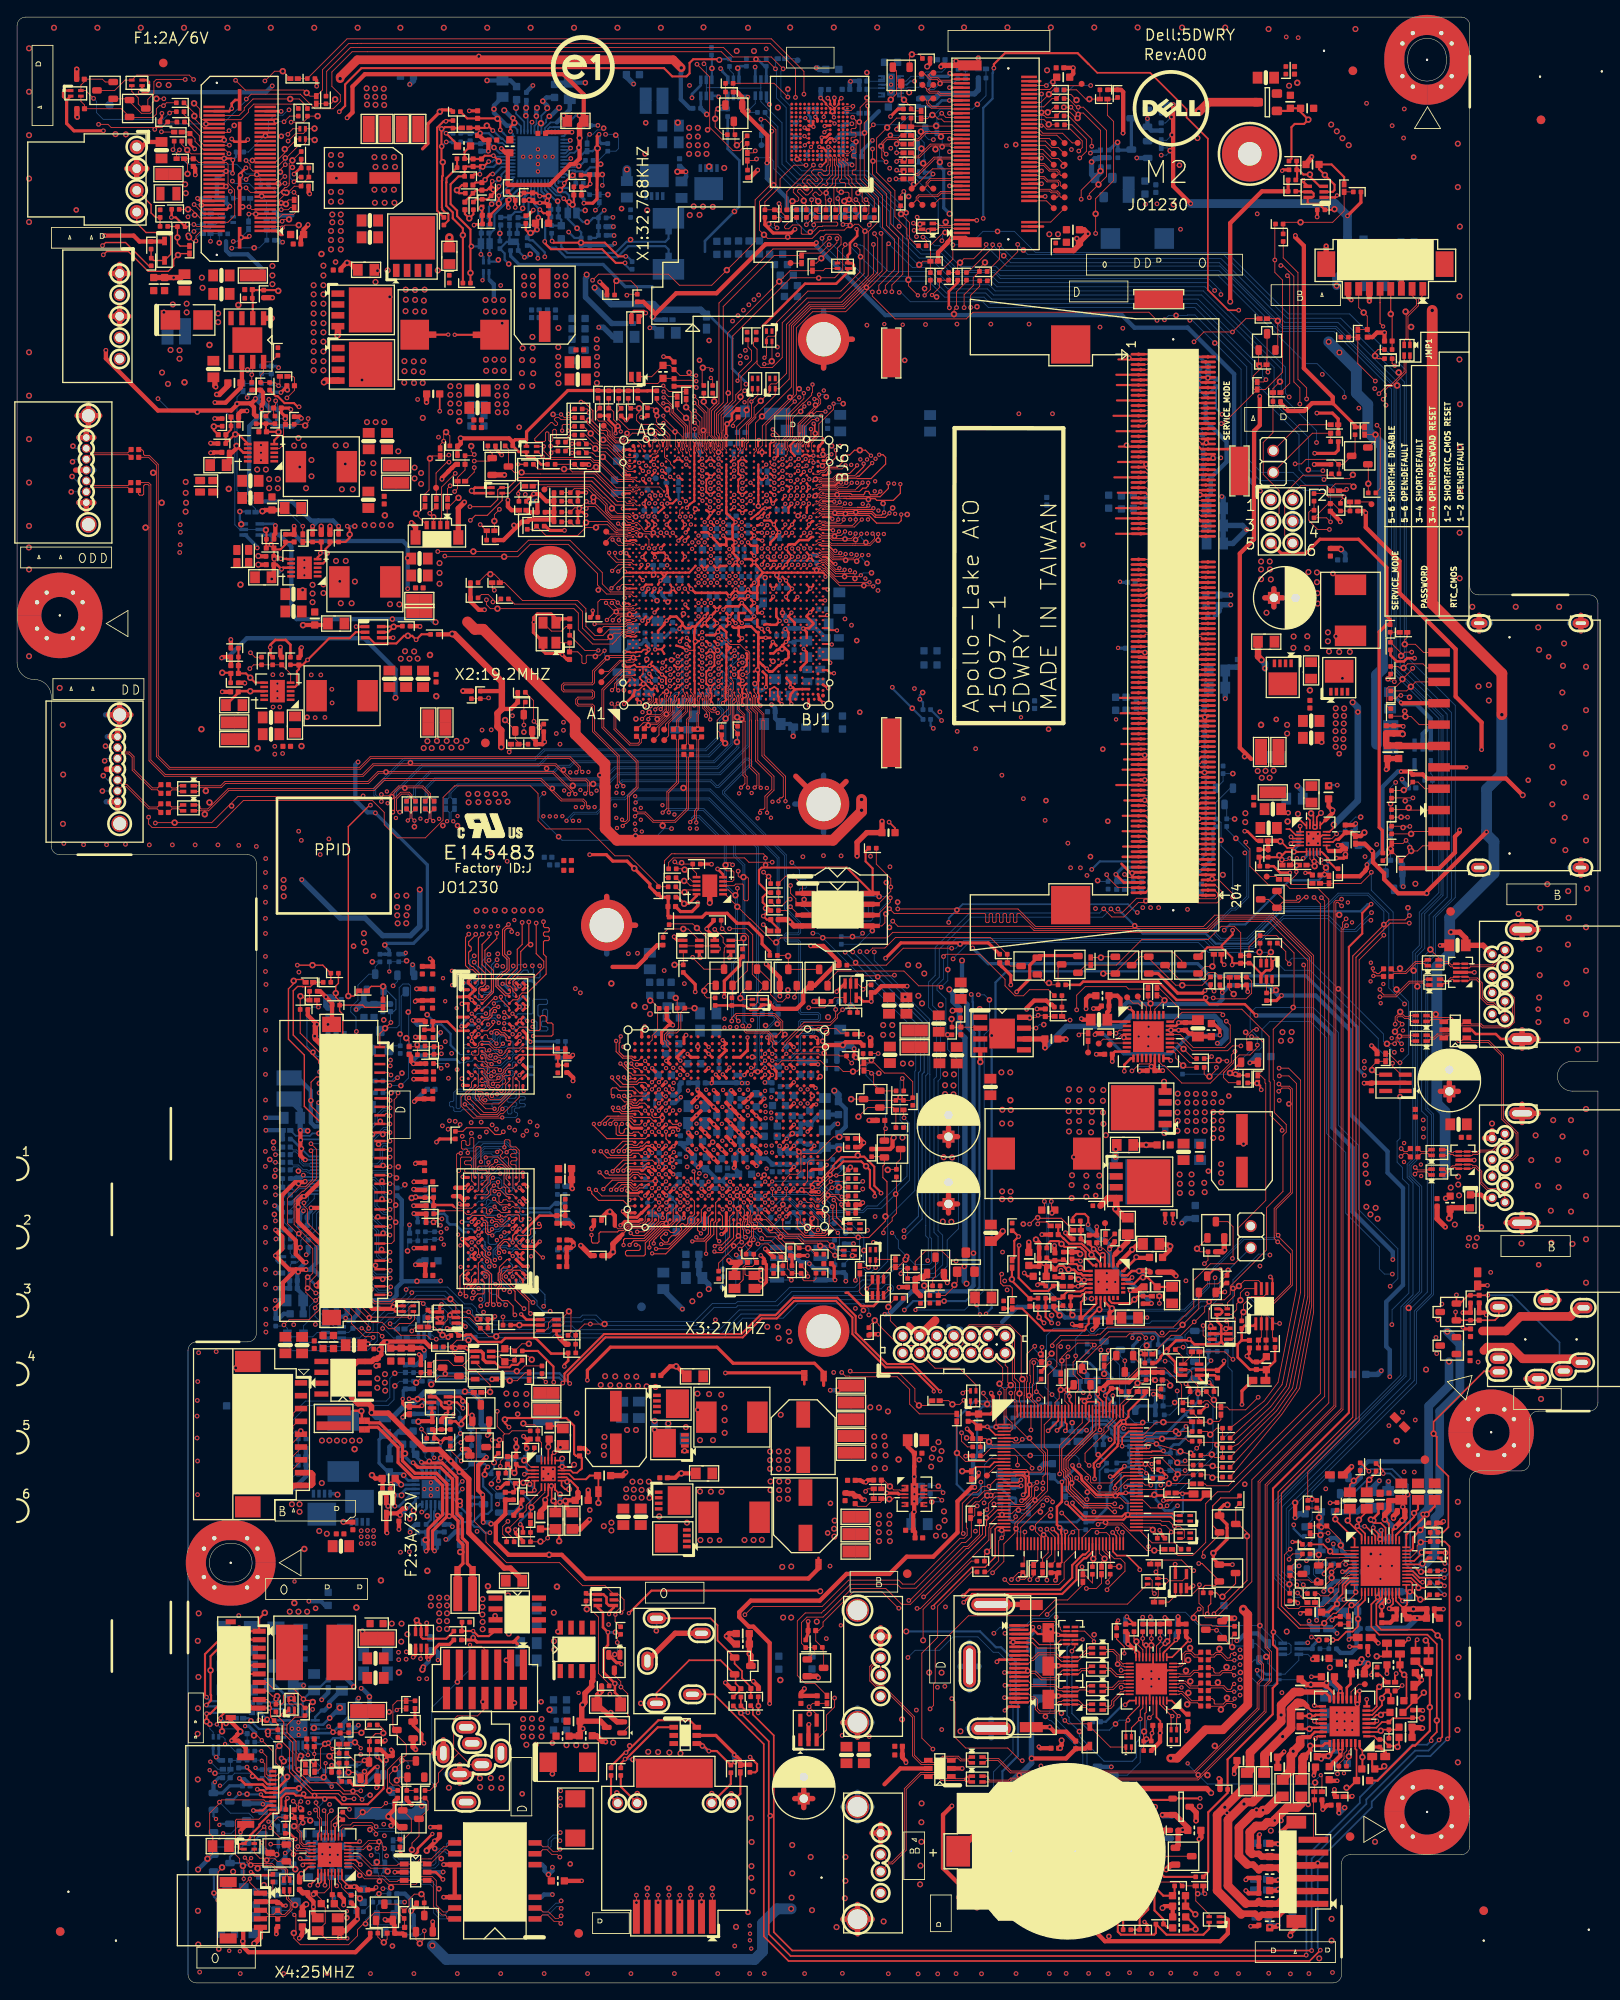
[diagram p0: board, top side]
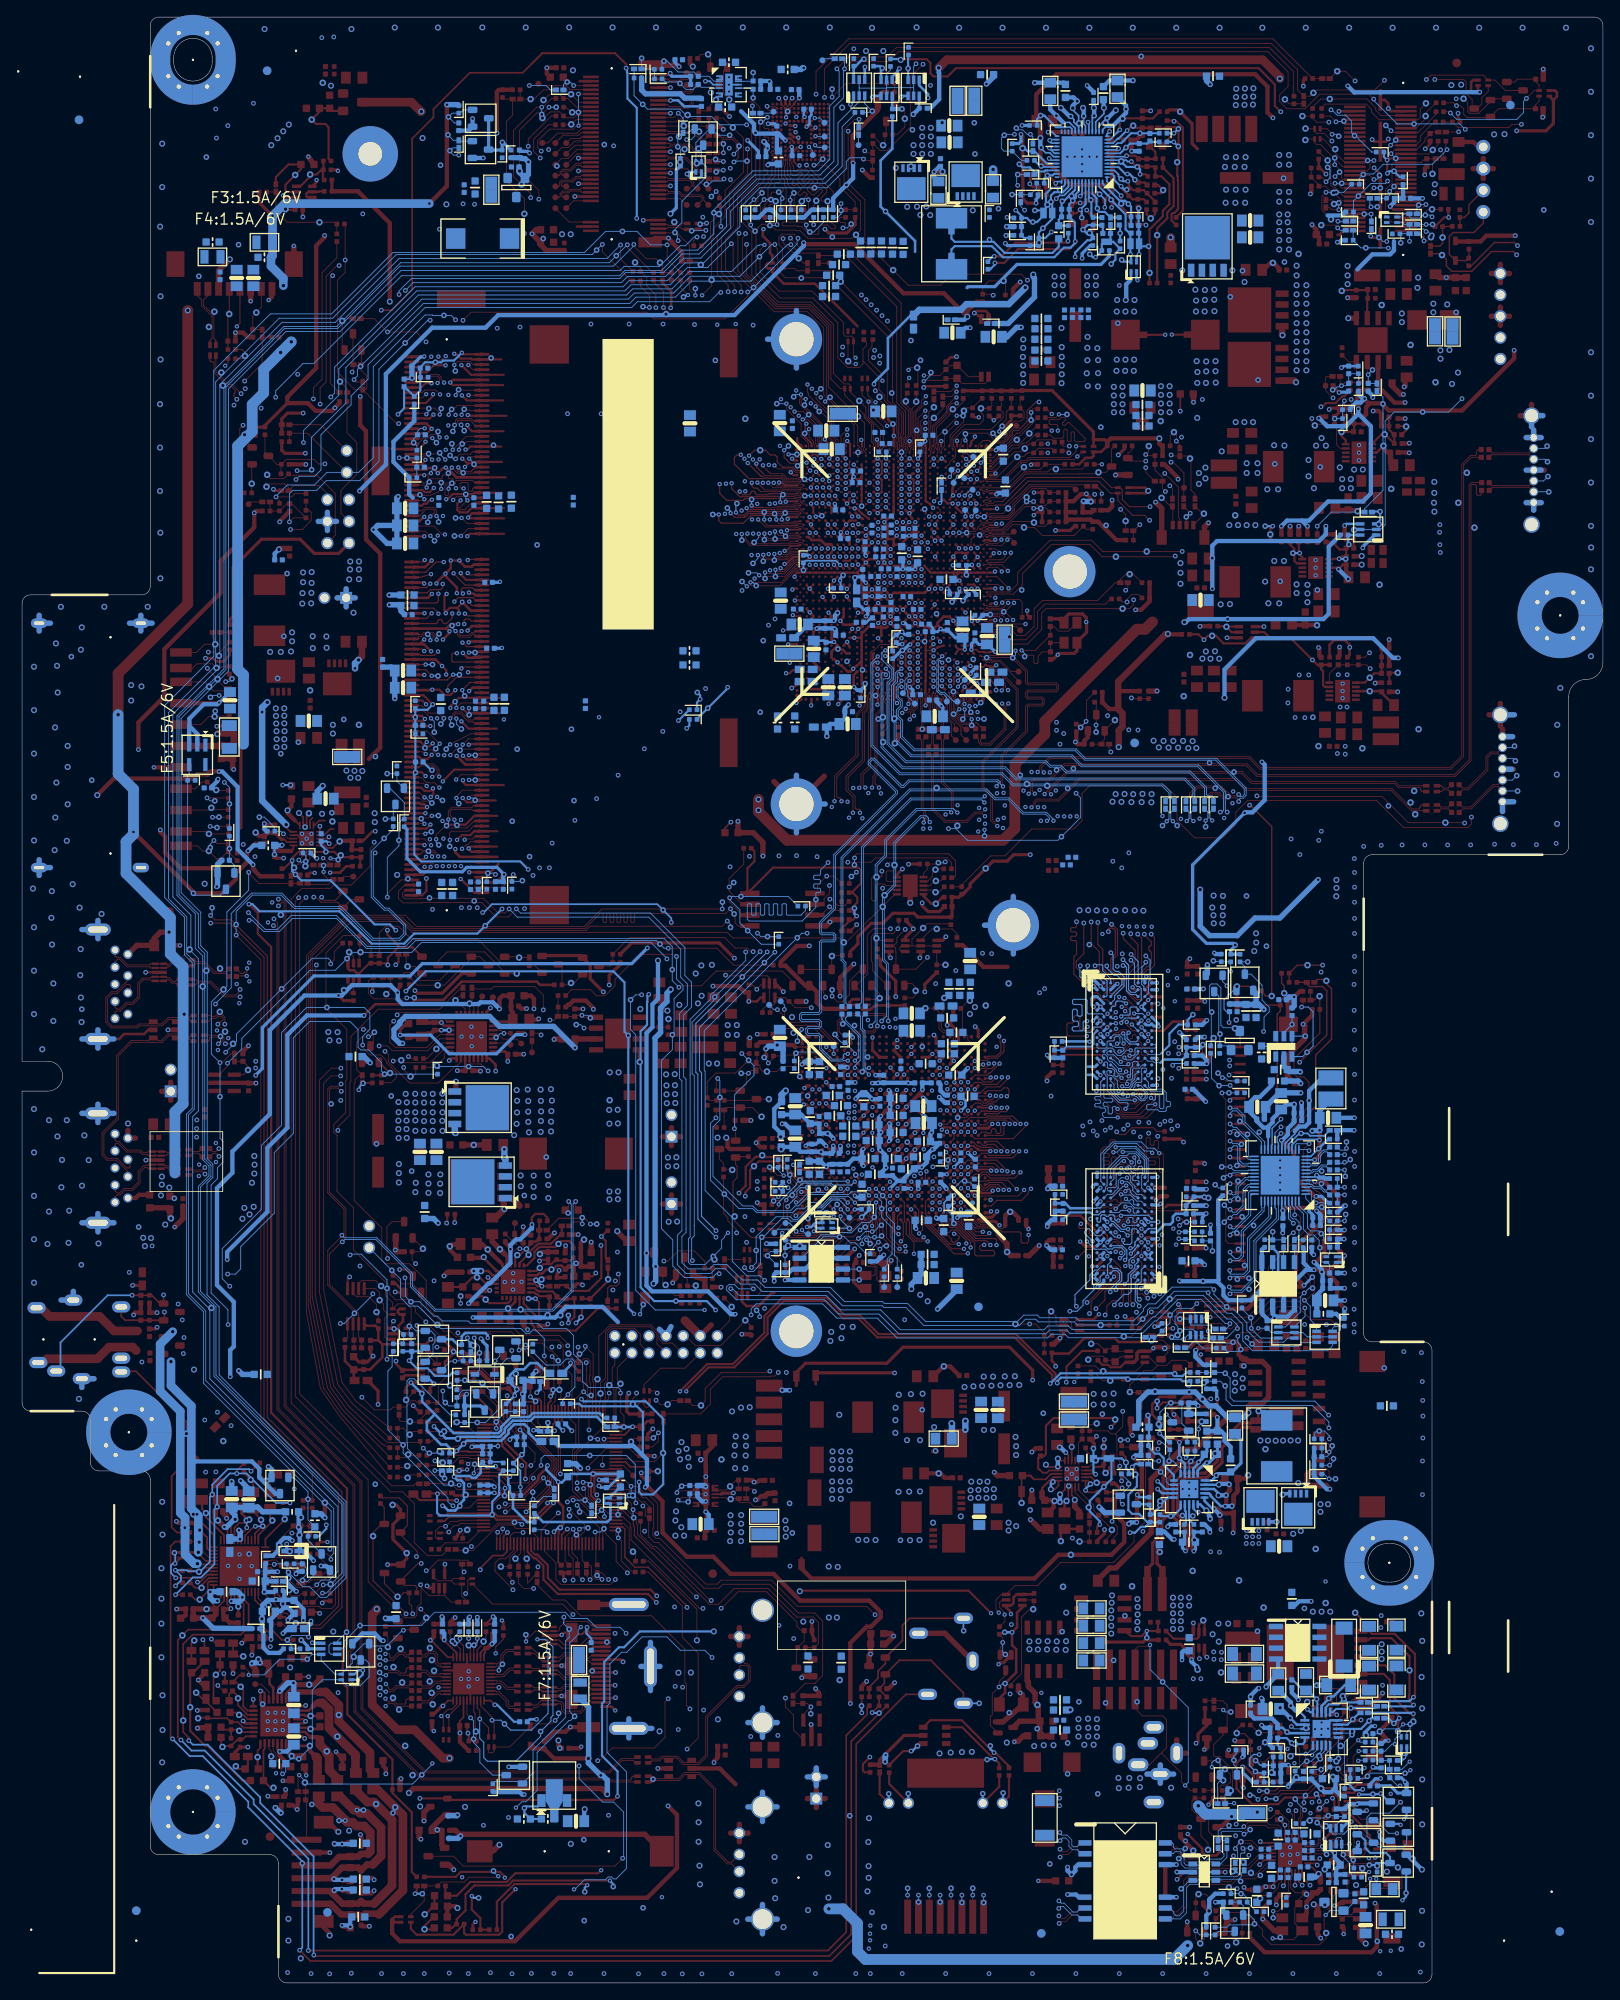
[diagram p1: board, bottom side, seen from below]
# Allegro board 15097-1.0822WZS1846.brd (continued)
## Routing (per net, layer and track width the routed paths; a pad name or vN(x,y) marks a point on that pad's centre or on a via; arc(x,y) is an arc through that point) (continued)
PWR_VGA_CORE_SENSE+_1: length 5.5
  TOP w0.254: PR119.2 116.42,83.65 v4(116.42,82.32) 116.42,82.16 PC96.2 119.41,80.05 PR122.2
PWR_VGA_CORE_SNB: length 2.8
  TOP w0.635: PR96.1 v4(132.14,98.04) PC85.1
PWR_VGA_CORE_TALERT#: length 15.2
  TOP w0.254: U11.14 126.79,78.93 v4(126.65,78.79) 126.47,78.79 125.41,77.72 125.41,77.11 125.05,76.76 125.05,76.48 124.9,76.33 120.2,76.33 117.62,78.91 PR127.2 PR128.1
PWR_VGA_CORE_TSNS: length 33.9
  TOP w0.254: v1(135.31,88.9) 135.24,88.98 PR99.1 ; U11.13 126.29,79.47 124.61,77.79 PC98.1 124.49,79.63 v1(124.92,80.06) ; PR115.2 118.24,82.68 v1(117.86,83.06)
  L4 w0.254: v1(117.86,83.06) 121.17,83.06 124.16,80.06 v1(124.92,80.06) 131.41,80.06 135.31,83.96 v1(135.31,88.9)
  BOTTOM w0.254: v2(125.74,80.06) v1(124.92,80.06)
PWR_VGA_CORE_UGATE1: length 4.4
  TOP w0.305: U11.2 128.29,85.05 128.51,85.27
  TOP w0.635: 128.51,85.27 v4(129.08,85.84) 129.98,86.74 PR103.1
PWR_VGA_CORE_UGATE1_R: length 13.4
  TOP w0.762: PR98.1 127.67,91.82 PU8.4 128.63,90.63 v5(128.56,90.55) 129.57,89.53 PR103.2
  L4 w1.016: v5(128.56,96.65) v5(128.56,90.55)
  BOTTOM w0.762: v2(128.56,97.54) v5(128.56,96.65) 128.56,96.52 128.43,96.39 PU17.4
PWR_VGA_CORE_VCC: length 4.8
  TOP w0.305: 128.08,78.89 127.29,79.68 U11.15
  TOP w0.508: 128.08,78.89 128.1,78.92 v4(128.13,78.92) 128.13,78.72 127.85,78.44 PC99.1 128.23,77.83 PR126.2
PWR_VGA_CORE_VID: length 7.7
  TOP w0.254: U11.5 126.79,84.21 125.82,85.18 v4(125.72,85.18) 125.64,85.27 125.64,85.48 124.82,86.29 124.79,86.29 124.59,86.49 123.09,86.49 122.48,87.1 122.45,87.1 121.99,87.55 PC87.1 PR102.1
PWR_VGA_CORE_VIDBUF: length 7.9
  TOP w0.254: U11.6 125.92,83.95 125.09,84.78 125.04,84.82 125.04,85.54 124.67,85.91 124.63,85.91 124.43,86.11 122.58,86.11 v4(122.22,86.46) 121.89,86.79 120.94,86.79 120.49,86.35 PR109.1
PWR_VGA_CORE_VREF: length 7.1
  TOP w0.305: PC93.1 121.86,83.92 122.41,83.92 122.87,83.46 v4(123.05,83.46) 123.08,83.44 123.69,83.44 124.14,82.99 124.51,82.99 124.71,82.79 U11.8
  TOP w0.508: PC93.1 121.38,83.5 121.06,83.82 PR113.1 120.43,83.76 PR115.1
PWR_VGA_CORE_VREF_1: length 4.6
  TOP w0.508: v4(119.24,86.97) 119.6,86.6 PR109.2 PR112.1 PR113.2 118.52,83.82 PC92.1
PWR_VGA_CORE_VREF_2: length 2.1
  TOP w0.508: PR110.2 PR111.1 124.17,85.51 v4(124.4,85.27)
PWR_VGA_VRAM_POK: length 225.8
  TOP w0.254: PC58.1 32.98,153.7 32.75,153.47 32.75,151.84 32.54,151.63 PU4.4 ; PC58.1 32.95,154.22 PR63.2 ; PC58.1 33.4,154.19 v1(33.99,154.79) 36.53,157.33 38.92,157.33 39.63,158.04 Q9.2 ; U14.96 129.81,65.33 129.72,65.42 129.28,65.42 128.87,65.01 128.87,63.11 128.78,63.02 128.78,62.8 v1(126.53,60.54)
  L3 w0.254: v1(33.99,154.79) 24.87,154.79 23.3,153.21 23.3,153.21 22.88,152.79 22.88,144.38 25.02,142.24 33.19,142.24 33.75,141.68 33.76,141.68 38.97,136.47 38.97,136.11 41.58,133.5 41.59,133.5 43.59,131.5 57.08,131.5 v1(57.35,131.23)
  L4 w0.254: v1(111.66,115.65) 111.02,115.65 109.61,117.07 107.24,117.07 106.61,116.43 105.14,116.43 104.8,116.09 102.89,116.09 100.82,118.16 90.11,118.16 88.53,119.74 83.93,119.74 83.59,119.41 78.42,119.41 74.26,123.56 74.26,125.74 70.44,129.57 66.09,129.57 64.78,130.88 57.71,130.88 v1(57.35,131.23) ; v1(103.83,78.73) 102.72,77.62 102.72,73.32 105.48,70.56 108.1,70.56 109.45,69.21 109.45,68.77 111.37,66.85 115.36,66.85 118.3,63.91 119.16,63.91 123.06,60.01 124.49,60.01 124.87,60.4 124.87,60.71 125.24,61.07 125.99,61.07 v1(126.53,60.54)
  BOTTOM w0.254: v1(103.83,78.73) 104.87,79.77 v2(108.48,79.77) 111.01,79.77 112.62,81.38 112.62,111.34 111.86,112.09 111.86,114.74 111.82,114.79 111.82,115.5 v1(111.66,115.65)
PWR_VGA_VRAM_POK_B_1: length 4.2
  TOP w0.254: R172.2 44.13,158.74 v4(44.06,158.67) ; v4(44.06,158.67) 44.04,158.69 Q9.6 ; v4(44.06,158.67) 43.43,158.04 Q9.5
PWR_VNN_BOOT: length 5.5
  BOTTOM w0.203: 63.16,217.68 62.43,217.68 61.75,217 PU13.22
  BOTTOM w0.508: 63.16,217.68 v2(63.96,218.47) 64.68,219.19 PR182.2
PWR_VNN_BOOTA: length 3.7
  BOTTOM w0.508: PC127.2 63.1,222.33 PR182.1 v2(66.49,222.33)
PWR_VNN_COMP: length 6.9
  TOP w0.254: PC18.1 62.19,205.89 PC15.1 61.6,207.05 v1(61.17,207.47)
  BOTTOM w0.203: PU13.47 60.55,208.66
  BOTTOM w0.254: v2(60.99,206.54) 60.99,207.3 v1(61.17,207.47) 60.55,208.1 60.55,208.66
PWR_VNN_COMPA: length 3
  TOP w0.254: PR24.1 59.52,205.1 59.88,204.75 v4(60.08,204.75) 60.28,204.75 60.67,205.14 PC18.2
PWR_VNN_CSN: length 36.3
  TOP w0.254: v1(71.15,201.24) 70.06,201.24 68.46,202.84 62.47,202.84 61.84,203.47 61.84,203.59 61.74,203.69 v1(61.74,203.75)
  BOTTOM w0.203: PU13.45 61.35,210.19
  BOTTOM w0.254: v1(71.15,201.24) 71.15,201.04 71.7,200.5 PR205.2 ; 61.35,210.19 61.35,209.61 61.69,209.27 61.69,208.87 v2(62.04,208.52) 62.45,208.11 PC135.1 PC136.1 61.8,205.97 61.8,203.8 v1(61.74,203.75) 61.74,203.66 61.8,203.61 61.8,203.52 62.29,203.02 63.07,203.02 63.8,202.3 64.2,201.9 70.22,201.9 71.52,203.2 75.85,203.2 76.24,202.81 PG17.1
PWR_VNN_CSN_NTC: length 11.3
  TOP w0.254: v1(62.61,203.79) 62.79,203.61 v4(65.99,203.61) 68.78,203.61 70.38,202.01 v1(71.23,202.01)
  BOTTOM w0.254: PR200.2 62.56,203.84 v1(62.61,203.79) ; v1(71.23,202.01) 71.41,202.01 71.97,201.44 PR205.1
PWR_VNN_CSP: length 15.5
  BOTTOM w0.254: v2(71.79,203.96) 71.79,203.71 ; 71.79,203.71 75.85,203.71 76.24,204.09 PG12.1 ; 71.79,203.71 71.31,203.71 70,202.41 64.41,202.41 63.68,203.14 PR201.2
PWR_VNN_CSP1B: length 7.2
  BOTTOM w0.203: PU13.44 61.75,209.81 61.82,209.74
  BOTTOM w0.254: 61.82,209.74 63.09,208.47 v2(63.26,208.47) 63.26,208.3 63.34,208.22 PC135.2 PC136.2 63.68,206.29 PR201.1 63.67,205.6 PR200.1
PWR_VNN_HG: length 18.2
  L3 w1.016: v5(63.43,219.38) 67.93,219.38 71.36,215.94 v5(71.36,212.17)
  BOTTOM w0.203: PU13.21 61.35,217.15 61.91,217.7 61.91,218.02 v2(62.28,218.39)
  BOTTOM w0.508: v5(63.43,219.38) 63.41,219.38 62.42,218.39 v2(62.28,218.39)
  BOTTOM w1.016: PR193.1 v5(71.36,212.17)
PWR_VNN_HG_R:
  vias: v2(70.74,207.59)
PWR_VNN_ILIM: length 4.8
  TOP w0.254: PR20.1 PC13.1 60.78,209.43 v1(61.16,209.05) v4(62.19,209.05)
  BOTTOM w0.203: v1(61.16,209.05) 60.95,209.26 PU13.46
PWR_VNN_IOUT: length 6.5
  TOP w0.254: v1(63.96,208.76) 64.68,208.05 v4(65.01,208.05) 65.15,208.19 PC12.1 65.15,209.19 PR15.1
  BOTTOM w0.203: PU13.43 62.15,210.04 63.05,209.14 63.59,209.14 v1(63.96,208.76)
PWR_VNN_LG: length 32.7
  L4 w1.016: v5(60.84,219.38) 60.84,220.57 63.03,222.76 69.63,222.76 75.47,216.92 75.47,214.5 76.23,213.74 77.5,213.74 78.24,213 82.1,213 v5(82.75,212.35)
  BOTTOM w0.203: v2(60.77,218.41) 60.77,217.49 60.55,217.28 PU13.19
  BOTTOM w0.508: v5(60.84,219.38) 60.84,219.29 60.77,219.22 v2(60.77,218.41)
PWR_VNN_PH: length 29.3
  L3 w1.016: v5(73.74,207.39) 73.03,208.1 73.03,216.61 68.61,221.03 63,221.03 62.03,220.07 v5(62.03,219.35)
  BOTTOM w0.203: v5(62.03,219.35) 62.03,219.14 61.35,218.45 61.35,217.61 61.1,217.36 61.1,217.36 60.95,217.21 PU13.20
  BOTTOM w0.508: PC127.1 61.96,220.6 v2(61.52,220.16) 62.03,219.65 v5(62.03,219.35)
  vias: v5(78.72,206.83) v5(79.18,207.85) v5(79.87,206.86) v5(80.27,207.82) v5(81.41,207.8)
PWR_VNN_PWM: length 3.2
  TOP w0.254: v4(63.53,209.78) 64.04,210.29 v1(64.04,210.57) 64.12,210.64 64.12,210.69 64.94,211.51 PR13.1
  BOTTOM w0.203: PU13.40 63.85,210.75 v1(64.04,210.57)
PWR_VNN_SN: length 3.4
  TOP w0.508: v1(78.26,211.91) v4(77.27,211.91)
  BOTTOM w0.508: PC133.1 77.64,212.54 v1(78.26,211.91) 78.29,211.88 78.29,211.3 PR194.2
PWR_VNN_VSN: length 5.4
  BOTTOM w0.203: PU13.48 60.15,209.09
  BOTTOM w0.254: PC138.2 59.65,206.54 PR199.2 59.86,206.75 59.86,208.54 v2(59.93,208.61) 60.15,208.83 60.15,209.09
PWR_VNN_VSP: length 6.5
  BOTTOM w0.203: 59.75,209.31 PU13.49
  BOTTOM w0.254: 59.75,209.31 59.48,209.05 59.48,209.04 59.27,208.82 59.27,207.72 v2(59.16,207.62) 59.16,207.42 58.95,207.21 58.27,207.21 PR198.2 56.6,206.56 PC137.2
PWR_VNN_VSPA: length 5.8
  BOTTOM w0.254: v2(57.54,201.12) 57.06,201.6 57.06,202.35 PR202.1 57.3,203.71 PG14.2 57.63,203.84 PC143.1 57.63,205.66 PR198.1
PWR_VNN_VSPA_R: length 1.9
  BOTTOM w0.254: PC137.1 56.5,205.57 v2(56.5,204.7) PR202.2
PWR_VR_HOT#: length 4.9
  BOTTOM w0.254: v2(67.99,214.65) 67.68,214.65 67.34,214.31 PR190.2 66.52,214.31 65.07,212.86 PU13.35
PWR_VTT_EN: length 2.9
  TOP w0.102: 151.84,130.67 151.72,130.78 PR84.2 ; 151.84,130.67 v4(151.85,130.66) ; 151.84,130.67 151.84,130.97 151.3,131.51 PU5.7
PWRBTN_APS: length 1.6
  BOTTOM w0.102: R528.2 97.23,218.76 TP55.1
PWRBTN_N: length 210.2
  TOP w0.102: R354.2 138.81,67.94 138.98,68.12 139.36,68.12 140.1,67.37 R356.1 141.58,67.37 141.91,67.05 143.76,67.05 v1(145.23,68.52)
  L4 w0.127: v3(23.73,23.08) 22.8,22.15 22.8,7.35 25.91,4.24 26.32,4.24 27.73,2.83 112.63,2.83 120.19,10.39 127.81,10.39 129.71,12.3 129.71,14.08 126.7,17.09 126.7,20.62 130.86,24.79 135.04,24.79 141.36,31.11 141.36,34.5 141.54,34.68 141.54,56.79 144.32,59.57 144.32,66.41 145.17,67.27 145.17,68.46 v1(145.23,68.52)
  BOTTOM w0.102: v3(23.73,23.08) 24.01,23.08 C514.1 25.48,24.54 25.48,24.54 27.2,24.54 v2(27.56,24.18) 27.8,23.93 R787.2
PWRBTN_N_R: length 5.9
  TOP w0.102: R355.2 137.32,66.99 C138.1 138.4,65.91 R358.1 138.45,65.61 139.53,65.61 v4(139.61,65.68) 140.65,65.68 140.88,65.91 R356.2
PWRCN_DET_N: length 425.9
  TOP w0.305: v4(31.61,24.1) 31.61,23.88 30.48,22.75 PWRCN1.5 29.2,22.75 28.74,23.22 26.72,23.22 v1(26.02,23.92)
  TOP w0.508: v1(57.44,173.48) 57.44,172.74 57.87,172.31 R155.1
  L3 w0.305: v3(133.5,12.37) 131.17,10.03 v3(110.12,10.03)
  L3 w0.381: v1(111.82,121.09) 110.69,121.09 108.97,122.81 101.4,122.81 100.64,123.57 95.46,123.57 94.11,122.22 90.83,122.22 87.38,125.67 84.15,125.67 76.08,133.73 69.88,133.73 68.61,135 61.67,135 60.61,136.06 60.61,143.06 63.1,145.55 v1(63.1,146.18)
  L4 w0.203: v3(110.12,10.03) 109.51,9.42 100.44,9.42 99.41,10.45 99.41,16.11 96.27,19.24 91.09,19.24 91.09,19.25 89.7,19.25 85.7,23.24 68.89,23.24 67.72,24.41 61.86,24.41 57.39,19.94 48.06,19.94 46.74,18.62 46.74,14.02 47.25,13.51 47.25,8.19 46.5,7.44 46.5,7.44 43.76,4.7 30.31,4.7 28.13,6.88 26.22,6.88 25.15,7.95 25.15,10.44 24.7,10.9 24.7,14.2 25.5,15.01 25.5,16.17 25.76,16.43 28.16,18.83 28.16,21.53 26.02,23.67 v1(26.02,23.92)
  L4 w0.305: v1(157.66,106.18) 156.24,104.76 156.24,66.05 150.09,59.9 150.09,56.16 148.29,54.36 148.29,42.53 149.21,41.61 149.21,34.38 148.84,34.01 148.84,32.27 143.57,27 143.57,24.81 138.38,19.62 137.83,19.62 133.5,15.29 v3(133.5,12.37)
  L4 w0.381: v1(57.44,173.48) 57.44,171.65 56.48,170.7 56.48,161.39 54.71,159.62 54.71,156.27 62.64,148.33 62.64,146.63 v1(63.1,146.18)
  BOTTOM w0.381: v1(111.82,121.09) 113.65,119.25 138.16,119.25 139.59,117.82 150.83,117.82 156.88,111.77 156.88,106.99 157.66,106.21 v1(157.66,106.18) ; v1(26.02,23.92) 26.05,23.88 26.62,23.88 27.27,23.24 C516.2
PWRCN_DET_N_C: length 21.2
  TOP w0.305: CPU1.J39 75.72,168.27 75.34,167.89 v3(75.34,167.84)
  TOP w0.508: v1(60.79,173.37) 60.89,173.28 R159.1 59.86,172.06 R155.2
  L3 w0.254: v1(60.79,173.37) 61,173.57 64.02,173.57 67.4,170.2 71.69,170.2 73.21,168.67 74.51,168.67 v3(75.34,167.84)
  BOTTOM w0.635: v1(60.79,173.37) 60.75,173.33 59.95,173.33 v2(59.93,173.3)
PWRGD_3V: length 110.6
  TOP w0.102: R340.1 132.87,73.58 135.06,75.77 136.18,75.77 v1(137.75,77.34) 137.8,77.34 138.98,78.52 138.98,79.1 139.81,79.93 141.3,79.93 141.97,80.59 141.97,81.51 146.21,85.75 146.21,90.68 148.14,92.61 148.14,99.16 148.52,99.55 148.52,100.43 147.12,101.83 147.12,105.58 147,105.71 147,111.57 149.44,114.01 149.44,120.51 147.41,122.53 R214.1 144.16,121.24 R213.1 144.15,120.19 C58.1 143.2,122.86 142.44,123.62 140.93,123.62 139.38,122.07 131.62,122.07 128.64,119.09 R218.1 125.06,119.09 Q17.G
  L4 w0.127: v1(136.69,59.94) 136.2,60.43 136.2,66.6 137.77,68.17 137.77,73.87 136.7,74.94 136.7,76.29 v1(137.75,77.34)
  BOTTOM w0.102: v2(135.55,59.02) 135.86,59.33 R734.2 v1(136.69,59.94)
PWRGD_3V_B: length 5.5
  TOP w0.102: Q17.D 121.82,118.74 R226.2 120.98,116.77 v4(120.76,116.99) 120.39,116.99 Q18.B
PWRGD_3V_B_1: length 4.3
  TOP w0.102: Q19.6 146.86,116.65 147.33,116.18 v4(147.33,116.15) 147,115.82 R238.2 146.21,115.83 Q19.5
PWRGD_3V_C: length 204.7
  TOP w0.102: Q2.G 13.01,220.44 Q4.G 13.22,220.23 13.22,220.07 14.54,218.74 15.59,218.74 15.81,218.97 15.81,219.96 v4(16.31,220.45) 16.37,220.45 16.45,220.45 16.46,220.45 v1(17.17,220.45) ; Q18.C 116.25,118.98 PC76.1 115.87,119.36 R220.2 113.91,122.31 102.79,122.31 101.56,121.08 100.12,121.08 99.7,120.66 v1(99.44,120.66)
  L3 w0.127: v1(99.44,120.66) 98.92,120.13 87.96,120.13 87.68,120.41 80.54,120.41 78.39,122.56 78.39,124.56 72.5,130.45 65.41,130.45 65.01,130.86 59.6,130.86 56.73,133.73 43.67,133.73 40.57,136.83 40.57,137.16 39.2,138.53 39.2,142.85 45.96,149.61 45.96,152.5 41.66,156.79 32.14,156.79 30.21,158.72 24.77,158.72 21.82,161.68 21.82,176.75 19.94,178.63 19.94,194.21 18.9,195.26 18.9,207.35 17.77,208.47 17.77,214.78 18.86,215.87 18.86,219.15 17.56,220.45 v1(17.17,220.45)
PWRGD_3V_D: length 11.3
  TOP w0.102: v4(127.11,118.09) Q16.S 128.52,118.25 130.89,120.63 135.24,120.63 136.3,119.56 Q14.D
PWRGD_3V_G1: length 2.9
  TOP w0.102: Q16.G 126.92,120.06 v4(126.83,119.96) 126.81,119.98 R218.2
PWRGD_3V_G2: length 3.5
  TOP w0.102: R221.2 140.05,119.09 v4(139.89,118.93) 139.03,118.93 Q14.G
PWRGD_3V_LL: length 2.4
  TOP w0.102: R214.2 145.46,120.66 v4(145.4,120.6) 145.56,120.44 Q19.3
PWRGD_3V_N: length 3.9
  TOP w0.102: Q34.G 131.3,72.52 R343.1 R340.2 131.98,74.37 v4(132.19,74.57)
PWROK3_1_R: length 5.2
  TOP w0.102: v3(132.93,60.06) 132.82,60.06 132.35,60.53 U14.84
  BOTTOM w0.102: v3(132.93,60.06) 132.95,60.06 133.07,59.94 v2(133.85,59.94) R734.1 R729.2
PWROK3_2_R: length 107.3
  TOP w0.102: U14.10 116.84,61.73 117.08,61.49 v1(117.08,60.58) ; v1(148.88,119.23) 148.88,119.3 148.47,119.71 148.47,120.67 R216.1
  L3 w0.127: v1(161.17,108.88) 161.28,108.88 162.3,107.87 162.3,99.85 160.98,98.52 160.98,94.12 161.95,93.15 161.95,84.89 156.42,79.36 156.42,75.87 140.03,59.47 136.49,59.47 136.27,59.69 133.43,59.69 132.93,59.18 130.77,59.18 129.97,59.98 129.39,59.98 129.31,60.07 122.8,60.07 122.18,60.69 117.19,60.69 v1(117.08,60.58)
  BOTTOM w0.102: v1(148.88,119.23) 148.88,119.59 149.18,119.89 151.04,119.89 v2(154.62,116.3) 159.9,111.03 159.9,110.16 v1(161.17,108.88)
QSA0: length 33.2
  TOP w0.127: v3(78.44,92.94) 78.88,92.5 GPU1.E19
  L3 w0.152: v3(55.24,85.32) 54.84,85.73 54.84,86.14 55.1,86.4 55.57,86.4 55.8,86.17 56.51,86.17 56.63,86.3 57.56,86.3 57.72,86.14 58.97,86.14 59.13,86.3 63.5,86.3 64.25,87.06 66.56,87.06 67.25,86.36 69.78,86.36 70.67,87.25 72.66,87.25 72.95,86.96 73.8,86.96 74.14,87.31 75.5,87.31 75.61,87.2 76.34,87.2 78.95,89.81 78.95,92.68 78.7,92.94 v3(78.44,92.94)
  BOTTOM w0.127: VRAM4.F3 54.76,85.88 54.76,85.81 v3(55.24,85.32)
QSA1: length 35.6
  TOP w0.127: GPU1.C15 82.18,90.9 v3(82.58,90.5)
  L3 w0.152: v1(56.99,81.11) 57.2,81.32 57.68,81.32 57.68,81.32 58.13,81.32 58.47,80.98 60.7,80.98 61.12,81.4 75.85,81.4 79.88,85.43 79.88,85.6 80.32,86.04 80.35,86.04 81.69,87.38 81.69,88.68 82.58,89.57 v3(82.58,90.5)
  BOTTOM w0.127: v1(56.99,81.11) 56.99,81.48 56.31,82.16 56.31,83.11 56.79,83.59 57.35,83.59 VRAM4.C7
QSA2: length 37.4
  TOP w0.127: v3(79.49,87.24) 79.49,87.15 79.59,87.05 80.31,87.05 80.9,87.63 80.9,89.64 GPU1.B16 ; VRAM2.C7 54.9,83.34 55.08,83.34 55.52,82.9 55.52,79.57 v1(55.74,79.34)
  L4 w0.152: v1(55.74,79.34) 55.74,79.07 55.94,78.86 57.7,78.86 59.62,80.78 63.05,80.78 63.1,80.73 64.48,80.73 65.16,81.41 73.19,81.41 73.2,81.42 73.25,81.42 78.02,86.2 78.02,86.45 78.82,87.24 v3(79.49,87.24)
QSA3: length 26.1
  TOP w0.127: v3(57.01,85.55) 57.01,85.55 56.98,85.57 56.9,85.57 56.51,85.96 56.51,86.2 57.05,86.74 57.28,86.74 57.6,86.41 VRAM2.F3 ; GPU1.B22 76.16,90.1 76,89.94 76,89.26 75.82,89.08 75.35,89.08 73.35,87.09 71.13,87.09 70.97,86.93 v3(70.97,86.33)
  L4 w0.152: v3(57.01,85.55) 57.05,85.51 57.37,85.51 57.68,85.81 59.24,85.81 59.46,86.04 62.12,86.04 62.29,85.86 62.68,85.86 62.77,85.95 62.77,86.05 63.07,86.36 63.58,86.36 63.88,86.05 63.88,85.84 63.99,85.74 68.98,85.74 69.12,85.88 69.12,86.08 69.45,86.41 69.93,86.41 70.47,85.86 70.77,85.86 70.97,86.06 v3(70.97,86.33)
QSA4: length 35.4
  TOP w0.127: v3(73.51,100.41) 73.52,100.41 73.9,100.8 GPU1.R25
  L3 w0.152: v3(73.51,100.41) 73.16,100.07 72.68,100.07 72.22,99.61 67.1,99.61 65.1,101.61 65.1,102.48 63.8,103.78 63.8,104.52 63.93,104.65 64.29,104.65 64.59,104.95 64.59,105.58 64.29,105.88 63.98,105.88 63.83,106.03 63.83,106.34 63.98,106.5 64.91,106.5 65.24,106.83 65.24,107.41 64.91,107.74 63.96,107.74 63.8,107.9 63.8,113.04 62.96,113.89 62.22,113.89 61.65,113.32 61.37,113.32 61.22,113.47 61.22,113.97 60.92,114.27 60.39,114.27 60.09,113.97 60.09,113.48 59.97,113.36 59.77,113.36 59.38,113.74 58.93,113.74 58.09,112.91 v3(57.02,112.91)
  BOTTOM w0.127: VRAM3.F3 57.43,112.83 57.09,112.83 v3(57.02,112.91)
QSA5: length 40.1
  TOP w0.127: GPU1.W23 75.5,103.84 75.62,103.72 v3(75.91,103.72)
  L3 w0.152: v3(75.91,103.72) 75.86,103.78 74.95,103.78 74.68,103.5 73.03,103.5 72.47,104.07 72.47,105.73 71.85,106.35 71.85,106.35 71.8,106.4 69.66,106.4 69.3,106.76 69.3,108.39 69.63,108.72 70.11,108.72 70.26,108.87 70.26,109.17 70.11,109.33 69.63,109.33 69.3,109.66 69.3,110.46 70.38,111.54 70.38,113.21 63.94,119.65 57.26,119.65 57.03,119.43 56.52,119.43 56.36,119.26 56.3,119.26 56.16,119.12 v1(56.16,119.03)
  BOTTOM w0.127: VRAM3.C7 54.59,115.59 54.6,115.59 54.65,115.64 55.29,115.64 55.77,116.12 55.77,118.83 55.97,119.03 v1(56.16,119.03)
QSA6: length 37
  TOP w0.127: GPU1.AB26 72.71,106.99 72.35,106.99 71.87,107.46 v3(71.87,107.56) ; v1(57.51,123.84) 57.28,123.62 57.18,123.62 56.81,123.24 56.81,120.27 57.33,119.75 57.33,118.62 57.04,118.34 56.93,118.34 56.03,117.44 56.03,116.61 57.15,115.49 57.51,115.49 VRAM1.C7
  L4 w0.152: v1(57.51,123.84) 57.74,123.84 57.79,123.9 58.5,123.9 60.74,121.66 62.39,121.66 62.49,121.76 63.87,121.76 69.48,116.14 69.48,109.96 71.54,107.89 71.56,107.89 71.87,107.58 v3(71.87,107.56)
QSA7: length 33.4
  TOP w0.127: GPU1.T26 72.72,102.02 71.98,102.02 71.91,101.95 70.82,101.95 70.39,102.38 70.36,102.38 v3(70.36,102.38) ; v3(56.31,114.19) 56.26,114.14 55.74,114.14 55.33,113.73 55.33,113.22 55.05,112.94 54.46,112.94 VRAM1.F3
  L4 w0.152: v3(56.31,114.19) 56.45,114.33 56.45,114.59 56.91,115.05 59.9,115.05 60.48,114.46 60.82,114.46 60.98,114.61 60.98,114.74 61.24,115.01 62.75,115.01 63.38,114.38 63.38,112.31 63.07,112.01 62.6,112.01 62.45,111.85 62.45,111.5 62.6,111.34 63,111.34 63.33,111.01 63.33,110.38 63,110.05 62.6,110.05 62.45,109.9 62.45,109.56 62.6,109.4 62.91,109.4 63.24,109.07 63.24,108.28 63.38,108.15 63.75,108.15 64.28,107.61 64.28,107.24 64.42,107.1 65.15,107.1 66.55,105.7 66.55,104.83 66.75,104.63 66.98,104.63 67.05,104.69 67.54,104.69 67.93,104.3 67.93,103.62 68.13,103.42 68.68,103.42 69.24,102.86 69.88,102.86 69.9,102.84 69.9,102.84 70.16,102.59 70.16,102.59 v3(70.36,102.38)
QSA#0: length 33.3
  TOP w0.127: v3(78.44,93.77) 78.87,93.34 GPU1.F19
  L3 w0.152: v3(78.44,93.77) 78.44,93.63 79.26,92.81 79.26,89.68 76.47,86.9 75.48,86.9 75.37,87.01 74.27,87.01 73.92,86.66 72.82,86.66 72.53,86.94 70.79,86.94 69.91,86.06 67.13,86.06 66.43,86.75 64.38,86.75 63.63,86 59.26,86 59.1,85.83 57.59,85.83 57.43,85.99 56.76,85.99 56.63,85.87 55.68,85.87 55.59,85.96 v3(55.28,85.96)
  BOTTOM w0.127: v3(55.28,85.96) 55.04,85.96 54.77,86.23 54.77,86.39 54.76,86.4 54.76,86.68 VRAM4.G3
QSA#1: length 35.7
  TOP w0.127: v3(83.42,90.5) 83.02,90.9 GPU1.C14
  L3 w0.152: v3(83.42,90.5) 82.88,89.97 82.88,89.44 82,88.55 82,87.25 80.48,85.74 80.45,85.74 80.19,85.48 80.19,85.3 75.98,81.09 61.25,81.09 60.83,80.67 58.34,80.67 58,81.02 57.8,81.02 57.65,80.86 v1(57.65,80.85)
  BOTTOM w0.127: v1(57.65,80.85) 57.65,81.18 56.57,82.26 56.57,83 56.9,83.34 57.3,83.34 VRAM4.B7
QSA#2: length 37.1
  TOP w0.127: VRAM2.B7 54.4,83.19 54.46,83.24 54.64,83.24 54.8,83.08 54.97,83.08 55.26,82.79 55.26,79.62 v1(55.01,79.36) ; GPU1.A16 81.16,89.1 81.16,87.53 80.42,86.79 79.05,86.79 v3(79.02,86.76)
  L4 w0.152: v1(55.01,79.36) 55.01,79.19 55.64,78.56 57.83,78.56 59.75,80.48 62.92,80.48 62.98,80.43 64.6,80.43 65.28,81.11 73.31,81.11 73.33,81.12 73.38,81.12 78.33,86.07 78.33,86.32 78.77,86.76 v3(79.02,86.76)
QSA#3: length 25.9
  TOP w0.127: v3(56.39,85.4) 56.39,85.45 56.26,85.57 56.26,86.31 56.94,86.99 57.55,86.99 VRAM2.G3 ; v3(71.68,86.34) 71.81,86.47 72.18,86.84 73.46,86.84 75.45,88.83 75.93,88.83 GPU1.A22
  L4 w0.152: v3(71.68,86.34) 70.9,85.56 70.35,85.56 69.81,86.1 69.57,86.1 69.42,85.95 69.42,85.75 69.11,85.44 63.86,85.44 63.58,85.72 63.58,85.92 63.45,86.05 63.2,86.05 63.07,85.92 63.07,85.82 62.81,85.56 62.16,85.56 61.99,85.73 59.59,85.73 59.36,85.51 57.8,85.51 57.38,85.08 56.87,85.08 56.84,85.12 56.84,85.12 56.55,85.4 v3(56.39,85.4)
QSA#4: length 35.4
  TOP w0.127: GPU1.P25 73.89,100 73.5,99.61 v3(73.5,99.59)
  L3 w0.152: v3(73.5,99.59) 73.31,99.77 73.3,99.77 73.29,99.77 72.8,99.77 72.35,99.31 66.97,99.31 64.8,101.48 64.8,102.36 63.5,103.65 63.5,104.65 63.81,104.95 64.16,104.95 64.29,105.08 64.29,105.45 64.16,105.58 63.85,105.58 63.52,105.91 63.52,106.47 63.85,106.8 64.78,106.8 64.93,106.95 64.93,107.29 64.78,107.44 63.83,107.44 63.5,107.77 63.5,112.92 62.83,113.58 62.35,113.58 61.78,113.02 61.25,113.02 60.92,113.35 60.92,113.84 60.79,113.97 60.52,113.97 60.39,113.84 60.39,113.35 60.09,113.05 59.64,113.05 59.26,113.43 59.05,113.43 58.22,112.6 57.34,112.6 57.2,112.46 57.19,112.46 v3(57,112.27)
  BOTTOM w0.127: VRAM3.G3 57.56,112.24 57.03,112.24 v3(57,112.27)
QSA#5: length 40.2
  TOP w0.127: GPU1.W22 75.92,104.54 v3(75.92,104.54)
  L3 w0.152: v3(75.92,104.54) 75.46,104.08 74.83,104.08 74.55,103.81 73.16,103.81 72.78,104.19 72.78,105.85 71.98,106.65 71.98,106.65 71.92,106.71 69.79,106.71 69.6,106.89 69.6,108.26 69.76,108.41 70.24,108.41 70.57,108.74 70.57,109.3 70.24,109.63 69.76,109.63 69.6,109.78 69.6,110.33 70.69,111.42 70.69,113.33 64.06,119.96 63.81,119.96 57.13,119.96 56.9,119.73 56.18,119.73 v1(56.17,119.72)
  BOTTOM w0.127: v1(56.17,119.72) 56.14,119.72 55.51,119.09 55.51,118.69 55.51,118.69 55.51,116.22 55.18,115.9 54.7,115.9 VRAM3.B7
QSA#6: length 37.1
  TOP w0.127: VRAM1.B7 57.73,116.07 57.73,115.86 57.61,115.74 57.25,115.74 56.28,116.71 56.28,117.33 57.03,118.08 57.15,118.08 57.58,118.52 57.58,119.85 57.06,120.38 57.06,123.14 57.29,123.36 57.38,123.36 57.42,123.4 57.81,123.4 57.96,123.25 57.96,123.08 v1(57.88,123) ; GPU1.AB27 72.3,106.68 71.99,106.98 71.52,106.98 71.24,107.27 v3(71.24,107.58)
  L4 w0.152: v3(71.24,107.58) 71.24,107.76 69.17,109.83 69.17,116.02 63.74,121.45 62.62,121.45 62.52,121.35 60.61,121.35 58.37,123.59 57.94,123.59 57.69,123.35 57.69,123.18 v1(57.88,123)
QSA#7: length 33.4
  TOP w0.127: v3(69.72,102.41) 69.72,102.05 69.84,101.94 70.48,101.94 70.72,101.7 72.24,101.7 GPU1.T27 ; v3(55.92,113.7) 55.81,113.7 55.58,113.46 55.58,113.11 55.16,112.69 54.71,112.69 54.4,112.38 VRAM1.G3
  L4 w0.152: v3(55.92,113.7) 56.08,113.53 56.44,113.53 56.56,113.66 56.56,113.82 56.76,114.01 56.76,114.46 57.04,114.74 59.77,114.74 60.36,114.16 60.95,114.16 61.28,114.49 61.28,114.61 61.37,114.7 62.62,114.7 63.07,114.26 63.07,112.44 62.94,112.31 62.47,112.31 62.14,111.98 62.14,111.37 62.47,111.04 62.87,111.04 63.02,110.89 63.02,110.51 62.87,110.36 62.47,110.36 62.14,110.03 62.14,109.43 62.47,109.1 62.78,109.1 62.94,108.95 62.94,108.15 63.25,107.84 63.62,107.84 63.98,107.48 63.98,107.11 64.29,106.8 65.02,106.8 66.25,105.57 66.25,104.7 66.63,104.32 67.11,104.32 67.18,104.39 67.41,104.39 67.63,104.17 67.63,103.49 68,103.11 68.55,103.11 69.24,102.42 69.24,102.38 69.39,102.23 69.57,102.23 69.72,102.38 v3(69.72,102.41)
REXT: length 3.4
  TOP w0.127: R419.1 130.71,40.24 v4(130.99,39.95) 130.99,39.72 131.74,38.98 U20.18
RING2: length 45.8
  TOP w0.203: v5(164.47,49.05) 164.32,49.05 164.24,48.97 U16.31
  TOP w0.305: v5(164.47,49.05) 165.14,49.71 RN32.4
  TOP w1.016: UHS1.3 182.78,78.99 181.77,77.98 175.93,77.98 174.23,76.28 171.48,76.28
  BOTTOM w1.016: v5(164.47,49.05) 164.84,49.05 165.92,50.13 165.92,53.23 v2(165.95,53.26) 165.92,53.29 165.92,54.43 166.48,54.99 166.48,66.88 168.84,69.24 168.84,74.73 v5(167.37,76.2)
ROM_CS*: length 14
  TOP w0.102: v3(85.06,91.31) 85.03,91.31 GPU1.D12
  BOTTOM w0.102: R691.1 92.1,86.91 91.47,87.53 89.97,87.53 89.7,87.81 88.43,87.81 88.38,87.76 87.94,87.76 86.72,88.98 85.81,88.98 85.28,89.51 v2(85.28,89.59) 85.06,89.8 v3(85.06,91.31)
ROM_CS_R*: length 3.7
  BOTTOM w0.102: U32.1 95.63,86.06 R691.2 95.71,85.97 v2(95.71,85.12) R696.2
ROM_SCLK: length 17.1
  TOP w0.102: v1(87.13,87.1) 87.38,86.84 88.24,86.84 89.97,85.1 89.97,84.76 90.15,84.58 90.15,83.55 R310.1 R311.1 91.97,82.81 91.97,82.28 92.09,82.15 93.25,82.15 93.49,82.39 R313.2 ; v1(85.52,87.9) 85.09,88.34 85.09,88.94 85.21,89.06 85.21,89.54 85.11,89.64 85.11,90.42 84.64,90.89 GPU1.C12
  BOTTOM w0.102: v2(84.44,88.65) 84.49,88.6 84.61,88.6 85.3,87.9 v1(85.52,87.9) 86.32,87.9 v1(87.13,87.1)
ROM_SCLK_R: length 7.5
  TOP w0.102: v1(92.54,82.65) 92.54,83.12 R311.2
  BOTTOM w0.102: v2(87.03,83.52) U32.6 90.79,83.52 91.65,82.65 v1(92.54,82.65)
ROM_SI: length 11.9
  TOP w0.102: v1(86.7,86.46) 87.89,86.46 89.4,84.95 R304.1 89.62,84.72 R309.1 R308.2 ; GPU1.B12 84.64,89.82 85.01,89.45 85.01,89.15 84.89,89.03 84.89,88.2 85.01,88.07 85.01,87.47 v1(85.24,87.24)
  BOTTOM w0.102: v2(84.41,87.4) 84.57,87.24 v1(85.24,87.24) 85.78,87.24 85.91,87.38 86.35,87.38 86.7,87.03 v1(86.7,86.46)
ROM_SI_R: length 4.9
  TOP w0.102: v1(90.61,82.22) 89.81,83.02 R309.2
  BOTTOM w0.102: v1(90.61,82.22) 90.58,82.25 U32.5 v2(87.03,82.25)
ROM_SO: length 19.3
  TOP w0.102: R314.2 82.1,84.23 84.53,86.66 v1(84.79,86.66) 84.64,86.81 GPU1.A12
  BOTTOM w0.102: U32.2 93.76,84.79 91.24,87.3 v2(89.34,87.3) 89.29,87.35 88.83,87.35 88.07,86.59 87.49,86.59 86.2,85.31 R693.1 85.76,85.58 84.88,86.66 v1(84.79,86.66)
RSMRST#_KBC_MUX: length 2.8
  TOP w0.102: R206.1 77.72,127.61 v4(78.1,127.61) 78.36,127.87 U2.9
RSMRST*_R: length 2.6
  TOP w0.102: R216.2 146.73,121.52 v4(146.73,120.6) 146.72,120.6 146.21,120.09 Q19.2
RSMRST_APS: length 1.5
  BOTTOM w0.102: TP54.1 91.15,225.14 R511.2
RSMRST_N: length 538.3
  TOP w0.102: CPU1.AC57 v3(82.08,176.95) ; v1(88.75,223.95) 87.9,224.79 83.57,224.79 82.42,225.95 41.03,225.95 39.21,225.95 36.84,223.58 36.84,221.89 37.83,220.9 37.83,220.12 36.99,219.28 34.85,219.28 33.17,220.96 33.15,220.98 27.39,220.98 v1(26.82,220.41) ; R28.2 17.62,217.73 R27.2 16.97,217.09 16.34,217.09 v1(16.11,216.87) 15.89,217.09 11,217.09 10.64,217.45 v1(9.54,217.45) ; v1(85.17,43.08) 86.14,44.04 94.22,44.04 97.29,47.12 103.18,47.12 103.64,46.66 104.99,46.66 110.35,52.02 110.81,52.02 111.18,52.39 111.18,53.16 111.09,53.25 111.09,55.91 111.95,56.77 112.38,56.77 113.19,57.58 113.93,57.58 114.08,57.73 U14.20 ; R206.2 75.05,128.24 R1805.2 75.04,128.46 71.63,131.87 69.97,131.87 66.83,135.01 61.93,135.01 60.96,135.98 60.96,139.16 60.07,140.06 51.2,140.06 49.85,138.71 49.85,136.05 47.77,133.97 44.5,133.97 42.97,135.51 42.97,136.95 41.59,138.33 26.47,138.33 23.33,135.19 15.79,135.19 15.39,135.6 v1(15.39,136.4)
  L3 w0.127: v1(103.22,205.52) 102.89,205.19 100.57,205.19 100.56,205.18 100.13,205.18 99.83,204.88 99.83,204.51 99.3,203.98 99.11,203.8 97.28,203.8 97.09,203.99 96.47,204.61 93.72,204.61 92.29,203.17 87.17,203.17 74.67,190.68 74.67,181.94 74.2,181.47 74.2,180.3 74.85,179.65 80.41,179.65 81.58,178.48 81.58,177.44 v3(82.08,176.95) ; v1(85.17,43.08) 82.89,45.36 61.85,45.36 61.85,45.36 60.51,45.36 58.42,47.45 34.29,47.45 33.67,48.08 33.35,48.4 27.33,54.42 27.33,55.3 27.33,55.31 27.33,56.53 27.33,69.75 31.69,74.11 31.69,77.2 31.33,77.57 31.33,99.52 30.56,100.28 30.56,132.46 28.23,134.8 19.87,134.8 18.32,136.35 15.43,136.35 v1(15.39,136.4) 15.26,136.52 15.26,139.41 14.39,140.28 14.39,172.8 11.98,175.2 11.98,182.08 8.54,185.52 8.54,203.43 9.43,204.31 9.43,217.34 v1(9.54,217.45)
  BOTTOM w0.102: v1(16.11,216.87) 16.75,217.5 v2(22.11,217.5) 24.07,217.5 26.82,220.26 v1(26.82,220.41) ; R511.1 88.75,224.87 v1(88.75,223.95) 88.87,223.82 88.87,220.54 90,219.41 90,213.13 91.6,211.53 99.27,211.53 103.22,207.58 v1(103.22,205.52)
RT: length 4.4
  BOTTOM w0.102: R786.1 33.85,24.97 v2(32.98,24.97) 32.44,25.5 32.44,26.77 31.93,27.29 U35.10
RTC_DET#: length 94.6
  TOP w0.102: U14.17 114.56,58.93 113.73,58.1 v1(113.73,58.09) 112.99,58.09 112.3,57.4 111.9,57.4 110.61,56.11 110.61,52.69 v1(110.73,52.58) ; U27.D 134.52,14.82 133.36,13.67 115.63,13.67 v1(114.71,14.58)
  L3 w0.127: v1(119.81,25.39) 120.12,25.69 120.12,36.42 128.34,44.64 128.34,47.16 127.37,48.13 119.49,48.13 117.97,49.66 113.65,49.66 v1(110.73,52.58)
  BOTTOM w0.102: RN40.2 114.24,56.74 v2(113.95,57.04) 113.73,57.26 v1(113.73,58.09) ; v1(114.71,14.58) 114.6,14.69 114.6,19.98 115.78,21.16 117.05,21.16 119.81,23.92 v1(119.81,25.39)
RTCRST_ON: length 38.6
  TOP w0.102: v1(138.95,84.15) 139.36,84.57 R1803.1 138.44,85.55 v4(138.08,85.9) 138.08,85.95 Q1801.G ; U14.122 119.45,67.71 118.83,68.33 118.83,70.01 118.93,70.11 118.93,72.53 v1(118.98,72.58)
  L3 w0.127: v1(138.95,84.15) 138.95,82.14 134.23,77.42 133.64,77.42 132.47,76.25 129.01,76.25 128.01,75.25 126.22,75.25 126.06,75.41 119.35,75.41 118.62,74.69 118.62,72.94 v1(118.98,72.58)
RTD_LVDS_BL_ADJ: length 3.7
  TOP w0.165: R233.2 41.45,116.6 42.82,116.6 v4(42.83,116.59) 42.82,116.57 R244.2
RTL_ISOLATE_N: length 15
  TOP w0.102: U26.20 34.1,15.19 33.82,15.47 32.69,15.47 32.33,15.82 32.33,16.46 31.98,16.8 30.96,16.8 v3(29.63,18.14) 29.63,18.47 30.55,19.39 R480.1 31.45,18.45 R482.2
  BOTTOM w0.102: v2(33.44,18.75) 32.8,18.11 Q76.6 31.87,17.69 31.61,17.42 30.3,17.42 29.65,18.07 29.65,18.12 v3(29.63,18.14)
RTL_ISOLATE_N_1: length 7
  BOTTOM w0.102: R797.2 34.38,19.3 32.65,19.3 32.38,19.58 v2(32.14,19.58) 31.31,19.58 C517.1 R794.1 31.22,18.48 Q76.5
RTL_ISOLATE_N_2: length 6.5
  BOTTOM w0.102: Q76.2 31.22,16.89 31.1,17.02 30.69,17.02 30.57,16.9 Q76.3 30.57,15.2 v2(30.39,15.01) 30.39,14.76 29.62,14 29.62,12.87 R800.2
RTN1: length 20.6
  TOP w0.254: v4(28.99,43.31) 28.33,42.64 CONVT1.1 27.34,41.15 27.03,40.84 24.37,40.84 21.99,38.47 21.99,33.61 v1(22.17,33.43)
  BOTTOM w0.254: R768.1 27.06,32.82 26.91,32.96 22.64,32.96 v1(22.17,33.43)
RTN2: length 16.1
  TOP w0.254: CONVT1.2 27.4,40.15 27.21,40.34 24.75,40.34 22.64,38.23 v4(22.64,36.58) 22.64,33.72 22.7,33.65 22.7,33.06 v1(22.15,32.51)
  BOTTOM w0.254: R769.1 23.24,32.36 23.24,32.36 23.11,32.36 23.11,32.36 22.3,32.36 v1(22.15,32.51)
RTN3: length 16.4
  TOP w0.254: CONVT1.5 25.47,37.15 24.42,36.09 24.42,33.32 22.6,31.5 v1(22.18,31.5) v4(22.18,30.58)
  BOTTOM w0.254: v1(22.18,31.5) 22.28,31.6 R770.1
RTN4: length 12.4
  TOP w0.254: v4(23.99,29.44) 23.99,30.4 23.83,30.56 v1(23.83,30.96) 23.83,31.17 24.95,32.28 24.95,35.46 25.64,36.15 CONVT1.6
  BOTTOM w0.254: v1(23.83,30.96) 23.85,30.96 v2(24.46,30.36) 25.06,30.96 R772.1
S5_ENABLE: length 48.5
  TOP w0.102: U14.14 116.37,60.13 116.43,60.07 118.14,60.07 118.46,59.75 119.85,59.75 120.12,60.02 120.12,61.9 116.77,65.25 116.77,67.92 116.34,68.35 116.34,68.96 v1(116.29,69.01)
  L4 w0.127: v1(116.29,69.01) 117.57,67.73 119.63,67.73 120.01,68.11 120.01,68.59 119.78,68.82 119.78,72.18 120.62,73.01 121,73.01 122,72.01 122,71.16 125.06,68.11 129.71,68.11 v1(134.35,72.75)
  BOTTOM w0.102: Q64.D 134.85,72.75 v1(134.35,72.75) 134.32,72.78 R712.2 133.37,73.61 R708.2 134.42,73.78 v2(134.5,73.86)
S_LVDS_BL_EN: length 6
  TOP w0.127: R473.2 37.69,23.88 R472.1 R467.1 37.37,25.73 v4(36.58,26.52) 36.94,26.87 R465.1 R463.1
S_TXE0+: length 5.8
  TOP w0.102: LVDS1.18 v1(43.63,92.5)
  BOTTOM w0.102: U31.31 41.46,94.3 41.53,94.23 41.9,94.23 42.5,93.62 ; 42.5,93.62 v2(42.71,93.83) ; 42.5,93.62 42.93,93.19 42.93,92.31 43.04,92.2 43.33,92.2 v1(43.63,92.5)
S_TXE0-: length 5.9
  TOP w0.102: LVDS1.19 v1(43.63,91.5)
  BOTTOM w0.102: 42.93,91.95 43.18,91.95 v1(43.63,91.5) ; 42.93,91.95 v2(42.71,91.72) ; 42.93,91.95 42.68,92.2 42.68,93.08 41.79,93.97 41.53,93.97 41.46,93.9 U31.32
S_TXE1+: length 5.3
  TOP w0.102: LVDS1.15 v1(43.63,95.5)
  BOTTOM w0.102: v2(44.61,95.48) 43.65,95.48 v1(43.63,95.5) 43.16,95.03 41.53,95.03 41.46,95.1 U31.29
S_TXE1-: length 5.1
  TOP w0.102: LVDS1.16 v1(43.63,94.5)
  BOTTOM w0.102: U31.30 41.46,94.7 41.53,94.77 43.36,94.77 v1(43.63,94.5) 44.09,94.5 v2(44.41,94.18)
S_TXE2+: length 6.5
  TOP w0.102: LVDS1.12 v1(43.63,98.5)
  BOTTOM w0.102: v1(43.63,98.5) 43.33,98.19 42.75,98.19 42.49,97.93 ; v2(42.3,98.12) 42.49,97.93 ; 42.49,97.93 42.49,96.18 42.14,95.83 41.53,95.83 41.46,95.9 U31.27
S_TXE2-: length 6.6
  TOP w0.102: LVDS1.13 v1(43.63,97.5)
  BOTTOM w0.102: 42.57,95.9 42.24,95.57 41.53,95.57 41.46,95.5 U31.28 ; 42.57,95.9 42.74,96.08 42.74,97.83 42.86,97.94 43.19,97.94 v1(43.63,97.5) ; 42.57,95.9 v2(42.83,95.63)
S_TXE3+: length 8.6
  TOP w0.102: LVDS1.8 43.53,102.5 v1(43.64,102.39)
  BOTTOM w0.102: v1(43.64,102.39) 43.54,102.29 42.78,102.29 41.89,101.4 41.89,100.71 40.47,99.29 ; U31.23 39.58,98.39 40.47,99.29 ; 40.47,99.29 v2(40.22,99.54)
S_TXE3-: length 8.6
  TOP w0.102: LVDS1.9 42.96,101.5 43.16,101.7 43.38,101.7 v1(43.63,101.45)
  BOTTOM w0.102: 42.15,100.81 42.15,100.61 39.98,98.44 U31.24 ; 42.15,100.81 42.15,101.29 42.89,102.03 43.34,102.03 43.63,101.74 v1(43.63,101.45) ; 42.15,100.81 v2(42.5,100.81)
S_TXEC+: length 7.2
  TOP w0.102: LVDS1.10 v1(43.63,100.5)
  BOTTOM w0.102: v1(43.63,100.5) 43.23,100.1 42.88,100.1 41.83,99.05 ; 41.83,99.05 v2(41.59,99.29) ; 41.83,99.05 41.49,98.71 41.49,96.72 41.4,96.63 41.31,96.63 41.24,96.7 U31.25
S_TXEC-: length 7.1
  TOP w0.102: LVDS1.11 v1(43.63,99.5)
  BOTTOM w0.102: v1(43.63,99.5) 43.28,99.85 42.98,99.85 42.6,99.47 ; 42.6,99.47 v2(42.81,99.26) ; 42.6,99.47 41.74,98.61 41.74,96.61 41.51,96.38 41.31,96.38 41.24,96.3 U31.26
S_TXO0+: length 15.5
  TOP w0.102: LVDS1.29 43.65,81.5 v1(43.72,81.43)
  BOTTOM w0.102: 41.18,82.2 40.85,82.53 40.85,86.82 38.23,89.44 38.23,90.55 38.38,90.69 U31.41 ; 41.18,82.2 v2(41.43,82.45) ; 41.18,82.2 42.33,81.05 43.49,81.05 43.72,81.28 v1(43.72,81.43)
S_TXO0-: length 15.5
  TOP w0.102: LVDS1.30 43.53,80.5 v1(43.64,80.62)
  BOTTOM w0.102: 41.64,81.38 42.22,80.8 43.47,80.8 v1(43.64,80.62) ; 41.64,81.38 40.6,82.42 40.6,86.72 37.98,89.34 U31.42 ; 41.64,81.38 v2(41.41,81.15)
S_TXO1+: length 13.4
  TOP w0.102: v1(43.66,83.36) 43.52,83.5 LVDS1.27
  BOTTOM w0.102: U31.39 39.18,90.88 39.1,90.81 39.1,89.64 41.59,87.15 41.59,83.95 ; 41.59,83.95 v2(41.94,83.95) ; 41.59,83.95 41.59,83.38 42.04,82.93 43.54,82.93 43.66,83.05 v1(43.66,83.36)
S_TXO1-: length 13.5
  TOP w0.102: LVDS1.28 43.62,82.5 v1(43.65,82.47)
  BOTTOM w0.102: v1(43.65,82.47) 43.45,82.67 42.78,82.67 ; 42.78,82.67 41.94,82.67 41.33,83.28 41.33,87.05 38.85,89.53 38.85,90.74 38.78,90.82 U31.40 ; 42.78,82.67 v2(42.78,82.32)
S_TXO2+: length 10.8
  TOP w0.102: LVDS1.25 v1(43.63,85.5)
  BOTTOM w0.102: v1(43.63,85.5) 43.63,85.33 43.05,84.75 42.69,84.75 42.32,85.12 42.32,85.83 ; v2(42.65,85.83) 42.32,85.83 ; 42.32,85.83 42.32,87.99 39.9,90.41 39.9,90.74 39.98,90.82 U31.37
S_TXO2-: length 10.8
  TOP w0.102: LVDS1.26 v1(43.63,84.5)
  BOTTOM w0.102: 41.11,88.85 42.07,87.89 42.07,85.01 42.58,84.5 v1(43.63,84.5) ; 41.11,88.85 v2(40.88,88.62) ; 41.11,88.85 40.04,89.92 40.04,89.92 40.04,89.92 39.65,90.31 39.65,90.74 39.58,90.82 U31.38
S_TXO3+: length 7.5
  TOP w0.102: LVDS1.20 v1(43.63,90.5)
  BOTTOM w0.102: v2(44.31,91.01) 43.8,90.5 v1(43.63,90.5) 43.3,90.17 42.93,90.17 42.12,90.98 42.12,92.85 41.54,93.43 41.31,93.43 41.23,93.5 U31.33
S_TXO3-: length 7.6
  TOP w0.102: LVDS1.21 v1(43.63,89.5)
  BOTTOM w0.102: U31.34 41.24,93.1 41.31,93.17 41.44,93.17 41.87,92.74 41.87,90.88 42.83,89.92 43.22,89.92 v1(43.63,89.5) 43.81,89.5 v2(44.31,89)
S_TXOC+: length 7.9
  TOP w0.102: LVDS1.22 v1(43.63,88.5)
  BOTTOM w0.102: v1(43.63,88.5) 43.35,88.22 43.16,88.22 41.98,89.4 ; U31.35 41.24,92.7 41.46,92.48 41.46,89.91 41.98,89.4 ; 41.98,89.4 v2(42.22,89.64)
S_TXOC-: length 7.8
  TOP w0.102: LVDS1.23 v1(43.63,87.5)
  BOTTOM w0.102: U31.36 41.03,92.3 41.21,92.12 41.21,89.81 41.91,89.11 43.06,87.96 ; 43.06,87.96 43.16,87.86 43.37,87.86 43.63,87.59 v1(43.63,87.5) ; 43.06,87.96 v2(42.83,87.73)
SATA__RXN0_C: length 9.7
  TOP w0.102: C51.2 16.41,139.6 15.75,139.6 13.47,141.88 13.47,143.39 13.06,143.8 12.28,143.8 HDD1.5
  BOTTOM w0.102: v2(10.24,142.98) 10.54,143.27 HDD1.5
SATA__RXN1_C: length 7.3
  TOP w0.102: C31.2 13.04,178.8 8.63,178.8 ODD1.5
  BOTTOM w0.102: v2(6.48,177.98) 6.78,178.27 ODD1.5
SATA__RXP0_C: length 9.5
  TOP w0.102: C50.2 16.45,139.82 15.84,139.82 13.69,141.97 13.69,143.48 13.15,144.01 12.28,144.01 HDD1.6
  BOTTOM w0.102: v2(10.35,144.7) 10.51,144.54 HDD1.6
SATA__RXP1_C: length 7.3
  TOP w0.102: C30.2 12.95,179.01 8.63,179.01 ODD1.6
  BOTTOM w0.102: ODD1.6 6.8,179.54 v2(6.54,179.81)
SATA__TXN0_C: length 8.4
  TOP w0.102: C53.2 16.44,137.58 15.47,137.58 12.85,140.2 12.28,140.2 HDD1.3
  BOTTOM w0.102: v2(10.08,141.25) 10.6,140.73 HDD1.3
SATA__TXN1_C: length 7.4
  TOP w0.102: C33.2 12.98,175.2 8.63,175.2 ODD1.3
  BOTTOM w0.102: ODD1.3 6.95,175.73 v2(6.43,176.25)
SATA__TXP0_C: length 8.3
  TOP w0.102: HDD1.2 12.28,139.99 12.76,139.99 15.39,137.36 16.4,137.36 C54.2
  BOTTOM w0.102: HDD1.2 9.99,139.46 v2(9.98,139.45)
SATA__TXP1_C: length 7.4
  TOP w0.102: ODD1.2 8.63,174.99 12.94,174.99 C34.2
  BOTTOM w0.102: ODD1.2 6.34,174.46 v2(6.33,174.45)
SATAHDR_RX_DN0: length 71.9
  TOP w0.102: v3(64.57,139.06) 64.83,139.32 64.83,139.39 62.69,141.53 42.32,141.53 41.13,140.34 24.39,140.34 23.91,139.85 22.09,139.85 ; L2.4 21.18,139.38 21.33,139.53 21.33,139.74 21.44,139.85 22.09,139.85 ; v3(78.34,153.07) 78.35,153.07 CPU1.T7 ; v4(22.09,139.46) 22.09,139.85
  L3 w0.089: 78.54,149.8 78.54,149.82 78.58,149.86 78.58,150.51 78.94,150.86 78.94,153.11 78.74,153.3 78.58,153.3 v3(78.34,153.07)
  L3 w0.127: 78.54,149.8 78.54,147.67 75.11,144.23 70.08,144.23 66.77,140.93 65.6,140.93 65.07,140.39 65.07,139.67 64.87,139.47 64.7,139.47 64.57,139.34 v3(64.57,139.06)
SATAHDR_RX_DN0_EMI: length 2
  TOP w0.102: L2.3 18.9,139.38 18.7,139.59 18.13,139.59 C51.1
SATAHDR_RX_DN1: length 108.8
  TOP w0.102: C31.1 15.39,178.49 16.3,177.59 16.3,176.69 ; CPU1.T6 v3(78.33,152.36) ; v4(15.92,176.69) 16.3,176.69 ; 16.3,176.69 16.3,143.5 17.8,142 40.16,142 41.4,143.25 64.63,143.25 65.68,142.2 65.68,141.87 v3(65.44,141.63)
  L3 w0.089: 77.85,149.84 77.85,149.86 77.88,149.9 77.88,151.91 v3(78.33,152.36)
  L3 w0.127: v3(65.44,141.63) 65.59,141.78 65.59,142.44 68.3,145.15 74.6,145.15 77.85,148.4 77.85,149.84
SATAHDR_RX_DP0: length 72
  TOP w0.102: 64.75,139.78 62.78,141.74 42.23,141.74 41.04,140.55 24.3,140.55 23.82,140.07 L2.1 ; 64.75,139.78 65.04,139.48 65.04,139.38 v3(65.34,139.09) ; 64.75,139.78 v4(65.03,140.07) ; v3(78.32,153.81) CPU1.T9
  L3 w0.089: v3(78.32,153.81) 78.63,153.49 78.82,153.49 79.13,153.19 79.13,150.79 78.77,150.43 78.77,149.86 78.81,149.82 78.81,149.8
  L3 w0.127: 78.81,149.8 78.81,147.56 75.22,143.97 70.19,143.97 66.88,140.66 65.72,140.66 65.34,140.28 v3(65.34,139.09)
SATAHDR_RX_DP0_EMI: length 2
  TOP w0.102: L2.2 18.89,140.07 18.63,139.8 18.11,139.8 C50.1
SATAHDR_RX_DP1: length 108.9
  TOP w0.102: 16.52,173.18 16.52,143.59 17.89,142.22 40.07,142.22 41.31,143.46 64.72,143.46 65.9,142.29 65.9,141.94 v3(66.15,141.68) ; 16.52,173.18 v4(16.92,173.18) ; 16.52,173.18 16.52,177.68 15.48,178.71 14.93,178.71 14.79,178.85 14.79,179.19 14.58,179.41 C30.1 ; CPU1.T5 v3(78.34,151.65)
  L3 w0.089: 78.11,149.84 78.11,149.86 78.07,149.9 78.07,151.38 v3(78.34,151.65)
  L3 w0.127: v3(66.15,141.68) 65.86,141.97 65.86,142.33 68.41,144.88 74.71,144.88 78.11,148.29 78.11,149.84
SATAHDR_TX_DN0: length 74.5
  TOP w0.089: v3(82,148.59) 82,148.59 81.9,148.69 81.25,148.69 80.68,149.26 CPU1.Y2
  TOP w0.102: 22.79,137.83 24.69,139.73 41.72,139.73 42.89,140.91 61.36,140.91 63.76,138.51 66.28,138.51 66.64,138.14 66.64,137.75 66.85,137.54 v3(66.87,137.54) ; 22.79,137.83 22.32,137.35 21.53,137.35 21.39,137.49 21.39,137.67 21.24,137.82 L3.1 ; 22.79,137.83 v4(22.51,138.11)
  L3 w0.127: v3(82,148.59) 81.99,148.59 81.86,148.46 81.86,147.62 76.23,141.99 70.98,141.99 69.16,140.17 69.16,138.87 68.51,138.23 66.81,138.23 66.67,138.09 66.67,137.74 v3(66.87,137.54)
SATAHDR_TX_DN0_EMI: length 2
  TOP w0.102: C53.1 18.08,137.59 18.97,137.59 19.2,137.82 L3.2
SATAHDR_TX_DN1: length 110.5
  TOP w0.089: CPU1.W2 80.36,150.82 80.36,150.52 80.49,150.34 80.49,150.02 80.42,149.95 80.42,149.22 81.03,148.62 81.03,147.91 v3(81.11,147.83)
  TOP w0.102: 67,140.28 67,140.5 66.63,140.87 64.83,140.87 63.06,142.63 41.65,142.63 40.41,141.39 17.34,141.39 15.65,143.08 15.65,175.28 15.4,175.53 C33.1 ; 67,140.28 v4(67.41,140.28) ; 67,140.28 67,139.33 v3(67.2,139.13)
  L3 w0.127: v3(81.11,147.83) 80.59,147.83 80.58,147.83 80.57,147.83 75.75,143 70.53,143 67.09,139.57 67.09,139.26 67.2,139.16 v3(67.2,139.13)
SATAHDR_TX_DP0: length 74.5
  TOP w0.089: CPU1.Y3 80.68,151.04 80.76,150.96 80.98,150.69 80.98,150.49 80.87,150.34 80.87,149.33 81.19,149.02 81.54,149.02 v3(81.59,149.07)
  TOP w0.102: v4(21.97,136.73) 21.97,137.14 ; 21.97,137.14 L3.4 ; 21.97,137.14 22.41,137.14 24.78,139.51 41.81,139.51 42.98,140.69 61.27,140.69 63.67,138.29 66.19,138.29 66.43,138.05 66.43,137.77 66.21,137.55 v3(66.11,137.55)
  L3 w0.127: v3(81.59,149.07) 81.59,147.73 76.12,142.25 70.86,142.25 68.89,140.28 68.89,138.98 68.4,138.5 66.7,138.5 66.41,138.2 66.41,137.73 66.23,137.55 v3(66.11,137.55)
SATAHDR_TX_DP0_EMI: length 2
  TOP w0.102: L3.3 19.18,137.14 18.94,137.37 18.13,137.37 C54.1
SATAHDR_TX_DP1: length 110.5
  TOP w0.089: CPU1.W1 80.22,150.05 80.23,150.03 80.23,149.15 80.71,148.67 80.71,148.34 v3(80.63,148.26)
  TOP w0.102: v4(15.03,170.27) 15.44,170.27 ; 15.44,170.27 15.44,142.99 17.25,141.18 40.5,141.18 41.74,142.42 62.97,142.42 64.74,140.65 66.54,140.65 66.78,140.41 66.78,139.44 v3(66.48,139.14) ; 15.44,170.27 15.44,175.19 15.31,175.32 14.97,175.32 14.82,175.16 14.82,174.19 14.69,174.07 14.32,174.07 14.2,174.19 C34.1
  L3 w0.127: v3(80.63,148.26) 75.64,143.27 70.42,143.27 66.83,139.68 66.83,139.64 66.66,139.47 66.66,139.31 v3(66.48,139.14)
SB3V: length 1224.9
  TOP w0.305: RN37.1 31.78,32 v1(31.15,31.37) 32.3,31.37 32.44,31.51 RN37.2 ; v1(64.04,72.14) 64.04,72.34 64.49,72.78 R339.1 64.41,73.63 62.49,73.63 60.69,75.44 57.12,75.44 56.66,74.98 53.98,74.98 53.1,75.86 52.55,75.86 52.44,75.74 R334.1 51.66,75.84 50.94,76.56 50.34,76.56 v1(50.33,76.58) ; RN34.1 141.37,7.1 141.69,7.42 141.36,7.75 RN34.2 ; 87.23,193.83 92.21,198.81 95.85,198.81 97.2,200.15 RN2.1 97.66,200.58 97.69,200.61 97.72,200.61 97.92,200.81 97.92,201.01 97.72,201.21 97.31,201.21 RN2.2 97.2,202.12 97.47,202.39 97.47,203.56 98.31,204.4 98.31,205.05 98.23,205.13 v3(98.23,205.19) ; U7.1 127.8,112.47 C72.1 ; RN16.2 15.2,222.63 15.43,222.4 15.43,221.36 15.2,221.13 14.5,221.13 v1(14.41,221.21) 14.62,221.42 RN16.1 ; R452.1 28.36,30.7 v1(28.3,30.76)
  TOP w0.381: R228.1 140.75,116.53 141,116.27 141,115.91 v1(141.04,115.87) ; PR171.1 59.19,51.73 58.33,52.59 v1(58.33,53.04) ; R445.1 46.57,30.79 D5.2 46.35,30.14 47.38,29.11 47.38,28.27 v1(47.61,28.04) ; v1(67.01,132) 68.96,132 69.71,131.25 71.38,131.25 v4(72.23,130.4) 74.05,128.57 74.05,128.23 74.63,127.65 74.63,127.62 74.88,127.37 R1805.1 75.38,127.03 R208.2 76.19,125.96 C56.1 76.17,124.84 R211.2 80.18,124.7 80.63,125.15 83.09,125.15 84.26,123.98 85.62,123.98 87.18,122.41 87.18,121.56 88.08,120.66 R219.1 ; 146.22,114.94 147.37,114.94 v1(147.96,115.53)
  TOP w0.508: 141.69,7.42 141.69,5.79 140.77,4.88 127.31,4.88 122.23,9.96 111.84,9.96 108.36,13.44 108.36,19.67 v1(109.39,20.7) ; PR86.1 157.14,129.48 157.79,130.13 157.79,130.23 157.97,130.41 v1(157.97,130.84) ; v1(129.42,216.43) 129.44,216.45 129.44,221.24 129.19,221.49 R12.1 128.77,221.5 R9.1 ; v5(176.2,138.97) 174.26,140.91 164.99,140.91 164.5,141.39 R185.1 162.99,141.73 v3(161.96,141.73) ; v1(47.15,158.71) 47.12,158.74 R172.1 ; v1(28.62,184.17) 28.62,184.65 28.78,184.8 28.78,186.08 PR38.2 PR37.1 ; v1(129.14,113.95) 129.12,113.97 129.12,115.14 128.76,115.5 R237.2 127.78,115.49 C70.1 127.78,113.78 127.58,113.57 C72.1 ; PR50.1 v1(34.58,170.43) ; v5(46.09,8.43) 46.76,9.09 R499.1 ; PR51.1 v1(37.63,170.43) ; PR39.1 33.08,183.25 v1(33.27,183.06)
  TOP w1.016: v5(134.98,26.29) 135.75,26.29 139.07,29.62 141.09,29.62 144.03,32.55 144.03,43.1 143.49,43.63 v5(143.49,43.74)
  L3 w0.305: v1(64.04,72.14) 64.82,72.26 65.69,71.39 65.69,69.06 61.44,64.81 61.44,63.69 59.93,62.18 59.93,53.9 59.07,53.04 v1(58.33,53.04)
  L3 w0.381: v1(67.01,132) 60.16,132 55,137.16 51.98,137.16 51.56,137.58 43.72,137.58 43.03,136.89 v1(41.93,136.89) ; v1(36.49,133.84) 38.77,131.56 38.77,119.74 41.52,116.98 41.52,108.52 41.97,108.07 41.97,79.99 42.01,79.96 42.01,79.92 42.93,78.99 46.72,78.99 48.14,77.57 49.13,77.57 50.12,76.58 v1(50.33,76.58)
  L3 w0.508: v3(24.83,22.12) 24.83,18.05 27.06,15.82 27.06,15.82 28.93,13.95 28.93,11.51 v5(28.88,11.46) ; v1(28.62,184.17) 28.31,184.48 27.59,184.48 27.26,184.81 27.25,184.81 27.23,184.83 26.65,184.83 26.26,185.21 26.26,197.6 27.51,198.85 27.51,202.02 28.36,202.86 28.36,208.02 28.34,208.03 28.34,217.17 28.34,219.9 29.86,221.42 v1(29.86,221.95) 29.86,223.08 31.87,225.09 75.26,225.09 78.35,222 v1(78.69,222) ; v1(31.15,31.37) 30.54,30.76 v1(28.3,30.76) ; 98.18,205.24 97.92,205.5 97.92,205.51 97.04,206.4 91.24,206.4 89.39,204.55 86.52,204.55 78.98,197 73.78,197 72.09,198.69 72.09,198.73 71.97,198.86 71.97,202.31 70.75,203.53 v1(69.93,203.53)
  L3 w0.635: v3(98.23,205.19) 98.18,205.24 98.18,206.43 100.19,208.43 107.68,208.43 v5(109.13,206.99) 110.23,208.09 124.1,208.09 124.23,207.97 124.83,207.97 124.95,208.09 131.03,208.09 131.75,207.38 132.35,207.38 132.4,207.43 133.69,207.43 134.36,208.09 v5(135.34,208.09) ; v5(104.39,221.19) 104.21,221.19 103.59,220.56 101.56,220.56 100.39,221.74 96.61,221.74 96.3,222.05 78.73,222.05 v1(78.69,222)
  L3 w1.016: v5(138.13,215.85) 137.55,216.43 v1(129.42,216.43) 120.26,216.43 120.24,216.41 115.96,216.41 114.89,217.48 108.1,217.48 v5(104.39,221.19)
  L3 w1.27: 12.11,221.38 18.11,227.38 33.14,227.38 33.15,227.38 34.91,227.38 34.91,227.38 35.62,227.38 35.62,227.38 36.93,227.38 36.93,227.38 89.87,227.38 ; 168.33,85.83 167.19,84.68 167.19,82.91 163.46,79.17 163.46,73.75 v1(160.64,70.93) 146.08,56.38 146.08,47.11 143.49,44.52 v5(143.49,43.74)
  L4 w0.381: v1(41.93,136.89) 41.76,137.06 39.71,137.06 v1(36.49,133.84)
  L4 w0.508: v1(28.3,30.76) 28.3,30.28 24.79,26.76 24.79,22.17 v3(24.83,22.12) ; v1(37.63,170.43) 37.63,170.16 38.99,168.8 45.8,168.8 46.5,168.09 46.5,161.05 47.15,160.4 v1(47.15,158.71) 47.15,157.66 47.89,156.92 47.89,150.83 v1(39.9,142.85)
  L4 w0.635: 170.22,88.44 171.08,89.3 171.08,94.53 169.76,95.85 169.76,122.5 176.15,128.89 176.15,138.91 v5(176.2,138.97) ; v5(66.66,199.87) 66.71,199.92 66.71,200.28 69.76,203.33 69.76,203.35 v1(69.93,203.53)
  L4 w1.016: v5(134.98,26.29) 134.96,26.26 130.61,26.26 126.39,22.04 ; 126.39,22.04 122.75,18.4 111.7,18.4 v1(109.39,20.7) 107.5,22.59 96.63,22.59 94.27,20.24 92.62,20.24 92.61,20.23 91.5,20.23 91.5,20.24 90.11,20.24 86.09,24.26 70.35,24.26 68.48,26.13 59.79,26.13 54.64,31.28 53.59,31.28 53.59,31.28 51.52,31.28 51.51,31.28 50.84,31.28 v1(47.61,28.04) 47.61,20.98 v5(47.35,20.73) 45.27,18.64 45.27,11.66 46.26,10.67 46.26,8.77 46.09,8.6 v5(46.09,8.43) 46.08,8.41 41.16,8.41 39.28,10.29 29.54,10.29 28.88,10.94 v5(28.88,11.46) ; 126.39,22.04 v3(126.22,22.04)
  L4 w1.27: v5(172.23,151.85) v5(172.23,150.04) 172.23,146.7 173,145.93 173,133.4 172.86,133.25 172.86,129.12 167.96,124.21 167.96,119.36 166.15,117.55 166.15,103.71 167.4,102.45 167.4,94.42 163.71,90.72 163.71,90.7
  BOTTOM w0.381: v5(109.13,206.99) 108.44,207.68 108.44,212.1 R536.2 ; R635.1 43.07,120.35 43.08,120.36 R634.1 43.56,120.82 43.03,121.35 v2(43.03,121.43) 43.22,121.63 46.39,121.63 48.01,123.25 48.01,130.8 v1(41.93,136.89) ; v1(69.93,203.53) 69.67,203.27 R568.1 PR203.1
  BOTTOM w0.508: 28.62,183.59 v1(28.62,184.17) ; 28.62,183.59 30.08,182.13 PR209.1 32.27,182.13 33.2,183.06 v1(33.27,183.06) ; 28.62,183.59 27.16,182.13 27.16,174.27 28.1,173.33 32.16,173.33 34.4,171.09 35.24,171.09 ; v1(14.41,221.21) 25.99,221.21 26.01,221.19 29.1,221.19 v1(29.86,221.95) ; v1(160.64,70.93) 160.64,74.04 160.22,74.46 160.22,79.69 162.19,81.65 162.19,92.99 160.38,94.8 160.38,97.27 156,101.65 156,111.48 151.95,115.53 v1(147.96,115.53) 147.6,115.53 146.39,116.74 141.9,116.74 v1(141.04,115.87) 141.04,115.08 140.49,114.53 131.55,114.53 131.35,114.73 129.91,114.73 129.52,114.35 129.52,114.34 129.14,113.96 v1(129.14,113.95) ; v3(126.22,22.04) 126.47,22.04 126.75,22.33 129.81,22.33 R791.1 ; 46.08,8.41 v5(46.09,8.43) ; 46.08,8.41 46.08,9.73 45.37,10.44 R802.2 ; 46.08,8.41 46.08,8.24 46.41,7.91 R806.1 ; v1(39.9,142.85) 39.58,142.53 39.58,138.39 41.01,136.96 41.86,136.96 v1(41.93,136.89) ; v1(34.58,170.43) 35.24,171.09 ; 35.24,171.09 36.96,171.09 v1(37.63,170.43) ; v3(161.96,141.73) 161.58,141.73 159.77,139.93 159.77,132.64 v1(157.97,130.84)
  BOTTOM w0.635: 105.58,220.52 107.47,220.52 107.97,221.02 112.04,221.02 112.49,221.47 R520.1 ; v5(66.66,199.87) 66.66,199.59 66.52,199.45 66.52,197.23 69.6,194.15 R573.1
  BOTTOM w1.27: v5(47.35,20.73) 47.18,20.55 47.18,20.43 46.47,19.73 42.13,19.73 R811.1
  vias: v1(87.66,226.29) v1(169.78,86.23) v2(136.02,212.67) v2(164.31,199.67) v2(171.36,88.44) v2(176.84,140.72) v4(19.59,187.28) v4(21.57,146.69) v4(22.51,191.64) v4(26.23,170.66) v5(11.51,216.31) v5(12.73,216.28) v5(16.58,222.09) v5(16.96,188.41) v5(17.74,222.05) v5(17.66,187.08) v5(19.73,175.62) v5(19.73,174.33) v5(19.72,172.14) v5(19.77,173.18) v5(84.21,226.03) v5(86.23,226.03) v5(100.85,54.74) v5(100.85,53.72) v5(100.85,52.73) v5(100.87,51.69) v5(102.09,54.71) v5(102.06,53.72) v5(102.06,52.7) v5(102.14,51.69) v5(153.78,217.42) v5(154.44,216.64) v5(155.1,215.82) v5(155.84,215.01) v5(157.89,90.81) v5(158.38,89.92) v5(158.99,90.68) v5(159.21,89.41) v5(169.91,87.15) v5(170.62,86.21) v5(170.83,87.18) v5(171.03,151.69)
SB3V_D: length 3.1
  BOTTOM w0.305: Q45.6 87.69,224.23 R513.2 87.46,224.26 86.65,225.07 v2(86.47,225.07)
SB5V: length 760.9
  TOP w0.203: U15.4 103.18,57.18
  TOP w0.305: v1(144.99,113.19) 143.68,114.5 139.51,114.5 139.01,115.01 135.69,115.01 133.55,117.15 124.75,117.15 124.38,116.77 R226.1 ; R485.1 44.79,15.37 45.25,14.91 46.48,14.91 46.9,15.32 46.9,15.72 v3(48.6,17.42)
  TOP w0.381: v1(101.76,57.33) 101.79,57.3 103.06,57.3 103.18,57.18
  TOP w0.508: v5(134.04,8.76) 134.26,8.98 R501.1 135.24,8.96 R503.1 ; PU1.6 26.31,187.31 PC26.1 26.2,186.69 24.39,184.89 23.17,184.89 v1(23.15,184.91) ; v5(65.82,215.85) 65.82,213.44 65.18,212.8 64.75,212.8 62.31,210.36 57.54,210.36 PR16.1 57.43,213.88 PR10.1 57.18,214.12 v1(56.68,214.63) ; PR81.2 157.7,133.29 v1(158.55,132.44) 158.68,132.31 158.68,131.11 159.98,129.82 159.98,129.13 161.63,127.48 164.79,127.48 v1(171.96,134.66) ; PR2.2 66.31,220.94 63.94,223.32 40.7,223.32 39.25,221.87 39.25,218.85 v1(38.62,218.21)
  TOP w0.635: v5(65.82,215.85) 65.82,217.37 PR2.2
  TOP w1.27: v5(173.75,148.38) 173.75,153.2 165.61,161.35 v5(165.61,195.68)
  L3 w0.635: v5(89.03,219.42) 89.03,218.57 85.6,215.14 85.6,206.48 77.98,198.86 75.17,198.86 75.15,198.84 74.54,198.84 73.95,199.44 73.95,203.15 70.59,206.5 70.59,207.6 69.37,208.82 66.99,208.82 65.82,209.98 v5(65.82,215.85)
  L3 w1.27: v5(25.28,13.02) 25.28,8.79 29.88,4.19 48.42,4.19 v5(48.6,4.37) ; v5(134.04,8.76) 134.04,7.81 131.39,5.16 94.09,5.16 v5(90.58,8.67)
  L3 w2.54: 106.46,70.73 106.59,70.87 125.33,70.87 125.47,70.73 134.86,70.73 135.06,70.94 135.25,70.94 137.02,72.71 137.24,72.71 139.02,74.49 141.6,74.49 151.14,84.02
  L4 w0.305: v5(48.6,4.37) 48.6,5.92 49.2,6.53 49.2,13.77 48.29,14.68 48.29,16.87 48.6,17.17 v3(48.6,17.42)
  L4 w0.508: v1(38.62,218.21) 37.93,217.53 34.73,217.53 31.53,214.33 29.93,214.33 28.53,212.93 28.53,202.77 28.2,202.44 28.2,202.13 25.2,199.14 25.2,185.6 24.52,184.91 v1(23.15,184.91)
  L4 w1.016: 105.01,225.65 133.38,225.65 138.34,220.69 153.16,220.69 165.61,208.24 v5(165.61,195.68) ; 105.01,225.65 97.04,225.65 94.23,222.85 90.4,222.85 89.19,221.64 89.19,219.58 v5(89.03,219.42) ; 105.01,225.65 105.03,225.63 v1(105.03,222.5)
  L4 w1.27: v5(134.04,8.76) 134.04,10.57 145.93,22.45 145.93,26.63 150.77,31.47 150.77,33.16 152.51,34.9 152.51,37.37 154.49,39.35 154.49,40.87 v1(154.47,40.89) 154.95,41.38 154.95,43.61 154.06,44.5 154.06,49.37 152.17,51.26 152.17,54.9 152.1,54.97 152.1,59.04 158.45,65.39 158.45,82.08 160.99,84.62 v1(160.99,84.63) 161,84.63 168.51,92.14 v5(168.74,92.14)
  BOTTOM w0.203: PU13.9 56.84,214.46 v1(56.68,214.63) ; PU13.33 64.27,213.66 64.72,214.12 65.21,214.12 65.74,214.66 v2(65.74,214.73) ; U29.4 104.12,222.1 104.52,222.5 v1(105.03,222.5)
  BOTTOM w0.508: v5(65.82,215.85) 65.82,215.77 65.84,215.75 65.84,214.83 v2(65.74,214.73) ; v1(160.99,84.63) 160.99,85.52 156.29,90.22 156.29,97.72 153.94,100.07 153.94,110.91 151.66,113.19 v1(144.99,113.19) ; v1(154.47,40.89) 153.91,41.45 R757.2 ; PR212.2 157.9,133.09 v1(158.55,132.44)
  BOTTOM w1.27: v5(48.6,4.37) 50.22,2.74 86.3,2.74 87.23,3.67 87.23,6.96 88.94,8.67 v5(90.58,8.67) ; v5(173.75,148.38) 173.75,141.46 171.96,139.67 v1(171.96,134.66) 171.96,134.39 172.83,133.52 172.83,129.82 167.65,124.64 167.65,120.4 166.15,118.89 166.15,102.87 167.11,101.9 167.11,94.76
  vias: v2(95.18,56.11) v2(167.18,91.79) v4(89.31,35.43) v4(103.16,61.24) v5(89.54,48.67) v5(89.64,42.75) v5(90.6,48.72) v5(90.58,42.75) v5(99.85,67.35) v5(100.31,63.91) v5(100.29,62.84) v5(100.31,61.7) v5(100.36,60.2) v5(100.86,67.31) v5(101.48,63.93) v5(101.58,62.87) v5(101.63,61.72) v5(101.56,60.22) v5(101.91,66.87) v5(157.82,96.75) v5(157.79,95.73) v5(157.82,94.69) v5(158.1,93.62) v5(167.77,93.05) v5(168.64,94.34) v5(168.65,93.4)
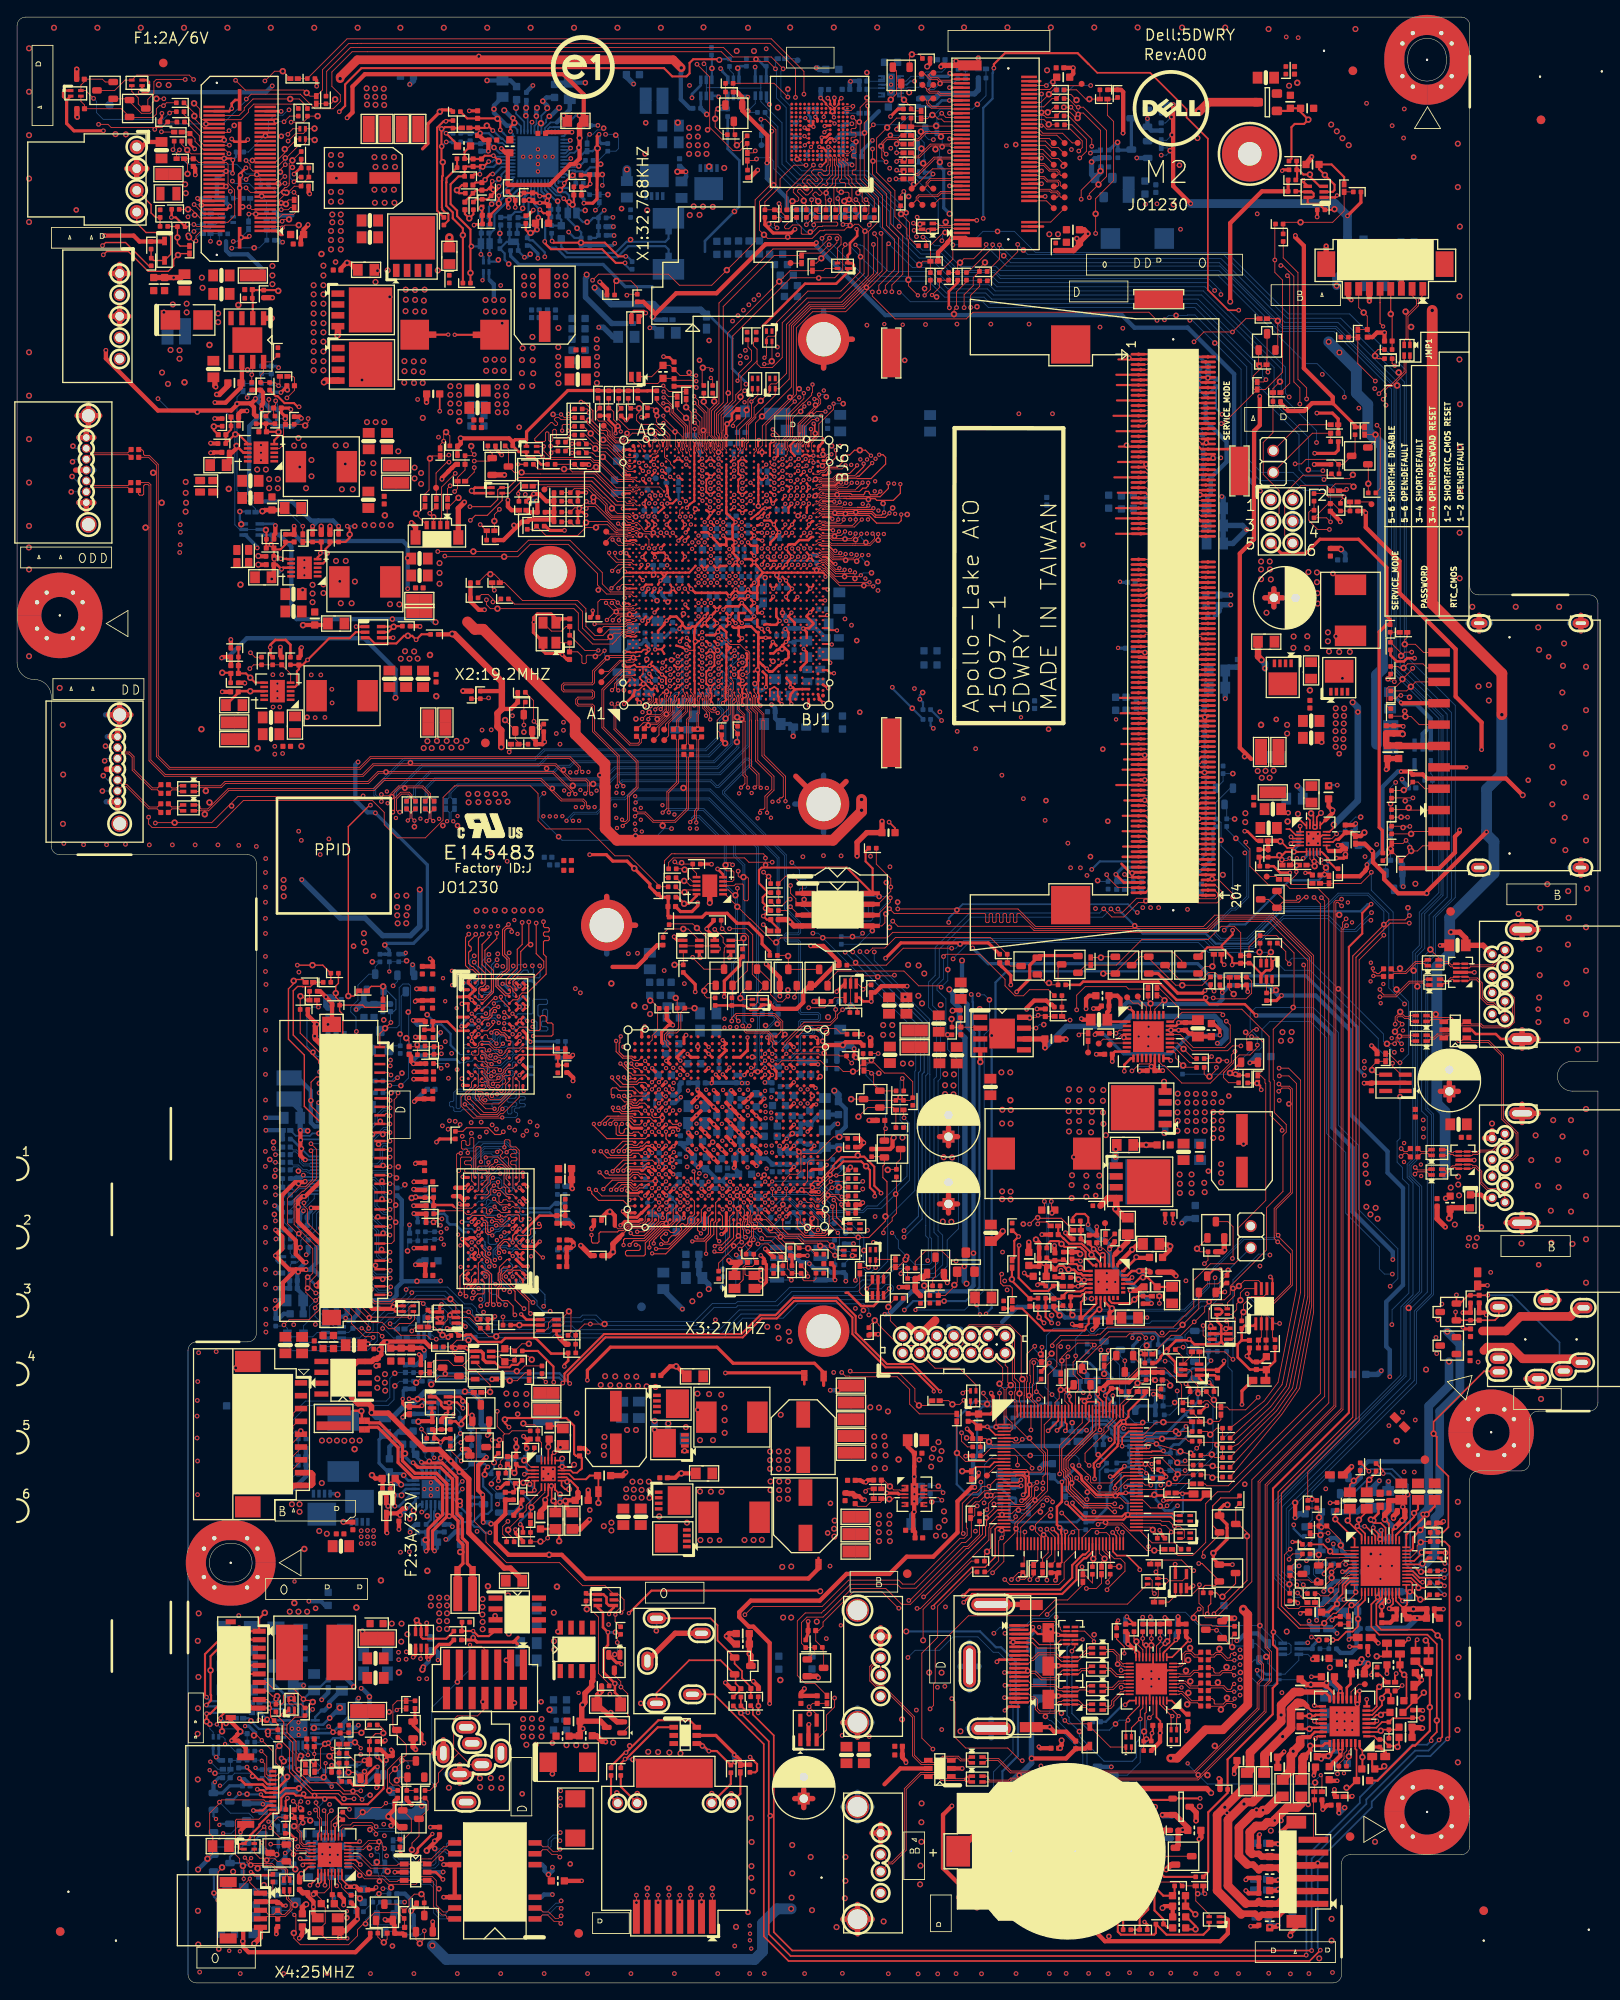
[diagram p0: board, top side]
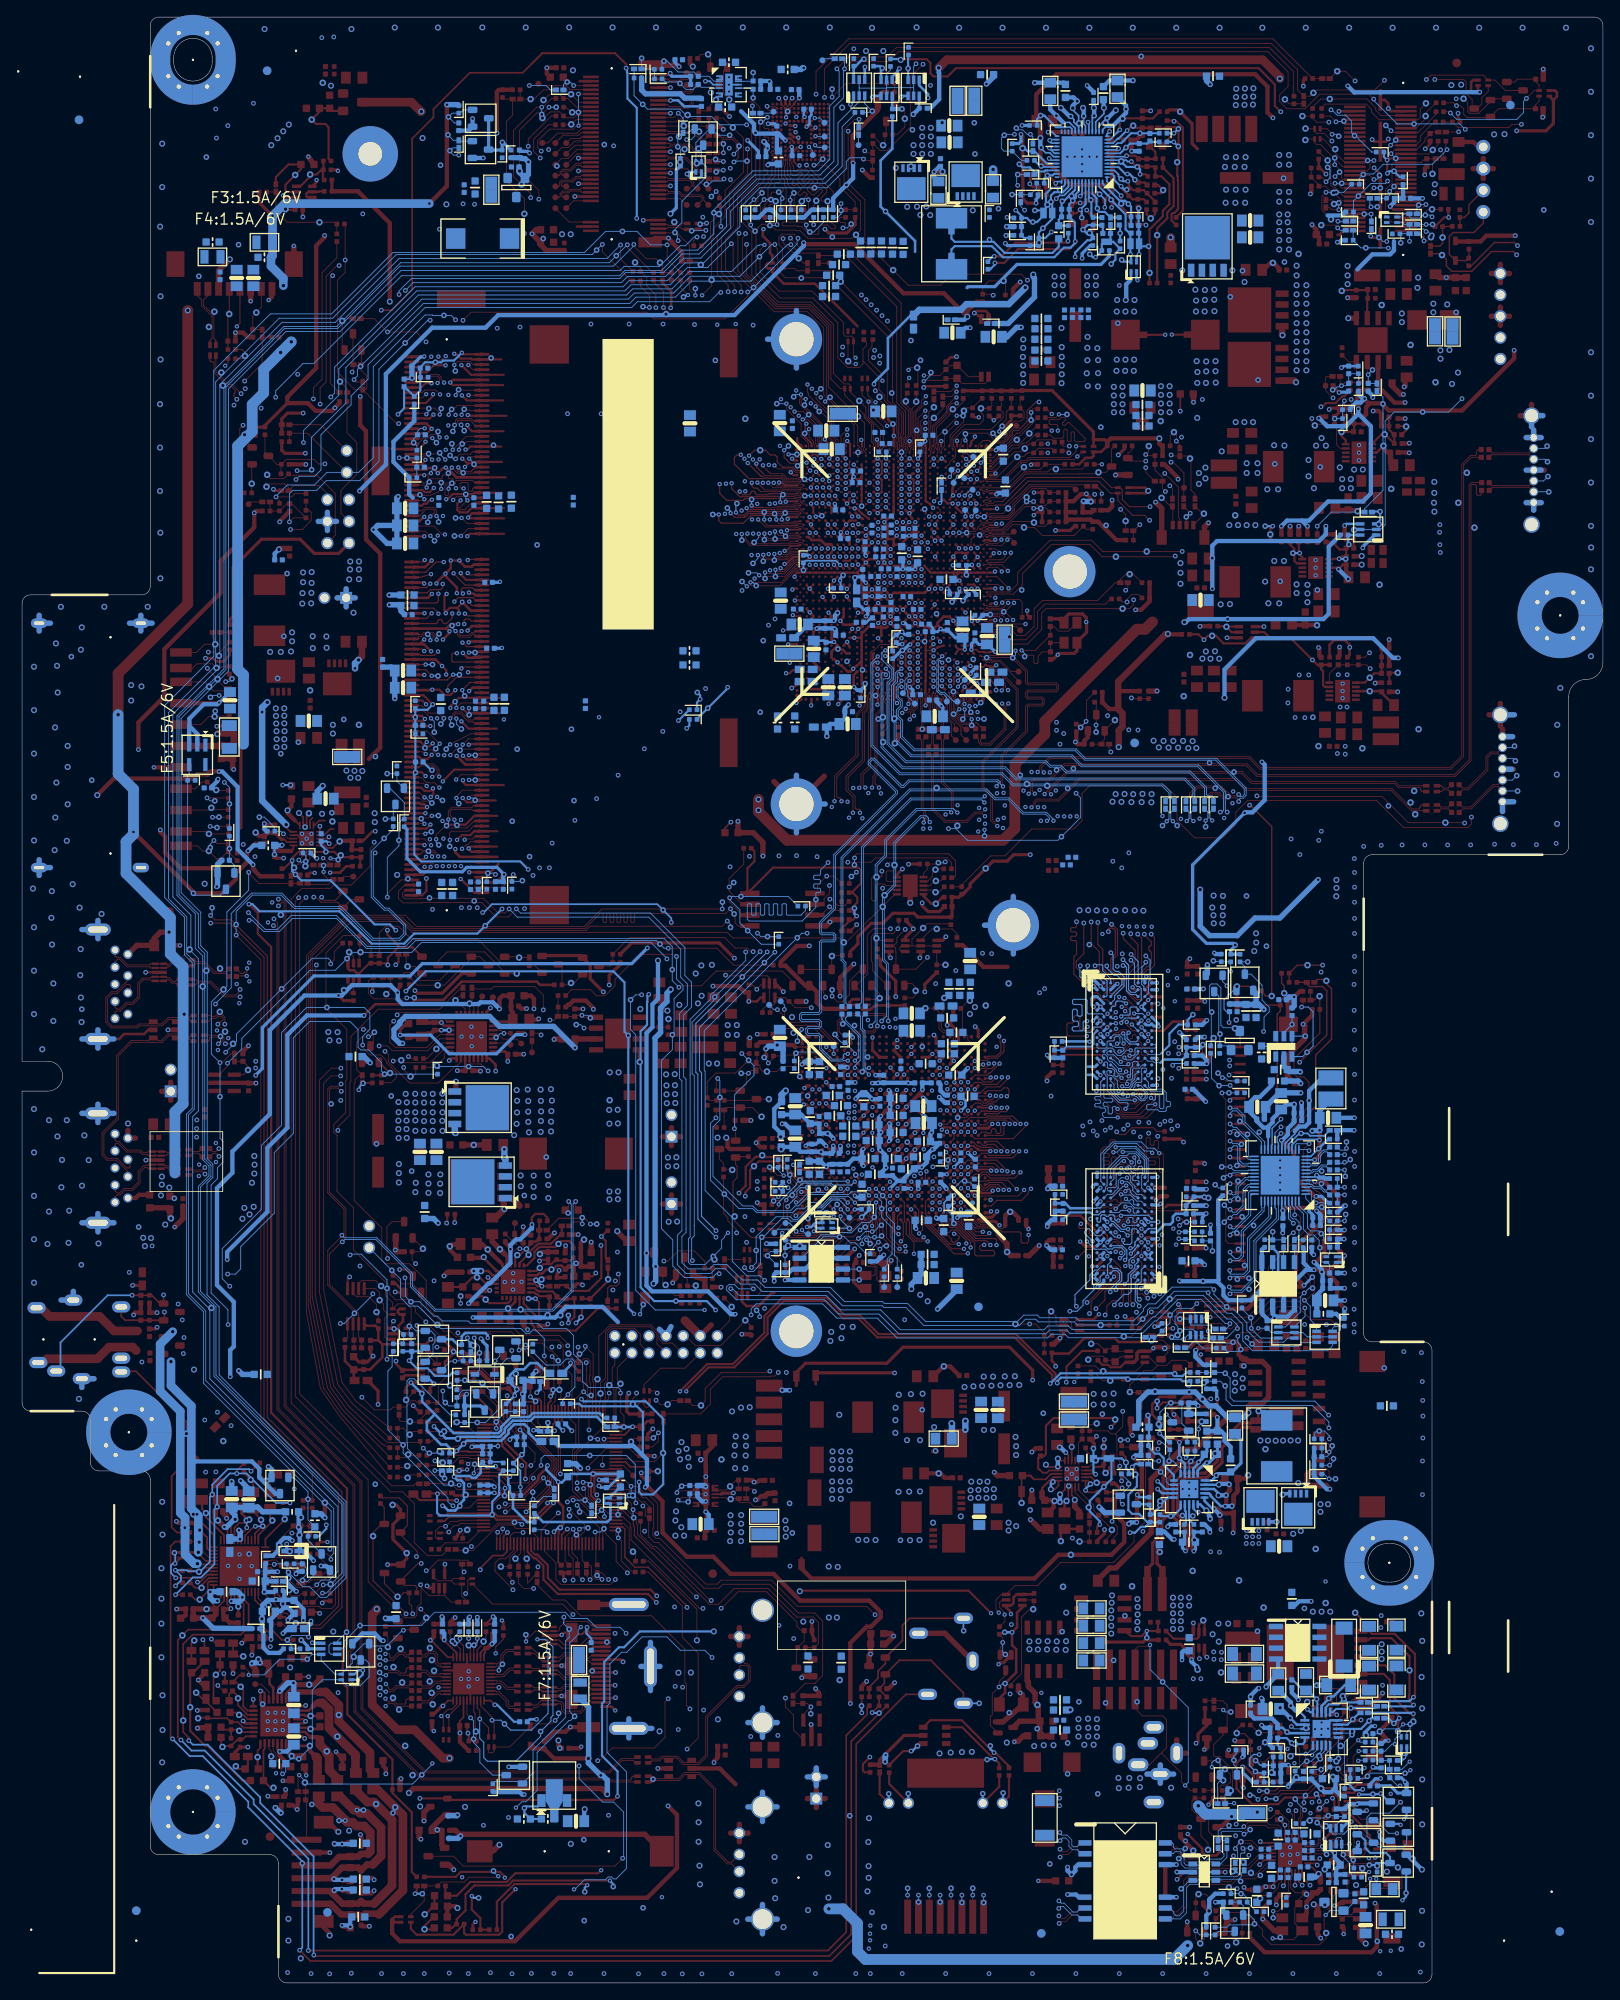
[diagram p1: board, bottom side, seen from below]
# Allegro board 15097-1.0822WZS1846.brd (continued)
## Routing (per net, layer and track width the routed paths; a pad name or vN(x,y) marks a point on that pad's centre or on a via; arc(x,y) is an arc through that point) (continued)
SD_CD_BD: length 8.3
  TOP w0.102: R200.1 160.86,132.34 R195.2 161.96,131.34 R196.1 162.01,131.31 v4(163.14,132.44) 163.88,132.44 164.47,133.03 MEMCD1.11
SD_CD_BD_CPU: length 169
  TOP w0.102: v1(162.54,133.67) 162.19,133.32 R195.1 ; CPU1.AB54 v3(81.13,174.81)
  L4 w0.089: v3(81.13,174.81) 80.58,175.36 80.58,175.7 80.57,175.71 80.57,177.78 80.55,177.8 80.55,178.91 80.24,179.23 79.68,179.79 79.68,180.55 79.31,180.92 79.05,180.92 78.24,181.73
  L4 w0.127: 78.24,181.73 78.24,188.65 78.35,188.76 78.35,188.79 78.57,189.01 78.58,189.01 78.87,189.3 78.87,189.64 82.61,193.38 82.61,194.09 86.83,198.3 87.46,198.3 92.03,202.87 92.11,202.87 143.39,202.87 152.48,193.79 152.48,191.55 163.73,180.29 163.73,156.15 164.09,155.79 164.09,134.77 162.99,133.67 v1(162.54,133.67)
  BOTTOM w0.102: v1(162.54,133.67) 162.97,133.24 v2(162.97,132.84)
SD_CLK_BD: length 6.1
  TOP w0.102: MEMCD1.5 164.07,147.22 163.13,148.16 v4(162.46,148.16) 162.42,148.21 R180.2
SD_CLK_BD_CPU: length 165
  TOP w0.102: CPU1.AB58 81.18,177.61 v3(81.18,177.61) ; v1(163.31,153.81) 163.31,153.73 v4(162.12,152.54) 162.12,152.46 162.11,152.45 162.11,152.4 161.38,151.67 160.51,151.67 160.29,151.45 160.29,149.4 160.59,149.1 R180.1
  L4 w0.089: 79.92,180.95 80.07,180.79 80.07,180.03 81.51,178.59 81.51,178.04 81.18,177.71 v3(81.18,177.61)
  L4 w0.127: 79.92,180.95 79.46,181.41 79.13,181.41 78.83,181.71 78.83,188.31 79.94,189.43 80.1,189.43 92.53,201.86 141.87,201.86 150.02,193.7 150.02,192.92 150.02,192.92 150.02,192.57 158.14,184.45 158.14,182.31 158.01,182.18 157.04,182.18 156.92,182.31 156.92,183.6 156.79,183.72 156.41,183.72 156.28,183.6 156.28,181.9 156.64,181.55 158.01,181.55 158.5,181.06 158.5,180.88 157.35,179.73 157.35,179.55 157.62,179.28 157.8,179.28 158.95,180.43 159.13,180.43 159.4,180.16 159.4,179.98 158.26,178.85 158.26,178.67 158.53,178.4 158.71,178.4 159.84,179.53 160.02,179.53 160.29,179.27 160.29,179.09 159.11,177.9 159.11,177.72 159.37,177.45 159.55,177.45 160.74,178.64 160.92,178.64 161.19,178.37 161.19,178.19 160.08,177.07 160.08,176.89 160.35,176.62 160.53,176.62 161.64,177.74 161.82,177.74 162.6,176.96 162.6,154.53 v1(163.31,153.81)
SD_CMD_BD: length 6.3
  TOP w0.102: R186.2 162.22,139.51 v4(162.28,139.57) 162.39,139.57 R185.2 163.94,140.5 164.72,139.72 MEMCD1.2
SD_CMD_BD_CPU: length 165.2
  TOP w0.102: CPU1.AC52 v3(82.08,174.81) ; v1(163.35,138.65) 160.87,138.65 R186.1
  L4 w0.089: 81.41,181.38 81.53,181.26 81.53,180.29 81.55,180.28 82.47,179.36 82.47,175.2 v3(82.08,174.81)
  L4 w0.127: v1(163.35,138.65) 163.35,139.31 163.53,139.49 163.53,152.5 162.09,153.94 162.09,174.52 161.86,174.75 161.32,174.75 160.98,175.09 160.98,175.27 162.09,176.38 162.09,176.65 161.87,176.87 161.69,176.87 160.53,175.72 160.35,175.72 156.47,179.6 156.47,179.78 157.31,180.61 157.31,180.79 157.06,181.04 156.84,181.04 156.02,180.23 155.84,180.23 155.57,180.5 155.57,183.7 156.42,184.55 156.42,184.73 156.07,185.08 155.9,185.08 155.5,184.68 155.12,184.68 154.06,185.74 154.06,185.92 154.53,186.4 154.53,186.58 154.26,186.85 154.08,186.85 153.61,186.37 153.43,186.37 153.16,186.64 153.16,186.82 153.55,187.22 153.55,187.39 153.28,187.66 153.11,187.66 152.71,187.27 152.53,187.27 148.5,191.3 148.5,192.65 148.5,193.07 141.23,200.33 93.17,200.33 82.87,190.03 82.87,188.8 81.41,187.35 81.41,181.38
  BOTTOM w0.102: v2(162.44,138.3) 163,138.3 v1(163.35,138.65)
SD_DATA0_BD: length 6.1
  TOP w0.102: MEMCD1.7 163.67,152.22 v4(163.11,151.66) 162.61,151.17 R178.2
SD_DATA0_CPU: length 166.2
  TOP w0.102: v1(161.94,150.63) 161.72,150.63 161.36,150.28 R178.1 ; v3(82.08,172.68) 82.42,173.02 CPU1.AC49
  L4 w0.089: v3(82.08,172.68) 83,173.6 83,174.52 83,174.52 83,179.58 83,179.58 82.95,179.63 82.44,180.15 82.27,180.31 82.27,180.41
  L4 w0.127: 82.27,180.41 82.27,186.9 84.19,188.82 85.19,188.82 86.18,189.81 86.18,191.41 86.18,191.41 86.18,191.69 93.65,199.16 103.3,199.16 103.77,198.7 114.37,198.7 115.28,197.79 125.97,197.79 127.35,199.16 129.07,199.16 129.19,199.04 129.19,197.34 129.32,197.21 129.7,197.21 129.83,197.34 129.83,199.04 129.96,199.16 130.34,199.16 130.46,199.04 130.46,197.34 130.59,197.21 130.97,197.21 131.1,197.34 131.1,199.04 131.23,199.16 131.61,199.16 131.73,199.04 131.73,197.34 131.86,197.21 132.24,197.21 132.37,197.34 132.37,199.04 132.5,199.16 132.88,199.16 133,199.04 133,197.34 133.13,197.21 133.51,197.21 133.64,197.34 133.64,199.04 133.77,199.16 134.15,199.16 134.27,199.04 134.27,197.34 134.4,197.21 134.78,197.21 134.91,197.34 134.91,199.04 135.04,199.16 135.42,199.16 135.54,199.04 135.54,197.34 135.67,197.21 136.05,197.21 136.18,197.34 136.18,199.04 136.31,199.16 136.69,199.16 136.81,199.04 136.81,197.34 136.94,197.21 137.32,197.21 137.45,197.34 137.45,199.04 137.58,199.16 140.75,199.16 147.3,192.61 147.3,192.34 147.3,190.85 153.64,184.51 153.64,180.27 160.7,173.21 160.7,153.42 161.94,152.18 v1(161.94,150.63)
  BOTTOM w0.102: v2(162.95,150.42) 162.74,150.63 v1(161.94,150.63)
SD_DATA1_BD: length 6.1
  TOP w0.102: MEMCD1.8 165.01,153.85 164.52,154.34 162.73,154.34 v4(162.25,153.85) 161.78,153.85 161.6,154.03 R176.2
SD_DATA1_CPU: length 166.1
  TOP w0.102: v3(82.08,171.97) 82.14,171.97 CPU1.AC48 ; R176.1 160.74,152.63 161.12,152.25 v1(161.17,152.25)
  L4 w0.089: 82.96,179.99 83.18,179.77 83.18,173.98 83.18,173.98 83.18,173.52 83.18,173.52 83.18,173.06 82.28,172.16 v3(82.08,171.97)
  L4 w0.127: 82.96,179.99 82.51,180.44 82.51,186.83 84.27,188.59 85.43,188.59 86.51,189.68 86.51,191.55 93.79,198.83 103.16,198.83 103.64,198.36 113.76,198.36 115.37,196.75 115.76,196.75 115.89,196.88 115.89,197.33 116.02,197.46 116.4,197.46 116.52,197.33 116.52,196.88 116.65,196.75 117.03,196.75 117.16,196.88 117.16,197.33 117.29,197.46 117.67,197.46 117.79,197.33 117.79,196.88 117.92,196.75 118.3,196.75 118.43,196.88 118.43,197.33 118.56,197.46 118.94,197.46 119.06,197.33 119.06,196.88 119.19,196.75 119.57,196.75 119.7,196.88 119.7,197.33 119.83,197.46 120.21,197.46 120.33,197.33 120.33,196.88 120.46,196.75 120.84,196.75 120.97,196.88 120.97,197.33 121.1,197.46 121.48,197.46 121.6,197.33 121.6,196.88 121.73,196.75 122.11,196.75 122.24,196.88 122.24,197.33 122.37,197.46 122.75,197.46 122.87,197.33 122.87,196.88 123,196.75 123.38,196.75 123.51,196.88 123.51,197.33 123.64,197.46 124.02,197.46 124.14,197.33 124.14,196.88 124.27,196.75 124.65,196.75 124.78,196.88 124.78,197.33 124.91,197.46 125.29,197.46 125.41,197.33 125.41,196.88 125.54,196.75 125.92,196.75 126.05,196.88 126.05,197.33 126.18,197.46 126.56,197.46 126.68,197.33 126.68,196.88 126.81,196.75 127.19,196.75 127.32,196.88 127.32,198.63 127.45,198.76 127.83,198.76 127.95,198.63 127.95,198.3 128.08,198.18 128.74,198.18 128.86,198.05 128.86,197.67 128.74,197.54 128.08,197.54 127.95,197.41 127.95,196.88 128.08,196.75 137.64,196.75 137.87,196.98 138.05,196.98 138.65,196.39 139,196.39 139.65,197.03 139.65,197.21 139.38,197.48 139.2,197.48 138.91,197.2 138.73,197.2 138.5,197.43 138.5,197.61 139.6,198.71 140.74,198.71 146.97,192.48 146.97,190.71 147.84,189.84 147.84,189.66 146.98,188.81 146.98,188.63 147.25,188.36 147.43,188.36 148.29,189.21 148.47,189.21 148.73,188.95 148.73,188.77 147.88,187.91 147.88,187.73 148.15,187.46 148.33,187.46 149.18,188.32 149.36,188.32 149.63,188.05 149.63,187.87 148.78,187.01 148.78,186.83 149.05,186.56 149.23,186.56 150.08,187.42 150.26,187.42 150.78,186.9 150.78,186.72 150.61,186.56 150.61,186.38 150.88,186.11 151.06,186.11 151.23,186.27 151.41,186.27 153.24,184.44 153.24,180.2 160.36,173.08 160.36,153.05 v1(161.17,152.25)
  BOTTOM w0.102: v1(161.17,152.25) 160.76,152.25 v2(160.43,152.58)
SD_DATA2_BD: length 5.7
  TOP w0.102: R192.2 160.86,134.44 v4(163.13,134.44) 163.22,134.44 163.51,134.72 MEMCD1.9
SD_DATA2_CPU: length 165.1
  TOP w0.102: CPU1.AC51 v3(82.08,174.1) ; R192.1 162.96,135.33 v1(162.99,135.31)
  L4 w0.089: v3(82.08,174.1) 82.64,174.67 82.64,179.43 81.72,180.35 81.72,181.36
  L4 w0.127: v1(162.99,135.31) 163.18,135.51 163.18,136.98 162.84,137.32 162.84,139.78 163.02,139.95 163.02,152.29 161.58,153.73 161.58,173.32 154.3,180.6 154.3,184.78 147.99,191.09 147.99,192.86 141.02,199.82 117.81,199.82 117.68,199.7 117.68,198.85 117.55,198.72 117.17,198.72 117.04,198.85 117.04,199.7 116.92,199.82 116.54,199.82 116.41,199.7 116.41,198.85 116.28,198.72 115.9,198.72 115.77,198.85 115.77,199.7 115.65,199.82 113.87,199.82 113.75,199.7 113.75,199.49 113.62,199.36 113.24,199.36 113.11,199.49 113.11,199.7 112.99,199.82 112.6,199.82 112.48,199.7 112.48,199.49 112.35,199.36 111.97,199.36 111.84,199.49 111.84,199.7 111.72,199.82 111.33,199.82 111.21,199.7 111.21,199.49 111.08,199.36 110.7,199.36 110.57,199.49 110.57,199.7 110.45,199.82 110.06,199.82 109.94,199.7 109.94,199.49 109.81,199.36 109.43,199.36 109.3,199.49 109.3,199.7 109.18,199.82 108.79,199.82 108.67,199.7 108.67,199.49 108.54,199.36 108.16,199.36 108.03,199.49 108.03,199.7 107.91,199.82 107.52,199.82 107.4,199.7 107.4,199.49 107.27,199.36 106.89,199.36 106.76,199.49 106.76,199.7 106.64,199.82 106.25,199.82 106.13,199.7 106.13,199.49 106,199.36 105.62,199.36 105.49,199.49 105.49,199.7 105.37,199.82 104.98,199.82 104.86,199.7 104.86,199.49 104.73,199.36 104.35,199.36 104.22,199.49 104.22,199.7 104.1,199.82 93.38,199.82 83.4,189.84 83.4,188.87 81.72,187.2 81.72,181.36
  BOTTOM w0.102: v2(162.19,135.18) 162.85,135.18 v1(162.99,135.31)
SD_DATA3_BD: length 5.8
  TOP w0.102: R191.2 162.64,137.28 v4(162.85,137.49) 163.12,137.22 MEMCD1.1
SD_DATA3_CPU: length 166.9
  TOP w0.102: R191.1 v1(162.71,136.39) ; CPU1.AB51 v3(82.08,173.39)
  L4 w0.089: 82.01,181.36 82.01,180.32 82.31,180.02 82.82,179.51 82.82,174.59 82.82,174.59 82.82,174.13 v3(82.08,173.39)
  L4 w0.127: 82.01,181.36 82.01,186.95 84.11,189.05 84.95,189.05 85.85,189.95 85.85,191.28 85.85,191.28 85.85,191.55 85.85,191.82 93.52,199.49 103.44,199.49 103.9,199.03 114.6,199.03 115.39,198.24 118.91,198.24 119.15,198.48 119.15,199.26 119.38,199.49 119.95,199.49 120.07,199.37 120.07,198.38 120.2,198.25 120.58,198.25 120.71,198.38 120.71,199.37 120.84,199.49 121.22,199.49 121.34,199.37 121.34,198.32 121.47,198.19 121.85,198.19 121.98,198.32 121.98,199.37 122.11,199.49 122.49,199.49 122.61,199.37 122.61,198.26 122.74,198.14 123.12,198.14 123.25,198.26 123.25,199.37 123.38,199.49 123.76,199.49 123.88,199.37 123.88,198.49 124.01,198.36 124.39,198.36 124.52,198.49 124.52,199.37 124.65,199.49 125.03,199.49 125.15,199.37 125.15,198.65 125.28,198.52 125.66,198.52 125.79,198.65 125.79,199.37 125.92,199.49 140.89,199.49 147.63,192.75 147.63,192.2 147.63,190.98 153.97,184.65 153.97,180.46 161.03,173.41 161.03,153.59 162.69,151.93 162.69,140.67 162.51,140.5 162.51,136.59 v1(162.71,136.39)
  BOTTOM w0.102: v2(161.96,136.4) 161.97,136.39 162.71,136.39 v1(162.71,136.39)
SD_PWR_EN: length 19.6
  BOTTOM w0.102: Q81.C 161.83,127.25 164.73,127.25 v2(164.96,127.48) 165.63,128.15 R815.2 165.63,141.29 165.44,141.48 U39.4
SD_PWR_EN_CPU#: length 122.6
  TOP w0.102: v3(78.27,173.35) 77.89,173.73 CPU1.P51
  L4 w0.127: v3(78.27,173.35) 78.52,173.35 79.41,172.47 80.04,172.47 81.06,171.45 82.84,171.45 83.35,170.94 83.35,170.31 83.6,170.05 83.6,168.28 85.25,166.62 85.25,164.08 86.14,163.19 86.14,162.05 85.63,161.54 85.63,159.89 86.39,159.13 88.17,159.13 89.44,157.86 91.85,157.86 94.7,155.02 97.49,155.02 101.51,151 102.22,151 109.1,144.12 109.33,144.12 122.28,131.17 141.08,131.17 142.86,129.39 158.71,129.39 160.74,131.42 160.74,139.88 v1(161.32,140.46)
  BOTTOM w0.102: R814.2 v2(160.73,137.95) 160.73,139.36 160.73,139.37 160.73,139.37 160.73,139.87 v1(161.32,140.46)
SD_PWR_EN_CPU#_R: length 4.6
  BOTTOM w0.102: Q81.B 160.15,130.77 C568.1 160.74,132.41 160.73,132.42 v2(160.73,132.72) R814.1
SD_WP_BD: length 5.9
  TOP w0.102: MEMCD1.10 164.59,155.66 163.63,156.62 v4(162.39,156.62) 162.39,157.14 162.68,157.43 R175.2
SD_WP_BD_CPU: length 166.6
  TOP w0.102: v1(163.2,155.7) 162.39,155.7 v4(161.96,155.27) 161.96,155.61 R2002.1 160.71,158 R2001.2 161.78,158.03 R175.1 ; CPU1.AB55 v3(81.13,175.52)
  L4 w0.089: 78.52,182.11 78.52,181.74 79.13,181.13 79.36,181.13 79.9,180.59 79.9,179.82 80.74,178.98 80.74,177.89 80.78,177.85 80.78,175.87 v3(81.13,175.52)
  L4 w0.127: v1(163.2,155.7) 163.23,155.72 163.23,177.46 163.1,177.59 162.69,177.59 162.56,177.71 162.56,178.1 162.69,178.22 163.1,178.22 163.23,178.35 163.23,178.73 163.1,178.86 162.69,178.86 162.56,178.98 162.56,179.37 162.69,179.49 163.1,179.49 163.23,179.62 163.23,180.08 162.5,180.81 162.32,180.81 161.22,179.7 161.04,179.7 160.77,179.97 160.77,180.15 161.87,181.25 161.87,181.43 161.6,181.7 161.42,181.7 160.32,180.6 160.14,180.6 159.87,180.87 159.87,181.05 160.98,182.15 160.98,182.33 160.65,182.66 160.47,182.66 160.01,182.19 159.83,182.19 159.56,182.46 159.56,182.64 160.02,183.1 160.02,183.28 159.75,183.55 159.58,183.55 159.11,183.09 158.93,183.09 158.66,183.36 158.66,183.54 159.13,184 159.13,184.18 152.18,191.12 152.18,191.13 151.97,191.34 151.97,192.07 151.84,192.2 151.42,192.2 151.29,192.32 151.29,192.7 151.42,192.83 151.84,192.83 151.97,192.96 151.97,193.3 151.1,194.18 150.92,194.18 150.68,193.94 150.5,193.94 150.23,194.21 150.23,194.39 150.47,194.63 150.47,194.81 150.2,195.07 150.02,195.07 149.78,194.84 149.6,194.84 149.33,195.11 149.33,195.29 149.57,195.52 149.57,195.7 149.3,195.97 149.12,195.97 148.88,195.74 148.7,195.74 148.43,196.01 148.43,196.19 148.67,196.42 148.67,196.6 148.4,196.87 148.22,196.87 147.99,196.63 147.81,196.63 147.54,196.9 147.54,197.08 147.77,197.32 147.77,197.5 147.5,197.77 147.32,197.77 147.09,197.53 146.91,197.53 146.64,197.8 146.64,197.98 146.87,198.22 146.87,198.4 146.61,198.67 146.43,198.67 146.19,198.43 146.01,198.43 145.74,198.7 145.74,198.88 145.98,199.12 145.98,199.3 145.71,199.57 145.53,199.57 145.29,199.33 145.11,199.33 144.84,199.6 144.84,199.78 145.08,200.01 145.08,200.19 144.81,200.46 144.63,200.46 144.39,200.23 144.21,200.23 143.94,200.5 143.94,200.68 144.18,200.91 144.18,201.09 143.91,201.36 143.73,201.36 143.49,201.13 143.31,201.13 143.05,201.39 143.05,201.57 143.28,201.81 143.28,201.99 142.91,202.36 92.32,202.36 78.52,188.56 78.52,182.11
SENSE_B: length 5
  TOP w0.102: R389.2 R391.2 164.35,51.64 v4(164.27,51.56) 163.84,51.13 163.84,50.5 163.11,49.77 U16.33
SER_IRQ: length 33.5
  TOP w0.102: R338.2 137.48,73.45 U13.4 136.45,73.2 R337.2 135.82,74.38 v1(136.45,74.38) ; v1(119.09,74.49) 118.17,73.57 118.17,70.92 118.22,70.87 118.22,70.41 118.12,70.3 118.12,68.49 118.25,68.36 U14.125
  L3 w0.127: v1(136.45,74.38) 135.33,73.26 134.07,73.26 133.79,72.98 131.97,72.98 131.31,72.32 126.12,72.32 125.99,72.45 125.46,72.45 124.07,73.84 119.74,73.84 v1(119.09,74.49)
  BOTTOM w0.102: v1(119.09,74.49) 119.1,74.49 119.1,74.1 119.62,73.58 v2(119.76,73.58)
SIDE_USB3_RX0+: length 11.2
  TOP w0.102: L5.3 166.79,117.43 167.04,117.18 167.33,117.18 167.75,117.6 168.03,117.6 168.14,117.72 U4.9 U4.2 169.82,117.72 169.96,117.58 170.87,117.58 171.46,116.99 171.46,115.34 172.12,114.68 172.83,114.68 173.59,113.92 173.87,113.92 174.12,114.17 SSUSB1.6
SIDE_USB3_RX0-: length 11.2
  TOP w0.102: L5.2 166.77,116.75 166.99,116.97 167.42,116.97 167.84,117.39 168.03,117.39 168.18,117.24 U4.10 U4.1 169.84,117.24 169.96,117.36 170.78,117.36 171.24,116.9 171.24,115.25 172.03,114.47 172.74,114.47 173.21,113.99 173.5,113.7 173.99,113.7 174.12,113.58 SSUSB1.5
SIDE_USB3_RX1+: length 10.7
  TOP w0.102: SSUSB2.6 174.12,92.68 173.86,92.42 173.6,92.42 173.07,92.95 172.13,92.95 171.41,93.68 171.41,94.95 170.74,95.61 170.36,95.61 170.23,95.75 U9.2 U9.9 168.39,95.75 168.24,95.6 167.96,95.6 167.33,94.98 167.18,94.98 166.95,95.21 L7.3
SIDE_USB3_RX1-: length 10.6
  TOP w0.102: SSUSB2.5 174.12,91.96 173.87,92.2 173.52,92.2 173.38,92.34 172.98,92.74 172.04,92.74 171.19,93.59 171.19,94.86 170.65,95.4 170.36,95.4 170.23,95.27 U9.1 U9.10 168.44,95.27 168.33,95.38 168.05,95.38 167.42,94.76 167.21,94.76 166.98,94.53 L7.2
SIDE_USB3_TX0+: length 10.9
  TOP w0.102: v4(165.39,120.9) 166.34,119.95 L4.3 166.76,119.7 166.97,119.49 167.47,119.49 167.86,119.1 168,119.1 168.14,119.24 U4.6 U4.5 169.95,119.24 170.09,119.11 172.63,119.11 173.51,119.99 173.95,119.99 174.12,120.16 SSUSB1.9
SIDE_USB3_TX0-: length 9.3
  TOP w0.102: SSUSB1.8 174.12,119.46 173.81,119.77 173.6,119.77 172.72,118.89 170.09,118.89 169.95,118.76 U4.4 U4.7 168.12,118.76 167.99,118.88 167.77,118.88 167.38,119.27 167.02,119.27 166.76,119.01 L4.2
SIDE_USB3_TX1+: length 9
  TOP w0.102: SSUSB2.9 174.12,98.6 173.97,98.45 173.66,98.45 172.65,97.43 171.13,97.43 170.83,97.13 170.36,97.13 170.23,97.27 U9.5 U9.6 168.16,97.27 168.03,97.13 167.86,97.13 167.73,97.26 167.54,97.26 167.3,97.5 L6.3
SIDE_USB3_TX1-: length 9
  TOP w0.102: L6.2 167.3,96.81 167.54,97.05 167.64,97.05 167.77,96.92 168.03,96.92 168.16,96.79 U9.7 U9.4 170.23,96.79 170.36,96.92 170.92,96.92 171.22,97.22 172.74,97.22 173.75,98.23 174,98.23 174.12,98.11 SSUSB2.8
SIO_EUP_EN#: length 38.6
  TOP w0.203: R270.1 145.18,105.3 R271.2 145.5,104.98 145.5,104.62 145.59,104.53 v1(145.59,104.5)
  L3 w0.203: v1(145.59,104.5) 145.59,103.95 145.42,103.78 145.42,91.87 139.61,86.06 139.61,81.93 134.67,77 134.23,77 132.88,75.65 v1(132.88,75.47)
  BOTTOM w0.203: R709.2 132.49,74.85 132.88,75.23 v1(132.88,75.47) ; v2(145.09,105.24) 145.5,104.84 145.5,104.62 145.59,104.53 v1(145.59,104.5)
SIO_EUP_EN#_G: length 4
  TOP w0.203: Q24.G 143.2,107.7 141.99,106.5 141.98,106.5 v4(141.94,106.46) 142.18,106.21 R269.2 142.97,106.19 R270.2
SIO_EUP_EN#_L: length 3.4
  BOTTOM w0.102: R526.1 85.65,218.85 v2(85.5,219) 86.39,219.88 Q45.3
SIO_EUP_EN#_R: length 320.7
  TOP w0.102: PR150.2 57.92,64.59 57.56,64.24 57.06,64.24 ; v1(56.19,66.88) 56.19,65.1 57.06,64.24 ; 57.06,64.24 56.88,64.06 56.88,61.37 56.55,61.04 v1(56.55,60.45) ; v1(144.47,110.71) 144.53,110.65 145.23,110.65 145.84,110.04 145.84,106.83 R271.1 145.51,106.18 146.03,105.66 146.03,105.31 146.13,105.21 146.13,91.55 142.91,88.33 142.91,84.58 142.46,84.14 139.64,84.14 137.7,82.2 137.7,79.13 135.31,76.73 127.59,76.73 126.75,75.9 126.43,75.9 126.33,75.79 125.38,75.79 125.33,75.74 122.08,75.74 121.14,74.8 v1(121.14,74.55) ; PR164.2 57.28,52.04 56.83,52.5 56.83,53.39 v1(57.44,54)
  L3 w0.127: v1(140.15,198.01) 140.15,196.93 144.35,192.72 144.35,169.83 143.59,169.07 143.59,149.21 143.38,149 142.95,148.57 142.95,131.48 143.72,130.71 143.72,116.93 144.48,116.17 144.48,115.78 144.01,115.31 144.01,111.75 144.47,111.3 v1(144.47,110.71) ; v1(95.56,71.42) 95.56,72.29 97.52,74.24 97.52,78.33 v1(98.1,78.92)
  L4 w0.127: v1(56.55,60.45) 57.44,59.56 v1(57.44,54) ; v1(121.14,74.55) 120.84,74.85 120.11,74.85 116.61,78.36 116.6,78.36 116.54,78.42 115.27,78.42 113.48,80.21 106.05,80.21 105.87,80.39 99.09,80.39 98.64,80.85 98.64,82.55 98.33,82.85 97.8,82.85 97.54,82.6 97.54,79.48 v1(98.1,78.92) ; v1(56.19,66.88) 56.42,66.88 56.5,66.8 59.82,66.8 60.28,67.26 60.28,71.7 63,74.42 83.19,74.42 86.11,71.5 95.49,71.5 v1(95.56,71.42)
  BOTTOM w0.102: v1(144.47,110.71) 144.28,110.71 v2(143.77,111.23) ; R526.2 87.53,218.67 89.03,217.17 89.03,212.52 90.99,210.56 98.8,210.56 102.07,207.3 102.07,205.3 105.57,201.81 107.55,201.81 109.71,199.64 114.15,199.64 114.86,198.93 139.23,198.93 v1(140.15,198.01)
SIO_EUP_EN_D: length 298.7
  TOP w0.102: Q24.D 143.9,109.93 143.9,110.79 144.66,111.56 v1(145.05,111.56)
  L3 w0.127: v1(145.05,111.56) 144.52,112.09 144.52,115.1 144.99,115.57 144.99,116.38 144.58,116.79 144.58,116.83 144.37,117.05 144.37,137.97 143.45,138.89 143.45,148.36 143.89,148.79 143.89,148.79 144.1,149 144.1,168.86 144.86,169.62 144.86,192.93 140.88,196.91 v1(140.88,197.54)
  L4 w0.127: v1(80.38,224.54) 79.53,225.39 29.07,225.39 19.76,216.08 19.11,216.08 16.76,213.73 16.76,206.96 16.42,206.62 16.42,185.43 v1(16.49,185.35)
  BOTTOM w0.102: v1(80.38,224.54) 80.66,224.25 Q47.2 80.66,221.72 ; R515.2 83.37,223.83 83.83,223.37 Q46.2 83.83,221.69 ; 83.83,221.69 Q46.5 ; 83.83,221.69 87.01,221.69 87.04,221.72 ; 83.83,221.69 83.77,221.75 80.69,221.75 80.66,221.72 ; 80.66,221.72 Q47.5 ; Q52.5 Q52.2 26.03,170.05 25.48,170.6 25.48,182.73 24.42,183.79 v2(21.09,183.79) 18.05,183.79 v1(16.49,185.35) ; Q45.5 87.04,221.72 ; 87.04,221.72 Q45.2 87.04,220.11 89.51,217.63 89.51,212.79 91.26,211.05 99,211.05 102.55,207.5 102.55,205.5 105.77,202.29 107.75,202.29 109.91,200.13 114.35,200.13 115.06,199.42 139.43,199.42 140.88,197.96 v1(140.88,197.54)
SIO_GPU_EN: length 106.2
  TOP w0.102: R210.1 82.39,123.46 v1(82.51,123.34) 83.07,122.78 85.25,122.78 85.61,122.43 85.61,119.53 85.45,119.38 85.45,118.41 83.74,116.7 Q20.E 83.72,115.32 R241.1 ; v1(49.23,167.47) v4(53.39,167.47) 58.52,167.47 59.84,168.79 64.7,168.79 68.49,165 68.49,163.68 69.43,162.74 72.03,162.74 CPU1.B27
  L3 w0.127: v1(82.51,123.34) 82.51,123.98 80.23,126.25 80.23,127.09 74.73,132.59 69.25,132.59 68.03,133.81 61.25,133.81 59.47,135.59 59.47,142.98 56.94,145.5 55.49,145.5 v1(54.41,146.58)
  L4 w0.127: v1(49.23,167.47) 48.76,167.47 48.29,167 48.29,161.79 48.94,161.14 48.94,160.01 49.19,159.75 49.21,159.75 49.53,159.43 49.53,159.42 49.56,159.38 49.56,157.38 49.58,157.37 49.58,155.18 50.3,154.46 50.3,154.45 52.94,151.82 52.94,148.06 v1(54.41,146.58)
SIO_GPU_EN_C: length 189.4
  TOP w0.102: 83.02,121.33 82.63,121.72 82.63,122.28 v1(81.64,123.27) ; 83.02,121.33 Q13.5 ; 83.02,121.33 83.01,121.33 82.76,121.08 82.76,120.62 82.73,120.6 Q20.C 80.39,118.61 79.05,119.95 v1(79.05,119.99) ; R250.1 120.7,116.2 118.47,116.2 117.76,115.49 116.79,115.49 115.61,116.67 115.61,117.42 112.68,120.35 108.67,120.35 v1(108.41,120.09) ; PR76.1 27.83,155.11 v1(27.31,155.63) ; v1(103.42,82.98) 103.42,83.24 103.79,83.62 R307.1 R315.1
  L3 w0.127: v1(27.31,155.63) 27.39,155.55 33.92,155.55 34.55,156.18 41.51,156.18 45.45,152.25 45.45,149.86 38.64,143.05 38.64,138.35 40.06,136.93 40.06,136.55 42.03,134.58 42.03,134.58 43.72,132.89 56.75,132.89 59.29,130.35 64.68,130.35 65.11,129.92 72.25,129.92 77.63,124.54 77.63,122.33 79.05,120.9 v1(79.05,119.99)
  L4 w0.127: v1(108.41,120.09) 108.39,120.09 106.81,121.67 98.63,121.67 97.94,122.36 93.34,122.36 93.32,122.35 92.93,122.35 92.91,122.36 90.42,122.36 90.42,122.36 90.03,122.36 89.59,122.81 86.17,122.81 86.13,122.77 82.14,122.77 v1(81.64,123.27)
  BOTTOM w0.102: v1(108.41,120.09) 108.4,120.08 108.4,117.46 107.65,116.71 107.65,116.18 108.69,115.14 108.69,111.14 v2(108.9,110.94) 108.9,109.19 110.17,107.92 110.17,88.24 108.85,86.92 108.85,83.87 107.5,82.52 104.2,82.52 103.75,82.98 v1(103.42,82.98)
SIO_GPU_EN_LS: length 3.9
  TOP w0.102: R240.1 80.74,115.25 80.42,115.57 v4(80.42,116.08) 80.42,116.48 80.88,116.94 81.51,116.94 Q20.B
SIO_GPU_RST: length 106.4
  TOP w0.102: CPU1.C26 72.13,162.22 71.85,162.5 68.98,162.5 67.91,163.57 67.91,164.89 64.5,168.31 60.04,168.31 58.6,166.87 v4(57,166.87) 50.12,166.87 v1(50.05,166.94) ; RN22.4 86.37,114.43 86.65,114.71 86.65,115.77 Q21.E 87.37,116.7 86.04,118.03 86.04,119.13 86.09,119.19 86.09,122.63 85.37,123.34 v1(83.37,123.34)
  L3 w0.127: v1(83.37,123.34) 83.37,124.13 82.2,125.3 82.2,126.71 75.82,133.1 69.5,133.1 68.23,134.37 61.41,134.37 59.98,135.8 59.98,143.25 57.22,146.01 56.1,146.01 55.5,146.61 v1(55.48,146.61)
  L4 w0.127: v1(50.05,166.94) 49.37,166.94 48.8,166.37 48.8,162 49.45,161.35 49.45,160.23 50.03,159.64 50.03,159.63 50.07,159.6 50.07,157.59 50.08,157.58 50.08,155.39 53.47,152 53.47,148.62 v1(55.48,146.61)
SIO_GPU_RST_C: length 18.8
  TOP w0.102: R232.1 99.53,116.77 v1(99.02,116.26) 98.34,116.93 U5.1 ; v1(90.2,115.44) 89.54,114.78 89.03,114.78 88.17,115.65 88.17,117.21 86.77,118.61 Q21.C
  L4 w0.127: v1(99.02,116.26) 98.84,116.26 98.52,116.57 91.33,116.57 v1(90.2,115.44)
  BOTTOM w0.102: v1(90.2,115.44) v2(90.2,116.18)
SIO_GPU_RST_LS: length 3.4
  TOP w0.102: RN22.3 84.77,115.08 v4(84.64,115.21) 84.64,115.73 Q21.B
SIO_GREEN_PWM: length 69.1
  TOP w0.203: 116.9,59.38 116.85,59.33 U14.16
  TOP w0.254: v1(117.74,57.1) 118.03,57.39 118.03,59.05 117.69,59.38 116.9,59.38 ; v1(139.01,10.43) 138.82,10.62 R494.1
  L3 w0.254: v1(139.01,10.43) 136.52,12.92 136.52,23.33 139.66,26.47 139.66,41.51 133.81,47.35 133.81,48.31 130.43,51.69 126.5,51.69 124.16,54.03 120.47,54.03 118.09,56.4 118.09,56.74 v1(117.74,57.1)
  BOTTOM w0.254: v2(138.16,10.43) 138.17,10.43 v1(139.01,10.43)
SIO_GREEN_PWM_1: length 145
  TOP w0.102: RN34.3 139.5,8.03 137.93,9.6 R494.2 R493.1 136.34,11.42 135.96,11.8 133.26,11.8 132.71,12.35 129.39,12.35 v3(129.27,12.48)
  L3 w0.127: v3(85.73,6.7) 84.51,5.48 84.51,3.59 83.95,3.04 24.5,3.04 23.66,3.88 23.66,9.07 23.97,9.38 23.97,9.86 23.34,10.49 23.34,16.73 v3(24.11,17.5)
  L4 w0.127: v3(85.73,6.7) 87.53,4.91 110.79,4.91 119.01,13.12 128.62,13.12 v3(129.27,12.48)
  BOTTOM w0.102: v2(129.83,13.1) 129.83,13.1 129.4,12.51 v3(129.27,12.48) ; Q74.G 26.59,19.03 25.06,17.5 v3(24.11,17.5)
SIO_HDD_LED: length 75
  TOP w0.203: 116.7,59.76 116.66,59.73 U14.15
  TOP w0.254: 116.7,59.76 117.85,59.76 118.41,59.21 118.41,57.02 117.96,56.57 117.69,56.57 v1(117.54,56.42) ; R507.1 R508.2 131.36,7.58 132.37,8.58 v3(132.37,10.16)
  L3 w0.254: v1(117.54,56.42) 117.58,56.38 117.58,56.37 120.31,53.64 124,53.64 126.34,51.31 129.73,51.31 132.74,48.3 132.74,47.85 139.25,41.34 139.25,26.66 135.62,23.02 135.62,13.41 v3(132.37,10.16)
  BOTTOM w0.254: v2(131.57,9.95) 132.16,9.95 v3(132.37,10.16)
SIO_HDD_LED_1: length 134.3
  TOP w0.254: v3(118.85,11.43) 118.99,11.57 127.37,11.57 129.43,9.5 R507.2
  L3 w0.254: v3(85.76,4.99) 85.76,4.75 85.33,4.32 85.33,3.17 84.35,2.19 24.08,2.19 22.85,3.42 22.85,17.66 v3(23.68,18.49)
  L4 w0.254: v3(118.85,11.43) 118.85,11.31 111.63,4.09 86.66,4.09 v3(85.76,4.99)
  BOTTOM w0.254: v3(23.68,18.49) 23.8,18.61 Q75.B ; v3(118.85,11.43) 119.15,11.14 v2(119.15,10.67)
SIO_LVDS_BL_ADJ: length 199.3
  TOP w0.165: v1(32.8,119.08) v4(34.57,119.08) 35.77,119.08 R224.1 36.71,118.13 R231.2 ; v1(128.2,52.7) 128.65,52.26 U14.62
  L3 w0.165: v1(107.7,34.59) 106.89,33.78 103.11,33.78 101.94,32.61 100.34,32.61 99.42,33.53 98.51,33.53 93.94,38.1 89.19,38.1 86.27,41.02 86.27,43.61 83.42,46.46 60.97,46.46 58.88,48.54 34.75,48.54 28.43,54.86 28.43,68.53 33.4,73.5 33.4,78.02 33.08,78.34 32.46,78.96 32.46,118.74 v1(32.8,119.08)
  L4 w0.165: v1(128.2,52.7) 128.2,49.35 128.65,48.9 128.65,45.55 126.6,43.5 126.6,41.28 123.17,37.85 117.77,37.85 115.75,35.83 114.93,35.83 112.91,33.81 108.49,33.81 v1(107.7,34.59)
SIO_MEM_EVENT_L: length 145.8
  TOP w0.102: U14.25 117.88,55.73 119.06,56.91 119.06,57.61 v1(119.29,57.84)
  L3 w0.127: v1(162.36,114.53) 163.07,113.83 163.07,96.17 162.81,95.91 162.81,83.85 161.25,82.3 160.45,82.3 157.63,79.47 157.63,75.99 139.34,57.7 136.18,57.7 135.99,57.51 133.59,57.51 133.58,57.51 131.41,57.51 130.14,58.78 129.42,58.78 129.41,58.76 127.08,58.76 126.29,59.55 123.79,59.55 123.32,59.08 122.07,59.08 122.07,59.08 121.13,59.08 120.98,59.24 119.35,59.24 118.88,58.76 118.88,58.25 v1(119.29,57.84)
  BOTTOM w0.102: R627.1 141.55,134.98 v2(142.63,133.91) 144.13,132.4 144.13,127.04 142.62,125.52 142.15,125.52 140.32,123.7 140.32,122.77 140.88,122.22 143.92,122.22 147.63,125.94 153.03,125.94 154.59,127.5 158.14,127.5 160.52,125.11 160.52,116.42 162.36,114.58 v1(162.36,114.53)
SIO_MEM_EVENT_L_B: length 3.2
  BOTTOM w0.102: Q53.B 141.13,140.6 R620.2 v2(142.27,141.49)
SIO_MEM_EVENT_L_C: length 2.7
  BOTTOM w0.102: Q53.C 141.55,137.62 R627.2 142.46,136.19 v2(142.48,136.17)
SIO_PWNBTN_N: length 313.3
  TOP w0.102: R354.1 137.45,67.88 R355.1 136.28,68.03 136.28,69.98 134.31,71.94 131.2,71.94 129.96,70.7 126.98,70.7 126.96,70.72 124.7,70.72 124.07,71.35 124.07,72.63 v1(126.07,74.63) 125.84,74.85 124.1,74.85 123.18,73.94 122.98,73.94 122.26,73.21 122.26,71.43 R345.2 ; R17.2 36.23,220.83 36.23,223.65 39.01,226.43 39.41,226.43 39.41,226.43 40.05,226.43 40.06,226.44 82.67,226.44 83.77,225.34 88.26,225.34 v1(89.65,223.95)
  L3 w0.127: v1(155.32,185.52) 155.32,183.09 162.06,176.35 162.06,174.48 162.07,174.47 162.07,154.35 164.07,152.35 164.07,134.18 162.48,132.59 162.33,132.59 160.41,130.67 160.41,127.97 159.27,126.82 159.27,123.37 156.87,120.97 156.87,107.49 148.15,98.77 148.15,85.01 146.72,83.58 146.72,83.35 145.97,82.61 144.92,82.61 144.8,82.73 141.56,82.73 134.22,75.39 133.62,75.39 133.09,74.85 126.3,74.85 v1(126.07,74.63)
  BOTTOM w0.102: v1(89.65,223.95) 89.38,223.68 89.38,220.71 90.48,219.61 90.48,213.36 91.83,212.01 99.48,212.01 104.04,207.44 v2(104.04,207.11) 104.04,204.65 105.95,202.74 107.79,202.74 110.17,200.36 114.44,200.36 115.05,199.75 140.57,199.75 150.86,189.46 152.13,189.46 155.32,186.26 v1(155.32,185.52)
SIO_SMCLK0: length 222.9
  TOP w0.102: v3(36.91,27.38) 36.33,27.96 v4(36.04,27.96) 35.52,27.44 35.52,25.12 35.2,24.8 34.91,24.8 R469.2 ; Q32.6 139.29,75.3 138.8,75.79 138.8,76.91 v1(138.79,76.91) ; v1(99.42,81.2) 99.42,81.21 99.42,81.23 100.09,81.9 Q28.6 ; U14.67 133.75,53.73 133.97,53.52 134.43,53.52 135.06,52.89 v1(135.06,52.76) 135.16,52.76 135.27,52.65 RN13.3
  L3 w0.127: v1(122.99,74.4) 123.05,74.35 124.77,74.35 126.11,73.01 129.19,73.01 129.67,73.49 133.52,73.49 134.15,74.12 134.88,74.12 136.63,75.87 137.75,75.87 v1(138.79,76.91)
  L4 w0.127: v1(138.79,76.91) 140.71,74.99 140.71,59.96 134.93,54.18 134.93,52.88 v1(135.06,52.76) ; v1(122.99,74.4) 121.52,75.87 120.53,75.87 116.96,79.44 115.69,79.44 113.87,81.25 106.48,81.25 105.87,81.87 100.08,81.87 v1(99.42,81.2) ; v3(36.91,27.38) 36.91,28.04 41.74,32.87 41.74,43.96 29.2,56.5 29.2,68.86 37.29,76.95 39.16,76.95 39.86,77.65 41.61,77.65 42.13,77.13 v1(43.65,77.13)
  BOTTOM w0.102: v1(99.42,81.2) 101.13,81.2 101.63,81.71 102.27,81.71 102.55,81.43 102.55,81.07 101.42,79.93 91.12,79.93 89.44,78.26 84.72,78.26 82.41,75.95 65.18,75.95 64.75,76.38 62.75,76.38 62.34,75.97 53.92,75.97 52.45,77.44 52.24,77.44 49.73,79.96 47,79.96 44.2,77.17 43.68,77.17 v1(43.65,77.13) 43.65,76.94 44.09,76.5 R702.2
SIO_SMCLK0_D: length 5
  BOTTOM w0.102: v2(49.51,77.67) Q60.3 48.27,77.09 48.14,76.96 45.91,76.96 45.45,76.5 R702.1
SIO_SMDAT0: length 221
  TOP w0.102: v3(36.1,25.7) 36.1,24.28 v4(35.88,24.06) 34.35,24.06 R470.2 ; Q32.3 141.75,77.21 v1(141.54,77.42) ; v1(102.06,81.23) 102.06,81.11 Q28.3 ; U14.68 133.82,54.13 133.95,54 134.83,54 135.33,53.5 135.37,53.5 v1(135.44,53.42) 135.52,53.42 135.55,53.39 136.1,53.39 136.59,52.9 136.59,52.09 136.5,52 RN13.4
  L3 w0.127: v1(122.13,74.45) 122.55,74.87 124.99,74.87 126.33,73.52 128.98,73.52 129.46,74 133.31,74 133.93,74.63 134.54,74.63 136.37,76.45 137.62,76.45 138.58,77.42 v1(141.54,77.42)
  L4 w0.127: v1(122.13,74.45) 121.22,75.36 120.32,75.36 116.75,78.93 115.48,78.93 113.66,80.75 106.26,80.75 106.1,80.9 102.4,80.9 v1(102.06,81.23) ; v1(42.78,76.57) 42.72,76.63 41.92,76.63 41.4,77.14 40.13,77.14 39.39,76.4 37.46,76.4 29.71,68.65 29.71,56.73 42.25,44.19 42.25,31.72 37.78,27.25 37.78,27.1 36.38,25.7 v3(36.1,25.7) ; v1(135.44,53.42) 135.44,53.97 141.83,60.36 141.83,69.99 142.85,71.01 142.85,76.13 141.56,77.42 v1(141.54,77.42)
  BOTTOM w0.102: v1(102.06,81.23) 101.86,81.23 101.05,80.42 90.89,80.42 89.21,78.74 84.52,78.74 82.21,76.43 65.39,76.43 64.96,76.86 62.95,76.86 62.54,76.86 62.14,76.45 54.12,76.45 52.6,77.98 52.39,77.98 51.39,78.98 51.39,78.99 50.35,80.03 50.35,80.04 49.94,80.44 46.77,80.44 44,77.67 43.51,77.67 42.78,76.94 v1(42.78,76.57) 42.92,76.57 44.03,75.45 R704.2
SIO_SMDAT0_D: length 4.3
  BOTTOM w0.102: v2(43.29,74.96) 43.39,74.85 45.27,74.85 45.6,75.18 R704.1 46.63,75.45 Q60.6
SIO_YELLOW: length 207.8
  TOP w0.203: v1(122.74,52.78) 122.65,52.69 U14.47
  TOP w0.254: v3(127.25,10.96) 128.81,9.41 128.81,6 129.17,5.64 133.07,5.64 133.27,5.84 R505.2 134.51,5.64 138.82,5.64 139.5,6.32 RN34.4
  L3 w0.254: v3(85.91,4.01) 85.91,3.89 85.74,3.72 85.74,3.01 84.52,1.79 23.91,1.79 22.44,3.25 22.44,18.69 22.92,19.18 v3(23.27,19.18) ; v3(127.25,10.96) 128.47,10.96 135.21,17.7 135.21,23.19 138.85,26.83 138.85,41.17 131.99,48.03 131.99,48.48 129.54,50.93 126.18,50.93 123.85,53.26 123.22,53.26 v1(122.74,52.78)
  L4 w0.254: v3(127.25,10.96) 127.26,10.96 127.26,10.98 127.22,11.02 127.22,11.72 126.92,12.01 120.32,12.01 111.99,3.68 86.3,3.68 86.1,3.89 86.04,3.89 v3(85.91,4.01)
  BOTTOM w0.254: v3(23.27,19.18) 23.27,19.2 22.98,19.49 Q72.G ; v1(122.74,52.78) 122.26,53.26 v2(122,53.26)
SLEEVE: length 51.8
  TOP w0.203: U16.32 163.5,49.37 164.37,50.24 v5(164.37,50.37)
  TOP w0.305: RN32.3 164.38,50.36 v5(164.37,50.37)
  TOP w1.016: 171.65,73.99 172.04,74.39 174.82,74.39 176.18,73.03 182.05,73.03 182.48,72.59 UHS1.4
  BOTTOM w0.508: 165.18,60.96 165.13,61.01 158.1,61.01 157.24,60.16 157.24,59.14 155.34,57.24 Q66.D
  BOTTOM w1.016: v5(167.57,72.69) 167.57,69.88 165.18,67.49 165.18,55.49 164.65,54.96 164.65,54.95 v2(164.53,54.83) 164.37,54.67 v5(164.37,50.37)
SLEEVE_G: length 11.6
  BOTTOM w0.102: Q67.C 151.53,51.79 R746.2 151.53,52.57 R744.1 151.54,54.18 v2(151.54,56.59) 151.54,57.48 153.21,59.14 Q66.G
SLP_S0_APS: length 1.4
  TOP w0.102: R256.2 TP50.1
SLP_S0_N: length 4.9
  TOP w0.102: R90.2 147.28,194.72 v4(147.53,194.46) 147.53,191.32 D2.2
SLP_S3_N: length 383.3
  TOP w0.102: v1(97.49,71.58) 97.67,71.4 103.13,71.4 103.13,71.4 103.19,71.4 104.15,70.44 105.06,69.53 105.06,68.05 v4(105.54,67.56) 106.52,67.56 R353.1 ; R381.2 R379.2 99.5,57.81 99.3,57.61 v1(99.3,57.51) ; R96.2 146.07,186.42 148.09,188.45 148.09,199.23 147.19,200.13 v1(147.19,201.58) 147.19,205.71 PR27.1 ; R96.2 141.14,182.44 v1(140.93,182.44) ; R96.2 144.83,186.42 144.66,186.59 144.66,188.01 145.33,188.68 R94.1 145.29,189.37 D2.1 ; R118.1 29.46,183.67 v1(29.46,185.27)
  L3 w0.127: v1(140.93,182.44) 140.26,181.77 140.26,166.94 139.76,166.43 139.76,159.34 140.26,158.84 140.26,152.38 139.9,152.01 139.9,129.02 138.53,127.65 138.53,107.39 141.92,104 141.92,93.09 135.21,86.39 135.21,86.02 135.21,85.65 131.17,81.61 130.05,81.61 128.99,80.54 124.57,80.54 124.29,80.26 112.25,80.26 110.75,78.77 108.75,78.77 107.97,77.99 102.2,77.99 99.37,75.16 99.37,73.45 v1(97.49,71.58) ; v1(29.46,185.27) 29.46,185.3 28.21,186.56 28.21,192.82 28.21,201.73 29.06,202.58 29.06,208.31 29.04,208.32 29.04,217.45 29.04,219.27 30.57,220.79 30.57,222.8 32.16,224.4 74.97,224.4 78.12,221.24 91.08,221.24 91.25,221.07 91.28,221.07 91.56,220.8 91.56,220.77 92.31,220.01 96.15,220.01 97.32,218.85 98.16,218.85 99.01,218.01 100.32,218.01 102.02,216.31 103.27,216.31 106.37,213.22 119.5,213.22 119.69,213.03 120.76,213.03 122,211.79 136.51,211.79 146.71,201.58 v1(147.19,201.58)
  L4 w0.127: v1(99.3,57.51) 99.9,58.11 102.33,58.11 104.27,60.05 104.27,66.24 98.93,71.58 v1(97.49,71.58)
SLP_S3_N_APS: length 1.3
  TOP w0.102: TP29.1 90.52,201.21 R77.2
SLP_S3_N_EC: length 35
  TOP w0.102: v1(129.34,52.73) 129.45,52.63 U14.64 ; R353.2 109.02,68.12 v4(109.46,67.69) 110.32,67.69 v1(110.8,68.17)
  L4 w0.127: v1(129.34,52.73) 129.34,53.54 127.98,54.91 127.98,56.33 128.95,57.3 128.95,58.08 128.67,58.35 128.14,58.35 126.99,59.5 126.99,60.74 126.34,61.39 126.07,61.39 123.27,64.19 123.27,64.67 122.83,65.11 119.73,65.11 118.84,64.23 118.45,64.23 115.12,67.56 112.17,67.56 111.56,68.17 v1(110.8,68.17)
SLP_S4_N: length 249
  TOP w0.102: v1(150.91,185.32) 150.91,186.61 149.89,187.63 149.89,200.1 148.17,201.83 PR28.1 ; v1(161.83,107.67) 161.82,107.68 161.57,107.68 160.53,108.72 R263.2 ; R205.2 152.88,128.65 PR87.1 157.27,128.64 158.48,129.84 v1(158.48,129.95) ; v1(112.35,55.8) 112.07,55.52 112.07,54.71 111.76,54.4 R386.2 111.67,54.31 111.67,52.19 111.01,51.54 110.55,51.54 105.19,46.18 103.44,46.18 102.98,46.63 97.5,46.63 94.42,43.56 94.4,43.56 94.39,43.56 94.12,43.28 92.24,43.28 91.31,42.36 91.31,35.96 92.22,35.05 93.34,35.05 94.78,33.62 R441.2
  L3 w0.127: v1(160.88,77.02) 160.88,75.14 137.87,52.12 133.04,52.12 131.28,53.87 127.87,53.87 127.39,54.36 120.59,54.36 119.21,55.73 119.21,56.29 117.93,57.57 113.63,57.57 112.35,56.29 v1(112.35,55.8)
  L4 w0.127: v1(150.91,185.32) 151.26,184.96 151.26,183.59 152.66,182.19 152.66,179.96 159.77,172.85 159.77,152.65 161.12,151.31 161.12,141.78 160.13,140.79 160.13,132 158.48,130.35 v1(158.48,129.95)
  BOTTOM w0.102: v1(158.48,129.95) 158.48,127.84 161.03,125.28 161.03,116.59 162.85,114.78 162.85,108.68 v1(161.83,107.67) v2(161.83,103.69) 161.83,98.82 161.5,98.48 161.5,96.02 162.14,95.38 162.14,94.08 162.87,93.34 162.87,80.72 160.91,78.76 160.91,77.04 v1(160.88,77.02)
SLP_S4_N_APS: length 1.6
  TOP w0.102: R203.2 147.34,129.44 TP43.1
SLP_S4_N_EC: length 5
  TOP w0.102: U14.21 114.36,57.33 114.08,57.05 113.56,57.05 v4(113.53,57.02) 113.31,57.02 112.58,56.29 112.15,56.29 111.57,55.71 R386.1
SM_RCOMP_0: length 6.1
  TOP w0.254: v3(89.26,165.9) 89.25,165.89 89.24,165.89 CPU1.AV34
  BOTTOM w0.203: v3(89.26,165.9) 89.76,166.4 92.5,166.4 92.82,166.4 93.31,166.4 R589.2 v2(93.56,165.28)
SM_RCOMP_1: length 2.3
  TOP w0.254: CPU1.AV30 v3(89.27,164.08)
  BOTTOM w0.254: v2(88.91,164.71) 89.27,164.34 v3(89.27,164.08) R591.2
SMB0_ALERT#: length 5.7
  TOP w0.102: R10.1 123.98,221.49 125.06,220.41 v4(125.48,220.41) R14.1 126.71,220.42 R9.2
SMB0_ALERT#_C: length 86.6
  TOP w0.089: 78.45,181.27 78.45,180.9 78.36,180.81 CPU1.R63
  TOP w0.102: v1(126.22,204.69) v4(126.22,206.98) 126.22,208.77 128.32,210.87 128.32,217.79 127.59,218.52 R14.2 128.59,220.41 R12.2 ; 78.45,181.27 78.45,182.16 76.83,183.78 76.83,184.44 75.77,185.5 v3(75.65,185.5)
  L3 w0.127: v1(126.22,204.69) 123.94,202.41 98.52,202.41 98.51,202.4 87.5,202.4 76.99,191.89 76.99,186.84 v3(75.65,185.5)
SMB0_CLK_C: length 6.2
  TOP w0.089: 78.89,181.36 78.89,180.61 78.83,180.56 CPU1.T62
  TOP w0.102: 78.89,181.36 78.89,183.76 78.29,184.35 v4(78.29,184.35) R108.2
SMB0_CLK_MAIN: length 340.5
  TOP w0.102: v1(17.85,218.78) 17.87,218.78 18.02,218.93 R21.2 ; v1(8.95,220.49) 8.04,221.4 RN17.4 7.47,222.04 7.86,222.44 PC1.1 9.99,222.74 10.32,222.41 Q2.S ; v1(128,125.66) 128.47,125.19 129.29,125.19 130.99,126.9 138.34,126.9 138.39,126.84 140.22,126.84 140.48,127.11 140.48,127.5 140.13,127.85 DIMM1.202
  L3 w0.127: v1(17.85,218.78) 17.85,216.29 16.76,215.2 16.76,190.32 18.92,188.16 18.92,178.07 20.8,176.19 20.8,159.08 20.23,158.51 20.23,143.42 23.94,139.7 32.14,139.7 36.43,135.41 36.43,135.08 39.4,132.11 39.4,120.02 42.17,117.25 42.17,108.84 42.6,108.41 42.6,80.26 42.64,80.22 42.64,80.2 43.21,79.63 45.06,79.63 v1(46.19,80.76)
  BOTTOM w0.102: v1(128,125.66) 127.03,124.69 111.67,124.69 107.92,120.94 107.92,117.67 107.14,116.89 107.14,114.35 108.06,113.44 108.06,105.82 107.78,105.54 107.78,88.01 108.31,87.48 108.31,84.02 107.3,83.01 104.4,83.01 103.84,83.57 102.73,83.57 100.92,81.76 99.25,81.76 98.38,80.9 90.66,80.9 88.98,79.22 84.32,79.22 84.12,79.02 81.57,79.02 79.46,76.91 68.31,76.91 67.57,77.65 66.38,77.65 66.07,77.34 63.15,77.34 61.85,77.34 61.5,76.99 54.54,76.99 v2(53.86,77.67) 53.3,78.23 53.3,78.69 53.03,78.96 52.11,78.96 50.15,80.92 46.36,80.92 v1(46.19,80.76) 46.17,80.73 46.17,80.53 43.99,78.35 43.44,78.35 42.15,77.05 42.15,75.12 40.99,73.96 32.21,73.96 31.63,74.55 Q62.4 ; v1(17.85,218.78) 17.1,218.03 10.08,218.03 9.29,218.82 9.29,220.15 v1(8.95,220.49)
SMB0_CLK_RESUME: length 201.6
  TOP w0.102: Q2.D 11.42,221.42 12.63,222.63 RN16.3 14.01,223.22 20.14,223.22 v1(20.66,222.7) ; R13.1 123.01,220.47 124.02,219.46 v1(124.19,219.46) 124.77,219.46 127.49,216.74 127.49,211.35 v4(126.55,210.41) 125.48,209.34 v1(125.48,208.88) ; v3(75.62,186.87) 76.3,186.19 R108.1
  L3 w0.127: v1(124.19,219.46) 123.68,218.95 117.91,218.95 111.82,225.04 106.16,225.04 105.76,224.65 84.85,224.65 84.85,224.64 83.53,224.64 83.53,224.65 83.38,224.65 82.23,225.79 36.27,225.79 36.27,225.79 33.8,225.79 33.8,225.79 23.75,225.79 v1(20.66,222.7)
  L4 w0.127: v1(125.48,208.88) 125.18,209.17 123.88,209.17 123.25,208.54 110.32,208.54 109.89,208.98 103.24,208.98 101.67,207.41 97.68,207.41 97.66,207.43 95.99,207.43 95.82,207.25 91.73,207.25 76.13,191.65 76.13,187.38 v3(75.62,186.87)
  BOTTOM w0.102: v2(124.18,218.62) 124.18,219.16 124.19,219.17 v1(124.19,219.46)
SMB0_CVT_CLK: length 5.3
  TOP w0.102: R469.1 34.81,26.62 34.8,26.63 34.8,26.77 v3(34.78,26.79) 34.78,26.79 C202.1
  BOTTOM w0.102: U35.6 33.93,27.49 34.63,26.79 v3(34.78,26.79) 36.29,26.79 v2(36.51,26.57)
SMB0_CVT_DATA: length 4.5
  TOP w0.102: C201.1 34.04,27.5 v3(34.04,26.65) 33.31,26.65 v4(33.21,26.55) 33.21,26.09 R470.1
  BOTTOM w0.102: v3(34.04,26.65) 34.04,26.69 33.43,27.31 U35.7
SMB0_DATA_C: length 6.8
  TOP w0.089: 78.66,181.36 78.64,181.34 78.64,179.64 78.54,179.55 78.54,179.29 78.68,179.16 78.68,178.81 CPU1.T61
  TOP w0.102: R110.2 77.25,184.15 v4(78.29,183.11) 78.66,182.74 78.66,181.36
SMB0_DATA_MAIN: length 331.6
  TOP w0.102: R18.2 17.48,219.98 v1(17.13,219.63) 16.66,219.63 16.3,219.27 16.3,218.65 15.91,218.26 13.22,218.26 Q4.S 12.2,219.28 PC2.1 7.89,219.72 7.47,220.14 RN17.3 ; v1(127.16,125.67) 128.11,124.71 129.52,124.71 131.22,126.41 138.13,126.41 138.19,126.36 140.42,126.36 140.96,126.91 140.96,127.71 140.22,128.45 DIMM1.200
  L3 w0.127: v1(45.52,81.13) 44.53,80.14 43.44,80.14 43.11,80.47 43.11,109.22 42.68,109.65 42.68,117.47 39.91,120.24 39.91,132.32 36.94,135.29 36.94,135.64 32.36,140.22 24.14,140.22 20.75,143.61 20.75,158.31 21.31,158.87 21.31,176.4 19.43,178.27 19.43,188.37 17.26,190.54 17.26,214.99 18.35,216.08 18.35,218.94 17.66,219.63 v1(17.13,219.63)
  BOTTOM w0.102: v1(127.16,125.67) 126.66,125.17 111.46,125.17 107.44,121.15 107.44,117.87 106.66,117.09 106.66,114.15 107.58,113.23 107.58,106.02 107.3,105.74 107.3,88.21 107.3,88.21 107.3,87.81 107.78,87.33 107.78,84.28 107.04,83.54 104.55,83.54 104.04,84.06 102.53,84.06 100.72,82.25 99.45,82.25 98.92,82.25 98.05,81.38 90.41,81.38 88.73,79.71 84.29,79.71 84.08,79.5 81.37,79.5 79.26,77.39 68.51,77.39 67.77,78.13 66.17,78.13 65.87,77.83 63.35,77.83 61.65,77.83 61.3,77.47 54.92,77.47 53.78,78.61 53.78,78.89 53.23,79.44 52.37,79.44 50.4,81.41 45.8,81.41 v1(45.52,81.13) 45.52,80.57 44.1,79.14 44.07,79.14 v2(44.02,79.1) 43.76,78.84 43.25,78.84 41.66,77.25 41.66,76.36 40.27,74.97 37.36,74.97 36.88,75.45 Q61.4
SMB0_DATA_RESUME: length 208
  TOP w0.102: RN16.4 13.43,221.3 14.18,220.55 14.18,219.84 14.71,219.3 Q4.D 15.3,219.54 15.3,220.37 16.01,221.08 16.01,222.43 16.28,222.7 v1(19.67,222.7) ; R19.1 v1(123.32,219.46) 124,218.78 124.77,218.78 126.78,216.77 v4(126.78,211.99) 124.53,209.74 v1(124.53,208.69) ; R110.1 76.23,185.6 v3(75.65,186.18)
  L3 w0.127: v1(123.32,219.46) 118.13,219.46 112.04,225.55 105.95,225.55 105.55,225.15 84.64,225.15 84.64,225.15 83.74,225.15 83.74,225.15 83.59,225.15 82.44,226.3 36.48,226.3 21.46,226.3 21.33,226.17 21.33,224.21 21.2,224.08 20.76,224.08 20.63,224.21 20.63,226.17 20.51,226.3 19.07,226.3 18.93,226.16 18.93,225.6 19.06,225.48 19.79,225.48 19.92,225.35 19.92,224.97 19.79,224.84 19.06,224.84 18.93,224.71 18.93,224.31 19.06,224.18 19.64,224.18 19.77,224.05 19.77,223.7 19.64,223.57 19.08,223.57 18.96,223.44 18.96,222.83 19.08,222.7 v1(19.67,222.7)
  L4 w0.127: v3(75.65,186.18) 76.64,187.17 76.64,191.44 91.94,206.75 96.03,206.75 96.2,206.92 97.45,206.92 97.47,206.9 101.88,206.9 102,207.02 103.45,208.47 109.67,208.47 110.27,207.88 123.71,207.88 v1(124.53,208.69)
  BOTTOM w0.102: v1(123.32,219.46) v2(122.49,219.46)
SMB_CLK_GPU: length 3.9
  TOP w0.102: R312.2 98.61,83 98.61,80.77 98.94,80.44 Q28.1
SMB_DAT_GPU: length 3.9
  TOP w0.102: v4(103.97,84.63) 103.1,83.76 R306.2 102.26,83.76 101.39,82.9 Q28.4
SMBUS_ISP: length 121.4
  TOP w0.102: v1(115.58,47.19) 116.16,46.61 121.89,46.61 122.53,47.24 122.53,49.17 123.85,50.49 U14.50 ; v3(40.32,76.6) 40.38,76.6 40.88,76.1 42.28,76.1 v1(42.72,75.66)
  L3 w0.127: v1(95.13,48.77) 94.9,49 94.87,49 93.25,50.62 93.25,64.65 84.65,73.25 65.39,73.25 65.28,73.37 63.58,73.37 63.47,73.25 60.93,73.25 60.9,73.28 49.06,73.28 47.84,74.5 44.15,74.5 42.99,75.66 v1(42.72,75.66)
  L4 w0.127: v1(95.13,48.77) 95.59,49.23 107.22,49.23 109.3,47.14 115.53,47.14 v1(115.58,47.19)
  BOTTOM w0.102: R710.2 43.94,73.86 42.63,73.86 v2(42.37,74.12) 42.37,74.57 42.72,74.92 v1(42.72,75.66) ; Q62.5 Q62.2 34.6,75.59 35.11,76.1 Q61.5 Q61.2 38.81,76.1 C462.1 40.32,76.59 v3(40.32,76.6)
SMBUS_ISP_G: length 12.6
  BOTTOM w0.102: R707.2 48.6,74.32 47.86,75.06 47.62,75.06 ; 47.62,75.06 46.83,74.27 R710.1 ; 47.62,75.06 Q60.5 47.62,76.11 47.99,76.48 49,76.48 49.19,76.3 v2(49.49,76.3) 49.74,76.54 49.74,76.78 50.07,77.11 50.07,77.95 49.59,78.44 47.91,78.44 47.62,78.15 Q60.2
SOC_EXTSMI_N: length 38.7
  TOP w0.102: R151.1 47.73,174.19 48.21,174.67 48.21,178.25 v4(48.32,178.36) 48.61,178.65 R130.1 50.29,178.65 50.4,178.77 v1(50.53,178.77) ; CPU1.M41 v3(76.73,169.67)
  L3 w0.127: v3(76.73,169.67) 76.19,170.21 75.86,170.21 75.74,170.32 75.06,170.32 74.95,170.21 73.26,170.21 71.99,171.48 71.91,171.48 71.33,172.06 70.68,172.06 69.26,173.47 69.26,173.53 69.04,173.74 69.04,173.8 67.5,175.34 62.8,175.34 61.43,176.71 57.77,176.71 57.34,177.15 56.73,177.15 56.05,176.47 52.67,176.47 50.96,178.18 50.95,178.18 50.59,178.55 50.59,178.71 v1(50.53,178.77)
SOC_PWROK_CPU: length 168.5
  TOP w0.102: R225.1 142.8,117.67 R229.1 144.01,117.67 144.47,117.21 144.47,115.79 143.82,115.14 140.09,115.14 v1(139.98,115.24) ; CPU1.AG49 v3(83.92,173.39)
  L3 w0.127: v1(139.98,115.24) 139.98,115.27 139.61,115.65 139.61,116.84 139.25,117.2 139.25,127.61 140.01,128.37 140.01,128.42 140.41,128.81 140.41,151.8 140.77,152.17 140.77,159.05 140.26,159.55 140.26,166.22 140.77,166.73 140.77,172.26 141.47,172.96 141.47,189.73 137.31,193.89 136.97,193.89 133.18,197.69 111.03,197.69 111.01,197.66 109.29,197.66 108.35,198.6 104.89,198.6 104.69,198.4 91.19,198.4 83.13,190.34 83.13,181.94 83.39,181.68 83.39,180.47 83.3,180.37 83.3,174.01 v3(83.92,173.39)
  BOTTOM w0.102: v1(139.98,115.24) 139.98,115.24 139.95,115.27 v2(139.1,115.27)
SP_PLLVDD: length 8.5
  TOP w0.254: v3(90.08,98.76) 90.02,98.76 89.66,98.41 GPU1.M6
  BOTTOM w0.508: L21.2 94.53,101.59 C395.1 93.84,101.6 C400.1 91.78,100.53 C403.1 C410.1 90.74,99.39 v2(90.72,99.38) 90.61,99.38 90.08,98.84 v3(90.08,98.76)
SPEED_100*_CON: length 4.8
  TOP w0.254: RJ1.12 69.5,21.81 UR2.2
  BOTTOM w0.254: RJ1.12 70.19,21.13 v2(70.19,22.23)
SPEED_100_N: length 60.7
  TOP w0.203: U26.25 35.21,12.37 v1(34.27,11.43)
  TOP w0.254: UR2.1 69.5,25.35 71.1,26.94 v1(71.25,26.94) 75.05,30.73 78.71,30.73 U24.6
  L3 w0.254: v1(71.25,26.94) 71.15,26.94 69.75,25.55 62.26,25.55 56.78,20.07 41.2,20.07 38.37,17.24 38.37,14.36 37.26,13.25 36.1,13.25 v1(34.27,11.43)
  BOTTOM w0.254: v1(71.25,26.94) 71.6,27.28 71.69,27.35 v2(71.69,27.74)
SPEED_1000*_CON: length 24.2
  TOP w0.254: UR3.2 70.65,22.96 RJ1.11 ; UR4.2 86.39,24.64 86.6,24.84 86.6,25.6 v1(85.78,26.42)
  L3 w0.254: v1(85.78,26.42) 85.78,25.12 84.08,23.42 74.94,23.42 RJ1.11
  BOTTOM w0.254: v2(72.58,22.15) 72.58,21.05 RJ1.11
SPEED_1000_N: length 55
  TOP w0.203: v1(35.19,11.43) 35.61,11.85 U26.26
  TOP w0.254: UR3.1 70.65,25.68 v1(71.15,26.19) 71.25,26.19 74.97,29.91 U24.1
  L3 w0.254: v1(71.15,26.19) 69.98,25.01 62.42,25.01 57.07,19.66 41.37,19.66 38.78,17.07 38.78,13.93 37.62,12.77 36.53,12.77 v1(35.19,11.43)
  BOTTOM w0.254: v2(72.07,26.14) 72.02,26.19 v1(71.15,26.19)
SPI_CLK_CPU_MUX: length 98
  TOP w0.102: v1(83.73,130.81) 83.48,131.05 83.04,131.05 82.91,130.93 v4(82.91,130.79) 82.91,130.23 83.04,130.1 83.75,130.1 83.88,129.98 83.88,129.05 83.7,128.87 U2.4 ; v1(62.49,179.02) 62.7,179.23 R134.2
  L4 w0.114: v1(62.49,179.02) 62.49,172.95 61.82,172.28 61.82,172.12 61.9,172.04 61.9,171.87 61.66,171.63 61.5,171.63 61.42,171.71 61.25,171.71 61.01,171.47 61.01,171.31 61.09,171.23 61.09,171.07 60.85,170.82 60.69,170.82 60.61,170.9 60.45,170.9 60.2,170.66 60.2,170.5 60.28,170.42 60.28,170.26 60.04,170.01 59.88,170.01 59.8,170.09 59.64,170.09 59.4,169.85 59.4,169.69 59.48,169.61 59.48,169.45 59.23,169.21 59.07,169.21 58.99,169.29 58.83,169.29 58.48,168.94 58.48,158.98 58.36,158.86 56.89,158.86 56.72,158.69 56.72,158.42 56.84,158.29 58.36,158.29 58.48,158.18 58.48,157.84 58.36,157.72 56.75,157.72 56.64,157.61 56.64,157.26 56.75,157.15 58.36,157.15 58.48,157.03 58.48,156.69 58.36,156.58 57.82,156.58 57.69,156.45 57.69,156.19 57.87,156.01 58.36,156.01 58.48,155.89 58.48,155.4 65.65,148.22 65.65,148.06 65.09,147.49 65.09,147.31 65.31,147.09 65.49,147.09 66.06,147.66 66.22,147.66 66.46,147.41 66.46,147.25 65.07,145.86 65.07,145.68 65.29,145.46 65.47,145.46 66.86,146.85 67.03,146.85 67.27,146.61 67.27,146.44 65.59,144.77 65.59,144.59 65.81,144.36 65.99,144.36 67.67,146.04 67.83,146.04 68.08,145.8 68.08,145.64 67.05,144.61 67.05,144.25 67.27,144.04 67.85,144.04 68.15,143.74 68.32,143.74 68.78,144.2 71.18,144.2 77.43,137.96 77.43,128.81 77.71,128.53 83.1,128.53 83.66,129.1 83.66,130.74 83.73,130.8 v1(83.73,130.81)
SPI_CLK_KBC_MUX: length 122.6
  TOP w0.102: v1(147.69,107.02) 148.8,107.02 150.2,105.63 150.2,80.83 148.09,70.26 148.02,69.99 146.32,67.76 R362.2 ; v1(84.29,128.08) 84.29,127.38 84.17,127.26 v4(84.06,127.26) 83.88,127.26 83.26,127.87 U2.2
  L4 w0.114: v1(147.69,107.02) 146.82,107.02 144.62,109.22 144.1,109.22 143.68,109.65 143.68,109.82 143.41,110.09 143.23,110.09 140.12,113.21 138.78,113.21 136.92,115.06 116.95,115.06 108.3,123.71 101.5,123.71 100.63,124.58 93.82,124.58 93.33,125.06 90.57,125.06 89.77,125.86 88.75,125.86 86.53,128.08 v1(84.29,128.08)
SPI_CLK_N_CPU: length 9.9
  TOP w0.102: R134.1 64.5,179.55 66.09,179.55 R135.2 67.29,179.02 67.37,178.94 67.41,178.94 67.74,178.62 68.28,178.62 68.36,178.54 v4(68.54,178.54) 70.99,176.08 71.82,176.08 71.88,176.14 72.44,176.14 CPU1.C56
SPI_CLK_ROM: length 49.6
  TOP w0.102: SRCON1.6 100.66,124.94 102.19,126.46 v1(102.19,126.96) ; v1(88.36,131.12) 85.63,131.12 85.13,131.62 76.78,131.62 76.25,131.09 R199.1
  L4 w0.114: v1(102.19,126.96) 95.74,126.96 92.58,130.12 89.72,130.12 88.72,131.12 v1(88.36,131.12)
  BOTTOM w0.102: R631.2 95.32,127.11 v2(100.88,127.11) 102.04,127.11 v1(102.19,126.96) 102.19,126.75 101,125.55 101,124.03 v2(100.08,123.11) 98.5,121.53 R632.2
SPI_CLK_ROM_CPU: length 124.9
  TOP w0.102: v3(64.96,179.02) R135.1
  L4 w0.114: v1(90.67,131.08) 90.67,130.74 90.56,130.62 89.93,130.62 89.51,131.03 89.51,131.78 89.3,132 89.14,132 88.79,131.65 88.61,131.65 88.39,131.88 88.39,132.06 88.73,132.4 88.73,132.56 88.49,132.81 88.33,132.81 87.68,132.15 87.5,132.15 87.27,132.38 87.27,132.56 87.92,133.21 87.92,133.37 87.68,133.61 87.52,133.61 86.72,132.82 86.58,132.82 86.32,133.08 86.32,133.22 87.11,134.02 87.11,134.18 83.93,137.36 83.77,137.36 83.05,136.64 82.87,136.64 82.65,136.86 82.65,137.04 83.37,137.76 83.37,137.92 83.13,138.17 82.97,138.17 82.15,137.35 81.96,137.35 81.74,137.57 81.74,137.75 82.56,138.57 82.56,138.73 82.21,139.08 79.34,139.08 72.53,145.89 72.53,148.58 72.38,148.73 71.89,148.73 71.77,148.61 71.77,146.5 71.65,146.37 71.44,146.37 71.32,146.5 71.32,148.62 71.2,148.73 70.97,148.73 70.86,148.62 70.86,148.32 70.74,148.2 70.52,148.2 70.4,148.32 70.4,148.62 70.29,148.73 69.24,148.73 68.1,149.87 68.1,150.03 68.95,150.89 68.95,151.11 68.75,151.31 68.57,151.31 67.69,150.43 67.53,150.43 67.29,150.68 67.29,150.84 68,151.55 68,151.73 67.77,151.95 67.6,151.95 66.88,151.24 66.72,151.24 64.3,153.67 64.3,162.55 65.6,163.85 65.6,179.5 65.47,179.62 65.18,179.62 65.06,179.5 65.06,179.12 v3(64.96,179.02)
  BOTTOM w0.102: v1(90.67,131.08) 91.56,130.19 91.56,129.7 91.67,129.6 92.26,129.6 92.36,129.5 92.36,129.19 92.26,129.09 91.67,129.09 91.56,128.99 91.56,128.68 91.67,128.58 92.26,128.58 92.36,128.48 92.36,128.18 92.26,128.07 91.67,128.07 91.56,127.97 91.56,127.67 91.67,127.57 92.01,127.57 92.1,127.47 v2(92.1,126.75) 92.1,125.85 93.71,124.24 99.91,124.24 100.13,124.46 100.13,126.16 100.03,126.26 99.72,126.26 99.62,126.16 99.62,125.03 99.52,124.92 99.21,124.92 99.11,125.03 99.11,126.16 99.01,126.26 98.7,126.26 98.6,126.16 98.6,125.03 98.5,124.92 98.2,124.92 98.09,125.03 98.09,126.16 97.99,126.26 97.69,126.26 97.59,126.16 97.59,125.03 97.49,124.92 97.18,124.92 97.08,125.03 97.08,126.16 96.98,126.26 96.67,126.26 96.57,126.16 96.57,125.03 96.47,124.92 96.16,124.92 96.06,125.03 96.06,126.16 95.96,126.26 95.66,126.26 95.55,126.16 95.55,125.03 95.45,124.92 93.85,124.92 93.31,125.46 R631.1
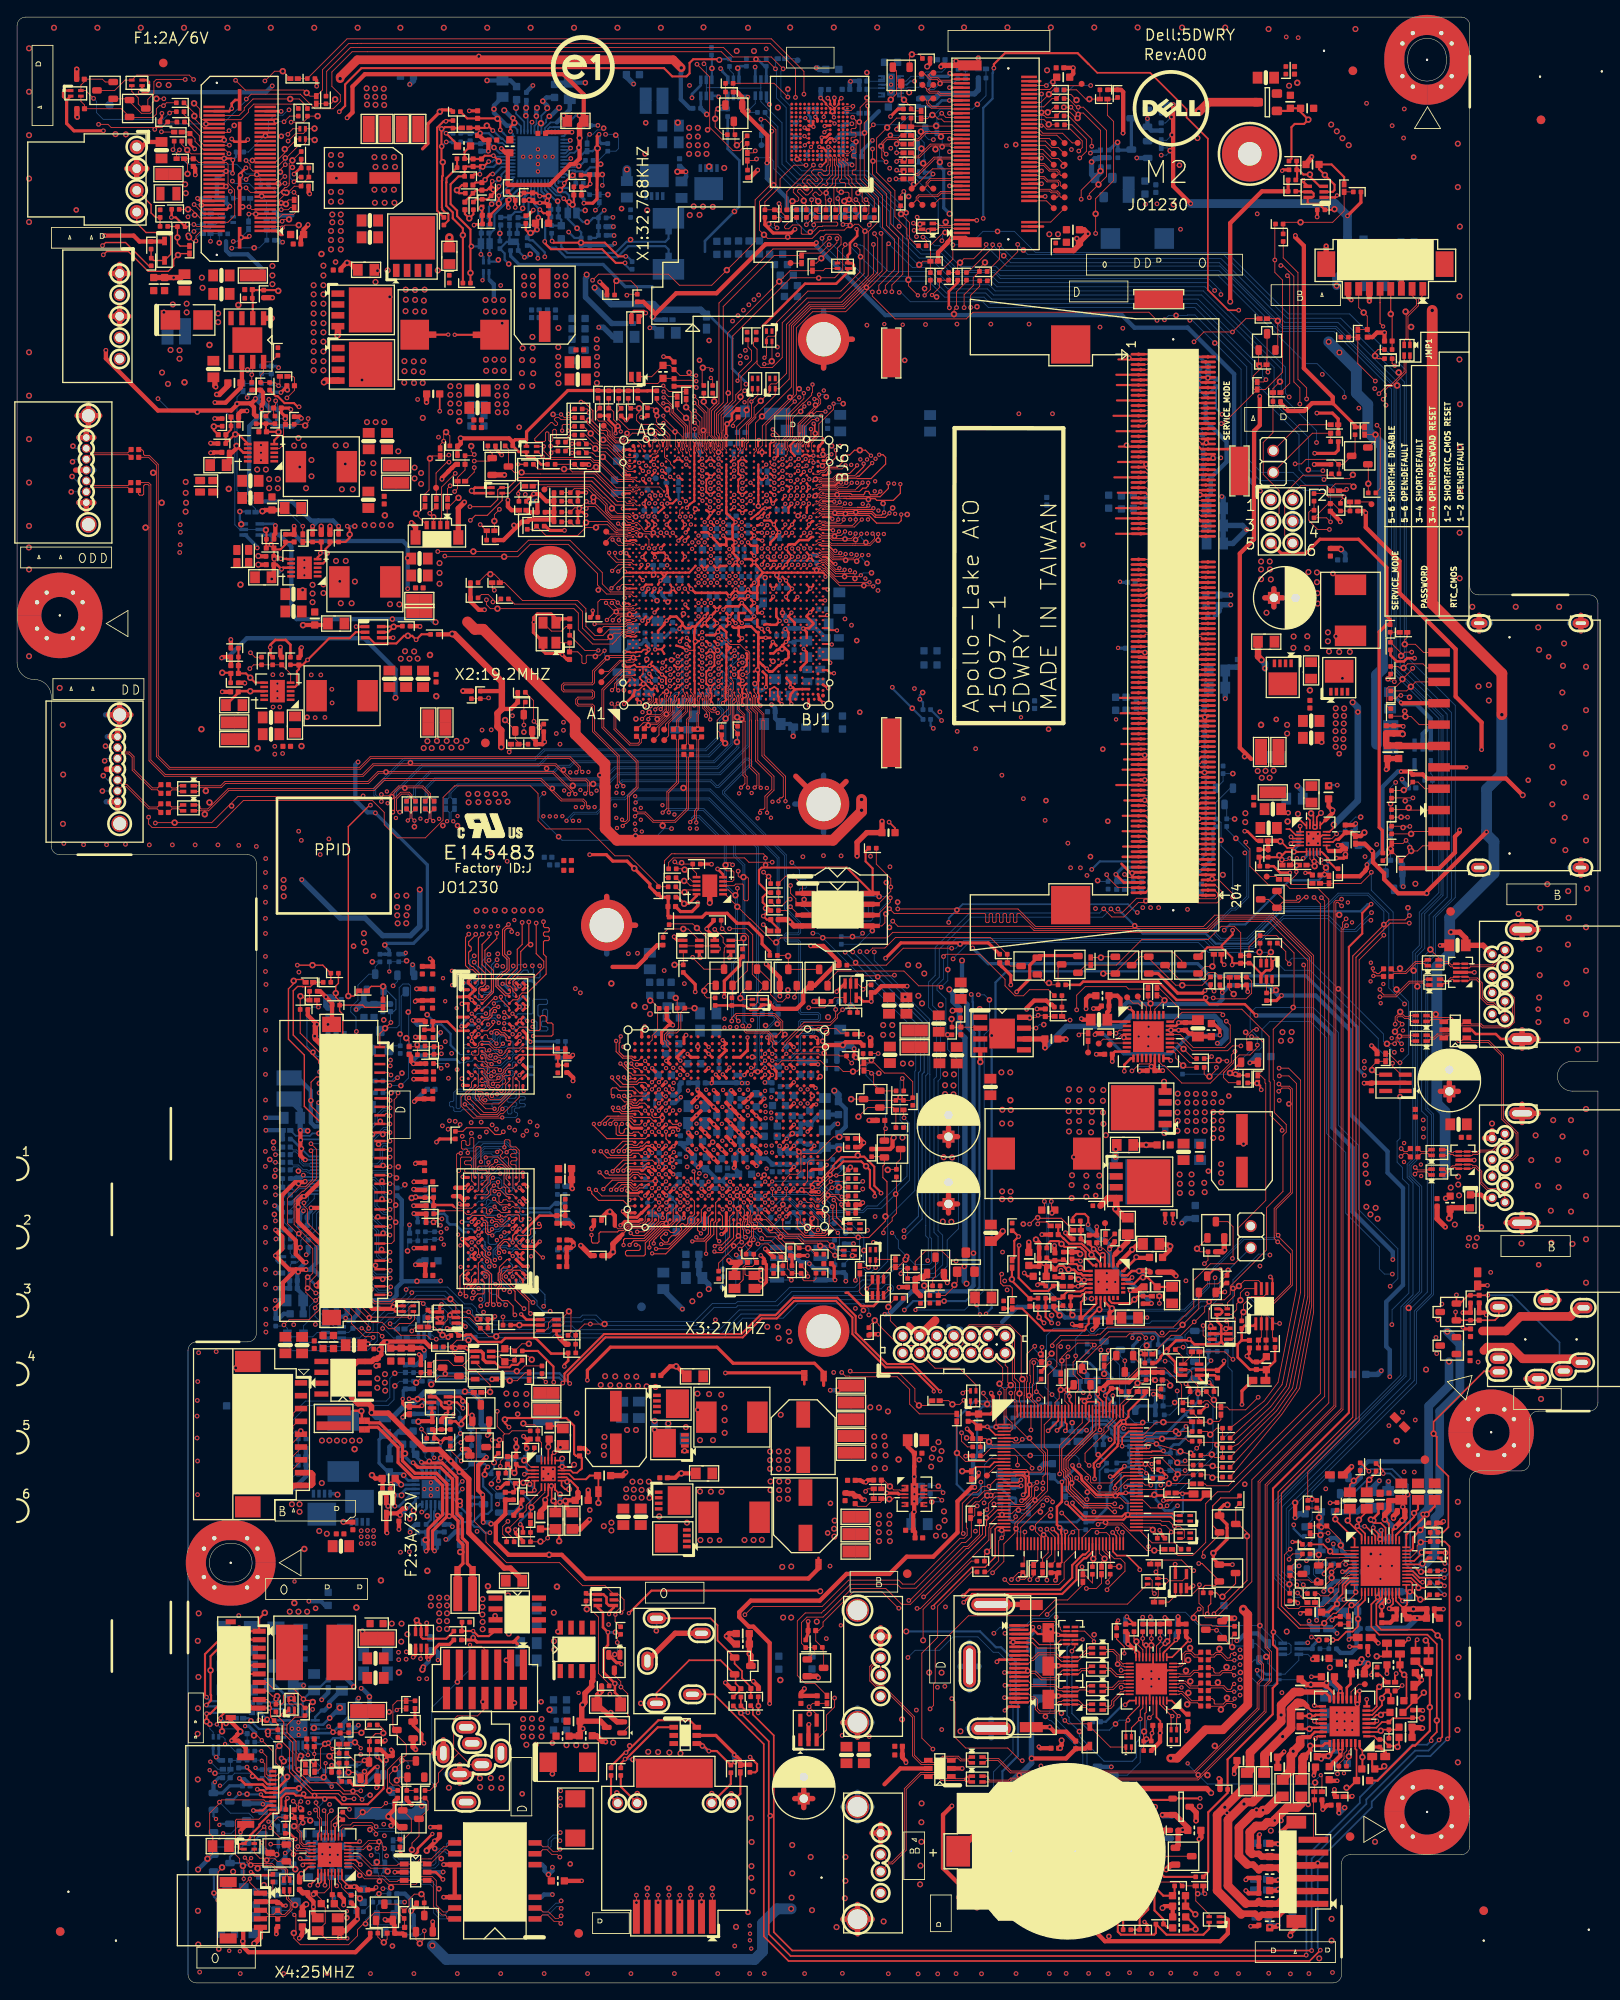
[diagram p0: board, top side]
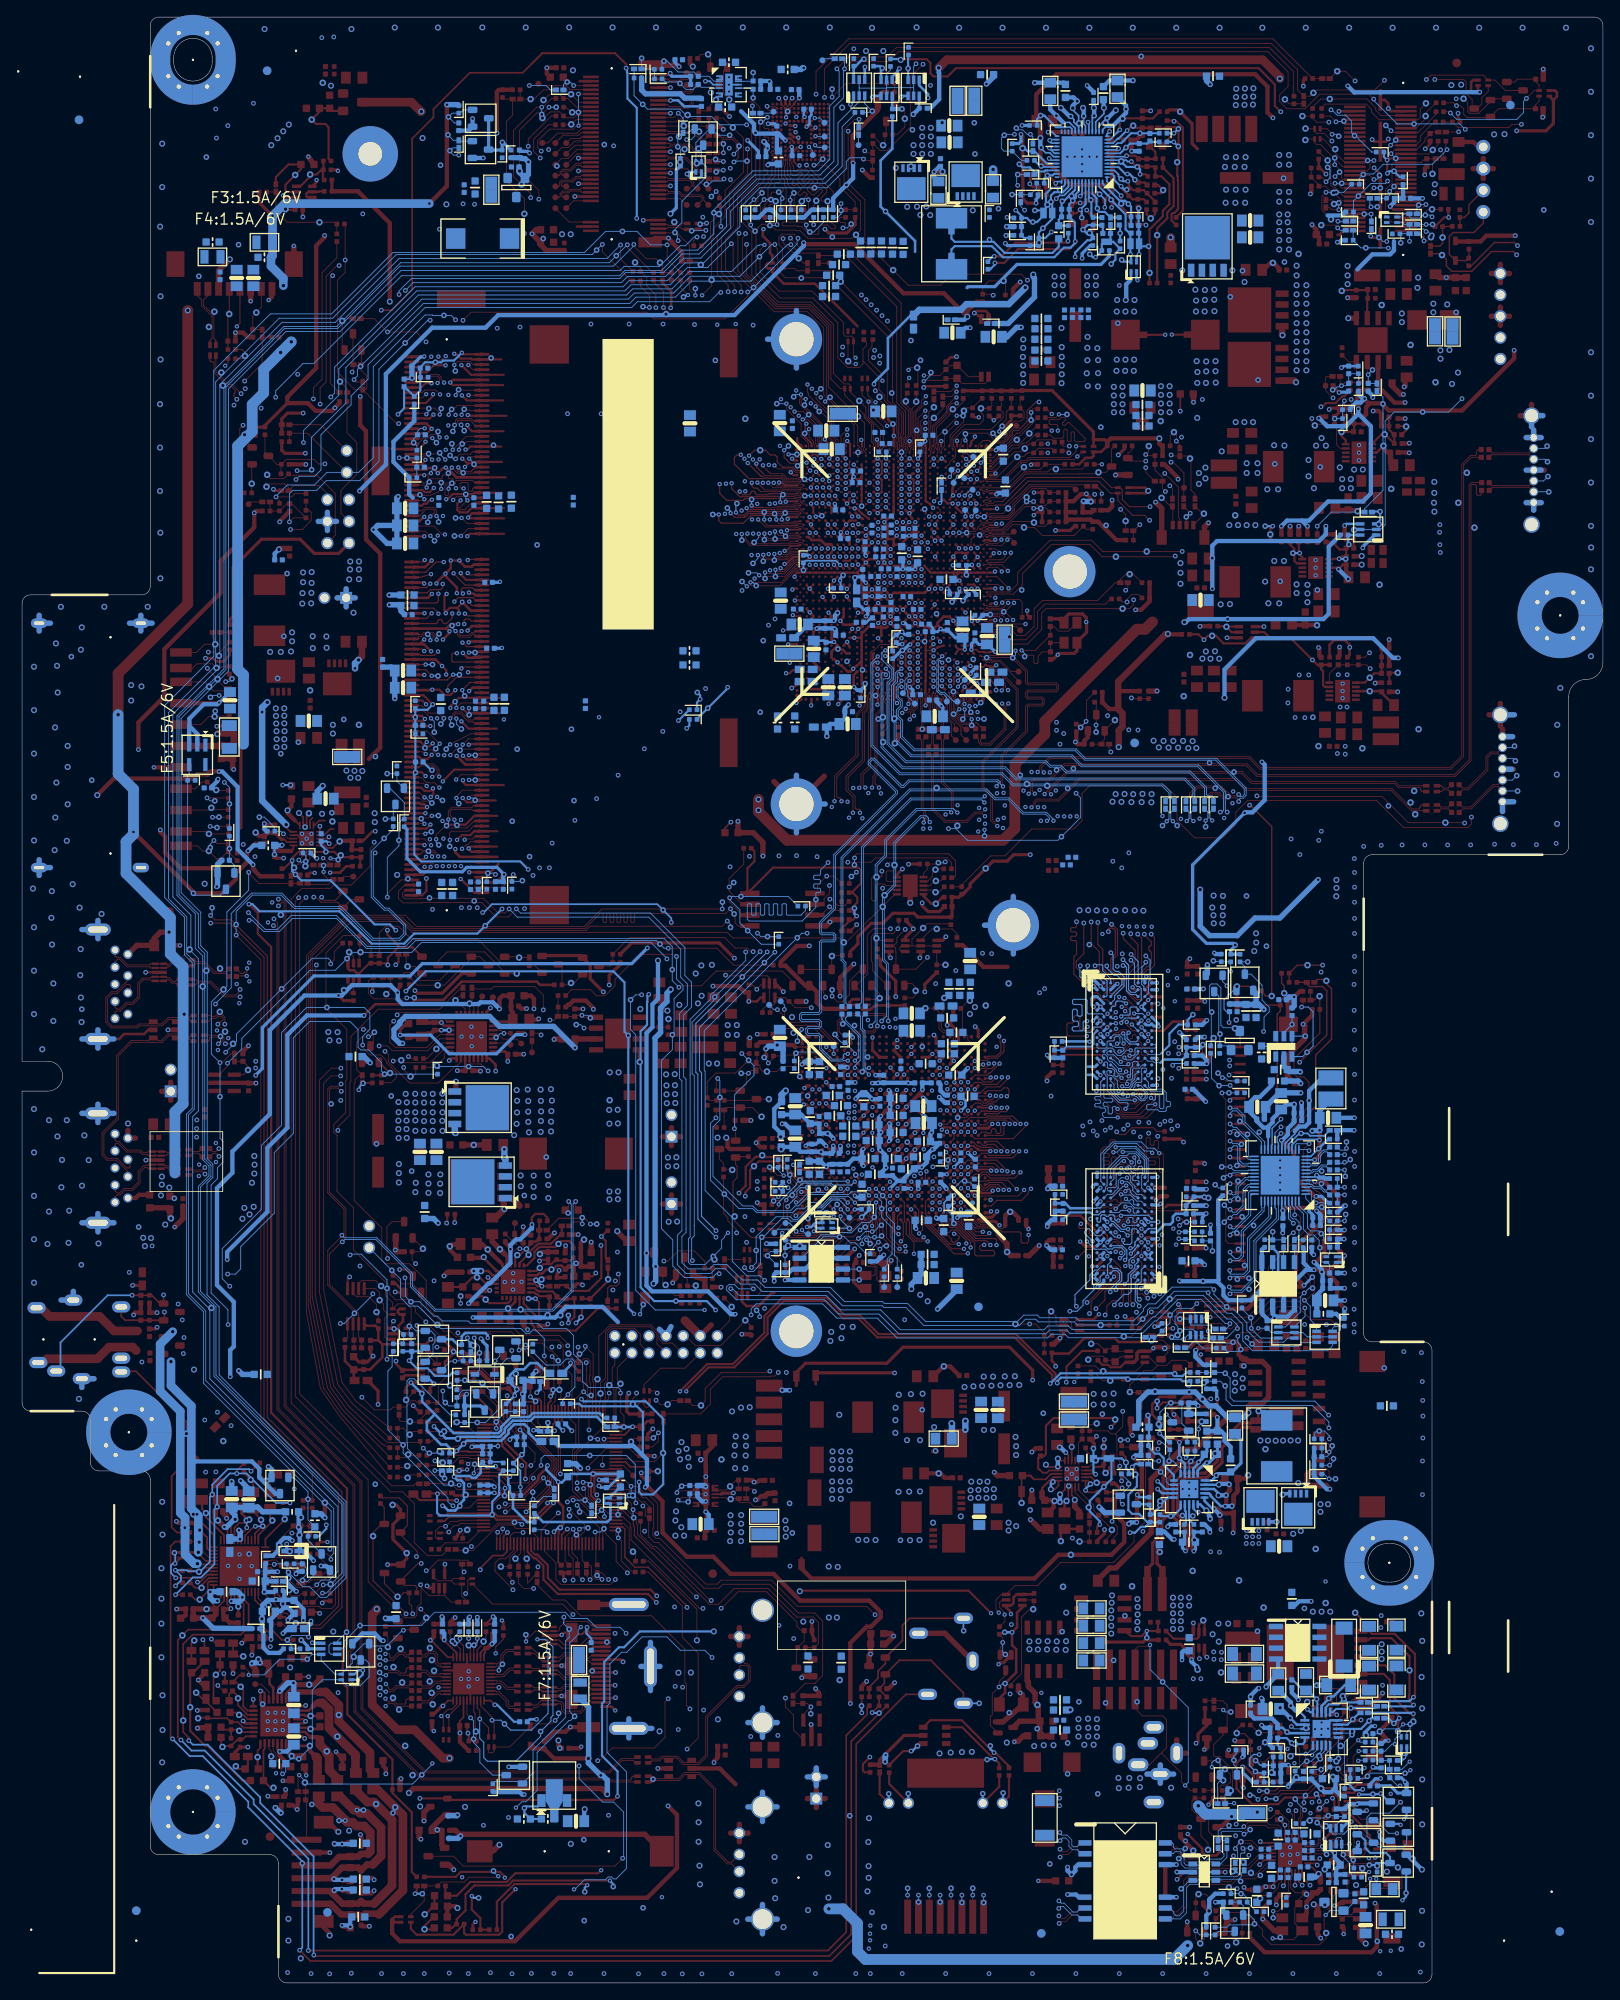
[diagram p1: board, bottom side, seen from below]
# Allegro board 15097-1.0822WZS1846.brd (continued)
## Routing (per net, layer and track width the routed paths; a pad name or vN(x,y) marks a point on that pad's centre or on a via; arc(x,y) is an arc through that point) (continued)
SPI_CLK_ROM_KBC: length 115.4
  TOP w0.102: R360.2 145.91,68.07 147.56,70.27 149.71,81.07 149.71,105.24 148.83,106.12 v1(147.72,106.12)
  L4 w0.114: v1(147.72,106.12) 147.02,106.12 146.72,105.82 146.72,103.23 146.59,103.1 145.06,103.1 144.93,103.23 144.93,105.19 145.04,105.3 145.89,105.3 146.01,105.42 146.01,105.76 145.89,105.88 145.04,105.88 144.93,105.99 144.93,106.33 145.04,106.45 145.89,106.45 146.01,106.56 146.01,106.9 145.89,107.02 145.04,107.02 144.93,107.13 144.93,108.09 144.45,108.57 143.98,108.57 143.38,109.16 143.02,109.16 142.75,109.43 142.75,109.8 140.02,112.52 138.22,112.52 136.18,114.57 116.73,114.57 108.24,123.06 101.37,123.06 100.92,123.51 99.24,123.51 98.94,123.21 v1(98.94,122.82)
  BOTTOM w0.102: R632.1 v2(97.76,122.42) 98.54,122.42 v1(98.94,122.82)
SPI_CLK_ROM_MUX: length 3.3
  TOP w0.102: U2.7 79.03,128.87 78.47,129.44 78.47,129.87 78.11,130.23 78.11,130.25 v4(78.11,130.25) 78.01,130.35 R199.2
SPI_CS0_N_ROM: length 27
  TOP w0.102: R207.2 R204.2 89.07,127.59 R201.2 89.94,129.49 v1(90.84,129.49) 91.92,128.41 SRCON1.1 ; v1(87.57,131.61) 87.57,131.87 87.34,132.11 76.98,132.11 76.58,132.11 75.76,131.29 75.76,129.48 75.93,129.31 R202.1
  L4 w0.114: v1(90.84,129.49) 88.79,129.49 87.59,130.7 87.59,131.6 v1(87.57,131.61)
  BOTTOM w0.102: v2(87.59,130.8) 87.57,130.82 v1(87.57,131.61)
SPI_CS0_N_ROM_CPU: length 135.5
  TOP w0.102: v1(87.35,129.96) 88.18,129.13 R201.1 ; R129.1 64.98,180.06 v3(64.96,180.09)
  L4 w0.114: v1(87.35,129.96) 86.89,129.96 86.69,130.16 86.69,130.4 86.81,130.52 87.2,130.52 87.32,130.65 87.32,130.85 87.2,130.98 86.81,130.98 86.69,131.09 86.69,131.32 86.81,131.43 87,131.43 87.11,131.55 87.11,131.78 87,131.89 86.81,131.89 85.41,133.28 82.18,133.28 82.05,133.41 82.05,133.72 82.18,133.85 86.2,133.85 86.33,133.97 86.33,134.18 86.2,134.3 82.18,134.3 82.05,134.43 82.05,134.63 82.18,134.76 85.32,134.76 85.44,134.89 85.44,135.09 85.32,135.22 82.18,135.22 82.05,135.34 82.05,135.55 82.18,135.67 84.49,135.67 84.62,135.8 84.62,135.98 84.46,136.13 82.18,136.13 82.05,136.26 82.05,136.73 81.93,136.86 81.34,136.86 81.23,136.97 81.23,138.47 81.11,138.59 80.89,138.59 80.77,138.47 80.77,136.97 80.66,136.86 80.43,136.86 80.31,136.97 80.31,138.47 80.2,138.59 79.97,138.59 79.86,138.47 79.86,136.97 79.74,136.86 79.5,136.86 79.26,137.1 79.26,138.46 71.64,146.08 71.15,146.08 70.39,146.84 70.39,147 71.01,147.62 71.01,147.8 70.87,147.95 70.69,147.95 70.06,147.32 69.9,147.32 69.74,147.48 69.74,147.64 70.14,148.04 70.14,148.2 69.97,148.36 69.81,148.36 69.42,147.97 69.25,147.97 63.69,153.53 63.69,154.79 63.18,155.31 61.87,155.31 61.76,155.19 61.76,154.72 61.63,154.59 61.42,154.59 61.3,154.72 61.3,155.19 61.18,155.31 60.68,155.31 60,155.99 60,159.94 60.58,160.52 61.19,160.52 61.31,160.65 61.31,160.93 61.43,161.04 63.67,161.04 63.8,161.17 63.8,161.37 63.67,161.5 61.43,161.5 61.31,161.62 61.31,161.84 61.43,161.96 63.67,161.96 63.8,162.09 63.8,162.29 63.67,162.42 61.43,162.42 61.31,162.53 61.31,162.77 60,164.09 60,166.11 61.4,167.51 63.94,167.51 64.64,166.81 64.64,165.97 64.77,165.84 64.97,165.84 65.1,165.97 65.1,167.79 64.99,167.9 64.53,167.9 64.4,168.03 64.4,168.23 64.53,168.36 64.99,168.36 65.1,168.48 65.1,168.86 64.99,168.97 64.63,168.97 64.52,169.09 64.52,169.32 64.63,169.43 64.99,169.43 65.1,169.54 65.1,169.94 64.99,170.06 64.63,170.06 64.52,170.17 64.52,170.4 64.63,170.52 64.99,170.52 65.1,170.63 65.1,170.87 64.99,170.99 64.33,170.99 64.22,171.1 64.22,171.33 64.33,171.44 64.99,171.44 65.1,171.56 65.1,171.8 64.99,171.91 64.33,171.91 64.22,172.03 64.22,172.26 64.33,172.37 64.99,172.37 65.1,172.48 65.1,172.71 64.99,172.83 64.33,172.83 64.22,172.94 64.22,173.17 64.33,173.28 64.99,173.28 65.1,173.4 65.1,173.63 64.99,173.74 64.33,173.74 64.22,173.86 64.22,174.08 64.33,174.2 64.99,174.2 65.1,174.31 65.1,174.54 64.99,174.66 64.33,174.66 64.22,174.77 64.22,175 64.33,175.11 64.99,175.11 65.1,175.23 65.1,175.46 64.99,175.57 64.33,175.57 64.22,175.68 64.22,175.91 64.33,176.03 64.99,176.03 65.1,176.14 65.1,176.37 64.99,176.48 64.33,176.48 64.22,176.6 64.22,176.83 64.33,176.94 64.99,176.94 65.1,177.06 65.1,177.28 64.99,177.4 64.33,177.4 64.22,177.51 64.22,177.74 64.33,177.86 64.99,177.86 65.1,177.97 65.1,178.21 64.99,178.33 64.95,178.33 64.46,178.81 64.46,179.22 64.52,179.28 64.52,179.96 64.65,180.09 v3(64.96,180.09)
  BOTTOM w0.102: v1(87.35,129.96) 87.87,129.45 v2(87.94,129.45)
SPI_CS0_N_ROM_KBC: length 130.5
  TOP w0.102: R368.2 143.23,62.81 147.39,66.94 149.27,69.62 151.27,79.74 151.27,119.96 146.76,124.47 140.61,124.47 139.28,123.14 129.98,123.14 129.98,123.14 119.08,123.14 118.99,123.14 118.52,123.62 103.08,123.62 v1(102.47,124.23) ; v1(90.47,126.8) 90.28,126.8 89.54,126.06 88.69,126.06 R207.1
  L4 w0.114: v1(102.47,124.23) 101.68,124.23 100.83,125.07 94.54,125.07 92.24,127.38 90.91,127.38 90.47,126.94 v1(90.47,126.8)
  BOTTOM w0.102: v1(102.47,124.23) 102.09,123.85 v2(102.09,123.49)
SPI_CS0_R_CPU: length 9.7
  TOP w0.102: CPU1.B57 71.4,176.84 71.24,177 71.01,177 68.87,179.15 68.03,179.15 v4(67.66,179.52) 67.12,180.06 R129.2 66.14,180.54 64.45,180.54 R127.1
SPI_CS_CPU_MUX: length 102.9
  TOP w0.102: R127.2 63.29,179.93 63.16,179.81 v1(62.44,179.81) ; v1(84.39,130.07) 84.39,129.51 84.51,129.38 v4(85,129.38) 85.45,129.38 85.58,129.25 85.58,126.74 85.45,126.61 85.15,126.61 85.03,126.74 85.03,128.44 84.9,128.56 84.09,128.56 83.9,128.37 U2.3
  L4 w0.114: v1(62.44,179.81) 62.83,179.81 62.99,179.65 62.99,172.26 58.97,168.25 58.97,155.6 68.69,145.88 68.69,145.55 67.97,144.82 67.97,144.64 68.15,144.46 68.33,144.46 69.13,145.25 69.33,145.25 69.78,144.79 69.98,144.79 69.98,144.79 71.29,144.79 77.92,138.16 77.92,134.03 78.04,133.91 80.05,133.91 80.16,133.8 80.16,133.57 80.05,133.46 78.04,133.46 77.92,133.34 77.92,133.11 78.04,133 80.05,133 80.16,132.89 80.16,132.66 80.05,132.54 78.04,132.54 77.92,132.43 77.92,132.2 78.04,132.09 80.05,132.09 80.16,131.97 80.16,131.74 80.05,131.63 78.04,131.63 77.92,131.51 77.92,131.29 78.04,131.17 80.05,131.17 80.16,131.06 80.16,130.83 80.05,130.71 78.04,130.71 77.92,130.6 77.92,130.37 78.04,130.26 79.02,130.26 79.14,130.14 79.14,129.9 79.02,129.79 78.04,129.79 77.92,129.67 77.92,129.44 78.04,129.33 82.96,129.33 83.17,129.54 83.17,131.17 83.29,131.3 84.48,131.3 84.61,131.17 84.61,130.3 v1(84.39,130.07)
SPI_CS_KBC_MUX: length 133.9
  TOP w0.102: U2.1 82.87,127.37 84.23,126.01 84.23,125.97 v4(84.28,125.91) 84.33,125.91 85.77,124.47 85.82,124.47 88.55,121.74 v4(88.83,121.74) 89.35,122.26 101.82,122.26 102.48,122.91 129.88,122.91 129.88,122.91 139.38,122.91 140.65,124.18 141.79,124.18 141.82,124.21 142.68,124.21 142.7,124.18 146.47,124.18 151.04,119.61 151.04,80.26 148.92,69.9 148.83,69.62 147.05,67.13 142.87,63.04 R365.2
SPI_CS_ROM_MUX: length 2.8
  TOP w0.102: R202.2 77.49,128.93 v4(78.06,128.93) 78.21,128.93 78.77,128.37 U2.8
SPI_DATAIN_N_CPU: length 7.9
  TOP w0.102: CPU1.B58 71.95,177.11 71.54,177.11 69.07,179.58 68.43,179.58 67.85,180.16 67.46,180.16 66.52,181.1 R123.2
SPI_DATAIN_ROM: length 256.5
  TOP w0.102: v3(63.79,181.61) 63.79,182.21 63.91,182.34 64.68,182.34 64.8,182.47 64.8,182.78 64.68,182.91 63.65,182.91 63.39,183.16 63.06,183.16 62.9,183 62.9,182.86 63.24,182.51 63.24,182.34 63.13,182.22 62.96,182.22 62.61,182.57 62.47,182.57 60.58,180.69 60.58,180.45 60.71,180.33 61.7,180.33 61.83,180.45 61.83,181.35 61.95,181.47 62.12,181.47 62.24,181.35 62.24,180.45 62.36,180.33 62.56,180.33 62.68,180.45 62.68,181.65 62.81,181.77 62.98,181.77 63.1,181.65 63.1,180.86 63.22,180.73 64.29,180.73 64.33,180.77 64.66,181.1 R123.1 ; SRCON1.2 91.45,126.21 91.14,126.52 91.14,126.85 90.51,127.48 v1(90.51,128.4) ; v1(103.06,125.65) 117.13,125.65 119.18,123.6 138.83,123.6 140.15,124.92 147,124.92 151.72,120.2 151.72,78.6 151.72,78.44 150.09,69.57 147.98,66.49 R377.2
  L4 w0.114: v3(63.79,181.61) 63.51,181.33 63.51,181.09 63.62,180.97 64.07,180.97 64.2,180.85 64.2,180.64 64.07,180.52 63.62,180.52 63.51,180.4 63.51,172.1 62.74,171.33 62.74,171.16 63.4,170.5 63.4,170.34 63.24,170.18 63.08,170.18 62.41,170.84 62.25,170.84 62.09,170.68 62.09,170.52 63.36,169.25 63.36,169.09 63.2,168.93 63.03,168.93 61.77,170.19 61.61,170.19 61.44,170.03 61.44,169.87 62.66,168.66 62.66,168.48 62.52,168.33 62.34,168.33 61.12,169.55 60.96,169.55 60.8,169.39 60.8,169.22 61.46,168.56 61.46,168.4 61.3,168.24 61.14,168.24 60.47,168.9 60.31,168.9 60.15,168.74 60.15,168.58 60.81,167.92 60.81,167.75 60.65,167.59 60.49,167.59 59.83,168.25 59.67,168.25 59.49,168.08 59.49,167.53 59.61,167.42 59.96,167.42 60.09,167.29 60.09,167.09 59.96,166.96 59.61,166.96 59.49,166.85 59.49,163.18 59.62,163.05 60.3,163.05 60.43,162.92 60.43,162.72 60.3,162.59 59.62,162.59 59.49,162.46 59.49,162.26 59.62,162.13 60.68,162.13 60.8,162.01 60.8,161.8 60.68,161.68 59.62,161.68 59.49,161.55 59.49,161.35 59.62,161.22 60.12,161.22 60.25,161.09 60.25,160.89 60.12,160.76 59.62,160.76 59.49,160.64 59.49,155.83 59.51,155.81 59.51,155.79 70.01,145.29 71.71,145.29 78.68,138.32 78.68,136.54 78.85,136.37 80.52,136.37 80.64,136.25 80.64,131.9 80.77,131.77 82.79,131.77 83.2,132.18 84.87,132.18 85.21,131.84 85.54,131.84 85.66,131.73 85.66,131.5 85.54,131.38 85.21,131.38 85.09,131.27 85.09,131.04 85.21,130.93 85.54,130.93 85.66,130.81 85.66,130.58 85.54,130.47 85.21,130.47 85.09,130.36 85.09,130.11 85.21,130 86.11,130 86.24,129.87 86.24,129.67 86.11,129.54 85.21,129.54 85.09,129.43 85.09,128.94 85.21,128.83 87.08,128.83 87.19,128.71 87.68,128.71 87.8,128.6 87.8,128.05 87.92,127.92 88.13,127.92 88.25,128.05 88.25,128.6 88.37,128.71 88.6,128.71 88.71,128.6 88.71,127.08 88.84,126.95 89.04,126.95 89.17,127.08 89.17,128.6 89.28,128.71 89.51,128.71 89.83,128.4 v1(90.51,128.4) 90.56,128.4 90.73,128.23 92.68,128.23 95.32,125.6 101.23,125.6 101.7,125.12 102.52,125.12 v1(103.06,125.65)
  BOTTOM w0.102: v2(103.04,126.45) 103.04,125.66 v1(103.06,125.65)
SPI_DATAOUT_N_CPU: length 7.5
  TOP w0.102: R122.2 66.29,182.12 v4(67.12,181.29) 67.12,181.21 68.4,179.93 69.13,179.93 71.62,177.44 CPU1.A58
SPI_DATAOUT_ROM: length 254.1
  TOP w0.102: R371.2 142.84,61.31 147.68,66.65 149.71,69.6 151.5,79.2 151.5,120.07 146.87,124.7 140.51,124.7 139.18,123.37 130.07,123.37 130.07,123.37 129.69,123.37 119.09,123.37 117.34,125.13 117.11,125.13 117.01,125.02 117.01,124.16 116.9,124.05 116.7,124.05 116.6,124.16 116.6,125.02 116.5,125.13 116.29,125.13 116.19,125.02 116.19,124.16 116.09,124.05 115.89,124.05 115.79,124.16 115.79,125.02 115.68,125.13 115.48,125.13 115.38,125.02 115.38,124.16 115.28,124.05 115.07,124.05 114.97,124.16 114.97,125.02 114.87,125.13 114.67,125.13 114.57,125.02 114.57,124.16 114.47,124.05 114.26,124.05 114.16,124.16 114.16,125.02 114.06,125.13 113.86,125.13 113.75,125.02 113.75,124.16 113.65,124.05 113.45,124.05 113.35,124.16 113.35,125.02 113.25,125.13 102.64,125.13 v1(102.09,125.68) 101.56,125.15 101.56,124.03 101.2,123.67 SRCON1.5 ; v3(64.5,181.61) 65.01,182.12 R122.1
  L4 w0.114: v1(102.09,125.68) 102.09,125.92 101.86,126.14 95.71,126.14 92.9,128.96 92.11,128.96 92,129.07 92,129.51 91.89,129.63 91.54,129.63 91.43,129.51 91.43,129.07 91.31,128.96 87.29,128.96 87.18,129.07 86.72,129.07 86.48,129.31 86.48,129.97 86.3,130.15 86.3,132.04 85.93,132.42 85.29,132.42 85.17,132.54 85.17,132.93 85.06,133.04 84.71,133.04 84.6,132.93 84.6,132.54 84.49,132.42 84.14,132.42 84.03,132.54 84.03,132.93 83.91,133.04 83.57,133.04 83.46,132.93 83.46,132.54 83.34,132.42 83.1,132.42 82.78,132.1 82.19,132.1 82.07,132.22 82.07,132.6 82.07,132.6 82.07,132.89 81.94,133.02 81.63,133.02 81.5,132.89 81.5,132.25 81.37,132.12 81.01,132.12 80.88,132.25 80.88,133.83 81,133.95 81.7,133.95 81.81,134.06 81.81,134.29 81.7,134.4 81,134.4 80.88,134.52 80.88,134.75 81,134.86 81.7,134.86 81.81,134.98 81.81,135.2 81.7,135.32 81,135.32 80.88,135.43 80.88,135.66 81,135.78 81.7,135.78 81.81,135.89 81.81,136.12 81.7,136.23 81,136.23 80.62,136.61 79.26,136.61 78.93,136.95 78.93,138.42 78.9,138.44 78.9,138.46 71.61,145.75 69.89,145.75 69.72,145.92 69.72,146.08 70.18,146.54 70.18,146.7 70.02,146.86 69.85,146.86 69.4,146.41 69.24,146.41 69.07,146.57 69.07,146.73 69.53,147.19 69.53,147.35 69.37,147.51 69.21,147.51 68.75,147.05 68.59,147.05 68.43,147.22 68.43,147.38 68.88,147.83 68.88,147.99 68.72,148.16 68.56,148.16 68.1,147.7 67.94,147.7 67.78,147.86 67.78,148.02 68.24,148.48 68.24,148.64 68.08,148.8 67.91,148.8 67.46,148.35 67.3,148.35 67.13,148.51 67.13,148.67 67.59,149.13 67.59,149.29 67.43,149.45 67.27,149.45 66.81,148.99 66.65,148.99 66.49,149.16 66.49,149.32 66.94,149.77 66.94,149.93 66.78,150.1 66.62,150.1 66.16,149.64 66,149.64 65.84,149.8 65.84,149.96 66.3,150.42 66.3,150.58 66.14,150.74 65.97,150.74 65.52,150.29 65.36,150.29 65.19,150.45 65.19,150.61 65.65,151.07 65.65,151.23 65.49,151.39 65.33,151.39 64.87,150.93 64.71,150.93 64.55,151.1 64.55,151.26 65,151.71 65,151.87 64.84,152.04 64.68,152.04 64.22,151.58 64.06,151.58 63.9,151.74 63.9,151.9 64.36,152.36 64.36,152.52 64.2,152.68 64.03,152.68 63.58,152.23 63.42,152.23 63.25,152.39 63.25,152.55 63.71,153.01 63.71,153.17 63.55,153.33 63.39,153.33 62.93,152.87 62.77,152.87 62.61,153.04 62.61,153.2 63.44,154.03 63.44,154.21 63.3,154.36 63.12,154.36 62.28,153.52 62.12,153.52 61.96,153.68 61.96,153.84 62.87,154.75 62.87,154.93 62.73,155.07 62.54,155.07 61.64,154.17 61.48,154.17 59.75,155.89 59.75,160.03 61.06,161.34 61.06,162.68 59.75,163.99 59.75,166.35 61.58,168.18 61.74,168.18 62.15,167.77 62.33,167.77 62.79,168.22 62.99,168.22 63.43,167.78 63.61,167.78 63.75,167.93 63.75,168.11 63.33,168.54 63.33,168.72 63.47,168.86 63.65,168.86 63.96,168.55 64.14,168.55 64.28,168.68 64.28,168.88 63.36,169.8 63.36,169.96 63.98,170.58 63.98,179.84 64.5,180.36 v3(64.5,181.61)
  BOTTOM w0.102: v2(101.67,125.07) 101.67,125.07 102.09,125.49 v1(102.09,125.68)
SPI_IO2_N_CPU: length 8.6
  TOP w0.102: R117.2 66.68,182.59 66.68,182.52 68.58,180.62 v4(68.58,180.54) 68.68,180.44 68.99,180.44 70.26,179.17 70.26,179.07 71.55,177.78 72.02,177.78 CPU1.B60
SPI_IO2_ROM: length 96.4
  TOP w0.102: SRCON1.3 91.48,124.94 v1(90.5,125.92) 90.06,125.47 R209.2 ; v3(63.66,183.51) 64.04,183.13 R117.1
  L4 w0.114: v1(90.5,125.92) 90.41,126.01 90.41,126.06 90.01,126.46 88.99,126.46 86.87,128.58 85.12,128.58 84.85,128.84 84.85,131.45 84.72,131.57 82.94,131.57 82.72,131.36 82.72,129.98 82.59,129.85 80.7,129.85 80.4,130.15 80.4,134.37 80.27,134.5 78.35,134.5 78.22,134.62 78.22,138.42 71.61,145.03 69.88,145.03 59.22,155.7 59.22,168.15 63.24,172.17 63.24,180.43 63.13,180.54 61.86,180.54 61.74,180.66 61.74,180.88 61.86,181 63.13,181 63.24,181.11 63.24,181.34 63.13,181.46 61.86,181.46 61.74,181.57 61.74,181.8 61.86,181.91 63.13,181.91 63.24,182.03 63.24,182.13 63.36,182.24 64.8,182.24 64.91,182.35 64.91,182.58 64.8,182.7 63.36,182.7 63.24,182.81 63.24,183.1 v3(63.66,183.51)
  BOTTOM w0.102: v3(63.66,183.51) v2(62.72,183.51)
SPI_IO3_N_CPU: length 10.3
  TOP w0.102: R111.2 66.71,184.15 66.91,183.95 v1(66.91,183.74) 67.05,183.6 67.05,182.54 68.28,181.32 68.55,181.32 68.6,181.32 69.14,180.77 69.14,180.65 71.34,178.46 72.09,178.46 CPU1.B61
  BOTTOM w0.102: v2(66.91,182.85) v1(66.91,183.74)
SPI_IO3_ROM: length 92
  TOP w0.102: R111.1 65.08,184.15 v3(64.5,183.57) ; SRCON1.7 100.74,126.21 102.25,127.71 v1(102.25,128.22) 102.25,129.21 100.55,130.91 R194.2
  L4 w0.114: v1(102.25,128.22) 95.9,128.22 92.99,131.12 91.51,131.12 90.84,131.79 90.21,131.79 82.41,139.6 79.54,139.6 72.73,146.4 72.73,148.67 72.47,148.93 69.76,148.93 69.16,149.54 69.16,152.04 68.72,152.48 66.21,152.48 64.79,153.9 64.79,162.34 66.09,163.64 66.09,181.97 v3(64.5,183.57)
  BOTTOM w0.102: v1(102.25,128.22) 102.25,128.22 v2(101.72,128.74)
SPKR_DET: length 58.1
  TOP w0.102: v1(123.55,52.73) 123.46,52.73 123.05,52.32 U14.48 ; v3(152.56,24.31) 152.7,24.17 R475.1
  L3 w0.127: v1(123.55,52.73) 123.93,52.73 126.17,50.5 128.38,50.5 132.11,46.76 132.77,46.76 138.5,41.03 138.5,27.2 v3(136.98,25.68)
  BOTTOM w0.102: v3(136.98,25.68) 136.98,25.58 v2(138.22,24.35) 139.3,23.27 151.52,23.27 v3(152.56,24.31) ; v1(123.55,52.73) 123.55,52.83 123.75,53.02 R745.2
SPKR_DET_C: length 6.8
  TOP w0.102: v4(151.9,23.44) 151.81,23.36 R475.2 PC126.2 151.7,21.3 SPK1.6
SPKR_IN_L: length 5.5
  TOP w0.203: C191.2 160.76,33.77 C187.2 159.72,33.52 v4(159.72,33.3) 159.72,32.49 158.59,31.36 U22.6
SPKR_IN_R: length 6
  TOP w0.203: U22.31 156.6,27.39 156.75,27.25 C217.2
  TOP w0.254: C217.2 155.91,22.83 v4(155.58,22.83)
SPKR_L+_C: length 26.8
  TOP w0.762: SPK1.1 148.91,9.25 147.67,8.02 R504.1 145.64,7.98 C231.1 144.88,8.1 143.35,8.1 143.25,8
  TOP w1.016: 143.25,8 140.43,10.82 140.43,19.65 v4(141.33,20.55) 143.42,22.63 L12.2
SPKR_L+_SNB: length 3.3
  TOP w0.508: v1(147.56,6.73) 147.43,6.6 R504.2
  BOTTOM w0.508: v1(147.56,6.73) 146.76,6.73 146.6,6.56 v2(146.59,6.56) 146.59,6.57 146.59,7.54 C545.1
SPKR_L-_C: length 25.2
  TOP w0.762: 143.8,9.27 145,9.27 C228.1 145.64,9.27 147.49,9.27 148.97,10.75 SPK1.2
  TOP w1.016: L13.2 145.93,22.5 144.59,21.16 143.8,21.16 v4(143.57,20.93) 141.7,19.06 141.7,11.37 143.8,9.27
SPKR_L-_SNB: length 3.4
  TOP w0.508: v1(147.58,10.97) 147.45,10.85 147.45,10.79 R496.2
  BOTTOM w0.508: C540.1 146.34,10.97 v1(147.58,10.97) 148.32,10.97 v2(148.47,10.83)
SPKR_OUT_L+: length 16.4
  TOP w0.305: 152.68,33.97 153.11,33.97 153.6,33.47 U22.16
  TOP w0.635: C183.2 152.62,34.04 152.68,33.97
  TOP w1.016: L12.1 144.28,24.94 C212.1 144.28,26.95 147.93,30.59 v4(147.93,31.35) 147.93,32.5 149.46,34.04 C183.2
SPKR_OUT_L-: length 13.2
  TOP w0.305: U22.18 151.46,31.86 150.95,32.37
  TOP w0.635: C193.2 150.55,32.77 150.95,32.37
  TOP w1.016: L13.1 145.98,24.61 C211.1 145.98,26.7 v4(148.1,28.82) 149.08,29.8 149.08,32 149.84,32.77 C193.2
SPKR_OUT_R+: length 6.8
  TOP w0.305: U22.25 153.07,28.02 152.79,27.74 v4(151.33,27.74)
  TOP w0.508: C210.2 151.33,27.16 v4(151.33,27.74)
  TOP w1.016: C210.2 150.43,26.26 C213.1 150.43,23.9 L15.1
SPKR_OUT_R-: length 8.6
  TOP w0.305: U22.23 151.87,29.36 151.26,28.75
  TOP w0.508: C199.2 150.45,28.75 151.26,28.75
  TOP w1.016: L14.1 148.12,23.93 149.05,24.87 C214.1 149.05,26.57 149.33,26.85 v4(149.33,27.1) 149.39,27.1 150.15,27.86 C199.2
SPKR_R+_C: length 19.4
  TOP w0.762: 144.52,15.1 C222.1 145.64,14.78 R487.1 147.91,14.73 148.89,13.75 SPK1.4
  TOP w1.016: 144.52,15.1 144.25,15.37 144.25,17.64 144.98,18.36 145.88,18.36 146.31,18.8 146.97,18.8 v1(147.18,19) 147.18,19.08 148.62,20.52 149.82,20.52 150.27,20.98 L15.2
  BOTTOM w0.254: v1(147.18,19) v2(147.91,19)
SPKR_R+_SNB: length 3.2
  TOP w0.508: v1(147.56,16.24) 147.49,16.31 R487.2
  BOTTOM w0.508: v2(148.44,16.28) 148.4,16.24 v1(147.56,16.24) 146.32,16.24 C525.1
SPKR_R-_C: length 20.8
  TOP w0.762: 143.97,13.84 144.65,13.84 C223.1 145.64,13.49 R489.1 147.56,13.49 148.79,12.25 SPK1.3
  TOP w1.016: 143.97,13.84 142.98,14.83 142.98,18.17 144.65,19.84 145.42,19.84 v1(145.8,20.22) 146.18,20.22 147.78,21.82 L14.2
  BOTTOM w0.254: v1(145.8,20.22) v2(145.04,20.22)
SPKR_R-_SNB: length 3.3
  TOP w0.508: R489.2 147.45,11.96 v1(147.56,12.06)
  BOTTOM w0.508: v2(148.49,12.15) 148.4,12.06 v1(147.56,12.06) 146.31,12.06 C538.1
SRTCRST_APS: length 1.7
  TOP w0.102: TP33.1 158.23,173.27 R150.2
SSTCMP: length 3.5
  BOTTOM w0.102: R781.1 31.06,26.15 v2(30.94,26.26) 30.97,26.29 U35.11
SSTCMP_1: length 2.8
  BOTTOM w0.102: v2(31,25.04) 31.21,25.26 R781.2 32.82,24.37 C515.1
STATUS: length 4.7
  BOTTOM w0.102: U35.8 32.93,27.13 34.12,25.93 v2(34.65,25.93) 34.87,25.93 R785.1
STRAP0: length 5
  TOP w0.102: R282.1 v4(96.18,93.09) 95.41,93.09 v1(95.36,93.04) 95.27,93.04 93.93,91.7 GPU1.D1
  BOTTOM w0.102: R665.2 95.98,93.66 v1(95.36,93.04)
STRAP1: length 6.6
  TOP w0.102: R285.1 96.6,92.08 v3(96.5,91.97) 96.25,92.23 94.75,92.23 93.88,91.36 93.45,91.36 93.11,91.7 GPU1.D2
  BOTTOM w0.102: R667.2 95.98,92.49 v3(96.5,91.97) 96.56,91.97 v2(97.05,91.49)
STRAP2: length 9.2
  TOP w0.102: R279.1 96.59,94.46 v3(95.87,94.46) 95.31,94.46 93.82,92.98 91.73,92.98 GPU1.E4
  BOTTOM w0.102: v2(97.51,95.43) 97.51,95.43 R661.2 96.53,95.12 v3(95.87,94.46)
STRAP3: length 8.3
  TOP w0.102: GPU1.E3 92.38,92.55 92.81,92.12 93.99,92.12 94.55,92.68 94.55,93.07 v3(95.23,93.75) 96.9,93.75 R281.1
  BOTTOM w0.102: v3(95.23,93.75) 95.08,93.9 95.08,94.48 v2(95.14,94.54) 95.46,94.86 R660.2
STRAP4: length 11.8
  TOP w0.102: GPU1.D3 92.51,91.29 93.03,91.29 93.29,91.03 93.29,90.78 93.58,90.5 94.31,90.5 95.03,89.78 95.03,88.77 v3(96.05,87.76)
  BOTTOM w0.102: v3(96.05,87.76) 96.22,87.58 96.22,85.79 96.43,85.59 R692.1 97.41,85.59 97.75,85.24 97.75,85.09 v2(97.76,85.09) 96.74,84.07 R697.2
STRAP_REF0: length 11.3
  TOP w0.102: GPU1.F6 89.6,93.65 90,94.06 90,94.19 90.43,94.61 91.36,94.61 91.73,94.98 91.73,96.9 91.85,97.03 93.56,97.03 95.52,98.98 v4(96.22,98.98) 97.01,98.98 R277.2
SUS_LED_GREEN_C: length 163.9
  TOP w0.254: v3(28.53,22.05) 28.83,21.75 PWRCN1.7 ; v3(117.23,13.18) 117.58,12.83 127.27,12.83 128.29,11.81 132.53,11.81 134.13,10.2 R495.2 135.46,10.45 R493.2
  L4 w0.254: v1(26.02,22.15) 24.94,21.08 24.94,16.87 24.87,16.8 24.87,16.8 24.62,16.54 24.62,15.44 23.66,14.48 23.66,14.42 23.65,14.42 23.65,14.08 23.66,14.08 23.66,10.6 24.25,10 24.25,7.1 25.64,5.71 27.87,5.71 29.78,3.81 43.61,3.81 43.61,3.81 43.95,3.81 44.13,3.81 46.87,6.55 46.87,6.55 47.11,6.79 48.14,7.82 48.14,7.99 48.14,7.99 48.14,8.33 48.14,8.33 48.14,8.73 48.14,13.89 47.63,14.4 47.63,18.24 48.44,19.05 57.79,19.05 62.12,23.38 67.49,23.38 68.55,22.33 85.36,22.33 88.11,19.58 88.11,19.56 89.73,17.94 95.76,17.94 98.14,15.55 98.14,10.02 99.94,8.21 113.39,8.21 117.23,12.05 v3(117.23,13.18)
  BOTTOM w0.254: Q72.D 25.1,21.23 v1(26.02,22.15) 26.09,22.09 v2(26.91,22.09) 26.95,22.05 v3(28.53,22.05)
SUS_LED_GREEN_C2: length 2.8
  TOP w0.254: R495.1 136.73,8.99 R501.2 136.85,8.98 137.8,8.03 v4(137.88,8.03)
SUS_PWR_ACK_CPU: length 248.4
  TOP w0.102: v1(95.94,204.09) 95.94,203.61 v4(94.11,201.78) 93.55,201.21 R80.1 ; U14.60 127.85,52.32 127.49,52.68 126.4,52.68 v1(126.37,52.7)
  L3 w0.127: v1(145.13,206.98) 152.36,199.75 152.36,198.97 159.3,192.03 159.3,187.98 164.93,182.35 164.93,175.68 164.94,175.66 164.94,158.63 167.37,156.2 167.37,155.3 167.37,120.63 166.53,119.79 166.53,90.27 165.01,88.75 165.01,83.01 161.84,79.84 161.84,75.38 138.08,51.61 132.97,51.61 130.99,53.59 127.26,53.59 v1(126.37,52.7)
  L4 w0.127: v1(145.13,206.98) 110.45,206.98 109.46,207.97 103.82,207.97 102.24,206.39 102.24,205.18 101.23,204.17 96.02,204.17 v1(95.94,204.09)
SUS_PWR_ACK_CPU_R: length 29.8
  TOP w0.089: 81.85,181.36 81.85,181.15 82.04,180.96 82.04,180.8 82.07,180.78 82.07,180.6 82.07,180.59 CPU1.AC63
  TOP w0.102: RN2.4 94.57,200.58 94.32,200.32 R80.2 90.45,200.32 v4(89.19,199.06) 83.14,193.01 83.14,184.94 81.85,183.65 81.85,181.36
SUSCLK: length 6.9
  TOP w0.102: U14.77 131.96,57.73 131.97,57.72 134.09,57.72 v4(134.79,58.43) 137.59,58.43 R378.1
SUSCLK_NGFF: length 6.4
  TOP w0.102: TP8.1 123.47,215.28 122.35,216.41 120.05,216.41 119.46,217 NGFF1.50
SUSCLK_SIO_C: length 229.5
  TOP w0.089: 82.63,181.69 82.6,181.65 82.6,180.82 82.73,180.69 82.73,179.66 82.99,179.4 82.99,179.05 CPU1.AE62
  TOP w0.102: R378.2 139,58.39 139.23,58.17 141.74,58.17 152.51,68.94 152.51,126.26 v1(151.77,127) ; v1(85.15,186.28) 84.66,185.79 v4(84.66,185.57) 84.66,185.18 82.63,183.16 82.63,181.69
  L3 w0.127: v1(152.94,175.9) 153.14,175.69 155.68,175.69 159.02,172.35 159.02,151.25 159.8,150.48 159.8,142.92 158.69,141.81 158.69,136.44 155.05,132.8 155.05,130.53 151.77,127.25 v1(151.77,127)
  L4 w0.127: v1(85.15,186.28) 86.7,186.28 89.67,189.26 89.67,192.51 94.01,196.85 102.29,196.85 v1(103.23,197.79)
  BOTTOM w0.102: v1(103.23,197.79) 103.44,197.79 104.53,196.7 112.99,196.7 113.67,196.01 137.83,196.01 144.51,189.34 144.51,187.66 146.49,185.67 146.49,184.66 150.02,181.13 150.02,177.01 150.76,176.28 152.56,176.28 v1(152.94,175.9)
SVID0_ALERT#_CPU_R: length 18.2
  TOP w0.089: CPU1.B17 71.92,158.05 71.91,158.06 71.45,158.06 71.36,158.15 70.85,158.15 70.63,157.92 70.01,157.92
  TOP w0.102: R170.2 57.63,161.93 58.23,161.32 65.31,161.32 66.16,160.47 66.16,158.52 67.53,157.15 69.1,157.15 v4(69.44,157.5) 69.87,157.92 70.01,157.92
SVID0_CLK_CPU_R: length 75.2
  TOP w0.089: 70.13,157.18 70.93,157.97 71.28,157.97 71.37,157.88 71.83,157.88 71.95,157.76 72.21,157.76 72.49,158.05 CPU1.C17
  TOP w0.102: v1(54.92,161.82) 54.92,161.25 55.39,160.79 v4(56.21,160.79) 65.16,160.79 65.68,160.27 65.68,158.32 67.35,156.65 69.66,156.65 70.13,157.12 70.13,157.18
  L4 w0.114: v1(54.92,161.82) 54.8,161.95 54.8,178.84 56.8,180.85 58.04,180.85 64.43,187.24 64.43,195.45 65.13,196.15 65.13,200.99 67.75,203.61 67.75,207.34 v1(67.68,207.41)
  BOTTOM w0.102: v1(67.68,207.41) 68.13,207.87 R545.2
SVID0_DATA_CPU_R: length 23.7
  TOP w0.089: 70.46,158.33 71.44,158.33 71.53,158.24 71.84,158.24 72.02,158.37 72.16,158.51 CPU1.C18
  TOP w0.102: PR56.2 54.94,164.82 v4(55.38,164.82) 55.85,164.82 56.48,164.19 R168.2 57.06,163.83 59.14,161.75 65.59,161.75 66.56,160.78 66.56,158.72 67.62,157.66 68.57,157.66 69.24,158.33 70.46,158.33
SW_ON_N_SIO: length 3.8
  TOP w0.102: U14.117 121.45,67.9 121.95,68.4 121.95,69.22 v4(122.13,69.39) R345.1
SWR_LX: length 11.6
  BOTTOM w0.203: 36.05,99.64 36.05,99.35 37.18,98.22 U31.17
  BOTTOM w0.508: 36.05,99.64 36.05,99.67 35.52,100.2 34.83,100.2 34.38,100.66 v2(34.38,103.24) 34.38,104.38 32.87,105.88 L20.2
SWR_V12: length 27.4
  TOP w0.508: v1(34.4,90.68) 37.17,90.68 v1(37.47,90.37) ; v1(33.15,99.75) 33.15,98.63 v1(33.18,98.6) 33.15,98.58 33.15,96.81 33.66,96.3 v1(33.73,96.3)
  L3 w0.635: v1(34.4,90.68) 34.44,90.72 34.44,95.6 v1(33.73,96.3)
  BOTTOM w0.203: U31.43 37.58,90.48 v1(37.47,90.37) ; U31.15 36.38,98.05 35.73,98.69 33.27,98.69 v1(33.18,98.6) ; U31.11 v1(33.73,96.3)
  BOTTOM w0.381: C449.1 C445.1 33.95,89.85 34.4,90.29 v1(34.4,90.68)
  BOTTOM w0.508: v1(37.47,90.37) 37.42,90.32 37.42,89.5 C448.1
  BOTTOM w0.635: v2(34.01,99.69) 33.97,99.72 33.18,99.72 v1(33.15,99.75) 33.13,99.77 C401.2 33.13,102.12 L20.1
SYNC: length 2.9
  TOP w0.102: U22.11 156.1,34.05 157.01,34.95 TP53.1
SYS_FAN_TACH1_1: length 5.7
  TOP w0.165: R71.2 16.73,206.55 R58.2 16.2,206.57 15.68,207.09 15.68,208.05 FANC3.3
SYS_FAN_TACH1_2: length 4.6
  TOP w0.165: R71.1 17.71,205.51 R72.2 v4(18.77,204.22) 18.77,203.52 19.07,203.21 R76.2
SYS_PEX_RST_MON_GPU#: length 35
  TOP w0.102: R272.2 103.75,105.65 v1(103.59,105.82) ; v3(85.89,92.13) 85.94,92.08 85.95,92.08 GPU1.D10
  BOTTOM w0.102: v3(85.89,92.13) 85.89,92.18 86.26,92.56 87.97,92.56 88.27,92.25 92.78,92.25 94.13,90.91 94.52,90.91 95.08,90.35 98.92,90.35 99.48,90.9 100.65,90.9 104.14,94.4 104.14,100.16 103.33,100.97 v2(103.33,103.61) 103.33,105.56 v1(103.59,105.82)
SYS_PRES: length 4.5
  TOP w0.102: v1(31.99,60.57) 31.99,60.62 32.01,60.65 32.01,61.37 33.22,62.58 BAT2.6
  BOTTOM w0.102: v2(31.53,61.34) 31.5,61.32 31.5,61.05 v1(31.99,60.57) R731.2
SYS_PWRGD: length 11.1
  TOP w0.102: v4(142.37,115.7) 141.89,116.18 C64.1 R225.2 140.76,117.66 R228.2 140.21,118.21 139.4,118.21 138.48,117.3 136.12,117.3 Q15.D
SYS_PWRGD_G: length 11.5
  TOP w0.102: Q16.D 131.42,120.07 Q15.G 132.43,119.89 135.59,116.73 v4(136.35,116.73) 138.7,116.73 R227.2
SYSTEM_FAN_PWM1_1: length 11.8
  TOP w0.165: FANC3.4 14,205.89 15.1,204.8 17.52,204.8 17.98,204.34 17.98,202.24 D1.A 15.97,201.52 R79.2 15.68,201.82 R73.2
T_CRIT#: length 28.3
  TOP w0.102: v1(147.75,77.16) 147.71,77.12 U12.4 146.91,75.55 R335.2 ; R342.1 127.69,73.58 v1(127.69,73.99)
  L3 w0.127: v1(143.95,80.62) 142.25,78.92 138.11,78.92 134.33,75.13 133.72,75.13 133.14,74.55 128.13,74.55 127.69,74.11 v1(127.69,73.99)
  BOTTOM w0.102: v1(147.75,77.16) 147.29,77.16 v2(146.1,78.34) 143.95,80.49 v1(143.95,80.62)
TAP_PRDY#: length 96.7
  TOP w0.102: v3(70.44,159.41) 70.44,159.63 70.66,159.84 71.27,159.84 71.73,159.84 71.97,159.61 72.21,159.61 72.5,159.9 CPU1.C21
  L3 w0.127: v1(24.96,209.62) 21.94,206.6 21.94,203.29 21.08,202.43 21.08,198.18 21.29,197.97 21.29,179.21 23.42,177.07 23.42,174.49 29.83,168.08 49.86,168.08 56.65,161.29 68.32,161.29 69.71,159.89 69.96,159.89 v3(70.44,159.41)
  BOTTOM w0.102: v2(24.44,210.19) 24.44,210.13 v1(24.96,209.62) 24.96,209.16 R543.2 25.33,208.79 R544.1
TAP_PREQ#: length 104.7
  TOP w0.102: CPU1.C20 72.32,159.29 72.01,159.29 71.88,159.19 71.85,159.16 71.4,159.16 71.23,158.98 v3(67.57,158.98)
  L3 w0.127: v1(20,206.63) 20.01,206.63 20.21,206.43 20.21,196.95 20.45,196.71 20.45,178.84 22.66,176.63 22.66,161.56 24.81,159.41 30.31,159.41 32.25,157.47 40.93,157.47 41.72,158.25 46.03,158.25 46.95,159.18 47.34,159.18 48.28,158.24 49.22,158.24 49.91,158.93 50.41,158.93 51.04,159.57 60.18,159.57 60.28,159.66 60.65,159.66 60.75,159.57 66.99,159.57 v3(67.57,158.98)
  BOTTOM w0.102: RN18.4 23.7,206.62 23.32,206.99 R556.2 22.65,206.67 22.45,206.47 21.41,206.47 21.05,206.84 v2(20.79,206.84) 20.21,206.84 v1(20,206.63)
THERM_SYS_SHDN#: length 2.9
  TOP w0.102: Q34.S 127.46,72.21 R342.2 127.22,71.43 127.21,71.42 v4(127.21,71.26)
TP_DET: length 172.6
  TOP w0.102: v4(23.99,13.51) 23.99,13.44 23.52,12.97 23.52,11.13 23.62,11.03 26.12,11.03 26.12,11.08 v3(27.24,12.19) 27.24,11.74 TOUCH1.1 29.66,10.5 29.93,10.77 R491.2 ; v1(118.65,64.7) U14.124
  L4 w0.127: v1(118.65,64.7) 119.32,65.36 122.93,65.36 123.53,64.77 123.53,64.3 126.18,61.65 126.44,61.65 127.68,60.41 127.68,60.14 129.32,58.5 129.92,58.5 130.92,57.5 130.92,50.37 131.85,49.44 131.85,44.86 130.74,43.75 130.74,42.34 129.4,40.99 129.4,39.32 122.97,32.89 120.22,32.89 115.82,28.49 103.55,28.49 102.28,27.22 95.18,27.22 93.4,28.99 85.9,28.99 85.26,28.99 84.46,29.79 72.02,29.79 70.57,31.25 64.9,31.25 61.89,34.26 49.53,34.26 43.64,28.38 43.64,27.75 43.34,27.45 43.34,24.77 41.6,23.03 41.6,22.03 37.02,17.45 31.59,17.45 28.47,14.33 27.97,14.33 26.91,13.27 26.91,12.45 27.08,12.28 27.15,12.28 v3(27.24,12.19)
TP_NGFF_COEX1: length 4.7
  TOP w0.102: NGFF1.48 119.53,216.5 119.85,216.18 121.67,216.18 TP10.1
TP_NGFF_COEX2: length 3.2
  TOP w0.102: TP9.1 120.8,215.79 119.7,215.79 119.49,216 NGFF1.46
TP_NGFF_COEX3: length 4.8
  TOP w0.102: TP12.1 121.85,214.73 121.1,214.73 120.33,215.5 NGFF1.44
TP_NGFF_LED1: length 4.8
  TOP w0.102: NGFF1.6 119.4,206 119.42,206.02 120.96,206.02 TP28.1
TP_NGFF_LED2: length 3.2
  TOP w0.102: TP27.1 120.46,208.5 NGFF1.16
TP_NGFF_MLDIR: length 3.7
  TOP w0.102: TP26.1 107.95,208.75 NGFF1.17
TPA3131_BSNL: length 2.7
  TOP w0.305: U22.19 151.96,31.36 151.84,31.24 151.25,31.24 v4(151.24,31.23) 151.14,31.23 151.13,31.24 C193.1
TPA3131_BSNR: length 2.8
  TOP w0.305: U22.22 151.45,29.86 151.32,29.72 v4(151.24,29.72) 150.4,29.72 C199.1
TPA3131_BSPL: length 5.4
  TOP w0.305: 153.23,34.72 154.1,33.85 U22.15
  TOP w0.635: C183.1 150.81,34.9 v4(151.4,34.9) 153.05,34.9 153.23,34.72
TPA3131_BSPR: length 3.1
  TOP w0.305: U22.26 154.1,27.2 153.63,26.72
  TOP w0.635: C210.1 152.23,26.54 v4(153.45,26.54) 153.63,26.72
TPA3131_FAULT#: length 2.9
  TOP w0.102: R468.2 155.57,25.91 155.85,26.18 v4(155.85,26.5) 155.85,27.11 156.1,27.37 U22.30
TPA3131_GAIN: length 7
  TOP w0.203: U22.3 159.07,29.86 159.73,30.52 R454.2 160.98,30.96 163.23,30.96 R451.1 164.33,31.03 v4(164.4,30.97)
TPA3131_GVDD: length 5.1
  TOP w0.203: R454.1 161.42,29.63 C197.2 ; R454.1 159.72,29.63 v4(159.59,29.5) 159.45,29.36 U22.2 ; R454.1 R461.2
TPA3131_LINN: length 3.1
  TOP w0.203: C194.2 159.87,31.63 v4(159.6,31.36) 159.08,31.36 158.58,30.86 U22.5
TPA3131_LINN_1: length 3.6
  TOP w0.203: C194.1 163.47,32.93 R440.2 163.9,33.24 v4(164.63,33.96)
TPA3131_MUTE: length 6.6
  TOP w0.203: U22.7 158.61,31.86 159.11,32.36 159.11,34.34 v4(159.42,34.65) 159.95,35.18 R438.1 159.49,36.06 R435.2
TPA3131_PLIMIT: length 5.3
  TOP w0.203: C200.2 161.72,27.78 v4(161.55,27.61) 161.44,27.72 R461.1 159.77,28.49 R462.2 159.18,28.49 158.81,28.86 U22.1
TPA3131_RINN: length 3.2
  TOP w0.203: U22.32 157.1,27.52 157.44,27.18 v4(157.44,26.42)
  TOP w0.254: C215.2 157.44,25.11 v4(157.44,26.42)
TPA3131_RINN_1: length 2.8
  TOP w0.254: v4(159.99,25.35) 159.67,25.03 C215.1 158.58,25.34 R466.2
TPA3131_SD: length 25.9
  TOP w0.102: R435.1 158.97,36.94 158.48,36.45 v3(158.48,36.04) ; Q2801.D 140.29,41.33 v1(140.37,41.25)
  BOTTOM w0.102: v1(140.37,41.25) 140.45,41.17 140.57,41.17 142.32,39.42 144.12,39.42 Q70.G 144.98,39.69 146.36,38.3 146.36,37.41 RN23.3 148.37,36.12 149.99,37.74 Q69.3 151.05,38.44 v2(151.62,37.87) 154.85,37.87 156.67,36.04 v3(158.48,36.04)
TPA3131_SD1#: length 26.5
  TOP w0.102: U22.29 155.6,27.18 155.29,26.86 155.29,26.22 154.68,25.62 R468.1 154.68,24.63 v1(154.52,24.46)
  BOTTOM w0.102: v1(154.52,24.46) 154.39,24.46 154.13,24.71 C509.1 153.58,26.21 v2(152.61,26.21) 151.04,27.79 151.04,34.26 149.83,35.47 RN23.4 146.95,34.77 145.42,34.77 144.38,35.81 144.38,37.39 144.77,37.78 Q70.D
TPM_CLKRUN_N: length 9.3
  TOP w0.102: v1(130.46,106.71) 130.46,106.65 131.33,107.52 132.47,107.52 132.64,107.69 U7.13
  BOTTOM w0.102: R654.1 v2(132.75,107.21) 131,107.21 130.49,106.71 v1(130.46,106.71)
TPM_GPIO0: length 2.6
  TOP w0.102: TP45.1 131.15,115.21 132.14,114.22 U7.29
TPM_GPIO1: length 3.2
  TOP w0.102: TP44.1 130.59,114.63 131.18,114.63 131.62,114.19 131.64,114.19 U7.30
TPM_GPIO2: length 3.3
  TOP w0.102: U7.3 128.98,111.47 v1(128.61,111.1) R252.1
  BOTTOM w0.102: v1(128.61,111.1) 129.04,111.1 v2(129.52,110.62)
TPM_GPIO3: length 2.1
  TOP w0.102: U7.6 128.04,109.97 TP49.1
TPM_LCLK: length 3.9
  TOP w0.102: U7.19 135.81,109.97 v4(136.51,109.27) 137.63,108.15 R264.2
TPM_LPCPD_N: length 2.4
  TOP w0.102: U7.28 v4(132.64,114.59) 132.64,114.61 132.35,114.9 R234.2
TPM_PP: length 3.7
  TOP w0.102: TP48.1 127.08,110.41 128.71,110.41 129.26,110.97 U7.4
TPM_RST_N: length 4.2
  TOP w0.102: U7.17 135.34,108.97 135.59,108.71 135.59,108.2 v4(136.46,107.34) 136.66,107.14 138,107.14 R266.2
TPM_SERIRQ: length 3.4
  TOP w0.102: R235.2 133.7,115.54 v4(134.28,114.96) 134.17,114.96 133.14,113.93 U7.27
TRST_PD: length 4.5
  TOP w0.102: XDP1.8 21.44,206.49 20.42,207.51 v4(20,207.51) R56.1
U15_ZQ: length 5.5
  BOTTOM w0.152: VRAM4.L8 58.65,90.24 59.01,89.87 59.73,89.87 59.94,90.08
  BOTTOM w0.254: R679.1 62.37,90.14 60,90.14 59.94,90.08
U19_ZQ: length 5.1
  TOP w0.102: VRAM1.L8 58.7,109 59.09,109.4 59.63,109.4
  TOP w0.254: 59.63,109.4 59.71,109.32 R258.1
U35_ZQ: length 5.3
  TOP w0.102: 50.01,90.34 52.18,90.34 52.61,89.91 53.08,89.91 53.27,90.1 53.46,90.1 VRAM2.L8
  TOP w0.254: R291.1 49.06,89.99 49.41,90.34 50.01,90.34
U36_ZQ: length 8.9
  BOTTOM w0.102: VRAM3.L8 53.21,108.61 51.84,108.61 51.68,108.77
  BOTTOM w0.254: 51.68,108.77 50.73,109.72 50.73,111.06 49.66,112.14 48.64,112.14 R643.1 48.6,112.67 v2(47.99,113.28)
USB1N_C_EXT: length 27.3
  TOP w0.102: SSUSB2.2 172.46,96.34 172.37,96.25 172.37,95.44 172.46,95.35 172.75,95.35 173.87,96.47 174.96,96.47 175.42,96.93 175.42,99.36 173.74,101.05 173.74,108.45 172.14,110.04 168.59,110.04 167.82,110.81 167.21,110.81 U6.6 166.95,110.56 166.69,110.81 166.28,110.81 165.9,110.43 165.36,110.43 165.13,110.19 TR4.1
USB1P_C_EXT: length 27.3
  TOP w0.102: TR4.4 165.17,110.88 165.41,110.64 165.81,110.64 166.19,111.03 167.91,111.03 168.68,110.26 169.07,110.26 169.37,110.56 U6.1 169.92,110.56 170.22,110.26 172.23,110.26 173.95,108.54 173.95,101.14 175.64,99.45 175.64,96.84 175.05,96.25 173.96,96.25 172.62,94.91 SSUSB2.3
USB2N_EXT: length 22.8
  TOP w0.102: USB3.2 101.06,38.03 100.38,37.34 100.1,37.34 99.79,37.03 99.79,35.32 100.53,34.58 101.26,34.58 104.78,31.06 104.78,26.57 105.79,25.57 107.64,25.57 108.38,26.3 108.82,26.3 109.08,26.05 U25.3 109.61,26.05 109.86,26.3 110.08,26.3 110.41,25.97 111.32,25.97 111.55,25.74 TR9.4
USB2P_EXT: length 22.8
  TOP w0.102: USB3.3 101.06,36.95 100.88,37.13 100.19,37.13 100,36.94 100,35.41 100.62,34.8 101.35,34.8 105,31.15 105,26.66 105.87,25.78 106.37,25.78 U25.4 106.9,25.78 107.55,25.78 108.29,26.52 110.17,26.52 110.5,26.19 111.29,26.19 111.52,26.43 TR9.1
USB3N_EXT: length 20.2
  TOP w0.102: USB4.2 101.95,14.14 102.36,14.14 103.83,15.61 103.83,22.73 105.71,24.61 107.48,24.61 108.2,23.89 108.81,23.89 109.06,24.14 U25.1 109.6,24.14 109.85,23.89 110.94,23.89 111.24,24.19 TR10.1
USB3P_EXT: length 20.1
  TOP w0.102: USB4.3 101.95,13.92 102.45,13.92 104.05,15.52 104.05,22.64 105.8,24.4 106.13,24.4 106.38,24.14 U25.6 106.89,24.14 107.14,24.4 107.39,24.4 108.11,23.67 110.95,23.67 111.12,23.51 TR10.4
USB30_RX_CPU_N0: length 116.4
  TOP w0.102: L5.1 164.74,116.75 164.51,116.99 163.86,116.99 ; v1(159.49,115.37) 161.38,115.37 162.99,116.99 163.86,116.99 ; 163.86,116.99 v4(163.86,116.59) ; CPU1.K10 75.59,154.48 v3(75.55,154.48)
  L4 w0.089: 74.62,150.85 74.6,150.85 74.56,150.89 74.34,150.89 74.04,151.19 74.04,151.87 74.53,152.36 74.53,154.11 74.73,154.31 75.37,154.31 v3(75.55,154.48)
  L4 w0.127: v1(159.49,115.37) 159.23,115.63 158.93,115.63 158.6,115.96 158.6,116.71 159.3,117.41 159.3,119.25 157.05,121.5 121.26,121.5 99.56,143.21 80.68,143.21 75.92,147.97 75.92,150.3 75.36,150.85 74.62,150.85
USB30_RX_CPU_N1: length 129.2
  TOP w0.089: v3(74.12,149.38) 74.12,149.63 74.46,149.97 74.46,150.39 CPU1.G2
  TOP w0.102: L7.1 165.32,94.53 164.96,94.89 163.85,94.89 v1(163.59,94.63)
  L4 w0.127: v3(74.12,149.38) 73.92,149.17 73.92,148.84 74.56,148.21 74.56,147.16 80.05,141.67 98.71,141.67 120.42,119.96 152.91,119.96 159.62,113.26 159.62,101.31 160.85,100.08 162.8,100.08 164.05,98.82 164.05,97.16 165.02,96.19 165.02,95.35 164.59,94.92 163.88,94.92 v1(163.59,94.63)
  BOTTOM w0.102: v2(73.97,148.66) 74.12,148.81 v3(74.12,149.38)
USB30_RX_CPU_P0: length 116.4
  TOP w0.102: CPU1.K9 75.95,153.92 75.77,153.79 v3(75.48,153.79) ; v1(159.49,116.24) 159.49,116.06 159.96,115.59 161.29,115.59 161.68,115.98 ; v4(161.42,116.23) 161.68,115.98 ; 161.68,115.98 162.9,117.2 164.51,117.2 164.74,117.43 L5.4
  L4 w0.089: 74.62,151.11 74.6,151.11 74.56,151.08 74.42,151.08 74.23,151.26 74.23,151.79 74.72,152.28 74.72,154.03 74.81,154.11 75.34,154.11 75.48,153.98 v3(75.48,153.79)
  L4 w0.127: 74.62,151.11 75.47,151.11 76.18,150.41 76.18,148.08 80.79,143.47 99.67,143.47 121.37,121.77 157.16,121.77 159.57,119.36 159.57,117.3 158.87,116.6 158.87,116.07 159.04,115.9 159.15,115.9 v1(159.49,116.24)
USB30_RX_CPU_P1: length 129.1
  TOP w0.089: v3(73.44,149.4) 73.44,149.53 73.77,149.86 74.08,149.86 74.27,150.05 74.27,150.41 74.19,150.5 CPU1.F2
  TOP w0.102: v1(163.61,95.4) 163.91,95.11 165.05,95.11 165.15,95.21 L7.4
  L4 w0.127: v1(163.61,95.4) 163.83,95.19 164.48,95.19 164.75,95.46 164.75,96.08 163.79,97.05 163.79,98.71 162.69,99.81 160.74,99.81 159.35,101.2 159.35,113.15 152.8,119.7 120.31,119.7 98.6,141.4 79.93,141.4 74.29,147.05 74.29,148.09 73.65,148.73 73.65,149.19 v3(73.44,149.4)
  BOTTOM w0.102: v3(73.44,149.4) 73.2,149.4 v2(72.81,149.79)
USB30_TX_CPU_N0: length 102.4
  TOP w0.089: v3(74.68,149) 75.14,149.45 75.14,150.52 75.33,150.71 CPU1.J2
  TOP w0.102: v3(158.71,117.82) 159.85,117.82 C63.1
  L4 w0.127: v3(158.71,117.82) 157.02,117.82 154.24,120.6 120.69,120.6 98.99,142.3 80.31,142.3 74.84,147.78 74.84,148.84 v3(74.68,149)
  BOTTOM w0.102: v2(74.91,147.86) 74.91,147.87 74.68,148.09 v3(74.68,149)
USB30_TX_CPU_N0_EMI: length 5.4
  TOP w0.102: L4.1 164.91,119.01 164.65,119.27 163.71,119.27 163.15,118.72 ; 163.15,118.72 162.52,118.09 161.14,118.09 C63.2 ; 163.15,118.72 v4(163.43,118.44)
USB30_TX_CPU_N1: length 126.8
  TOP w0.089: v3(73.87,147.85) 73.87,148.01 74.06,148.2 75.34,148.2 76.02,148.88 76.02,149.11 76.02,150.55 CPU1.K2
  TOP w0.102: v1(161.95,96.7) 162.32,97.07 162.62,97.07 C94.2
  L4 w0.127: v1(161.95,96.7) 162.52,96.7 162.7,96.88 162.7,97.27 163.06,97.63 163.06,98.53 162.44,99.16 160.44,99.16 158.71,100.88 158.71,107.85 157.97,108.59 157.97,113.25 152.64,118.58 140.22,118.58 139.74,119.06 120.02,119.06 98.31,140.77 79.66,140.77 73.4,147.02 73.4,147.38 73.53,147.51 73.69,147.51 73.87,147.69 v3(73.87,147.85)
  BOTTOM w0.102: v2(73.87,147.13) v3(73.87,147.85)
USB30_TX_CPU_N1_EMI: length 1.9
  TOP w0.102: L6.1 165.33,96.81 165.08,97.07 164.35,97.07 C94.1
USB30_TX_CPU_P0: length 102
  TOP w0.089: CPU1.J1 75.47,149.94 75.33,149.79 75.33,149.6 75.52,149.4 75.52,149.23 v3(75.32,149.02)
  TOP w0.102: v3(158.66,118.69) 158.63,118.67 158.63,118.39 158.76,118.26 158.98,118.26 159.15,118.08 159.35,118.08 C60.1
  L4 w0.127: v3(75.32,149.02) 75.46,148.88 75.46,148.62 75.38,148.54 75.19,148.54 75.1,148.45 75.1,147.89 80.42,142.57 99.1,142.57 120.8,120.87 154.35,120.87 157.13,118.08 158.35,118.08 158.53,118.26 158.66,118.39 v3(158.66,118.69)
  BOTTOM w0.102: v2(75.99,148.44) 75.9,148.44 v3(75.32,149.02)
USB30_TX_CPU_P0_EMI: length 5.4
  TOP w0.102: v4(161.83,118.69) 161.83,118.31 ; 161.83,118.31 162.43,118.31 163.62,119.49 164.65,119.49 164.86,119.7 L4.4 ; 161.83,118.31 161.14,118.31 C60.2
USB30_TX_CPU_P1: length 126.8
  TOP w0.089: CPU1.K3 76.05,150.99 75.75,150.69 75.75,150.39 75.82,150.31 75.82,149.03 75.82,148.95 75.26,148.39 73.64,148.39 v3(73.13,147.88)
  TOP w0.102: C92.2 162.71,97.28 162.3,97.28 v1(161.97,97.61)
  L4 w0.127: v3(73.13,147.88) 73.13,146.91 79.55,140.5 98.2,140.5 119.91,118.8 139.63,118.8 140.11,118.32 152.53,118.32 157.71,113.14 157.71,108.48 158.45,107.74 158.45,100.77 160.33,98.89 162.33,98.89 162.8,98.42 162.8,97.74 162.67,97.61 v1(161.97,97.61)
  BOTTOM w0.102: v3(73.13,147.88) v2(72.42,147.88)
USB30_TX_CPU_P1_EMI: length 1.8
  TOP w0.102: C92.1 164.27,97.28 165.08,97.28 165.3,97.5 L6.4
USB_DN5: length 3.1
  TOP w0.102: CPU1.AB7 v3(81.13,153.05)
  BOTTOM w0.089: v3(81.13,153.05) 81.13,152.97 81.69,152.4 81.69,151.16 TP72.1
USB_DP5: length 3.8
  TOP w0.102: CPU1.AB6 v3(81.13,152.34)
  BOTTOM w0.089: v3(81.13,152.34) 81.51,151.96 81.51,151.38 81.35,151.22 81.35,150.53 81.06,150.24
  BOTTOM w0.102: TP75.1 80.52,149.7 81.06,150.24
USB_EN_1: length 4.1
  TOP w0.102: R263.1 C81.1 158.55,107.23 v4(158.55,106.81) 159.1,106.26 U8.4
USB_EN_2: length 5
  TOP w0.102: R441.1 C190.1 93.09,32.7 v1(92.68,32.3) 93.57,31.42 U23.4
  BOTTOM w0.102: v1(92.68,32.3) 92.68,31.7 92.7,31.68 v2(92.7,31.49)
USB_OTGID: length 33.4
  TOP w0.102: CPU1.AC15 82.42,156.98 v3(82.08,157.32) ; R1703.1 60.8,147.28 v1(60.49,147.6) 60.43,147.65 60.43,150.04 R177.2
  L3 w0.127: v1(60.49,147.6) 61.24,148.36 63.26,148.36 69.58,154.68 74.57,154.68 78.33,158.44 80.37,158.44 80.65,158.16 80.65,157.74 81.06,157.32 v3(82.08,157.32)
  BOTTOM w0.102: v1(60.49,147.6) 60.49,147.53 v2(61.12,146.89)
USB_PCH_DN1_NN: length 7.7
  TOP w0.102: v4(162.49,195.54) 162.74,195.28 ; 162.74,195.28 162.55,195.09 162.55,192.41 162.32,192.17 TR2.4 ; 162.74,195.28 163.77,196.31 163.77,196.91 163.25,197.43 WEBCM1.2
USB_PCH_DN4_NN: length 7.3
  TOP w0.102: TR11.4 31.9,10.35 31.74,10.2 31.74,9.92 32.18,9.49 32.18,9.12 ; TOUCH1.4 28.97,7.5 29.23,7.76 30.22,7.76 C232.1 30.81,7.79 31.4,7.79 32.18,8.56 32.18,9.12 ; v4(32.54,9.12) 32.18,9.12
USB_PCH_DN5_NN: length 4
  TOP w0.102: NGFF1.5 109.48,205.75 109.35,205.62 108.67,205.62 ; TR1.4 107.69,205.85 107.92,205.62 108.67,205.62 ; v4(108.67,206.02) 108.67,205.62
USB_PCH_DP1_PP: length 7.7
  TOP w0.102: 162.77,193.75 162.77,192.41 163,192.17 TR2.1 ; 162.77,193.75 v4(163.14,193.75) ; 162.77,193.75 162.77,195 163.98,196.22 163.98,196.91 164.5,197.43 WEBCM1.1
USB_PCH_DP4_PP: length 6.9
  TOP w0.102: TOUCH1.3 28.92,8.5 29.45,7.98 29.99,7.98 C229.1 30.99,8 31.31,8 31.96,8.65 31.96,9.4 31.53,9.83 31.53,10.19 31.21,10.5 TR11.1
USB_PCH_DP5_PP: length 3.6
  TOP w0.102: NGFF1.3 109.54,205.25 109.39,205.4 107.92,205.4 107.69,205.17 TR1.1
USB_RCOMP: length 3.3
  TOP w0.305: CPU1.Y15 80.68,156.98 v3(81.06,156.6)
  BOTTOM w0.381: v3(81.06,156.6) 81.19,156.6 81.88,155.91 v2(81.97,155.91) 82.08,155.91 83.05,154.93 R600.2
USB_SSIC_RCOMP: length 1.3
  TOP w0.305: CPU1.AB15 81.96,156.63 v3(81.99,156.63)
  BOTTOM w0.381: v3(81.99,156.63) 82.5,156.63 R597.2
USB_VBUSSNS: length 65.8
  TOP w0.102: CPU1.AC16 82.48,157.42 82.87,157.03 83.03,157.03 83.47,156.59 84.59,156.59 85.32,155.86 85.52,155.86 85.65,155.73 85.65,155.67 85.74,155.58 85.74,153.38 85.47,153.11 84.97,153.11 v1(84.92,153.06) ; R1702.1 R1701.2 55.09,150.25 v1(55.18,150.34)
  L3 w0.127: v1(76.59,135.05) 76.6,135.04 76.78,135.04 83.32,141.58 83.32,143 85.76,145.44 85.76,152.1 84.92,152.93 v1(84.92,153.06)
  L4 w0.127: v1(55.18,150.34) 55.18,149.83 56.7,148.31 56.7,147.96 61.65,143 v1(61.65,139.19)
  BOTTOM w0.102: v1(76.59,135.05) 75.73,135.05 74.36,133.68 63.79,133.68 v2(63.37,134.1) 61.15,136.32 61.15,138.69 v1(61.65,139.19)
USBOC01: length 178.4
  TOP w0.102: U8.3 161.96,106.26 160.96,107.26 v1(160.96,107.6) ; RN7.4 v3(61.64,179.78) 61.64,179.22 62.4,178.46 67.21,178.46 67.54,178.13 68.08,178.13 68.16,178.05 70.32,175.89 71.9,175.89 71.97,175.95 72.21,175.95 72.49,175.72 72.55,175.66 CPU1.C55
  L4 w0.127: v3(61.64,179.78) 61.95,179.47 61.95,173.11 57.98,169.14 57.98,160.66 56.14,158.83 56.14,157.02 64.55,148.61 64.55,144.91 65.93,143.54 67.64,143.54 68.86,142.32 72.21,142.32 75.04,139.49 75.04,136.68 75.2,136.51 75.2,129.92 77.38,127.74 77.38,125.63 78.84,124.16 83.36,124.16 84.25,123.28 85.92,123.28 85.96,123.31 93.61,123.31 94.05,122.87 98.16,122.87 98.61,122.42 98.62,122.42 98.73,122.31 107.34,122.31 109.53,120.12 v1(109.53,119.8)
  BOTTOM w0.102: v1(160.96,107.6) 159.29,109.27 159.29,110.49 151.31,118.48 148.34,118.48 v2(146.97,119.84) 146.24,120.57 139.4,120.57 138.25,121.72 111.4,121.72 109.53,119.86 v1(109.53,119.8)
USBOC02: length 287.9
  TOP w0.102: RN7.3 60.97,179.13 v3(61.5,178.6) 61.86,178.23 67.11,178.23 67.44,177.9 67.98,177.9 68.06,177.83 70.23,175.66 CPU1.B55 ; v1(40.49,138.88) 40.42,138.81 25.84,138.81 22.78,135.75 v4(18.44,135.75) 16.27,135.75 16.23,135.71 v1(16.18,135.71) ; U23.3 94.71,29.59 94.71,31.33 95.66,32.29 v1(95.66,33.33)
  L3 w0.127: v1(69.22,41.94) 68.95,42.2 68.89,42.2 66.98,44.11 60.44,44.11 57.97,46.58 33.52,46.58 33.17,46.24 31.86,46.24 31.23,46.87 31.23,49.72 26.71,54.25 26.71,70.06 30.64,73.99 30.64,78.69 30.76,78.8 30.76,99.36 30.03,100.09 30.03,132.26 28,134.29 18.09,134.29 16.67,135.71 v1(16.18,135.71) ; v1(40.49,138.88) 40.7,139.09 40.7,141.86 46.89,148.04 57.52,148.04 58.87,146.7 60.27,146.7 61.07,147.5 v1(63.94,147.5)
  L4 w0.127: v1(69.22,41.94) 69.35,41.94 69.4,41.88 69.91,41.88 71.18,40.61 71.18,36.35 72.79,34.73 81.42,34.73 82.3,33.86 95.14,33.86 95.66,33.33 v1(95.66,33.33) ; v3(61.5,178.6) 61.5,173.05 57.71,169.26 57.71,161.39 57.71,160.95 55.89,159.13 55.89,156.92 63.94,148.87 v1(63.94,147.5)
USBP0N_EXT: length 18.1
  TOP w0.102: TR3.1 165.24,112.5 165.47,112.73 166.42,112.73 166.69,112.46 U6.4 167.16,112.46 167.42,112.73 167.79,112.73 168.54,111.98 171.25,111.98 171.49,111.74 174.56,111.74 175.2,112.38 175.2,115.28 174.52,115.96 173.96,115.96 172.87,117.06 172.62,117.3 SSUSB1.2
USBP0P_EXT: length 18.5
  TOP w0.102: 166.02,112.95 167.88,112.95 168.63,112.2 169.13,112.2 169.39,112.46 U6.3 169.89,112.46 170.16,112.2 171.34,112.2 171.58,111.96 174.47,111.96 174.99,112.47 174.99,115.19 174.43,115.75 173.87,115.75 172.79,116.83 172.46,116.83 172.3,116.66 172.3,116.16 SSUSB1.3 ; 166.02,112.95 v4(166.02,113.33) ; 166.02,112.95 165.42,112.95 165.19,113.18 TR3.4
USBVCC14: length 26.7
  TOP w0.508: v1(167.93,111.51) 167.92,111.51 U6.5
  TOP w0.635: 166.55,104.31 TC2.1 ; TC2.1 167.61,105.37 ; TC2.1 167.61,103.26 ; TC2.1 168.66,104.31 ; 171.73,98.84 SSUSB2.1 172.62,99.73 ; SSUSB1.1 171.56,121.4 C59.2 169.53,122.22 168.82,122.94 v4(167.8,122.94)
  L3 w0.635: v1(167.93,111.51) 168.75,110.68 168.75,105.46 TC2.1
  L4 w0.635: 171.73,120.34 SSUSB1.1 ; SSUSB1.1 172.62,121.23 ; SSUSB1.1 172.62,119.45 ; 172.62,97.95 SSUSB2.1 ; SSUSB2.1 171.73,98.84 ; SSUSB2.1 172.62,99.73
  vias: v5(172.6,100.55)
USBVCC56: length 18.4
  TOP w0.508: U25.5 103.36,25.1 101.51,23.24
  TOP w0.635: TC3.1 92.06,22.62 ; TC3.1 93.11,21.56 ; TC3.1 92.06,20.51 ; TC3.1 91,21.56 ; USB4.1 102.09,17.53 ; USB4.1 101.06,16.5 ; USB4.1 101.06,18.56 ; USB4.1 100.03,17.53 ; USB3.1 102.09,40.53 ; USB3.1 101.06,39.5 ; USB3.1 100.03,40.53 ; USB3.1 101.06,41.56
USBVCCTP: length 2.2
  TOP w0.61: v5(27.75,4.6) 28.47,5.32 TOUCH1.5
  vias: v2(26.41,4.87)
V_1P5_HDMI: length 20.8
  TOP w0.203: U20.20 130.94,38.53 130.82,38.65 130.82,39.17 131.34,38.65 U20.19 ; v1(129.67,32.54) 130.17,33.03 U20.31 ; U20.40 135.12,33.03 v1(135.75,32.41) ; U20.12 134.14,38.6 134.21,38.67 134.21,38.67 134.34,38.81 134.35,38.81 135.59,40.05 v1(135.59,40.13)
  TOP w0.381: C195.1 136.81,31.44 135.84,32.41 v1(135.75,32.41) ; C170.1 135.91,40.37 135.67,40.13 v1(135.59,40.13)
  TOP w0.508: C205.1 122.23,27.8 v5(122.23,28.37) ; 130.82,39.17 130.54,39.17 130.06,39.65 v1(130,39.65) 129.95,39.7 129.95,40.88 C169.2
  BOTTOM w0.254: C503.1 127.41,30.56 129.4,32.54 v1(129.67,32.54)
  BOTTOM w0.508: C490.1 135.59,40.9 v1(135.59,40.13) ; v1(130,39.65) 129.69,39.96 C491.1
  vias: v2(122.08,27.46)
V_1P05_LAN: length 10
  TOP w0.203: U26.3 39.62,14.39 v1(40.17,13.84) ; U26.8 39.94,16.39 v1(40.09,16.54) ; U26.24 34.09,13.59 v5(33.27,12.76) ; v1(33.13,14.55) 33.3,14.39 U26.22 ; v1(37.4,11.35) 37.21,11.54 U26.30
  TOP w0.635: C224.2 33.07,12.56 v5(33.27,12.76)
  BOTTOM w0.635: C536.1 33.63,12.4 v5(33.27,12.76)
  vias: v2(40.09,12.58)
V_3_CARD_BD: length 9.5
  TOP w0.762: v5(162.14,146.11) 162.06,146.19 C39.2 161.11,146.2 C38.2 160.22,144.9 C49.2 160.37,144.77 C48.2 161.73,144.72 MEMCD1.4
  vias: v2(162.39,148.79)
V_3P0_BAT_VREG: length 359.5
  TOP w0.381: v1(151.85,178.97) 151.86,178.96 154.24,178.96 154.61,179.33 R126.1
  TOP w0.508: v1(149.56,54.43) v4(149.56,56.18) ; v1(171.38,144.3) 171.38,147.47 168.35,150.51 168.35,156.04 161.77,162.62 161.77,166.35 157.83,170.3 v1(157.83,172) 157.61,172.21 R156.1 ; R89.2 73.29,196.68 73.86,196.11 73.87,196.11 73.92,196.06 73.95,196.06 74.38,195.63 v5(74.38,194.94) 77.12,197.69 81.85,197.69 87.59,203.43 93.35,203.43 v1(93.53,203.61)
  TOP w0.635: v1(137.96,18.96) 137.98,18.98 137.98,19.95 137.31,20.62 D7.3
  L3 w0.381: v1(132.42,51.05) 134.68,51.05 137.07,48.67 137.07,47.97 137.44,47.6 138.89,47.6 140.96,45.53 140.96,26.97 137.09,23.1 137.09,19.83 v1(137.96,18.96)
  L3 w0.635: v1(171.38,144.3) 171.38,144.07 171.41,144.04 171.41,135.61 169.69,133.89 169.69,114.14 171.56,112.27 171.56,101.9 171.24,101.59 171.24,90.41 171.72,89.93 171.72,85.58 164.9,78.77 164.9,73.3 149.56,57.96 v1(149.56,54.43)
  L4 w0.381: v1(132.42,51.05) 132.28,51.19 132.28,57.04 130.16,59.16 129.56,59.16 128.51,60.21 128.51,61.31 v1(125.15,64.67)
  L4 w0.508: v1(149.56,54.43) 150.06,53.94 150.06,49.8 149.03,48.77 149.03,42.73 150.02,41.74 150.02,34.25 149.5,33.73 149.5,32 144.53,27.03 144.53,24.84 138.65,18.96 v1(137.96,18.96) ; v1(145.5,174.55) 146.34,175.39 148.27,175.39 v1(151.85,178.97) 152.59,178.97 157.83,173.73 v1(157.83,172)
  BOTTOM w0.381: R724.2 124.5,64.67 v1(125.15,64.67)
  BOTTOM w0.508: v1(93.53,203.61) 93.53,203.22 101.62,195.14 129.28,195.14 130.76,193.66 136.97,193.66 137.01,193.65 142.43,188.24 142.43,177.65 145.5,174.58 v1(145.5,174.55) ; v5(74.38,194.94) 74.73,194.59 R571.2
  BOTTOM w0.635: v1(149.56,54.43) 150.02,54.89 R744.2
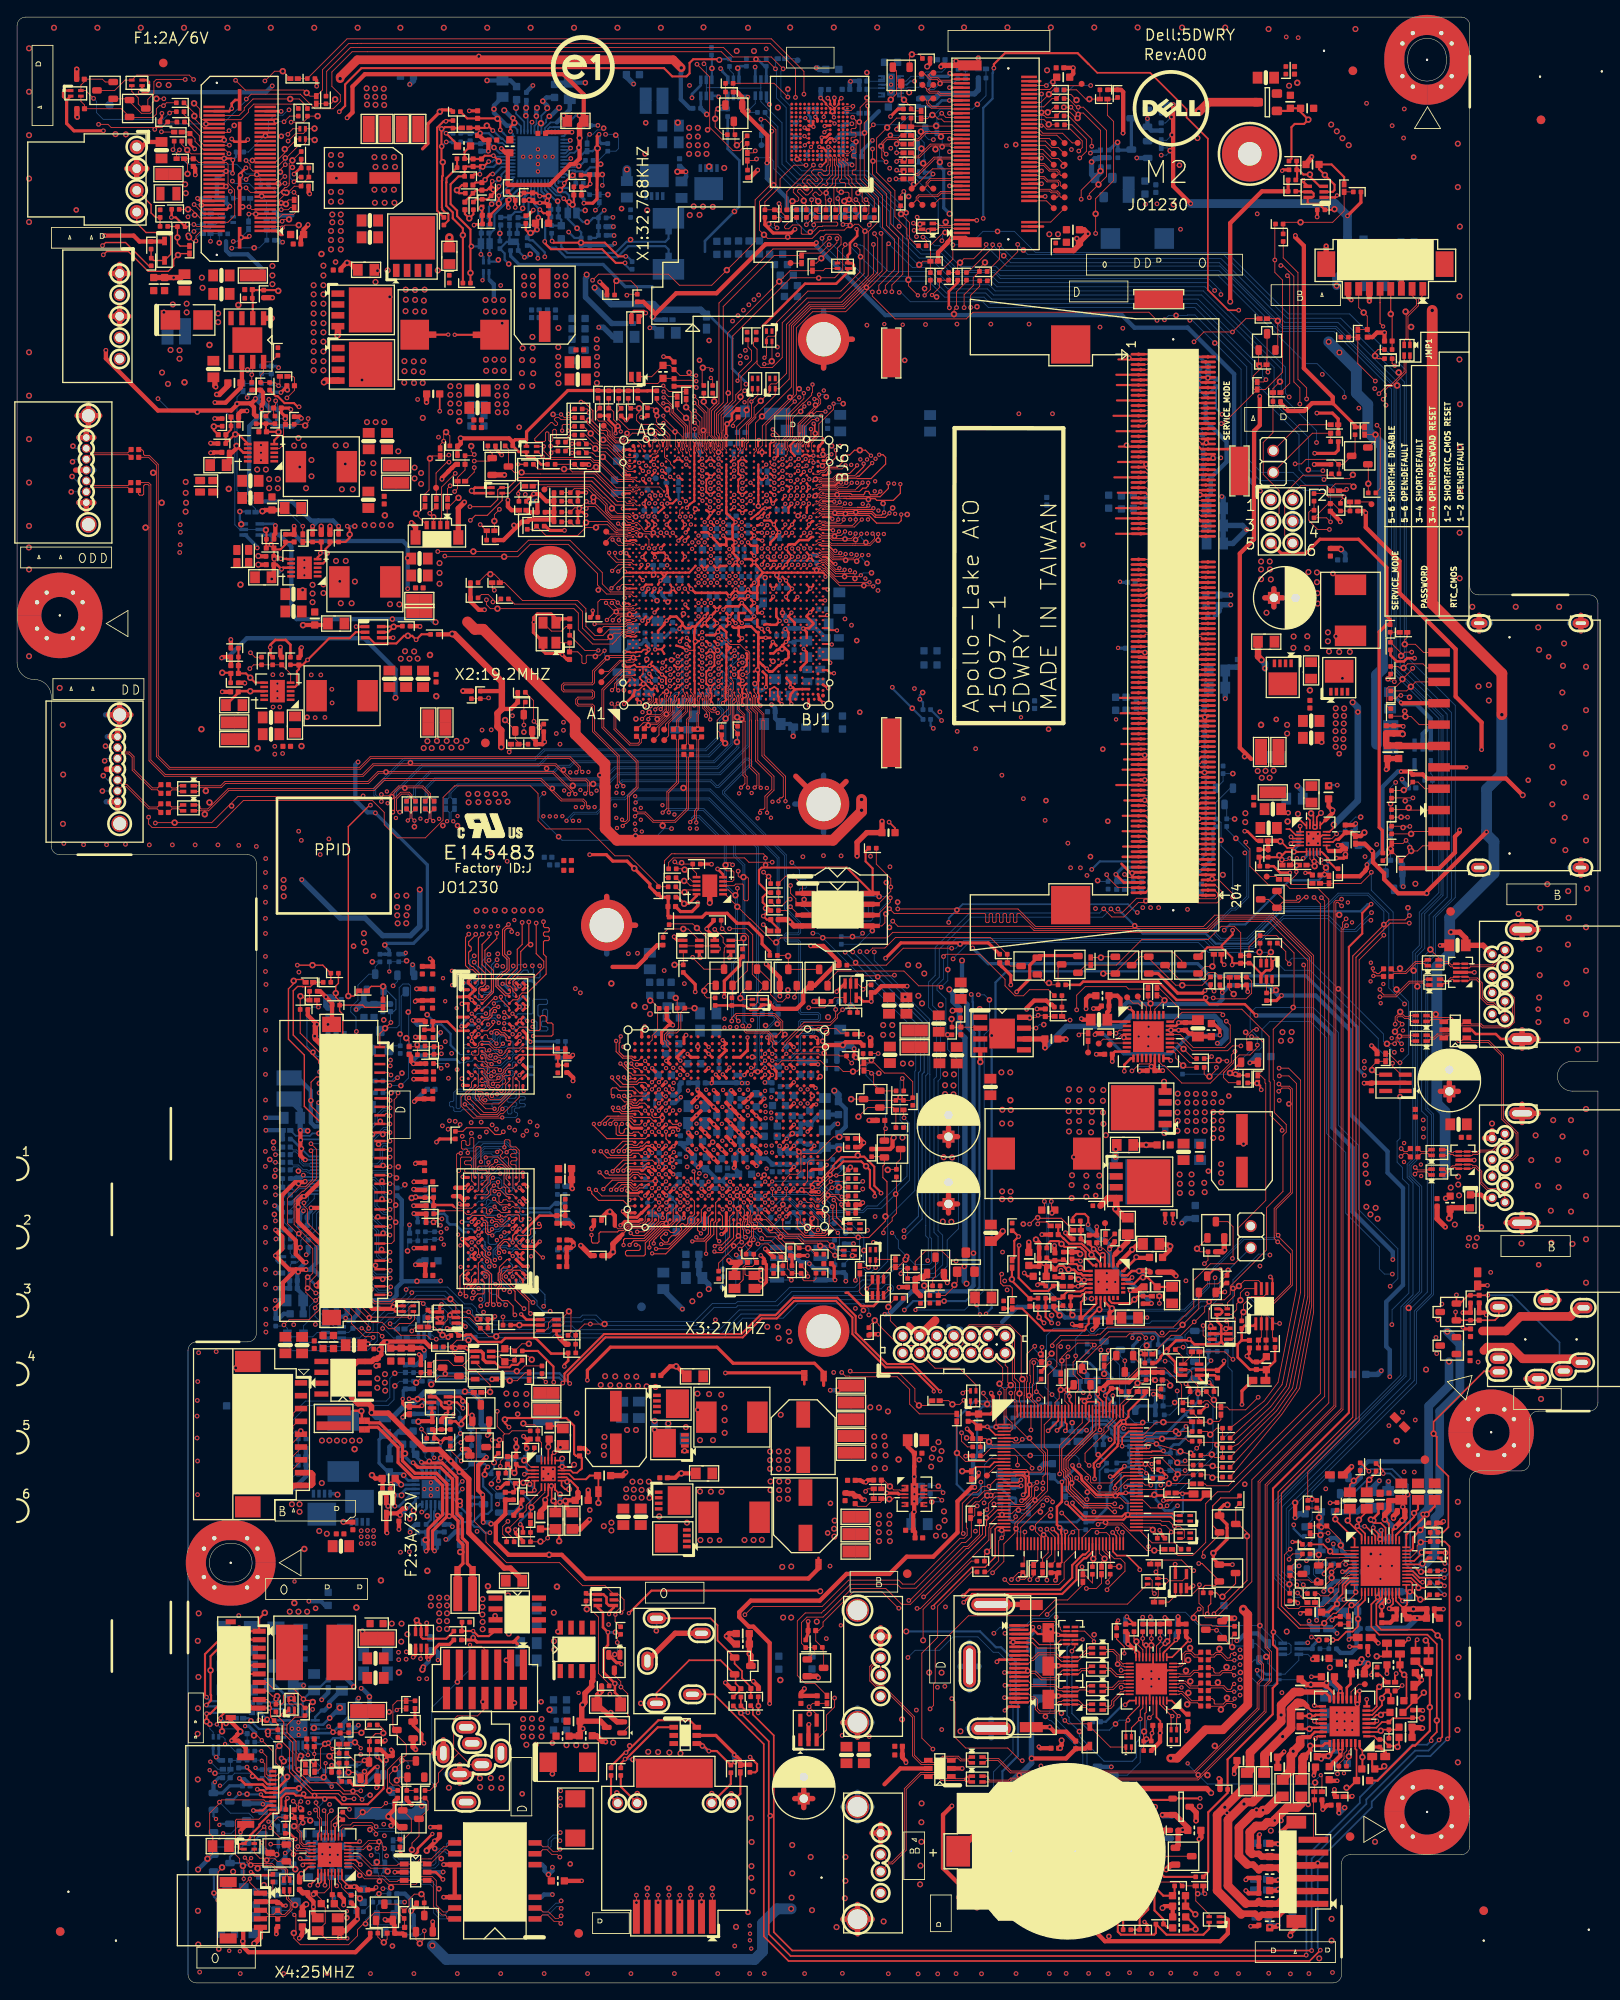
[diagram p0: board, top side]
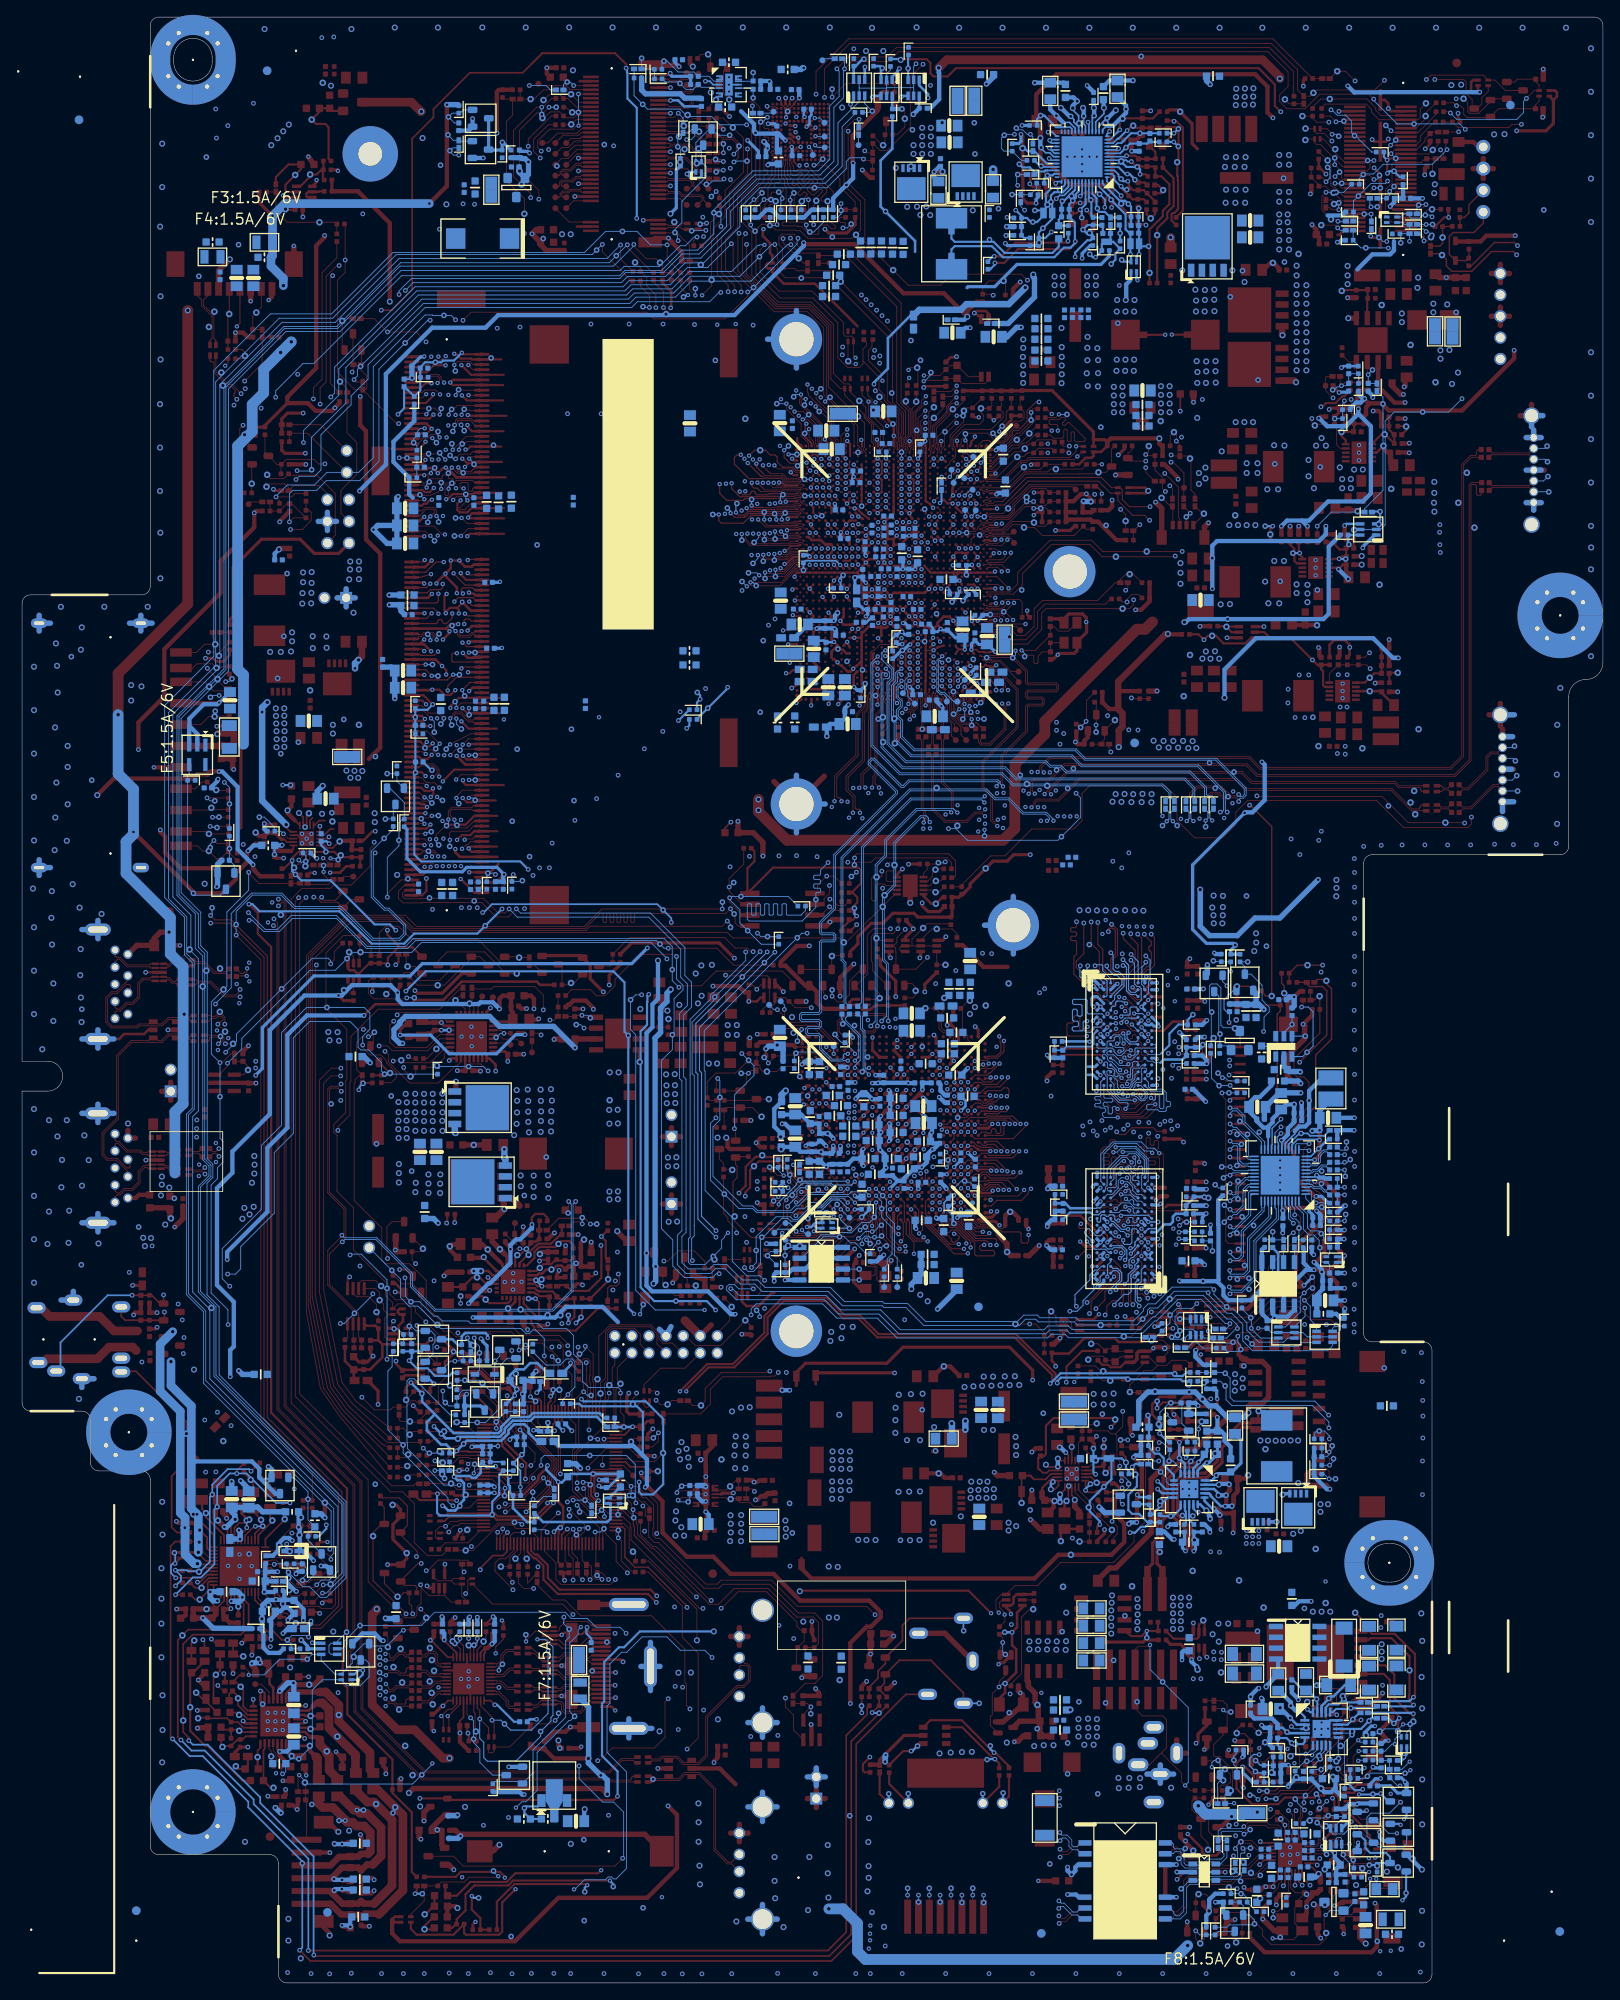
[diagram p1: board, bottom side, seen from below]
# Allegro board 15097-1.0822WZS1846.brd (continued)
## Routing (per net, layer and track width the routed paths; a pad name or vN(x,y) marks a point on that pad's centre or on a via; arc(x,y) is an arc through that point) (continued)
V_3P3_A: length 676.5
  TOP w0.254: v3(71.59,43.26) 74.24,45.9 93.91,45.9 v5(93.99,45.82) ; v5(82.18,224.99) 82.1,225.07 79.13,225.07 78.7,224.64 78.7,223.42 78.34,223.06 76.66,223.06 75.7,224.03 40.29,224.03 38.39,222.12 38.39,219.61 v1(37.7,218.92) ; v1(58.88,53.64) 59.19,53.34 PR169.1 ; R715.1 138.49,56.49 134.7,56.49 134.65,56.44 134.15,56.44 v1(134.15,56.44) ; v5(55.82,60.88) 55.82,61.46 PR156.1 ; v1(138.44,21.59) 135.25,21.59 D7.1 135.07,21.41 115.74,21.41 v1(115.31,21.84) ; v1(140.08,116.04) 139.59,116.52 R227.1 ; v1(62.8,70.28) 62.77,70.31 62.77,72.11 60.94,73.94 PR132.2
  L3 w0.254: v3(27.9,25.16) 34.04,25.16 35.54,26.66 35.54,31.24 40.65,36.35 67.28,36.35 70,39.07 70.41,39.07 70.92,39.58 70.92,42.59 v3(71.59,43.26) ; v1(112.78,58.6) 113.44,58.6 114.23,59.38 117.69,59.38 118.35,58.73 118.35,58.03 119.09,57.29 121.26,57.29 121.37,57.4 123.52,57.4 123.72,57.61 125.69,57.61 126.37,56.92 128.73,56.92 129.17,56.49 129.52,56.49 130.01,56 133.12,56 133.68,56.56 134,56.56 134,56.55 134.03,56.55 134.14,56.44 v1(134.15,56.44) ; v1(138.44,21.59) 138.44,21.62 138.59,21.77 138.59,22.76 145.12,29.29 v1(145.12,36.58) 145.12,43.1 148.12,46.11 148.12,52.32 v1(149.4,53.6) ; v1(62.8,70.28) 62.77,70.26 62.77,68.93 59.63,65.79 57.06,65.79 56.47,65.2 56.47,61.54 v5(55.82,60.88) 55.82,60.12 55.25,59.56 54.5,59.56 53.32,60.73 53.32,63.07 52.69,63.7 52.64,63.7 52.08,64.26 51.9,64.26 v1(51.87,64.29) 51.85,64.26 46.08,64.26 39.05,71.29 39.05,77.32 39.78,78.05 39.78,79.03 39.71,79.11 39.71,81.08 39.72,81.09 39.72,106.24 38.34,107.62 38.34,117.27 36.79,118.82 36.79,129.92 34.93,131.78 34.93,132.97 34.95,132.99 34.95,134.78 34.93,134.79 34.93,134.8 31.58,138.15 23.43,138.15 18.35,143.23 18.35,168.58 18.85,169.09 19.64,169.09 20.05,169.49 20.05,170.36 19.79,170.61 v1(19.08,170.61)
  L4 w0.254: v3(71.59,43.26) 71.59,42.96 71.07,42.44 69.48,42.44 69.45,42.47 65.54,42.47 v1(55.33,52.68) ; v1(19.08,170.61) 18.22,171.48 18.22,178.18 22.33,182.3 22.33,187.35 22.74,187.76 22.74,187.78 24.32,189.36 24.32,199.16 27.57,202.41 27.57,203.99 27.72,204.14 27.72,208 27.57,208.15 27.57,213.69 30.92,217.04 32.8,217.04 34.68,218.92 v1(37.7,218.92) ; v1(112.78,58.6) 112.78,58.14 113.72,57.2 114.31,57.2 115.53,55.98 115.53,52.53 118.19,49.86 118.19,47.9 117.84,47.55 117.84,46.58 117.38,46.13 112.07,46.13 111.34,45.39 111.34,44.25 110.98,43.89 109.91,43.89 109.02,44.78 108.34,44.78 107.93,44.37 107.93,43.54 107.53,43.13 106.06,43.13 v5(104.05,41.12) 99.35,45.82 v5(93.99,45.82) ; v3(113.39,78.29) 113.39,78.16 114.46,77.09 115.98,77.09 117.53,75.54 117.53,70.03 117.94,69.62 117.94,68.37 118.27,68.04 119.28,68.04 v1(119.54,68.3)
  BOTTOM w0.254: v3(27.9,25.16) 28.09,24.96 R784.1 ; v1(58.88,53.64) 58.88,54.03 60.05,55.19 60.05,56.39 v2(58.4,58.04) 57.51,58.93 PG18.1 56.3,61.37 v5(55.82,60.88) 55.82,60.2 55.47,59.86 PR228.1 54.85,59.56 54.54,59.26 54.54,58.09 55.53,57.1 55.53,55.32 55.09,54.88 54.27,54.88 53.31,53.91 PR231.1 ; v5(82.18,224.99) 82.28,225.09 83.35,225.09 R515.1 ; v1(149.4,53.6) 149.4,53.12 150.27,52.25 R746.1 ; v1(119.54,68.3) 119.28,68.04 112.02,68.04 109.96,65.99 109.96,58.34 111.16,57.15 112.48,57.15 112.78,57.45 v1(112.78,58.6) ; v3(113.39,78.29) 113.39,78.31 114.05,78.97 v2(114.05,110.85) 114.5,111.29 114.5,117.06 115.8,118.36 137.76,118.36 v1(140.08,116.04) ; PR225.1 50.85,63.26 v1(51.87,64.29) 51.87,64.62 51.85,64.64 PR220.1 ; v1(55.33,52.68) 54.74,52.68 54.06,53.37 53.54,53.37 PR231.1 ; PR231.1 PR232.2 ; v1(115.31,21.84) 115.31,24.75 117.13,26.57 117.13,32.69 116.87,32.94 116.87,37.54 115.15,39.27 114.55,39.27 112.69,41.12 v5(104.05,41.12) ; RN23.1 145.74,35.47 145.12,36.09 v1(145.12,36.58) 145.63,36.58 146.08,36.12 RN23.2
V_3P3_LAN: length 102.5
  TOP w0.203: v1(38.59,11.25) 38.59,11.53 38.01,12.11 U26.32 ; v1(33.43,13.79) 33.63,13.99 U26.23 ; U26.11 v1(37.21,18.47)
  TOP w0.305: R481.2 37.81,19.09 37.22,18.5 37.22,18.49 37.21,18.48 v1(37.21,18.47) ; U28.5 49,12.95 v1(49.84,12.12)
  TOP w0.381: R471.1 84.64,26.09 84.26,26.47 84.15,26.47 83.95,26.67 v3(83.93,26.67) 83.93,26.8 81.77,28.96 U24.5
  TOP w0.508: R471.1 84.65,25.53 UR4.1 ; v1(38.59,11.25) 38.59,11.25 v1(39.45,11.25) 39.68,11.25 40.03,10.9 40.22,10.9 C225.2
  TOP w0.635: v5(33.84,9.19) 33.74,9.19 33.38,8.84 C230.1
  L3 w0.635: v3(83.93,26.67) 82.75,27.85 71.04,27.85 70.01,26.82 68.64,26.82 63.72,31.74 46.75,31.74 44.54,29.52 44.54,25.99 42.8,24.25 42.47,24.25 41.35,23.13 41.35,21.42 38.37,18.44 37.24,18.44 v1(37.21,18.47) 37.19,18.45 37.19,18.41 34.48,15.69 34.48,12.8 33.55,11.87 33.55,9.54 33.84,9.25 v5(33.84,9.19) ; v1(49.84,12.12) 47.19,12.12 v1(46.34,12.97) 43.57,10.2 41.01,10.2 39.96,11.25 v1(39.45,11.25)
  BOTTOM w0.305: U37.5 46.31,12.95 46.34,12.98 v1(46.34,12.97)
  BOTTOM w0.635: v2(84.01,25.88) 84.01,26.41 83.95,26.47 83.95,26.65 v3(83.93,26.67)
  vias: v1(38.9,20.32) v2(34.68,10.36) v2(37.69,19.19)
V_3P3_PCIVAUX: length 19.9
  TOP w0.305: NGFF1.72 119.74,222.5 ; NGFF1.4 120.06,205.5
  TOP w0.381: R20.2 103.09,219.25 v1(102.21,218.37)
  L3 w0.635: v1(115.77,214.94) 115.73,214.97 108.82,214.97 108.78,214.94 106.93,214.94 103.5,218.37 v1(102.21,218.37)
  vias: v2(116.86,215.08) v2(124.01,204.09) v5(120.53,223.78) v5(120.79,204.59) v5(121.81,204.59)
V_5_CODEC: length 13.7
  TOP w0.203: 161.06,53.07 160.95,52.96 U16.39
  TOP w0.381: 161.06,53.07 v1(161.32,53.34)
  TOP w0.635: C153.2 162.4,54.43 162.09,54.11 v4(162.09,54.1) v1(161.32,53.34)
  BOTTOM w0.635: L24.1 156.85,55.12 157.41,55.68 C480.2 158.5,55.63 C479.1 160.46,55.09 160.1,54.74 160.1,54.3 161.06,53.34 v1(161.32,53.34)
V_5HDD: length 8.5
  TOP w0.635: SATAP1.1 12,201.07 ; SATAP1.1 10.93,200 ; SATAP1.1 12,198.93 ; SATAP1.1 13.07,200 ; SATAP1.3 12,196.07 ; SATAP1.3 13.07,195 ; SATAP1.3 12,193.93 ; SATAP1.3 10.93,195
  vias: v2(17.18,195.45) v5(18.22,196.38) v5(19.85,196.47) v5(19.85,195.45)
V_5P0_A: length 1
  TOP w0.254: PG6.2 v4(68.03,56.16)
V_5P0_HDMI_CONN:
  vias: v1(115.6,40.89) v2(116.55,39.88)
V_5P0_HDMI_CONN_L:
  vias: v2(118.28,36.5)
V_19_INV: length 2.5
  BOTTOM w0.508: R771.1 v2(41.23,33.48) 41.23,33.6 40.37,34.47 v1(40.27,34.47)
  vias: v4(39.71,43.92)
VD1_EN#: length 3.2
  TOP w0.102: R390.2 133.44,52.47 v4(132.9,53.01) 132.58,53.33 U14.66
VD_IN1: length 266.9
  TOP w0.203: R100.1 v1(49.46,183.9) ; U14.108 125.05,67.74 125.31,68 126.5,68 126.65,67.85 U14.104 126.65,64.87 126.73,64.79 v1(126.73,64.69)
  L3 w0.203: v1(53.83,52.83) 49.72,56.94 49.72,59.25 46.51,62.46 44.18,62.46 40.37,66.27 40.37,67 36.89,70.48 36.89,82.88 38.08,84.07 38.08,91.77 37.12,92.74 37.12,106.53 36.69,106.96 36.69,116.61 34.96,118.34 34.96,129.44 33.26,131.14 v1(33.26,133.68)
  L4 w0.203: v1(53.83,52.83) 54.31,53.31 55.49,53.31 64.38,44.42 85.29,44.42 85.53,44.19 86.5,44.19 93.86,44.19 95.09,42.95 95.09,41.38 96.85,39.63 102.6,39.63 102.83,39.4 107.53,39.4 108.62,40.48 113.9,40.48 114.69,39.7 121.51,39.7 124.35,42.55 124.35,44.13 125.89,45.66 125.89,51.75 125.61,52.03 125.61,53.98 126.53,54.9 126.53,57.58 126.68,57.73 v1(126.68,58.01) ; v1(49.46,183.9) 49.41,183.85 46.92,183.85 44.03,180.95 44.03,174.68 47.75,170.96 47.75,161.56 48.39,160.92 48.39,158.01 49,157.4 49,150.37 48.93,150.29 48.93,149.24 33.37,133.68 v1(33.26,133.68)
  BOTTOM w0.203: v1(126.73,64.69) 126.22,64.19 C469.1 126.23,63.87 C470.1 126.23,62.09 v2(126.51,61.81) 127.5,60.82 R733.2 127.5,60.76 126.68,59.94 v1(126.68,58.01) 126.68,57.58 126.66,57.56 R739.2
VD_IN2: length 137.8
  TOP w0.203: U14.94 130.1,64.53 129.32,63.75 v1(129.32,62.8) ; v1(102.05,135.81) 102.74,135.12 R193.1
  L3 w0.203: v1(109.02,124.08) 108.6,124.5 108.6,129.34 102.13,135.81 v1(102.05,135.81) ; v1(115.86,81.08) 114.6,82.33 114.6,110.59 116.41,112.39 120.59,112.39 131.09,122.9 v1(131.09,125.24)
  L4 w0.203: v1(115.86,81.08) 116.16,80.77 117.3,80.77 119.24,78.83 122.46,78.83 124.2,77.09 132.65,77.09 133.48,76.25 133.48,75.84 133.78,75.54 134.09,75.54 135.59,74.03 135.59,69.81 135.25,69.47 135.25,69.33 129.32,63.39 v1(129.32,62.8)
  BOTTOM w0.203: v1(131.09,125.24) 130.98,125.24 130.01,126.21 110.66,126.21 v2(109.98,125.53) 109.02,124.57 v1(109.02,124.08) ; R732.2 128.82,60.96 130.19,60.96 R730.2 130.21,61.88 C472.1 130.22,62.04 C471.1 130.08,62.8 v1(129.32,62.8)
VD_OUT1#: length 4.9
  TOP w0.203: U14.110 124.25,68.08 124.53,68.36 125.29,68.36 v1(125.51,68.58) 125.51,69.86 D4.2
  BOTTOM w0.203: v2(124.9,68.05) 124.98,68.05 v1(125.51,68.58)
VD_OUT2#: length 4.3
  TOP w0.203: U14.112 123.45,67.77 123.15,68.07 v1(123.15,68.63) 123.15,69.47 D4.1
  BOTTOM w0.203: v2(122.84,69.39) 122.84,68.94 v1(123.15,68.63)
VGA_CORE_DISCHG: length 2.6
  TOP w0.102: Q12.3 77.96,120.68 R223.1 76.94,119.11 v4(76.94,119.12)
VNN_CTRL: length 33.1
  TOP w0.102: R4501.1 141.51,82.78 140.52,81.79 139.29,81.79 Q4501.G 138.29,78.9 v4(136.39,77) 135.64,76.25 134.86,76.25 134.2,75.59 133.79,75.59 133.21,76.17 127.72,76.17 126.75,75.21 122.25,75.21 121.67,74.64 121.67,72.16 120.65,71.14 U14.119
VNN_VCC_SENSE: length 55.2
  TOP w0.254: CPU1.AG48 83.9,172.64 83.9,172.64 v3(83.91,172.66)
  L3 w0.254: v1(59.38,201.9) 60.55,203.07 67.53,203.07 70.82,199.78 70.82,184.84 72.56,183.1 72.56,182.99 72.93,182.62 72.93,180.24 74.02,179.15 78.18,179.15 79.4,177.93 79.4,173.06 80.97,171.49 82.75,171.49 v3(83.91,172.66)
  BOTTOM w0.254: PG14.1 58.64,203.44 PR204.1 58.64,202.64 v1(59.38,201.9) 59.7,201.9 v2(60.05,202.26)
VNN_VSS_SENSE: length 51.1
  L3 w0.254: v3(77.58,173.15) 77.58,174.83 78.16,175.41 78.16,176.38 75.75,178.79 73.85,178.79 72.58,180.06 72.58,182.35 70.31,184.61 70.31,199.57 67.32,202.56 62.36,202.56 v1(61.76,201.96)
  BOTTOM w0.254: PR242.2 77.4,173.33 v3(77.58,173.15) ; PC143.2 58.52,205.54 PC138.1 59.65,205.65 PR199.1 60.31,205.67 v2(60.85,205.13) 60.34,204.62 59.85,204.62 59.7,204.47 PG13.2 59.98,203.89 60.33,203.89 61.76,202.46 v1(61.76,201.96)
VOUT_INV: length 5.2
  BOTTOM w0.305: U35.18 32.93,32.38 32.08,33.23 v2(32.08,33.28) 31.84,33.52 31.53,33.52 30.2,34.85 C499.1
  vias: v5(25.89,39.62) v5(25.89,38.76) v5(25.89,37.9)
VR_SVID_ALERT#: length 61.1
  TOP w0.102: R169.2 54.33,162.43 55.15,162.43 55.68,161.9 v1(55.68,161.57) 56.26,161.57 R170.1
  L4 w0.114: v1(55.68,161.57) 55.68,161.77 55.31,162.15 55.31,172.99 55.93,173.61 55.93,179.08 57.06,180.21 58.2,180.21 64.92,186.94 64.92,195.24 65.62,195.94 65.62,200.78 67.95,203.12 68.24,203.41 68.24,207.55 68.18,207.61 68.18,208.93 68.49,209.24 v1(68.49,210.31)
  BOTTOM w0.102: v1(68.49,210.31) 68.61,210.44 68.61,211.46 v2(68.49,211.58) R539.2
VR_SVID_CLK: length 3.8
  BOTTOM w0.102: PR192.2 66.26,209.96 PR195.2 68.12,209.22 R545.1 v2(69.14,209.23)
VR_SVID_DATA: length 66.5
  TOP w0.102: v1(55.85,162.94) 55.6,163.19 R168.1
  L4 w0.127: v1(55.85,162.94) 55.85,172.83 56.42,173.4 56.42,177.67 65.39,186.64 65.39,194.97 66.05,195.63 66.05,200.52 69.2,203.67 69.2,214.43 68.87,214.76 v1(68.87,216.28)
  BOTTOM w0.102: PR191.2 68.04,213.23 PR189.2 70.07,214.31 70.39,214.63 70.39,215.85 v2(70.06,216.18) 69.96,216.28 v1(68.87,216.28)
VREF: length 3.8
  BOTTOM w0.305: v2(36.58,30.99) 35.81,30.22 U35.2
  BOTTOM w0.508: v2(36.58,30.99) 37.65,32.05 C501.2
VREF_1: length 5.7
  TOP w0.203: U16.41 160.14,53.25 159.6,53.8 158.83,53.8 v4(158.42,54.21)
  TOP w0.305: v4(158.42,54.21) 158.59,54.21 159.32,54.94 159.32,55.58 C149.1
VREF_CA_DIMM1: length 63.1
  TOP w0.254: DIMM1.126 138.01,150.65 v1(136.94,149.58)
  L3 w0.254: v1(107.22,146.79) 122.66,131.34 124.67,131.34 125.74,130.28 v1(125.76,130.28)
  BOTTOM w0.254: R612.2 106.9,147.1 v1(107.22,146.79) ; v1(125.76,130.28) 126.7,131.22 138.3,131.22 139.1,132.01 139.1,141.48 v2(138.96,141.62) C342.1 138.97,142.86 138.97,146.14 R617.1 C341.1 v2(138.98,148.08) 138.98,149.11 R610.2 138.8,148.95 137.57,148.95 v1(136.94,149.58)
VREF_DQ_DIMM1: length 107.6
  TOP w0.254: v3(133.54,190.73) 133.36,190.55 DIMM1.1
  L4 w0.254: v1(108.19,147.7) 108.19,147.38 123.05,132.51 132.24,132.51 132.6,132.16 134.53,132.16 134.97,132.6 138.1,132.6 138.85,133.35 138.85,181.37 v1(141,183.51)
  BOTTOM w0.254: v3(133.54,190.73) 134.45,189.81 135.75,189.81 135.95,189.61 v2(136.63,189.61) 137.83,189.61 138.4,189.04 C274.1 138.4,187.88 R578.1 138.4,187.83 138.4,186.31 R581.2 139.9,186.41 139.95,186.41 C275.1 140.29,184.23 v1(141,183.51) ; R611.2 108.17,147.7 v1(108.19,147.7)
VREFC_U20: length 8.7
  TOP w0.102: 51.14,90.81 51.29,90.65 53.21,90.65 VRAM2.M8
  TOP w0.305: 51.14,90.81 50.93,91.01 48.84,91.01 C103.1 48.74,90.94 R284.2 R283.1 46.22,91.88 v4(46.18,91.84)
VREFC_U21: length 7.2
  BOTTOM w0.152: VRAM4.M8 58.48,91.04 58.84,90.68 59.23,90.68 59.28,90.63 60.03,90.63
  BOTTOM w0.305: 60.03,90.63 62.32,90.63 62.89,91.19 C443.1 63.18,91.21 R674.1 64.12,91.21 R669.2
VREFC_U22: length 8.5
  BOTTOM w0.102: VRAM3.M8 53.24,107.84 52.67,107.84 52.49,107.67 51.77,107.67
  BOTTOM w0.305: 51.77,107.67 51.39,108.04 49.19,108.04 C372.1 48.74,108.52 R646.2 R647.1
  BOTTOM w0.508: R647.1 47.14,109.46 v2(46.82,109.78)
VREFC_U23: length 7.2
  TOP w0.203: R267.1 64.29,107.37 R268.2 63.28,107.39 C80.1 63.05,108.58 58.79,108.58 VRAM1.M8
VREFD_U20: length 6.8
  TOP w0.305: R287.2 R292.1 63.18,89.78 C104.1 61.13,89.77 VRAM2.H1
VREFD_U21: length 8.9
  BOTTOM w0.305: v2(46.64,91.95) 46.69,91.99 R670.2 47.87,91.87 R673.1 C444.1 49.99,89.99 50.32,89.65 50.32,89.04 50.62,88.74 51.31,88.74 52.21,87.84 VRAM4.H1
VREFD_U22: length 7.7
  BOTTOM w0.203: R645.2 64.19,110.14 R652.1 64.18,109.12 C371.1 62.77,109.55 59.88,109.55 59.6,109.83 59.6,111 59.2,111.39 VRAM3.H1
VREFD_U23: length 6.6
  TOP w0.305: R253.1 R254.2 48.65,111.53 C73.1 50.34,112.47 51.41,111.4 VRAM1.H1
VREG_PCIAUX_PCH: length 7.6
  BOTTOM w0.381: Q48.C 130.4,218.14 Q50.D 130.34,214.44 R533.2 128.81,215.32 v2(128.79,215.34) 128.71,215.34 127.99,214.62 127.97,214.62 R534.1
VREG_PCIAUX_PCH_1: length 5.9
  BOTTOM w0.61: R534.2 C246.1 126.6,213.55 126.49,213.45 126.13,213.45 v2(125.74,213.06) 125.74,211.58 Q51.G 126.84,211.87 PC134.2
VRP: length 5.8
  TOP w0.203: U16.38 161.35,52.37
  TOP w0.254: C146.2 163.94,55.42 v4(163.48,54.97) 163.48,54.51 161.35,52.37
VTT_EN: length 254
  TOP w0.102: v3(149.77,131.6) 149.76,131.6 149.69,131.6 148.97,130.87 R198.2 PR84.1 ; v1(150.12,184.72) 150.12,186.61 149.41,187.31 149.41,199.67 148.86,200.23 148.85,200.23 148.14,200.93 v1(147.89,200.93) ; v1(30.26,185.1) 30.26,184.66 30.02,184.42 PC27.1 30.02,183.48 PR40.2
  L3 w0.127: v1(147.89,200.93) 146.49,200.93 136.24,211.18 121.37,211.18 120.08,212.47 119.69,212.47 119.5,212.28 106.52,212.28 103,215.8 101.65,215.8 100.9,216.55 98,216.55 97.22,217.33 97.22,217.99 95.82,219.4 90.54,219.4 89.68,220.26 87.33,220.26 87.16,220.09 78.49,220.09 74.69,223.89 32.37,223.89 31.07,222.59 31.07,220.58 29.55,219.05 29.55,208.53 29.56,208.52 29.56,202.36 28.72,201.52 28.72,186.76 30.26,185.23 v1(30.26,185.1)
  L4 w0.127: v3(149.77,131.6) 149.77,131.62 149.74,131.65 149.74,131.86 149.32,132.28 145.88,132.28 144.18,133.99 143.29,133.99 142.94,134.33 142.94,150.82 142.45,151.31 142.45,159.84 143.19,160.58 143.19,172.12 144.01,172.94 144.01,179.18 145.3,180.47 146.97,180.47 149.38,182.87 149.38,183.98 v1(150.12,184.72)
  BOTTOM w0.102: v1(30.26,185.1) 30.26,184.93 30.47,184.72 PR208.2 PR209.2 v2(31.38,183.02)
VTT_EN_R: length 72
  TOP w0.102: D2.3 146.27,190.05 R94.2 146.22,188.63 v1(146.37,188.47) ; v3(148.9,131.58) 148.64,131.32 148.24,131.32 148.08,131.15 R198.1
  L4 w0.127: v3(148.9,131.58) 148.88,131.6 145.64,131.6 144.35,132.89 142.86,132.89 141.93,133.82 141.93,150.4 141.32,151 141.32,171.88 142.97,173.54 142.97,181.52 146.62,185.17 146.62,188.22 v1(146.37,188.47)
  BOTTOM w0.102: v2(148.01,131.41) 148.17,131.57 148.56,131.57 148.57,131.58 v3(148.9,131.58)
WAKE_N_APU: length 76.6
  TOP w0.102: CPU1.AG55 v3(83.92,176.23) ; v1(100.2,217.4) 99.62,216.82 99.62,211.43 101.76,209.3 101.76,205.61 103.16,204.21 103.16,200.15 101.61,198.6 v1(101.61,197.87)
  L4 w0.089: v3(83.92,176.23) 83.36,176.8 83.36,180.79 83.37,180.81 83.37,181.45 83.36,181.47
  L4 w0.127: 83.36,181.47 83.15,181.67 83.15,187.18 84.31,188.33 87.3,188.33 87.9,188.93 87.9,189.96 87.9,189.96 87.9,190.33 87.9,190.33 87.9,192.23 94,198.32 101.13,198.32 101.58,197.87 v1(101.61,197.87)
  BOTTOM w0.102: v1(100.2,217.4) 103.34,217.4 104.3,218.36 107.13,218.36 108,219.23 111.81,219.23 v2(112.37,219.79) 113.38,220.8 R520.2 R517.2
WEBCAM_DET: length 181.8
  TOP w0.102: v1(120.05,55.88) 117.45,53.28 U14.34 ; R92.2 156.89,192.55 R91.2 156.9,191.32 156.9,191.32 156.9,189.47 v1(158.95,187.42)
  L3 w0.127: v1(158.95,187.42) 164.6,181.76 164.6,175.54 164.61,175.53 164.61,158.49 167.04,156.07 167.04,155.43 167.04,121.26 166.2,120.42 166.2,90.42 164.68,88.9 164.68,83.16 159.94,78.43 159.94,75.35 138.72,54.13 128,54.13 127.49,54.64 123.25,54.64 122.48,55.41 122.44,55.45 122.05,55.45 121.55,54.95 120.79,54.95 120.05,55.69 v1(120.05,55.88)
  BOTTOM w0.102: v1(120.05,55.88) 119.75,55.59 v2(119.75,55.11)
WEBCAM_DET_M: length 6.3
  TOP w0.102: R91.1 156.91,193.44 PC24.2 158.01,195.01 v4(157.59,195.43) 157,196.02 WEBCM1.7
XDP_H_TCK: length 89.8
  TOP w0.089: CPU1.B23 71.45,160.83 71.43,160.84
  TOP w0.102: 71.43,160.84 71.42,160.83 70.24,160.83 v3(69.6,161.47)
  L3 w0.127: v3(69.6,161.47) 69.2,161.87 59.82,161.87 55.04,166.66 52,166.66 50.07,168.59 30.04,168.59 23.93,174.7 23.93,179.86 22.18,181.61 22.18,197.12 25.11,200.06 v1(25.11,202.97)
  BOTTOM w0.102: R563.1 29.23,205.05 R567.2 28.34,203.01 v2(27.74,203.01) 25.15,203.01 v1(25.11,202.97)
XDP_H_TDI: length 112.3
  TOP w0.102: v3(69.71,159.44) 70.32,160.05 71.81,160.05 72,160.24 72.34,160.24 CPU1.C22
  L3 w0.127: v3(69.71,159.44) 68.14,161 66.59,161 65.79,160.2 54.9,160.2 54.89,160.19 54.5,160.19 54.4,160.29 47.59,160.29 46.99,159.68 46.74,159.68 45.82,158.76 41.51,158.76 40.72,157.98 32.76,157.98 30.81,159.92 25.11,159.92 23.17,161.85 23.17,176.95 21,179.13 21,197.9 20.82,198.07 20.82,202.71 21.54,203.43 21.54,207.15 v1(25.2,210.81)
  BOTTOM w0.102: R559.1 29.19,206.14 R546.2 29.19,208.5 v2(28.62,209.07) 27.16,210.53 25.48,210.53 v1(25.2,210.81)
XDP_H_TDO: length 101.3
  TOP w0.102: CPU1.A22 71.55,160.36 71.44,160.25 69.81,160.25 69.55,160 v3(69.02,159.46)
  L3 w0.127: v1(20.7,204.92) 20.46,204.69 20.46,197.58 20.74,197.31 20.74,179.02 22.91,176.85 22.91,161.67 24.92,159.66 30.42,159.66 32.36,157.72 40.83,157.72 41.61,158.51 45.93,158.51 46.85,159.43 47.1,159.43 47.66,159.99 54.33,159.99 54.39,159.93 54.99,159.93 55.01,159.94 65.9,159.94 65.95,159.99 68.49,159.99 v3(69.02,159.46)
  BOTTOM w0.102: RN18.3 23.46,205.97 23.25,205.75 R561.2 22.63,205.28 22.55,205.2 20.98,205.2 v1(20.7,204.92) 20.47,204.92 v2(20.02,204.47)
XDP_H_TMS: length 88.4
  TOP w0.089: CPU1.C23 72.55,160.83 72.34,160.66 72.23,160.54 71.96,160.54 71.86,160.64 71.53,160.64
  TOP w0.102: v3(68.92,161.47) 69.75,160.64 71.52,160.64 71.53,160.64
  L3 w0.127: v1(22.63,203.77) 22.63,203.73 22.5,203.6 22.5,197.8 21.93,197.23 21.93,178.93 23.68,177.18 23.68,174.59 29.93,168.34 49.96,168.34 51.9,166.41 54.93,166.41 59.79,161.55 68.84,161.55 v3(68.92,161.47)
  BOTTOM w0.102: v2(23.66,203.59) 23.66,204.55 R565.2 23.73,204.67 R564.2 v1(22.63,203.77)
XDP_H_TRST_N: length 90.4
  TOP w0.089: 71.32,161.03 71.51,161.03 71.53,161.02 71.84,161.02 71.86,161.03 72.02,161.15 72.32,161.15 CPU1.C24
  TOP w0.102: R171.2 67.97,161.56 68.27,161.86 69.92,161.86 v3(70.29,161.49) 70.76,161.02 71.31,161.02 71.32,161.03
  L3 w0.127: v1(25.29,203.75) 25.58,203.46 25.58,200.16 24.42,199 24.42,174.57 30.08,168.91 50.11,168.91 52.11,166.91 55.15,166.91 59.93,162.13 69.65,162.13 v3(70.29,161.49)
  BOTTOM w0.102: v1(25.29,203.75) 25.73,203.75 26.2,204.22 v2(26.22,204.22) 27.09,205.09 R560.1
XRF_TDC2: length 14.8
  TOP w0.508: v1(49.92,13.84) XF1.9 51.21,10.03 v1(49.92,10.03) ; C221.1 49.44,17.04 49,16.61 v1(48.85,16.61) 48.85,16.46 47.94,15.54 v4(47.94,15.47)
  L3 w0.508: v1(48.85,16.61) 49.92,15.54 v1(49.92,13.84)
  BOTTOM w0.508: 51.21,10.03 v1(49.92,10.03) ; XF1.9 v1(49.92,13.84)
XTAL19D2M_IN: length 23.4
  TOP w0.102: X2.1 64.08,156.8 64.1,156.79 R174.1 64.67,156.3 64.65,156.28 C37.2 65.61,155.73 66.1,155.24 66.1,154.48 66.23,154.36 66.48,154.36 66.61,154.48 66.61,155.24 66.71,155.35 68.22,155.35 v3(68.75,155.87) ; CPU1.R27 v3(78.15,163.13)
  L4 w0.127: v3(78.15,163.13) 78.15,162.28 74.04,158.18 71.02,158.18 68.75,155.91 v3(68.75,155.87)
  BOTTOM w0.102: v3(68.75,155.87) 68.75,155.36 v2(69.07,155.04)
XTAL19D2M_OUT: length 23.4
  TOP w0.102: X2.3 62.53,158.16 63.71,158.16 64.25,158.71 C36.2 64.67,157.68 R174.2 66.44,155.9 v3(68.02,155.9) ; CPU1.P29 v3(77.44,163.13)
  L4 w0.127: v3(68.02,155.9) 70.71,158.58 73.88,158.58 77.44,162.14 v3(77.44,163.13)
  BOTTOM w0.102: v3(68.02,155.9) 67.67,155.55 v2(67.67,155.19)
XTAL_OUTBUFF: length 10.3
  TOP w0.102: R300.2 93.31,85.47 93.3,85.47 92.89,85.88 92.64,85.88 v4(92.57,85.95) 91.57,85.95 R299.1 90.85,86.66 89.81,86.66 88.7,87.78 88.16,87.78 86.72,89.22 86.72,90.5 86.32,90.89 GPU1.C10
XTAL_SSFOUT: length 6.6
  TOP w0.102: GPU1.A10 86.67,88.95 86.67,88.34 v1(86.93,88.09) 87.72,87.29 88.68,87.29 89.97,85.99 R298.1
  BOTTOM w0.102: v2(86.32,88.44) 86.57,88.44 v1(86.93,88.09)
XTALIN: length 12.4
  TOP w0.102: GPU1.C11 85.48,90.66 85.82,90.32 85.82,89.91 85.76,89.85 85.76,88.96 85.95,88.77 85.95,87.34 85.74,87.12 85.74,86.92 84.67,85.85 v1(84.61,85.85) 84.64,85.82 84.64,85.14 C114.1 84.96,83.79 84.96,82.26 X3.1
  BOTTOM w0.102: v2(83.85,86.23) 84.23,86.23 v1(84.61,85.85)
XTALOUT: length 4.7
  TOP w0.102: R816.2 86.2,84.64 C115.1 86.05,83.82 85.3,83.82 85.18,83.7 85.18,82.92 85.34,82.77 X3.3
XTALOUT_GPU: length 6.1
  TOP w0.102: GPU1.B10 85.98,89.76 85.98,89.05 86.17,88.86 v1(86.17,86.94) 86.14,86.94 85.94,86.74 85.94,86.18 85.31,85.56 R816.1
  BOTTOM w0.102: v1(86.17,86.94) 85.76,86.53 v2(85.76,86.49)

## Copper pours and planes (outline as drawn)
1V_CPU_VCGI on TOP: 54.26,181.69 54.14,181.81 54.14,197.61 54.52,197.99 57.06,197.99 57.44,197.61 57.44,196.33 58.13,195.63 65.17,195.63 65.69,195.11 65.69,187.2 60.18,181.69 ; 4 cut-outs
1V_CPU_VCGI on TOP: 79.36,163.36 79.28,163.44 79.28,165.13 79.67,165.52 80.02,165.52 80.47,165.06 84.64,165.06 84.64,166.35 84.71,166.42 84.99,166.42 85.03,166.46 85.03,166.55 85.1,166.62 85.23,166.62 85.29,166.55 85.29,166.29 85.6,165.98 85.6,165.52 85.97,165.15 85.97,163.76 85.58,163.36 84.3,163.36 84.25,163.41 83.93,163.41 83.87,163.36
1V_CPU_VCGI on TOP: 83.2,165.89 83.03,166.07 81.55,166.07 81.39,165.91 81.04,165.91 80.9,166.06 79.54,166.06 79.14,166.46 79.14,166.46 78.92,166.68 78.92,167.15 78.76,167.31 78.76,170.38 78.59,170.55 78.59,170.87 77.93,171.53 77.93,171.86 78.25,172.17 78.56,172.17 78.76,172.37 78.76,172.65 79.03,172.92 79.43,172.92 79.57,172.77 79.57,172.23 79.91,171.89 79.91,169.75 80.18,169.48 80.55,169.48 82.01,168.02 83.38,168.02 83.62,167.78 83.62,167.65 83.46,167.49 83.46,167.16 83.89,166.72 83.89,166.36 83.43,165.89
1V_CPU_VCGI on BOTTOM: 59.13,159.99 55.27,163.86 55.27,170.53 54.14,171.66 54.14,197.61 54.52,197.99 57.06,197.99 57.44,197.61 57.44,196.09 58.45,195.07 65.27,195.07 65.44,194.9 65.44,186.82 65.82,186.44 73.91,186.44 76.32,184.02 76.32,180.44 78.25,178.51 78.25,172.51 79.13,171.63 79.13,170.75 80.29,169.58 80.29,169.15 80.52,168.92 80.8,168.92 80.8,168.91 81.19,168.91 81.24,168.86 82.75,168.86 83.69,167.92 83.69,165.98 83.87,165.79 83.87,165.12 84.07,164.92 84.56,164.92 84.56,164.93 84.87,164.93 85.11,165.17 85.11,165.88 85.07,165.92 84.72,165.92 84.56,166.08 84.56,166.25 84.88,166.57 84.88,167.05 84.93,167.1 85.42,167.1 85.42,164.99 85.25,164.82 85.25,163.84 84.96,163.56 84.08,163.56 83.29,162.77 79.79,162.77 79.26,163.3 73.77,163.3 72.78,162.31 72.4,162.31 72.38,162.3 71.95,162.3 71.38,161.72 68.55,161.72 67.88,161.05 67.53,161.05 66.47,159.99 ; 42 cut-outs
1V_CPU_VCGI on L2VCC: 67.04,161.99 66.41,162.62 60.56,162.62 54.33,168.86 54.33,197.28 54.85,197.8 56.98,197.8 57.37,197.41 57.37,196.01 58.5,194.88 64.85,194.88 65.5,194.23 65.5,187.37 66.25,186.63 77.82,186.63 78.39,186.17 78.44,186.12 78.46,186.11 78.53,186.12 79.58,186.12 79.73,185.98 79.73,170.86 80.61,169.97 80.61,169.09 81.11,168.59 83.01,168.59 84.41,167.2 85.06,167.2 85.06,163.78 84.81,163.53 84.81,162.64 84.16,161.99
1V_CPU_VCGI on L4: 77.5,173.74 73.94,173.74 73.08,174.59 71.65,174.59 70.81,173.75 70.81,161.95 70.95,161.8 73.43,161.8 73.7,162.06 73.7,163.23 72.96,163.96 72.96,164.49 73.3,164.83 75.8,164.83 76.63,164.01 79.04,164.01 79.76,163.28 82.02,163.28 82.18,163.44 82.18,168.11 80.71,169.59 80.71,171.55 80.11,172.15 79.09,172.15
1V_CPU_VNN on TOP: 84.36,167.13 84.23,167.26 84.23,170.05 84.62,170.43 84.62,170.69 84.23,171.07 84.23,171.32 84.36,171.45 85.25,171.45 86.03,170.67 86.03,170.32 85.38,169.67 85.38,168.78 85.25,168.66 85.25,168.4 85.38,168.28 85.38,167.26 85.25,167.13
1V_CPU_VNN on BOTTOM: 84.92,167.62 84.92,167.93 84.56,168.29 84.56,169.72 84.4,169.89 83.91,169.89 83.83,169.98 83.83,170.48 83.87,170.52 84.45,170.52 84.52,170.6 84.52,171.26 85.11,171.85 85.11,179.43 85.84,180.16 85.84,186.7 84.34,188.21 84.34,190.7 84.03,191.01 84.03,192.3 81.92,194.41 81.92,195.38 80.86,196.44 75.42,196.44 74.33,197.54 74.33,201.42 74.58,201.68 76.92,201.68 78.04,202.79 88.22,202.79 88.53,202.49 88.53,201.93 89.14,201.32 89.14,200.79 89.92,200 89.92,199.39 90.36,198.96 90.36,196.6 91.1,195.85 91.1,192.17 91.31,191.96 91.31,186.55 88.73,183.97 88.73,181.59 85.79,178.65 85.79,171.91 85.7,171.81 85.7,170.28 85.69,170.27 85.18,170.27 85.12,170.21 85.12,168.42 85.4,168.15 85.4,167.62 ; 17 cut-outs
1V_CPU_VNN on L2VCC: 84.57,167.58 83.17,168.97 81.27,168.97 81,169.24 81,170.13 80.11,171.02 80.11,177.86 81.52,177.86 82.14,178.48 82.14,180.67 81.5,181.31 81.5,184.71 82.01,185.21 82.01,193.22 86.6,197.8 87.46,197.8 88.49,196.77 88.49,192.61 87.6,191.72 87.6,175.08 87.09,174.58 87.09,172.29 86.46,171.66 86.46,167.85 86.19,167.58
1V_CPU_VNN on L3: 89.29,191.77 88.37,191.77 87.79,191.19 87.79,189.28 86.65,188.14 86.65,186.41 86.35,186.12 86.35,184.98 85.86,184.48 85.86,176.38 86.42,175.82 86.42,173.46 85.28,172.31 85.28,171.73 84.56,171.02 84.56,168.43 84.72,168.28 85.66,168.28 85.99,168.61 85.99,169.62 85.94,169.67 85.94,170.08 86.77,170.92 86.77,171.78 87.18,172.19 87.18,172.49 87.33,172.64 87.33,175.74 86.75,176.33 86.75,179.17 87.03,179.45 87.03,182.12 87.64,182.73 87.64,184.48 90,186.84 90,191.06
1V_VCCIOA on BOTTOM: 86.19,169.05 85.97,169.27 85.97,178.41 87.43,179.87 88.43,179.87 89.12,180.56 89.12,183.73 89.12,183.73 89.12,184.06 89.36,184.3 90.53,184.3 90.62,184.22 90.62,180.54 90.21,180.13 90.21,178.95 89.95,178.69 88.36,178.69 87.37,177.7 87.37,172.4 86.9,171.94 86.9,169.19 86.76,169.05 ; 4 cut-outs
3V3_VDD33 on TOP: 86.26,93.9 85.9,94.25 85.04,94.25 84.73,93.95 84.56,93.95 84.46,94.05 84.46,94.21 84.46,94.21 84.46,94.82 84.64,95 86.94,95 87.57,95.63 88.01,95.63 88.32,95.32 88.32,94.38 87.94,94 87.28,94 87.18,93.9
3V3_VDD33 on BOTTOM: 86.24,92.94 86.14,93.04 86.14,94.01 85.96,94.19 85.6,94.19 85.5,94.29 85.5,94.87 85.63,95 86.52,95 86.64,95.13 86.88,95.13 87.27,95.52 87.84,95.52 88.09,95.27 90.51,95.27 90.66,95.13 93.02,95.13 93.17,95.28 93.4,95.28 93.55,95.13 94.18,95.13 94.34,94.97 94.34,94.63 94.19,94.49 93.89,94.49 93.78,94.39 93.78,94.38 93.4,94 88.6,94 88.4,94.19 87.46,94.19 87.23,93.95 87.23,93.07 87.1,92.94 ; 4 cut-outs
19V_AMP_PVCC on TOP: 153.58,35.26 153.35,35.48 153.35,36.42 153.02,36.75 153.02,38.51 153.25,38.73 155.02,38.73 155.35,38.4 155.35,37.13 154.59,36.37 154.59,35.41 154.44,35.26 ; 5 cut-outs
19V_AMP_PVCC on L3: 154.59,37.62 153.12,37.62 152.33,36.83 152.33,26.62 152.79,26.16 154.82,26.16 155.15,26.49 155.15,27.51 154.06,28.6 154.06,31.95 154.99,32.88 154.99,34.94 155.23,35.18 155.23,36.98
+5V_PWR on TOP: 93.89,57.91 93.51,58.29 93.51,62.87 93,63.37 85.76,63.37 85.38,63.75 85.38,70.36 85.71,70.69 97.23,70.69 97.44,70.48 97.44,58.17 97.19,57.91 ; 2 cut-outs
AGND on TOP: 159.14,56.82 159.05,56.91 159.05,58.84 159.24,59.03 160.23,59.03 160.56,59.36 160.56,60.33 159.93,60.96 159.93,63.12 169.83,73.03 171.1,73.03 171.36,72.77 171.36,72.14 165.77,66.55 165.77,60.1 166.73,59.13 166.73,57.68 166.63,57.58 161.37,57.58 160.79,57 160.05,57 159.88,56.82 ; 2 cut-outs
AGND on L2VCC: 89.65,2.35 86.96,5.03 86.96,27.76 82.92,31.81 73.01,31.81 71.98,32.84 71.98,42.34 72.88,43.24 81.62,43.24 84.68,40.18 84.68,37.01 85.68,36 86.31,36 87.09,35.23 87.09,31.54 88.87,29.77 88.87,6.27 91.01,4.13 152.74,4.13 152.88,3.99 152.88,2.87 152.35,2.35
AGND on L2VCC: outline of 108 points within 153.51,18.55 184.24,82.36
AGND on L5GND: 150.73,2.48 150.46,2.75 150.46,14.91 153.89,18.34 153.89,20.11 154.91,21.13 154.91,22.91 163.04,31.04 163.04,35.64 157.83,40.85 157.83,44.12 158.21,44.5 158.21,46.15 158.23,46.16 161.91,46.16 162.15,46.4 162.15,51.01 161.78,51.37 157.31,51.37 156.93,50.99 156.07,50.99 155.8,51.26 155.8,51.77 153.51,54.05 153.51,56.56 154.53,57.58 154.53,59.36 158.48,63.31 160.01,63.31 166.47,69.77 166.47,72.82 167.61,73.96 167.61,75.15 166.59,75.91 166.59,76.76 167.48,77.65 167.48,80.31 169.53,82.36 174.33,82.36 178.01,78.68 180.71,78.68 182.61,80.58 184.24,80.58 184.24,67.9 184.17,67.73 184,67.66 179.67,67.66 179.67,71.33 178.93,72.07 175.98,72.07 174.07,70.17 170.64,70.17 167.48,67.01 167.48,50.92 167.79,50.62 167.79,27.92 166.98,27.11 166.32,27.11 164.55,25.34 163.28,25.34 159.86,21.92 159.86,21.29 153,14.43 153,2.75 152.74,2.48
GND on TOP: 47.3,162.89 47.2,162.99 47.2,167.36 47.33,167.49 49.11,167.49 49.61,166.98 49.61,163.09 49.41,162.89 ; 1 cut-out
GND on TOP: 124.65,195.86 121.29,199.21 121.29,202.95 123.17,202.95 123.91,203.68 123.91,205.26 124.34,205.69 136.28,205.69 137.02,204.95 137.02,196.27 136.61,195.86 ; 4 cut-outs
GND on TOP: 64.04,24.38 63.66,24.77 63.66,27.81 63.91,28.07 67.72,28.07 67.98,27.81 67.98,24.64 67.72,24.38
GND on TOP: 34.58,188.21 34.32,188.47 34.32,201.55 36.23,203.45 36.23,214 36.61,214.38 39.66,214.38 40.04,214 40.04,208.23 40.95,207.31 40.95,202.74 40.65,202.44 39.15,202.44 37.5,200.79 37.5,199.26 38.39,198.37 38.39,194.82 38.26,194.69 36.61,194.69 36.48,194.56 36.48,192.53 36.86,192.15 38.26,192.15 38.39,192.02 38.39,188.34 38.26,188.21 ; 2 cut-outs
GND on TOP: 144.97,134.34 144.76,134.54 144.76,135.08 144.48,135.36 143.59,135.36 143.37,135.59 143.37,137.72 143.85,138.2 144.53,138.2 144.56,138.18 146.39,138.18 146.54,138.02 146.54,136.6 146.21,136.27 146.21,134.44 146.11,134.34 ; 2 cut-outs
GND on TOP: 69.62,65.53 69.62,65.53 69.32,65.53 69.03,65.82 69.03,68.49 67.8,69.72 67.8,70.54 68.87,71.6 74.56,71.6 74.66,71.5 74.66,70.33 75.32,69.67 75.32,67.36 75.22,67.26 73.85,67.26 73.69,67.11 73.69,65.66 73.57,65.53 ; 1 cut-out
GND on TOP: 98,87.63 97.87,87.76 97.87,89.33 97.95,89.41 98.51,89.41 98.66,89.56 98.66,90.17 99.47,90.98 99.47,91.44 98.97,91.95 97.97,91.95 97.85,92.08 97.85,95.25 97.95,95.35 97.95,95.38 98.71,95.38 99.23,94.86 99.23,92.47 99.98,91.72 99.98,87.88 99.73,87.63 ; 6 cut-outs
GND on TOP: 40.42,180.85 39.91,181.36 39.91,182.75 40.67,183.51 43.98,183.51 44.36,183.13 44.36,181.1 44.1,180.85
GND on TOP: 89.14,55.8 87.66,57.28 87.66,58.93 87.87,59.13 93.07,59.13 93.17,59.03 93.17,55.93 93.05,55.8
GND on TOP: 38.32,50.36 38.06,50.62 38.06,52.96 38.44,53.34 41.94,53.34 42.07,53.21 42.07,50.67 41.75,50.36 ; 4 cut-outs
GND on TOP: 27.72,172.97 27.59,173.1 27.59,177.29 27.72,177.42 27.72,181.79 27.8,181.86 28.53,181.86 28.63,181.76 28.63,181.08 29.37,180.34 29.37,177.42 30.26,176.53 30.64,176.53 31.02,176.15 31.02,173.86 30.13,172.97 ; 2 cut-outs
GND on TOP: 152.59,143.41 151.91,144.08 151.91,147.89 150.96,148.84 150.96,149.4 151.02,149.47 151.79,149.47 152.84,150.52 152.84,151.36 153.07,151.59 155.1,151.59 155.2,151.49 155.2,149.63 155.79,149.05 155.79,143.79 155.4,143.41 ; 1 cut-out
GND on TOP: 134.53,97.41 134.4,97.54 134.4,99.98 134.28,100.1 133.56,100.1 133.51,100.15 133.51,103.38 135.16,103.38 135.42,103.63 135.42,104.14 135.67,104.39 144.56,104.39 145.19,103.76 145.19,98.04 144.56,97.41 ; 3 cut-outs
GND on TOP: 140.77,173 140.55,173.23 140.55,174.22 141.31,174.98 141.38,174.98 141.61,175.21 141.61,179.96 141.87,180.21 143.85,180.21 144.2,179.86 144.2,173.84 143.37,173
GND on TOP: 113.16,105.17 113.01,105.32 113.01,106.76 113.23,106.98 116.42,106.98 116.72,106.68 116.72,105.32 116.57,105.17
GND on TOP: 47.4,23.37 47.15,23.62 47.15,24.64 47.91,25.4 47.91,32.5 46.85,33.57 46.85,36.65 48.55,38.35 49.31,38.35 49.31,38.61 49.82,39.12 53.37,39.12 53.67,38.82 53.67,31.99 53.4,31.72 51.04,31.72 50.48,31.17 50.48,26.49 48.8,24.82 48.8,24.05 48.12,23.37
GND on TOP: 106.89,112.62 104.94,114.58 101.51,114.58 101.3,114.78 101.3,116.03 101.53,116.26 107.75,116.26 108.34,115.67 112.2,115.67 113.57,114.3 113.57,112.9 113.44,112.78 111.41,112.78 111.13,113.05 111.13,114.13 110.85,114.41 109.17,114.41 108.7,113.93 108.7,112.97 108.35,112.62
GND on TOP: 29.83,143.51 29.67,143.66 29.67,149.68 29.52,149.83 29.52,153.34 29.62,153.44 31.07,153.44 31.33,153.19 31.33,143.56 31.28,143.51 ; 2 cut-outs
GND on TOP: 79.15,211.84 78.77,212.22 78.77,212.88 78.42,213.23 77.12,213.23 76.89,213.46 76.89,218.06 76.94,218.11 80.2,218.11 81.44,216.87 81.44,211.89 81.39,211.84
GND on TOP: 91.14,5.18 89.49,6.83 89.49,16.87 90.1,17.48 91.98,17.48 94.19,15.27 97.95,15.27 99.19,14.02 99.19,9.96 99.8,9.35 102.14,9.35 104.68,11.89 104.68,21.89 105.01,22.23 107.17,22.23 107.75,21.64 107.75,12.32 104.45,9.02 104.45,6.45 103.18,5.18
GND on TOP: 41.49,30.73 41.38,30.84 41.38,33.43 42.45,34.49 42.45,38.99 42.58,39.12 45.56,39.12 45.73,38.94 45.73,38.1 45.74,38.09 45.74,37.33 45.37,36.96 45.37,34.98 43.42,33.02 43.42,30.96 43.19,30.73
GND on TOP: 120.02,123.95 117.81,126.16 113.15,126.16 99.73,139.58 98.24,139.58 98.22,139.56 97.44,140.34 96.55,140.34 95.92,140.97 92.87,140.97 91.22,139.32 90.97,139.32 90.58,139.7 90.58,141.29 87.97,143.91 87.97,148.18 86.72,149.43 86.72,149.76 86.82,149.86 93.09,149.86 93.17,149.78 94.13,149.78 94.72,150.37 94.72,159.63 94.55,159.81 94.55,161.52 94.39,161.68 94.39,161.99 94.62,162.22 94.62,163.43 94.71,163.53 95.51,163.53 96.05,162.99 100.21,162.99 100.72,163.5 100.72,165.35 99.42,166.65 99.42,167.23 101.25,169.06 101.25,170.26 101.66,170.66 103.16,170.66 103.89,171.4 103.89,176.83 101.15,179.58 96.12,179.58 95.41,180.29 94.42,180.29 94.06,180.64 94.06,182.25 95.89,184.07 95.89,185.06 94.98,185.98 94.39,185.98 92.97,187.4 92.97,194.46 92.87,194.56 93.28,194.97 97.42,194.97 98.05,194.34 129.24,194.34 129.6,193.98 129.6,131.04 128.86,130.3 126.96,130.3 126.53,129.87 126.53,124.59 125.89,123.95
GND on TOP: 88.02,59.46 87.79,59.69 87.79,62.58 88.25,63.04 92.64,63.04 92.87,62.81 92.87,59.74 92.59,59.46
GND on TOP: outline of 288 points within 0.76,0.79 184.24,229.24 ; 12 cut-outs
GND on TOP: 64.68,131.57 64.68,128.27 66.58,126.36 66.58,123.19 69.88,119.89 72.55,119.89 74.07,121.41 74.07,127 70.65,130.43 69.25,130.43 68.11,131.57
GND on TOP: 66.03,186.92 66.03,192.43 66.26,192.65 68.17,192.65 68.49,192.34 68.49,187.07 68.33,186.92 ; 2 cut-outs
GND on TOP: 164.99,98.3 163.14,100.15 163.14,101.46 163.28,101.6 168.18,101.6 168.44,101.35 168.44,99.62 168.71,99.34 169.17,99.34 169.3,99.21 169.3,98.53 169.07,98.3 ; 2 cut-outs
GND on TOP: 95.54,26.92 95.16,27.3 95.16,28.07 95.92,28.83 95.92,30.1 97.06,31.24 98.97,31.24 100.11,30.1 100.11,27.05 99.98,26.92
GND on TOP: 105.64,105.97 104.81,106.81 101.76,106.81 101.51,107.06 101.51,107.7 101.89,108.08 110.9,108.08 111.03,107.95 111.03,106.55 111.03,106.55 111.03,106.33 110.67,105.97
GND on TOP: 33.05,159.77 32.8,160.02 32.8,163.75 32.85,163.8 32.85,166.9 32.95,167 34.45,167 34.58,166.88 34.58,164.08 35.09,163.58 35.09,161.42 35.34,161.16 35.34,159.89 35.21,159.77 ; 1 cut-out
GND on TOP: 72.42,22.35 71.92,22.86 71.92,26.16 74.68,28.93 74.71,28.93 74.99,29.21 77.88,29.21 78.65,28.45 78.65,26.97 79.08,26.54 81.57,26.54 82.33,25.78 82.33,22.61 82.08,22.35
GND on TOP: 40.42,170.18 40.17,170.43 40.17,173.23 40.29,173.35 43.98,173.35 44.1,173.23 44.1,170.31 43.98,170.18 ; 2 cut-outs
GND on TOP: 70.29,54.89 70.16,55.02 70.16,56.16 70.7,56.69 70.7,58.12 71.72,59.14 74.37,59.14 74.38,59.13 74.48,59.13 74.79,59.44 75.42,59.44 75.55,59.31 75.55,55.91 74.07,55.91 73.87,55.7 73.87,55.04 73.72,54.89 ; 1 cut-out
GND on TOP: 20.73,193.17 20.61,193.29 20.61,195.96 20.86,196.22 23.66,196.22 23.91,195.96 23.91,193.93 23.15,193.17
GND on TOP: 59.61,211.19 58.8,211.99 58.8,214.64 59.48,215.32 62.69,215.32 63.27,214.75 63.27,212.16 62.29,211.19
GND on TOP: 51.87,181.65 50.76,182.75 50.71,182.75 50.2,183.26 50.2,187.07 50.45,187.32 53.25,187.32 53.63,186.94 53.63,181.84 53.44,181.65 ; 2 cut-outs
GND on TOP: 21.75,196.72 21.37,197.1 21.37,200.41 21.62,200.66 23.53,200.66 23.78,200.41 23.78,196.98 23.53,196.72
GND on TOP: 42.81,152.96 42.67,153.09 42.67,154.09 44.74,156.16 48.36,156.16 49.69,154.83 49.69,153.14 49.51,152.96 ; 2 cut-outs
GND on TOP: 58.62,196.3 58.07,196.85 58.07,200.31 58.44,200.68 64.67,200.68 65.06,200.29 65.06,196.9 64.46,196.3
GND on TOP, BOTTOM: 63.41,20.45 63.28,20.57 63.28,22.61 63.41,22.73 66.45,22.73 66.58,22.61 66.58,20.57 66.45,20.45
GND on BOTTOM: 33.05,161.04 32.67,161.42 32.67,166.88 32.8,167 34.32,167 34.45,166.88 34.45,164.21 35.09,163.58 35.09,161.29 34.83,161.04
GND on BOTTOM: 94.6,157.96 94.22,158.34 94.22,160.17 94.39,160.35 94.39,160.96 94.55,161.11 95.16,161.11 95.41,161.37 96.93,161.37 98,160.3 98,158.7 97.7,158.39 96.5,158.39 96.07,157.96 ; 1 cut-out
GND on BOTTOM: 80.91,106.88 80.78,107.01 80.78,109.63 81.21,110.06 81.21,115.04 80.65,115.6 77.93,115.6 77.02,116.51 75.01,116.51 74.81,116.71 74.81,117.5 75.06,117.75 75.06,119.41 74.71,119.76 68.49,119.76 66.1,122.15 66.1,127.48 62.9,130.68 62.9,131.06 62.39,131.57 62.39,132.46 63.03,133.1 72.93,133.1 76.49,129.54 76.49,123.16 77.36,122.29 77.36,121.27 82.74,115.9 82.74,114.81 82.89,114.66 82.89,113.11 83.07,112.93 83.07,110.59 84.06,109.6 84.06,107.01 83.93,106.88 83.17,106.88 82.99,107.06 82.99,107.42 82.81,107.59 81.59,107.59 81.39,107.39 81.39,106.96 81.31,106.88 ; 5 cut-outs
GND on BOTTOM: 157.77,46.61 157.51,46.86 157.51,47.37 157.26,47.62 157.26,50.55 157.64,50.93 161.32,50.93 161.7,50.55 161.7,47.12 161.2,46.61 ; 3 cut-outs
GND on BOTTOM: 66.07,186.69 65.82,186.94 65.82,192.91 65.82,192.91 65.82,195.01 65.99,195.18 66.76,195.18 66.94,195 66.94,193.34 67.24,193.04 68.11,193.04 68.49,192.66 68.49,187.07 68.11,186.69 ; 6 cut-outs
GND on BOTTOM: 82.46,159.3 82.2,159.56 82.2,160.86 82.08,160.97 81.69,160.97 81.09,160.37 80.94,160.37 80.73,160.16 80.73,159.77 80.59,159.63 80.29,159.63 80.15,159.77 80.15,160 80.37,160.22 80.37,160.94 80.43,161 81.31,161 81.58,161.27 81.58,162.44 81.7,162.56 83.49,162.56 83.83,162.91 83.83,163.45 85.03,163.45 85.37,163.8 85.37,164.29 85.37,164.29 85.37,164.81 85.51,164.96 85.51,168.37 85.2,168.37 85.2,169.88 85.71,169.88 85.71,169.23 85.99,168.95 86.43,168.95 86.43,168.44 85.94,168.44 85.94,167.01 86.46,166.5 86.46,166.2 86.92,165.73 86.92,165.13 86.83,165.04 86.37,165.04 86.15,164.82 86.15,164.14 85.98,163.97 85.98,163.64 86.11,163.52 86.49,163.52 86.62,163.39 86.62,162.85 86.57,162.81 84.47,162.81 84.47,162.67 84,162.21 84,161.91 85.73,161.91 85.73,161.1 85.53,160.9 85.53,160.1 85.77,159.87 85.77,159.49 85.7,159.42 85.02,159.42 83.82,160.62 83.82,160.91 83.69,161.04 83.66,161.07 82.98,161.07 82.88,160.98 82.88,159.37 82.81,159.3 ; 5 cut-outs
GND on BOTTOM: 38.23,50.39 38.06,50.57 38.06,52.88 38.21,53.04 39.12,53.04 39.53,53.44 39.53,54.38 39.58,54.43 41.79,54.43 42.04,54.18 42.04,50.88 41.56,50.39
GND on BOTTOM: 42.73,35.05 42.5,35.28 42.5,39.29 42.63,39.42 44.1,39.42 44.43,39.09 45.58,39.09 45.75,38.91 45.75,37.52 45.65,37.41 44.89,37.41 44.56,37.08 44.56,35.61 44,35.05
GND on BOTTOM: 150.88,132.87 150.58,133.17 150.58,133.91 150.43,134.06 149.56,134.06 149.28,133.78 148.95,133.78 148.8,133.93 148.8,135.41 149.08,135.69 152.31,135.69 152.66,135.33 152.66,133.07 152.46,132.87 ; 2 cut-outs
GND on BOTTOM: 60.9,57.41 60.75,57.56 60.75,61.85 60.89,61.99 62.25,61.99 62.77,61.47 62.77,60.37 63.02,60.12 63.02,57.74 62.7,57.41 ; 1 cut-out
GND on BOTTOM: 34.5,188.09 34.04,188.54 34.04,201.45 35.75,203.15 35.75,213.69 36.38,214.33 39.02,214.33 39.61,213.74 39.61,208.66 40.95,207.31 40.95,202.74 40.63,202.43 39.16,202.43 36.76,200.03 36.76,188.65 36.2,188.09
GND on BOTTOM: 119.92,206.63 119.67,206.88 119.67,214.63 119.92,214.88 123.41,214.88 123.64,214.65 123.64,206.75 123.53,206.63
GND on BOTTOM: 136.76,125.27 135.69,126.34 134.53,126.34 133.71,125.53 131.58,125.53 129.8,127.3 127.82,127.3 127.36,127.76 127.36,128.12 127.46,128.22 132.82,128.22 133.1,127.94 138.92,127.94 139.19,127.67 139.19,126.48 137.99,125.27 ; 15 cut-outs
GND on BOTTOM: 29.75,143.51 29.55,143.71 29.55,153.34 29.65,153.44 31.02,153.44 31.33,153.14 31.33,143.56 31.28,143.51
GND on BOTTOM: 155.67,196.29 155.32,196.63 155.32,199.14 155.73,199.55 162.21,199.55 162.32,199.44 162.32,198.17 160.44,196.29 ; 1 cut-out
GND on BOTTOM: outline of 320 points within 0.76,0.76 184.24,229.24 ; 22 cut-outs
GND on BOTTOM: 87.69,59.44 87.43,59.69 87.43,62.64 87.92,63.12 90.46,63.12 91.35,62.23 91.35,59.94 90.84,59.44
GND on BOTTOM: 84.07,165.13 83.93,165.27 83.93,167.9 83.71,168.13 82.76,169.08 82.55,169.08 82.39,169.23 82.39,169.67 82.44,169.72 82.78,169.72 83.04,169.97 83.6,169.97 83.84,169.74 84.36,169.74 84.45,169.64 84.45,168.22 84.52,168.15 84.52,166.01 84.73,165.8 84.94,165.8 84.98,165.76 84.98,165.28 84.83,165.13 ; 2 cut-outs
GND on BOTTOM: 152.94,174.24 150.78,174.24 150.78,173.1 150.27,172.59 148.12,172.59 147.73,172.21 147.73,170.05 148.37,169.42 150.15,169.42 150.78,168.78 150.78,167.89 152.94,167.89
GND on BOTTOM: 89.06,55.88 87.66,57.28 87.66,58.93 87.79,59.05 90.84,59.05 90.97,58.93 90.97,56.39 90.46,55.88
GND on BOTTOM: 131.6,202.95 131.22,203.33 131.22,209.42 131.61,209.8 133.51,209.8 133.64,209.68 133.64,206.63 134.53,205.74 136.05,205.74 136.43,205.36 136.43,203.33 136.06,202.95 ; 3 cut-outs
GND on BOTTOM: 28.1,174.12 27.72,174.5 27.72,180.34 27.85,180.47 29.24,180.47 29.37,180.34 29.37,177.42 30.26,176.53 30.64,176.53 31.02,176.15 31.02,174.37 30.77,174.12
GND on BOTTOM: 69.23,67.44 67.83,68.83 67.83,70.63 68.57,71.37 74.33,71.37 75.09,70.61 75.09,68.07 74.46,67.44
GND on BOTTOM: 132.67,173.35 132.46,173.57 119.84,173.57 110.9,182.5 93.89,182.5 93.12,181.74 93.12,180.59 92.24,179.71 92.24,178.94 91.98,178.69 90.71,178.69 90.58,178.82 90.58,180.09 90.84,180.34 90.84,185.8 91.85,186.82 91.85,195.68 90.74,196.8 90.74,197.66 90.76,197.69 90.76,198.96 90.25,199.47 90.25,199.97 89.39,200.84 89.39,201.45 88.86,201.98 88.86,202.64 88.32,203.17 81.65,203.17 81.46,203.37 81.46,204.12 82.37,205.03 89.42,205.03 90.03,205.64 91.07,205.64 91.81,204.89 91.81,203.18 100.42,194.58 129.05,194.58 134.15,189.48 135.67,189.48 135.8,189.36 137.45,189.36 138.21,188.59 138.21,173.61 137.96,173.35 ; 33 cut-outs
GND on BOTTOM: 71.86,54.94 70.86,55.94 70.86,58.33 71.66,59.13 74.4,59.13 74.71,58.83 74.71,55.83 73.82,54.94
GND on BOTTOM: 47.51,160.99 47.35,161.14 47.35,166.01 47.91,166.57 49.79,166.57 49.89,166.47 49.89,161.19 49.69,160.99
GND on BOTTOM: 123.1,129.95 122.94,130.1 122.94,131.01 123.2,131.27 124.14,131.27 124.44,131.57 124.44,132.13 123.96,132.61 118.8,132.61 115.95,135.46 115.95,148.18 117.14,149.38 136.66,149.38 137.47,148.56 138.18,148.56 138.46,148.29 138.46,131.8 138.16,131.5 128.4,131.5 128.35,131.55 126.35,131.55 124.75,129.95 ; 13 cut-outs
GND on BOTTOM: 83.84,170.65 83.84,171.68 84.02,171.86 84.02,178.55 83.93,178.64 83.93,179.17 84.22,179.47 84.22,180.35 84.91,181.04 84.91,182.95 84.73,183.12 84.73,186.5 84.84,186.61 85.5,186.61 85.63,186.49 85.63,180.02 84.95,179.34 84.95,171.89 84.4,171.34 84.4,170.8 84.24,170.65 ; 2 cut-outs
GND on BOTTOM: 64.1,27.19 63.66,27.64 63.66,30.99 63.67,31 63.67,33.64 63.86,33.83 66.3,33.83 67.06,33.07 67.06,27.46 66.8,27.19 ; 7 cut-outs
GND on BOTTOM: 77.63,106.81 77.37,107.06 77.37,107.7 76.99,108.08 76.99,110.51 76.78,110.71 76.02,110.71 75.9,110.84 75.9,111.73 76.7,112.54 76.7,113.14 76.83,113.26 77.85,113.26 78.26,112.85 78.26,111.2 78.28,111.2 78.68,110.8 78.68,108.37 79.03,108.03 79.03,107.01 78.83,106.81 ; 7 cut-outs
GND on BOTTOM: 135.8,97.54 135.29,98.04 135.29,101.22 135.16,101.35 133.64,101.35 133.51,101.47 133.51,104.65 133.57,104.71 143.97,104.71 144.5,104.18 144.5,97.98 144.05,97.54
GND on BOTTOM: 35.29,11.96 35.01,12.24 35.01,14 34.58,14.43 34.58,16.85 34.44,16.99 34.44,17.7 34.52,17.78 35.25,17.78 35.33,17.7 35.33,17.08 35.41,17 36.9,17 36.91,17 37.23,17 37.35,16.89 39.35,16.89 39.48,16.76 39.48,15.9 39.38,15.8 39.38,13.26 39.25,13.13 38.36,13.13 38.16,12.93 36.53,12.93 36.38,12.78 36.38,12.27 36.08,11.96 ; 16 cut-outs
GND on BOTTOM: 79.15,211.84 78.77,212.22 78.77,212.85 78.39,213.23 77.12,213.23 76.87,213.49 76.87,217.3 76.87,217.3 76.87,218.04 76.95,218.12 80.16,218.12 81.44,216.84 81.44,211.84 ; 2 cut-outs
GND on BOTTOM: 59.25,195.68 58.7,196.22 58.7,199.76 58.94,200 64.64,200 65.1,199.54 65.1,196.13 64.64,195.68 ; 5 cut-outs
GND on BOTTOM: 91.32,131.42 84.19,138.55 84.19,139.71 86.42,141.93 86.42,144.58 86.41,144.59 86.41,150.43 86.64,150.66 87.39,150.66 88.03,151.31 89.61,151.31 90.17,151.87 90.7,151.87 91.04,151.53 92.66,151.53 93.03,151.17 93.03,149.06 91.34,147.37 91.34,144.55 92.38,143.51 96.31,143.51 97.39,142.43 97.39,136.03 98.19,135.23 99.31,135.23 100.51,134.04 100.51,131.82 100.11,131.42 ; 3 cut-outs
GND on BOTTOM: 88.6,98.7 88.55,98.75 88.55,100.21 88.68,100.33 89.5,100.33 90.07,100.91 90.07,101.86 89.82,102.11 89.56,102.11 89.44,102.24 89.44,103 89.95,103.51 89.95,104.27 89.69,104.52 89.69,105.41 89.82,105.54 93.2,105.54 93.33,105.41 93.96,105.41 95.28,104.09 95.28,102.87 94.95,102.54 93.73,102.54 93.4,102.21 93.4,101.8 93,101.39 92.28,101.39 91.95,101.06 91.41,101.06 91.18,100.83 91.18,100.18 91.12,100.12 90.14,100.12 89.41,99.39 89.41,98.78 89.33,98.7 ; 10 cut-outs
GND on BOTTOM: 152.6,143.42 152.09,143.94 152.09,149.35 152.26,149.52 155.3,149.52 155.65,149.18 155.65,143.7 155.38,143.42
GND on BOTTOM: 51.78,181.68 50.2,183.26 50.2,187.07 50.45,187.32 53.25,187.32 53.63,186.94 53.63,181.81 53.49,181.68 ; 4 cut-outs
GND on L2VCC: outline of 172 points within 0.76,0.76 184.24,229.24 ; 3 cut-outs
GND on L3: outline of 183 points within 0.76,0.84 184.24,229.24
GND on L3: 79.38,171.55 79.66,171.83 83.55,171.83 83.93,172.21 85,172.21 85.11,172.1 85.11,171.87 84.34,171.09 84.34,168.43 84.97,167.79 84.97,165.2 85.89,164.29 85.89,161.87 85.15,161.14 80.27,161.14 80.12,161.29 79.64,161.29 78.54,162.39 78.54,165.37 78.7,165.53 78.77,165.53 79.38,166.15
GND on L4: outline of 159 points within 0.76,0.79 184.24,229.24
GND on L5GND: outline of 116 points within 0.76,0.76 184.24,229.24 ; 1 cut-out
VCC on TOP: 18.35,208.18 18.04,208.48 18.04,212.42 18.26,212.64 20.11,212.64 20.28,212.48 20.28,208.46 20,208.18
VCC on TOP: 105.7,57.91 105.7,58.67 105.57,58.8 105.57,64.26 105.7,64.39 108.62,64.39 108.87,64.14 108.87,58.55 108.24,57.91 ; 2 cut-outs
VCC on TOP: 130.84,77.09 130.59,77.34 130.59,78.49 130.72,78.61 134.15,78.61 134.53,78.99 134.53,80.01 134.65,80.14 135.92,80.14 136.18,80.39 136.18,82.17 136.56,82.55 137.07,82.55 137.32,82.3 137.32,79.25 135.16,77.09
VCC on BOTTOM: 17.62,189.55 16.67,190.5 16.67,192.64 16.89,192.85 20.61,192.85 20.65,192.9 20.65,196.78 20.21,197.22 18.97,197.22 15.77,200.42 15.77,210.67 16.04,210.94 20.14,210.94 20.24,210.84 20.24,208.45 19.92,208.13 19.92,203.4 21.26,202.07 22.33,202.07 23.42,200.98 23.42,196.28 23.05,195.92 23.05,190.93 21.67,189.55
VCC on BOTTOM: 103.06,59.59 102.27,60.38 102.27,64.49 101.53,65.23 89.59,65.23 83.78,71.04 83.78,71.58 83.28,72.07 64.66,72.07 64.65,72.09 50.58,72.09 49.7,72.97 49.7,74.55 50.06,74.91 51.72,74.91 51.77,74.96 53.07,74.96 53.12,74.91 83.39,74.91 85.9,77.42 90.08,77.42 91.26,76.24 91.26,75.02 93.06,73.22 96.3,73.22 97.74,74.66 97.74,76.02 99.45,77.72 116.39,77.72 118.68,75.44 118.66,75.43 118.66,71.74 117.81,70.89 111.31,70.89 110.24,69.82 110.22,69.82 110.09,69.7 110.09,68.2 108.85,66.96 108.85,60.15 108.29,59.59 ; 1 cut-out
VCC on BOTTOM: 38.03,110.13 37.96,110.21 37.96,111.68 37.45,112.19 37.45,114.45 37.63,114.63 37.63,119.71 37.37,119.96 30.54,119.96 30.13,120.37 30.13,129.18 30.37,129.42 32.33,129.42 32.67,129.08 32.67,127.75 36.9,123.52 40.8,123.52 41.87,122.45 41.87,120.22 41.61,119.96 40.04,119.96 39.45,119.38 39.45,114.96 38.87,114.38 38.87,113.33 39.12,113.08 39.12,110.21 39.05,110.13 ; 2 cut-outs
VCC on L3: 87.41,81.15 87.41,76.45 89.31,74.55 90.71,74.55 91.85,75.69 91.85,77.72 93.7,79.57 101.82,79.57 102.4,80.14 109.67,80.14 111.89,82.36 112.11,82.36 113.43,83.68 113.43,110.85 111.89,112.39 106.27,112.39 102.52,116.14 102.52,119.38 101.76,120.14 101.13,120.14 100.11,119.13 87.77,119.13 87.3,119.59 79.24,119.59 76.11,122.73 76.11,125.35 71.79,129.67 63.29,129.67 62.84,130.11 41.24,130.11 40.29,129.16 40.29,120.68 41.08,119.89 48.04,119.89 54.26,126.11 61.12,126.11 62.52,124.71 65.69,124.71 66.96,125.98 70.39,125.98 71.53,124.84 71.53,122.3 70.39,121.16 70.39,120.02 74.33,116.08 79.5,116.08 79.9,115.67 92.13,115.67 93.51,114.3 96.81,114.3 97.18,113.93 97.18,110.63 100.36,107.44 109.76,107.44 110.65,106.55 110.65,88.77 109.63,87.76 92.8,87.76 87.44,82.4 87.44,81.19
VCC on L4: 30.1,126.87 30.42,126.55 32.01,126.55 32.6,127.14 32.6,130.74 32.59,130.75 32.59,131.74 32.57,131.76 32.57,134.24 29.03,137.78 20.61,137.78 17.57,140.82 17.57,147.99 17.57,147.99 17.57,156.39 16.42,157.54 16.42,177.06 21.83,182.47 21.83,190.28 20.59,191.52 17.69,191.52 17.43,191.26 17.43,189.36 19.14,187.65 19.14,184.37 13.35,178.57 13.35,139.37 18.55,134.16 28.15,134.16 30.1,132.21
VCC3 on TOP: 105.37,75.31 102.56,78.12 102.56,79.01 103.39,79.83 103.39,80.57 103.49,80.67 104.48,80.67 105.32,79.83 108.69,79.83 111.31,82.45 111.31,83.72 111.54,83.95 112.56,83.95 112.68,83.82 112.68,79.15 110.4,76.86 107.55,76.86 106,75.31 ; 7 cut-outs
VCC3 on TOP: 153.87,190.35 152.84,191.38 152.84,198.81 153.15,199.12 154.73,199.12 154.89,198.96 154.89,193.43 155.21,193.1 155.21,190.74 154.82,190.35 ; 2 cut-outs
VCC3 on TOP: 105.95,51.55 105.7,51.81 105.7,56.52 107.73,56.52 108.87,55.37 108.87,52.32 108.11,51.55 ; 1 cut-out
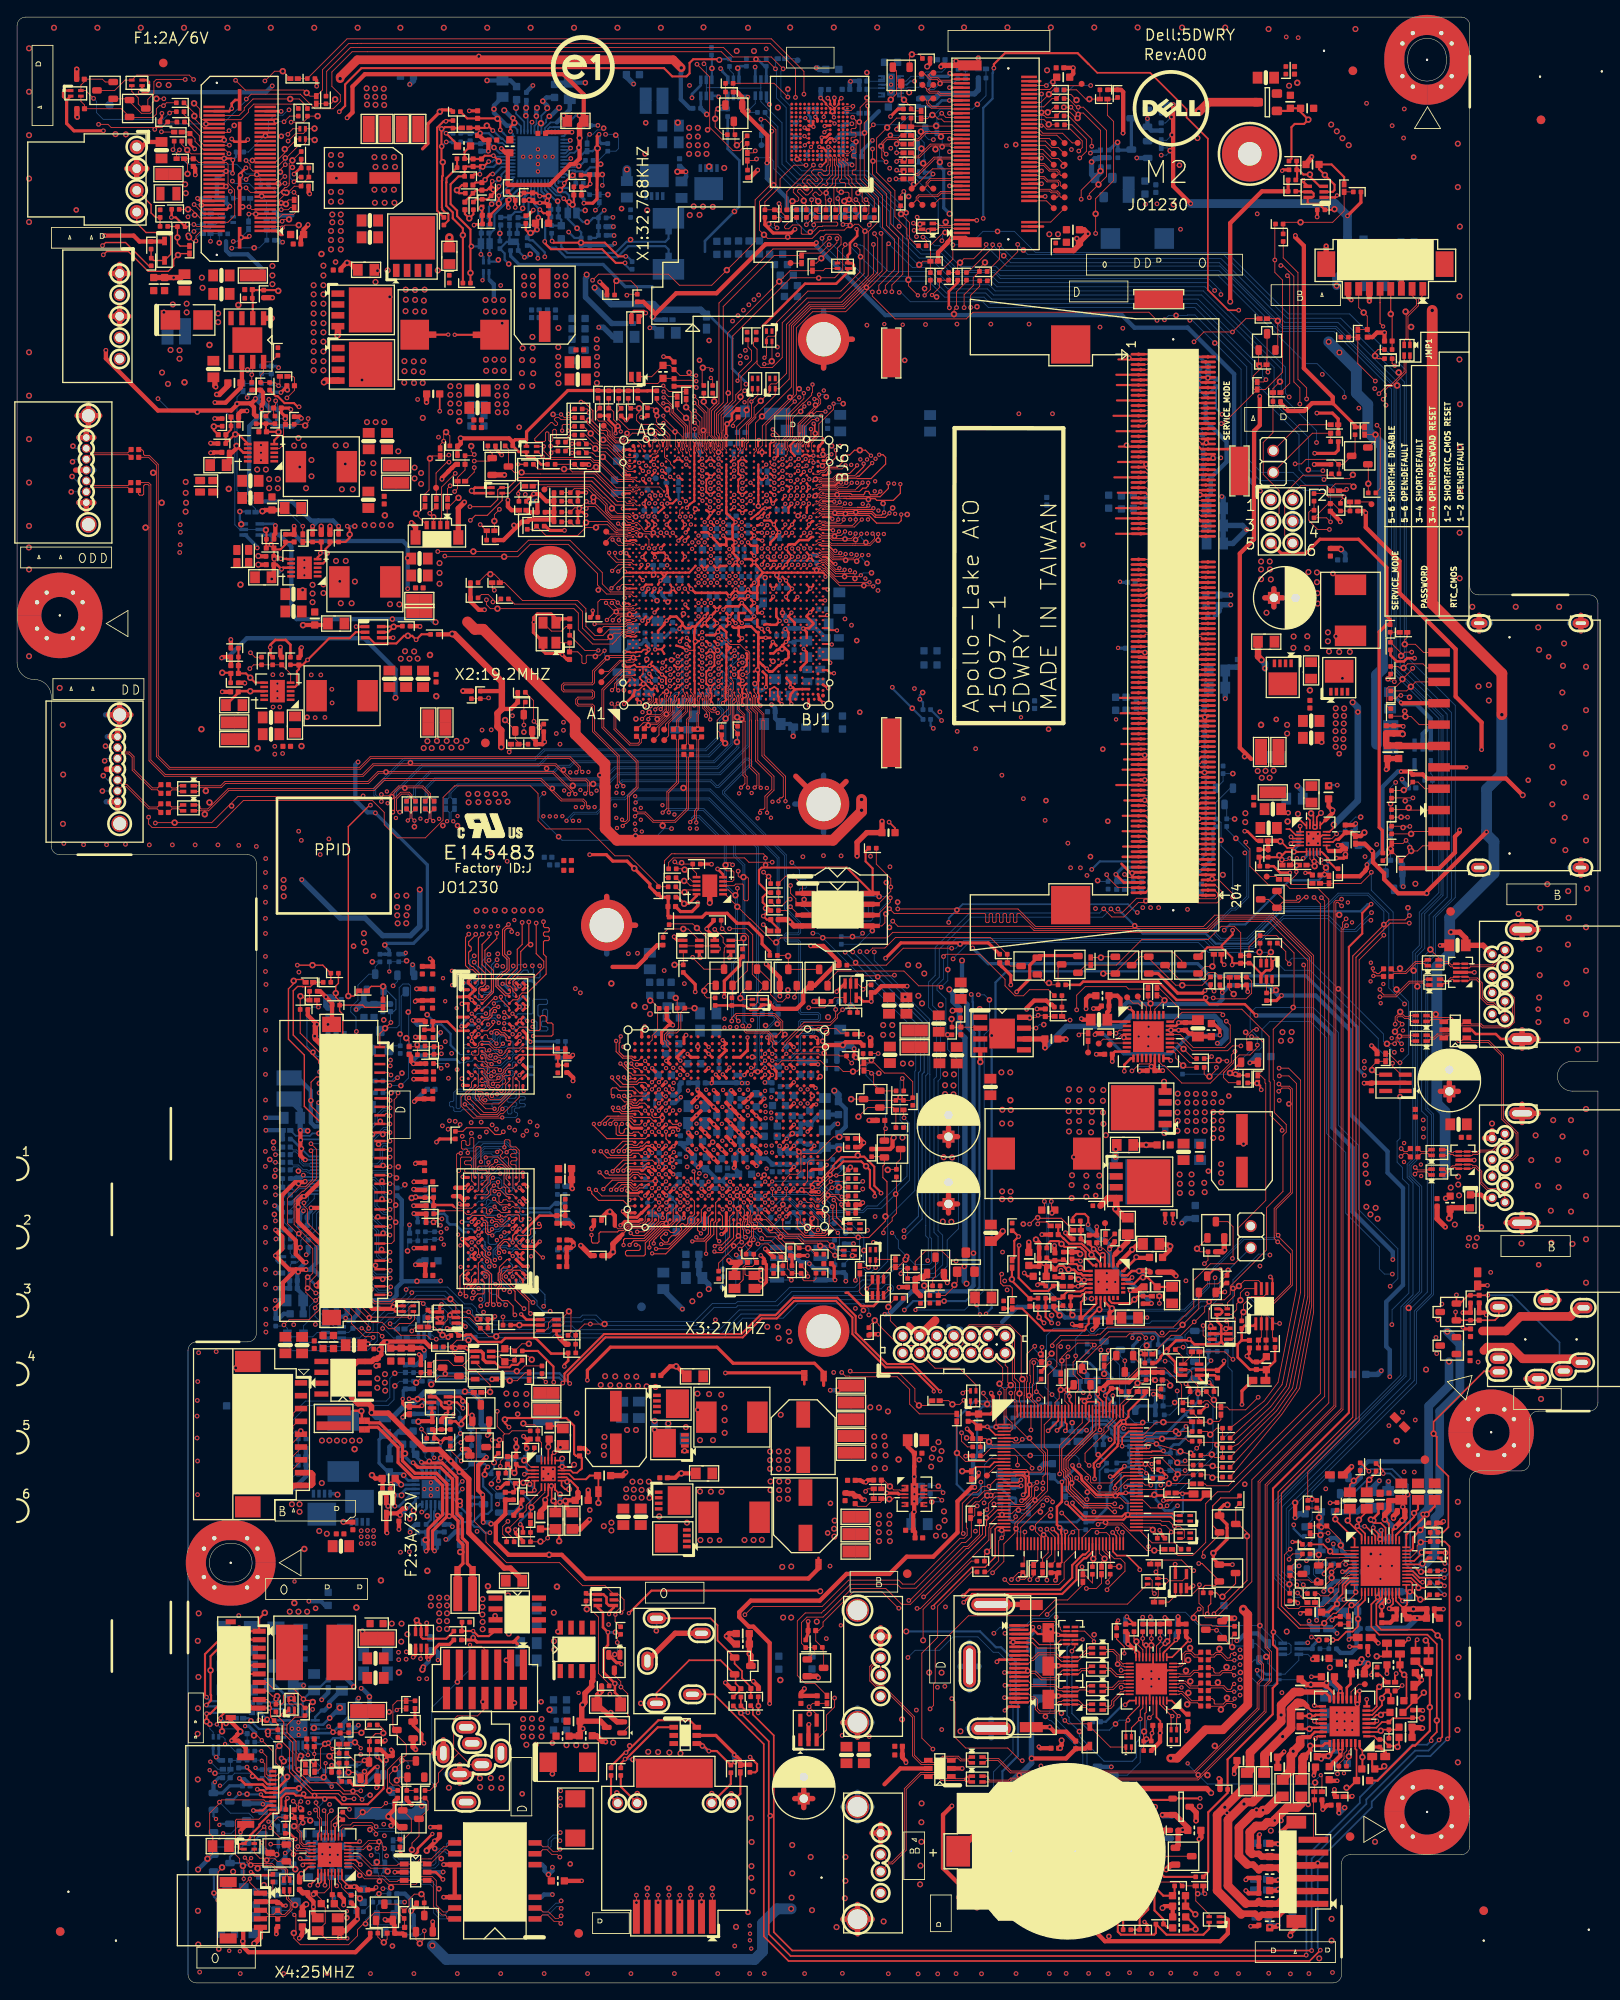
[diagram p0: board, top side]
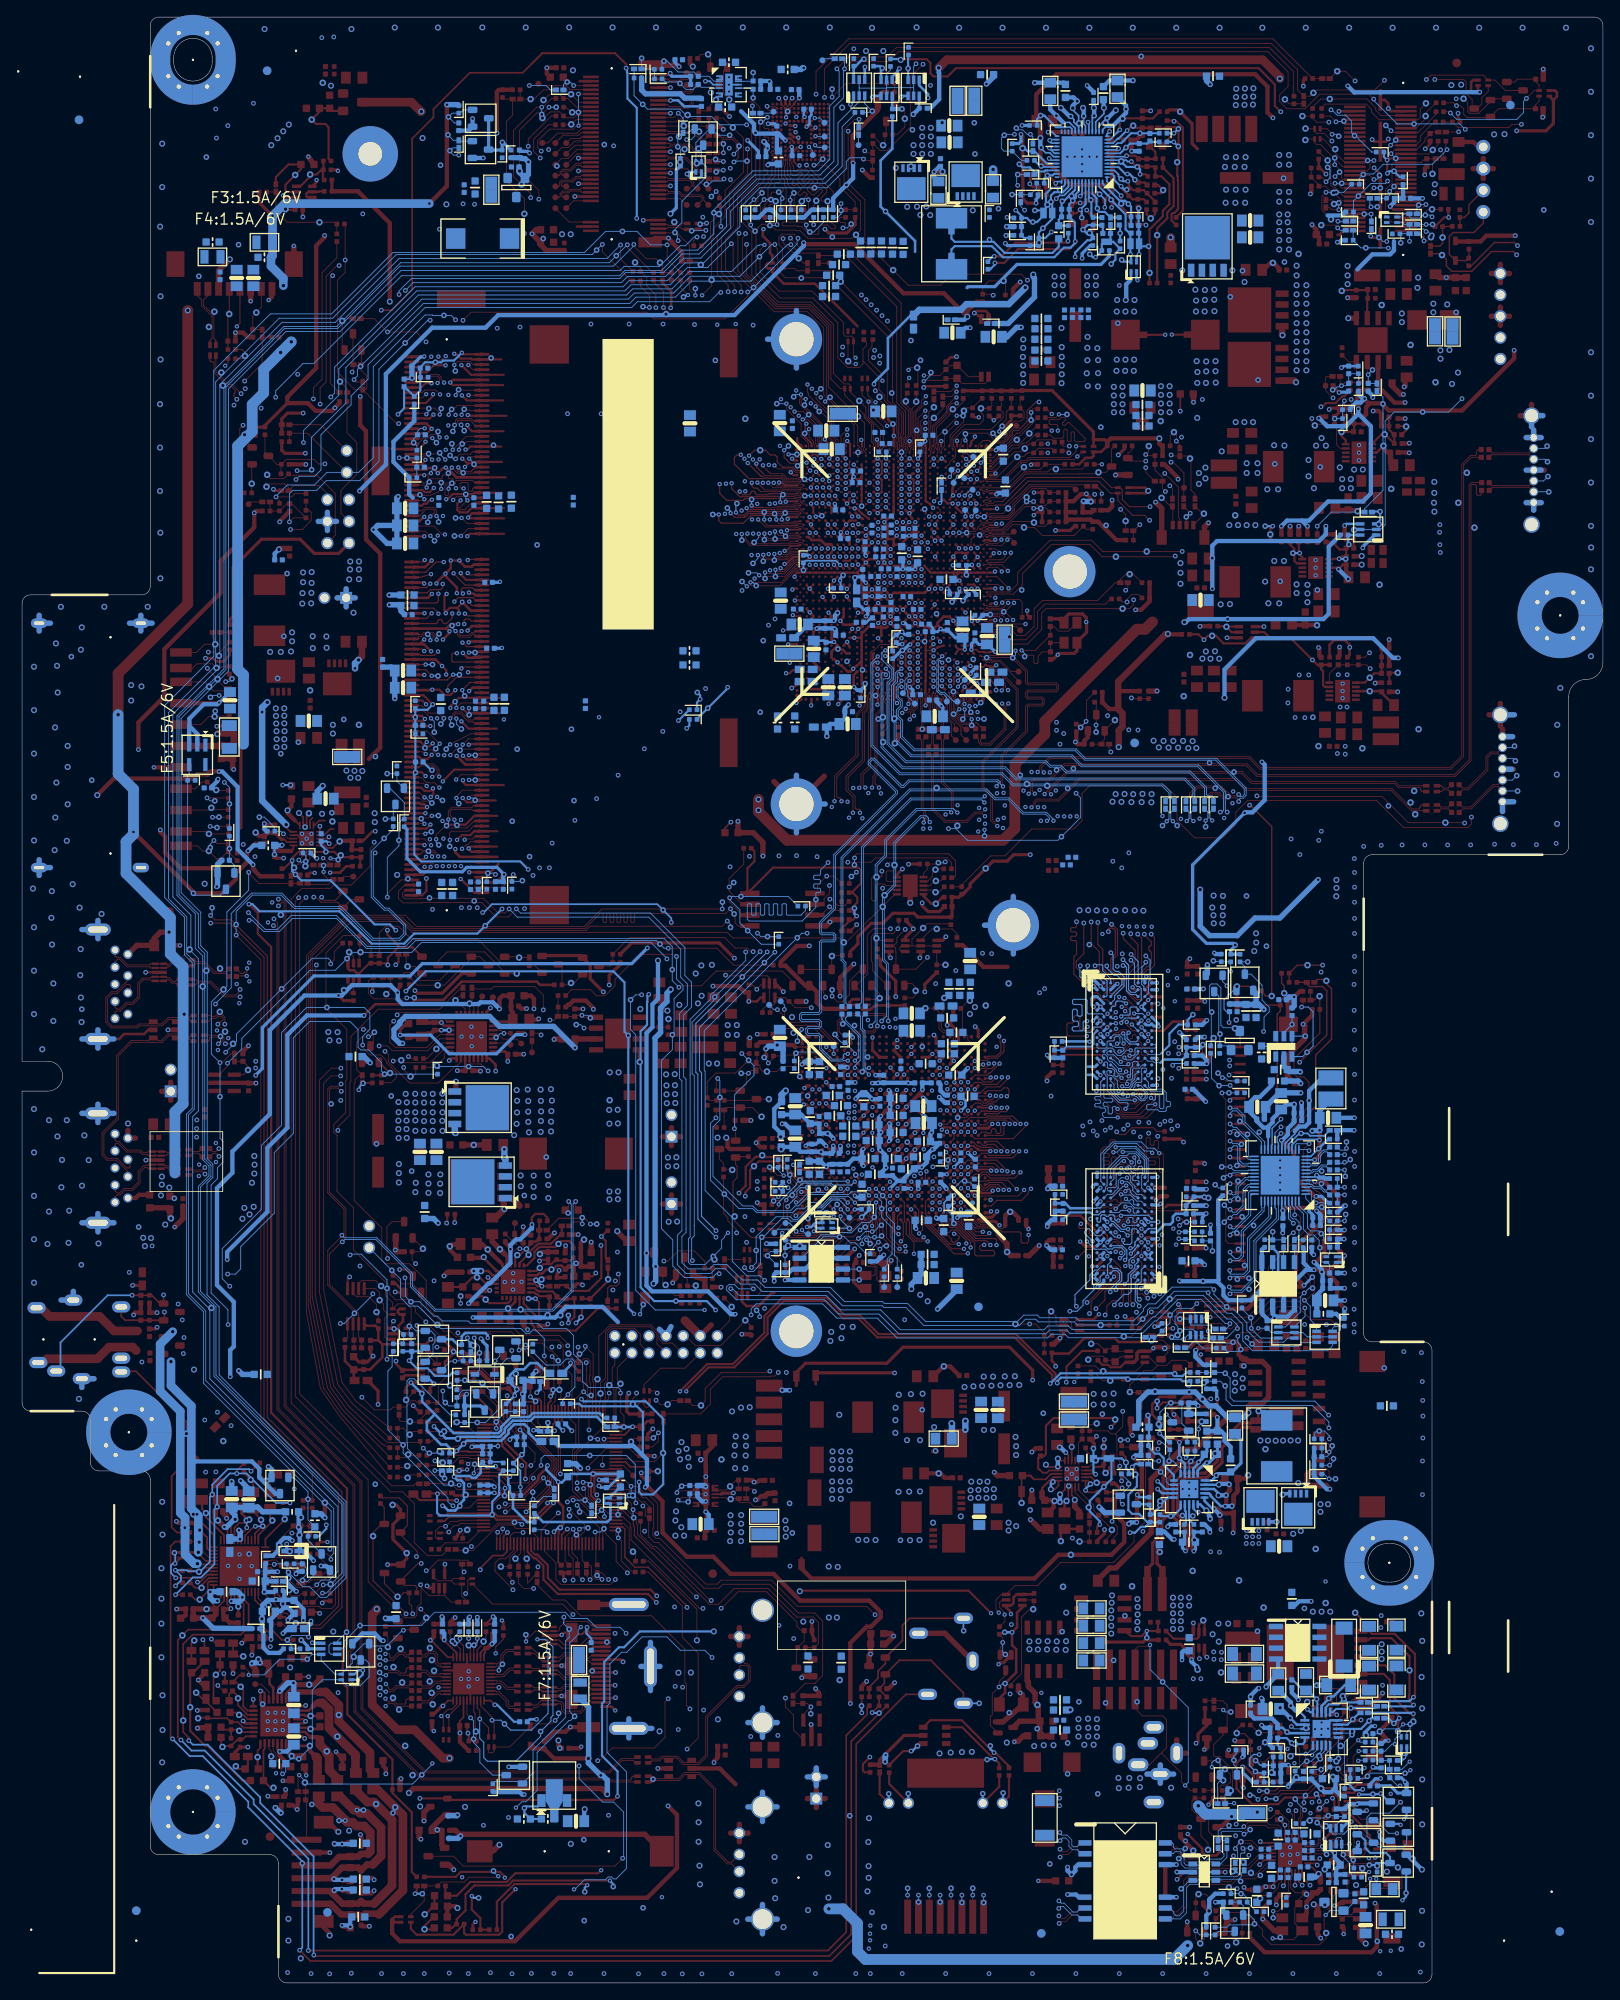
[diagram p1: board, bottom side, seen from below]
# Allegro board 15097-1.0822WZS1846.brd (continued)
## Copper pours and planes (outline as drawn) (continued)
VCC3 on BOTTOM: 118.12,15.79 116.01,17.91 116.01,19.68 116.24,19.91 116.59,19.91 117.88,18.63 117.88,18.05 118.24,17.68 120.07,17.68 120.3,17.91 120.3,22.07 120.45,22.23 121.55,22.23 121.78,22 121.78,17.48 121.79,17.46 121.79,16.46 121.12,15.79
VCC3 on BOTTOM: 163.1,127.76 162.72,128.14 162.72,128.96 163.74,129.97 163.74,139.06 163.36,139.45 163.36,140.21 162.72,140.84 162.72,141.73 161.22,143.23 159.37,143.23 158.5,144.09 158.5,145.44 158.73,145.67 159.34,145.67 159.85,145.16 161.58,145.16 163.36,143.38 163.74,143.38 164.37,142.75 164.37,141.35 165.13,140.59 165.13,140.34 165.39,140.08 165.39,129.16 163.99,127.76 ; 3 cut-outs
VCC3 on BOTTOM: 106.21,51.94 105.96,52.19 105.96,54.9 106.72,55.66 108.55,55.66 108.9,55.32 108.9,52.13 108.7,51.94
VCC3 on L3: 132.62,64.45 111.19,64.45 109.8,63.05 107.81,63.05 106.91,62.15 106.91,54.52 106.15,53.76 106.15,51.97 106.88,51.24 108.82,51.24 110.9,53.31 114.22,53.31 116.53,51 123.14,51 125.39,48.75 127.35,48.75 128.99,47.12 128.99,44.32 128.08,43.41 128.08,42.34 128.67,41.75 134.47,41.75 135.37,40.84 135.85,40.84 136.29,40.41 136.29,31.37 134.76,29.84 133.94,29.84 132.1,28 132.1,20.74 130.55,19.2 122.65,19.2 120.23,16.78 120.23,15.89 120.67,15.44 121.53,15.44 123.54,17.45 131.57,17.45 134.44,20.31 134.44,26.12 135.27,26.94 137.31,26.94 138.23,27.86 138.23,40.93 132.85,46.32 132.01,46.32 128.23,50.11 126.21,50.11 126.07,50.25 126.04,50.25 123.91,52.37 117.49,52.37 115.19,54.67 111.66,54.67 111.42,54.91 111.42,59.7 112.69,60.97 141.03,60.97 147.24,67.18 147.24,67.2 150.81,70.76 150.81,72.47 150.32,72.96 149.36,72.96 144.67,68.26 142.76,68.26 139.29,64.79 132.96,64.79
VCC3_CAM on BOTTOM: 157.14,199.86 156.92,200.08 156.92,204.47 157.1,204.65 161.89,204.65 162.46,204.08 162.46,200.12 162.2,199.86 ; 6 cut-outs
VCC5_PANEL on TOP: 43.33,107.01 43.14,107.2 41.8,107.2 41.72,107.28 41.72,108.7 41.83,108.81 43.69,108.81 43.96,108.53 43.96,107.08 43.9,107.01
VCC5_PANEL on BOTTOM: 41.65,103.89 41.33,104.2 40.63,104.2 39.91,104.93 39.91,106.25 39.73,106.43 38.21,106.43 37.98,106.65 37.98,108.89 38.06,108.97 40.5,108.97 40.7,109.17 40.7,111.86 40.03,112.53 40.03,113.29 40.27,113.53 42.13,113.53 42.5,113.89 43.04,113.89 43.09,113.84 43.09,113.26 43.14,113.21 43.14,112.45 43.06,112.37 41.74,112.37 41.56,112.19 41.56,110.74 42.35,109.96 42.35,108.41 42.48,108.28 43.3,108.28 43.31,108.29 44.21,108.29 44.51,108.58 44.51,108.94 44.61,109.04 45.07,109.04 45.27,108.84 45.27,107.72 44.42,106.87 42.51,106.87 42.21,106.57 42.21,104.64 42.2,104.63 42.2,103.89 42.2,103.89 ; 8 cut-outs
VCC_FAN_PWR on TOP: 16.34,207.14 15.98,207.49 15.98,209.85 15.2,210.64 12.71,210.64 12.53,210.82 12.53,213.51 12.78,213.77 15.27,213.77 16.01,214.5 17.28,214.5 17.56,214.22 17.56,208.38 17.18,208 17.18,207.26 17.05,207.14 ; 1 cut-out
1D05V_FHV0 on BOTTOM: 73.62,150.52 73.52,150.62 73.52,151.41 73.62,151.51 74.51,151.51 74.61,151.41 75.57,151.41 75.7,151.54 75.7,154.31 75.78,154.39 75.78,154.82 76.82,155.85 76.82,155.85 77.53,156.57 77.86,156.57 78.19,156.9 78.52,156.9 78.67,156.74 78.67,156.49 78.37,156.18 78.04,156.18 77.12,155.27 77.12,151.33 76.31,150.52
1D05V_FHV1 on BOTTOM: 71.36,152.98 71.23,153.11 71.23,153.97 71.48,154.23 71.48,154.94 72.22,155.68 74.79,155.68 76.92,157.81 77.93,157.81 78.09,157.66 78.6,157.66 78.7,157.56 78.7,157.2 78.57,157.07 78.19,157.07 77.86,157.4 77.22,157.4 75.14,155.32 72.96,155.32 72.25,154.61 72.25,153.06 72.17,152.98
1D05V_FUSE on BOTTOM: 71.76,151.79 71.69,151.87 71.69,152.65 71.79,152.76 72.14,152.76 72.4,153.01 72.4,154.51 73.11,155.22 75.22,155.22 77.22,157.23 77.73,157.23 77.86,157.1 77.86,156.79 77.73,156.67 77.38,156.67 75.29,154.58 73.39,154.58 73.01,154.2 73.01,152.76 72.85,152.6 72.85,152.04 72.6,151.79
1D05V_IO_3PHASEIO on BOTTOM: 78.15,146.18 78.02,146.32 78.02,147.01 78.26,147.25 78.26,149.5 78.48,149.73 78.48,151.17 78.56,151.24 78.56,155.6 78.81,155.86 78.81,158.24 79.36,158.79 79.36,159.14 79.73,159.52 80.62,159.52 80.85,159.75 80.85,159.96 81.81,160.92 82.03,160.92 82.18,160.76 82.18,160.38 80.82,159.02 80.08,158.28 80.08,146.44 79.82,146.18 ; 3 cut-outs
1D05V_PCH on TOP: 79.28,159.38 79.15,159.51 79.15,161.93 79.28,162.05 82.96,162.05 83.09,161.93 83.09,161.67 82.96,161.54 81.57,161.54 79.41,159.38
1D05V_PCH on BOTTOM: 68.77,157.4 68.26,157.91 68.26,160.53 68.66,160.94 70.16,160.94 70.98,160.94 72.07,162.03 74.07,162.03 74.89,161.21 75.95,161.21 77.25,162.52 80.92,162.52 80.92,162.52 81.24,162.52 81.35,162.42 81.35,161.41 81.09,161.15 80.21,161.15 80.09,161.02 80.09,160.1 79.36,159.37 78.52,159.37 77.87,158.72 77.62,158.72 77.41,158.52 76.31,158.52 75.86,158.07 74.04,158.07 73.37,157.4 ; 6 cut-outs
1D05V_S0 on TOP: 44.86,174.5 44.61,174.75 44.61,178.18 44.86,178.44 47.53,178.44 47.79,178.18 47.79,174.88 47.4,174.5
1D05V_S0 on BOTTOM: 70.58,145.22 67.03,148.78 58.6,148.78 56.42,150.96 56.42,153.54 50.2,159.77 50.2,168.02 45.5,172.72 45.5,177.29 46.01,177.8 47.84,177.8 49.23,176.4 49.23,175.59 52.36,172.47 52.36,171.2 52.74,170.81 54.01,170.81 54.52,170.31 54.52,161.77 60.77,155.52 64.31,155.52 65.63,156.84 70.67,156.84 70.8,156.72 70.8,153.01 71.18,152.63 71.18,151.89 71.61,151.46 72.83,151.46 72.91,151.38 72.91,151.16 72.96,151.1 72.96,147.85 73.74,147.07 77.43,147.07 77.62,146.88 77.62,145.58 77.26,145.22
1D8V_EMMC on BOTTOM: 93.52,213.42 93.17,213.78 93.17,216.6 93.58,217.02 93.58,217.91 93.81,218.14 93.81,218.79 94.02,218.99 94.02,219.68 94.02,219.69 94.67,220.34 94.67,221.72 95.39,222.45 95.39,224.62 95.99,225.22 101.93,225.22 102.01,225.14 102.01,224.33 101.9,224.23 101.74,224.23 101.58,224.07 101.58,222.81 101.56,222.79 100.56,222.79 100.46,222.9 100.46,223.67 100.24,223.89 97.13,223.89 96.81,223.57 96.81,219.91 95.32,218.41 95.32,216.09 95.05,215.82 95.05,215.52 94.33,214.8 94.33,213.5 94.26,213.42 ; 7 cut-outs
1D8V_PCH on TOP: 82.2,169.54 82.08,169.67 82.08,169.8 81.82,170.05 81.82,170.69 81.31,171.2 81.31,171.45 81.44,171.58 83.09,171.58 83.22,171.45 83.22,169.67 83.09,169.54
1D8V_PCH on BOTTOM: 82.52,169.88 82.39,170 82.39,170.59 82.14,170.84 81.58,170.84 81.58,171.55 81.27,171.86 81.27,190.12 80.04,191.35 80.04,193.8 80.3,194.06 81.82,194.06 83.31,192.57 83.32,192.57 83.49,192.4 83.49,191.14 84.06,190.58 84.06,188.04 84.39,187.71 84.39,183.04 84.63,182.8 84.63,181.01 83.86,180.25 83.86,179.3 83.7,179.14 83.7,171.88 83.58,171.77 83.58,170.34 83.52,170.27 83.14,170.27 82.74,169.88 ; 6 cut-outs
1D8V_S0 on TOP: 146.92,220.4 146.49,220.83 146.49,223.62 150.02,223.62 150.43,223.22 150.43,220.65 150.17,220.4 ; 6 cut-outs
1D8V_S5 on TOP: 29.5,198.37 29.12,198.75 28.1,198.75 27.97,198.88 27.97,201.04 28.18,201.25 29.91,201.25 31.55,202.89 31.55,203.97 31.45,204.07 31.02,204.07 30.84,204.26 30.84,204.74 31.15,205.05 32.37,205.05 32.55,204.88 32.55,200.54 30.39,198.37 ; 2 cut-outs
1D8V_S5 on TOP: 85.02,186.82 84.89,186.94 84.89,187.55 85.91,188.57 88.81,188.57 89.03,188.34 89.03,187.48 88.96,187.4 86.01,187.4 85.43,186.82
1D8V_S5 on BOTTOM: 103.02,222.78 102.97,222.83 102.97,223.66 102.53,224.1 102.53,225.2 102.66,225.33 107.94,225.33 107.98,225.29 107.98,224.79 106.99,223.8 104.19,223.8 103.97,223.58 103.97,222.9 103.85,222.78 ; 1 cut-out
1D8V_S5 on BOTTOM: 24.24,203.3 24.16,203.38 24.16,204.37 24.29,204.5 24.29,204.98 24.77,205.46 24.77,207.14 24.57,207.34 24.57,207.95 24.72,208.1 25.28,208.1 26.2,207.19 26.2,205.54 24.73,204.08 24.73,203.34 24.7,203.3 ; 1 cut-out
1D8V_S5 on BOTTOM: 52.17,173.46 51.38,174.25 51.38,175.22 43.47,183.13 35.21,183.13 30.91,187.43 30.91,189.06 30.1,189.87 29.62,189.87 28.23,191.26 28.23,200.57 28.62,200.96 29.17,200.96 31.68,203.47 31.68,207.82 32.72,208.87 32.72,219.38 33.34,220 33.34,223.16 33.63,223.46 38.48,223.46 38.75,223.18 38.75,221.46 38.53,221.23 36.6,221.23 36.26,220.89 36.26,216.61 34.49,214.83 34.49,207.98 33.36,206.85 33.36,202.2 32.93,201.77 32.93,188.09 35.85,185.17 46.77,185.17 47.15,184.78 47.89,184.78 51.6,181.08 52.13,181.08 53.77,179.44 53.77,173.87 53.36,173.46
1D24_35V_S5 on BOTTOM: 94.14,147.7 93.51,148.34 93.51,154.05 93.63,154.18 95.03,154.18 95.54,154.69 95.54,157.61 95.74,157.81 105.95,157.81 106.64,157.12 106.64,152.02 106.51,151.89 104.17,151.89 99.98,147.7 ; 8 cut-outs
1D24V_AUD_ISH_PLL on BOTTOM: 91.75,154.55 91.74,154.55 91.58,154.55 90.95,155.19 90.45,155.19 90.25,155.38 88.25,155.38 86.22,157.41 86.22,157.8 85.52,158.5 84.98,158.5 84.52,158.96 84.52,159.24 84.65,159.37 84.95,159.37 85.18,159.14 85.84,159.14 86.71,158.27 86.71,158.27 87.99,156.99 87.99,156.76 88.34,156.41 90.37,156.41 90.51,156.27 94.75,156.27 94.85,156.18 94.85,154.87 94.53,154.55 ; 2 cut-outs
1D24V_MPHY on BOTTOM: 86.41,151.75 86.05,152.11 86.05,154.48 84.92,155.6 84.54,155.6 83.14,157 83.14,157.95 82.72,158.37 82.45,158.37 82.45,158.39 82.35,158.49 82.35,158.97 82.43,159.05 82.75,159.05 83.01,159.31 83.01,160.83 83.11,160.93 83.52,160.93 83.65,160.79 83.65,158.45 84.27,157.84 84.27,157.42 84.73,156.96 84.87,156.96 87.31,154.52 87.31,153.65 87.47,153.49 88.71,153.49 88.72,153.5 90.63,153.5 90.93,153.2 91.48,153.2 91.72,152.97 92.85,152.97 93.02,152.79 93.02,151.83 92.95,151.75 91.26,151.75 91.02,151.99 89.86,151.99 89.62,151.75
1D24V_S5 on TOP: 48.29,158.55 47.25,159.59 47.25,162.28 47.45,162.48 48.8,162.48 50.22,161.06 52.84,161.06 54.06,159.84 54.06,158.85 53.75,158.55
1D24V_S5 on BOTTOM: 98.71,135.76 98.08,136.4 98.08,142.65 96.71,144.02 92.36,144.02 91.73,144.65 91.73,147.19 91.85,147.32 100.62,147.32 102.14,145.8 102.14,137.03 100.87,135.76 ; 4 cut-outs
1D24V_USB2 on BOTTOM: 91.75,153.16 91.6,153.32 91.19,153.32 90.76,153.75 88.38,153.75 84.48,157.65 84.48,157.81 83.77,158.52 83.77,159.97 84.31,159.97 84.31,158.9 84.84,158.37 85.47,158.37 86,157.84 86,157.34 88.18,155.16 90.22,155.16 90.39,154.99 90.84,154.99 91.55,154.28 92.83,154.28 93.03,154.08 93.03,153.3 92.89,153.16
3D3V_AUX_KBC on TOP: 136.93,50.36 136.85,50.44 136.85,55.02 136.33,55.55 135.39,55.55 135.31,55.63 135.31,56.04 135.39,56.12 137.65,56.12 138.48,55.29 138.48,54.77 138.5,54.75 138.5,50.5 138.36,50.36 ; 1 cut-out
3D3V_EMMC on BOTTOM: 100.69,218.65 100.45,218.89 100.45,221.24 100.62,221.42 101.55,221.42 101.55,221.41 101.6,221.36 101.6,220.54 101.87,220.27 102.31,220.27 102.5,220.08 102.5,219.13 102.02,218.65 ; 2 cut-outs
3D3V_USB on TOP: 81.9,168.7 81.76,168.85 81.76,169.16 80.94,169.98 80.38,169.98 79.94,170.42 79.94,171.4 80.02,171.48 80.23,171.48 80.23,171.45 82.49,169.19 82.49,168.82 82.38,168.7
3D3V_USB on BOTTOM: 81.09,169.78 81.01,169.86 80.33,169.86 79.37,170.83 79.37,171.57 78.48,172.45 78.48,178.67 76.57,180.57 76.57,184.4 75.98,185 75.98,187.2 75.88,187.3 74.96,187.3 71.79,190.47 71.79,194.41 71.86,194.49 73.29,194.49 73.43,194.35 73.43,191.81 76.13,189.1 77.23,189.1 79.24,187.1 79.24,180.32 80.07,179.49 80.07,171.69 80.63,171.13 80.63,170.96 81.05,170.54 81.22,170.54 81.25,170.51 82.11,170.51 82.2,170.41 82.2,169.91 82.07,169.78 ; 3 cut-outs
3D3V_VCCRTC on BOTTOM: 81.08,170.68 80.32,171.44 80.32,179.62 79.57,180.37 79.57,188.09 76.36,191.3 76.36,194.92 76.44,195 78.6,195 78.87,194.72 78.87,191.83 81.1,189.61 81.1,172.05 81.46,171.68 81.46,170.75 81.39,170.68
+3D3V_PWR on TOP: 87.59,48.97 86.72,49.83 85.07,49.83 84.53,50.37 84.53,56.34 84.84,56.64 87.79,56.64 88.93,55.5 94.52,55.5 95.77,56.74 97.09,56.74 97.35,56.48 97.35,55.97 97.7,55.63 97.7,49.71 97.12,49.13 92.6,49.13 92.59,49.12 91.3,49.12 91.14,48.97 ; 1 cut-out
+3D3V_PWR on BOTTOM: 95.18,51.54 94.48,52.24 94.48,53.83 95.97,55.32 97.65,55.32 97.77,55.19 97.77,51.79 97.52,51.54
+3D3V_PWR on L4: 96.22,55.09 85.17,55.09 84.59,54.51 84.59,51.59 85.02,51.16 96.02,51.16 96.53,51.66 96.53,54.79
+V_1P05_VGA on TOP: 101.28,108.97 100.69,109.55 100.69,113.59 101.05,113.94 104.53,113.94 104.71,113.77 104.71,109.14 104.53,108.97
+V_1P05_VGA on TOP: 76.95,104.88 73.21,108.62 72.26,108.62 70.82,110.07 70.82,114.21 71.35,114.75 73.37,114.75 74.46,113.67 74.46,112.4 74.07,112.02 73.94,112.02 73.32,111.39 73.3,111.39 72.8,110.88 72.8,110.68 73.24,110.23 73.28,110.23 73.81,109.7 74.12,109.7 74.57,109.26 74.57,109.03 74.74,108.86 74.94,108.86 75.07,108.98 75.17,108.98 75.34,108.82 75.34,108.2 76.26,107.28 76.98,107.28 77.04,107.22 77.04,106.81 77.35,106.5 81.12,106.5 81.48,106.14 84.61,106.14 84.94,105.81 85.95,105.81 86.16,106.02 86.51,106.02 86.95,105.57 86.95,105.04 86.85,104.94 83.73,104.94 83.68,104.88 82.86,104.88 82.85,104.88 82.39,104.88 82.39,104.88 81.5,104.88 81.5,104.88
+V_1P05_VGA on BOTTOM: 76.74,104.9 75.85,105.79 75.85,106.56 74.96,107.44 74.07,107.44 73.82,107.7 73.82,108.08 73.67,108.23 73.2,108.23 72.97,108.45 72.97,108.94 72.7,109.21 72.7,115.67 73.06,116.03 75.47,116.03 75.5,116 76.82,116 76.94,115.87 76.94,115.24 76.59,114.88 76.59,113.87 76.48,113.76 76.48,112.62 75.51,111.65 75.51,110.59 75.77,110.33 76.4,110.33 76.74,110 76.74,107.83 77.25,107.32 77.25,106.94 77.5,106.68 78.26,106.68 78.65,106.3 78.65,106.05 78.04,105.44 78.04,105.03 77.91,104.9 ; 13 cut-outs
+V_1P05_VGA on BOTTOM: 94.62,110.54 94.3,110.86 94.3,112.99 94.6,113.29 102.1,113.29 102.28,113.11 102.31,113.11 103.04,112.38 103.04,110.86 102.73,110.54
+V_1P05_VGA on L4: 95.94,104.14 95.63,103.83 95.15,103.83 93.93,105.05 91.21,105.05 91.07,104.9 83.21,104.9 83.09,104.78 81.82,104.78 81.69,104.9 76.86,104.9 73.94,107.83 73.94,108.21 73.82,108.33 73.82,113.33 74.15,113.67 77.96,113.67 80.09,115.8 87.66,115.8 89.8,113.67 101.81,113.67 102.85,112.62 102.85,108.81 98.17,104.14 ; 1 cut-out
+V_1P35_VGA on TOP: 82.93,93.12 82.91,93.13 82.9,93.13 82.54,93.49 81.67,93.49 81.52,93.64 79.45,93.64 79.43,93.63 79.21,93.63 79.18,93.66 78.85,93.66 78.68,93.48 78.47,93.48 78.27,93.68 77.94,93.68 77.4,93.14 77.12,93.14 76.79,93.47 76.79,93.48 76.61,93.66 76.61,93.92 76.9,94.21 76.9,94.98 76.59,95.28 76.59,95.59 76.76,95.75 76.76,96.8 76.23,97.33 76.23,97.65 76.77,98.19 76.77,100.64 77.02,100.88 77.02,101.6 76.81,101.81 76.81,104.19 77.02,104.4 77.33,104.4 77.45,104.27 77.45,103.53 77.91,103.08 77.91,101.85 78.36,101.39 78.36,99.94 78.18,99.77 78.18,99.76 77.91,99.49 77.91,97.43 78.48,96.86 78.48,96.13 79.14,95.47 80.08,95.47 80.76,94.79 82.2,94.79 82.6,94.39 83.31,94.39 83.89,94.97 84.2,94.97 84.35,94.81 84.35,94.08 83.75,93.47 83.52,93.47 83.16,93.12
+V_1P35_VGA on TOP: 46.46,144.09 46.11,144.45 46.11,146.69 46.4,146.98 52.65,146.98 52.89,146.74 52.89,144.55 52.43,144.09
+V_1P35_VGA on TOP: outline of 166 points within 43.62,79.14 80.24,139.55 ; 41 cut-outs
+V_1P35_VGA on BOTTOM: 52.23,88.09 51.34,88.98 50.81,88.98 50.5,89.28 50.5,90.12 49,91.62 48.6,91.62 48.37,91.85 48.37,94.49 47.48,95.38 47.48,102.67 48.62,103.81 48.62,106.3 48.72,106.4 50.15,106.4 51.01,107.26 52.26,107.26 52.61,107.62 52.94,107.62 53.07,107.49 53.07,107.14 52.56,106.63 52.56,106.35 53.02,105.89 53.02,105.64 52.87,105.49 51.72,105.49 50.25,104.01 50.25,101.6 49.49,100.84 49.49,99.47 51.26,97.69 51.26,94.56 51.87,93.95 52.76,93.95 52.99,93.73 52.99,91.64 52.64,91.29 52.13,91.29 51.9,91.52 51.57,91.52 51.42,91.36 51.42,90.93 52.59,89.76 52.59,88.16 52.51,88.09 ; 4 cut-outs
+V_1P35_VGA on BOTTOM: outline of 146 points within 48.42,79.32 81.86,139.47 ; 28 cut-outs
+V_1P35_VGA on BOTTOM: 51.62,81.05 50.1,82.58 49.21,82.58 48.57,83.21 48.57,85.85 48.72,86 49.99,86 50.33,86.33 50.33,87.38 50.81,87.86 51.85,87.86 52.1,87.6 52.1,87.35 53.02,86.44 53.02,86.06 52.56,85.6 52.56,84.58 52.74,84.4 52.94,84.4 53.42,84.89 53.6,84.89 53.83,84.66 53.83,84.38 53.42,83.97 53.42,83.67 53.86,83.24 53.86,82.85 53.32,82.32 53.32,81.36 53.02,81.05 ; 2 cut-outs
+V_1P35_VGA on BOTTOM: 46.52,143.92 46.11,144.32 46.11,146.71 46.4,147 52.65,147 52.9,146.75 52.9,144.31 52.51,143.92
+V_1P35_VGA on L3: 77.3,102.44 77.96,102.44 80.17,100.23 80.17,97.18 81.21,96.14 81.21,94.61 80.75,94.16 80.17,94.16 79.97,94.36 79.81,94.36 79.59,94.59 79.59,95.1 79.41,95.28 79.03,95.28 78.85,95.1 78.85,94.56 76.16,91.87 75.65,91.87 75.37,92.15 75.37,94.06 76.08,94.77 76.28,94.77 76.28,98.02 76.46,98.2 77.15,98.2 78.34,99.39 78.34,100.74 77.2,101.88 77.2,102.34
+V_1P35_VGA on L4: 53.54,118.21 53.54,114.66 49.29,110.41 49.29,97.19 50.47,96.01 50.47,95.37 53.49,92.35 53.49,91.14 53.14,90.79 51.49,90.79 51.47,90.76 50.01,90.76 49.14,89.89 49.14,86.96 49.42,86.69 50.3,86.69 51.71,88.09 51.71,89.16 51.94,89.39 53.35,89.39 53.49,89.25 53.49,88.95 52.65,88.11 52.65,83.2 52.14,82.69 48,82.69 47.2,83.49 47.2,116.38 48.34,117.53 48.34,125.68 50.45,127.79 61.3,127.79 61.88,127.2 61.88,125.3 61.27,124.69 52.87,124.69 52.1,123.93 52.1,119.65
+V_1P35_VGA on L4: 47.68,145.67 53.91,145.67 53.91,145.67 54.5,145.67 57.82,142.35 57.82,138.01 57.6,137.79 52.11,137.79 52.09,137.81 48.05,137.81 47,138.86 47,144.99
+V_3P3_VGA on TOP: outline of 92 points within 81.31,78.87 115.73,103.05 ; 5 cut-outs
+V_3P3_VGA on BOTTOM: 99.88,86.21 99.6,86.49 99.6,89.79 99.88,90.07 100.7,90.07 100.95,89.82 100.95,86.35 100.8,86.21
+V_3P3_VGA on BOTTOM: 98.08,90.88 96.48,92.48 96.48,93.8 96.67,94 97.07,94 97.93,94.85 97.93,95.67 97.62,95.99 94.52,95.99 94.42,95.89 94.42,95.5 94.34,95.43 93.81,95.43 93.66,95.58 93.66,96.57 93.91,96.82 95.99,96.82 97.68,98.51 97.68,104.31 96.39,105.6 93.44,105.6 93.25,105.79 89.02,105.79 88.96,105.86 87.38,105.86 87.25,105.99 87.25,106.37 87.43,106.55 88.03,106.55 88.17,106.68 90.32,106.68 90.47,106.83 93.99,106.83 94.45,107.29 97.11,107.29 100.71,103.69 100.71,100.16 101.44,99.44 103.8,99.44 104,99.24 104,94.75 101.94,92.68 100.95,92.68 99.14,90.88 ; 8 cut-outs
+V_VGA_CORE on TOP: 82.65,94.62 82.35,94.92 80.85,94.92 80,95.76 79.03,95.76 78.68,96.1 78.68,96.91 78.13,97.46 78.13,99.44 78.54,99.84 78.54,101.55 78.13,101.95 78.13,104.38 78.41,104.65 88.35,104.65 88.57,104.43 88.57,96.03 88.3,95.76 87.53,95.76 86.94,95.17 83.77,95.17 83.22,94.62
+V_VGA_CORE on TOP: 107.37,88.14 106.51,89 106.51,104.57 107.22,105.28 111.78,105.28 112.63,104.43 116.32,104.43 117.36,103.39 117.36,89.15 116.82,88.62 115.07,88.62 114.59,88.14 ; 2 cut-outs
+V_VGA_CORE on BOTTOM: 81.69,94.49 81.31,94.87 81.31,95.63 80.8,96.14 80.17,96.14 79.91,96.4 79.91,97.11 79.79,97.23 79.33,97.23 79.07,97.49 79.07,97.84 79.4,98.17 79.4,103 78.64,103.76 78.13,103.76 78.01,103.89 78.01,104.65 78.13,104.78 85.41,104.78 86.05,105.42 89.17,105.42 89.44,105.16 89.44,104.52 89.69,104.27 89.69,103.63 89.06,103 89.06,102.11 89.31,101.86 89.56,101.86 89.69,101.73 89.69,100.99 89.54,100.84 88.22,100.84 88.04,100.66 88.04,98.81 88.76,98.09 88.76,97 88.6,96.85 87.41,96.85 87.16,97.1 87.16,97.66 86.78,98.03 86.5,98.03 86.14,97.67 86.14,95.48 85.96,95.3 85.04,95.3 84.81,95.52 84.81,96.75 84.64,96.93 83.72,96.93 83.65,96.85 83.65,95.28 83.41,95.04 82.8,95.04 82.55,94.79 82.55,94.59 82.46,94.49 ; 33 cut-outs
+V_VGA_CORE on L3: 93.27,105.66 78.82,105.66 78.19,105.04 78.19,102.44 80.2,100.44 80.2,100.43 80.32,100.3 80.32,97.31 81.75,95.88 84.38,95.88 85.28,94.98 88.25,94.98 95.12,88.1 109.48,88.1 110.37,88.99 110.37,106.4 110.02,106.76 100.6,106.76 99.55,105.71 93.32,105.71
+V_VGA_CORE on L4: 78.31,104.75 93.8,104.75 95,103.55 98.66,103.55 100.85,105.74 115.81,105.74 117.46,104.09 117.46,92.23 116.39,91.16 113.85,91.16 111.41,88.72 107.27,88.72 102.52,93.47 88.7,93.47 88.3,93.88 88.3,93.89 87.31,94.88 85.08,94.88 84.27,95.69 79.11,95.69 78.82,95.98 78.82,100.55 77.93,101.44 77.93,104.36
AD+_TO_SYS on TOP: 57.09,40.77 57.09,41.74 57.01,41.83 55,41.83 54.87,41.71 54.87,41.03 54.74,40.91 53.64,40.91 52.61,41.94 52.61,47.24 52.62,47.26 52.62,47.64 52.88,47.89 57.5,47.89 57.82,47.57 57.82,41.02 57.56,40.77 ; 1 cut-out
AD+_TO_SYS on BOTTOM: 54.52,37.03 54.01,37.54 54.01,44.91 54.01,44.91 54.01,44.96 54.52,45.47 58.71,45.47 59.34,44.83 59.34,37.13 59.24,37.03
AD_JK on TOP: 50.13,19.52 49.79,19.86 49.79,24.66 50.99,25.86 52.94,25.86 53.5,26.42 53.5,29.36 55.63,31.5 55.63,37.95 55.66,37.97 55.66,38.86 55.79,38.99 59.62,38.99 60.36,38.25 65.64,38.25 66.58,37.31 66.58,33.78 66.19,33.39 66.09,33.39 65.31,32.61 65.31,30.12 65.08,29.9 64.7,29.9 64.02,29.21 64.02,28.57 63.83,28.38 63.6,28.38 63.28,28.07 63.28,23.55 62.57,22.83 62.57,21.29 60.8,19.52 ; 4 cut-outs
AD_JK on BOTTOM: 51.06,21.34 49.87,22.53 49.87,31.04 52.36,33.53 63.23,33.53 63.28,33.48 63.28,23.06 61.55,21.34 ; 6 cut-outs
AD_JK on L3: 62.14,31.11 54.52,31.11 53.94,30.54 53.72,30.54 49.72,26.54 49.72,21.69 50.58,20.83 56.68,20.83 62.52,26.67 62.52,30.73
AD_JK on L4: 57.61,26.14 50.4,26.14 49.59,25.32 49.59,21.89 50.1,21.39 57.26,21.39 57.89,22.02 57.89,25.86
AMP_GND on L3: 157.96,37.08 159.16,37.08 161.2,35.05 162.47,35.05 162.59,34.92 162.59,34.04 162.34,33.78 161.7,33.78 161.58,33.91 160.69,33.91 157.64,30.86 157.64,28.7 156.88,27.94 156.88,23.24 155.86,22.23 155.86,21.69 156.34,21.21 156.9,21.21 163.1,27.41 163.96,27.41 164.94,28.38 164.94,35.75 162.09,38.61 157.89,38.61 157.75,38.47 157.75,37.29
BT+ on TOP: 34.4,66.15 33.72,66.83 32.19,66.83 31.86,67.17 31.86,70.11 31.64,70.33 30.67,70.33 30.19,70.81 30.19,74.41 30.29,74.51 34.83,74.51 34.85,74.53 35.24,74.53 35.47,74.75 37.29,74.75 37.96,75.41 38.59,75.41 38.74,75.26 38.74,73.61 38.72,73.61 38.47,73.36 38.47,68.96 38.48,68.95 38.48,68.29 39.48,67.28 39.48,66.43 39.2,66.15 ; 4 cut-outs
BT+_R on TOP: 35.22,62.02 34.92,62.32 34.92,65.59 35.04,65.71 39.4,65.71 39.52,65.6 39.52,65.28 40.42,65.28 40.67,65.02 40.67,62.69 40.01,62.02
BT+_R on BOTTOM: 35.21,62.99 34.96,63.25 34.96,66.8 35.34,67.18 39.91,67.18 40.42,66.67 40.42,63.25 40.17,62.99
CAGND on TOP: 33.19,28.23 31.94,29.49 31.94,30 32.67,30.73 34.07,30.73 35.34,32 35.34,33.35 35.47,33.48 40.14,33.48 40.52,33.1 40.52,30.33 40.06,29.87 37.68,29.87 37.17,30.38 35.97,30.38 35.67,30.07 35.67,28.78 35.12,28.23 ; 6 cut-outs
DC_19V on TOP: 60.87,38.61 60.1,39.37 58.58,39.37 58.33,39.62 58.33,46.61 58.35,46.63 58.35,47.41 58.69,47.75 63.21,47.75 64.63,46.33 64.63,45.71 67.72,42.62 67.72,39.24 67.09,38.61
DC_19V on BOTTOM: 59.98,37.01 59.85,37.13 59.85,44.58 60.1,44.83 63.76,44.83 67.55,41.05 67.55,38.46 66.1,37.01
DCBATOUT on TOP: 40.47,217.17 40.19,217.45 40.19,221.49 40.91,222.21 45.26,222.21 45.93,221.54 47.12,221.54 47.66,221.01 47.66,217.17
DCBATOUT on TOP: 42.45,39.5 42.32,39.62 42.32,43.54 40.95,44.91 35.53,44.91 31.67,48.77 31.67,55.51 31.68,55.52 31.68,56.01 32.06,56.39 36.48,56.39 37.56,55.31 37.56,50.38 38.03,49.91 47.63,49.91 49.53,48.01 51.8,48.01 52.1,47.71 52.1,42.32 51.7,41.91 50.74,41.91 50.64,41.81 50.64,41.27 50.39,41.02 49.21,41.02 49.06,41.17 49.06,42.01 48.37,42.7 46.74,42.7 46.03,41.99 46.03,40.16 45.37,39.5 ; 2 cut-outs
DCBATOUT on TOP: 57.18,66.55 56.8,66.93 56.8,69.27 57.28,69.75 58.53,69.75 59.57,70.79 60.36,70.79 61.53,69.62 61.53,66.57 61.5,66.55
DCBATOUT on TOP: 39.89,68.43 39.68,68.63 39.68,71.58 39.73,71.63 39.73,71.78 39.68,71.83 41.54,71.83 41.99,72.29 42.58,72.29 43.16,72.87 43.16,73.13 43.26,73.23 46.59,73.23 46.59,70.97 44.05,68.43 ; 4 cut-outs
DCBATOUT on TOP: 148.88,37.25 147.83,38.3 147.83,41.5 148.08,41.75 149.18,41.75 149.58,41.36 149.58,39.36 150.05,38.89 152.36,38.89 152.69,38.56 152.69,37.42 152.52,37.25 ; 2 cut-outs
DCBATOUT on TOP: 143.72,140.59 143.54,140.77 143.54,143.38 143.8,143.64 147.86,143.64 148.12,143.38 148.12,140.92 147.78,140.59
DCBATOUT on TOP: 130.11,90.98 129.83,91.26 129.83,96.6 130.13,96.9 144.53,96.9 145.32,96.11 145.32,91.41 144.89,90.98 ; 2 cut-outs
DCBATOUT on BOTTOM: outline of 86 points within 25.55,37.82 156.76,111.62 ; 23 cut-outs
DCBATOUT on BOTTOM: 58.8,65.18 58.19,65.79 57.06,65.79 56.88,65.96 56.88,69.22 57.26,69.6 61.32,69.6 61.58,69.34 61.58,65.28 61.48,65.18
DCBATOUT on BOTTOM: 42.77,123.3 40.44,125.63 37.57,125.63 33.31,129.9 32.16,129.9 27.8,134.26 18.24,134.26 13.35,139.16 13.35,141.42 12.86,141.91 12.86,150.04 11.16,151.74 11.16,182.18 8.57,184.77 7.02,184.77 2.53,189.26 2.53,225.41 5.03,227.92 75.02,227.92 76.59,226.35 76.59,221.18 76.33,220.93 72.96,220.93 72.78,221.11 72.78,222.5 72.73,222.55 72.7,222.55 72.32,222.94 72.32,223.8 72.07,224.05 45.17,224.05 44.86,223.75 44.86,220.42 43.77,219.33 39.89,219.33 39.45,219.76 39.45,223.09 38.49,224.05 10.65,224.05 8.48,221.88 8.48,209.78 8.5,209.76 8.5,191.53 11.02,189.01 12.97,189.01 13,189.04 14.39,187.65 14.39,186.28 18.26,182.41 18.26,154.53 19.55,153.23 19.55,142.59 21.16,140.99 33.63,140.99 33.65,140.97 35.21,140.97 45.99,130.19 45.99,123.98 45.32,123.3 ; 4 cut-outs
DCBATOUT on L3: 146.51,109.52 149.34,109.52 149.65,109.84 149.65,117.67 148.72,118.61 148.16,119.17 148.16,119.18 148.14,119.2 148.14,142.7 147.58,143.26 145.11,143.26 144.66,142.81 144.66,139.19 145.27,138.58 145.27,117.42 146.24,116.46 146.24,109.8
DCBATOUT on L3: 59.93,67.49 59.75,67.31 54.64,67.31 52.87,69.09 44.48,69.09 43.95,68.55 42.43,68.55 41.56,69.42 41.56,71.77 41.82,72.02 59.53,72.02 59.93,71.63
DCBATOUT on L4: 54.77,67.18 52.87,69.09 44.51,69.09 44,68.58 35.35,68.58 33.9,67.12 33.9,58.96 37.4,55.46 37.4,52.28 37.01,51.88 35.95,51.88 30.65,57.18 30.65,68.03 37.23,74.62 43.43,74.62 43.98,75.17 43.98,76.16 44.23,76.41 44.23,77.27 44.06,77.43 42.56,77.43 40.43,79.56 40.43,118.31 40.44,118.32 40.44,118.82 40.45,118.83 40.45,119.49 41.68,120.73 41.68,125.08 41.69,125.09 41.69,126.03 43.23,127.57 46.2,127.57 47.85,125.92 47.85,119.64 47.83,119.62 47.83,118.73 47.09,117.98 47.09,116.83 46.71,116.45 46.71,83.44 51.98,78.17 51.98,78.11 53.51,78.11 59.91,71.7 59.91,67.5 59.6,67.18 ; 1 cut-out
DCBATOUT_RT6575 on TOP: 69.03,60.71 65.57,64.17 65.57,65.79 64.8,66.55 62.26,66.55 62.14,66.67 62.14,69.34 62.39,69.6 67.09,69.6 68.36,68.33 68.36,66.03 69.32,65.07 74.07,65.07 74.3,64.84 77.13,64.84 77.17,64.8 77.17,61.34 76.54,60.71
DCBATOUT_RT6575 on TOP: 68.92,50.27 68.03,51.16 68.03,53.47 68.71,54.15 73.67,54.15 74.1,53.72 77.27,53.72 77.35,53.64 77.35,50.34 77.27,50.27
DCBATOUT_RT6575 on BOTTOM: 68.94,50.27 65.5,53.71 65.5,59.2 66.28,59.97 66.28,60.93 62.28,64.94 62.28,68.33 62.65,68.7 66.46,68.7 68.45,66.71 73.45,66.71 73.52,66.65 73.52,61.01 73.44,60.93 70.72,60.93 70.26,60.48 70.26,55.37 71.46,54.18 73.77,54.18 74.12,53.82 77.25,53.82 77.35,53.72 77.35,50.34 77.27,50.27
DDR_VDDQ on TOP: 144.29,159.65 144.05,159.89 144.05,166.62 144.43,167 146.85,167 147.35,166.5 151.16,166.5 151.67,167 152.89,167 153.12,167.23 154.08,167.23 154.31,167 157.39,167 158.02,166.37 158.02,161.75 157.67,161.39 157.67,161.19 156.75,160.27 147.99,160.27 147.37,159.65 ; 2 cut-outs
DDR_VDDQ on TOP: 114.17,108.55 113.85,108.86 113.85,114.57 112.39,116.03 110.76,116.03 110.75,116.04 109.94,116.04 108.97,117.02 105.68,117.02 103.72,118.97 103.72,120.07 104.17,120.51 106.81,120.51 108.12,119.2 113.32,119.2 115.22,117.3 115.22,116.58 116.77,115.03 116.77,109.86 117.08,109.55 118.62,109.55 118.86,109.31 118.86,108.82 118.59,108.55
DDR_VDDQ on BOTTOM: outline of 108 points within 86.84,117.66 154.85,182.17 ; 51 cut-outs
DDR_VDDQ on L3: 88.91,173.43 88.35,173.43 87.36,172.44 87.36,172.19 86.88,171.7 86.88,170.71 86.65,170.48 86.65,168.63 86.9,168.38 87.36,168.38 87.56,168.58 87.56,170.59 88.2,171.22 88.73,171.22 89.03,171.53 89.03,173.3
FB_PLLAVDD on BOTTOM: 72.17,98.93 71.79,99.31 71.79,100.71 71.66,100.84 69.25,100.84 68.99,101.09 68.99,104.39 68.23,105.16 68.23,117.5 69.98,119.25 74.66,119.25 74.76,119.15 74.76,117.96 74.48,117.68 74.48,116.69 74.38,116.59 70.65,116.59 69.76,115.7 69.76,107.95 70.52,107.19 72.8,107.19 73.19,106.81 73.19,104.39 73.31,104.27 73.95,104.27 74.2,104.01 74.2,103.12 73.31,102.23 73.31,101.98 73.44,101.85 76.36,101.85 77.38,100.84 77.38,100.33 78.01,99.69 78.01,98.93 ; 2 cut-outs
FB_PLLAVDD on L4: 77.09,98.52 77.09,95.61 76.32,94.85 76.32,94.09 76.45,93.96 77.59,93.96 77.6,93.97 78,93.97 78.48,94.45 78.48,99.77 78.18,100.07 77.34,100.07 77.17,99.89 77.17,98.6 77.14,98.57
GPU_1D05V on TOP: 105.82,108.84 105.44,109.22 105.44,111.89 105.7,112.14 108.11,112.14 109,111.25 111.41,111.25 111.92,110.74 113.44,110.74 113.44,108.97 113.32,108.84 ; 4 cut-outs
ISW_1 on BOTTOM: 39.96,35 39.78,35.18 39.78,38.23 39.25,38.76 37.09,38.76 36.71,38.38 36.71,36.7 35.47,35.46 33.94,35.46 33.82,35.59 33.82,36.47 34.22,36.88 34.96,36.88 35.62,37.54 35.62,42.85 36.28,43.51 41.41,43.51 41.94,42.98 41.94,35.13 41.82,35
LX on TOP: 30.03,35.18 29.75,35.46 29.75,43.56 30.01,43.81 30.03,43.81 31.02,44.81 34.17,44.81 34.81,44.17 34.81,43.16 33.78,42.13 33.78,35.63 33.33,35.18
LX on BOTTOM: 31.96,37.29 31.86,37.39 31.86,38.48 31.35,38.99 29.37,38.99 28.99,39.37 28.99,43.43 29.37,43.81 29.37,43.81 29.82,44.26 35.09,44.26 35.3,44.05 35.3,43.47 34.45,42.62 34.45,38.23 34.44,38.21 34.44,37.73 33.99,37.29
MCT_R on TOP: 59.98,9.65 59.85,9.78 59.85,14.1 59.98,14.22 63.93,14.22 64.15,14.44 64.15,17.89 64.29,18.03 66.34,18.03 66.45,17.92 66.45,14.61 64.55,12.7 63.41,12.7 63.28,12.57 63.28,10.41 62.52,9.65 ; 2 cut-outs
MCT_R_1 on BOTTOM: 64.3,11.68 64.17,11.81 64.17,17.91 64.3,18.03 66.33,18.03 66.45,17.91 66.45,11.94 66.2,11.68
MEM_VTT on TOP: 141.04,129.25 140.56,129.73 140.56,130.32 140.57,130.32 141.26,131.01 141.26,139.2 142.07,140.01 146.31,140.01 146.6,139.71 146.6,138.62 146.41,138.43 143.29,138.43 142.91,138.05 142.91,130.42 141.74,129.25 ; 2 cut-outs
MEM_VTT on BOTTOM: 133.97,128.27 133.71,128.52 131.33,128.52 131.25,128.6 131.25,129.36 131.33,129.44 139.1,129.44 139.73,130.07 141.38,130.07 141.69,129.77 141.69,129.46 141.1,128.88 140.95,128.88 140.34,128.27 ; 8 cut-outs
PEX_PLLVDD_GPU on BOTTOM: 81.36,105.76 81.32,105.79 79.53,105.79 79.2,106.12 79.2,108.27 78.84,108.64 78.84,110.99 78.38,111.45 78.38,113.16 78.01,113.54 77.5,113.54 77.12,113.92 77.12,114.81 77.44,115.13 80.26,115.13 80.78,114.6 80.78,109.88 80.58,109.68 80.58,106.84 80.73,106.68 81.54,106.68 81.69,106.83 81.69,107.11 81.87,107.29 82.43,107.29 82.76,106.96 82.76,106.68 83.01,106.43 83.01,106.05 82.73,105.76 ; 3 cut-outs
PWR_1D05V_A on TOP: 37.5,173.86 36.61,174.75 36.61,180.72 36.86,180.97 39.78,180.97 40.55,180.21 44.74,180.21 45.12,179.83 45.12,178.82 44.99,178.69 44.23,178.69 44.1,178.56 44.1,174.12 43.85,173.86 ; 2 cut-outs
PWR_1D05V_A on BOTTOM: 37.5,173.86 36.61,174.75 36.61,180.72 36.86,180.97 39.78,180.97 40.55,180.21 42.58,180.21 42.71,180.09 42.71,174.12 42.45,173.86
PWR_1D05V_LX on TOP: 32.67,171.86 32.65,171.88 32.65,173.58 32.49,173.74 31.53,173.74 31.28,173.99 31.28,176.4 30.89,176.78 30.39,176.78 29.62,177.55 29.62,179.2 31.02,179.2 31.53,179.71 31.53,180.85 31.78,181.1 34.58,181.1 34.83,180.85 34.83,173.86 34.7,173.74 34.04,173.74 33.84,173.53 33.84,171.88 33.82,171.86
PWR_1D05V_LX on BOTTOM: 31.53,173.74 31.28,173.99 31.28,176.4 30.89,176.78 30.39,176.78 29.62,177.55 29.62,179.2 31.02,179.2 31.53,179.71 31.53,180.85 31.78,181.1 34.58,181.1 34.83,180.85 34.83,173.86 34.7,173.74
PWR_1D05V_PVIN on TOP: 25.79,172.97 25.09,173.67 22.84,173.67 22.51,174 22.51,176.15 21.88,176.78 21.88,178.31 22,178.44 23.27,178.44 23.4,178.31 23.4,176.78 23.78,176.4 25.31,176.4 25.43,176.53 25.43,178.31 25.81,178.69 27.34,178.69 27.36,178.66 27.36,173.25 27.08,172.97
PWR_1D24V_A on TOP: 41.82,159.64 41.18,160.27 41.18,166.75 41.94,167.51 46.64,167.51 46.9,167.26 46.9,162.97 46.69,162.76 46.69,159.72 46.62,159.64 ; 2 cut-outs
PWR_1D24V_A on BOTTOM: 43.34,160.81 43.06,161.09 43.06,163.86 43.31,164.11 46.16,164.11 46.74,163.53 46.74,161.01 46.54,160.81
PWR_1D24V_LX on TOP: 37.75,158.24 37.63,158.37 37.63,160.91 36.86,161.67 35.85,161.67 35.34,162.18 35.34,163.7 34.7,164.34 34.7,165.74 35.97,165.74 36.86,166.62 39.4,166.62 39.78,166.24 39.78,161.23 38.97,160.41 38.97,158.37 38.84,158.24
PWR_1D24V_LX on BOTTOM: 37.75,160.78 36.86,161.67 35.85,161.67 35.34,162.18 35.34,163.7 34.7,164.34 34.7,165.61 34.83,165.74 35.97,165.74 36.86,166.62 39.28,166.62 39.78,166.12 39.78,160.91 39.66,160.78
PWR_1D24V_PVIN on TOP: 30.89,159.51 30.64,159.77 30.64,160.15 30.39,160.4 27.72,160.4 25.43,162.69 25.43,166.24 25.81,166.62 27.72,166.62 27.72,165.61 27.97,165.35 28.35,165.35 28.48,165.23 28.48,163.7 28.86,163.32 30.51,163.32 30.77,163.58 30.77,164.72 31.28,165.23 32.42,165.23 32.42,159.77 32.16,159.51
PWR_1D35V_A on TOP: 39.66,147.75 39.03,148.38 39.03,149.98 39.02,149.99 39.02,151.82 39.56,152.35 51.11,152.35 51.26,152.2 51.26,148.08 50.93,147.75 50.12,147.75 50.12,147.75 ; 2 cut-outs
PWR_1D35V_LX on TOP: 31.71,147.55 31.55,147.7 31.55,151.28 33.21,151.28 33.46,151.54 33.46,153.24 33.61,153.39 36.84,153.39 37.22,153.01 37.22,147.78 36.99,147.55
PWR_1D35V_LX on BOTTOM: 33.61,147.57 33.46,147.73 33.46,153.24 33.64,153.42 36.79,153.42 37.22,152.98 37.22,147.75 37.04,147.57
PWR_1D35V_PVIN on TOP: 26.02,143.92 25.76,144.17 25.76,146.66 25.69,146.74 25.69,150.24 25.84,150.39 27.59,150.39 28.02,150.83 29.32,150.83 29.37,150.77 29.37,144.15 29.14,143.92
PWR_1D35V_SN on TOP: 31.76,144.32 31.68,144.4 31.68,146.74 31.78,146.84 33.66,146.84 33.74,146.76 33.74,144.53 33.54,144.32 ; 1 cut-out
PWR_3D3V_HG2 on TOP: 77.93,52.78 77.91,52.81 77.91,54 78.11,54.2 78.67,54.2 78.82,54.05 78.82,52.78
PWR_3D3V_LG2 on TOP: 74.86,54.23 74.61,54.48 74.61,55.65 74.66,55.7 75.55,55.7 75.55,54.38 75.39,54.23
PWR_3D3V_PH2 on TOP: 78.27,49.66 77.88,50.04 77.88,52.5 79.38,52.5 79.51,52.63 79.51,54.58 79.36,54.74 76.13,54.74 76.08,54.79 76.08,58.01 76.21,58.14 80.47,58.14 80.65,58.32 80.65,60.3 80.73,60.38 82.58,60.38 82.96,59.99 82.96,49.76 82.86,49.66
PWR_3D3V_PH2 on BOTTOM: 79.51,50.14 79.2,50.44 79.2,58.01 79.33,58.14 82.81,58.14 82.94,58.01 82.94,50.39 82.68,50.14
PWR_5V_HG1_R on TOP: 77.71,63.9 77.68,63.93 77.68,65.19 77.94,65.44 78.65,65.44 78.77,65.31 78.77,64.08 78.6,63.9
PWR_5V_HG1_R on BOTTOM: 77.72,61.89 77.5,62.11 77.5,65.02 77.88,65.41 78.39,65.41 78.65,65.15 78.65,62.12 78.42,61.89
PWR_5V_LG1 on TOP: 74.42,65.4 74.25,65.57 74.25,66.88 74.39,67.02 75.3,67.02 75.37,66.95 75.37,65.57 75.2,65.4
PWR_5V_PH1 on TOP: 78.02,60.96 77.69,61.29 77.69,63.56 77.74,63.61 78.95,63.61 79.43,64.09 79.43,65.84 79.23,66.04 75.93,66.04 75.85,66.12 75.85,69.75 76.09,69.99 79.42,69.99 79.64,70.21 79.64,71.63 79.71,71.7 80.86,71.7 83.6,68.96 83.6,61.37 83.19,60.96
PWR_5V_PH1 on BOTTOM: 79.83,61.5 79.28,62.04 79.28,63.88 79.54,64.14 79.54,65.79 79.28,66.04 77.63,66.04 77.22,66.45 76.11,66.45 75.85,66.7 75.85,69.72 76.11,69.98 82.58,69.98 83.6,68.96 83.6,61.76 83.33,61.5
PWR_CHG_PHASE on BOTTOM: 38.26,54.99 38.13,55.12 38.13,57.66 37.75,58.04 36.15,58.04 36.1,57.99 36.1,56.74 36,56.64 34.07,56.64 33.82,56.9 33.82,58.47 34.39,59.04 34.39,62.04 34.58,62.23 40.55,62.23 41.18,61.59 41.18,59.31 41.82,58.67 41.82,55.12 41.69,54.99
PWR_CORE_HG1_R on TOP: 48.04,199.26 47.79,199.52 47.79,201.17 49.31,201.17 49.82,201.68 51.34,201.68 51.34,199.72 51.14,199.52 50.02,199.52 49.77,199.26 ; 2 cut-outs
PWR_CORE_HG1_R on BOTTOM: 42.17,199.62 41.86,199.93 41.86,200.87 42.16,201.17 44.86,201.17 44.86,199.64 44.84,199.62
PWR_CORE_LX1 on TOP: 38.88,186.63 38.77,186.74 38.77,198.63 39.02,198.88 40.8,198.88 41.18,199.26 41.18,200.91 41.44,201.17 42.37,201.17 42.43,201.12 42.43,199.62 42.58,199.47 43.9,199.47 43.98,199.54 43.98,201.12 44.03,201.17 47.28,201.17 47.28,199.26 47.66,198.88 49.87,198.88 50.17,199.19 50.86,199.19 50.96,199.09 50.96,196.98 48.17,194.18 48.17,186.94 47.85,186.63 ; 1 cut-out
PWR_CORE_LX1 on BOTTOM: 38.91,186.61 38.77,186.75 38.77,198.63 39.45,199.31 45.09,199.31 45.25,199.47 45.25,201.17 48.44,201.17 48.56,201.04 48.56,199.69 48.76,199.49 49.77,199.49 50.26,199 50.26,196.28 48.29,194.31 48.29,187.12 47.78,186.61
PWR_DCBATOUT_VCCGI on TOP: 42.07,201.55 41.49,202.13 41.49,207.59 40.42,208.66 40.42,216.53 40.55,216.66 47.66,216.66 47.66,210.57 48.42,209.8 48.42,207.39 49.18,206.63 49.18,201.8 48.93,201.55
PWR_DCBATOUT_VCCGI on BOTTOM: 42.1,201.55 41.49,202.16 41.49,207.59 40.42,208.66 40.42,216.53 40.55,216.66 47.53,216.66 47.66,216.53 47.66,210.57 48.42,209.8 48.42,207.39 49.18,206.63 49.18,201.8 48.93,201.55
PWR_DCBATOUT_VDDQ on TOP: 144.98,144.53 144.42,145.08 144.42,152.68 145.11,153.37 149.91,153.37 149.91,149.45 149.91,149.45 149.91,149.23 150.94,148.19 150.94,144.81 150.66,144.53
PWR_DCBATOUT_VDDQ on BOTTOM: 147.33,145.59 146.95,145.97 146.95,148.41 147.25,148.72 150.83,148.72 151.06,148.49 151.06,145.85 150.81,145.59
PWR_DCBATOUT_VNN on BOTTOM: 72.93,210.06 72.68,210.31 72.68,219.66 72.91,219.89 75.93,219.89 76.49,219.33 76.49,210.31 76.23,210.06
PWR_DDR_SN on TOP: 150.76,149.78 150.48,150.06 150.48,153.12 150.56,153.2 151.91,153.2 152.04,153.08 152.04,150.1 151.72,149.78 ; 2 cut-outs
PWR_V1P8A on TOP: 24.54,193.93 24.16,194.31 24.16,196.72 24.04,196.85 24.04,200.41 24.29,200.66 27.08,200.66 27.34,200.41 27.34,198.88 26.96,198.5 26.96,195.96 26.7,195.71 26.7,193.93 ; 4 cut-outs
PWR_VCCGI_PVCC on TOP: 60.15,216.13 59.98,216.31 59.98,217.88 60.08,217.98 63.18,217.98 63.76,218.57 64.96,218.57 64.98,218.54 64.98,217.2 64.96,217.17 61.5,217.17 61.17,216.84 61.17,216.28 61.02,216.13 ; 1 cut-out
PWR_VCCGI_VCC on TOP: 56.07,215.19 55.96,215.29 55.96,216.31 56.6,216.94 57.82,216.94 58.12,216.64 58.12,215.26 58.05,215.19 ; 2 cut-outs
PWR_VDDQ_BOOT on TOP: 151.57,136.3 151.1,136.77 151.1,137.15 150.73,137.52 150.73,138.66 150.78,138.71 152.15,138.71 152.2,138.66 152.2,137.54 151.82,137.16 151.82,136.37 151.75,136.3
PWR_VDDQ_BOOT_A on TOP: 150.96,139.62 150.81,139.78 150.81,140.49 150.83,140.51 154.62,140.51 154.74,140.39 154.74,139.85 154.52,139.62
PWR_VDDQ_HG_R on TOP: 146.72,153.92 146.59,154.05 146.59,155.12 146.41,155.3 146.41,157.58 146.49,157.66 147.76,157.66 147.84,157.58 147.84,156.26 147.35,155.78 147.35,153.97 147.3,153.92
PWR_VDDQ_LG on TOP: 156.09,149.38 155.48,149.99 155.48,151.54 155.53,151.59 156.32,151.59 156.37,151.54 156.37,150.5 156.8,150.06 156.8,149.58 156.6,149.38
PWR_VDDQ_PH on TOP: 153.07,152.07 152.84,152.3 152.84,153.77 152.69,153.92 147.73,153.92 147.63,154.03 147.63,155.42 148.24,156.03 148.24,158.45 148.8,159 157.97,159 158.3,158.67 158.3,153.09 157.28,152.07
PWR_VDDQ_PH on BOTTOM: 153.14,152.07 152.84,152.37 152.84,153.8 152.71,153.92 148.78,153.92 148.65,154.05 148.65,158.88 148.8,159.03 157.97,159.03 158.31,158.69 158.31,154.2 157.74,153.63 157.74,153.62 157.64,153.52 157.64,152.43 157.28,152.07
PWR_VDDQ_VLDOIN on TOP: 150.55,136.17 150.3,136.42 149.59,136.42 149.39,136.63 149.39,137.19 149.66,137.46 150.2,137.46 151.19,136.47 151.19,136.32 151.04,136.17
PWR_VDDQ_VLDOIN on BOTTOM: 148.06,136.4 147.58,136.88 147.58,140.67 148.04,141.12 148.04,142.57 147.89,142.72 147.23,142.72 147.18,142.77 147.18,144.22 147.23,144.27 149,144.27 149.64,143.64 149.64,140.82 149.11,140.28 149.11,137.59 149.26,137.44 150.12,137.44 150.3,137.26 150.3,136.58 150.12,136.4
PWR_VDDQ_VTT on TOP: 147.1,134.24 146.85,134.49 146.85,137.67 147.33,138.15 147.33,140.13 147.43,140.23 148.42,140.23 148.65,140 148.65,136.86 149.32,136.18 149.47,136.18 149.64,136.02 149.64,135.89 149.51,135.76 149.23,135.76 148.62,135.16 148.62,134.37 148.5,134.24
PWR_VGA_CORE_PHASE1 on TOP: 123.5,90.68 122.44,91.75 122.44,104.34 123.27,105.18 133.21,105.18 133.21,99.59 133.15,99.54 129.45,99.54 129.29,99.39 129.29,97.38 129.24,97.33 129.24,97.33 128.13,97.33 127.9,97.1 127.9,96.21 128.11,96.01 129.16,96.01 129.29,95.87 129.29,92.66 127.24,92.66 126.14,91.57 126.14,90.82 126,90.68 ; 1 cut-out
PWR_VGA_CORE_PHASE1 on BOTTOM: 123.52,90.68 122.44,91.76 122.44,104.85 123.21,105.62 132.99,105.62 133.15,105.46 133.15,98.96 132.62,98.42 127.87,98.42 127.52,98.07 127.52,96.49 127.31,96.29 127.31,95 127.46,94.85 129,94.85 129.32,94.53 129.32,91.52 129.17,91.36 128.18,91.36 127.49,90.68
PWR_VNN_HG_R on BOTTOM: 70.54,207.2 70.3,207.44 70.3,209.39 70.43,209.52 73.82,209.52 73.82,208.53 73.44,208.15 73.01,208.15 72.05,207.2 ; 2 cut-outs
PWR_VNN_LG on BOTTOM: 81.69,211.84 81.69,213.11 81.82,213.23 82.96,213.23 83.09,213.11 83.09,211.96 82.96,211.84
PWR_VNN_PH on TOP: 71.69,205.44 71.48,205.64 71.48,206.78 71.56,206.86 72.78,206.86 74.05,208.13 74.05,209.47 74.12,209.55 76.61,209.55 76.82,209.75 78.85,209.75 79,209.91 79,211.2 79.13,211.33 82.76,211.33 82.89,211.2 82.89,208.15 80.17,205.44
PWR_VNN_PH on BOTTOM: 75.99,205.37 75.94,205.42 71.72,205.42 71.48,205.66 71.48,206.78 71.56,206.86 72.75,206.86 73.67,207.77 73.69,207.77 74.07,208.15 74.07,209.55 76.61,209.55 76.8,209.74 78.84,209.74 79,209.91 79,211.2 79.13,211.33 82.79,211.33 82.89,211.23 82.89,208.15 80.16,205.42 76.04,205.42 ; 1 cut-out
RING2 on TOP: 168,74.85 166.81,76.05 166.81,76.48 167.09,76.76 168.31,76.76 169.12,75.95 170.37,75.95 171.31,76.89 173.39,76.89 173.64,76.63 173.64,75.77 173.54,75.67 171.84,75.67 171.03,74.85 ; 2 cut-outs
SB3V on TOP: 99.07,48.79 98.43,49.43 98.43,55.17 98.6,55.33 100.45,55.33 101.15,56.03 102.34,56.03 102.83,56.52 104.17,56.52 104.3,56.39 104.3,52.7 104.17,52.58 103.41,52.58 103.16,52.32 103.16,50.16 101.79,48.79 ; 1 cut-out
SB3V on TOP: 134.73,25.78 134.42,26.09 134.42,28.57 134.7,28.85 136.28,28.85 136.89,28.24 136.89,26.64 136.02,25.78
SB3V on TOP: 17.36,186.59 16.3,187.65 16.3,188.72 16.69,189.1 19.11,189.1 19.69,189.69 19.69,191.97 20.45,192.74 23.58,192.74 24.52,193.68 30.53,193.68 30.81,193.4 30.81,191.15 30.67,191.01 29.25,191.01 28.99,190.75 25.56,190.75 25.31,190.5 25.31,188.85 25.2,188.75 24.65,188.75 24.57,188.82 24.57,189.08 24.52,189.13 22.28,189.13 21.85,188.7 21.85,187.3 21.14,186.59 ; 1 cut-out
SB3V on TOP: 85.43,192.94 85.35,193.01 85.35,193.75 85.94,194.34 88.25,194.34 88.53,194.06 88.53,192.99 88.48,192.94 ; 3 cut-outs
SB3V on TOP: 20.68,144.2 19.7,145.18 19.7,171.46 19.03,172.13 19.03,176.07 19.24,176.28 21.62,176.28 21.75,176.15 21.75,173.9 22.32,173.34 22.36,173.34 24.55,171.15 26.79,171.15 27.63,170.31 27.63,167.39 23.2,167.39 22.54,166.73 22.54,148.44 22.79,148.18 24.85,148.18 25.06,147.97 25.06,144.56 25.08,144.55 24.72,144.2
SB3V on TOP: 162.54,84.53 160.33,86.74 158.55,86.74 157.59,87.71 157.59,90.88 157.74,91.03 162.42,91.03 165.41,88.04 170.9,88.04 171.64,87.3 171.64,84.78 171.38,84.53
SB3V on BOTTOM: 29.83,10.03 29.78,10.08 27.67,10.08 27.57,10.18 27.57,11.07 27.92,11.42 27.92,13.67 28.02,13.77 28.48,13.77 28.53,13.72 28.53,13.14 28.51,13.11 28.51,12.29 28.68,12.12 30.44,12.12 30.54,12.01 30.54,11.51 31.1,10.95 31.1,10.26 30.87,10.03 ; 3 cut-outs
SB3V on BOTTOM: outline of 84 points within 78.14,85.65 178.39,227.94 ; 11 cut-outs
SB3V on BOTTOM: 98.84,51.21 98.43,51.61 98.43,55.07 98.76,55.4 102.4,55.4 102.73,55.07 102.73,51.54 102.4,51.21
SB3V on BOTTOM: 103.05,219.04 102.97,219.12 102.97,221.39 102.99,221.41 105.87,221.41 106.16,221.12 106.16,220.3 106,220.14 105.11,220.14 104.01,219.04 ; 3 cut-outs
SB3V on L3: 100.11,51.31 99.47,51.94 99.47,55.5 100.36,56.39 101.51,56.39 102.24,57.12 102.24,63.86 106.81,68.43 127.69,68.43 128.14,68.88 136.27,68.88 139.73,72.34 141.68,72.34 154.69,85.36 154.69,90.2 155.91,91.41 158.69,91.41 159.6,90.51 159.6,86 158.76,85.16 158.76,84.31 154.24,79.78 154.24,78.16 144.87,68.8 142.19,68.8 138.66,65.27 131.98,65.27 131.61,64.9 120.94,64.9 120.93,64.89 112.9,64.89 112.48,65.3 112.48,65.32 111.25,65.32 110.07,64.14 107.75,64.14 106.28,62.66 106.28,54.81 102.78,51.31
SB3V on L3: 20.38,171.88 20.05,171.55 17.51,171.55 17.1,171.96 17.1,174.19 14.71,176.58 14.71,183.46 13.21,184.97 13.21,202.68 10.58,205.3 10.58,221.81 12.48,223.71 15.99,223.71 16.01,223.7 18.02,223.7 18.4,223.32 18.4,221.28 18.02,220.9 16.59,220.9 15.91,220.23 15.91,217.27 16.23,216.95 16.23,190.27 18.48,188.02 18.48,182.48 18.46,182.45 18.46,178.03 20.38,176.11
SB3V on L3: 170.72,87.76 169.02,87.76 166.35,85.09 166.35,84 166.62,83.73 168.93,83.73 171.1,85.9 171.1,87.38
SB3V on L3: 173.12,149.24 173.53,149.66 173.53,154.89 168.1,160.31 168.1,208.33 149.48,226.95 146.51,226.95 145.44,228.03 83.38,228.03 83.11,227.76 83.11,226.31 83.86,225.56 112.6,225.56 113.51,224.65 142.36,224.65 163.66,203.35 163.66,189.28 165.82,187.12 165.82,159.01 170.01,154.82 170.01,150.29 171.06,149.24
SB3V on L4: 168.96,86.02 169.35,85.63 170.71,85.63 171.36,86.28 171.36,88.13 171.35,88.14 171.35,88.64 171.06,88.93 169.7,88.93 168.96,88.19
SB3V on L4: 157.87,91.04 158.89,91.04 159.65,90.27 161.64,90.27 162.59,91.21 162.59,91.95 165.48,94.84 165.48,101.1 164.43,102.14 164.43,122.78 166.71,125.05 166.71,129.56 170.03,132.88 170.03,151.37 172.07,153.4 174.03,153.4 175.2,152.22 175.2,129.04 169.02,122.86 169.02,118.86 167.11,116.96 167.11,104.07 168.44,102.75 168.44,94.02 167.62,93.2 167.62,92.34 162.5,87.22 158.56,87.22 157.53,88.25 157.53,90.7
SB3V on L4: 16.82,221.01 18.02,221.01 18.64,221.63 18.64,224.72 19.63,225.71 83.42,225.71 83.58,225.55 87.89,225.55 88.17,225.83 88.17,227.63 87.84,227.97 16.34,227.97 13.04,224.66 13.04,219.23 10.96,217.14 10.96,215.95 11.16,215.75 13.11,215.75 16.47,219.1 16.47,220.65
SB5V on TOP: 89.82,29.92 88.43,31.32 88.43,37.74 88.84,38.16 88.84,42.91 89.19,43.26 90.23,43.26 90.24,43.24 90.77,43.24 90.94,43.08 90.94,37.29 90.3,36.65 90.3,33.71 90.99,33.02 91.96,33.02 92.11,32.87 92.11,32.13 91.98,32 91.98,30.02 91.88,29.92 ; 1 cut-out
SB5V on TOP: 25.5,12.69 25.46,12.73 24.62,12.73 24.47,12.88 24.47,14.86 24.06,15.27 24.06,16.48 24.37,16.79 25.38,16.79 25.66,16.51 25.66,14.76 25.74,14.68 25.74,12.93
SB5V on TOP: 102.4,57.91 102.01,58.29 102.01,59.18 101.76,59.44 99.98,59.44 99.73,59.18 98.33,59.18 97.95,59.56 97.95,70.23 98.28,70.56 102.85,70.56 103.31,70.1 103.31,62.46 104.3,61.47 104.3,58.04 104.17,57.91
SB5V on TOP: 159.42,91.49 157.41,93.5 157.41,97.31 157.47,97.37 157.47,104.07 158.07,104.66 160.69,104.66 160.85,104.5 160.85,96.63 163.61,93.88 167.37,93.88 168.21,94.72 169.81,94.72 170.04,94.49 170.04,93.42 169.3,92.68 169.3,91.82 168.97,91.49 ; 6 cut-outs
SB5V on BOTTOM: 88.93,47.8 88.49,48.25 88.49,52.13 92.57,56.21 92.57,63.53 93.82,64.78 101.65,64.78 101.96,64.47 101.96,59.99 101.58,59.61 98.36,59.61 96.43,57.68 96.43,56.21 91.16,50.94 91.16,48.17 90.79,47.8
SB5V on BOTTOM: 166.72,91.22 166.17,91.76 166.17,95.02 166.55,95.4 167.85,95.4 169.02,94.24 169.02,91.66 168.57,91.22
SB5V on BOTTOM: 23.27,5.05 23.2,5.12 23.2,8.61 23.96,9.37 23.96,10.34 23.93,10.36 23.93,12.42 24.98,13.46 26.6,13.46 26.78,13.28 26.78,12.75 26.53,12.5 26.07,12.5 25.43,11.86 25.43,9.09 24.98,8.64 24.97,8.64 24.56,8.23 24.56,5.2 24.42,5.05 ; 1 cut-out
SB5V on L3: 89.47,49.17 89.1,48.81 89.1,42.44 89.38,42.16 91.04,42.16 91.42,42.55 91.42,48.82 91.07,49.17
SB5V on L3: 158.7,93.09 157.74,92.13 155.89,92.13 154.1,90.34 154.1,85.13 152.61,83.64 150.63,83.64 149.54,84.73 149.54,92.13 154.49,97.08 158,97.08 158.7,96.37
SB5V on L3: 99.6,57.28 99.98,56.9 101.58,56.9 101.96,57.28 101.96,64.31 106.59,68.94 106.59,68.94 107.3,69.64 107.3,72.11 106.98,72.43 103.53,72.43 99.14,68.05 99.14,59.51 99.6,59.05
SLEEVE on TOP: 167.44,72.19 167.01,72.62 167.01,73.05 168.46,74.5 171.28,74.5 171.34,74.56 171.62,74.56 172.07,74.12 172.07,73.69 171.76,73.38 169.1,73.38 167.9,72.19 ; 2 cut-outs
USBVCC14 on TOP: 169.98,98.12 169.6,98.5 169.6,99.19 168.99,99.8 168.99,101.61 168.69,101.92 162.03,101.92 161.58,102.36 161.58,104.57 161.66,104.65 163.88,104.65 164.98,105.76 171.06,105.76 173.21,103.6 173.21,100.53 173.85,99.9 173.85,98.78 173.18,98.12 ; 4 cut-outs
USBVCC14 on L4: 173.52,122.76 171.05,122.76 170.21,121.91 170.21,103 170.47,102.74 170.47,102.72 170.62,102.57 170.62,98.14 171.19,97.57 172.94,97.57 172.94,97.58 173.23,97.87 173.23,99.61 174.08,100.46 174.08,103.91 173.35,104.63 173.35,108.69 174.49,109.83 174.49,110.54 176.55,112.6 176.55,121.58 175.39,122.74 173.53,122.74
USBVCC56 on TOP: 94.9,15.88 90.08,20.7 90.08,28.96 90.46,29.34 91.85,29.34 91.98,29.21 91.98,27.18 92.62,26.54 100.36,26.54 100.87,27.05 100.87,30.23 99.09,32 98.46,32 96.68,33.78 96.68,38.37 100.3,41.99 102.32,41.99 102.9,41.4 102.9,39.88 102.14,39.12 100.43,39.12 98.46,37.14 98.46,35.56 100.24,33.78 100.24,33.4 103.03,30.61 103.03,23.62 102.9,23.5 102.9,16.64 102.14,15.88 ; 4 cut-outs
USBVCCTP on BOTTOM: 26.51,4.3 25.89,4.93 24.95,4.93 24.84,5.04 24.84,8.01 25.21,8.38 26.46,8.38 26.48,8.35 26.48,7.01 26.9,6.6 28.38,6.6 28.57,6.41 28.57,5.08 27.79,4.3 ; 2 cut-outs
V_1P5_HDMI on BOTTOM: 122.28,18.72 122.05,18.95 122.05,22.38 121.7,22.73 121.7,25.88 121.45,26.14 121.45,28.42 121.75,28.73 122.46,28.73 123.12,28.07 123.12,26.92 123.73,26.31 123.73,22.89 123.3,22.45 123.3,18.82 123.2,18.72 ; 1 cut-out
V_1P5_HDMI on L3: 134.44,41.1 129.64,41.1 129.26,40.72 129.26,39.37 129.69,38.94 129.69,34.57 129.12,34 127.89,34 125.72,31.83 125.72,30.93 124.68,29.89 121.45,29.89 121.17,29.61 121.17,27.81 121.4,27.58 126.07,27.58 128.86,30.37 128.86,31.44 129.17,31.75 135.81,31.75 136.12,32.05 136.12,40.21 135.78,40.55 134.99,40.55 ; 1 cut-out
V_1P05_LAN on BOTTOM: 36.88,11.1 36.48,11.49 36.48,12.55 36.59,12.66 38.19,12.66 38.4,12.87 39.35,12.87 39.7,13.22 39.7,15.88 39.78,15.96 39.78,16.65 39.93,16.8 40.36,16.8 40.55,16.61 40.55,12.07 40.32,11.85 38.41,11.85 37.66,11.1 ; 2 cut-outs
V_1P05_LAN on BOTTOM: 32.98,14.22 32.82,14.38 32.82,15.06 33.15,15.39 33.15,17.7 33.22,17.77 33.84,17.77 33.96,17.66 33.96,17.01 34.3,16.67 34.3,14.38 34.19,14.28 33.54,14.28 33.48,14.22 ; 3 cut-outs
V_1P05_LAN on L4: 39.47,17.04 39.02,16.59 39.02,14.1 38.32,13.4 35.4,13.4 35.09,13.72 35.09,14.48 34.63,14.93 33.06,14.93 32.93,14.8 32.93,14.35 33.05,14.22 33.56,14.22 33.69,14.1 33.69,13.34 33.43,13.08 33.05,13.08 32.93,12.95 32.93,11.94 33.05,11.81 36.36,11.81 37.12,11.05 37.63,11.05 37.88,11.3 37.88,11.56 38.26,11.94 39.4,11.94 40.67,13.21 40.67,16.84 40.47,17.04
V_3_CARD_BD on BOTTOM: 163.23,144.15 161.83,145.54 161.83,146.18 161.58,146.43 160.23,146.43 160.03,146.63 160.03,149.61 160.15,149.73 161.32,149.73 161.98,149.07 163.43,149.07 164.12,148.39 164.12,146.58 163.74,146.2 163.74,144.15
V_3P3_LAN on BOTTOM: 31.73,8.99 31.66,9.07 31.66,10.9 31.67,10.91 31.67,11.24 31.78,11.35 31.78,14.15 31.88,14.25 32.55,14.25 32.7,14.1 32.71,14.1 32.87,13.94 34.52,13.94 34.71,13.76 34.71,13.21 34.59,13.1 33.7,13.1 33.46,13.34 32.98,13.34 32.7,13.06 32.7,11.79 33.59,10.9 37.83,10.9 38.2,11.27 38.21,11.27 38.45,11.51 40.9,11.51 40.96,11.44 40.96,10.87 40.97,10.87 40.97,10.43 40.89,10.36 39.93,10.36 39.59,10.02 38.29,10.02 37.87,9.6 34.65,9.6 34.04,8.99 ; 7 cut-outs
V_3P3_LAN on BOTTOM: 37.47,17.2 37.4,17.27 35.78,17.27 35.62,17.43 35.62,19.05 35.9,19.33 36.94,19.33 38.23,20.62 40.34,20.62 40.5,20.47 40.5,17.35 40.34,17.2 ; 5 cut-outs
